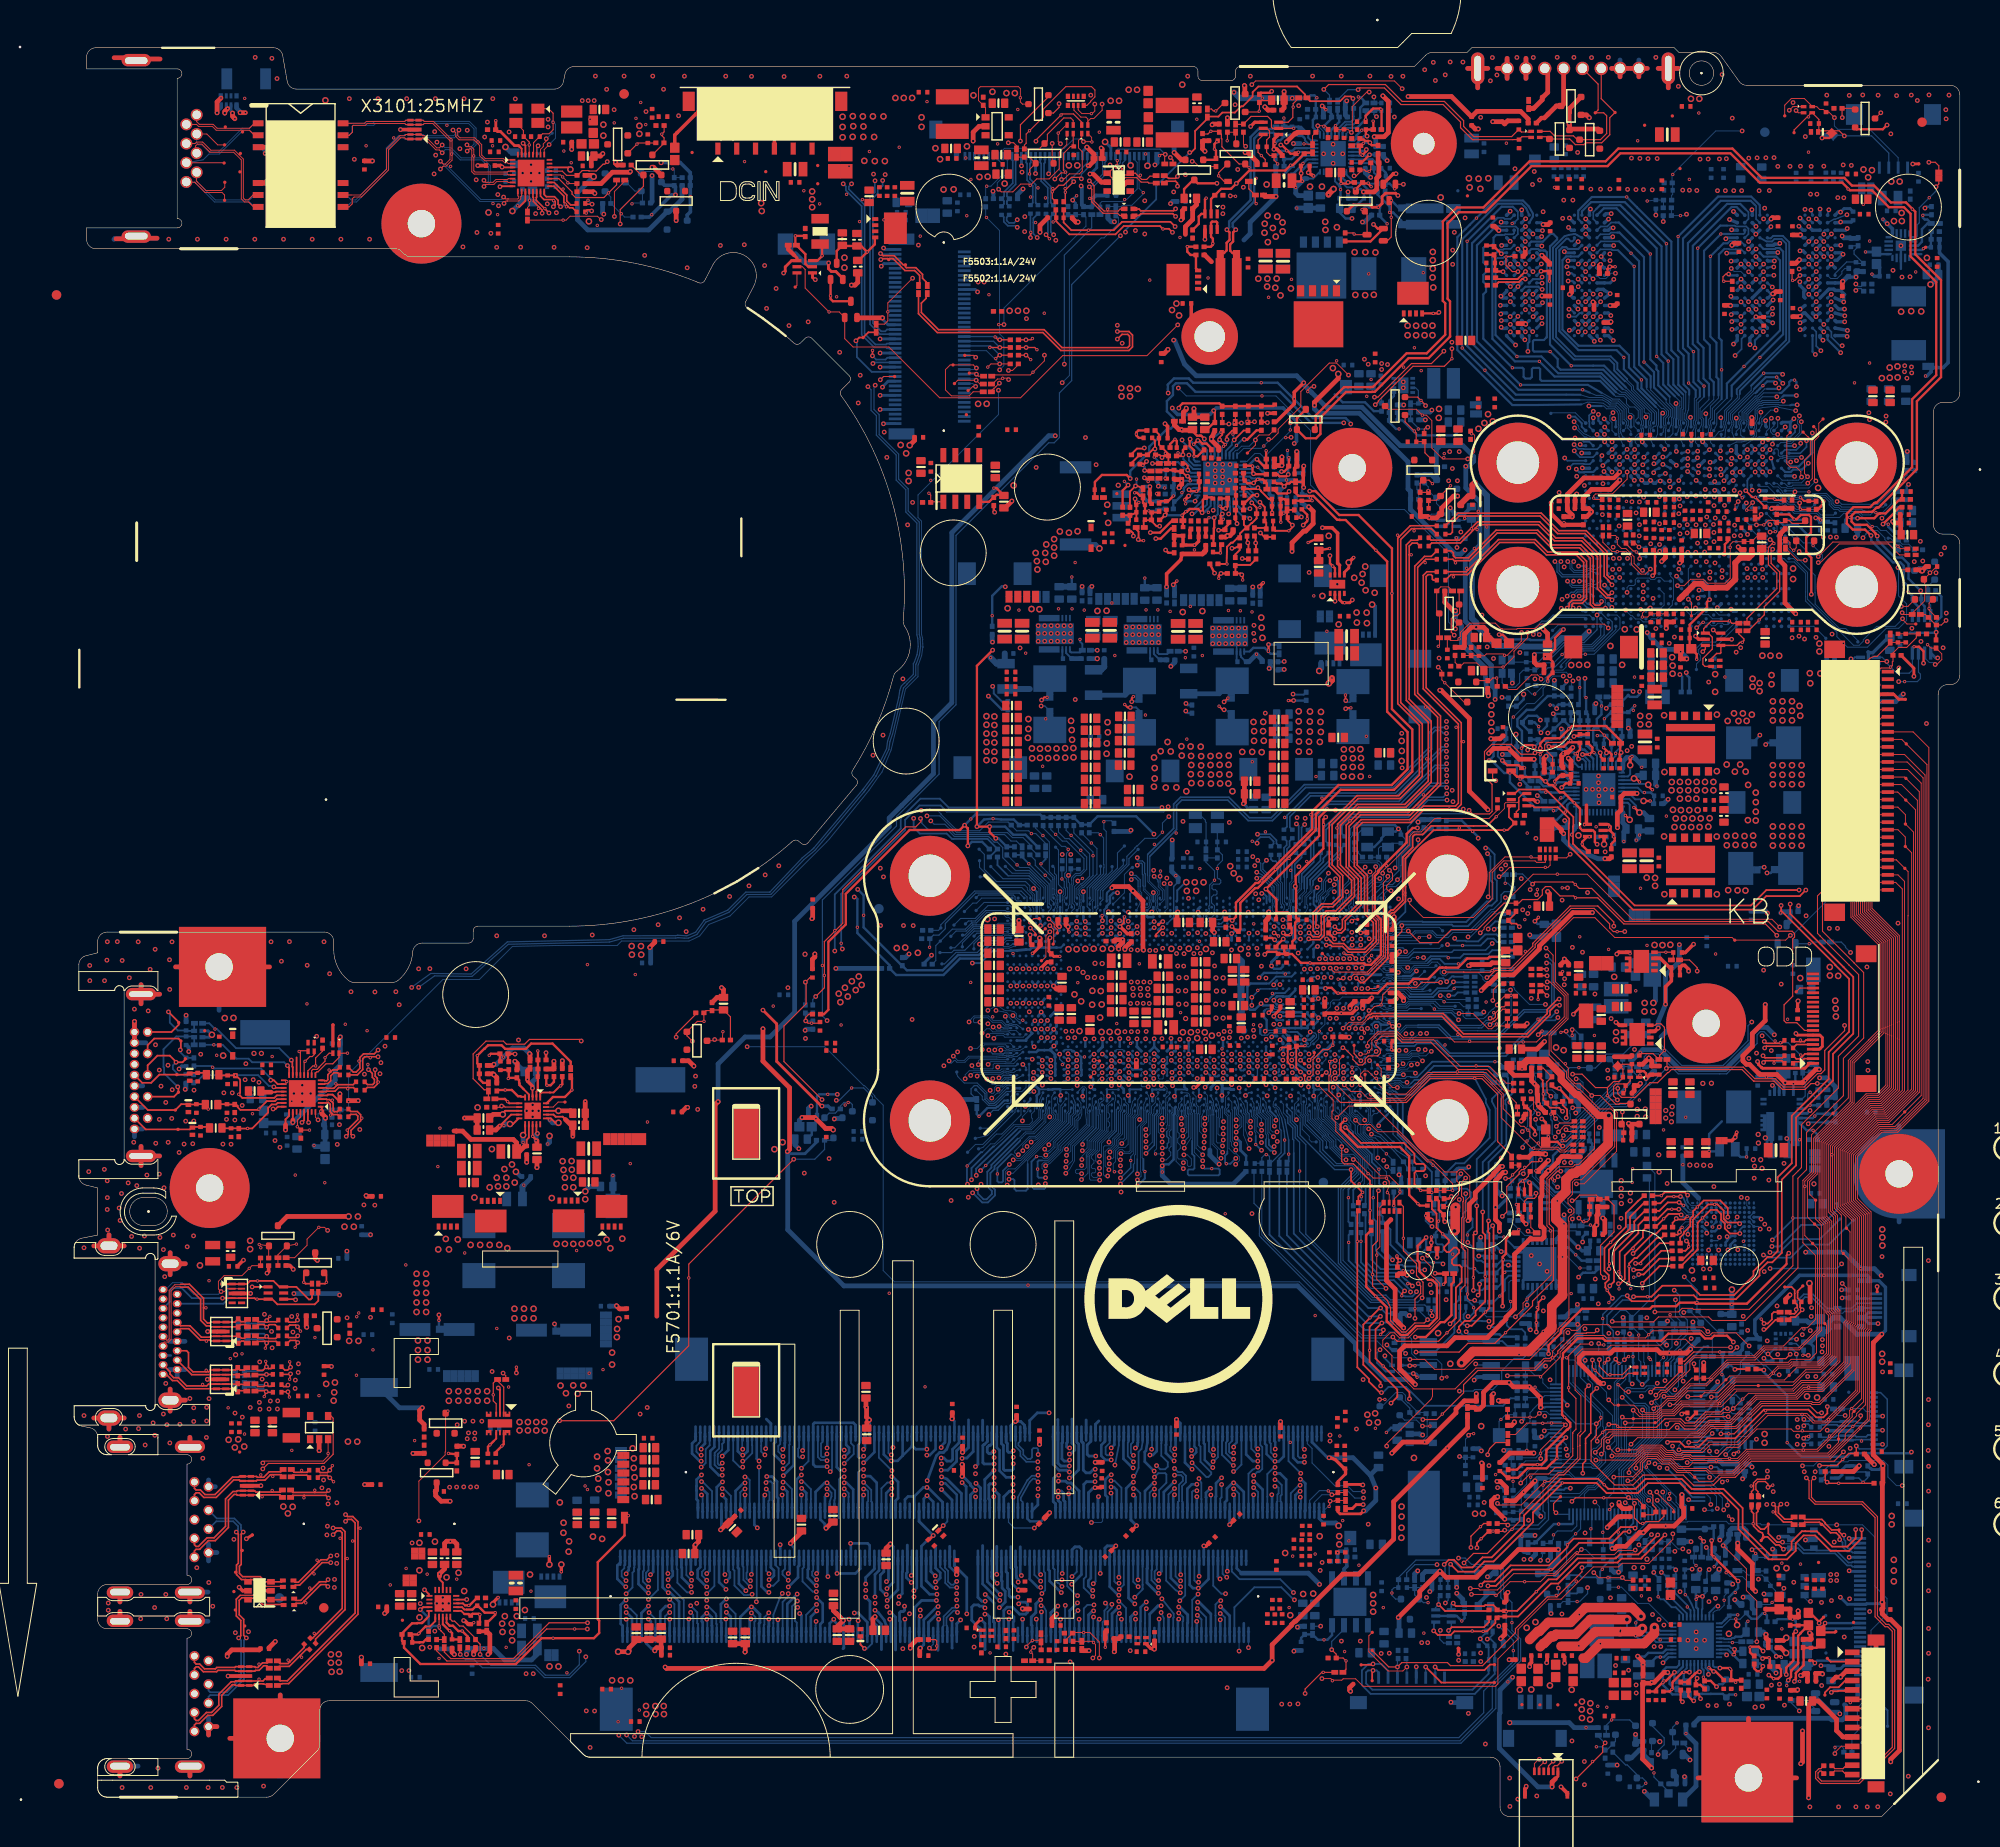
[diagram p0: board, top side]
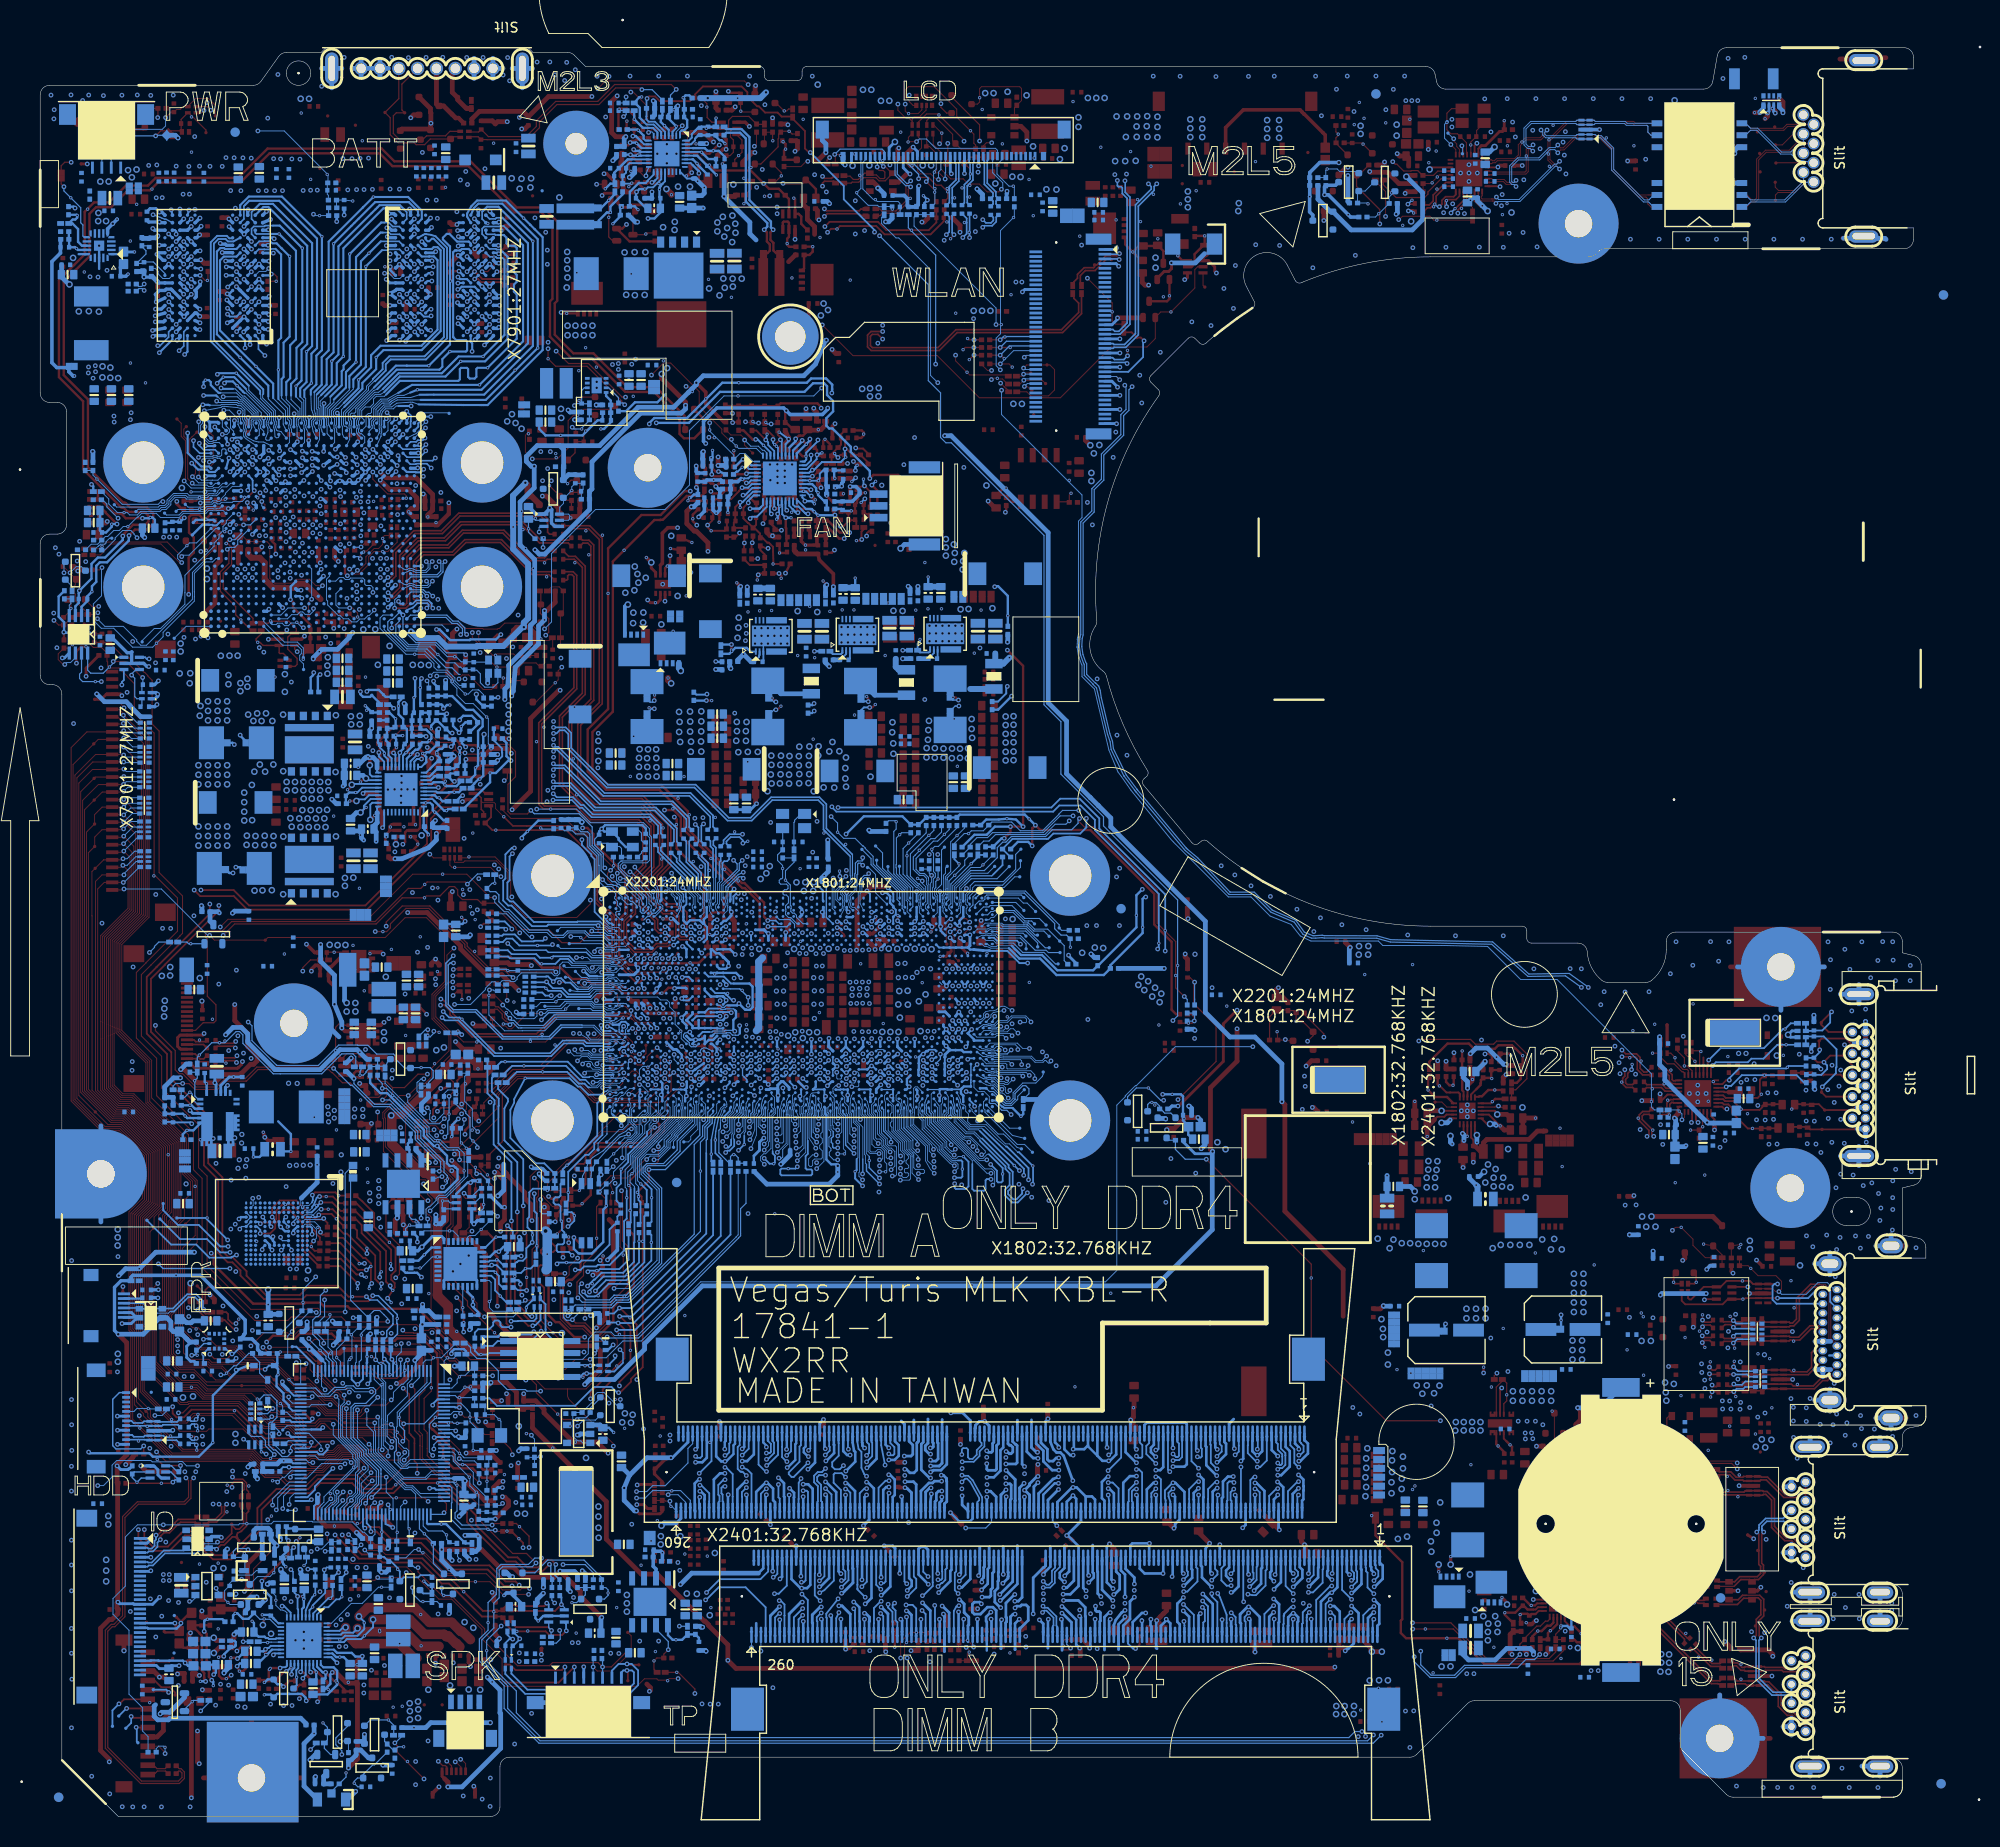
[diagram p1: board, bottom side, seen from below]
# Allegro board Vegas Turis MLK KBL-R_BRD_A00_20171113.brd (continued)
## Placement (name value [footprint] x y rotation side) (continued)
R6808  0R2J-2-GP  [R402H16]  186.33 5.39 90 top
R6809  0R2J-2-GP  [R402H16]  186.33 4.55 90 top
R7601  1KR2F-L1-GP  [R402H15]  194.28 139.95 90 bottom
R7618  1KR2F-L1-GP  [R402H15]  164.88 135.79 180 top
R7621  -  [0R0402-PAD]  145.51 125.29 90 top
R7622  1K69R2F-2-GP  [R402H16]  165.65 135.78 0 top
R7623  -  [0R0402-PAD]  146.88 130.26 270 top
R7625  10KR2J-L-GP  [R402H15]  145.2 130.26 270 top
R7704  -  [0R0603-PAD]  151.79 124.7 90 top
R7705  -  [0R0603-PAD]  171.16 124.11 90 top
R7802  2K2R2J-L1-GP  [R402H16]  169.28 170.16 270 bottom
R7803  10R2J-L-GP  [R402H16]  169.3 171.8 270 bottom
R7804  49D9R2F-L1-GP  [R402H16]  169.27 170.99 90 bottom
R7809  120R2F-GP  [R402H16]  162.35 139.55 180 top
R7810  40D2R2F-GP  [R402H16]  158.27 137.72 180 top
R7814  100R2F-L3-GP  [R402H16]  158.22 139.83 270 top
R7817  40D2R2F-GP  [R402H16]  160.36 137.72 180 top
R7818  100R2F-L3-GP  [R402H16]  159.9 139.83 270 top
R7819  5K1R2F-2-GP  [R402H16]  169.37 173.64 90 bottom
R7820  51D1R2F-GP  [R402H16]  185.08 139.37 0 top
R7821  51D1R2F-GP  [R402H16]  181.68 139.48 0 top
R7901  1MR2J-1-GP  [R402H16]  155.18 122.3 180 bottom
R7902  1KR2F-L1-GP  [R402H15]  195.57 143.49 180 bottom
R7903  5K1R2F-2-GP  [R402H16]  194.74 143.49 0 bottom
R7904  0R2J-2-GP  [R402H16]  151.63 120.12 270 top
R7911  0R2J-2-GP  [R402H16]  194.24 134.6 90 bottom
R7912  -  [0R0402-PAD]  177.3 126.83 90 top
R7913  0R2J-2-GP  [R402H16]  180.9 137.96 0 top
R7914  -  [0R0402-PAD]  177.3 126.03 90 top
R7919  -  [0R0402-PAD]  178.59 138.43 180 top
R7920  -  [0R0402-PAD]  194.28 140.82 90 bottom
R7921  10KR2J-L-GP  [R402H15]  181.8 137.3 180 top
R7922  10KR2J-L-GP  [R402H15]  182.52 139.48 180 top
R7923  10KR2J-L-GP  [R402H15]  152.4 118.45 180 bottom
R7924  10KR2J-L-GP  [R402H15]  158.13 119.54 180 bottom
R7925  10KR2J-L-GP  [R402H15]  152.84 112.03 90 bottom
R7926  8K45R2F-2-GP  [R402H16]  147.6 123.84 0 top
R7927  2KR2F-L1-GP  [R402H16]  148.43 123.83 180 top
R7928  8K45R2F-2-GP  [R402H16]  146.72 123.83 0 top
R7929  2KR2F-L1-GP  [R402H16]  146.69 122.26 270 top
R7930  8K45R2F-2-GP  [R402H16]  178.25 135.08 180 top
R7931  4K75R2F-1-GP  [R402H16]  177.43 135.08 0 top
R7932  3K24R2F-GP  [R402H16]  169.16 127.39 180 top
R7933  5K62R2F-GP  [R402H16]  168.33 127.4 0 top
R7934  10KR2J-L-GP  [R402H15]  157.27 119.53 0 bottom
R7935  10KR2J-L-GP  [R402H15]  195.96 134.63 90 bottom
R7936  10KR2J-L-GP  [R402H15]  194.24 135.66 270 bottom
R7937  -  [0R0402-PAD]  181.82 135.24 180 top
R7938  16K2R2F-GP  [R402H16]  195.26 132.5 270 top
R7939  10KR2J-L-GP  [R402H15]  151.68 114.57 270 bottom
R7940  10KR2J-L-GP  [R402H15]  152.84 112.87 270 bottom
R7941  4K7R2J-2-GP  [R402H16]  154.88 120.22 270 bottom
R7942  10KR2J-L-GP  [R402H15]  150.19 120.3 180 top
R7943  0R2J-2-GP  [R402H16]  145.75 121.42 270 top
R7944  0R2J-2-GP  [R402H16]  152.84 113.71 90 bottom
R7945  0R2J-2-GP  [R402H16]  159.05 119.5 0 bottom
R7946  0R2J-2-GP  [R402H16]  153.24 118.45 0 bottom
R8101  60D4R2F-GP  [R402H16]  150.58 162.75 90 top
R8102  60D4R2F-GP  [R402H16]  150.59 163.56 90 top
R8103  60D4R2F-GP  [R402H16]  190.57 162.12 90 bottom
R8104  60D4R2F-GP  [R402H16]  190.57 162.88 90 bottom
R8105  2K37R2F-GP  [R402H16]  150.86 166.42 0 top
R8106  2K37R2F-GP  [R402H16]  189.54 167.38 180 bottom
R8107  5K49R2F-GP  [R402H16]  150.6 164.34 270 top
R8108  5K49R2F-GP  [R402H16]  190.11 164.64 180 bottom
R8109  120R2F-GP  [R402H16]  188.55 164.11 0 bottom
R8110  120R2F-GP  [R402H16]  153.52 165.83 270 top
R8111  1KR2J-L2-GP  [R402H15]  156.75 164.58 0 top
R8112  1KR2J-L2-GP  [R402H15]  162.49 164 90 top
R8113  1KR2J-L2-GP  [R402H15]  182.52 164.65 0 top
R8114  1KR2J-L2-GP  [R402H15]  176.17 162.74 180 top
R9120  10KR2J-L-GP  [R402H15]  161.39 58.29 270 bottom
R9121  10KR2J-L-GP  [R402H15]  160.24 62 270 bottom
R9122  2K2R2J-L1-GP  [R402H16]  155.42 52.74 180 bottom
R9130  -  [0R0402-PAD]  150.55 57.77 270 bottom
R9132  33R2J-2-GP  [R402H16]  150.57 61.59 270 bottom
R9133  33R2J-2-GP  [R402H16]  150.51 58.59 270 bottom
R9136  0R0402-PAD-2-GP  [0R0402-PAD-1]  150.05 53.89 270 bottom
R9138  33R2J-2-GP  [R402H16]  150.55 56.22 270 bottom
R9140  10KR2J-L-GP  [R402H15]  150.55 56.99 270 bottom
R9141  10KR2J-L-GP  [R402H15]  152.97 63.35 270 bottom
R9143  0R0402-PAD-2-GP  [0R0402-PAD-1]  163.21 62.41 180 bottom
R9144  0R0402-PAD-2-GP  [0R0402-PAD-1]  161.39 59.08 90 bottom
R9145  0R0402-PAD-2-GP  [0R0402-PAD-1]  160.18 53.75 270 bottom
R9146  0R2J-L-GP  [R402H15]  160.17 52.97 270 bottom
R9147  0R0402-PAD-2-GP  [0R0402-PAD-1]  150.46 59.44 270 bottom
R9149  0R2J-2-GP  [R402H16]  157.58 52.3 90 bottom
R9150  0R0402-PAD-2-GP  [0R0402-PAD-1]  157.57 53.08 90 bottom
R9152  0R0402-PAD-2-GP  [0R0402-PAD-1]  150.05 54.66 270 bottom
R9202  0R0402-PAD-2-GP  [0R0402-PAD-1]  190.27 56.94 90 bottom
R9203  0R0402-PAD-2-GP  [0R0402-PAD-1]  181.69 53.6 90 top
R9204  0R0402-PAD-2-GP  [0R0402-PAD-1]  181.69 52.79 90 top
RJ45  RJ45-8P-186-GP  [23-00980-2A03-A]  6.6 177.3 90 bottom
RN801  SRN2K2J-1-GP  [ARES2H16]  152.32 94.8 270 bottom
RN802  SRN10KJ-6-GP  [ARES8-CN24-MUH20]  156.57 102.34 180 top
RN803  SRN2K2J-1-GP  [ARES2H16]  152.31 93.28 270 bottom
RN1201  SRN1KJ-7-GP  [SMD-ARES4H18]  113.42 18.69 90 top
RN1301  SRN1KJ-7-GP  [SMD-ARES4H18]  96.99 19.47 270 top
RN1701  SRN10KJ-5-GP  [ARES2H18]  144.23 54.42 0 bottom
RN1704  SRN10KJ-6-GP  [ARES8-CN24-MUH20]  139.97 64.8 0 top
RN1807  SRN2K2J-4-GP  [ARES8-CN24-UH20]  148.36 88.41 270 bottom
RN1812  SRN10KJ-6-GP  [ARES8-CN24-MUH20]  159.85 73.05 90 top
RN1813  SRN10KJ-5-GP  [ARES2H18]  159.72 71.07 90 top
RN1901  SRN20KJ-1-GP  [SMD-ARES4H20]  165.79 78.89 90 top
RN2007  SRN10KJ-5-GP  [ARES2H18]  155.35 88.03 90 top
RN2008  SRN2K2J-1-GP  [ARES2H16]  152.31 91.74 90 bottom
RN2009  SRN10KJ-5-GP  [ARES2H18]  152.3 89.71 270 bottom
RN2010  SRN2K2J-1-GP  [ARES2H16]  155.27 89.75 270 top
RN2011  SRN10KJ-5-GP  [ARES2H18]  151.29 88.09 90 bottom
RN2402  SRN4K7J-8-GP  [SMD-ARES4H18]  166.37 47.43 270 top
RN2403  SRN10KJ-12-GP  [ARES8-CN24-UH22]  189.29 101.75 90 bottom
RN2404  SRN10KJ-12-GP  [ARES8-CN24-UH22]  189.3 104.91 90 bottom
RN2405  SRN100KJ-5-GP  [ARES8-CN24H20]  177.5 43.07 90 bottom
RN2406  SRN100KJ-5-GP  [ARES8-CN24H20]  189.26 112.85 90 bottom
RN2407  SRN100KJ-5-GP  [ARES8-CN24H20]  189.24 115.42 90 bottom
RN2408  SRN100KJ-5-GP  [ARES8-CN24H20]  189.29 110.23 90 bottom
RN2409  SRN100KJ-5-GP  [ARES8-CN24H20]  189.29 107.44 90 bottom
RN2501  SRN4K7J-8-GP  [SMD-ARES4H18]  147.65 56.5 180 bottom
RN2502  SRN0J-6-GP  [SMD-ARES4H20]  147.54 54.61 0 bottom
RN2503  SRN0J-6-GP  [SMD-ARES4H20]  140.49 47.62 270 bottom
RN2901  SRN2K2J-1-GP  [ARES2H16]  180.61 18.34 90 bottom
RN3201  SRN75J-1-GP  [ARES8-CN24H22]  16.42 182.4 180 bottom
RN4302  SRN100J-3-GP  [SMD-ARES4H18]  155.26 178.79 270 top
RN5501  SRN100J-3-GP  [SMD-ARES4H18]  105.82 179.33 0 top
RN5502  SRN100KJ-5-GP  [ARES8-CN24H20]  106.43 182.35 180 top
RN5503  SRN100J-3-GP  [SMD-ARES4H18]  107.38 179.33 0 top
RN5601  SRN2K2J-1-GP  [ARES2H16]  13.19 83.16 90 bottom
RN5602  SRN4K7J-8-GP  [SMD-ARES4H18]  27.82 81.59 180 top
RN5603  SRN4K7J-8-GP  [SMD-ARES4H18]  25.18 81.79 180 top
RN5701  SRN470J-3-GP  [ARES8-CN24H20]  17.9 51.53 90 bottom
RN5702  SRN2K2J-1-GP  [ARES2H16]  25.61 56.19 180 top
RN5703  SRN470J-3-GP  [ARES8-CN24H20]  17.61 46.49 90 bottom
RN6401  SRN100J-3-GP  [SMD-ARES4H18]  184.21 181.41 270 top
RN6502  SRN2K2J-1-GP  [ARES2H16]  146.51 18.76 270 bottom
RN6503  SRN33J-5-GP-U  [SMD-ARES4H18]  150.61 16.18 0 bottom
RN6504  SRN10KJ-5-GP  [ARES2H18]  150.37 20.1 0 bottom
RN7902  SRN4K7J-8-GP  [SMD-ARES4H18]  174.38 122.56 270 top
RN7903  SRN4K7J-8-GP  [SMD-ARES4H18]  189.08 119.13 90 bottom
RN7904  SRN10KJ-5-GP  [ARES2H18]  162.76 136.59 0 top
RN7905  SRN10KJ-5-GP  [ARES2H18]  195.22 134.42 270 top
RTC1  BAT-AAA-BAT-054-P06-GP-U  [AAA-BAT-054-P06]  32.4 31.1 90 bottom
SKT251  SKT-G6179HT0321-001-GP  [G6179HT0321-001]  147.22 48.62 90 bottom
SPI25  GD25B128CSIGR-GP  [SOIC8-1H86]  147.22 48.62 270 bottom
SPK1  ACES-CON4-29-GP  [50224-0040N-001]  155.2 8.3 180 bottom
SPR1  SPRING-63-GP  [SPR5630H142]  71.4 74.7 90 top
SPR2  SPRING-63-GP  [SPR5630H142]  22.4 83.3 0 bottom
SPR3  SPRING-63-GP  [SPR5630H142]  71.4 47.3 90 top
SPR4  SPRING-43-GP-U  [SPR4527H308]  143.4 35.5 90 bottom
SPR5  SPRING-63-GP  [SPR5630H142]  64.4 78.3 0 bottom
TC3501  SC100U6D3V6MX-GP  [C1206H71]  23.07 41.59 180 top
THM262  NCT7718W-GP  [MSOP8-1H44]  196.28 125.65 0 bottom
TP1  STAR-CON8-2-GP  [106H08-011001-A2-R]  142.1 12.1 180 bottom
TP401  TPAD14-OP-GP  [TPAD14-OP]  103.98 100.99 180 bottom
TP402  TPAD14-OP-GP  [TPAD14-OP]  98.94 100.98 180 bottom
TP404  TPAD14-OP-GP  [TPAD14-OP]  137.15 78.88 0 top
TP405  TPAD14-OP-GP  [TPAD14-OP]  111.59 103.15 180 bottom
TP406  TPAD14-OP-GP  [TPAD14-OP]  111.48 101.64 0 bottom
TP407  TPAD14-OP-GP  [TPAD14-OP]  113.05 102.79 180 bottom
TP408  TPAD14-OP-GP  [TPAD14-OP]  109.06 100.99 180 bottom
TP601  TPAD14-OP-GP  [TPAD14-OP]  96.27 73.15 180 bottom
TP602  TPAD14-OP-GP  [TPAD14-OP]  96.1 70.96 180 bottom
TP610  TPAD14-OP-GP  [TPAD14-OP]  138.8 71.58 180 bottom
TP611  TPAD14-OP-GP  [TPAD14-OP]  140.17 71.67 180 bottom
TP612  TPAD14-OP-GP  [TPAD14-OP]  102.78 90.96 0 top
TP613  TPAD14-OP-GP  [TPAD14-OP]  103.19 94.36 0 top
TP614  TPAD14-OP-GP  [TPAD14-OP]  95.79 77.24 180 bottom
TP615  TPAD14-OP-GP  [TPAD14-OP]  94.93 70.6 180 bottom
TP616  TPAD14-OP-GP  [TPAD14-OP]  108.01 78.59 0 top
TP617  TPAD14-OP-GP  [TPAD14-OP]  108.94 80.3 0 top
TP618  TPAD14-OP-GP  [TPAD14-OP]  96.15 102.81 180 bottom
TP619  TPAD14-OP-GP  [TPAD14-OP]  96.2 101.59 180 bottom
TP620  TPAD14-OP-GP  [TPAD14-OP]  97.39 100.97 180 bottom
TP621  TPAD14-OP-GP  [TPAD14-OP]  92.08 94.44 180 bottom
TP622  TPAD14-OP-GP  [TPAD14-OP]  92.03 93.04 180 bottom
TP623  TPAD14-OP-GP  [TPAD14-OP]  93.48 94.74 180 bottom
TP624  TPAD14-OP-GP  [TPAD14-OP]  94.71 94.87 180 bottom
TP625  TPAD14-OP-GP  [TPAD14-OP]  95.84 97.67 180 bottom
TP626  TPAD14-OP-GP  [TPAD14-OP]  94.39 93.68 180 bottom
TP627  TPAD14-OP-GP  [TPAD14-OP]  91.99 91.82 180 bottom
TP628  TPAD14-OP-GP  [TPAD14-OP]  93.15 93.55 180 bottom
TP629  TPAD14-OP-GP  [TPAD14-OP]  93.15 92.33 180 bottom
TP630  TPAD14-OP-GP  [TPAD14-OP]  92.2 90.62 180 bottom
TP631  TPAD14-OP-GP  [TPAD14-OP]  95.61 93.57 180 bottom
TP632  TPAD14-OP-GP  [TPAD14-OP]  95.6 92.22 180 bottom
TP633  TPAD14-OP-GP  [TPAD14-OP]  94.37 92.43 180 bottom
TP634  TPAD14-OP-GP  [TPAD14-OP]  104.47 93.9 0 top
TP635  TPAD14-OP-GP  [TPAD14-OP]  104.02 92.73 0 top
TP636  TPAD14-OP-GP  [TPAD14-OP]  102.55 95.43 0 top
TP637  TPAD14-OP-GP  [TPAD14-OP]  102.14 93.72 0 top
TP638  TPAD14-OP-GP  [TPAD14-OP]  136.38 95.35 0 top
TP801  TPAD14-OP-GP  [TPAD14-OP]  112.45 100.86 180 bottom
TP802  TPAD14-OP-GP  [TPAD14-OP]  132.61 91.73 0 top
TP1601  TPAD14-OP-GP  [TPAD14-OP]  110.28 100.96 0 bottom
TP1602  TPAD14-OP-GP  [TPAD14-OP]  104.27 103.02 180 bottom
TP1603  TPAD14-OP-GP  [TPAD14-OP]  145.39 94.14 270 bottom
TP1701  TPAD14-OP-GP  [TPAD14-OP]  132.59 78.74 0 top
TP1702  TPAD14-OP-GP  [TPAD14-OP]  131.76 81.19 0 top
TP1703  TPAD14-OP-GP  [TPAD14-OP]  133.06 71.12 180 bottom
TP1704  TPAD14-OP-GP  [TPAD14-OP]  130.74 78.76 0 top
TP1705  TPAD14-OP-GP  [TPAD14-OP]  131.97 71.7 180 bottom
TP1706  TPAD14-OP-GP  [TPAD14-OP]  130.72 79.99 0 top
TP1707  TPAD14-OP-GP  [TPAD14-OP]  134.81 80.8 0 top
TP1803  TPAD14-OP-GP  [TPAD14-OP]  144.14 92.77 180 bottom
TP1804  TPAD14-OP-GP  [TPAD14-OP]  144.06 87.81 180 bottom
TP1805  TPAD14-OP-GP  [TPAD14-OP]  138.52 88.23 0 top
TP1806  TPAD14-OP-GP  [TPAD14-OP]  145.35 92.56 180 bottom
TP1807  TPAD14-OP-GP  [TPAD14-OP]  114.95 93.59 0 top
TP1808  TPAD14-OP-GP  [TPAD14-OP]  115.21 94.79 0 top
TP1902  TPAD14-OP-GP  [TPAD14-OP]  137.62 71.21 180 bottom
TP2006  TPAD14-OP-GP  [TPAD14-OP]  144.7 90.42 180 bottom
TP2007  TPAD14-OP-GP  [TPAD14-OP]  143.16 88.64 180 bottom
TP2008  TPAD14-OP-GP  [TPAD14-OP]  135.99 81.97 0 top
TP2010  TPAD14-OP-GP  [TPAD14-OP]  143.48 89.82 180 bottom
TP2011  TPAD14-OP-GP  [TPAD14-OP]  144.54 89.2 180 bottom
TP2012  TPAD14-OP-GP  [TPAD14-OP]  143.12 85.86 180 bottom
TP2015  TPAD14-OP-GP  [TPAD14-OP]  146.73 86.11 180 bottom
TP2301  TPAD14-OP-GP  [TPAD14-OP]  94.59 96.19 180 bottom
TP2304  TPAD14-OP-GP  [TPAD14-OP]  93.78 79.12 180 bottom
TP2305  TPAD14-OP-GP  [TPAD14-OP]  141.08 70.85 180 bottom
TP2307  TPAD14-OP-GP  [TPAD14-OP]  95.75 72.07 180 bottom
TP2310  TPAD14-OP-GP  [TPAD14-OP]  138.48 79.89 0 top
TP2311  TPAD14-OP-GP  [TPAD14-OP]  96.27 99.87 180 bottom
TP2312  TPAD14-OP-GP  [TPAD14-OP]  95.83 96.3 180 bottom
TP2401  TPAD14-OP-GP  [TPAD14-OP]  157.92 33.99 0 top
TP2402  TPAD14-OP-GP  [TPAD14-OP]  169.95 32.38 0 top
TP2403  TPAD14-OP-GP  [TPAD14-OP]  174.05 32.54 180 bottom
TP2404  TPAD14-OP-GP  [TPAD14-OP]  166.77 49.97 180 bottom
TP2405  TPAD14-OP-GP  [TPAD14-OP]  168.08 49.75 180 bottom
TP2406  TPAD14-OP-GP  [TPAD14-OP]  173.57 49.93 180 bottom
TP2407  TPAD14-OP-GP  [TPAD14-OP]  174.58 41.08 180 bottom
TP3101  TPAD14-OP-GP  [TPAD14-OP]  50.86 180.14 180 bottom
TP3102  TPAD14-OP-GP  [TPAD14-OP]  50.78 178.92 180 bottom
TP3103  TPAD14-OP-GP  [TPAD14-OP]  49.24 176.73 180 bottom
TP4301  TPAD14-OP-GP  [TPAD14-OP]  76.61 162.56 0 top
TP4501  TPAD14-OP-GP  [TPAD14-OP]  52.15 75.93 0 top
TP6001  TPAD14-OP-GP  [TPAD14-OP]  182.96 87.65 0 top
TP6101  TPAD14-OP-GP  [TPAD14-OP]  87.17 153.05 0 top
TP6102  TPAD14-OP-GP  [TPAD14-OP]  94.62 155.3 0 top
TP6103  TPAD14-OP-GP  [TPAD14-OP]  94.98 151.56 0 top
TP6301  TPAD14-OP-GP  [TPAD14-OP]  187.29 65.14 270 bottom
TP6302  TPAD14-OP-GP  [TPAD14-OP]  185.83 63.62 270 bottom
TP6303  TPAD14-OP-GP  [TPAD14-OP]  187.63 63.51 270 bottom
TP6304  TPAD14-OP-GP  [TPAD14-OP]  189.02 63.37 270 bottom
TP6801  TPAD14-OP-GP  [TPAD14-OP]  186.27 16.8 0 top
TP6802  TPAD14-OP-GP  [TPAD14-OP]  186.01 12.9 0 top
TP6803  TPAD14-OP-GP  [TPAD14-OP]  188.34 13.48 180 bottom
TP6804  TPAD14-OP-GP  [TPAD14-OP]  192.67 9.59 180 bottom
TP6805  TPAD14-OP-GP  [TPAD14-OP]  192.01 10.67 180 bottom
TP6806  TPAD14-OP-GP  [TPAD14-OP]  191.25 9.37 180 bottom
TP6807  TPAD14-OP-GP  [TPAD14-OP]  189.97 7.83 180 bottom
TP7701  TPAD14-OP-GP  [TPAD14-OP]  156.9 149.13 180 bottom
TP7702  TPAD14-OP-GP  [TPAD14-OP]  186.11 125.22 180 bottom
TP7703  TPAD14-OP-GP  [TPAD14-OP]  157.08 126.06 180 bottom
TP7901  TPAD14-OP-GP  [TPAD14-OP]  185.91 138.72 180 bottom
TP7902  TPAD14-OP-GP  [TPAD14-OP]  195.67 126.75 0 top
TP7903  TPAD14-OP-GP  [TPAD14-OP]  190.18 138.69 180 bottom
TP7904  TPAD14-OP-GP  [TPAD14-OP]  171.84 127.61 0 top
TP7905  TPAD14-OP-GP  [TPAD14-OP]  176.46 138.92 0 top
TP7906  TPAD14-OP-GP  [TPAD14-OP]  187.14 138.53 180 bottom
TP7907  TPAD14-OP-GP  [TPAD14-OP]  192.48 139.43 180 bottom
TP7908  TPAD14-OP-GP  [TPAD14-OP]  185.82 148.54 0 top
TP7909  TPAD14-OP-GP  [TPAD14-OP]  184.18 136.21 180 bottom
TP7910  TPAD14-OP-GP  [TPAD14-OP]  184.94 139.46 180 bottom
TP7911  TPAD14-OP-GP  [TPAD14-OP]  184.83 147.72 0 top
TP7912  TPAD14-OP-GP  [TPAD14-OP]  183.7 147.14 0 top
TP7913  TPAD14-OP-GP  [TPAD14-OP]  182.34 147.1 0 top
TP7914  TPAD14-OP-GP  [TPAD14-OP]  184.08 137.54 180 bottom
TP7918  TPAD14-OP-GP  [TPAD14-OP]  192.74 135.87 180 bottom
TP7919  TPAD14-OP-GP  [TPAD14-OP]  172.39 123.18 180 bottom
TP7920  TPAD14-OP-GP  [TPAD14-OP]  172.37 121.91 180 bottom
TP7922  TPAD14-OP-GP  [TPAD14-OP]  157.99 122.2 180 bottom
TP7923  TPAD14-OP-GP  [TPAD14-OP]  189.52 124.84 180 bottom
TP8501  TPAD14-OP-GP  [TPAD14-OP]  165.12 119.17 180 bottom
TP8502  TPAD14-OP-GP  [TPAD14-OP]  163.88 119.23 180 bottom
U2101  RT9724GB-GP  [SOT-23-5H51]  143.13 40.66 90 bottom
U3501  SY6288DAAC-GP  [SOT-23-5H56]  26.03 41.33 0 top
U3503  SY6288DAAC-GP  [SOT-23-5H56]  182.63 24.48 270 bottom
U4001  AP22966DC8-7-GP  [SON14J3020-G2610H32]  45.24 41.78 0 top
U4002  APE8939GN3-GP  [DFN8F3-G245165H34]  166.06 83.12 270 top
U4006  APE8939GN3-GP  [DFN8F3-G245165H34]  166.51 90.89 270 top
U5501  RT9724GB-GP  [SOT-23-5H51]  98.07 179.65 270 top
U5601  RTD2166-CGT-GP  [QFN32J4-G2D85H36]  24.24 76.84 270 top
U6301  KLMBG4GEND-B031-GP  [BGA153G115130-1H40]  175.22 61.95 270 bottom
U6701  LNG2DMTR-GP  [LGA12G2H40]  181.58 50.51 0 bottom
U9103  NPCT650VB2YX-GP  [QFN32G5-G3D6H32]  155.7 58.72 90 bottom
USB1  SKT-USB13-179-GP  [SKT-USB13-157164-1]  4.87 31.55 90 bottom
USB2  SKT-USB13-179-GP  [SKT-USB13-157164-1]  4.87 13.05 90 bottom
VGA1  D-SUB-15-297-GP  [28-00370-1003-A]  7.11 78.8 90 bottom
VRAM1  H5GQ2H24AFR-T2C-GP  [BGA170D1214H48]  157.4 163.8 180 bottom
VRAM2  H5GQ2H24AFR-T2C-GP  [BGA170D1214H48]  181.9 163.8 0 bottom
WLAN1  PAD-SKT-NGFF75P-GP-U  [PAD-SKT-NGFF75P-U]  92.4 157.3 270 bottom
X1801  XTAL-24MHZ-81-GP  [OSC-3225-4P-4H36]  120.3 105.8 0 bottom
X1802  X-32D768KHZ-65-GP  [SMD-OSC2H56]  142.37 64.12 270 bottom
X2201  XTAL-24MHZ-86-GP  [OSC-3225-4P-3H36]  138.49 103.86 180 bottom
X2401  XTAL-32D768KHZ-91-GP  [SMD49-3215-0713H36]  152.63 40.5 90 bottom
X3101  XTAL-25MHZ-260-GP  [OSC-3225-4P-4H36]  48.1 180.76 180 top
X7901  XTAL-27MHZ-159-GP  [SMD-OSC38H20]  152.22 122.21 270 bottom
XF3201  XFORM-12P-48-GP  [XFORM12A127097H91]  24.06 175.52 270 top
XF3202  XFORM-12P-48-GP  [XFORM12A127097H91]  24.06 175.52 90 bottom

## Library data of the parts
AFTP2501 AFTP2502 AFTP2601-AFTP2603 AFTP2901-AFTP2904 AFTP3201-AFTP3208 AFTP3601-AFTP3608 AFTP4301-AFTP4315 AFTP4601 AFTP5602-AFTP5609 AFTP6001 AFTP6101 AFTP6105-AFTP6110 AFTP6401-AFTP6404 AFTP6502 AFTP6503 AFTP6505-AFTP6508 AFTP6510-AFTP6513 AFTP6515-AFTP6540 AFTP6601-AFTP6612 AFTP8902-AFTP8904 = AFTE14P-75: tolerance: ZZ.AFT14.101
BATT1 = C144KA-108A7-L-1: tolerance: 20.81775.008
C715 C1176 C1183 C1202-C1206 C1208-C1210 C1303-C1310 C1324 C1325 C1704 C2401 C2501 C2615 C2707 C2710 C2711 C2713 C2715 C2717 C2720 C2722 C2902 C4004 C4005 C4007 C4009 C4012 C4013 C4016 C5538 C5615 C5621 C5628 C6002 C6008 C6009 C6105 C6106 C6703 C7713 C8001 C8002 C8010 C8016 C8038-C8041 C8043 C8044 C8053 C8063 C8064 C8121 C8122 C8131 C8132 PC1055 PC1057 PC1058 PC5109 PC5117 PC5118 PC5152 PC5403 PC8621 PC8622 = C603H38: tolerance: 78.10610.5BL
C716 C717 C719 C722 C1101-C1103 C1116 C1117 C1136 C1138 C1147-C1154 C1172-C1175 C1180 C1207 C1213-C1221 C1225 C1226 C1313-C1322 C1326 C1327 C1901 C1902 C2101 C2103-C2109 C2116 C2117 C2120 C2121 C2125 C2418 C3104 C3105 C3508 C3510 C3518 C4028 C4029 C5536 C6318 C6320 C7711 C7715 C7801 C7805 C7904 C8003-C8006 C8008 C8009 C8013 C8015 C8017-C8037 C8042 C8045 C8048-C8050 C8054 C8055 C8057-C8062 C8065 C8101-C8104 C8113-C8120 C8123-C8130 C9202 EC9725-EC9731 FC9702 FC9703 FC9706-FC9708 PC4439 PC4445 PC4446 PC4607 PC4708 PC4809 PC4812 PC5102 PC5107 PC5401 PC8508 PC8509 PC8623 PC8634 PC8655 = C402H22: tolerance: 78.10523.5FL
C718 C720 C721 C1228 C1229 C1301 C1328 C2110-C2112 C2118 C2119 C2406-C2408 C2410-C2414 C2416 C2420-C2423 C2428 C2429 C2502 C2605 C2610 C2612 C2616-C2618 C2704 C2706 C2714 C2718 C2721 C2735-C2737 C2741 C3103 C3112-C3115 C3117-C3124 C3504 C3507 C3517 C3618 C3706 C4017 C4018 C5501 C5531 C5533 C5602 C5606 C5609 C5610 C5620 C5624-C5627 C5702 C6001 C6007 C6018 C6101-C6104 C6316 C6319 C6401 C6503 C6504 C6701 C6702 C7710 C7714 C7821 C7822 C8007 C8011 C8012 C8046 C8047 C8056 C8105-C8112 C9107 C9108 C9111 C9112 C9116 C9201 EC1707 EC1709 EC1712 EC1805-EC1808 EC2601 EC6401 PC4517 PC4518 PC5106 PC8601 PC8603 PC8607 PC8636 = C402H22: tolerance: 78.10421.2FL
C1104 C1106 C1108 C1182 C1184 C2113 C2114 C2122 C5506 C8066 PC1001-PC1037 PC1040-PC1054 PC1062-PC1099 PC1105 PC1106 PC8534 PC8535 PC8625 PC8626 = C603H40: tolerance: 78.22610.5BL
C1201 C1329 C2415 C2417 C2426 C2708 C5543 C5608 PC5001 PC8654 = C603H36: tolerance: 78.22523.L1L
C1211 C1212 C1223 C1224 C1227 C1230-C1232 C1311 C1312 C1330 C1331 = C402H22: tolerance: 078.47510.05FD
C1222 C1323 C2123 = C402H22: tolerance: 78.22321.2FL
C1601 = C402H22: tolerance: 78.10421.2FL; signal model: wistron_C1601
C1602 = C402H22: tolerance: 78.10421.2FL; signal model: wistron_C1602
C1603 = C402H22: tolerance: 78.10421.2FL; signal model: wistron_C1603
C1604 = C402H22: tolerance: 78.10421.2FL; signal model: wistron_C1604
C1605 = C402H22: tolerance: 78.22423.L2L; signal model: wistron_C1605
C1606 = C402H22: tolerance: 78.22423.L2L; signal model: wistron_C1606
C1607 = C402H22: tolerance: 78.22423.L2L; signal model: wistron_C1607
C1608 = C402H22: tolerance: 78.22423.L2L; signal model: wistron_C1608
C1609 = C402H22: tolerance: 78.22423.L2L; signal model: wistron_C1609
C1610 = C402H22: tolerance: 78.22423.L2L; signal model: wistron_C1610
C1611 = C402H22: tolerance: 78.22423.L2L; signal model: wistron_C1611
C1612 = C402H22: tolerance: 78.22423.L2L; signal model: wistron_C1612
C1701 PC4662 PC5312 = C402H22: tolerance: 78.22124.2FL
C1801 C1802 C2201 C2202 C3116 C3125 C5611-C5614 C5618 C5619 = C402H22: tolerance: 78.15034.1FL
C1803 C1804 = C402H22: tolerance: 78.3R974.1FL
C2403 C7609 = C402H22: tolerance: 78.47034.1FL
C2405 C2613 C5607 C5622 C7802 EC2905-EC2908 PC8512 = C402H22: tolerance: 78.10134.1FL
C2409 C2419 C3201 C7921 C8014 EC1708 PC4303-PC4305 PC4419 PC4531 PC4609 PC4613 PC4615 PC4620 PC4622 PC4637 PC4644 PC5313 PC8501 = C402H22: tolerance: 78.10324.L0L
C2424 C2425 C5616 C5617 PC4522 PC4523 PC5115 = C402H22: tolerance: 78.18034.1FL
C2435 C2441 C2603 C2614 C9114 C9115 PC5120 PC5315 = C402H22: tolerance: 78.22224.2FL
C2503 = C402H22: tolerance: 78.47423.5FL
C2604 C2611 C2723 C3108-C3111 C5505 C5539 C6317 C8051 C8052 C9106 C9109 C9113 PC4526 = C603H36: tolerance: 78.47520.5BL
C2702 C2703 C2705 C2709 C2740 = C402H22: tolerance: 78.22523.5FL
C2725 C5540 C5541 EC1802 EC1901 EC2602 EC4306 EC4309 EC4310 PC4436 = C402H22: tolerance: 78.10034.L0L
C2738 PC4471 PC8517 PC8518 PC8612 = C402H22: tolerance: 78.22423.L2L
C2739 = C603H36: tolerance: 78.10134.1BL
C2907 C2908 = C603H38: tolerance: 78.10610.L0L
C3102 = C402H22: tolerance: 78.10421.2FL; signal model: wistron_C3102
C3107 = C402H22: tolerance: 78.10421.2FL; signal model: wistron_C3107
C3202 = C1808H40: tolerance: 078.5603N.014D
C3512 C3513 PC1038 PC1039 PC5110-PC5114 PC5154 PC5301 PC5303 PC5305-PC5307 PC5402 PC5404 PC8604 PC8605 PC8657-PC8661 = C603H40: tolerance: 78.22610.5BLDL
C3515 = C805H58: tolerance: 78.22610.L2L
C3601 = C402H22: tolerance: 78.10421.2FL; signal model: wistron_C3601
C3602 = C402H22: tolerance: 78.10421.2FL; signal model: wistron_C3602
C3604 = C402H22: tolerance: 78.10421.2FL; signal model: wistron_C3604
C3605 = C402H22: tolerance: 78.10421.2FL; signal model: wistron_C3605
C4001 C4002 PC4661 = C402H22: tolerance: 78.47124.2FL
C5508 = C402H22: tolerance: 78.10421.2FL; signal model: wistron_C5508
C5515 EC401 EC1702 EC1703 EC1705 EC1706 EC1903 EC2002 EC2901-EC2904 EC6403 EC9708-EC9711 EC9714 EC9740 EC9745 EC9748 PC4407-PC4409 PC4616-PC4619 PC4642 PC4643 PC4651 PC4706 PC4810 PC4813 PC5314 PC8503 PC8511 PC8513 = C402H22: tolerance: 78.10224.L1L
C5532 = C402H22: tolerance: 78.10421.2FL; signal model: wistron_C5532
C5534 = C402H22: tolerance: 78.10421.2FL; signal model: wistron_C5534
C5535 EC4308 PC4302 PC4516 PC4525 PC4530 PC4535 PC5108 = C603H36: tolerance: 78.10424.2BL
C5537 = C402H22: tolerance: 78.10421.2FL; signal model: wistron_C5537
C5601 = C402H22: tolerance: 78.10421.2FL; signal model: wistron_C5601
C5603 = C402H22: tolerance: 78.10421.2FL; signal model: wistron_C5603
C5604 = C402H22: tolerance: 78.10421.2FL; signal model: wistron_C5604
C5605 = C402H22: tolerance: 78.10421.2FL; signal model: wistron_C5605
C5623 = C402H22: tolerance: 78.10321.2FL
C5629 PC1056 PC1059-PC1061 = C402H22: tolerance: 78.4R7B4.1FL
C5701 = C402H22: tolerance: 78.10421.2FL; signal model: wistron_C5701
C5703 = C402H22: tolerance: 78.10421.2FL; signal model: wistron_C5703
C5704 = C402H22: tolerance: 78.10421.2FL; signal model: wistron_C5704
C5705 = C402H22: tolerance: 78.10421.2FL; signal model: wistron_C5705
C5706 = C402H22: tolerance: 78.10421.2FL; signal model: wistron_C5706
C5707 = C402H22: tolerance: 78.10421.2FL; signal model: wistron_C5707
C5708 = C402H22: tolerance: 78.10421.2FL; signal model: wistron_C5708
C5709 = C402H22: tolerance: 78.10421.2FL; signal model: wistron_C5709
C6003 = C402H22: tolerance: 78.22423.L2L; signal model: wistron_C6003
C6004 = C402H22: tolerance: 78.22423.L2L; signal model: wistron_C6004
C6005 = C402H22: tolerance: 78.22423.L2L; signal model: wistron_C6005
C6006 = C402H22: tolerance: 78.22423.L2L; signal model: wistron_C6006
C6010 = C402H22: tolerance: 78.10324.L0L; signal model: wistron_C6010
C6011 = C402H22: tolerance: 78.10324.L0L; signal model: wistron_C6011
C6013 = C402H22: tolerance: 78.10324.L0L; signal model: wistron_C6013
C6014 = C402H22: tolerance: 78.10324.L0L; signal model: wistron_C6014
C7601 = C402H22: tolerance: 78.22423.L2L; signal model: wistron_C7601
C7602 = C402H22: tolerance: 78.22423.L2L; signal model: wistron_C7602
C7603 = C402H22: tolerance: 78.22423.L2L; signal model: wistron_C7603
C7604 = C402H22: tolerance: 78.22423.L2L; signal model: wistron_C7604
C7605 = C402H22: tolerance: 78.22423.L2L; signal model: wistron_C7605
C7606 = C402H22: tolerance: 78.22423.L2L; signal model: wistron_C7606
C7607 = C402H22: tolerance: 78.22423.L2L; signal model: wistron_C7607
C7608 = C402H22: tolerance: 78.22423.L2L; signal model: wistron_C7608
C7803 PC5153 PC5405 = C402H22: tolerance: 78.68034.1FL
C7901 C7903 = C402H22: tolerance: 78.6R874.1FLDL
C7918 = C402H22: tolerance: 78.82321.2FL
C7919 C7920 = C603H36: tolerance: 78.68421.5BL
CPU1 = BGA1356M4224-U2H52: tolerance: 071.SKYLA.000U
D1702 D2402 D2403 D2405 = SOD323AKH38: tolerance: 83.R2004.G8F
D2101 D2901 = SOT-23-9H44: tolerance: 75.BAT54.07D
D2102 = SOD323-2513AKH36: tolerance: 83.R2004.J8F
D2501 D2703 D5502 D5503 D8601 D8602 PD4410 = SOT-23-9H44: tolerance: 75.00054.A7D
D2601 D5604 PD4404 = SOD323AKH38: tolerance: 83.R5003.H8H
D4001 D4002 = SOT23-2D4-312H44: tolerance: 83.00016.P11
D4304-D4306 PD4302 = SOT23-2D4-312H44: tolerance: 75.00099.O7D
D5701 = SOT23-2D4-312H44: tolerance: 83.00056.Y11
D7601 = SOT-23-9H44: tolerance: 83.00056.Q11
DB3 = 50696-00601-001: tolerance: 20.K0691.006
DBG1 = DM-87212-1400N-01: tolerance: ZZ.F0765.01401
DCIN1 = 50458-00601-W01: tolerance: 20.F2132.006
DM1 = ADDR0206-P013A: tolerance: 062.10011.01C1
DM2 = ADDR0205-P012A: tolerance: 062.10011.01B1
EC2101 EC2701-EC2705 EC4302 EC4307 EC6402 EC6404 EC8901-EC8928 EC9701-EC9707 EC9712 EC9713 EC9715-EC9724 EC9732-EC9739 EC9741-EC9744 EC9746 EC9747 EC9749-EC9753 FC9704 PC4456 PC4463 PC4464 PC4466 PC4602 PC4603 PC4630 PC4631 PC4633 PC4634 PC5004 PC5105 PC5304 PC5308 PC8521 PC8523 PC8525 PC8530 PC8651 PC8656 = C402H22: tolerance: 78.10422.5FL
EC2709-EC2711 EC5501 EC5502 EC5504 EC9201 EC9202 PC8624 = C402H22: tolerance: 78.22034.1FL
EC4301 PC4306 PC4401 PC4410 PC4418 PC4427 PC4438 PC4452 PC4453 PC4459 PC4519 PC4527 PC4528 PC4701-PC4704 PC4802-PC4805 PC4814-PC4817 PC5002 PC5003 PC5309 PC5310 PC8519 PC8528 PC8529 PC8531 PC8652 = C805H56: tolerance: 78.10622.LAL
EC5503 EC6501-EC6506 PC4610 PC4624 PC4639 = C402H22: tolerance: 78.33034.1FL
ED502 ED1217 ED1302 ED5601-ED5603 ED6401 = SOD882-10D6-1H20: tolerance: 83.05725.0A0
ED3201 ED3202 = DFN10G2510H26: tolerance: 75.01004.073
ED3602 ED3603 ED6001 = DFN10G2510H26: tolerance: 75.01045.073
ED3604 ED3704 ED5501 ED9201 = SOT-6H58: tolerance: 075.09904.0A7C
ED5701-ED5703 = SLP2510P8-3H26: tolerance: 75.00524.A73
EL3601 = L125100-4P-4H28: tolerance: 68.01012.20B; signal model: wistron_EL3601
EL3602 = L125100-4P-4H28: tolerance: 68.01012.20B; signal model: wistron_EL3602
EL3706 = L125100-4P-4H28: tolerance: 68.01012.20B; signal model: wistron_EL3706
EL4303 EL4304 R1724 R1735 R2701 R2707 R2713 R2714 R4025 R4048 R4101 R6001 R6003 R6117 = 0R0805-PAD-1-U: tolerance: ZZ.00PAD.M31
EL5507 = L125100-4P-4H24: tolerance: 68.00396.001; signal model: wistron_EL5507
EL5601-EL5603 = L1608-UH38: tolerance: 68.00084.B61
ER5704 = 0R0402-PAD-1: tolerance: ZZ.00PAD.M11; signal model: Graser_ER5704
ER5705 = 0R0402-PAD-1: tolerance: ZZ.00PAD.M11; signal model: Graser_ER5705
ER5706 = 0R0402-PAD-1: tolerance: ZZ.00PAD.M11; signal model: Graser_ER5706
ER5713 = 0R0402-PAD-1: tolerance: ZZ.00PAD.M11; signal model: Graser_ER5713
ER5714 = 0R0402-PAD-1: tolerance: ZZ.00PAD.M11; signal model: Graser_ER5714
ER5715 = 0R0402-PAD-1: tolerance: ZZ.00PAD.M11; signal model: Graser_ER5715
ER5716 = 0R0402-PAD-1: tolerance: ZZ.00PAD.M11; signal model: Graser_ER5716
ER5717 = 0R0402-PAD-1: tolerance: ZZ.00PAD.M11; signal model: Graser_ER5717
EU1701 = D402H24: tolerance: 83.05325.AA0
F5502 F5503 = POLYSW-4633-UH43: tolerance: 69.50007.A31
F5701 = POLYSW-2114H30: tolerance: 69.48001.081
FAN1 = 3806K-F03N-04L: tolerance: 020.F0283.0003
FAN261 = SOIC8H69: tolerance: 74.05606.A71
FC1901 FC1902 = C402H22: tolerance: 78.2R074.1FL
FPR1 = TF31HM-6S-0D5H-800: tolerance: 020.K0237.0006
G1901 G6401 G6402 = CON2O-U: tolerance: ZZ.CON2O.XXX
GPU1 = BGA631M23H82: tolerance: 071.00JET.M001
H1-H8 = HOLE335R178: tolerance: ZZ.00PAD.7F1
H9 H10 H12 H13 = HOLE335R115: tolerance: ZZ.00PAD.D01
H11 H14 = HT85B85X925R29-S: tolerance: ZZ.00PAD.D81
H15 = HOLE276R91: tolerance: ZZ.00PAD.CZ1
H16 = HT85BE95R29-U-5: tolerance: ZZ.00PAD.D31
H17 = HOLE384X421R115: tolerance: ZZ.SCREW.681
HDA27 = QFN40J5-G3D75H36: tolerance: 071.03204.0003
HDD1 = 132F12-010000-A2-R: tolerance: 020.K0125.0012
HDMI1 = SKT-HDMI23-188137-5: tolerance: 022.10025.0161
HS1 = STF237R128H128: tolerance: 34.4LO45.201
IOBD1 = 51519-03001-W02-U2: tolerance: 20.K0510.030
KB1 = 196370-30041-3: tolerance: 20.K0621.030
KBC24 = TQFP128-2H48: tolerance: 071.01416.000G
L3101 = L2520-D820H41: tolerance: 68.4R71E.10G
L8001 = L402H22: tolerance: 68.00109.081
L8002 L8003 = L402H22: tolerance: 68.00084.921
LCD1 = 20455-040E-12: tolerance: 20.F1407.040
LED1 = LED3020-3P-19H44: tolerance: 083.1212A.0070
LOM31 = QFN32J4-G2D85H36: tolerance: 71.08111.U03
ODD1 = 51519-02001-W03-U1: tolerance: 20.K0708.020
PC4301 PC4435 PC4524 PC5156 = C603H32: tolerance: 78.10524.5BL
PC4402-PC4404 PC4461 PC4462 PC4467 PC4468 PC4611 PC4612 PC4623 PC4632 = C402H22: tolerance: 78.22224.L0L
PC4405 PC4625 PC4626 PC4635 PC4652 PC8522 = C402H22: tolerance: 78.22322.2FLDL
PC4406 PC8662 = C402H22: tolerance: 78.47124.L0L
PC4431 PC4606 PC4707 PC4808 PC4811 PC5005 PC8507 PC8510 = C603H40: tolerance: 78.22422.2BL
PC4433 PC8602 = C603H36: tolerance: 78.47422.5BL
PC4509 PC4529 PC5103 PC5104 PC5302 PC8520 PC8526 PC8527 PC8532 = C805H58: tolerance: 78.47522.L4L
PC4520 PC4614 PC8506 PC8515 PC8516 PC8524 PC8533 = C402H22: tolerance: 78.33124.2FL
PC4536 = C603: tolerance: 78.56124.2BL
PC4601 = C402H22: tolerance: 78.22224.2FLDL
PC4604 PC4629 PC4638 PC4641 = C402H22: tolerance: 78.33124.2FLDL
PC4605 = C402H22: tolerance: 78.68322.2FL
PC4608 PC4628 = C402H22: tolerance: 78.33322.2FL
PC4621 = C402H22: tolerance: 78.68124.2FL
PC4640 = C402H22: tolerance: 78.47224.2FLDL
PC4653 PC5116 = C402H22: tolerance: 78.47322.2FL
PC5155 PC5406 = C402H22: tolerance: 78.47224.2FL
PC8502 PC8635 = C402H22: tolerance: 78.10422.5FLDL
PC8514 = C402H22: tolerance: 78.18134.1FL
PD4301 = DO214AAAKH97: tolerance: 83.P6SMB.HAG
PD4303 = SOT-23-10H44: tolerance: 83.0024V.0A1
PD4304 = SOD123AK-2H43: tolerance: 83.SMF18.AAH
PD8501 = SOD323-2513AKH36: tolerance: 83.R5003.N8F
PG4407 PG4426 PG4428 PG4429 PG4532 PG4535 PG4701-PG4708 PG4802-PG4806 PG4808-PG4816 PG5001-PG5003 PG5011 PG5101 PG5113-PG5130 PG5301-PG5314 PG8507-PG8510 PG8651-PG8653 PG8655 = GAP-CLOSE-PWR-3: tolerance: ZZ.CLOSE.001
PG4517-PG4529 PG4531 PG4533 PG4534 PG4536-PG4538 PG4540-PG4545 PG5151 PG5152 PG5405-PG5407 PG8501-PG8506 PG8511-PG8516 PG8601-PG8604 = GAP-CLOSE-PWR: tolerance: ZZ.CON2D.XXX
PL4401 = L7066-1830-UH119: tolerance: 68.4R71A.20H
PL4501 = L7066-1830-UH119: tolerance: 68.2R210.20B
PL4502 = L7066-1830-UH119: tolerance: 68.3R310.20A
PL4701 PL4801 PL4802 = L7366-1930H158: tolerance: 68.R1510.20A
PL5001 = L7066-1830-UH119: tolerance: 68.R4710.10M
PL5101 = L7066-1830-UH119: tolerance: 68.R6810.20B
PL5301 = L7066-1830-UH119: tolerance: 68.1R01A.20B
PL8501 PL8502 = L7066-1830-UH119: tolerance: 68.R3310.201
PL8601 = L3030-3009H63: tolerance: 068.1R050.1021
PL8651 = L686647-127318H119: tolerance: 68.R681A.10A
PQ4301 Q501 Q6401 = SOT23DGS2D4H48: tolerance: 84.05067.031
PQ4302 Q5703 Q7905 = SOT23CBE2D4H44: tolerance: 84.T3904.H11
PQ4304 PQ4415 = SOT323CBE2D2H40: tolerance: 84.05212.B11
PQ4305 PQ4416 = SC70-2D2-312H44: tolerance: 84.00024.01K
PQ4306 PQ4405 PQ4406 PQ8501 PQ8604 Q1702 Q2412 Q6701 = SOT-363H44: tolerance: 84.2N702.A3F
PQ4401 PQ4410 PU4301 = PPAK-8P-3232H36: tolerance: 84.07403.037
PQ4402 PQ4412 PQ8608 Q502 Q1901 Q2110 Q2408 Q2414 Q2505 Q2602 Q2605 Q2705 Q3102 Q5701 Q6505 Q7902 Q7903 = SOT23DGS2D4H44: tolerance: 84.2N702.J31
PQ4409 = SOT23CBE2D4H44: tolerance: 84.03906.P11
PQ8607 Q2107 Q2704 Q3101 Q6504 = SOT23DGS2D4H48: tolerance: 84.02130.031
PQ8609 = SOT23DGS2D4H44: tolerance: 084.03419.0031
PR4302 = R402H16: tolerance: 64.15025.6DL
PR4303 PR8501 PR8502 PR8522 PR8543 PR8624 PR8625 PR8650 PR8661 R507 R802 R1503 R1606-R1608 R1610 R1701 R1707 R1717 R1718 R1720 R1726 R1816 R1817 R1834 R1835 R2001-R2005 R2008 R2015-R2018 R2020 R2022-R2024 R2115 R2403 R2410 R2412 R2414 R2415 R2429 R2430 R2607 R2736 R2919 R2920 R3103 R3106 R4009 R5521 R5709 R6323 R6401 R6514 R7625 R7921-R7925 R7934-R7936 R7939 R7940 R7942 R9120 R9121 R9140 R9141 = R402H15: tolerance: 63.10334.L0L
PR4304 PR8651 R1805 R1821 R1832 R7802 R9122 = R402H16: tolerance: 63.22234.L0L
PR4305 PR4306 = R402H16: tolerance: 63.33034.1DL
PR4307 = R603H22: tolerance: 63.24434.15L
PR4308 = R603H22: tolerance: 63.47333.15L
PR4309 PR4312 PR4417 PR4431 PR4441 PR4478 PR4534 PR5308 PR8539 PR8606 PR8619 PR8673 R603 R806 R1715 R1722 R1727 R1737 R1904 R2118 R2120 R2417 R2434 R2436 R2449-R2452 R2455 R2478 R2489 R2702 R2710 R2716 R2717 R3107 R4031 R4032 R5506 R5528 R5529 R5719 R6509 R6702-R6705 = R402H16: tolerance: 63.10434.1DL
PR4313 PR4406 PR4415 PR4458 PR4459 PR4462 PR4470 PR4471 PR4474-PR4476 PR4502-PR4505 PR4701 PR4702 PR4706 PR4802 PR4806 PR4811 PR4812 PR5004 PR5127 PR5128 PR5153 PR5158 PR5305 PR5306 PR5406 PR5408 PR8505 PR8509 PR8511-PR8514 PR8520 PR8530 PR8534 PR8544 PR8621 R410 R504 R602 R703 R709 R732 R1205 R1210 R1212 R1303 R1311 R1601 R1602 R1704 R1706 R1708 R1710 R1713 R1728 R2101 R2113 R2402 R2416 R2419 R2420 R2427 R2431 R2435 R2438 R2439 R2445 R2456 R2458 R2469 R2470 R2472 R2474 R2479 R2481 R2491 R2495 R2497 R2606 R2611 R2612 R2615 R2712 R2718 R3105 R3110 R4002 R4010 R4011 R4024 R4029 R4030 R4034 R4301 R5530 R5531 R5602 R5603 R5605 R5712 R6002 R6112-R6114 R6116 R6404 R6405 R6508 R6512 R7621 R7623 R7919 R7920 R7937 = 0R0402-PAD: tolerance: ZZ.R0402.ZZZ
PR4314 = R1206H28: tolerance: 63.33232.11L
PR4317 R705 R2704-R2706 R3104 R7704 R7705 = 0R0603-PAD: tolerance: ZZ.R0603.ZZZ
PR4401 PR4402 R2711 R5711 = R402H16: tolerance: 64.20035.6DL
PR4403 PR5301 = R402H16: tolerance: 64.95325.6DL
PR4404 = R402H16: tolerance: 64.82525.6DL
PR4405 = R402H16: tolerance: 64.14735.6DL
PR4407 PR4604 PR4607 PR4627 PR4631 PR4639 PR4659 PR4663 R503 R710-R713 R716 R717 R726 R1501 R1604 R7814 R7818 = R402H16: tolerance: 64.10005.L1L
PR4408 PR4481 PR4501 PR4525 PR4530 PR4535 PR5126 PR8546 PR8601 PR8677 R2461 R2473 R2486 R2602 R2605 R2737 R4033 R5524 R5526 R5707 R6324 R6511 R6515 R6518-R6520 R6706 R6807 R7904 R7911 R7913 R7943-R7946 R9149 = R402H16: tolerance: 63.R0034.1DL
PR4409 PR4413 PR4439 PR4450 PR4451 PR4472 PR4821-PR4824 PR5303 PR5402 PR8506 PR8508 PR8524 R1716 R2441 R2444 = R402H16: tolerance: 64.10035.L3L
PR4410 = R402H16: tolerance: 64.71515.6DL
PR4411 PR4477 PR4603 PR4615 PR4635 PR4645 PR4651 R7601 R7618 R7902 = R402H15: tolerance: 64.10015.L3L
PR4412 = NTC-402H24-U: tolerance: 69.60028.001
PR4414 PR8672 R1802 R2102 R2203 R6707 R7901 = R402H16: tolerance: 63.10534.1DL
PR4416 R2613 = R402H16: tolerance: 64.18725.6DL
PR4418 = R402H16: tolerance: 64.19135.6DL
PR4420 PR4422 PR4435 PR4449 PR4453 PR4523 PR4609 PR5111 PR5155 PR5304 PR8503 PR8519 PR8538 R1204 R1208 R1211 R1302 R1306 R1310 R2401 R2443 R2448 R2493 = R402H15: tolerance: 64.10025.L0L
PR4426 PR4443 = R3720H40: tolerance: 64.R0105.7FL
PR4428 PR8674 = 0R0603-PAD-U: tolerance: ZZ.R0603.001
PR4434 = R402H16: tolerance: 64.30035.L0L
PR4437 PR4456 PR4468 R1206 R1305 = R402H16: tolerance: 64.2R005.6DL
PR4438 = R603H22: tolerance: 64.4R705.55L
PR4440 = R603H22: tolerance: 63.20333.15L
PR4444 PR8518 PR8603 R401 R417 R419 R604 R605 R1702 R1822-R1825 R1827 R1828 R1909 R2006 R2007 R2019 R2432 R2453 R2502 R2735 R2921 R2922 R3109 R4005 R6506 R6516 = R402H16: tolerance: 63.10234.1DL
PR4445 = R402H15: tolerance: 63.47434.L0L
PR4452 R5710 = R402H16: tolerance: 64.15035.6DL
PR4454 = R805H24: tolerance: 64.10005.16L
PR4455 = R402H16: tolerance: 64.68035.6DL
PR4457 PR4467 PR4601 PR4602 PR4612 PR4623 PR4647 PR4649 PR4665-PR4668 PR5109 PR8671 = 0R0402-PAD: tolerance: ZZ.R0402.001
PR4512 = R402H16: tolerance: 64.66515.6DL
PR4517 PR4531 = R402H16: tolerance: 64.12735.L1L
PR4524 PR4528 = R603H22: tolerance: 63.1R534.15L
PR4526 = R402H16: tolerance: 64.10025.6DL
PR4527 = R402H16: tolerance: 64.15425.6DL
PR4529 PR4533 PR5120 PR5309 = R805H24: tolerance: 64.2R205.16L
PR4605 PR8609 R5606-R5608 = R402H16: tolerance: 64.75R05.6DL
PR4606 = R402H16: tolerance: 64.45R35.6DL
PR4608 = R402H16: tolerance: 64.90925.6DL
PR4610 = R402H16: tolerance: 63.1R034.1DL
PR4611 PR4646 PR4650 PR8533 = NTC-402H22-U: tolerance: 69.60011.201
PR4613 PR4614 PR4669 R721 R1307 R1819 R2114 R2411 R2418 R2428 R2463-R2466 R2471 R2476 R2487 R3701 R3702 R4012 R5533 R5534 R6115 R6118 R9146 = R402H15: tolerance: 63.R0034.L0L
PR4616 = R402H16: tolerance: 64.57615.6DL
PR4617 PR4654 = NTC-402H24-U: tolerance: 69.60013.141
PR4618 PR4643 PR4652 PR8532 = R402H16: tolerance: 64.11025.6DL
PR4620 = R402H16: tolerance: 64.39205.6DL
PR4621 PR4655 = R402H16: tolerance: 64.27425.6DL
PR4622 PR4809 PR4815 R2908 R2910 = R402H16: tolerance: 64.10R05.L1L
PR4624 R412-R415 R601 R7804 = R402H16: tolerance: 64.49R95.L0L
PR4625 PR4641 PR4653 PR8529 = R402H16: tolerance: 64.26115.6DL
PR4626 = R402H16: tolerance: 64.33015.6DL
PR4628 = R402H16: tolerance: 64.93115.6DL
PR4629 PR4661 PR4672 = R402H16: tolerance: 64.88725.6DL
PR4630 PR4638 PR4657 PR8527 R2614 R7927 R7929 = R402H16: tolerance: 64.20015.L0L
PR4632 = R402H16: tolerance: 64.10015.6DL
PR4633 = R402H16: tolerance: 64.30115.6DL
PR4636 PR4658 R403 = R402H16: tolerance: 64.49905.6DL
PR4637 R7622 = R402H16: tolerance: 64.16915.6DL
PR4640 R3102 = R402H16: tolerance: 64.24915.L0L
PR4642 = R402H16: tolerance: 64.32405.6DL
PR4644 = R402H16: tolerance: 64.11335.6DL
PR4648 R6406 = R402H16: tolerance: 64.27405.6DL
PR4656 = R402H16: tolerance: 64.28715.6DL
PR4660 = R402H16: tolerance: 64.19115.6DL
PR4662 R7931 = R402H16: tolerance: 64.47515.6DL
PR4670 = R402H16: tolerance: 64.26705.6DL
PR4671 = R402H16: tolerance: 64.15415.6DL
PR4703 PR4805 PR4814 = R1206H28: tolerance: 63.2R232.11L
PR4704 PR4803 PR4813 = R402H16: tolerance: 64.2R205.6DL
PR4705 PR4804 PR4810 PR5001 PR5112 PR8507 PR8515 = R603H24: tolerance: 64.2R205.L0L
PR4708 PR4808 PR4816 PR5003 PR8517 PR8537 = R402H16: tolerance: 64.36515.6DL
PR4712 PR4817 PR4818 = R402H16: tolerance: 64.51115.6DL
PR5107 = R402H16: tolerance: 64.5R105.6DL
PR5113 = R402H16: tolerance: 64.75035.L0L
PR5114 = R402H16: tolerance: 64.25535.6DL
PR5116 = R402H16: tolerance: 64.15825.6DL
PR5117 PR5154 R2424 = R402H16: tolerance: 64.20025.L0L
PR5151 = R402H16: tolerance: 64.43225.6DL
PR5152 PR5401 = R402H16: tolerance: 63.47334.1DL
PR5302 = R402H16: tolerance: 64.25515.6DL
PR5403 PR8676 = R402H16: tolerance: 64.16525.6DL
PR5404 = R402H16: tolerance: 64.13025.6DL
PR8510 PR8521 PR8540 = R402H16: tolerance: 64.1R005.6DL
PR8516 = R402H16: tolerance: 64.13335.6DL
PR8523 = R402H16: tolerance: 64.30105.6DL
PR8525 = R402H16: tolerance: 64.11315.6DL
PR8526 = R402H16: tolerance: 64.33025.6DL
PR8528 = R402H16: tolerance: 64.32425.6DL
PR8531 PR8535 R7803 = R402H16: tolerance: 63.10034.L0L
PR8536 = R402H16: tolerance: 64.16515.6DL
PR8541 PR8542 = R603H22: tolerance: 63.2R233.15L
PR8545 R4302 R5502 R5503 R5518 R5525 = R402H15: tolerance: 63.10134.L0L
PR8622 = R402H16: tolerance: 64.30125.6DL
PR8623 = R402H16: tolerance: 64.51125.6DL
PR8675 R2609 = R402H16: tolerance: 64.24925.6DL
PT4501 PT4502 = SE361414H178: tolerance: 79.22710.3KL
PT4701 PT4801 PT4803 PT8506-PT8508 = CT7343H83: tolerance: 79.33719.20C
PT4805 PT8902 = CT7343H123: tolerance: 077.C1071.0071
PT4806 PT8901 = CT7343H83: tolerance: 79.33612.20L
PU4401 = QFN32J4-G2D7H42: tolerance: 074.95521.0A73
PU4411 PU4412 = PPAK-8PH48: tolerance: 084.04378.0037
PU4501 PU4504 PU4505 PU5002 PU5003 PU5102 = PPAK-8P-3232H36: tolerance: 84.07410.A37
PU4502 PU5105 = PPAK-8P-3232H36: tolerance: 84.07506.037
PU4503 = QFN20-G1D75H32: tolerance: 74.51225.073
PU4601 = QFN40J5-G3D6-DIFF-H34: tolerance: 074.95859.0B33
PU4701 PU4801 PU4802 = DFN8J4535-G4122-U1H40: tolerance: 074.97396.0043
PU5001 = DFN8G2-G1710-U1H40: tolerance: 074.95808.0B73
PU5101 = QFN20-G1D75H32: tolerance: 074.08231.0073
PU5151 PU5401 = SOIC8-G3530H63: tolerance: 74.05930.03D
PU5301 = QFN22G4-G2PH42: tolerance: 074.02262.0043
PU8501 = QFN40-G3D5H32: tolerance: 74.62771.033
PU8502-PU8505 = PPAK-8P-G5324H44-COLAY: tolerance: ZZ.00215.037
PU8601 = DFN8G2-G1711H26: tolerance: 74.00232.033
PU8651 = QFN20Z3-G1D1H36: tolerance: 074.08286.0B43
PWR1 = 50524-00401-001: tolerance: 020.K0005.0004
Q1701 = SOT-363H44: tolerance: 075.00138.0A7C
Q1801 = SOT-363H44: tolerance: 84.2N702.A3F; signal model: Graser_Q1801
Q5702 = SOT-363H44: tolerance: 84.2N702.A3F; signal model: wistron_Q5702
Q6301 = SOT23DGS2D4H44: tolerance: 084.00138.0A31
Q6403 Q6404 Q6502 = SOT23CBE2D6H62: tolerance: 084.02418.0011
Q6503 = SOT-363H44: tolerance: 84.2N702.A3F; signal model: Graser_Q6503
Q7901 = SOT-363H44: tolerance: 84.2N702.A3F; signal model: Graser_Q7901
Q7904 = SOT-363H44: tolerance: 84.2N702.A3F; signal model: Graser_Q7904
R402 R406-R409 R416 R421-R423 = R402H16: tolerance: 63.51034.1DL
R501 = R402H16: tolerance: 64.12105.6DL
R502 = R402H16: tolerance: 64.80R65.6DL
R505 = R402H16: tolerance: 64.47005.6DL
R506 = R402H16: tolerance: 64.22035.L1L
R718-R720 = R805H20: tolerance: 063.R0007.0161
R723 = R402H16: tolerance: 64.54R95.6DL
R727 = R402H16: tolerance: 63.56034.1DL
R728 = R402H16: tolerance: 63.22134.1DL
R801 R1209 R1309 = R402H16: tolerance: 64.24R95.6DL
R1101 = 0R1206-PAD: tolerance: ZZ.R1206.ZZZ
R1110 R1117 R1139 R1711 R2108 R2112 R2446 R2703 R2715 R2901-R2904 R2906 R2907 R2909 R2911 R2923 R3101 R5520 R5527 R5609 R5610 R6701 = 0R0603-PAD-1-U: tolerance: ZZ.00PAD.M21
R1215 R1312 = R402H16: tolerance: 64.24005.6DL
R1502 R1901 = R402H16: tolerance: 64.20005.6DL
R1603 = R402H16: tolerance: 64.11305.6DL
R1719 R2505 = R402H16: tolerance: 64.47025.6DL
R1730 = R402H16: tolerance: 63.33434.1DL
R1731 R3111 R4006 = R402H16: tolerance: 63.20334.1DL
R1734 R8101-R8104 = R402H16: tolerance: 64.60R45.6DL
R1801 = 0R0402-PAD: tolerance: ZZ.R0402.ZZZ; signal model: Graser_R1801
R1803 = R402H16: tolerance: 64.27015.6DL
R1804 = R402H16: tolerance: 64.15R05.6DL; signal model: Graser_R1804
R1806 = 0R0402-PAD: tolerance: ZZ.R0402.ZZZ; signal model: Graser_R1806
R1807 = 0R0402-PAD: tolerance: ZZ.R0402.ZZZ; signal model: Graser_R1807
R1808 = 0R0402-PAD: tolerance: ZZ.R0402.ZZZ; signal model: Graser_R1808
R1809 = 0R0402-PAD: tolerance: ZZ.R0402.ZZZ; signal model: Graser_R1809
R1810 = 0R0402-PAD: tolerance: ZZ.R0402.ZZZ; signal model: wistron_R1810
R1811 = 0R0402-PAD: tolerance: ZZ.R0402.ZZZ; signal model: Graser_R1811
R1812 = 0R0402-PAD: tolerance: ZZ.R0402.ZZZ; signal model: Graser_R1812
R1813 = R402H15: tolerance: 63.R0034.L0L; signal model: wistron_R1813
R1814 = 0R0402-PAD: tolerance: ZZ.R0402.ZZZ; signal model: Graser_R1814
R1815 R2504 = R402H16: tolerance: 63.10634.1DL
R1818 = R402H16: tolerance: 64.82015.6DL
R1820 = R402H16: tolerance: 63.15434.1DL
R1826 = 0R0402-PAD: tolerance: ZZ.R0402.ZZZ; signal model: Graser_R1826
R1829 = R402H16: tolerance: 64.15R05.6DL; signal model: Graser_R1829
R1830 = R402H16: tolerance: 64.15R05.6DL; signal model: Graser_R1830
R1831 = R402H16: tolerance: 64.15R05.6DL; signal model: Graser_R1831
R1833 = R402H16: tolerance: 64.15R05.6DL; signal model: Graser_R1833
R1907 = 0R0402-PAD: tolerance: ZZ.R0402.ZZZ; signal model: wistron_R1907
R1908 = 0R0402-PAD: tolerance: ZZ.R0402.ZZZ; signal model: wistron_R1908
R1912 = 0R0402-PAD: tolerance: ZZ.R0402.ZZZ; signal model: wistron_R1912
R2046 R2048 R2049 = R402H16: tolerance: 63.51334.1DL
R2104 R2501 R2738 R2912 R2913 R5613 R5616 R6513 R7941 = R402H16: tolerance: 63.47234.1DL
R2107 R2462 R2708 R2709 R2719 R2734 R2740 R2741 R4036 R5501 R5537 R5538 R6004 R6521 R9136 R9143-R9145 R9147 R9150 R9152 R9202 = 0R0402-PAD-1: tolerance: ZZ.00PAD.M11
R2116 R5522 R5718 R6311 R6325 R6517 R6601 = R603H22: tolerance: 63.R0033.L0L
R2201 = R402H16: tolerance: 63.R0034.1DL; signal model: wistron_R2201
R2202 = R402H16: tolerance: 63.R0034.1DL; signal model: wistron_R2202
R2421 R2423 = R402H16: tolerance: 63.33134.1DL
R2437 = R402H16: tolerance: 63.43034.1DL
R2442 = R402H16: tolerance: 64.64925.6DL
R2503 = R402H16: tolerance: 64.16015.6DL
R2507 = R402H16: tolerance: 64.10R05.L1L; signal model: Graser_R2507
R2608 = R402H16: tolerance: 64.25525.6DL
R2610 = NTC-603H38: tolerance: 69.60035.041
R2720 = R402H16: tolerance: 63.22034.1DL
R2722 = 0R0402-PAD-1: tolerance: ZZ.00PAD.M11; signal model: wistron_R2722
R2723 = R402H16: tolerance: 63.22034.1DL; signal model: wistron_R2723
R2724 = R402H16: tolerance: 63.22034.1DL; signal model: wistron_R2724
R3113 = R402H16: tolerance: 63.15334.1DL
R3301 = 0R0402-PAD-1: tolerance: ZZ.00PAD.M11; signal model: Graser_R3301
R3302 = 0R0402-PAD-1: tolerance: ZZ.00PAD.M11; signal model: Graser_R3302
R3605 = 0R0402-PAD-1: tolerance: ZZ.00PAD.M11; signal model: Graser_R3605
R3606 = 0R0402-PAD-1: tolerance: ZZ.00PAD.M11; signal model: Graser_R3606
R3607 = 0R0402-PAD-1: tolerance: ZZ.00PAD.M11; signal model: Graser_R3607
R3608 = 0R0402-PAD-1: tolerance: ZZ.00PAD.M11; signal model: Graser_R3608
R3609 = 0R0402-PAD-1: tolerance: ZZ.00PAD.M11; signal model: Graser_R3609
R3610 = 0R0402-PAD-1: tolerance: ZZ.00PAD.M11; signal model: Graser_R3610
R3611 = 0R0402-PAD-1: tolerance: ZZ.00PAD.M11; signal model: Graser_R3611
R3612 = 0R0402-PAD-1: tolerance: ZZ.00PAD.M11; signal model: Graser_R3612
R5523 R5532 = R805H24: tolerance: 63.R0031.16L
R5535 = 0R0402-PAD-1: tolerance: ZZ.00PAD.M11; signal model: Graser_R5535
R5536 = 0R0402-PAD-1: tolerance: ZZ.00PAD.M11; signal model: Graser_R5536
R5611 R5612 = R402H16: tolerance: 63.47034.1DL
R5701-R5703 R5708 = R402H16: tolerance: 63.15134.1DL
R6108 = R402H15: tolerance: 63.R0034.L0L; signal model: Graser_R6108
R6109 = R402H15: tolerance: 63.R0034.L0L; signal model: Graser_R6109
R6110 = 0R0402-PAD-1: tolerance: ZZ.00PAD.M11; signal model: Graser_R6110
R6111 = 0R0402-PAD-1: tolerance: ZZ.00PAD.M11; signal model: Graser_R6111
R6119 = R402H15: tolerance: 63.R0034.L0L; signal model: Graser_R6119
R6312 = R402H16: tolerance: 64.10R05.L1L; signal model: Graser_R6312
R6313 = R402H16: tolerance: 64.10R05.L1L; signal model: Graser_R6313
R6314 = R402H16: tolerance: 64.10R05.L1L; signal model: Graser_R6314
R6315 = R402H16: tolerance: 64.10R05.L1L; signal model: Graser_R6315
R6316 = R402H16: tolerance: 64.10R05.L1L; signal model: Graser_R6316
R6317 = R402H16: tolerance: 64.10R05.L1L; signal model: Graser_R6317
R6318 = R402H16: tolerance: 64.10R05.L1L; signal model: Graser_R6318
R6319 = R402H16: tolerance: 64.10R05.L1L; signal model: Graser_R6319
R6320 = R402H16: tolerance: 63.R0034.1DL; signal model: Graser_R6320
R6321 = R402H16: tolerance: 63.R0034.1DL; signal model: Graser_R6321
R6322 = R402H16: tolerance: 64.10R05.L1L; signal model: Graser_R6322
R6407 = R402H16: tolerance: 64.42205.6DL
R6522 = R603H22: tolerance: 63.10133.15L
R6808 = R402H16: tolerance: 63.R0034.1DL; signal model: Graser_R6808
R6809 = R402H16: tolerance: 63.R0034.1DL; signal model: Graser_R6809
R7809 R8109 R8110 = R402H16: tolerance: 64.12005.6DL
R7810 R7817 = R402H16: tolerance: 64.40R25.6DL
R7819 R7903 = R402H16: tolerance: 64.51015.6DL
R7820 R7821 = R402H16: tolerance: 64.51R15.6DL
R7912 = 0R0402-PAD: tolerance: ZZ.R0402.ZZZ; signal model: Graser_R7912
R7914 = 0R0402-PAD: tolerance: ZZ.R0402.ZZZ; signal model: Graser_R7914
R7926 R7928 R7930 = R402H16: tolerance: 64.84515.6DL
R7932 = R402H16: tolerance: 64.32415.6DL
R7933 = R402H16: tolerance: 64.56215.6DL
R7938 = R402H16: tolerance: 64.16225.6DL
R8105 R8106 = R402H16: tolerance: 64.23715.6DL
R8107 R8108 = R402H16: tolerance: 64.54915.6DL
R8111-R8114 = R402H15: tolerance: 63.10234.L0L
R9130 = 0R0402-PAD: tolerance: ZZ.R0402.ZZZ; signal model: Graser_R9130
R9132 = R402H16: tolerance: 63.33034.1DL; signal model: Graser_R9132
R9133 = R402H16: tolerance: 63.33034.1DL; signal model: Graser_R9133
R9138 = R402H16: tolerance: 63.33034.1DL; signal model: Graser_R9138
R9203 = 0R0402-PAD-1: tolerance: ZZ.00PAD.M11; signal model: Graser_R9203
R9204 = 0R0402-PAD-1: tolerance: ZZ.00PAD.M11; signal model: Graser_R9204
RJ45 = 23-00980-2A03-A: tolerance: 022.10001.0D41
RN801 RN803 RN2008 RN2010 RN2901 RN5601 RN5702 RN6502 = ARES2H16: tolerance: 66.22236.04L
RN802 RN1704 RN1812 = ARES8-CN24-MUH20: tolerance: 66.10336.08L
RN1201 RN1301 = SMD-ARES4H18: tolerance: 66.10236.04L
RN1701 RN1813 RN2007 RN2009 RN2011 RN6504 RN7904 RN7905 = ARES2H18: tolerance: 66.10336.04L
RN1807 = ARES8-CN24-UH20: tolerance: 66.22236.A8L
RN1901 = SMD-ARES4H20: tolerance: 66.20336.04L
RN2402 RN2501 RN5602 RN5603 RN7902 RN7903 = SMD-ARES4H18: tolerance: 66.47236.04L
RN2403 RN2404 = ARES8-CN24-UH22: tolerance: 66.10336.B8L
RN2405-RN2409 RN5502 = ARES8-CN24H20: tolerance: 66.10436.A8L
RN2502 = SMD-ARES4H20: tolerance: 66.R0036.04L; signal model: Graser_RN2502
RN2503 = SMD-ARES4H20: tolerance: 66.R0036.04L; signal model: Graser_RN2503
RN3201 = ARES8-CN24H22: tolerance: 66.75036.08L
RN4302 = SMD-ARES4H18: tolerance: 66.10136.04L; signal model: Graser_RN4302
RN5501 RN5503 RN6401 = SMD-ARES4H18: tolerance: 66.10136.04L
RN5701 RN5703 = ARES8-CN24H20: tolerance: 66.47136.08L
RN6503 = SMD-ARES4H18: tolerance: 66.33036.04L
RTC1 = AAA-BAT-054-P06: tolerance: 62.70001.061
SKT251 = G6179HT0321-001: tolerance: 62.10089.011
SPI25 = SOIC8-1H86: tolerance: 072.25128.0H01
SPK1 = 50224-0040N-001: tolerance: 20.F1639.004
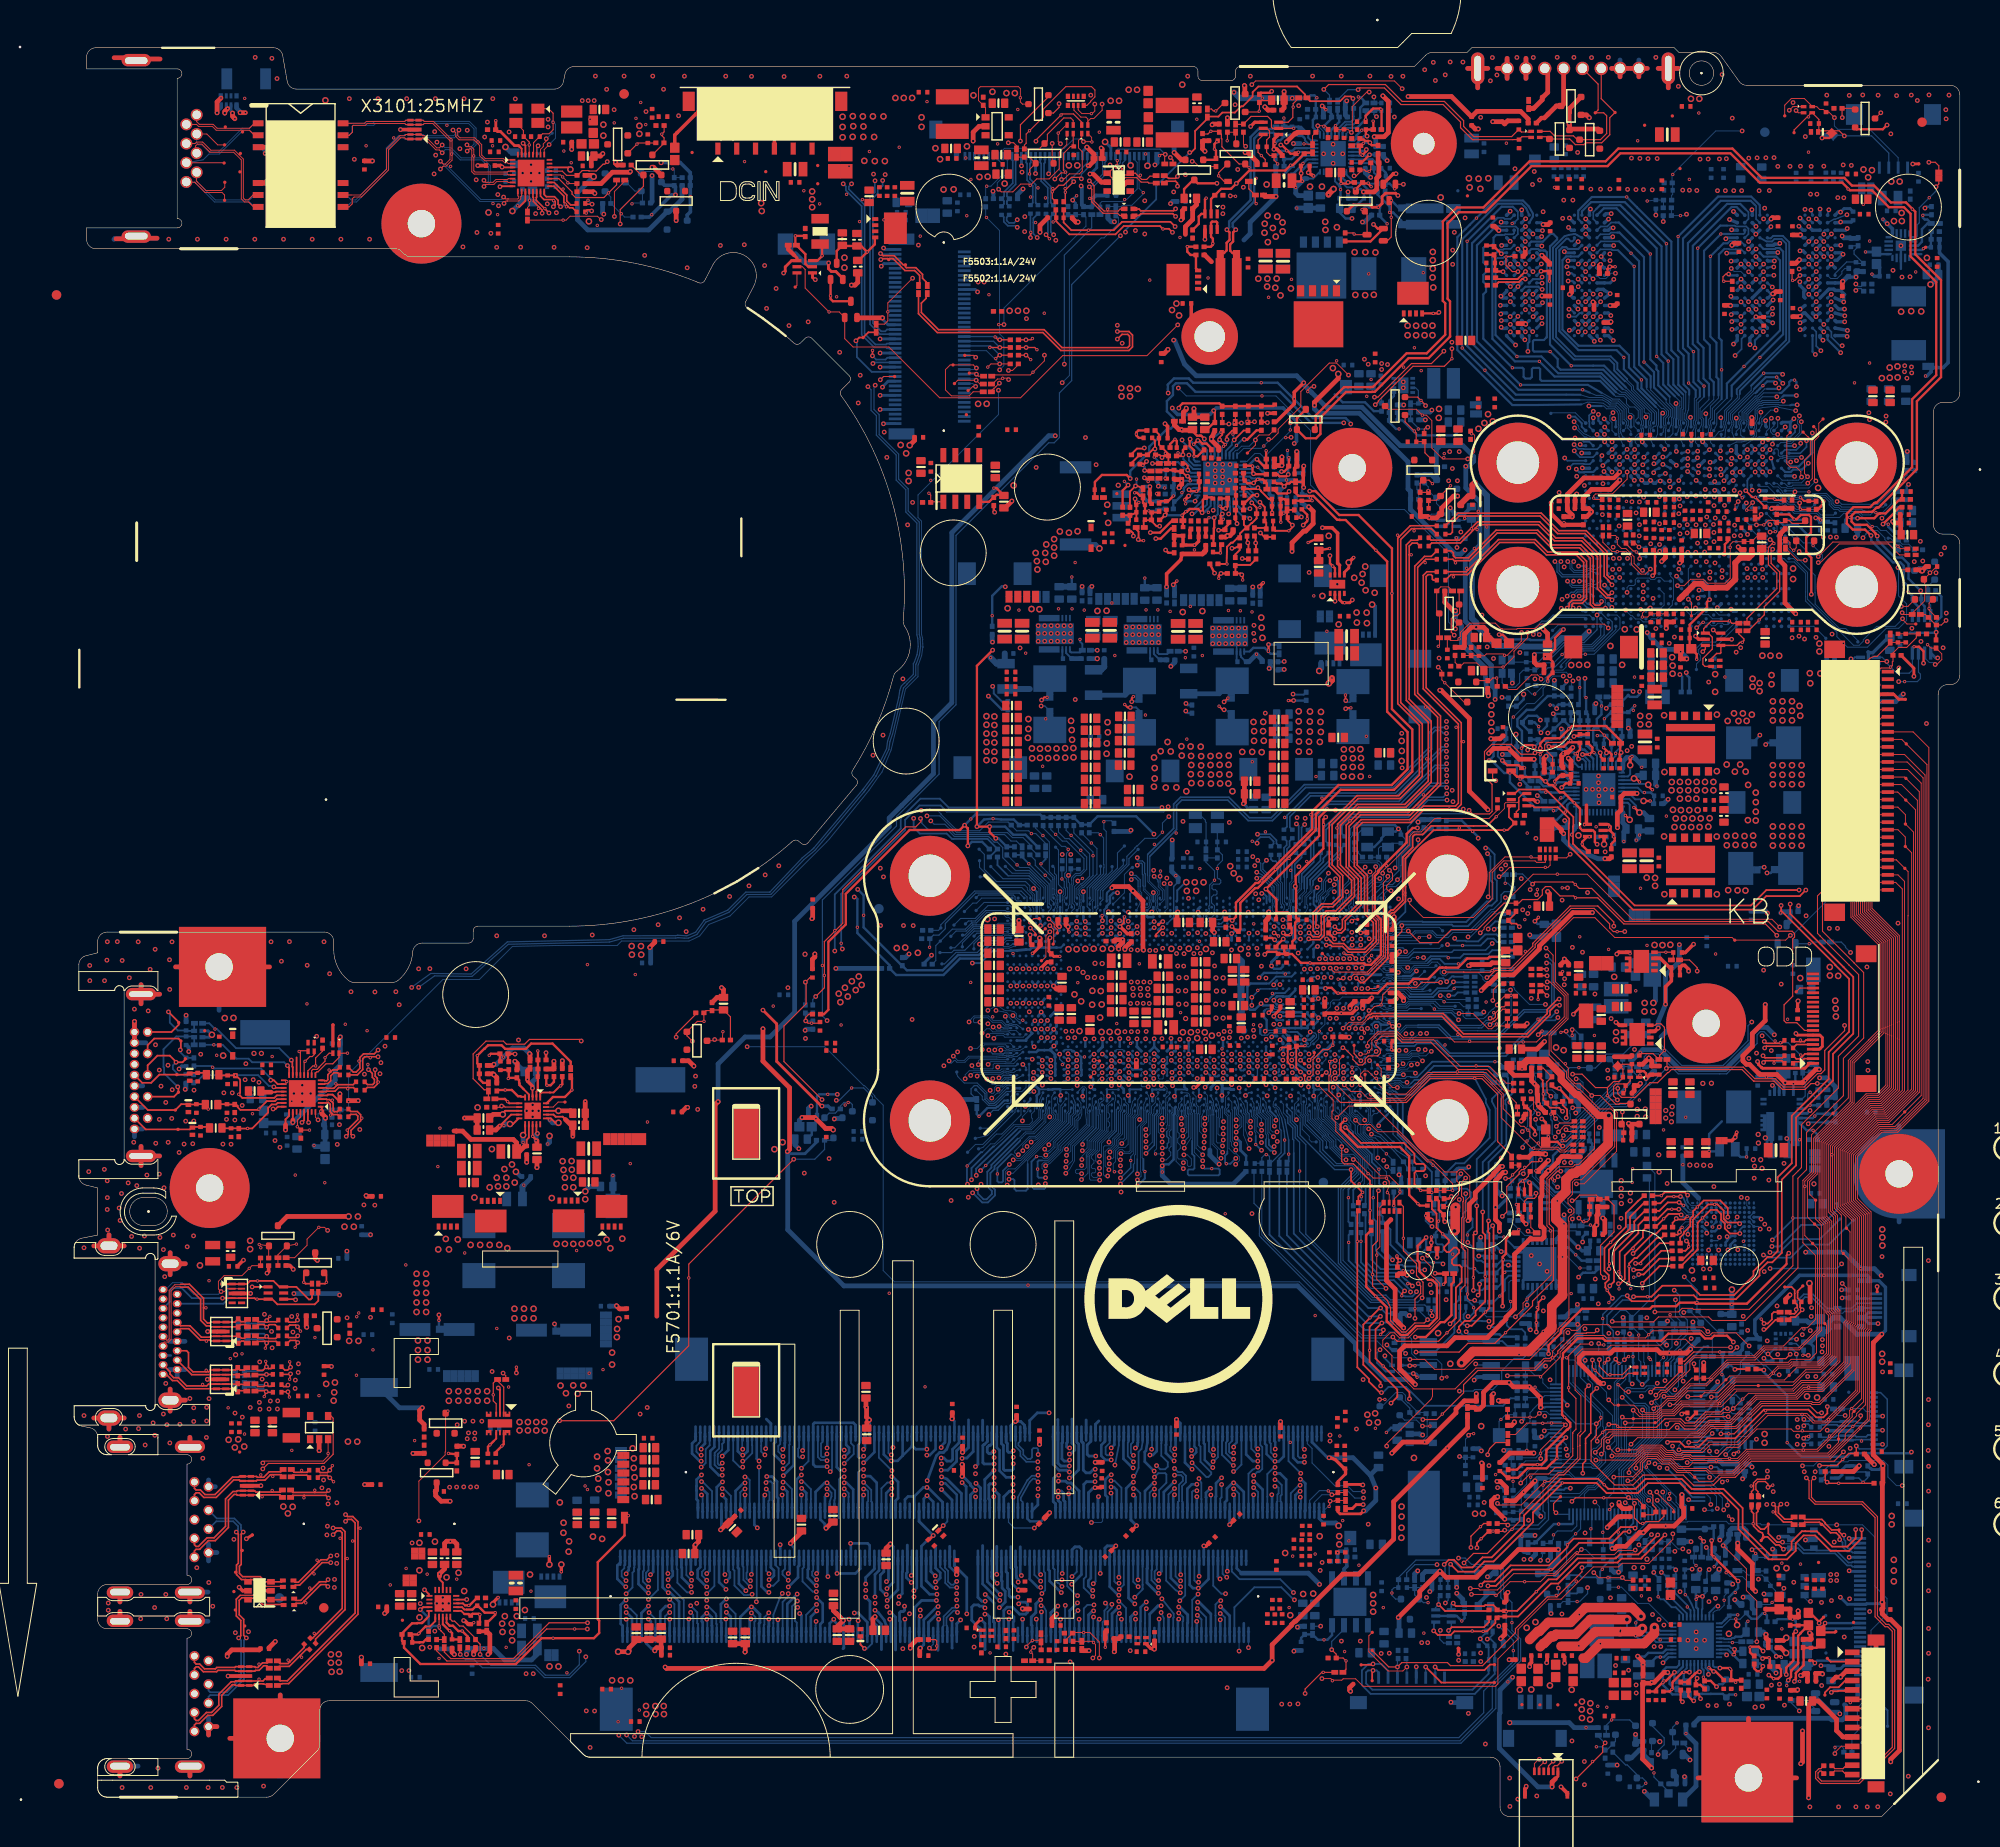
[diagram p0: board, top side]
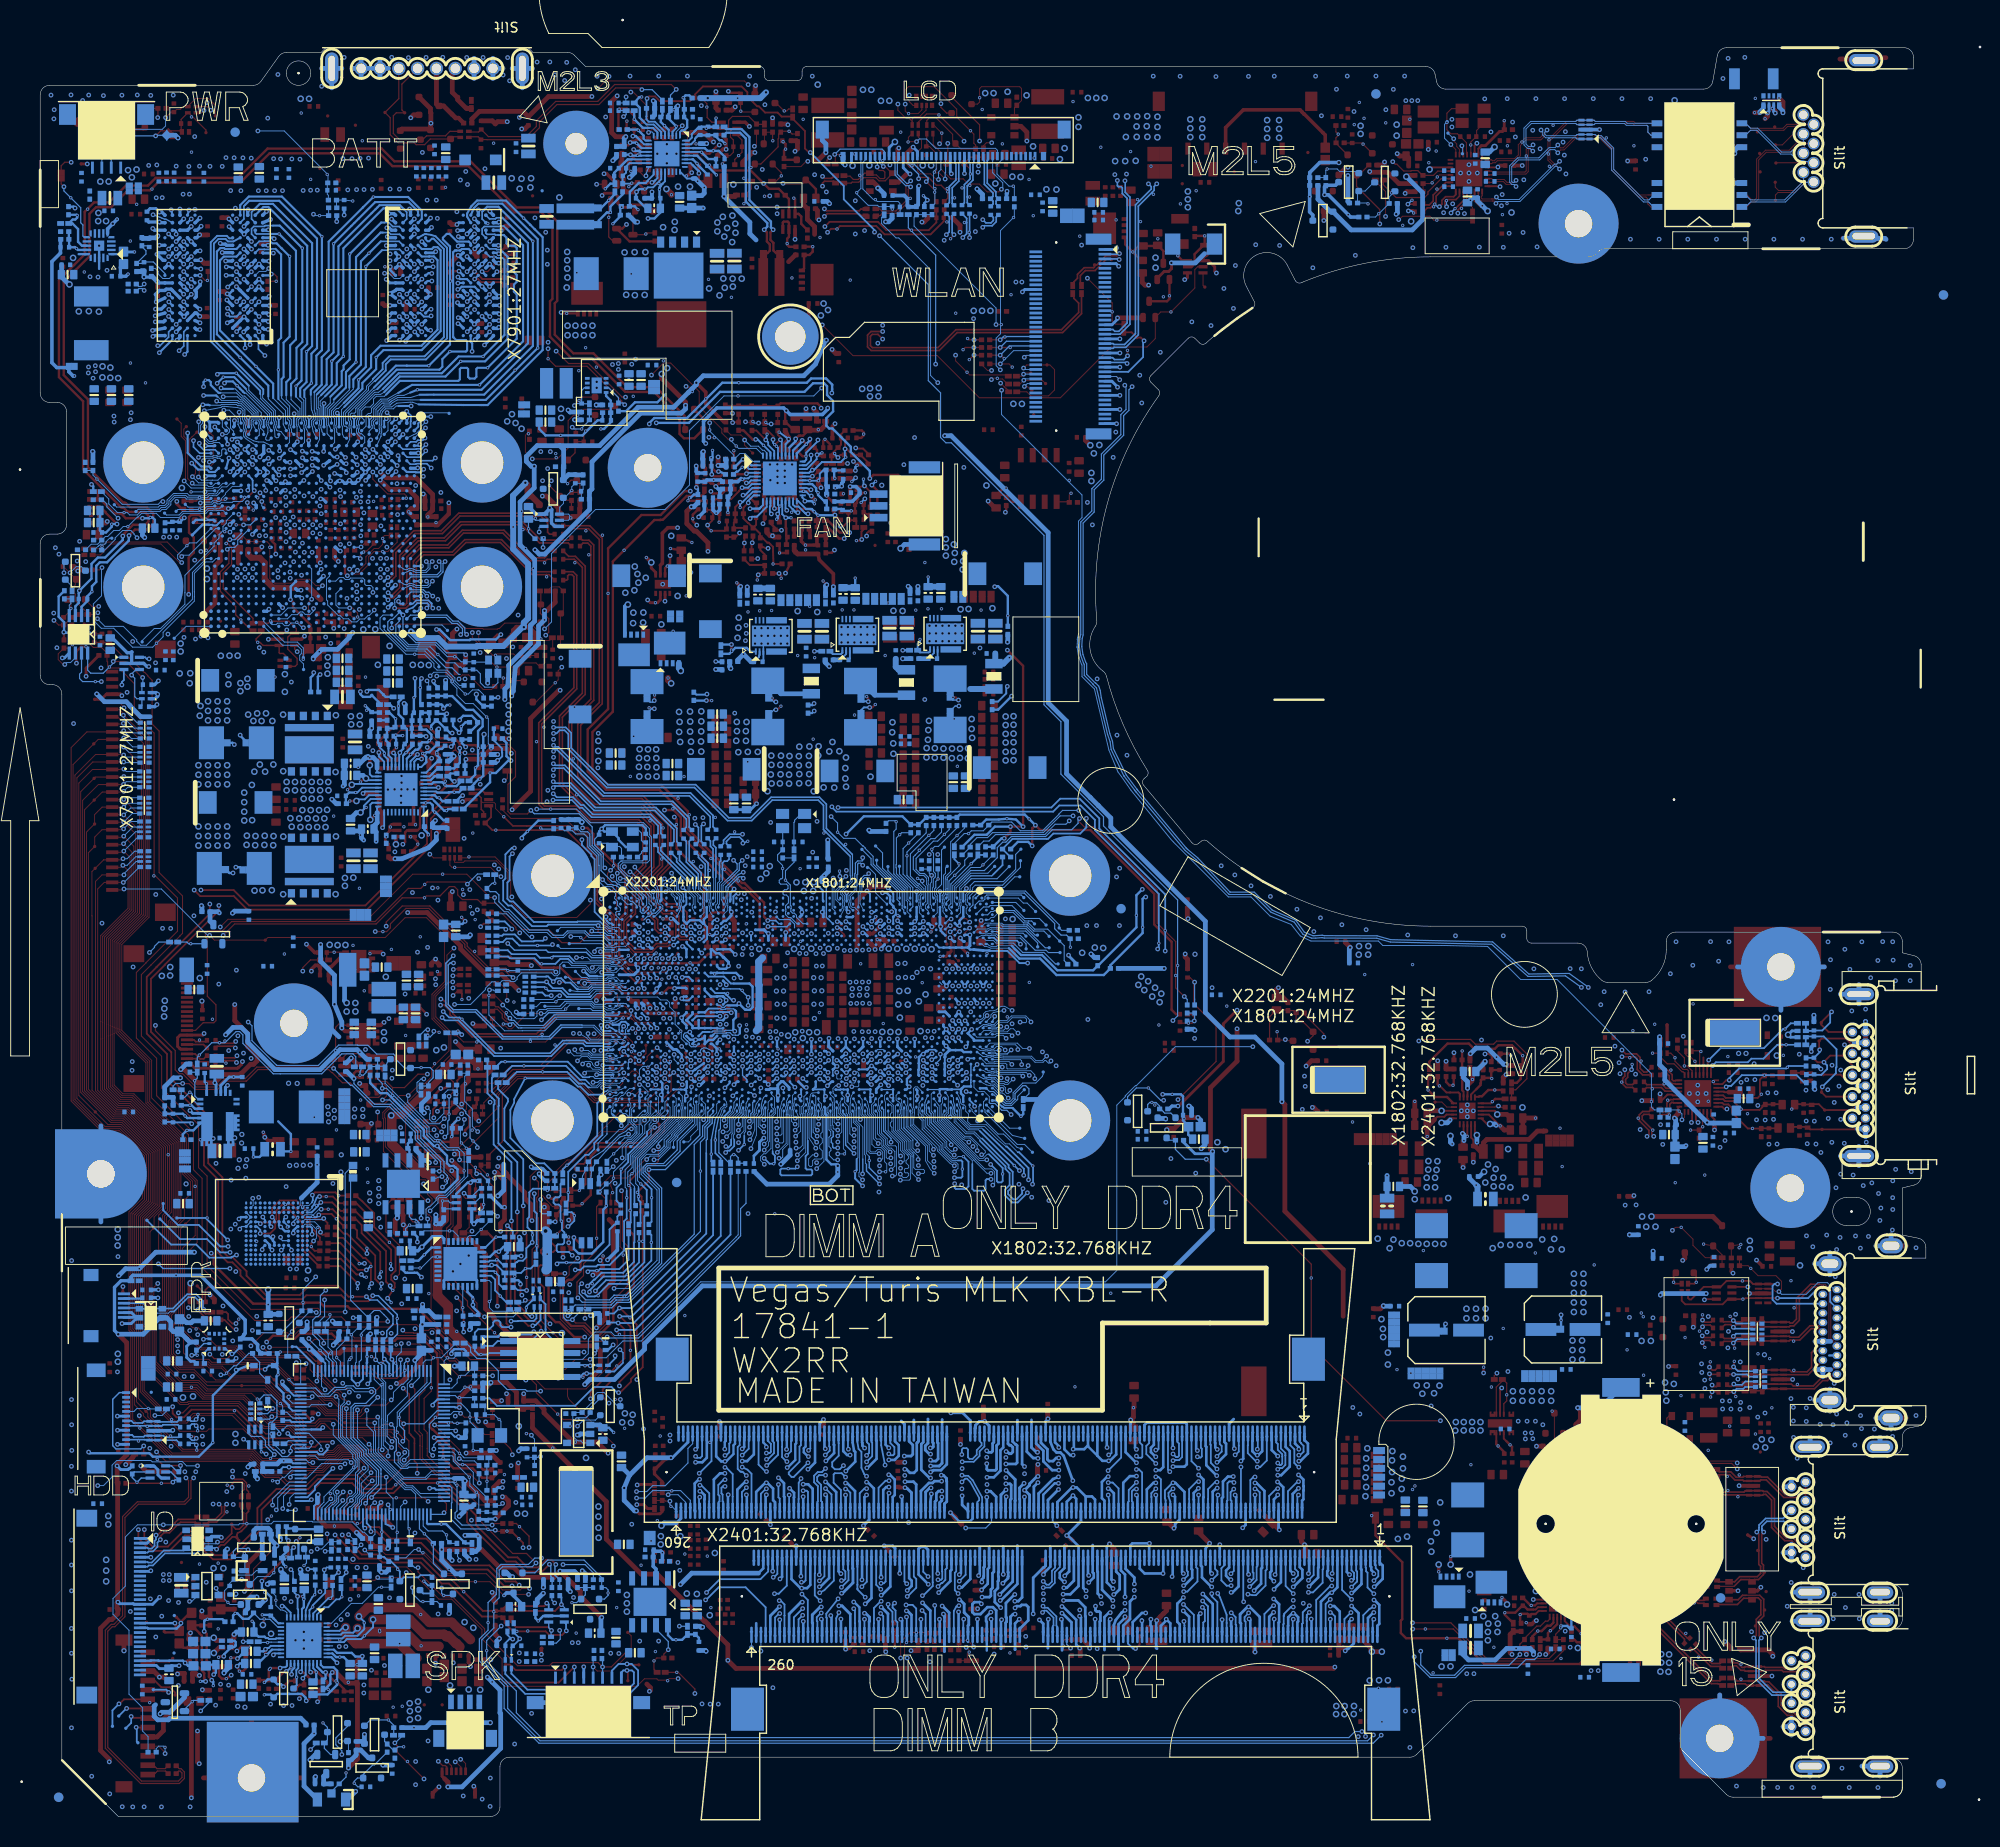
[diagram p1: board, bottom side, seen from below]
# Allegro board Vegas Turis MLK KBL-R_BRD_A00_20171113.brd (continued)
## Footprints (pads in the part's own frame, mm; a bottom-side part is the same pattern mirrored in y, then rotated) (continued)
C144KA-108A7-L-1
  round 1.422 hole 1.016: 1(7,0) 2(5,0) 3(3,0) 4(1,0) 5(-1,0) 6(-3,0) 7(-5,0) 8(-7,0)
  oval 1.422x3.404 hole 0.711x2.692: 9(10.125,0) 10(-10.125,0)
C402H22
  custom 0.114x0.114 smd: 1(0,0.457) 2(0,-0.457)
C603
  custom 0.197x0.197 smd: 1(0,0.66) 2(0,-0.66)
C603H32
  custom 0.197x0.197 smd: 1(0,0.66) 2(0,-0.66)
C603H36
  custom 0.197x0.197 smd: 1(0,0.66) 2(0,-0.66)
C603H38
  custom 0.197x0.197 smd: 1(0,0.66) 2(0,-0.66)
C603H40
  custom 0.197x0.197 smd: 1(0,0.66) 2(0,-0.66)
C805H56
  rect 1.549x0.94 smd: 1(0,0.838) 2(0,-0.838)
C805H58
  rect 1.549x0.94 smd: 1(0,0.838) 2(0,-0.838)
C1206H71
  rect 1.854x1.016 smd: 1(0,1.346) 2(0,-1.346)
C1808H40
  rect 2.235x1.143 smd: 1(0,2.057) 2(0,-2.057)
CON2O-U
  custom 0.159x0.159 smd: 1(0,0.254) 2(0,-0.254)
CT7343H83
  rect 2.413x1.905 smd: 1(0,2.959) 2(0,-2.959)
CT7343H123
  rect 2.413x1.905 smd: 1(0,2.959) 2(0,-2.959)
D402H24
  custom 0.127x0.127 smd: 1(0,0.432) 2(0,-0.432)
DFN8F3-G245165H34
  rect 0.406x0.711 smd: 1(0.975,1.399) 2(0.325,1.399) 3(-0.325,1.399) 4(-0.975,1.399) 5(-0.975,-1.399)
  rect 0.025x0.025 smd: 6(-0.325,-1.399) 8(0.975,-1.399)
  custom 0.178x0.178 smd: 7(0.325,-1.399)
  rect 2.438x1.651 smd: 9(0,0)
DFN8G2-G1710-U1H40
  rect 0.305x0.559 smd: 1(0.75,1.043) 2(0.25,1.043) 3(-0.25,1.043) 4(-0.75,1.043) 5(-0.75,-1.043) 6(-0.25,-1.043) 7(0.25,-1.043) 8(0.75,-1.043)
  rect 1.702x0.94 smd: 9(0,0)
DFN8G2-G1711H26
  rect 0.305x0.508 smd: 1(0.75,1) 2(0.25,1) 3(-0.25,1) 4(-0.75,1) 5(-0.75,-1) 6(-0.25,-1) 7(0.25,-1) 8(0.75,-1)
  rect 1.702x1.092 smd: 9(0,0)
DFN8J4535-G4122-U1H40
  rect 0.203x0.686 smd: 1(1.6,1.661) 2(1.2,1.661) 3(0.8,1.661) 6(0.8,-1.661) 7(1.2,-1.661) 8(1.6,-1.661)
  rect 2.21x0.686 smd: 4(-0.6,1.661) 5(-0.6,-1.661)
  rect 4.039x2.21 smd: 9(0,0)
DFN10G2510H26
  rect 0.305x0.66 smd: 1(1,0.43) 5(-1,0.43) 6(-1,-0.43) 10(1,-0.43)
  rect 0.254x0.66 smd: 2(0.521,0.43) 4(-0.521,0.43) 7(-0.521,-0.43) 9(0.521,-0.43)
  rect 0.025x0.025 smd: 3(0,0.43)
  rect 0.406x1.499 smd: 8(0,-0.43)
DM-87212-1400N-01
  rect 0.61x1.549 smd: 1(-6.5,-2.525) 2(-5.5,-2.525) 3(-4.5,-2.525) 4(-3.5,-2.525) 5(-2.5,-2.525) 6(-1.5,-2.525) 7(-0.5,-2.525) 8(0.5,-2.525) 9(1.5,-2.525) 10(2.5,-2.525) 11(3.5,-2.525) 12(4.5,-2.525) 13(5.5,-2.525) 14(6.5,-2.525)
  rect 1.194x1.803 smd: 15(-7.797,0) 16(7.797,0)
DO214AAAKH97
  rect 2.261x1.651 smd: A(0,2.223) K(0,-2.223)
G6179HT0321-001
  rect 0.635x1.854 smd: 1(1.905,3.339) 2(0.635,3.339) 3(-0.635,3.339) 4(-1.905,3.339) 5(-1.905,-3.339) 6(-0.635,-3.339) 7(0.635,-3.339) 8(1.905,-3.339)
GAP-CLOSE-PWR
  rect 0.66x0.762 smd: 1(-0.305,0) 2(0.305,0)
GAP-CLOSE-PWR-3
  rect 0.66x0.762 smd: 1(-0.305,0) 2(0.305,0)
HOLE276R91
  round 7.01 hole 2.311: 1(0,0)
HOLE335R115
  round 8.509 hole 2.921: 1(0,0)
HOLE335R178
  round 8.509 hole 4.521: 1(0,0)
HOLE384X421R115
  rect 9.754x10.693 hole 2.921: 1(0,0)
HT85B85X925R29-S
  rect 8.509x9.271 hole 2.921: 1(0,0)
HT85BE95R29-U-5
  round 8.509 hole 2.921: 1(0,0)
L402H22
  custom 0.127x0.127 smd: 1(0,0.432) 2(0,-0.432)
L1608-UH38
  custom 0.197x0.197 smd: 1(0,0.66) 2(0,-0.66)
L2520-D820H41
  rect 2.261x1.295 smd: 1(0,0.844) 2(0,-0.844)
L3030-3009H63
  rect 3.251x1.397 smd: 1(0,1.044) 2(0,-1.044)
L7066-1830-UH119
  rect 3.505x2.667 smd: 1(0,2.653) 2(0,-2.653)
L7366-1930H158
  rect 3.505x2.819 smd: 1(0,2.729) 2(0,-2.729)
L125100-4P-4H24
  rect 0.635x0.432 smd: 1(-0.562,0.341) 2(0.562,0.341) 3(0.562,-0.341) 4(-0.562,-0.341)
L125100-4P-4H28
  rect 0.635x0.432 smd: 1(-0.562,0.341) 2(0.562,0.341) 3(0.562,-0.341) 4(-0.562,-0.341)
L686647-127318H119
  rect 3.683x2.159 smd: 1(0,2.859) 2(0,-2.859)
LED3020-3P-19H44
  rect 1.499x0.991 smd: 1(0,1.5) 3(0,-1.5)
  rect 0.889x0.889 smd: 2(0.65,0)
LGA12G2H40
  rect 0.381x0.381 smd: 1(0.809,0.809) 4(-0.809,0.809) 7(-0.809,-0.809) 10(0.809,-0.809)
  rect 0.305x0.432 smd: 2(0.25,0.784) 3(-0.25,0.784) 8(-0.25,-0.784) 9(0.25,-0.784)
  rect 0.432x0.305 smd: 5(-0.784,0.25) 6(-0.784,-0.25) 11(0.784,-0.25) 12(0.784,0.25)
MSOP8-1H44
  rect 0.356x1.397 smd: 1(-0.975,-1.991) 2(-0.325,-1.991) 3(0.325,-1.991) 4(0.975,-1.991) 5(0.975,1.991) 6(0.325,1.991) 7(-0.325,1.991) 8(-0.975,1.991)
NTC-402H22-U
  custom 0.127x0.127 smd: 1(0,0.432) 2(0,-0.432)
NTC-402H24-U
  custom 0.127x0.127 smd: 1(0,0.432) 2(0,-0.432)
NTC-603H38
  rect 0.914x0.787 smd: 1(0,0.66) 2(0,-0.66)
OSC-3225-4P-3H36
  rect 1.27x0.914 smd: 1(-1.108,-0.825) 2(1.108,-0.825) 3(1.108,0.825) 4(-1.108,0.825)
OSC-3225-4P-4H36
  rect 1.397x1.067 smd: 1(-1.171,-0.756) 2(1.171,-0.756) 3(1.171,0.756) 4(-1.171,0.756)
PAD-SKT-NGFF75P-U
  round 0.254 hole 1.168 unplated: (-10,0)
  round 0.254 hole 1.651 unplated: (10,0)
  rect 0.305x1.346 smd: 1(-9.25,5.173) 2(-9,-2.173) 3(-8.75,5.173) 4(-8.5,-2.173) 5(-8.25,5.173) 6(-8,-2.173) 7(-7.75,5.173) 8(-7.5,-2.173) 9(-7.25,5.173) 10(-7,-2.173) 11(-6.75,5.173) 12(-6.5,-2.173) 13(-6.25,5.173) 14(-6,-2.173) 15(-5.75,5.173) 16(-5.5,-2.173) 17(-5.25,5.173) 18(-5,-2.173) 19(-4.75,5.173) 20(-4.5,-2.173) 21(-4.25,5.173) 22(-4,-2.173) 23(-3.75,5.173) 24(-3.5,-2.173) 25(-3.25,5.173) 26(-3,-2.173) 27(-2.75,5.173) 28(-2.5,-2.173) 29(-2.25,5.173) 30(-2,-2.173) 31(-1.75,5.173) 32(-1.5,-2.173) 33(-1.25,5.173) 34(-1,-2.173) 35(-0.75,5.173) 36(-0.5,-2.173) 37(-0.25,5.173) 38(0,-2.173) 39(0.25,5.173) 40(0.5,-2.173) 41(0.75,5.173) 42(1,-2.173) 43(1.25,5.173) 44(1.5,-2.173) 45(1.75,5.173) 46(2,-2.173) 47(2.25,5.173) 48(2.5,-2.173) 49(2.75,5.173) 50(3,-2.173) 51(3.25,5.173) 52(3.5,-2.173) 53(3.75,5.173) 54(4,-2.173) 55(4.25,5.173) 56(4.5,-2.173) 57(4.75,5.173) 58(5,-2.173) 59(5.25,5.173) 60(5.5,-2.173) 61(5.75,5.173) 62(6,-2.173) 63(6.25,5.173) 64(6.5,-2.173) 65(6.75,5.173) 66(7,-2.173) 67(7.25,5.173) 68(7.5,-2.173) 69(7.75,5.173) 70(8,-2.173) 71(8.25,5.173) 72(8.5,-2.173) 73(8.75,5.173) 74(9,-2.173) 75(9.25,5.173)
  rect 1.194x2.743 smd: 76(-10.35,4.5) 77(10.35,4.5)
POLYSW-2114H30
  rect 1.6x0.889 smd: 1(0,0.865) 2(0,-0.865)
POLYSW-4633-UH43
  rect 3.505x1.626 smd: 1(0,1.834) 2(0,-1.834)
PPAK-8P-3232H36
  rect 0.406x0.66 smd: 1(-0.975,-2.142) 2(-0.325,-2.142) 3(0.325,-2.142) 4(0.975,-2.142)
  rect 3.353x2.438 smd: 5(0,0)
  rect 0.025x0.025 smd: 6(0.65,0.838) 7(0,0.838) 8(-0.65,0.838)
PPAK-8P-G5324H44-COLAY
  rect 0.762x0.889 smd: 1(-1.905,-2.946) 2(-0.635,-2.946) 3(0.635,-2.946) 4(1.905,-2.946) 5(1.905,2.946) 6(0.635,2.946) 7(-0.635,2.946) 8(-1.905,2.946)
  rect 5.207x2.896 smd: 9(0,0.65)
  rect 5.207x0.787 smd: 10(0,-1.7)
PPAK-8PH48
  rect 0.762x1.194 smd: 1(-1.905,-3.556) 2(-0.635,-3.556) 3(0.635,-3.556) 4(1.905,-3.556)
  rect 5.283x4.902 smd: 5(0,0)
  rect 0.025x0.025 smd: 6(0.635,2.032) 7(-0.635,2.032) 8(-1.905,2.032)
QFN20-G1D75H32
  rect 0.203x0.66 smd: 1(0.8,1.487) 2(0.4,1.487) 3(0,1.487) 4(-0.4,1.487) 5(-0.8,1.487) 11(-0.8,-1.487) 12(-0.4,-1.487) 13(0,-1.487) 14(0.4,-1.487) 15(0.8,-1.487)
  rect 0.66x0.203 smd: 6(-1.487,0.8) 7(-1.487,0.4) 8(-1.487,0) 9(-1.487,-0.4) 10(-1.487,-0.8) 16(1.487,-0.8) 17(1.487,-0.4) 18(1.487,0) 19(1.487,0.4) 20(1.487,0.8)
  rect 1.753x1.753 smd: 21(0,0)
QFN20Z3-G1D1H36
  custom 0.064x0.064 smd: 1(0.9,1.297) 5(-0.9,1.297) 6(-1.297,0.9) 10(-1.297,-0.9) 11(-0.9,-1.297) 15(0.9,-1.297) 16(1.297,-0.9) 20(1.297,0.9)
  rect 0.254x0.914 smd: 2(0.45,1.297) 3(0,1.297) 4(-0.45,1.297) 12(-0.45,-1.297) 13(0,-1.297) 14(0.45,-1.297)
  rect 0.914x0.254 smd: 7(-1.297,0.45) 8(-1.297,0) 9(-1.297,-0.45) 17(1.297,-0.45) 18(1.297,0) 19(1.297,0.45)
  rect 1.092x1.092 smd: 21(0,0)
QFN22G4-G2PH42
  rect 0.305x0.66 smd: 1(1.25,1.924) 2(0.75,1.924) 3(0.25,1.924) 4(-0.25,1.924) 5(-0.75,1.924) 6(-1.25,1.924) 16(0.75,-1.924) 17(1.25,-1.924)
  custom 0.326x0.326 smd: 7(-1.924,1.25)
  rect 0.025x0.025 smd: 8(-1.924,0.75) 9(-1.924,0.25) 10(-1.924,-0.75) 13(-0.75,-1.924) 14(-0.25,-1.924) 15(0.25,-1.924)
  custom 0.232x0.232 smd: 11(-1.924,-1.25)
  custom 0.165x0.165 smd: 12(-1.25,-1.924)
  rect 0.66x0.305 smd: 18(1.924,-1.25) 19(1.924,-0.75) 20(1.924,-0.25) 21(1.924,0.25) 22(1.924,1.25)
QFN32G5-G3D6H32
  rect 0.305x0.66 smd: 1(1.75,2.487) 8(-1.75,2.487) 17(-1.75,-2.487) 24(1.75,-2.487)
  rect 0.305x0.737 smd: 2(1.25,2.449) 3(0.75,2.449) 4(0.25,2.449) 5(-0.25,2.449) 6(-0.75,2.449) 7(-1.25,2.449) 18(-1.25,-2.449) 19(-0.75,-2.449) 20(-0.25,-2.449) 21(0.25,-2.449) 22(0.75,-2.449) 23(1.25,-2.449)
  rect 0.66x0.305 smd: 9(-2.487,1.75) 16(-2.487,-1.75) 25(2.487,-1.75) 32(2.487,1.75)
  rect 0.737x0.305 smd: 10(-2.449,1.25) 11(-2.449,0.75) 12(-2.449,0.25) 13(-2.449,-0.25) 14(-2.449,-0.75) 15(-2.449,-1.25) 26(2.449,-1.25) 27(2.449,-0.75) 28(2.449,-0.25) 29(2.449,0.25) 30(2.449,0.75) 31(2.449,1.25)
  rect 3.607x3.607 smd: 33(0,0)
QFN32J4-G2D7H42
  custom 0.051x0.051 smd: 1(1.4,1.911) 8(-1.4,1.911) 9(-1.911,1.4) 16(-1.911,-1.4) 17(-1.4,-1.911) 24(1.4,-1.911) 25(1.911,-1.4) 32(1.911,1.4)
  rect 0.203x0.686 smd: 2(1,1.911) 3(0.6,1.911) 4(0.2,1.911) 5(-0.2,1.911) 6(-0.6,1.911) 7(-1,1.911) 18(-1,-1.911) 19(-0.6,-1.911) 20(-0.2,-1.911) 21(0.2,-1.911) 22(0.6,-1.911) 23(1,-1.911)
  rect 0.686x0.203 smd: 10(-1.911,1) 11(-1.911,0.6) 12(-1.911,0.2) 13(-1.911,-0.2) 14(-1.911,-0.6) 15(-1.911,-1) 26(1.911,-1) 27(1.911,-0.6) 28(1.911,-0.2) 29(1.911,0.2) 30(1.911,0.6) 31(1.911,1)
  rect 2.692x2.692 smd: 33(0,0)
QFN32J4-G2D85H36
  rect 0.203x0.61 smd: 1(1.4,1.958) 2(1,1.958) 3(0.6,1.958) 4(0.2,1.958) 5(-0.2,1.958) 6(-0.6,1.958) 7(-1,1.958) 8(-1.4,1.958) 17(-1.4,-1.958) 18(-1,-1.958) 19(-0.6,-1.958) 20(-0.2,-1.958) 21(0.2,-1.958) 22(0.6,-1.958) 23(1,-1.958) 24(1.4,-1.958)
  rect 0.61x0.203 smd: 9(-1.958,1.4) 10(-1.958,1) 11(-1.958,0.6) 12(-1.958,0.2) 13(-1.958,-0.2) 14(-1.958,-0.6) 15(-1.958,-1) 16(-1.958,-1.4) 25(1.958,-1.4) 26(1.958,-1) 27(1.958,-0.6) 28(1.958,-0.2) 29(1.958,0.2) 30(1.958,0.6) 31(1.958,1) 32(1.958,1.4)
  rect 2.845x2.845 smd: 33(0,0)
QFN40-G3D5H32
  rect 0.203x0.66 smd: 1(1.8,2.4) 10(-1.8,2.4) 21(-1.8,-2.4) 30(1.8,-2.4)
  rect 0.203x0.711 smd: 2(1.4,2.4) 3(1,2.4) 4(0.6,2.4) 5(0.2,2.4) 6(-0.2,2.4) 7(-0.6,2.4) 8(-1,2.4) 9(-1.4,2.4) 22(-1.4,-2.4) 23(-1,-2.4) 24(-0.6,-2.4) 25(-0.2,-2.4) 26(0.2,-2.4) 27(0.6,-2.4) 28(1,-2.4) 29(1.4,-2.4)
  rect 0.66x0.203 smd: 11(-2.4,1.8) 20(-2.4,-1.8) 31(2.4,-1.8) 40(2.4,1.8)
  rect 0.711x0.203 smd: 12(-2.4,1.4) 13(-2.4,1) 14(-2.4,0.6) 15(-2.4,0.2) 16(-2.4,-0.2) 17(-2.4,-0.6) 18(-2.4,-1) 19(-2.4,-1.4) 32(2.4,-1.4) 33(2.4,-1) 34(2.4,-0.6) 35(2.4,-0.2) 36(2.4,0.2) 37(2.4,0.6) 38(2.4,1) 39(2.4,1.4)
  rect 3.505x3.505 smd: 41(0,0)
QFN40J5-G3D6-DIFF-H34
  rect 0.203x0.66 smd: 1(1.8,2.388) 10(-1.8,2.388) 21(-1.8,-2.388) 30(1.8,-2.388)
  rect 0.203x0.737 smd: 2(1.4,2.388) 3(1,2.388) 4(0.6,2.388) 5(0.2,2.388) 6(-0.2,2.388) 7(-0.6,2.388) 8(-1,2.388) 9(-1.4,2.388) 22(-1.4,-2.388) 23(-1,-2.388) 24(-0.6,-2.388) 25(-0.2,-2.388) 26(0.2,-2.388) 27(0.6,-2.388) 28(1,-2.388) 29(1.4,-2.388)
  rect 0.66x0.203 smd: 11(-2.388,1.8) 20(-2.388,-1.8) 31(2.388,-1.8) 40(2.388,1.8)
  rect 0.737x0.203 smd: 12(-2.388,1.4) 13(-2.388,1) 14(-2.388,0.6) 15(-2.388,0.2) 16(-2.388,-0.2) 17(-2.388,-0.6) 18(-2.388,-1) 19(-2.388,-1.4) 32(2.388,-1.4) 33(2.388,-1) 34(2.388,-0.6) 35(2.388,-0.2) 36(2.388,0.2) 37(2.388,0.6) 38(2.388,1) 39(2.388,1.4)
  rect 3.607x3.607 smd: 41(0,0)
QFN40J5-G3D75H36
  rect 0.203x0.66 smd: 1(1.8,2.489) 2(1.4,2.489) 3(1,2.489) 4(0.6,2.489) 5(0.2,2.489) 6(-0.2,2.489) 7(-0.6,2.489) 8(-1,2.489) 9(-1.4,2.489) 10(-1.8,2.489) 21(-1.8,-2.489) 22(-1.4,-2.489) 23(-1,-2.489) 24(-0.6,-2.489) 25(-0.2,-2.489) 26(0.2,-2.489) 27(0.6,-2.489) 28(1,-2.489) 29(1.4,-2.489) 30(1.8,-2.489)
  rect 0.66x0.203 smd: 11(-2.489,1.8) 12(-2.489,1.4) 13(-2.489,1) 14(-2.489,0.6) 15(-2.489,0.2) 16(-2.489,-0.2) 17(-2.489,-0.6) 18(-2.489,-1) 19(-2.489,-1.4) 20(-2.489,-1.8) 31(2.489,-1.8) 32(2.489,-1.4) 33(2.489,-1) 34(2.489,-0.6) 35(2.489,-0.2) 36(2.489,0.2) 37(2.489,0.6) 38(2.489,1) 39(2.489,1.4) 40(2.489,1.8)
  rect 3.759x3.759 smd: 41(0,0)
R402H15
  custom 0.127x0.127 smd: 1(0,0.432) 2(0,-0.432)
R402H16
  custom 0.127x0.127 smd: 1(0,0.432) 2(0,-0.432)
R603H22
  custom 0.197x0.197 smd: 1(0,0.66) 2(0,-0.66)
R603H24
  custom 0.197x0.197 smd: 1(0,0.66) 2(0,-0.66)
R805H20
  rect 1.549x0.94 smd: 1(0,0.838) 2(0,-0.838)
R805H24
  rect 1.549x0.94 smd: 1(0,0.838) 2(0,-0.838)
R1206H28
  rect 1.854x1.016 smd: 1(0,1.346) 2(0,-1.346)
R3720H40
  rect 4.013x1.041 smd: 1(0,0.867) 2(0,-0.867)
SC70-2D2-312H44
  custom 0.152x0.152 smd: 1(-0.65,-0.864) 2(0.65,-0.864) 3(0,0.864)
SE361414H178
  rect 1.372x3.277 smd: 1(0,2.343) 2(0,-2.343)
SKT-HDMI23-188137-5
  oval 0.787x0.94 hole 0.533: 1(-4.5,5.75) 2(-4,7.25) 3(-3.5,5.75) 4(-3,7.25) 5(-2.5,5.75) 6(-2,7.25) 7(-1.5,5.75) 8(-1,7.25) 9(-0.5,5.75) 10(0,7.25) 11(0.5,5.75) 12(1,7.25) 13(1.5,5.75) 14(2,7.25) 15(2.5,5.75) 16(3,7.25) 17(3.5,5.75) 18(4,7.25) 19(4.5,5.75)
  oval 1.626x2.515 hole 0.914x1.803: 20(-7.25,6.5) 21(7.25,6.5) 22(-9.15,0) 23(9.15,0)
SKT-USB13-157164-1
  round 1.067 hole 0.711: 1(3.5,9.41) 2(1,9.41) 3(-1,9.41) 4(-3.5,9.41) 5(-4,7.91) 6(-2,7.91) 7(0,7.91) 8(2,7.91) 9(4,7.91)
  oval 1.321x3.2 hole 0.711x2.489: 10(7.7,7.43) 11(-7.7,7.43)
  oval 1.321x2.819 hole 0.711x2.108: 12(7.7,0) 13(-7.7,0)
SLP2510P8-3H26
  rect 0.305x0.762 smd: 1(-1,-0.5) 5(1,-0.5) 6(1,0.5) 10(-1,0.5)
  rect 0.203x0.762 smd: 2(-0.5,-0.5) 4(0.5,-0.5) 7(0.5,0.5) 9(-0.5,0.5)
  rect 0.406x1.753 smd: 3(0,-0.449)
  rect 0.025x0.025 smd: 8(0,0.449)
SMD49-3215-0713H36
  rect 1.549x1.295 smd: 1(0,1.244) 2(0,-1.244)
SMD-ARES4H18
  rect 0.356x0.61 smd: 1(-0.325,-0.457) 2(0.325,-0.457) 3(0.325,0.457) 4(-0.325,0.457)
SMD-ARES4H20
  rect 0.356x0.61 smd: 1(-0.325,-0.457) 2(0.325,-0.457) 3(0.325,0.457) 4(-0.325,0.457)
SMD-OSC2H56
  rect 1.194x0.61 smd: 1(-3.147,-0.457) 2(3.147,-0.457) 3(3.147,0.457) 4(-3.147,0.457)
SMD-OSC38H20
  rect 0.965x0.737 smd: 1(-0.706,-0.495) 2(0.706,-0.495) 3(0.706,0.495) 4(-0.706,0.495)
SOD123AK-2H43
  rect 1.143x1.245 smd: A(0,1.631) K(0,-1.631)
SOD323-2513AKH36
  rect 0.559x1.041 smd: A(0,0.987) K(0,-0.987)
SOD323AKH38
  rect 0.559x0.813 smd: A(0,1.1) K(0,-1.1)
SOD882-10D6-1H20
  rect 0.61x0.457 smd: 1(0,0.457) 2(0,-0.457)
SOIC8-1H86
  rect 0.635x1.524 smd: 1(-1.905,-3.442) 2(-0.635,-3.442) 3(0.635,-3.442) 4(1.905,-3.442) 5(1.905,3.442) 6(0.635,3.442) 7(-0.635,3.442) 8(-1.905,3.442)
SOIC8-G3530H63
  rect 0.635x1.524 smd: 1(-1.905,-2.492) 2(-0.635,-2.492) 3(0.635,-2.492) 4(1.905,-2.492) 5(1.905,2.492) 6(0.635,2.492) 7(-0.635,2.492) 8(-1.905,2.492)
  rect 3.505x2.997 smd: 9(0,0)
SOIC8H69
  rect 0.635x1.524 smd: 1(-1.905,-2.477) 2(-0.635,-2.477) 3(0.635,-2.477) 4(1.905,-2.477) 5(1.905,2.477) 6(0.635,2.477) 7(-0.635,2.477) 8(-1.905,2.477)
SON14J3020-G2610H32
  rect 0.025x0.025 smd: 1(1.2,0.978) 6(-0.8,0.978) 9(-0.8,-0.978) 14(1.2,-0.978)
  custom 0.14x0.14 smd: 2(0.8,0.978) 7(-1.2,0.978) 8(-1.2,-0.978) 13(0.8,-0.978)
  rect 0.203x0.559 smd: 3(0.4,0.978) 4(0,0.978) 5(-0.4,0.978) 10(-0.4,-0.978) 11(0,-0.978) 12(0.4,-0.978)
  rect 2.591x0.889 smd: 15(0,0)
SOT23-2D4-312H44
  custom 0.171x0.171 smd: 1(-0.95,-1.069) 2(0.95,-1.069) 3(0,1.069)
SOT23CBE2D4H44
  custom 0.165x0.165 smd: B(-0.95,-1.073) C(0,1.073) E(0.95,-1.073)
SOT23CBE2D6H62
  custom 0.165x0.165 smd: B(-0.95,-1.016) C(0,1.016) E(0.95,-1.016)
SOT23DGS2D4H44
  custom 0.171x0.171 smd: D(0,1.069) G(-0.95,-1.069) S(0.95,-1.069)
SOT23DGS2D4H48
  custom 0.171x0.171 smd: D(0,1.069) G(-0.95,-1.069) S(0.95,-1.069)
SOT323CBE2D2H40
  custom 0.152x0.152 smd: B(-0.65,-0.864) C(0,0.864) E(0.65,-0.864)
SOT-6H58
  rect 0.61x0.813 smd: 1(-0.95,-1.219) 2(0,-1.219) 3(0.95,-1.219) 4(0.95,1.219) 5(0,1.219) 6(-0.95,1.219)
SOT-23-5H51
  rect 0.686x0.864 smd: 1(-0.953,-1.232) 2(0,-1.232) 3(0.953,-1.232) 4(0.953,1.232) 5(-0.953,1.232)
SOT-23-5H56
  rect 0.686x0.864 smd: 1(-0.953,-1.232) 2(0,-1.232) 3(0.953,-1.232) 4(0.953,1.232) 5(-0.953,1.232)
SOT-23-9H44
  custom 0.165x0.165 smd: 1(-0.953,-1.056) 2(0.953,-1.056) 3(0,1.056)
SOT-23-10H44
  custom 0.165x0.165 smd: 1(-0.95,-1.054) 2(0.95,-1.054) 3(0,1.054)
SOT-363H44
  rect 0.356x0.965 smd: 1(-0.65,-0.826) 2(0,-0.826) 3(0.65,-0.826) 4(0.65,0.826) 5(0,0.826) 6(-0.65,0.826)
SPR4527H308
  rect 8.992x3.404 smd: 1(-2.248,0)
SPR5630H142
  rect 5.283x2.692 smd: 1(-2.413,0)
STF237R128H128
  round 6.02 hole 3.251: 1(0,0)
TF31HM-6S-0D5H-800
  rect 0.305x1.295 smd: 1(-1.25,3.5) 2(-0.75,3.5) 3(-0.25,3.5) 4(0.25,3.5) 5(0.75,3.5) 6(1.25,3.5)
  rect 1.295x1.6 smd: 7(-3.25,0) 8(3.25,0)
TPAD14-OP
  round 0.356 smd: 1(0,0)
TQFP128-2H48
  rect 0.203x1.27 smd: 1(6.2,7.62) 2(5.8,7.62) 3(5.4,7.62) 4(5,7.62) 5(4.6,7.62) 6(4.2,7.62) 7(3.8,7.62) 8(3.4,7.62) 9(3,7.62) 10(2.6,7.62) 11(2.2,7.62) 12(1.8,7.62) 13(1.4,7.62) 14(0.999,7.62) 15(0.599,7.62) 16(0.199,7.62) 17(-0.199,7.62) 18(-0.599,7.62) 19(-0.999,7.62) 20(-1.4,7.62) 21(-1.8,7.62) 22(-2.2,7.62) 23(-2.6,7.62) 24(-3,7.62) 25(-3.4,7.62) 26(-3.8,7.62) 27(-4.2,7.62) 28(-4.6,7.62) 29(-5,7.62) 30(-5.4,7.62) 31(-5.8,7.62) 32(-6.2,7.62) 65(-6.2,-7.62) 66(-5.8,-7.62) 67(-5.4,-7.62) 68(-5,-7.62) 69(-4.6,-7.62) 70(-4.2,-7.62) 71(-3.8,-7.62) 72(-3.4,-7.62) 73(-3,-7.62) 74(-2.6,-7.62) 75(-2.2,-7.62) 76(-1.8,-7.62) 77(-1.4,-7.62) 78(-0.999,-7.62) 79(-0.599,-7.62) 80(-0.199,-7.62) 81(0.199,-7.62) 82(0.599,-7.62) 83(0.999,-7.62) 84(1.4,-7.62) 85(1.8,-7.62) 86(2.2,-7.62) 87(2.6,-7.62) 88(3,-7.62) 89(3.4,-7.62) 90(3.8,-7.62) 91(4.2,-7.62) 92(4.6,-7.62) 93(5,-7.62) 94(5.4,-7.62) 95(5.8,-7.62) 96(6.2,-7.62)
  rect 1.27x0.203 smd: 33(-7.62,6.2) 34(-7.62,5.8) 35(-7.62,5.4) 36(-7.62,5) 37(-7.62,4.6) 38(-7.62,4.2) 39(-7.62,3.8) 40(-7.62,3.4) 41(-7.62,3) 42(-7.62,2.6) 43(-7.62,2.2) 44(-7.62,1.8) 45(-7.62,1.4) 46(-7.62,0.999) 47(-7.62,0.599) 48(-7.62,0.199) 49(-7.62,-0.199) 50(-7.62,-0.599) 51(-7.62,-0.999) 52(-7.62,-1.4) 53(-7.62,-1.8) 54(-7.62,-2.2) 55(-7.62,-2.6) 56(-7.62,-3) 57(-7.62,-3.4) 58(-7.62,-3.8) 59(-7.62,-4.2) 60(-7.62,-4.6) 61(-7.62,-5) 62(-7.62,-5.4) 63(-7.62,-5.8) 64(-7.62,-6.2) 97(7.62,-6.2) 98(7.62,-5.8) 99(7.62,-5.4) 100(7.62,-5) 101(7.62,-4.6) 102(7.62,-4.2) 103(7.62,-3.8) 104(7.62,-3.4) 105(7.62,-3) 106(7.62,-2.6) 107(7.62,-2.2) 108(7.62,-1.8) 109(7.62,-1.4) 110(7.62,-0.999) 111(7.62,-0.599) 112(7.62,-0.199) 113(7.62,0.199) 114(7.62,0.599) 115(7.62,0.999) 116(7.62,1.4) 117(7.62,1.8) 118(7.62,2.2) 119(7.62,2.6) 120(7.62,3) 121(7.62,3.4) 122(7.62,3.8) 123(7.62,4.2) 124(7.62,4.6) 125(7.62,5) 126(7.62,5.4) 127(7.62,5.8) 128(7.62,6.2)
unnamed#2
  round 1.016 smd: (0,0)
XFORM12A127097H91
  rect 0.635x1.143 smd: 1(-4.445,-4.508) 2(-3.175,-4.508) 3(-1.905,-4.508) 4(1.905,-4.508) 5(3.175,-4.508) 6(4.445,-4.508) 7(4.445,4.508) 8(3.175,4.508) 9(1.905,4.508) 10(-1.905,4.508) 11(-3.175,4.508) 12(-4.445,4.508)

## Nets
1.8V_RUN_FB: PC5405.2 PR5403.2 PR5404.1 PU5401.2
3.3V_ALW_1: PC8601.2 PC8603.2 PQ8604.5 PQ8604.6 PQ8609.G PR8606.2 PR8619.2
3.3V_RUN_VGA_1: D8601.3 D8602.3 PQ8604.3 PR8609.2
3V5V_CT1: C4001.1 U4001.12
3V5V_CT2: C4002.1 U4001.10
3V5V_S0_ON: R4010.2 U4001.3 U4001.5
3V_5V_DSW_OK: D2101.3 R2114.2 R2115.2 U2101.1
3V_5V_EN: C4009.1 D4001.1 PR4503.1 PR4504.2 R4006.1 R4009.1 R4012.1
3V_5V_POK: D2101.1 EC1705.1 PR4534.2 PR5306.1 PR5406.1 PU4503.7 R1728.2 R2114.1 R4033.1
3V_5V_POK#: Q1701.5 Q1701.6 R1726.2
3V_5V_POK_C: Q1701.2 R1727.2 R1728.1
3V_FEEDBACK: PG4535.2 PR4512.1 PR4535.1
5V_CRT_S0_R: AFTP5604.1 C5623.2 D5604.K RN5601.3(B) RN5601.4(B) VGA1.9
5V_HDD_S0: AFTP6001.1 C6007.1 C6008.1 HDD1.2 HDD1.3 HDD1.4 R6001.2
5V_HDMI_S0: C5702.1 D5604.A F5701.2 HDMI1.18 R5718.2
5V_PWR: PC4518.1 PG4519.2 PG4523.2 PG4527.2 PG4532.1 PG4533.2 PG4537.2 PG4538.2 PG4540.2 PG4541.2 PG4544.2 PG4545.2 PL4501.2 PT4501.1
5V_PWR_2: PC4524.1 PU4503.13
5V_S0: C2605.1 C2611.1 C4005.1 C5602.1 C5629.1 C6001.1 C6002.1 D5701.3 EC9718.1 EC9719.1 EC9720.1 EC9721.1 EC9722.1 EC9723.1 EC9724.1 F5701.1 FAN261.2 FC9704.1 Q5701.G Q6502.E R2701.1 R2703.2 R2707.1 R5527.1 R5718.1 R5719.1 R6001.1 R6003.1 R6512.1 R6705.1 U4001.13 U4001.14 U5601.17
5V_S5: C3504.1 C3510.1 C4028.1 C4029.1 EC9732.1 EC9733.1 EC9734.1 PC5001.1 PC5156.1 PC5302.1 PC5401.1 PC8508.1 PG4519.1 PG4523.1 PG4527.1 PG4533.1 PG4537.1 PG4538.1 PG4540.1 PG4541.1 PG4544.1 PG4545.1 PR4303.2 PR4610.1 PR4635.1 PR4704.1 PR4803.1 PR4813.1 PR5107.2 PR5109.2 PR5308.1 PR8510.1 PU5001.6 PU5151.6 PU5301.21 PU5401.6 PU8501.26 PU8501.31 Q6403.E Q6404.E U3501.5 U3503.5 U4001.1 U4001.2 U4001.4 U4002.3 U4006.3
+3V_1D8V_AVDD: C2710.1 HDA27.33 R2719.2
+3V_1D8V_DVDD: C2720.1 C2721.1 C2723.1 C2740.1 C2741.1 HDA27.1 HDA27.8 R2710.1 R2715.2 R2717.1
+5V_AVDD: C2706.1 C2707.1 HDA27.20 R2703.1
+5V_PVDD: R2701.2 R2707.2 R2713.1 R2714.1
+5V_PVDD1: C2713.1 C2714.1 C2717.1 C2718.1 HDA27.34 HDA27.39 R2713.2 R2714.2
+V1.00A_SIP: C1108.1 C2101.1 C2104.1 C2116.1 C2121.1 C2122.1 CPU1.A10 CPU1.A14 CPU1.AB17 CPU1.AB19 CPU1.AB20 CPU1.AK20 CPU1.K17 CPU1.K19 CPU1.L1 CPU1.L19 CPU1.L21 CPU1.N20 CPU1.P18 CPU1.T1 CPU1.Y18 R1117.2 R1803.2 R2108.1
+V1.00U_CPU: C720.1 C721.1 C4012.1 CPU1.K20 CPU1.K21 R4025.2 R4036.1
+V1.00U_CPU_LS: R4025.1 U4006.6 U4006.7 U4006.8
+V1.8A_SIP: C1106.1 C2108.1 CPU1.AA1 CPU1.AF16 CPU1.AK15 R1139.2 R1607.1 R1718.1 R1816.1 R1818.2 R2001.2 R2004.2 R2015.1 R2017.1 R2022.1
+V3.3A_SIP: C1104.1 C1183.1 C2105.1 C2106.1 C2107.1 C2109.1 C2110.1 C2111.1 CPU1.AD15 CPU1.AG15 CPU1.AJ16 CPU1.AJ21 CPU1.AK17 CPU1.T16 CPU1.V19 CPU1.Y15 CPU1.Y16 R1110.2 R1701.1 R2101.1
+VCCAMPHYPLL_1P0: C2113.1 CPU1.K15 CPU1.L15 R2112.2
+VCCAPLL_1P0: C2114.1 CPU1.V15 R2108.2
+VCCDSW_1P0: C2103.1 CPU1.AL1
+VCCFUSEPRG: CPU1.G20 R703.1
+VCCGT: C1136.1 C1138.1 C1147.1 C1148.1 C1149.1 C1150.1 CPU1.A58 CPU1.A62 CPU1.A66 CPU1.AA63 CPU1.AA64 CPU1.AA66 CPU1.AA67 CPU1.AA69 CPU1.AA70 CPU1.AA71 CPU1.AC64 CPU1.AC65 CPU1.AC66 CPU1.AC67 CPU1.AC68 CPU1.AC69 CPU1.AC70 CPU1.AC71 CPU1.J53 CPU1.J55 CPU1.J56 CPU1.J58 CPU1.J60 CPU1.K53 CPU1.K55 CPU1.K56 CPU1.K58 CPU1.K60 CPU1.L62 CPU1.L63 CPU1.L64 CPU1.L65 CPU1.L66 CPU1.L67 CPU1.L68 CPU1.L69 CPU1.L70 CPU1.L71 CPU1.M62 CPU1.N63 CPU1.N64 CPU1.N66 CPU1.N67 CPU1.N69 CPU1.N70 CPU1.N71 CPU1.R63 CPU1.R64 CPU1.R65 CPU1.R66 CPU1.R67 CPU1.R68 CPU1.R69 CPU1.R70 CPU1.R71 CPU1.T62 CPU1.U65 CPU1.U68 CPU1.U71 CPU1.W63 CPU1.W64 CPU1.W65 CPU1.W66 CPU1.W67 CPU1.W68 CPU1.W69 CPU1.W70 CPU1.W71 CPU1.Y62 FC9706.1 FC9707.1 FC9708.1 PC1031.1 PC1032.1 PC1033.1 PC1034.1 PC1041.1 PC1042.1 PC1043.1 PC1044.1 PC1053.1 PC1065.1 PC1069.1 PC1070.1 PC1071.1 PC1072.1 PC1073.1 PC1074.1 PC1075.1 PC1076.1 PC1077.1 PC1078.1 PC1079.1 PC1080.1 PC1081.1 PC1082.1 PC1083.1 PC1084.1 PC1085.1 PC1086.1 PC1087.1 PC1088.1 PC1089.1 PC1090.1 PC1091.1 PC1092.1 PC1093.1 PC1094.1 PC1095.1 PC1096.1 PG4708.2 PL4701.2 PR4663.2 PT4701.1 R712.1 R719.2 R721.1
+VCCIO: C1151.1 C1152.1 C1153.1 C1154.1 C4007.1 CPU1.AK28 CPU1.AK30 CPU1.AL30 CPU1.AL42 CPU1.AM28 CPU1.AM30 CPU1.AM42 PC1035.1 PC1036.1 PC1037.1 R801.1 R4048.1 U4002.6 U4002.7 U4002.8
+VCCMPHYGTAON_1P0_LS_SIP: C1172.1 C1173.1 C1174.1 C1175.1 C1176.1 C1180.1 C1182.1 C1184.1 C1704.1 CPU1.AF20 CPU1.AF21 CPU1.N15 CPU1.N16 CPU1.N17 CPU1.N18 CPU1.P15 CPU1.P16 CPU1.T19 CPU1.T20 R1724.2 R1735.2 R2112.1
+VCCPAZIO: CPU1.AJ19 R2101.2
+VCCPDSW_3P3: CPU1.AD17 CPU1.AD18 CPU1.AJ17 R1707.1 R1711.2
+VCCPRIM_CORE: C2120.1 CPU1.AF18 CPU1.AF19 CPU1.V20 CPU1.V21 EC2101.1 PC1105.1 PC1106.1 R1101.2
+VCCPRTC_3P3: CPU1.AK19 CPU1.BB14 R2107.2
+VCCSA: CPU1.AK23 CPU1.AK25 CPU1.G23 CPU1.G25 CPU1.G27 CPU1.G28 CPU1.J22 CPU1.J23 CPU1.J27 CPU1.K23 CPU1.K25 CPU1.K27 CPU1.K28 CPU1.K30 PC1045.1 PC1046.1 PC1047.1 PC1048.1 PC1049.1 PC1050.1 PC1051.1 PC1052.1 PC1054.1 PC1098.1 PG5001.2 PL5001.2 R716.2
+VCCST_CPU: C716.1 CPU1.A18 PC4602.1 PR4603.1 PR4604.1 PR4605.1 PR4606.1 R419.1 R603.2 R723.1 R726.1 R727.1 R4036.2
+VCCSTG: C717.1 CPU1.A22 R401.1 R408.2 R409.2 R416.2 R417.2 R421.2 R422.2 R423.2 R703.2 R1722.1 R4048.2
+VDDQ_CPU_CLK: C715.1 C722.1 CPU1.AM40 R705.2
AV1_TP: CPU1.AV1 TP2310.1
AV71_TP: CPU1.AV71 TP2304.1
AVCC33: C5606.1 C5621.2 R5610.2 U5601.1
DVSS: HDA27.10 R2716.2
GND: AFTP2501.1 AFTP2601.1 AFTP3604.1 AFTP3608.1 AFTP4309.1 AFTP4310.1 AFTP4311.1 AFTP6403.1 AFTP6531.1 AFTP6537.1 AFTP6612.1 BATT1.7 BATT1.8 BATT1.9 BATT1.10 C715.2 C716.2 C717.2 C718.2 C719.2 C720.2 C721.2 C722.2 C1101.2 C1102.2 C1103.2 C1104.2 C1106.2 C1108.2 C1116.2 C1117.2 C1136.2 C1138.2 C1147.2 C1148.2 C1149.2 C1150.2 C1151.2 C1152.2 C1153.2 C1154.2 C1172.2 C1173.2 C1174.2 C1175.2 C1176.2 C1180.2 C1182.2 C1183.2 C1184.2 C1201.2 C1202.2 C1203.2 C1204.2 C1205.2 C1206.2 C1207.2 C1208.2 C1209.2 C1210.2 C1211.2 C1212.2 C1213.2 C1214.2 C1215.2 C1216.2 C1217.2 C1218.2 C1219.2 C1220.2 C1221.2 C1223.2 C1224.2 C1225.2 C1226.2 C1227.2 C1228.2 C1229.2 C1230.2 C1231.2 C1232.2 C1301.2 C1303.2 C1304.2 C1305.2 C1306.2 C1307.2 C1308.2 C1309.2 C1310.2 C1311.2 C1312.2 C1313.2 C1314.2 C1315.2 C1316.2 C1317.2 C1318.2 C1319.2 C1320.2 C1321.2 C1322.2 C1324.2 C1325.2 C1326.2 C1327.2 C1328.2 C1329.2 C1330.2 C1331.2 C1701.2 C1704.2 C1801.2 C1802.2 C1803.2 C1804.2 C1901.2 C1902.2 C2101.2 C2103.2 C2104.2 C2105.2 C2106.2 C2107.2 C2108.2 C2109.2 C2110.2 C2111.2 C2112.2 C2113.2 C2114.2 C2116.2 C2117.2 C2118.2 C2119.2 C2120.2 C2121.2 C2122.2 C2123.2 C2125.2 C2201.2 C2202.2 C2401.2 C2403.2 C2405.2 C2406.2 C2409.2 C2410.2 C2411.2 C2412.2 C2413.2 C2414.2 C2415.2 C2416.2 C2417.2 C2418.2 C2419.2 C2420.2 C2421.2 C2423.2 C2424.2 C2425.2 C2426.2 C2428.2 C2429.2 C2501.2 C2502.2 C2503.2 C2603.2 C2604.2 C2605.2 C2610.2 C2611.2 C2615.2 C2616.2 C2617.2 C2618.2 C2704.2 C2705.2 C2709.1 C2713.2 C2714.2 C2717.2 C2718.2 C2720.2 C2721.2 C2722.2 C2723.2 C2725.2 C2736.2 C2737.2 C2739.2 C2740.2 C2741.2 C3103.2 C3104.2 C3108.2 C3109.2 C3110.2 C3111.2 C3112.2 C3113.2 C3114.2 C3115.2 C3116.2 C3117.2 C3118.2 C3119.2 C3120.2 C3121.2 C3122.2 C3123.2 C3124.2 C3125.2 C3201.2 C3202.2 C3504.2 C3507.2 C3508.2 C3510.2 C3512.2 C3513.2 C3515.2 C3517.2 C3518.2 C3618.2 C3706.2 C4001.2 C4002.2 C4004.2 C4005.2 C4007.2 C4009.2 C4012.2 C4013.2 C4016.2 C4017.2 C4018.2 C4028.2 C4029.2 C5501.2 C5505.2 C5506.2 C5515.2 C5535.2 C5536.2 C5538.2 C5539.2 C5540.2 C5541.2 C5543.2 C5602.2 C5606.2 C5607.2 C5608.2 C5609.2 C5610.2 C5611.2 C5612.2 C5613.2 C5614.2 C5615.2 C5616.2 C5617.2 C5618.2 C5619.2 C5620.2 C5621.1 C5622.2 C5623.1 C5626.2 C5627.2 C5628.2 C5629.2 C5702.2 C6001.2 C6002.2 C6007.2 C6008.2 C6009.2 C6018.2 C6101.2 C6102.2 C6103.2 C6104.2 C6105.2 C6106.2 C6316.2 C6317.2 C6318.2 C6319.2 C6320.2 C6401.2 C6504.2 C6701.2 C6702.2 C6703.2 C7609.2 C7710.2 C7711.2 C7713.2 C7714.2 C7715.2 C7801.2 C7802.2 C7803.2 C7805.2 C7901.2 C7903.2 C7904.2 C7918.2 C7919.2 C7920.2 C7921.2 C8001.2 C8002.2 C8003.2 C8004.2 C8005.2 C8006.2 C8007.2 C8008.2 C8009.2 C8010.2 C8011.2 C8012.2 C8013.2 C8014.2 C8015.2 C8016.2 C8017.2 C8018.2 C8019.2 C8020.2 C8021.2 C8022.2 C8023.2 C8024.2 C8025.2 C8026.2 C8027.2 C8028.2 C8029.2 C8030.2 C8031.2 C8032.2 C8033.2 C8034.2 C8035.2 C8036.2 C8037.2 C8038.2 C8039.2 C8040.2 C8041.2 C8042.2 C8043.2 C8044.2 C8045.2 C8046.2 C8047.2 C8048.2 C8049.2 C8050.2 C8051.2 C8052.2 C8053.2 C8054.2 C8055.2 C8056.2 C8057.2 C8058.2 C8059.2 C8060.2 C8061.2 C8062.2 C8063.2 C8064.2 C8065.2 C8066.2 C8103.2 C8104.2 C8105.2 C8106.2 C8107.2 C8108.2 C8109.2 C8110.2 C8111.2 C8112.2 C8113.2 C8114.2 C8115.2 C8116.2 C8117.2 C8118.2 C8119.2 C8120.2 C8121.2 C8122.2 C8123.2 C8124.2 C8125.2 C8126.2 C8127.2 C8128.2 C8129.2 C8130.2 C8131.2 C8132.2 C9106.2 C9107.2 C9108.2 C9109.2 C9111.2 C9112.2 C9113.2 C9114.2 C9115.2 C9116.2 C9201.2 C9202.2 CPU1.AA2 CPU1.AA4 CPU1.AA65 CPU1.AA68 CPU1.AB8 CPU1.AB15 CPU1.AB16 CPU1.AB18 CPU1.AB21 CPU1.AD8 CPU1.AD13 CPU1.AD16 CPU1.AD19 CPU1.AD20 CPU1.AD21 CPU1.AD62 CPU1.AE64 CPU1.AE65 CPU1.AE66 CPU1.AE67 CPU1.AE68 CPU1.AE69 CPU1.AF1 CPU1.AF2 CPU1.AF4 CPU1.AF10 CPU1.AF15 CPU1.AF17 CPU1.AF63 CPU1.AG16 CPU1.AG17 CPU1.AG18 CPU1.AG19 CPU1.AG20 CPU1.AG21 CPU1.AG71 CPU1.AH6 CPU1.AH13 CPU1.AH63 CPU1.AH64 CPU1.AH67 CPU1.AJ4 CPU1.AJ15 CPU1.AJ18 CPU1.AJ20 CPU1.AK8 CPU1.AK11 CPU1.AK16 CPU1.AK18 CPU1.AK21 CPU1.AK22 CPU1.AK27 CPU1.AK63 CPU1.AK68 CPU1.AK69 CPU1.AL2 CPU1.AL4 CPU1.AL28 CPU1.AL32 CPU1.AL35 CPU1.AL38 CPU1.AL45 CPU1.AL48 CPU1.AL52 CPU1.AL55 CPU1.AL58 CPU1.AL64 CPU1.AL65 CPU1.AL66 CPU1.AM8 CPU1.AM13 CPU1.AM21 CPU1.AM25 CPU1.AM27 CPU1.AM43 CPU1.AM45 CPU1.AM46 CPU1.AM55 CPU1.AM60 CPU1.AM61 CPU1.AM68 CPU1.AM71 CPU1.AN20 CPU1.AN23 CPU1.AN28 CPU1.AN30 CPU1.AN32 CPU1.AN33 CPU1.AN35 CPU1.AN37 CPU1.AN38 CPU1.AN40 CPU1.AN42 CPU1.AN58 CPU1.AN63 CPU1.AP10 CPU1.AP18 CPU1.AP20 CPU1.AP23 CPU1.AP28 CPU1.AP32 CPU1.AP35 CPU1.AP38 CPU1.AP42 CPU1.AP58 CPU1.AP63 CPU1.AP68 CPU1.AP70 CPU1.AR5 CPU1.AR8 CPU1.AR11 CPU1.AR15 CPU1.AR16 CPU1.AR20 CPU1.AR23 CPU1.AR28 CPU1.AR35 CPU1.AR42 CPU1.AR43 CPU1.AR45 CPU1.AR46 CPU1.AR48 CPU1.AR50 CPU1.AR52 CPU1.AR53 CPU1.AR55 CPU1.AR58 CPU1.AR63 CPU1.AT2 CPU1.AT4 CPU1.AT20 CPU1.AT23 CPU1.AT28 CPU1.AT35 CPU1.AT42 CPU1.AT56 CPU1.AT58 CPU1.AT63 CPU1.AT68 CPU1.AT71 CPU1.AU10 CPU1.AU15 CPU1.AU20 CPU1.AU32 CPU1.AU38 CPU1.AV68 CPU1.AV69 CPU1.AV70 CPU1.AW6 CPU1.AW8 CPU1.AW10 CPU1.AW12 CPU1.AW14 CPU1.AW16 CPU1.AW18 CPU1.AW21 CPU1.AW23 CPU1.AW26 CPU1.AW28 CPU1.AW30 CPU1.AW32 CPU1.AW34 CPU1.AW36 CPU1.AW38 CPU1.AW41 CPU1.AW43 CPU1.AW45 CPU1.AW47 CPU1.AW49 CPU1.AW51 CPU1.AW53 CPU1.AW55 CPU1.AW57 CPU1.AW60 CPU1.AW62 CPU1.AW64 CPU1.AW66 CPU1.AY66 CPU1.B10 CPU1.B14 CPU1.B18 CPU1.B22 CPU1.B30 CPU1.B34 CPU1.B39 CPU1.B44 CPU1.B48 CPU1.B53 CPU1.B58 CPU1.B62 CPU1.B66 CPU1.BA6 CPU1.BA10 CPU1.BA14 CPU1.BA18 CPU1.BA23 CPU1.BA28 CPU1.BA32 CPU1.BA36 CPU1.BA41 CPU1.BA45 CPU1.BA49 CPU1.BA53 CPU1.BA57 CPU1.BA62 CPU1.BA66 CPU1.BB6 CPU1.BB18 CPU1.BB26 CPU1.BB30 CPU1.BB34 CPU1.BB38 CPU1.BB43 CPU1.BB55 CPU1.BB60 CPU1.BB64 CPU1.C5 CPU1.C25 CPU1.D6 CPU1.D10 CPU1.D11 CPU1.D14 CPU1.D18 CPU1.D22 CPU1.D25 CPU1.D26 CPU1.D30 CPU1.D34 CPU1.D39 CPU1.D44 CPU1.D45 CPU1.D47 CPU1.D48 CPU1.D53 CPU1.D58 CPU1.D62 CPU1.D66 CPU1.D69 CPU1.E6 CPU1.E11 CPU1.E15 CPU1.E18 CPU1.E21 CPU1.E46 CPU1.E50 CPU1.E53 CPU1.E56 CPU1.E65 CPU1.F1 CPU1.F2 CPU1.F4 CPU1.F8 CPU1.F13 CPU1.F22 CPU1.F23 CPU1.F27 CPU1.F28 CPU1.F32 CPU1.F33 CPU1.F35 CPU1.F37 CPU1.F38 CPU1.F40 CPU1.F42 CPU1.F68 CPU1.G5 CPU1.G6 CPU1.G10 CPU1.G22 CPU1.G43 CPU1.G45 CPU1.G48 CPU1.G52 CPU1.G55 CPU1.G58 CPU1.G60 CPU1.G63 CPU1.G66 CPU1.H15 CPU1.H18 CPU1.H71 CPU1.J8 CPU1.J11 CPU1.J13 CPU1.J25 CPU1.J28 CPU1.J32 CPU1.J35 CPU1.J38 CPU1.J42 CPU1.K16 CPU1.K18 CPU1.K22 CPU1.K61 CPU1.K63 CPU1.K64 CPU1.K65 CPU1.K66 CPU1.K67 CPU1.K68 CPU1.K70 CPU1.K71 CPU1.L2 CPU1.L4 CPU1.L8 CPU1.L11 CPU1.L16 CPU1.L17 CPU1.L18 CPU1.L20 CPU1.N6 CPU1.N10 CPU1.N13 CPU1.N19 CPU1.N21 CPU1.N65 CPU1.N68 CPU1.P17 CPU1.P19 CPU1.P20 CPU1.P21 CPU1.R6 CPU1.R13 CPU1.T2 CPU1.T4 CPU1.T15 CPU1.T17 CPU1.T18 CPU1.T21 CPU1.U10 CPU1.U63 CPU1.U64 CPU1.U66 CPU1.U67 CPU1.U69 CPU1.U70 CPU1.V16 CPU1.V17 CPU1.V18 CPU1.W6 CPU1.W9 CPU1.W13 CPU1.Y17 CPU1.Y19 CPU1.Y20 CPU1.Y21 D2601.A D4304.1 D4305.1 D4306.1 DB3.4 DB3.7 DB3.8 DBG1.3 DBG1.15 DBG1.16 DCIN1.7 DCIN1.8 DM1.1 DM1.2 DM1.5 DM1.6 DM1.9 DM1.10 DM1.14 DM1.15 DM1.18 DM1.19 DM1.22 DM1.23 DM1.26 DM1.27 DM1.30 DM1.31 DM1.35 DM1.36 DM1.39 DM1.40 DM1.43 DM1.44 DM1.47 DM1.48 DM1.51 DM1.52 DM1.56 DM1.57 DM1.60 DM1.61 DM1.64 DM1.65 DM1.68 DM1.69 DM1.72 DM1.73 DM1.77 DM1.78 DM1.81 DM1.82 DM1.85 DM1.86 DM1.89 DM1.90 DM1.93 DM1.94 DM1.98 DM1.99 DM1.102 DM1.103 DM1.106 DM1.107 DM1.167 DM1.168 DM1.171 DM1.172 DM1.175 DM1.176 DM1.180 DM1.181 DM1.184 DM1.185 DM1.188 DM1.189 DM1.192 DM1.193 DM1.196 DM1.197 DM1.201 DM1.202 DM1.205 DM1.206 DM1.209 DM1.210 DM1.213 DM1.214 DM1.217 DM1.218 DM1.222 DM1.223 DM1.226 DM1.227 DM1.230 DM1.231 DM1.234 DM1.235 DM1.238 DM1.239 DM1.243 DM1.244 DM1.247 DM1.248 DM1.251 DM1.252 DM1.261 DM1.262 DM2.1 DM2.2 DM2.5 DM2.6 DM2.9 DM2.10 DM2.14 DM2.15 DM2.18 DM2.19 DM2.22 DM2.23 DM2.26 DM2.27 DM2.30 DM2.31 DM2.35 DM2.36 DM2.39 DM2.40 DM2.43 DM2.44 DM2.47 DM2.48 DM2.51 DM2.52 DM2.56 DM2.57 DM2.60 DM2.61 DM2.64 DM2.65 DM2.68 DM2.69 DM2.72 DM2.73 DM2.77 DM2.78 DM2.81 DM2.82 DM2.85 DM2.86 DM2.89 DM2.90 DM2.93 DM2.94 DM2.98 DM2.99 DM2.102 DM2.103 DM2.106 DM2.107 DM2.167 DM2.168 DM2.171 DM2.172 DM2.175 DM2.176 DM2.180 DM2.181 DM2.184 DM2.185 DM2.188 DM2.189 DM2.192 DM2.193 DM2.196 DM2.197 DM2.201 DM2.202 DM2.205 DM2.206 DM2.209 DM2.210 DM2.213 DM2.214 DM2.217 DM2.218 DM2.222 DM2.223 DM2.226 DM2.227 DM2.230 DM2.231 DM2.234 DM2.235 DM2.238 DM2.239 DM2.243 DM2.244 DM2.247 DM2.248 DM2.251 DM2.252 DM2.261 DM2.262 EC401.2 EC1702.2 EC1703.2 EC1705.2 EC1706.2 EC1707.2 EC1708.2 EC1709.2 EC1712.2 EC1802.2 EC1805.2 EC1806.2 EC1807.2 EC1808.2 EC1901.1 EC1903.1 EC2002.1 EC2101.2 EC2601.2 EC2602.2 EC2701.2 EC2702.2 EC2703.2 EC2704.2 EC2705.2 EC2709.2 EC2710.2 EC2711.2 EC2901.2 EC2902.2 EC2903.2 EC2904.2 EC4306.2 EC4307.2 EC4308.2 EC4309.2 EC4310.2 EC5501.2 EC5502.2 EC5503.2 EC5504.2 EC6401.2 EC6402.2 EC6403.2 EC6404.2 EC6501.2 EC6502.2 EC6503.2 EC6504.2 EC6505.2 EC6506.2 EC8901.2 EC8902.2 EC8903.2 EC8904.2 EC8905.2 EC8906.2 EC8907.2 EC8908.2 EC8909.2 EC8910.2 EC8911.2 EC8912.2 EC8913.2 EC8914.2 EC8915.2 EC8916.2 EC8917.2 EC8918.2 EC8919.2 EC8920.2 EC8921.2 EC8922.2 EC8923.2 EC8924.2 EC8925.2 EC8926.2 EC8927.2 EC8928.2 EC9201.2 EC9202.2 EC9701.2 EC9702.2 EC9703.2 EC9704.2 EC9705.2 EC9706.2 EC9707.2 EC9708.2 EC9709.2 EC9710.2 EC9711.2 EC9712.2 EC9713.2 EC9714.2 EC9715.2 EC9716.2 EC9717.2 EC9718.2 EC9719.2 EC9720.2 EC9721.2 EC9722.2 EC9723.2 EC9724.2 EC9725.2 EC9726.2 EC9727.2 EC9728.2 EC9729.2 EC9730.2 EC9731.2 EC9732.2 EC9733.2 EC9734.2 EC9735.2 EC9736.2 EC9737.2 EC9738.2 EC9739.2 EC9740.2 EC9741.1 EC9742.2 EC9743.2 EC9744.2 EC9745.2 EC9746.2 EC9747.1 EC9748.2 EC9749.1 EC9750.2 EC9751.2 EC9752.2 EC9753.2 ED502.2 ED1217.2 ED1302.2 ED3201.3 ED3201.8 ED3202.3 ED3202.8 ED3602.3 ED3602.8 ED3603.3 ED3603.8 ED3604.2 ED3704.2 ED5501.2 ED5601.2 ED5602.2 ED5603.2 ED5701.3 ED5701.8 ED5702.3 ED5702.8 ED5703.3 ED5703.8 ED6001.3 ED6001.8 ED6401.2 ED9201.2 EL4303.2 EL4304.2 EU1701.2 FAN1.3 FAN1.4 FAN1.5 FAN261.5 FAN261.6 FAN261.7 FAN261.8 FC1901.2 FC1902.2 FC9702.2 FC9703.2 FC9704.2 FC9706.2 FC9707.2 FC9708.2 FPR1.5 FPR1.6 FPR1.7 FPR1.8 G1901.1 G6401.2 G6402.2 GPU1.A3 GPU1.A30 GPU1.AA11 GPU1.AA13 GPU1.AA16 GPU1.AA27 GPU1.AB6 GPU1.AB10 GPU1.AB15 GPU1.AB24 GPU1.AB32 GPU1.AC9 GPU1.AC17 GPU1.AC24 GPU1.AC26 GPU1.AC27 GPU1.AD6 GPU1.AD8 GPU1.AD25 GPU1.AD32 GPU1.AE7 GPU1.AE14 GPU1.AE27 GPU1.AF32 GPU1.AG12 GPU1.AG27 GPU1.AH10 GPU1.AH28 GPU1.AH32 GPU1.B6 GPU1.B8 GPU1.B10 GPU1.B12 GPU1.B14 GPU1.B16 GPU1.B18 GPU1.B20 GPU1.B22 GPU1.B24 GPU1.B26 GPU1.C1 GPU1.C32 GPU1.E28 GPU1.F2 GPU1.F6 GPU1.F8 GPU1.F10 GPU1.F12 GPU1.F14 GPU1.F16 GPU1.F18 GPU1.F20 GPU1.F22 GPU1.F24 GPU1.F26 GPU1.G8 GPU1.G10 GPU1.G27 GPU1.G31 GPU1.H2 GPU1.H6 GPU1.H14 GPU1.H17 GPU1.H20 GPU1.J7 GPU1.J27 GPU1.J31 GPU1.K2 GPU1.K6 GPU1.K11 GPU1.K22 GPU1.K28 GPU1.K32 GPU1.L27 GPU1.M6 GPU1.M12 GPU1.M32 GPU1.N11 GPU1.N13 GPU1.N16 GPU1.N18 GPU1.N21 GPU1.N25 GPU1.N27 GPU1.P6 GPU1.P9 GPU1.P25 GPU1.P32 GPU1.R11 GPU1.R12 GPU1.R15 GPU1.R17 GPU1.R20 GPU1.R27 GPU1.T6 GPU1.T11 GPU1.T13 GPU1.T16 GPU1.T18 GPU1.T21 GPU1.T25 GPU1.T32 GPU1.U9 GPU1.U15 GPU1.U17 GPU1.U20 GPU1.U25 GPU1.U27 GPU1.V11 GPU1.V13 GPU1.V16 GPU1.V18 GPU1.V32 GPU1.W25 GPU1.W26 GPU1.W27 GPU1.Y10 GPU1.Y15 GPU1.Y17 GPU1.Y20 GPU1.Y25 GPU1.Y32 H1.1 H2.1 H3.1 H4.1 H5.1 H6.1 H7.1 H8.1 H9.1 H10.1 H11.1 H12.1 H13.1 H14.1 H15.1 H16.1 H17.1 HDA27.41 HDD1.6 HDD1.9 HDD1.12 HDD1.13 HDD1.14 HDMI1.2 HDMI1.5 HDMI1.8 HDMI1.11 HDMI1.17 HDMI1.20 HDMI1.21 HDMI1.22 HDMI1.23 HS1.1 IOBD1.1 IOBD1.2 IOBD1.5 IOBD1.8 IOBD1.29 IOBD1.30 IOBD1.31 IOBD1.32 KB1.1 KB1.31 KB1.32 KBC24.17 KBC24.51 KBC24.64 KBC24.84 KBC24.100 KBC24.124 LCD1.13 LCD1.16 LCD1.19 LCD1.23 LCD1.24 LCD1.25 LCD1.29 LCD1.36 LCD1.41 LCD1.42 LCD1.43 LCD1.44 LED1.3 LOM31.33 ODD1.1 ODD1.4 ODD1.7 ODD1.18 ODD1.19 ODD1.20 ODD1.21 ODD1.22 PC1001.2 PC1002.2 PC1003.2 PC1004.2 PC1005.2 PC1006.2 PC1007.2 PC1008.2 PC1009.2 PC1010.2 PC1011.2 PC1012.2 PC1013.2 PC1014.2 PC1015.2 PC1016.2 PC1017.2 PC1018.2 PC1019.2 PC1020.2 PC1021.2 PC1022.2 PC1023.2 PC1024.2 PC1025.2 PC1026.2 PC1027.2 PC1028.2 PC1029.2 PC1030.2 PC1031.2 PC1032.2 PC1033.2 PC1034.2 PC1035.2 PC1036.2 PC1037.2 PC1038.2 PC1039.2 PC1040.2 PC1041.2 PC1042.2 PC1043.2 PC1044.2 PC1045.2 PC1046.2 PC1047.2 PC1048.2 PC1049.2 PC1050.2 PC1051.2 PC1052.2 PC1053.2 PC1054.2 PC1055.2 PC1056.2 PC1057.2 PC1058.2 PC1059.2 PC1060.2 PC1061.2 PC1062.2 PC1063.2 PC1064.2 PC1065.2 PC1066.2 PC1067.2 PC1068.2 PC1069.2 PC1070.2 PC1071.2 PC1072.2 PC1073.2 PC1074.2 PC1075.2 PC1076.2 PC1077.2 PC1078.2 PC1079.2 PC1080.2 PC1081.2 PC1082.2 PC1083.2 PC1084.2 PC1085.2 PC1086.2 PC1087.2 PC1088.2 PC1089.2 PC1090.2 PC1091.2 PC1092.2 PC1093.2 PC1094.2 PC1095.2 PC1096.2 PC1097.2 PC1098.2 PC1099.2 PC1105.2 PC1106.2 PC4302.2 PC4303.2 PC4304.2 PC4305.2 PC4306.2 PC4401.2 PC4402.2 PC4403.2 PC4404.2 PC4405.2 PC4406.2 PC4410.2 PC4418.2 PC4419.2 PC4427.2 PC4435.2 PC4436.2 PC4438.2 PC4445.2 PC4446.2 PC4452.2 PC4453.2 PC4456.2 PC4459.2 PC4461.1 PC4462.1 PC4464.2 PC4467.2 PC4468.2 PC4471.2 PC4509.2 PC4517.2 PC4518.2 PC4519.2 PC4520.2 PC4524.2 PC4525.2 PC4526.2 PC4527.2 PC4528.2 PC4529.2 PC4530.2 PC4531.2 PC4536.2 PC4601.2 PC4602.2 PC4603.1 PC4604.1 PC4606.2 PC4607.2 PC4610.1 PC4612.2 PC4613.2 PC4614.2 PC4615.1 PC4620.2 PC4621.1 PC4622.2 PC4624.2 PC4629.1 PC4631.2 PC4633.2 PC4637.2 PC4638.2 PC4639.2 PC4640.2 PC4641.2 PC4644.2 PC4651.2 PC4661.2 PC4701.2 PC4702.2 PC4703.2 PC4704.2 PC4706.2 PC4708.2 PC4802.2 PC4803.2 PC4804.2 PC4805.2 PC4809.2 PC4810.2 PC4812.2 PC4813.2 PC4814.2 PC4815.2 PC4816.2 PC4817.2 PC5001.2 PC5002.2 PC5003.2 PC5004.2 PC5102.2 PC5103.2 PC5104.2 PC5105.2 PC5106.2 PC5107.2 PC5109.2 PC5110.2 PC5111.2 PC5112.2 PC5113.2 PC5114.2 PC5116.2 PC5117.2 PC5118.2 PC5120.2 PC5152.2 PC5154.2 PC5155.2 PC5156.2 PC5301.2 PC5302.2 PC5303.2 PC5305.2 PC5306.2 PC5307.2 PC5308.2 PC5309.2 PC5310.2 PC5313.2 PC5314.2 PC5315.2 PC5401.2 PC5402.2 PC5403.2 PC5404.2 PC5406.2 PC8501.2 PC8502.1 PC8503.1 PC8506.2 PC8508.2 PC8509.2 PC8511.2 PC8512.2 PC8516.2 PC8519.2 PC8520.2 PC8521.2 PC8524.2 PC8525.2 PC8526.2 PC8527.2 PC8528.2 PC8529.2 PC8530.2 PC8531.2 PC8532.2 PC8533.2 PC8534.2 PC8535.2 PC8602.2 PC8604.2 PC8605.2 PC8607.2 PC8612.2 PC8621.2 PC8622.2 PC8623.2 PC8625.2 PC8626.2 PC8635.2 PC8636.2 PC8651.2 PC8652.2 PC8654.2 PC8655.2 PC8657.2 PC8658.2 PC8659.2 PC8660.2 PC8661.2 PD4301.A PD4302.1 PD4303.3 PD4304.A PQ4302.E PQ4304.E PQ4306.1 PQ4306.4 PQ4402.S PQ4405.1 PQ4405.4 PQ4406.1 PQ4406.4 PQ4412.S PQ4415.E PQ8501.1 PQ8501.4 PQ8604.1 PQ8604.4 PQ8608.S PR4302.2 PR4308.2 PR4313.2 PR4403.2 PR4404.2 PR4405.2 PR4406.1 PR4411.2 PR4412.2 PR4413.2 PR4414.2 PR4416.2 PR4418.2 PR4434.1 PR4445.2 PR4455.2 PR4478.2 PR4517.2 PR4523.2 PR4526.2 PR4530.2 PR4531.2 PR4608.1 PR4614.1 PR4617.1 PR4621.1 PR4627.2 PR4628.2 PR4629.2 PR4639.1 PR4644.2 PR4654.2 PR4655.1 PR4659.2 PR4661.2 PR4672.1 PR4712.2 PR4817.2 PR4818.2 PR5114.2 PR5117.2 PR5152.2 PR5154.2 PR5303.2 PR5304.2 PR5401.2 PR5404.2 PR8501.1 PR8502.1 PR8506.1 PR8508.1 PR8516.2 PR8524.2 PR8528.2 PR8531.2 PR8623.2 PR8671.2 PR8672.2 PR8676.2 PT4501.2 PT4502.2 PT4701.2 PT4801.2 PT4803.2 PT4805.2 PT4806.2 PT8506.2 PT8507.2 PT8508.2 PT8901.2 PT8902.2 PU4401.33 PU4412.1 PU4412.2 PU4412.3 PU4502.1 PU4502.2 PU4502.3 PU4503.21 PU4505.1 PU4505.2 PU4505.3 PU4601.41 PU4701.3 PU4701.9 PU4801.3 PU4801.9 PU4802.3 PU4802.9 PU5001.4 PU5001.9 PU5003.1 PU5003.2 PU5003.3 PU5101.1 PU5101.3 PU5101.14 PU5101.21 PU5105.1 PU5105.2 PU5105.3 PU5151.1 PU5301.4 PU5301.12 PU5301.13 PU5301.14 PU5301.15 PU5301.19 PU5401.1 PU8501.41 PU8502.5 PU8502.6 PU8502.7 PU8503.5 PU8503.6 PU8503.7 PU8504.5 PU8504.6 PU8504.7 PU8505.5 PU8505.6 PU8505.7 PU8601.4 PU8601.8 PU8601.9 PU8651.7 PU8651.8 PU8651.18 PU8651.21 PWR1.4 PWR1.5 PWR1.6 Q501.S Q502.S Q1701.1 Q1701.4 Q1702.1 Q1702.4 Q1901.S Q2110.S Q2408.S Q2505.S Q2705.S Q3102.S Q5701.S Q6505.S Q6701.1 Q6701.4 Q7902.S Q7903.S R402.2 R406.2 R407.2 R412.1 R413.1 R414.1 R415.1 R501.2 R502.2 R503.2 R601.1 R602.2 R604.2 R605.2 R711.1 R713.1 R717.2 R806.2 R1205.1 R1209.2 R1210.1 R1212.1 R1303.1 R1307.1 R1309.2 R1311.1 R1501.2 R1502.2 R1601.2 R1602.2 R1603.2 R1715.2 R1717.1 R1719.2 R1720.1 R1817.2 R1823.2 R1825.2 R1901.2 R1904.1 R2008.2 R2016.2 R2018.2 R2019.2 R2020.2 R2024.2 R2118.2 R2401.2 R2417.2 R2436.2 R2445.1 R2448.2 R2449.2 R2455.2 R2504.2 R2505.2 R2605.1 R2611.2 R2704.2 R2705.2 R2706.2 R2735.2 R3102.1 R3107.2 R3113.2 R4006.2 R4301.2 R5506.2 R5526.2 R5528.2 R5531.2 R5606.2 R5607.2 R5608.2 R5616.2 R5707.2 R5709.2 R5711.2 R5719.2 R6513.2 R6601.2 R6707.2 R7601.1 R7809.1 R7814.2 R7818.2 R7819.2 R7820.2 R7821.2 R7902.1 R7922.1 R7925.2 R7927.2 R7929.2 R7931.2 R7933.2 R7934.2 R7936.2 R7938.1 R7939.2 R7941.1 R7943.1 R8107.2 R8108.2 R8109.1 R8110.1 R8111.1 R8112.1 R8113.1 R9141.2 RJ45.9 RJ45.10 RN1201.2(A) RN1301.2(A) RN1701.1(A) RN1701.2(A) RN2009.1(A) RN2009.2(A) RN5502.1(A) RN5502.2(A) RN5502.3(A) RN5602.2(A) RN7904.3(B) RN7904.4(B) RTC1.2 SKT251.4 SPI25.4 SPK1.5 SPK1.6 SPR1.1 SPR2.1 SPR3.1 SPR4.1 SPR5.1 TC3501.2 THM262.5 TP1.4 TP1.9 TP1.10 U2101.2 U3501.2 U3503.2 U4001.11 U4001.15 U4002.5 U4006.5 U5501.2 U5601.24 U5601.33 U6301.A6 U6301.C4 U6301.E7 U6301.G5 U6301.H10 U6301.J5 U6301.K8 U6301.N2 U6301.N5 U6301.P4 U6301.P6 U6701.5 U6701.6 U6701.7 U6701.8 U9103.9 U9103.16 U9103.23 U9103.32 U9103.33 USB1.4 USB1.7 USB1.10 USB1.11 USB1.12 USB1.13 USB2.4 USB2.7 USB2.10 USB2.11 USB2.12 USB2.13 VGA1.5 VGA1.6 VGA1.7 VGA1.8 VGA1.10 VGA1.16 VGA1.17 VRAM1.A1 VRAM1.A3 VRAM1.A12 VRAM1.A14 VRAM1.B5 VRAM1.B10 VRAM1.C1 VRAM1.C3 VRAM1.C4 VRAM1.C11 VRAM1.C12 VRAM1.C14 VRAM1.D10 VRAM1.E1 VRAM1.E3 VRAM1.E12 VRAM1.E14 VRAM1.F5 VRAM1.F10 VRAM1.G5 VRAM1.G10 VRAM1.H1 VRAM1.H2 VRAM1.H13 VRAM1.H14 VRAM1.K1 VRAM1.K2 VRAM1.K13 VRAM1.K14 VRAM1.L5 VRAM1.L10 VRAM1.M5 VRAM1.M10 VRAM1.N1 VRAM1.N3 VRAM1.N12 VRAM1.N14 VRAM1.P10 VRAM1.R1 VRAM1.R3 VRAM1.R4 VRAM1.R11 VRAM1.R12 VRAM1.R14 VRAM1.T5 VRAM1.T10 VRAM1.U1 VRAM1.U3 VRAM1.U12 VRAM1.U14 VRAM2.A1 VRAM2.A3 VRAM2.A12 VRAM2.A14 VRAM2.B5 VRAM2.B10 VRAM2.C1 VRAM2.C3 VRAM2.C4 VRAM2.C11 VRAM2.C12 VRAM2.C14 VRAM2.D10 VRAM2.E1 VRAM2.E3 VRAM2.E12 VRAM2.E14 VRAM2.F5 VRAM2.F10 VRAM2.G5 VRAM2.G10 VRAM2.H1 VRAM2.H2 VRAM2.H13 VRAM2.H14 VRAM2.K1 VRAM2.K2 VRAM2.K13 VRAM2.K14 VRAM2.L5 VRAM2.L10 VRAM2.M5 VRAM2.M10 VRAM2.N1 VRAM2.N3 VRAM2.N12 VRAM2.N14 VRAM2.P10 VRAM2.R1 VRAM2.R3 VRAM2.R4 VRAM2.R11 VRAM2.R12 VRAM2.R14 VRAM2.T5 VRAM2.T10 VRAM2.U1 VRAM2.U3 VRAM2.U12 VRAM2.U14 WLAN1.1 WLAN1.7 WLAN1.18 WLAN1.33 WLAN1.39 WLAN1.45 WLAN1.51 WLAN1.57 WLAN1.63 WLAN1.69 WLAN1.75 WLAN1.76 WLAN1.77 X2201.2 X2201.4 X3101.2 X3101.4 X7901.2 X7901.4
V3D3_STB: HDA27.16 R2708.2
VCC_CORE: C1101.1 C1102.1 C1103.1 C1116.1 C1117.1 CPU1.A30 CPU1.A34 CPU1.A39 CPU1.A44 CPU1.AK33 CPU1.AK35 CPU1.AK37 CPU1.AK38 CPU1.AK40 CPU1.AL33 CPU1.AL37 CPU1.AL40 CPU1.AM32 CPU1.AM33 CPU1.AM35 CPU1.AM37 CPU1.AM38 CPU1.G30 CPU1.G32 CPU1.G33 CPU1.G35 CPU1.G37 CPU1.G38 CPU1.G40 CPU1.G42 CPU1.J30 CPU1.J33 CPU1.J37 CPU1.J40 CPU1.K33 CPU1.K35 CPU1.K37 CPU1.K38 CPU1.K40 CPU1.K42 CPU1.K43 PC1001.1 PC1002.1 PC1003.1 PC1004.1 PC1005.1 PC1006.1 PC1007.1 PC1008.1 PC1009.1 PC1010.1 PC1011.1 PC1012.1 PC1013.1 PC1014.1 PC1015.1 PC1016.1 PC1017.1 PC1018.1 PC1019.1 PC1020.1 PC1021.1 PC1022.1 PC1023.1 PC1024.1 PC1025.1 PC1026.1 PC1027.1 PC1028.1 PC1029.1 PC1030.1 PC1040.1 PC1066.1 PC1067.1 PC1068.1 PC1097.1 PC1099.1 PG4809.1 PG4815.1 PL4801.2 PL4802.2 PR4631.1 PT4801.1 PT4803.1 R710.1 R718.1 R720.1
VCC_SENSE: CPU1.E32 PR4665.1 R710.2
VCCDSW_EN#: C2125.1 D2101.2 R2120.2 R2411.1
VCCDSW_ON: KBC24.88 R2411.2
VCCGT_SENSE: CPU1.J70 PR4667.1 R712.2
VCCK_12: C5608.1 C5609.1 C5620.1 U5601.4 U5601.25
VCCRTCEXT: C2112.1 CPU1.BB10
VCCSA_SENSE: CPU1.H20 PR4601.2 R716.1
VCCSTG_EN_R: C4017.1 R4034.2 U4002.4
VCCSTU_EN_R: C4018.1 R4024.2 U4006.4
VDD: PC4446.1 PR4401.1 PR4402.1 PR4438.1 PR4451.1 PU4401.19
VDD10: C3104.1 C3108.1 C3112.1 C3114.1 C3115.1 C3119.1 C3122.1 C3123.1 L3101.2 LOM31.3 LOM31.8 LOM31.22 LOM31.30 R3101.2
VDD_DAC_33: C5615.1 C5627.1 C5628.1 R5609.2 U5601.20
VDDREG: C3110.1 C3124.1 LOM31.23 R3104.2
VSS_AY71: CPU1.AY71 R602.1
VSS_MECH1: GPU1.A32 TP7701.1
VSS_MECH2: GPU1.AM1 TP7702.1
VSS_MECH3: GPU1.AM32 TP7703.1
VSS_SENSE: CPU1.E33 PR4666.1 R711.2
VSSGT_SENSE: CPU1.J69 PR4668.1 R713.2
VSSSA_SENSE: CPU1.H21 PR4602.2 R717.1
0D6V_S0: C1223.1 C1224.1 C1225.1 C1226.1 C1227.1 C1230.1 C1324.1 C1325.1 C1326.1 C1327.1 DM1.258 DM2.258 PG5113.1 PG5114.1
0D95V_VGA_EN: PR8603.1 PR8621.1 PR8625.2
0D95V_VGA_EN_R: D8601.2 PC8607.1 PR8621.2 PU8601.7
0D95V_VGA_S0: C8010.1 C8011.1 C8012.1 C8013.1 C8015.1 C8016.1 C8057.1 C8065.1 GPU1.L23 GPU1.L24 GPU1.L25 GPU1.L26 GPU1.M22 GPU1.N22 GPU1.N23 GPU1.N24 GPU1.R21 GPU1.R22 GPU1.T22 GPU1.U21 GPU1.U22 GPU1.V22 L8003.1 PG8603.2 PG8604.2 R7618.2 R7622.1 R7705.1
0D95V_VGA_S0_PG: PG8655.1 PR8624.2 PU8601.2
1D0V_S5: C4013.1 C4016.1 PC1038.1 PC1039.1 PG5304.2 PG5305.2 PG5306.2 PG5307.2 PG5308.2 PG5309.2 PG5311.2 PG5312.2 PG5313.2 PG5314.2 R1101.1 R1117.1 R1724.1 R1735.1 R2402.1 U4002.1 U4002.2 U4002.9 U4006.1 U4006.2 U4006.9
1D0V_S5_PWRGD: PR5305.1 R4029.1
1D2V_S3: C718.1 C719.1 C1202.1 C1203.1 C1204.1 C1205.1 C1206.1 C1208.1 C1209.1 C1210.1 C1214.1 C1215.1 C1216.1 C1217.1 C1218.1 C1219.1 C1220.1 C1221.1 C1303.1 C1304.1 C1305.1 C1306.1 C1307.1 C1308.1 C1309.1 C1310.1 C1315.1 C1316.1 C1317.1 C1318.1 C1319.1 C1320.1 C1321.1 C1322.1 CPU1.AL23 CPU1.AU23 CPU1.AU28 CPU1.AU35 CPU1.AU42 CPU1.BB23 CPU1.BB32 CPU1.BB41 CPU1.BB47 CPU1.BB51 DM1.12 DM1.33 DM1.54 DM1.75 DM1.96 DM1.111 DM1.112 DM1.117 DM1.118 DM1.123 DM1.124 DM1.129 DM1.130 DM1.135 DM1.136 DM1.141 DM1.142 DM1.147 DM1.148 DM1.153 DM1.154 DM1.159 DM1.160 DM1.163 DM1.178 DM1.199 DM1.220 DM1.241 DM2.12 DM2.33 DM2.54 DM2.75 DM2.96 DM2.111 DM2.112 DM2.117 DM2.118 DM2.123 DM2.124 DM2.129 DM2.130 DM2.135 DM2.136 DM2.141 DM2.142 DM2.147 DM2.148 DM2.153 DM2.154 DM2.159 DM2.160 DM2.163 DM2.178 DM2.199 DM2.220 DM2.241 EC8901.1 EC8902.1 EC8903.1 EC8904.1 EC8905.1 EC8906.1 EC8907.1 EC8908.1 EC8909.1 EC8910.1 EC8911.1 EC8912.1 EC8913.1 EC8914.1 EC8915.1 PC1055.1 PC1056.1 PC1057.1 PC1058.1 PC1059.1 PC1060.1 PC1061.1 PC1062.1 PC1063.1 PC1064.1 PG5115.1 PG5116.1 PG5119.2 PG5120.2 PG5121.2 PG5122.2 PG5123.2 PG5124.2 PG5125.2 PG5126.2 PG5127.2 PG5128.2 PG5129.2 PG5130.2 R505.1 R705.1 R1215.1 R1312.1 RN1201.1(A) RN1301.1(A)
1D8V_EN#: Q2705.D R2736.2 R2738.1
1D8V_EN_R#: C2738.2 Q2704.G R2738.2
1D8V_PWR: PC5402.1 PC5404.1 PC5405.1 PG5405.1 PG5406.1 PG5407.1 PR5403.1 PU5401.3 PU5401.4
1D8V_S0: C2736.1 Q2704.D R2709.1 R2719.1 R6401.1
1D8V_S5: C2737.1 C2738.1 PC8634.1 PC8635.1 PG5405.2 PG5406.2 PG5407.2 PQ8607.S PR8650.1 Q2704.S Q6301.G R1139.1 R2462.1 R2736.1 R5521.1 R6311.1
1D8V_S5_KBC: C2423.1 KBC24.54 R2410.1 R2462.2
1D8V_VGA_EN: D8601.1 PC8612.1 PQ8608.G PR8603.2
1D8V_VGA_EN#: PQ8608.D PR8650.2 PR8651.1
1D8V_VGA_EN_R#: PC8634.2 PQ8607.G PR8651.2
1D8V_VGA_S0: C7904.1 C8002.1 C8008.1 C8017.1 GPU1.AA20 GPU1.AA21 GPU1.AB20 GPU1.AB21 GPU1.AD17 GPU1.AM30 L8001.1 L8002.1 PC8636.1 PQ8607.D PR8546.1 R7704.1 R7926.1 R7928.1 R7930.1 R7932.1 RN7905.3(B) RN7905.4(B)
1D35V_VGA_S0: C8001.1 C8003.1 C8004.1 C8005.1 C8006.1 C8007.1 C8009.1 C8014.1 C8031.1 C8032.1 C8033.1 C8034.1 C8042.1 C8101.1 C8102.1 C8105.1 C8106.1 C8107.1 C8108.1 C8109.1 C8110.1 C8111.1 C8112.1 C8113.1 C8114.1 C8115.1 C8116.1 C8117.1 C8118.1 C8119.1 C8120.1 C8121.1 C8122.1 C8123.1 C8124.1 C8125.1 C8126.1 C8127.1 C8128.1 C8129.1 C8130.1 C8131.1 C8132.1 EC9725.1 EC9726.1 EC9727.1 EC9728.1 EC9729.1 EC9730.1 EC9731.1 GPU1.H13 GPU1.H16 GPU1.H19 GPU1.J9 GPU1.J10 GPU1.J23 GPU1.J24 GPU1.K9 GPU1.K10 GPU1.K23 GPU1.K24 GPU1.L11 GPU1.L12 GPU1.L13 GPU1.L20 GPU1.L21 GPU1.L22 PC8657.1 PC8658.1 PC8659.1 PC8660.1 PC8661.1 PG8653.2 PL8651.2 R7802.1 R7810.1 R7817.1 R8101.1 R8102.1 R8103.1 R8104.1 R8105.1 R8106.1 R8114.1 VRAM1.B1 VRAM1.B3 VRAM1.B12 VRAM1.B14 VRAM1.C5 VRAM1.C10 VRAM1.D1 VRAM1.D3 VRAM1.D11 VRAM1.D12 VRAM1.D14 VRAM1.E5 VRAM1.E10 VRAM1.F1 VRAM1.F3 VRAM1.F12 VRAM1.F14 VRAM1.G1 VRAM1.G2 VRAM1.G4 VRAM1.G11 VRAM1.G13 VRAM1.G14 VRAM1.H3 VRAM1.H12 VRAM1.K3 VRAM1.K12 VRAM1.L1 VRAM1.L2 VRAM1.L4 VRAM1.L11 VRAM1.L13 VRAM1.L14 VRAM1.M1 VRAM1.M3 VRAM1.M12 VRAM1.M14 VRAM1.N5 VRAM1.N10 VRAM1.P1 VRAM1.P3 VRAM1.P11 VRAM1.P12 VRAM1.P14 VRAM1.R5 VRAM1.R10 VRAM1.T1 VRAM1.T3 VRAM1.T12 VRAM1.T14 VRAM2.B1 VRAM2.B3 VRAM2.B12 VRAM2.B14 VRAM2.C5 VRAM2.C10 VRAM2.D1 VRAM2.D3 VRAM2.D11 VRAM2.D12 VRAM2.D14 VRAM2.E5 VRAM2.E10 VRAM2.F1 VRAM2.F3 VRAM2.F12 VRAM2.F14 VRAM2.G1 VRAM2.G2 VRAM2.G4 VRAM2.G11 VRAM2.G13 VRAM2.G14 VRAM2.H3 VRAM2.H12 VRAM2.K3 VRAM2.K12 VRAM2.L1 VRAM2.L2 VRAM2.L4 VRAM2.L11 VRAM2.L13 VRAM2.L14 VRAM2.M1 VRAM2.M3 VRAM2.M12 VRAM2.M14 VRAM2.N5 VRAM2.N10 VRAM2.P1 VRAM2.P3 VRAM2.P11 VRAM2.P12 VRAM2.P14 VRAM2.R5 VRAM2.R10 VRAM2.T1 VRAM2.T3 VRAM2.T12 VRAM2.T14
2D5V_PWR: PC5153.1 PC5154.1 PG5151.1 PG5152.1 PR5151.1 PU5151.3 PU5151.4
2D5V_PWROK: PR5128.1 PR5158.1
2D5V_S3: C1207.1 C1211.1 C1212.1 C1213.1 C1231.1 C1232.1 C1311.1 C1312.1 C1313.1 C1314.1 C1330.1 C1331.1 DM1.257 DM1.259 DM2.257 DM2.259 PG5151.2 PG5152.2
3D3V_AUX_KBC_R: DB3.1 R2476.2
3D3V_AUX_S5: PR4409.1 PR4435.1 PR4449.1 PR4450.1 PR4501.1 PR4505.2 R1726.1 R1727.1 R1737.1 R2453.1 R2473.1 R2503.1 R2609.1
3D3V_CAMERA_S0: C5539.1 EC5503.1 LCD1.32 R5532.2
3D3V_LAN_S5: C3103.1 C3109.1 C3111.1 C3113.1 C3117.1 C3120.1 LOM31.11 LOM31.32 Q3101.D R3104.1
3D3V_PWR: PC4517.1 PG4517.1 PG4522.1 PG4526.1 PG4528.1 PG4529.1 PG4535.1 PL4502.1 PT4502.1
3D3V_PWR_2: PC4526.1 PR4505.1 PU4503.3
3D3V_RTC_SYS: D2501.1 R2503.2 R2505.1
3D3V_RUN_FFS: C6701.1 C6702.1 C6703.1 R6701.2 U6701.2 U6701.3 U6701.9 U6701.10
3D3V_S0: C1201.1 C1228.1 C1328.1 C1329.1 C2615.1 C2616.1 C4004.1 C5505.1 C5610.1 C5626.1 C6101.1 C6102.1 C6105.1 DBG1.10 DM1.255 DM2.255 EC9735.1 EC9736.1 EC9737.1 EC9738.1 ED9201.5 FC9702.1 FC9703.1 IOBD1.15 PC8601.1 PQ8609.S PR4609.1 PR8601.1 PR8619.1 Q1801.2 Q1801.5 Q2414.G Q5702.2 Q5702.5 Q5703.C Q7904.2 Q7904.5 R506.1 R802.2 R1204.1 R1208.1 R1211.1 R1302.1 R1306.1 R1310.1 R1503.2 R1606.2 R1608.2 R1610.2 R1834.2 R1835.2 R2002.1 R2003.1 R2005.1 R2006.1 R2023.1 R2046.1 R2048.1 R2049.1 R2429.2 R2430.1 R2489.1 R2613.1 R2614.1 R2715.1 R2716.1 R2737.1 R3109.2 R4005.1 R5522.1 R5529.2 R5532.1 R5609.1 R5610.1 R5613.1 R6117.1 R6517.1 R6520.1 R6701.1 R6702.1 R6703.1 R6704.1 R9120.2 R9121.2 R9145.1 R9150.1 R9202.1 RN801.1(A) RN801.2(A) RN803.1(A) RN803.2(A) RN1812.1(A) RN1812.2(A) RN1812.3(A) RN1812.4(A) RN1813.1(A) RN1813.2(A) RN2007.3(B) RN2007.4(B) RN2008.3(B) RN2008.4(B) RN2010.1(A) RN2010.2(A) RN5602.1(A) RN5603.1(A) RN5603.2(A) RN7903.1(A) RN7903.2(A) THM262.1 U4001.8 U4001.9 U5501.4 U5501.5 U5601.14 U5601.26
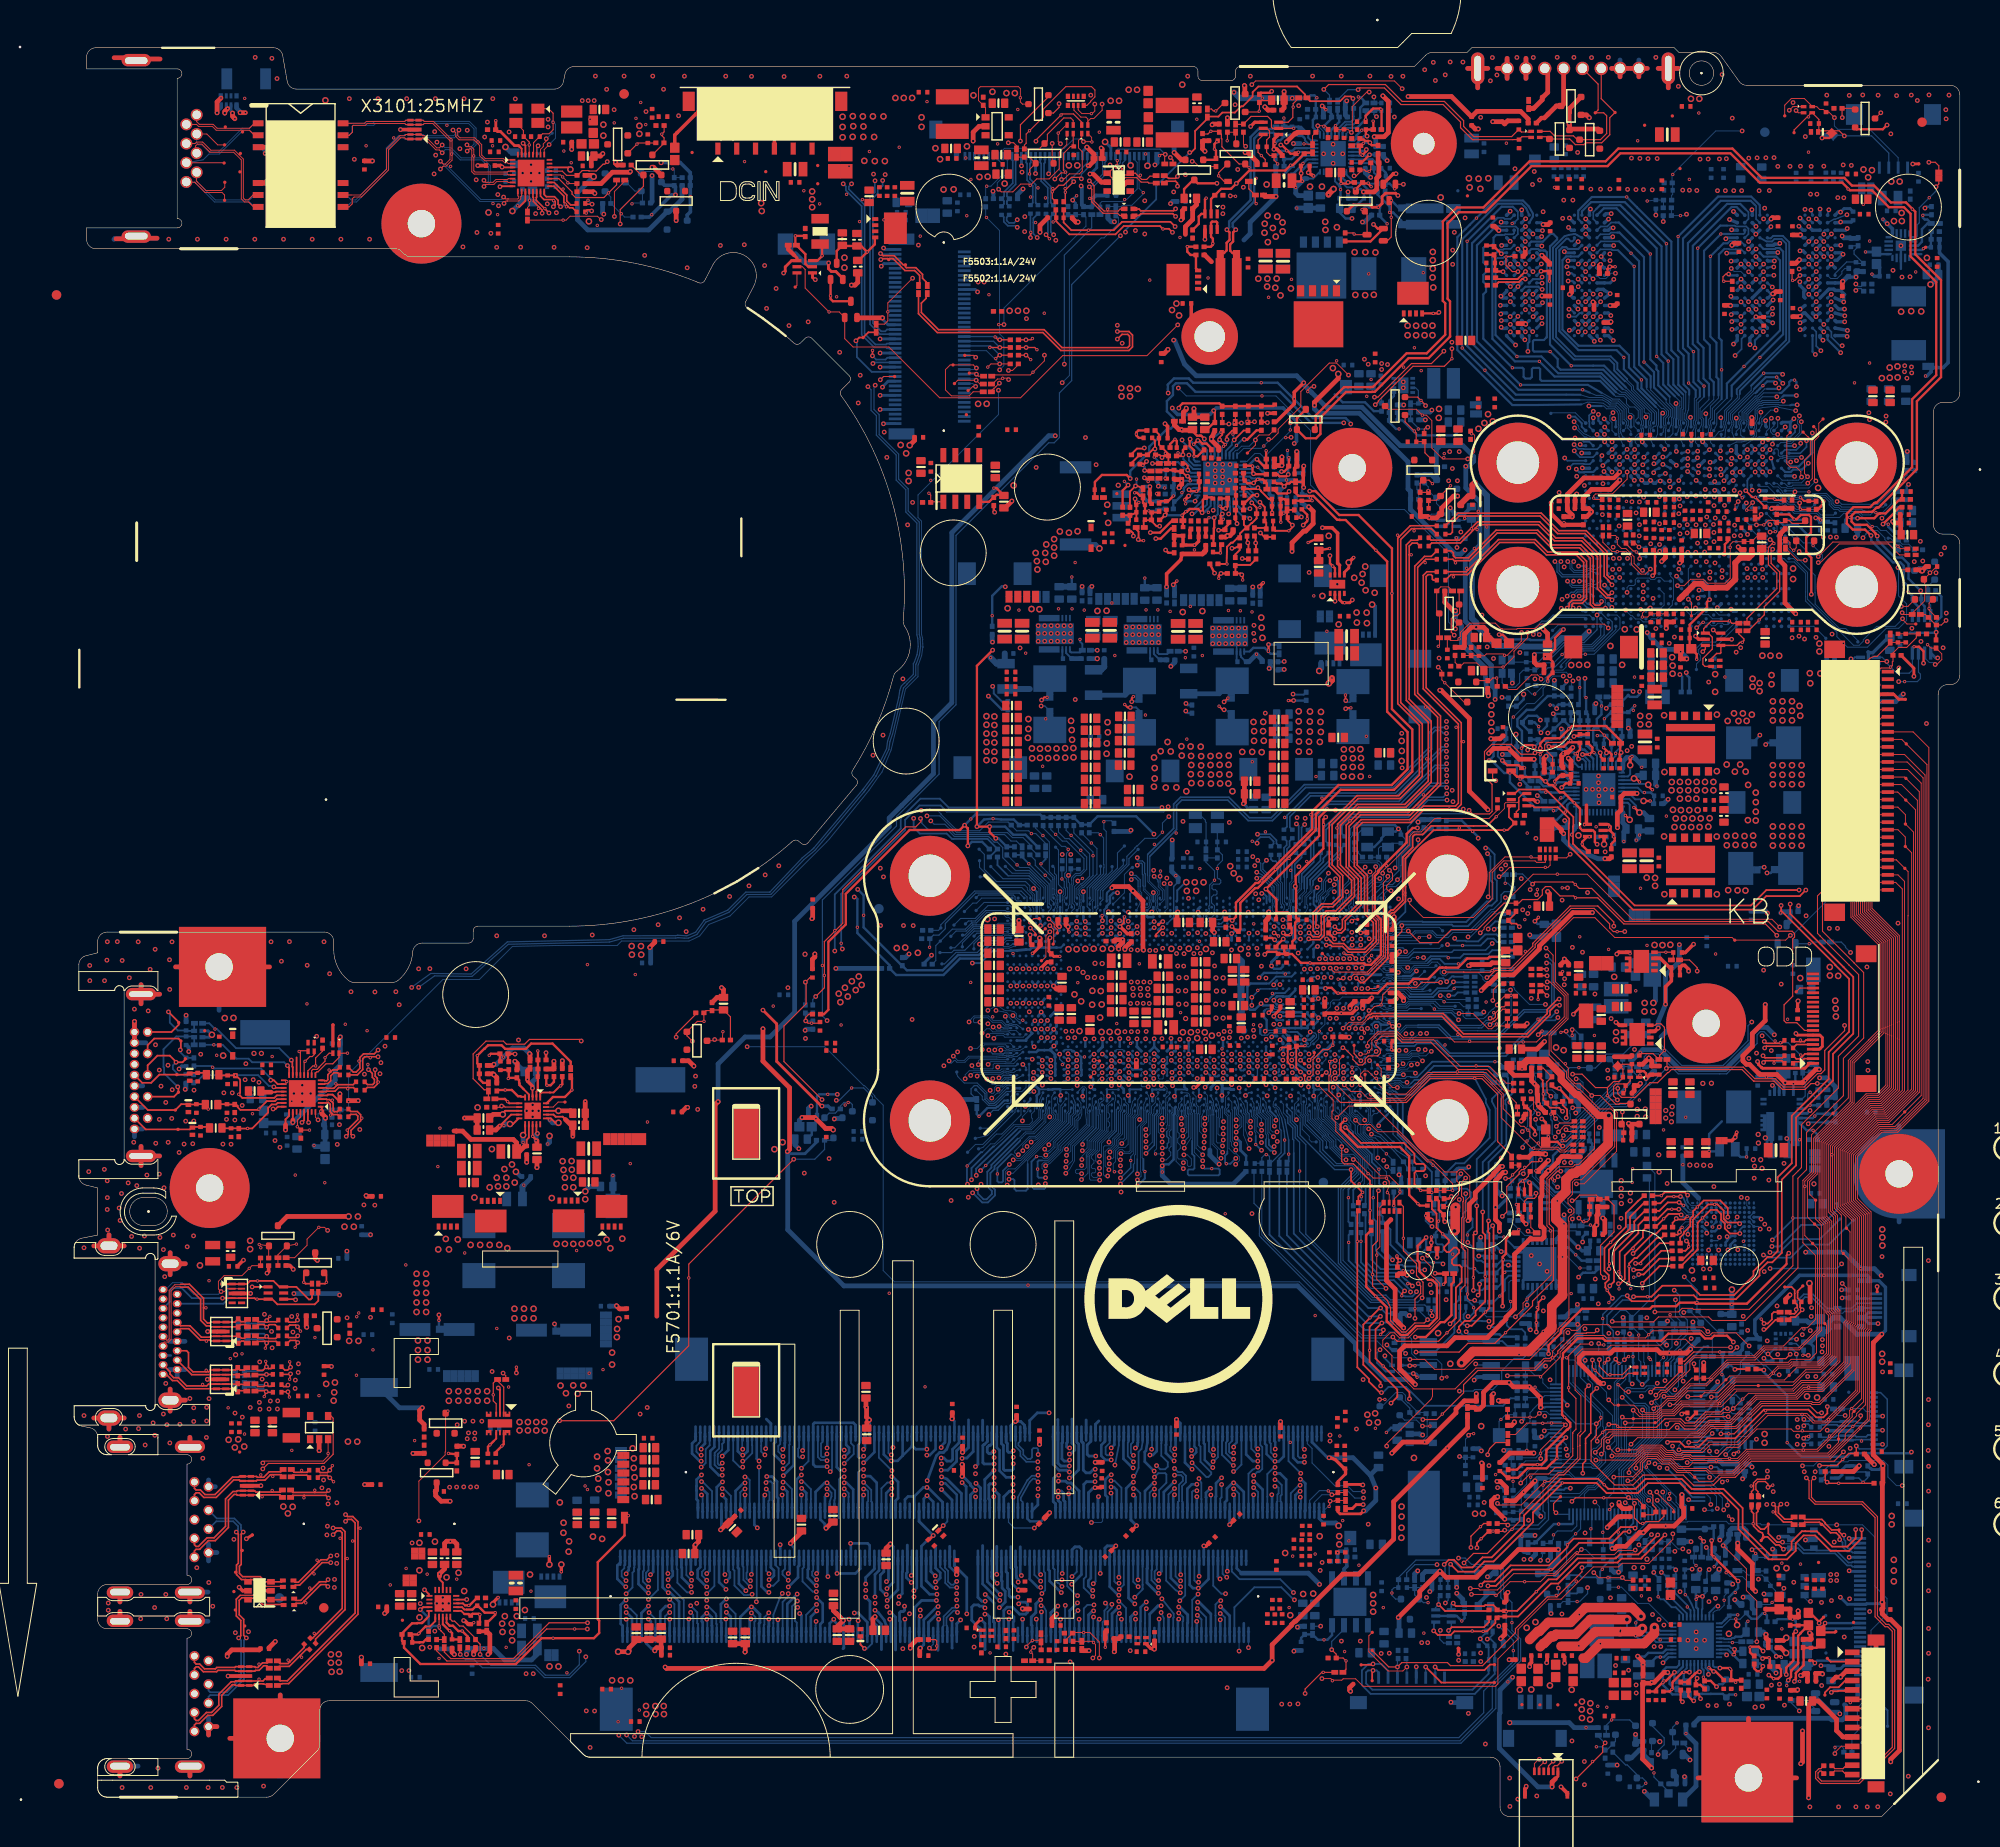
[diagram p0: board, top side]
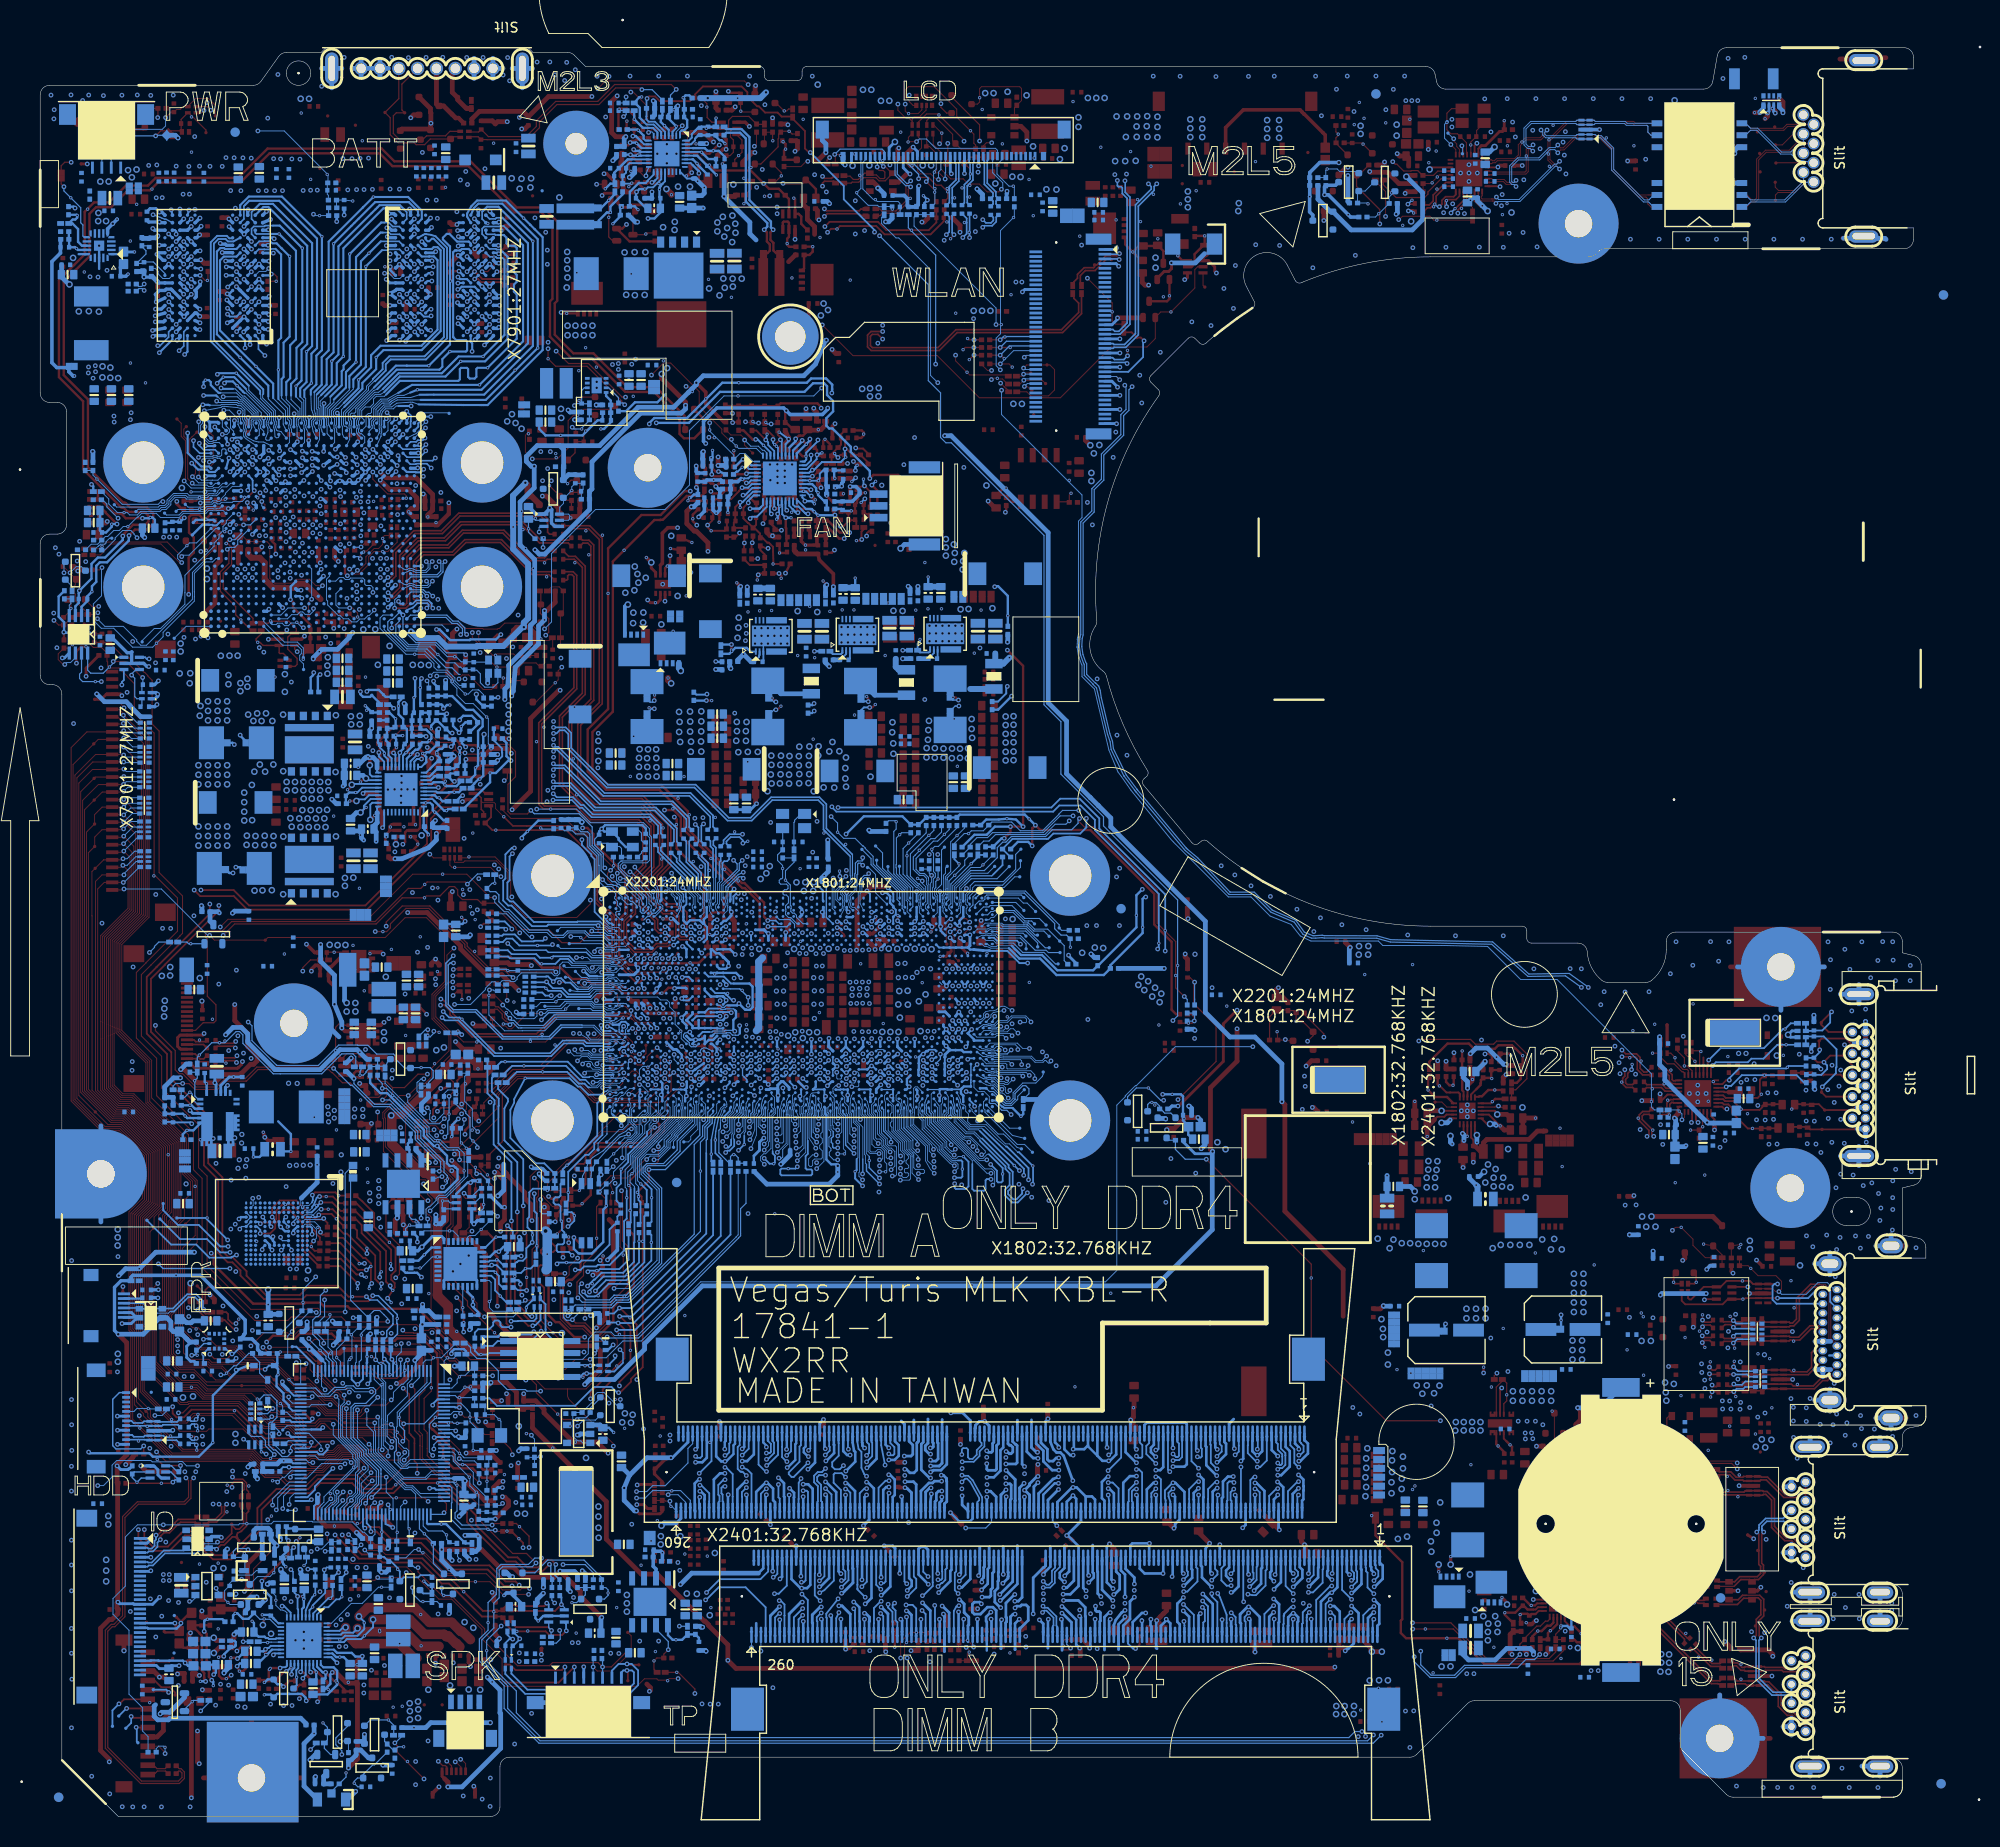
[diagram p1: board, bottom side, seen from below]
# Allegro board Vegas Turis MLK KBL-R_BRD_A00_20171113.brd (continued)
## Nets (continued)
3D3V_S5: AFTP6402.1 C2415.1 C2416.1 C2421.1 C3105.1 C3121.1 C6401.1 EC8916.1 EC8917.1 EC8918.1 EC8919.1 EC8920.1 EC8921.1 EC8922.1 EC8923.1 EC8924.1 EC8925.1 EC8926.1 EC8927.1 EC8928.1 PC5152.1 PC5403.1 PC8603.1 PC8655.1 PD4302.2 PG4517.2 PG4522.2 PG4526.2 PG4528.2 PG4529.2 PG8601.1 PG8602.1 PR4304.1 PR4453.2 PR4472.1 PR4534.1 PR5111.1 PR5155.1 PR5402.1 PR8539.1 PR8606.1 PR8624.1 PR8673.1 PU5151.5 PU5151.9 PU5401.5 PU5401.9 PU8651.15 PWR1.1 Q2412.2 Q2412.5 Q3101.S R507.1 R1711.1 R2115.1 R2120.1 R2434.1 R2442.1 R2443.1 R2446.1 R3103.1 R3106.1 R4031.1 R4101.1 R6118.1 R6325.1 R6521.1 R9143.1 R9146.1 R9149.1 RN1704.1(A) RN1704.2(A) RN1704.3(A) RN1704.4(A) RN2405.5(B) RN2405.6(B) RN2405.7(B) RN2405.8(B) U2101.4 U2101.5 U4001.6 U4001.7
3D3V_S5_KBC: C2410.1 C2411.1 C2412.1 C2413.1 C2414.1 C2417.1 C2420.1 C2422.1 C2429.1 D4304.2 D4305.2 D4306.2 KBC24.5 KBC24.19 KBC24.22 KBC24.43 KBC24.65 KBC24.82 KBC24.103 KBC24.115 R2412.1 R2414.1 R2415.1 R2424.1 R2446.2 R2450.1 R2476.1 R2478.1 R2493.2 R2607.1 R2608.1 R4032.1 RN2402.3(B) RN2402.4(B) RN2403.1(A) RN2403.2(A) RN2403.3(A) RN2403.4(A) RN2404.1(A) RN2404.2(A) RN2404.3(A) RN2404.4(A) RN2406.1(A) RN2406.2(A) RN2406.3(A) RN2406.4(A) RN2407.1(A) RN2407.2(A) RN2407.3(A) RN2407.4(A) RN2408.1(A) RN2408.2(A) RN2408.3(A) RN2408.4(A) RN2409.1(A) RN2409.2(A) RN2409.3(A) RN2409.4(A)
3D3V_S5_PCH: C2501.1 C2502.1 R1110.1 R1731.1 R1805.2 R1820.2 R1821.2 R1822.1 R1824.1 R1827.1 R1828.1 R1832.2 R2007.1 R2116.2 R2501.1 R4101.2 RN802.1(A) RN802.2(A) RN802.3(A) RN802.4(A) RN1807.1(A) RN1807.2(A) RN1807.3(A) RN1807.4(A) RN2011.1(A) RN2011.2(A) RN2501.3(B) RN2501.4(B) SKT251.8 SPI25.8
3D3V_S5_PCH_GEN9: R2116.1 U2101.3
3D3V_TP_S5_R: C6503.2 Q6504.S R6520.2 R6521.2
3D3V_TPM: C9114.1 C9115.1 C9116.1 R9140.1 R9147.1 R9149.2 R9150.2
3D3V_TPM_1: C9106.1 C9108.1 R9143.2 R9144.1
3D3V_VGA_S0: C8024.1 GPU1.AA17 GPU1.AA18 GPU1.AB17 GPU1.AB18 PC8604.1 PC8605.1 PQ8609.D PR8503.1 PR8505.1 PR8518.1 PR8601.2 PR8609.1 PR8625.1 Q7901.2 Q7901.5 R7625.1 R7903.2 R7921.1 R7935.1 R7942.1 RN7902.3(B) RN7902.4(B)
3D3V_WLAN_S0: AFTP6101.1 C6103.1 C6104.1 C6106.1 R6117.2 R6118.2 WLAN1.2 WLAN1.4 WLAN1.72 WLAN1.74
+DC_IN: AFTP4313.1 AFTP4314.1 DCIN1.1 DCIN1.2 EC4301.1 EC4302.1 PC4301.1 PC4302.1 PD4301.K PQ4305.2 PR4307.1 PR4312.1 PR4314.1 PU4301.1 PU4301.2 PU4301.3
+RTC_CELL_VBAT: C2428.1 KBC24.122 R2451.1 R2452.2 R2472.2 R2473.2
+RTC_VCC: AFTP2502.1 R2502.1 RTC1.1
+SDC_IN: PG4429.2 PQ4410.1 PQ4410.2 PQ4410.3 PR4426.1 PR4441.1
+UZ12_TPM: C9109.1 C9112.1 R9145.2 R9146.2 U9103.8
+V_VREF_PATH1: C1222.2 R1209.1
+V_VREF_PATH2: C1323.2 R1309.1
+VCHGR: PG4428.2 PL4401.2 PQ4401.5 PQ4401.6 PQ4401.7 PQ4401.8 PR4443.1
A67_TP: CPU1.A67 TP2311.1
A70_TP: CPU1.A70 TP2301.1
AC_DIS: KBC24.69 PQ4304.B PQ4306.5 PR4444.2
AC_DIS_R: PC4471.1 PQ4412.G PR4444.1
AC_IN#_G: PQ4306.2 PR4312.2 PR4313.1
AC_IN_KBC#: PQ4306.6 TP4301.1
AC_PRESENT: CPU1.AY15 D1702.A EC1707.1 Q1702.3 RN1704.8(B)
ACLIM: PR4401.2 PR4403.1 PU4401.16
ACOK_IN: D1702.K PQ4405.2 PR4417.2 PR4418.1 PR4474.1 R2469.2
AD+: PC4303.1 PC4304.1 PC4305.1 PC4306.1 PD4410.1 PQ4410.5 PQ4410.6 PQ4410.7 PQ4410.8 PR4420.1 PR4431.1 PR4440.1 PR4445.1 PR4452.1 PU4301.5 PU4301.6 PU4301.7 PU4301.8
AD+_G_1: PQ4405.5 PQ4405.6 PR4422.2
AD+_G_2: PQ4410.4 PR4422.1 PR4441.2
AD+_R: PQ4401.4 PQ4412.D PR4440.2
AD_IA: PC4402.1 PR4475.1 R2421.2
AD_OFF_L: PQ4304.C PQ4305.1
AD_OFF_R: PC4301.2 PQ4305.3 PR4307.2 PR4308.1 PU4301.4
ADBIA0: GPU1.L18 VRAM1.J4
ADBIA1: GPU1.K16 VRAM2.J4
ALL_SYS_PWRGD: D4002.1 EC1709.1 R1716.1 R2481.1 R4002.1 R4005.2 R4011.2
ALWON: KBC24.121 R4009.2
AMBER_LED_BAT: EC6402.1 Q6403.C R6407.1
ATI_RST#: D7601.3 R7621.1 R7623.2 R7625.2
AUD_AGND: AFTP6611.1 C2702.1 C2703.2 C2706.2 C2707.2 C2710.2 C2711.2 C2715.2 C2902.2 EC2701.1 EC2702.1 EC2703.1 EC2704.1 EC2705.1 EC2905.2 EC2906.2 EC2907.2 EC2908.2 EC9739.1 EC9743.1 EC9744.1 EC9745.1 HDA27.19 HDA27.31 IOBD1.18 IOBD1.28 R2702.2 R2704.1 R2705.1 R2706.1 R2919.2 R2920.2 R6601.1
AUD_HP1_JACK_L: HDA27.25 R2908.1 R2913.2 R2922.2
AUD_HP1_JACK_L1: EC2907.1 R2907.1 R2908.2 R2919.1
AUD_HP1_JACK_R: HDA27.26 R2910.1 R2912.2 R2921.2
AUD_HP1_JACK_R1: EC2908.1 R2909.1 R2910.2 R2920.1
AUD_PC_BEEP: C2735.2 HDA27.11
AUD_PC_BEEP_C: C2735.1 C2739.1 D2703.3 R2735.1
AUD_PORTA_L_R_B: AFTP6606.1 IOBD1.19 R2907.2
AUD_PORTA_R_R_B: AFTP6608.1 IOBD1.20 R2909.2
AUD_SENSE: C2902.1 R2711.1 R2923.2
AUD_SENSE_A: HDA27.12 R2710.2 R2711.2
AUD_SPK_L+: EC2902.1 HDA27.35 R2902.1
AUD_SPK_L+_C: AFTP2902.1 R2902.2 SPK1.3
AUD_SPK_L-: EC2901.1 HDA27.36 R2901.1
AUD_SPK_L-_C: AFTP2901.1 R2901.2 SPK1.4
AUD_SPK_R+: EC2904.1 HDA27.38 R2904.1
AUD_SPK_R+_C: AFTP2904.1 R2904.2 SPK1.1
AUD_SPK_R-: EC2903.1 HDA27.37 R2903.1
AUD_SPK_R-_C: AFTP2903.1 R2903.2 SPK1.2
AUD_VREF: C2702.2 HDA27.22
AUX_ON: KBC24.3 R2491.2
B71_TP: CPU1.B71 TP2312.1
BA1_TP: CPU1.BA1 TP2305.1
BAT1_LED#: KBC24.106 Q2412.4 RN2405.2(A)
BAT2_LED#: KBC24.1 Q2412.1 RN2405.1(A)
BAT_AMBER: LED1.1 R6407.2
BAT_WHITE: LED1.2 R6406.2
BATT_WHITE_LED#: Q2412.6 R6404.1
BATT_WHITE_LED_R#: Q6401.D Q6404.B R6404.2
BB70_TP: CPU1.BB70 TP2307.1
BEEP: KBC24.45 R2734.1
BKLT_CTRL: D5503.3 R5524.1 RN5501.3(B) RN5502.8(B)
BKLT_IN_EC: KBC24.67 R2435.2 R2436.1
BLON_OUT: R2497.2 RN5503.4(B)
BLON_OUT_C: LCD1.21 RN5502.7(B) RN5503.1(A)
BLUETOOTH_EN: CPU1.AB2 R2002.2 R6113.1
BLUETOOTH_EN_NGFF: AFTP6107.1 R6113.2 WLAN1.54
BOARD_ID: KBC24.111 R2474.1
BOARD_ID2: CPU1.AB3 R2005.2 R2008.1
BOARD_ID_R: C2408.1 R2443.2 R2444.1 R2474.2
BOOST_MON: PC4403.1 PR4476.1 R2423.2
BP_D: PQ4402.D PR4415.2
BP_G: PC4433.2 PQ4402.G PR4478.1
BREATH_LED#: KBC24.70 TP2402.1
BT+: AFTP4302.1 AFTP4306.1 AFTP4307.1 BATT1.1 BATT1.2 EC4307.1 EC4308.1 PC4401.1 PC4410.1 PC4452.1 PC4453.1 PC4464.1 PD4304.K PG4426.2 PQ4416.2 PR4443.2 PR4454.2 PR4481.1
CAMERA_DET#: CPU1.BA7 R2004.1 R5501.2
CAMERA_DET#_R: LCD1.33 R5501.1
CAP_LED: AFTP6532.1 KB1.4 R6506.2
CAP_LED#: KBC24.93 Q2414.S R2489.2
CAP_LED#_S: Q2414.D R6508.1
CAP_LED_Q: Q6502.C R6506.1
CAP_LED_R#: Q6502.B R6508.2
CASA0B: GPU1.G19 VRAM1.L3
CASA1B: GPU1.G16 VRAM2.G3
CBN: C2708.2 HDA27.28
CBP: C2708.1 HDA27.30
CCG4_I2C_INT#: KBC24.32 TP2406.1
CCLIM: PR4402.2 PR4404.1 PU4401.11
CFG0: CPU1.E68 TP618.1
CFG1: CPU1.B67 TP619.1
CFG2: CPU1.D65 TP620.1
CFG3: CPU1.D67 R604.1 TP621.1
CFG4: CPU1.E70 R605.1 TP622.1
CFG5: CPU1.C68 TP623.1
CFG6: CPU1.D68 TP624.1
CFG7: CPU1.C67 TP625.1
CFG8: CPU1.F71 TP626.1
CFG9: CPU1.G69 TP627.1
CFG10: CPU1.F70 TP628.1
CFG11: CPU1.G68 TP629.1
CFG12: CPU1.H70 TP630.1
CFG13: CPU1.G71 TP631.1
CFG14: CPU1.H69 TP632.1
CFG15: CPU1.G70 TP633.1
CFG16: CPU1.E63 TP634.1
CFG17: CPU1.F63 TP635.1
CFG18: CPU1.E66 TP636.1
CFG19: CPU1.F66 TP637.1
CFG_RCOMP: CPU1.E60 R601.2
CHG_AMBER_LED#: Q2412.3 R6405.1
CHG_AMBER_LED_R#: Q6403.B R6405.2
CKEA0: GPU1.K20 VRAM1.J3
CKEA1: GPU1.J17 VRAM2.J3
CL_CLK: CPU1.G3 R6109.1
CL_CLK_R: R6109.2 WLAN1.42
CL_DATA: CPU1.G2 R6119.1
CL_DATA_R: R6119.2 WLAN1.40
CL_RST#: CPU1.G1 EC1805.1 R6108.1
CL_RST#_R: R6108.2 WLAN1.38
CLK_TP_SIO: EC6503.1 KBC24.78 RN6503.1(A) RN6504.4(B)
CLKA0: GPU1.H26 R8101.2 VRAM1.J12
CLKA0B: GPU1.H25 R8102.2 VRAM1.J11
CLKA1: GPU1.G9 R8103.2 VRAM2.J12
CLKA1B: GPU1.H9 R8104.2 VRAM2.J11
CLKREQ_PCIE#1: CPU1.AT7 R6112.2 RN1812.6(B)
CLKREQ_PCIE#2: CPU1.AT8 R3105.1 RN1812.5(B)
CLKREQ_PCIE#3: CPU1.AT10 RN1813.4(B)
CLKREQ_PCIE#4: CPU1.AU8 RN1813.3(B)
CLKREQ_PCIE#5: CPU1.AU7 RN1812.8(B)
CLKREQ_PEG#0: CPU1.AR10 Q7903.D R7943.2 RN1812.7(B)
CLKRUN#_R: CPU1.AW11 R1818.1 R1819.1
CLKTESTA: C7822.1 GPU1.K8
CLKTESTA_C: C7822.2 R7821.1
CLKTESTB: C7821.1 GPU1.L7
CLKTESTB_C: C7821.2 R7820.1
CMP_VIN0: KBC24.20 R2470.1
CMP_VIN0_R: C2612.1 C2613.1 R2470.2 R2471.2 R2608.2 R2609.2 R2610.1
CMP_VIN1: KBC24.21 TP2404.1
CMP_VOUT0: KBC24.85 R2602.1 R2607.2 R2612.1
CMP_VOUT1_R: C2419.1 Q2408.G R2417.1 R2418.1 R2420.2
CPU_A16_TP: CPU1.BB9 TP1902.1
CPU_D3_TP: CPU1.J4 TP1803.1
CPU_D4_TP: CPU1.V1 TP1804.1
CPU_D5_TP: CPU1.V2 TP1805.1
CPU_D6_TP: CPU1.M1 TP1806.1
CPU_DP1_CTRL_CLK: CPU1.L13 Q5702.4 RN801.3(B)
CPU_DP1_CTRL_DATA: CPU1.L12 Q5702.1 RN801.4(B)
CPU_DP1_HPD: CPU1.L9 R5712.1
CPU_DP2_CTRL_CLK: CPU1.N7 RN803.4(B)
CPU_DP2_CTRL_DATA: CPU1.N8 RN803.3(B)
CPU_DP2_HPD: CPU1.L7 R806.1 R5605.2
CPU_POPIRCOMP: CPU1.AT16 R412.2
CPVDD: C2704.1 C2705.1 HDA27.29 R2709.2
CPVEE: C2709.2 HDA27.27
CRT_B: AFTP5606.1 C5618.1 ED5601.1 EL5602.2 VGA1.3
CRT_DDCCLK_CON: AFTP5608.1 C5607.1 R5602.2 RN5601.2(A) VGA1.15
CRT_DDCCLK_CON_R: R5602.1 U5601.15
CRT_DDCDATA_CON: AFTP5609.1 C5622.1 R5603.2 RN5601.1(A) VGA1.12
CRT_DDCDATA_CON_R: R5603.1 U5601.16
CRT_G: AFTP5607.1 C5614.1 ED5603.1 EL5603.2 VGA1.2
CRT_HSYNC_CON: AFTP5603.1 C5617.1 R5612.2 VGA1.13
CRT_PCH_HPD: R5605.1 U5601.32
CRT_R: AFTP5605.1 C5619.1 ED5602.1 EL5601.2 VGA1.1
CRT_VSYNC_CON: AFTP5602.1 C5616.1 R5611.2 VGA1.14
CSA0B_0: GPU1.H22 VRAM1.G12
CSA1B_0: GPU1.G13 VRAM2.L12
CSI2_COMP: CPU1.E13 R1501.1
DAT_TP_SIO: EC6501.1 KBC24.79 RN6503.2(A) RN6504.3(B)
DBC_EN_R: LCD1.8 R5518.1
DBC_PANEL_EN: CPU1.AM5 R2003.2 R5518.2
DC_IN_D: PQ4405.3 PR4420.2
DCBATOUT: EC9701.1 EC9702.1 EC9703.1 EC9704.1 EC9705.1 EC9706.1 EC9707.1 EC9708.1 EC9709.1 EC9710.1 EC9711.1 EC9712.1 EC9713.1 EC9714.1 EC9715.1 EC9716.1 EC9717.1 EC9740.1 EC9741.2 EC9742.1 EC9747.2 EC9748.1 EC9749.2 F5503.1 PC4418.1 PC4427.1 PC4438.1 PC4456.1 PC4459.1 PC4519.1 PC4531.1 PG4407.2 PG4518.2 PG4520.2 PG4521.2 PG4524.2 PG4525.2 PG4531.2 PG4534.2 PG4536.2 PG4542.2 PG4543.2 PG4701.1 PG4702.1 PG4703.1 PG4704.1 PG4705.1 PG4706.1 PG4802.2 PG4803.2 PG4804.2 PG4805.2 PG4806.2 PG4810.2 PG4811.2 PG4812.2 PG4814.2 PG4816.2 PG5002.2 PG5003.2 PG5117.1 PG5118.1 PG5301.1 PG5302.1 PG5303.1 PG8501.1 PG8502.1 PG8503.1 PG8504.1 PG8505.1 PG8506.1 PG8511.1 PG8512.1 PG8513.1 PG8514.1 PG8515.1 PG8516.1 PG8651.1 PG8652.1 PQ4401.1 PQ4401.2 PQ4401.3 PR4426.2 PR4459.1 PR4477.1 PR4612.1 PT4805.1 PT4806.1 PT8901.1 PT8902.1 PU4411.5 PU4411.6 PU4411.7 PU4411.8 PU4503.12
DCBATOUT_LCD: C5515.1 C5535.1 F5503.2 LCD1.1 LCD1.2
DDBIA0_0: GPU1.H27 VRAM1.P13
DDBIA0_1: GPU1.A27 VRAM1.P2
DDBIA0_2: GPU1.C23 VRAM1.D13
DDBIA0_3: GPU1.C19 VRAM1.D2
DDBIA1_0: GPU1.C15 VRAM2.P2
DDBIA1_1: GPU1.E9 VRAM2.P13
DDBIA1_2: GPU1.C5 VRAM2.D2
DDBIA1_3: GPU1.H4 VRAM2.D13
DDC_CLK_HDMI: ED5703.4 ED5703.7 HDMI1.15 Q5702.3 RN5702.4(B)
DDC_CLK_PH1: D5701.2 RN5702.1(A)
DDC_DATA_HDMI: ED5703.1 ED5703.10 HDMI1.16 Q5702.6 RN5702.3(B)
DDC_DATA_PH2: D5701.1 RN5702.2(A)
DDPD_CTRLDATA: CPU1.N12 TP802.1
DDR4_DRAMRST#: DM1.108 DM2.108 ED1217.1 ED1302.1 R504.2
DGPU_HOLD_RST#: CPU1.P3 D7601.2 EC2002.2 R7623.1 RN2009.4(B)
DGPU_PWR_EN: CPU1.U1 PD8501.K PR8661.1 RN2009.3(B)
DGPU_PWR_EN_R: PC8602.1 PQ8604.2 PR8661.2
DGPU_PWROK: CPU1.C8 EC1903.2 PR8520.2 R1904.2 R2427.2 R7904.1
DGPU_PWROK_EC: KBC24.23 R2427.1
DGPU_PWROK_R: Q7903.G R7904.2 R7942.2
DMIC_CLK: C2725.1 EC5501.1 R2720.1 R5503.2
DMIC_CLK_EDP: LCD1.27 R5503.1
DMIC_CLK_R: HDA27.3 R2720.2
DMIC_DATA: EC2711.1 EC5502.1 R2718.1 R5502.2
DMIC_DATA_EDP: LCD1.28 R5502.1
DMIC_DATA_R: HDA27.2 R2718.2
DP_CRT_B: C5613.1 EL5602.1 R5607.1 U5601.21
DP_CRT_G: C5611.1 EL5603.1 R5608.1 U5601.22
DP_CRT_HSYNC_CON: R5612.1 U5601.19
DP_CRT_R: C5612.1 EL5601.1 R5606.1 U5601.23
DP_CRT_VSYNC_CON: R5611.1 U5601.18
DPLL_PVDD: C7710.1 C7711.1 C7713.1 GPU1.AF14 R7704.2
DPLL_VDDC: C7714.1 C7715.1 GPU1.AD14 R7705.2
DQA0_0: GPU1.K27 VRAM1.M13
DQA0_1: GPU1.J29 VRAM1.N13
DQA0_2: GPU1.H30 VRAM1.T13
DQA0_3: GPU1.H32 VRAM1.U13
DQA0_4: GPU1.G29 VRAM1.U11
DQA0_5: GPU1.F28 VRAM1.T11
DQA0_6: GPU1.F32 VRAM1.M11
DQA0_7: GPU1.F30 VRAM1.N11
DQA0_8: GPU1.C30 VRAM1.U2
DQA0_9: GPU1.F27 VRAM1.N2
DQA0_10: GPU1.A28 VRAM1.T2
DQA0_11: GPU1.C28 VRAM1.T4
DQA0_12: GPU1.E27 VRAM1.M2
DQA0_13: GPU1.G26 VRAM1.M4
DQA0_14: GPU1.D26 VRAM1.N4
DQA0_15: GPU1.F25 VRAM1.U4
DQA0_16: GPU1.A25 VRAM1.A11
DQA0_17: GPU1.C25 VRAM1.B13
DQA0_18: GPU1.E25 VRAM1.B11
DQA0_19: GPU1.D24 VRAM1.A13
DQA0_20: GPU1.E23 VRAM1.F13
DQA0_21: GPU1.F23 VRAM1.E13
DQA0_22: GPU1.D22 VRAM1.F11
DQA0_23: GPU1.F21 VRAM1.E11
DQA0_24: GPU1.E21 VRAM1.E4
DQA0_25: GPU1.D20 VRAM1.F4
DQA0_26: GPU1.F19 VRAM1.F2
DQA0_27: GPU1.A19 VRAM1.E2
DQA0_28: GPU1.D18 VRAM1.A2
DQA0_29: GPU1.F17 VRAM1.B2
DQA0_30: GPU1.A17 VRAM1.A4
DQA0_31: GPU1.C17 VRAM1.B4
DQA1_0: GPU1.E17 VRAM2.U4
DQA1_1: GPU1.D16 VRAM2.T4
DQA1_2: GPU1.F15 VRAM2.T2
DQA1_3: GPU1.A15 VRAM2.U2
DQA1_4: GPU1.D14 VRAM2.N2
DQA1_5: GPU1.F13 VRAM2.M2
DQA1_6: GPU1.A13 VRAM2.M4
DQA1_7: GPU1.C13 VRAM2.N4
DQA1_8: GPU1.E11 VRAM2.M13
DQA1_9: GPU1.A11 VRAM2.M11
DQA1_10: GPU1.C11 VRAM2.N13
DQA1_11: GPU1.F11 VRAM2.T13
DQA1_12: GPU1.A9 VRAM2.N11
DQA1_13: GPU1.C9 VRAM2.T11
DQA1_14: GPU1.F9 VRAM2.U13
DQA1_15: GPU1.D8 VRAM2.U11
DQA1_16: GPU1.E7 VRAM2.E2
DQA1_17: GPU1.A7 VRAM2.A2
DQA1_18: GPU1.C7 VRAM2.A4
DQA1_19: GPU1.F7 VRAM2.F2
DQA1_20: GPU1.A5 VRAM2.B4
DQA1_21: GPU1.E5 VRAM2.B2
DQA1_22: GPU1.C3 VRAM2.E4
DQA1_23: GPU1.E1 VRAM2.F4
DQA1_24: GPU1.G7 VRAM2.E13
DQA1_25: GPU1.G6 VRAM2.F11
DQA1_26: GPU1.G1 VRAM2.A11
DQA1_27: GPU1.G3 VRAM2.E11
DQA1_28: GPU1.J6 VRAM2.F13
DQA1_29: GPU1.J1 VRAM2.B11
DQA1_30: GPU1.J3 VRAM2.B13
DQA1_31: GPU1.J5 VRAM2.A13
DRAM_RST: R7802.2 R7804.1 VRAM1.J2 VRAM2.J2
DRAM_RST_R: C7802.1 R7803.1 R7804.2
DRAM_RST_VGA1: C7803.1 GPU1.L10 R7803.2 R7819.1
E51_RX1: TP6102.1 WLAN1.46
E51_RX2: TP6103.1 WLAN1.58
E51_TX1: R6115.2 WLAN1.44
E51_TXD_R: DB3.5 R2466.2
EC_AGND: C2407.2 C2408.2 C2422.2 C2435.2 C2441.2 KBC24.112 R2441.2 R2444.2 R2445.2
EC_BRIGHTNESS: D5503.2 R2456.1
EDCA0_0: GPU1.H28 VRAM1.R13
EDCA0_1: GPU1.C27 VRAM1.R2
EDCA0_2: GPU1.A23 VRAM1.C13
EDCA0_3: GPU1.E19 VRAM1.C2
EDCA1_0: GPU1.E15 VRAM2.R2
EDCA1_1: GPU1.D10 VRAM2.R13
EDCA1_2: GPU1.D6 VRAM2.C2
EDCA1_3: GPU1.G5 VRAM2.C13
EDP_AUX_CON_N: C5533.2 LCD1.12 R5529.1
EDP_AUX_CON_P: C5531.2 LCD1.11 R5528.1
EDP_AUX_CPU_N: C5533.1 CPU1.E45
EDP_AUX_CPU_P: C5531.1 CPU1.F45
EDP_BKLT_CTRL: D5503.1 R5524.2 R5530.2
EDP_COMP: CPU1.E52 R801.2
EDP_DISP_UTIL: CPU1.B52 TP801.1
EDP_HPD: CPU1.L10 RN5502.6(B) RN5503.3(B)
EDP_HPD_CONN: LCD1.9 RN5503.2(A)
EDP_TX_CON_N0: C5508.2 LCD1.14
EDP_TX_CON_N1: C5534.2 LCD1.17
EDP_TX_CON_P0: C5532.2 LCD1.15
EDP_TX_CON_P1: C5537.2 LCD1.18
EDP_TX_CPU_N0: C5508.1 CPU1.C47
EDP_TX_CPU_N1: C5534.1 CPU1.D46
EDP_TX_CPU_P0: C5532.1 CPU1.C46
EDP_TX_CPU_P1: C5537.1 CPU1.C45
EDP_VDD_EN: CPU1.U13 D5502.1
EDRAM_OPIO_RCOMP: CPU1.H66 R414.2
EMMC_CLK: CPU1.AM3 R6320.1
EMMC_CLK_R: R6320.2 U6301.M6
EMMC_CMD: CPU1.AP4 R6321.1
EMMC_CMD_R: R6321.2 U6301.M5
EMMC_D0: CPU1.AP2 R6312.2
EMMC_D0_R: R6312.1 U6301.A3
EMMC_D1: CPU1.AP1 R6313.2
EMMC_D1_R: R6313.1 U6301.A4
EMMC_D2: CPU1.AP3 R6314.2
EMMC_D2_R: R6314.1 U6301.A5
EMMC_D3: CPU1.AN3 R6316.2
EMMC_D3_R: R6316.1 U6301.B2
EMMC_D4: CPU1.AN1 R6317.2
EMMC_D4_R: R6317.1 U6301.B3
EMMC_D5: CPU1.AN2 R6318.2
EMMC_D5_R: R6318.1 U6301.B4
EMMC_D6: CPU1.AM4 R6319.2
EMMC_D6_R: R6319.1 U6301.B5
EMMC_D7: CPU1.AM1 R6315.2
EMMC_D7_R: R6315.1 U6301.B6
EMMC_E9: TP6301.1 U6301.E9
EMMC_E10: TP6302.1 U6301.E10
EMMC_F10: TP6303.1 U6301.F10
EMMC_K10: TP6304.1 U6301.K10
EMMC_RCLK: CPU1.AM2 R6322.1
EMMC_RCLK_R: R6322.2 U6301.H5
EMMC_RCOMP: CPU1.AT1 R1502.1
EMMC_RESET#: Q6301.S R6323.2 R6324.1 U6301.K5
EMMC_VCC: C6318.1 C6319.1 R6325.2 U6301.E6 U6301.F5 U6301.J10 U6301.K9
EMMC_VCCQ: C6316.1 C6317.1 R6311.2 R6323.1 U6301.C6 U6301.M4 U6301.N4 U6301.P3 U6301.P5
EMMC_VDDI: C6320.1 U6301.C2
EN/DEM_VGA: D8602.2 PC8502.2 PD8501.A PQ8501.2 PR8503.2 PR8514.1
EOPIO_RCOMP: CPU1.H65 R415.2
ESPI_ALERT#: CPU1.AY11 KBC24.55 R2410.2
ESPI_CLK: EC1802.1 KBC24.57 R1804.2
ESPI_CLK_CON: DBG1.2 TP6801.1
ESPI_CLK_CPU: CPU1.AW9 R1804.1
ESPI_CS#: KBC24.58 R1801.2
ESPI_CS#_CON: DBG1.5 TP6803.1
ESPI_CS#_CPU: CPU1.BA12 R1801.1
ESPI_IO0: KBC24.59 R1829.2
ESPI_IO0_CON: DBG1.9 TP6807.1
ESPI_IO0_CPU: CPU1.AY13 R1829.1
ESPI_IO1: KBC24.60 R1830.2
ESPI_IO1_CON: DBG1.8 TP6806.1
ESPI_IO1_CPU: CPU1.BA13 R1830.1
ESPI_IO2: KBC24.61 R1831.2
ESPI_IO2_CON: DBG1.7 TP6805.1
ESPI_IO2_CPU: CPU1.BB13 R1831.1
ESPI_IO3: KBC24.62 R1833.2
ESPI_IO3_CON: DBG1.6 TP6804.1
ESPI_IO3_CPU: CPU1.AY12 R1833.1
ESPI_RESET#: KBC24.53 R1826.2
ESPI_RESET#_CON: DBG1.4 TP6802.1
ESPI_RESET#_CPU: CPU1.BA11 R1826.1
EXT_CLK_IN_CRT: R5616.1 U5601.28
EXT_PWR_GATE#: CPU1.AM10 R1731.2
FALL_INT2: Q6701.2 Q6701.3 R6703.2
FAN1_DAC_1: C2401.1 FAN261.4 R2403.2
FAN1_PWM: KBC24.47 R2403.1
FAN1_TACH: D2403.A KBC24.40 R2430.2 R2461.1
FAN2_PWMVOL_LP#: KBC24.34 R2486.1
FAN_TACH1: D2403.K EC2602.1 R2461.2 R2606.1
FAN_TACH1_C: AFTP2602.1 FAN1.2 R2606.2
FAN_VCC1: AFTP2603.1 C2603.1 C2604.1 D2601.K EC2601.1 FAN1.1 FAN261.3
FFS_INT2: CPU1.AC2 Q6701.5 R6704.2 R6706.2 R6707.1 U6701.11
FFS_INT2_Q: HDD1.1 Q6701.6 R6705.2 R6706.1
FON#: FAN261.1 R2605.2
FP_PWR: AFTP8902.1 C9201.1 C9202.1 FPR1.1 FPR1.2 R9202.2
FPR_SCAN#: KBC24.42 R2412.2
GPD2/LAN_WAKE#: CPU1.AM15 R1707.2 R1710.2
GPD9/SLP_WLAN#: CPU1.BB17 TP1705.1
GPD11/LANPHYPC: CPU1.AW17 RN1704.5(B)
GPIO16_VGA: GPU1.M4 TP7903.1
GPIO_5_AC_BATT: GPU1.T9 Q7902.D R7913.2 R7921.2
GPIO_8_ROMSO: GPU1.P10 TP7905.1
GPIO_9_ROMSI: GPU1.P4 TP7906.1
GPIO_10_ROMSCK: GPU1.P2 TP7901.1
GPIO_17_THERMAL_INT: GPU1.R6 TP7923.1
GPIO_19_CTF: GPU1.M2 R7922.2
GPIO_22_ROMCS#: GPU1.N8 TP7910.1
GPP_B4/CPU_GP3: CPU1.AY5 TP404.1
GPP_B18/GSPI0_MOSI: CPU1.AR7 R2007.2 R2019.1
GPP_B22: CPU1.AN5 TP2008.1
GPP_B23/SML1ALERT#: CPU1.AM7 R1820.1
GPP_C2/SMBALERT#: CPU1.R10 R1821.1
GPP_C5/SML0ALERT#: CPU1.W1 R1822.2 R1823.1
GPP_E0/SATAXPCIE0/SATAGP0: CPU1.H2 TP1603.1
GPU_ALERT#: R2613.2 THM262.6
GPU_DMINUS: GPU1.T2 TP7914.1
GPU_DPLUS: GPU1.T4 TP7909.1
GPU_DPRSLP: R7911.1 TP7918.1
GPU_DPRSLP_R: GPU1.U6 R7911.2
GPU_PWR_LEVEL: KBC24.10 R7937.1
GPU_PWR_LEVEL_R: Q7902.G R7937.2
GPU_T_CRIT#: R2614.2 R2615.1 THM262.4
GPU_T_CRIT_R#: Q2605.S R2615.2
GPU_THM_SMBCLK: KBC24.12 R2439.1
GPU_THM_SMBDAT: KBC24.11 R2438.1
GT_CORE: CPU1.A48 CPU1.A53 CPU1.J43 CPU1.J45 CPU1.J46 CPU1.J48 CPU1.J50 CPU1.J52 CPU1.K48 CPU1.K50 R718.2 R719.1
GTX_CORE: CPU1.AK42 CPU1.AK43 CPU1.AK45 CPU1.AK46 CPU1.AK48 CPU1.AK50 CPU1.AL43 CPU1.AL46 CPU1.AL50 CPU1.AM48 CPU1.AM50 CPU1.AM52 R720.2
H_CATERR#: CPU1.D63 TP401.1
H_CPU_SVIDALRT#: CPU1.B63 R728.1
H_CPU_SVIDCLK: CPU1.A63 R732.1
H_CPU_SVIDDAT: CPU1.D64 R709.1 R726.2
H_CPUPWRGD: CPU1.A68 R1720.2
H_PECI: CPU1.A54 R2437.2
H_PECI_R: C2405.1 KBC24.94 R2437.1
H_PROCHOT#: C2403.1 PR4415.1 PR4450.2 PR4458.2 PR4603.2 PR4607.1 PU4401.5 R401.2 R403.1 R2416.2
H_PROCHOT#_EC: Q2408.D R2416.1 R2418.2
H_PROCHOT#_R: CPU1.C65 R403.2
H_VCCST_PWRGD: CPU1.B65 R1734.2
H_VCCST_PWRGD_R: EC1708.1 R1716.2 R1719.1 R1722.2 R1734.1
H_VID3: GPU1.AK10 TP7919.1
H_VID4: GPU1.AM10 TP7920.1
HDA_BITCLK: CPU1.AY22 R1907.2
HDA_BITCLK_CODEC_R: HDA27.5 R2723.2
HDA_CODEC_BITCLK: EC1901.2 EC2710.1 R1907.1 R2723.1
HDA_CODEC_SDIN0: HDA27.7 R2724.2
HDA_CODEC_SDOUT: EC2709.1 R1912.1 R2722.1
HDA_CODEC_SYNC: HDA27.9 R1908.1
HDA_SDIN0: CPU1.BA21 FC1902.1 R2724.1
HDA_SDOUT: CPU1.BB22 FC1901.1 R1909.2 R1912.2
HDA_SDOUT_CODEC_R: HDA27.4 R2722.2
HDA_SPKR_R: D2703.1 R2741.2
HDA_SYNC: CPU1.BA22 R1908.2
HDD_DEVSLP: CPU1.J1 R6002.1
HDD_DEVSLP_R: HDD1.5 R6002.2
HDD_FALL_INT: CPU1.M3 R6702.2 U6701.12
HDMI_CLK: C5704.1 CPU1.G56
HDMI_CLK#: C5701.1 CPU1.F56
HDMI_CLK#_R: C5701.2 ER5714.1 RN5701.7(B)
HDMI_CLK#_R_C: ED5702.2 ED5702.9 ER5714.2 HDMI1.12 R5702.2
HDMI_CLK_R: C5704.2 ER5706.1 RN5701.8(B)
HDMI_CLK_R_C: ED5702.1 ED5702.10 ER5706.2 HDMI1.10 R5702.1
HDMI_DATA0: C5703.1 CPU1.G53
HDMI_DATA0#: C5705.1 CPU1.F53
HDMI_DATA0#_R: C5705.2 ER5715.1 RN5701.5(B)
HDMI_DATA0#_R_C: ED5702.5 ED5702.6 ER5715.2 HDMI1.9 R5701.2
HDMI_DATA0_R: C5703.2 ER5713.1 RN5701.6(B)
HDMI_DATA0_R_C: ED5702.4 ED5702.7 ER5713.2 HDMI1.7 R5701.1
HDMI_DATA1: C5706.1 CPU1.F58
HDMI_DATA1#: C5707.1 CPU1.E58
HDMI_DATA1#_R: C5707.2 ER5704.1 RN5703.5(B)
HDMI_DATA1#_R_C: ED5701.5 ED5701.6 ER5704.2 HDMI1.6 R5708.2
HDMI_DATA1_R: C5706.2 ER5705.1 RN5703.6(B)
HDMI_DATA1_R_C: ED5701.4 ED5701.7 ER5705.2 HDMI1.4 R5708.1
HDMI_DATA2: C5709.1 CPU1.F55
HDMI_DATA2#: C5708.1 CPU1.E55
HDMI_DATA2#_R: C5708.2 ER5716.1 RN5703.7(B)
HDMI_DATA2#_R_C: ED5701.2 ED5701.9 ER5716.2 HDMI1.3 R5703.2
HDMI_DATA2_R: C5709.2 ER5717.1 RN5703.8(B)
HDMI_DATA2_R_C: ED5701.1 ED5701.10 ER5717.2 HDMI1.1 R5703.1
HDMI_HPD_B: Q5703.B R5710.2
HDMI_HPD_E: Q5703.E R5709.1 R5712.2
HDMI_PLL_GND: Q5701.D R5707.1 RN5701.1(A) RN5701.2(A) RN5701.3(A) RN5701.4(A) RN5703.1(A) RN5703.2(A) RN5703.3(A) RN5703.4(A)
HOST_DEBUG_TX: KBC24.81 R2466.1 R2478.2 R6115.1 R6807.1
HOST_DEBUG_TX_CON: DBG1.11 R6807.2
HPD_HDMI_CON: ED5703.2 ED5703.9 HDMI1.19 R5710.1 R5711.1
HW_ACAV_IN: KBC24.128 R2469.1
HW_ACAVIN_NB: KBC24.24 TP2405.1
I2C0_SCL: CPU1.N3 RN2007.1(A)
I2C0_SCL_TCH_PAD: CPU1.U6 EC6504.1 Q6503.1 R6518.1 RN2010.3(B)
I2C0_SDA: CPU1.M4 RN2007.2(A)
I2C0_SDA_TCH_PAD: CPU1.U7 EC6502.1 Q6503.4 R6519.1 RN2010.4(B)
I2C1_SCL: CPU1.N2 RN2008.1(A)
I2C1_SCL_R: AFTP6528.1 Q6503.6 R6515.2 R6518.2 RN6502.4(B) TP1.3
I2C1_SDA: CPU1.N1 RN2008.2(A)
I2C1_SDA_R: AFTP6527.1 Q6503.3 R6511.2 R6519.2 RN6502.3(B) TP1.2
I_ADP: C2435.1 KBC24.110 R2421.1
I_BATT: C2441.1 KBC24.114 R2423.1
ICSP_CLK: KBC24.101 R2463.1
ICSP_CLK_R: DB3.2 R2463.2
ICSP_CLR: KBC24.87 R2414.2 R2465.1
ICSP_DAT: KBC24.102 R2464.1
ICSP_DATA_R: DB3.3 R2464.2
ICSP_MCLR_R: DB3.6 R2465.2
INT_TP#: AFTP6525.1 R410.1 R2431.1 R6514.2 TP1.5
ISOLATE#: LOM31.20 R3109.1 R3113.1
ITP_PMODE: CPU1.E8 TP638.1
JACK_PLUG: AFTP6607.1 IOBD1.27 R2923.1
JET_SVC: GPU1.P8 R7919.2
JET_SVD: GPU1.N1 R7920.2
JGND: AFTP4301.1 AFTP4315.1 DCIN1.5 DCIN1.6 EC4301.2 EC4302.2 EL4303.1 EL4304.1
JTAG_TCK_VGA: GPU1.L3 TP7911.1
JTAG_TDI_VGA: GPU1.L5 TP7908.1
JTAG_TDO_VGA: GPU1.K4 TP7913.1
JTAG_TMS_VGA: GPU1.L1 TP7912.1
JTAG_TRST#_VGA: GPU1.L6 TP7907.1
KB_DET#: AFTP6519.1 CPU1.BB7 KB1.30 R2001.1
KB_LED_PWM: KBC24.44 TP2407.1
KBC_BEEP_R: D2703.2 R2734.2
KBC_PWRBTN#: R2432.1 RN6401.2(A)
KBC_PWRBTN#_C: AFTP6404.1 EC6403.1 ED6401.1 G6401.1 G6402.1 PWR1.2 RN6401.3(B)
KSI0: AFTP6507.1 KB1.22 KBC24.98 RN2404.5(B)
KSI1: AFTP6540.1 KB1.24 KBC24.99 RN2404.7(B)
KSI2: AFTP6533.1 KB1.26 KBC24.6 RN2403.5(B)
KSI3: AFTP6502.1 KB1.23 KBC24.7 RN2404.6(B)
KSI4: AFTP6521.1 KB1.27 KBC24.104 RN2403.6(B)
KSI5: AFTP6513.1 KB1.25 KBC24.105 RN2404.8(B)
KSI6: AFTP6511.1 KB1.28 KBC24.107 RN2403.7(B)
KSI7: AFTP6523.1 KB1.29 KBC24.108 RN2403.8(B)
KSO0: AFTP6520.1 KB1.13 KBC24.2 RN2406.8(B)
KSO1: AFTP6517.1 KB1.15 KBC24.14 RN2408.6(B)
KSO2: AFTP6510.1 KB1.14 KBC24.15 RN2408.5(B)
KSO3: AFTP6518.1 KB1.16 KBC24.16 RN2408.7(B)
KSO4: AFTP6522.1 KB1.20 KBC24.37 RN2409.7(B)
KSO5: AFTP6536.1 KB1.21 KBC24.38 RN2409.8(B)
KSO6: AFTP6512.1 KB1.18 KBC24.39 RN2409.5(B)
KSO7: AFTP6534.1 KB1.19 KBC24.50 RN2409.6(B)
KSO8: AFTP6505.1 KB1.17 KBC24.46 RN2408.8(B)
KSO9: AFTP6516.1 KB1.7 KBC24.68 R2449.1 R2450.2
KSO10: AFTP6503.1 KB1.5 KBC24.72 RN2407.5(B)
KSO11: AFTP6506.1 KB1.6 KBC24.74 RN2407.6(B)
KSO12: AFTP6538.1 KB1.12 KBC24.75 RN2406.7(B)
KSO13: AFTP6535.1 KB1.9 KBC24.76 RN2407.8(B)
KSO14: AFTP6539.1 KB1.8 KBC24.77 RN2407.7(B)
KSO15: AFTP6515.1 KB1.10 KBC24.86 RN2406.5(B)
KSO16: AFTP6508.1 KB1.11 KBC24.92 RN2406.6(B)
L_BKLT_CTRL: CPU1.R11 R5530.1
L_BKLT_EN: CPU1.R12 R2435.1
LAN_CLKREQ_LAN#: LOM31.12 R3105.2
LAN_ENABLE_R_C: Q3102.D R3106.2 R3111.1
LAN_MDI0N: ED3202.2 ED3202.9 LOM31.2 XF3202.11
LAN_MDI0P: ED3202.1 ED3202.10 LOM31.1 XF3202.12
LAN_MDI1N: ED3202.5 ED3202.6 LOM31.5 XF3202.7
LAN_MDI1P: ED3202.4 ED3202.7 LOM31.4 XF3202.8
LAN_MDI2N: ED3201.2 ED3201.9 LOM31.7 XF3201.8
LAN_MDI2P: ED3201.1 ED3201.10 LOM31.6 XF3201.7
LAN_MDI3N: ED3201.5 ED3201.6 LOM31.10 XF3201.12
LAN_MDI3P: ED3201.4 ED3201.7 LOM31.9 XF3201.11
LANWAKE#: KBC24.35 R1710.1
LANXIN: C3125.1 LOM31.28 X3101.1
LANXOUT: C3116.1 LOM31.29 X3101.3
LCD_BRIGHTNESS: EC5504.1 LCD1.20 RN5501.2(A)
LCD_TST: KBC24.26 R2419.2 R2456.2
LCD_TST_C: LCD1.10 RN5501.1(A)
LCD_TST_R: R2419.1 RN5501.4(B)
LCD_VCC_TEST_EN: D5502.2 R2495.2
LCD_VCC_TEST_EN_R: KBC24.113 R2487.1 R2495.1
LCDVDD: C5506.1 R5523.2 U5501.3
LCDVDD_EN: D5502.3 R5506.1 U5501.1
LCDVDD_LCD: C5536.1 C5538.1 LCD1.4 LCD1.5 LCD1.6 LCD1.7 R5523.1
LDO1_CAP: C2703.1 HDA27.21 R2702.1
LDO2_CAP: C2711.1 HDA27.32
LDO3_CAP: C2722.1 HDA27.6
LED0: LOM31.27 TP3103.1
LED1: LOM31.26 TP3102.1
LED2: LOM31.25 TP3101.1
LID_CL_SIO#: D2402.K KBC24.66 RN2405.3(A) RN6401.1(A)
LID_CLOSE#_C: AFTP6401.1 EC6401.1 PWR1.3 RN6401.4(B)
LINE1-L_C: C2907.2 R2922.1
LINE1-L_R: C2908.2 R2921.1
LINE1_L: C2907.1 HDA27.18
LINE1_R: C2908.1 HDA27.17
LINE1_VREFO: D2901.3 HDA27.24
LINE1_VREFO_D1: D2901.1 R2912.1
LINE1_VREFO_D2: D2901.2 R2913.1
LOM_TCT: C3201.1 XF3201.9 XF3201.10 XF3202.9 XF3202.10
LPSS_UART2_CTS#: CPU1.AD4 R2046.2
M_A_A0: CPU1.AY50 DM1.144
M_A_A1: CPU1.BB50 DM1.133
M_A_A2: CPU1.AY51 DM1.132
M_A_A3: CPU1.BA50 DM1.131
M_A_A4: CPU1.BB52 DM1.128
M_A_A5: CPU1.BA51 DM1.126
M_A_A6: CPU1.BA52 DM1.127
M_A_A7: CPU1.AW52 DM1.122
M_A_A8: CPU1.AY52 DM1.125
M_A_A9: CPU1.BB54 DM1.121
M_A_A10: CPU1.AT50 DM1.146
M_A_A11: CPU1.BA54 DM1.120
M_A_A12: CPU1.AW54 DM1.119
M_A_A13: CPU1.AU46 DM1.158
M_A_A14: CPU1.AT46 DM1.151
M_A_A15: CPU1.AU48 DM1.156
M_A_A16: CPU1.AU50 DM1.152
M_A_ACT_N: CPU1.BA55 DM1.114
M_A_ALERT_N: CPU1.AW50 DM1.116
M_A_BA0: CPU1.AU52 DM1.150
M_A_BA1: CPU1.AT48 DM1.145
M_A_BG0: CPU1.AY55 DM1.115
M_A_BG1: CPU1.AY54 DM1.113
M_A_CKE0: CPU1.BA56 DM1.109
M_A_CKE1: CPU1.BB56 DM1.110
M_A_CLK0: CPU1.AT53 DM1.137
M_A_CLK1: CPU1.AT55 DM1.138
M_A_CLK#0: CPU1.AU53 DM1.139
M_A_CLK#1: CPU1.AU55 DM1.140
M_A_CS#0: CPU1.AU45 DM1.149
M_A_CS#1: CPU1.AU43 DM1.157
M_A_DIMA_ODT0: CPU1.AT45 DM1.155
M_A_DIMA_ODT1: CPU1.AT43 DM1.161
M_A_DQ0: CPU1.AL71 DM1.8
M_A_DQ1: CPU1.AL68 DM1.7
M_A_DQ2: CPU1.AN68 DM1.20
M_A_DQ3: CPU1.AN69 DM1.21
M_A_DQ4: CPU1.AL70 DM1.4
M_A_DQ5: CPU1.AL69 DM1.3
M_A_DQ6: CPU1.AN70 DM1.16
M_A_DQ7: CPU1.AN71 DM1.17
M_A_DQ8: CPU1.AR70 DM1.28
M_A_DQ9: CPU1.AR68 DM1.29
M_A_DQ10: CPU1.AU71 DM1.41
M_A_DQ11: CPU1.AU68 DM1.42
M_A_DQ12: CPU1.AR71 DM1.24
M_A_DQ13: CPU1.AR69 DM1.25
M_A_DQ14: CPU1.AU70 DM1.38
M_A_DQ15: CPU1.AU69 DM1.37
M_A_DQ16: CPU1.BB65 DM1.50
M_A_DQ17: CPU1.AW65 DM1.49
M_A_DQ18: CPU1.AW63 DM1.62
M_A_DQ19: CPU1.AY63 DM1.63
M_A_DQ20: CPU1.BA65 DM1.46
M_A_DQ21: CPU1.AY65 DM1.45
M_A_DQ22: CPU1.BA63 DM1.58
M_A_DQ23: CPU1.BB63 DM1.59
M_A_DQ24: CPU1.BA61 DM1.70
M_A_DQ25: CPU1.AW61 DM1.71
M_A_DQ26: CPU1.BB59 DM1.83
M_A_DQ27: CPU1.AW59 DM1.84
M_A_DQ28: CPU1.BB61 DM1.66
M_A_DQ29: CPU1.AY61 DM1.67
M_A_DQ30: CPU1.BA59 DM1.79
M_A_DQ31: CPU1.AY59 DM1.80
M_A_DQ32: CPU1.AY39 DM1.174
M_A_DQ33: CPU1.AW39 DM1.173
M_A_DQ34: CPU1.AY37 DM1.187
M_A_DQ35: CPU1.AW37 DM1.186
M_A_DQ36: CPU1.BB39 DM1.170
M_A_DQ37: CPU1.BA39 DM1.169
M_A_DQ38: CPU1.BA37 DM1.183
M_A_DQ39: CPU1.BB37 DM1.182
M_A_DQ40: CPU1.AY35 DM1.195
M_A_DQ41: CPU1.AW35 DM1.194
M_A_DQ42: CPU1.AY33 DM1.207
M_A_DQ43: CPU1.AW33 DM1.208
M_A_DQ44: CPU1.BB35 DM1.191
M_A_DQ45: CPU1.BA35 DM1.190
M_A_DQ46: CPU1.BA33 DM1.203
M_A_DQ47: CPU1.BB33 DM1.204
M_A_DQ48: CPU1.AY31 DM1.216
M_A_DQ49: CPU1.AW31 DM1.215
M_A_DQ50: CPU1.AY29 DM1.228
M_A_DQ51: CPU1.AW29 DM1.229
M_A_DQ52: CPU1.BB31 DM1.211
M_A_DQ53: CPU1.BA31 DM1.212
M_A_DQ54: CPU1.BA29 DM1.224
M_A_DQ55: CPU1.BB29 DM1.225
M_A_DQ56: CPU1.AY27 DM1.237
M_A_DQ57: CPU1.AW27 DM1.236
M_A_DQ58: CPU1.AY25 DM1.249
M_A_DQ59: CPU1.AW25 DM1.250
M_A_DQ60: CPU1.BB27 DM1.232
M_A_DQ61: CPU1.BA27 DM1.233
M_A_DQ62: CPU1.BA25 DM1.245
M_A_DQ63: CPU1.BB25 DM1.246
M_A_DQS_DN0: CPU1.AM70 DM1.11
M_A_DQS_DN1: CPU1.AT69 DM1.32
M_A_DQS_DN2: CPU1.BA64 DM1.53
M_A_DQS_DN3: CPU1.AY60 DM1.74
M_A_DQS_DN4: CPU1.BA38 DM1.177
M_A_DQS_DN5: CPU1.AY34 DM1.198
M_A_DQS_DN6: CPU1.BA30 DM1.219
M_A_DQS_DN7: CPU1.AY26 DM1.240
M_A_DQS_DP0: CPU1.AM69 DM1.13
M_A_DQS_DP1: CPU1.AT70 DM1.34
M_A_DQS_DP2: CPU1.AY64 DM1.55
M_A_DQS_DP3: CPU1.BA60 DM1.76
M_A_DQS_DP4: CPU1.AY38 DM1.179
M_A_DQS_DP5: CPU1.BA34 DM1.200
M_A_DQS_DP6: CPU1.AY30 DM1.221
M_A_DQS_DP7: CPU1.BA26 DM1.242
M_A_PARITY: CPU1.AT52 DM1.143
M_B_A0: CPU1.BA46 DM2.144
M_B_A1: CPU1.AY46 DM2.133
M_B_A2: CPU1.AY47 DM2.132
M_B_A3: CPU1.BB46 DM2.131
M_B_A4: CPU1.BA47 DM2.128
M_B_A5: CPU1.AY48 DM2.126
M_B_A6: CPU1.BA48 DM2.127
M_B_A7: CPU1.AP48 DM2.122
M_B_A8: CPU1.BB48 DM2.125
M_B_A9: CPU1.AP50 DM2.121
M_B_A10: CPU1.AW46 DM2.146
M_B_A11: CPU1.AN48 DM2.120
M_B_A12: CPU1.AN50 DM2.119
M_B_A13: CPU1.BA43 DM2.158
M_B_A14: CPU1.AY44 DM2.151
M_B_A15: CPU1.AY43 DM2.156
M_B_A16: CPU1.AW44 DM2.152
M_B_ACT_N: CPU1.AN53 DM2.114
M_B_ALERT_N: CPU1.AN43 DM2.116
M_B_BA0: CPU1.BB44 DM2.150
M_B_BA1: CPU1.BA44 DM2.145
M_B_BG0: CPU1.AP52 DM2.115
M_B_BG1: CPU1.AN52 DM2.113
M_B_CKE0: CPU1.AN56 DM2.109
M_B_CKE1: CPU1.AP55 DM2.110
M_B_CLK0: CPU1.AP45 DM2.137
M_B_CLK1: CPU1.AP46 DM2.138
M_B_CLK#0: CPU1.AN45 DM2.139
M_B_CLK#1: CPU1.AN46 DM2.140
M_B_CS#0: CPU1.BB42 DM2.149
M_B_CS#1: CPU1.AY42 DM2.157
M_B_DIMB_ODT0: CPU1.BA42 DM2.155
M_B_DIMB_ODT1: CPU1.AW42 DM2.161
M_B_DQ0: CPU1.AF65 DM2.28
M_B_DQ1: CPU1.AF64 DM2.29
M_B_DQ2: CPU1.AK65 DM2.41
M_B_DQ3: CPU1.AK64 DM2.42
M_B_DQ4: CPU1.AF66 DM2.24
M_B_DQ5: CPU1.AF67 DM2.25
M_B_DQ6: CPU1.AK67 DM2.38
M_B_DQ7: CPU1.AK66 DM2.37
M_B_DQ8: CPU1.AF70 DM2.8
M_B_DQ9: CPU1.AF68 DM2.7
M_B_DQ10: CPU1.AH71 DM2.20
M_B_DQ11: CPU1.AH68 DM2.21
M_B_DQ12: CPU1.AF71 DM2.4
M_B_DQ13: CPU1.AF69 DM2.3
M_B_DQ14: CPU1.AH70 DM2.16
M_B_DQ15: CPU1.AH69 DM2.17
M_B_DQ16: CPU1.AT66 DM2.50
M_B_DQ17: CPU1.AU66 DM2.49
M_B_DQ18: CPU1.AP65 DM2.62
M_B_DQ19: CPU1.AN65 DM2.63
M_B_DQ20: CPU1.AN66 DM2.46
M_B_DQ21: CPU1.AP66 DM2.45
M_B_DQ22: CPU1.AT65 DM2.58
M_B_DQ23: CPU1.AU65 DM2.59
M_B_DQ24: CPU1.AT61 DM2.70
M_B_DQ25: CPU1.AU61 DM2.71
M_B_DQ26: CPU1.AP60 DM2.83
M_B_DQ27: CPU1.AN60 DM2.84
M_B_DQ28: CPU1.AN61 DM2.66
M_B_DQ29: CPU1.AP61 DM2.67
M_B_DQ30: CPU1.AT60 DM2.79
M_B_DQ31: CPU1.AU60 DM2.80
M_B_DQ32: CPU1.AU40 DM2.174
M_B_DQ33: CPU1.AT40 DM2.173
M_B_DQ34: CPU1.AT37 DM2.187
M_B_DQ35: CPU1.AU37 DM2.186
M_B_DQ36: CPU1.AR40 DM2.170
M_B_DQ37: CPU1.AP40 DM2.169
M_B_DQ38: CPU1.AP37 DM2.183
M_B_DQ39: CPU1.AR37 DM2.182
M_B_DQ40: CPU1.AT33 DM2.195
M_B_DQ41: CPU1.AU33 DM2.194
M_B_DQ42: CPU1.AU30 DM2.207
M_B_DQ43: CPU1.AT30 DM2.208
M_B_DQ44: CPU1.AR33 DM2.191
M_B_DQ45: CPU1.AP33 DM2.190
M_B_DQ46: CPU1.AR30 DM2.203
M_B_DQ47: CPU1.AP30 DM2.204
M_B_DQ48: CPU1.AU27 DM2.216
M_B_DQ49: CPU1.AT27 DM2.215
M_B_DQ50: CPU1.AT25 DM2.228
M_B_DQ51: CPU1.AU25 DM2.229
M_B_DQ52: CPU1.AP27 DM2.211
M_B_DQ53: CPU1.AN27 DM2.212
M_B_DQ54: CPU1.AN25 DM2.224
M_B_DQ55: CPU1.AP25 DM2.225
M_B_DQ56: CPU1.AT22 DM2.237
M_B_DQ57: CPU1.AU22 DM2.236
M_B_DQ58: CPU1.AU21 DM2.249
M_B_DQ59: CPU1.AT21 DM2.250
M_B_DQ60: CPU1.AN22 DM2.232
M_B_DQ61: CPU1.AP22 DM2.233
M_B_DQ62: CPU1.AP21 DM2.245
M_B_DQ63: CPU1.AN21 DM2.246
M_B_DQS_DN0: CPU1.AH66 DM2.32
M_B_DQS_DN1: CPU1.AG69 DM2.11
M_B_DQS_DN2: CPU1.AR66 DM2.53
M_B_DQS_DN3: CPU1.AR61 DM2.74
M_B_DQS_DN4: CPU1.AT38 DM2.177
M_B_DQS_DN5: CPU1.AT32 DM2.198
M_B_DQS_DN6: CPU1.AR25 DM2.219
M_B_DQS_DN7: CPU1.AR22 DM2.240
M_B_DQS_DP0: CPU1.AH65 DM2.34
M_B_DQS_DP1: CPU1.AG70 DM2.13
M_B_DQS_DP2: CPU1.AR65 DM2.55
M_B_DQS_DP3: CPU1.AR60 DM2.76
M_B_DQS_DP4: CPU1.AR38 DM2.179
M_B_DQS_DP5: CPU1.AR32 DM2.200
M_B_DQS_DP6: CPU1.AR27 DM2.221
M_B_DQS_DP7: CPU1.AR21 DM2.242
M_B_PARITY: CPU1.AP43 DM2.143
M_VREF_CA_DIMMA: C1229.1 DM1.164 R1206.1 RN1201.3(B) RN1201.4(B)
M_VREF_CA_DIMMB: C1301.1 DM2.164 R1305.1 RN1301.3(B) RN1301.4(B)
MAA0_0: GPU1.K17 VRAM1.H4
MAA0_1: GPU1.J20 VRAM1.H5
MAA0_2: GPU1.H23 VRAM1.H11
MAA0_3: GPU1.G23 VRAM1.H10
MAA0_4: GPU1.G24 VRAM1.K11
MAA0_5: GPU1.H24 VRAM1.K10
MAA0_6: GPU1.J19 VRAM1.K5
MAA0_7: GPU1.K19 VRAM1.K4
MAA0_8: GPU1.G20 VRAM1.J5
MAA1_0: GPU1.J14 VRAM2.K4
MAA1_1: GPU1.K14 VRAM2.K5
MAA1_2: GPU1.J11 VRAM2.K11
MAA1_3: GPU1.J13 VRAM2.K10
MAA1_4: GPU1.H11 VRAM2.H11
MAA1_5: GPU1.G11 VRAM2.H10
MAA1_6: GPU1.J16 VRAM2.H5
MAA1_7: GPU1.L15 VRAM2.H4
MAA1_8: GPU1.G14 VRAM2.J5
MASK_SATA_LED#: KBC24.56 Q6401.G R6401.2
MCT: C3202.1 RN3201.5(B) RN3201.6(B) RN3201.7(B) RN3201.8(B)
MCT0: RN3201.4(A) XF3201.3
MCT1: RN3201.3(A) XF3201.4
MCT2: RN3201.2(A) XF3202.4
MCT3: RN3201.1(A) XF3202.3
MDO0+: AFTP3204.1 RJ45.1 XF3202.1
MDO0-: AFTP3201.1 RJ45.2 XF3202.2
MDO1+: AFTP3202.1 RJ45.3 XF3202.5
MDO1-: AFTP3208.1 RJ45.6 XF3202.6
MDO2+: AFTP3205.1 RJ45.4 XF3201.6
MDO2-: AFTP3203.1 RJ45.5 XF3201.5
MDO3+: AFTP3207.1 RJ45.7 XF3201.2
MDO3-: AFTP3206.1 RJ45.8 XF3201.1
ME_FWP: KBC24.80 R1909.1
ME_SUS_PWR_ACK_R: CPU1.AR13 R1708.1 R1718.2
MEC_XTAL1_R: C2425.1 KBC24.123 X2401.1
MEC_XTAL2: KBC24.125 R2428.2 R2458.1
MEM_CALRP0: GPU1.K25 R7809.2
MEM_SMBCLK: CPU1.R7 Q1801.3 R1805.1
MEM_SMBDATA: CPU1.R8 Q1801.6 R1832.1
MESO_SVC: GPU1.AJ11 R7946.2
MESO_SVD: GPU1.AK12 R7944.2
MESO_SVT: GPU1.AL11 R7945.2
MESO_U1: GPU1.U1 RN7905.2(A)
MESO_U3: GPU1.U3 RN7905.1(A)
MF_A0: R8112.2 VRAM1.J1
MF_A1: R8114.2 VRAM2.J1
MIC2_VREFO: HDA27.23 RN2901.1(A) RN2901.2(A)
MIC_CAP: C2715.1 HDA27.15
MIC_GND: LCD1.26 R5531.1
MLPS_EN#: GPU1.R5 R7935.2 R7936.1
MODEL_ID: C2407.1 KBC24.109 R2441.1 R2442.2
MPV18: C8043.1 C8044.1 C8045.1 GPU1.L8 L8001.2
MSM#: CPU1.AP56 TP617.1
MVREFDA: C7805.1 GPU1.K26 R7817.2 R7818.1
MVREFSA: C7801.1 GPU1.J26 R7810.2 R7814.1
NB_MODE#: KBC24.96 TP2401.1
NB_MUTE#: KBC24.119 R2712.1 R2717.2
NC#AA3: GPU1.AA3 R7938.2
NC_R: GPU1.AM26 TP7922.1
NC_VSYNC: GPU1.AJ27 R7941.2
NCT7718_DXN: C2614.2 Q7905.E THM262.3
NCT7718_DXP: C2614.1 Q7905.B Q7905.C THM262.2
ODD_PWR_5V: C6009.1 C6018.1 ODD1.10 ODD1.11 ODD1.12 ODD1.13 ODD1.14 ODD1.15 R6003.2
P_SYS: PC4404.1 PR4411.1 PR4614.2 PU4401.8 PU4601.1
PANEL_BKEN_EC: KBC24.117 R2471.1 R2497.1
PANEL_SIZE_ID: CPU1.AP13 R5521.2 R5525.2 R5526.1
PANEL_SIZE_ID_CONN: LCD1.22 R5525.1
PBAT_CHG_SMBCLK: EC4309.1 KBC24.9 PR4471.1 RN2402.1(A) RN4302.2(A)
PBAT_CHG_SMBDAT: EC4310.1 KBC24.8 PR4470.1 RN2402.2(A) RN4302.1(A)
PBAT_PRES1#: AFTP4303.1 BATT1.5 D4304.3 R4302.2
PBAT_PRES#: EC4306.1 KBC24.29 PC4433.1 PR4409.2 PR4439.2 PR4472.2 R2415.2 R4302.1
PBAT_SMBCLK1: AFTP4304.1 BATT1.3 D4306.3 RN4302.3(B)
PBAT_SMBDAT1: AFTP4308.1 BATT1.4 D4305.3 RN4302.4(B)
PCH_BATLOW#: CPU1.AU13 RN1704.6(B)
PCH_DPC_AUXN: C5625.1 CPU1.E48
PCH_DPC_AUXN_U: C5625.2 U5601.3
PCH_DPC_AUXP: C5624.1 CPU1.F48
PCH_DPC_AUXP_U: C5624.2 U5601.2
PCH_DPC_N0: C5605.1 CPU1.C50
PCH_DPC_N0_U: C5605.2 U5601.6
PCH_DPC_N1: C5604.1 CPU1.C52
PCH_DPC_N1_U: C5604.2 U5601.8
PCH_DPC_P0: C5601.1 CPU1.D50
PCH_DPC_P0_U: C5601.2 U5601.5
PCH_DPC_P1: C5603.1 CPU1.D52
PCH_DPC_P1_U: C5603.2 U5601.7
PCH_DPWROK: CPU1.BB20 R1704.2
PCH_JTAG_TCK: CPU1.B56 R407.1
PCH_JTAG_TDI: CPU1.D59 R408.1
PCH_JTAG_TDO: CPU1.A56 R409.1
PCH_JTAG_TMS: CPU1.C59 R416.1
PCH_PLTRST#: CPU1.AN10 R1713.2
PCH_POPIRCOMP: CPU1.AU16 R413.2
PCH_RSMRST#: EC1712.1 KBC24.27 R1702.2
PCH_SMBCLK: DM1.253 DM2.253 EC6505.1 Q1801.4 R1834.1 R6515.1 U5601.30 U6701.1
PCH_SMBDATA: DM1.254 DM2.254 EC6506.1 Q1801.1 R1835.1 R6511.1 U5601.29 U6701.4
PCH_THERMTRIP: CPU1.C63 R419.2
PCH_WAKE#: CPU1.BB15 RN1704.7(B)
PCIE_CALR_RX: GPU1.AA22 R7618.1
PCIE_CALR_TX: GPU1.Y22 R7622.2
PCIE_CLK_XDP_N: CPU1.F43 TP1807.1
PCIE_CLK_XDP_P: CPU1.E43 TP1808.1
PCIE_RCOMPN: CPU1.F5 R1604.1
PCIE_RCOMPP: CPU1.E5 R1604.2
PCIE_RX_CON_N5: C3107.1 LOM31.18
PCIE_RX_CON_P5: C3102.1 LOM31.17
PCIE_RX_CPU_N5: C3107.2 CPU1.F16
PCIE_RX_CPU_N6: CPU1.G18 WLAN1.43
PCIE_RX_CPU_P5: C3102.2 CPU1.E16
PCIE_RX_CPU_P6: CPU1.F18 WLAN1.41
PCIE_TX_CON_N5: C1601.1 LOM31.14
PCIE_TX_CON_N6: C1603.1 WLAN1.37
PCIE_TX_CON_P5: C1602.1 LOM31.13
PCIE_TX_CON_P6: C1604.1 WLAN1.35
PCIE_TX_CPU_N5: C1601.2 CPU1.C19
PCIE_TX_CPU_N6: C1603.2 CPU1.D20
PCIE_TX_CPU_P5: C1602.2 CPU1.D19
PCIE_TX_CPU_P6: C1604.2 CPU1.C20
PCIE_WAKE#: KBC24.4 LOM31.21 R3103.2
PD4404_A: PD4404.A PQ4409.B
PD4404_K: PD4404.K PR4459.2
PDB_R: HDA27.40 R2712.2
PEG_CLK1_CPU: CPU1.A42 WLAN1.47
PEG_CLK1_CPU#: CPU1.B42 WLAN1.49
PEG_CLK2_CPU: CPU1.C41 LOM31.15
PEG_CLK2_CPU#: CPU1.D41 LOM31.16
PEG_CLK_CPU: CPU1.C42 GPU1.AK30
PEG_CLK_CPU#: CPU1.D42 GPU1.AK32
PEG_RX_CPU_N0: C7602.2 CPU1.H13
PEG_RX_CPU_N1: C7604.2 CPU1.G11
PEG_RX_CPU_N2: C7606.2 CPU1.H16
PEG_RX_CPU_N3: C7608.2 CPU1.G15
PEG_RX_CPU_P0: C7601.2 CPU1.G13
PEG_RX_CPU_P1: C7603.2 CPU1.F11
PEG_RX_CPU_P2: C7605.2 CPU1.G16
PEG_RX_CPU_P3: C7607.2 CPU1.F15
PEG_RX_GPU_N0: C7602.1 GPU1.AG31
PEG_RX_GPU_N1: C7604.1 GPU1.AF28
PEG_RX_GPU_N2: C7606.1 GPU1.AF26
PEG_RX_GPU_N3: C7608.1 GPU1.AD26
PEG_RX_GPU_P0: C7601.1 GPU1.AH30
PEG_RX_GPU_P1: C7603.1 GPU1.AG29
PEG_RX_GPU_P2: C7605.1 GPU1.AF27
PEG_RX_GPU_P3: C7607.1 GPU1.AD27
PEG_TX_CPU_N0: C1606.2 CPU1.B17
PEG_TX_CPU_N1: C1608.2 CPU1.D16
PEG_TX_CPU_N2: C1610.2 CPU1.D17
PEG_TX_CPU_N3: C1612.2 CPU1.B19
PEG_TX_CPU_P0: C1605.2 CPU1.A17
PEG_TX_CPU_P1: C1607.2 CPU1.C16
PEG_TX_CPU_P2: C1609.2 CPU1.C17
PEG_TX_CPU_P3: C1611.2 CPU1.A19
PEG_TX_GPU_N0: C1606.1 GPU1.AE31
PEG_TX_GPU_N1: C1608.1 GPU1.AD28
PEG_TX_GPU_N2: C1610.1 GPU1.AC31
PEG_TX_GPU_N3: C1612.1 GPU1.AB28
PEG_TX_GPU_P0: C1605.1 GPU1.AF30
PEG_TX_GPU_P1: C1607.1 GPU1.AE29
PEG_TX_GPU_P2: C1609.1 GPU1.AD30
PEG_TX_GPU_P3: C1611.1 GPU1.AC29
PG_1: PG4429.1 PR4467.1
PG_2: PG4407.1 PR4468.1
PIRQA#: CPU1.BB11 R1607.2 R9152.1
PLL_ANALOG_IN: GPU1.AA1 TP7902.1
PLT_RST#: C1701.1 D7601.1 EC1703.1 Q6301.D R1713.1 R1715.1 R3110.1 R5538.2 R6116.1 R6324.2 R9136.1
PLT_RST#_LAN: LOM31.19 R3110.2
PLT_RST#_Q_TPM2: R9136.2 U9103.17
PLT_RST_NGFF#: AFTP6108.1 R6116.2 WLAN1.52
PM_LAN_ENABLE: Q3102.G R2491.1 R3107.1
PM_LAN_ENABLE_C: C3105.2 Q3101.G R3111.2
PM_PCH_PWROK: CPU1.BA20 R1706.2 RN1701.4(B)
PM_RSMRST#: CPU1.AY17 Q1701.3 Q1702.2 R1702.1 R1704.1 RN1701.3(B)
PM_RSMRST#_M: Q1702.5 Q1702.6 R1737.2
PME#: CPU1.AU11 TP1707.1
POL1/SPI_CEB: RN5602.3(B) U5601.10
POL2: RN5602.4(B) U5601.9
POWER_SW_IN#: C2426.1 KBC24.127 R2432.2 R2451.2
PQ3802_1: PQ4302.B PR4302.1 PR4309.2
PQ3809_D: PQ4306.3 PR4314.2
PQ4406_2: PQ4406.2 PR4408.1 PR4462.1
PQ4406_3: PQ4406.3 PR4458.1
PQ4406_5: PC4439.1 PQ4406.5 PR4413.1
PQ4406_6: PC4439.2 PQ4406.6 PR4453.1
PQ4409_C: PQ4409.C PR4455.1 PR4462.2
PQ4409_E: PQ4409.E PR4414.1 PR4431.2
PQ4416_1: PQ4415.C PQ4416.1
PQ8206_3: PQ8501.3 PR8545.2
PR_2: PC4405.1 PR4407.2
PRIM_PWRGD: KBC24.30 PR5408.1 R4030.1
PROC_SELECT#: CPU1.C64 R603.1
PROCHOT: KBC24.83 R2420.1
PROJECT_ID1: CPU1.AY8 R2015.2 R2016.1
PROJECT_ID2: CPU1.BA8 R2017.2 R2018.1
PS_0: C7918.1 GPU1.AC19 R7926.2 R7927.1
PS_1: C7919.1 GPU1.AD19 R7928.2 R7929.1
PS_2: C7920.1 GPU1.AE17 R7930.2 R7931.1
PS_3: C7921.1 GPU1.AE20 R7932.2 R7933.1
PS_ID: KBC24.36 PD4302.3 PR4304.2 PR4305.2
PS_ID_R: AFTP4312.1 DCIN1.4 PR4317.1
PS_ID_R1: PQ4301.S PR4305.1 PR4306.2
PS_ID_R2: PD4303.1 PD4303.2 PQ4301.D PR4306.1 PR4309.1 PR4317.2
PSID_DISABLE#_R_C: PQ4301.G PQ4302.C PR4303.1
PTP_DIS#: D2405.K KBC24.90
PU8201_36: PU8501.36 PU8501.37 PU8501.38
PU8201_39: PU8501.39 PU8501.40
PURE_HW_SHUTDOWN#: C2610.1 D4001.3 Q2602.D Q2605.D R2612.2 R4012.2
PWR_0D95V: PC8624.1 PC8625.1 PC8626.1 PG8603.1 PG8604.1 PL8601.2 PR8622.1
PWR_0D95V_FB: PC8624.2 PR8622.2 PR8623.1 PU8601.1
PWR_0D95V_PHASE: PL8601.1 PU8601.6
PWR_0D95V_PVDD: PC8621.1 PC8622.1 PC8623.1 PG8601.2 PG8602.2 PU8601.3
PWR_1D0V: PC5301.1 PC5303.1 PC5305.1 PC5306.1 PC5307.1 PG5304.1 PG5305.1 PG5306.1 PG5307.1 PG5308.1 PG5309.1 PG5310.2 PG5311.1 PG5312.1 PG5313.1 PG5314.1 PL5301.2
PWR_1D0V_BT: PC5304.2 PU5301.20
PWR_1D0V_EN: PC5314.1 PR5306.2 PU5301.2
PWR_1D0V_PFM: PR5303.1 PU5301.3
PWR_1D0V_PG: PR5305.2 PR5308.2 PU5301.1
PWR_1D0V_PH: PC5304.1 PL5301.1 PR5309.1 PU5301.10 PU5301.11 PU5301.16 PU5301.17 PU5301.18
PWR_1D0V_SNUB: PC5315.1 PR5309.2
PWR_1D0V_SS: PC5313.1 PU5301.22
PWR_1D0V_TON: PR5301.2 PU5301.6
PWR_1D0V_VFB: PC5312.2 PR5302.2 PR5304.1 PU5301.5
PWR_1D0V_VFB_A: PC5312.1 PG5310.1 PR5302.1
PWR_1D2V: PC5110.1 PC5111.1 PC5112.1 PC5113.1 PC5114.1 PG5101.2 PG5119.1 PG5120.1 PG5121.1 PG5122.1 PG5123.1 PG5124.1 PG5125.1 PG5126.1 PG5127.1 PG5128.1 PG5129.1 PG5130.1 PL5101.2
PWR_1D8V_EN: PC5406.1 PR5401.1 PR5406.2 PU5401.8
PWR_1D8V_POK: PR5402.2 PR5408.2 PU5401.7
PWR_1D35V_BOOT: PR8674.1 PU8651.1
PWR_1D35V_BOOT_A: PC8656.1 PR8674.2
PWR_1D35V_EN: D8602.1 PG8655.2 PR8672.1 PU8651.11
PWR_1D35V_FB: PC8662.2 PR8675.2 PR8676.1 PU8651.14
PWR_1D35V_FB_A: PC8662.1 PG8653.1 PR8675.1
PWR_1D35V_PG: PR8673.2 PU8651.9 PU8651.10
PWR_1D35V_PH: PC8656.2 PL8651.1 PU8651.6 PU8651.19 PU8651.20
PWR_1D35V_VCC: PC8654.1 PR8677.2 PU8651.16 PU8651.17
PWR_1V35V_ILMT: PR8671.1 PR8677.1 PU8651.13
PWR_2D5V_EN: PC5155.1 PR5152.1 PR5153.2 PU5151.8
PWR_2D5V_FB: PC5153.2 PR5151.2 PR5154.1 PU5151.2
PWR_2D5V_POK: PR5155.2 PR5158.2 PU5151.7
PWR_3D3V_CS2: PR4517.1 PU4503.5
PWR_3D3V_DRVH2: PU4503.10 PU4504.4
PWR_3D3V_DRVL2: PU4503.11 PU4505.4
PWR_3D3V_EN2: PR4503.2 PU4503.6
PWR_3D3V_FB2: PC4523.2 PR4512.2 PR4523.1 PU4503.4
PWR_3D3V_FB2_R: PC4523.1 PR4535.2
PWR_3D3V_LL2: PC4535.2 PL4502.2 PR4533.1 PU4503.8 PU4504.1 PU4504.2 PU4504.3 PU4505.5 PU4505.6 PU4505.7 PU4505.8
PWR_3D3V_SNUB: PC4520.1 PR4533.2
PWR_3D3V_VBST2: PR4528.2 PU4503.9
PWR_3D3V_VBST2_1: PC4535.1 PR4528.1
PWR_5V_CS1: PR4531.1 PU4503.1
PWR_5V_DRVH1: PU4501.4 PU4503.16
PWR_5V_DRVL1: PU4502.4 PU4503.15
PWR_5V_EN1: PR4502.2 PU4503.20
PWR_5V_EN1_R: PR4501.2 PR4502.1 PR4504.1 PR4530.1
PWR_5V_FB1: PC4522.2 PR4526.1 PR4527.2 PU4503.2
PWR_5V_FB1_R: PC4522.1 PR4525.2
PWR_5V_LL1: PC4516.2 PL4501.1 PR4529.1 PU4501.1 PU4501.2 PU4501.3 PU4502.5 PU4502.6 PU4502.7 PU4502.8 PU4503.18
PWR_5V_SNUB: PC4536.1 PR4529.2
PWR_5V_VBST1: PR4524.1 PU4503.17
PWR_5V_VBST1_1: PC4516.1 PR4524.2
PWR_5V_VCLK: PU4503.19 TP4501.1
PWR_5V_VO1: PG4532.2 PR4525.1 PR4527.1 PU4503.14
PWR_CHG_ACDET: PC4419.1 PR4416.1 PR4452.2 PU4401.1
PWR_CHG_ACN: PC4466.2 PC4468.1 PR4468.2 PU4401.31
PWR_CHG_ACOK: PR4408.2 PR4434.2 PR4451.2 PR4474.2 PU4401.2
PWR_CHG_ACP: PC4466.1 PC4467.1 PR4467.2 PU4401.32
PWR_CHG_AMON: PR4475.2 PU4401.6
PWR_CHG_ASGATE: PC4409.2 PU4401.30
PWR_CHG_BATDRV: PC4408.2 PU4401.25
PWR_CHG_BATGONE: PC4436.1 PR4439.1 PU4401.13
PWR_CHG_BMON: PR4476.2 PU4401.7
PWR_CHG_BTST: PR4428.1 PU4401.24
PWR_CHG_BTST1: PC4431.1 PR4428.2
PWR_CHG_CMSRC: PC4409.1 PR4477.2 PU4401.29
PWR_CHG_COMP: PC4406.1 PR4407.1 PU4401.10
PWR_CHG_DCIN: PC4435.1 PR4437.1 PU4401.18
PWR_CHG_DCIN_D: PD4410.2 PQ4416.3 PR4481.2
PWR_CHG_DCIN_R: PD4410.3 PR4437.2
PWR_CHG_FSET: PR4406.2 PU4401.12
PWR_CHG_HIDRV: PU4401.23 PU4411.4
PWR_CHG_LODRV: PU4401.21 PU4412.4
PWR_CHG_NTC: PR4410.1 PU4401.17
PWR_CHG_NTC_1: PR4410.2 PR4412.1
PWR_CHG_PHASE: PC4431.2 PL4401.1 PU4401.22 PU4411.1 PU4411.2 PU4411.3 PU4412.5 PU4412.6 PU4412.7 PU4412.8
PWR_CHG_PROG: PR4405.1 PU4401.9
PWR_CHG_REGN: PC4445.1 PR4417.1 PR4438.2 PU4401.20
PWR_CHG_SCL: PR4449.2 PR4471.2 PU4401.4
PWR_CHG_SDA: PR4435.2 PR4470.2 PU4401.3
PWR_CHG_SRN: PC4462.2 PC4463.2 PR4457.2 PU4401.14
PWR_CHG_SRN_R: PG4426.1 PR4457.1
PWR_CHG_SRP: PC4461.2 PC4463.1 PR4456.2 PU4401.15
PWR_CHG_SRP_R: PG4428.1 PR4456.1
PWR_DCBATOUT_1D0V: PC5308.1 PC5309.1 PC5310.1 PG5301.2 PG5302.2 PG5303.2 PR5301.1 PU5301.7 PU5301.8 PU5301.9
PWR_DCBATOUT_1D35V: PC8651.1 PC8652.1 PG8651.2 PG8652.2 PU8651.2 PU8651.3 PU8651.4 PU8651.5
PWR_DCBATOUT_3D3V: PC4509.1 PC4525.1 PC4528.1 PG4521.1 PG4524.1 PG4525.1 PG4531.1 PU4504.5 PU4504.6 PU4504.7 PU4504.8
PWR_DCBATOUT_5V: PC4527.1 PC4529.1 PC4530.1 PG4518.1 PG4520.1 PG4534.1 PG4536.1 PG4542.1 PG4543.1 PU4501.5 PU4501.6 PU4501.7 PU4501.8
PWR_DCBATOUT_VCCGTA: PC4802.1 PC4803.1 PC4804.1 PC4805.1 PG4802.1 PG4803.1 PG4804.1 PG4805.1 PG4806.1 PU4801.5
PWR_DCBATOUT_VCCGTB: PC4814.1 PC4815.1 PC4816.1 PC4817.1 PG4810.1 PG4811.1 PG4812.1 PG4814.1 PG4816.1 PU4802.5
PWR_DCBATOUT_VCCSA: PC5002.1 PC5003.1 PC5004.1 PG5002.1 PG5003.1 PU5002.5 PU5002.6 PU5002.7 PU5002.8
PWR_DCBATOUT_VCORE: PC4701.1 PC4702.1 PC4703.1 PC4704.1 PG4701.2 PG4702.2 PG4703.2 PG4704.2 PG4705.2 PG4706.2 PU4701.5
PWR_DCBATOUT_VDDQ: PC5103.1 PC5104.1 PC5105.1 PG5117.2 PG5118.2 PR5113.1 PU5102.5 PU5102.6 PU5102.7 PU5102.8
PWR_DCBATOUT_VGA_CORE1: PC8526.1 PC8527.1 PC8528.1 PC8529.1 PC8530.1 PG8511.2 PG8512.2 PG8513.2 PG8514.2 PG8515.2 PG8516.2 PU8502.2 PU8502.3 PU8502.4 PU8502.10 PU8503.2 PU8503.3 PU8503.4 PU8503.10
PWR_DCBATOUT_VGA_CORE2: PC8519.1 PC8520.1 PC8521.1 PC8531.1 PC8532.1 PG8501.2 PG8502.2 PG8503.2 PG8504.2 PG8505.2 PG8506.2 PU8504.2 PU8504.3 PU8504.4 PU8504.10 PU8505.2 PU8505.3 PU8505.4 PU8505.10
PWR_OPCN: PC4407.2 PU4401.28
PWR_OPCP: PC4407.1 PU4401.27
PWR_SECLET: KBC24.63 R1819.2 R2401.1
PWR_VBAT: PC4408.1 PR4454.1 PU4401.26
PWR_VCCGT_BOOTA: PR4804.2 PU4801.7
PWR_VCCGT_BOOTA_RC: PC4808.1 PR4804.1
PWR_VCCGT_BOOTB: PR4810.2 PU4802.7
PWR_VCCGT_BOOTB_RC: PC4811.1 PR4810.1
PWR_VCCGT_BOOTRA: PC4808.2 PU4801.6
PWR_VCCGT_BOOTRB: PC4811.2 PU4802.6
PWR_VCCGT_COMP: PC4610.2 PR4626.2 PU4601.4
PWR_VCCGT_COMP1: PC4612.1 PC4651.1 PR4626.1
PWR_VCCGT_FB: PR4630.2 PR4633.2 PR4636.2 PR4671.2 PU4601.5
PWR_VCCGT_FB1: PC4614.1 PC4661.1 PR4630.1
PWR_VCCGT_FB2: PC4615.2 PC4618.1 PC4619.1 PC4662.1 PR4631.2 PR4633.1 PR4665.2 PR4671.1
PWR_VCCGT_FB_RC: PC4618.2 PC4662.2 PR4636.1
PWR_VCCGT_FCCM#: PR4806.1 PR4812.1 PU4601.11
PWR_VCCGT_FCCM#_RA: PR4806.2 PU4801.1
PWR_VCCGT_FCCM#_RB: PR4812.2 PU4802.1
PWR_VCCGT_IMON: PC4604.2 PR4608.2 PR4672.2 PU4601.2
PWR_VCCGT_ISEN1: PC4625.1 PR4669.2 PR4821.1 PR4824.2 PU4601.9
PWR_VCCGT_ISEN2: PC4626.1 PR4635.2 PR4669.1 PR4822.2 PR4823.1 PU4601.10
PWR_VCCGT_ISUMN: PC4625.2 PC4626.2 PC4630.2 PC4633.1 PR4642.2 PR4643.2 PR4645.2 PR4646.2 PR4647.1 PR4670.2 PR4809.2 PR4815.2
PWR_VCCGT_ISUMN_GA: PG4809.2 PR4809.1 PR4822.1
PWR_VCCGT_ISUMN_GB: PG4815.2 PR4815.1 PR4824.1
PWR_VCCGT_ISUMN_P_1: PC4609.2 PC4628.2 PC4653.2 PR4647.2
PWR_VCCGT_ISUMN_P_2: PR4641.2 PR4646.1
PWR_VCCGT_ISUMN_RC: PC4623.1 PR4645.1
PWR_VCCGT_ISUMNB: PC4623.2 PR4642.1 PR4670.1 PU4601.8
PWR_VCCGT_ISUMP: PC4609.1 PC4628.1 PC4630.1 PC4653.1 PR4641.1 PR4643.1 PR4808.1 PR4816.1 PU4601.7
PWR_VCCGT_ISUMP_GA: PG4808.2 PR4808.2 PR4821.2
PWR_VCCGT_ISUMP_GB: PG4813.2 PR4816.2 PR4823.2
PWR_VCCGT_NTC: PR4616.1 PU4601.3
PWR_VCCGT_NTC1: PR4616.2 PR4617.2 PR4621.2
PWR_VCCGT_PWMA: PR4802.2 PU4601.12
PWR_VCCGT_PWMA_RA: PR4802.1 PR4817.1 PU4801.8
PWR_VCCGT_PWMB: PR4811.2 PU4601.13
PWR_VCCGT_PWMB_RA: PR4811.1 PR4818.1 PU4802.8
PWR_VCCGT_RTN: PC4619.2 PC4622.1 PR4639.2 PR4666.2 PU4601.6
PWR_VCCGT_SNB1: PC4810.1 PR4805.2
PWR_VCCGT_SNB2: PC4813.1 PR4814.2
PWR_VCCGT_SWA: PG4808.1 PL4801.1 PR4805.1 PU4801.4
PWR_VCCGT_SWB: PG4813.1 PL4802.1 PR4814.1 PU4802.4
PWR_VCCGT_VCCDA: PC4809.1 PR4803.2 PU4801.2
PWR_VCCGT_VCCDB: PC4812.1 PR4813.2 PU4802.2
PWR_VCCSA_BST: PR5001.2 PU5001.2
PWR_VCCSA_BST_RC: PC5005.1 PR5001.1
PWR_VCCSA_COMP: PC4624.1 PR4640.1 PU4601.24
PWR_VCCSA_COMP_RC: PC4601.1 PR4640.2
PWR_VCCSA_DRVH: PU5001.1 PU5002.4
PWR_VCCSA_DRVL: PU5001.5 PU5003.4
PWR_VCCSA_FB: PR4632.2 PR4637.1 PR4638.2 PU4601.25
PWR_VCCSA_FB1: PC4621.2 PR4638.1
PWR_VCCSA_FB2: PC4616.2 PC4617.2 PC4620.1 PR4601.1 PR4637.2
PWR_VCCSA_FB_RC: PC4617.1 PR4632.1
PWR_VCCSA_FCCM: PU4601.29 PU5001.7
PWR_VCCSA_IMON: PC4629.2 PR4644.1 PU4601.23
PWR_VCCSA_ISUMN: PC4603.2 PC4605.1 PR4611.1 PR4613.1 PR4615.1 PR4618.2 PR4620.1 PR5004.2
PWR_VCCSA_ISUMN_P_1: PC4608.2 PR4613.2
PWR_VCCSA_ISUMN_P_2: PR4611.2 PR4625.2
PWR_VCCSA_ISUMN_R: PG5001.1 PR5004.1
PWR_VCCSA_ISUMN_RC: PC4611.2 PR4615.2
PWR_VCCSA_ISUMNB: PC4611.1 PR4620.2 PU4601.28
PWR_VCCSA_ISUMP: PC4605.2 PC4608.1 PR4618.1 PR4625.1 PR5003.2 PU4601.27
PWR_VCCSA_ISUMP_R: PG5011.1 PR5003.1
PWR_VCCSA_PWM: PU4601.30 PU5001.3
PWR_VCCSA_RTN: PC4613.1 PC4616.1 PR4602.1 PR4627.1 PU4601.26
PWR_VCCSA_SW: PC5005.2 PG5011.2 PL5001.1 PU5001.8 PU5002.1 PU5002.2 PU5002.3 PU5003.5 PU5003.6 PU5003.7 PU5003.8
PWR_VCORE_ALERT#: PR4623.2 PU4601.36
PWR_VCORE_BOOT: PR4705.2 PU4701.7
PWR_VCORE_BOOT_RC: PC4707.1 PR4705.1
PWR_VCORE_BOOTR: PC4707.2 PU4701.6
PWR_VCORE_COMP: PC4639.1 PR4656.1 PU4601.16
PWR_VCORE_COMP1: PC4640.1 PR4656.2
PWR_VCORE_FB: PR4657.1 PR4658.1 PR4660.1 PU4601.17
PWR_VCORE_FB1: PC4641.1 PR4657.2
PWR_VCORE_FB2: PC4642.2 PC4643.2 PC4644.1 PR4660.2 PR4663.1 PR4667.2
PWR_VCORE_FB_RC: PC4643.1 PR4658.2
PWR_VCORE_FCCM#: PR4706.1 PU4601.21
PWR_VCORE_FCCM#_R: PR4706.2 PU4701.1
PWR_VCORE_IMON: PC4638.1 PR4661.1 PU4601.14
PWR_VCORE_ISUMN: PC4631.1 PC4634.1 PR4648.2 PR4649.2 PR4650.1 PR4651.2 PR4652.2 PR4701.2
PWR_VCORE_ISUMN_G: PG4708.1 PR4701.1
PWR_VCORE_ISUMN_P_1: PC4635.1 PC4652.1 PR4649.1
PWR_VCORE_ISUMN_P_2: PR4650.2 PR4653.2
PWR_VCORE_ISUMN_RC: PC4632.1 PR4651.1
PWR_VCORE_ISUMNA: PC4632.2 PR4648.1 PU4601.20
PWR_VCORE_ISUMP: PC4634.2 PC4635.2 PC4652.2 PR4652.1 PR4653.1 PR4708.2 PU4601.19
PWR_VCORE_ISUMP_G: PG4707.1 PR4708.1
PWR_VCORE_NTC: PR4662.1 PU4601.15
PWR_VCORE_NTC1: PR4654.1 PR4655.2 PR4662.2
PWR_VCORE_PROG1: PR4629.1 PU4601.32
PWR_VCORE_PROG2: PR4628.1 PU4601.31
PWR_VCORE_PWM: PR4702.2 PU4601.22
PWR_VCORE_PWM_R: PR4702.1 PR4712.1 PU4701.8
PWR_VCORE_RTN: PC4637.1 PC4642.1 PR4659.1 PR4668.2 PU4601.18
PWR_VCORE_SCLK: PR4624.2 PU4601.37
PWR_VCORE_SDIO: PR4622.2 PU4601.35
PWR_VCORE_SNB: PC4706.1 PR4703.2
PWR_VCORE_SW: PG4707.2 PL4701.1 PR4703.1 PU4701.4
PWR_VCORE_VCC: PC4607.1 PR4610.2 PU4601.34
PWR_VCORE_VCC_R: PC4708.1 PR4704.2 PU4701.2
PWR_VCORE_VIN: PC4606.1 PR4612.2 PU4601.33
PWR_VCORE_VRHOT#: PR4607.2 PU4601.38
PWR_VDDQ_BOOT: PR5112.1 PU5101.18
PWR_VDDQ_BOOT_A: PC5108.1 PR5112.2
PWR_VDDQ_CS: PR5114.1 PU5101.13
PWR_VDDQ_EN: PC5106.1 PR5128.2 PU5101.8
PWR_VDDQ_FB: PC5115.2 PR5116.2 PR5117.1 PU5101.6
PWR_VDDQ_HG: PU5101.17 PU5102.4
PWR_VDDQ_LG: PU5101.15 PU5105.4
PWR_VDDQ_PG: PR5111.2 PU5101.10 R4011.1
PWR_VDDQ_PH: PC5108.2 PL5101.1 PR5120.1 PU5101.16 PU5102.1 PU5102.2 PU5102.3 PU5105.5 PU5105.6 PU5105.7 PU5105.8
PWR_VDDQ_SNUB: PC5120.1 PR5120.2
PWR_VDDQ_TON: PR5113.2 PU5101.9
PWR_VDDQ_VDD: PC5107.1 PR5109.1 PU5101.12
PWR_VDDQ_VDDQ: PC5115.1 PG5101.1 PR5116.1 PU5101.5
PWR_VDDQ_VID: PC5102.1 PR5107.1 PU5101.11
PWR_VDDQ_VLDOIN: PC5109.1 PG5115.2 PG5116.2 PU5101.19
PWR_VDDQ_VTT: PC5117.1 PC5118.1 PG5113.2 PG5114.2 PU5101.2 PU5101.20
PWR_VDDQ_VTTREF: PC5116.1 PU5101.4
PWR_VGA_CORE__BOOT1_1: PC8510.1 PR8515.2
PWR_VGA_CORE__BOOT2_1: PC8507.1 PR8507.2
PWR_VGA_CORE_BOOT1: PR8515.1 PU8501.21
PWR_VGA_CORE_BOOT2: PR8507.1 PU8501.30
PWR_VGA_CORE_COMP: PC8514.2 PC8515.2 PR8528.1 PU8501.19
PWR_VGA_CORE_COMP_1: PC8516.1 PR8527.2
PWR_VGA_CORE_EN_R#: PQ8501.5 PQ8501.6 PR8539.2
PWR_VGA_CORE_ENABLE: PR8514.2 PU8501.8
PWR_VGA_CORE_FB: PC8514.1 PR8523.2 PR8525.1 PR8526.2 PR8527.1 PU8501.18
PWR_VGA_CORE_FB2_R: PC8515.1 PR8526.1
PWR_VGA_CORE_FB_R: PC8513.1 PR8523.1
PWR_VGA_CORE_IMON: PC8511.1 PR8516.1 PU8501.10
PWR_VGA_CORE_IMON_NB: PR8508.2 PU8501.2
PWR_VGA_CORE_ISEN1: PC8518.1 PR8519.1 PR8543.1 PU8501.13
PWR_VGA_CORE_ISEN2: PC8517.1 PR8522.1 PR8538.1 PU8501.12
PWR_VGA_CORE_ISUMN: PR8536.2 PU8501.15
PWR_VGA_CORE_ISUMP: PC8522.1 PC8523.1 PR8517.1 PR8529.1 PR8532.1 PR8537.1 PU8501.14
PWR_VGA_CORE_LGATE1: PU8501.24 PU8502.8 PU8503.8
PWR_VGA_CORE_LGATE2: PU8501.27 PU8504.8 PU8505.8
PWR_VGA_CORE_LGATE_NB: PR8501.2 PU8501.34
PWR_VGA_CORE_NTC: PR8524.1 PU8501.11
PWR_VGA_CORE_NTC_NB: PR8506.2 PU8501.1
PWR_VGA_CORE_PGOOD: PC8512.1 PR8518.2 PR8520.1 PR8544.2 PU8501.20
PWR_VGA_CORE_PH1: PG8507.1 PR8517.2 PR8519.2
PWR_VGA_CORE_PH2: PG8509.1 PR8537.2 PR8538.2
PWR_VGA_CORE_PHASE1: PC8510.2 PG8507.2 PL8501.1 PR8541.1 PU8501.23 PU8502.9 PU8503.9
PWR_VGA_CORE_PHASE2: PC8507.2 PG8509.2 PL8502.1 PR8542.1 PU8501.28 PU8504.9 PU8505.9
PWR_VGA_CORE_PWROK: PR8544.1 PU8501.9
PWR_VGA_CORE_RTN: PC8501.1 PR8530.1 PU8501.17
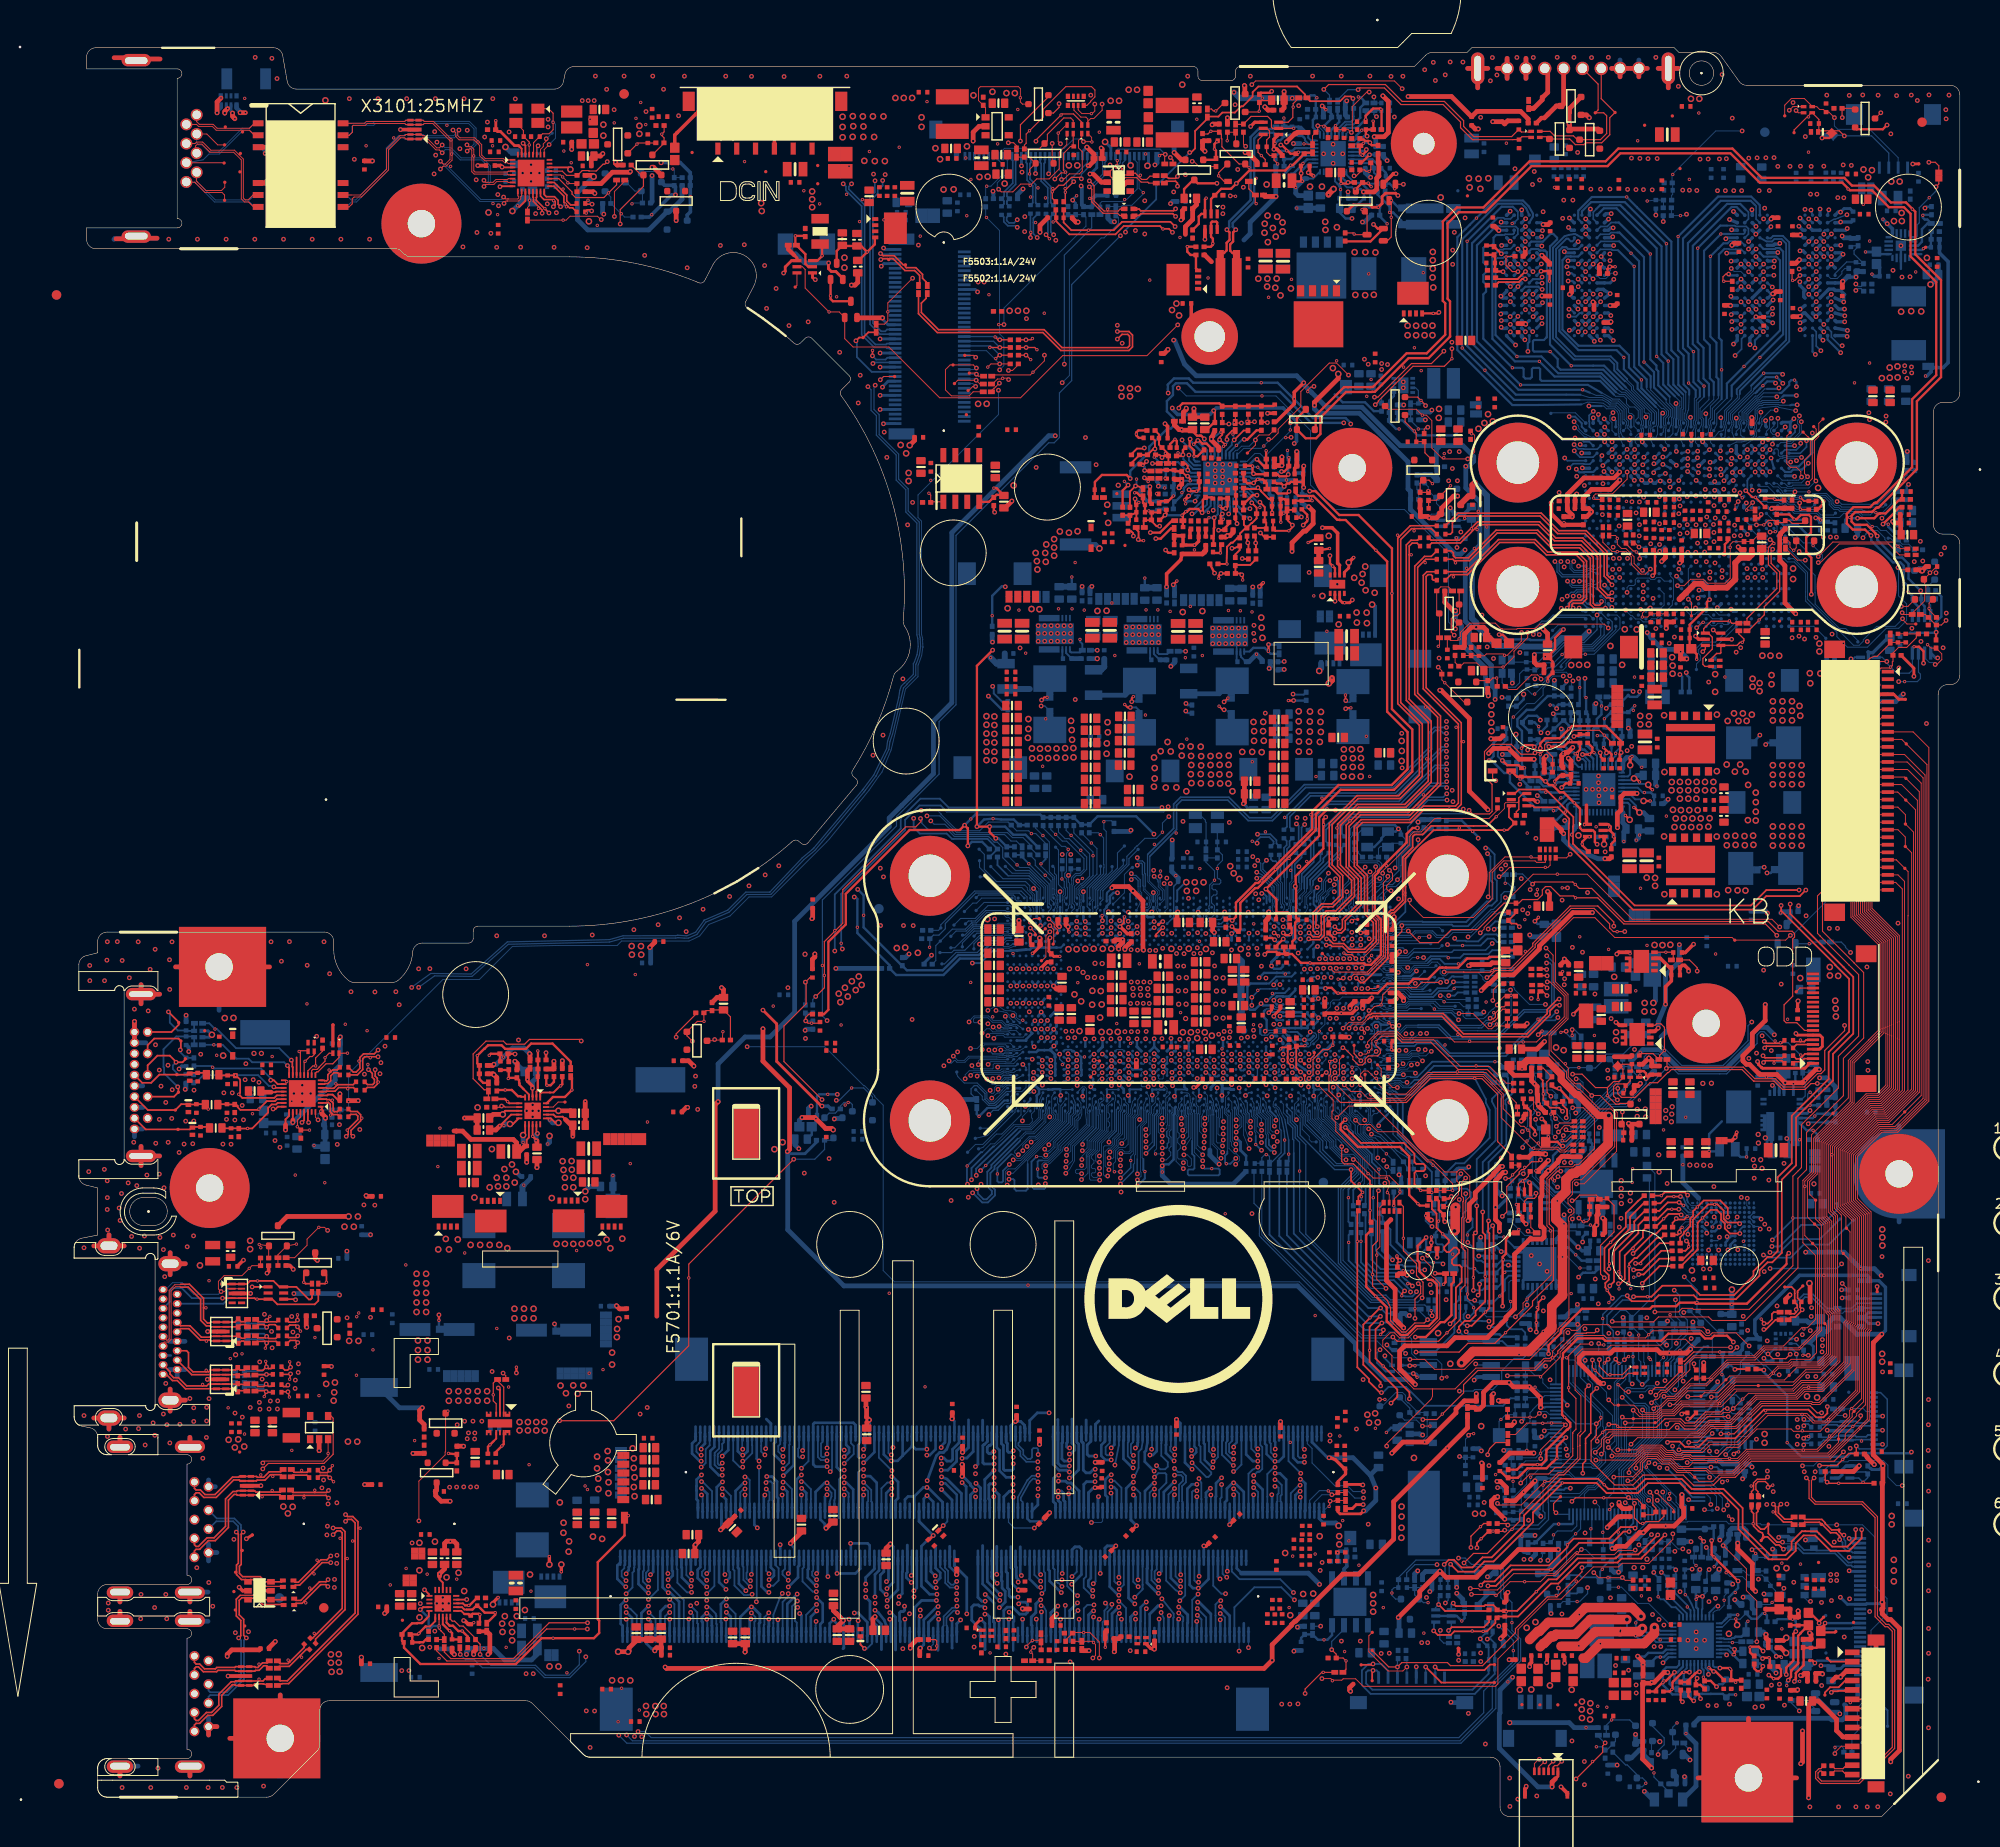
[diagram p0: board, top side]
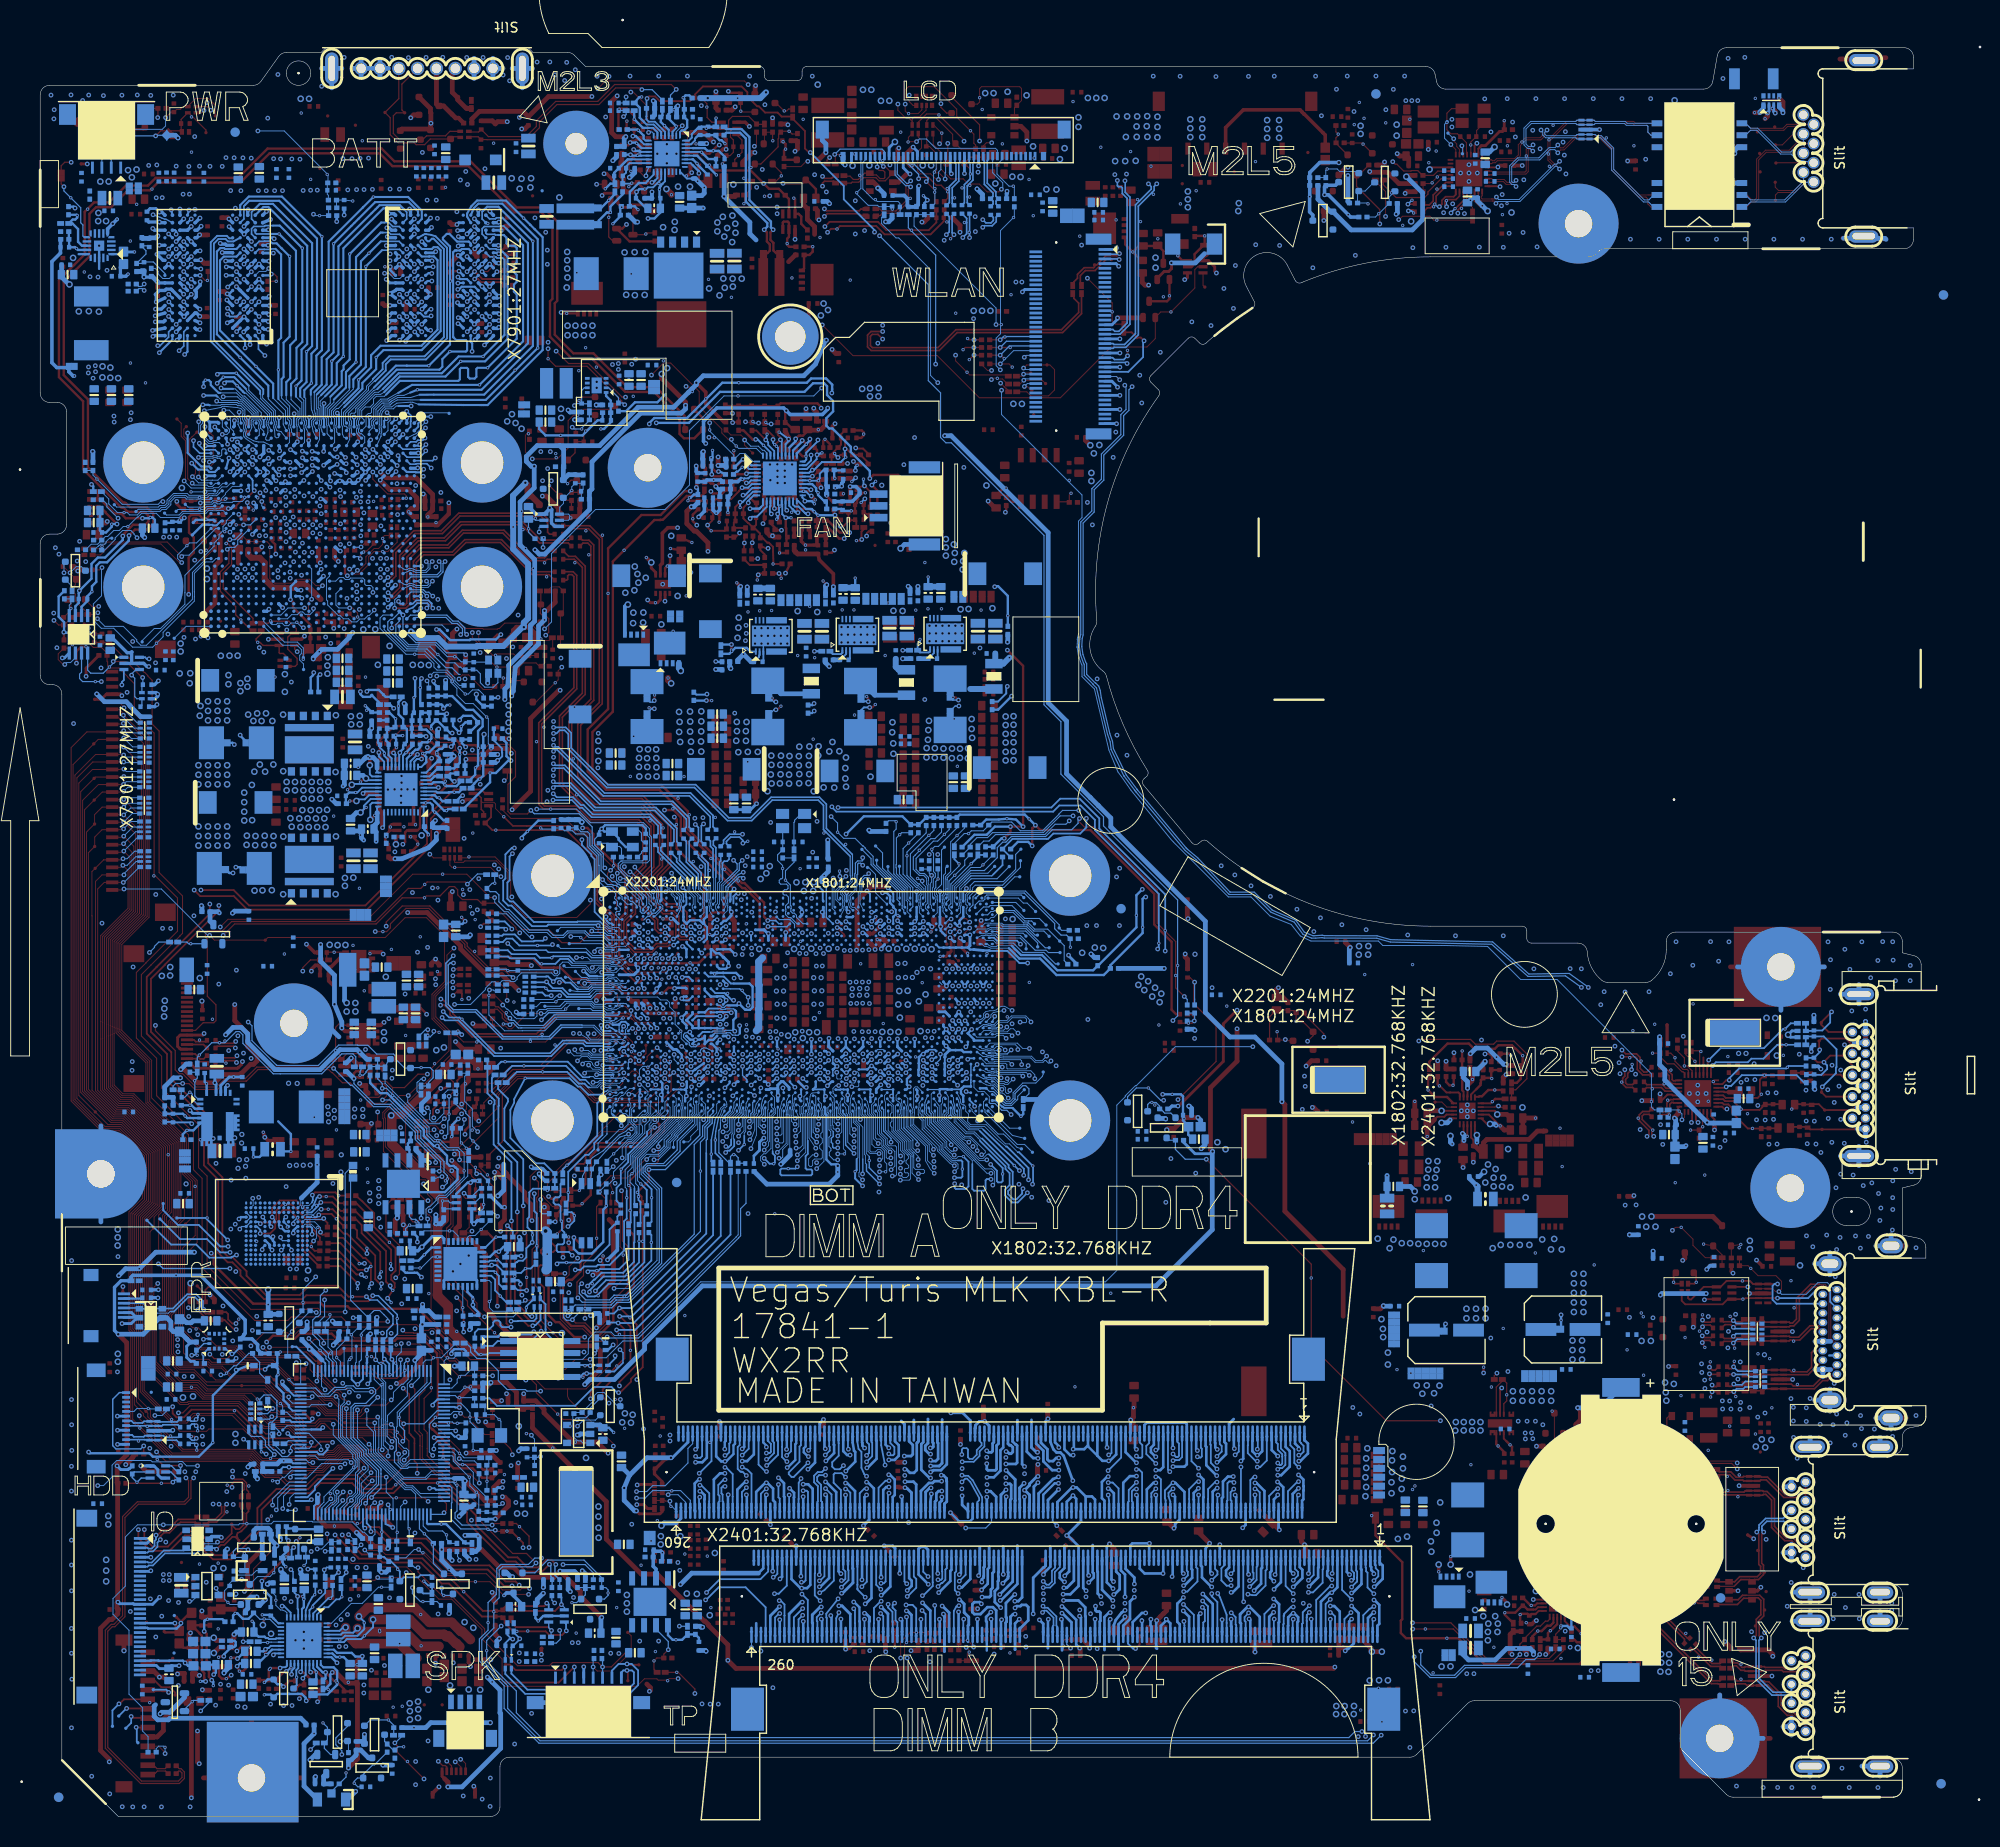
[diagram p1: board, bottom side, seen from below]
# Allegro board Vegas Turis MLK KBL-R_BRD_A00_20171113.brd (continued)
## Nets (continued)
PWR_VGA_CORE_SVC: PR8509.2 PU8501.3
PWR_VGA_CORE_SVD: PR8512.2 PU8501.5
PWR_VGA_CORE_SVT: PR8513.2 PU8501.7
PWR_VGA_CORE_UGATE1: PU8501.22 PU8502.1 PU8503.1
PWR_VGA_CORE_UGATE2: PU8501.29 PU8504.1 PU8505.1
PWR_VGA_CORE_UGATE_LX_NB: PR8502.2 PU8501.32 PU8501.33
PWR_VGA_CORE_VDD: PC8509.1 PR8510.2 PU8501.25
PWR_VGA_CORE_VDDIO: PC8503.2 PR8505.2 PR8546.2 PU8501.6 R7923.1 R7924.1 R7940.1
PWR_VGA_CORE_VO1: PG8508.1 PR8521.2 PR8522.2
PWR_VGA_CORE_VO2: PG8510.1 PR8540.2 PR8543.2
PWR_VGA_CORE_VR_HOT#: PR8511.2 PU8501.4
PWR_VGA_CORE_VSEN: PC8513.2 PC8524.1 PR8525.2 PR8534.1 PU8501.16
PWR_VGA_CORE_VSUM-: PC8517.2 PC8518.2 PC8522.2 PC8523.2 PC8525.1 PR8521.1 PR8532.2 PR8533.2 PR8536.1 PR8540.1
PWR_VGA_SNUB1: PC8506.1 PR8541.2
PWR_VGA_SNUB2: PC8533.1 PR8542.2
PWR_VTT_EN: PR5126.2 PR5127.2 PU5101.7
PWRGOOD_TEST: GPU1.N10 R7601.2
PX_EN: GPU1.AB16 TP7904.1
Q502_G: Q501.D Q502.G R507.2
Q4009_G: Q2705.G R2737.2 R2740.2
Q6204_G: Q6503.2 Q6503.5 R6512.2
Q6205_Q: Q6505.D R6522.2
RASA0B: GPU1.G22 VRAM1.G3
RASA1B: GPU1.G17 VRAM2.L3
REGOUT: C3118.1 L3101.1 LOM31.24 R3101.1
RESET_OUT#: EU1701.1 KBC24.73 Q2602.G Q2605.G R1706.1
RING2: EC2905.1 HDA27.13 R2906.1 RN2901.4(B)
RING2_R: AFTP6605.1 IOBD1.24 IOBD1.25 IOBD1.26 R2906.2
RSET: LOM31.31 R3102.2
RSMRST_PWRGD#: D4002.3 R4029.2 R4030.2 R4031.2 R4032.2 R4033.2
RSVD_F65: CPU1.F65 TP612.1
RSVD_G65: CPU1.G65 TP613.1
RSVD_TP_AW70: CPU1.AW70 TP615.1
RSVD_TP_AW71: CPU1.AW71 TP614.1
RSVD_TP_BA68: CPU1.BA68 TP602.1
RSVD_TP_BA70: CPU1.BA70 TP601.1
RTC_3D3V: C2503.1 D2501.3 Q2107.S R2113.1 R2472.1
RTC_3P3_EN_D: Q2110.D R2104.2
RTC_3P3_EN_G: C2123.1 D2102.A Q2110.G R2102.2
RTC_AUX_S5: C2117.1 C2118.1 C2119.1 Q2107.D R1730.1 R2104.1 R2107.1 R2113.2 R2708.1 RN1901.1(A) RN1901.2(A)
RTC_DET#: CPU1.P1 Q2505.D RN2011.3(B)
RTC_PWR: D2501.2 Q2505.G R2502.2 R2504.1
RTC_RST#: C1901.1 CPU1.AM16 EC1807.1 G1901.2 Q1901.D RN1901.3(B)
RTC_X1: C1804.1 CPU1.AM18 R1815.1 X1802.1
RTC_X2: C1803.1 CPU1.AM20 R1815.2 X1802.4
RTCRST_ON: D2102.K EC1808.1 KBC24.31 Q1901.G Q2107.G R1817.1 R2102.1 R2118.1
RUNPWROK: KBC24.48 R2481.2
SA0_CHA_DIM0: DM1.256 R1204.2 R1205.2
SA0_CHB_DIM0: DM2.256 R1302.2 R1303.2
SA1_CHA_DIM0: DM1.260 R1208.2 R1210.2
SA1_CHB_DIM0: DM2.260 R1306.2 R1307.2
SA2_CHA_DIM0: DM1.166 R1211.2 R1212.2
SA2_CHB_DIM0: DM2.166 R1310.2 R1311.2
SATA_LED#_R: CPU1.H1 Q6401.S R1606.1
SATA_ODD_DA#_C: ODD1.17 TP6001.1
SATA_ODD_PRSNT#: CPU1.H3 R1608.1 R6004.1
SATA_ODD_PRSNT#_R: ODD1.8 R6004.2
SATA_RX_CON_N0: C6004.2 ED6001.4 ED6001.7 HDD1.8
SATA_RX_CON_N1: C6010.2 ODD1.5
SATA_RX_CON_P0: C6003.2 ED6001.5 ED6001.6 HDD1.7
SATA_RX_CON_P1: C6011.2 ODD1.6
SATA_RX_CPU_N0: C6004.1 CPU1.F20
SATA_RX_CPU_N1: C6010.1 CPU1.G21
SATA_RX_CPU_P0: C6003.1 CPU1.E20
SATA_RX_CPU_P1: C6011.1 CPU1.F21
SATA_TX_CON_N0: C6006.2 ED6001.2 ED6001.9 HDD1.10
SATA_TX_CON_N1: C6013.2 ODD1.3
SATA_TX_CON_P0: C6005.2 ED6001.1 ED6001.10 HDD1.11
SATA_TX_CON_P1: C6014.2 ODD1.2
SATA_TX_CPU_N0: C6006.1 CPU1.B21
SATA_TX_CPU_N1: C6013.1 CPU1.D21
SATA_TX_CPU_P0: C6005.1 CPU1.A21
SATA_TX_CPU_P1: C6014.1 CPU1.C21
SD_RCOMP: CPU1.AB7 R1901.1
SEN_A0: R8111.2 VRAM1.J10
SEN_A1: R8113.2 VRAM2.J10
SERIRQ_TPM: R9141.1 U9103.27
SIO_EXT_SCI#: CPU1.J2 R1610.1
SIO_EXT_SMI#_R: CPU1.L6 R802.1
SIO_EXT_WAKE#: CPU1.AD3 KBC24.116 RN2011.4(B)
SIO_PWRBTN#: CPU1.BA15 KBC24.52
SIO_RCIN#: CPU1.AW13 R1816.2
SIO_SLP_A#: CPU1.AN16 TP1706.1
SIO_SLP_S0#: CPU1.AT11 TP1701.1
SIO_SLP_S3#: CPU1.AP15 PR5126.1 R2486.2 R2487.2 R2740.1 R4010.1 R4034.1
SIO_SLP_S4#: CPU1.BA16 PQ4415.B PR5153.1 R4024.1
SIO_SLP_S5#: CPU1.AY16 TP1703.1
SKTOCC#: CPU1.A65 TP402.1
SLEEVE: EC2906.1 HDA27.14 R2911.1 RN2901.3(B)
SLEEVE_R: AFTP6609.1 IOBD1.21 IOBD1.22 IOBD1.23 R2911.2
SLP_LAN#: CPU1.AW15 TP1704.1
SLP_SUS#: CPU1.AN15 TP1702.1
SM_DRAMRST#: CPU1.AT13 ED502.1 R504.1 R505.2
SM_INTRUDER#: CPU1.AP16 R1730.2
SM_PGCNTL: CPU1.AW67 Q501.G
SM_PGCNTL_R: PR5127.1 Q502.D R506.2
SM_RCOMP_0: CPU1.AR18 R501.1
SM_RCOMP_1: CPU1.AT18 R502.1
SM_RCOMP_2: CPU1.AU18 R503.1
SMB_CLK_THM_R: C2617.1 Q7904.1 RN7903.3(B) THM262.8
SMB_CLK_VGA: GPU1.U7 R7912.2
SMB_CLK_VGA_R: Q7901.1 R7912.1 RN7902.2(A)
SMB_DATA_THM_R: C2618.1 Q7904.4 RN7903.4(B) THM262.7
SMB_DATA_VGA: GPU1.U8 R7914.2
SMB_DATA_VGA_R: Q7901.4 R7914.1 RN7902.1(A)
SML0_SMBCLK: CPU1.R9 RN1807.5(B)
SML0_SMBDATA: CPU1.W2 RN1807.6(B)
SML1_SMBCLK: CPU1.W3 Q7901.6 Q7904.6 R2439.2 RN1807.7(B)
SML1_SMBDATA: CPU1.V3 Q7901.3 Q7904.3 R2438.2 RN1807.8(B)
SPI_CLK_CPU: CPU1.AV2 R1806.2
SPI_CLK_CRT: R5613.2 U5601.11
SPI_CLK_ROM: R1806.1 R9138.1 RN2503.4(B)
SPI_CLK_ROM_R: RN2503.1(A) SKT251.6 SPI25.6
SPI_CLK_ROM_TPM2: R9138.2 U9103.19
SPI_CS2#_R_TPM2: R9122.2 R9130.2 R9140.2 U9103.20
SPI_CS_CPU_N0: CPU1.AU3 R1812.2
SPI_CS_CPU_N2: CPU1.AU1 R1814.2
SPI_CS_ROM_N0: R1812.1 R2501.2 SKT251.1 SPI25.1
SPI_CS_ROM_N2: R1814.1 R9130.1
SPI_HOLD_CPU: CPU1.AU4 R1811.2
SPI_HOLD_ROM: R1811.1 R1827.2 RN2502.4(B)
SPI_HOLD_ROM_R: RN2501.2(A) RN2502.1(A) SKT251.7 SPI25.7
SPI_IRQ#_TPM2: R9152.2 U9103.18
SPI_SI_CPU: CPU1.AV3 R1808.2 R1824.2 R1825.1
SPI_SI_CRT: RN5603.4(B) U5601.12
SPI_SI_ROM: R1808.1 R9133.1 RN2503.3(B)
SPI_SI_ROM_R: RN2503.2(A) SKT251.5 SPI25.5
SPI_SI_ROM_TPM2: R9133.2 U9103.21
SPI_SO_CPU: CPU1.AW3 R1807.2
SPI_SO_CRT: RN5603.3(B) U5601.13
SPI_SO_ROM: R1807.1 R2507.1 R9132.1
SPI_SO_ROM_R: R2507.2 SKT251.2 SPI25.2
SPI_SO_ROM_TPM2: R9132.2 U9103.24
SPI_WP_CPU: CPU1.AW2 R1809.2
SPI_WP_ROM: R1809.1 R1828.2 RN2502.3(B)
SPI_WP_ROM_R: RN2501.1(A) RN2502.2(A) SKT251.3 SPI25.3
SPKR: CPU1.AW5 R2006.2 R2741.1
SPV10: C8055.1 C8056.1 GPU1.H8 L8003.2
SPV18: C8053.1 C8054.1 GPU1.H7 L8002.2
SRTC_RST#: C1902.1 CPU1.AN18 EC1806.1 RN1901.4(B)
SUS_CLK: R1813.2 R2428.1
SUSACK#_R: CPU1.AP11 R1708.2
SUSCLK_R: CPU1.BA17 R1813.1
SYS_PRES1#: AFTP4305.1 BATT1.6 R4301.1
SYS_PWROK: CPU1.B6 EC1702.1 KBC24.28 R1717.2
SYSPWR_PRES: KBC24.120 R2453.2 R2455.1
TESTEN: GPU1.K7 R7902.2 R7903.1
THERM_SYS_SHDN#: Q2602.S R2602.2
TOPAZ_OCP: PR8511.1 R7913.1
TOUCH_PANEL_INTR#: CPU1.A7 D2402.A R2429.1 R5537.2
TOUCHPAD_INTR#: CPU1.BA5 R410.2
TP1_AY4: CPU1.AY4 TP610.1
TP2_BB3: CPU1.BB3 TP611.1
TP_EN#: KBC24.49 R6516.1 RN2405.4(A)
TP_LOCK#: AFTP6526.1 D2405.A R6509.2 TP1.6
TP_ON#_GATE: C6503.1 Q6504.G Q6505.G R6516.2
TP_RESET: C5540.1 LCD1.38 R5538.1
TP_RS: C5541.1 LCD1.37 R5537.1
TP_VDD: AFTP6529.1 C6504.1 Q6504.D R6509.1 R6513.1 R6514.1 R6517.2 R6522.1 RN6502.1(A) RN6502.2(A) RN6504.1(A) RN6504.2(A) TP1.1
TP_WAKE_KBC#: KBC24.33 R2431.2
TPAN_VDD: C5501.1 C5543.1 ED5501.5 F5502.2 LCD1.40 R5520.2
TPAN_VDD_F: F5502.1 R5520.1 R5522.2 R5527.2
TPCLK_C: AFTP6530.1 RN6503.4(B) TP1.8
TPDATA_C: AFTP6524.1 RN6503.3(B) TP1.7
TPM_GPIO0: R9121.1 U9103.29
TPM_GPIO2: R9120.1 U9103.3
TPM_GPIO4: R9122.1 U9103.13
TPM_SELECT: CPU1.AY7 R2020.1 R2022.2
TPM_VDD14: C9107.1 C9111.1 C9113.1 R9147.2 U9103.14 U9103.22
TPM_VSB: R9144.2 U9103.1
TS#_DIMM0_1: DM1.134 R1215.2
TS#_DIMM1_1: DM2.134 R1312.2
U22_POWER_K52: CPU1.K52 R721.2
UART0_CTS#: CPU1.U4 TP2011.1
UART0_RTS#: CPU1.U3 TP2010.1
UART0_TXD: CPU1.U2 TP2007.1
UART1_CTS#: CPU1.AB4 TP2015.1
UART1_RXD: CPU1.AC1 TP2012.1
UART_2_CRXD_DTXD: CPU1.AD1 R2048.2 R6809.1
UART_2_CRXD_DTXD_CON: DBG1.14 R6809.2
UART_2_CTXD_DRXD: CPU1.AD2 R2049.2 R6808.1
UART_2_CTXD_DRXD_CON: DBG1.13 R6808.2
USB2_ID: CPU1.AG3 R1601.1
USB2_VBUSSENSE: CPU1.AG4 R1602.1
USB3_PRX_CTX_N1_C: ED3602.1 ED3602.10 R3607.2 USB1.5
USB3_PRX_CTX_N2_C: ED3603.1 ED3603.10 R3611.2 USB2.5
USB3_PRX_CTX_P1_C: ED3602.2 ED3602.9 R3608.2 USB1.6
USB3_PRX_CTX_P2_C: ED3603.2 ED3603.9 R3612.2 USB2.6
USB3_PTX_CRX_N1_C: ED3602.4 ED3602.7 R3605.2 USB1.8
USB3_PTX_CRX_N1_R: C3602.2 R3605.1
USB3_PTX_CRX_N2_C: ED3603.4 ED3603.7 R3609.2 USB2.8
USB3_PTX_CRX_N2_R: C3605.2 R3609.1
USB3_PTX_CRX_P1_C: ED3602.5 ED3602.6 R3606.2 USB1.9
USB3_PTX_CRX_P1_R: C3601.2 R3606.1
USB3_PTX_CRX_P2_C: ED3603.5 ED3603.6 R3610.2 USB2.9
USB3_PTX_CRX_P2_R: C3604.2 R3610.1
USB20_VCCA: AFTP6610.1 C3515.1 C3517.1 C3518.1 C3706.1 ED3704.5 IOBD1.10 IOBD1.11 IOBD1.12 IOBD1.13 U3503.1
USB30_RX_CPU_N1: CPU1.H8 R3607.1
USB30_RX_CPU_N2: CPU1.J6 R3611.1
USB30_RX_CPU_P1: CPU1.G8 R3608.1
USB30_RX_CPU_P2: CPU1.H6 R3612.1
USB30_TX_CPU_N1: C3602.1 CPU1.C13
USB30_TX_CPU_N2: C3605.1 CPU1.B13
USB30_TX_CPU_P1: C3601.1 CPU1.D13
USB30_TX_CPU_P2: C3604.1 CPU1.A13
USB30_VCCC: AFTP3601.1 AFTP3605.1 C3507.1 C3508.1 C3512.1 C3513.1 C3618.1 ED3604.5 TC3501.1 U3501.1 USB1.1 USB2.1
USB_CAMERA_PN4: EL5507.1 LCD1.30 R5533.1
USB_CAMERA_PP4: EL5507.4 LCD1.31 R5534.1
USB_CON_PN6: AFTP6109.1 R6110.1 WLAN1.5
USB_CON_PN7: ED5501.1 LCD1.34 R5535.1
USB_CON_PP6: AFTP6110.1 R6111.1 WLAN1.3
USB_CON_PP7: ED5501.6 LCD1.35 R5536.1
USB_CPU_PN0: CPU1.AB9 EL3601.4
USB_CPU_PN1: CPU1.AD6 EL3602.4
USB_CPU_PN2: CPU1.AH3 EL3706.1 R3701.1
USB_CPU_PN4: CPU1.AJ1 EL5507.2 R5533.2
USB_CPU_PN5: CPU1.AF6 R3301.1
USB_CPU_PN6: CPU1.AH1 R6110.2
USB_CPU_PN7: CPU1.AF8 R5535.2
USB_CPU_PN8: CPU1.AG1 R9203.1
USB_CPU_PP0: CPU1.AB10 EL3601.1
USB_CPU_PP1: CPU1.AD7 EL3602.1
USB_CPU_PP2: CPU1.AJ3 EL3706.4 R3702.1
USB_CPU_PP4: CPU1.AJ2 EL5507.3 R5534.2
USB_CPU_PP5: CPU1.AF7 R3302.1
USB_CPU_PP6: CPU1.AH2 R6111.2
USB_CPU_PP7: CPU1.AF9 R5536.2
USB_CPU_PP8: CPU1.AG2 R9204.1
USB_EN#: KBC24.13 R2479.2
USB_OC0#: CPU1.A9 RN802.6(B) U3501.3
USB_OC1#: CPU1.C9 RN802.5(B)
USB_OC2#: CPU1.D9 RN802.8(B) U3503.3
USB_OC3#: CPU1.B9 RN802.7(B)
USB_PN0_C: AFTP3602.1 ED3604.3 EL3601.3 USB1.2
USB_PN1_C: AFTP3606.1 ED3604.1 EL3602.3 USB2.2
USB_PN2_C: AFTP6603.1 ED3704.6 EL3706.2 IOBD1.6 R3701.2
USB_PN5_C: AFTP6601.1 IOBD1.3 R3301.2
USB_PN8_C: AFTP8903.1 EC9202.1 ED9201.6 FPR1.3 R9203.2
USB_POWERSHARE_VBUS_EN: KBC24.71 TP2403.1
USB_PP0_C: AFTP3603.1 ED3604.4 EL3601.2 USB1.3
USB_PP1_C: AFTP3607.1 ED3604.6 EL3602.2 USB2.3
USB_PP2_C: AFTP6604.1 ED3704.1 EL3706.3 IOBD1.7 R3702.2
USB_PP5_C: AFTP6602.1 IOBD1.4 R3302.2
USB_PP8_C: AFTP8904.1 EC9201.1 ED9201.1 FPR1.4 R9204.2
USB_PWR_EN#: R2434.2 R2479.1 U3501.4 U3503.4
USB_PWR_SHR_EN_L#: KBC24.118 R2493.1
USB_UART_SEL_D9: CPU1.P2 TP2006.1
USBCOMP: CPU1.AB6 R1603.1
V_SM_VREF_CNTA: C1222.1 CPU1.AY67 R1206.2
V_SM_VREF_CNTB: C1323.1 CPU1.BA67 R1305.2
VCI_IN1#: KBC24.126 R2452.1
VCREF0: C2409.1 KBC24.25 R2424.2 R2448.1
VD_IN1_C: C2612.2 C2613.2 R2610.2 R2611.1
VGA_CORE: C8018.1 C8019.1 C8020.1 C8021.1 C8022.1 C8023.1 C8025.1 C8026.1 C8027.1 C8028.1 C8029.1 C8030.1 C8035.1 C8036.1 C8037.1 C8038.1 C8039.1 C8040.1 C8041.1 C8046.1 C8047.1 C8048.1 C8049.1 C8050.1 C8051.1 C8052.1 C8058.1 C8059.1 C8060.1 C8061.1 C8062.1 C8063.1 C8064.1 C8066.1 EC9746.1 EC9750.1 EC9751.1 EC9752.1 EC9753.1 GPU1.AA12 GPU1.AA15 GPU1.M11 GPU1.M13 GPU1.M15 GPU1.M16 GPU1.M17 GPU1.M18 GPU1.M20 GPU1.M21 GPU1.N12 GPU1.N15 GPU1.N17 GPU1.N20 GPU1.R13 GPU1.R16 GPU1.R18 GPU1.T12 GPU1.T15 GPU1.T17 GPU1.T20 GPU1.U11 GPU1.U13 GPU1.U16 GPU1.U18 GPU1.V15 GPU1.V17 GPU1.V20 GPU1.V21 GPU1.Y13 GPU1.Y16 GPU1.Y18 GPU1.Y21 PC8534.1 PC8535.1 PG8508.2 PG8510.2 PL8501.2 PL8502.2 PR8535.2 PR8545.1 PT8506.1 PT8507.1 PT8508.1
VGA_RST#: C7609.1 GPU1.AL27 R7621.2
VGA_SVC: PR8509.1 R7919.1 R7923.2 R7939.1 R7946.1
VGA_SVD: PR8512.1 R7920.1 R7925.1 R7940.2 R7944.1
VGA_SVT: PR8513.1 R7924.2 R7934.1 R7945.1
VGA_VDD_RUN_FB_H: PR8534.2 PR8535.1 TP8502.1
VGA_VDD_RUN_FB_L: PR8530.2 PR8531.1 TP8501.1
VGA_VSUM-_1: PR8529.2 PR8533.1
VR_CAP: C2418.1 KBC24.18
VR_EN: PU4601.40 R4002.2
VR_RDY: AFTP4601.1 PR4609.2 PU4601.39
VR_SVID_ALERT#: PR4605.2 PR4623.1 R727.2 R728.2
VR_SVID_CLK: PR4606.2 PR4624.1 R723.2 R732.2
VR_SVID_DATA: PR4604.2 PR4622.1 R709.2
VRAM_ID1: CPU1.AP8 R2023.2 R2024.1
VREF_CPU: C2406.1 KBC24.95 R2402.2
VREFC_A0: C8101.2 C8103.1 R8105.2 R8107.1 VRAM1.J14
VREFC_A1: C8102.2 C8104.1 R8106.2 R8108.1 VRAM2.J14
WCKA0_0: GPU1.E32 VRAM1.P4
WCKA0_1: GPU1.A21 VRAM1.D4
WCKA0B_0: GPU1.E30 VRAM1.P5
WCKA0B_1: GPU1.C21 VRAM1.D5
WCKA1_0: GPU1.E13 VRAM2.P4
WCKA1_1: GPU1.E3 VRAM2.D4
WCKA1B_0: GPU1.D12 VRAM2.P5
WCKA1B_1: GPU1.F4 VRAM2.D5
WEA0B: GPU1.G25 VRAM1.L12
WEA1B: GPU1.H10 VRAM2.G12
WHITE_LED_BAT: EC6404.1 Q6404.C R6406.1
WIFI_RF_EN: CPU1.B7 R1503.1 R6114.1
WLAN_CLKREQ_WLAN#: AFTP6105.1 R6112.1 WLAN1.53
WLAN_DISABLE#1: AFTP6106.1 R6114.2 WLAN1.56
WLAN_WAKE: TP6101.1 WLAN1.55
XCLK_BIASREF: CPU1.E42 R1803.1
XDP_BPM0: CPU1.C55 TP405.1
XDP_BPM1: CPU1.D55 TP406.1
XDP_BPM2: CPU1.B54 TP407.1
XDP_BPM3: CPU1.C56 TP408.1
XDP_DBRESET#: CPU1.B5 EC1706.1 R1701.2
XDP_PRDY#: CPU1.D56 TP1601.1
XDP_PREQ#: CPU1.D61 TP1602.1
XDP_TCK_JTAGX: CPU1.A59 R417.1
XDP_TCLK: CPU1.B61 R406.1
XDP_TDI: CPU1.D60 R422.1
XDP_TDO_CPU: CPU1.A61 R423.1
XDP_TMS: CPU1.C60 R421.1
XDP_TRST#: CPU1.B59 CPU1.C61 EC401.1 R402.1
XO_IN: GPU1.AC22 RN7904.2(A)
XO_IN2: GPU1.AB22 RN7904.1(A)
XTAL24_IN: CPU1.E37 R1802.1 R1810.1
XTAL24_IN_R: C1801.1 R1810.2 X1801.1
XTAL24_IN_U42: CPU1.E3 R2201.1
XTAL24_IN_U42_R: C2201.1 R2201.2 R2203.1 X2201.1
XTAL24_OUT: C1802.1 CPU1.E35 R1802.2 X1801.3
XTAL24_OUT_R_U42: C2202.1 R2202.2 R2203.2 X2201.3
XTAL24_OUT_U42: CPU1.C7 R2202.1
XTAL_KBC_2: C2424.1 R2458.2 X2401.2
XTL_27M_X1_VGA: C7901.1 GPU1.AM28 R7901.1 X7901.1
XTL_27M_X2_VGA: C7903.1 GPU1.AK28 R7901.2 X7901.3
ZQ_A0: R8110.2 VRAM1.J13
ZQ_A1: R8109.2 VRAM2.J13
ZVM#: CPU1.AR56 TP616.1
N171297876: CPU1.A5
N171299768: CPU1.H63
N171301627: VRAM1.A10
N171301632: VRAM1.U10
N171301637: VRAM2.A10
N171301642: VRAM2.U10
N171378840: CPU1.AN11
N171586817: CPU1.BB67
N171586827: CPU1.BA71
N171586837: CPU1.BA2
N172436911: CPU1.E71

Pads without a net: CPU1 A3 A4 A6 A11 A15 A23 A25 A26 A27 A29 A31 A33 A36 A38 A40 A45 A47 A50 A52 A69 AB1 AB11 AB12 AB13 AB62 AC3 AC63 AD9 AD10 AD11 AD12 AE62 AE63 AF11 AF12 AF13 AG62 AH7 AH8 AH9 AH10 AH11 AH12 AJ62 AK6 AK7 AK9 AK10 AK12 AK13 AK32 AK52 AK53 AK55 AK56 AK58 AK60 AK62 AK70 AL25 AL27 AL53 AL56 AL60 AL61 AL63 AM11 AM22 AM23 AM53 AM56 AM58 AN7 AN8 AN13 AN55 AP5 AP7 AP53 AT5 AT15 AU2 AU5 AU56 AU58 AU63 AW1 AW7 AW20 AW22 AW48 AW56 AW68 AW69 AY1 AY2 AY3 AY9 AY20 AY21 AY56 AY68 B2 B3 B11 B15 B23 B25 B26 B27 B29 B31 B33 B36 B38 B40 B45 B47 B50 B69 B70 BA3 BA4 BA9 BB2 BB4 BB5 BB57 BB66 BB68 BB69 C1 C2 C4 C11 C12 C15 C23 C24 C27 C28 C29 C31 C32 C33 C36 C37 C38 C40 C51 C54 C70 C71 D1 D3 D4 D5 D7 D8 D12 D15 D23 D24 D27 D28 D29 D31 D32 D33 D36 D37 D38 D40 D51 D54 D71 E1 E2 E10 E22 E23 E25 E27 E28 E30 E38 E40 E61 F6 F10 F25 F30 F46 F50 F52 F60 F61 G4 G46 G50 G61 H5 H10 H11 J3 J5 J10 J68 J71 K32 K45 K46 M2 N9 N11 P4 P62 U8 U9 U11 U12 V62 W4 W7 W8 W10 W11 W12; D4001 2; D4002 2; DBG1 1 12; DCIN1 3; DM1 87 88 91 92 95 97 100 101 104 105 162 165; DM2 87 88 91 92 95 97 100 101 104 105 162 165; ED3704 3 4; ED5501 3 4; ED5703 5 6; ED9201 3 4; GPU1 AA5 AA6 AA29 AA31 AB2 AB4 AB7 AB8 AB9 AB11 AB12 AB13 AB23 AB25 AB26 AB27 AB30 AC1 AC3 AC5 AC6 AC7 AC8 AC10 AC11 AC13 AC14 AC16 AC20 AC23 AC25 AD2 AD4 AD7 AD9 AD10 AD11 AD13 AD16 AD20 AD22 AD23 AD24 AE1 AE3 AE5 AE6 AE8 AE9 AE10 AE11 AE13 AE16 AE19 AE22 AE23 AE24 AE25 AE26 AF2 AF4 AF6 AF7 AF8 AF9 AF10 AF11 AF13 AF16 AF17 AF19 AF20 AF22 AF23 AF24 AF25 AG1 AG3 AG5 AG6 AG7 AG8 AG9 AG10 AG11 AG13 AG14 AG15 AG16 AG17 AG18 AG19 AG20 AG21 AG22 AG23 AG24 AG25 AG26 AH1 AH3 AH5 AH6 AH8 AH12 AH14 AH16 AH18 AH20 AH22 AH24 AH26 AJ7 AJ9 AJ13 AJ15 AJ17 AJ19 AJ21 AJ23 AJ25 AK1 AK3 AK5 AK6 AK8 AK14 AK16 AK18 AK20 AK22 AK24 AK26 AL7 AL9 AL13 AL15 AL17 AL19 AL21 AL23 AL25 AM3 AM5 AM6 AM8 AM12 AM14 AM16 AM18 AM20 AM22 AM24 J8 J22 J25 K13 K30 L9 L16 L17 L29 L31 M27 M28 M30 N3 N5 N6 N7 N9 N26 N29 N31 P7 P23 P24 P26 P27 P28 P30 R1 R3 R29 R31 T7 T8 T10 T23 T24 T26 T27 T28 T30 U5 U10 U12 U23 U24 U26 U29 U31 V2 V4 V6 V12 V27 V28 V30 W1 W3 W5 W6 W7 W8 W9 W10 W23 W24 W29 W31 Y2 Y4 Y6 Y7 Y8 Y9 Y11 Y12 Y23 Y24 Y26 Y27 Y28 Y30; HDMI1 13 14; IOBD1 9 14 16 17; KB1 2 3; KBC24 41 89 91 97; LCD1 3 39; ODD1 9 16; PU8501 35; PU8601 5; PU8651 12; RN5502 4 5; U5601 27 31; U6301 A1 A2 A7 A8 A9 A10 A11 A12 A13 A14 B1 B7 B8 B9 B10 B11 B12 B13 B14 C1 C3 C5 C7 C8 C9 C10 C11 C12 C13 C14 D1 D2 D3 D4 D12 D13 D14 E1 E2 E3 E5 E8 E12 E13 E14 F1 F2 F3 F12 F13 F14 G1 G2 G3 G10 G12 G13 G14 H1 H2 H3 H12 H13 H14 J1 J2 J3 J12 J13 J14 K1 K2 K3 K6 K7 K12 K13 K14 L1 L2 L3 L12 L13 L14 M1 M2 M3 M7 M8 M9 M10 M11 M12 M13 M14 N1 N3 N6 N7 N8 N9 N10 N11 N12 N13 N14 P1 P2 P7 P8 P9 P10 P11 P12 P13 P14; U9103 2 4 5 6 7 10 11 12 15 25 26 28 30 31; VGA1 4 11; VRAM1 A5 U5; VRAM2 A5 U5; WLAN1 6 8 9 10 11 12 13 14 15 16 17 19 20 21 22 23 24 25 26 27 28 29 30 31 32 34 36 48 50 59 60 61 62 64 65 66 67 68 70 71 73; X1801 2 4; X1802 2 3

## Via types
v1: diameter 0.508, hole 0.254, TOP to BOTTOM, 4062 vias
v2: diameter 0.356, hole 0.178, TOP to BOTTOM, 1267 vias
v3: diameter 0.559, hole 0.305, TOP to BOTTOM, 82 vias
v4: diameter 0.711, hole 0.406, TOP to BOTTOM, 786 vias

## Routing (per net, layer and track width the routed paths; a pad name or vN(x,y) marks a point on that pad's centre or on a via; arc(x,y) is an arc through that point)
1.8V_RUN_FB: length 3
  BOTTOM w0.254: PC5405.2 160.98,71.82 PR5403.2 161.29,71.52 PR5404.1 161.12,70.85 PU5401.2
3.3V_ALW_1: length 9.4
  BOTTOM w0.102: PR8606.2 142.85,140.83 PC8603.2 142.66,141.07 PR8619.2 142.69,141.7 PC8601.2 143.87,141.33 v2(143.87,140.93) 144.64,140.16 PQ8609.G 144.75,140.14 144.75,139.56 145.15,139.16 145.15,138.45 PQ8604.6 144.22,138.42 144.1,138.3 144.1,137.9 144.23,137.77 PQ8604.5
3.3V_RUN_VGA_1: length 103.3
  TOP w0.102: v1(191.96,181.08) 191.36,180.48 D8602.3 ; D8601.3 139.63,149.57 142.62,149.57 v2(143.24,148.94) 143.68,148.94 144.25,148.36 144.25,145.44 145.4,144.29 v1(148.06,144.29) 148.8,145.03 148.8,146.81 PR8609.2
  L3 w0.102: v1(148.06,144.29) 148.06,148.33 149.02,149.29 149.02,154.03 147.5,155.55 146.23,155.55 145.96,155.83 145.96,155.98 145.93,156.01 145.93,166.69 150.84,171.59 155.51,171.59 158.12,174.2 168.1,174.2 171.11,177.22 174.05,177.22 176.91,180.08 190.96,180.08 v1(191.96,181.08)
  L4 w0.102: v1(147.34,136.52) 147.71,136.9 147.71,143.05 147.43,143.33 147.43,143.69 147.68,143.94 147.71,143.94 v1(148.06,144.29)
  BOTTOM w0.102: PQ8604.3 147.22,137.12 147.35,137 147.35,136.54 v1(147.34,136.52)
3V5V_CT1: length 2.6
  TOP w0.203: U4001.12 45.64,39.9
  TOP w0.254: C4001.1 44.79,38.72 v2(45.45,39.38) 45.64,39.57 45.64,39.9
3V5V_CT2: length 2.6
  TOP w0.203: U4001.10 44.84,40.16 44.58,39.9
  TOP w0.254: 44.58,39.9 v2(44.18,39.5) 43.97,39.29 43.97,38.57 C4002.1
3V5V_S0_ON: length 8
  TOP w0.127: U4001.3 45.64,45.64 44.99,46.29 R4010.2 44.91,46.45 44.53,46.07 v2(44.53,44.81) 44.53,44.17 44.84,43.86 U4001.5
3V_5V_DSW_OK: length 12.7
  TOP w0.102: v1(138.7,44.33) v2(139.26,44.33)
  BOTTOM w0.102: U2101.1 142.7,39.71 142.91,39.92 143.16,39.92 143.33,39.99 143.76,40.42 143.76,42.03 143.76,42.03 143.76,42.7 R2115.2 143.52,42.94 R2114.2 142.68,43.04 142.68,43.05 141.77,43.96 141.7,43.96 141.44,44.21 141.44,44.76 141.15,45.06 140.44,45.06 138.97,43.6 D2101.3 138.72,44.3 v1(138.7,44.33)
3V_5V_EN: length 40.4
  TOP w0.127: v1(53.88,82.43) 53.71,82.59 48.37,82.59 47.87,82.08 45.93,82.08 45.6,82.41 43.76,82.41 42.39,81.04 42.39,78.42 43.57,77.24 43.89,77.24 PR4504.2 44.02,76.45 PR4503.1 ; R4012.1 69.73,84.99 C4009.1 67.85,85.73 R4006.1 67.14,85.65 R4009.1 66.91,84.52 v2(66.92,84.51) 66.21,84.51 D4001.1 65.11,82.99 v1(65.69,82.4)
  L3 w0.127: v1(65.69,82.4) 65.34,82.04 54.26,82.04 v1(53.88,82.43)
3V_5V_POK: length 447.1
  TOP w0.127: v1(162.57,57.26) 162.18,57.65 162.18,60.69 163.61,62.13 163.61,64.95 EC1705.1 162.77,65.6 PR5406.1 162.04,65.72 161.72,66.04 159.96,66.04 159.36,65.45 v1(159.15,65.45) ; PR4534.2 45.29,75.38 v1(45.41,75.51) 45.67,75.51 45.78,75.4 PU4503.7 ; v1(151.75,63.79) 152.21,64.25 152.21,66.95 153.54,68.27 153.54,68.49 153.8,68.75 154.02,68.75 154.85,69.59 155.57,69.59 155.77,69.79 155.77,69.79 v1(155.8,69.79) ; v1(185.21,77.91) 185.2,77.91 185.2,77.9 184.53,77.9 183.92,77.28 181.51,77.28 180.63,78.16 178.44,78.16 177.21,79.39 169.71,79.39 169.39,79.07 169.32,79.07 168.24,77.99 167.43,77.99 165.88,76.43 164.4,76.43 164.01,76.83 v1(164.01,77.39) ; v1(161.82,51.69) 161.55,51.42 160.72,51.42 160.67,51.37 159.55,51.37 157.64,49.46 157.64,49.23 157.33,48.92 157.33,48.9 156.85,48.42 156.26,48.42 155.24,47.41 149.14,47.41 147.63,45.89 147.63,45.03 v2(145.37,42.77) 144.79,42.19 v1(143.3,42.19)
  L3 w0.127: v1(162.57,57.26) 162.57,54.39 161.82,53.64 v1(161.82,51.69) ; v1(30.79,65) 30.79,56.52 24.7,50.43 24.7,44.48 21.08,40.86 21.08,25.8 21.87,25 21.87,21.15 21.88,21.14 21.88,19.99 27.34,14.53 36.51,14.53 49.72,14.53 54.47,9.78 63.29,9.78 64.36,10.84 136.87,10.84 138.66,9.06 150.37,9.06 157.21,2.22 179.01,2.22 180.54,3.76 187.04,3.76 195.03,11.75 195.03,31.15 190.4,35.78 189.05,35.78 185.59,39.25 185.59,42.2 186.11,42.72 186.11,43.09 185.83,43.36 185.83,43.74 186.01,43.92 186.01,48.42 184.06,50.37 184.06,51.41 184.02,51.46 184.02,53.23 184.12,53.33 184.12,53.33 184.38,53.59 184.38,53.59 184.6,53.81 v1(184.6,54.07) ; v1(159.15,65.45) 159.16,65.45 158.95,65.23 153.19,65.23 v1(151.75,63.79)
  L4 w0.127: v1(45.41,75.51) 45.02,75.91 41.69,75.91 v1(30.79,65) ; v1(155.8,69.79) 156.43,69.16 158.06,69.16 158.21,69.01 165.2,69.01 168.01,66.2 169.81,66.2 170.1,66.49 173.4,66.49 174.91,64.98 178.38,64.98 182.67,60.69 182.67,55.89 184.5,54.07 v1(184.6,54.07)
  BOTTOM w0.127: R4033.1 164.5,78.41 164.01,77.91 v1(164.01,77.39) 163.54,77.39 159.27,73.12 159.27,72.47 158.51,71.7 157.98,71.7 157.11,70.83 156.46,70.83 156.44,70.84 156.08,70.84 156.06,70.83 156,70.83 155.8,70.63 155.8,69.84 155.77,69.82 155.77,69.79 v1(155.8,69.79) ; v1(151.75,63.79) 152.11,64.15 R1728.2 ; D2101.1 140.84,44.48 141.91,43.4 R2114.1 141.91,42.82 142.36,42.37 143.11,42.37 v1(143.3,42.19) ; v1(185.21,77.91) 185.95,77.91 186.23,77.63 PR5306.1
3V_5V_POK#: length 3.9
  BOTTOM w0.127: Q1701.6 157.38,64.58 R1726.2 157.63,64.64 157.63,65.38 v2(157.59,65.42) 156.99,65.42 156.8,65.23 Q1701.5
3V_5V_POK_C: length 3.3
  BOTTOM w0.127: R1728.1 153.46,64.42 153.24,64.65 v2(153.24,65.04) 153.24,65.73 R1727.2 154.16,65.23 Q1701.2
3V_FEEDBACK: length 37.2
  TOP w0.254: PR4512.1 46.1,80.31 PR4535.1 46.81,81.07 v1(46.84,81.04) ; v1(38.76,53.32) v2(38.76,52.73)
  L3 w0.254: v1(38.76,53.32) 38.76,57.52 35.93,60.35 35.93,69.33 45.72,79.12 45.72,79.91 v1(46.84,81.04)
  BOTTOM w0.254: PG4535.2 v1(38.76,53.32)
5V_CRT_S0_R: length 11.8
  L3 w1.016: v4(14.64,83.09) 14.23,83.09 14.18,83.03 11.42,83.03 8.33,79.94 VGA1.9
  BOTTOM w0.305: RN5601.4 14.38,82.83 v4(14.64,83.09) 14.23,83.5 RN5601.3
5V_HDMI_S0: length 8.2
  L2 w0.508: HDMI1.18 10.95,56.15 v4(13.37,58.57)
  L3 w0.508: v4(13.37,58.57) 10.95,56.15 HDMI1.18
  vias: v2(14.33,56.95) v2(15.15,80.9) v4(15.83,80.88)
5V_PWR:
  vias: v2(56.19,47.5)
5V_PWR_2: length 2.6
  TOP w0.203: v2(48.72,72.29) 48.72,72.29 PU4503.13
  TOP w0.254: v2(48.72,72.29) 49.17,71.84
  TOP w0.508: 49.17,71.84 PC4524.1
5V_S0: length 263.2
  TOP w0.508: R6705.1 190.51,38.23 190.51,38.16 v1(191.26,37.4) ; v1(25.84,59.11) 25.61,59.34 D5701.3
  L2 w1.524: 157.72,8.26 157.71,8.26 151.57,8.26 150.74,9.09 63.82,9.09 63.57,8.84
  L3 w0.508: v1(148.14,10.96) 148.14,22.06 147.54,22.66 147.54,23.08 v1(146.9,23.72)
  L3 w2.032: 19.61,84.36 41.18,84.36 44.24,87.42 66.12,87.42 86.2,107.5 86.2,107.51 87.38,108.69 87.73,109.04 87.73,109.11 91.79,113.17 91.79,141.19 90.62,142.36 ; 89.92,176.77 87.69,174.54 87.69,162.57 92.65,157.62 92.65,150.14 94.87,147.91 94.95,147.79 94.95,143.75 94.55,143.35
  BOTTOM w0.508: R6512.1 147.68,22.55 147.54,22.7 147.54,23.08 v1(146.9,23.72)
  vias: v1(34.81,15.5) v1(35.57,15.5) v1(48.02,15.17) v1(48.78,15.17) v2(19.83,60.45) v2(21.04,80.77) v2(30.02,53.12) v2(29.99,46.9) v2(48.34,37.39) v2(60.05,11.31) v2(91.02,142.01) v2(161.88,11.71) v2(162.85,11.61) v3(19.11,81.1) v3(19.9,81.1) v3(178.6,11.61) v3(179.37,11.71) v4(16,84.86) v4(16.93,84.88) v4(18.7,61.19) v4(18.7,60.3) v4(27.28,17.22) v4(27.28,16.33) v4(27.35,15.37) v4(28.12,17.25) v4(28.12,16.36) v4(28.21,15.39) v4(29.09,39.84) v4(29.22,50.55) v4(30.08,39.84) v4(30.21,50.54) v4(47.32,41.92) v4(47.32,41.03) v4(48.21,41.92) v4(48.21,41.03) v4(49.1,41.92) v4(49.1,41.03) v4(49.94,41.92) v4(50,41.02) v4(60.76,11.74) v4(60.79,10.88) v4(61.75,11.73) v4(61.78,10.88) v4(62.64,11.73) v4(62.67,10.88) v4(88.66,142.81) v4(88.66,141.94) v4(90.04,180.6) v4(90.04,179.59) v4(112.04,183.53) v4(112.93,183.53) v4(160.21,12.21) v4(160.18,11.37) v4(160.21,10.47) v4(161.09,12.03) v4(161.07,11.19) v4(161.07,10.31) v4(186.54,90.28) v4(186.54,89.38) v4(187.42,89.34) v4(192.11,62.4) v4(192.11,61.55) v4(192.12,60.68) v4(192.1,49.17) v4(192.1,48.33)
5V_S5: length 654
  TOP w0.127: 45.24,42.88 U4001.4
  TOP w0.203: v1(45.07,45.54) 45.24,45.37 45.24,42.88
  TOP w0.254: v1(121.08,149.42) 121.2,149.3 PR4610.1 121.11,148.16 120.35,147.41 PC5001.1 ; PR4635.1 v1(121.16,132.15)
  TOP w0.305: PU5001.6 134.46,133
  TOP w0.381: v1(169.08,86.33) 169.08,88.19 169.7,88.81 C4029.1 169.7,90.22 C4028.1 169.51,90.23 168.53,91.21 ; 134.46,133 134.25,133.21 134.25,136.4 133.67,136.98 v1(132.63,136.98)
  TOP w0.406: PR5107.2 PR5109.2 ; U4002.3 167.47,83.45 167.95,83.45 v1(168.31,83.81) ; U4006.3 168.53,91.21
  TOP w0.508: v1(179.68,86.3) 179.68,84.59 178.31,83.22 178.31,81.85 177.3,80.84 177.3,80.31 177.67,79.94 178.01,79.94 179,78.95 179.04,78.95 179.13,78.86 180.92,78.86 v1(181.8,77.98) 183.63,77.98 185.04,79.4 v1(185.41,79.4) ; PC5401.1 162.63,62.05 162.63,63.4 v1(162.43,63.6) ; 164.34,108.35 164.72,108.74 v1(166.05,108.74) ; 164.34,108.35 164.34,106.97 163.97,106.61 v1(163.97,105.1) ; 164.34,108.35 PC8508.1 ; v1(43.97,17.22) 44.17,17.42 44.17,19.34 PR5109.2 ; 61.91,53.18 61.91,58.14 68.1,64.33 68.1,75.66 v1(68.42,75.97)
  L2 w0.508: v1(181.8,77.98) 182.01,77.98 182.68,77.31 182.68,68.11 178.5,63.93 178.5,60.72 176.77,58.99 175.86,58.99 171.07,54.21 170.76,54.21 170.18,53.62 169.04,53.62 167.43,52.01 163.72,52.01 163.7,51.98 163.16,51.98 162.81,52.33 161.01,52.33 v1(160.53,51.84)
  L2 w1.524: 53.82,44.02 53.82,29.77 53.83,29.76 53.83,23.14 53.38,22.7 53.38,19.45 54.08,18.76 62.6,18.76 68.88,12.47 126.24,12.47 129.63,15.86 131.95,15.86 132.01,15.8 133.81,15.8 v1(136.66,18.64)
  L3 w0.381: v1(129.64,145.94) 130.21,145.94 131.91,144.24 131.91,139.57 132.63,138.85 v1(132.63,136.98) ; v1(104.24,146.75) 107.26,146.75 v1(107.45,146.56)
  L3 w0.508: v1(160.53,51.84) 160.53,58.08 162.43,59.99 162.43,63.59 v1(162.43,63.6) ; v1(43.97,17.22) 43.97,17.28 43.34,17.92 39.17,17.92 38.28,18.81 36.06,18.81 34.58,20.29 34.58,30.27 36.74,32.43 49.58,32.43 50.94,33.79 50.94,42.7 48.09,45.54 v1(45.07,45.54) ; 185.53,29.57 185.53,32 181.29,36.24 181.29,44.4 178.6,47.09 178.6,50.87 v1(177.81,51.67) ; v1(166.05,108.74) 168.73,108.74 v1(169.36,108.11) ; v1(163.97,105.1) 165.33,103.74 165.33,100.24 170.56,95.01 v1(170.56,92.67)
  L4 w0.254: 127.56,131.48 127.47,131.39 121.61,131.39 121.16,131.83 v1(121.16,132.15)
  L4 w0.381: v1(116.68,149.7) 109.91,149.7 107.57,147.36 107.57,146.7 v1(107.45,146.56) ; v1(179.68,86.3) 179.07,85.69 177.32,85.69 176.73,86.28 169.47,86.28 169.46,86.29 169.26,86.29 169.24,86.32 169.16,86.32 169.15,86.33 v1(169.08,86.33)
  L4 w0.508: v1(104.24,146.75) 108.99,151.5 109,154.02 109,164.14 110.22,165.36 110.22,168.1 111.16,169.04 111.16,171.66 110.73,172.09 110.73,173.78 107.82,176.68 95.27,176.68 93.95,175.36 91.52,175.36 89.39,177.5 65.31,177.5 62.22,174.41 v1(61.41,174.41) ; v3(108.7,123.07) 115.7,123.07 v1(116.52,122.24) 126.75,122.24 v1(126.97,122.02) 127.56,122.62 127.56,133.53 129.26,135.23 131,135.23 132.63,136.86 v1(132.63,136.98) ; v1(160.53,51.84) 161.31,51.06 162.46,51.06 162.86,50.66 167.35,50.66 168.44,51.75 172.88,51.75 173.32,52.18 177.29,52.18 v1(177.81,51.67)
  BOTTOM w0.203: PU8501.31 163.8,105.27 v1(163.97,105.1) ; PU8501.26 165.83,108.95 v1(166.05,108.74)
  BOTTOM w0.305: PC5302.1 181.8,78.69 v1(181.8,77.98) 181.66,77.84 PU5301.21
  BOTTOM w0.381: v1(129.64,145.94) 129.87,146.17 129.87,148.29 128.45,149.71 121.36,149.71 v1(121.08,149.42) 120.67,149.02 117.24,149.02 116.68,149.58 v1(116.68,149.7)
  BOTTOM w0.508: v1(185.41,79.4) 184.84,79.97 PR5308.1 ; v1(170.56,92.67) 170.56,90.89 169.08,89.42 v1(169.08,86.33) 168.31,84.45 v1(168.31,83.81) ; Q6403.E 185.02,12.65 186.6,11.07 187.43,11.07 v1(187.6,10.91) ; PR4803.1 127.09,122.23 127.04,122.17 127.04,122.05 127.02,122.02 v1(126.97,122.02) ; v1(169.36,108.11) 168.89,107.64 PR8510.1 ; PR4303.2 61.41,171.65 v1(61.41,174.41) ; PU5401.6 162.39,63.64 v1(162.43,63.6) ; PR4704.1 v3(108.7,123.07) ; Q6404.E 171.11,6.58 v1(171.68,6.01) ; PR4813.1 116.95,122.67 v1(116.52,122.24) ; v1(68.42,75.97) 68.42,79.99 71.28,82.85 73.93,82.85 76.55,85.47 76.55,95.15 86.6,105.19 86.6,106.13 87.93,107.45 91.3,110.83 91.3,116.43 93.25,118.38 93.25,136.45 103.55,146.75 v1(104.24,146.75)
  vias: v1(134.64,18.64) v2(26.02,44.73) v2(46.16,45.65) v2(54.72,47.12) v2(134.98,17.53) v2(138.26,41.26) v2(181.44,26.93) v4(26.78,45.98) v4(27.63,45.08) v4(27.57,44.19) v4(27.71,46.13) v4(51.68,45.8) v4(52.26,44.99) v4(53.03,45.82) v4(53.5,44.93) v4(54.09,45.82) v4(57.16,49.3) v4(57.16,48.03) v4(57.69,51.82) v4(57.67,50.95) v4(57.84,52.86) v4(137.4,42.7) v4(137.58,41.85) v4(138.23,42.85) v4(138.51,41.89) v4(180.88,26.39) v4(181.93,26.39) v4(193.34,27.27) v4(193.34,26.13) v4(193.34,24.99)
+3V_1D8V_AVDD: length 7
  TOP w0.508: v1(166.12,17.03) 166.69,16.47 v2(166.69,16.13) R2719.2
  BOTTOM w0.203: 169.14,17.73 HDA27.33
  BOTTOM w0.254: 166.12,17 166.86,17 167.25,17.39 168.8,17.39 169.14,17.73 ; 166.12,17 v1(166.12,17.03) ; 166.12,17 C2710.1
+3V_1D8V_DVDD: length 2.6
  BOTTOM w0.508: R2710.1 178.55,21.85 178.29,22.11 178.29,22.99 177.96,23.32 177.34,23.32 v1(177.33,23.31)
  vias: v1(167.41,23.08) v1(173.7,22.83) v1(174.39,23.19) v2(166.52,23.45) v2(176.49,23.8)
+5V_AVDD:
  vias: v2(175.91,15.73)
+5V_PVDD:
  vias: v2(159.93,21.47) v2(159.87,18.14)
+5V_PVDD1: length 0.6
  BOTTOM w0.127: 169.28,18.13 HDA27.34
  vias: v1(167.7,21.46) v1(167.88,18.06) v1(168.38,20.93) v1(168.57,18.06) v1(168.92,20.35) v2(164.29,19.79) v2(168.51,18.77)
+V1.00A_SIP: length 53.4
  L3 w0.508: v1(130.06,91.77) 128.76,90.48 127.37,90.48 127.29,90.4 v1(127.22,90.4) 127.24,90.38 127.24,89.73 126.63,89.12 v1(126.63,89.11)
  L4 w0.305: v1(130.13,100.95) 130.13,100.91 128.44,99.23 125.44,99.23 124.78,99.89 124.78,100.66 123.45,102 118.06,102 116.67,103.39 v1(116.67,103.79)
  BOTTOM w0.127: 127.29,86.21 127.46,86.21 127.66,86 127.91,86 128.12,86.21 128.34,86.21 CPU1.AB20 ; v1(132.38,99.56) 132.56,99.39 132.56,98.56 132.01,98.01 132.01,97.63 132.01,97.63 CPU1.A14 ; CPU1.L1 140.3,92.11 140.52,92.33 141.17,92.33 141.46,92.04 v1(141.46,91.92)
  BOTTOM w0.178: CPU1.T1 140.34,89.46 140.51,89.29 141.18,89.29 141.21,89.32
  BOTTOM w0.203: v1(130.06,91.77) 130.39,92.1 CPU1.K17 ; CPU1.P18 129.34,89.27 127.7,89.27 126.96,88.53 126.68,88.53
  BOTTOM w0.254: CPU1.L21 128.2,91.75 128.56,91.75 128.99,92.18 CPU1.K19 CPU1.L19 ; v1(142.62,89.86) 142.56,89.86 142.02,89.32 141.21,89.32 ; 127.29,86.21 126.3,86.21 v1(126.11,86.4) 125.46,85.75 125.34,85.75 125.32,85.74 124.93,85.74 124.66,86.01 124.66,88.2 124.99,88.53 126.68,88.53 ; v1(127.22,90.4) 127.22,90.37 127.49,90.1 128.18,90.1 128.44,90.36 CPU1.N20 ; v1(134.03,99.66) 134.36,99.34 134.36,97.46 134.37,97.38 CPU1.A10
  BOTTOM w0.305: v1(128.13,82.55) 128.13,82.53 128.15,82.53 128.44,82.24 CPU1.AK20 ; CPU1.L21 127.74,91.34 127.22,90.81 v1(127.22,90.4)
  BOTTOM w0.508: R1803.2 116.67,101.82 v1(116.67,103.79)
  vias: v1(128.11,86.71) v1(140.72,97.53) v1(153.91,96.37) v1(154.44,95.98) v2(127.31,87.48) v2(154.13,95.33) v2(154.64,96.7) v2(165.31,91.7)
+V1.00U_CPU: length 54.9
  TOP w0.254: v1(142.72,105.07) 142.22,105.07 141.58,104.43 141.58,103.53 138.6,100.55 138.6,100.49 138.56,100.45 138.56,100.33 138.2,99.97 138.2,95.99 138.84,95.35 138.84,91.57 137.79,90.53 137.17,90.53 137.03,90.67 131.36,90.67 v2(131.3,90.73) 130.33,90.73 129.39,91.67 C721.1 ; v1(126.5,91.62) 126.78,91.9 127.72,91.9 C720.1 127.95,91.67 C721.1 ; C721.1 128.58,91.9 R4036.1
  L4 w0.254: v1(159.19,92.38) 159.19,92.62 156.56,95.25 155.93,95.25 154.3,96.88 154.09,96.88 152,98.97 151.07,98.97 149.89,100.15 149.89,101.06 147.24,103.71 146.61,103.71 146.61,103.72 145.04,103.72 145,103.75 144.97,103.75 143.61,105.11 142.73,105.11 142.69,105.07 v1(142.72,105.07)
  BOTTOM w0.254: CPU1.K20 CPU1.K21 127.06,92.18 v1(126.5,91.62)
  vias: v2(159.97,93.5)
+V1.00U_CPU_LS:
  vias: v2(163.03,92.16)
+V1.8A_SIP: length 121.1
  TOP w0.254: R1816.1 137.29,61.79 137.29,56.3 v2(138.29,55.29) 139.46,54.13 139.46,52.65 139.55,52.56 140.94,51.17 141.2,51.17 141.62,51.17 142.58,52.13 143.92,52.13 144.79,53 144.79,56.54 144.34,57 144.3,57 144.25,57.04 143.84,57.04 142.94,57.94 142.94,58.89 142.75,59.08 142.75,60.64 v1(143.65,61.54) ; v1(145.63,63.21) 145.5,63.34 R1607.1 145.5,63.99 145.2,64.29 145.17,64.29 144.99,64.46 144.99,65.43 R2017.1
  TOP w0.508: R1818.2 154.85,79.55 R2022.1 ; R1818.2 154.85,78.19 v2(155.17,77.87) 155.45,77.58 155.45,76.74 155.5,76.7 155.5,75.8 v1(155.57,75.72) 155.57,75.55 155.81,75.31 155.84,75.31 156.21,74.94 156.21,74.92 156.29,74.84 R2001.2 ; R1818.2 153,78.77 152.5,79.27 ; v1(140.46,86.91) 140.17,86.62 C2108.1 ; R1718.1 153.54,70.08 154.54,70.08 154.93,70.46 155.3,70.46 155.33,70.49 155.58,70.49 155.64,70.43 156.23,70.43 156.25,70.41 156.34,70.41 v1(156.34,70.4) ; v1(151.74,69.08) 151.56,69.08 150.81,68.34 150.81,68.26 148.86,66.31 148.86,65.7 148.23,65.07 148.23,63.46 v1(148.1,63.33)
  L3 w0.381: v1(151.74,69.08) 152.51,69.86 154.46,69.86 154.96,70.36 156.31,70.36 v1(156.34,70.4)
  L3 w0.457: v1(128.12,85.06) 131.65,88.58 133.19,88.58 133.52,88.25 133.52,87.78 134.39,86.91 v1(140.46,86.91)
  L3 w0.508: v1(148.1,63.33) 145.75,63.33 v1(145.63,63.21) 144.91,62.49 144.91,62.45 144.08,61.61 143.72,61.61 v1(143.65,61.54) ; v1(140.46,86.91) 140.87,87.32 141.99,87.32 142.89,86.41 147.51,86.41 148.15,85.77 148.15,85.25 151.42,81.98 v1(151.42,81.66)
  L4 w0.508: v1(155.57,75.72) 156.56,74.73 156.56,70.7 156.34,70.48 v1(156.34,70.4)
  BOTTOM w0.089: CPU1.AA1 139.49,86.91 139.3,87.1 134.74,87.1 134.43,86.79 133.76,86.79 133.47,86.5 133.47,86.06 132.89,85.48 132.89,85.09 ; CPU1.AK15 132.24,82.67 132.24,83.54 132.44,83.75
  BOTTOM w0.102: 132.89,85.09 132.89,84.19 132.44,83.75
  BOTTOM w0.203: v1(128.12,85.06) 130.61,85.06 CPU1.AF16
  BOTTOM w0.254: v1(145.63,63.21) R2004.2 ; v1(143.65,61.54) 143.65,60.33 143.17,59.86 143.02,59.83 141.74,59.83 140.52,61.05 140.52,64.51 140.21,64.82 v2(140.21,64.93) R2015.1 ; v1(140.46,86.91) 140.36,86.81 CPU1.AA1
+V3.3A_SIP: length 51.2
  L3 w0.381: v4(157.45,81.74) 157.45,83.23 158.66,84.44 158.66,85.66 159.16,86.15 159.16,91.12 158.26,92.01 158.26,94.61 155.99,96.88 155.99,99.2 151.21,103.98 v1(149.18,103.98)
  L4 w0.508: v1(132.19,86.94) 130.45,86.94 130.04,87.35 127.22,87.35 126.67,86.8 v1(126.67,86.75)
  BOTTOM w0.127: CPU1.AK17 130.69,81.81 131.18,81.81 131.38,82.02 131.38,82.24 131.56,82.42 131.59,82.42 131.99,82.83 131.99,83.11 131.85,83.27 v1(131.33,83.38)
  BOTTOM w0.203: CPU1.AJ16 131.33,83.25 v1(131.33,83.38) ; CPU1.T16 131.46,89.25 131.99,89.25 132.05,89.18 v1(132.14,89.18) ; v1(132.19,86.94) 132,86.75 131.43,86.75 CPU1.Y16 ; v1(126.67,86.75) 126.84,86.75 127.41,87.32 127.44,87.32 127.63,87.52 128.62,87.52 129.09,87.99 CPU1.V19
  BOTTOM w0.254: R1701.1 147.43,105.85 v2(148.59,104.69) 149.18,104.11 v1(149.18,103.98) ; CPU1.AD15 131.69,85.42 v1(132.21,84.9) 132.2,84.9 132.11,84.81 132.11,84.51 131.69,84.08 CPU1.AG15 ; v1(132.19,86.94) 132.19,86.94 131.99,87.15 CPU1.Y15
  BOTTOM w0.305: CPU1.AJ21 127.34,82.96 v1(127.24,82.86)
  vias: v2(132.29,83.47) v2(158.45,80.01) v4(158.26,81.45)
+VCCAMPHYPLL_1P0: length 29.9
  TOP w0.254: v1(155.2,95.15) 155.57,95.52 v2(155.57,95.57)
  L3 w0.254: v1(155.2,95.15) 154.33,95.15 153.67,95.81 146.33,95.81 146.05,96.09 134.82,96.09 132.57,93.85 132.57,92.93 v1(132.11,92.47)
  BOTTOM w0.254: CPU1.L15 CPU1.K15 131.97,92.46 132.09,92.46 v1(132.11,92.47) ; v1(155.2,95.15) 155.49,94.86 156.15,94.86 C2113.1 156.24,94.86 157.42,94.86 R2112.2
+VCCAPLL_1P0: length 23.9
  TOP w0.254: R2108.2 152.11,92.06 C2114.1 151.4,91.37 150.38,91.37 150.2,91.19 148.01,91.19 147.05,90.22 145.76,90.22 145.75,90.23 145.36,90.23 145.36,90.22 145.07,90.22 143.86,89.02 142.31,89.02 141.81,88.52 139.53,88.52 138.52,87.51 v2(134.29,87.51) 134.16,87.51 133.59,88.08 133.02,88.08 v1(132.95,88.01)
  BOTTOM w0.254: CPU1.V15 131.78,88.08 132.88,88.08 v1(132.95,88.01)
+VCCDSW_1P0: length 3.1
  TOP w0.254: C2103.1 139.96,82.28 v2(139.96,81.51) 140.05,81.42 v1(140.77,81.42)
  BOTTOM w0.254: CPU1.AL1 139.54,81.46 140.74,81.46 v1(140.77,81.42)
+VCCFUSEPRG: length 2.5
  TOP w0.254: R703.1 129.35,94.44 129.35,93.88 v2(129.21,93.74) 129.15,93.68 128.7,93.68 v1(128.47,93.91)
  BOTTOM w0.254: v1(128.47,93.91) 128.55,93.91 128.87,93.59 CPU1.G20
+VCCGT: length 44.1
  TOP w0.254: v1(115.96,134.61) 116.25,134.32 PR4663.2
  L4 w0.254: v1(106.37,118.72) 106.37,122.75 106.37,122.75 106.37,126.77 105.44,127.7 99.04,127.7 98.53,128.2 98.53,130.39 98.43,130.5 98.43,130.92 98.53,131.03 98.94,131.43 103.78,131.43 105.82,133.47 114.83,133.47 v1(115.96,134.61)
  BOTTOM w0.102: 104.53,88.42 104.76,88.65 104.76,88.7
  BOTTOM w0.203: v1(101.94,98.63) 102.27,98.29 CPU1.A66 ; CPU1.A62 v1(104.75,98.3) ; CPU1.A58 v1(107.23,98.3)
  BOTTOM w0.508: v1(88.7,91.67) 88.32,91.29 R712.1
  vias: v1(97.8,95.4) v1(99.51,90.1) v1(99.51,88.27) v1(99.51,86.44) v1(100.16,90.1) v1(100.16,86.44) v1(100.81,90.1) v1(100.81,88.27) v1(101.46,88.27) v1(101.46,86.44) v1(102.11,90.1) v1(102.11,86.44) v1(102.76,88.27) v1(103.42,90.1) v1(103.4,88.27) v1(104.07,90.1) v1(106.31,82.78) v1(108.36,82.65) v1(110.16,82.65) v2(81.49,84.13) v2(95.26,88.65) v2(99.75,91.72) v2(102.9,111.62) v2(103.23,116.66) v2(106.64,88.62) v2(110.78,84.28) v3(105.75,90.1) v3(106.61,90.12) v3(107.2,89.71) v3(107.68,89.18) v3(108.41,89.18) v3(108.47,90.68) v3(109.23,90.65) v3(109.18,89.16) v4(81.24,87.45) v4(81.41,86.55) v4(81.9,88.09) v4(82.2,87.15) v4(82.63,88.78) v4(83.04,87.84) v4(83.37,89.28) v4(83.67,88.39) v4(87.41,92.31) v4(88.3,92.36) v4(89.64,91.8) v4(97.04,95.38) v4(101.33,114.65) v4(101.39,116.65) v4(101.39,115.59) v4(101.76,113.52) v4(101.78,112.47) v4(102.62,113.49) v4(102.62,112.52) v4(103.47,113.51) v4(103.48,112.49) v4(104.38,113.51) v4(104.37,112.53) v4(105.29,113.55) v4(105.3,112.53) v4(105.65,92.18) v4(105.92,116.45) v4(105.99,115.47) v4(106.03,114.44) v4(106.17,113.56) v4(106.18,112.57) v4(106.28,87.38) v4(106.51,92.18) v4(106.82,83.48) v4(106.99,86.64) v4(107.43,92.23) v4(108.19,87.76) v4(108.16,86.29) v4(108.32,92.23) v4(109.01,84.91) v4(109.07,87.73) v4(109.18,86.31) v4(109.16,83.39) v4(109.29,92.22) v4(110.01,83.39) v4(110.19,92.24) v4(110.88,83.39)
+VCCIO: length 22.4
  TOP w0.508: v1(111.64,92.15) 111.64,92.31 111.7,92.37 111.7,92.38 112.05,92.72 112.08,92.72 R801.1
  L3 w0.381: v1(111.64,92.15) 111.64,91.71 111.91,91.44 114.15,91.44 115.76,89.84 115.76,84.61 116.11,84.25 116.11,83.11 116.52,82.7 v1(116.54,82.7) 117.22,82.03 122.23,82.03 122.74,82.54 v1(122.74,82.78)
  BOTTOM w0.305: v1(116.54,82.7) 116.58,82.67 CPU1.AL42 116.12,81.37 CPU1.AM42
  vias: v1(122.07,81.03) v1(122.18,83.44) v1(122.82,83.42) v1(122.98,81.03) v2(121.95,81.59) v2(161.53,83.01) v4(163.83,83.36) v4(163.81,82.5)
+VCCMPHYGTAON_1P0_LS_SIP: length 7.6
  TOP w0.305: v1(127.46,85.05) 127.46,85.13 128.16,85.83 C1180.1
  L4 w0.254: v1(160.26,91.86) 160.5,91.86 161.56,90.8 161.56,90.74 161.58,90.73 v1(161.58,87.42)
  BOTTOM w0.178: CPU1.AF20 CPU1.AF21
  BOTTOM w0.254: CPU1.AF21 v1(127.46,85.05)
  vias: v1(128.12,88.42) v1(130.71,90.06) v1(131.37,90.09) v1(132.1,90.11) v1(158.32,88.4) v1(158.36,89.04) v2(128.68,89.54) v2(158.14,89.81)
+VCCPAZIO: length 39.9
  TOP w0.254: v1(155.56,83.1) 155.58,83.1 v2(155.96,83.48)
  L3 w0.254: v1(155.56,83.1) 155.54,83.1 153.6,81.16 151.21,81.16 147.65,84.72 147.65,85.55 147.35,85.85 141.46,85.85 140.94,86.37 131.92,86.37 129.28,83.73 127.13,83.73 126.81,84.05 v1(126.04,84.05)
  BOTTOM w0.127: 128.81,83.11 128.66,83.26 127.47,83.26 127.44,83.29 127.43,83.29 127.42,83.3 127.05,83.3 126.8,83.05 126.47,83.05 126.45,83.03 126.2,83.03 126.02,83.21
  BOTTOM w0.254: CPU1.AJ19 128.97,82.96 128.81,83.11 ; 126.02,83.21 126.02,84.03 v1(126.04,84.05) ; v1(155.56,83.1) 155.58,83.1 155.58,83.12 155.78,83.32 156.25,83.32 R2101.2
+VCCPDSW_3P3: length 51.7
  TOP w0.254: v1(155.93,74.15) 155.98,74.15 156.35,73.77 R1711.2
  L3 w0.254: v1(155.93,74.15) 156.08,74.3 156.08,75.93 155.78,76.23 154.85,76.23 153.86,77.23 150.39,77.23 148.33,79.29 147.59,79.29 144.4,82.47 141.81,82.47 141.8,82.47 141.2,82.47 141.18,82.49 137.22,82.49 136.97,82.25 135.33,82.25 134.61,82.96 133.46,82.96 133.1,83.32 132.4,83.32 132.37,83.3 131.98,83.3 131.69,83 131.69,82.35 131.15,81.82 126.72,81.82 126.14,82.39 126.14,82.81 126.55,83.22 v1(126.55,83.47)
  BOTTOM w0.127: 126.64,83.55 127.56,83.55 127.64,83.48 128.87,83.48 128.97,83.38 129.25,83.38 ; 128.36,85.87 128.08,85.87 128,85.79 127.57,85.79 127.52,85.84 126.67,85.84 126.54,85.71
  BOTTOM w0.203: 128.36,85.87 129.34,85.87 CPU1.AD18 ; CPU1.AJ17 129.96,83.38 129.25,83.38
  BOTTOM w0.254: CPU1.AD18 CPU1.AD17 ; v1(126.55,83.47) 126.7,83.62 126.7,84.66 126.42,84.94 126.42,85.59 126.54,85.71 ; v1(155.93,74.15) 156.56,73.51 R1707.1 156.56,72.33 v2(156.64,72.25)
+VCCPRIM_CORE: length 3.9
  BOTTOM w0.14: CPU1.V21 127.76,87.96 127.03,87.96
  BOTTOM w0.152: 127.03,87.96 126.02,87.96 v1(125.13,87.07) v1(125.13,86.21)
  vias: v1(127.46,84.2) v1(128.11,84.2) v2(125.76,87.81) v2(167.11,92.59) v4(167.92,92.63) v4(168.76,92.61) v4(169.59,92.65)
+VCCPRTC_3P3: length 49
  TOP w0.254: v1(144.6,57.73) 144.63,57.7 R2107.2 145.71,56.78 v2(145.49,56.56)
  L4 w0.203: 128.92,77.83 128.92,79.48 128.9,79.51 128.92,79.54 128.92,79.92 128.9,79.94 128.92,79.96 128.92,80.19 128.91,80.2 128.91,80.57 v1(128.46,81.02)
  L4 w0.254: 128.92,77.83 128.92,77.62 129.75,76.79 129.75,75.98 134.17,71.56 134.17,70.99 134.47,70.69 135.08,70.69 v1(135.16,70.78) 135.68,70.78 136.48,69.98 136.48,68.86 138.21,67.13 138.71,67.13 139.15,66.69 139.15,66.07 138.75,65.66 138.75,57.76 141.89,54.61 143.85,54.61 144.7,55.47 144.7,56.99 144.65,57.04 144.65,57.61 v1(144.6,57.73)
  BOTTOM w0.089: CPU1.BB14 131.83,74.15 132.45,73.53 132.47,73.53 133.63,72.37 133.63,72.36
  BOTTOM w0.102: 133.63,72.36 134.06,71.93 134.06,71.35
  BOTTOM w0.127: v1(135.16,70.78) 134.53,70.78 134.06,71.25 134.06,71.35
  BOTTOM w0.254: v1(128.46,81.02) 128.48,81.04 128.48,81.64 128.96,82.12 CPU1.AK19
+VCCSA: length 8.1
  BOTTOM w0.762: 124.27,83.52 124.01,83.77 124.01,85.82 123.97,85.86 123.97,88.36 124.01,88.39 124.01,90.86 123.6,91.26
  vias: v1(122.97,92.1) v1(124.75,91.62) v1(124.67,82.83) v1(124.77,92.31) v1(125.31,83.57) v1(125.36,82.88) v1(125.53,98.07) v1(125.72,93.92) v1(125.66,92.28) v1(125.76,91.62) v1(125.86,97.44) v2(125.33,94.87) v2(125.31,84.15) v2(137.29,114.81) v2(137.65,110.54) v4(123.95,92.2) v4(134.91,113.41) v4(134.89,112.49) v4(134.88,111.51) v4(134.86,110.54) v4(135.77,113.42) v4(135.85,111.55) v4(135.77,110.53) v4(135.87,112.48) v4(136.66,113.44) v4(136.73,112.5) v4(136.74,111.56) v4(136.7,110.54)
+VCCST_CPU: length 165.7
  TOP w0.254: v1(97.59,123.97) 95.92,122.3 v1(95.92,105.21) v1(97.26,105.21) 97.26,104.62 v1(97.92,103.96) ; 129.79,98.82 129.83,98.78 129.83,95.51 C716.1 129.73,95.01 129.73,93.3 129.44,93.01 R4036.2 ; 129.79,98.82 129.79,99.95 132.72,102.88 132.72,105.97 v1(132.98,106.22) ; 129.79,98.82 v1(129.74,98.87) ; PC4602.1 127.4,149.91 PR4603.1 124.76,149.91 PR4606.1 123.4,149.91 PR4605.1 PR4604.1 121.68,150.19 117.77,150.19 117.37,149.8 v1(117.37,149.69)
  L4 w0.254: v1(117.37,149.69) 117.37,149.68 ; 117.37,149.68 116.89,149.19 110.8,149.19 103.96,142.36 99.51,142.36 98.51,141.36 98.51,138.05 97.92,137.45 97.92,125.51 98.22,125.21 98.22,124.42 97.77,123.97 v1(97.59,123.97) ; 117.37,149.68 117.37,149.57 117.82,149.12 119.19,149.12 119.99,149.93 123,149.93 125.67,147.26 126.99,147.26 130.2,144.05 130.86,144.05 131.37,143.54 131.37,142.07 139,134.44 139,126.57 138.97,126.54 138.97,117.65 137.85,116.54 137.85,116.49 137.83,116.47 137.83,110.12 133.94,106.22 v1(132.98,106.22)
  BOTTOM w0.203: CPU1.A18 129.53,98.52 129.74,98.73 v1(129.74,98.87)
  BOTTOM w0.254: R727.1 101.08,104.35 99.78,104.35 98.91,105.21 v1(97.26,105.21) ; R419.1 100.43,105.37 R723.1 99.84,105.96 98.5,105.96 v2(97.64,106.05) 96.67,105.96 v1(95.92,105.21) ; v1(97.92,103.96) 98.2,103.96 99.09,103.08 R603.2 R726.1
+VCCSTG: length 138.6
  TOP w0.254: v1(134.02,106.97) 133.06,106.97 132.28,106.2 132.28,104.24 126.63,98.58 ; 127.74,96.09 128.94,96.09 129.14,95.89 R703.2 ; 127.74,96.09 127.74,97.46 126.63,98.58 ; 127.74,96.09 127.74,95.43 C717.1 ; R1722.1 79.66,85.27 80.14,85.75 80.14,92.97 81.99,94.82 81.99,98.07 88.77,104.85 94.1,104.85 v1(94.61,105.36) 94.94,105.03 94.95,105.03 v1(94.95,103.16) ; v1(159.29,85.26) 159.29,85.3 159.93,85.93 R4048.2 ; 126.63,98.58 v1(126.62,98.57)
  L3 w0.254: v1(134.02,106.97) 137.45,106.97 141.1,110.62 v1(141.1,111.45)
  L4 w0.254: v1(159.29,85.26) 160.11,86.08 160.11,91.3 159.7,91.71 159.7,92.65 156.72,95.63 156.09,95.63 154.43,97.29 154.21,97.29 152.15,99.35 151.84,99.35 151.23,99.35 150.27,100.31 150.27,101.22 147.39,104.09 145.11,104.09 142.26,106.95 142.06,106.95 141.1,107.91 141.1,108.11 v1(141.1,111.45) ; v1(126.62,98.57) 126.46,98.73 125.42,98.73 124.42,99.73 124.42,100.24 123.05,101.6 117.54,101.6 v1(114.73,104.41)
  BOTTOM w0.254: v1(126.62,98.57) 127.01,98.18 127.01,97.48 127.05,97.37 CPU1.A22 ; v1(94.95,103.16) 95.38,103.59 96.47,103.59 R401.1 ; v1(114.73,104.41) 112.84,106.3 108.74,106.3 R409.2 R408.2 106.98,105.42 R416.2 R417.2 R422.2 R421.2 R423.2 102.65,106.49 95.73,106.49 v2(95.27,106.02) v1(94.61,105.36)
+VDDQ_CPU_CLK: length 51.9
  L3 w0.203: 99.07,86.92 102.91,86.92 103.33,86.49 103.33,86.17
  L3 w0.254: v1(81.09,76.75) 81.09,77.48 90.53,86.92 99.07,86.92 ; 103.33,86.17 104.6,84.91 104.6,82.58 105.32,81.87 115.78,81.87 v1(116.58,81.06)
  BOTTOM w0.254: v1(81.09,76.75) v2(80.07,76.75) 79.14,76.75 78.93,76.54 C722.1 78.93,73.99 78.37,73.43 R705.2 78.37,72.46 C715.1 ; v1(116.58,81.06) 116.87,81.35 CPU1.AM40
AV1_TP: length 4.4
  TOP w0.102: v1(140.59,77.48) 140.09,77.48 138.87,78.7 138.87,79.5 TP2310.1
  BOTTOM w0.102: CPU1.AV1 139.82,77.48 v1(140.59,77.48)
AV71_TP: length 7.9
  BOTTOM w0.102: TP2304.1 93.78,78.9 93.89,78.64 94.57,77.95 95.95,77.95 96.98,76.93 96.98,76.31 97.33,75.96 97.66,75.96 99.09,77.4 CPU1.AV71
AVCC33: length 5.8
  TOP w0.203: 26.32,74.96 26.32,75.32 U5601.1
  TOP w0.508: v1(26.7,74.22) 26.7,74.33 26.32,74.71 26.32,74.96
  BOTTOM w0.508: v1(26.7,74.22) 26.58,74.1 26.58,73.62 C5606.1 26.63,73.37 C5621.2 26.66,72.45 R5610.2 25.6,71.2 v2(25.49,71.31)
DVSS: length 3.5
  BOTTOM w0.102: HDA27.10 174.14,21.66 174.29,21.81 174.63,21.95 174.82,21.95 175.31,22.44 v2(175.31,22.98) 175.31,23.43 175.59,23.7 R2716.2
GND: length 1971.6
  TOP w0.203: v1(21.14,75.2) 21.4,75.2 21.64,75.44 U5601.24 ; v1(37.23,24.09) 37.68,23.63 PU5101.1 ; v1(41.71,23.06) 41.7,23.05 PU5101.14
  TOP w0.254: PC8502.1 153.47,111.74 152.25,111.74 v1(151.75,112.24) ; v1(146.33,65.9) 146.27,65.9 146.03,65.66 R2018.2 ; v1(127.24,183.36) 127.08,183.21 126.1,183.21 PR4478.2 ; PC4633.2 129.86,138.05 130.32,138.05 v1(130.39,138.12) ; R2401.2 v1(157.79,77.39) 157.63,77.32 157.1,77.54 R2020.2 ; R1501.2 133.29,93.9 v1(133.92,93.27) ; C2429.2 170.93,42.9 170.8,42.77 v1(170.8,42.77) ; G6401.2 186.49,178.41 v1(185.71,178.41)
  TOP w0.305: v1(178.86,80.24) 178.96,80.14 178.96,79.92 179.27,79.61 179.31,79.61 179.4,79.52 183.89,79.52 184.42,80.05 ODD1.1 ; ODD1.4 185.43,81.55 185.5,81.62 185.51,81.62 185.75,81.85 185.75,82.78 185.48,83.05 ODD1.7 183.07,83.05 182.94,83.18 v1(182.94,83.22) ; PR4526.2 v1(50.14,81.18) ; C8003.2 166.52,146.2 v1(166.61,146.11) ; PQ4306.1 78.45,163.58 78.68,163.35 v1(78.75,163.35) ; R1205.1 136.67,35.29 136.73,35.24 v1(136.92,35.24) ; v1(75.38,164.05) 75.56,164.23 75.56,164.7 76.22,165.37 PQ4306.4 76.8,165.65 76.5,165.95 ; v1(171.82,146.26) 171.83,146.27 C8004.2 ; v1(126.93,85.43) 127.25,85.75 C1180.2 ; C8006.2 172.97,146.17 v1(173.03,146.12) ; v1(195.35,175.64) 195.36,175.65 AFTP6403.1 ; v1(185.83,139.78) 185.83,139.5 185.27,138.94 R7820.2 ; R1210.1 135.8,32.73 136.22,33.15 v1(136.96,33.15) ; v1(178.69,159.4) 178.72,159.37 C8033.2 ; v1(101.57,93.7) 101.56,93.7 101.59,93.67 101.59,92.83 R414.1 ; v1(18.3,29.51) AFTP3604.1
  TOP w0.356: v3(183.17,86.67) 183.12,86.62 C6018.2 ; 160.68,105.57 PQ8501.1 ; EC9733.2 58.67,53.95 ; v1(154.62,67.37) 154.62,67.29 154.74,67.17 Q1702.4 ; RN5602.2 27.5,84.12 27.5,84.13 ; 140.16,174.6 139.08,173.52 PQ4415.E ; v1(127.47,177.2) 127.47,178.26 PQ4406.1 ; PQ4406.4 125.45,180.08 v1(125,179.63) ; EC1707.2 153.44,64.13 Q1702.1
  TOP w0.381: v1(116.07,130.7) 116.07,132.07 117.57,133.57 PC4644.2 ; 156.5,17.06 156.5,17.07 EC2903.2 ; 158.35,16.97 EC2904.2 ; C4018.2 171.18,91.83 v1(172.06,92.71) ; v1(34.67,179.3) ED3201.8 ED3201.3 ; HS1.1 118.69,159.26 EC8917.2 ; PC4615.1 129.67,143.29 PR4621.1 ; R415.1 103.38,90.83 102.76,90.21 v1(102.76,90.1) ; PC4631.2 114.3,139.7 PC4620.2 v1(114.3,141.35) ; v1(20.49,57.75) 20.67,57.93 R5711.2 ; 162.56,104.04 162.56,103.43 162.55,103.42 v4(162.55,103.33) ; v1(163.81,84.41) 163.86,84.41 164.17,84.1 ; PC4603.1 116.18,147.76 v1(115.9,148.03) ; C4029.2 170.61,89.44 C4028.2 170.85,90.47 171.11,90.47 171.53,90.04 v1(171.53,89.85) ; v1(23.28,58.15) 23.28,58.19 22.91,58.56 R5709.2 ; v1(126.8,149.14) 126.87,149.14 126.88,149.14 126.88,149.15 PC4602.2 ; ED3604.2 v1(19.96,23.99) ; v1(17.99,59.13) 17.36,58.5 C5702.2 ; 160.68,107.48 160.68,105.57 ; v1(154.27,62.97) 153.88,63.35 153.88,63.68 EC1707.2 ; 154.83,17.08 EC2902.2 ; PC4606.2 118.83,148.73 PC5001.2
  TOP w0.406: U4006.5 164.11,91.86 v1(163.91,91.66) ; 154.83,17.08 154.83,16.37 154.64,16.18 v1(154.64,15.93) ; PR4413.2 128.35,176.65 127.78,177.22 127.49,177.22 v1(127.47,177.2) ; U4002.5 164.17,84.1 ; v1(41.38,20.82) 41.45,20.75 41.55,20.75 41.87,20.43 PC5102.2 ; v1(158.35,16.28) 158.35,16.97 ; C3112.2 42.89,175.47 v1(42.89,175.48) ; v1(156.45,16.33) 156.5,16.38 156.5,17.06 ; v1(154.28,3.21) 154.28,3.07 154.15,2.94 DB3.8 ; v1(14.15,46.46) 14.16,46.46 ED5701.8 ED5701.3 ; ED5703.3 ED5703.8 v1(18.74,55.59) ; DB3.7 158.65,2.47 v1(157.98,3.15) ; ED3602.8 ED3602.3 19.83,35.14 v1(19.84,35.16) ; ED3603.8 v1(16.36,14.92) ; v1(14.18,51.54) ED5702.8 ED5702.3 ; EC9732.2 27.23,47.86 27.26,47.83 v1(27.34,47.83) ; 108.36,174.49 108.28,174.58 v1(107.93,174.58) ; PQ8501.4 162.56,104.04 ; 140.16,174.6 v1(140.44,174.6) ; PQ4405.4 v1(120.15,167.64)
  TOP w0.457: 159.47,139.48 R7818.2 159.47,140.39 v1(159.65,140.57) ; 76.5,165.95 75.88,166.57 PR4313.2 ; 159.47,139.04 C7805.2
  TOP w0.508: EC1805.2 140.25,94.49 140.25,95.61 v1(140.24,95.62) ; 127.53,143.47 127.66,143.6 128.28,143.6 ; 127.53,143.47 PR4672.1 ; 127.53,143.47 PR4608.1 ; v1(162.89,30.72) 164.01,31.84 164.31,31.84 164.35,31.88 C2420.2 ; v1(154.18,166.62) 154.18,166.05 R8110.1 ; v1(95.52,178.08) 95.52,179.02 96.15,179.65 U5501.2 ; v1(135.56,85.9) 135.56,86.13 136.07,86.64 R1603.2 ; v1(116.21,155.93) 116.21,155.9 115.81,155.5 EC9703.2 ; 151.18,185.8 BATT1.8 ; BATT1.8 152.25,186.87 ; BATT1.8 152.25,184.73 ; DBG1.3 188.28,15.45 187.68,14.85 v1(187.68,14.81) 187.19,14.81 AFTP6612.1 ; EC1808.2 165.51,71.9 R1817.2 165.51,73.23 165.22,73.53 165.22,73.59 165.16,73.65 v1(165.16,73.66) 165.24,73.58 Q1901.S ; PC1088.2 100.39,95.22 v1(100.38,95.23) ; v1(141.63,57.54) 141.48,57.7 140.77,57.7 R503.2 ; v1(120.15,176.99) 119.89,177.25 PR4414.2 119.99,178.11 PC4471.2 ; v1(156.56,98.31) 156.56,98.26 156.75,98.07 C2122.2 ; 4.25,186.94 6.29,186.94 RJ45.10 6.77,186.8 9.13,186.8 ; v1(187.92,163.16) 187.86,163.1 EC9725.2 ; v1(104.06,88.27) 104.37,87.96 PC1044.2 ; C5620.2 v1(30.18,76.08) ; v1(154.22,158.61) 154.16,158.68 C8110.2 ; EC9714.2 65.28,80.32 v1(65.84,79.76) ; v1(124.24,107.65) 124.34,107.75 PC1001.2 PC1022.2 ; USB2.11 12.3,4.31 ; VGA1.17 7.11,88.42 ; VGA1.17 7.11,86.38 ; VGA1.17 9.08,87.4 ; EC9748.2 78.47,95.51 v1(78.39,95.43) ; 122.54,136.13 122.49,136.13 122.34,135.98 PC4639.2 ; 122.54,136.13 v1(122.54,136.11) ; 122.54,136.13 122.79,136.13 123.14,136.48 PR4655.1 ; R1901.2 132.87,86.66 132.89,86.68 v1(132.89,86.94) ; C3201.2 30.86,175.96 v1(31.69,175.96) ; PC4531.2 v1(48.08,69.54) ; v1(117.26,96.13) 117.18,96.04 PC1030.2 ; v1(122.54,180.55) PR4455.2 ; HDMI1.23 5.31,60.65 ; HDMI1.23 2.09,60.65 ; HDMI1.23 3.7,61.82 ; v1(65.18,75.36) 65.06,75.36 EC9717.2 ; PC4613.2 116.95,142.1 PR4627.2 117.68,141.61 117.44,141.37 117.44,141.27 v1(117.39,141.23) ; v1(149.55,37.57) 149.63,37.49 EC8921.2 ; 169.37,183.74 BATT1.9 ; BATT1.9 170.44,185.8 ; BATT1.9 168.31,185.8 ; v1(155.14,123.48) 155.14,122.67 155.43,122.39 C7710.2 156.17,122.38 C7711.2 ; EC6504.2 152.01,19.35 v1(151.56,18.91) ; EC9701.2 31.1,65.92 v1(31.02,65.99) ; v1(56.17,176.74) 55.91,176.48 C3110.2 55.15,176.48 54.95,176.28 C3124.2 ; USB2.10 12.3,21.79 ; 15.17,9.55 USB2.4 14.28,8.66 ; v1(149.19,179.37) 148.87,179.37 EC4306.2 ; PC4641.2 120.23,134.54 PC4640.2 119.88,134.19 PC4644.2 ; 148.06,185.8 BATT1.10 ; BATT1.10 149.12,183.74 ; BATT1.10 150.19,185.8 ; 159.47,139.48 159.47,139.04 ; v1(175.99,160.58) 175.95,160.62 C8034.2 ; 7.11,69.18 VGA1.16 ; VGA1.16 7.11,71.22 ; VGA1.16 9.08,70.2 ; EC4310.2 152.31,180.23 AFTP4311.1 151.76,180.14 v1(150.73,180.14) ; v1(182.3,55.44) 181.84,54.99 EC9202.2 ; v1(156.22,82.36) 155.42,81.56 C1106.2 ; C2118.2 C2117.2 167.62,80.3 v1(167.31,80.61) 166.65,79.95 166.31,79.95 C4017.2 ; v1(156.08,169.2) 156.62,169.2 EC9731.2 ; v1(6.41,84.49) 6.41,84.49 VGA1.5 VGA1.10 ; EC9730.2 150.91,169.03 v1(151.37,168.57) ; R3107.2 57.71,175.52 57.51,175.72 v1(57.51,175.85) ; v1(129.9,145.07) 129.9,143.55 PR4621.1 ; D4304.1 160.67,180.86 v1(160.98,180.55) ; C2428.2 150.64,44.77 v1(150.8,44.93) ; v1(26.03,38.89) 26.03,38.89 U3501.2 ; v1(68.79,88.09) 68.99,87.89 C4009.2 68.31,87.05 R4006.2 ; v1(166.41,77.91) 166.18,77.68 EC1806.2 165.75,77.11 C1902.2 ; v1(183.39,159.45) 183.35,159.41 EC9726.2 ; v1(180.3,169.8) 180.43,169.93 EC9728.2 ; PC5106.2 40.15,17.46 v1(40.39,17.22) ; 8.81,167.75 6.83,167.75 RJ45.9 6.31,167.69 4.44,167.69 ; v1(155.95,165.93) 156.75,165.12 R8111.1 ; HDMI1.20 10.2,45.42 ; HDMI1.20 10.2,43.08 ; HDMI1.20 11.81,44.25 ; USB1.12 4.87,40.29 ; v1(82.58,162.77) 82.97,162.77 83.26,163.05 PR4308.2 ; v4(184.37,56.68) 184.44,56.61 EC9201.2 ; v1(153.75,73.92) 154.04,74.2 154.04,74.47 R2024.2 ; v1(185.76,15.14) 185.7,15.2 EC2703.2 185.05,15.2 185.06,15.2 185.06,14.4 EC9744.2 ; EC6502.2 152.15,22.93 152.15,23.63 v1(152.33,23.82) ; EC5502.2 102.62,169.11 v1(102.62,168.39) ; C2112.2 143.78,63.67 144.07,63.38 v1(144.2,63.38) ; HDMI1.21 11.81,58.75 ; HDMI1.21 10.2,57.58 ; HDMI1.21 10.2,59.92 ; v1(156.39,112.69) 156.17,112.46 EC1903.1 156.19,111.81 R1904.1 ; PR4523.2 47.07,79.4 47.07,80.03 v1(46.84,80.27) ; DBG1.15 v3(191.45,17.62) ; v1(55.32,172.52) 55.15,172.7 R3113.2 ; EC9740.2 61.69,92.91 61.17,92.39 v1(61.17,92.36) ; v1(52.86,177.19) 52.86,177.94 C3118.2 ; R717.2 126.6,95.2 C717.2 126.92,95.52 v1(126.92,96.14) ; C1901.2 165.38,80.75 163.63,80.75 ; PC5401.2 161.55,61.88 161.55,62.67 v1(161.76,62.88) 161.79,62.91 161.79,63.9 PC5406.2 161.88,64.07 PR5401.2 161.92,64.78 EC1705.2 ; 2.09,42.35 HDMI1.22 ; HDMI1.22 3.7,41.18 ; HDMI1.22 5.31,42.35 ; v1(148.16,90.44) 148.29,90.44 148.4,90.55 150.46,90.55 150.64,90.73 152.09,90.73 C2114.2 ; EC9749.1 v3(30.52,16.91) ; C2108.2 140.68,87.53 141.25,86.96 v1(141.25,86.72) ; C8009.2 176.35,167.21 v1(176.14,167) ; PR4530.2 44.51,78.94 v1(44.6,78.84) 44.91,78.54 PR4517.2 ; R601.1 104.53,94.74 v1(104.68,94.59) ; H17.1 177.9,10.41 ; H17.1 183.01,4.1 ; H17.1 172.54,4.1 ; PD4303.3 v1(63.96,169.63) ; R2455.2 152.74,41.57 153.02,41.86 v1(153.02,41.94) ; C7920.2 179.3,133.21 ; v1(158.88,161.79) 159.09,161.99 C8111.2 ; v1(116.87,176.86) 117.65,176.08 PQ4412.S ; C2401.2 98.9,139.09 v1(99.63,139.81) ; C7713.2 156.55,125.73 v1(156.07,126.21) ; 58.67,53.95 57.95,53.95 v1(57.63,54.28) ; C8109.2 161.48,160.87 v1(161.38,160.98) ; v1(117.61,169.7) 117.76,169.85 117.76,170.68 PR4445.2 ; R413.1 v1(135.47,82.83) ; PC4524.2 49.17,68.98 v1(49.17,68.98) ; v1(128.32,143.6) 128.28,143.6 ; 128.28,143.6 128.32,143.63 128.32,144.49 v1(128.32,144.5) ; v1(158.34,91.13) 158.34,91.09 ; 158.34,91.09 158.34,90.94 157.96,90.56 C1175.2 ; 158.34,91.09 158.8,90.63 C1174.2 ; 154.25,184.73 BATT1.7 154.25,186.87 ; v1(61.41,175.29) 61.56,175.29 Q3102.S ; v1(180.47,161.84) 180.57,161.84 180.81,162.08 C8031.2 ; v1(36.01,38.59) 36.01,38.59 37.18,38.59 R2504.2 ; USB1.13 4.87,22.81 ; v1(106.66,169.47) 106.44,169.47 106.05,169.86 EC5501.2 ; v1(107.82,17.62) 107.18,17.62 R1303.1 ; C8112.2 163.21,158.79 v1(163.28,158.87) ; EC9709.2 v1(30.87,35.28) ; C2610.2 196.76,132.86 196.43,132.53 196.43,132.45 v1(196.36,132.38) 196.24,132.38 196.12,132.5 R7938.1 ; C8032.2 178.27,148.66 v1(178.25,148.68) ; 108.36,174.49 109.15,173.71 ED5501.2 ; USB2.13 4.87,4.31 ; 10.78,90.3 H14.1 20.76,90.3 ; v1(33,21.59) 33.22,21.81 EC9747.1 ; AFTP6531.1 135.52,13.69 135.52,13.41 v1(135.62,13.31) ; R6707.2 189.06,36.67 v1(189.66,37.27) ; USB2.12 4.87,21.79 ; EC2901.2 v1(152.47,16.66) ; R8113.1 182.92,165.08 v1(183.3,165.46) ; v1(180.36,139.01) 180.4,139.05 R7821.2 181.68,139.05 R7922.1 ; PC1097.2 120.96,94.13 v1(121.14,93.96) ; R2008.2 154.12,84.02 v1(154.38,84.27) ; PQ4304.E 83.21,159.28 85.88,159.28 v1(85.88,159.28) ; v1(118.98,149.63) 118.98,149 118.83,148.85 PC4606.2 ; USB1.10 12.3,40.29 ; v1(162.18,164.97) 162.05,164.84 R8112.1 ; v1(176.8,134.94) 177.12,134.62 177.4,134.62 R7931.2 ; R5707.2 24.66,52.06 v1(24.71,52) ; v1(155.95,161.63) 155.98,161.61 EC9729.2 ; EC9727.2 183.4,168.1 v1(183.41,168.11) ; C8105.2 163.75,160.6 v1(163.2,160.6) ; USB1.11 12.3,22.81 ; C2104.2 140.03,90.86 C2121.2 140.51,91.61 v1(140.82,91.92) ; R5531.2 109.22,177.24 v1(109.13,177.33) ; C3618.2 20.71,17.93 v1(21.37,18.59) ; PR4531.2 v1(51.87,80.32) ; 21.9,12.91 H11.1 16.54,8.3 ; PQ4402.S 124.38,183.1 124.38,183.93 v1(124.34,183.97) ; EC1709.2 78.44,91.11 78.7,91.37 v1(78.7,91.67) ; v1(150.53,114.55) 150.54,114.54 151.5,114.54 EC9712.2 ; R2449.2 v1(173.14,48.23)
  L2 w0.254: 10.4,55 HDMI1.17 ; 10.45,52 10.44,52 HDMI1.11 ; 10.37,49 HDMI1.5
  L2 w0.508: 2.09,60.65 HDMI1.23 ; HDMI1.23 3.7,61.82 ; HDMI1.23 5.31,60.65 ; 154.25,184.73 BATT1.7 154.25,186.87 ; HDMI1.21 10.2,59.92 ; HDMI1.21 10.2,57.58 ; HDMI1.21 11.81,58.75 ; USB2.10 12.3,21.79 ; USB1.10 12.3,40.29 ; 8.51,167.73 6.85,167.73 ; 6.85,167.73 6.87,167.7 8.67,167.7 ; 6.85,167.73 RJ45.9 6.37,167.74 ; 7.27,73.08 VGA1.6 6.41,72.25 ; VGA1.5 6.41,84.49 v1(6.41,84.49) ; 151.18,185.8 BATT1.8 ; BATT1.8 152.25,186.87 ; BATT1.8 152.25,184.73 ; HDMI1.2 11.78,47.5 ; HDMI1.2 10.12,47.5 ; HDMI1.2 10.95,46.75 ; BATT1.9 170.44,185.8 ; BATT1.9 168.31,185.8 ; BATT1.9 169.37,183.74 ; VGA1.17 7.11,88.42 ; VGA1.17 7.11,86.38 ; VGA1.17 9.08,87.4 ; USB2.13 4.87,4.31 ; 21.9,6.28 H11.1 ; H11.1 19.88,8.3 ; H11.1 23.92,8.3 ; H11.1 21.9,10.32 ; 6.37,167.74 4.14,167.74 ; 6.37,167.74 6.33,167.7 4.53,167.7 ; H16.1 193.9,70.32 ; H16.1 193.9,66.28 ; H16.1 195.92,68.3 ; 148.06,185.8 BATT1.10 ; BATT1.10 150.19,185.8 ; BATT1.10 149.12,183.74 ; USB2.4 15.17,9.55 ; USB2.4 14.28,10.44 ; USB2.4 14.28,8.66 ; H14.1 15.4,92.32 ; H14.1 17.42,90.3 ; H14.1 15.4,88.28 ; H14.1 13.38,90.3 ; USB1.13 4.87,22.81 ; VGA1.16 9.08,70.2 ; VGA1.16 7.11,71.22 ; VGA1.16 7.11,69.18 ; USB1.4 15.17,28.05 ; USB1.4 14.28,28.94 ; USB1.4 14.28,27.16 ; USB1.11 12.3,22.81 ; 14,13.05 USB2.7 ; 13.93,31.55 USB1.7 ; VGA1.10 7.26,82.24 ; VGA1.7 7.33,75.36 ; 11.78,50.5 HDMI1.8 10.12,50.5 ; HDMI1.20 11.81,44.25 ; HDMI1.20 10.2,45.42 ; HDMI1.20 10.2,43.08 ; USB1.12 4.87,40.29 ; VGA1.8 7.25,77.65 ; HDMI1.22 5.31,42.35 ; HDMI1.22 3.7,41.18 ; HDMI1.22 2.09,42.35 ; USB2.12 4.87,21.79 ; USB2.11 12.3,4.31
  L3 w0.254: 13.72,31.55 USB1.7 ; 10.4,52 HDMI1.11 ; 10.36,55 HDMI1.17 ; 10.35,49 9.45,49 HDMI1.5 ; 13.86,13.05 USB2.7
  L3 w0.508: 14.28,8.66 USB2.4 ; USB2.4 14.28,10.44 ; USB2.4 15.17,9.55 ; HDMI1.21 11.81,58.75 ; HDMI1.21 10.2,59.92 ; HDMI1.21 10.2,57.58 ; 8.67,167.7 6.87,167.7 RJ45.9 6.37,167.74 4.14,167.74 ; VGA1.8 7.25,77.65 ; BATT1.8 152.25,186.87 ; BATT1.8 151.18,185.8 ; BATT1.8 152.25,184.73 ; 19.88,8.3 H11.1 ; H11.1 23.92,8.3 ; H11.1 21.9,10.32 ; H11.1 21.9,6.28 ; USB2.10 12.3,21.79 ; VGA1.10 7.26,82.24 ; 15.4,88.28 H14.1 ; H14.1 15.4,92.32 ; H14.1 17.42,90.3 ; H14.1 13.38,90.3 ; HDMI1.20 11.81,44.25 ; HDMI1.20 10.2,45.42 ; HDMI1.20 10.2,43.08 ; HDMI1.23 5.31,60.65 ; HDMI1.23 2.09,60.65 ; HDMI1.23 3.7,61.82 ; BATT1.10 150.19,185.8 ; BATT1.10 149.12,183.74 ; BATT1.10 148.06,185.8 ; USB2.11 12.3,4.31 ; 170.44,185.8 BATT1.9 169.37,183.74 ; 10.95,46.75 HDMI1.2 ; HDMI1.2 11.78,47.5 ; HDMI1.2 10.12,47.5 ; 14.28,28.94 USB1.4 14.28,27.16 ; 7.11,86.38 VGA1.17 ; VGA1.17 9.08,87.4 ; VGA1.17 7.11,88.42 ; USB1.11 12.3,22.81 ; VGA1.16 7.11,71.22 ; VGA1.16 7.11,69.18 ; VGA1.16 9.08,70.2 ; USB2.12 4.87,21.79 ; USB1.12 4.87,40.29 ; 2.09,42.35 HDMI1.22 ; HDMI1.22 5.31,42.35 ; HDMI1.22 3.7,41.18 ; 154.25,184.73 BATT1.7 154.25,186.87 ; 7.27,73.08 VGA1.6 6.41,72.25 ; USB2.13 4.87,4.31 ; USB1.13 4.87,22.81 ; 10.12,50.5 HDMI1.8 11.78,50.5 ; VGA1.7 7.33,75.36 ; USB1.10 12.3,40.29 ; VGA1.5 6.41,84.49 v1(6.41,84.49)
  L4 w0.305: 10.37,49 HDMI1.5 ; 13.72,31.55 USB1.7 ; v1(127.25,34.19) 128.04,33.4 130.5,33.4 131.82,34.73 131.82,34.94 132.74,35.86 132.74,38.46 134.27,39.99 134.27,42.36 136.95,45.04 v1(136.95,46.44) ; 10.35,55 HDMI1.17 ; 13.83,13.05 USB2.7
  L4 w0.508: H14.1 17.42,90.3 ; H14.1 15.4,88.28 ; H14.1 15.4,92.32 ; H14.1 13.38,90.3 ; 10.2,57.58 HDMI1.21 ; HDMI1.21 11.81,58.75 ; HDMI1.21 10.2,59.92 ; HDMI1.20 10.2,45.42 ; HDMI1.20 10.2,43.08 ; HDMI1.20 11.81,44.25 ; 6.41,72.25 VGA1.6 7.27,73.08 ; H11.1 23.92,8.3 ; H11.1 21.9,6.28 ; H11.1 19.88,8.3 ; H11.1 21.9,10.32 ; 2.09,60.65 HDMI1.23 ; HDMI1.23 5.31,60.65 ; HDMI1.23 3.7,61.82 ; 3.7,41.18 HDMI1.22 ; HDMI1.22 5.31,42.35 ; HDMI1.22 2.09,42.35 ; VGA1.7 7.29,75.36 ; USB2.4 15.17,9.55 ; USB2.4 14.28,8.66 ; USB2.4 14.28,10.44 ; 151.18,185.8 BATT1.8 152.25,186.87 ; USB2.10 12.3,21.79 ; 14.28,27.16 USB1.4 ; USB1.4 14.28,28.94 ; USB1.4 15.17,28.05 ; 168.31,185.8 BATT1.9 170.44,185.8 ; 10.12,50.5 HDMI1.8 11.78,50.5 ; 7.11,69.18 VGA1.16 ; VGA1.16 7.11,71.22 ; VGA1.16 9.08,70.2 ; HDMI1.11 10.23,52 ; v1(6.41,84.49) 6.41,84.49 VGA1.5 ; 10.12,47.5 HDMI1.2 ; HDMI1.2 10.95,46.75 ; HDMI1.2 11.78,47.5 ; VGA1.17 7.11,88.42 ; VGA1.17 9.08,87.4 ; VGA1.17 7.11,86.38 ; USB1.12 4.87,40.29 ; USB1.11 12.3,22.81 ; USB1.10 12.3,40.29 ; 148.06,185.8 BATT1.10 150.19,185.8 ; USB1.13 4.87,22.81 ; VGA1.10 7.29,82.24 ; VGA1.8 7.29,77.65 ; USB2.12 4.87,21.79
  L5GND w0.508: v1(6.41,84.49) 6.41,84.49 VGA1.5 ; VGA1.10 7.4,82.24 ; VGA1.7 7.48,75.36 ; VGA1.8 7.41,77.65
  BOTTOM w0.089: CPU1.BB34 120.68,74.56 120.71,74.53 120.71,70.87 120.67,70.83 ; v1(177.76,65.7) 177.72,65.66 177.72,64.95 U6301.N2 ; v1(140.82,91.92) 140.79,91.89 139.67,91.89 139.59,91.85 139.15,91.85 139.06,91.89 CPU1.L2
  BOTTOM w0.102: 138.2,83.18 138.17,83.21 138.17,83.6 137.95,83.82 137.95,84.07 CPU1.AF4 ; 135.42,95.86 135.42,96.14 135.47,96.19 135.47,96.47 135.42,96.51 135.42,96.78 135.67,97.03 135.67,97.82 135.96,98.2 137.72,99.96 137.88,99.96 138.72,100.8 138.72,101.1 138.45,101.36 135.87,101.36 135.6,101.64 135.6,104.02 C2202.2
  BOTTOM w0.127: CPU1.BB43 115.73,74.37 v1(115.59,74.23) ; v1(179.15,62.44) 179.15,62.5 178.94,62.7 U6301.P6 U6301.N5 ; v1(117.85,71.67) 118.42,72.25 118.42,74.59 118.33,74.69 CPU1.BB38 ; CPU1.AG71 98.75,83.8 98.54,83.91 98.33,83.91 v1(98.28,83.97) ; v1(140.35,100.82) 140.53,100.99 140.53,102.33 141.44,103.25 141.44,103.87 C2201.2 ; 120.2,94.45 120.2,94.85 120.68,95.33 121.8,95.33 CPU1.D30 ; CPU1.AV70 99.49,77.05 99.06,77.05 97.9,75.89 97.87,75.89 97.74,75.76 97.25,75.76 97.24,75.77 96.78,76.23 96.78,76.84 95.94,77.68 95.64,77.68 95.3,77.33 95.3,76.81 R602.2 ; v1(98.25,78.5) 98.43,78.5 98.71,78.79 CPU1.AT71 ; v1(103.65,74.35) 103.61,74.4 CPU1.BB64 ; v1(103.56,71.4) 103.56,71.61 105.69,73.74 105.69,74.69 105.88,74.88 105.88,75.23 CPU1.BB60 ; VRAM2.C12 185.9,158.6 v1(185.9,158.59) ; CPU1.AW60 CPU1.AW62 ; 155.73,121.39 155.89,121.39 156.6,122.1 157.26,122.1 159.25,124.09 160.31,124.09 160.32,124.1 161.38,124.1 163.42,126.14 163.42,126.97 163.14,127.24 162.91,127.24 162.2,127.95 GPU1.AH28 ; CPU1.BB55 108.58,75.29 108.58,73.19 107.14,71.76 v1(107.14,71.43) ; v1(161.8,127.7) 161.8,126.13 160.44,124.76 160.05,124.76 160.04,124.75 158.26,124.75 157.19,123.68 155.34,123.68 v1(155.14,123.48) ; 140.14,95.2 140.24,95.29 v1(140.24,95.62) ; CPU1.AF2 138.84,83.61 138.84,83.38 138.67,83.22 138.67,83.22 138.63,83.17 138.53,83.17 138.2,83.18 138.1,83.18 137.77,83.19 137.67,83.16 ; v1(97.19,81.47) 97.61,81.05 98.67,81.05 98.74,81.05 98.84,81.15 CPU1.AM71 ; CPU1.AP70 100.05,79.78 98.25,79.78 v1(98.13,79.65) ; 136.21,95.29 135.82,95.68 135.6,95.68 135.28,96.01 134.97,96.01 134.49,96.49 CPU1.B10 ; v1(126.15,73.57) 126.15,74.15 125.66,74.63 CPU1.BB26 ; CPU1.BA28 124.64,75.89 124.64,74.88 124.85,74.68 124.85,74.05 v1(125,73.9) ; CPU1.AW51 CPU1.AW53 ; v1(123.46,74.03) 123.46,74.11 123.31,74.26 CPU1.BB30
  BOTTOM w0.152: CPU1.AV68 101.47,78.03 101.47,78.03 101.47,78.27 101.46,78.29 CPU1.AT68 CPU1.AP68 ; CPU1.AP42 116.13,80.06 116.13,80.7 CPU1.AN42 ; PU4801.9 123.51,124.68 PU4801.3 ; CPU1.AR42 116.13,79.39 116.13,78.76 CPU1.AT42 ; v1(173.46,62.99) 173.46,63.21 U6301.C4 ; CPU1.B34 119.69,96.64
  BOTTOM w0.178: 140.14,95.18 140.14,95.2 140.14,95.2 ; CPU1.AW64 103.48,77.28 102.52,77.28 ; CPU1.H71 99.51,93.4 99.02,93.4 98.71,93.09 96.57,93.09 v1(96.2,92.72) ; CPU1.AM60 105.92,81.5 105.29,81.5 CPU1.AM61
  BOTTOM w0.203: KBC24.64 171.8,33.53 171.66,33.67 v1(171.53,33.67) ; GPU1.B12 175,148.63 v1(174.96,148.67) ; v1(165.32,148.72) 165.4,148.63 GPU1.B24 ; CPU1.AW53 109.74,76.73 v1(109.9,76.57) ; CPU1.J25 124.82,93.14 v1(124.82,93.88) ; CPU1.AW62 104.78,76.67 v1(104.82,76.63) ; CPU1.AG21 127.83,83.75 128.39,83.75 CPU1.AG20 CPU1.AG19 ; v1(162.89,30.72) 162.97,30.8 163.66,31.08 KBC24.84 ; v1(158.98,34.89) 158.46,34.89 158.3,34.73 KBC24.100 ; v1(110.21,79.72) 110.53,79.4 CPU1.AR52 ; CPU1.AW36 119.51,76.68 v1(119.63,76.56) ; 118.21,77.28 117.05,77.28 CPU1.AW41 117.03,76.67 v1(116.91,76.54) ; CPU1.AL2 138.56,81.79 138.24,81.79 CPU1.AJ4 ; CPU1.AW43 115.81,77.25 115.35,77.25 115.32,77.28 115,77.28 114.98,77.26 CPU1.AW45 114.55,76.67 v1(114.55,76.67) ; KBC24.17 165.26,46.27 v1(165.55,45.98) ; v1(163.57,148.57) 163.8,148.34 GPU1.B26 ; CPU1.B14 131.69,96.96 131.69,97.67 131.76,97.74 131.76,98.42 v1(132.08,98.73) ; v1(176.6,148.63) GPU1.B10 ; KBC24.124 158.14,44.33 158.65,43.83 v1(158.65,43.72) ; PC4812.2 114.32,123.08 PU4802.3 ; 126.7,97.05 126.7,97.79 126.38,98.11 v1(126.18,98.11) ; GPU1.AH32 160.24,128.1 v1(159.91,128.43) ; GPU1.B18 170.2,148.49 170.26,148.55 170.26,150.12 v1(170.19,150.18) ; GPU1.B8 178.2,148.64 v1(178.25,148.68) ; CPU1.K71 99.47,92 97.6,92 96.3,90.71 v1(95.44,90.71) ; v1(126.93,85.43) 126.99,85.49 127.76,85.49 CPU1.AD21 127.82,85.51 128.4,85.51 CPU1.AD20 CPU1.AD19 ; v1(171.46,61.88) 171.46,62.53 171.63,62.7 U6301.A6 ; GPU1.AB32 v1(159.84,132.9) ; CPU1.AN63 CPU1.AP63 ; CPU1.AR45 114.56,79.14 114.62,79.14 v1(114.7,79.06) 114.87,79.06 CPU1.AR43 ; v1(169.83,39.36) 169.83,38.97 170.31,38.49 170.71,38.49 170.95,38.73 KBC24.51 ; CPU1.E18 129.5,94.55 129.5,93.28 CPU1.H18 ; v1(151.75,112.24) 151.7,112.24 151.26,112.68 151.26,113.08 151.29,113.11 151.29,113.51 152.11,114.34 R7939.2 ; CPU1.K63 104.84,92.35 CPU1.K61 ; PU4701.3 105,123.13 PC4708.2 ; CPU1.H15 131.67,92.81 CPU1.K16 ; CPU1.AR46 CPU1.AR48 112.1,79.77 v1(112.02,79.77) 111.91,79.77 CPU1.AR50 ; v1(158.85,148.79) 159.48,148.79 160.18,148.08 160.18,147.72 GPU1.C32 ; CPU1.AW10 134.68,77.26 134.7,77.28 135.47,77.28 CPU1.AW8 ; v1(123.16,37.31) 123.09,37.31 121.96,38.44 121.96,39.92 122.02,39.98 DM1.217 ; v1(159.94,131.3) 160.47,131.3 160.47,131.3 GPU1.AD32 ; CPU1.AW47 113.32,77.28 112.16,77.28 CPU1.AW49 112.14,76.79 v1(111.99,76.64) ; CPU1.BB6 CPU1.BA6 ; CPU1.AF2 138.84,84.21 138.58,84.47 138.17,84.47 CPU1.AF4 ; GPU1.B16 171.8,148.65 v1(171.74,148.71) ; CPU1.AB21 127.47,86.63 v1(127.47,86.75) ; v1(168.78,149.16) 168.6,148.98 GPU1.B20 ; v1(131.7,76.58) 131.7,77.13 CPU1.AW14 132.26,77.26 132.28,77.28 133.05,77.28 CPU1.AW12 ; DM1.60 80.77,33.61 80.85,33.83 80.85,34.65 80.04,35.46 v1(79.99,35.46) ; GPU1.AF32 159.91,129.7 v1(159.91,129.7) ; 140.14,95.18 139.88,94.92 139.64,94.92 CPU1.F1 ; PC4809.2 123.51,122.82 PU4801.3 ; GPU1.B22 v1(167,148.74) ; CPU1.B53 109.44,96.37 109.44,95.89 CPU1.D53 109.72,95.61 CPU1.E53 ; v1(170.49,132.56) 170.8,132.26 GPU1.AC17 ; v1(173.36,149.1) 173.4,149.06 GPU1.B14
  BOTTOM w0.229: GPU1.F2 181.84,145.66 182.75,145.66 v1(182.79,145.7) ; GPU1.H2 181.94,143.96 v1(182.38,143.96)
  BOTTOM w0.254: CPU1.AD16 131.04,85.28 CPU1.AF15 131.65,84.63 131.04,84.02 CPU1.AG16 CPU1.AG17 ; DM1.239 127.52,39.89 127.62,39.8 v1(127.62,39.05) ; v1(140.7,104.97) 140.42,104.68 X2201.4 138.89,103.98 138.89,103.81 138.12,103.03 X2201.2 ; v1(140.7,104.97) 140.96,104.7 C2201.2 ; v1(140.7,104.97) 140.7,105 140.33,105.37 136.36,105.37 136,105.01 136,104.46 C2202.2 ; CPU1.AL58 v1(107.44,82.64) ; CPU1.AW55 108.32,77.26 108.03,77.56 ; CPU1.P19 CPU1.P20 CPU1.P21 126.42,89.66 v1(125.9,89.14) ; 89.02,39.44 89.02,39.34 88.02,38.34 ; CPU1.AF2 CPU1.AF1 ; 108.03,77.56 v1(108.02,77.56) ; 108.03,77.56 108.26,77.79 108.26,78.38 CPU1.AT56 ; CPU1.U63 v1(104.06,88.27) CPU1.U64 ; v1(120.98,37.09) 120.93,37.09 120.12,37.89 120.12,39.56 120.02,39.66 DM1.209 ; CPU1.AH63 104.39,83.36 v1(104.08,83.67) ; 194.09,164.49 PU8651.18 v1(194.09,166.96) ; CPU1.AM68 102.23,81.24 CPU1.AL66 CPU1.AL65 CPU1.AL64 ; R7939.2 152.15,114.61 EC9713.2 ; CPU1.U69 100.42,88.63 v1(100.16,88.27) CPU1.U70 ; v1(111.99,76.64) 112.14,76.48 CPU1.BA49 ; CPU1.AM60 106.2,81.35 v1(106.52,81.03) 106.65,81.03 CPU1.AN58 106.99,80.69 106.99,80.07 CPU1.AP58 106.99,80.04 106.99,79.42 CPU1.AR58 107.04,79.34 107.04,78.81 CPU1.AT58 ; CPU1.AV68 102.22,77.59 CPU1.AW66 102.52,77.28 102.52,76.85 CPU1.AY66 CPU1.BA66 ; v1(104.08,83.67) 104.39,83.98 CPU1.AF63 ; v1(104.08,83.67) 104.08,83.58 CPU1.AH64 ; U6301.H10 175.47,61.02 175.62,61.18 175.62,61.26 ; CPU1.AR42 116.09,79.4 115.76,79.73 ; CPU1.B44 114.66,96.31 v1(114.49,96.14) ; CPU1.AP42 116.08,80.05 115.76,79.73 ; v1(130.72,82.55) 130.74,82.58 131.29,82.56 CPU1.AJ15 ; v1(130.72,82.55) 130.27,82.57 129.82,82.75 CPU1.AJ18 CPU1.AK18 129.32,82.54 128.86,82.54 CPU1.AJ20 ; v1(130.72,82.55) CPU1.AK16 ; CPU1.U66 v1(102.11,88.27) CPU1.U67 ; CPU1.AW64 103.95,77.26 103.99,77.3 104.74,77.3 CPU1.AW62 ; CPU1.AF17 CPU1.AG17 ; CPU1.AG17 CPU1.AG18 CPU1.AG19 ; CPU1.AW38 117.95,77.54 CPU1.AU38 ; DM1.235 126.52,39.62 126.69,39.45 126.69,38.52 127.47,37.74 v1(127.59,37.74) ; DM1.213 121.02,39.04 v1(121.05,39.02) ; 10.27,49 HDMI1.5 ; CPU1.AR53 110.04,79.72 v1(110.21,79.72) ; CPU1.BA53 109.74,76.41 v1(109.9,76.57) ; v1(154.62,67.37) 154.94,67.37 156.15,66.16 Q1701.4 ; CPU1.AW14 131.65,77.44 131.65,78.09 CPU1.AU15 ; CPU1.BA14 131.83,76.44 v1(131.7,76.58) ; CPU1.AL45 115.21,81.37 CPU1.AM43 ; CPU1.AL45 v1(114.75,82.66) ; CPU1.AL45 114.75,81.81 CPU1.AM45 ; v1(127.47,86.75) 127.47,86.75 127.47,86.83 CPU1.Y21 127.82,87.18 128.41,87.18 CPU1.Y20 CPU1.Y19 129.74,87.8 CPU1.V18 ; CPU1.K70 CPU1.K71 ; v1(123.2,39.26) 123.2,39.43 123.52,39.76 DM1.223 ; v1(111.09,93.84) 110.84,93.59 CPU1.G52 ; v1(118.73,38.25) 118.77,38.25 119.22,38.7 119.22,39.13 119.02,39.32 DM1.205 ; 115.76,79.73 v1(115.69,79.73) ; CPU1.G58 106.77,93.59 v1(106.51,93.86) 106.33,93.86 CPU1.G60 ; CPU1.G48 112.78,93.91 v1(112.96,93.91) ; v1(119.63,76.56) 119.63,76.16 CPU1.BA36 ; CPU1.AL55 v1(109.26,82.64) ; CPU1.AL52 v1(111.09,82.68) ; CPU1.AV69 CPU1.AV70 ; CPU1.AW6 136.63,76.71 v1(136.55,76.63) 136.67,76.5 CPU1.BA6 ; U6301.K8 176.06,61.7 175.62,61.26 ; CPU1.AR55 109.16,79.76 v1(109.23,79.76) ; CPU1.N65 102.9,90.29 v1(102.76,90.1) ; v1(113.91,22.79) 113.87,22.79 113.3,22.23 113.3,20.74 113.27,20.71 ; CPU1.B58 CPU1.D58 107.23,95.33 v1(107.43,95.13) 107.66,94.89 CPU1.E56 ; v1(177.1,163.4) 176.7,163 VRAM2.H1 ; CPU1.AR15 v1(131.21,79.08) CPU1.AR16 CPU1.AP18 ; FC1901.2 124.52,70.21 124.5,70.23 ; CPU1.B14 CPU1.D14 132.01,95.23 CPU1.E15 131.3,95.26 130.29,95.26 129.92,94.89 CPU1.E18 129.84,95.35 129.56,95.62 CPU1.D18 CPU1.B18 ; CPU1.AT63 104.25,78.77 104.25,79.39 CPU1.AR63 104.25,79.42 104.25,80.04 CPU1.AP63 ; v1(101.57,93.7) 101.59,93.71 102.09,93.71 CPU1.G66 ; CPU1.B53 109.71,96.76 110.05,97.1 110.05,97.42 110.04,97.43 110.04,97.8 110.41,98.17 v1(110.85,98.17) ; CPU1.BA57 107.16,76.14 v1(107.16,76.55) 107.16,77.16 CPU1.AW57 ; v1(175.62,61.63) 175.62,61.26 ; v1(118.41,82.62) CPU1.AL38 v1(118.41,81.03) ; v1(139.48,50.12) 140.1,49.5 ED502.2 ; CPU1.BA41 117.03,76.42 v1(116.91,76.54) ; v1(112.92,82.65) CPU1.AL48 ; VRAM2.G5 180.26,161.84 180.41,161.84 ; CPU1.T21 127.45,88.49 v1(127.45,88.39) ; CPU1.AM13 132.19,80.96 v1(132.19,80.38) ; CPU1.B22 127.05,96.28 v1(126.92,96.14) 126.92,95.76 CPU1.D22 127.49,95.18 127.72,95.18 CPU1.E21 ; U6301.G5 174.97,62.83 v1(174.79,62.65) 174.34,62.2 U6301.E7 ; v1(104.68,94.59) 104.68,94.15 CPU1.G63 ; CPU1.D45 114.07,95.58 114.62,95.58 CPU1.D44 ; v1(136.83,90.2) 137.09,90.45 CPU1.N6 ; CPU1.K68 101.56,92.15 CPU1.K67 CPU1.K66 CPU1.K65 CPU1.K64 CPU1.K63 ; v1(175.82,62.69) 175.97,62.84 U6301.J5 ; CPU1.AR8 v1(134.87,79.08) ; v1(114.55,76.67) 114.55,76.66 CPU1.BA45 ; CPU1.B66 CPU1.D66 102.68,95.22 v1(102.68,94.69) 102.9,94.69 CPU1.E65 ; U6301.P4 179.03,63.7 v1(179.23,63.5) ; v1(104.82,76.63) 104.78,76.59 CPU1.BA62 ; v1(101.46,90.1) 101.33,90.29 CPU1.N68 ; CPU1.AL32 v1(122.07,82.67) ; CPU1.B62 CPU1.D62 ; CPU1.L4 CPU1.L2 ; CPU1.AU10 134.25,77.94 CPU1.AW10 134.25,76.81 v1(134.37,76.7) 134.25,76.58 CPU1.BA10 ; CPU1.G5 137.37,93.59 137.59,93.37 v1(137.59,93.29) ; CPU1.AK69 CPU1.AK68 101.14,82.59 CPU1.AH67 101.79,83.25 v1(101.39,83.65)
  BOTTOM w0.279: DM1.85 87.02,40.7 87.02,39.24 v1(87,39.22) ; v1(78.89,23.26) 79.53,22.62 79.53,20.69 79.27,20.43 DM2.86 ; DM1.222 123.27,34.07 123.19,34.15 v1(123.19,34.19) ; DM2.172 v1(102.77,21.74) ; v1(116.87,37.79) 116.83,37.79 116,38.62 116,39.49 116.02,39.52 DM1.193 ; v1(104.98,25.83) 105.02,25.87 DM2.181 ; DM2.98 82.27,20.2 82.38,20.3 82.38,20.93 v1(82.34,20.96) ; DM2.197 109.02,26.03 v1(109.02,25.83) ; v1(65.54,24.46) 65.51,24.46 64.57,25.4 64.57,26.44 64.52,26.48 DM2.27 ; DM1.171 110.52,39.51 v1(110.19,39.17) ; v1(112.55,35.53) 112.43,35.53 111.77,34.87 DM1.176 ; DM1.227 124.52,38.48 125.24,37.77 v1(125.76,37.77) ; v1(68.86,34.18) 68.86,34.12 69.27,33.7 DM1.14 ; 89.27,34.02 90.22,34.97 v1(90.61,34.97) 90.68,34.9 90.79,34.9 92.27,33.41 DM1.106 ; 89.27,34.02 DM1.94 ; 89.27,34.02 89.26,34.01 88.6,34.01 88.27,33.68 DM1.90 ; 107.02,28.45 DM2.189 107.02,25.72 v1(105.99,24.68) ; v1(86.87,36.12) 86.97,36.12 87.54,35.55 87.54,33.83 87.27,33.56 DM1.86 ; v1(73.81,23.82) 73.65,23.82 73.02,24.44 DM2.61 ; DM1.69 83.02,41.61 82.79,41.84 78.65,41.84 78.52,41.71 DM1.51 78.52,37.43 78.77,37.18 v1(79.99,37.18) ; 107.77,21.42 107.77,19.3 ; v1(66.62,37.77) 66.46,37.77 65.65,38.58 65.65,39.64 66.02,40.01 DM1.1 ; DM1.196 116.77,34.06 v1(116.91,34.19) ; DM1.98 90.27,33.76 v1(90.62,34.11) 91.27,33.45 DM1.102 ; v1(120.73,34.88) 120.25,34.4 120.25,33.93 120.27,33.91 DM1.210 ; v1(113.04,25.15) 113.04,25.22 113.02,25.24 DM2.213 ; DM1.78 85.27,35.47 84.57,36.17 v1(83.88,36.17) ; DM2.193 108.02,25.33 107.76,25.06 107.76,24.49 v1(108.23,24.02) ; DM2.222 v1(115.27,20.98) ; DM1.206 119.27,33.95 119.29,33.96 v1(119.29,33.99) ; DM2.2 58.27,20.27 58.07,20.47 58.07,22.48 58.59,23 v1(58.64,23) ; DM1.2 66.27,33.57 66.13,33.71 66.13,34.63 66.11,34.65 66.11,35.1 66.13,35.12 66.13,35.8 66.63,36.3 v1(66.65,36.3) ; DM1.31 73.52,39.14 v1(73.47,39.09) ; DM1.23 71.52,39.95 71.56,39.92 71.56,38.82 71.14,38.4 v1(71.03,38.4) 70.93,38.4 70.51,38.82 70.51,40.29 70.52,40.3 DM1.19 ; DM2.243 120.52,25.22 119.57,24.26 v1(119.44,24.26) 118.87,24.26 118.52,24.61 DM2.235 ; v1(78.86,24.53) 78.79,24.53 77.95,25.37 77.95,26.23 78.02,26.3 DM2.81 ; v1(119.29,35.31) 118.75,35.31 118.27,34.83 DM1.202 ; v1(121.75,25.25) 121.52,25.47 DM2.247 ; DM1.61 81.02,37.13 81.35,36.81 v1(81.82,36.81) ; DM1.82 86.27,34.36 86.77,34.85 v1(86.87,34.85) ; v1(71.96,25.73) 72.02,25.8 DM2.57 ; DM2.214 113.27,20.71 ; v1(111.01,25.42) 111.01,25.62 111.02,25.64 DM2.205 ; DM2.251 v1(122.52,26.06) ; DM1.168 109.77,33.95 109.56,34.17 109.56,35.81 110.07,36.32 v1(110.2,36.32) ; v1(102.69,25.7) 102.53,25.87 DM2.171 ; DM2.23 63.52,26.14 63.6,26.06 63.6,25.61 63.16,25.17 v1(63.1,25.17) ; v1(68.86,38.3) 69.5,38.94 69.5,40.68 DM1.15 ; v1(69.26,24.14) 69.26,24.17 68.52,24.9 DM2.43 ; DM2.48 69.77,19.31 69.77,21.22 v1(69.3,21.7) ; v1(117.56,24.41) 117.46,24.41 116.52,25.34 DM2.227 ; DM1.72 83.77,34.06 v1(83.88,34.16) ; v1(58.65,21.68) 58.7,21.68 59.27,21.1 DM2.6 ; v1(71.91,21) 71.78,20.86 DM2.56 ; DM2.230 117.27,20.89 ; DM1.64 81.77,34.12 v1(81.82,34.16) ; v1(130.72,39.02) 130.52,39.21 DM1.251 ; DM1.238 127.27,34.17 v1(127.25,34.19) ; DM2.90 80.27,20.53 v1(80.71,20.96) 80.71,20.82 81.28,20.26 81.28,19.3 DM2.94 ; v1(77.4,38.89) 77.52,39.01 DM1.47 ; DM2.93 81.02,25.85 v1(81.05,25.83) 83.01,25.83 83.52,26.34 DM2.103 ; DM2.73 76.02,25.97 v1(75.88,25.82) ; DM1.36 74.8,32.52 74.8,33.83 74.68,33.95 74.68,35.6 74.15,36.13 v1(73.59,36.13) ; DM1.103 91.52,39.02 90.91,38.4 v1(90.6,38.4) ; DM2.102 83.27,20.88 83.31,20.92 83.31,20.81 v1(83.3,20.81) ; v1(125.32,35.58) 125.44,35.58 126.27,34.75 DM1.234 ; v1(65.6,25.82) 65.52,25.89 DM2.31 ; v1(69.27,25) 69.67,25.4 69.67,25.94 69.52,26.08 DM2.47 ; DM2.107 84.52,28.81 84.31,29.03 v1(82.5,29.03) 82.52,29 DM2.99 ; DM2.168 101.77,20.29 ; DM2.231 117.52,25.74 v1(117.57,25.69) ; v1(77.3,34.88) 77.79,34.38 77.79,33.7 77.77,33.68 DM1.48 ; v1(112.55,34.17) 112.77,33.95 DM1.180 ; DM2.51 70.52,26.43 70.63,26.32 70.63,24.74 v1(71.37,24) ; DM2.206 111.27,20.96 ; DM1.99 90.52,39.11 90.6,39.04 v1(90.6,39.04) 89.43,39.04 89.02,39.44 DM1.93 ; DM2.167 101.53,25.23 102.4,24.35 v1(102.69,24.35) ; DM2.252 122.77,21.33 ; DM2.26 64.27,22.83 63.32,23.79 v1(63.12,23.79) 63.1,23.79 62.52,24.36 DM2.19 ; DM1.22 71.27,34.18 v1(71.28,34.18) ; DM1.197 117.02,39.17 v1(116.94,39.08) ; DM2.60 72.78,20.52 ; v1(114.78,35.44) 114.63,35.44 113.77,34.59 DM1.184 ; v1(79.99,39.17) 80.02,39.2 DM1.57 ; v1(83.88,39.02) 84.02,39.17 84.02,40.7 DM1.73 ; DM1.39 75.52,39.71 75.5,39.68 75.5,39.22 v1(75.29,39.02) ; v1(75.88,24.39) 75.9,24.39 76.91,25.41 76.91,26.54 77.02,26.65 DM2.77 ; v1(114.78,34.17) 114.77,34.16 DM1.188 ; DM2.244 120.77,21.53 ; v1(58.61,24.41) 58.56,24.41 57.71,25.25 57.71,26.68 58.02,26.99 DM2.1 ; DM1.172 110.77,34.71 110.47,35.01 v1(110.17,35.01) ; DM2.14 61.27,20.72 v1(61.02,20.98) ; v1(130.72,37.64) 130,37.64 129.52,38.12 DM1.247 ; v1(79.99,34.19) 79.78,33.98 79.78,32.5 DM1.56 ; DM1.68 82.77,34.76 82.07,35.46 v1(81.82,35.46) ; DM2.234 118.27,20.55 ; DM1.65 82.02,39.5 82.34,39.18 82.34,38.73 81.84,38.23 v1(81.82,38.23) ; v1(112.7,22.59) 112.65,22.59 112.02,23.22 DM2.209 ; DM2.30 65.27,20.95 v1(65.31,20.98) ; v1(73.39,34.17) 73.39,34.07 73.27,33.96 DM1.30 ; v1(111,23.52) 110.94,23.52 110.02,24.43 DM2.201 ; DM2.184 105.77,21.88 ; DM2.218 114.27,21.51 ; DM1.89 88.02,38.34 87.48,37.8 v1(86.82,37.8) 86.7,37.8 86.02,38.47 86.02,40.7 DM1.81 ; DM2.68 v1(74.78,20.91) ; DM1.40 75.77,34.51 75.38,34.9 v1(75.29,34.9) ; v1(67.21,25.82) 67.52,26.13 DM2.39 ; v1(110.19,37.9) 109.57,37.9 109.13,38.33 109.13,39.47 109.52,39.86 DM1.167 ; DM2.40 67.78,20.25 67.75,20.28 67.75,21.16 67.32,21.6 v1(67.21,21.6) 67.11,21.6 66.69,21.18 66.69,20.73 66.78,20.65 DM2.36 ; DM1.185 114.02,39.73 113.88,38.87 113.75,38.74 113.75,37.71 v1(114.75,36.71) ; v1(78.9,21.85) 78.27,21.23 DM2.82 ; v1(72.77,37.78) 72.52,38.03 DM1.27 ; DM1.181 113.02,39.74 112.99,39.71 112.99,39.51 112.97,39.37 v1(112.76,39.16) ; DM2.72 75.78,22.59 v1(76.82,23.64) ; DM1.252 130.81,32.54 130.81,35.39 130.36,35.84 v1(130.29,35.84) ; DM2.64 73.78,20.17 ; DM1.107 92.52,39.76 92.12,39.36 v1(92.12,39.22) ; DM1.5 67.02,39.64 66.62,39.24 v1(66.62,39.04) ; v1(61.02,23.75) 60.92,23.75 59.97,24.7 59.97,26.24 60.02,26.3 DM2.9 ; DM2.85 79.02,25.96 v1(78.89,25.82) ; v1(68.89,35.56) 68.83,35.56 68.27,35 DM1.10 ; v1(127.6,36.47) 128.12,36.47 128.77,35.82 DM1.244 ; DM1.226 124.27,34.5 123.31,35.46 v1(123.19,35.46) 123.09,35.46 122.48,34.85 122.48,33.61 122.27,33.41 DM1.218 ; DM1.6 67.27,34.28 66.68,34.88 v1(66.66,34.88) ; v1(125.32,34.19) 125.27,34.14 DM1.230 ; v1(77.27,36.3) 77.25,36.3 76.75,35.8 76.75,33.93 76.77,33.91 DM1.44 ; v1(127.59,37.74) 127.99,37.74 128.52,38.27 DM1.243 ; DM2.175 103.53,26.22 103.65,26.1 103.65,25.02 104.87,23.8 v1(104.88,23.8) ; DM2.226 116.27,21.27 ; DM2.239 119.52,25.53 v1(119.53,25.53) ; v1(79.99,35.46) 79.74,35.46 78.77,34.49 DM1.52 ; DM2.202 110.27,21.55 ; v1(118.78,36.91) 118.73,36.91 118.02,37.61 DM1.201 ; v1(75.34,36.22) 76.45,37.33 76.45,39.28 76.52,39.36 DM1.43 ; DM1.214 121.27,33.96 121.32,34.01 121.32,35.43 121.89,35.99 v1(121.91,35.99) ; v1(63.28,22.36) 62.86,22.36 62.27,21.78 DM2.18 ; DM1.189 115.02,38.83 114.61,38.42 v1(114.3,38.42) ; DM2.65 74.02,26.47 74.35,26.14 74.35,25.58 73.93,25.16 v1(73.84,25.16) ; DM1.26 72.27,30.99 v1(72.59,30.68) ; DM1.248 129.77,33.7 129.75,33.72 129.75,34.15 130.17,34.57 v1(130.26,34.57) ; v1(71.28,35.45) 71.12,35.45 70.27,34.6 DM1.18 ; DM2.238 v1(119.27,20.74) ; v1(77.08,21.57) 77.27,21.38 DM2.78 ; DM2.5 59.02,26.61 58.93,26.51 58.93,26.19 58.65,25.91 v1(58.65,25.79) ; DM2.89 80.02,25.56 v1(80.08,25.5) ; v1(71.96,22.27) 71.84,22.27 70.78,21.21 DM2.52 ; DM2.10 60.27,21.62 v1(61.02,22.36) ; v1(82.89,21.63) 83.29,21.63 84.27,20.65 DM2.106 ; DM2.35 66.52,26.5 66.24,26.22 66.24,25.34 67.19,24.39 v1(67.21,24.39) ; DM2.188 v1(106.77,20.96) ; v1(116.91,35.56) 116.86,35.56 115.77,34.48 DM1.192 ; DM2.22 63.27,20.97 v1(63.28,20.97) ; v1(61.24,25.7) 61.52,25.99 DM2.15 ; v1(83.88,37.6) 83.9,37.6 85.02,38.72 85.02,40.7 DM1.77 ; v1(68.86,36.27) 68.5,36.27 67.59,37.18 67.59,38.84 68.02,39.28 DM1.9 ; DM2.223 115.52,26.05 v1(115.28,25.8) ; DM2.44 68.78,20.6 68.72,20.66 68.72,22.56 69.27,23.12 v1(69.3,23.12) ; DM1.175 111.52,39.98 111.49,39.94 111.49,38.01 112.45,37.05 v1(112.52,37.05) ; DM2.248 v1(121.77,20.91) ; 108.77,20.82 108.77,19.3 ; DM1.231 125.52,40.33 125.55,40.3 125.55,39.28 v1(125.76,39.07) ; DM2.210 112.27,20.71 ; DM1.35 74.52,39.8 74.35,39.63 74.35,38.51 75.22,37.64 v1(75.32,37.64) ; DM2.180 104.77,20.93 ; v1(75.02,28.88) 75.02,28.88 DM2.69 ; DM2.185 106.02,28.35 ; DM2.176 103.77,21.66
  BOTTOM w0.305: CPU1.AD62 104.19,85.52 CPU1.AE64 ; R605.2 90.31,90.71 91.09,91.49 v1(91.09,91.54) ; v1(123.46,72.1) 123.49,72.1 123.92,71.67 123.92,70.81 124.5,70.23 ; v1(124.24,107.65) 124.87,107.01 PC1008.2 PC1023.2 ; v1(191.65,52.39) 190.68,52.39 190.06,53.01 ; GPU1.P6 180.09,139.01 v1(180.36,139.01) ; v1(153.15,156.4) 152.2,157.35 VRAM1.U14 ; GPU1.C1 182.33,147.43 182.33,148.17 ; CPU1.AM46 112.92,81.81 CPU1.AL48 ; IOBD1.5 v1(188.59,27.55) ; WLAN1.75 86.01,148.05 v1(85.99,148.03) ; 107.77,21.42 108.21,21.85 v1(108.32,21.85) ; v1(100.65,175.44) LCD1.13 ; C8107.2 189.01,170.58 188.68,170.9 188.06,170.9 v1(187.68,170.53) ; v1(182.79,142.44) 182.73,142.5 GPU1.K2 ; v1(102.15,174.62) LCD1.16 ; v1(174.91,145.15) 174.91,145.61 GPU1.F12 ; CPU1.AE65 102.78,85.5 v1(102.75,85.5) CPU1.AE66 ; v1(170.55,140.04) 170.34,140.04 GPU1.N18 ; 110.27,21.55 110.98,22.25 v1(111,22.25) ; CPU1.AA68 v1(100.81,86.44) ; LCD1.19 103.65,174.71 v1(103.54,174.6) ; LCD1.36 112.15,175.59 v4(112.25,175.49) ; v1(104.68,94.59) 104.75,94.66 CPU1.D62 ; CPU1.AN63 104.21,80.73 104.21,80.98 CPU1.AL64 103.74,81.53 v1(104.1,81.89) 104.39,82.18 CPU1.AK63 ; v1(170.23,145.09) 170.2,145.13 GPU1.F18 ; CPU1.D39 117.14,96.01 v1(117.26,96.13) 117.14,96.24 CPU1.B39 ; v1(155.7,58.72) 154.45,59.97 U9103.23 ; v1(155.7,58.72) 153.95,56.97 U9103.16 ; v1(155.7,58.72) 157.45,56.97 U9103.9 ; DM2.217 114.02,26.37 113.99,26.34 113.99,24.83 115.1,23.72 v1(115.2,23.72) ; WLAN1.7 86.04,165.05 v1(85.76,164.77) ; CPU1.AL55 109.26,81.81 CPU1.AM55 ; GPU1.A3 181.5,148.2 182.31,148.2 182.33,148.17 ; v1(108.92,20.97) 108.77,20.82 ; VRAM1.K1 163.2,163 v1(163.59,163.38) ; WLAN1.51 v1(85.63,154.05) ; CPU1.W9 134.85,87.78 v1(134.85,87.98) 134.48,88.35 CPU1.U10 ; GPU1.G8 178.2,144.91 v1(178.6,145.31) 178.21,145.7 GPU1.F8 ; Q6701.4 187.5,35.97 187.84,36.31 187.84,36.84 188.22,37.22 188.62,37.22 Q6701.1 v1(189.66,37.27) ; v1(153.79,41.99) 154.02,42.22 C2424.2 ; 182.33,148.17 v1(182.73,148.57) ; CPU1.AW34 120.78,77.48 121.4,78.1 CPU1.AU32 121.98,77.73 CPU1.AW32 122.08,77.35 122.79,77.35 122.88,77.26 CPU1.AW30 ; v1(168.98,145.32) GPU1.F20 ; HDD1.6 v1(192.15,42.55) ; v1(119.38,22.78) 119.52,22.78 120.77,21.53 ; WLAN1.45 v1(85.63,155.55) ; CPU1.D34 119.42,95.82 v1(119.42,96.11) 119.42,96.44 CPU1.B34 ; 155.95,165.95 155.67,165.95 155.42,166.2 VRAM1.F10 ; 155.95,165.95 v1(155.95,165.93) ; 155.95,165.95 VRAM1.G10 ; WLAN1.63 v1(85.63,151.05) ; WLAN1.57 86.48,152.55 85.88,151.95 v1(85.88,151.92) ; CPU1.J28 v1(122.98,93.85) 123.05,93.85 CPU1.F28 CPU1.F27 ; CPU1.E50 111.23,95.21 v1(111.08,95.21) ; v1(156.08,169.2) 155.88,169.4 VRAM1.B10 ; v1(158.87,157.97) 159.17,157.97 VRAM1.T5 ; v1(198,123.14) 197.78,123.14 THM262.5 ; v1(73.81,20.97) 73.81,20.97 73.81,20.21 73.78,20.17 ; 108.77,19.3 DM2.196 ; 122.77,21.33 v1(121.8,22.3) ; v1(178.69,159.4) 178.3,159.01 VRAM2.C3 ; 105.77,21.88 v1(106.6,22.7) ; VRAM1.R12 153.84,159 v1(154.22,158.61) 154.6,158.99 VRAM1.R11 ; CPU1.AM13 132.75,81.52 133.07,81.52 CPU1.AK11 ; v1(179.72,148.37) 179.72,147.78 GPU1.B6 ; VRAM1.R14 v1(151.64,159) ; 101.77,20.29 101.69,20.37 101.69,21.19 102.18,21.68 102.18,22.59 102.62,23.03 v1(102.69,23.03) ; 103.77,21.66 104.48,22.36 v1(104.52,22.36) ; v1(184.44,75.03) 184.14,74.73 PU5301.4 ; CPU1.J32 121.15,93.94 v1(121.14,93.96) ; v1(151.37,168.57) 151.4,168.6 VRAM1.C14 ; C6701.2 180.42,48.4 179.83,48.4 v1(179.53,48.7) ; U9103.32 157.45,61.41 157.69,61.65 158.66,61.65 v3(159.79,60.52) ; CPU1.J8 135.48,92.29 v1(135.8,92.61) ; GPU1.AH28 v1(161.8,127.7) ; C7802.2 v1(168.05,170.21) ; v1(101.57,93.7) 101.56,93.69 101.56,92.56 CPU1.K67 ; 114.27,21.51 115.15,22.39 v1(115.49,22.39) ; v1(188.59,26.11) 188.68,26.11 188.74,26.05 IOBD1.8 ; v1(161.8,146.9) GPU1.E28 ; 118.27,20.55 118.31,20.59 118.31,21.43 117.48,22.26 v1(117.36,22.26) ; v1(107.93,174.58) 107.98,174.58 108.65,175.24 LCD1.29 ; v1(161.41,148.66) 161.4,148.65 GPU1.A30 ; CPU1.K68 CPU1.K70 ; IOBD1.2 188.99,29.05 188.59,29.45 v1(188.59,29.55) 188.6,29.55 IOBD1.1 ; v1(180.47,161.84) 180.41,161.84 179.97,161.4 ; 190.06,53.01 ED9201.2 189.85,53.05 FPR1.6 ; 190.06,53.01 190.1,53.01 190.64,53.55 FPR1.5 ; v1(158.72,165.35) 158.78,165.4 VRAM1.G5 ; VRAM1.H14 152.2,164.61 v1(152.6,165) ; v1(175.3,141.97) 175.6,142.28 GPU1.K11 ; v1(85.88,159.28) 85.88,159.14 86.48,158.55 WLAN1.33 ; 107.02,28.45 106.82,28.66 106.33,28.66 106.02,28.35 ; v1(85.63,149.55) WLAN1.69 ; 117.27,20.89 v1(117.36,20.98) ; HDD1.12 v1(192.13,39.55) ; CPU1.AA65 v1(102.76,86.44) ; WLAN1.18 95.73,162.3 v1(95.99,162.05) ; 112.27,20.71 112.24,20.74 112.24,21.18 112.65,21.6 v1(112.77,21.6) ; VRAM1.K14 152.21,163 v1(152.6,162.61) 152.61,162.61 VRAM1.K13 ; v1(86,166.71) 86.16,166.55 WLAN1.1 ; GPU1.H20 168.08,143.78 v1(167.85,143.78) ; HDD1.9 v1(192.13,41.05) ; 107.77,19.3 DM2.192 ; 72.78,20.52 72.86,20.6 72.86,21.49 72.08,22.27 v1(71.96,22.27) ; v1(177.8,136.27) 177.8,136.3 GPU1.U9 ; 116.27,21.27 v1(116.35,21.35) ; VRAM1.T10 155.87,158.67 v1(155.96,158.67) ; CPU1.T2 CPU1.T4 137.26,89.46 CPU1.R6 136.83,89.88 v1(136.83,90.2) ; v1(109.25,93.88) 109.09,93.88 CPU1.G55 ; v1(142.6,15.91) TP1.4 ; 111.27,20.96 v1(111.27,20.96) ; 104.77,20.93 v1(104.8,20.96) ; WLAN1.39 v1(85.63,157.05) ; VRAM2.N1 v1(176.14,167) ; v1(158.33,166.33) 158.45,166.2 VRAM1.F5
  BOTTOM w0.33: PU5301.19 180.66,77.48 v1(180.44,77.7) ; VRAM2.U12 v1(185.5,170.85)
  BOTTOM w0.356: GPU1.H17 171.03,144.33 v1(171.45,144.33) ; VRAM2.C14 187.23,158.87 v1(188.11,158.87) ; v1(168.46,134.5) 168.57,134.5 168.97,134.9 GPU1.Y20 ; VRAM2.R12 VRAM2.R11 v1(184.3,169) ; GPU1.G31 160.2,144.9 v1(160.18,144.92) ; v1(179.03,140.9) 179.03,140.9 GPU1.M6 ; v1(176.1,168.65) 176.15,168.6 VRAM2.R1 ; v1(187.85,55.12) 187.87,55.14 188.57,55.14 C9201.2 ; VRAM2.R4 v1(178.68,168.18) 178.68,168.22 VRAM2.R3 ; VRAM2.N12 185.5,167 v1(185.1,166.6) ; GPU1.M12 174.55,140.95 v1(174.31,140.95) ; VRAM1.M5 159.27,161.4 v1(158.88,161.79) 159.3,162.2 VRAM1.L5 ; v1(155.02,159.42) VRAM1.P10 ; v1(163.31,170.36) 162.76,170.36 VRAM1.A1 ; VRAM2.A3 178.05,157.15 v1(178.05,156.44) ; VRAM2.M5 179.93,166.21 180.99,166.21 v1(181.01,166.24) ; VRAM2.E12 v1(185.12,160.22) ; v1(183.41,168.11) 183.72,167.8 VRAM2.P10 ; v1(180.64,165.33) 179.97,165.33 VRAM2.L5 ; VRAM2.C1 176.23,159 v1(176.12,158.89) ; VRAM2.E14 187.48,160.22 v1(188.1,160.22) ; v1(171.82,146.26) 171.82,145.72 GPU1.F16 ; VRAM1.A3 161,170.74 v1(161.11,170.85) ; VRAM2.E3 v1(178.7,160.2) ; v1(155.95,161.63) 155.63,161.63 VRAM1.M10 ; VRAM1.E1 162.63,166.97 v1(163.57,166.97) ; VRAM1.A14 152.57,170.57 v1(152.57,170.62) ; v1(173.03,146.12) 173.4,145.74 GPU1.F14 ; v1(155,161.8) VRAM1.L10 ; v1(161.51,156.79) 161.51,156.89 VRAM1.U3 ; VRAM2.K1 176.7,164.6 v1(177.1,165) 177.5,164.6 VRAM2.K2 ; v1(172.64,130.34) 173.04,130.34 GPU1.AE14 ; v1(176.3,156.49) 176.7,156.89 VRAM2.A1 ; VRAM2.F10 183.77,161.53 183.77,162.07 VRAM2.G10 183.35,162.75 v1(183.35,163.12) ; PQ8604.4 145.68,137.12 146.02,137.46 146.02,138.11 ; v1(163.52,168.86) 163.27,168.86 163.02,168.6 VRAM1.C1 ; VRAM1.C12 v1(154.2,169) ; v1(177.01,144.5) 176.61,144.9 GPU1.G10 GPU1.F10 ; v3(159.79,60.52) 159.95,60.46 160,60.34 160.22,60.12 C9106.2 161.07,60.42 C9108.2 ; v1(154.18,166.62) VRAM1.E12 ; v1(178.26,170.78) 178.3,170.74 VRAM2.U3 ; VRAM2.L10 183.36,165.4 v1(183.3,165.46) ; VRAM1.H13 152.6,165 v1(152.6,165) ; VRAM2.H2 177.5,163.01 v1(177.1,163.4) ; v1(189.32,163.62) 188.61,163.62 R8109.1 ; VRAM1.E3 161,167 v1(160.6,166.6) ; VRAM1.R3 160.99,159 v1(160.59,158.6) 160.2,158.99 VRAM1.R4 ; VRAM1.H1 162.55,164.6 v1(162.18,164.97) 161.81,164.6 VRAM1.H2 ; v1(179.42,143.72) GPU1.H6 ; v1(178.69,159.4) 178.7,159.4 VRAM2.C4 VRAM2.B5 ; GPU1.K22 167.03,142.5 v1(166.66,142.88) ; EC1712.2 154.43,67.56 v1(154.62,67.37) ; v1(188.39,168.78) 188.2,168.6 VRAM2.R14 ; v1(188.37,157.31) 188.34,157.31 188.25,157.4 VRAM2.A14 ; VRAM2.U14 187.43,170.53 v1(187.68,170.53) ; Q1701.1 154.5,63.2 v1(154.27,62.97) 153.89,63.35 R9141.2 ; VRAM2.E1 176.01,160.6 v1(175.99,160.58) ; v1(163.2,160.6) VRAM1.N1 ; VRAM2.K13 186.3,164.61 v1(186.69,165) 187.09,164.6 VRAM2.K14 ; GPU1.P9 177.4,139.35 v1(177.67,139.62) ; v1(183.37,166.41) 183.69,166.41 VRAM2.M10 ; v1(160.24,143.34) 160.28,143.3 GPU1.J31 ; v1(185.81,156.91) 185.5,157.22 VRAM2.A12 ; v1(162.6,130.88) 162.62,130.88 GPU1.AE27 ; GPU1.G27 163.01,144.9 v1(163.41,145.3) 163.8,145.69 GPU1.F26 ; VRAM1.C4 v1(160.6,169) 161,168.6 VRAM1.C3 ; v1(174.59,128.48) 175,128.89 GPU1.AG12 ; v1(163.38,128.52) GPU1.AG27 ; C9202.2 188.57,55.98 v1(187.79,55.98) ; v1(158.87,169.9) 159.37,169.4 VRAM1.B5 ; v1(179.41,145.31) GPU1.F6 ; v1(155,168.2) VRAM1.C11 ; VRAM1.N12 v1(154.2,161) ; v1(155.92,167.93) 155.79,167.8 VRAM1.D10 ; v1(180.19,137.31) GPU1.T6 ; v1(176.3,170.6) VRAM2.U1 ; GPU1.J7 179.01,143.3 v1(179.4,142.91) 179.4,142.9 GPU1.K6 ; v1(121.95,76.63) 121.98,76.6 CPU1.BA32 ; v1(166.61,146.11) 166.61,146.09 GPU1.F22 ; VRAM1.R1 163.15,159 v1(163.28,158.87) ; VRAM2.N3 v1(177.9,166.6) ; GPU1.F24 165.4,146.15 v1(165.23,146.32) ; C2618.2 188.17,117.96 v1(187.94,118.19) ; v1(176.05,128.32) 176.26,128.1 GPU1.AH10 ; v1(161.38,160.98) VRAM1.N3 ; v1(151.67,166.98) 151.68,167 VRAM1.E14 ; VRAM1.N14 152.18,160.62 v1(151.54,160.62) ; VRAM2.T10 183.87,169.4 v1(183.37,169.9) ; VRAM2.B10 183.74,158.04 v1(183.39,158.04) ; VRAM2.C11 VRAM2.D10 183.74,159.8 v1(183.39,159.45) ; VRAM2.H13 VRAM2.H14 187.77,163 v1(187.92,163.16) ; GPU1.J27 v1(163.4,142.9) ; v1(187.7,167) VRAM2.N14 ; VRAM1.A12 v1(153.8,170.76) ; v1(163.54,156.87) 163.01,157.4 VRAM1.U1 ; VRAM1.K1 VRAM1.K2 ; v1(172.6,143.56) 172.66,143.56 GPU1.H14 ; VRAM2.T5 v1(180.3,169.8) ; C2617.2 188.2,120.3 v1(187.79,120.7) ; VRAM2.F5 179.97,161.4
  BOTTOM w0.381: PC4614.2 129.78,139.4 PC4661.2 129.78,138.73 v1(130.39,138.12) ; v1(186.26,41.06) 186.23,41.06 186.29,41 ED6001.3 ED6001.8 ; EC9723.2 22.92,58.55 23.28,58.19 v1(23.28,58.15) ; v1(114.3,141.35) 113.67,141.35 113.29,140.97 PC4621.1 113.29,140.54 114.05,139.78 PC4601.2 115.12,139.77 PC4624.2 ; C5622.2 11.94,81.99 12.16,81.77 12.16,81.63 12.17,81.62 v1(12.17,81.3) ; ED3201.3 ED3201.8 v1(34.67,179.3) ; v1(149.77,85.5) 149.7,85.43 149.68,85.43 149.54,85.29 R1823.2 ; EC1802.2 139.03,60.2 v1(140.07,59.16) ; CPU1.AW32 121.98,76.67 v1(121.95,76.63) ; v1(147.34,68.31) 147.34,68.2 146.7,67.56 R1825.2 ; C5616.2 11.44,79.73 v1(11.15,79.45) ; ED3704.2 182.13,29.75 181.19,29.75 v1(181.11,29.66)
  BOTTOM w0.406: R5528.2 97.67,172.5 97.62,172.55 v1(97.62,172.74) ; 146.02,138.11 146.02,138.9 v1(146.22,139.09) 146.22,138.98 146.78,138.42 PQ8604.1 147.67,138.42 PC8602.2 ; v1(154.14,156.96) 153.8,157.3 VRAM1.U12 ; v1(148.75,46.38) 149.08,46.71 SKT251.4 SPI25.4 ; v1(135.35,172.68) 135.35,172.01 ; v1(106.99,173.31) 107.07,173.23 107.07,171.3 R5526.2 107.29,171.08 C5541.2 108.11,171.08 108.21,171.18 108.21,171.96 108.54,172.29 C5501.2 ; C1803.2 140.83,68.35 140.72,68.25 140.72,68.21 v1(140.77,68.21) 141,67.97 141,67.97 R2016.2
  BOTTOM w0.457: C2123.2 179.61,23.59 v1(179.54,23.66) ; v4(46.94,68.52) 47.44,68.02 PC4520.2
  BOTTOM w0.508: 152.25,184.73 BATT1.8 ; BATT1.8 151.18,185.8 ; BATT1.8 152.25,186.87 ; PC8607.2 142.83,149.28 144.05,149.28 v1(144.25,149.48) ; v1(61.17,92.36) 61.26,92.27 EC9737.2 ; R713.1 v1(80.93,90.14) ; v1(152.81,120.47) 152.81,121.41 X7901.2 ; v1(189.24,135.94) 189.49,136.18 C8053.2 ; C2722.2 172.65,25.78 172.65,26.17 v1(172.72,26.25) ; PC4526.2 46.84,80.16 v1(46.84,80.27) ; VGA1.16 9.08,70.2 ; VGA1.16 7.11,71.22 ; VGA1.16 7.11,69.18 ; 8.75,167.75 6.83,167.75 RJ45.9 6.35,167.72 4.33,167.72 4.23,167.63 ; v1(176.43,23.04) 176.45,23.04 176.97,22.53 Q2110.S ; v1(146.28,12.15) 146.33,12.1 TP1.9 ; v1(165.9,8.72) Q2705.S 166.14,7.98 C2736.2 ; C2419.2 164.29,26.17 v1(164.09,25.97) 163.6,25.97 R2417.2 ; v1(180.46,28.42) 180.48,28.42 180.69,28.22 R2118.2 ; 169.37,183.74 BATT1.9 ; BATT1.9 170.44,185.8 ; BATT1.9 168.31,185.8 ; VGA1.5 6.41,84.49 v1(6.41,84.49) ; v1(185.45,78.51) 186.18,78.51 187.12,77.56 PR5304.2 187.08,76.43 PC5314.2 186.22,76.42 PR5303.2 ; 193.9,73.41 H16.1 193.9,63.19 ; v1(57.63,54.28) 57.59,54.24 PC4518.2 ; v1(116.87,176.86) 116.87,177.77 117.25,178.15 LCD1.44 ; PR8508.1 157.22,105.1 158.55,105.1 PR8506.1 158.66,105.56 v1(158.37,105.86) ; v1(128.57,121.92) 127.96,121.92 PR4617.1 ; v1(78.31,75.5) 78.26,75.5 78.01,75.25 C722.2 ; 149.12,183.74 BATT1.10 ; BATT1.10 150.19,185.8 ; BATT1.10 148.06,185.8 ; v1(80.77,74.13) 80.82,74.19 81.54,74.19 Q502.S ; v1(179.92,96.01) 179.71,96.22 EC9706.2 ; 154.25,184.73 BATT1.7 154.25,186.87 ; 4.87,4.31 USB2.13 6.79,5.35 ; v1(171.1,4.22) 171.15,4.18 EC6404.2 ; 10.12,47.5 HDMI1.2 ; HDMI1.2 11.78,47.5 ; HDMI1.2 10.95,46.75 ; R2735.2 175.06,29.83 174.85,29.61 v1(174.85,29.38) ; 168.61,82.87 170.04,84.3 H13.1 ; v3(174.78,26.28) 174.78,26.08 174.41,25.71 C2723.2 ; 10.2,57.58 HDMI1.21 ; HDMI1.21 10.2,59.92 ; HDMI1.21 11.81,58.75 ; 15.4,85.69 H14.1 ; H14.1 20.01,90.3 ; H14.1 10.79,90.3 ; v1(189.32,163.62) C8104.2 189.59,164.28 189.67,164.21 R8108.2 ; PR8528.2 165.32,115.49 v1(165.13,115.67) PC8516.2 ; 21.9,12.91 H11.1 17.29,8.3 ; 10.2,43.08 HDMI1.20 ; HDMI1.20 10.2,45.42 ; HDMI1.20 11.81,44.25 ; C5607.2 v1(11.89,85.16) ; v1(169.2,50.1) 169.2,50.12 168.63,50.69 R2448.2 168.63,51.46 C2409.2 ; v4(197.24,162.84) 197.29,162.84 198.1,163.65 PC8654.2 198.08,163.91 PC8655.2 ; C2423.2 177.65,37.44 177.98,37.44 v1(178.27,37.14) ; v1(137.75,174.22) 137.68,174.22 137.18,174.71 PC4461.1 ; C2413.2 154.5,32.92 C2417.2 155.32,32.4 v1(155.83,31.9) ; v1(128.32,143.6) 127.63,143.6 PC4604.1 127.47,144.21 PR4614.1 ; v1(149.51,38.86) 149.28,39.09 C2125.2 ; v1(154.73,51.73) 154.62,51.84 C9111.2 C9107.2 ; PR5152.2 130.23,20.21 130.14,20.12 v1(129.97,20.12) ; 14.28,27.16 USB1.4 ; USB1.4 14.28,28.94 ; USB1.4 15.17,28.05 ; v1(146.9,24.36) 146.87,24.38 EC6505.2 ; PR8524.2 158.13,115.47 v1(158.01,115.59) ; EC9735.2 31.48,61.82 v1(31.49,61.83) ; 11.78,50.5 HDMI1.8 10.12,50.5 ; PR8516.2 156.9,112.18 v1(156.39,112.69) 156.6,112.9 PC8511.2 ; v1(142.79,105.7) 142.79,105.69 142.79,105.67 142.81,105.69 142.83,105.69 143.09,105.95 R1717.1 144.17,105.95 EC1702.2 144.26,105.94 144.96,105.94 EC1706.2 ; 5.31,60.65 HDMI1.23 3.7,61.82 ; LED1.3 167.7,1.8 v1(166.83,2.67) ; v1(149.44,61.57) 149.44,61.52 149.37,61.45 C9113.2 ; v1(97.58,124.82) 97.54,124.86 PR4654.2 ; PR5404.2 160.42,70.8 159.85,70.23 PU5401.1 159.31,69.74 159.06,69.49 v1(159.02,69.49) ; v4(108.94,134.78) 108.51,135.2 FAN1.4 ; 14.22,23.85 USB1.11 12.3,22.81 ; EC6501.2 151.84,18.15 151.84,18.63 v1(151.56,18.91) ; 12.3,21.79 USB2.10 14.22,20.75 ; v1(136.89,169.47) 137.1,169.47 137.84,170.21 PR4412.2 ; USB2.11 12.3,4.31 ; v1(165.27,51.3) 165.5,51.06 C2418.2 ; C2403.2 156.85,21.63 v1(156.92,21.56) ; v1(151.75,112.24) 151.96,112.03 R7925.2 ; v1(112.28,104.83) 112.3,104.83 112.17,104.7 R407.2 ; EC9742.2 116.73,171.67 v1(116.49,171.43) ; v1(156.58,27.22) 156.87,27.5 C2405.2 ; v1(77,70.98) 76.58,71.39 C715.2 ; 5.31,42.35 HDMI1.22 3.7,41.18 ; PR4818.2 v1(116.07,130.7) ; EC6506.2 144.26,24.13 v1(144.03,23.9) ; v1(110.52,169.5) 110.2,169.5 109.84,169.86 C5540.2 ; C5617.2 11.87,77.36 v1(11.8,77.29) ; 120.67,70.83 120.67,70.3 121.63,69.34 v1(121.66,69.34) ; 135.35,172.01 PC4445.2 PC4446.2 ; C2737.2 v1(163.94,5.46) ; 6.41,72.25 VGA1.6 7.27,73.08 ; VGA1.17 9.08,87.4 ; VGA1.17 7.11,86.38 ; VGA1.17 7.11,88.42 ; EC9719.2 v1(28.98,60.08) ; R602.2 93.15,76.21 H2.1 ; VGA1.7 7.3,75.36 ; USB1.10 12.3,40.29 ; PR4302.2 56.15,171.43 56.15,170.44 v1(56.28,170.31) ; C2119.2 167.82,80.1 v1(167.31,80.61) ; v1(129.55,177.81) 129.56,177.81 PC4468.2 ; v1(150.16,25.47) 150.35,25.47 150.77,25.9 Q6505.S ; v1(156.33,47.87) C2426.2 ; v1(143.28,40.55) 143.07,40.55 142.96,40.66 U2101.2 ; v1(77.67,83.56) 77.78,83.67 R1719.2 ; PC4612.2 129.94,144.28 PC4651.2 129.96,145.01 v1(129.9,145.07) ; PR4817.2 v1(125.23,130.68) ; v1(154.74,27.33) 155.28,27.87 C2406.2 ; USB1.13 4.87,22.81 ; v1(187.92,163.16) 188.45,163.68 R8109.1 ; PR8623.2 v1(141.27,150.03) ; v1(157.27,120.76) R7934.2 ; PR4712.2 v1(107.09,130.74) ; C2425.2 v1(151.89,38.91) ; v1(114.83,175.55) 115.05,175.77 LCD1.42 ; v1(171.79,29.21) 171.66,29.21 171.65,29.21 C2739.2 ; v1(185.71,178.41) 185.99,178.69 G6402.2 ; v1(154.66,93.7) 154.66,93.66 154.82,93.5 C2113.2 ; USB2.12 4.87,21.79 ; EC1901.1 140.9,53.34 FC1902.2 141.43,53.46 141.66,53.24 v1(141.86,53.24) ; USB1.12 4.87,40.29 ; PC8525.2 161.56,118.17 v1(161.68,118.29) ; PC5155.2 129.67,17.64 v1(129.6,17.57) ; v4(54.31,66.44) 54.31,66.5 54.77,66.96 PC4536.2 ; 14.28,8.66 USB2.4 ; USB2.4 15.17,9.55 ; USB2.4 14.28,10.44 ; 7.62,82.24 VGA1.10 ; VGA1.8 7.28,77.65
  vias: v1(1.05,60.45) v1(1.05,42.61) v1(1.55,68.54) v1(1.65,90.45) v1(1.67,88.84) v1(3.23,88.83) v1(3.21,68.78) v1(3.53,92.97) v1(3.48,91.01) v1(3.52,67.56) v1(3.53,65.77) v1(3.52,64.51) v1(3.54,40.39) v1(3.56,62.33) v1(3.63,22.69) v1(3.63,21.92) v1(4.59,92.98) v1(4.78,64.67) v1(4.88,63.35) v1(5.03,66.22) v1(5.1,90.98) v1(5.09,3.07) v1(5.47,41.18) v1(5.74,67.34) v1(5.86,89.14) v1(6.1,61.65) v1(6.33,71.66) v1(6.4,85.81) v1(6.66,67.05) v1(6.8,92.97) v1(6.84,41.23) v1(6.94,42.61) v1(6.96,60.4) v1(7.1,23.6) v1(7.07,21.01) v1(7.47,61.7) v1(7.54,39.48) v1(7.73,68.18) v1(7.87,85.62) v1(8.07,90.04) v1(8.14,3.07) v1(8.39,41.84) v1(8.55,22.2) v1(8.61,92.17) v1(8.64,82.02) v1(8.57,40.52) v1(8.67,71.55) v1(8.91,5.13) v1(9.05,79.33) v1(9.05,74.09) v1(9.05,68.28) v1(9.12,61.54) v1(9.23,77.62) v1(9.48,60.25) v1(9.48,42.78) v1(9.55,66.83) v1(9.62,57.38) v1(9.74,75.9) v1(9.74,46.03) v1(9.74,23.6) v1(9.84,21.01) v1(9.86,41.63) v1(9.97,79.85) v1(9.99,71.66) v1(10.05,167.65) v1(10.13,91.06) v1(10.16,87.91) v1(10.17,39.7) v1(10.4,92.97) v1(10.42,77.24) v1(10.37,74.2) v1(10.54,61.8) v1(11.15,70.57) v1(11.23,41.68) v1(11.68,71.47) v1(11.85,73.91) v1(11.92,3.08) v1(12.01,60.55) v1(12.3,44.43) v1(12.61,71.5) v1(12.74,77.2) v1(12.71,73.92) v1(12.69,61.71) v1(12.71,43.44) v1(12.71,41.99) v1(13.03,26.44) v1(13.1,167.65) v1(13.45,81.02) v1(13.67,38.08) v1(14.08,43.49) v1(14.08,42.04) v1(14.05,40.29) v1(14.24,3.07) v1(14.33,44.41) v1(14.31,24.87) v1(14.73,22.34) v1(15.75,3.08) v1(15.81,71.47) v1(15.91,76.91) v1(16.15,167.65) v1(16.19,74.09) v1(16.67,71.45) v1(16.8,76.91) v1(16.97,29.45) v1(17.08,74.03) v1(17.09,42.88) v1(17.13,19.53) v1(17.29,3.07) v1(17.86,75.58) v1(17.86,42.45) v1(17.99,74.04) v1(18.24,80.01) v1(18.17,78.31) v1(18.52,19.64) v1(18.71,43.47) v1(19.03,78.31) v1(19.24,186.97) v1(19.2,167.65) v1(19.72,48.31) v1(19.68,44.01) v1(19.74,43.28) v1(19.97,46.48) v1(20.12,3.23) v1(20.22,53.37) v1(20.71,43.31) v1(20.85,44.16) v1(20.92,92.97) v1(21.01,186.87) v1(20.98,51.56) v1(21.04,49.81) v1(21.34,71.84) v1(21.56,184.72) v1(21.63,44.17) v1(21.6,43.31) v1(21.87,71.12) v1(22.02,90.9) v1(22.25,167.65) v1(22.87,92.98) v1(23.12,53.14) v1(23.25,51.49) v1(23.35,76.84) v1(23.5,46.38) v1(23.48,45.49) v1(23.83,48.11) v1(23.81,47.2) v1(24.24,77.73) v1(24.24,76.84) v1(24.24,75.95) v1(24.76,90.47) v1(25.13,76.84) v1(25.29,167.65) v1(26.32,34.93) v1(26.45,37.04) v1(26.55,92.97) v1(26.5,35.77) v1(26.91,30.85) v1(26.86,29.92) v1(26.97,33.21) v1(27.15,89.57) v1(27.65,24.34) v1(27.67,25.2) v1(27.91,33.34) v1(27.92,27.76) v1(27.9,26.9) v1(27.95,71.43) v1(28.19,73.53) v1(28.34,167.65) v1(29,53) v1(29.24,182.58) v1(29.41,87.66) v1(30.35,73.01) v1(30.84,78.89) v1(31.39,167.65) v1(31.49,53.05) v1(31.96,87.63) v1(32.29,182.58) v1(32.49,78.95) v1(32.6,80.12) v1(33.03,81.87) v1(34.18,87.66) v1(34.54,86.28) v1(35.34,182.58) v1(36.6,90.1) v1(36.78,22.63) v1(37.79,90.11) v1(38.25,174.58) v1(38.3,179.08) v1(38.32,19.7) v1(38.38,182.58) v1(38.41,176.58) v1(38.55,177.96) v1(38.53,22.65) v1(39.17,23.28) v1(39.17,22.65) v1(39.17,22.01) v1(39.8,22.65) v1(39.9,34.99) v1(40.64,35.01) v1(40.7,41.63) v1(40.99,177.26) v1(41.31,166.83) v1(41.43,182.58) v1(41.39,35.03) v1(41.49,42.01) v1(41.65,90.1) v1(41.77,179.22) v1(42.12,35.02) v1(42.37,42.01) v1(42.72,173.96) v1(42.8,168.36) v1(42.76,35.03) v1(43.31,42.01) v1(43.62,178.51) v1(43.91,180.09) v1(44.28,168.28) v1(44.41,47.3) v1(44.48,182.58) v1(44.9,166.79) v1(44.9,93.6) v1(45.02,172.39) v1(45.09,171.2) v1(46.21,179.05) v1(46.23,50.85) v1(46.87,182.56) v1(47.44,166.8) v1(47.66,174.68) v1(48.08,75) v1(48.55,175.57) v1(48.55,174.68) v1(48.55,173.79) v1(48.72,75.64) v1(48.72,75) v1(48.72,74.37) v1(49.03,170.36) v1(49.44,174.68) v1(49.35,75) v1(49.98,93.6) v1(50.27,171.41) v1(50.36,180.39) v1(50.36,179.57) v1(50.99,166.79) v1(51.24,170.46) v1(52.56,43.63) v1(54.41,11.22) v1(54.51,166.74) v1(54.82,7.33) v1(55.05,93.69) v1(55.29,11.21) v1(55.38,184.98) v1(56.58,183.58) v1(57.37,181.41) v1(58.43,184.98) v1(59.47,94.25) v1(60.14,42.77) v1(60.62,165.93) v1(60.76,181.22) v1(60.89,43.47) v1(61.48,184.98) v1(62.05,94.78) v1(62.62,183.58) v1(64.22,180.77) v1(64.32,95.51) v1(64.84,184.98) v1(65.03,94.05) v1(65.13,164.61) v1(65.95,77.6) v1(66.02,78.69) v1(66.15,22.66) v1(66.25,75.15) v1(66.82,96.42) v1(67.21,22.97) v1(68.66,166.98) v1(69.23,184.98) v1(69.64,97.78) v1(71.2,167.06) v1(71.7,98.92) v1(71.97,184.95) v1(73.36,164.85) v1(73.42,100.08) v1(73.57,160.29) v1(74.58,162.41) v1(74.87,101.04) v1(75.43,184.93) v1(75.84,88.09) v1(75.95,158.46) v1(77.58,68.38) v1(77.7,82.69) v1(77.99,158.86) v1(79.23,184.97) v1(80.21,69.93) v1(80.75,65.28) v1(81.34,155.63) v1(82.09,184.98) v1(83.31,150.24) v1(83.52,153.19) v1(84.93,174.57) v1(84.88,112.8) v1(85.66,100.79) v1(85.68,94.69) v1(85.94,114.93) v1(85.99,99.87) v1(86.07,147.14) v1(86.17,174.51) v1(86.35,144.46) v1(88.05,120.91) v1(88.12,94.69) v1(88.56,137.28) v1(89.04,84.71) v1(89.09,139.67) v1(89.15,94.69) v1(89.7,167.02) v1(92.4,79.79) v1(93.18,65.47) v1(93.86,81.27) v1(95,65.81) v1(95.64,19.14) v1(95.61,18.01) v1(96.36,67.2) v1(97.09,84.25) v1(100.5,124.2) v1(100.71,174.77) v1(101.01,170.04) v1(100.99,168.45) v1(101.25,71.21) v1(101.48,85.52) v1(102.43,126.56) v1(102.43,125.75) v1(102.43,124.92) v1(102.45,67.13) v1(103.12,126.56) v1(103.11,125.75) v1(103.11,124.92) v1(103.8,126.56) v1(103.8,125.75) v1(103.8,124.92) v1(104.3,167.53) v1(104.49,126.56) v1(104.48,125.75) v1(104.49,124.92) v1(104.99,102.25) v1(105.17,126.56) v1(105.17,125.75) v1(105.17,124.92) v1(105.37,83.46) v1(105.61,82.75) v1(105.86,126.56) v1(105.86,125.75) v1(105.86,124.92) v1(105.89,102.25) v1(106.04,83.47) v1(106.57,77.7) v1(108.01,182.96) v1(108.58,143.68) v1(110.07,175.54) v1(110.84,158.5) v1(111.35,156.59) v1(111.79,126.43) v1(111.78,125.61) v1(111.79,124.78) v1(112.25,86.41) v1(112.32,88.7) v1(112.47,126.43) v1(112.47,125.61) v1(112.47,124.78) v1(112.99,88.69) v1(112.96,86.44) v1(113.16,126.43) v1(113.15,125.61) v1(113.16,124.78) v1(113.6,86.42) v1(113.65,88.7) v1(113.84,126.43) v1(113.84,125.61) v1(113.84,124.78) v1(114.23,86.41) v1(114.31,88.67) v1(114.53,126.43) v1(114.53,125.61) v1(114.53,124.78) v1(115.22,126.43) v1(115.21,125.61) v1(115.21,124.78) v1(115.67,93.82) v1(116.82,172.67) v1(117.47,81.03) v1(117.49,80.38) v1(117.64,73.57) v1(117.81,105.77) v1(117.86,69.49) v1(118.07,174.5) v1(118.31,184.97) v1(118.27,102.49) v1(119.32,80.38) v1(119.32,79.73) v1(119.36,93.93) v1(120.06,71.67) v1(120.24,82.62) v1(120.46,143.7) v1(120.97,126.31) v1(120.97,125.49) v1(120.97,124.66) v1(121.11,80.39) v1(121.24,143.05) v1(121.25,142.39) v1(121.23,141.73) v1(121.17,90.4) v1(121.25,143.73) v1(121.66,126.31) v1(121.66,125.49) v1(121.66,124.66) v1(122.03,143.72) v1(122.01,143.04) v1(122.02,142.39) v1(122,141.74) v1(122.01,71.27) v1(122.06,171.06) v1(122.05,170.35) v1(122.23,96.14) v1(122.34,126.31) v1(122.34,125.49) v1(122.34,124.66) v1(122.74,105.66) v1(122.82,143.7) v1(122.77,142.04) v1(123.03,126.31) v1(123.03,125.49) v1(123.03,124.66) v1(122.98,80.38) v1(123.72,126.31) v1(123.71,125.49) v1(123.71,124.66) v1(124.01,82.73) v1(124.4,126.31) v1(124.4,125.49) v1(124.4,124.66) v1(124.75,96.12) v1(124.97,184.97) v1(125.01,72.61) v1(125.14,64.08) v1(125.23,102.02) v1(125.33,125.75) v1(125.36,126.61) v1(125.41,124.98) v1(125.44,101.06) v1(125.71,81.01) v1(125.72,80.38) v1(126.14,90.38) v1(126.16,71.62) v1(126.65,82.6) v1(127.83,71.75) v1(128.3,11.94) v1(129.24,76.58) v1(129.17,11.94) v1(129.43,79.06) v1(129.93,106.16) v1(130.03,11.97) v1(130.11,181.84) v1(130.79,106.1) v1(131.58,184.98) v1(132.39,26.16) v1(132.6,27) v1(132.75,176.73) v1(132.75,90.15) v1(132.89,82.81) v1(133.44,84.83) v1(133.5,83.68) v1(133.77,177.74) v1(133.77,176.73) v1(133.77,175.71) v1(133.92,79.71) v1(134.11,84.83) v1(134.21,130.98) v1(134.25,91.19) v1(134.63,184.98) v1(134.78,176.73) v1(135.39,90.17) v1(135.76,93.97) v1(136.24,41.18) v1(136.81,87.99) v1(136.76,82.76) v1(137.09,154.89) v1(137.5,154.36) v1(137.5,31.06) v1(137.68,184.98) v1(138.34,79.04) v1(138.92,154.43) v1(138.92,153.8) v1(138.87,17.33) v1(139.55,154.33) v1(139.73,17.35) v1(139.91,184.95) v1(140.27,180.64) v1(141.18,184.96) v1(141.22,152.48) v1(141.22,151.85) v1(141.5,83.19) v1(141.5,81.42) v1(143.49,185.66) v1(143.59,68.09) v1(143.7,83.24) v1(144.08,56.53) v1(144.19,55.68) v1(144.41,186.44) v1(144.63,184.52) v1(145.02,123.12) v1(145.68,185.11) v1(145.81,116.39) v1(145.81,114.49) v1(145.81,112.58) v1(145.83,110.63) v1(146.2,186.48) v1(146.39,156.69) v1(146.41,109.07) v1(146.47,166.48) v1(146.47,164.98) v1(146.5,107.86) v1(146.64,168.38) v1(147.55,186.47) v1(147.79,169.91) v1(149.44,17.38) v1(149.45,16.47) v1(149.57,127.7) v1(149.81,33.38) v1(149.94,7.7) v1(150.14,124.31) v1(150.48,184.48) v1(150.68,186.95) v1(150.81,123.08) v1(151.17,185.1) v1(152.52,4.08) v1(152.55,1.07) v1(153.09,175.14) v1(153.29,186.96) v1(154.82,59.62) v1(154.95,173.46) v1(155.03,186.96) v1(155.13,174.85) v1(155.21,120.9) v1(155.7,173.94) v1(156.5,57.94) v1(157.57,186.98) v1(157.78,140.73) v1(158,128.42) v1(158.1,129.36) v1(158.31,132.82) v1(158.71,51.42) v1(159.14,8.03) v1(159.35,186.97) v1(159.65,142.45) v1(159.74,176.87) v1(160.46,141.46) v1(160.47,3.37) v1(160.64,109.17) v1(161.22,186.95) v1(161.32,109.17) v1(161.62,57.12) v1(161.94,54.49) v1(161.96,110.59) v1(161.96,109.88) v1(161.97,109.17) v1(162.01,108.49) v1(162.01,107.75) v1(162.44,141.66) v1(162.38,138.37) v1(162.69,109.17) v1(162.93,79.32) v1(163,186.98) v1(162.98,78.46) v1(163.1,45.62) v1(163.23,23.24) v1(163.41,109.15) v1(163.52,134.91) v1(163.54,133.72) v1(163.47,132.55) v1(163.77,16.04) v1(164.15,137.17) v1(164.18,133.72) v1(164.18,132.58) v1(164.21,131.68) v1(165.04,133.72) v1(165.01,113.29) v1(165.46,176.26) v1(165.49,113.74) v1(166.36,176.23) v1(167.22,176.2) v1(168.05,186.97) v1(168.05,126.26) v1(168.19,176.22) v1(168.21,46.05) v1(168.43,140.29) v1(168.44,137.39) v1(169.02,46.33) v1(169.48,124.69) v1(170.02,125.36) v1(170.44,183.9) v1(170.57,137.22) v1(171.38,136.43) v1(171.45,18.73) v1(171.55,28.16) v1(172.04,57.08) v1(172.33,137.29) v1(172.33,133.38) v1(172.34,19.62) v1(172.34,18.73) v1(172.34,17.84) v1(172.48,135.34) v1(172.75,176.15) v1(173.23,18.73) v1(173.42,133.36) v1(173.47,138.12) v1(173.61,176.17) v1(174.24,139.33) v1(174.18,137.32) v1(174.23,135.49) v1(174.81,176.18) v1(175.09,185.15) v1(175.35,139.36) v1(175.33,138.06) v1(175.55,176.2) v1(177.74,132.63) v1(177.81,131.67) v1(177.93,176.26) v1(178.59,132.59) v1(178.59,131.7) v1(178.81,176.29) v1(178.75,81.13) v1(179.34,82.98) v1(179.38,132.56) v1(179.42,131.69) v1(179.75,176.3) v1(179.84,33.16) v1(179.89,50.55) v1(179.9,36.71) v1(180.32,81.41) v1(180.52,34.53) v1(180.61,176.32) v1(180.93,54.26) v1(181.01,175.38) v1(181.71,11.83) v1(181.98,33.2) v1(182.31,175.39) v1(182.53,125.28) v1(182.71,24.89) v1(183.07,42.19) v1(183.14,41.37) v1(183.12,40.43) v1(183.07,39.56) v1(183.42,175.41) v1(183.82,36.64) v1(183.93,178.55) v1(184.19,46.76) v1(184.42,1.02) v1(184.56,175.38) v1(184.98,36.64) v1(185.07,125.33) v1(185.05,46.76) v1(185.66,22.75) v1(185.67,13.92) v1(185.85,135.98) v1(185.9,175.41) v1(186.21,182.96) v1(186.49,94.39) v1(186.61,135.99) v1(186.71,22.95) v1(186.78,125.67) v1(187.01,29.16) v1(187.35,94.4) v1(187.47,1.02) v1(187.96,175.54) v1(188.09,122.62) v1(188.6,182.93) v1(188.82,175.49) v1(189.31,1.02) v1(190.03,182.98) v1(190.52,124.89) v1(190.48,90.29) v1(190.52,1.02) v1(190.57,80.23) v1(190.59,79.31) v1(190.69,149.2) v1(190.76,148.47) v1(191.63,1.03) v1(191.67,182.95) v1(192.14,47.25) v1(192.51,148.85) v1(192.49,148.21) v1(193.02,178.84) v1(192.96,2.4) v1(193.63,182.91) v1(193.89,122.07) v1(194.21,163.62) v1(194.87,4.27) v1(195.19,182.97) v1(195.84,182.39) v1(196.16,135.54) v1(196.22,124.89) v1(196.81,116.16) v1(197.01,59.08) v1(197.03,44.31) v1(197.01,41.63) v1(196.99,38.91) v1(197.03,37.22) v1(197.03,34.58) v1(197.03,29.37) v1(197.03,26.73) v1(197.02,23.98) v1(197.03,19.98) v1(197.03,17.34) v1(196.98,14.59) v1(197.03,9.42) v1(197.08,182.98) v1(198.86,181.41) v1(198.89,180.44) v1(198.91,127.91) v1(199.2,182.96) v2(14.25,75.18) v2(16.36,43.44) v2(20.85,41.49) v2(22.59,78.11) v2(23.12,76.02) v2(23.5,68.17) v2(24.73,86.37) v2(25.51,19.46) v2(28.81,84.2) v2(30.23,53.51) v2(31.13,83.52) v2(31.75,49.6) v2(42.46,20.6) v2(45.9,17.98) v2(54.54,90.55) v2(57.79,10.06) v2(59.69,180.49) v2(60.2,182.18) v2(81.01,161.52) v2(81.6,167.69) v2(81.92,75.62) v2(82.33,175.4) v2(84.5,176.97) v2(86.04,169.7) v2(86.6,55.61) v2(90.41,45.67) v2(97.59,84.99) v2(100.79,84.63) v2(101.35,56.47) v2(105,79.91) v2(107.34,80.73) v2(122.3,64.06) v2(129.21,39.76) v2(131.95,110.53) v2(131.86,53.24) v2(137.8,152.73) v2(141.25,154.05) v2(158.29,137.53) v2(166.33,104.31) v2(166.56,111.51) v2(169.17,106.33) v2(174.4,91.67) v2(184.27,180.64) v2(184.27,176.9) v2(184.28,45.62) v3(77.66,91.65) v3(110.93,141.49) v3(112.49,88) v3(112.52,87.3) v3(113.28,88) v3(113.31,87.3) v3(114.07,87.98) v3(114.09,87.27) v3(121.32,89.13) v3(121.29,86.34) v3(121.32,84.86) v3(121.37,87.73) v3(122.08,89.13) v3(122.13,87.73) v3(122.05,86.34) v3(122.08,84.86) v3(165.74,26.45) v3(166.66,26.46) v3(167.11,27.34) v3(168.36,70.33) v3(168.4,68.5) v3(171.66,69.24) v3(172.4,69.22) v3(173.05,77.91) v3(173.13,69.22) v3(173.85,69.18) v3(173.96,77.93) v3(178.41,69.81) v3(178.54,69.11) v3(178.92,72.49) v3(178.95,71.58) v3(179.19,69.8) v3(179.33,68.89) v3(179.69,72.13) v3(184.85,67.24) v4(26.7,182.4) v4(36.53,50.59) v4(36.53,49.57) v4(36.53,48.55) v4(36.69,21.16) v4(37.55,50.59) v4(37.55,49.57) v4(37.55,48.55) v4(38.34,29.21) v4(44.14,66.87) v4(44.39,70.94) v4(44.91,67.89) v4(45.03,66.97) v4(45.48,20.49) v4(45.52,19.61) v4(45.72,68.81) v4(45.76,21.29) v4(45.92,67.89) v4(45.92,66.97) v4(46.52,69.3) v4(46.49,20.49) v4(46.53,19.61) v4(46.54,18.72) v4(46.81,67.38) v4(46.78,53.97) v4(46.78,52.95) v4(47.03,21.29) v4(47.8,53.97) v4(47.8,52.95) v4(47.89,21.94) v4(48.81,53.97) v4(48.81,52.95) v4(51.9,69.65) v4(51.99,68.72) v4(52,31.22) v4(51.98,30.15) v4(52.15,67.89) v4(52.15,66.87) v4(52.54,28.14) v4(52.59,29.24) v4(52.85,69.66) v4(52.88,68.75) v4(53.03,67.89) v4(53.03,66.87) v4(54.3,65.6) v4(55.13,29.75) v4(56.1,29.5) v4(74.4,70.92) v4(75.28,71.66) v4(81.64,180.66) v4(81.64,179.58) v4(81.65,178.48) v4(81.85,165.68) v4(81.84,164.62) v4(82.73,180.72) v4(82.72,178.53) v4(82.78,179.66) v4(83.8,180.7) v4(83.85,178.52) v4(83.86,179.63) v4(83.96,175.97) v4(84.87,180.7) v4(85,178.51) v4(85.07,175.95) v4(85.99,180.7) v4(86.14,175.95) v4(91.51,177.32) v4(92.01,176.15) v4(92.37,172.92) v4(93.44,172.95) v4(96.93,116.95) v4(96.93,116.04) v4(96.93,115.1) v4(96.93,114.18) v4(96.93,113.19) v4(96.93,112.28) v4(97.57,183.31) v4(97.77,116.92) v4(97.77,116) v4(97.77,115.06) v4(97.77,114.15) v4(97.77,113.16) v4(97.77,112.24) v4(98.87,173.56) v4(105.69,175.49) v4(106.58,175.49) v4(109.72,114.06) v4(109.7,112.95) v4(109.8,116.3) v4(109.83,115.24) v4(112.13,110.52) v4(126.13,127.42) v4(126.17,126.35) v4(126.26,125.28) v4(126.5,169.29) v4(126.47,168.33) v4(126.8,170.16) v4(126.83,167.34) v4(127.36,168.84) v4(127.67,167.92) v4(127.82,170.03) v4(128.4,169.42) v4(128.4,168.48) v4(130.11,117.46) v4(130.11,116.4) v4(130.12,115.33) v4(130.14,114.26) v4(130.11,113.19) v4(130.58,23.65) v4(131.2,114.24) v4(131.22,113.17) v4(131.31,117.44) v4(131.29,116.38) v4(131.3,115.31) v4(131.65,23.69) v4(132.34,29.79) v4(132.42,116.34) v4(132.36,114.21) v4(132.47,117.4) v4(132.46,115.27) v4(132.93,169.5) v4(132.95,168.63) v4(136.01,131.66) v4(136.26,127.96) v4(136.29,126.9) v4(136.79,131.14) v4(136.9,132.06) v4(137.17,132.86) v4(137.22,130.33) v4(137.33,127.95) v4(137.35,126.84) v4(138.18,130.07) v4(141.05,114.32) v4(141.05,112.19) v4(141.04,32.94) v4(141.04,31.87) v4(141.03,30.69) v4(141.02,29.62) v4(141.06,113.25) v4(145.02,149.61) v4(144.99,148.65) v4(159.06,122.38) v4(159.9,122.4) v4(160.76,122.4) v4(163.63,89.24) v4(169.75,109.95) v4(169.72,109.07) v4(169.79,123.21) v4(169.84,122.32) v4(169.83,121.46) v4(169.87,107) v4(170.03,105.16) v4(170.16,106.08) v4(170.61,109.96) v4(170.61,109.07) v4(170.61,108.18) v4(170.72,106.96) v4(170.92,105.16) v4(171.05,106.08) v4(171.5,109.96) v4(171.5,109.07) v4(171.5,108.18) v4(171.61,106.96) v4(171.81,105.16) v4(171.94,106.08) v4(172.39,109.96) v4(172.39,109.07) v4(172.36,108.18) v4(172.5,106.96) v4(172.7,105.16) v4(172.83,106.08) v4(173.28,109.96) v4(173.28,109.07) v4(173.63,105.2) v4(173.77,106.1) v4(174.17,109.96) v4(174.17,109.07) v4(174.35,121.41) v4(174.35,119.53) v4(177.83,105.89) v4(177.86,109.64) v4(178.33,120.92) v4(178.33,120.08) v4(178.67,108.83) v4(178.67,107.81) v4(178.67,106.79) v4(178.67,105.86) v4(179.08,120.46) v4(179.08,119.61) v4(183.39,89.11) v4(184.12,44.65) v4(185.18,44.53) v4(185.43,124.67) v4(185.43,123.83) v4(193.35,169.57) v4(194.16,170.44) v4(194.19,169.57)
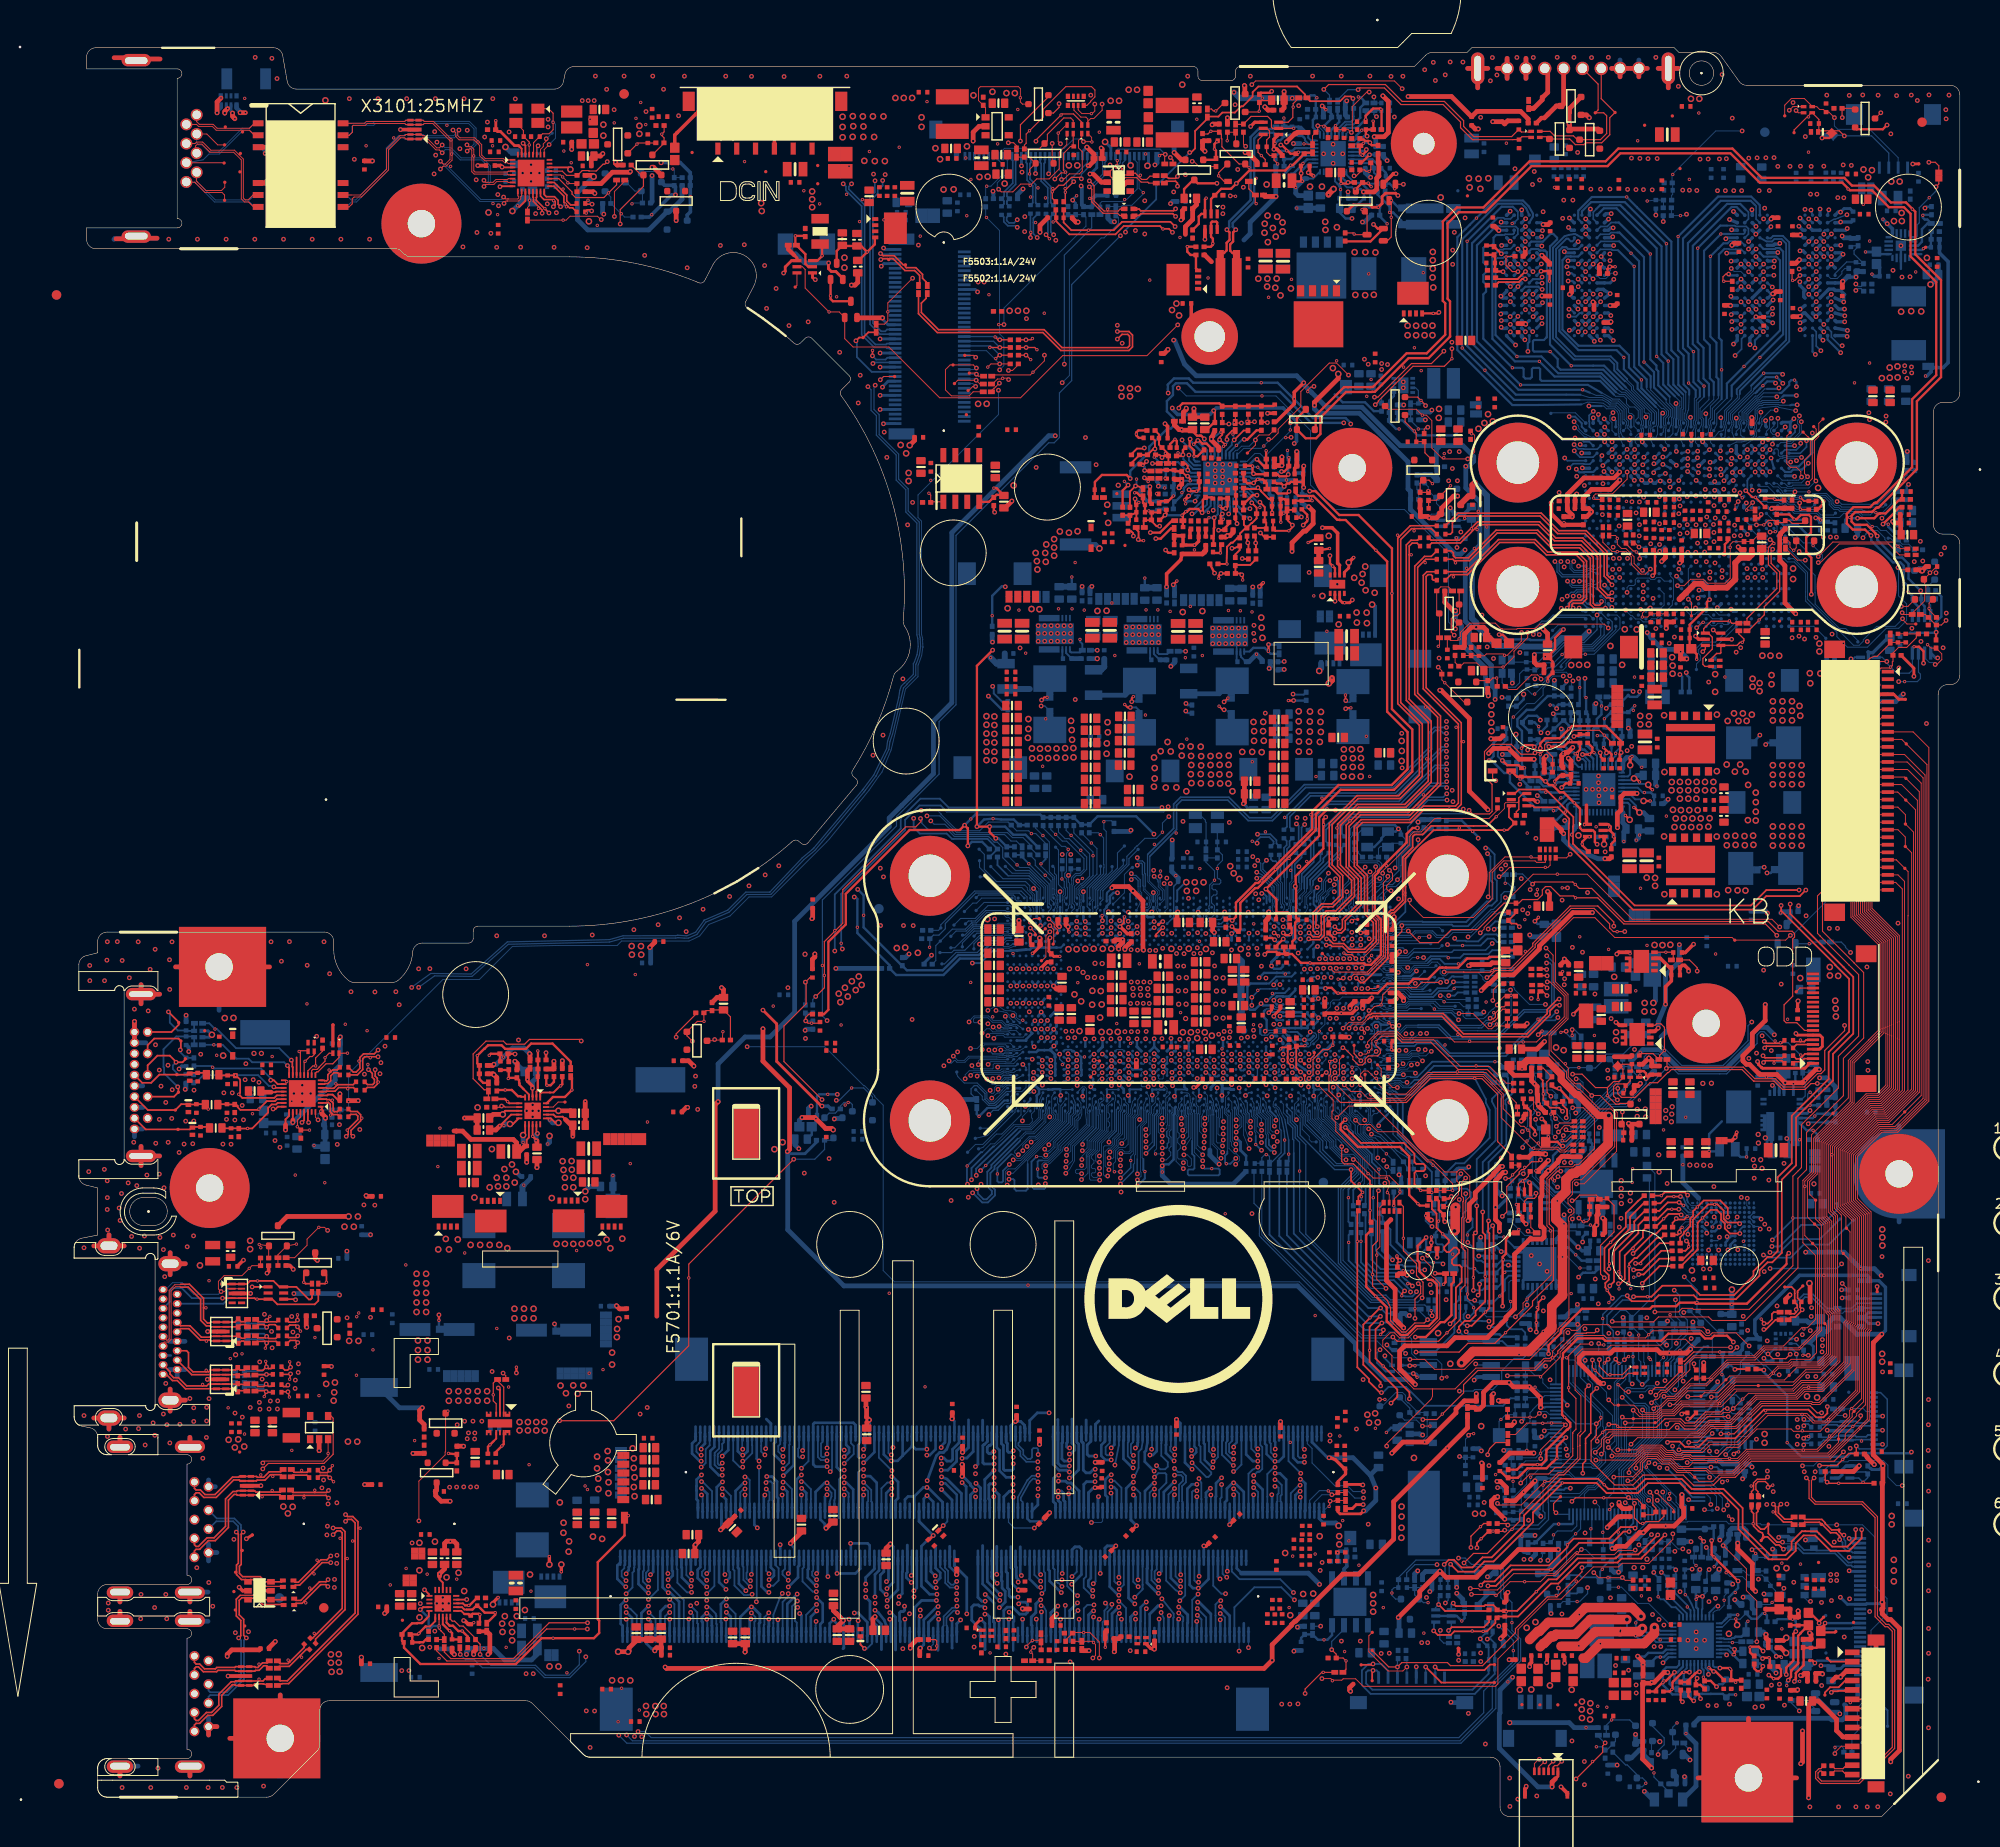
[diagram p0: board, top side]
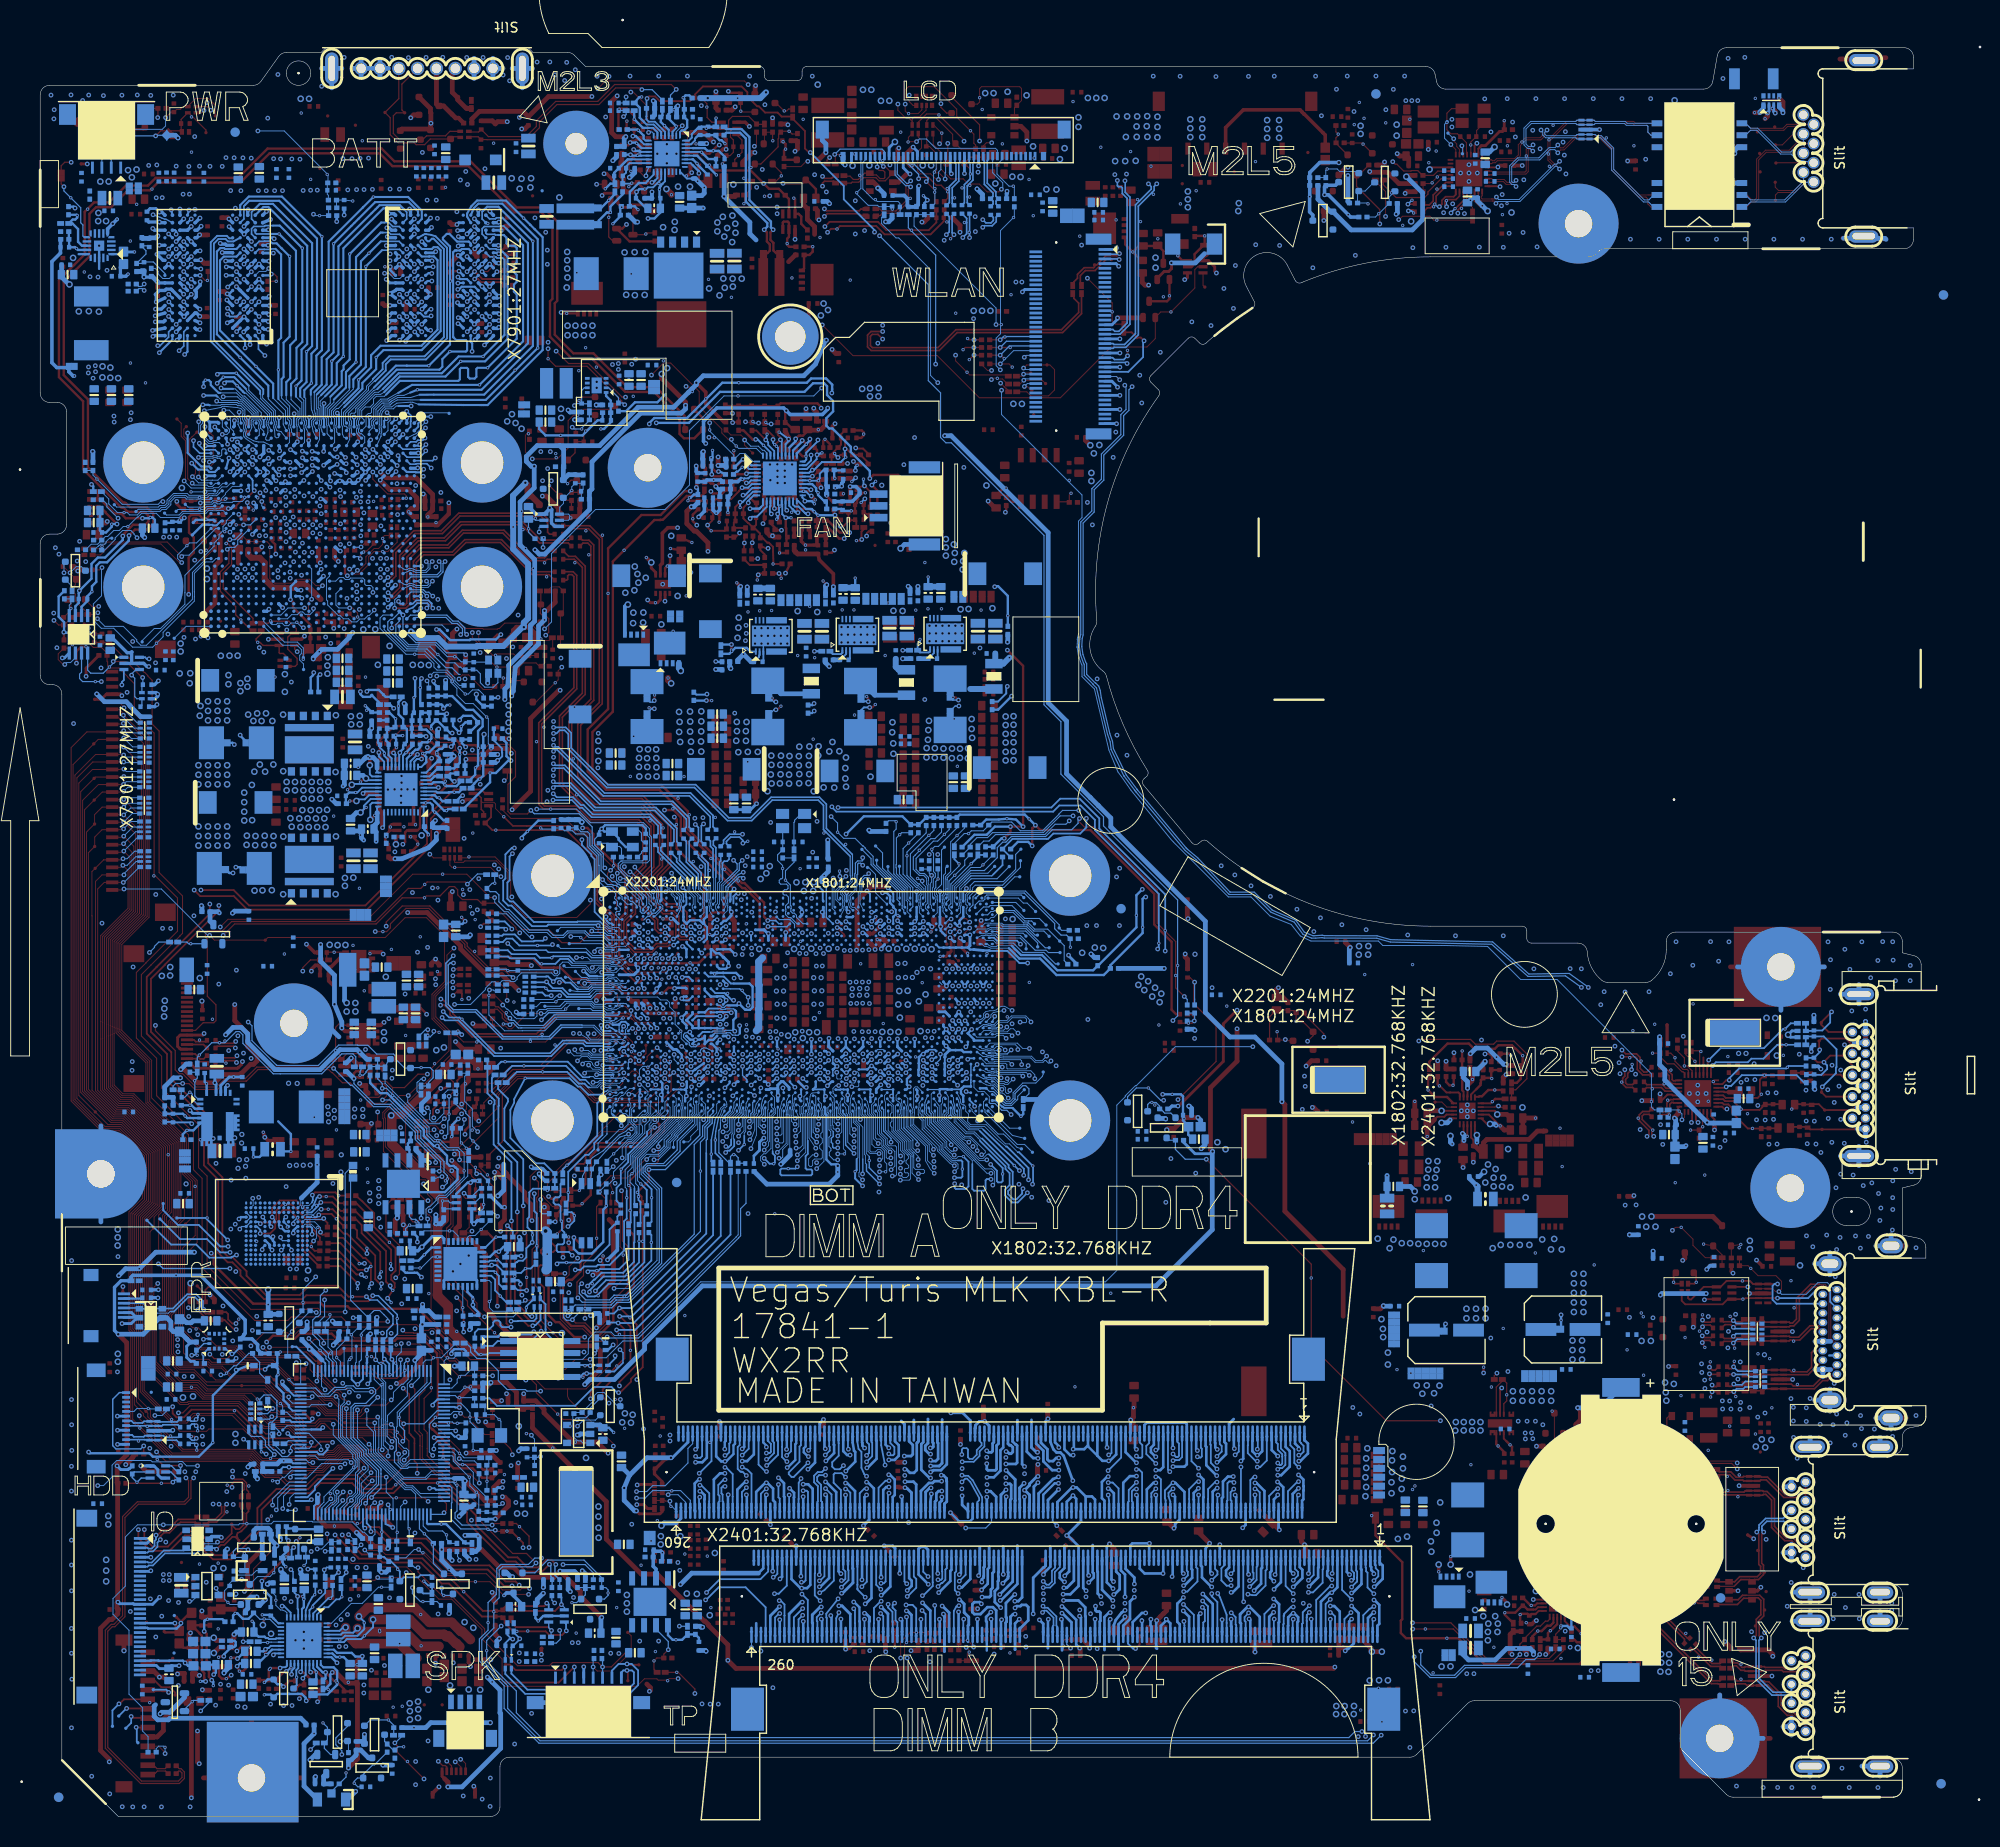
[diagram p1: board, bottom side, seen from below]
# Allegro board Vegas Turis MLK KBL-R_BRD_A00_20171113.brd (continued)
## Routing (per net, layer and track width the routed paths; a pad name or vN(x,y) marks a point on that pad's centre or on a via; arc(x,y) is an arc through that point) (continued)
V3D3_STB: length 2.4
  BOTTOM w0.102: 175.78,18.53 HDA27.16
  BOTTOM w0.127: 175.78,18.53 176.14,18.53 v2(176.19,18.48) 176.18,18.48 176.18,18.5 177.11,18.5 R2708.2
VCC_CORE: length 28.6
  TOP w0.508: v1(129.4,134.47) 129.4,135.38 130.64,136.62 130.85,136.62 131.65,137.42 131.65,138.73 v1(131.17,139.2)
  L4 w0.508: v1(129.4,134.47) 129.4,134.26 129.2,134.06 129.2,121.2 126.56,118.55 v1(126.56,117.27)
  BOTTOM w0.203: CPU1.A44 v1(114.66,98.2) ; CPU1.A39 117.2,97.35 117.2,98.43 117.99,99.21 118.07,99.21 v4(118.16,99.3)
  BOTTOM w0.508: PR4631.1 130.91,139.2 v1(131.17,139.2)
  vias: v1(114.7,100.56) v1(115.66,92.28) v1(116.09,99.74) v1(116.61,93.88) v1(117.13,91.72) v1(117.25,90.4) v1(117.48,92.3) v1(117.48,82.6) v1(117.92,91.7) v1(117.89,90.39) v1(118.4,97.59) v1(118.41,93.84) v1(118.97,91.71) v1(119.34,92.33) v1(119.39,83.47) v1(119.66,91.74) v1(120.24,93.84) v1(120.94,91.8) v1(121.61,83.14) v2(113.82,117.07) v2(117.56,85.45) v2(118.22,114.51) v2(119.61,100.74) v2(119.57,93.02) v2(125.18,112.1) v3(117.3,87.76) v3(117.38,89.16) v3(117.36,86.34) v3(118.09,87.76) v3(118.14,86.34) v3(118.09,84.81) v3(118.17,89.16) v4(114.74,112.55) v4(114.73,109.45) v4(114.81,111.44) v4(114.81,110.33) v4(115.44,113.22) v4(115.98,109.35) v4(116.17,114.2) v4(116.51,113.2) v4(116.58,92.22) v4(117.11,109.38) v4(117.64,113.75) v4(117.68,112.76) v4(117.8,83.35) v4(118.17,108.97) v4(118.22,98.38) v4(118.43,92.24) v4(118.63,113.73) v4(118.65,110.79) v4(118.67,112.72) v4(118.69,111.76) v4(118.72,109.84) v4(118.65,83.35) v4(119.06,99.3) v4(119.21,98.38) v4(119.32,82.73) v4(119.7,113.7) v4(119.74,112.69) v4(119.74,111.71) v4(119.7,110.79) v4(119.71,109.81) v4(120,99.29) v4(120.13,83.35) v4(120.25,92.2) v4(120.74,112.71) v4(120.74,111.76) v4(120.78,110.73) v4(120.78,109.78) v4(120.88,82.99) v4(121.64,112.75) v4(121.71,111.77) v4(121.69,110.77) v4(121.76,109.8) v4(122.64,109.79) v4(122.68,112.76) v4(122.66,111.77) v4(122.72,110.75) v4(122.83,101.01) v4(123.07,108.97) v4(123.2,100.26) v4(123.81,99.65) v4(124.11,113.15) v4(125.16,113.15) v4(125.3,116.33) v4(125.37,115.36) v4(125.36,114.33) v4(126.18,113.12) v4(126.34,116.34) v4(126.32,115.36) v4(126.4,114.33)
VCC_SENSE: length 65.6
  TOP w0.254: R710.2 122.89,95.38 v1(123.04,95.23) 123.44,95.62 123.44,97.13 123.72,97.41 125.53,99.21 125.81,99.21 131.54,104.95 131.54,106.83 134.34,109.63 139.99,109.63 141.67,111.31 141.67,115.26 139.51,117.43 139.51,133.39 v2(138.31,134.58) 135.1,137.8 134.47,137.8 134.45,137.82 134.2,137.82 131.66,140.36 130.08,140.36 129.78,140.67 PR4665.1
  BOTTOM w0.152: CPU1.E32 121.87,94.89 122.21,95.23 v1(123.04,95.23)
VCCDSW_EN#: length 11.3
  TOP w0.102: v2(144.05,41.49) v1(143.26,41.49)
  L4 w0.102: v1(147.2,38.26) 143.96,41.49 v1(143.26,41.49)
  BOTTOM w0.102: v1(143.26,41.49) 142.62,42.13 141.4,42.13 141.37,42.11 D2101.2 ; R2120.2 147.83,37.32 R2411.1 ; R2411.1 147.5,38.17 147.41,38.26 v1(147.2,38.26) ; R2411.1 C2125.1
VCCDSW_ON: length 25.4
  TOP w0.102: v1(148.16,40.52) 148.33,40.69 v2(148.69,40.69)
  L4 w0.102: v1(148.16,40.52) 147.68,40.05 147.68,39.63 147.67,39.62 147.67,38.09 147.68,38.08 147.68,34.88 149.81,32.75 150.58,32.75 150.98,32.34 156.71,32.34 157.25,31.81 159,31.81 160.36,33.17 160.98,33.43 v1(161.58,33.43)
  BOTTOM w0.102: v1(148.16,40.52) 148.16,40.43 147.83,40.11 R2411.2 ; KBC24.88 162.06,32.95 v1(161.58,33.43)
VCCGT_SENSE: length 89.8
  TOP w0.254: PR4667.1 116.54,136.91 115.46,135.82 v1(114.92,135.82)
  L3 w0.254: v1(83.25,98.54) 83.25,100.22 88.23,105.2 91.26,105.2 92.46,106.4 92.46,108.66 95.81,112.01 95.81,117.41 96.93,118.53 97.5,118.53 98.21,119.23 98.21,127.81 97.85,128.17 97.85,132.87 103.73,138.74 112.96,138.74 114.92,136.78 v1(114.92,135.82)
  BOTTOM w0.089: 97.12,92.55 98.65,92.55 98.73,92.47 99.3,92.47 99.54,92.58 99.69,92.73 CPU1.J70
  BOTTOM w0.254: 97.12,92.55 96.14,91.57 93.91,91.57 92.29,89.94 88.48,89.94 R712.2 87.84,90.58 87.81,90.58 83.88,94.51 v2(83.88,95.79) 83.88,97.92 v1(83.25,98.54)
VCCK_12: length 13.2
  TOP w0.203: U5601.25 22.84,74.47 22.46,74.09 22.46,73.51 ; 28.24,76.08 C5620.1 28.1,76.08 27.46,76.72 26.96,76.72 26.88,76.64 U5601.4
  TOP w0.508: 22.46,73.51 v1(22.46,72.97) ; 28.24,76.08 v1(28.24,76.81)
  L4 w0.508: v1(22.46,72.97) 22.46,74.18 23.35,75.07 25.81,75.07 27.55,76.81 v1(28.24,76.81)
  vias: v2(23.71,73.31)
VCCRTCEXT: length 17.8
  TOP w0.254: v1(135.05,74.06) 134.56,73.57 134.56,73.03 136.42,71.17 140.85,71.17 141.85,70.17 141.85,66.05 v2(142.77,65.13) 142.97,64.93 C2112.1
  BOTTOM w0.089: v1(135.05,74.06) 135.05,74.18 134.48,74.76 134.48,75.05 134.25,75.28 CPU1.BB10
VCCSA_SENSE: length 90.6
  TOP w0.254: v1(113.72,142.28) 113.85,142.15 114.33,142.15 PR4601.2 ; v1(128.47,93.26) 127.69,92.49 R716.1
  L3 w0.254: v1(128.47,93.26) 128.48,93.26 129.04,93.83 129.04,100.99 132.04,103.99 132.04,106.45 133.84,108.25 136.49,108.25 139.87,111.63 139.87,133.46 133.21,140.11 133.21,145.41 131.02,147.61 126.95,147.61 126.79,147.45 114.11,147.45 112.61,145.94 112.61,143.39 v1(113.72,142.28)
  BOTTOM w0.254: CPU1.H20 128.79,92.94 v1(128.47,93.26) ; v2(114.11,141.89) v1(113.72,142.28)
VCCSTG_EN_R: length 7.8
  TOP w0.127: U4002.4 167.97,84.1 168.12,84.25 168.59,84.25 168.97,83.87 v2(168.97,81.41) 168.45,80.89 168.45,80.54 R4034.2 167.74,81.09 166.5,81.09 C4017.1
VCCSTU_EN_R: length 2.9
  TOP w0.127: R4024.2 169.9,91.23 C4018.1 169.87,91.86 v2(169.12,91.86) U4006.4
VDD: length 29.3
  TOP w0.508: PR4402.1 138.54,175.85 PR4401.1 138.63,174.36 138.62,174.36 138.4,174.14 138.4,172.96 138.11,172.67 v1(136.99,172.67) ; PR4451.1 129.95,179 129.81,178.86 129.69,178.86 v1(128.81,177.98)
  L3 w0.254: v1(128.81,177.98) 128.81,177.47 128.98,177.31 130.64,177.31 132.51,179.17 134.56,179.17 136.27,177.47 136.27,176.15 137.19,175.23 137.19,173.1 136.99,172.9 v1(136.99,172.67)
  BOTTOM w0.203: PU4401.19 134.37,174.02 135.23,173.16 135.79,173.16 135.97,172.98 v2(136.1,172.98)
  BOTTOM w0.254: PR4438.1 135.97,170.93 PC4446.1 137.05,172.61 v1(136.99,172.67) 136.68,172.98 v2(136.1,172.98)
VDD10: length 7
  TOP w0.203: v1(47.7,177.85) 47.95,177.6 LOM31.30 ; v4(52.73,175.06) 52.51,175.28 LOM31.22 ; LOM31.8 45.29,173.28 v1(45.24,173.23) ; v1(45.47,175.31) 45.5,175.28 LOM31.3
  TOP w0.406: C3112.1 45.31,175.47 v1(45.47,175.31)
  vias: v1(53.98,182.38) v1(54.62,182.38) v1(55.25,182.38) v2(44.46,177.57) v2(52.46,173.64) v2(54.82,180.39)
VDD_DAC_33: length 2.5
  TOP w0.203: U5601.20 21.45,77.04 21.39,76.98 20.93,76.98
  TOP w0.508: C5628.1 19.96,76.98 20.93,76.98
  vias: v1(19.64,78.03) v2(18.95,74.69)
VDDREG:
  vias: v2(52.81,175.77)
VSS_AY71: length 4.8
  BOTTOM w0.203: 97.02,75.29 97.05,75.31 97.93,75.31 98.06,75.45 98.16,75.45 98.81,76.1 CPU1.AY71
  BOTTOM w0.254: R602.1 95.9,74.66 v2(96.15,74.41) 97.02,75.29
VSS_MECH1: length 4.2
  BOTTOM w0.102: GPU1.A32 159.51,149.19 156.96,149.19 TP7701.1
VSS_MECH2: length 4.4
  BOTTOM w0.102: GPU1.AM1 184.84,126.5 TP7702.1
VSS_MECH3: length 3.8
  BOTTOM w0.102: TP7703.1 157.66,126.64 160.46,126.64 GPU1.AM32
VSS_SENSE: length 72.5
  TOP w0.254: v1(129.09,140.84) 129.09,140.83 128.88,140.62 127.88,140.62 127.58,140.92 PR4666.1 ; v1(123.02,94.59) 123.53,94.08 R711.2 123.91,94.29 123.91,97.11 125.48,98.68 125.76,98.68 131.93,104.85 131.93,106.5 134.55,109.12 140.23,109.12 142.18,111.07 142.18,115.54 140.01,117.71 v2(140.01,130) 140.01,134.78 136.46,138.33 134.42,138.33 131.88,140.87 v1(131.27,140.87)
  L4 w0.254: v1(129.09,140.84) 130.02,141.77 130.85,141.77 131.27,141.34 v1(131.27,140.87)
  BOTTOM w0.152: CPU1.E33 121.01,94.57 123,94.57 v1(123.02,94.59)
VSSGT_SENSE: length 90.9
  TOP w0.254: v1(114.35,136.46) 115.38,136.46 116.65,137.73 PR4668.1
  L3 w0.254: v1(82.89,97.73) 83.16,97.73 83.76,98.33 83.76,100.01 88.4,104.65 91.6,104.65 93,106.05 93,108.48 96.32,111.8 96.32,117.2 97.14,118.02 97.75,118.02 98.72,118.98 98.72,128.02 98.36,128.38 98.36,132.66 103.94,138.23 112.58,138.23 v1(114.35,136.46)
  BOTTOM w0.089: CPU1.J69 100.28,92.73 100.02,92.47 99.78,92.47 99.34,92.29 97.42,92.29
  BOTTOM w0.254: v1(82.89,97.73) 83.01,97.73 83.22,97.53 v2(83.22,94.52) 83.22,93.9 86.64,90.47 R713.2 87.35,89.44 92.36,89.44 94.11,91.19 96.32,91.19 97.42,92.29
VSSSA_SENSE: length 87.5
  TOP w0.254: R717.1 127.29,93.37 127.48,93.19 v1(127.55,93.19) ; v1(113.74,143.06) 113.79,143.01 PR4602.2
  L3 w0.254: v1(127.55,93.19) 127.97,93.6 127.97,95 127.96,95.01 127.96,100.4 131.69,104.13 131.69,106.82 133.66,108.79 136.31,108.79 139.26,111.74 139.26,133.35 132.71,139.9 132.71,144.57 130.18,147.1 127.37,147.1 127.21,146.94 114.32,146.94 113.2,145.81 113.2,143.6 v1(113.74,143.06)
  BOTTOM w0.254: v1(113.74,143.06) 113.74,143.42 v2(113.55,143.61) ; CPU1.H21 127.8,92.94 v1(127.55,93.19)
0D6V_S0: length 124.2
  L3 w1.016: v4(36.68,26.16) 35.7,25.18 35.7,20.75 36.28,20.17 37.54,20.17 37.95,20.58 39.08,20.58 40.62,19.05 43.79,19.05 45.11,17.73 47.68,17.73 48.93,18.98 54.57,18.98 57.06,16.49 61.87,16.49 62.15,16.77 70.73,16.77 72.86,14.63 102.7,14.63 105.39,17.32 106.19,17.32 107.56,15.95 124.05,15.95 129.21,21.11 v4(129.21,21.39) 128.66,21.94 128.66,24.31 131.53,27.18 131.53,27.19 133.42,29.08 133.42,30.2 133.42,30.2 134,30.78 134.22,30.78 v4(134.34,30.9)
  BOTTOM w0.279: DM2.258 124.27,20.54
  BOTTOM w0.305: 132.78,31.19 132.75,31.19 132.27,31.67 DM1.258
  BOTTOM w0.508: v4(134.34,30.9) 134.05,31.19 132.78,31.19
  vias: v2(35.27,26.36) v2(129.09,22.2) v2(134.78,31.45)
0D95V_VGA_EN: length 4.2
  TOP w0.127: PR8603.1 143.44,147.46 143.64,147.66 v1(143.82,147.66)
  BOTTOM w0.127: PR8621.1 141.99,148.45 PR8625.2 142,148.38 142.82,147.57 v2(142.82,147.47) 143.64,147.47 v1(143.82,147.66)
0D95V_VGA_EN_R: length 6.4
  TOP w0.127: v1(143.59,149.96) 143.59,150.02 v2(143.1,150.5) 142.74,150.86 141.4,150.86 D8601.2
  BOTTOM w0.127: PC8607.1 142.82,151.56 142.53,151.85 PU8601.7 ; PC8607.1 142.8,150.15 PR8621.2 ; PC8607.1 143.38,150.18 143.59,149.98 v1(143.59,149.96)
0D95V_VGA_S0: length 44.2
  TOP w0.508: v1(171.34,123.04) 170.68,123.04 C8012.1 170.68,123.94 R7705.1
  L4 w0.508: v1(167.14,125.83) 167.14,126.11 165.7,127.56 165.7,134.62 165.68,134.64 165.68,134.65 165.65,134.67 165.65,135.18 165.7,135.22 165.7,135.52 v1(166.29,136.11) ; v1(166.31,139.72) 166.36,139.72 166.49,139.59 167.23,139.59 168.98,137.84 170.82,137.84 171.72,138.73 173.93,138.73 173.94,138.72 176.2,138.72 178.41,136.52 178.41,135.19 179.54,134.06 180.74,134.06 182.02,135.34 186.86,135.34 187.24,135.72 v1(187.24,135.97)
  BOTTOM w0.508: v1(171.34,123.04) 171.34,123.16 v2(170.7,123.8) 170.44,124.06 168.76,124.06 167.52,125.3 167.52,125.45 v1(167.14,125.83)
  vias: v1(165.51,139.74) v1(165.96,138.56) v1(166.33,140.84) v1(166.31,137.31) v1(166.76,140.22) v2(148.47,146.97) v2(164.93,139.78) v4(149.21,147.5) v4(149.84,148.11) v4(150.22,149.05) v4(150.73,148.29)
0D95V_VGA_S0_PG: length 86.1
  TOP w0.127: PG8655.1 198.12,175.45 197.75,175.82 v1(197.06,175.82) ; v1(138.25,150.06) 138.56,150.37 138.56,150.46 142.25,154.14 145.59,154.14 v2(146.39,154.94) v1(146.39,156.01)
  L3 w0.127: v1(146.39,156.01) 146.64,156.26 146.65,156.27 146.88,156.51 146.88,156.88 146.81,156.95 146.81,157.48 146.32,157.96 146.32,163.58 147.41,164.67 147.41,167.83 150.96,171.38 155.6,171.38 155.61,171.38 155.64,171.38 158.22,173.96 168.2,173.96 171.21,176.98 174.15,176.98 176.93,179.76 191.96,179.76 192.17,179.97 192.43,180.23 193.1,180.23 197.24,176.09 197.02,175.87 v1(197.06,175.82)
  BOTTOM w0.127: PU8601.2 139.95,151.85 138.91,150.82 PR8624.2 138.42,150.23 v1(138.25,150.06)
1D0V_S5: length 74.4
  L2 w0.508: v1(155.21,29.88) 156.46,31.13 156.46,32.2 157.78,33.52 157.78,51.39 159.7,53.31 162.07,53.31 162.56,53.8 166.42,53.8 173.06,60.44 173.06,60.5 173.46,60.9 176.82,60.9 177.61,61.7 177.61,64.29 180.78,67.46 180.78,69.79 181.16,70.17 181.16,75.99 177.94,79.22 v1(177.94,80.58)
  BOTTOM w0.508: 168.01,88.73 168.01,86.7 v4(167.79,86.48) ; R2402.1 154.06,28.16 153.7,28.51 153.7,29.67 v2(153.83,29.8) 153.91,29.88 v1(155.21,29.88)
  vias: v2(165.92,87.76) v2(166.31,76.15) v3(166.08,75.15) v3(166.07,74.41) v3(166.93,75.19) v3(166.97,74.35) v4(166.86,86.46) v4(166.86,85.56) v4(167.79,85.56)
1D0V_S5_PWRGD: length 23.2
  BOTTOM w0.127: R4029.1 166.82,79.83 166.82,80.75 167.13,81.05 168.31,81.05 170.43,78.94 174.84,78.94 175.58,78.94 175.61,78.97 178.81,82.17 178.81,83.07 179.16,83.42 179.54,83.42 180.72,82.24 v2(181.29,82.24) 182.12,82.24 183.66,80.7 PR5305.1
1D2V_S3: length 428.3
  TOP w0.305: C1218.1 112.43,30.46 v1(112.88,30.91) ; C1215.1 110.19,28.27 v1(110.68,28.76) ; v1(91.28,29.86) 90.84,29.42 PC1061.1 ; v1(126.64,81.03) 126.67,81 EC8908.1 ; v1(96.33,20.96) 95.74,20.38 C1214.1 95.99,19.79 RN1301.1 ; PC1056.1 126.42,77.99 v1(126.64,77.78) ; v1(118.96,77.49) 119.17,77.49 119.92,78.23 C718.1
  TOP w0.356: RN1201.1 114.35,17.89 114.69,17.75 v1(114.77,17.79)
  TOP w0.381: C1316.1 123.2,31.44 v1(122.77,31.01) ; v1(120.02,28.76) 120.28,28.76 C1319.1 ; C1322.1 109.1,34.95 v1(108.47,34.95)
  TOP w0.508: C1318.1 117.13,42.18 v1(117.12,42.19) ; v1(104.38,21.51) 103.89,21.03 C1221.1 ; C1321.1 100.35,24.06 v1(100.33,24.07) ; v1(88.84,17.89) 88.84,18.1 89.54,18.8 R1312.1 ; v1(94.34,36.15) 94.39,36.2 C1219.1 94.39,37.37 v1(94.34,37.42) ; v1(112.86,80.38) 112.86,80.38 EC8904.1 ; v1(94.39,38.71) 94.39,38.72 C1216.1 ; 82.38,19.94 81.08,19.94 81.08,20.2 v1(81.72,20.83) 81.35,21.2 81.35,21.23 80.97,21.6 80.95,21.6 80.68,21.87 C1305.1 ; EC8912.1 93.3,42.29 v1(93.28,42.27) ; EC8901.1 v1(108.49,37.64) ; C1307.1 65.95,28.81 v1(66.02,28.88) 66.35,29.22 C1309.1 ; v1(114.77,17.79) 114.77,17.96 114.79,17.97 C1217.1 ; v1(68.69,30.46) 69.4,31.17 PC1062.1 70.19,31.89 C1317.1 ; C1220.1 v1(128.18,41.96) ; PC1059.1 EC8915.1 ; EC8915.1 62.36,17.96 C1205.1 61.09,18.85 C1203.1 PC1058.1 59.72,18.67 58.96,17.91 58.96,17.62 v4(58.85,17.51) v4(57.8,17.51) ; EC8915.1 61.9,17.93 61.69,17.73 v1(61.69,17.61) ; EC8913.1 89.85,17.83 v1(89.91,17.89) ; v1(77.34,74.29) 78.69,74.29 v2(78.82,74.17) 79.85,73.13 EC8911.1 80.5,73.13 v3(80.65,72.98) ; EC8902.1 122.98,77.83 v1(122.99,77.81) ; v1(85.09,21.23) 84.87,21.01 C1206.1 ; v1(93.76,25.71) 93.78,25.73 C1320.1 ; C1208.1 C1204.1 71.31,17.51 v1(71.27,17.48) ; EC8903.1 100.13,42.12 v1(100.01,41.99) ; v1(103.64,32.29) 103.13,31.78 R1215.1 ; v1(86.73,28.97) 86.27,28.5 C1209.1 ; EC8914.1 v1(102.57,39.55) ; v1(100.76,22.08) 100.79,22.05 PC1060.1 ; 77.27,30.36 77.27,30.2 v1(76.11,29.03) ; C1202.1 80.55,31.29 v1(79.89,30.63) ; C1304.1 84.13,43.51 v2(84.19,43.45) 84.19,42.44 v1(84.49,42.14) 84.23,41.89 PC1063.1
  L2 w0.762: v1(88.84,17.89) 88.84,18.11 88.34,18.61 72.41,18.61 v1(71.27,17.48) 67.73,17.48 65.04,20.17 57.03,20.17 55.28,21.93 55.28,25.59 57.3,27.61 57.3,33.11 58.23,34.04 v4(59.54,34.04)
  L3 w0.102: 115.96,78.04 115.96,78.04 115.96,77.38
  L4 w0.127: v1(126.64,81.03) 126.21,81.46 125.24,81.46 ; 125.24,81.46 125.24,81.15 125.25,81.14 ; 125.24,81.46 124.35,81.46 ; 123.16,81.5 123.2,81.46 124.35,81.46 ; 124.35,81.46 124.35,81.2
  L4 w0.305: 120.78,78.01 120.78,75.87 v1(122.12,73.86) ; v1(127.69,74) 127.69,74.73 125.92,76.51 125.92,77.68 125.97,77.73
  L4 w0.508: v1(77.34,74.29) 77.67,73.96 77.67,70.1 76.94,69.37 73.25,65.42 73.25,63.46 69.21,59.42 63.79,53.62 63.79,49.15 62.92,48.29 62.92,42.71 v4(59.34,39.13)
  L4 w1.016: 128.41,76.04 128.98,75.47 128.98,73.69 129.96,72.71 130.79,72.71 133.87,69.64 133.87,69.27 135.27,67.87 135.64,67.87 137.86,65.65 137.86,49.18 137.86,49.18 137.86,44.62 135.32,42.07 135.32,36.18 134.23,35.09 133.26,35.09 132.74,34.57 132.74,34.35 129.4,31.01 v1(122.77,31.01)
  BOTTOM w0.089: v1(122.12,73.86) 122.02,74.33 CPU1.BB32
  BOTTOM w0.127: CPU1.BB47 113.36,75.29 113.36,74.22 v1(113.2,74.07) ; v1(109.95,71.67) 109.95,72.07 110.73,72.85 110.73,75.13 CPU1.BB51
  BOTTOM w0.203: v1(127.69,74) 127.69,74.38 127.07,75 127.07,75.29 CPU1.BB23
  BOTTOM w0.254: CPU1.AU42 116.27,78.1 v1(116.71,77.67) ; CPU1.AU23 126.31,78.1 v1(126.64,77.78) ; v1(93.28,42.27) 93.52,42.02 DM1.111 ; CPU1.AU35 119.17,77.49 v1(118.96,77.49) ; DM1.142 101.27,31.65 101.56,31.37 102.75,31.37 102.75,31.4 v1(103.64,32.29) ; 99.77,17.63 DM2.160 ; CPU1.BB41 116.93,75.3 116.93,74.68 116.82,74.56 116.82,69.83 116.31,69.32 115.77,69.32 v1(115.61,69.15) ; CPU1.AU28 123.28,78.1 v1(122.99,77.81) ; DM1.112 93.77,34.2 92.57,35.41 v1(92.16,35.41) ; v1(76.11,29.03) 76.52,28.48 ; v1(126.64,81.03) CPU1.AL23
  BOTTOM w0.279: v1(66.02,28.88) 66.02,28.88 DM2.33 ; v1(100.33,24.07) 99.67,24.73 99.67,26.29 99.53,26.44 DM2.159 ; DM2.153 v1(98.02,25.73) ; 93.29,17.89 93.27,17.91 DM2.142 93.27,20.93 v1(93.24,20.96) ; DM2.241 v1(120.02,28.76) ; 106.02,42.24 106.02,42.23 DM1.153 ; v1(91.67,23.62) 90.89,23.62 90.02,24.49 DM2.129 90.02,28.73 91.16,29.86 v1(91.28,29.86) ; DM2.147 96.53,24.71 98.28,22.96 v1(98.35,22.96) ; v1(86.66,21.66) 86.8,21.66 87.27,21.19 DM2.118 ; v1(89.91,17.89) 90.27,18.26 DM2.130 90.27,20.9 91.69,22.31 v1(91.79,22.31) ; DM2.112 85.77,20.43 85.09,21.12 v1(85.09,21.23) ; DM2.123 88.52,25.95 88.41,25.84 88.41,25.39 88.93,24.88 v1(88.95,24.88) ; DM2.148 96.77,20.52 v1(96.33,20.96) ; v1(85.09,23.34) 85.09,25.72 85.52,26.15 DM2.111 ; DM2.220 v1(114.77,17.79) ; DM2.178 104.27,20.74 104.27,20.74 104.27,21.18 104.27,21.19 104.27,21.41 v1(104.38,21.51) ; DM2.160 99.77,20.68 99.85,20.76 99.85,21.21 v1(99.34,21.72) ; DM1.54 79.27,31.58 79.76,31.09 ; v1(86.36,24.22) 87.02,24.88 DM2.117 87.02,28.67 v1(86.73,28.97) ; v1(61.69,17.61) 61.49,17.81 61.37,17.81 60.78,18.41 DM2.12 ; DM2.96 81.78,20.77 v1(81.72,20.83) ; DM2.54 v1(71.27,17.48) ; DM1.147 104.52,42.17 104.51,42.18 ; v1(88.84,17.89) 88.77,17.96 DM2.124 ; v1(91.85,20.96) 91.77,20.88 DM2.136 ; v1(93.76,25.71) 93.76,25.81 93.02,26.54 DM2.141 ; DM2.163 100.53,25.72 v1(100.64,25.61) ; v1(91.51,24.94) 91.61,24.94 92.02,25.35 92.02,25.91 91.52,26.4 DM2.135 ; v1(99.75,36.04) 99.03,36.04 98.32,36.75 98.32,38.92 98.02,39.22 DM1.129 ; v1(98.2,20.91) 98.27,20.84 DM2.154 ; 95.02,42.16 DM1.117
  BOTTOM w0.305: v1(117.12,42.19) 117.52,41.79 DM1.199 ; 96.52,42.12 DM1.123 ; DM1.159 107.52,42.14 ; v1(79.89,30.63) 79.76,30.76 79.76,31.09 ; v1(97.74,34.72) 98.27,34.18 DM1.130 ; 108.87,42.03 108.52,41.69 DM1.163 ; DM1.135 99.52,41.53 99.98,41.99 v1(100.01,41.99) 100.57,41.99 100.97,41.58 100.97,41.3 101.02,41.25 DM1.141 ; DM1.153 106.02,39.68 106.31,39.4 106.31,38.95 105.87,38.52 v1(105.75,38.52) ; v1(99.78,33.94) 99.78,33.89 99.77,33.88 DM1.136 ; DM1.124 96.77,33.56 96.76,33.58 96.76,35.81 v1(97.73,36.78) ; 98.02,28.71 DM2.153 ; DM1.12 68.77,30.55 v1(68.69,30.46) ; DM1.148 104.77,33.36 104.55,33.58 v1(104.55,33.95) ; 76.52,28.48 DM2.75 ; v1(112.88,30.91) 112.27,31.51 DM1.178 ; DM2.96 81.78,17.91 81.69,17.83 ; 73.55,42.23 74.02,41.75 DM1.33 ; v1(128.18,41.96) 128.02,41.81 DM1.241 ; v1(105.75,37.25) 104.83,37.25 104.52,37.55 DM1.147 ; v1(94.39,38.71) 94.51,38.71 95.02,39.22 DM1.117 ; 88.52,28.84 DM2.123 ; v1(110.68,28.76) 109.76,28.76 109.53,28.52 DM2.199 ; DM1.160 107.77,34.41 108.19,34.82 108.37,34.95 v1(108.47,34.95) ; 91.52,28.76 DM2.135 ; DM1.154 106.27,34.48 105.84,34.92 v1(105.7,34.92) ; DM1.118 95.23,32.54 95.23,34.17 95.73,34.67 v1(95.77,34.67) 95.23,35.21 95.23,35.35 94.44,36.15 v1(94.34,36.15) ; 91.77,17.66 DM2.136 ; DM2.178 104.27,17.54 104.28,17.54 ; 99.53,28.67 DM2.159 ; DM2.148 96.77,17.74 96.77,17.74 ; 85.77,17.74 DM2.112 ; DM2.154 98.27,17.84 98.28,17.84 ; DM1.96 89.77,31.37 v1(91.28,29.86) ; 87.27,17.7 DM2.118 ; DM1.220 122.77,31.02 v1(122.77,31.01) ; v1(84.49,42.14) 84.49,41.79 84.52,41.75 DM1.75 ; 100.53,28.66 DM2.163 ; 96.53,28.79 DM2.147 ; 93.02,28.71 DM2.141
  BOTTOM w0.508: R705.1 77.05,74 v1(77.34,74.29) ; v1(115.61,69.15) v2(115.61,68.5) 115.61,68.12 116.52,67.21 123.15,67.21 R505.1
  vias: v1(35.91,29.07) v1(37.79,17.99) v1(84.11,24.03) v1(85.1,22.66) v1(86.37,22.3) v1(87.59,22.63) v1(88.75,21.54) v1(89.24,23.34) v1(89.9,21.95) v1(92.16,37.47) v1(93.76,23.67) v1(93.76,23.01) v1(95.77,36.43) v1(97.75,38.15) v1(97.75,36.02) v1(99.78,38.18) v1(99.75,35.28) v1(102.39,36.98) v1(102.42,34.83) v1(105.39,69.63) v1(107.04,69.19) v1(108.49,36.25) v1(108.94,68.9) v1(109.99,69.37) v1(111.17,69.16) v1(111.23,66.37) v1(112.94,81.05) v1(113.88,71.74) v1(115.6,71.69) v2(38.77,16.79) v2(58.88,31.98) v4(36.68,29.09) v4(36.98,17.91) v4(59.47,38.06) v4(59.46,37.05) v4(59.54,36.04) v4(59.47,35.01)
1D8V_EN#: length 3.3
  BOTTOM w0.127: v2(161.74,7.41) 162.32,7.41 R2736.2 162.84,7.06 R2738.1 163.76,7.98 Q2705.D
1D8V_EN_R#: length 6.2
  BOTTOM w0.127: C2738.2 166.6,3.15 v2(166.99,3.53) 166.99,3.74 166.64,4.09 Q2704.G 166.03,4.46 165.02,5.48 164.84,5.48 R2738.2
1D8V_PWR:
  vias: v2(165.59,68.84)
1D8V_S0: length 19.2
  TOP w0.508: v1(167.6,5.16) 166.64,6.11 166.64,14.12 R2719.1 167.52,14.16 v2(167.62,14.26) 167.88,14.26 168.93,15.31 v1(169.31,15.31)
  BOTTOM w0.254: R2709.1 170.06,13.55 169.52,14.09 169.52,15.11 v1(169.31,15.31)
  BOTTOM w0.508: Q2704.D 165.46,6.23 166.3,7.06 C2736.1 166.78,6.52 167.28,6.03 167.58,5.91 R6401.1 v1(167.6,5.16)
1D8V_S5: length 374.2
  TOP w0.508: v1(146.99,140.34) 146.57,140.34 145.3,139.07 145.3,138.57 PQ8607.S 144.76,138.03 v2(143.97,138.03) 143.82,138.18 PC8635.1 143.03,139 PC8634.1 143,139.87 PR8650.1
  TOP w0.762: 162.99,74.31 163.05,74.37 163.05,74.51 ; 163.05,74.51 v4(163.05,74.51) ; 163.05,74.51 163.05,74.51 161.96,74.51 159.73,76.73 159.56,76.73 158,78.3 158,78.85 156.49,80.36 154.39,80.36 R1139.1
  TOP w1.016: 162.99,74.31 162.99,71.48 160.21,68.7 159.89,68.64 159.88,68.63 159.76,68.61 159.51,68.36 159.16,68.36 158.5,67.7 158.5,66.41 157.42,65.33 157.42,63.49 158.14,62.78 v2(158.14,59.47) 158.14,55.48 158.13,55.35 157.02,54.24 156.99,54.2 156.99,52.15 156.99,52.14 156.99,51.86 154.55,49.42 148.61,49.42 v4(147.4,48.21)
  L2 w0.203: v1(146.99,140.34) 146.47,140.34 145.09,141.72 145.09,145.84 147.74,148.49 147.74,168.22 143.18,172.77 137.77,172.77 137.19,172.19 135.07,172.19 134.67,172.59 134.67,173.31 133.82,174.15 129.43,174.15 127.95,172.67 123.1,172.67 123.04,172.73 121.51,172.73 118.51,169.74 118.51,169.23 116.72,167.44 110.5,167.44 106.13,171.8 v1(106.09,171.8)
  L2 w1.016: v4(159.83,104.28) 160.35,103.75 160.35,101.42 165.43,96.34 171.43,96.34 172.61,95.16 176.72,91.06 180.04,91.06 183.52,87.58 183.55,87.58 185.1,86.03 185.1,82.51 186.14,80.97 187.12,79.99 187.12,61.86 181.25,56 176.14,56 ; 176.14,56 v4(176.14,56) ; 176.14,56 174.56,54.42 174.56,52.09 174.5,52.04 174.5,51.21 174.23,50.94 174.23,49.63 175.46,48.41 175.46,46.71 177.27,44.9 v1(177.27,35.88)
  L3 w0.508: v1(154.44,113.35) 154.44,113.87 154.9,114.33 154.9,118.34 155.3,118.74 155.3,119.82 154.58,120.54 154.58,122.74 154.49,122.82 154.49,124.14 153.15,125.48 153.15,126.1 153.89,126.84 155,126.84 157.21,129.05 157.21,132.35 155,134.56 152.77,134.56 v1(146.99,140.34)
  L3 w1.016: 147.05,41.49 147,41.54 147,43.77 148.07,44.84 148.07,45.58 147.4,46.25 v4(147.4,48.21) ; 147.05,41.49 v4(149.5,41.49) ; 147.05,41.49 147.05,39.66 148.09,38.62 148.09,37.89 147.85,37.65 147.85,31.48 151.7,27.64 151.7,26.6 153.22,25.07 153.22,21.66 152.45,20.89 152.45,17.91 151.58,17.03 151.58,14.08 158.52,7.14 159.16,7.14 v1(160.46,5.84)
  L4 w0.508: v4(159.83,104.28) 159.83,105.51 158.81,106.52 158.81,109.5 156.92,111.39 155.19,111.39 154.44,112.15 v1(154.44,113.35)
  L4 w1.016: v4(149.5,41.49) 149.5,40.12 148.62,39.24 148.62,38.49 148.64,38.47 148.64,37.23 149.46,36.4 150.71,36.4 150.87,36.56 158.56,36.56 160.08,35.05 164.45,35.05 164.7,34.79 166.24,34.79 166.83,35.38 173.06,35.38 173.79,34.66 176.05,34.66 v1(177.27,35.88)
  BOTTOM w0.254: R5521.1 106.41,171.48 v1(106.09,171.8) 106.09,171.85 v2(106.51,172.26)
  BOTTOM w0.508: R2462.1 177.49,36.16 177.27,35.94 v1(177.27,35.88) ; Q6301.G 174.99,53.37 R6311.1 v2(176.12,54.41) 176.12,55.99 v4(176.14,56)
  vias: v2(161.32,5.84)
1D8V_S5_KBC: length 6
  BOTTOM w0.203: 173.77,37.8 173.51,37.53 KBC24.54
  BOTTOM w0.508: R2410.1 R2462.2 176.7,36.75 C2423.1 175.16,37.47 174.84,37.8 v2(174.47,37.8) 173.77,37.8
1D8V_VGA_EN: length 6.5
  TOP w0.127: PQ8608.G 143.52,144.94 143.52,146.05 PR8603.2 142.62,146.13 PC8612.1 142.59,146.12 142.59,147.06 v2(142.39,147.26) 141.41,148.24 141.41,148.95 D8601.1
1D8V_VGA_EN#: length 3.5
  TOP w0.127: v2(144.32,141.66) 143.95,142.04 PQ8608.D 143.01,141.71 PR8650.2 PR8651.1
1D8V_VGA_EN_R#: length 3.9
  TOP w0.127: v2(146.24,141.45) 145.18,140.39 PQ8607.G 144.73,139.9 143.92,139.9 PR8651.2 143.91,139.87 PC8634.2
1D8V_VGA_S0: length 114
  TOP w0.381: 169.17,126.95 R7932.1 169.16,126.95 ; 169.92,126.95 C8008.1
  TOP w0.508: v1(169.16,126.29) 169.16,126.29 169.16,126.95 ; R7930.1 178.25,134.64 178.25,134.63 ; R7928.1 147.6,124.27 R7926.1 147.72,124.38 147.72,125.24 147.72,125.24 147.72,125.67 147.81,125.77 148.45,126.41 v1(148.96,126.41) 149.74,126.41 150.08,126.07 C8002.1 150.43,125.31 151.04,124.7 R7704.1 ; v1(159.22,113.63) 158.71,113.11 158.5,113.11 158.29,112.91 v2(158.19,112.91) 158.04,112.76 158.04,111.66 PR8546.1 ; v1(168.67,133.4) 169.07,133.8 C7904.1 ; 169.17,126.95 169.92,126.95
  TOP w0.635: 178.25,134.63 178.25,134.12 177.92,133.79 177.02,133.79 176.49,133.26 176.49,131.5 175.61,130.61 174.38,130.61 174.35,130.58 173.36,130.58 172.91,131.02 172.21,131.02 171.23,130.05 171.23,130.05 170.83,129.65 170.83,129.65 170.57,129.39 ; PQ8607.D 147.32,139.5 148.14,140.33 148.55,140.33 PC8636.1 148.57,141.52 v1(148.8,141.76)
  L3 w0.635: v1(159.22,113.63) 160.05,114.45 160.05,115.08 158.7,116.44 156.94,116.44 156.46,116.92 156.46,117.5 156.56,117.6 156.56,121.57 v1(160.96,125.97) 161.1,125.97 161.85,125.22 166.8,125.22 166.86,125.16 168.03,125.16 v1(169.16,126.29) ; v1(170.26,131.83) 168.69,133.4 v1(168.67,133.4)
  L4 w0.635: v1(195.51,133.38) 195.28,133.61 187.35,133.61 184.49,130.75 173.41,130.75 173.05,131.1 171.7,131.1 170.98,131.83 v1(170.26,131.83)
  BOTTOM w0.356: GPU1.AD17 170.79,131.3 v1(170.26,131.83)
  BOTTOM w0.635: 148.96,126.46 149.07,126.46 151.12,124.41 153.93,124.41 154,124.34 157.17,124.34 158.07,125.25 160.24,125.25 v1(160.96,125.97) ; 148.96,126.46 v1(148.96,126.41) ; 148.96,126.46 148.96,126.9 148.51,127.35 148.51,133.13 150.1,134.71 v2(150.1,137.06) 150.12,137.08 150.12,140.39 148.8,141.71 v1(148.8,141.76)
1D35V_VGA_S0: length 129.8
  TOP w0.254: v1(151.63,166.1) 150.88,166.85 R8105.1 150.73,166.98 C8101.1
  TOP w0.457: v1(156.93,139.63) 156.93,138.46 158.1,137.29 R7810.1 R7817.1
  TOP w0.508: 194.03,137.5 C8042.1 193.39,137.48 v1(193.23,137.64) ; 194.03,137.5 194.03,137.48 194.07,137.45 194.07,136.29 C8001.1 ; 194.03,137.5 194.03,138.36 C8014.1
  L4 w0.114: v1(183.9,170.82) 182.48,172.24 157.75,172.24 v1(156.08,170.57)
  L4 w0.508: v1(156.93,139.63) 161.68,139.63 163.35,141.3 164.45,141.3 165.16,142.01 v1(165.77,142.01)
  BOTTOM w0.114: 183.9,170.81 v1(183.9,170.82)
  BOTTOM w0.254: v1(151.63,166.1) 151.74,166.2 VRAM1.F14
  BOTTOM w0.305: v1(176.14,158.06) 176.56,158.06 VRAM2.B1 ; v1(175.58,166.17) 176.67,166.17 VRAM2.M1 ; VRAM2.P1 175.64,167.8 175.53,167.7 v1(175.49,167.7) ; VRAM1.B12 v1(154.22,169.82) ; v1(172.48,144.41) 172.17,144.1 GPU1.H16 ; GPU1.K24 165.4,142.38 v1(165.77,142.01) ; GPU1.L20 168.75,141.95 v1(168.52,141.95) 168.25,141.95 GPU1.L21 ; VRAM1.T12 v1(154.2,157.8) ; v1(177.91,167.4) 178.3,167.79 VRAM2.P3 ; GPU1.J24 165.4,143.27 v1(165.79,142.87) ; GPU1.H13 174.24,143.94 173.82,143.94 v1(173.81,143.93) ; v1(165.79,142.87) 166.2,143.28 GPU1.J23 ; v1(165.79,142.87) 166.17,142.5 GPU1.K23 166.2,142.39 v1(166.56,142.04) ; GPU1.J9 177.4,143.3 v1(177,142.9) GPU1.K9 ; R7802.1 v1(168.84,169.52)
  BOTTOM w0.356: VRAM2.T3 178.67,169.03 178.67,169 v1(178.7,169) ; v1(181.22,167.21) 181.14,167.12 180.68,167.12 180.55,167 VRAM2.N5 ; VRAM1.L2 161.92,162.32 162.48,162.32 VRAM1.L1 v1(163.2,161.86) VRAM1.M1 ; VRAM1.B1 v1(163.02,169.78) 162.98,169.78 ; VRAM1.F12 153.4,166.6 v1(153.4,166.6) ; VRAM1.K12 v1(153.4,162.61) VRAM1.L13 ; VRAM1.F1 v1(162.24,165.8) VRAM1.G1 ; VRAM2.D1 176.25,159.8 176.06,159.61 v1(176.06,159.63) ; v1(159.8,167.39) 159.79,167.39 VRAM1.E5 ; GPU1.J10 176.56,143.3 176.19,142.93 v1(176.19,142.85) 176.54,142.5 GPU1.K10 ; VRAM1.D11 v1(154.21,168.21) ; VRAM2.C10 v1(183.37,158.76) ; VRAM1.H3 v1(161.4,165) VRAM1.G2 ; GPU1.L21 167.84,141.7 167.53,142.01 v1(167.49,142.01) 167.47,142.01 167.15,141.7 GPU1.L22 166.89,141.7 v1(166.56,142.04) ; VRAM2.P11 184.7,167.8 v1(184.3,167.4) 183.9,167 VRAM2.N10 ; VRAM2.H12 v1(185.08,162.59) VRAM2.G11 ; VRAM1.T3 v1(161.4,158.6) ; VRAM2.D14 v1(188.13,159.5) ; v1(155.94,166.92) 155.86,167 VRAM1.E10 ; v1(183.25,169.02) 183.68,168.6 VRAM2.R10 ; VRAM2.L11 184.69,165.4 v1(184.3,165.79) ; VRAM2.M14 187.79,166.2 v1(187.94,166.04) 187.3,165.4 VRAM2.L14 ; v1(155,165.8) 154.6,165.4 VRAM1.G11 ; VRAM1.G13 153,165.4 v1(153.4,165) 153.8,164.6 VRAM1.H12 ; VRAM1.L11 v1(154.2,161.8) VRAM1.M12 ; VRAM1.M14 151.77,161.4 v1(151.59,161.59) 151.68,161.59 152.2,162.11 VRAM1.L14 ; VRAM1.N10 155.75,160.6 156.05,160.9 v1(156.01,160.9) ; v1(151.63,165.1) 151.9,165.1 VRAM1.G14 ; GPU1.L12 174.49,141.7 v1(174.3,141.89) 174.11,141.7 GPU1.L13 ; VRAM2.G1 176.71,162.2 v1(177.1,162.6) 177.5,162.2 VRAM2.G2 ; VRAM1.D1 163.37,167.8 v1(163.47,167.91) ; VRAM1.D3 v1(160.6,168.2) ; VRAM2.M12 185.9,165.8 v1(185.9,165.79) ; GPU1.L11 176.1,142 v1(176.28,142) ; VRAM1.T1 163.02,158.2 v1(163.34,157.87) ; VRAM2.D12 185.45,159.8 v1(185.07,159.42) 184.7,159.79 VRAM2.D11 ; VRAM1.R5 v1(159.8,158.6) ; v1(152.58,167.42) 152.57,167.42 152.57,167.43 VRAM1.D14 ; v1(178.69,165.8) 179.09,165.4 VRAM2.L4 ; VRAM2.F1 176.2,161.4 v1(176.03,161.57) ; VRAM2.L1 176.63,165.33 176.06,165.33 v1(176.05,165.31) ; VRAM1.R10 155.71,159.31 v1(155.94,159.31) ; VRAM1.T14 152.16,158.16 151.75,158.16 v1(151.62,158.29) ; VRAM1.B3 v1(160.6,169.8) ; VRAM2.M3 178.3,166.2 v1(178.7,166.6) ; VRAM2.R5 v1(180.28,168.98) ; VRAM1.P3 160.96,159.8 v1(160.57,159.41) ; VRAM1.C5 159.07,168.6 v1(158.78,168.9) ; VRAM2.B3 178.31,158.2 v1(178.73,157.78) 178.73,157.78 178.73,157.78 ; v1(151.62,169.47) 151.68,169.4 VRAM1.B14 ; VRAM1.N5 v1(159.78,160.22) ; VRAM1.F3 v1(161.39,165.8) ; v1(163.27,159.53) 163,159.8 VRAM1.P1 ; VRAM2.F14 v1(188.02,160.98) 188.02,161.68 188.11,161.77 187.68,162.2 VRAM2.G14 186.96,162.34 186.44,162.34 VRAM2.G13 VRAM2.F12 ; v1(180.51,161.19) 180.48,161.19 180.48,161.16 179.92,160.6 VRAM2.E5 ; VRAM2.L2 177.5,165.4 v1(177.9,165) 178.3,164.6 VRAM2.K3 ; GPU1.H19 169.61,144.1 v1(170.23,143.62) ; VRAM2.F3 VRAM2.G4 v1(179.5,162.6) ; VRAM2.B14 v1(188.41,157.95) ; v1(185.1,169.8) 185.5,169.4 VRAM2.T12 ; VRAM2.H3 v1(178.69,163.38) ; VRAM2.D3 v1(177.92,160.18) ; VRAM2.T14 187.61,169.4 v1(187.69,169.48) 188.82,169.48 C8107.1 ; VRAM2.E10 v1(183.38,160.21) ; VRAM2.P12 v1(185.9,167.4) ; VRAM1.D12 v1(154.18,167.41) ; VRAM1.M3 v1(160.6,161) ; VRAM2.T1 175.89,169.74 v1(175.89,169.74) ; VRAM1.G4 v1(159.81,165.01) ; VRAM1.C10 v1(156,168.56) ; VRAM2.C5 v1(180.47,158.76) ; VRAM1.P14 151.68,159.8 v1(151.58,159.69) ; VRAM2.B12 v1(185.9,157.79)
  BOTTOM w0.508: v1(187.85,167.99) 188.05,167.79 188.71,167.79 C8102.1 189.47,167.73 R8106.1
  vias: v1(154.2,160.16) v1(158.15,169.86) v1(158.27,171.8) v1(159.24,171.8) v1(159.81,162.6) v1(161.15,172.97) v1(161.4,166.6) v1(162.18,172.97) v1(163.17,172.98) v1(163.17,166.08) v1(163.19,165.37) v1(165.05,172.94) v1(165.94,172.92) v1(166.74,172.91) v1(167.67,172.89) v1(170.91,172.86) v1(171.62,172.85) v1(172.41,172.83) v1(174.6,172.8) v1(175.44,172.8) v1(176.33,172.8) v1(177.17,172.8) v1(179.03,172.8) v1(179.5,169.8) v1(179.62,170.94) v1(180.11,172.82) v1(184.49,172.43) v1(185.17,172.43) v1(185.9,166.6) v1(187.39,172.06) v1(188.02,172.05) v1(194.49,154.2) v1(194.47,153.56) v1(194.73,152.87) v1(195.21,154.07) v1(195.24,153.43) v2(149.89,153.72) v2(152.79,169.32) v2(157.28,173.15) v2(171.61,174) v2(188.48,172.98) v2(189.16,152.38) v2(190.76,154.48) v4(185.29,141.21) v4(192.07,152.88) v4(192.9,154) v4(192.9,152.92) v4(193.73,154.13) v4(193.74,152.96)
2D5V_PWR:
  vias: v2(136.51,26.7)
2D5V_PWROK: length 99.5
  TOP w0.127: PR5158.1 v2(132.71,15.32) 132.56,15.32 130.79,13.55 v1(130.79,13.07) ; v1(41.03,17.22) 40.97,17.28 PR5128.1
  L3 w0.127: v1(54.36,16.97) 56.21,15.12 61.27,15.12 64.24,12.15 127.86,12.15 128.78,13.07 v1(130.79,13.07)
  BOTTOM w0.127: v1(54.36,16.97) 54.36,16.46 52.67,14.76 49.97,14.76 48.92,15.81 43.37,15.81 42.5,16.68 41.57,16.68 v1(41.03,17.22)
2D5V_S3:
  vias: v1(133.43,40.54) v1(133.43,39.91) v2(129.47,27.67) v2(131.86,27.89) v2(134.47,40.44) v2(135.44,29.29) v4(128.67,28) v4(134.41,29.79) v4(134.42,28.92)
3D3V_AUX_KBC_R: length 42.6
  TOP w0.305: DB3.1 157.65,4.27 157.39,4.02
  TOP w0.508: v1(151.18,35.61) 151.53,35.61 152.17,34.97 R2476.2 ; v1(157.03,3.14) 157.03,3.65 157.39,4.02
  L3 w0.508: v1(151.18,35.61) 151.48,35.61 151.87,35.22 151.87,33.03 151.33,32.48 151.33,30.13 152.84,28.62 152.84,27.07 154.36,25.54 154.36,21.19 153.6,20.42 153.6,15.57 152.83,14.8 v1(152.83,14.8)
  BOTTOM w0.508: v1(152.83,14.8) v2(152.33,14.3) 152.33,14.28 151.5,13.44 151.5,11.01 151.43,10.93 151.43,7.24 155.52,3.14 v1(157.03,3.14)
3D3V_AUX_S5: length 514.6
  TOP w0.254: v1(132.61,181.81) v2(133,181.41) ; v1(46.99,47.14) v2(46.99,47.75)
  TOP w0.305: R2609.1 195.47,122.05 v1(195.47,121.18)
  TOP w0.508: v1(48.39,81.08) 48.44,81.03 PR4505.2 ; R2453.1 151.46,44.13 151.46,44.2 v1(151.33,44.2) ; v1(44.6,79.95) 44.48,79.83 PR4501.1 ; v1(148.98,44.93) R2473.1 148.97,44.18 147.71,44.18 146.82,43.29 146.82,42.9 143.71,39.79 v2(143.49,39.79) 141.18,39.79 v1(140.01,38.62) ; v1(151.43,62.2) 151.43,63.01 151.01,63.43 v1(151.01,64.75) 151.01,67.56 151.45,68 151.45,68.08 151.82,68.45 151.9,68.45 152,68.45 152.03,68.48 v1(152.08,68.48) ; R1737.1 155.56,68.66 156.63,69.73 v1(156.62,69.73) ; R2503.1 v1(41.37,39.35)
  L2 w0.508: v1(151.43,62.2) 151.43,60.75 150.99,60.3 150.99,54.14 151.14,53.99 151.14,53.98 151.43,53.68 151.43,44.2 v1(151.33,44.2)
  L3 w0.508: v1(198.74,134.85) 199.09,134.5 199.09,131.66 198.35,130.92 196.63,130.92 196.6,130.94 195.8,130.94 195.4,130.55 195.4,129.81 195.94,129.28 195.94,125.51 195.23,124.8 195.23,124.8 195.23,121.43 v1(195.47,121.18) 195.61,121.05 195.61,70.44 196.48,69.57 196.48,61.24 192.73,57.49 v1(192.01,57.49) ; v1(46.99,47.14) 47.76,47.14 53.77,41.13 53.77,33.36 54.3,32.82 54.3,26.43 54.81,25.92 54.81,22.41 58.33,18.89 80.99,18.89 84.19,15.7 102,15.7 104.56,18.26 112.69,18.26 113.8,17.15 122.42,17.15 127.45,22.17 127.45,24.35 129.08,25.99 130.64,27.55 130.64,27.56 131.55,28.47 131.55,30.04 132.12,30.61 132.13,30.61 133.19,31.67 133.81,31.67 135.37,33.23 135.37,34.61 139.37,38.62 v1(140.01,38.62) ; v1(152.08,68.48) 152.77,69.17 155.52,69.17 155.53,69.16 156.06,69.16 156.62,69.72 v1(156.62,69.73) ; v1(158.31,63.95) 158.31,63.89 156,61.58 152.06,61.58 v1(151.43,62.2) ; v1(148.98,44.93) 149.78,44.13 151.46,44.13 151.46,44.2 v1(151.33,44.2) ; v1(176.17,180.51) 176.24,180.45 176.24,180.04 174,177.81 171.09,177.81 167.92,174.63 157.94,174.63 155.57,172.26 147.45,172.26 145.47,174.25 141.69,174.25 139.95,176 v1(139.5,176) 139.18,176.33 139.18,181 138.85,181.33 136.23,181.33 v1(135.21,182.35) 134.67,181.81 v1(132.61,181.81) ; v1(31.95,64.98) 31.95,67.29 v1(44.6,79.95)
  L4 w0.508: v1(198.74,134.85) 198.56,135.03 197.97,135.03 196.53,136.46 196.53,151.72 198.97,154.15 198.97,171.19 196.02,174.14 196.02,177.28 192.88,180.42 192.31,180.42 191.83,179.93 186.76,179.93 186.19,180.51 v1(176.17,180.51) ; v1(31.95,64.98) 34.4,62.52 34.4,49.64 36.22,47.82 44.03,47.82 44.14,47.93 46.34,47.93 46.99,47.28 v1(46.99,47.14) 46.99,45.97 45.1,44.08 45.1,41.65 42.8,39.35 v1(41.37,39.35) ; v1(156.62,69.73) 156.7,69.73 156.82,69.84 157.64,69.84 157.95,70.15 160.62,70.15 160.85,69.92 161.09,69.82 165.02,69.82 167.84,67 168.19,66.64 169.51,66.64 170.45,67.58 176.47,67.58 177.62,66.43 178.02,66.43 183.97,60.48 v1(183.97,59.97)
  BOTTOM w0.356: R1727.1 152.51,65.95 151.31,64.75 v1(151.01,64.75)
  BOTTOM w0.508: v1(158.31,63.95) 158.31,63 v2(158.3,62.99) 157.79,62.99 157.48,63.31 R1726.1 ; PR4435.1 132.73,181.68 v1(132.61,181.81) ; PR4449.1 135.07,180.85 PR4450.1 135.07,182.2 v1(135.21,182.35) ; v1(183.97,59.97) 188.07,59.97 v2(189.82,58.22) 191.27,58.22 v1(192.01,57.49) ; v1(48.39,81.08) 47.79,81.67 46.58,81.67 v2(45.62,80.71) 44.86,79.95 v1(44.6,79.95) ; PR4409.1 139.12,176.39 v1(139.5,176)
3D3V_CAMERA_S0: length 1.8
  BOTTOM w0.305: LCD1.32 110.15,177.38 v4(109.54,177.99)
  vias: v2(108.92,179.03)
3D3V_LAN_S5: length 6.3
  TOP w0.203: LOM31.11 47.95,171.72 47.29,171.07
  BOTTOM w0.508: v4(45.83,177.45) 46.36,176.91 C3111.1 ; C3109.1 48.18,172.05 47.63,172.05 C3103.1 47.63,171.71 v2(47.12,171.2) v4(46.56,170.64)
  vias: v2(44.99,170.26) v2(55.58,169.12) v2(57.39,180.01) v4(44.03,170.49) v4(54.69,169.55) v4(56.23,179.82) v4(56.23,178.66)
3D3V_PWR:
  vias: v2(44.91,51.87)
3D3V_PWR_2: length 5.3
  TOP w0.203: PU4503.3 48.7,76.51 v1(48.7,77.4)
  TOP w0.356: v1(48.7,77.4) 48.7,77.63 48.17,78.16 v2(48.17,78.33)
  TOP w0.508: v2(48.17,78.33) 48.17,79.26 PR4505.1
  BOTTOM w0.508: v1(48.7,77.4) 48.7,78.1 49.13,78.54 PC4526.1
3D3V_RTC_SYS: length 3
  TOP w0.254: D2501.1 39.47,37.59 R2505.1 40.66,37.6 R2503.2 v2(39.77,38.58)
3D3V_RUN_FFS: length 8.3
  L4 w0.508: v1(183.62,51.21) 183.62,51.01 183.64,50.98 183.64,50.46 183.62,50.43 183.62,49.47 183.62,48.88 183.23,48.5 182.6,48.5 182.59,48.49 182.07,48.49 182.06,48.5 181.62,48.5 v1(181.01,49.11)
  BOTTOM w0.508: C6703.1 184.11,52.68 184.3,52.48 184.8,52.48 185.18,52.86 R6701.2
  vias: v2(183.78,51.81)
3D3V_S0: length 983.5
  TOP w0.127: 145.15,26.04 v1(145.11,26.07)
  TOP w0.178: 152.4,95.25 152.4,95.2 152.71,94.9 153.23,94.9 v1(153.56,94.57) ; 152.4,95.25 153.19,96.04 R1606.2 ; 152.4,95.25 R1610.2
  TOP w0.203: U5601.14 23.64,80.67 ; U5601.26 23.24,74.02
  TOP w0.254: v1(155.21,72.5) 155.21,72.93 154.75,73.39 154.75,74.23 154.75,74.23 154.75,74.97 154.44,75.28 154.35,75.28 R2023.1 153.97,75.66 R2003.1 ; v1(197.84,125.87) 197.82,125.85 R2613.1
  TOP w0.305: v1(137.01,32.48) 136.69,32.17 134.5,32.17 134.26,32.41 R1208.1 ; 135.08,36.41 134.26,35.59 R1204.1
  TOP w0.356: v1(133.33,38.13) 133.51,38.13 134,37.92 134.94,36.98 C1328.1 135.08,36.91 135.08,36.41 ; RN5602.1 28.15,82.72 v1(28.28,82.86) ; v1(155.49,107.87) 155.3,107.87 155.09,108.08 Q1801.5
  TOP w0.381: v1(130.64,152.39) 129.63,151.38 v2(129.63,150.67) 129.63,150.15 127.72,148.24 PR4609.1 ; R2006.1 v1(144.8,59.43)
  TOP w0.508: v1(142.49,45.92) 140.83,47.58 140.83,49.48 141.38,50.02 145.85,50.02 146.72,50.89 150.15,50.89 152.12,52.87 152.12,53.05 153.04,53.97 153.04,59.74 154.75,61.45 154.83,61.37 155.96,61.37 156.18,61.59 156.18,62.47 155.96,62.69 155.83,62.69 155.83,62.82 155.81,62.84 155.81,65.81 155.95,65.96 155.95,67.28 155.95,67.89 156.41,68.35 156.41,68.43 156.62,68.63 v1(156.62,68.63) 156.7,68.63 157.55,69.49 157.58,69.49 157.7,69.61 157.7,69.78 158.07,70.15 158.78,70.15 158.81,70.12 160.05,70.12 ; v1(184.29,1.98) 184.29,11.86 C1201.1 185.32,12.27 187.26,10.33 187.26,9.12 187.93,8.45 DBG1.10 ; 23.24,74.02 v1(23.24,73.76) ; R3109.2 55.99,173.56 57.19,174.76 59.02,174.76 v1(59.09,174.84) ; v1(145.11,26.07) 142.97,23.93 142.97,23.43 v1(140.69,21.15) ; v4(29.16,63.77) 22.63,63.77 Q5703.C ; v1(157.69,28.37) 153.44,28.37 151.57,26.49 150.08,26.49 149,25.42 145.77,25.42 145.15,26.04 ; 192.11,22.78 192.18,22.71 192.18,22.13 FC9703.1 192.11,21.95 192.11,21.55 192.72,20.93 193.01,20.93 193.94,20 193.94,7.01 193.01,6.09 v1(193.01,5.81) ; 192.11,22.78 192.11,22.81 192.12,22.82 192.12,35.4 R6704.1 192.18,35.49 v1(192.18,37.26) 192.18,37.41 191.14,38.45 FC9702.1 191.14,41.95 191.16,41.97 191.16,50.36 v1(192.06,51.26) ; 192.11,22.78 v1(192.1,22.78) ; EC9738.1 89.29,146.26 v4(88.78,145.75) ; v1(73.18,83.72) 73.18,80.28 76.01,77.46 76.01,70.91 v1(75.78,70.68)
  L2 w0.381: v1(144.8,59.43) 144.8,58.56 145.17,58.18 145.17,52.58 144.24,51.65 144.24,47.68 v1(142.49,45.92)
  L2 w0.508: v1(178.5,67.84) 176.73,67.84 172.1,63.21 172.1,61.61 171.94,61.46 171.94,60.9 167.03,55.99 164.76,55.99 164.48,55.71 161.01,55.71 v1(159.72,54.43)
  L2 w1.524: 42.52,38.88 43.91,37.49 43.91,25.98 46.53,23.36 49.1,23.36 50.11,22.35 50.11,19.06 53.34,15.83 61.23,15.83 66.23,10.82 127.8,10.82 127.83,10.8 129.64,10.8 129.67,10.82 130.5,10.82 130.5,10.82 140.44,10.82 142.9,13.29 149.22,13.29 v3(152.53,9.97)
  L3 w0.254: v1(147.86,143.51) 153.13,138.24 156.47,138.24 156.54,138.18 156.54,138.18 158.12,136.59 166.49,136.59 167.02,136.06 167.02,135.07 168.15,133.95 168.16,133.95 168.18,133.95 168.19,133.95 170.81,133.95 170.87,133.89 171.83,133.89 171.83,133.89 171.88,133.89 171.89,133.89 172.96,133.89 172.98,133.89 172.99,133.89 174.37,133.89 175.14,133.12 175.16,133.11 175.16,133.1 175.58,132.68 175.58,130.47 176.61,129.44 176.61,124.69 v1(177.07,124.23) ; v1(159.72,54.43) 159.72,57.2 v1(159.84,57.32) 159.84,59.82 160.32,60.3 160.32,61.01 v1(160.28,61.06)
  L3 w0.356: v1(188.81,122.23) 188.35,121.77 188.35,119.77 v1(187.87,119.29)
  L3 w0.508: v1(193.01,5.81) 191.62,5.81 187.8,1.98 v1(184.29,1.98) ; v1(157.69,28.37) 158.33,27.72 158.33,23.71 158.07,23.45 v1(158.07,21.52) ; v1(163.3,84.81) 163.17,84.68 163.07,84.48 163.07,82.2 163.62,81.65 163.62,77.9 163.34,77.62 163.34,76.64 162.25,75.55 162.25,73.43 v1(162.05,73.23) ; v1(155.49,107.87) 155.2,107.87 153.6,109.48 153.6,109.71 ; v1(116.82,156.91) 116.82,157.06 101.01,172.87 100.81,172.87 v1(100.81,172.99) 100.81,173.03 100.49,173.35 100.49,173.96 97.54,176.9 97.54,179.65 99.75,181.86 ; v1(105.82,16.44) 107.2,15.06 124.86,15.06 129.07,19.28 130.03,19.28 132.38,21.63 132.38,24.6 v1(132.32,24.67) 133.94,24.67 136.63,27.36 ; v1(150.98,118.73) 151.33,118.38 151.33,115.81 151.32,115.81 151.32,115.06 151.2,114.93 151.2,113.23 151.11,113.14 151.11,111.98 152.71,110.38 152.79,110.38 153.46,109.72 153.6,109.72 153.6,109.71 ; v1(145.11,26.07) 144.51,25.47 138.52,25.47 136.63,27.36 ; 153.6,109.71 v1(153.6,109.71) ; v1(142.49,45.92) 142.49,44.68 142.51,44.65 142.51,39.74 138.3,35.52 v1(138.3,34.91) ; v1(137.01,32.48) 136.83,32.3 136.83,29.34 136.83,29.34 136.83,28.51 136.83,27.55 136.63,27.36 ; v1(25.77,82.92) 25.83,82.86 v1(28.28,82.86) 41.88,82.86 44.17,85.14 71.76,85.14 v1(73.18,83.72)
  L4 w0.254: v1(177.07,124.23) 177.43,124.59 177.43,124.97 179.56,127.1 185.78,127.1 186.29,126.6 187.16,126.6 187.7,126.05 187.7,124.88 189.29,123.29 189.29,122.71 v1(188.81,122.23) ; v1(156.62,68.63) 156.24,68.63 155.29,69.58 155.29,72.42 v1(155.21,72.5)
  L4 w0.381: v1(154.82,86.96) 154.82,85.06 156.78,83.1 158.52,82.37 160.87,82.37 v1(163.3,84.81)
  L4 w0.508: v1(158.07,21.52) 164.08,21.52 164.79,22.23 168.96,22.23 v1(170.62,23.89) 172.47,23.89 173.17,24.59 173.42,24.69 v1(176.22,24.69) 176.87,24.04 177.49,24.04 178.55,22.98 183.31,22.98 183.91,23.58 187.37,23.58 v1(187.66,23.3) ; 162.09,73.23 v1(162.05,73.23) ; 162.09,73.23 163.41,71.92 164.15,71.61 166.45,71.61 166.84,71.22 174.82,71.22 178.2,67.84 v1(178.5,67.84) ; 162.09,73.23 162.09,73.25 160.57,74.78 v1(159.55,74.78)
  BOTTOM w0.254: R9121.2 160.28,61.59 v1(160.28,61.06) ; 195.03,125.81 195.11,125.81 195.13,125.79 195.55,125.79 195.57,125.81 197.62,125.81 197.68,125.87 v1(197.84,125.87) 197.81,125.9 197.81,126.94 198.39,127.52 198.39,129.67 R2614.1 ; R9120.2 161.82,58.09 161.52,57.79 161.34,57.79 161.34,57.79 160.57,57.79 160.57,57.79 160.31,57.79 v1(159.84,57.32)
  BOTTOM w0.279: 124.04,25.86 123.52,26.37 DM2.255
  BOTTOM w0.305: 184.33,50.42 184.78,49.97 184.78,48.8 184.37,48.38 183.98,48.38 183.76,48.16 R1834.2 ; R6703.1 190.87,36.96 190.94,36.96 191.03,36.87 191.78,36.87 v1(192.18,37.26) ; v1(187.66,23.3) 188.41,22.55 IOBD1.15 190.4,22.55 190.46,22.61 191.91,22.61 192.11,22.81 192.11,22.78 v1(192.1,22.78) ; R506.1 78.87,71.67 77.65,70.45 76.01,70.45 75.82,70.64 ; v1(133.33,38.13) 133.18,38.13 131.52,39.78 DM1.255
  BOTTOM w0.356: 190.63,122.61 190.63,123.75 190.61,123.78 190.82,123.69 191.1,123.69 192.69,125.27 C2615.1 ; 190.63,122.61 190.69,122.56 Q7904.2 ; 190.63,122.61 190.58,122.56 Q7904.5 189.34,122.56 189.01,122.23 v1(188.81,122.23) ; R9202.1 191.76,56.94 192.45,56.25 192.45,51.65 v1(192.06,51.26) ; RN7903.1 188.14,118.8 187.87,119.07 v1(187.87,119.29) 188.03,119.45 RN7903.2
  BOTTOM w0.381: R2430.1 176.04,49.23 R2429.2 176.92,49.3 177.25,49.62 177.25,50.15 177.85,50.76 R1835.2 178.72,51.12 178.72,51.22 178.58,51.36 178.58,52.77 183.32,57.51 v2(185.91,57.51) 190.5,57.51 190.7,57.31 R9202.1
  BOTTOM w0.508: 137.75,36.25 137.75,36.33 138.5,37.08 C1329.1 ; 137.75,36.25 135.87,38.13 v1(133.33,38.13) ; 137.75,36.25 138.3,34.93 v1(138.3,34.91) 138.3,33.59 137.19,32.48 v1(137.01,32.48) ; v1(176.22,24.69) 176.13,24.69 176,24.82 R2716.1 ; v1(132.32,24.67) 131.13,25.86 124.04,25.86 ; R2489.1 157.71,28.39 v1(157.69,28.37) 157.69,27.25 156.23,25.79 Q2414.G ; R6702.1 184.45,50.42 184.75,50.72 184.75,50.74 R6701.1 186.2,51.53 186.47,51.81 186.47,52.58 186.9,53.01 ED9201.5 187.41,52.97 187.69,52.97 189.4,51.26 v1(192.06,51.26) ; v1(28.2,55.42) 28.05,55.58 v1(23.35,55.58) ; PR8619.1 143.47,142.59 PC8601.1 144.21,142.62 PQ8609.S 144.77,143.43 PR8601.1 144.74,145.29 145.15,145.7 ; R5529.2 100.23,172.41 v1(100.81,172.99) ; R4005.1 159.1,76.47 159.85,75.72 159.85,75.07 159.56,74.78 v1(159.55,74.78) ; v1(145.11,26.07) 145.07,26.03 143.58,26.03 143.27,25.72 R6520.1 ; R6517.1 140.77,21.07 v1(140.69,21.15) ; 145.15,145.7 147.55,145.7 148.7,144.56 148.7,144.03 148.18,143.51 v1(147.86,143.51) 147.86,141.21 149.36,139.71 149.36,135.15 147.81,133.6 147.81,127.04 148.26,126.59 148.26,124.66 150.57,122.35 150.57,122.31 150.57,121.41 150.68,120.14 150.98,119.84 v1(150.98,118.73) ; 145.15,145.7 140.91,145.7 136.83,149.79 133.05,149.79 131.46,151.37 130.64,152.19 v1(130.64,152.39) 129.89,153.13 119.22,153.13 117.97,154.38 116.94,156.87 v1(116.82,156.91) ; v3(152.53,9.97) 158.85,9.97 159.38,9.44 v2(160.64,9.44) R2737.1 ; v1(159.72,54.43) 159.72,54.02 159.75,54 R9145.1 159.08,53.75 158.41,53.08 R9150.1 ; v1(75.78,70.68) 75.82,70.64 75.82,62.37 81.79,56.39 130,56.39 136.13,50.26 136.13,49.66 139.35,46.45 141.96,46.45 v1(142.49,45.92) ; v1(28.28,82.86) 28.3,82.84 C5626.1 28.29,82.14 28.29,79.89 27.74,79.35 27.74,78.27 v1(23.24,73.76) 23.17,73.7 C5610.1 20.33,73.7
  vias: v1(41.76,40.15) v1(41.89,40.77) v1(42.57,40.76) v1(42.55,40.13) v2(26.63,67.36) v2(59.62,89.49) v2(87.66,177.42) v2(100.26,181.43) v2(154.19,91.95) v4(28.72,62.69) v4(29.72,62.68) v4(30.15,63.77) v4(59.24,92.51) v4(59.26,91.6) v4(60.23,92.51) v4(60.25,91.6) v4(87.26,182.66) v4(87.82,145.77) v4(88.15,182.66) v4(88.4,144.88) v4(89.03,182.66) v4(99.06,183.17) v4(99.95,183.17) v4(110.13,182.36) v4(111.02,182.36) v4(117.74,184.08)
3D3V_S5: length 298.9
  TOP w0.254: R1711.1 157.57,71.7 157.6,71.7 158.04,71.26 v1(158.17,71.26)
  TOP w0.305: v1(79.47,75.51) 79.39,75.51 74.65,80.25 74.65,84.24 v1(73.18,85.7)
  TOP w0.508: v1(183.45,5.61) 183.64,5.79 v1(183.64,9.08) ; R4101.1 157.15,105.74 158.02,104.87 158.02,104.71 v1(158.26,104.47) ; PR5111.1 42.65,17.69 42.45,17.49 v1(42.45,17.22) ; v4(134.31,153.32) 134.31,152.85 131.78,150.32 v1(131.78,149.99) ; v1(124.42,176.86) 124.69,176.86 125.69,175.86 PR4453.2 ; 139.9,63.43 139.89,63.43 139.44,62.98 139.44,56.97 140.35,56.05 140.35,52.84 140.72,52.47 140.73,52.47 141.26,51.94 v1(141.26,51.93) ; v1(162.65,101.79) 163.13,101.79 PR8539.1 ; PR4472.1 126.86,181.37 v1(126.51,181.71) ; v4(55.2,174.3) 55.2,174.3 55.07,174.43 R3103.1
  L2 w0.381: v1(141.26,51.93) 141.26,49.81 140.89,49.45 140.89,46.71 142.96,44.64 147.82,44.64 149.74,46.57 149.74,56.19 150.01,56.46 150.01,62.22 148.45,63.79 148.45,65.13 150.35,67.03 152.11,67.03 153.4,68.32 153.4,68.54 156.12,71.26 v1(158.17,71.26)
  L3 w0.508: v4(116.65,160.12) 115.5,161.27 115.5,174.03 116.81,175.34 118.41,175.34 118.46,175.29 119.35,175.29 120.8,176.74 120.8,177.54 123.35,180.09 v1(123.35,181.94) ; v4(193.11,31.05) 194.33,29.83 194.33,12.04 187.9,5.61 v1(183.45,5.61) ; v1(147.78,134.63) 147.78,128.51 147.73,128.46 147.73,126.04 148.29,125.48 148.29,121.68 149.05,120.92 149.05,112.6 150.59,111.07 151.11,111.07 155.01,107.16 155.56,107.16 v1(158.26,104.47)
  L4 w0.254: v1(169.25,67.28) 168.33,67.28 168.06,67.55 168.01,67.55 167.45,68.1 167.45,68.16 165.28,70.33 161.6,70.33 160.85,70.63 160.23,71.26 v1(158.17,71.26)
  L4 w0.381: v1(159.74,52.3) 159.74,52.37 160.1,52.73 162.1,52.73 162.56,53.19 164.42,53.19 v1(164.57,53.05)
  L4 w0.406: v1(126.51,181.71) 126.28,181.94 v1(123.35,181.94) 123.35,181.74 123.83,181.26 123.83,177.33 124.3,176.86 v1(124.42,176.86)
  BOTTOM w0.254: 196.26,166.06 PU8651.15 ; R4031.1 165.29,77.96 164.22,76.88 163.48,76.88 159.59,72.99 159.59,72.34 158.51,71.26 v1(158.17,71.26) 157.33,70.43 157.13,70.22 157.13,69.43 156.84,69.14 156.41,69.14 156.26,68.99 156.21,68.99 156.01,68.79 156.01,67.7 157.35,66.36 160,66.36 160.04,66.4 ; PR8624.1 138.09,149.37 137.15,150.31 134.78,150.31 133.93,151.15
  BOTTOM w0.305: R2443.1 151.73,34.95 v1(151.24,34.95)
  BOTTOM w0.356: R507.1 80.4,75.2 80.1,75.51 v1(79.47,75.51)
  BOTTOM w0.508: R9149.1 159.73,52.3 v1(159.74,52.3) ; v4(55.2,174.3) 53.48,172.57 53.48,169.72 54.57,168.63 61.06,168.63 PD4302.2 63.26,170.57 64.59,171.9 64.59,173.34 PR4304.1 ; v1(147.78,134.63) 147.32,134.17 146.73,134.17 141.98,138.92 141.98,139.99 PR8606.1 141.99,140.83 PC8603.1 141.72,141.1 141.72,143.98 136.55,149.15 132.24,149.15 131.78,149.61 v1(131.78,149.99) ; R2434.1 164.62,52.99 v1(164.57,53.05) ; v1(159.74,52.3) 159.85,52.19 R2446.1 ; v1(159.74,52.3) R9146.1 ; R6521.1 142.43,25.78 v1(142.75,26.11) ; v1(158.26,104.47) 158.26,103.8 159.09,102.96 161.91,101.79 v1(162.65,101.79)
  vias: v2(35.24,58.63) v2(39.71,43.08) v2(58.16,13.63) v2(60.73,179.83) v2(74.28,86.13) v2(103.08,159.78) v2(134.13,154.72) v2(139.1,22.2) v2(150.76,30.33) v2(165.54,67.39) v2(172.61,181.06) v2(179.71,43.13) v3(164.37,67.58) v3(164.37,66.74) v3(164.37,65.93) v3(164.39,65.15) v3(165.35,66.27) v3(165.32,65.43) v4(22.23,32.94) v4(22.71,32.21) v4(23.22,32.92) v4(36.38,57.68) v4(36.38,56.67) v4(36.38,55.65) v4(36.38,54.63) v4(36.38,53.62) v4(37.4,57.68) v4(37.4,56.67) v4(37.4,55.65) v4(37.4,54.63) v4(37.4,53.62) v4(39.81,45.2) v4(39.81,44.18) v4(40.83,45.2) v4(40.83,44.18) v4(41.85,45.2) v4(41.85,44.18) v4(42.87,75.36) v4(42.86,45.2) v4(42.86,44.18) v4(43.88,45.2) v4(43.88,44.18) v4(57.16,14.47) v4(58.1,14.48) v4(59.09,14.45) v4(60.06,179.7) v4(60.06,178.84) v4(73,171.48) v4(73.06,170.64) v4(99.39,160.04) v4(100.28,160.04) v4(101.17,160.04) v4(117.12,160.81) v4(117.4,159.54) v4(133.74,153.94) v4(138.02,23.54) v4(138.02,22.66) v4(138.02,21.77) v4(148.84,32.18) v4(149.68,32.2) v4(154.33,20.05) v4(155.26,20.66) v4(171.78,182.57) v4(171.89,58.04) v4(172.67,182.57) v4(179.61,40.65) v4(179.61,39.71) v4(193.07,173.77) v4(193.11,31.94) v4(193.96,173.77) v4(196.86,165.66)
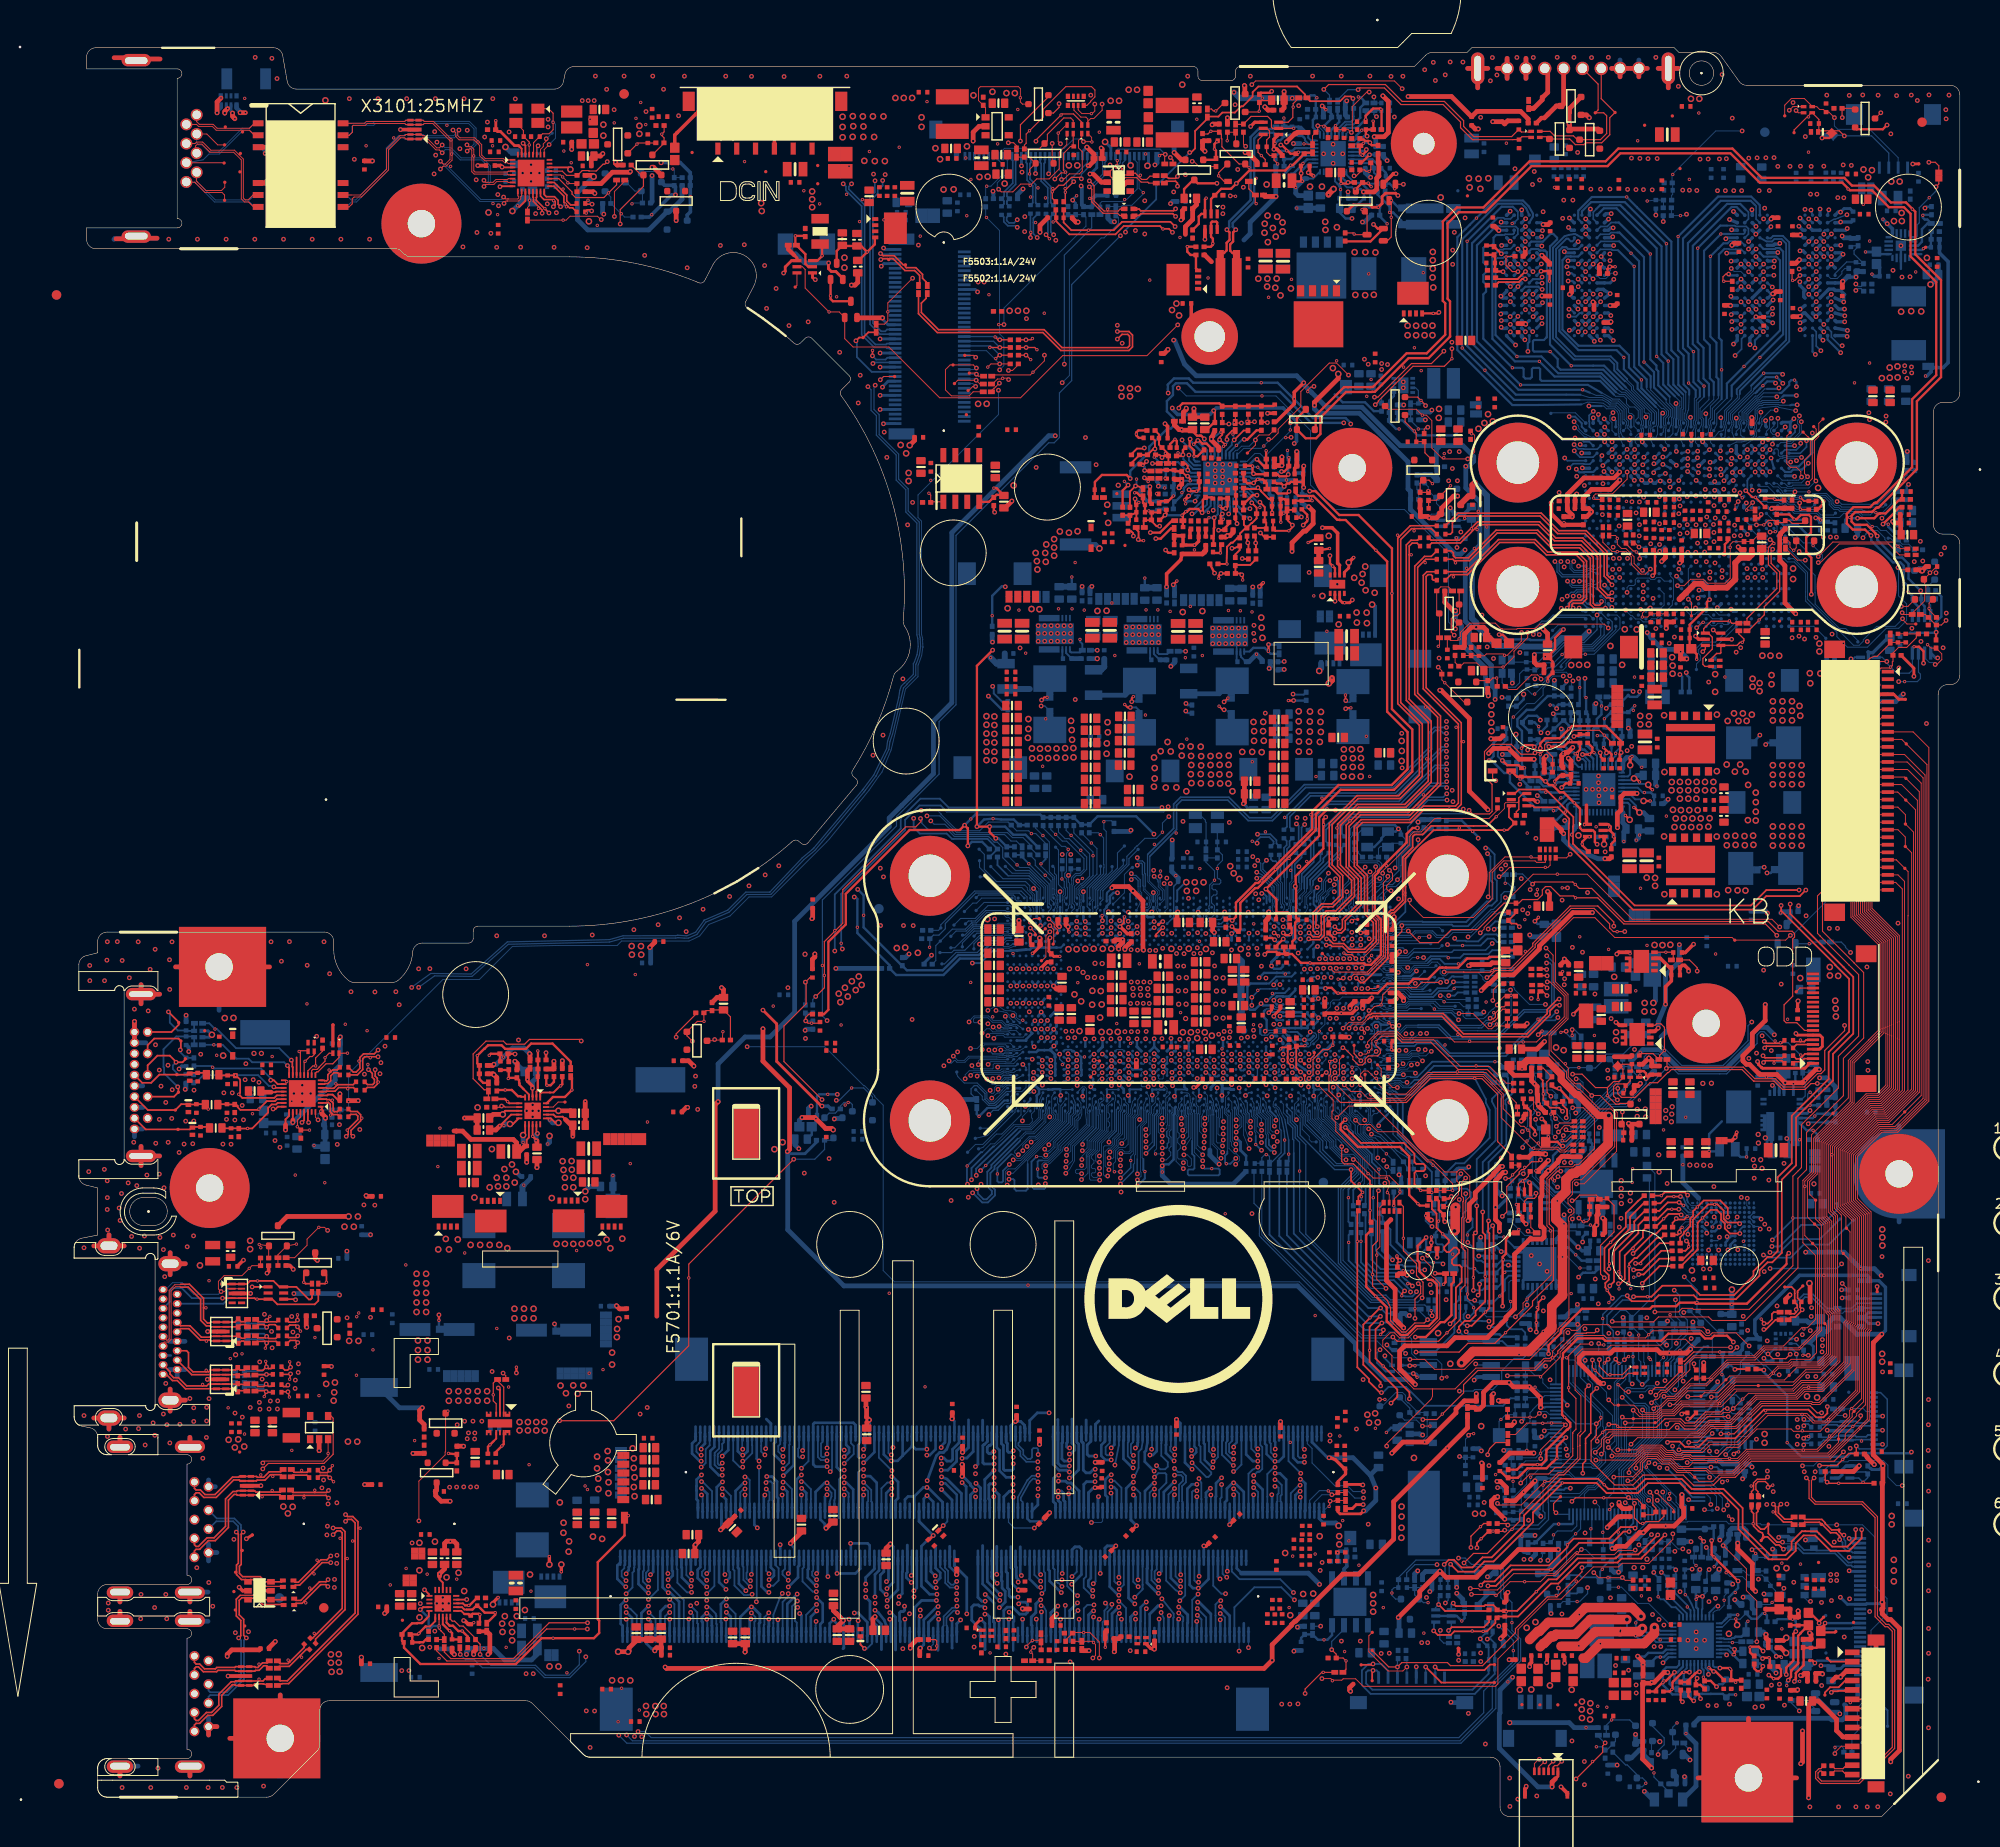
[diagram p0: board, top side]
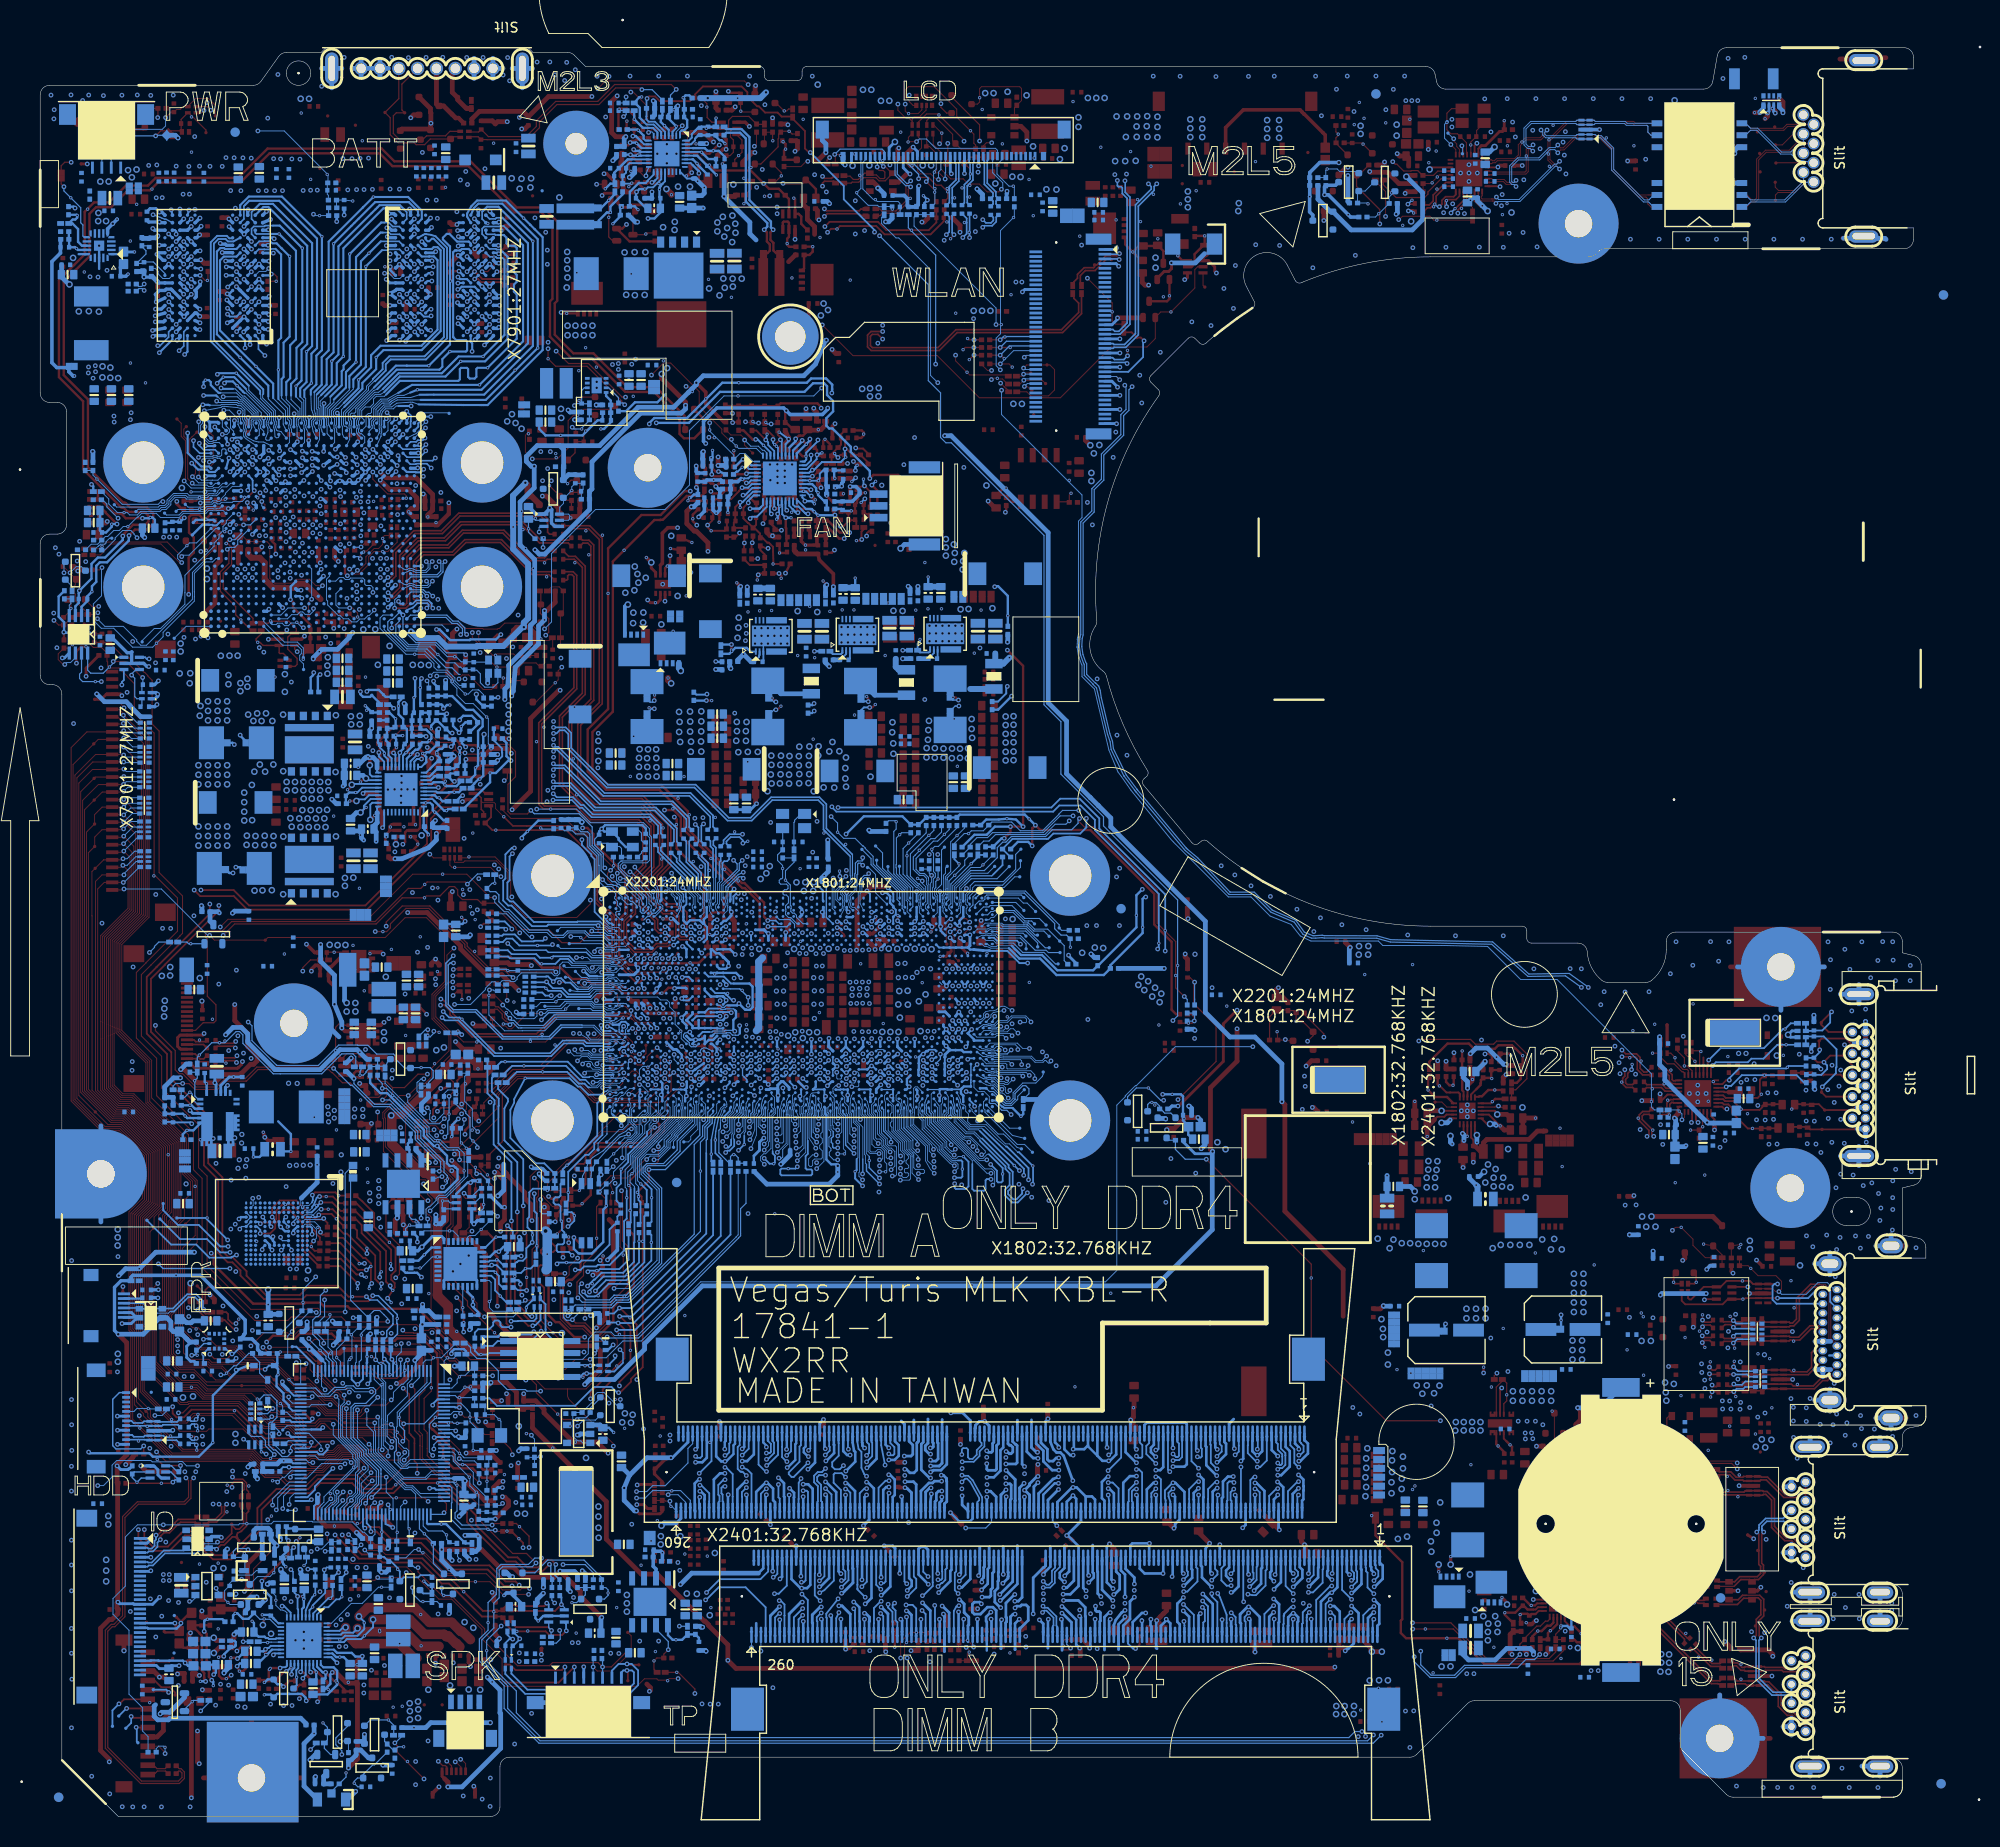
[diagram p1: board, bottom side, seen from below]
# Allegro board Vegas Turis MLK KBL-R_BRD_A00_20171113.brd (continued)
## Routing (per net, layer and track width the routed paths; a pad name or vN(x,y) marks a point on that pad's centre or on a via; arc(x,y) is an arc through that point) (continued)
3D3V_S5_KBC: length 423.8
  TOP w0.127: 152.18,33.55 R2476.1 ; v1(172.1,48.12) 172.1,47.71 R2450.1
  TOP w0.254: v1(171.44,42.26) 171.44,42.27 171.69,42.27 C2429.1
  TOP w0.508: v1(170.83,34.2) 170.8,34.18 170.8,32.94 C2414.1 171.01,31.88 170,30.86 v2(169.1,30.86) 167.42,30.86 v1(166.73,30.18) 166.32,30.18 164.85,28.71 163.91,28.71 163.68,28.48 v1(163.41,28.48) ; D4304.2 158.88,181.54 158.88,181.11 158.84,181.06 v1(158.84,179.97) 158.84,179.79 158.88,179.74 D4306.2 158.99,179.35 161.92,179.35 D4305.2 ; v1(164.14,33.38) 164.14,33.11 164.54,32.72 165.25,32.72 C2420.1 ; 152.18,33.55 153.1,33.55 v2(154.01,34.47) v1(155.21,35.67)
  L2 w0.508: v1(172.1,48.12) 172.1,42.82 171.55,42.27 171.44,42.27 v1(171.44,42.26) ; v1(172.1,48.12) 168.8,48.12 v1(166.61,45.93) 165.34,47.19 161.83,47.19 161.14,47.88 161.06,47.88 161.05,47.89 160.68,48.26 160.68,48.35 v1(160.54,48.48) 159.9,47.84 159.9,36.98 159.65,36.74 159.65,36.21 159.95,35.92 159.95,32.69 160.48,31.42 v1(163.41,28.48) ; v1(172.1,48.12) 171.11,49.12 171.11,51.67 v1(171.99,52.55) ; v1(171.99,52.55) 169.39,52.55 v1(169.29,52.66) ; v1(171.99,52.55) 171.99,52.71 172.56,53.27 172.56,54.4 175.56,57.4 178.12,57.4 179.69,58.97 180.09,58.97 184.52,63.4 185.09,63.4 185.51,63.82 185.51,76.22 184.44,77.29 184.44,79.29 v1(180.64,83.08)
  L3 w0.508: v1(154.53,31.49) 154.53,34.98 v1(155.21,35.67) 156.46,36.92 156.46,39.9 156,40.36 v1(155.9,40.36) ; v1(184.02,95.73) 181.44,95.73 178.87,93.16 178.87,89.51 179.35,89.03 179.56,89.03 181.62,86.96 181.62,86.5 187.4,80.73 187.4,72.05 186.16,70.81 186.16,61.08 177.07,51.99 177.07,50.91 177.31,50.67 177.31,47.48 180.34,44.45 180.34,38.22 v1(178.57,36.44) ; v1(163.41,28.48) 164.14,29.21 v1(164.14,33.38) ; v1(198.36,134.16) 198.46,134.06 198.46,131.93 198.09,131.55 196.89,131.55 196.87,131.58 195.53,131.58 194.77,130.82 194.77,129.55 195.3,129.01 195.3,126.34 v1(195.26,126.29) 195.26,125.72 194.59,125.06 194.59,119.55 v1(194.34,119.31) 193.78,118.75 v1(193.78,94.95)
  L4 w0.508: v1(193.78,94.95) 190.32,94.95 189.54,95.73 v1(184.02,95.73) ; v1(166.52,44.66) 165.89,44.66 165.01,43.79 165.01,42.91 165.38,42.54 170.02,42.54 170.45,42.12 171.29,42.12 v1(171.44,42.26) 174.2,39.51 176.24,39.51 177.06,38.69 177.06,37.46 178.08,36.44 v1(178.57,36.44) ; v1(198.36,134.16) 198.13,134.39 197.29,134.39 196.78,134.9 195.76,134.9 195.38,135.27 195.38,136.16 195.82,136.6 195.82,151.9 198.33,154.42 198.33,170.45 189.52,179.26 186.54,179.26 186.01,179.79 158.84,179.79 v1(158.84,179.97) ; v1(164.14,33.38) 164.14,33.38 163.76,33.76 162.86,33.76 160.14,31.04 154.98,31.04 v1(154.53,31.49)
  BOTTOM w0.203: KBC24.19 166.06,46.48 v1(166.61,45.93) 166.73,45.93 167.26,46.45 KBC24.22 ; R2412.1 173.81,42.1 173.64,41.93 KBC24.43 171.64,41.93 171.44,42.13 v1(171.44,42.26) ; KBC24.103 156.36,35.93 ; KBC24.65 171.26,32.99 170.89,33.36 ; v1(160.54,48.48) 160.46,48.4 KBC24.5 ; v1(164.14,33.38) 164.14,33.33 164.46,33.02 KBC24.82 ; v1(155.9,40.36) 156.31,40.36 156.68,40.73 KBC24.115
  BOTTOM w0.508: v1(163.41,28.48) 163.33,28.57 R2414.1 ; v1(171.99,52.55) 171.99,51.84 172.3,51.54 R2415.1 ; C2413.1 155.14,34.06 C2417.1 155.32,35.56 v1(155.21,35.67) 155.47,35.93 156.36,35.93 ; v1(180.64,83.08) 179.86,83.86 178.98,83.86 178.3,83.19 178.3,82.46 178.29,82.44 178.29,82.27 175.43,79.41 175.39,79.38 175.03,79.38 170.62,79.38 168.5,81.5 166.66,81.5 v2(166.39,81.22) 165.64,80.48 R4032.1 ; C2410.1 159.81,49.54 R2446.2 159.85,49.18 v1(160.54,48.48) ; 188.68,116.89 189.67,116.89 190.81,118.04 190.81,118.1 191.21,118.49 193.53,118.49 v1(194.34,119.31) ; R2478.1 v1(166.73,30.18) ; 170.89,33.36 170.89,34.14 v1(170.83,34.2) ; v1(169.29,52.66) 169.03,52.39 R2424.1 ; v1(155.9,40.36) 155.8,40.26 C2422.1 155.18,40.29 155.18,40.91 R2493.2
  vias: v2(167.47,48.57) v2(188.27,99.98)
3D3V_S5_PCH: length 88.1
  TOP w0.508: v1(161.3,96.07) 159.23,96.07 155.68,92.52 155.68,92.21 152.93,89.46 151.3,89.46 150.37,88.54 150.24,88.54 v1(149.5,87.79)
  TOP w1.016: v1(146.79,64.77) 146.73,64.71 146.73,62.3 v4(146.66,62.23)
  L3 w0.508: v1(148.18,69.05) 150.69,69.05 v1(151.62,69.99) ; v1(146.79,64.77) 147.32,64.77 147.68,65.13 148.35,65.13 148.97,65.76 151.53,65.76 v1(151.73,65.96)
  L3 w0.635: v1(161.3,96.07) 161.3,96.71 160.1,97.91 160.1,99.13 159.08,100.15 159.08,100.2 v1(155.31,103.96)
  L3 w0.762: v4(142.36,38.11) 144.14,39.89 144.14,43.99 146.21,46.07 v4(146.21,48.12)
  L4 w0.254: v1(145.77,54.92) 145.77,53.68 147.9,51.55 v1(147.9,51.53)
  L4 w0.508: v1(154.74,77.06) 154.47,77.06 153.5,78.03 153.23,78.03 148.95,82.3 148.95,87.24 v1(149.5,87.79)
  L4 w0.762: v4(144.92,51.37) 144.92,48.77 145.56,48.12 v4(146.21,48.12)
  BOTTOM w0.254: v1(147.9,51.53) 148.18,51.25 151.45,51.25 151.7,51 153.2,51 R2501.1
  BOTTOM w0.381: R1824.1 146.53,68.4 146.95,68.82 147.04,68.82 147.1,68.89 148.02,68.89 v1(148.18,69.05)
  BOTTOM w0.508: 151.1,69.34 151.1,66.55 151.69,65.96 v1(151.73,65.96) ; R1828.1 146.12,61.7 146.48,62.05
  BOTTOM w1.016: 146.6,58.09 146.48,58.21 v2(146.48,59.77) 146.48,62.05 v4(146.66,62.23)
  vias: v2(150.02,86.57) v2(153.84,79.46) v2(154.39,104.52)
3D3V_S5_PCH_GEN9: length 2.8
  BOTTOM w0.254: v2(139.42,40.82) 139.92,41.31 R2116.1
  BOTTOM w0.508: U2101.3 140.87,41.61 R2116.1
3D3V_TP_S5_R: length 4.2
  BOTTOM w0.127: R6521.2 R6520.2 ; R6521.2 141.61,24.33 C6503.2 ; R6521.2 142.43,23.55 Q6504.S 142.98,23.1 143.36,22.73 v2(143.85,22.73)
3D3V_TPM: length 13.8
  TOP w0.203: v1(149.17,55.41) 149.32,55.56 v1(149.32,56.57)
  L3 w0.254: v1(156.1,53.74) 153.16,53.74 151.49,55.41 v1(149.17,55.41) ; v1(149.32,56.57) 149.32,59.49 v1(149.24,59.57)
  BOTTOM w0.254: v1(149.32,56.57) 149.32,56.77 149.54,56.99 R9140.1 ; R9147.1 149.88,59.59 149.27,59.59 v1(149.24,59.57)
  vias: v2(156.09,51.56)
3D3V_TPM_1:
  vias: v2(163.24,61.03)
3D3V_VGA_S0: length 88.2
  TOP w0.356: Q7901.2 172.6,125.12 v1(172.27,125.45) ; Q7901.5 v1(176.11,125.12)
  TOP w0.508: C8024.1 170.79,133.44 v1(170.59,133.24) ; v1(158.76,112.48) 159.04,112.2 PR8505.1 ; R7625.1 145.63,129.05 146.53,128.16 v1(146.77,128.16) ; v1(150.25,119.11) 150.25,119.31 150.19,119.37 R7942.1 ; v1(150.29,113) 150.81,113.51 152.41,113.51 v2(152.45,113.48) 153.55,112.37 155.11,112.37 v1(155.11,112.37) ; v1(182.91,127.84) 181.77,128.98 181.77,132.95 181.21,133.5 181.21,136.18 181.31,136.27 181.31,136.37 R7921.1
  L3 w0.508: v1(150.25,119.11) 150.14,119.11 149.69,118.66 149.69,113.65 150.29,113.04 v1(150.29,113) ; v1(155.11,112.37) 155.43,112.05 158.33,112.05 v1(158.76,112.48) 159.48,111.76 160.1,111.76 161.45,113.11 161.45,116.11 161.05,116.51 161.05,118.55 161.42,118.93 164.9,118.93 165.41,118.42 170.08,118.42 172.83,121.16 ; v1(194.77,145.09) 196.15,143.72 196.15,136.45 196.79,135.8 196.79,133.82 v1(196.42,133.44)
  L4 w0.508: v1(143.56,148.45) 143.87,148.45 144.03,148.29 144.12,148.29 144.49,147.92 144.49,147.83 146.15,146.18 v1(146.15,145.07)
  BOTTOM w0.102: 194.74,143.94 R7903.2
  BOTTOM w0.254: v1(155.11,112.37) 155.21,112.27 PR8518.1 155.21,111.68 PR8503.1
  BOTTOM w0.508: v1(150.25,119.11) 150.27,119.13 150.27,119.42 150.09,119.61 149.87,122.15 147.4,124.62 147.4,126.55 v2(146.77,127.18) v1(146.77,128.16) ; v1(194.77,145.09) 194.74,145.05 194.74,143.94 ; PR8625.1 143.56,148.45 v1(143.56,148.45)
  vias: v1(146.04,141.97) v1(146.43,143.27) v1(146.97,141.97) v1(147.16,145.07) v1(176.59,123.75) v1(198.58,124.22) v2(145.52,144.43) v2(145.57,144.86) v2(175.39,121.11)
3D3V_WLAN_S0:
  vias: v1(96.05,163.09) v1(96.68,163.09) v2(94.84,170.14) v2(97.2,161.75) v4(96.04,150.14) v4(96.95,150.15)
+DC_IN: length 6.6
  TOP w0.305: v1(80.16,165.13) 80.14,165.11 80.14,164.52 80.45,164.21 80.93,164.21 81.67,163.48 PQ4305.2
  BOTTOM w0.508: v1(80.16,165.13) 77.62,165.13 76.64,166.11
  vias: v2(71.23,175.9) v2(77.53,172.8) v2(79.2,171.4) v2(83.45,169.52) v4(68.72,180.3) v4(68.72,179.36) v4(68.72,178.42) v4(69.99,180.3) v4(69.99,179.36) v4(69.99,178.42) v4(78.41,172.72) v4(78.41,171.88) v4(78.41,171.05)
+RTC_CELL_VBAT: length 14.9
  TOP w0.508: R2472.2 148.81,43.47 R2473.2 149.35,43.3 149.73,43.68 C2428.1 149.75,44.01 149.75,45.08 150.78,46.12 v1(152.46,46.12) 152.92,45.67 v2(154.62,45.67) 155.8,44.48 155.8,43.54 155.84,43.5 155.84,43.47 v1(155.81,43.47)
  BOTTOM w0.203: v1(155.81,43.47) 156.26,43.47 156.32,43.53 KBC24.122
  BOTTOM w0.508: v1(152.46,46.12) 152.52,46.06 R2451.1 R2452.2
+RTC_VCC: length 8
  TOP w0.508: R2502.1 37.19,41.67 36.71,42.14 AFTP2502.1 36.71,43.16 v1(36.99,43.44)
  BOTTOM w0.508: RTC1.1 34.56,43.44 v1(36.99,43.44)
+SDC_IN: length 1.1
  TOP w0.508: PR4441.1 120.11,165.98 120.84,165.25
  vias: v2(120.48,163.53)
+UZ12_TPM:
  vias: v2(159.06,55.58)
+V_VREF_PATH1: length 1.8
  TOP w0.254: C1222.2 v2(109.56,17.99)
  TOP w0.508: R1209.1 109.56,19.6 C1222.2
+V_VREF_PATH2:
  vias: v2(97.32,17.38)
+VCHGR:
  vias: v2(143.34,164.09) v4(144.33,163.58) v4(144.36,166.3) v4(144.36,165.41) v4(144.36,164.52) v4(144.41,162.51)
A67_TP: length 6.4
  BOTTOM w0.102: CPU1.A67 101.6,97.83 100.69,98.73 97.95,98.73 96.81,99.87 TP2311.1
A70_TP: length 5.6
  BOTTOM w0.102: TP2301.1 95.49,97.08 95.89,97.08 96.43,97.61 CPU1.A70
AC_DIS: length 341.2
  TOP w0.102: PQ4306.5 77.37,164.72 77.67,164.42 77.67,162.45 v2(80.21,159.92) 81.28,159.92 PQ4304.B 81.87,157.08 82.76,156.19 86.56,156.19 91.96,150.79 100.56,150.79 105.04,155.27 113.99,155.27 v1(117.26,158.54) ; v1(118.79,175.92) 118.96,175.92 119.51,175.37 PR4444.2
  L3 w0.102: v1(182.63,182.17) 192.06,182.17 193.35,180.88 193.37,180.88 198.15,176.1 198.14,176.09 199.17,175.05 199.17,174.72 199.17,152.99 195.03,148.84 195.03,146.45 193.91,145.33 193.91,141.69 193.91,141.69 193.91,141.34 193.91,141.34 193.91,141.17 194.95,140.12 194.95,139.59 194.95,138.9 194.95,136 192.74,133.79 192.74,129.72 191.5,128.48 191.5,120.73 190.69,119.92 190.69,119.3 191.32,118.67 191.79,118.67 192.4,118.06 192.4,94.27 194.24,92.43 194.24,71.44 192.4,69.6 192.4,69.6 192.06,69.26 192.06,67.54 193.06,66.53 193.06,59.3 192.36,58.6 191.64,58.6 188.48,55.43 188.48,54.86 187.29,53.67 187.29,42.49 186.69,41.89 186.69,40.85 186.44,40.6 v1(186.44,39.34) ; v1(117.26,158.54) 117.26,158.74 114.84,161.16 114.84,174.95 115.26,175.37 115.26,176.6 115.95,177.29 117.42,177.29 v1(118.79,175.92) 118.79,176.51 122.05,179.78 122.05,181.26 123.2,182.4 124.4,182.4 126.08,184.08 142.07,184.08 144.04,182.11 147.52,182.11 149.03,180.6 v1(149.44,180.6)
  L4 w0.102: v1(182.63,182.17) 182.24,181.78 182.05,181.78 181.8,181.53 181.8,181.34 181.62,181.16 173.37,181.16 173.18,180.98 168.97,180.98 168.79,181.16 150,181.16 v1(149.44,180.6) ; v1(186.44,39.34) 186.44,39.34 186.44,36.94 182.15,32.65 178.51,32.65 177.32,33.84 173.49,33.84 172.89,33.24 169.39,33.24 169.04,33.59 169.04,34.23 v1(168.79,34.49)
  BOTTOM w0.102: v1(168.79,34.49) 168.84,34.43 168.84,33.5 169.21,33.13 169.31,33.13 169.66,32.78 KBC24.69
AC_DIS_R: length 3.5
  TOP w0.254: PQ4412.G 121.17,176.08 PR4444.1 121.32,177.06 v2(121.16,177.22) 121.16,177.76 PC4471.1
AC_IN#_G: length 5.4
  TOP w0.254: PR4312.2 77.6,168 v2(76.63,168) 76.63,167.12 PR4313.1 77.7,166.05 77.7,165.03 78,164.72 PQ4306.2
AC_IN_KBC#: length 1.6
  TOP w0.102: PQ4306.6 76.8,162.75 TP4301.1
AC_PRESENT: length 60.8
  TOP w0.102: 155.36,62.03 154.66,62.03 v1(154.47,62.21) ; 155.36,62.03 154.77,62.62 EC1707.1 154.77,64.7 Q1702.3 ; 155.36,62.03 D1702.A ; v1(139.38,56.13) 138.4,57.11 v2(138.4,59.67) 138.4,60.22 138.73,60.55 138.73,64.73 139.14,65.14 RN1704.8
  L3 w0.102: v1(154.47,62.21) 152.03,62.21 151.61,62.63 151.25,62.63 150.98,62.36 149.38,62.36 148.97,62.76 146.44,62.76 144.63,60.95 144.63,60.81 143.89,60.07 140.04,60.07 139.29,59.32 139.29,56.21 v1(139.38,56.13)
  BOTTOM w0.089: 133.24,72.49 133.24,72.5 132.4,73.35 132.38,73.35 131.55,74.18 131.55,75.86 131.21,76.2 CPU1.AY15
  BOTTOM w0.102: 133.24,72.49 133.24,72.37 133.83,71.78 133.83,71.19 134.63,70.38 135.91,70.38 136.5,69.79 136.5,68.27 134.82,66.59 134.82,59.1 137.79,56.13 v1(139.38,56.13)
ACLIM: length 4.3
  TOP w0.127: PR4401.2 137.78,175.75 137.78,175.04 v2(137.59,174.86) 137.59,174.86 137.25,174.86 137.1,175.01 PR4403.1 136.61,174.77 136.22,174.38 v1(135.99,174.38)
  BOTTOM w0.127: v1(135.99,174.38) 135.99,174.31 135.92,174.34 135.89,174.38 135.86,174.45 135.95,174.66 PU4401.16
ACOK_IN: length 227.4
  TOP w0.203: 181.94,58.72 181.94,59.63 v1(182.18,59.87)
  TOP w0.254: PR4474.1 130.79,176.84 PR4417.2 129.47,175.52 v2(129.24,175.52) 128.67,174.95 124.86,174.95 v1(123.48,173.57) 122.91,173 121.88,173 PR4418.1 120.8,171.92 PQ4405.2 ; v1(151.77,54.24) 151.77,59.47 152.13,59.83 152.13,61.37 152.79,62.03 D1702.K ; v1(156.66,49.18) 156.66,50.09 157.98,51.41 157.98,51.73 160.21,53.96 167.43,53.96 167.7,54.23 170.21,54.23 170.59,54.61 172.18,54.61 172.29,54.5 177.73,54.5 181.94,58.72
  L3 w0.254: v1(156.66,49.18) 156.66,51.99 156.05,52.6 152.93,52.6 151.77,53.75 v1(151.77,54.24) ; v1(182.18,59.87) 182.18,66.21 185.01,69.04 185.01,71.16 186.38,72.53 186.38,79.69 183.8,82.27 183.17,82.27 182.25,83.19 182.25,84.11 180.49,85.88 180.49,86.21 175.5,91.19 167.77,91.19 166.8,92.17 166.8,93.14 167.38,93.72 167.38,96.45 164.24,99.58 164.24,103.04 162.96,104.32 162.38,104.32 157.54,109.16 157.54,109.53 156.16,110.91 155.14,110.91 153.68,112.37 153.68,114.19 154.13,114.65 154.13,118.65 154.54,119.06 154.54,119.5 153.82,120.23 153.82,122.42 150.24,126 150.24,134.88 147.62,137.5 146.73,137.5 144.52,139.71 144.52,146.81 147.7,149.99 147.7,153.84 147.21,154.32 141.47,154.32 136.48,159.31 126.66,159.31 123.02,162.95 123.02,167 124.31,168.29 124.31,172.37 123.48,173.2 v1(123.48,173.57)
  BOTTOM w0.254: v1(156.66,49.18) 156.66,49.37 156.36,49.67 155.32,49.67 155.12,49.47 R2469.2
AD+: length 69.2
  TOP w0.305: v1(140.65,172.29) 140.41,172.53 139.34,172.53 138.97,172.16 138.97,171.45 v2(138.56,171.05) 137.93,171.05 137.68,171.3 135.91,171.3 135.24,170.62 PD4410.1
  TOP w0.508: PR4431.1 120.99,179.88 v1(120.91,179.81) ; PR4440.1 119.25,171.3 PR4445.1 118.84,169.75 118.07,168.98 118.07,168.16
  L3 w0.635: v1(123.23,183.26) 123.21,183.24 121.67,183.24 121.06,182.63 121.06,180.01 120.91,179.86 v1(120.91,179.81) 112.78,179.81 109.37,176.39 109.37,175.25 109.69,174.93 109.69,174.93 110.66,173.95 110.66,173.37 110.66,173.37 110.66,172.79 110.66,172.79 110.66,172.12 113.75,169.04 v1(113.75,168.2)
  L4 w0.508: v1(129.42,182.64) 129.87,183.09 132.25,183.09 133.83,181.51 140.32,181.51 141.28,180.55 141.28,174.5 140.65,173.87 140.65,173.8 140.6,173.75 140.6,173.22 140.65,173.17 v1(140.65,172.29)
  BOTTOM w0.635: PR4452.1 v1(129.42,182.64) v2(126.25,182.64) 123.85,182.64 v1(123.23,183.26)
  vias: v2(89.9,167.97) v2(114.28,163.3) v2(117.5,167.83)
AD+_G_1: length 4.9
  TOP w0.254: PR4422.2 120.77,166.84 120.99,167.06 v2(120.99,167.18) 120.99,167.7 120.8,167.89 PQ4405.5 120.8,169.4 120.91,169.52 121.35,169.52 121.45,169.42 PQ4405.6
AD+_G_2: length 4.3
  TOP w0.254: PQ4410.4 119.19,164.56 PR4441.2 118.62,165.98 118.27,166.32 v2(118.27,166.85) 119.17,166.85 PR4422.1
AD+_R: length 54.6
  TOP w0.254: v1(145,159.87) 144.9,159.76 v2(144.41,159.76) PQ4401.4 ; v1(121.42,173.59) 119.37,173.59 PQ4412.D 118.9,173.94 117.93,172.98 PR4440.2
  L3 w0.254: v1(145,159.87) 145.09,159.96 145.09,167.36 144.05,168.4 137.14,168.4 136.38,169.17 136.38,169.26 136.38,170.77 138.41,172.81 138.41,174.73 136.78,176.36 136.78,178.68 135.22,180.24 131.78,180.24 131.18,179.64 127.03,179.64 125.6,178.21 124.44,178.21 122.78,176.56 122.78,174.95 v1(121.42,173.59)
AD_IA: length 232
  TOP w0.102: v1(151.22,33.28) 151.39,33.11 153.76,33.11 v2(156.26,35.6) 156.73,35.6 157.67,36.54 158.17,36.54 159.75,38.12 159.75,39.32 159.75,39.33 159.75,40.5 159.75,40.5 159.75,40.6 160.09,40.94 160.09,44.69 159.48,45.31 159.48,48.93 160.23,49.68 162.85,49.68 163.26,50.09 168.59,50.09 169.22,50.72 171.21,50.72 171.82,50.11 171.92,50.11 172.16,49.87 v1(175.99,49.87)
  L3 w0.102: v1(138.1,182.77) 136.96,182.77 136.68,183.06 135.28,183.06 134.72,182.5 132.61,182.5 130.61,180.49 126.74,180.49 125.27,179.02 124.1,179.02 121.97,176.89 121.97,175.89 120.61,174.53 120.61,173.25 121.17,172.68 123.02,172.68 123.27,172.43 123.27,170.6 122.04,169.37 122.04,162.96 126.73,158.27 136.55,158.27 140.66,154.15 140.66,151.68 141.82,150.52 141.82,149 143.74,147.08 143.74,139.51 147.23,136.02 147.59,136.02 148.81,134.8 148.81,128.08 148.76,128.03 148.76,127.36 149.39,126.72 149.39,126.07 149.32,126 149.32,122.21 151.68,119.85 152.08,119.85 152.74,119.19 152.74,115.22 152.73,115.22 152.73,112.34 154.85,110.22 154.95,110.22 158.47,106.71 158.74,106.71 161.16,104.29 161.16,103.38 161.64,102.9 161.64,101.22 166.16,96.7 166.16,93.47 166.11,93.43 166.11,91.88 167.69,90.31 174.51,90.31 179.34,85.48 179.45,85.48 181.57,83.36 181.57,82.85 184.47,79.95 184.47,78.04 185.69,76.82 185.69,72.81 184.32,71.44 184.32,69.32 181.28,66.28 181.28,58.61 175.86,53.19 175.86,50 v1(175.99,49.87)
  BOTTOM w0.102: v1(151.22,33.28) 151.44,33.06 R2421.2 ; PC4402.1 138.1,182.13 PR4475.1 138.13,182.16 138.13,182.74 v1(138.1,182.77)
AD_OFF_L: length 4.3
  TOP w0.254: PQ4305.1 v2(80.37,161.63) 80.37,161.3 80.62,161.05 PQ4304.C
AD_OFF_R: length 8.4
  TOP w0.254: v2(84.26,166.29) 85.07,167.1 85.07,167.79 PU4301.4 ; v2(84.26,166.29) 83.62,166.93 PR4307.2 81.68,166.93 PC4301.2 81.02,166.39 PQ4305.3 ; v2(84.26,166.29) 83.37,165.39 PR4308.1
ADBIA0: length 31.7
  L3 w0.102: v1(169.56,141.29) 169.91,141.63 169.91,142.3 169.62,142.59 169.62,144.41 169.79,144.58 169.79,145.3 170.03,145.53
  L3 w0.203: v1(160.57,163.42) 161.04,163.88 162.1,163.88 163.06,162.93 163.82,162.93 164.74,163.85 165.24,163.85 168.12,160.96 168.12,151.53 170.03,149.62 170.03,145.53
  BOTTOM w0.229: VRAM1.J4 160.55,163.45 160.55,163.44 v1(160.57,163.42) ; GPU1.L18 v1(169.56,141.29)
ADBIA1: length 30.9
  L3 w0.102: 171.28,146.49 171.28,146.23 172.07,145.44 172.07,143.92 171.88,143.73 171.88,143.41 v1(171.43,142.96)
  L3 w0.203: 171.28,146.49 171.28,149.03 171.57,149.31 171.57,151.84 170.81,152.59 170.81,161.72 171.97,162.87 175.93,162.87 176.91,163.86 177.53,163.86 177.66,163.73 178.23,163.73 178.7,164.19 v1(179.49,164.19)
  BOTTOM w0.229: GPU1.K16 v1(171.43,142.96) ; v1(179.49,164.19) VRAM2.J4
ALL_SYS_PWRGD: length 318.6
  TOP w0.127: v1(79.46,76.19) 75.42,80.24 75.42,84.02 77.77,86.38 77.77,88.6 v1(77.69,88.68) 78.18,89.17 EC1709.1
  L2 w0.102: 179.07,67.65 180.12,68.7 180.12,70.06 180.5,70.44 180.5,75.54 178.84,77.2
  L2 w0.127: 178.84,77.2 177.26,78.77 177.26,83.46 v1(178.25,84.44) ; v1(156.25,42.55) 156.25,42.55 156.25,42.56 156.28,42.54 156.56,42.54 156.99,42.96 156.99,46.25 v1(156.82,46.41) 156.82,48.39 155.84,49.37 155.84,50.4 159.42,53.98 160.8,53.98 161.75,54.93 162.96,54.93 163.26,54.63 166.3,54.63 172.38,60.72 172.38,60.78 172.78,61.18 172.78,63.27 176.8,67.28 178.7,67.28 179.07,67.65
  L3 w0.127: v1(156.25,42.55) 156.25,42.55 156.07,42.37 155.29,42.37 148.76,48.91 144.85,48.91 140.71,44.77 140.71,41.44 138.44,39.17 138.44,38.74 134.92,35.22 134.92,33.41 133.63,32.11 133.01,32.11 132.04,31.15 132.03,31.15 131.07,30.19 131.07,28.68 131.06,28.67 131.06,28.63 127,24.58 127,22.36 123.41,18.76 104.44,18.76 101.82,16.14 84.76,16.14 81.36,19.54 58.37,19.54 55.57,22.34 55.57,27.44 56.66,28.52 56.66,32.69 58.23,34.26 58.23,44.97 79.68,66.43 79.68,74.88 79.91,75.11 79.91,75.74 v1(79.46,76.19)
  L4 w0.102: 158.74,45.97 157.26,45.97 v1(156.82,46.41)
  L4 w0.127: v1(174.53,38.78) 174.53,38.78 174.53,38.78 174.15,38.39 173.57,38.39 173.31,38.65 173.31,38.7 171.68,40.33 167.76,40.33 167.29,40.8 165.69,40.8 165.22,41.27 164.52,41.27 159.82,45.97 158.74,45.97
  BOTTOM w0.102: R2481.1 175.31,39.36 174.72,38.78 v1(174.53,38.78)
  BOTTOM w0.127: v1(178.25,84.44) 177.84,84.04 177.84,82.46 175.24,79.86 175.21,79.82 170.8,79.82 168.64,81.99 166.62,81.99 166.6,81.97 165.53,81.97 164.59,81.03 162.81,81.03 162.58,80.8 162.58,80.5 161.63,79.55 D4002.1 160.95,79.6 v2(159.88,79.6) 158.91,79.6 158.6,79.29 158.6,78.52 159.1,78.02 R4005.2 159.11,77.64 R4002.1 ; R4011.2 175.62,39.88 175.36,39.62 R2481.1 ; R1716.1 77.69,86.89 77.69,86.89 v1(77.69,88.68)
ALWON: length 363
  TOP w0.127: v1(187.99,38.75) 186.99,37.76 178.2,37.76 176.49,36.04 174.99,36.04 174.16,35.22 172.04,35.22 170.97,36.29 166.68,36.29 165.63,35.24 163.69,35.24 161.18,37.75 161.18,39.91 161.57,40.31 161.57,40.35 161.73,40.51 v1(161.73,41.73) 162.21,42.22 v2(162.21,42.41) ; v1(63.96,82.83) 63.96,83.19 66.05,85.27 R4009.2
  L3 w0.127: v1(63.96,82.83) 62.54,84.25 45.75,84.25 17.69,56.19 17.69,43.34 19.29,41.73 19.29,37.53 19.29,36.63 19.4,36.52 19.4,34.75 19.9,34.25 19.9,24.93 20.73,24.1 20.73,20.72 20.73,18.6 20.92,18.41 20.92,18.41 21.18,18.15 21.18,18.15 21.49,17.84 22.16,17.84 26.59,13.41 48.98,13.41 54.5,7.89 59.71,7.89 v1(60.31,8.49) ; v1(153.39,1.84) 153.87,1.36 180.66,1.36 182.1,2.8 187.3,2.8 195.89,11.39 195.89,31.66 189.83,37.72 189.02,37.72 v1(187.99,38.75)
  L4 w0.127: v1(153.39,1.84) 153.42,1.87 153.42,6.12 150.19,9.35 133.34,9.35 132.42,10.28 63.27,10.28 63.02,10.03 61.85,10.03 v1(60.31,8.49)
  BOTTOM w0.127: v1(161.73,41.73) 159.56,41.73 158.16,43.13 KBC24.121
AMBER_LED_BAT: length 18
  BOTTOM w0.508: 188.1,11.87 188.24,11.74 188.24,10.64 187.86,10.27 186.73,10.27 186.56,10.44 172.67,10.44 172.11,9.88 R6407.1
  vias: v2(188.71,12.1)
ATI_RST#: length 8.1
  TOP w0.102: R7623.2 146.02,130.7 145.2,130.7 R7625.2 144.77,128.14 D7601.3 145.07,127.83 R7621.1 145.07,124.51 v2(144.94,124.37)
AUD_AGND: length 19
  TOP w0.508: v1(183.17,21.85) 183.19,21.82 EC2908.2 183.17,21.19 R2920.2 182.3,21.21 EC9739.1 181.19,22.05 R2705.1 179.76,22.02 EC9745.1 ; EC9744.1 184.17,14.4 184.17,15.2 184.16,15.2 EC2703.1 183.83,15.2 183.62,14.99 v1(183.44,14.99) ; v1(179.75,19.35) 179.76,19.34 179.76,18.96 EC2906.2 179.99,18.7 EC2905.2 ; v1(183.12,13.46) 183.07,13.41 EC2704.1 ; v1(184.39,19.51) 184.54,19.36 184.54,18.85 EC2907.2 184.51,18.82 R2919.2
  BOTTOM w0.203: v1(175.57,17.17) 175.41,17.33 HDA27.19 ; 169.41,16.93 HDA27.31
  BOTTOM w0.254: v1(168.82,16.33) 169.41,16.93
  BOTTOM w0.305: v1(185.6,16.02) 186.41,16.02 R6601.1 186.72,15.71 187.68,15.71 188.02,16.05 IOBD1.28
  BOTTOM w0.508: v1(180.82,15.25) 180.82,15.33 180.36,15.78 C2902.2 ; v1(179.75,19.35) 179.5,19.6 C2715.2
  vias: v1(165.16,15.55) v1(165.96,13.98) v1(165.97,13.12) v1(173.59,11.79) v1(174.49,11.78) v1(175.87,11.94) v1(180.33,13.96) v1(181.19,14.06) v1(187.43,21.29)
AUD_HP1_JACK_L: length 13.9
  TOP w0.254: v1(179.45,17.58) 178.98,18.05 178.12,18.05 v2(178.06,17.99) 178.06,17.44 178.45,17.06 R2922.2 ; v1(172.68,15.36) 172.49,15.36 172.2,15.17 171.93,14.9 171.93,14.89 171.52,14.48 R2913.2 170.71,14.28 R2908.1
  L3 w0.254: v1(179.45,17.58) 177.78,17.58 176.53,16.33 173.65,16.33 v1(172.68,15.36)
  BOTTOM w0.203: HDA27.25 172.54,15.51 v1(172.68,15.36)
AUD_HP1_JACK_L1: length 21.4
  TOP w0.254: 183.73,17.93 EC2907.1 185.12,17.93 R2907.1 ; 183.73,17.93 183.75,17.91 183.75,16.08 182.94,15.27 182.94,15.21 182.93,15.2 182.93,14.78 182.94,14.77 182.94,14.63 182.77,14.47 v1(182.77,14.35) ; 183.73,17.93 R2919.1 ; R2908.2 170.68,13.41 170.68,12.38 v1(170.88,12.19)
  L3 w0.254: v1(182.77,14.35) 181.87,13.45 180.12,13.45 179.78,13.79 176.14,13.79 174.73,12.38 173.41,12.38 172.81,11.78 171.29,11.78 v1(170.88,12.19)
  BOTTOM w0.254: v1(182.77,14.35) 182.79,14.37 v2(183.33,14.37)
AUD_HP1_JACK_R: length 14.3
  TOP w0.254: v1(180.06,15.02) v2(180.57,14.64) 181.05,14.64 181.35,14.95 181.35,15.62 R2921.2 ; v1(172.44,14.69) 172.44,14.58 172.31,14.45 R2910.1 172.79,13.99 R2912.2
  L3 w0.254: v1(180.06,15.02) 179.91,15.02 179.84,14.95 175.68,14.95 175.06,14.33 172.8,14.33 v1(172.44,14.69)
  BOTTOM w0.203: v1(172.44,14.69) 172.44,14.75 172.14,15.04 HDA27.26
AUD_HP1_JACK_R1: length 20.4
  TOP w0.203: EC2908.1 183.22,20.32 ; 182.33,20.31 R2920.1
  TOP w0.254: v1(172.8,12.52) 172.6,13 R2910.2 ; v1(182.13,14.48) 182.13,14.54 182.42,14.84 182.42,15.41 182.43,15.42 182.43,15.51 183.17,16.25 183.17,16.35 183.17,16.36 183.17,19.2 183.43,19.46 183.43,19.5 R2909.1 182.34,20.32 182.33,20.31
  L3 w0.254: v1(172.8,12.52) 173.24,12.96 174.42,12.96 175.9,14.45 180.1,14.45 180.12,14.46 180.87,14.46 180.97,14.57 181.4,14.57 181.48,14.48 v1(182.13,14.48)
  BOTTOM w0.254: v2(181.96,13.91) 181.96,14.32 v1(182.13,14.48)
AUD_PC_BEEP: length 2.3
  BOTTOM w0.203: HDA27.11 175.04,20.53 175.35,20.84
  BOTTOM w0.254: v2(176.75,21.43) 175.94,21.43 C2735.2 175.58,21.07 175.58,21.07 175.35,20.84
AUD_PC_BEEP_C: length 13.8
  TOP w0.254: v1(173.98,29.32) 173.98,27.83 v2(174.24,27.58) v1(176.8,25.02)
  BOTTOM w0.254: C2739.1 173.25,30.53 D2703.3 173.32,30.61 174,30.61 R2735.1 174.2,29.54 v1(173.98,29.32) ; C2735.1 175.82,22.29 175.82,23.3 176.8,24.28 v1(176.8,25.02)
AUD_PORTA_L_R_B: length 6.4
  TOP w0.254: AFTP6606.1 187.08,19.56 185.73,19.56 R2907.2 185.58,20.01 186.04,20.47 v1(186.04,20.55)
  BOTTOM w0.254: v1(186.04,20.55) IOBD1.19
AUD_PORTA_R_R_B: length 7.1
  TOP w0.254: 185.4,20.68 184.44,21.64 R2909.2 ; 185.4,20.68 185.4,20.7 AFTP6608.1 ; 185.4,20.68 v1(185.4,20.55)
  BOTTOM w0.254: IOBD1.20 188.97,20.05 188.9,19.98 185.85,19.98 185.4,20.43 v1(185.4,20.55)
AUD_SENSE: length 10.8
  TOP w0.254: v1(182.92,19.67) 182.66,19.41 182.66,16.57 181.91,15.82 v1(181.91,15.08)
  BOTTOM w0.254: v1(182.92,19.67) 182.92,20.73 182.87,20.85 v2(182.58,20.97) 180.99,20.97 R2711.1 ; R2923.2 182.62,16.13 C2902.1 181.68,15.29 181.9,15.08 v1(181.91,15.08)
AUD_SENSE_A: length 7
  BOTTOM w0.127: HDA27.12 175.11,20.13 175.94,20.96 177,20.96 R2710.2
  BOTTOM w0.254: R2710.2 177.68,21.54 178.22,21.01 178.81,21.01 179.39,21.59 v2(179.63,21.59) 179.86,21.36 R2711.2
AUD_SPK_L+: length 16.8
  TOP w1.016: 155.76,18.04 156.12,18.4 156.2,18.4 156.98,19.18 157.05,19.11 157.19,19.11 157.45,19.36 159.52,19.36 161.09,20.93 v4(164.98,20.93)
  BOTTOM w0.203: HDA27.35 168.08,18.53 167.76,18.85 166.25,18.85 v2(165.9,19.2) 164.98,20.12 v4(164.98,20.93)
AUD_SPK_L+_C:
  vias: v4(154.82,13.49)
AUD_SPK_L-: length 19.6
  TOP w1.016: 154.64,18.8 155.51,19.67 155.67,19.67 156.63,20.63 158.99,20.63 160.57,22.2 165.54,22.2 v4(166.48,21.26)
  BOTTOM w0.203: HDA27.36 168.24,18.93 167.97,19.2 166.63,19.2 165.92,19.91 v2(165.92,20.58) 165.92,20.7 v4(166.48,21.26)
AUD_SPK_L-_C:
  vias: v4(153.6,13.46)
AUD_SPK_R+: length 11.4
  TOP w1.016: v4(167.9,20.09) 167.9,19.47 166.81,18.37 v2(162.16,18.37) 160.61,16.82 160.33,16.82
  BOTTOM w0.203: HDA27.38 168.54,19.73 168.18,20.09 v4(167.9,20.09)
AUD_SPK_R+_C:
  vias: v4(159.11,13.46)
AUD_SPK_R-: length 12.9
  TOP w1.016: 157.97,18.09 160.05,18.09 161.47,19.51 161.5,19.51 161.64,19.64 v2(164.27,19.64) 166.28,19.64 v4(166.63,19.99)
  BOTTOM w0.203: HDA27.37 168.41,19.33 168.2,19.53 167.09,19.53 v4(166.63,19.99)
AUD_SPK_R-_C:
  vias: v4(156.8,13.92)
AUD_VREF: length 3.2
  TOP w0.254: v2(173.69,15.81) v1(174.2,15.42) 174.4,15.42 175.27,14.55 C2702.2
  BOTTOM w0.203: v1(174.2,15.42) 174.15,15.42 173.74,15.83 HDA27.22
AUX_ON: length 5.2
  BOTTOM w0.102: KBC24.3 159.66,48.23 159.37,48.52 158.77,48.52 158.57,48.72 v2(158.57,48.76) 157.72,48.76 156.18,50.3 R2491.2
B71_TP: length 3.7
  BOTTOM w0.102: CPU1.B71 96.69,97.15 TP2312.1
BA1_TP: length 5.1
  BOTTOM w0.102: CPU1.BA1 140.13,75.13 140.13,73.36 140.13,73.35 140.13,72.58 140.13,72.58 140.13,72.5 141.08,71.56 TP2305.1
BAT1_LED#: length 30.8
  TOP w0.127: v1(163.06,41.68) 163.79,41.68 v2(163.99,41.48) 164.1,41.36 168.11,41.36 169.01,42.26 170.71,42.26 171.16,41.81 172.15,41.81 173.34,43 174.94,43 175.3,43.36 v1(175.64,43.36)
  L4 w0.127: v1(178.74,40.1) 178.74,40.26 175.64,43.36 v1(175.64,43.36)
  BOTTOM w0.127: v1(178.74,40.1) 178.66,40.1 178.19,39.63 Q2412.4 ; v1(175.64,43.36) 176.19,42.82 RN2405.2 ; v1(163.06,41.68) 162.73,41.35 162.73,40.26 162.52,40.05 162.52,38.9 162.71,38.71 162.71,37.67 162.04,37 161.31,37 161.18,37.13 KBC24.106
BAT2_LED#: length 27.4
  TOP w0.127: v1(161.83,39.88) 161.83,40.25 v2(162.42,40.83) 162.69,41.11 169.47,41.11 170.14,41.78 170.51,41.78 171.11,41.18 172.2,41.18 173.52,42.5 v1(175.74,42.5)
  BOTTOM w0.127: v1(161.83,39.88) 161.84,39.88 161.63,40.09 161.63,41.01 162.17,41.55 162.17,42.85 158.86,46.17 KBC24.1 ; Q2412.1 176.89,42.1 RN2405.1 175.99,42.23 175.74,42.47 v1(175.74,42.5)
BAT_AMBER: length 9
  BOTTOM w0.508: R6407.2 v2(171.25,8.82) 172.32,7.75 172.32,3.22 LED1.1
BAT_WHITE: length 2.8
  BOTTOM w0.127: LED1.2 169.4,2.64 R6406.2 167.85,4.19 v2(167.85,4.63)
BATT_WHITE_LED#: length 68.1
  TOP w0.127: v2(176.85,38.75) 176.57,38.75 v1(176.34,38.52)
  L3 w0.127: v1(176.34,38.52) 176.34,35.13 177.58,33.89 177.58,32.3 177.57,32.29 177.57,28.06 177.78,27.85 177.78,25.4 178.81,24.37 179.56,24.37 180.12,23.81 188.69,23.81 188.91,24.02 192.3,24.02 192.5,23.82 192.62,23.82 193.29,23.16 193.29,21.21 193.3,21.2 193.3,16.18 193.29,16.17 193.29,11.98 188.43,7.13 186.89,7.13 186.88,7.11 v1(171.62,7.11)
  BOTTOM w0.127: v1(176.34,38.52) 176.49,38.52 176.89,38.92 Q2412.6 ; v1(171.62,7.11) 171.02,7.71 R6404.1
BATT_WHITE_LED_R#: length 4.5
  BOTTOM w0.127: v2(170.3,9.94) 169.83,9.47 Q6401.D 169.83,8.13 R6404.2 170.16,7.24 169.5,6.58 Q6404.B
BB70_TP: length 5
  BOTTOM w0.102: CPU1.BB70 97.05,72.39 TP2307.1
BEEP: length 21.3
  TOP w0.254: v2(172.75,29.63) v1(173.14,29.23)
  L3 w0.254: v1(170.32,41.33) 171.55,41.33 172.67,40.21 172.67,39.2 174.52,37.35 174.52,34.95 176.17,33.3 176.17,32.88 176.08,32.8 176.08,32.67 173.14,29.73 v1(173.14,29.23)
  BOTTOM w0.203: 171.53,41.13 KBC24.45
  BOTTOM w0.254: 171.53,41.13 170.52,41.13 v1(170.32,41.33) ; v1(173.14,29.23) 172.91,29 172.91,27.58 R2734.1
BKLT_CTRL: length 21.6
  TOP w0.114: RN5502.8 107.61,181.87 108,182.27 108,182.32 108.46,182.77 108.46,183.5 108.1,183.86 105.36,183.86 102.97,181.47 102.97,180.64 v2(101.51,179.17) 101.15,178.82 101.15,177.84 100.96,177.65 R5524.1 102.52,177.24 D5503.3 103.4,178.12 103.4,178.79 105.15,180.53 105.89,180.53 106.15,180.27 RN5501.3
BKLT_IN_EC: length 11.2
  TOP w0.102: v2(169.51,34.33) 169.51,33.81 v1(169.47,33.77)
  L3 w0.102: v1(169.47,33.77) 170.92,32.32 v1(170.92,28.44)
  BOTTOM w0.102: v1(169.47,33.77) 170.42,32.83 170.42,32.15 KBC24.67 ; v1(170.92,28.44) 170.43,28.44 169.7,29.17 R2435.2 169.36,29.21 168.66,29.21 R2436.1
BLON_OUT: length 320.2
  TOP w0.127: R2497.2 151.03,39.74 150.4,39.12 150.16,38.52 v1(150.19,38.45) ; v1(102.19,178.06) 102.19,178.19 v2(104.86,180.85) 104.96,180.96 106.18,180.96 107.05,180.08 RN5503.4
  L3 w0.127: v1(150.19,38.45) 149.79,38.45 149.1,37.76 149.1,36.22 150.64,34.68 150.64,30.19 152.39,28.43 152.39,26.89 153.92,25.36 153.92,21.37 153.15,20.6 153.15,16.49 152.35,15.68 152.35,14.63 152.68,14.3 153.54,14.3 154.15,13.69 154.15,13.39 156.36,11.17 156.85,11.17 160.65,7.38 165.43,7.38 166.48,8.43 179.15,8.43 183.26,12.53 187.71,12.53 191.93,16.75 191.93,20.63 v1(190.77,21.79)
  L4 w0.127: v1(190.77,21.79) 190.46,22.1 190.46,29.65 190.75,29.94 190.75,31.05 195.88,36.18 195.88,88.47 189.28,95.07 184.14,95.07 183.56,94.49 183.17,94.1 181.03,94.1 180.44,94.1 179.76,93.42 176.84,93.42 176.72,93.31 167.02,93.31 161.47,98.86 161.47,99.17 159.59,101.05 159.54,101.05 156.62,103.98 156.62,105.53 156.56,105.58 154.4,107.74 147.24,107.74 146.95,107.46 145.81,107.46 144.47,108.79 144.47,123.45 145.08,124.07 145.08,141.25 137.39,148.94 137.03,148.94 128.23,157.74 128.23,159.22 124,163.44 124,172.28 122.11,174.17 122.11,176.25 118.58,179.78 103.92,179.78 v1(102.19,178.06)
BLON_OUT_C: length 22.2
  TOP w0.102: RN5502.7 106.68,181.39 107.07,181 v2(108.08,181) 108.17,181 108.44,181.27 v1(108.44,182.01) ; RN5503.1 107.05,178.5 106.72,178.16 106.72,177.34 107.11,176.95 107.11,174.89 106.81,174.59 105.73,174.59 105.25,174.11 105.19,174.07 104.99,174.07 v1(104.91,173.99)
  L3 w0.102: v1(108.44,182.01) 108.44,181.61 108.07,181.24 108.07,180.2 105.11,177.24 105.11,174.53 104.91,174.33 v1(104.91,173.99)
  BOTTOM w0.102: LCD1.21 104.65,175.04 104.91,174.78 v1(104.91,173.99)
BLUETOOTH_EN: length 147.7
  TOP w0.102: v1(103.09,155.32) 103.09,154.72 v2(101.88,153.51) 101.58,153.21 97.62,153.21 R6113.1 ; v1(151.2,86.25) 151.2,86.44 151.96,87.19 R2002.2
  L3 w0.102: v1(103.09,155.32) 108.8,155.32 109.62,154.5 114.75,154.5 115.36,153.89 117.19,153.89 118.41,152.66 125.26,152.66 125.87,153.28 131.71,153.28 132.79,152.2 132.79,149.45 135.26,146.98 137.01,146.98 138.93,145.06 138.93,137.72 138.93,137.4 142.21,134.12 142.21,126.75 142.21,126.26 142.21,123.73 142.21,123.72 142.21,122.32 142.21,119.69 142.44,119.46 142.65,119.25 142.65,107.51 142.77,107.39 142.77,106.62 143.25,106.13 143.25,104.83 143.08,104.65 142.73,104.65 142.37,104.3 142.37,103.56 142.6,103.32 143.54,103.32 143.66,103.44 147.66,103.44 149.3,101.8 152.86,101.8 155.39,99.28 155.39,98.59 154.96,98.16 154.96,97.07 157.59,94.43 157.59,88.52 158.25,87.87 158.25,86.05 158.08,85.88 158.08,84.74 157.18,83.84 153.61,83.84 v1(151.2,86.25)
  BOTTOM w0.089: 140.42,86.12 139.95,85.89 139.71,85.89 139.62,85.92 139.39,85.92 CPU1.AB2
  BOTTOM w0.102: 140.42,86.12 141.5,86.12 141.82,86.44 144.41,86.44 145,85.86 146.49,85.86 146.59,85.76 146.88,85.76 146.9,85.78 147.32,85.78 147.57,85.52 147.57,85.08 147.84,84.81 147.93,84.81 147.94,84.8 149.75,84.8 149.88,84.93 149.9,84.93 150.27,85.3 150.27,85.38 150.68,85.8 150.75,85.8 v1(151.2,86.25)
BLUETOOTH_EN_NGFF: length 3
  TOP w0.102: R6113.2 96.08,153.09 v1(95.87,153.3) 95.75,153.42 AFTP6107.1
  BOTTOM w0.102: v1(95.87,153.3) WLAN1.54
BOARD_ID: length 4.3
  BOTTOM w0.102: KBC24.111 156.39,39.13 155.86,38.6 v2(155.8,38.6) 155.66,38.46 155.65,38.46 155.39,38.21 155.39,38.2 155.32,38.12 R2474.1
BOARD_ID2: length 16.1
  TOP w0.102: v1(147.14,85.34) 148.63,85.34 150.25,83.72 150.61,83.72 150.91,84.02 R2008.1 152.29,84.8 R2005.2
  BOTTOM w0.089: CPU1.AB3 139.18,85.75 139.59,85.75 139.68,85.71 140.13,85.71 140.49,85.93
  BOTTOM w0.102: v1(147.14,85.34) 146.72,85.34 146.41,85.65 144.69,85.65 v2(144.52,85.82) 144.08,86.25 141.9,86.25 141.58,85.93 140.49,85.93
BOARD_ID_R: length 3.6
  BOTTOM w0.102: R2443.2 v2(152.88,35.62) 152.88,36.47 C2408.1 152.9,36.54 R2444.1 152.68,37.54 R2474.2
BOOST_MON: length 228.8
  TOP w0.254: R2423.2 153.3,36.87 153.84,37.4 155.91,37.4 156.42,37.91 156.42,38.92 158.61,41.11 158.66,41.11 158.96,41.41 158.96,41.83 v2(158.37,42.42) 158.09,42.7 158.09,48.59 158.1,48.59 158.19,48.81 158.19,49.23 159.77,50.81 162.43,50.81 162.68,50.56 168.62,50.56 169.38,51.31 172.77,51.31 173.27,50.81 173.95,50.81 174.24,51.1 175.62,51.1 v1(176.29,50.43)
  L3 w0.254: v1(176.29,50.43) 176.29,53.19 181.59,58.49 181.59,66.15 184.63,69.19 184.63,71.31 186,72.69 186,79.53 183.64,81.89 183.02,81.89 181.87,83.03 181.87,83.49 179.57,85.79 179.47,85.79 174.44,90.81 167.61,90.81 166.42,92.01 166.42,93.3 166.47,93.35 166.47,96.82 163.86,99.42 163.86,102.88 162.81,103.94 161.94,103.94 156.81,109.07 156.53,109.07 155.08,110.53 154.98,110.53 153.3,112.21 153.3,114.35 153.72,114.77 153.72,118.64 152.2,120.16 151.81,120.16 149.63,122.34 149.63,125.87 149.7,125.94 149.7,126.85 149.06,127.48 149.06,127.91 149.12,127.96 149.12,135.46 147.46,137.12 146.58,137.12 144.14,139.56 144.14,147.08 144.33,147.27 144.33,148.47 141.74,151.06 141.74,153.51 136.47,158.78 126.65,158.78 122.64,162.79 122.64,167.15 123.93,168.44 123.93,172.2 123.05,173.08 121.21,173.08 120.91,173.38 120.91,174.3 122.27,175.66 122.27,176.77 124.23,178.72 125.39,178.72 126.82,180.15 130.97,180.15 131.57,180.75 138.3,180.75 v1(138.37,180.68)
  BOTTOM w0.127: v1(138.37,180.68) 138.31,180.68 138.1,180.89 PR4476.1 138.89,181.31 PC4403.1
BP_D: length 2.3
  TOP w0.127: PR4415.2 120.84,181.49 121.04,181.28 v2(121.29,181.28) 121.32,181.28 122.16,182.12 PQ4402.D
BP_G: length 3.9
  TOP w0.127: PC4433.2 127.19,182.38 126.13,182.38 PR4478.1 125.94,181.28 v2(125.92,181.26) 125.83,181.17 PQ4402.G
BREATH_LED#: length 5.7
  TOP w0.102: v1(168.15,34.49) 168.15,34.39 169.95,32.59 TP2402.1
  BOTTOM w0.102: KBC24.70 169.26,32.8 168.64,33.42 168.64,34.01 v1(168.15,34.49)
BT+: length 62.1
  TOP w0.254: PR4481.1 135.08,167.41 137.74,167.41 PQ4416.2 138.5,168.77 v1(138.06,169.22)
  TOP w0.508: BATT1.2 165.14,185.8 ; BATT1.2 163.36,185.8 ; BATT1.2 164.25,184.91 ; BATT1.1 167.14,185.8 ; BATT1.1 165.36,185.8 ; BATT1.1 166.25,184.91
  L3 w0.508: BATT1.2 164.25,186.69 ; BATT1.2 165.14,185.8 ; BATT1.2 163.36,185.8 ; BATT1.2 164.25,184.91 ; 165.36,185.8 BATT1.1 ; BATT1.1 167.14,185.8 ; BATT1.1 166.25,184.91 ; BATT1.1 166.25,186.69
  L3 w0.635: v4(145.19,172.09) 142.2,172.09 139.33,169.22 v1(138.06,169.22)
  L4 w0.762: v4(126.7,173.47) 126.7,177.9 129.27,180.47 136.28,180.47 137.37,179.38 138.37,179.38 138.89,178.85 138.89,176.47 138.74,176.31 138.74,169.9 v1(138.06,169.22)
  BOTTOM w0.508: 165.36,185.8 BATT1.1 ; BATT1.1 167.14,185.8 ; BATT1.1 166.25,184.91 ; BATT1.1 166.25,186.69 ; 164.25,184.91 BATT1.2 ; BATT1.2 165.14,185.8 ; BATT1.2 163.36,185.8 ; BATT1.2 164.25,186.69
  vias: v2(152.18,177.85) v2(166.12,178.11) v4(148.19,174.12) v4(148.27,173.15) v4(149.21,174.07) v4(149.41,173) v4(150.25,174.12)
CAMERA_DET#: length 174.6
  TOP w0.127: v2(158.11,98.7) 158.66,98.7 v1(158.66,98.69) ; R5501.2 116.75,176.05 v1(116.47,176.32)
  L3 w0.127: v1(158.66,98.69) 158.66,96.69 160.72,94.63 160.72,93 161.39,92.33 161.39,91.4 161.07,91.07 161.06,91.05 161.06,80.33 160.93,80.2 160.93,77.77 160.84,77.7 160.78,77.64 160.77,77.64 160.19,77.06 160.19,76.19 160.24,76.13 160.24,74.49 160.05,74.29 160.05,67.95 160.32,67.68 160.32,66.95 159.82,66.45 156.7,66.45 156.35,66.68 155.02,66.68 154.74,66.41 149,66.41 148.16,65.57 v1(147.17,65.57) 146.86,65.26 146.35,65.26 145.25,66.35 145.25,67.09 143.7,68.65 143.62,68.65 143.4,68.87 142.81,69.12 142.79,69.09 141,69.09 140.08,68.17 140.08,67.25 139.68,66.85 139.08,66.85 138.51,67.42 v1(138.51,70)
  L4 w0.127: v1(158.66,98.69) 158.64,98.69 152.49,104.84 148.82,104.84 148.06,105.6 145.54,105.6 142.97,108.17 142.97,124.43 143.58,125.04 143.58,140.63 137,147.21 135.17,147.21 134.45,147.94 134.45,149.51 132.48,151.47 131.63,151.47 131.54,151.56 131.54,151.56 131.28,151.82 131.1,152.01 131.1,152.56 127.04,156.62 127.04,158.29 119.36,165.96 119.36,173.83 117.96,175.24 117.56,175.24 v1(116.47,176.32)
  BOTTOM w0.089: CPU1.BA7 135.99,75.64 135.85,75.49 135.85,74.83 136.11,74.57 136.38,74.57 136.71,74.24 136.71,72.56 137.52,71.75 137.84,71.75 138.51,71.08 v1(138.51,70)
  BOTTOM w0.127: v1(147.17,65.57) 147.23,65.51 147.23,64.31 146.99,64.07 R2004.1
CAMERA_DET#_R: length 7.8
  TOP w0.127: v2(115.32,176.53) 115.45,176.66 v1(115.93,176.66) 115.87,176.6 115.87,175.66 R5501.1
  BOTTOM w0.127: LCD1.33 110.65,176.96 110.9,177.22 115.37,177.22 v1(115.93,176.66)
CAP_LED: length 34.4
  TOP w0.305: AFTP6532.1 193.87,118.74 193.33,119.28 KB1.4
  TOP w0.381: v1(191.67,119.13) 191.68,119.13 191.83,119.28 KB1.4
  L4 w0.508: v1(183.22,96.8) 190.57,96.8 192.2,98.43 192.2,118.4 191.68,118.92 191.68,119.13 v1(191.67,119.13)
  BOTTOM w0.508: R6506.2 183.17,96.69 183.22,96.74 v1(183.22,96.8)
CAP_LED#: length 7.4
  BOTTOM w0.127: Q2414.S 158.58,26.91 R2489.2 158.58,29.09 v2(159.53,30.04) 160.06,30.57 KBC24.93
CAP_LED#_S: length 104.2
  L4 w0.127: v1(188.74,91.83) 188.74,91.08 191.29,88.52 191.29,71.44 189.84,69.98 189.84,66.57 193.39,63.01 193.39,37.09 192.43,36.13 192.43,35.53 186.93,30.03 186.65,30.03 184.09,27.47 181.22,27.47 181.04,27.64 168.84,27.64 168.07,26.87 166.92,26.87 166.87,26.93 160.06,26.93 157.7,24.57 v1(157.7,24.28)
  BOTTOM w0.127: Q2414.D 156.65,23.49 v2(157.47,23.49) 157.7,23.72 v1(157.7,24.28) ; v1(188.74,91.83) 188.21,92.37 188.21,92.48 187.75,92.94 R6508.1
CAP_LED_Q: length 2.6
  BOTTOM w0.508: Q6502.C 182.3,95.15 R6506.1 181.44,96.17 v2(181.31,96.04)
CAP_LED_R#: length 2.9
  BOTTOM w0.127: Q6502.B v2(184.35,92.76) 184.59,92.76 184.77,92.94 R6508.2
CASA0B: length 30
  L3 w0.102: 168.65,145.77 168.57,145.7 168.57,145.15 168.8,144.93 v1(168.8,144.49)
  L3 w0.203: v1(161.4,161.81) 161.83,162.24 162.37,162.24 162.74,161.87 162.74,161.68 163.07,161.35 163.47,161.35 163.81,161.01 163.81,159.93 164.32,159.42 166.33,159.42 166.55,159.2 166.55,158.73 166.35,158.53 164.84,158.53 164.68,158.36 164.68,158.05 164.88,157.85 166.32,157.85 166.55,157.63 166.55,157.31 166.35,157.1 165.48,157.1 165.27,156.9 165.27,156.6 165.48,156.39 166.35,156.39 166.55,156.19 166.55,151.42 168.23,149.74 168.23,148.12 168.65,147.7 168.65,145.77
  BOTTOM w0.229: v1(161.4,161.81) 161.01,162.2 VRAM1.L3 ; v1(168.8,144.49) 168.78,144.49 168.78,144.47 169.17,144.47 GPU1.G19
CASA1B: length 27.1
  L3 w0.203: v1(172.5,145.11) 172.5,145.43 172.3,145.63 172.3,151.88 171.33,152.84 171.33,161.5 172.17,162.34 173.06,162.34 173.27,162.13 173.27,161.32 173.47,161.11 173.78,161.11 173.98,161.32 173.98,162.13 174.18,162.34 176.34,162.34 176.54,162.14 177.44,162.14 v1(177.9,162.6)
  BOTTOM w0.229: GPU1.G16 v1(172.5,145.11) ; VRAM2.G3 v1(177.9,162.6)
CBN: length 2.2
  BOTTOM w0.203: v2(171.02,15.34) 171.02,15.44 171.34,15.76 HDA27.28
  BOTTOM w0.254: v2(171.02,15.34) 171.02,14.64 C2708.2
CBP: length 6.6
  BOTTOM w0.203: 170.26,15.85 170.54,16.13 HDA27.30
  BOTTOM w0.254: C2708.1 169.81,12.97 168.8,13.98 v2(168.8,14.22) 168.8,15.49 169.17,15.85 170.26,15.85
CCG4_I2C_INT#: length 3.8
  BOTTOM w0.203: KBC24.32 171.26,48.05 173.14,49.93 TP2406.1
CCLIM: length 4.5
  TOP w0.254: PR4402.2 138.53,177.63 137.87,177.63 137.67,177.84 v1(137.67,177.91) 137.49,178.09 137.17,178.09 137.02,178.24 136.73,178.24 PR4404.1
  BOTTOM w0.203: 136.46,177.33 PU4401.11
  BOTTOM w0.254: v1(137.67,177.91) 137.05,177.91 v2(136.97,177.84) 136.46,177.33
CFG0: length 11.7
  BOTTOM w0.089: CPU1.E68 101.96,96.03 101.96,96.49 101.86,96.59 101.86,96.81 102.01,96.96 102.01,97.39 102.04,97.47 102.04,97.47 102.04,97.99 101.78,98.24 101.78,98.24 101.55,98.47 101.55,98.47 101.54,98.48 101.54,98.91
  BOTTOM w0.114: TP618.1 96.71,102.26 96.71,100.66 98,99.37 101.09,99.37 101.54,98.91
CFG1: length 8.8
  BOTTOM w0.089: 101,98.99 101.28,98.71 101.28,98.49 101.86,97.91 101.86,97.5 101.86,97.5 101.83,97.42 101.83,97.21 101.6,96.98 CPU1.B67
  BOTTOM w0.114: 101,98.99 98.09,98.99 96.2,100.88 TP619.1
CFG2: length 9.2
  BOTTOM w0.089: CPU1.D65 102.56,96.05 102.56,96.69 102.51,96.83 102.51,97.1 102.53,97.16 102.53,97.42 102.51,97.48 102.51,98.6 102.1,99.02 102.08,99.02
  BOTTOM w0.114: 102.08,99.02 101.43,99.67 98.69,99.67 TP620.1
CFG3: length 14
  BOTTOM w0.114: CPU1.D67 101.6,96.53 101.25,96.88 101.25,97.74 100.63,98.36 95.66,98.36 92.08,94.78 TP621.1 91.83,94.19 R604.1
CFG4: length 12.2
  BOTTOM w0.089: CPU1.E70 99.56,95.31 99.31,95.56 99.04,95.56 98.52,96.08 96.97,96.08
  BOTTOM w0.114: R605.1 91.55,90.96 91.55,92.56 TP622.1 93.3,94.31 94.69,94.31 95.35,94.97 95.4,94.97 95.86,94.97 96.97,96.08
CFG5: length 8.6
  BOTTOM w0.114: TP623.1 94.18,95.45 95.73,95.45 97.1,96.81 99.42,96.81 99.56,96.67 100.13,96.67 CPU1.C68
CFG6: length 6.3
  BOTTOM w0.114: CPU1.D68 99.68,95.84 99.33,96.19 99.06,96.19 98.96,96.29 97.05,96.29 96.86,96.29 95.75,95.18 95.32,95.18 95.01,95.18 TP624.1
CFG7: length 6.1
  BOTTOM w0.114: TP625.1 96.11,97.94 99.78,97.94 99.97,97.75 99.97,97.5 100.17,97.3 100.59,97.3 101.01,96.88 CPU1.C67
CFG8: length 5.7
  BOTTOM w0.089: 98.13,94.62 98.26,94.75 99.57,94.75 CPU1.F71
  BOTTOM w0.114: TP626.1 94.63,93.68 95.52,94.57 98.08,94.57 98.13,94.62
CFG9: length 9.4
  BOTTOM w0.089: CPU1.G69 100.39,93.86 100.11,93.86 99.92,93.8 99.75,93.8 99.62,93.83 99.36,93.83 99.29,93.8 98.76,93.8 98.58,93.63 96.2,93.63
  BOTTOM w0.114: TP627.1 93.23,91.82 93.48,92.07 94.64,92.07 96.19,93.63 96.2,93.63
CFG10: length 7.9
  BOTTOM w0.089: CPU1.F70 99.96,94.95 99.36,94.95 99.35,94.94 98.17,94.94 98.05,94.82 98.04,94.82 97.99,94.77
  BOTTOM w0.114: 97.99,94.77 95.83,94.77 95.43,94.77 94.77,94.11 93.71,94.11 TP628.1
CFG11: length 9.1
  BOTTOM w0.089: CPU1.G68 100.77,94.33 99.73,94.33 99.34,94.5 98.41,94.5 98.33,94.41
  BOTTOM w0.114: TP629.1 93.57,92.33 95.6,94.36 98.28,94.36 98.33,94.41
CFG12: length 9.1
  BOTTOM w0.089: CPU1.H70 99.93,93.16 99.8,93.11 99.08,93.11 98.79,92.82 96.94,92.82 96.9,92.79
  BOTTOM w0.114: 96.9,92.79 95.95,91.84 93.7,91.84 92.48,90.62 TP630.1
CFG13: length 3.8
  BOTTOM w0.114: TP631.1 95.92,93.88 98.48,93.88 98.66,94.06 CPU1.G71
CFG14: length 6.2
  BOTTOM w0.089: CPU1.H69 100.27,93.66 100.07,93.66 99.97,93.62 99.72,93.62 99.59,93.66 99.41,93.66 99.34,93.63 99.33,93.62 98.86,93.62 98.61,93.37 96.23,93.37
  BOTTOM w0.114: TP632.1 95.6,92.75 96.23,93.37
CFG15: length 6.6
  BOTTOM w0.089: 98.36,94.11 98.57,94.32 99.3,94.32 99.54,94.22 99.7,94.06 CPU1.G70
  BOTTOM w0.114: TP633.1 94.37,92.84 95.64,94.11 98.36,94.11
CFG16: length 2.7
  TOP w0.114: v1(103.57,95.39) 104.13,94.83 104.13,94.57 104.47,94.23 TP634.1
  BOTTOM w0.114: CPU1.E63 103.81,95.33 103.62,95.33 v1(103.57,95.39)
CFG17: length 2.8
  TOP w0.114: v1(103.66,94.68) 104.08,94.26 104.08,92.79 TP635.1
  BOTTOM w0.114: CPU1.F63 103.81,94.68 v1(103.66,94.68)
CFG18: length 1.7
  TOP w0.114: v1(101.59,95.06) 101.96,95.43 TP636.1
  BOTTOM w0.114: v1(101.59,95.06) 101.69,94.95 CPU1.E66
CFG19: length 1.5
  TOP w0.114: v1(101.6,94.43) 102.14,93.89 TP637.1
  BOTTOM w0.114: CPU1.F66 101.72,94.3 v1(101.6,94.43)
CFG_RCOMP: length 2
  TOP w0.254: v2(105.71,94.01) 105.61,94.11 v1(105.61,94.56)
  TOP w0.508: R601.2 105.39,94.78 v1(105.61,94.56)
  BOTTOM w0.305: CPU1.E60 105.94,94.89 v1(105.61,94.56)
CHG_AMBER_LED#: length 56.2
  L3 w0.127: v1(183.3,11.22) 183.61,11.53 189.4,11.53 192.4,14.54 192.4,16.54 192.41,16.55 192.41,20.83 192.4,20.84 192.4,21.72 191.45,22.67 187.28,22.67 186.91,22.3 184.17,22.3 183.49,22.98 178.65,22.98 177.26,24.37 177.26,26.9 176.31,27.85 176.31,30.43 177.01,31.13 177.01,32.42 177.09,32.5 177.09,33.69 175.82,34.96 175.82,35.84 175.56,36.09 175.47,36.18 v1(175.47,38.47)
  BOTTOM w0.127: Q2412.3 178.19,40.67 177.91,40.39 176.84,40.39 176.42,39.97 176.42,39.41 v1(175.47,38.47) v2(175.89,38.06) ; R6405.1 182.42,12.09 v1(183.3,11.22)
CHG_AMBER_LED_R#: length 2.3
  BOTTOM w0.127: R6405.2 184.06,12.34 v2(184.2,12.2) 185.02,11.38 Q6403.B
CKEA0: length 30.9
  L3 w0.102: v1(169.07,142.75) 169.41,143.09 169.41,144.89 169.59,145.07 169.59,145.76
  L3 w0.203: v1(161.38,163.43) 162.12,163.43 162.93,162.62 165.46,162.62 165.82,162.26 165.82,162.08 164.79,161.04 164.79,160.75 165,160.54 165.29,160.54 166.38,161.63 166.7,161.63 167.6,160.73 167.6,151.62 169.59,149.63 169.59,145.76
  BOTTOM w0.229: VRAM1.J3 161.37,163.43 v1(161.38,163.43) ; v1(169.07,142.75) GPU1.K20
CKEA1: length 29.3
  L3 w0.102: v1(171.44,143.61) 171.86,144.03 171.86,145.27 171.5,145.63 171.45,145.63
  L3 w0.203: 171.45,145.63 170.97,146.1 170.97,149.15 171.26,149.44 171.26,151.32 170.29,152.29 170.29,162.07 171.7,163.48 176.1,163.48 176.8,164.18 v1(177.92,164.18)
  BOTTOM w0.229: VRAM2.J3 v1(177.92,164.18) ; GPU1.J17 v1(171.44,143.61)
CL_CLK: length 100.7
  TOP w0.14: R6109.1 v1(101.13,155.32) 101.16,155.32 v2(101.63,154.85)
  L3 w0.165: v1(101.13,155.32) 101.59,155.78 108.88,155.78 109.78,154.89 114.91,154.89 115.53,154.28 117.35,154.28 118.57,153.05 125.1,153.05 125.71,153.66 131.87,153.66 133.17,152.36 133.17,151.39 139.32,145.24 139.32,137.56 142.6,134.28 142.6,126.59 142.6,126.59 142.6,126.1 142.6,126.1 142.6,123.89 142.6,123.88 142.6,122.16 142.6,119.85 143.04,119.41 143.04,118.85 143.1,118.79 143.1,106.59 143.47,106.23 143.47,104.5 v1(142.79,103.82)
  BOTTOM w0.089: CPU1.G3 138.89,94.48 139.52,94.48 139.68,94.54 139.83,94.54 140.47,95.18
  BOTTOM w0.178: 142.79,103.26 141.79,102.26 141.79,102.08 141.44,101.74 141.44,96.15 140.47,95.18
  BOTTOM w0.191: v1(142.79,103.82) 142.79,103.26
CL_CLK_R: length 5.9
  TOP w0.14: v2(97.92,154.96) 98.28,155.32 v1(98.35,155.32) R6109.2
  BOTTOM w0.14: v1(98.35,155.32) 97.37,156.3 WLAN1.42
CL_DATA: length 112.5
  TOP w0.14: v2(102.3,155.9) 102.06,156.14 v1(101.15,156.14) R6119.1
  L3 w0.165: v1(150.17,102.34) 149.32,102.34 147.74,103.91 147.15,103.91 143.54,107.53 143.54,118.94 143.46,119.02 143.46,119.59 143.02,120.03 143.02,124.06 143.02,124.06 143.02,125.93 143.02,126.41 143.02,126.42 143.02,134.45 139.74,137.73 139.74,145.42 133.59,151.56 133.59,152.54 132.05,154.08 125.53,154.08 124.92,153.47 118.74,153.47 117.52,154.69 115.7,154.69 115.09,155.31 109.96,155.31 109.06,156.2 101.21,156.2 v1(101.15,156.14)
  BOTTOM w0.089: 140.52,94.76 140.15,94.61 139.91,94.36 139.72,94.36 139.56,94.3 139.36,94.3 CPU1.G2
  BOTTOM w0.178: 140.52,94.76 140.89,95.12 143.25,95.12 143.3,95.07
  BOTTOM w0.191: 143.3,95.07 147.9,95.07 150.09,97.26 150.43,97.26 150.71,97.54 150.71,99.26 150.48,99.5 150.48,102.03 v1(150.17,102.34)
CL_DATA_R: length 6.2
  TOP w0.14: R6119.2 v1(98.35,156.14) v2(97.29,156.14)
  BOTTOM w0.14: v1(98.35,156.14) 97.69,156.8 WLAN1.40
CL_RST#: length 114.8
  TOP w0.127: EC1805.1 140.34,93.34 141.07,94.07 v1(141.07,94.69)
  TOP w0.14: R6108.1 v1(101.13,156.95) 101.68,156.95 v2(101.82,157.09)
  L3 w0.165: v1(149.97,102.94) 149.31,102.94 147.91,104.33 147.33,104.33 144.44,107.22 144.42,107.22 143.96,107.68 143.96,119.11 143.88,119.2 143.88,119.76 143.44,120.2 143.44,124.23 143.44,124.23 143.44,125.75 143.44,125.75 143.44,126.24 143.44,134.62 140.15,137.91 140.15,145.59 134.01,151.73 134.01,152.71 132.22,154.5 125.36,154.5 124.75,153.89 118.92,153.89 117.69,155.11 115.87,155.11 115.26,155.72 110.13,155.72 108.9,156.95 v1(101.13,156.95)
  BOTTOM w0.089: v1(141.07,94.69) 140.83,94.46 140.27,94.46 139.91,94.1 CPU1.G1
  BOTTOM w0.178: 141.17,94.79 v1(141.07,94.69)
  BOTTOM w0.191: 141.17,94.79 146.37,94.79 146.53,94.63 148.09,94.63 150.27,96.82 150.62,96.82 151.16,97.36 151.16,99.46 150.92,99.7 150.92,102.26 150.24,102.94 v1(149.97,102.94)
CL_RST#_R: length 5.7
  TOP w0.14: v2(97.85,157.25) 98.15,156.95 v1(98.35,156.95) R6108.2
  BOTTOM w0.14: WLAN1.38 98,157.3 v1(98.35,156.95)
CLK_TP_SIO: length 30.1
  TOP w0.191: v1(149.45,24.59) 149.85,24.98 150.91,24.98 152.62,26.68 156.72,26.68 158.66,28.62 v2(158.66,28.87) 159.32,29.53 163.11,29.53 164.34,30.76 165.74,30.76 v1(165.85,30.65)
  L3 w0.165: v1(149.4,18.88) 149.4,24.53 v1(149.45,24.59)
  BOTTOM w0.191: RN6504.4 150.04,19.56 149.4,18.92 v1(149.4,18.88) 149.4,18.83 150.09,18.14 EC6503.1 150.14,18.12 150.29,17.97 RN6503.1 ; v1(165.85,30.65) 165.89,30.65 166.06,30.81 KBC24.78
CLKA0: length 33.8
  TOP w0.203: R8101.2 151.26,163.01 151.27,163.01 151.34,163.08 153.51,163.08 153.84,163.41 v1(154.19,163.41)
  L3 w0.102: 161.83,145.93 161.84,145.93 161.84,145.86 162.34,145.36 162.6,145.23 162.96,144.88 162.96,144.36 163.41,143.91 163.78,143.91 163.91,144.03 163.91,144.22 v1(164.18,144.49)
  L3 w0.165: v1(154.19,163.41) 153.43,163.41 152.44,163.05 152.41,163.04 151.59,162.22 151.29,162.22 151.16,162.35 151.16,162.5 151.03,162.63 150.87,162.63 150.72,162.48 150.72,161.98 150.9,159.72 150.9,157.5 158.21,150.19 158.71,150.19 160.19,148.72 160.79,146.97 161.83,145.93
  BOTTOM w0.203: VRAM1.J12 v1(154.19,163.41) ; GPU1.H26 164.17,144.47 164.17,144.49 v1(164.18,144.49)
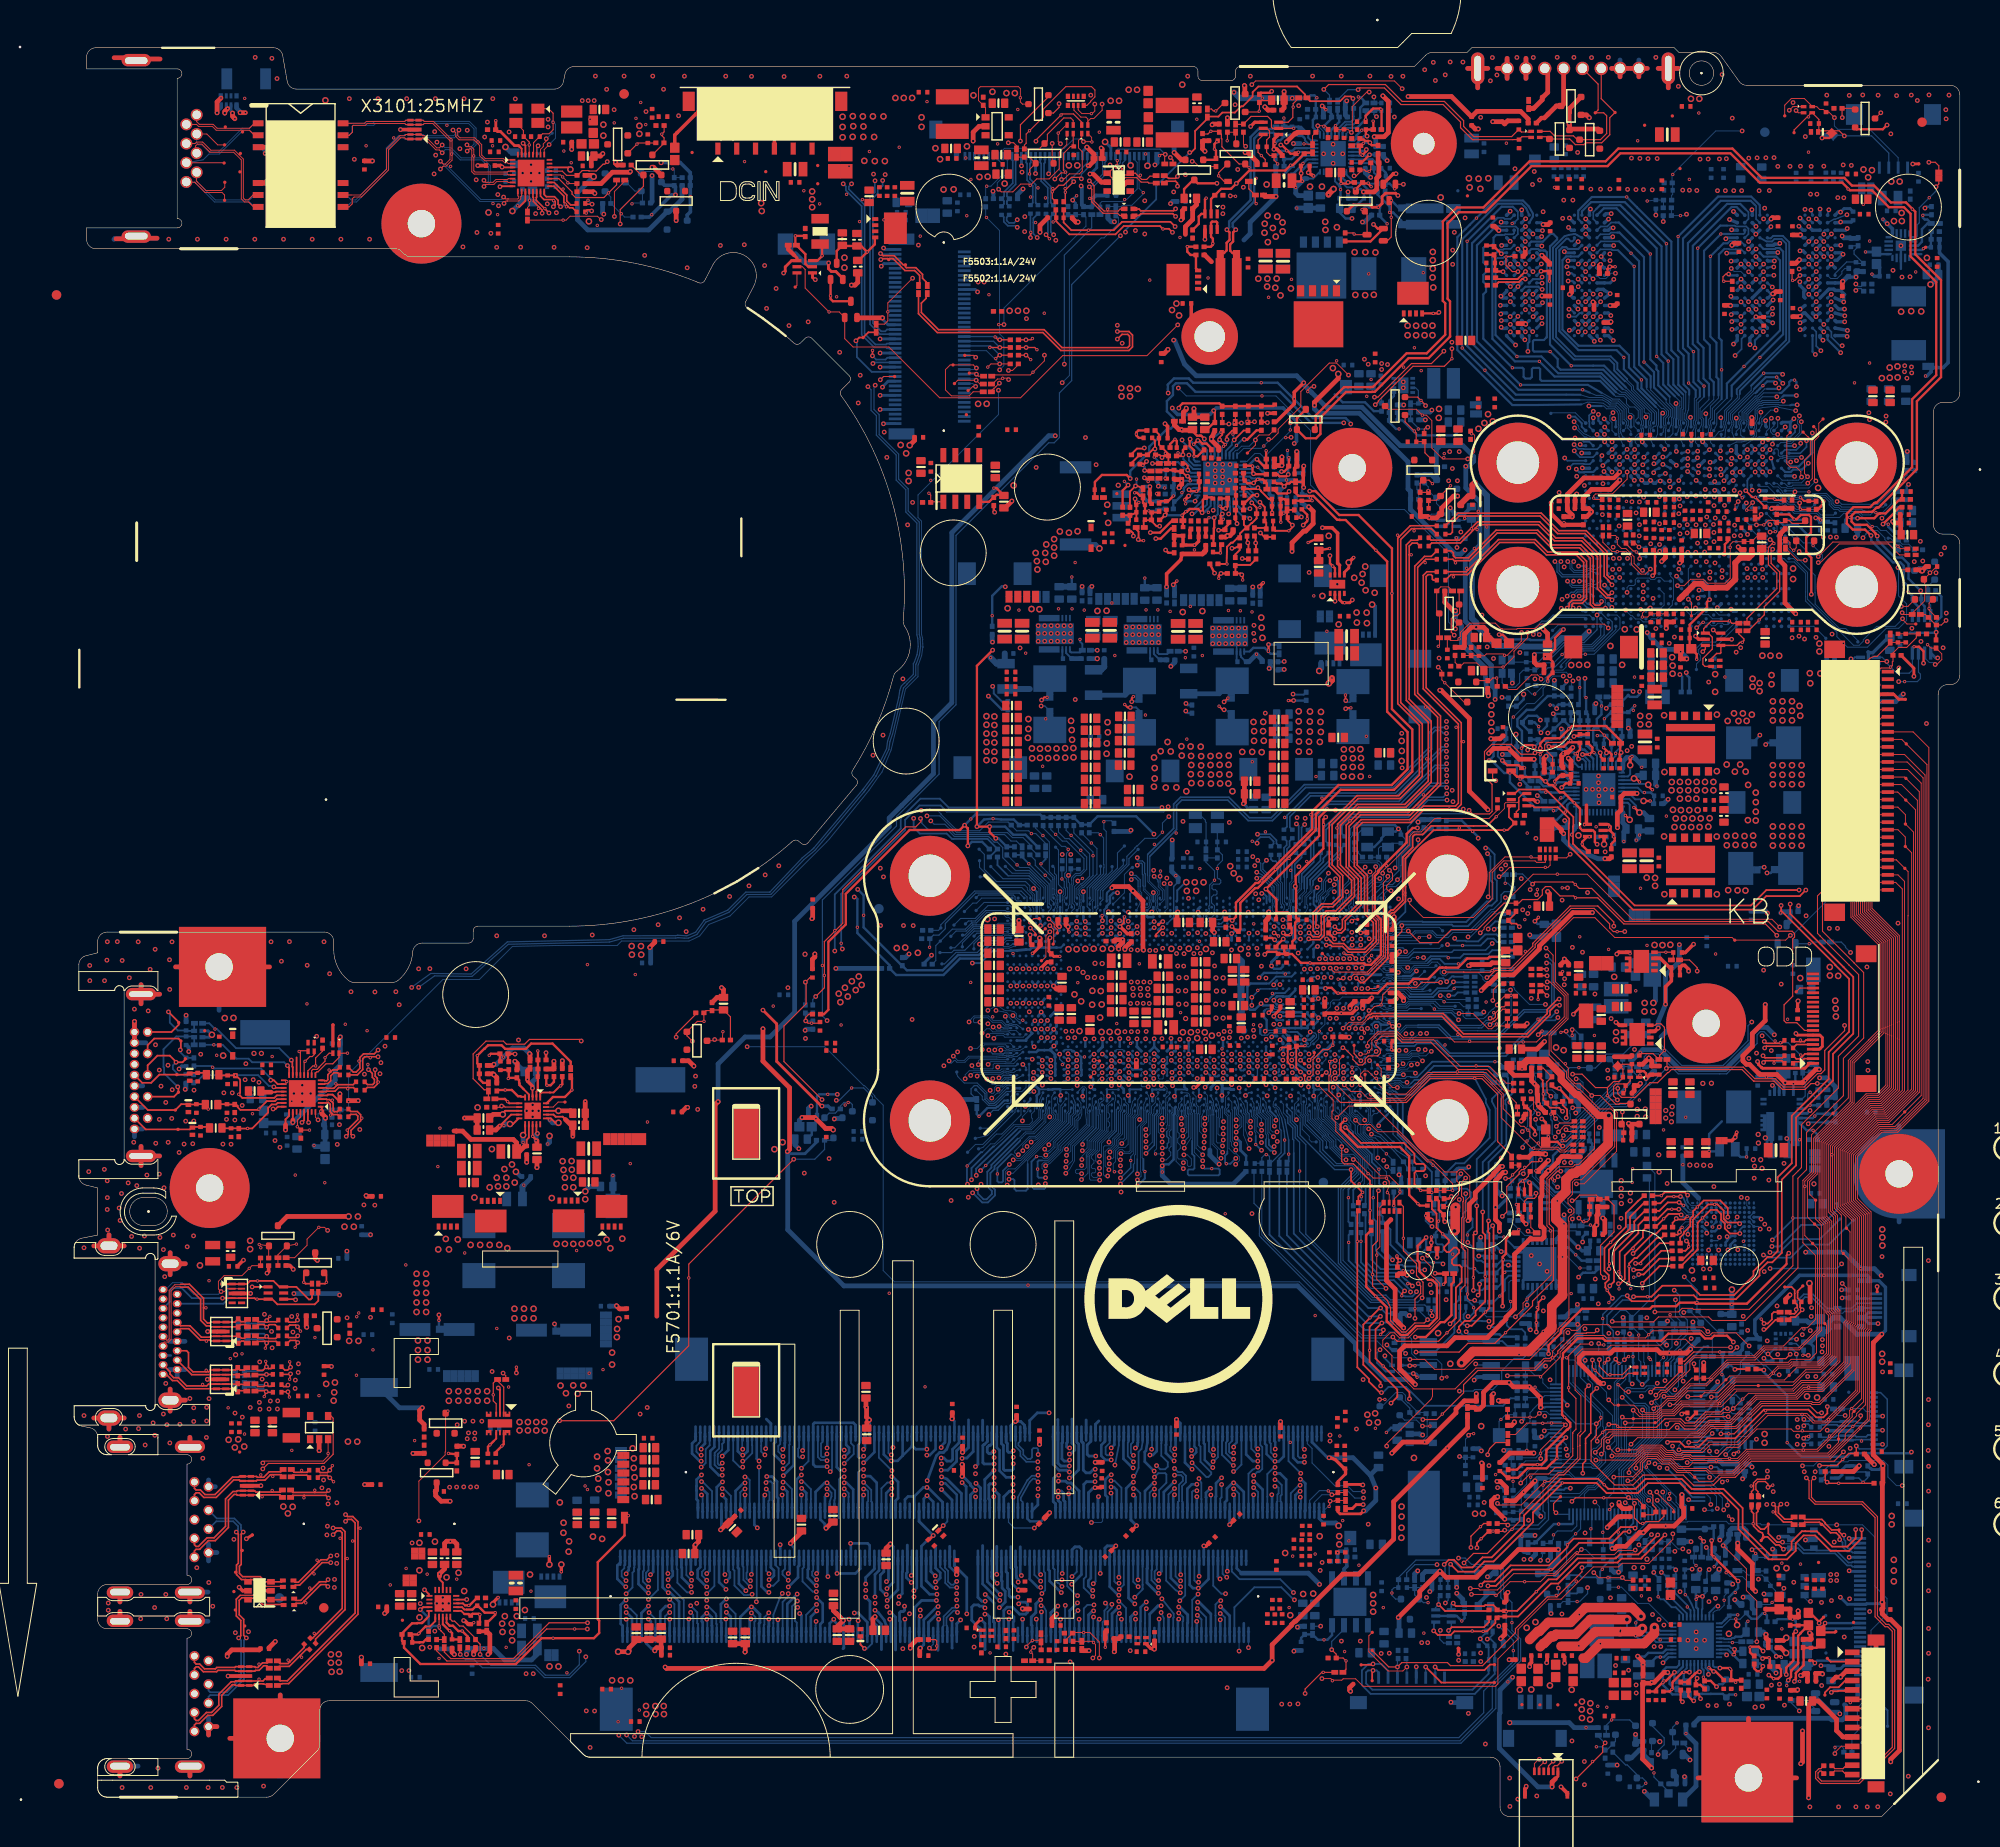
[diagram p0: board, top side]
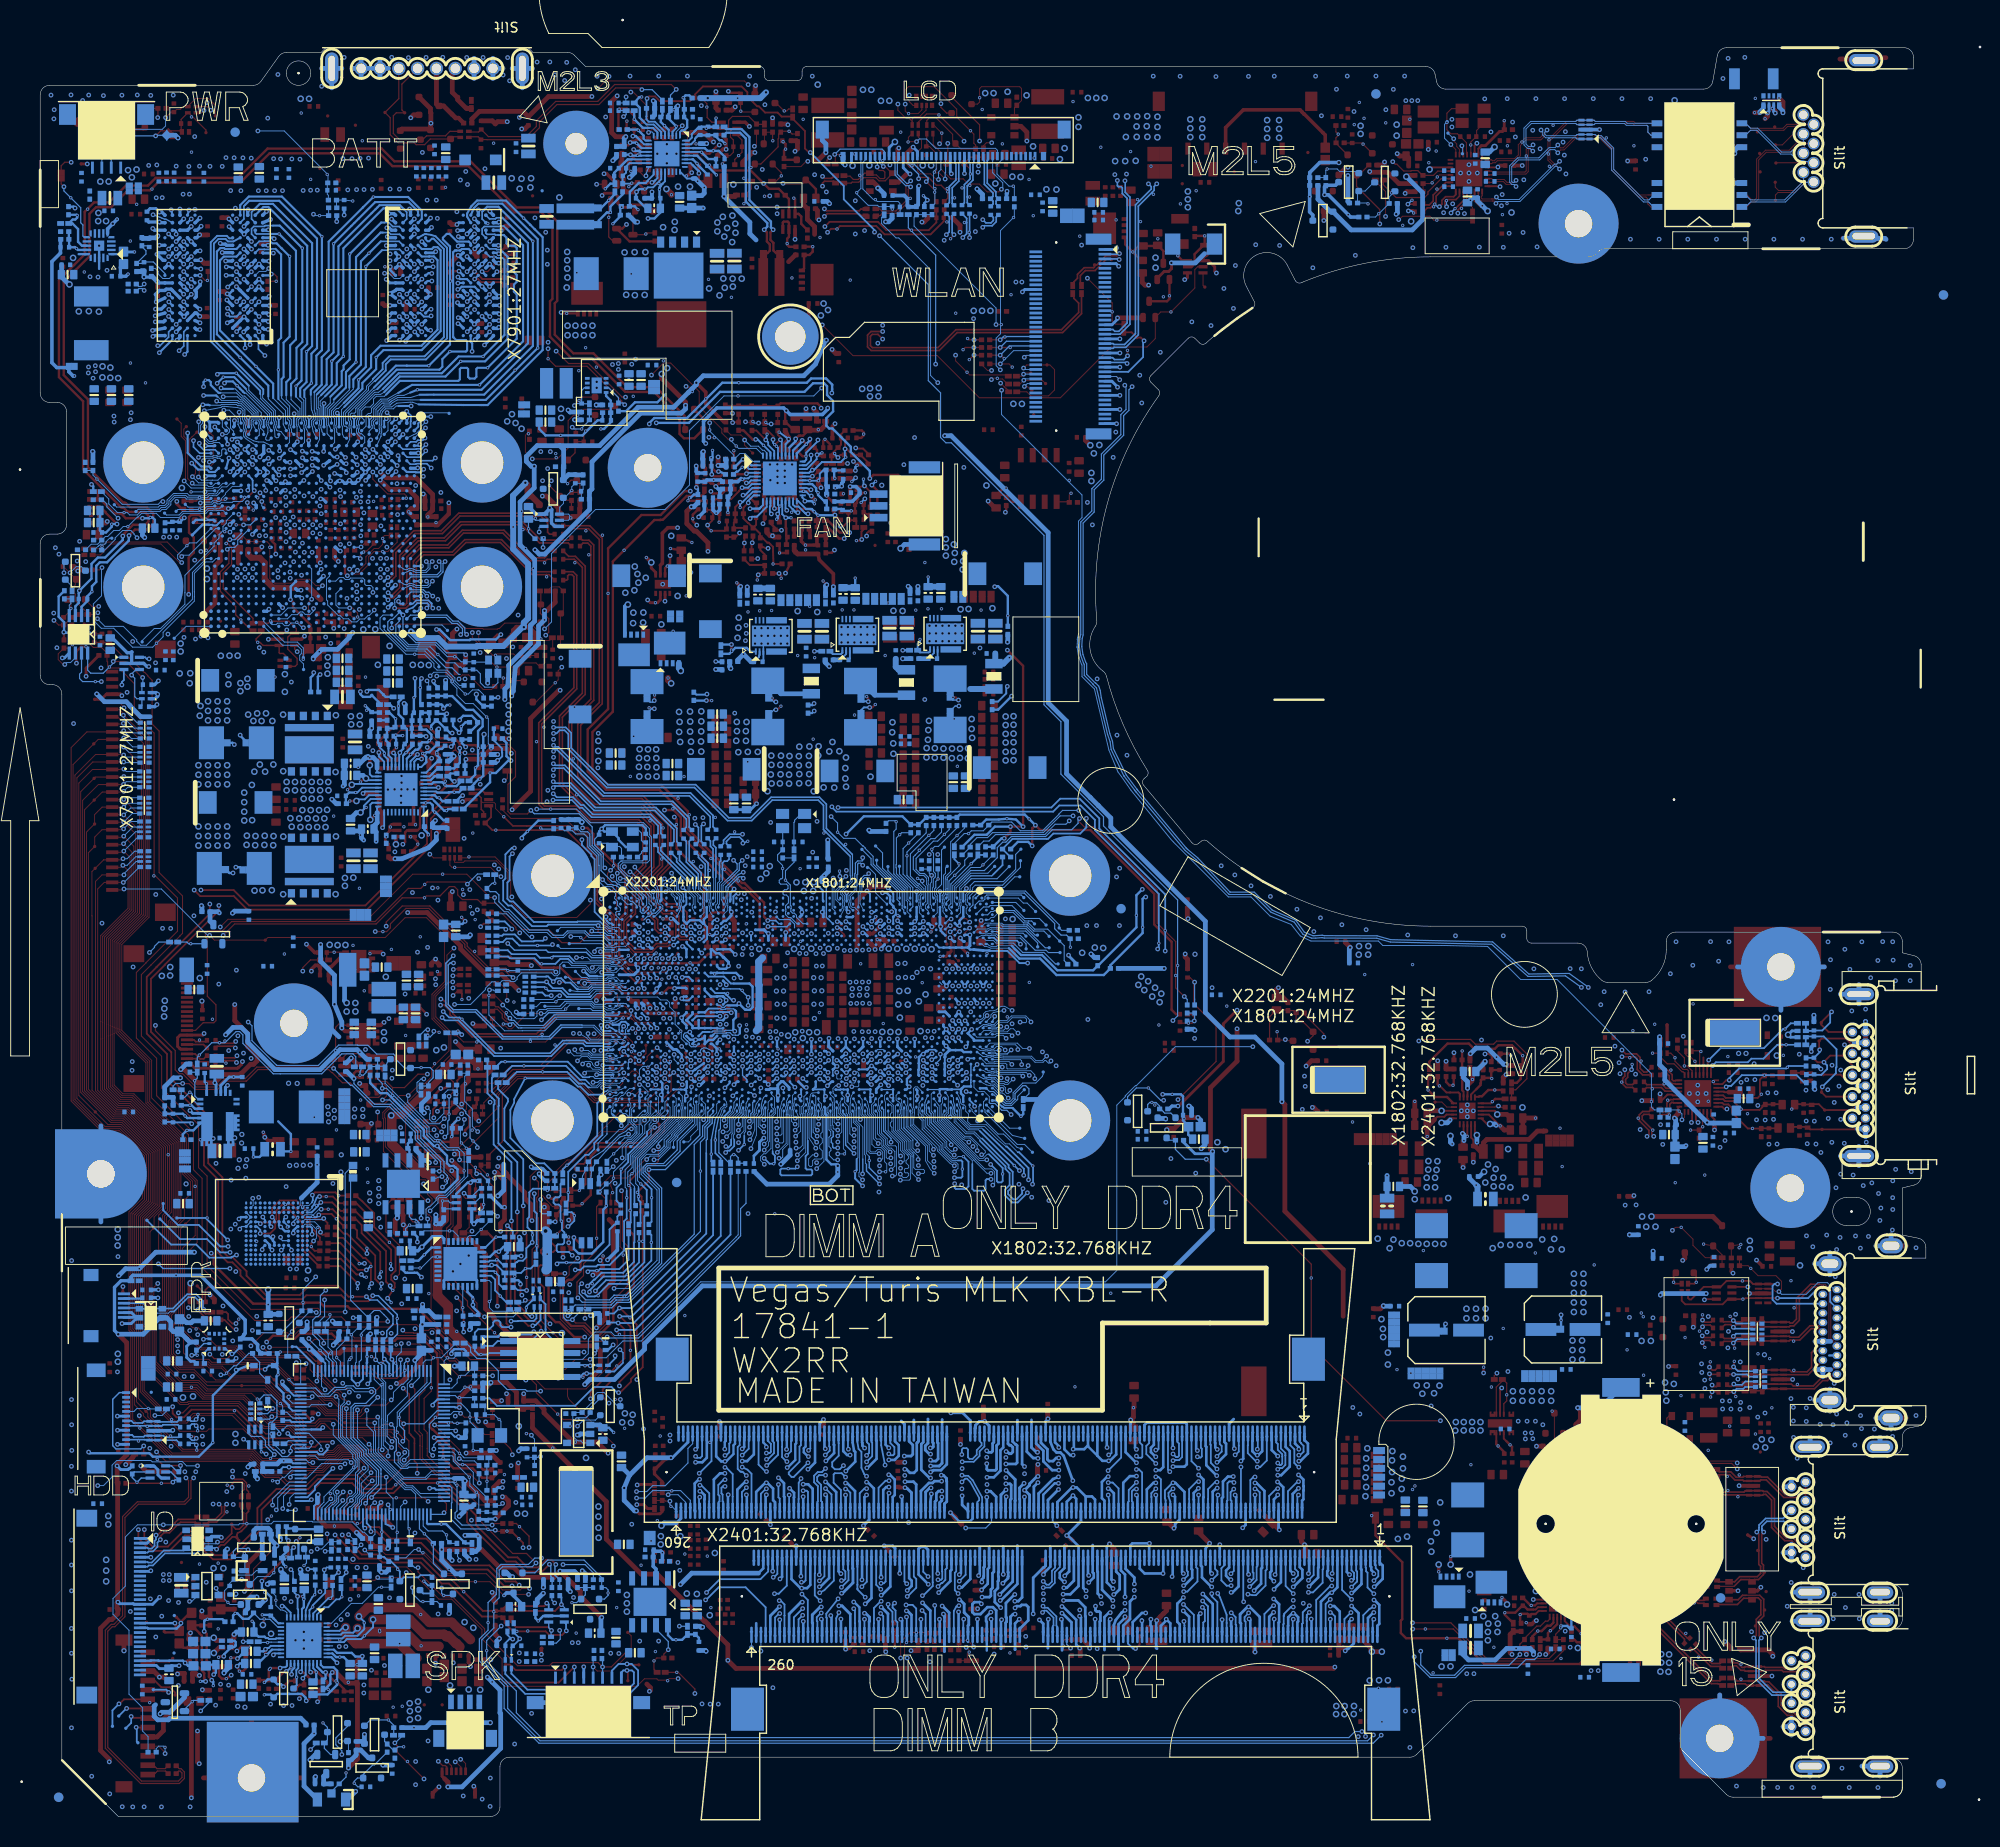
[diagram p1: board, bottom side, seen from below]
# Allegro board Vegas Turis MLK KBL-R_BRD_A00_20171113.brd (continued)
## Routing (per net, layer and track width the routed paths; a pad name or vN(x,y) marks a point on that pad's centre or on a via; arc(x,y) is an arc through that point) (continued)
CLKA0B: length 34.4
  TOP w0.203: R8102.2 151.17,163.41 153.37,163.41 154.16,164.21 v1(154.2,164.21)
  L3 w0.102: v1(164.2,143.7) 163.33,143.7 162.75,144.28 162.75,144.79 162.48,145.06 162.22,145.19 161.69,145.72 161.63,145.72 161.62,145.73
  L3 w0.165: 161.62,145.73 160.54,146.81 160.23,147.68 159.93,148.56 158.59,149.9 158.09,149.9 150.61,157.38 150.61,159.71 150.42,161.97 150.42,162.6 150.75,162.92 151.47,162.92 151.6,162.8 151.76,162.8 152.25,163.29 152.33,163.32 152.34,163.32 153.37,163.71 153.7,163.71 v1(154.2,164.21)
  BOTTOM w0.203: VRAM1.J11 v1(154.2,164.21) ; v1(164.2,143.7) GPU1.H25
CLKA1: length 33.4
  L3 w0.165: v1(177.78,145.28) 177.9,145.41 177.9,146.08 178.95,147.13 180.16,147.13 181.46,148.42 181.46,149.47 181.01,149.92 180.85,149.92 179.96,150.81 179.96,152.85 181.92,154.81 183.34,154.81 185.05,156.52 185.05,158.78 185.88,159.6 185.88,163.79 185.75,163.91 185.43,163.91 185.1,163.58 v1(185.1,163.39)
  L4 w0.165: v1(189.3,162.2) 189.14,162.37 186.98,162.37 185.7,163.65 185.35,163.65 v1(185.1,163.39)
  BOTTOM w0.127: R8103.2 189.86,162.39 189.49,162.39 v1(189.3,162.2)
  BOTTOM w0.203: v1(177.78,145.28) 177.74,145.32 177.56,145.32 177.36,145.12 177.36,144.94 GPU1.G9 ; VRAM2.J12 185.55,163.75 185.55,163.57 185.33,163.35 185.15,163.34 v1(185.1,163.39)
CLKA1B: length 34
  L3 w0.102: 178.2,145.52 178.2,145.16 v1(177.79,144.48)
  L3 w0.165: 178.2,145.52 178.2,145.96 179.07,146.83 180.28,146.83 181.75,148.3 181.75,149.59 181.13,150.21 180.97,150.21 180.25,150.93 180.25,152.73 182.04,154.51 183.47,154.51 185.35,156.39 185.35,158.66 186.17,159.48 186.17,163.91 185.87,164.21 v1(185.1,164.21)
  L4 w0.165: v1(185.1,164.21) 185.37,163.94 185.82,163.94 187.1,162.66 189.08,162.66 v1(189.31,162.88)
  BOTTOM w0.127: v1(189.31,162.88) 189.57,162.62 189.88,162.62 R8104.2
  BOTTOM w0.203: GPU1.H9 v1(177.79,144.48) ; v1(185.1,164.21) VRAM2.J11
CLKREQ_PCIE#1: length 181.7
  TOP w0.102: v1(89.09,163.5) 86.45,160.87 v2(86.45,159.92) 86.45,158.97 86.09,158.61 R6112.2 ; RN1812.6 159.01,73.3 158.89,73.43 158.33,73.43 158.07,73.17 158.07,73.13 v1(157.7,72.76)
  L3 w0.102: v1(89.09,163.5) 89.39,163.81 109.32,163.81 117.22,155.91 118.02,155.91 119.25,154.68 124.13,154.68 124.74,155.3 134.21,155.3 136.32,153.18 136.32,150.84 141.15,146 141.15,138.32 144.44,135.03 144.44,125.83 144.43,125.83 144.43,124.65 144.44,124.64 144.44,120.99 145.54,119.89 145.54,117.12 145.17,116.76 145.17,107.82 146.95,106.04 150.53,106.04 157.2,99.38 157.2,99.37 157.6,98.96 157.6,97.87 157.46,97.73 157.46,96.9 160.03,94.34 160.03,92.71 160.69,92.04 160.69,91.68 160.36,91.35 160.36,83.63 160.35,83.62 160.35,80.61 160.23,80.49 160.23,78.09 159.49,77.35 157.51,75.37 157.51,74.69 157.9,74.3 157.9,73.55 157.92,73.53 157.92,72.97 v1(157.7,72.76) 157.47,72.76 157.28,72.95 156.31,72.95 156.3,72.94 154.66,72.94 154.03,72.32 152.28,72.32 149.54,75.05 149.49,75.05 147.44,77.1 142.13,77.1 142.07,77.05 139.45,77.05 138.48,78.02 137.71,78.02 136.86,78.87 136.51,78.87 136.06,78.43 v1(135.78,78.43)
  BOTTOM w0.102: v1(135.78,78.43) 135.91,78.43 CPU1.AT7
CLKREQ_PCIE#2: length 218.5
  TOP w0.102: v1(157.49,73.35) 157.85,73.71 159.22,73.71 RN1812.5 ; R3105.1 v2(51.96,169.67) 52.28,169.67 52.69,170.09 55.6,170.09 55.96,169.73 v1(56.01,169.73)
  L3 w0.102: 157.49,73.35 157.29,73.15 156.23,73.15 156.2,73.18 154.8,73.18 154.75,73.23 151.94,73.23 149.71,75.46 149.66,75.46 147.6,77.52 141.5,77.52 140.45,78.57 138.17,78.57 137.33,79.41 136.06,79.41 135.96,79.51 135.6,79.51 135.35,79.26 135.35,78.91 v1(134.87,78.43) ; 157.49,73.35 157.49,73.48 156.97,74 156.97,75.12 159.29,77.44 160.03,78.17 160.03,80.58 160.14,80.7 160.14,91.23 159.82,91.55 159.82,94.25 157.26,96.82 157.26,97.81 157.4,97.96 157.4,98.88 156.99,99.29 156.99,99.29 150.45,105.84 146.87,105.84 145.02,107.69 144.85,107.85 144.85,119.35 144.67,119.53 144.67,120.21 144.23,120.65 144.23,124.56 144.23,124.56 144.23,125.91 144.23,125.91 144.23,134.95 140.95,138.24 140.95,145.92 136.07,150.79 136.07,153.14 134.12,155.09 124.83,155.09 124.22,154.48 119.16,154.48 117.94,155.7 117.05,155.7 113.55,159.2 v1(101.18,159.2) ; 157.49,73.35 v1(157.49,73.35)
  L4 w0.102: v1(56.01,169.73) 56.4,169.73 57.17,170.5 70.92,170.5 79.98,161.45 93.04,161.45 95.28,159.2 v1(101.18,159.2)
  BOTTOM w0.102: CPU1.AT8 135,78.43 v1(134.87,78.43)
CLKREQ_PCIE#3: length 34
  TOP w0.102: v1(133.95,79.08) 133.95,79.01 133.56,78.62 133.56,78.26 133.81,78.01 133.89,78.01 135.77,76.13 141.44,76.13 143.98,78.67 149.68,78.67 151.63,76.71 151.63,74.27 154.88,71.02 v2(155.07,71.02) 155.17,70.93 157.56,70.93 157.87,70.62 158.43,70.62 158.53,70.73 RN1813.4
  BOTTOM w0.102: CPU1.AT10 134.28,78.75 v1(133.95,79.08)
CLKREQ_PCIE#4: length 31.2
  TOP w0.102: RN1813.3 158.92,71.4 158.34,70.83 157.99,70.83 157.68,71.13 155.83,71.13 154.67,72.29 154.67,72.74 v2(154.45,72.95) 154.05,73.36 153.7,73.36 151.84,75.22 151.84,76.8 149.76,78.87 143.89,78.87 141.36,76.33 137.46,76.33 136.73,77.06 135.65,77.06 v1(134.95,77.76)
  BOTTOM w0.102: v1(134.95,77.76) 134.98,77.76 CPU1.AU8
CLKREQ_PCIE#5: length 28.1
  TOP w0.102: v1(158.23,72.38) 158.1,72.25 v2(158.1,71.82) 158.15,71.77 158.56,71.77 159,72.22 RN1812.8
  L3 w0.102: v1(135.77,77.75) 136.33,77.2 137.99,77.2 138.62,76.56 142.27,76.56 142.33,76.62 147.24,76.62 152.11,71.75 154.5,71.75 154.52,71.74 155.54,71.74 155.76,71.96 157,71.96 157.18,71.78 157.63,71.78 v1(158.23,72.38)
  BOTTOM w0.102: CPU1.AU7 136.11,78.1 v1(135.77,77.75)
CLKREQ_PEG#0: length 97
  TOP w0.102: RN1812.7 158.73,72.8 158.54,72.99 v1(158.5,72.99) ; v1(144.93,122.16) 145.32,121.77 R7943.2 145.32,120.81 v2(145.63,120.5) 147.68,118.45 Q7903.D
  L3 w0.102: v1(134.87,79.73) 134.44,79.3 134.44,77.82 134.52,77.74 134.52,77.58 134.77,77.33 135.06,77.33 136.19,76.2 139.97,76.2 144.51,71.66 145.28,71.34 147.01,71.34 147.21,71.53 155.62,71.53 155.72,71.63 157.04,71.63 157.1,71.57 157.78,71.57 158.08,71.88 158.34,71.88 158.66,72.2 158.66,72.84 v1(158.5,72.99) 158.4,73.09 158.4,73.33 158.1,73.64 158.1,74.38 157.71,74.77 157.71,75.28 159.69,77.27 160.43,78.01 160.43,80.41 160.56,80.54 160.56,91.27 160.9,91.6 160.9,92.13 160.23,92.8 160.23,94.42 157.66,96.99 157.66,97.64 157.81,97.79 157.81,99.05 157.4,99.46 157.4,99.46 150.61,106.24 147.04,106.24 145.38,107.9 145.38,116.67 145.74,117.03 145.74,119.97 144.93,120.78 v1(144.93,122.16)
  BOTTOM w0.102: v1(134.87,79.73) 134.54,79.4 CPU1.AR10
CLKRUN#_R: length 39.4
  TOP w0.191: R1818.1 155.71,78.56 156.04,78.23 156.04,77.85 156.05,77.83 156.1,76.81 v2(156.1,76.81) 156.1,76.16 156.42,75.84 R1819.1 156.46,75.68 156.81,75.33 157.76,75.33 v1(158.14,74.95)
  L3 w0.165: v1(133.78,77.51) 133.78,76.63 134.17,76.23 135.17,76.23 135.78,75.62 139.24,75.62 143.8,71.06 144.68,70.7 150.51,70.7 150.64,70.83 153.52,70.83 153.71,70.64 154.13,70.64 154.64,71.15 155.78,71.15 155.88,71.24 156.88,71.24 156.94,71.19 157.58,71.19 157.97,70.8 158.36,70.8 159.05,71.49 159.05,74.4 158.5,74.95 v1(158.14,74.95)
  BOTTOM w0.114: v1(133.78,77.51) 133.64,77.37 CPU1.AW11
CLKTESTA: length 4.6
  TOP w0.191: v1(177.6,140.92) 178.31,140.21 v2(178.63,140.21) 179.66,139.19 C7822.1
  BOTTOM w0.191: v1(177.6,140.92) 177.77,141.09 177.77,142 177.83,142.13 GPU1.K8
CLKTESTA_C: length 2.1
  TOP w0.191: R7821.1 180.78,139.92 v2(180.7,140) 180.6,140.09 C7822.2
CLKTESTB: length 7
  TOP w0.191: v2(183.41,138.95) 183.41,138.96 ; 183.41,138.96 183.33,139.04 v1(183.33,139.62) ; 183.41,138.96 183.46,138.9 C7821.1
  BOTTOM w0.089: GPU1.L7 179.12,141.38 179.94,141.38 180.68,140.64 180.68,140.5 181.08,140.1 181.08,139.97 181.27,139.78 181.53,139.78 181.58,139.83 181.59,139.83 181.6,139.84 182,139.84 182.01,139.83 182.02,139.83 182.15,139.7 183.25,139.7 v1(183.33,139.62)
CLKTESTB_C: length 1.8
  TOP w0.191: v2(183.42,140.19) 183.79,139.82 C7821.2 184.33,139.8 R7820.1
CMP_VIN0: length 5.2
  BOTTOM w0.114: R2470.1 165.51,52.08 166.23,51.37 v2(166.23,51.17) 166.23,48.55 166.46,48.32 KBC24.20
CMP_VIN0_R: length 146
  TOP w0.102: C2613.1 193.78,125.71 C2612.1 194.62,125.69 R2608.2 195.73,125.47
  TOP w0.114: 195.73,125.47 195.73,125.28 194.71,124.26 193.84,124.26 193.25,123.66 R2609.2 193.25,122.79 193.18,122.72 193.18,122.33 192.92,122.07 191.98,122.07 191.07,121.16 191.07,121.13 190.35,120.41 190.35,117.26 188.25,115.15 188.25,100.11 185.77,97.63 185.77,97.42 185.76,97.41 185.76,94.09 189.1,90.74 189.1,90.73 190.13,89.7 190.13,82.73 187.98,80.58 187.98,76.61 184.06,72.69 184.06,68.74 183.15,67.83 183.15,58.32 177.55,52.72 174.04,52.72 173.67,53.09 168.34,53.09 167.81,52.57 163.47,52.57 v1(163.42,52.62) ; v1(153.69,35.44) 154.66,36.4 156.68,36.4 157.35,37.07 157.96,37.07 159.23,38.34 159.23,39.11 159.23,40.82 159.56,41.16 159.56,44.43 158.79,45.21 v2(158.79,45.57) 158.79,48.98 160.02,50.21 161.14,50.21 v1(161.2,50.27)
  L3 w0.102: v1(161.2,50.27) 162.03,51.11 162.03,51.23 v1(163.42,52.62)
  BOTTOM w0.114: R2610.1 167.37,67.62 167.37,54.88 R2470.2 165.43,53.22 164.98,53.67 164.97,53.67 164.87,53.78 164.27,53.78 163.84,53.35 163.84,53.35 163.42,52.93 v1(163.42,52.62) ; R2471.2 153.72,35.47 v1(153.69,35.44)
CMP_VIN1: length 2.7
  BOTTOM w0.102: KBC24.21 166.86,48.2 166.77,48.28 TP2404.1
CMP_VOUT0: length 130.6
  TOP w0.114: v1(163.38,33.13) 163.38,32.89 163.15,32.66 163.15,32.62 v2(163.14,32.62) ; R2612.1 196.69,127.76 R2602.1 197.81,126.64 R2607.2 198.4,126.64 v1(198.89,127.13)
  L3 w0.102: v1(198.89,127.13) 198.23,126.47 198.23,126.1 198.27,126.05 198.27,125.69 198.14,125.56 198.14,123.63 198.43,123.34 198.43,122.53 196.37,120.47 196.37,70.82 197.2,69.99 197.2,60.73 195.63,59.16 195.63,42.44 192.02,38.82 189.01,38.82 v1(188.7,39.13)
  L4 w0.114: v1(188.7,39.13) 188.7,38.35 188.22,37.86 188.22,36.88 183.21,31.87 176.6,31.87 176.39,32.08 173.46,32.08 173.44,32.07 168.98,32.07 168.96,32.08 164.33,32.08 163.38,33.03 v1(163.38,33.13)
  BOTTOM w0.114: KBC24.85 163.26,33 163.38,33.12 v1(163.38,33.13)
CMP_VOUT1_R: length 8.6
  BOTTOM w0.191: R2418.1 158.95,25.65 159.95,25.65 160.18,25.42 161.73,25.42 Q2408.G 162.14,26.04 v2(162.36,26.27) 162.36,26.4 163.07,27.1 R2417.1 163.81,27.59 C2419.1 164.29,28.37 R2420.2
CPU_A16_TP: length 5
  BOTTOM w0.089: CPU1.BB9 134.94,74.99 135.63,74.3 135.63,74.28
  BOTTOM w0.102: TP1902.1 137.53,71.21 136.11,72.63 136.11,73.49 135.63,73.97 135.63,74.28
CPU_D3_TP: length 6.6
  BOTTOM w0.089: CPU1.J4 138.19,92.45 139.18,92.45 139.25,92.37 139.59,92.37 139.68,92.34 139.69,92.33 140.24,92.33 140.5,92.59
  BOTTOM w0.102: TP1803.1 140.67,92.77 140.5,92.59
CPU_D4_TP: length 4.8
  BOTTOM w0.102: CPU1.V1 139.53,88.1 141.63,88.1 141.69,88.04 142.05,87.68 143.29,87.68 TP1804.1
CPU_D5_TP: length 2.8
  TOP w0.102: TP1805.1 138.3,88.01 v1(137.45,88.01)
  BOTTOM w0.102: CPU1.V2 138.5,87.79 138.01,87.79 137.8,88.01 v1(137.45,88.01)
CPU_D6_TP: length 6
  BOTTOM w0.089: CPU1.M1 139.88,91.52 141.64,91.52 141.81,91.69
  BOTTOM w0.102: 141.81,91.69 142.39,92.27 145.05,92.27 TP1806.1
CPU_DP1_CTRL_CLK: length 190.5
  TOP w0.191: v1(23.53,54.92) 23.46,54.98 Q5702.4
  L3 w0.165: v1(23.53,54.92) 24.36,55.74 24.36,60.44 31.36,67.44 31.36,67.54 46.82,83 47.13,83 51.18,83 51.18,83 51.96,83 53.97,80.99 67.97,80.99 69.62,82.64 73.35,82.64 79.94,89.23 79.94,90.18 81.62,91.86 v1(81.62,92.2) ; v1(150.88,94.3) 150.88,94.34 150.04,95.18 136.37,95.18 135.93,94.74 135.73,94.74 134.34,93.34 134.34,93.09 134.09,92.85 134,92.85 v1(132.32,91.16)
  L4 w0.165: v1(116.24,107.32) 117.06,108.14 122.89,108.14 124.37,106.66 128.46,106.66 129.2,107.4 130.93,107.4 136.71,101.63 140.5,101.63 141.39,100.74 141.39,99.05 145.05,95.39 149.83,95.39 150.87,94.35 150.88,94.33 v1(150.88,94.3)
  BOTTOM w0.191: v1(81.62,92.2) 81.5,92.32 v2(81.5,92.81) 81.5,98.05 88.29,104.85 88.29,105.93 89.81,107.45 92.07,107.45 92.72,106.8 115.76,106.8 116.24,107.28 v1(116.24,107.32) ; RN801.3 151.04,94.46 v1(150.88,94.3) ; v1(132.32,91.16) 132.53,91.38 CPU1.L13
CPU_DP1_CTRL_DATA: length 190.2
  TOP w0.191: Q5702.1 v1(18.91,56.29)
  L3 w0.165: v1(80.82,91.99) 80.82,91.69 79.52,90.4 79.52,89.4 73.18,83.06 69.45,83.06 68.03,81.64 53.91,81.64 52.12,83.44 46.19,83.44 21.9,59.14 21.9,58.42 19.77,56.29 v1(18.91,56.29) ; v1(150.24,94.32) 149.83,94.74 143.19,94.74 142.11,93.66 139.85,93.66 138.33,92.14 134.57,92.14 v1(133.61,91.18)
  L4 w0.165: v1(115.58,107.24) 115.93,106.89 116.41,106.89 117.24,107.72 122.72,107.72 124.08,106.35 128.68,106.35 129.32,106.99 130.99,106.99 136.6,101.38 140.39,101.38 141.14,100.63 141.14,98.94 145.11,94.97 149.59,94.97 v1(150.24,94.32)
  BOTTOM w0.191: RN801.4 150.99,95.13 150.24,94.38 v1(150.24,94.32) ; CPU1.L12 133.61,91.21 v1(133.61,91.18) ; v1(80.82,91.99) v2(80.82,94.16) 80.82,98 87.82,105.01 87.82,106.09 89.91,108.18 91.97,108.18 92.91,107.24 v1(115.58,107.24)
CPU_DP1_HPD: length 247.9
  TOP w0.102: v1(141.92,48.58) 143.49,48.58 144.54,47.53 147.71,47.53 148.76,48.57 154.67,48.57 157.67,51.58 157.67,51.86 158.82,53.01 158.82,63.26 158.75,63.33 158.75,63.69 159.01,63.94 159.1,63.94 159.35,64.19 159.35,64.55 158.72,65.18 158.72,65.66 159.19,66.13 159.19,67.42 159.44,67.67 160.15,67.67 163.68,71.19 163.68,74.21 163.74,74.28 163.74,74.74 163.29,75.2 162.06,75.2 159.97,77.29 159.8,77.29 158.56,78.53 158.56,78.65 158.55,79.13 156.72,80.96 156.72,83.05 158.52,84.86 158.52,87.29 157.13,88.67 157.13,91.55 v1(156.38,92.3) ; v1(26.93,62.3) 26.61,62.61 v2(26,62.61) 24.75,61.36 24.75,60.71 23.43,59.39 R5712.1
  L3 w0.102: v1(47.21,82.53) 47.3,82.61 51.02,82.61 53.03,80.6 70.29,80.6 v1(71.51,81.82) ; v1(135.53,91.17) 136.17,91.81 138.7,91.81 140.28,93.4 142.37,93.4 143.32,94.35 149.6,94.35 150.09,93.86 154.13,93.86 154.4,94.13 154.84,94.13 156.38,92.59 v1(156.38,92.3)
  L4 w0.102: v1(26.93,62.3) 26.93,62.59 42.08,77.74 44.11,77.74 45.85,79.49 45.85,80.75 47.21,82.11 v1(47.21,82.53)
  BOTTOM w0.102: CPU1.L9 135.45,91.17 v1(135.53,91.17) ; v1(141.92,48.58) 141.75,48.75 140.22,48.75 138.43,50.54 136.46,50.54 130.18,56.83 87.16,56.83 85.96,58.02 85.96,75.6 85.06,76.5 85.06,76.59 83.98,77.67 83.89,77.67 79.74,81.82 v1(71.51,81.82)
CPU_DP2_CTRL_CLK: length 19.2
  TOP w0.14: v2(134.91,91.77) 135.08,91.6 135.76,91.6 v1(136.18,91.18)
  L3 w0.165: v1(146.68,93.34) 146.63,93.29 145.35,93.29 144.92,92.86 144.22,92.86 144.19,92.89 140.13,92.89 138.83,91.59 136.59,91.59 v1(136.18,91.18)
  BOTTOM w0.191: RN803.4 151.26,93.61 151.13,93.75 149.92,93.75 149.18,93.01 147.91,93.01 147.84,93.08 146.94,93.08 v1(146.68,93.34) ; v1(136.18,91.18) 136.28,91.08 CPU1.N7
CPU_DP2_CTRL_DATA: length 18
  L3 w0.165: v1(136.19,90.19) 136.63,90.63 137.01,90.63 137.07,90.57 138.53,90.57 140.4,92.44 144.01,92.44 144.03,92.41 145.1,92.41 145.36,92.67 v1(145.92,92.67)
  BOTTOM w0.178: 149.72,92.85 149.45,92.57 v2(147.52,92.57) 146.02,92.57 v1(145.92,92.67)
  BOTTOM w0.191: RN803.3 151.19,92.94 150.82,93.31 150.18,93.31 149.72,92.85 ; CPU1.N8 135.78,90.59 v1(136.19,90.19)
CPU_DP2_HPD: length 225.3
  TOP w0.102: v1(136.86,91.16) 138.57,92.87 138.57,95.23 137.93,95.87 137.93,100.08 138.28,100.43 v1(138.28,100.95)
  L3 w0.102: v1(98.21,151.59) 104.79,151.59 105.56,152.36 116.12,152.36 117.09,151.39 117.5,151.39 117.51,151.4 127.83,151.4 133.65,145.59 133.65,140.29 140.3,133.63 140.3,111.45 136.66,107.81 134.02,107.81 133.43,107.23 133.43,104.93 137.06,101.3 137.89,101.3 138.24,100.95 v1(138.28,100.95)
  BOTTOM w0.102: v1(98.21,151.59) 98.21,149.01 89.66,140.46 89.66,138.05 90.03,137.68 90.03,125.65 90.12,125.32 90.17,125.12 90.14,125.07 90.16,124.64 90.18,124.32 90.18,124.25 90.17,124.23 90.04,123.38 89.72,122.49 89.66,122.38 89.66,121.16 88.34,119.83 86.8,113.35 85.84,111.02 85.46,110.51 84.46,109.08 80.26,103.92 79.94,103.57 74.11,97.74 71.71,97.74 69.68,95.71 67.43,94.81 66.46,93.59 65.33,93.05 58.17,93.05 57.7,92.58 51.44,92.58 46.57,92.47 43.05,88.96 39.18,88.96 29.16,78.94 v2(29.16,75.98) 29.16,75.41 28.84,75.1 R5605.2 28.25,74.32 R806.1 ; v1(136.86,91.16) 136.83,91.2 136.55,91.62 CPU1.L7
CPU_POPIRCOMP: length 4.5
  TOP w0.203: v2(130.78,81.95) 130.7,81.87 R412.2 129.85,81.84 129.85,79.59 v1(130.31,79.12)
  BOTTOM w0.254: CPU1.AT16 130.38,79.12 v1(130.31,79.12)
CPVDD: length 6.2
  TOP w0.254: v1(170.03,15.32) 170.03,15.31 169.12,14.4 v2(168.92,14.4) 168.07,13.54 C2705.1 168.06,13.28 C2704.1
  BOTTOM w0.203: 170.94,15.92 HDA27.29
  BOTTOM w0.254: 170.94,15.92 170.33,15.32 v1(170.03,15.32) 170.03,14.69 R2709.2
CPVEE: length 5
  TOP w0.254: v1(171.62,15.33) 170.88,15.33 169.92,14.38 169.82,14.24 169.82,13.58 v2(169.75,13.5) 169.53,13.28 C2709.2
  BOTTOM w0.203: HDA27.27 171.74,15.52 171.62,15.4 v1(171.62,15.33)
CRT_B: length 8.5
  TOP w0.191: EL5602.2 13.85,79.04 C5618.1 ED5601.1 12.16,79.04 11.97,78.85 AFTP5606.1 9.06,78.85 8.19,77.98 7.23,77.98 VGA1.3
CRT_DDCCLK_CON: length 10.4
  TOP w0.191: VGA1.15 10.33,83.38 11.11,84.16 AFTP5608.1 11.11,84.43 v1(10.02,85.52)
  BOTTOM w0.191: v1(10.02,85.52) 10.17,85.37 10.17,84.38 11.01,83.54 C5607.1 11.94,83.5 RN5601.2 12.75,84.27 R5602.2
CRT_DDCCLK_CON_R: length 12.7
  TOP w0.191: U5601.15 23.24,79.64 23.19,79.69 23.19,80.28 v1(23.07,80.39)
  BOTTOM w0.191: v1(23.07,80.39) 21.8,81.66 17.2,81.66 15.17,83.7 v2(14.97,83.7) 14.36,84.3 R5602.1
CRT_DDCDATA_CON: length 13.4
  TOP w0.191: VGA1.12 10.62,76.51 AFTP5609.1 11.08,77.47 v1(11.01,77.55)
  BOTTOM w0.191: v1(11.01,77.55) 9.56,79 9.56,79.59 9.49,79.65 9.49,81.55 10.85,82.91 C5622.1 12.67,82.91 RN5601.1 12.76,82.82 R5603.2
CRT_DDCDATA_CON_R: length 11
  TOP w0.191: U5601.16 22.84,79.6 22.66,79.77 v1(22.66,79.81)
  BOTTOM w0.191: v1(22.66,79.81) 22.31,80.16 18.91,80.16 18.53,80.55 17.25,80.55 15.78,82.02 v2(14.84,82.02) R5603.1
CRT_G: length 8.4
  TOP w0.191: VGA1.2 7.84,75.08 AFTP5607.1 11.37,75.71 ED5603.1 12.16,75.68 12.97,75.68 C5614.1 13.89,75.71 EL5603.2
CRT_HSYNC_CON: length 9.4
  TOP w0.191: AFTP5603.1 11.83,80.48 11.51,80.16 v1(10.83,80.16) 10.83,80.21 10.17,80.87 8.84,80.87 7.81,79.83 VGA1.13
  BOTTOM w0.191: v1(10.83,80.16) 10.49,79.83 10.49,79.44 11.11,78.82 11.82,78.82 C5617.1 11.92,78.82 12.67,78.82 R5612.2
CRT_PCH_HPD: length 3.2
  TOP w0.102: U5601.32 25.64,74.32 v1(25.92,74.04)
  BOTTOM w0.102: R5605.1 26.34,75.1 v2(26.21,74.97) 25.92,74.67 v1(25.92,74.04)
CRT_R: length 8.6
  TOP w0.191: EL5601.2 14.27,73.29 C5619.1 ED5602.1 12.3,73.03 AFTP5605.1 7.6,73.03 VGA1.1
CRT_VSYNC_CON: length 7.7
  TOP w0.191: v1(11.28,81.49) 11.34,81.54 AFTP5602.1 11.09,82.68 8.51,82.68 7.81,81.98 VGA1.14
  BOTTOM w0.191: v1(11.28,81.49) 11.28,81.23 11.86,80.65 C5616.1 11.92,80.63 R5611.2
CSA0B_0: length 32
  L3 w0.203: v1(166.67,143.67) 166.32,144.01 166.32,144.66 167.07,145.41 167.07,146.33 165.82,147.58 165.82,149.26 163.92,151.16 163.92,153.12 163.12,153.92 161.02,153.92 161.02,153.92 160,153.92 157.41,156.51 157.41,164.14 156.08,165.47 155.32,165.47 154.85,165 v1(154.2,165)
  BOTTOM w0.229: GPU1.H22 v1(166.67,143.67) ; VRAM1.G12 v1(154.2,165)
CSA1B_0: length 29.2
  L3 w0.102: 175.19,145.61 175.31,145.49 175.31,144.97 174.94,144.6 v1(174.94,144.36)
  L3 w0.203: 175.19,145.61 175.19,146.4 175.91,147.12 175.91,150.64 175.41,151.14 175.41,153.51 177.07,155.16 178.35,155.16 179.8,156.61 180.27,156.61 182.21,158.55 182.21,164.06 183.09,164.94 183.47,164.94 183.87,164.54 184.63,164.54 v1(185.1,165)
  BOTTOM w0.229: VRAM2.L12 v1(185.1,165) ; v1(174.94,144.36) GPU1.G13
CSI2_COMP: length 2.5
  TOP w0.381: R1501.1 133.29,95.39 v1(133.33,95.43) 133.36,95.4 v2(134.18,95.4)
  BOTTOM w0.305: CPU1.E13 133.12,95.43 v1(133.33,95.43)
DAT_TP_SIO: length 28.9
  TOP w0.191: v1(165.21,30.28) 164.62,30.28 163.43,29.08 159.89,29.08 157.05,26.24 v2(156.9,26.24) 152.8,26.24 151.07,24.51 v1(150.22,24.51)
  L3 w0.165: v1(150.15,18.85) 150.15,19.62 150.07,19.7 150.07,20.78 150.22,20.93 v1(150.22,24.51)
  BOTTOM w0.191: v1(150.15,18.85) 150.26,18.85 ; 150.26,18.85 150.5,18.85 150.92,18.43 EC6501.1 150.94,18.13 RN6503.2 ; 150.26,18.85 150.71,19.3 RN6504.3 ; KBC24.79 165.66,31.17 165.26,30.77 165.26,30.33 v1(165.21,30.28)
DBC_EN_R: length 5.8
  BOTTOM w0.102: R5518.1 96.85,173.17 v2(96.96,173.28) 97.41,173.28 98.69,174.57 98.69,175.57 98.15,176.11 LCD1.8
DBC_PANEL_EN: length 186.8
  TOP w0.102: R2003.2 155.06,76.06 155.06,75.19 v1(155.57,74.68) ; v1(137.42,81.88) 137.42,82.31 138.5,83.39 140.63,83.39 141.26,82.76 146.21,82.76 146.65,82.32 155.38,82.32 155.7,82.64 155.71,82.64 155.99,82.92 156.01,82.92 156.01,82.95 156.04,82.99 156.32,82.99 158.32,84.98 158.32,87.2 156.81,88.71 v1(156.52,88.71)
  L3 w0.102: v1(137.42,81.88) 137.73,82.19 141.05,82.19 141.07,82.16 141.93,82.16 142.02,82.17 144.28,82.17 147.46,78.98 148.21,78.98 150.27,76.92 153.33,76.92 v1(155.57,74.68) ; v1(98.34,153.76) 99.38,154.8 108.53,154.8 109.03,154.3 114.67,154.3 115.28,153.68 117.1,153.68 118.33,152.46 125.34,152.46 125.95,153.07 131.63,153.07 132.58,152.12 132.58,149.37 135.29,146.67 136.7,146.67 138.73,144.64 138.73,137.8 138.73,137.32 142.01,134.03 142.01,126.83 142.01,126.34 142.01,123.64 142.01,123.64 142.01,122.41 142.01,119.61 142.33,119.29 142.33,105.27 142.07,105.01 142.07,103.42 142.54,102.96 143.72,102.96 143.97,103.21 147.61,103.21 149.21,101.6 152.72,101.6 154.47,99.85 154.47,98.89 154.27,98.69 154.27,96.92 156.96,94.23 156.96,89.15 v1(156.52,88.71)
  BOTTOM w0.102: CPU1.AM5 137.42,81.62 v1(137.42,81.88) ; v1(98.34,153.76) 98.78,154.2 98.78,157.13 98.32,157.6 98.32,168.57 v2(96.93,169.95) 96.85,170.04 R5518.2
DC_IN_D: length 4.2
  TOP w0.254: v2(120.28,172.01) 120.15,171.88 PQ4405.3 119.77,170.34 119.49,170.05 119.49,169.28 PR4420.2
DCBATOUT: length 30
  TOP w0.203: PU4503.12 48.32,72.16 48.08,71.93 PC4531.1 48.08,71.25
  TOP w0.508: 40.36,72.86 40.61,72.86 40.63,72.85 41.27,72.85 42.16,71.96 46.65,71.96 47.02,71.6 PC4519.1 47.31,70.68 47.89,71.25 48.08,71.25 ; PR4612.1 117.86,148.4 117.86,149.25 118.16,149.55 v1(118.16,149.68) ; v1(127.69,172.19) 126.52,172.19 PR4459.1
  L4 w0.508: v4(113.02,151.74) 114.29,150.47 117.49,150.47 118.16,149.8 v1(118.16,149.68)
  BOTTOM w0.508: 124.29,167.57 124.95,168.23 124.95,169.45 v1(127.69,172.19) 127.67,172.21 127.67,175.38 PR4477.1
  vias: v2(38.87,73.15) v2(52.36,15.27) v2(60.92,73.81) v2(90.61,182.28) v2(106.36,133.28) v2(119.03,134.62) v2(121.42,178.01) v2(126.91,161.47) v2(142.4,156.11) v2(186.75,70.33) v4(50.51,15.95) v4(51.46,15.94) v4(95.55,182.94) v4(102.16,134.3) v4(102.29,133.43) v4(102.34,132.54) v4(103.17,134.3) v4(103.23,133.35) v4(103.28,135.21) v4(104.12,135.77) v4(104.12,134.88) v4(104.12,134.01) v4(104.73,136.58) v4(105.7,136.45) v4(106.61,136.6) v4(111.25,151.83) v4(111.29,150.95) v4(112.18,151.79) v4(112.19,150.95) v4(125.81,163.45) v4(126.78,163.45) v4(126.75,162.61) v4(127.62,162.49) v4(127.77,163.46) v4(128.18,161.67) v4(141.68,158.46) v4(141.68,157.44) v4(142.58,158.45) v4(142.58,157.43) v4(143.48,158.46) v4(143.48,157.44) v4(144.32,158.46) v4(144.32,157.44) v4(150.58,118.09) v4(150.58,117.15) v4(150.58,116.26) v4(150.59,115.36) v4(190.11,175.06) v4(190.61,174.22) v4(191.02,174.98)
DCBATOUT_LCD:
  vias: v2(94.74,176.28) v4(94.86,177.52)
DDBIA0_0: length 23.1
  L4 w0.203: v1(162.42,143.58) 162.14,143.87 159.59,143.87 157.5,145.96 157.5,146.58 155.94,148.14 155.94,148.59 152.65,151.88 152.65,156.72 153.05,157.13 153.05,158.94 v1(152.58,159.41)
  BOTTOM w0.229: VRAM1.P13 v1(152.58,159.41) ; v1(162.42,143.58) 162.94,144.1 GPU1.H27
DDBIA0_1: length 13.1
  L4 w0.203: v1(161.39,159.41) 162.83,157.97 162.83,157.61 163.04,157.4 163.04,156.71 163.2,156.55 163.2,152.63 162.57,151.99 v1(162.57,148.56)
  BOTTOM w0.229: v1(161.39,159.41) 161.78,159.8 VRAM1.P2 ; GPU1.A27 v1(162.57,148.56)
DDBIA0_2: length 38.4
  BOTTOM w0.102: GPU1.C23 165.72,147.78 165.72,148.88 165.49,149.12 165.27,149.12 165.15,149.24 165.15,149.66 164.16,150.65 163.43,150.65 163.34,150.74 162.33,151.31 162.28,151.31
  BOTTOM w0.178: VRAM1.D13 153.39,168.19 153.39,168.76 153.16,168.99 151.51,168.99 151.46,169.04 151.09,169.04 150.82,168.77
  BOTTOM w0.229: 162.28,151.31 160.83,152.16 v2(153.67,152.16) 149.05,156.79 149.05,167 150.82,168.77
DDBIA0_3: length 26.1
  BOTTOM w0.102: GPU1.C19 169.58,147.71 169.69,147.92 169.74,148.01 169.74,148.68 169.8,148.74 169.8,149.65 169.14,150.31 169.14,150.6
  BOTTOM w0.178: 163.96,168.35 163.29,168.35 163.11,168.17 162.17,168.17 VRAM1.D2
  BOTTOM w0.229: 163.96,168.35 164.18,168.35 166.79,165.74 v2(166.79,154.59) 167.86,153.52 167.86,151.89 169.14,150.6
DDBIA1_0: length 28.1
  BOTTOM w0.102: 173.7,151.03 173.7,150.6 172.75,149.66 172.75,148.62 172.93,148.45 172.93,147.96 GPU1.C15
  BOTTOM w0.178: VRAM2.P2 177.89,168.19 177.89,168.76 177.65,169.01 176.54,169.01 176.45,169.09 175.62,169.09
  BOTTOM w0.229: 175.62,169.09 174.9,169.09 v2(172.5,166.69) 172.5,156.72 173.12,156.1 173.12,152.84 173.7,152.26 173.7,151.03
DDBIA1_1: length 34.1
  L3 w0.203: v1(186.71,168.2) 187.33,167.58 187.51,167.49 188.26,167.49 189.28,166.46 189.28,165.33 188.83,163.98 188.83,162.02 189.46,161.39 189.46,155.42 186.22,152.18 185.51,152.18 185.3,151.97 v1(182.99,151.97)
  BOTTOM w0.102: 181.22,151.31 179.5,151.31 178.96,150.77 178.71,150.77 177.21,149.27 177.21,148.4 177.07,148.22 177.07,148.03 177.13,147.89 177.13,147.53 177.07,147.39 177.07,146.83 177.1,146.8 GPU1.E9
  BOTTOM w0.229: v1(182.99,151.97) 182.99,152.47 v2(182.79,152.67) 182.43,152.67 182.23,152.47 182.23,152.15 181.39,151.31 181.22,151.31 ; VRAM2.P13 186.3,167.8 v1(186.71,168.2)
DDBIA1_2: length 14.7
  L4 w0.203: v1(177.09,159.43) 177.86,158.66 177.86,157.07 177.6,156.81 177.6,156.13 178.01,155.72 178.01,153.77 178.01,153.76 178.01,151.62 v1(181.02,148.61)
  BOTTOM w0.102: GPU1.C5 181,147.7 181,148.61 v1(181.02,148.61)
  BOTTOM w0.229: v1(177.09,159.43) VRAM2.D2
DDBIA1_3: length 20.5
  L4 w0.203: v1(186.68,160.18) 186.25,159.75 186.25,159.25 186.36,159.14 186.36,156.26 186.27,156.17 186.27,148.91 185.65,148.29 185.65,148.01 185.14,147.5 185.14,146.67 184.25,145.78 184.18,145.78 182.99,144.59 v1(182.99,144.11)
  BOTTOM w0.102: GPU1.H4 181.27,144.37 181.51,144.37 181.54,144.38 181.67,144.43 181.88,144.43 182.01,144.37 182.74,144.37 v1(182.99,144.11)
  BOTTOM w0.229: v1(186.68,160.18) 186.3,159.8 VRAM2.D13
DDC_CLK_HDMI: length 19.9
  TOP w0.191: RN5702.4 25.94,54.81 25.56,54.43 21.6,54.43 21.05,54.98 Q5702.3 v2(19.44,54.98) 19.29,54.98 19.18,55.09 ED5703.7 ED5703.4 15.76,55.09 v1(15.76,55.09)
  BOTTOM w0.191: HDMI1.15 10.17,54.72 10.17,55.86 10.48,56.17 11.43,56.17 12.51,55.09 v1(15.76,55.09)
DDC_CLK_PH1: length 2
  TOP w0.191: D5701.2 26.8,57.54 26.8,56.79 v2(26.81,56.78) 26.66,56.63 RN5702.1
DDC_DATA_HDMI: length 18.8
  TOP w0.191: v1(15.76,56.59) 16.79,56.59 ED5703.1 ED5703.10 18.36,56.59 18.69,56.92 v2(19.48,56.92) 21.17,56.92 21.81,56.29 Q5702.6 23.61,56.29 24.94,54.96 25.12,54.96 25.27,55.11 RN5702.3
  BOTTOM w0.191: v1(15.76,56.59) 16.09,56.59 16.29,56.39 16.29,54.92 15.86,54.5 HDMI1.16
DDC_DATA_PH2: length 2.1
  TOP w0.191: RN5702.2 24.59,56.63 24.39,56.82 ; 24.39,56.82 v2(24.39,56.78) ; 24.39,56.82 24.41,56.83 24.41,57.53 D5701.1
DDPD_CTRLDATA: length 1.3
  TOP w0.102: TP802.1 132.96,91.39 v1(132.96,91.17)
  BOTTOM w0.102: v1(132.96,91.17) 133.18,90.94 CPU1.N12
DDR4_DRAMRST#: length 100.4
  TOP w0.191: v1(92.34,30.91) 91.85,30.42 ED1302.1 ; ED1217.1 83.54,18.28 v1(83.97,17.85)
  L3 w0.165: v1(83.97,17.85) 83.99,17.83 v1(88.05,17.83) 89.08,16.8 101.44,16.8 104.05,19.42 123.14,19.42 124.78,21.06 124.78,23.71 127.8,26.74 128.2,26.74 130.41,28.95 130.41,30.53 131.59,31.71 131.67,31.71 131.76,31.8 131.77,31.8 132.74,32.77 133.35,32.77 134.27,33.68 134.27,35.49 137.78,39.01 137.78,39.44 139.42,41.07 139.42,47.16 v1(141.46,49.21)
  L4 w0.165: v1(88.05,17.83) 88.05,18.1 91.02,21.07 91.02,27.82 92.34,29.14 v1(92.34,30.91)
  BOTTOM w0.152: v1(141.46,49.21) 141.22,49.46 R504.2
  BOTTOM w0.191: v1(92.34,30.91) 92.77,31.35 DM1.108 ; v1(83.97,17.85) 84.25,17.85 84.77,18.37 DM2.108
DGPU_HOLD_RST#: length 80.7
  TOP w0.127: v1(146.63,125.56) 146.32,125.87 146.32,127.3 146.64,127.62 146.95,127.62 147.21,127.88 147.21,128.76 D7601.2 147.15,130.1 R7623.1 ; v1(145.56,89.76) 147.64,89.76 147.66,89.74 150.45,89.74 150.88,90.16 152.64,90.16 154.98,92.5 154.98,92.81 158.94,96.77 161.89,96.77 163.59,95.07 v1(163.59,94.63)
  L3 w0.127: v1(163.59,94.63) 163.59,97.4 160.32,100.67 160.32,100.74 159.79,101.27 159.79,101.67 159.79,102.07 159.14,102.72 158.7,102.72 155.46,105.95 154.91,105.95 151.44,109.43 150.77,109.43 148.13,112.07 148.13,120.53 147.35,121.31 147.35,122.66 147.35,124.68 146.63,125.39 v1(146.63,125.56) ; v1(140.69,89.72) 142.18,89.72 142.45,89.45 145.26,89.45 v1(145.56,89.76)
  BOTTOM w0.089: v1(140.69,89.72) 140.66,89.69 139.68,89.69 139.59,89.72 139.15,89.72 138.75,90.13 CPU1.P3
  BOTTOM w0.127: RN2009.4 150.8,90.04 v2(150.66,89.91) 149.61,89.91 EC2002.2 149.52,90 148.35,90 145.8,90 v1(145.56,89.76)
DGPU_PWR_EN: length 82.9
  TOP w0.127: v1(150.11,89.17) 150.25,89.17 150.99,89.91 152.75,89.91 155.23,92.39 155.23,92.7 159.05,96.52 161.49,96.52 163.14,94.86 163.14,94.44 163.54,94.05 v2(163.94,94.05) 164.74,94.05 v1(164.75,94.06) ; v1(151.05,110.1) 150.97,110.1 150.71,110.36 PD8501.K
  L3 w0.127: v1(146.92,134.88) 146.92,129.01 147.29,128.64 147.29,125.86 147.83,125.31 147.83,122.46 147.83,121.51 148.61,120.73 148.61,112.42 150.93,110.1 v1(151.05,110.1) 151.45,110.1 154.83,106.72 155.38,106.72 158.51,103.58 158.96,103.58 160.27,102.27 160.27,101.47 160.8,100.94 160.8,100.87 164.28,97.39 164.28,94.63 164.75,94.16 v1(164.75,94.06) ; v1(142.5,88.55) 143.09,89.13 150.12,89.13 150.12,89.17 v1(150.11,89.17)
  BOTTOM w0.089: CPU1.U1 139.98,88.64 141.27,88.64 141.28,88.64 142.41,88.64 v1(142.5,88.55)
  BOTTOM w0.127: PR8661.1 146.91,134.89 v1(146.92,134.88) ; RN2009.3 150.31,89.37 v1(150.11,89.17)
DGPU_PWR_EN_R: length 4.1
  BOTTOM w0.127: PQ8604.2 147.74,137.77 147.87,137.9 PC8602.1 148.47,136.87 v2(148.47,136.86) 148.47,136.5 PR8661.2
DGPU_PWROK: length 158.6
  TOP w0.102: v1(155.85,120.9) 155.85,120.97 155.49,121.34 154.83,121.34 153.28,119.79 152.39,119.79 R7904.1
  TOP w0.127: PR8520.2 v2(162.57,114.93) 162.05,115.45 159.32,115.45 158.03,114.16 156.5,114.16 156.24,113.89 156.24,113.39 156.17,113.32 ; v1(148.21,106.94) 148.59,106.56 150.39,106.56 150.65,106.82 150.65,109.71 149.85,110.52 149.85,113.19 150.62,113.96 152.68,113.96 153.73,112.91 155.08,112.91 v1(155.22,113.05) 155.27,113.1 155.96,113.1 156.17,113.32 ; R1904.2 157.08,111.03 EC1903.2 157.08,112.62 156.39,113.32 156.17,113.32
  L3 w0.127: v1(177.34,53.16) 183.53,59.35 183.53,66.75 185.58,68.8 185.58,70.92 186.62,71.96 186.62,71.96 186.95,72.29 186.95,80.22 181.14,86.03 181.14,86.82 179.37,88.58 178.92,88.58 175.74,91.77 168.01,91.77 167.37,92.4 167.37,92.9 167.95,93.49 167.95,96.68 164.82,99.82 164.82,103.59 156.93,111.48 155.37,111.48 154.67,112.19 154.67,112.55 155.16,113.05 v1(155.22,113.05) 155.9,113.05 156.22,113.36 156.22,113.96 155.38,114.8 155.38,116.07 155.34,116.11 155.34,117.97 155.79,118.43 155.79,120.84 v1(155.85,120.9)
  L4 w0.127: v1(167.09,53) 167.58,53 167.63,52.95 168.26,52.95 168.39,53.08 168.61,53.08 168.85,52.84 168.85,52.47 169.11,52.21 169.48,52.21 169.74,52.47 169.74,52.84 169.97,53.08 171.48,53.08 171.56,53.16 v1(177.34,53.16)
  BOTTOM w0.089: 138.6,98.83 138.21,98.83 136.97,97.59 136.86,97.59 136.73,97.47 136.71,97.42 136.71,97.14 136.71,97.13 136.71,96.77 136.6,96.66
  BOTTOM w0.127: 136.6,96.66 136.6,96.19 136.42,96.01 136.16,96.01 135.73,96.45 CPU1.C8 ; v1(148.21,106.94) 147.9,106.63 147.9,106.62 147.85,106.6 147.82,106.58 143.1,106.58 141.7,105.18 141.7,103.2 140.76,102.26 140.76,100.53 139.58,99.36 139.26,99.36 138.99,99.09 138.85,99.09 138.6,98.83 ; R2427.2 166.5,53 v1(167.09,53)
DGPU_PWROK_EC: length 5.2
  BOTTOM w0.102: R2427.1 167.23,51.3 167.23,48.85 v2(167.32,48.76) 167.66,48.42 KBC24.23
DGPU_PWROK_R: length 3.3
  TOP w0.127: Q7903.G 149.11,120.73 R7942.2 150.46,120.73 150.73,121.01 v2(151.14,121.01) 151.2,120.96 R7904.2
DMIC_CLK: length 235.8
  TOP w0.191: v1(116.97,168.99) 116.47,169.49 111.34,169.49 110.45,168.61 v2(107.77,168.61) 105.95,168.61 105.13,169.43 EC5501.1 105.13,170.76 R5503.2
  L4 w0.165: v1(116.97,168.99) 118.38,167.58 118.38,165.68 126.29,157.77 126.29,156.08 131.33,151.04 132.15,151.04 133.56,149.63 133.56,148.26 135.01,146.81 136.83,146.81 143.18,140.46 143.18,125.2 142.57,124.59 142.57,108 145.37,105.2 147.87,105.2 148.63,104.44 152.26,104.44 158.47,98.23 158.51,98.23 158.98,97.76 158.98,97.74 164.14,92.58 164.24,92.58 166.14,90.68 171.12,90.68 171.16,90.72 171.17,90.72 171.18,90.73 172.08,90.73 172.08,90.73 176.72,90.73 177.76,91.78 184.14,91.78 185.22,92.85 189.17,92.85 192.11,89.91 192.11,71.1 190.66,69.64 190.66,66.91 194.21,63.35 194.21,36.75 193.25,35.79 193.25,35.13 188.82,30.7 188.82,30.07 189.06,29.83 189.06,29.36 188.17,28.47 186.27,28.47 183.67,25.86 182.31,25.86 182.26,25.82 178.16,25.82 177.15,26.82 169.18,26.82 168.65,26.29 v1(168.65,25.94)
  BOTTOM w0.178: 168.69,26.29 168.69,26.47 C2725.1
  BOTTOM w0.191: 168.69,26.29 168.69,25.99 168.65,25.96 v1(168.65,25.94) 168.71,25.94 169.23,25.42 R2720.1
DMIC_CLK_EDP: length 6.1
  TOP w0.14: v1(106.2,173.76) 105.32,172.87 v2(105.32,172.65) 105.32,171.81 R5503.1
  BOTTOM w0.14: v1(106.2,173.76) 106.01,173.96 106.01,174.14 106.74,174.86 106.74,174.86 107.14,175.26 107.14,175.26 107.65,175.78 LCD1.27
DMIC_CLK_R: length 4.3
  BOTTOM w0.191: HDA27.3 171.34,21.58 169.74,23.18 v2(169.53,23.18) 169.28,23.43 R2720.2
DMIC_DATA: length 234.5
  TOP w0.191: v1(116.69,168.38) 116.32,168.75 115.71,168.75 v2(115.69,168.73) 115.37,169.05 111.52,169.05 110.64,168.16 105.74,168.16 104.35,169.55 EC5502.1 104.3,169.98 R5502.2
  L4 w0.165: v1(116.69,168.38) 116.69,166.78 125.87,157.6 125.87,155.91 131.15,150.62 131.86,150.62 133.14,149.34 133.14,148.09 134.83,146.39 136.66,146.39 142.76,140.29 142.76,125.38 142.15,124.77 142.15,107.83 145.2,104.79 147.7,104.79 148.96,103.52 149.39,103.52 149.63,103.76 152.35,103.76 158.3,97.81 158.33,97.81 158.56,97.59 158.56,97.57 163.96,92.16 164.07,92.16 165.97,90.26 171.29,90.26 171.34,90.31 172.25,90.31 172.26,90.32 176.89,90.32 177.94,91.36 184.32,91.36 185.39,92.43 188.99,92.43 191.69,89.73 191.69,71.28 190.24,69.82 190.24,66.73 193.79,63.18 193.79,36.93 192.83,35.96 192.83,35.36 187.09,29.63 186.81,29.63 184.25,27.07 177.5,27.07 177.33,27.24 169.01,27.24 168.23,26.46 168.23,26.33 v1(167.83,25.94)
  BOTTOM w0.191: R2718.1 168.39,25.29 167.83,25.85 v1(167.83,25.94) 167.83,26.4 EC2711.1
DMIC_DATA_EDP: length 7.9
  TOP w0.14: v1(107.02,174.07) 106.87,174.21 105.97,174.21 105.14,173.38 104.62,173.38 v2(103.93,172.69) 103.93,172 R5502.1
  BOTTOM w0.14: LCD1.28 108.15,175.68 107.56,175.09 107.56,175.08 107.02,174.54 v1(107.02,174.07)
DMIC_DATA_R: length 4.7
  BOTTOM w0.191: R2718.2 168.3,24.23 v2(168.3,23.35) 168.57,23.08 168.9,23.08 169.73,22.24 170.17,22.24 170.94,21.47 HDA27.2
DP_CRT_B: length 9.2
  TOP w0.191: U5601.21 21.53,76.64 21.27,76.38 17.87,76.38 17.61,76.63 v2(17.48,76.76) 17.63,76.91 17.63,78.33 17.23,78.73 R5607.1 17.11,78.76 C5613.1 15.46,78.76 EL5602.1
DP_CRT_G: length 7.8
  TOP w0.191: EL5603.1 15.32,75.71 C5611.1 16.26,75.68 R5608.1 17.22,75.68 17.38,75.52 17.38,75.38 17.66,75.1 19.54,75.1 v2(19.63,75.19) 20.48,76.04 21.34,76.04 21.55,76.24 U5601.22
DP_CRT_HSYNC_CON: length 10.5
  TOP w0.191: v1(21.22,77.55) 21.32,77.44 U5601.19
  BOTTOM w0.191: R5612.1 12.92,77.99 13.72,78.79 v2(17.16,78.79) 19.55,78.79 20.69,77.65 21.11,77.65 v1(21.22,77.55)
DP_CRT_R: length 8
  TOP w0.191: U5601.23 21.62,75.84 21.46,75.68 20.99,75.68 20.61,75.3 20.61,74.82 18.92,73.13 v2(18.42,73.13) 18.41,73.12 R5606.1 17.47,73.14 C5612.1 15.74,73.14 EL5601.1
DP_CRT_VSYNC_CON: length 10.5
  TOP w0.191: U5601.18 21.62,77.84 21.2,78.26 v1(20.89,78.26)
  BOTTOM w0.191: R5611.1 14.58,79.77 v2(14.71,79.63) 14.84,79.5 19.85,79.5 20.89,78.46 v1(20.89,78.26)
DPLL_PVDD: length 33
  TOP w0.254: v1(158.24,126.16) 157.34,125.27 157.34,124.09 C7713.1 157.09,122.76 C7710.1 157.09,121.56 C7711.1 156.57,121.04 v2(156.57,120.68) ; v1(151.41,125.62) 151.42,125.61 151.8,125.61 152.45,124.95 R7704.2
  L3 w0.254: v1(158.24,126.16) 159.25,127.18 163.09,127.18 164.75,128.84 165.21,128.84 166.24,127.82 169.94,127.82 171,128.88 171.94,128.88 v1(172.55,129.49)
  BOTTOM w0.254: v1(158.24,126.16) 157.92,126.16 156.79,125.04 154.71,125.04 154.64,125.11 151.92,125.11 v1(151.41,125.62) ; GPU1.AF14 172.76,129.7 v1(172.55,129.49)
DPLL_VDDC: length 9.7
  TOP w0.254: v1(173.76,129.33) 173.74,129.33 173.49,129.09 173.49,128.51 171.65,126.67 C7715.1 C7714.1 171.65,124.29 R7705.2 172.4,123.54 v2(172.4,122.99)
  BOTTOM w0.254: GPU1.AD14 173.2,131.25 173.73,130.73 173.73,129.36 v1(173.76,129.33)
DQA0_0: length 29.8
  L4 w0.203: v1(152.62,161.77) 151.92,161.07 151.35,161.07 150.24,159.97 150.24,150.87 157.25,143.86 157.25,143.8 159.07,141.99 161.58,141.99 v1(162.54,142.96)
  BOTTOM w0.229: VRAM1.M13 152.63,161.77 v1(152.62,161.77) ; GPU1.K27 v1(162.54,142.96)
DQA0_1: length 26.6
  L4 w0.203: v1(159.6,143.2) 159.27,142.87 158.62,142.87 157.56,143.93 157.56,144.03 155.41,146.18 155.41,146.53 150.76,151.18 150.76,159.52 151.39,160.15 151.74,160.15 v1(152.6,161)
  BOTTOM w0.229: GPU1.J29 161.41,142.91 160.48,142.91 160.44,142.87 159.94,142.87 v1(159.6,143.2) ; v1(152.6,161) VRAM1.N13
DQA0_2: length 22.5
  L4 w0.203: v1(152.6,158.6) 151.28,157.28 151.28,151.43 155.82,146.89 155.82,146.29 158.79,143.32 v1(158.81,143.32)
  BOTTOM w0.178: GPU1.H30 161.03,143.73 160.45,143.73 160.4,143.78 159.27,143.78 v1(158.81,143.32)
  BOTTOM w0.229: v1(152.6,158.6) 152.99,158.2 VRAM1.T13
DQA0_3: length 19.1
  L4 w0.203: v1(158.37,144.39) 156.26,146.5 156.26,147.15 155.93,147.48 155.93,147.52 152.13,151.32 152.13,157.33 v1(152.6,157.79)
  BOTTOM w0.178: v1(158.37,144.39) 158.66,144.1 GPU1.H32
  BOTTOM w0.229: v1(152.6,157.79) 152.99,157.4 VRAM1.U13
DQA0_4: length 17.3
  L4 w0.203: v1(159.39,145.15) 158.19,146.35 158.19,146.77 156.73,148.23 156.73,150 154.71,152.02 154.71,155.47 v1(154.46,155.72)
  BOTTOM w0.178: v1(159.39,145.15) 159.39,145.08 159.99,144.48 161.38,144.48 GPU1.G29
  BOTTOM w0.229: VRAM1.U11 154.61,157.39 154.61,156.74 154.45,156.58 154.45,155.72 v1(154.46,155.72)
DQA0_5: length 17.5
  L4 w0.203: v1(154.97,157.82) 154.98,157.81 154.98,156.48 155.33,156.13 155.33,152.3 157.12,150.5 157.12,148.28 158.55,146.86 158.55,146.64 v1(159.37,145.82)
  BOTTOM w0.178: v1(159.37,145.82) 159.82,145.37 160.36,145.37 160.4,145.33 161.83,145.33 GPU1.F28
  BOTTOM w0.229: v1(154.97,157.82) 154.97,157.82 154.97,157.82 154.6,158.19 VRAM1.T11
DQA0_6: length 18.6
  L4 w0.203: v1(160.01,145.83) 160.01,146.61 159.66,146.97 159.38,146.97 158.14,148.22 158.14,151.01 156.46,154.08 156.46,159.95 155.98,160.44 155.82,160.44 155.24,161.02 v1(154.98,161.02)
  BOTTOM w0.229: v1(160.01,145.83) 160.15,145.7 GPU1.F32 ; v1(154.98,161.02) 154.97,161.02 154.97,161.03 VRAM1.M11
DQA0_7: length 18.4
  L4 w0.203: v1(159.47,146.51) 159.41,146.51 157.58,148.34 157.58,150.85 155.85,153.57 155.85,156.36 155.48,157.27 155.48,157.82 155.3,158.31 154.74,158.88 154.55,159.22 154.55,159.56 154.95,160.17 155.01,160.18 155.01,160.19 v1(155,160.19)
  BOTTOM w0.178: v1(159.47,146.51) 159.7,146.28 160.23,146.28 160.41,146.11 160.99,146.11 GPU1.F30
  BOTTOM w0.229: v1(155,160.19) 155,160.2 VRAM1.N11
DQA0_8: length 10.9
  L4 w0.203: v1(161.41,149.35) 161.41,152.8 162.16,153.56 v1(162.16,156.92)
  BOTTOM w0.178: GPU1.C30 160.99,147.71 160.99,148.26 160.96,148.29 160.96,148.91 v1(161.41,149.35)
  BOTTOM w0.229: VRAM1.U2 161.8,157.28 v1(162.16,156.92)
DQA0_9: length 19.1
  L4 w0.203: v1(162.19,161) 162.25,161.06 163.39,161.06 165.23,159.22 165.23,150.95 164.04,149.76 164.04,148.01 163.1,147.07 163.1,146.6 v1(162.61,146.11)
  BOTTOM w0.178: VRAM1.N2 161.8,160.61 v1(162.19,161)
  BOTTOM w0.229: GPU1.F27 v1(162.61,146.11)
DQA0_10: length 11.5
  L4 w0.203: v1(161.95,149.02) 161.95,152.34 162.68,153.07 162.68,157.04 161.92,157.81 v1(161.4,157.81)
  BOTTOM w0.229: GPU1.A28 161.95,148.35 v1(161.95,149.02) ; v1(161.4,157.81) 161.79,158.2 VRAM1.T2
DQA0_11: length 13.2
  L4 w0.203: v1(162.6,146.9) 161.3,148.2 161.22,148.2 160.47,148.95 160.47,156.26 159.81,156.92 v1(159.81,157.8)
  BOTTOM w0.229: v1(159.81,157.8) 160.2,158.19 VRAM1.T4 ; GPU1.C28 v1(162.6,146.9)
DQA0_12: length 19.9
  L4 w0.203: v1(163.4,146.11) 163.4,146.87 164.59,148.06 164.59,148.92 165.75,150.08 165.75,159.44 163.78,161.4 162.56,161.4 v1(162.18,161.78)
  BOTTOM w0.229: VRAM1.M2 162.18,161.78 v1(162.18,161.78) ; v1(163.4,146.11) GPU1.E27
DQA0_13: length 24.4
  L4 w0.203: v1(163.4,144.51) 164.23,145.34 164.23,146.98 166.27,149.02 166.27,159.65 163.6,162.32 161.11,162.32 v1(160.59,161.8)
  BOTTOM w0.178: v1(160.59,161.8) 160.2,161.41 VRAM1.M4
  BOTTOM w0.229: GPU1.G26 v1(163.4,144.51)
DQA0_14: length 19.1
  L4 w0.203: v1(163.5,149.21) 163.5,150.43 164.71,151.64 164.71,158.74 163.38,160.07 160.72,160.07 v1(159.82,160.98)
  BOTTOM w0.102: GPU1.D26 163.4,147.3 163.4,148.17 163.17,148.4 163.17,148.88 v1(163.5,149.21)
  BOTTOM w0.229: VRAM1.N4 159.82,160.98 v1(159.82,160.98)
DQA0_15: length 15.9
  L4 w0.203: v1(160.56,157.8) 160.56,156.81 161.23,156.14 161.23,153.58 160.94,153.29 v1(160.94,149.92)
  BOTTOM w0.102: 162.29,149.92 162.52,149.92 162.82,149.62 163.66,149.62 163.96,149.32 164.07,149.06 164.07,147.94 164.13,147.81 164.13,147.59 164.07,147.46 164.07,147.14 164.13,147.01 164.13,146.72 164.14,146.69 GPU1.F25
  BOTTOM w0.229: VRAM1.U4 160.2,157.44 v1(160.56,157.8) ; 162.29,149.92 v1(160.94,149.92)
DQA0_16: length 42
  BOTTOM w0.102: GPU1.A25 164.47,148.23 164.47,149.39 163.83,150.02 163.18,150.02 163.02,150.18 162.95,150.25 162.4,150.57 159.93,150.57
  BOTTOM w0.229: 159.93,150.57 153,150.57 v2(147.48,156.08) 147.48,167.65 151.26,171.42 153.8,171.42 154.27,170.95 VRAM1.A11
DQA0_17: length 41.4
  BOTTOM w0.102: 160.03,151.11 161,150.82 162.37,150.82 163.01,150.45 163.08,150.41 163.18,150.31 163.26,150.23 163.84,150.23 164.01,150.23 164.68,149.56 164.68,148.49 164.93,148.24 164.93,147.99 164.87,147.86 164.87,147.57 GPU1.C25
  BOTTOM w0.178: VRAM1.B13 153.39,169.79 153.39,170.57 153.33,170.63
  BOTTOM w0.229: 153.33,170.63 152.87,171.09 151.67,171.09 v2(148,167.43) 148,156.3 153.18,151.12 158.53,151.12 160.03,151.11
DQA0_18: length 46.4
  BOTTOM w0.102: 160.14,150.08 160.2,150.11 160.79,150.32 161.02,150.32 162.45,150.22 163,149.82 163.75,149.82 164.14,149.43 164.27,149.12 164.27,147.99 164.29,147.94 164.33,147.9 164.33,147.5 164.29,147.46 164.27,147.41 164.27,147.19 164.33,147.06 164.33,147.05 GPU1.E25
  BOTTOM w0.229: VRAM1.B11 154.99,170.05 154.99,170.37 154.55,171.15 153.94,171.75 150.86,171.75 v2(148.99,169.89) 148.29,169.18 146.96,167.86 146.96,155.87 152.81,150.02 153.2,150.02 153.45,150.02 155.39,150.02 160.14,150.08
DQA0_19: length 38.5
  BOTTOM w0.102: GPU1.D24 165.4,147.23 165.09,147.54 165.07,147.59 165.07,147.81 165.09,147.86 165.13,147.9 165.13,148.32 164.91,148.54 164.91,149.61 164.07,150.45 163.33,150.45 163.2,150.57 162.37,151.05 161.71,151.05 161.03,151.34
  BOTTOM w0.178: 151.24,169.93 151.87,169.93 151.99,169.81 152.61,169.81 VRAM1.A13
  BOTTOM w0.229: 151.24,169.93 148.53,167.21 148.53,156.58 153.46,151.64 v2(160.27,151.64) 161.03,151.34
DQA0_20: length 32.5
  BOTTOM w0.102: 163.95,151.71 164.4,151.38 164.81,151.38 166.59,149.59 166.59,148.63 166.73,148.34 166.73,147.9 166.69,147.86 166.67,147.81 166.67,147.59 166.69,147.54 166.73,147.46 166.73,147.14 166.67,147.02 166.67,146.97 GPU1.E23
  BOTTOM w0.178: VRAM1.F13 152.57,165.77 151.94,165.77 151.81,165.65 151.2,165.65 151.02,165.46
  BOTTOM w0.229: 151.02,165.46 151.02,157.46 v2(153.3,155.18) 155.89,155.18 157.68,153.4 162.26,153.4 163.95,151.71
DQA0_21: length 34.7
  BOTTOM w0.102: 163.8,151.39 164.18,151.15 164.75,151.15 166.39,149.51 166.39,148.58 166.53,148.3 166.53,147.98 166.5,147.96 166.47,147.88 166.47,147.5 166.51,147.46 166.53,147.41 166.53,147.19 166.51,147.14 166.34,146.97 166.2,146.97 165.87,146.64 165.87,146.03 GPU1.F23
  BOTTOM w0.178: 151.18,166.27 151.45,166.54 151.85,166.54 151.93,166.62 152.62,166.62 VRAM1.E13
  BOTTOM w0.229: 163.8,151.39 162.14,153.05 157.29,153.05 v2(155.68,154.66) 153.08,154.66 150.69,157.05 150.69,165.78 151.18,166.27
DQA0_22: length 32.2
  BOTTOM w0.102: 164.53,151.72 164.92,151.56 166.82,149.65 166.82,149.28 166.95,149.15 167.28,149.15 167.41,149.03 167.41,148.53 167.27,148.3 167.27,147.98 167.33,147.84 167.33,147.58 167.27,147.43 167.27,147.03 167.14,146.9 GPU1.D22
  BOTTOM w0.229: 164.53,151.72 162.47,153.78 157.93,153.78 157.62,154.08 157.62,154.9 v2(156.82,155.7) 155.12,155.7 154.99,155.83 154.99,156.8 155.12,156.93 156.16,156.93 156.44,157.21 156.48,157.25 156.48,166.26 156.28,166.45 156.14,166.45 156.14,166.45 155.75,166.45 155.75,166.45 155.71,166.45 155.55,166.61 154.83,166.61 154.6,166.37 VRAM1.F11
DQA0_23: length 32.8
  BOTTOM w0.102: GPU1.F21 167.47,146.36 167.47,146.36 167.47,147.39 167.53,147.54 167.53,147.89 167.47,148.03 167.47,148.22 167.61,148.42 167.61,149.15 164.89,151.88
  BOTTOM w0.229: VRAM1.E11 154.6,167.18 154.82,167.39 156.05,167.39 156.87,168.21 157.16,168.21 157.56,167.8 157.56,167.62 156.81,166.87 156.81,166.86 156.81,156.45 v2(159.06,154.2) 161.39,154.2 161.4,154.21 162.56,154.21 164.89,151.88
DQA0_24: length 29.7
  BOTTOM w0.102: 168.04,149.82 168.34,149.52 168.34,147.92 168.24,147.72 168.24,146.94 168.06,146.59 GPU1.E21
  BOTTOM w0.229: VRAM1.E4 159.81,166.61 158.73,166.61 158.54,166.8 158.13,166.8 157.8,166.47 157.8,157.88 159.83,155.86 163.87,155.86 v2(164.65,155.08) 164.65,153.83 166.12,152.37 166.12,151.74 168.04,149.82
DQA0_25: length 28.4
  BOTTOM w0.102: 168.1,150.23 168.67,149.66 168.86,149.66 169.19,149.33 169.19,148.99 168.87,148.67 168.87,147.98 168.93,147.84 168.93,147.61 168.85,147.45 168.85,147.15 GPU1.D20
  BOTTOM w0.229: 168.1,150.23 166.52,151.8 v2(166.52,152.69) 165.19,154.02 165.19,155.32 164.19,156.32 159.83,156.32 158.13,158.02 158.13,165.42 158.53,165.82 159.01,165.82 159.02,165.81 159.81,165.81 VRAM1.F4
DQA0_26: length 25.7
  BOTTOM w0.102: GPU1.F19 169.07,146.03 169.07,147.38 169.13,147.53 169.13,147.89 169.07,148.03 169.07,148.58 169.39,148.91 169.39,149.41 167.08,151.73 167.08,151.92
  BOTTOM w0.178: VRAM1.F2 162.17,166.57 163.34,166.57 163.43,166.48 164.03,166.48
  BOTTOM w0.229: 167.08,151.92 167.08,152.74 165.75,154.07 v2(165.75,164.75) 164.03,166.48
DQA0_27: length 24.2
  BOTTOM w0.102: 167.5,151.87 167.5,151.62 169.6,149.53 169.6,148.82 169.4,148.63 GPU1.A19
  BOTTOM w0.178: 164.16,167.41 162.21,167.41 VRAM1.E2
  BOTTOM w0.229: 164.16,167.41 165.42,166.16 ; 165.42,166.16 v2(165.42,166.16) ; 165.42,166.16 166.27,165.3 166.27,154.31 167.5,153.08 167.5,151.87
DQA0_28: length 29.4
  BOTTOM w0.102: 170.08,150.94 170.6,150.42 170.6,149.98 170.51,149.89 170.51,148.44 170.47,148.4 170.47,147.98 170.53,147.84 170.53,147.61 170.43,147.35 170.41,147.18 GPU1.D18
  BOTTOM w0.229: 170.08,150.94 168.84,152.19 168.84,154.48 v2(168.14,155.18) 168.14,166.67 163.88,170.93 162.53,170.93 VRAM1.A2
DQA0_29: length 32.9
  BOTTOM w0.102: GPU1.F17 170.67,146.36 170.67,147.4 170.73,147.51 170.73,147.89 170.67,148.03 170.67,148.32 170.71,148.36 170.71,149.67 170.8,149.76 170.8,150.77 170.5,151.07
  BOTTOM w0.178: 161.72,170.85 161.72,170.84 161.41,170.52 161.41,169.79 VRAM1.B2
  BOTTOM w0.229: 161.72,170.85 162.13,171.26 164.29,171.26 164.53,171.02 164.72,170.82 165.13,170.41 168.66,166.89 168.66,155.4 v2(169.37,154.69) 169.37,152.2 170.5,151.07
DQA0_30: length 31.5
  BOTTOM w0.102: 170.95,151.15 171.01,151.09 171.01,149.63 170.92,149.54 170.92,148.18 GPU1.A17
  BOTTOM w0.229: VRAM1.A4 160.2,170.61 161.18,171.59 164.75,171.59 166.52,169.82 166.97,169.38 167.28,169.06 v2(169.18,167.16) 169.18,155.62 169.91,154.88 169.91,152.19 170.95,151.15
DQA0_31: length 34.8
  BOTTOM w0.102: 171.23,151.39 171.23,149.48 171.13,149.13 171.13,148.45 171.33,148.25 171.33,147.96 GPU1.C17
  BOTTOM w0.229: VRAM1.B4 159.81,169.79 159.81,170.68 161.26,172.13 v2(164.95,172.13) 166.05,171.03 169.7,167.38 169.7,155.83 170.44,155.09 170.44,152.17 171.23,151.39
DQA1_0: length 34
  BOTTOM w0.102: 171.6,151.12 171.54,149.58 171.48,149.43 171.42,149.26 171.33,149 171.33,148.54 171.53,148.34 171.53,147.92 171.46,147.76 171.34,147.19 GPU1.E17
  BOTTOM w0.229: VRAM2.U4 179.1,171.26 178.18,172.18 174.67,172.18 v2(170.42,167.93) 170.42,155.85 171.01,155.26 171.01,152.21 171.6,151.62 171.6,151.12
DQA1_1: length 33.1
  BOTTOM w0.102: GPU1.D16 172.03,147.42 172.13,147.61 172.13,147.84 172.07,147.98 172.07,148.37 172.14,148.45 172.14,150.73 172.28,150.87
  BOTTOM w0.178: VRAM2.T4 178.71,169.79 178.71,171.16 178.56,171.31
  BOTTOM w0.229: 172.28,150.87 172.28,151.6 v2(171.53,152.35) 171.53,155.47 170.94,156.07 170.94,167.71 174.96,171.73 178.14,171.73 178.56,171.31
DQA1_2: length 32.2
  BOTTOM w0.102: 172.73,150.91 172.35,150.53 172.35,148.35 172.27,148.27 172.27,148.03 172.33,147.89 172.33,147.53 172.27,147.39 172.27,146.03 GPU1.F15
  BOTTOM w0.178: 177.6,170.82 177.89,170.52 177.89,169.79 VRAM2.T2
  BOTTOM w0.229: 177.6,170.82 177.02,171.4 175.63,171.4 171.46,167.23 171.46,156.28 v2(172.05,155.69) 172.05,152.46 172.73,151.78 172.73,150.91
DQA1_3: length 27.2
  BOTTOM w0.102: 173.17,150.91 172.55,150.29 172.55,148.15 GPU1.A15
  BOTTOM w0.229: 173.17,150.91 v2(173.17,152.03) 172.58,152.62 172.58,155.9 171.98,156.5 171.98,166.94 176.11,171.07 176.63,171.07 VRAM2.U2
DQA1_4: length 24.4
  BOTTOM w0.102: GPU1.D14 173.65,147.15 173.65,147.45 173.73,147.61 173.73,147.84 173.67,147.98 173.67,148.48 173.85,148.66 173.85,149.9 174.7,150.76 174.7,151.03
  BOTTOM w0.178: 175.68,167.21 175.91,167.44 176.52,167.44 176.54,167.42 177.08,167.42 VRAM2.N2
  BOTTOM w0.229: 175.68,167.21 175.23,167.21 174.71,166.69 v2(173.85,165.82) 173.85,157.29 174.49,156.65 174.49,152.99 174.7,152.78 174.7,151.03
DQA1_5: length 24.3
  BOTTOM w0.102: 175.04,150.65 174.05,149.66 174.05,148.51 173.87,148.33 173.87,148.03 173.93,147.89 173.93,147.53 173.87,147.39 173.87,146.03 GPU1.F13
  BOTTOM w0.178: 175.34,166.62 175.79,166.62 175.85,166.56 176.53,166.56 176.55,166.57 177.13,166.57 VRAM2.M2
  BOTTOM w0.229: 175.04,153.77 v2(175.04,153.76) ; 175.04,153.77 175.04,156.88 174.75,157.17 174.75,166.03 175.34,166.62 ; 175.04,153.77 175.04,150.65
DQA1_6: length 22.7
  BOTTOM w0.102: GPU1.A13 174.28,148.18 174.28,149.44 175.6,150.75
  BOTTOM w0.229: 175.6,150.75 175.6,152.3 v2(177.42,154.12) 181.25,157.95 181.25,165.39 180.84,165.8 179.5,165.8 VRAM2.M4
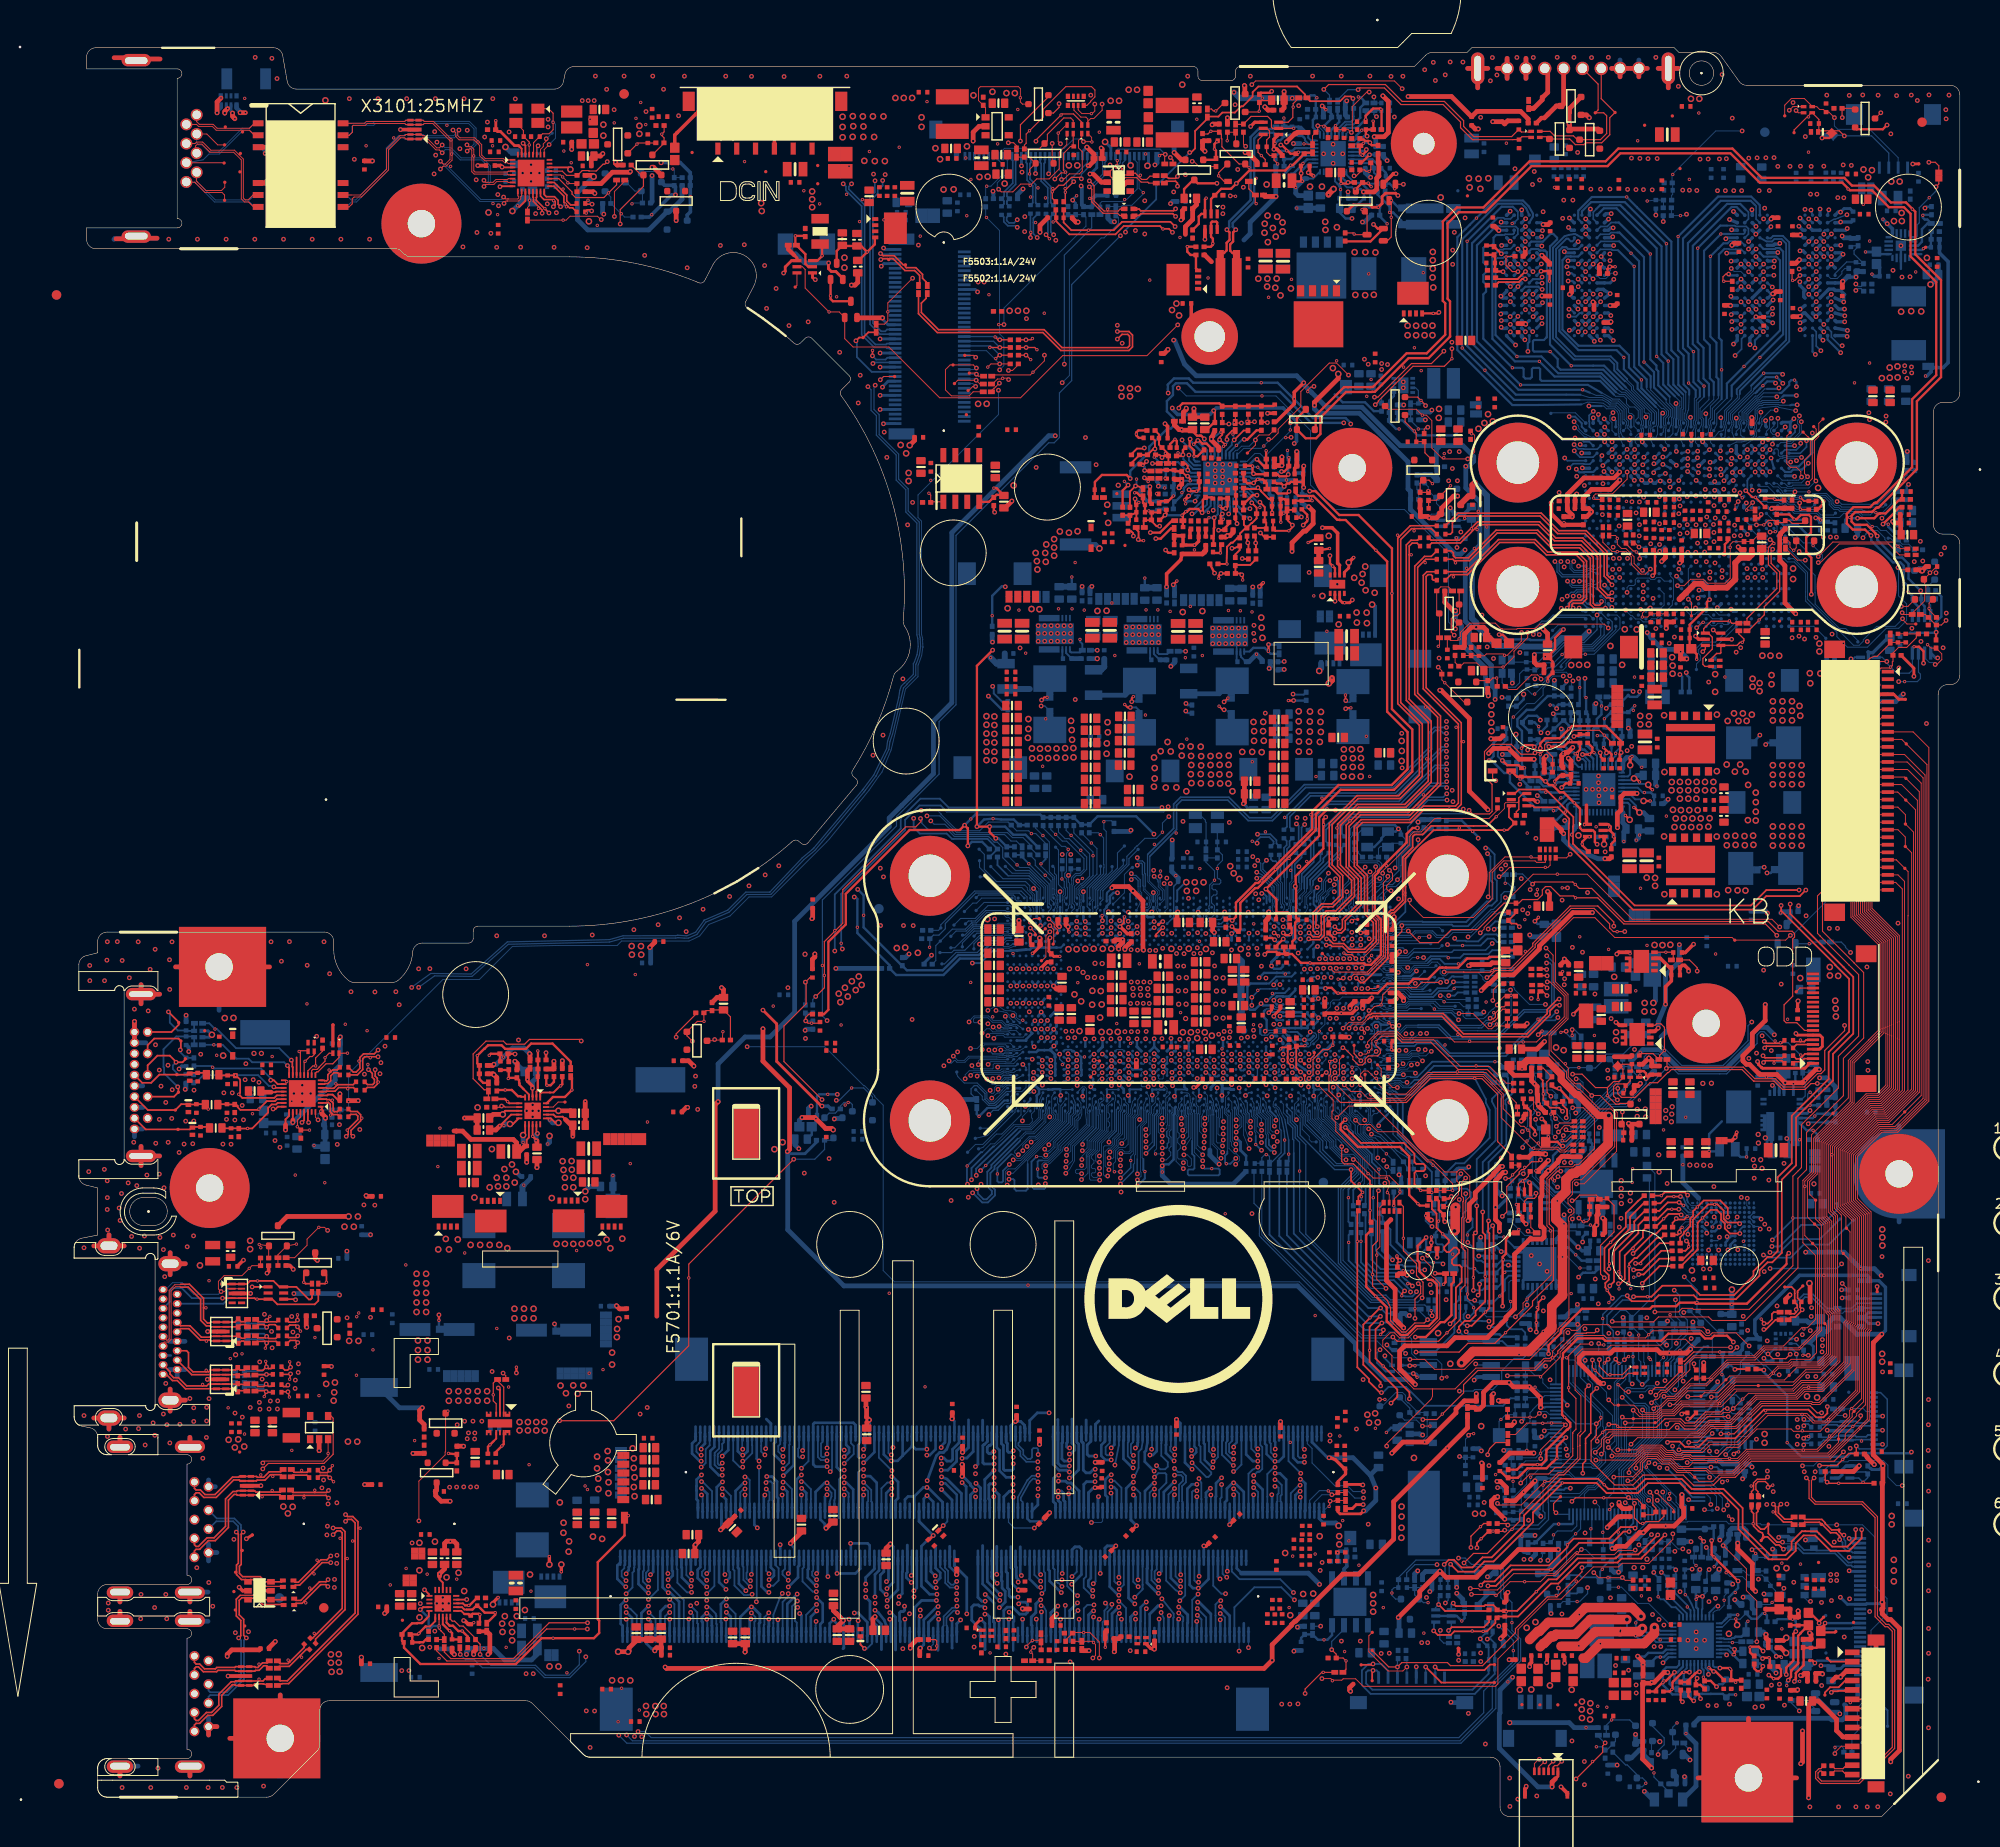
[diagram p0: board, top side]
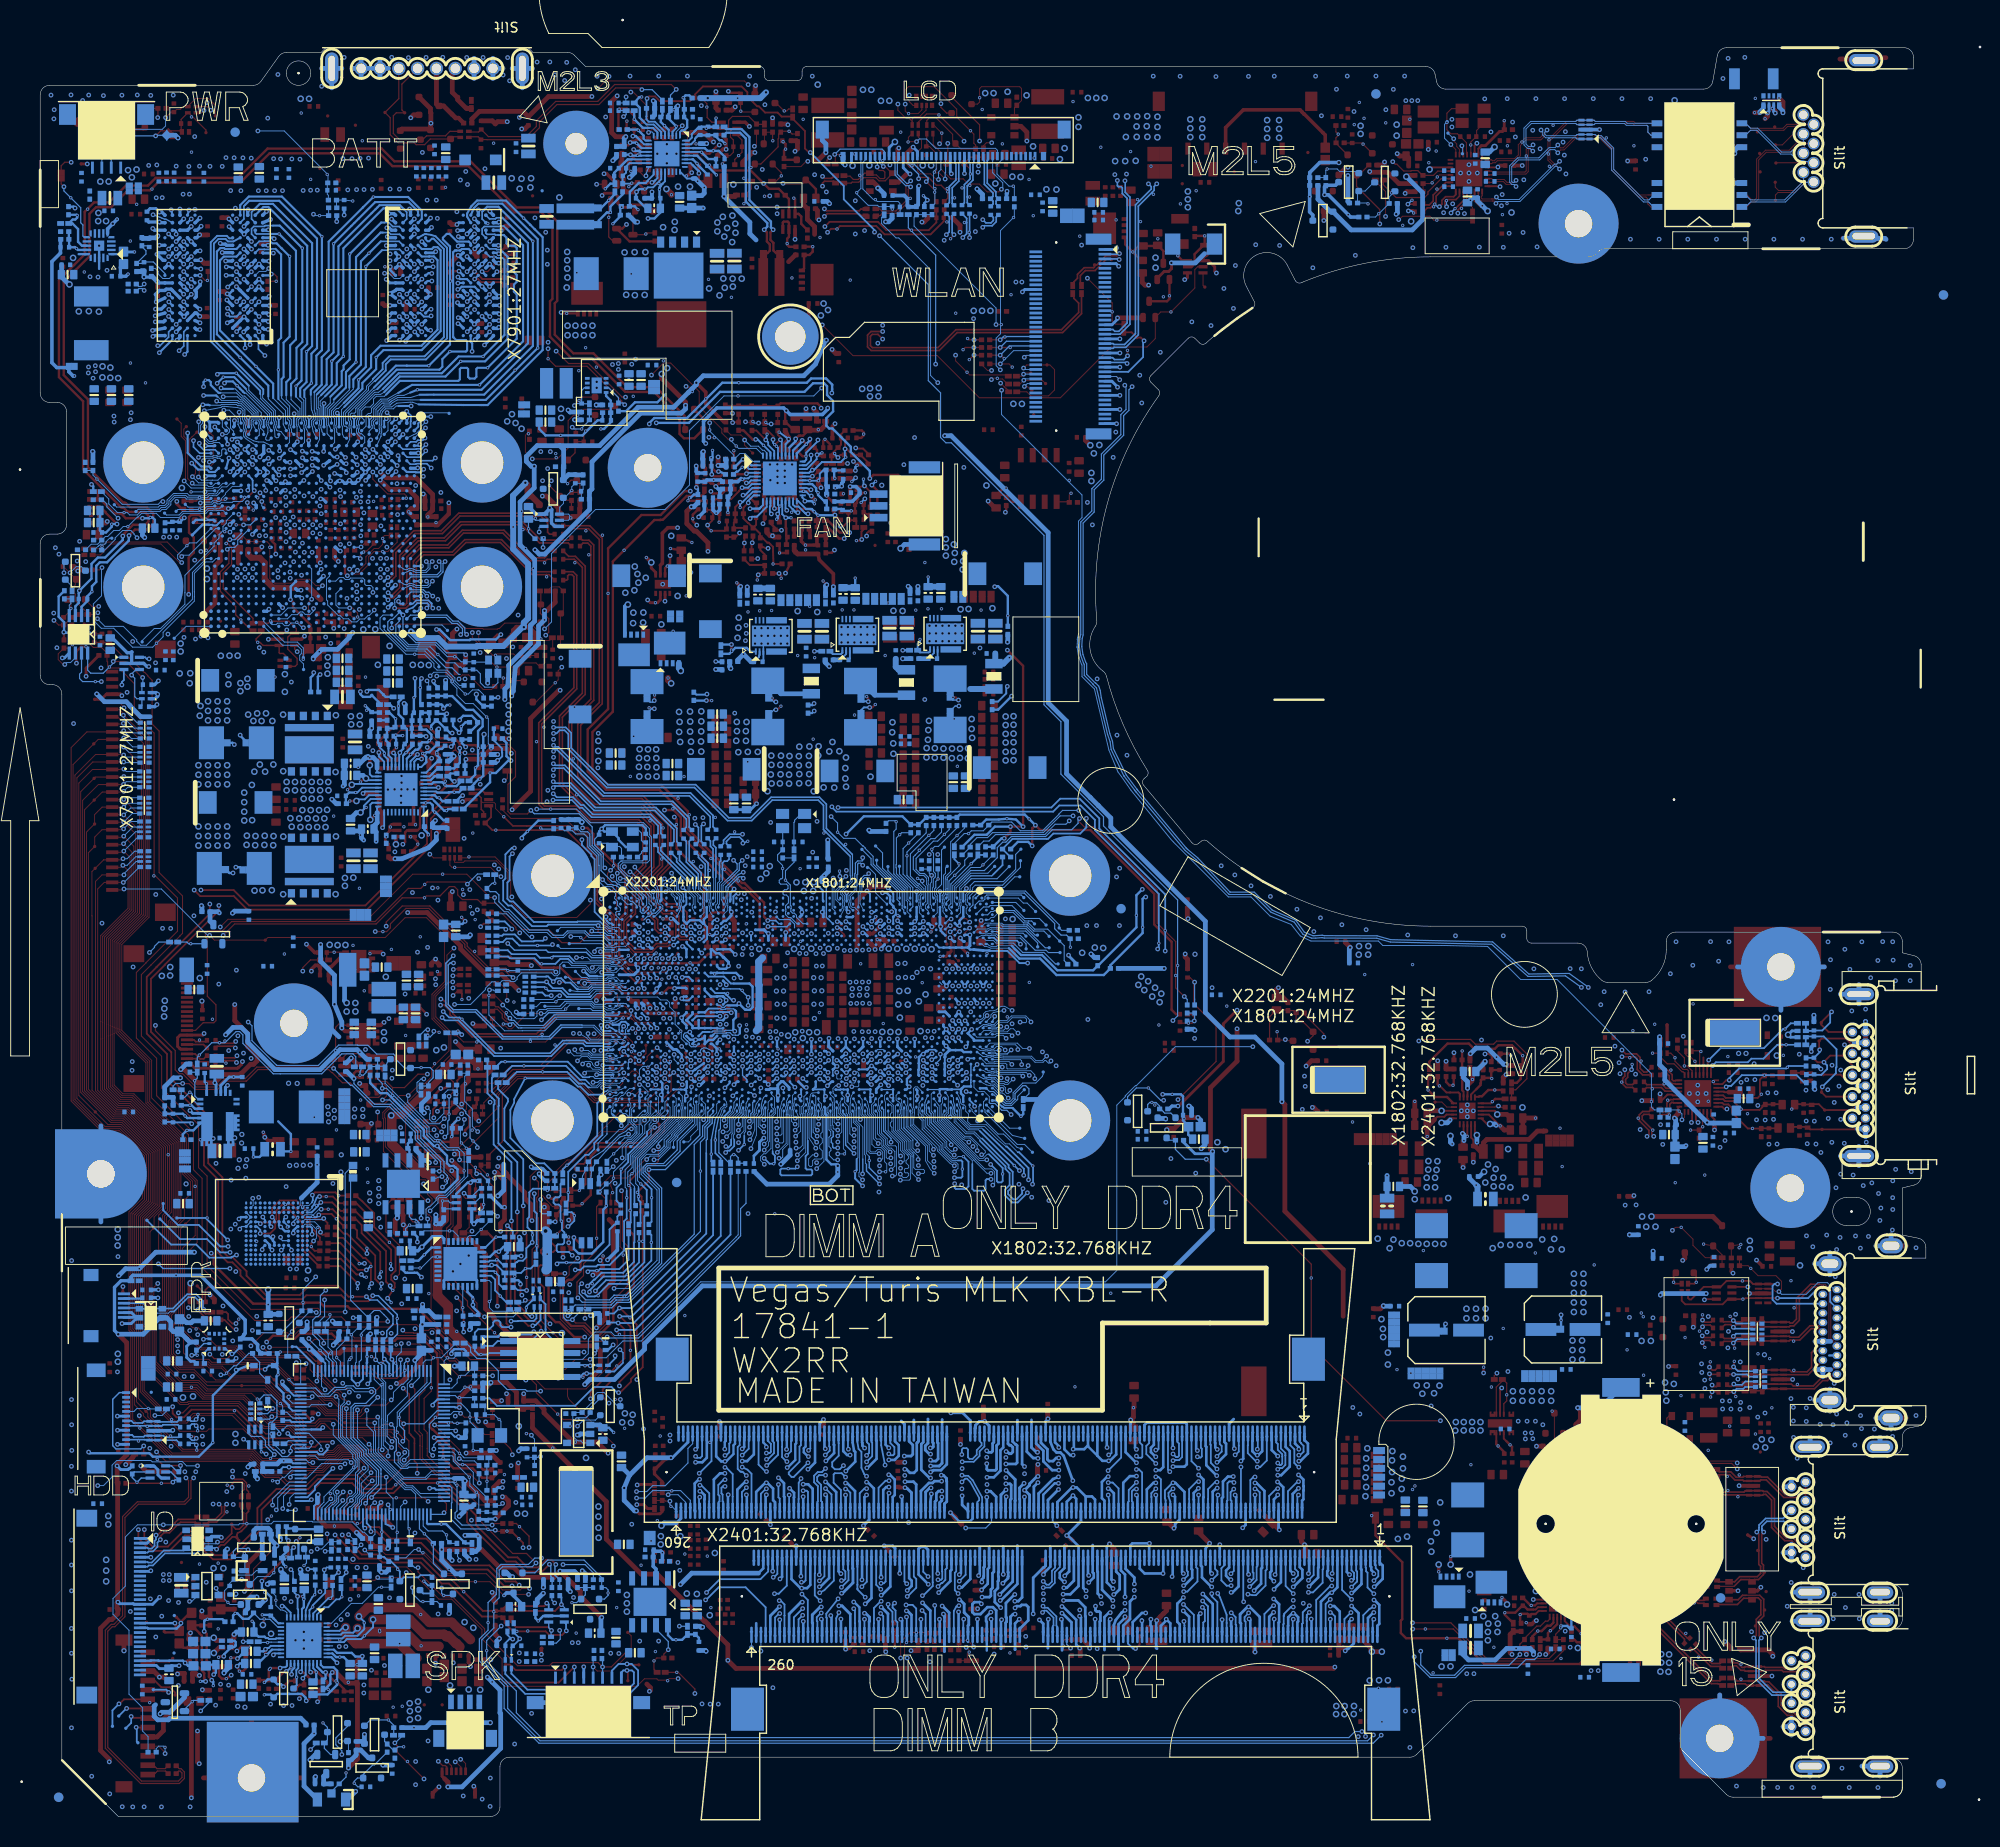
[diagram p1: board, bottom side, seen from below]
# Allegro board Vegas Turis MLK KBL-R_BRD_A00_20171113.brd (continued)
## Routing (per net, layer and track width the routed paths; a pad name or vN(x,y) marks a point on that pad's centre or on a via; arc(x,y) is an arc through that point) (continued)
DQA1_7: length 24.9
  BOTTOM w0.102: 176.11,150.93 176.11,150.67 174.53,149.09 174.53,148 174.51,147.93 174.35,147.6 GPU1.C13
  BOTTOM w0.229: 176.11,150.93 176.11,152.08 v2(179.11,155.07) 181.58,157.54 181.58,166.33 181.21,166.71 180.82,166.71 180.72,166.61 179.49,166.61 VRAM2.N4
DQA1_8: length 28.4
  L3 w0.203: v1(186.7,165.8) 187.16,165.34 187.16,162.55 187.47,162.25 187.47,157.3 186.63,156.47 186.63,155.35 184.74,153.45 182.43,153.45 181.79,152.81 181.23,152.81 v1(180.77,152.35)
  BOTTOM w0.102: 178.65,151.29 178.5,151.29 176.19,148.99 176.19,148.54 176.33,148.23 176.33,147.92 176.16,147.56 176.16,147.09 176.39,146.53 176.39,146.39 176.28,146.28 176.02,146.28 GPU1.E11
  BOTTOM w0.229: v1(180.77,152.35) 180.59,152.53 179.88,152.53 v2(179.43,152.07) 179.11,151.76 178.8,151.44 178.79,151.44 178.65,151.29 ; v1(186.7,165.8) 186.56,165.8 186.3,166.06 VRAM2.M13
DQA1_9: length 27.6
  L3 w0.203: v1(185.1,165.8) 186.8,164.1 186.8,162.34 187.16,161.98 187.16,159.13 186.97,158.94 186.54,158.94 186.4,158.8 186.4,158.42 186.6,158.22 186.83,158.22 187.04,158.01 187.04,157.71 186.83,157.5 186.6,157.5 186.4,157.3 186.4,156.68 186.1,156.39 186.1,155.55 184.42,153.87 182.11,153.87 v1(181.53,153.28)
  BOTTOM w0.102: GPU1.A11 175.79,148.11 175.79,149.19 178.18,151.59 178.18,152.08
  BOTTOM w0.229: v1(181.53,153.28) 181.41,153.41 v2(179.51,153.41) 178.18,152.08 ; v1(185.1,165.8) VRAM2.M11
DQA1_10: length 29.6
  L3 w0.203: v1(181.54,152.33) 181.78,152.33 182.43,152.99 185.01,152.99 187.17,155.15 187.17,156.43 187.91,157.17 187.91,158.09 188.22,158.4 188.3,158.4 188.58,158.69 188.58,161.06 187.9,161.74 187.9,162.36 187.46,162.8 187.46,165.84 v1(186.7,166.6)
  BOTTOM w0.102: 178.49,151.75 178.4,151.52 175.99,149.11 175.99,148.5 176.13,148.17 176.13,147.96 GPU1.C11
  BOTTOM w0.229: v1(181.54,152.33) 181.54,152.34 v2(180.89,152.99) 179.73,152.99 178.49,151.75 ; VRAM2.N13 v1(186.7,166.6)
DQA1_11: length 40.5
  L3 w0.203: v1(188.36,170.25) 189.04,170.25 190.55,168.74 191.54,166.96 191.54,162.5 191.55,162.49 191.55,154.57 186.92,149.94 183.17,149.94 v1(183.07,150.04)
  BOTTOM w0.102: 182.33,149.99 182.31,150 181.18,150 181.09,150.09 179.51,150.09 179.38,149.96 179.05,149.96 178.6,149.51 178.6,148.96 178.65,148.91 178.65,148.58 178.58,148.44 178.47,148.33 178.47,147.98 178.53,147.84 178.53,147.61 178.47,147.49 178.47,147.18 178.53,147.04 178.53,146.81 178.48,146.71 178.36,146.6 177.67,146.21 177.14,146.09 176.61,146.09 GPU1.F11
  BOTTOM w0.14: v1(188.36,170.25) 187.63,169.98 187.42,169.89 187.13,169.77 186.99,169.77 VRAM2.T13
  BOTTOM w0.229: 182.33,149.99 182.5,150.04 v1(183.07,150.04)
DQA1_12: length 34.5
  L3 w0.203: v1(180.9,150.9) 181.06,151.06 182.07,151.06 182.52,151.5 186.27,151.5 189.99,155.22 189.99,161.84 189.8,162.02 189.8,166.68 188.08,168.4 187.38,168.57 186.78,168.66 185.74,168.66 185.34,168.26 v1(185.1,167.39)
  BOTTOM w0.102: GPU1.A9 177.42,148.43 177.42,149.19 178.79,150.57 179.07,150.57 179.4,150.9 v1(180.9,150.9)
  BOTTOM w0.229: v1(185.1,167.39) VRAM2.N11
DQA1_13: length 37.5
  L3 w0.203: v1(182.99,151.03) 183.66,151.03 183.71,150.98 186.49,150.98 190.51,155 190.51,162.05 190.32,162.24 190.32,166.85 189.57,168.24 188.58,169.24 188.1,169.24 187.87,169.02 185.08,169.02 v1(184.3,169.8)
  BOTTOM w0.102: 181.52,150.9 181.49,150.9 181.07,150.49 179.34,150.49 179.21,150.36 178.88,150.36 177.64,149.12 177.64,148.38 177.73,148.28 177.73,147.96 GPU1.C9
  BOTTOM w0.229: VRAM2.T11 v1(184.3,169.8) ; 181.52,150.9 181.65,151.03 v1(182.99,151.03)
DQA1_14: length 40.8
  L3 w0.203: v1(186.43,170.77) 187.62,170.98 188.02,170.98 189.08,170.72 189.47,170.56 191.02,169 192.08,167.06 192.08,154.36 187.14,149.42 v1(182.91,149.42)
  BOTTOM w0.102: v1(182.91,149.42) 181.12,149.77 181.01,149.88 180.78,149.88 179.41,149.75 179.03,149.65 178.8,149.43 178.8,149.09 178.85,148.94 178.85,148.5 178.74,148.31 178.67,148.18 178.67,148.03 178.73,147.89 178.73,147.53 178.67,147.39 178.67,147.23 178.73,147.09 178.73,146.73 178.69,146.64 178.49,146.43 GPU1.F9
  BOTTOM w0.229: v1(186.43,170.77) 186.43,170.77 VRAM2.U13
DQA1_15: length 38.7
  L3 w0.203: v1(181.6,150.44) 182.31,150.44 182.6,150.5 183.46,150.5 183.5,150.46 186.71,150.46 191.03,154.78 191.03,162.27 190.85,163.28 190.85,167.04 190.02,168.53 188.77,169.78 188.03,169.78 187.87,169.93 186.12,169.93 185.89,170.03 185.55,170.3 185.25,170.43 v1(184.54,170.75)
  BOTTOM w0.102: GPU1.D8 177.87,147.62 177.87,147.79 177.93,147.92 177.93,148.37 177.84,148.47 177.84,149.04 178.96,150.16 179.29,150.16 179.42,150.29 181.45,150.29 v1(181.6,150.44)
  BOTTOM w0.229: VRAM2.U11 v1(184.54,170.75)
DQA1_16: length 20.3
  L4 w0.203: v1(177.11,160.99) 176.21,160.09 175.87,160.09 175.12,159.34 175.12,149.93 176.14,148.9 176.14,148.44 177.88,146.71 179.63,146.71 v1(179.98,146.36)
  BOTTOM w0.229: VRAM2.E2 177.11,160.99 v1(177.11,160.99) ; GPU1.E7 179.06,146.56 179.58,146.56 179.64,146.51 179.83,146.51 v1(179.98,146.36)
DQA1_17: length 11.5
  L4 w0.203: v1(179.21,149.26) 178.23,149.26 176.48,151.02 v1(176.48,155.28)
  BOTTOM w0.102: GPU1.A7 179.06,148.17 179.06,148.61 179.21,148.75 v1(179.21,149.26)
  BOTTOM w0.178: v1(176.48,155.28) 177.16,155.97 177.16,157.06 VRAM2.A2
DQA1_18: length 12.4
  L4 w0.203: v1(178.58,156.09) 178.53,156.09 178.53,156.09 178.53,151.78 v1(180.84,149.48)
  BOTTOM w0.102: GPU1.C7 179.33,147.96 179.33,147.96 179.33,148.24 179.31,148.26 179.31,148.53 180.25,149.48 v1(180.84,149.48)
  BOTTOM w0.229: VRAM2.A4 178.58,156.88 v1(178.58,156.09)
DQA1_19: length 21.9
  L4 w0.203: v1(179.4,146.09) 178.06,146.09 175.67,148.48 175.67,148.75 174.48,149.94 174.48,159.72 175.88,161.12 176.22,161.12 176.54,161.44 177.46,161.44 v1(177.9,161)
  BOTTOM w0.229: VRAM2.F2 v1(177.9,161) ; GPU1.F7 179.02,145.7 179.4,146.09 179.41,146.09 179.41,146.09 v1(179.4,146.09)
DQA1_20: length 14.5
  L4 w0.203: v1(179.48,157.82) 179.48,156.73 179.41,156.66 179.41,151.55 181.48,149.48 181.48,148.11 181,147.63 v1(181,146.9)
  BOTTOM w0.102: v1(181,146.9) 180.5,146.9 180.3,147.1 180.24,147.21 180.24,147.39 180.3,147.5 180.6,147.8 GPU1.A5
  BOTTOM w0.229: VRAM2.B4 v1(179.48,157.82)
DQA1_21: length 16.5
  L4 w0.203: v1(177.1,157.81) 176.62,157.81 175.66,156.86 175.66,150.51 177.98,148.19 178.79,148.19 180.44,146.54 v1(180.44,145.86)
  BOTTOM w0.229: v1(180.44,145.86) GPU1.E5 ; v1(177.1,157.81) 177.11,157.81 VRAM2.B2
DQA1_22: length 16.3
  L4 w0.203: v1(178.72,160.99) 179.17,160.54 179.17,158.78 179.93,158.01 179.93,152.05 180.63,151.36 181.33,151.36 182.06,150.62 182.06,150.25 181.8,149.99 v1(181.8,147.69)
  BOTTOM w0.229: GPU1.C3 181.41,147.3 v1(181.8,147.69) ; v1(178.72,160.99) 179.1,160.61 VRAM2.E4
DQA1_23: length 16.9
  L4 w0.203: v1(179.47,161.02) 179.47,158.91 180.48,157.9 180.48,154.97 181.71,153.74 181.71,153.74 182.36,153.09 182.36,150.12 182.13,149.89 182.13,148.43 v1(182.84,147.72)
  BOTTOM w0.178: GPU1.E1 182.84,147.14 v1(182.84,147.72)
  BOTTOM w0.229: v1(179.47,161.02) 179.1,161.39 VRAM2.F4
DQA1_24: length 27.1
  L4 w0.203: v1(179.39,144.51) 180.7,143.2 184.26,143.2 184.71,143.64 184.71,143.84 188.81,147.94 188.81,156.05 187.66,157.2 187.66,160.01 v1(186.68,160.99)
  BOTTOM w0.229: VRAM2.E13 186.68,160.98 v1(186.68,160.99) ; GPU1.G7 v1(179.39,144.51)
DQA1_25: length 20.3
  L4 w0.203: v1(180.18,145.28) 181.19,145.28 184.09,148.18 184.09,153.76 184.08,153.77 184.08,153.99 183.65,154.42 183.65,156.42 183.85,156.62 183.85,161.33 v1(184.3,161.79)
  BOTTOM w0.229: v1(184.3,161.79) 184.31,161.79 VRAM2.F11 ; GPU1.G6 179.8,144.9 v1(180.18,145.28)
DQA1_26: length 14.6
  L4 w0.203: v1(185,155.39) 185.13,155.27 185.13,149.04 184.91,148.81 184.91,148.13 184.37,147.6 184.06,147.25 v1(184.06,146.23)
  BOTTOM w0.178: GPU1.G1 183.4,144.9 184.06,145.56 v1(184.06,146.23)
  BOTTOM w0.229: VRAM2.A11 184.7,155.69 v1(185,155.39)
DQA1_27: length 19.3
  L4 w0.203: v1(185.1,161) 184.46,160.37 184.46,158.83 184.18,158.55 184.18,155.48 184.6,155.06 184.6,148.26 183.44,147.1 v1(183.44,145.96)
  BOTTOM w0.178: GPU1.G3 181.77,145.27 182.35,145.27 182.37,145.25 182.97,145.25 183.44,145.72 v1(183.44,145.96)
  BOTTOM w0.229: v1(185.1,161) 184.7,160.61 VRAM2.E11
DQA1_28: length 28.1
  L4 w0.203: v1(186.69,161.78) 187.86,161.78 189.33,160.31 189.33,147.7 184.52,142.89 180.21,142.89 v1(180.18,142.92)
  BOTTOM w0.229: VRAM2.F13 186.68,161.78 v1(186.69,161.78) ; GPU1.J6 v1(180.18,142.92)
DQA1_29: length 17.2
  L4 w0.203: v1(184.68,147.05) 184.68,147.48 185.31,148.1 185.31,148.68 185.65,149.02 185.65,155.74 v1(185.59,155.8)
  BOTTOM w0.178: v1(185.59,155.8) 185.09,156.29 185.09,157.81 VRAM2.B11
  BOTTOM w0.229: v1(184.68,147.05) 184.68,144.94 183.23,143.49 182.39,143.49 GPU1.J1
DQA1_30: length 20.4
  L4 w0.203: v1(187.86,156.33) 188.23,155.95 188.23,148.1 184.25,144.12 v1(184.25,143.83)
  BOTTOM w0.178: VRAM2.B13 186.71,157.79 186.71,157.24 187.62,156.33 v1(187.86,156.33)
  BOTTOM w0.229: GPU1.J3 181.79,142.91 182.38,142.91 182.63,143.16 183.58,143.16 v1(184.25,143.83)
DQA1_31: length 20.7
  L4 w0.203: v1(180.3,144.38) 181.17,143.5 183.23,143.5 183.95,144.22 183.95,144.25 183.99,144.29 183.99,144.62 187.69,148.32 v1(187.69,155.58)
  BOTTOM w0.229: VRAM2.A13 186.3,156.97 v1(187.69,155.58) ; GPU1.J5 v1(180.3,144.38)
DRAM_RST: length 24.5
  L4 w0.102: v1(163.76,164.02) 165.04,164.02 v1(171.32,170.3) 174.45,167.16 174.45,166.15 v1(176.07,164.53)
  BOTTOM w0.102: v1(163.76,164.02) 163.3,164.02 162.74,163.47 162.13,163.47 VRAM1.J2 ; v1(176.07,164.53) 176.38,164.22 177.08,164.22 VRAM2.J2 ; v1(171.32,170.3) 171.17,170.16 v2(170.67,170.16) R7802.2 169.7,170.16 R7804.1
DRAM_RST_R: length 2.6
  BOTTOM w0.102: R7804.2 168.87,171.01 R7803.1 C7802.1 v2(167.14,171.71)
DRAM_RST_VGA1: length 92.4
  L3 w0.102: v1(177.22,179.15) 189.34,179.15 197.77,170.72 197.77,153.38 193.67,149.28 193.67,147 192.62,145.95 192.62,140.49 193.68,139.42 193.68,137.11 193.28,136.71 183.44,136.71 180,140.16 176.95,140.16 176.38,140.73 v1(176.38,140.94)
  BOTTOM w0.102: v1(177.22,179.15) 174.42,179.15 169.85,174.58 v2(169.85,174.52) 169.77,174.45 169.77,173.66 R7819.1 169.84,173.59 C7803.1 169.84,172.42 169.73,172.31 R7803.2 ; GPU1.L10 176.38,141.28 v1(176.38,140.94)
E51_RX1: length 2.6
  TOP w0.102: TP6102.1 95.59,155.3 v1(95.79,155.09)
  BOTTOM w0.102: v1(95.79,155.09) 95.59,155.3 WLAN1.46
E51_RX2: length 2.3
  TOP w0.102: TP6103.1 95.05,151.56 95.49,152 v1(95.78,152)
  BOTTOM w0.102: WLAN1.58 95.47,152.3 v1(95.78,152)
E51_TX1: length 6.9
  TOP w0.102: R6115.2 v1(98.34,154.39) 97.41,154.39 v2(97.07,154.05)
  BOTTOM w0.102: WLAN1.44 96.93,155.8 v1(98.34,154.39)
E51_TXD_R: length 42.9
  TOP w0.102: v1(148.46,23.6) 151.22,23.6 152.57,24.95 v2(154.11,24.95) 155.79,24.95 156.44,25.6 157.34,25.6 159.57,27.83 163.64,27.83 164.09,28.28 165.82,28.28 v1(165.87,28.32) ; v1(156.25,5.81) 156.2,5.81 155.65,5.26 DB3.5
  L3 w0.102: v1(156.25,5.81) 156.25,6.24 153.09,9.4 152.46,9.4 151.8,10.06 151.8,10.63 149.6,12.83 148.97,13.46 148.97,23.09 v1(148.46,23.6)
  BOTTOM w0.102: v1(165.87,28.32) 165.5,27.96 165.43,27.79 R2466.2
EC_AGND: length 14.8
  TOP w0.508: v1(151.99,31.61) 150.59,33.01 150.59,33.54 150.98,33.93 151.2,33.93 151.25,33.98 v1(151.24,33.98) ; C2441.2 151.52,37.63 152.53,38.63 v1(155.09,38.63)
  L3 w0.508: v1(150.32,37.29) 150.54,37.08 153.54,37.08 v1(155.09,38.63)
  BOTTOM w0.305: v1(151.99,31.61) 152.74,31.61 C2407.2 153.02,31.57 R2441.2
  vias: v2(151.03,36.34)
EC_BRIGHTNESS: length 194.5
  TOP w0.114: v2(123.4,172.21) 123.37,172.21 123.37,172.25 v1(122.84,172.25) ; v1(103.92,177.83) 103.92,175.85 D5503.2
  L3 w0.114: v1(122.84,172.25) 122.09,171.5 121.88,171.5 121.61,171.23 121.61,162.8 126.6,157.81 136.16,157.81 138.39,155.59 138.39,153.37 140.64,151.11 140.64,149.59 143.33,146.91 143.33,139.33 147.13,135.53 147.5,135.53 148.4,134.63 148.4,128.26 148.35,128.2 148.35,126.3 148.91,125.73 148.91,122.04 151.51,119.44 151.9,119.44 152.32,119.02 152.32,115.4 152.32,115.39 152.32,112.17 155.46,109.03 155.56,109.03 158.3,106.29 158.57,106.29 160.37,104.5 160.37,103.58 161.23,102.72 161.23,101.05 165.75,96.52 165.75,93.64 165.7,93.6 165.7,91.71 168,89.41 174.83,89.41 179.17,85.07 179.28,85.07 181.16,83.19 181.16,82.56 184.06,79.66 184.06,77.87 185.28,76.64 185.28,72.98 184.73,72.43 183.91,71.61 183.91,69.49 180.87,66.45 180.87,59.59 179.57,58.29 v1(179.57,57.92)
  L4 w0.114: v1(122.84,172.25) 122.84,172.84 121.69,174 121.69,176.07 118.4,179.36 105.45,179.36 v1(103.92,177.83) ; v1(170.14,54.92) 170.65,55.43 177.08,55.43 v1(179.57,57.92)
  BOTTOM w0.114: v1(170.14,54.92) 170.14,53.17 170.85,52.46 R2456.1
EDCA0_0: length 23.2
  L4 w0.203: v1(153.4,159.45) 153.4,156.81 153.98,156.24 153.98,154.93 153.77,154.72 153.56,154.72 153.36,154.52 153.36,154.22 153.56,154.01 153.77,154.01 153.98,153.81 153.98,153.51 153.77,153.3 153.56,153.3 153.36,153.1 153.36,152.79 153.56,152.59 153.77,152.59 153.98,152.39 153.98,151.68 156.42,149.23 156.42,148.09 157.81,146.71 157.81,146.09 159.43,144.47 162.15,144.47 v1(162.33,144.64)
  BOTTOM w0.229: GPU1.H28 162.2,144.52 v1(162.33,144.64) ; VRAM1.R13 v1(153.4,159.45)
EDCA0_1: length 16.7
  L4 w0.203: v1(162.19,159.41) 162.63,159.41 162.75,159.29 162.75,158.69 163.06,158.38 163.48,158.38 163.81,158.72 164.15,158.72 164.33,158.54 164.33,156.71 163.92,156.3 163.92,153.77 164.22,153.46 164.22,152.16 164,151.94 163.24,151.94 163.02,151.72 163.02,147.81 162.9,147.68 v1(162.62,147.68)
  BOTTOM w0.229: GPU1.C27 v1(162.62,147.68) ; VRAM1.R2 161.8,159.02 v1(162.19,159.41)
EDCA0_2: length 38.8
  BOTTOM w0.102: GPU1.A23 166.05,148.1 165.93,148.23 165.93,148.43 166.19,148.69 166.19,149.43 165.8,149.81 165.29,149.81 164.93,150.17 164.93,150.66 164.64,150.95 163.78,150.95 163.6,151.13
  BOTTOM w0.178: VRAM1.C13 153,168.3 152.87,168.17 152.05,168.17 151.97,168.09 151.7,168.09
  BOTTOM w0.229: 151.7,168.09 151.1,168.09 150.81,167.81 150.81,167.2 150.55,166.95 149.95,166.95 149.72,166.72 149.72,165.19 150.02,164.89 150.02,164.15 149.72,163.85 149.72,163.12 150.02,162.82 150.02,162.08 149.72,161.78 149.72,157.07 v2(152.81,153.98) 153.88,153.98 154,153.85 154,153.02 154.19,152.84 154.71,152.84 154.88,153.01 154.88,153.84 155.01,153.97 155.63,153.97 155.76,153.84 155.76,152.75 155.92,152.59 162.14,152.59 163.6,151.13
EDCA0_3: length 28.2
  BOTTOM w0.102: GPU1.E19 169.76,146.86 169.87,147.01 169.87,147.81 169.94,147.94 169.94,148.59 170,148.65 170,149.76 169.53,150.23 169.53,150.89
  BOTTOM w0.178: 163.78,169.42 163.32,169.42 162.89,169 162.2,169 VRAM1.C2
  BOTTOM w0.229: 169.53,150.89 168.31,152.11 168.31,153.62 168.12,153.81 168.12,154.22 167.47,154.87 v2(167.47,166.07) 164.12,169.42 163.78,169.42
EDCA1_0: length 26.7
  BOTTOM w0.102: GPU1.E15 172.86,146.5 173.06,146.7 173.06,147.76 173.13,147.92 173.13,148.54 172.96,148.72 172.96,149.35 174.21,150.6 174.21,151.07
  BOTTOM w0.178: VRAM2.R2 177.5,168.33 177.37,168.2 175.92,168.2
  BOTTOM w0.229: 175.92,168.2 v2(174.96,168.2) 173.17,166.41 173.17,156.99 173.79,156.38 173.79,152.86 174.21,152.45 174.21,151.07
EDCA1_1: length 34
  L3 w0.203: v1(181.13,151.83) 181.13,151.75 181.33,151.54 181.9,151.54 182.89,152.53 185.26,152.53 185.63,152.9 185.92,152.9 188.74,155.71 188.74,156.64 189.04,156.93 189.04,161.21 188.39,161.86 188.39,163.66 188.26,163.79 188.15,163.79 187.92,164.02 187.92,165.15 188.13,165.36 188.57,165.36 188.77,165.56 188.77,166.34 188.57,166.54 187.45,166.54 187.18,166.81 187.18,167.03 187,167.21 186.64,167.21 186.44,167.41 186.44,167.8 186.06,168.18 v1(185.9,168.18)
  BOTTOM w0.102: 179.87,151.74 179.62,151.74 178.86,150.97 178.62,150.97 176.86,149.2 176.86,148.95 177.01,148.8 177.01,148.47 176.98,148.44 176.96,148.41 176.87,148.3 176.87,147.98 176.93,147.84 176.93,147.57 176.92,147.55 176.6,147.23 GPU1.D10
  BOTTOM w0.229: 179.87,151.74 181.04,151.74 v1(181.13,151.83) ; v1(185.9,168.18) 185.9,168.47 186.03,168.6 VRAM2.R13
EDCA1_2: length 15.3
  L4 w0.203: v1(177.1,158.6) 177.43,158.6 177.56,158.47 177.56,157.46 176.79,156.69 176.79,155.93 177.3,155.42 177.3,150.83 177.8,150.33 178.81,150.33 180.33,148.82 v1(180.33,148.62)
  BOTTOM w0.102: v1(180.33,148.62) 180.34,148.62 180.34,148.59 180.13,148.39 180.13,147.62 180.08,147.51 179.8,147.23 GPU1.D6
  BOTTOM w0.229: VRAM2.C2 v1(177.1,158.6)
EDCA1_3: length 21.2
  L4 w0.203: v1(183.53,144.45) 183.53,144.59 185.44,146.5 185.44,147.08 186.98,148.62 186.98,159.17 v1(186.71,159.44)
  BOTTOM w0.102: v1(183.53,144.45) 183.41,144.57 182.06,144.57 181.93,144.63 181.61,144.63 181.58,144.61 181.47,144.57 181.19,144.57 181.07,144.7 181.07,145.23 180.94,145.36 180.73,145.36 180.6,145.23 GPU1.G5
  BOTTOM w0.229: VRAM2.C13 186.3,159.03 v1(186.71,159.44)
EDP_AUX_CON_N: length 6.1
  BOTTOM w0.178: C5533.2 99.1,171.39 99.1,171.68 R5529.1 99.11,172.21 99.11,172.56 100.03,173.48 100.03,175.95 100.15,176.07 LCD1.12
EDP_AUX_CON_P: length 6.1
  BOTTOM w0.178: LCD1.11 99.65,176.09 99.73,176.01 99.73,173.6 98.81,172.68 98.81,172.22 R5528.1 98.79,171.7 98.79,171.39 C5531.2
EDP_AUX_CPU_N: length 108.7
  L4 w0.152: v1(100.2,169.72) 100.72,169.2 104.48,169.2 105.18,168.51 105.18,167.16 104.72,166.71 104.72,155.54 104.72,155.35 104.72,155.16 104.72,155.16 104.72,154.01 93.68,142.97 93.68,121.33 92.87,120.51 92.87,110.24 95.31,107.8 107.43,107.8 112.24,102.99 113.18,102.99 114.8,101.37 115.53,101.37 117.39,99.51 117.39,98.33 115.72,96.66 114.07,96.66 113.63,96.22 113.63,95.61 113.63,95.6 113.63,95.14 114.01,94.76 114.39,94.76 v1(114.75,95.12)
  BOTTOM w0.178: v1(100.2,169.72) 99.86,169.38 99.33,169.38 99.08,169.63 99.08,169.95 C5533.1 ; CPU1.E45 v1(114.75,95.12)
EDP_AUX_CPU_P: length 108.8
  L4 w0.152: v1(100.2,168.91) 104.36,168.91 104.89,168.39 104.89,167.28 104.43,166.83 104.43,155.54 104.43,155.16 104.43,154.13 93.39,143.09 93.39,121.45 92.57,120.64 92.57,110.12 95.18,107.51 107.31,107.51 112.12,102.69 113.06,102.69 114.67,101.08 115.41,101.08 117.1,99.39 117.1,98.45 115.6,96.95 113.95,96.95 113.34,96.34 113.34,95.73 113.34,95.72 113.34,95.02 113.89,94.47 v1(114.75,94.47)
  BOTTOM w0.178: C5531.1 98.77,169.99 98.77,169.51 99.21,169.07 100.04,169.07 v1(100.2,168.91) ; CPU1.F45 v1(114.75,94.47)
EDP_BKLT_CTRL: length 3.7
  TOP w0.114: R5530.2 100.13,176.37 R5524.2 101.49,176.37 D5503.1 101.52,175.07 101.52,174.72 101.51,174.72 v2(101.51,174.58)
EDP_COMP: length 3.4
  TOP w0.203: v1(111.11,94.57) 111.53,94.99 111.53,95.54 v2(111.61,95.62)
  TOP w0.381: v1(111.11,94.57) 111.15,94.57 111.89,93.83 R801.2
  BOTTOM w0.305: CPU1.E52 110.95,94.57 v1(111.11,94.57)
EDP_DISP_UTIL: length 4.8
  BOTTOM w0.102: CPU1.B52 111.59,98.17 111.59,100.13 112.33,100.86 TP801.1
EDP_HPD: length 132.4
  TOP w0.102: v1(109.22,182.01) 109.22,181.35 108.34,180.47 108.01,180.47 107.7,180.17 ; v1(129.3,146.59) 129.26,146.55 v2(128.73,146.55) ; RN5502.6 106.23,181.81 106.23,181.36 106.97,180.62 107.5,180.62 107.7,180.42 107.7,180.17 ; 107.7,180.17 RN5503.3
  L3 w0.102: v1(129.3,146.59) 130.07,146.59 132.27,144.39 132.27,139.72 133,139 133,138.82 138.83,132.99 138.83,111.92 136.13,109.22 133.48,109.22 131.3,107.04 131.3,104.17 127.59,100.46 127.59,95.68 127.1,95.19 127.1,93.08 127.7,92.48 130.44,92.48 132.15,90.77 134.48,90.77 v1(134.88,91.17) ; v1(109.22,182.01) 109.22,181.35 108.54,180.67 108.54,172.52 112.5,168.56 v1(112.76,168.56)
  L4 w0.102: v1(129.3,146.59) 128.77,146.59 127.63,147.72 126.6,147.72 123.87,150.45 120.48,150.45 116.69,154.24 111.67,154.24 110.41,155.5 110.41,162.96 112.83,165.39 112.83,168.49 v1(112.76,168.56)
  BOTTOM w0.102: v1(134.88,91.17) 134.48,91.57 CPU1.L10
EDP_HPD_CONN: length 11.8
  TOP w0.102: 108.11,178.01 108.1,178.01 v1(107.23,178.01) ; 108.11,178.01 v2(108.14,177.98) ; 108.11,178.01 108.11,178.47 RN5503.2
  BOTTOM w0.102: LCD1.9 98.65,177.1 98.85,177.3 105.2,177.3 106.19,178.3 106.95,178.3 v1(107.23,178.01)
EDP_TX_CON_N0: length 5.8
  BOTTOM w0.178: v2(101.62,172.13) 101.85,172.14 ; 101.85,172.14 101.85,173.32 101.25,173.92 101.25,175.69 101.15,175.79 LCD1.14 ; 101.85,172.14 101.85,171.52 C5508.2
EDP_TX_CON_N1: length 5.9
  BOTTOM w0.178: 103.45,172.04 103.45,173.12 102.75,173.82 102.75,175.69 102.65,175.79 LCD1.17 ; 103.45,172.04 103.45,171.44 C5534.2 ; 103.45,172.04 v2(103.21,172.04)
EDP_TX_CON_P0: length 5.9
  BOTTOM w0.178: v2(102.41,173.1) 102.16,173.1 ; 102.16,173.1 102.16,171.52 C5532.2 ; 102.16,173.1 102.16,173.44 101.55,174.05 101.55,175.69 101.65,175.79 LCD1.15
EDP_TX_CON_P1: length 5.9
  BOTTOM w0.178: 103.75,173.03 103.75,171.54 C5537.2 ; 103.75,173.03 103.75,173.24 103.05,173.94 103.05,175.69 103.15,175.79 LCD1.18 ; 103.75,173.03 v2(103.98,173.03)
EDP_TX_CPU_N0: length 96.4
  TOP w0.178: v1(101.61,167.82) v2(101.64,168.37)
  L4 w0.152: v1(112.32,99.58) 112.19,99.71 111.7,99.71 105.63,105.78 94.38,105.78 90.87,109.29 90.87,121.41 91.69,122.22 91.69,142.96 91.69,142.97 91.69,143.8 102.28,154.39 102.28,166.37 101.61,167.04 v1(101.61,167.82)
  BOTTOM w0.089: CPU1.C47 113.24,97.05 113.24,98.1 113.04,98.3 113.04,98.83
  BOTTOM w0.127: v1(112.32,99.58) 112.54,99.79 112.72,99.79 112.84,99.67 112.84,99.67 113.04,99.47 113.04,98.83
  BOTTOM w0.178: v1(101.61,167.82) C5508.1
EDP_TX_CPU_N1: length 97.9
  TOP w0.178: v1(103.26,168.12) v2(103.63,167.7)
  L4 w0.152: v1(103.26,168.12) 103.26,165.39 103.58,165.07 103.58,154.48 92.54,143.45 92.54,142.41 92.54,121.82 91.72,121 91.72,109.67 94.79,106.61 106.95,106.61 112.27,101.28 112.78,101.28 v1(112.96,101.1)
  BOTTOM w0.089: CPU1.D46 113.43,96.22 113.83,96.63 114.07,96.63 114.2,96.75 114.26,96.9 114.25,97.06 114.21,97.15 114.21,97.42 114.25,97.51 114.25,97.79 113.6,98.45 113.6,98.85 113.56,98.88 113.56,98.95
  BOTTOM w0.127: v1(112.96,101.1) 113.18,101.32 113.4,101.32 113.49,101.22 113.49,100.15 113.56,100.08 113.56,98.95
  BOTTOM w0.178: C5534.1 103.46,170.13 103.46,168.32 v1(103.26,168.12)
EDP_TX_CPU_P0: length 96.1
  L4 w0.152: v1(102.32,167.82) 101.9,167.4 101.9,167.16 102.57,166.49 102.57,154.27 91.98,143.68 91.98,142.84 91.98,142.84 91.98,122.1 91.16,121.28 91.16,109.41 94.5,106.07 105.75,106.07 111.82,100 112.11,100 v1(112.32,100.21)
  BOTTOM w0.089: 113.27,98.83 113.25,98.81 113.25,98.36 113.43,98.18 113.43,96.78 113.43,96.77 CPU1.C46
  BOTTOM w0.127: 113.27,98.83 113.27,99.56 112.81,100.02 112.52,100.02 v1(112.32,100.21)
  BOTTOM w0.178: C5532.1 101.91,169.86 101.91,169.42 ; v1(102.32,167.82) 101.91,168.23 101.91,169.42 ; v2(102.15,169.42) 101.91,169.42
EDP_TX_CPU_P1: length 97.6
  L4 w0.152: v1(112.96,101.91) 112.96,101.69 112.85,101.58 112.4,101.58 107.07,106.9 94.91,106.9 92.02,109.79 92.02,120.88 92.83,121.7 92.83,142.29 92.83,143.32 103.87,154.36 103.87,165.2 103.56,165.51 103.56,167.61 v1(104.07,168.12)
  BOTTOM w0.089: CPU1.C45 114.15,96.44 114.35,96.62 114.45,96.89 114.44,97.06 114.39,97.19 114.39,97.39 114.43,97.48 114.43,97.87 113.77,98.52 113.77,98.85 113.81,98.88 113.81,98.91
  BOTTOM w0.127: 113.81,98.91 113.81,100.18 113.74,100.25 113.74,101.32 113.5,101.56 113.02,101.56 112.96,101.63 v1(112.96,101.91)
  BOTTOM w0.178: 103.77,169.47 103.77,168.43 v1(104.07,168.12) ; 103.77,169.47 v2(104.02,169.48) ; 103.77,169.47 103.77,170.06 C5537.1
EDP_VDD_EN: length 184.2
  TOP w0.127: D5502.1 103.52,181.05 104.04,181.05 104.65,181.65 v1(104.65,182.05)
  L3 w0.127: v1(104.65,182.05) 104.65,181.58 103.09,180.02 103.09,174.42 103.98,173.53 105.16,173.53 110.69,168.01 v1(111.17,168.01) ; v1(80,84.6) 86.39,84.6 89,87.2 102.99,87.2 103.65,86.54 103.65,86.29 104.92,85.02 104.92,82.73 105.45,82.19 116.2,82.19 116.74,81.65 124.85,81.65 125.83,82.63 125.83,82.94 125.88,83 125.88,83.57 125.63,83.82 125.63,84.47 124.74,85.37 124.74,85.39 124.67,85.46 124.67,87.29 125.17,87.79 130.17,87.79 131.97,89.59 132.42,89.59 v1(132.82,89.18)
  BOTTOM w0.127: v1(132.82,89.18) 132.53,88.89 CPU1.U13 ; v1(80,84.6) 79.5,85.09 v2(79.5,90.45) 79.5,97.41 87.38,105.28 87.38,106.27 91.9,110.79 91.9,116.37 93.7,118.16 93.7,136.16 103.54,146 104.12,146 104.69,146.57 104.69,151.31 105.99,152.61 105.99,162.83 v1(111.17,168.01)
EDRAM_OPIO_RCOMP: length 2.7
  TOP w0.305: v2(101.81,91.75) 101.89,91.75 102.64,92.5 102.64,92.66
  TOP w0.508: 102.64,92.66 102.64,92.67 ; 102.64,92.67 102.64,93.31 v1(102.58,93.37) ; 102.64,92.67 R414.2
  BOTTOM w0.254: CPU1.H66 102.28,93 102.58,93.3 v1(102.58,93.37)
EMMC_CLK: length 48.1
  TOP w0.191: v1(166.61,56.66) 168.44,58.49 R6320.1
  L4 w0.165: v1(166.61,56.66) 166.29,56.66 164.01,58.94 158.69,58.94 154.73,62.9 154.73,63.16 152.19,65.7 152.19,66.15 150.61,67.73 150.61,70.18 149.98,70.82 149.98,75.66 144.31,81.32 v1(144.2,81.32)
  BOTTOM w0.089: v1(144.2,81.32) 144.1,81.32 143.62,80.85 142.98,80.85 142.88,80.94 142.12,80.94 141.84,80.66 140.3,80.66 140.3,80.66 140.15,80.66 140.14,80.65 140.1,80.65 140.03,80.58 139.71,80.58 139.63,80.62 139.63,80.62 139.35,80.62 139.35,80.62 139.26,80.58 139.06,80.58 138.98,80.62 138.94,80.65 138.71,80.65 CPU1.AM3
  BOTTOM w0.191: v1(166.61,56.66) 166.63,56.64 v2(166.63,56.1)
EMMC_CLK_R: length 13.1
  TOP w0.191: v1(176.98,61.96) 175.93,61.96 175.38,62.51 175.38,63.01 174.98,63.41 174.98,64.02 174.54,64.47 173.87,64.47 v2(173.02,63.62) 172.5,63.1 172.5,60.26 R6320.2
  BOTTOM w0.191: U6301.M6 177.32,62.7 176.96,62.35 176.96,61.97 v1(176.98,61.96)
EMMC_CMD: length 50.7
  TOP w0.191: v1(166.23,57.61) 166.75,57.61 168.43,59.28 R6321.1
  L3 w0.165: v1(152.55,75.92) 150.02,76.33 147.96,78.39 147.22,78.39 147.09,78.51 143.97,80.59 143.55,80.81 142.7,80.96 141.47,80.73 140.28,80.73 v1(137.63,80.34)
  L4 w0.165: v1(166.23,57.61) 166.63,58.01 166.63,59.65 165.12,61.15 161.75,61.15 160.34,62.56 160.34,63.83 159.22,64.96 155.94,64.96 154.29,66.61 154.29,67.05 153.51,67.83 153.51,69.46 153.51,69.46 153.51,70.26 152.55,71.22 v1(152.55,75.92)
  BOTTOM w0.127: CPU1.AP4 137.86,80.11 v1(137.63,80.34)
  BOTTOM w0.191: v1(166.23,57.61) 165.94,57.32 v2(165.7,57.32)
EMMC_CMD_R: length 12.4
  TOP w0.191: R6321.2 171,59.28 171.99,60.28 171.99,63.43 173.62,65.05 v2(174.3,65.05) 174.61,65.05 175.26,64.4 175.26,63.53 175.66,63.13 176.84,63.13 v1(176.96,63)
  BOTTOM w0.191: U6301.M5 177.16,63.2 v1(176.96,63)
EMMC_D0: length 52.1
  TOP w0.191: R6312.2 166.89,64.37 165.75,63.24 165.75,62.24 163.61,60.1 163.61,56.85 v1(163.16,56.4)
  L4 w0.165: v1(163.16,56.4) 163,56.24 157.43,56.24 156.19,57.48 156.11,57.48 152.48,61.11 152.48,61.77 151.9,62.36 151.9,62.39 151.63,62.66 151.62,62.66 150.13,64.15 150.13,65.02 148.79,66.36 148.79,69.09 148.17,69.71 148.17,71.19 148.06,71.31 145.5,71.31 144.49,71.63 143.25,72.87 143.25,75.37 144.21,76.33 144.21,77.94 143.25,78.9 143.25,78.92 142.7,79.47 142.49,79.47 v1(142.08,79.87)
  BOTTOM w0.089: v1(142.08,79.87) 141.64,79.42 140.98,79.42 140.81,79.26 139.71,79.26 139.62,79.29 139.39,79.29 CPU1.AP2
  BOTTOM w0.191: v2(162.88,55.92) 163.16,56.2 v1(163.16,56.4)
EMMC_D0_R: length 5.5
  TOP w0.191: v2(171,64.95) v1(170.53,65.27) 169.32,65.27 168.42,64.37 R6312.1
  BOTTOM w0.191: v1(170.53,65.27) 170.85,64.95 170.85,64.87 171.52,64.2 U6301.A3
EMMC_D1: length 50.9
  TOP w0.191: v1(164.08,56.63) 164.26,56.63 164.75,57.12 164.75,59.62 166.68,61.55 166.68,62.28 R6313.2
  L4 w0.165: v1(142.72,79.98) 142.87,79.98 143.09,79.76 143.92,79.76 144.22,79.46 144.22,79.23 143.98,78.99 143.98,78.76 144.22,78.53 144.45,78.53 144.69,78.76 144.92,78.76 145.15,78.53 145.15,78.29 144.73,77.88 144.73,77.02 145.09,76.66 147.02,76.66 148.59,75.09 148.59,72.91 148.2,72.52 148.2,71.98 148.59,71.58 148.59,70.24 149.21,69.62 149.21,66.6 150.55,65.26 150.55,64.33 151.8,63.08 151.8,63.08 152.88,62 152.88,61.97 153.44,61.4 153.58,61.27 153.58,60.75 154.25,60.08 155.21,60.08 157.09,58.2 157.09,58.2 158.63,56.66 162.76,56.66 162.97,56.86 163.85,56.86 v1(164.08,56.63)
  BOTTOM w0.089: CPU1.AP1 140.23,79.52 140.3,79.45 140.75,79.45 140.91,79.6 141.34,79.6 141.66,79.92 141.66,80.05 141.86,80.26 142.44,80.26 v1(142.72,79.98)
  BOTTOM w0.191: v1(164.08,56.63) 164.15,56.57 v2(164.15,56.07)
EMMC_D1_R: length 4.7
  TOP w0.191: 168.89,63.52 168.08,62.71 R6313.1 ; 168.89,63.52 v2(168.89,63.53) ; 168.89,63.52 169.4,64.04 170.64,64.04 v1(170.75,63.93)
  BOTTOM w0.191: v1(170.75,63.93) 170.98,63.7 U6301.A4
EMMC_D2: length 53.1
  TOP w0.191: v1(165.13,56.65) 165.22,56.74 165.22,58.78 165.79,59.36 166.03,59.36 168.18,61.5 168.67,61.5 R6314.2
  L4 w0.165: v1(165.13,56.65) 164.08,55.6 157.29,55.6 152.51,60.38 152.51,60.4 151.25,61.66 151.19,61.66 148.37,64.47 148.37,68.14 147.64,68.87 147.64,70.47 147.36,70.75 145.85,70.75 145.71,70.8 144.99,71.03 144.27,71.26 142.51,73.02 142.51,75.38 142.65,75.53 142.65,76.95 142.82,77.11 143.45,77.11 143.62,77.28 143.62,77.61 143.45,77.77 142.82,77.77 142.65,77.94 142.65,78.83 142.51,78.97 v1(142.51,79)
  BOTTOM w0.089: v1(142.51,79) 142.29,79.23 141.07,79.23 140.92,79.08 139.68,79.08 139.59,79.12 138.98,79.12 138.96,79.14 138.89,79.14 CPU1.AP3
  BOTTOM w0.191: v2(165.39,56.11) 165.39,56.39 v1(165.13,56.65)
EMMC_D2_R: length 3.6
  TOP w0.191: R6314.1 170.37,61.83 170.57,62.03 v1(170.57,62.11) 170.57,62.33 v2(170.85,62.61)
  BOTTOM w0.089: U6301.A5 171.18,63.2 170.57,62.59 v1(170.57,62.11)
EMMC_D3: length 54.5
  TOP w0.191: R6316.2 166.14,65.4 164.87,64.12 164.87,62.66 162.59,60.39 162.59,58 163.05,57.54 163.05,57.06 162.68,56.69 162.68,56.24 v1(163.44,55.08)
  L4 w0.165: v1(140.57,79.84) 140.77,78.71 141.32,77.41 141.59,75.37 141.64,75.33 141.64,75.07 141.64,75.07 141.64,72.7 143.97,70.37 144.31,70.37 145.27,70.06 146.45,68.88 146.45,66.95 147.69,65.7 147.69,64.56 151.75,60.5 151.82,60.5 152.09,60.23 152.09,60.21 157.22,55.08 v1(163.44,55.08)
  BOTTOM w0.127: v1(140.57,79.84) 138.53,79.84 CPU1.AN3
  BOTTOM w0.191: v2(163.06,54.62) 163.06,54.7 v1(163.44,55.08)
EMMC_D3_R: length 6.1
  TOP w0.191: R6316.1 v2(168.64,65.98) 168.99,66.33 171.14,66.33 v1(171.43,66.04)
  BOTTOM w0.089: U6301.B2 172.22,64.95 171.79,64.95 171.49,65.25
  BOTTOM w0.191: 171.49,65.25 171.38,65.5 171.38,65.99 v1(171.43,66.04)
EMMC_D4: length 50
  TOP w0.191: v1(163.07,58.2) 163.07,60.24 165.31,62.48 165.31,63.73 166.76,65.18 R6317.2
  L4 w0.165: v1(141.2,80) 140.95,80.1 140.67,80.39 140.67,80.75 140.87,80.96 143.79,80.96 143.97,80.78 144.09,80.78 149.43,75.43 149.43,70.59 149.82,70.2 150.07,69.95 150.07,67.06 150.3,66.82 150.74,66.82 151.25,66.31 151.25,65.77 151.24,65.77 152.69,64.32 152.69,63.51 152.98,63.22 153.62,63.22 153.79,63.04 153.79,62.29 154.01,62.07 154.01,62.02 154.28,61.75 155.08,61.75 158.47,58.35 162.91,58.35 v1(163.07,58.2)
  BOTTOM w0.089: v1(141.2,80) 141.2,80.1 140.99,80.3 140.25,80.3 140.17,80.22 139.53,80.22 CPU1.AN1
  BOTTOM w0.191: v2(163.12,58.75) 163.12,58.75 163.12,58.72 163.07,58.68 v1(163.07,58.2)
EMMC_D4_R: length 5.8
  TOP w0.191: R6317.1 168.54,65.18 169.25,65.89 v2(169.97,65.89) v1(170.67,65.89)
  BOTTOM w0.089: U6301.B3 172.22,64.45 171.69,64.45 171.45,64.69
  BOTTOM w0.191: 171.45,64.69 171.45,64.81 171.29,64.98 171.29,65 170.97,65.76 v1(170.67,65.89)
EMMC_D5: length 52
  TOP w0.191: R6318.2 166.86,63.53 166.2,62.87 166.2,62 164.21,60.02 164.21,57.38 v1(164.28,57.32)
  L4 w0.165: v1(143.26,80.31) 143.97,80.31 145.81,78.47 145.81,78.23 145.21,77.63 145.21,77.4 145.44,77.17 145.68,77.17 146.16,77.65 146.62,77.65 149.01,75.26 149.01,70.42 149.63,69.8 149.63,66.79 152.22,64.2 152.22,63.27 153.59,61.9 153.59,61.85 154.11,61.33 154.55,61.33 157.51,58.38 158.05,57.84 159.99,57.84 160.64,57.19 160.97,57.19 161.62,57.84 162.77,57.84 163.04,57.57 163.28,57.57 163.77,58.07 164.06,58.07 164.4,57.73 164.4,57.44 v1(164.28,57.32)
  BOTTOM w0.089: CPU1.AN2 139.06,80.41 139.3,80.41 139.39,80.44 139.59,80.44 139.71,80.4 140.1,80.4 140.18,80.48 140.21,80.48 140.22,80.48 141.91,80.48 142.19,80.76 142.8,80.76 v1(143.26,80.31)
  BOTTOM w0.191: v1(164.28,57.32) 164.28,57.72 v2(164.11,57.89)
EMMC_D5_R: length 5.3
  TOP w0.191: R6318.1 168.26,63.53 169.28,64.54 v2(169.75,64.54) v1(170.49,64.54)
  BOTTOM w0.089: v1(170.49,64.54) 170.72,64.54 171.31,63.95 172.22,63.95 U6301.B4
EMMC_D6: length 52.5
  TOP w0.191: v1(165.64,59.83) 167.75,61.95 168.1,61.95 168.79,62.64 R6319.2
  L4 w0.165: v1(138.34,81.32) 137.94,81.72 137.94,84.16 138.81,85.04 142.91,85.04 152.08,75.87 152.08,71.1 153.09,70.09 153.09,67.61 153.83,66.87 153.83,66.47 155.82,64.49 156.93,64.49 158.02,63.4 158.63,63.4 158.95,63.08 158.95,62.84 158.76,62.65 158.76,62.42 159,62.18 159.23,62.18 159.42,62.38 159.66,62.38 161.3,60.74 164.73,60.74 v1(165.64,59.83)
  BOTTOM w0.127: v1(138.34,81.32) 137.87,80.84 CPU1.AM4
  BOTTOM w0.191: v2(165.64,60.39) v1(165.64,59.83)
EMMC_D6_R: length 4.8
  TOP w0.191: R6319.1 169.83,63.1 170.22,63.49 v1(170.22,63.56) 170.33,63.45 171.07,63.45 v2(171.38,63.77)
  BOTTOM w0.089: v1(170.22,63.56) 170.33,63.45 172.22,63.45 U6301.B5
EMMC_D7: length 51.4
  TOP w0.191: R6315.2 168.64,60.12 166.61,58.09 v1(165.69,58.09)
  L4 w0.165: v1(143.55,81.5) 143.92,81.87 144.54,81.87 150.52,75.89 150.52,74.86 150.69,74.7 150.83,74.7 150.99,74.53 150.99,74.2 150.83,74.04 150.69,74.04 150.52,73.87 150.52,73.54 150.69,73.38 150.83,73.38 150.99,73.21 150.99,72.88 150.83,72.72 150.69,72.72 150.52,72.55 150.52,71.11 151.16,70.47 151.16,67.96 152.74,66.38 152.74,65.92 155.35,63.32 155.35,63.06 155.81,62.59 156.05,62.59 156.42,62.97 156.66,62.97 156.89,62.74 156.89,62.51 156.51,62.13 156.51,61.89 156.75,61.66 156.98,61.66 157.36,62.04 157.59,62.04 157.83,61.81 157.83,61.57 157.45,61.19 157.45,60.96 157.74,60.66 157.98,60.66 158.27,60.96 158.51,60.96 158.74,60.72 158.74,60.49 158.44,60.19 158.44,59.96 158.92,59.49 164.3,59.49 v1(165.69,58.09)
  BOTTOM w0.089: CPU1.AM1 139.82,80.84 141.76,80.84 142.04,81.12 142.06,81.12 142.08,81.14 143.33,81.14 143.55,81.36 v1(143.55,81.5)
  BOTTOM w0.191: v1(165.69,58.09) 165.65,58.09 165.28,58.46 165.22,58.46 165.22,58.46 v2(165.21,58.46)
EMMC_D7_R: length 5
  TOP w0.191: v1(171.3,61.17) 171.54,60.93 v2(171.54,60.57) 171.54,60.47 171.19,60.12 R6315.1
  BOTTOM w0.089: v1(171.3,61.17) 171,61.47 171,62.41 171.54,62.95 172.22,62.95 U6301.B6
EMMC_E9: length 16.5
  L4 w0.165: v1(174.81,61.56) 174.81,61.17 175.28,60.7 176.95,60.7 177.07,60.59 v1(180.39,60.59)
  BOTTOM w0.127: U6301.E9 174.61,61.2 174.81,61.41 v1(174.81,61.56)
  BOTTOM w0.191: TP6301.1 187.29,64.44 185.71,62.87 183.5,62.87 181.22,60.59 v1(180.39,60.59)
EMMC_E10: length 16.9
  L4 w0.165: v1(173.66,60.2) 173.65,60.2 173.65,60.18 175.04,58.79 179.86,58.79 180.85,59.78 180.85,60.86 v1(180.43,61.27)
  BOTTOM w0.127: v1(173.66,60.2) 173.65,60.2 173.65,60.36 173.97,60.68 U6301.E10
  BOTTOM w0.191: TP6302.1 182.77,63.62 v1(180.43,61.27)
EMMC_F10: length 15.9
  L4 w0.165: v1(174.73,60.2) 174.73,60.14 175.66,59.21 179.68,59.21 180.18,59.7 v1(180.18,59.95)
  BOTTOM w0.127: v1(174.73,60.2) 174.67,60.2 174.47,60.41 U6301.F10
  BOTTOM w0.191: v1(180.18,59.95) 181.21,59.95 182.63,61.37 185.49,61.37 TP6303.1
EMMC_K10: length 14.8
  L4 w0.165: v1(176.76,60.24) 177.33,59.67 v1(179.49,59.67)
  BOTTOM w0.191: v1(176.76,60.24) 176.76,60.41 U6301.K10 ; v1(179.49,59.67) 179.98,59.47 180.06,59.39 182.37,59.39 183.76,60.78 186.43,60.78 TP6304.1
EMMC_RCLK: length 47.5
  TOP w0.191: v1(165.9,58.78) 166.31,58.78 168.45,60.93 R6322.1
  L4 w0.165: v1(165.9,58.78) 164.65,60.03 159.59,60.03 159.29,60.33 159.29,61.11 156.46,63.95 155.59,63.95 153.29,66.25 153.29,66.65 152.55,67.39 152.55,69.86 151.54,70.87 151.54,75.65 144.77,82.42 143.69,82.42 142.83,81.55 v1(142.83,81.53)
  BOTTOM w0.089: CPU1.AM2 139.23,80.84 139.49,81.1 139.65,81.1
  BOTTOM w0.102: v1(142.83,81.53) 142.7,81.41 142.09,81.41 141.99,81.3 141.96,81.3 141.69,81.03 140.21,81.03 140.13,81.11 139.66,81.11 139.65,81.1
  BOTTOM w0.191: v2(166.45,58.76) 165.92,58.76 v1(165.9,58.78)
EMMC_RCLK_R: length 10
  TOP w0.191: R6322.2 170.63,61.55 171.02,61.94 171.02,62.07 171.71,62.76 171.71,63.54 172.02,63.85 172.02,64.34 v2(172.47,64.79) 173.15,65.47 174.9,65.47 175.7,64.67 v1(175.7,63.71)
  BOTTOM w0.127: v1(175.7,63.71) 175.47,63.47 U6301.H5
EMMC_RCOMP: length 1.8
  BOTTOM w0.203: CPU1.AT1 139.51,78.83 141.22,78.83 v1(141.23,78.84)
  vias: v2(139.58,78.65)
EMMC_RESET#: length 21.4
  L4 w0.165: v1(171.08,57.36) 171.32,57.6 171.32,60.53 171.93,61.13 171.93,62.12 173.99,64.18 176.23,64.18 v1(176.7,63.71)
  BOTTOM w0.127: v1(171.08,57.36) 172.42,56.01 v2(172.42,54.64) 172.42,53.87 R6324.1 172.54,53.6 174.64,51.51 Q6301.S 175.05,51.41 177.1,51.41 R6323.2
  BOTTOM w0.191: U6301.K5 176.44,63.35 v1(176.7,63.71)
EMMC_VCC: length 2.6
  BOTTOM w0.178: v1(174.25,63.71) 174.47,63.5 U6301.F5 174.47,63.2 173.97,62.7 U6301.E6
  BOTTOM w0.254: v1(175.72,60.21) 175.97,60.46 U6301.J10 175.97,60.76 176.41,61.2 U6301.K9
  vias: v2(174.09,62.65) v2(177.35,61.14)
EMMC_VCCQ: length 7.7
  L2 w0.254: v1(173.46,62) 174.28,62.83 174.28,63.01 175.49,64.22 175.54,64.22 v1(177.13,65.8)
  BOTTOM w0.127: U6301.P5 U6301.N4 U6301.P3
  BOTTOM w0.254: v1(173.46,62) 173.46,62.26 173.02,62.7 U6301.C6
  vias: v1(173.11,58.19) v1(173.79,58.19) v1(179.63,62.95) v1(180.1,62.44) v2(183.89,66.97)
EMMC_VDDI: length 6.4
  BOTTOM w0.089: 172.59,65.72 172.72,65.59 172.72,64.95 U6301.C2
  BOTTOM w0.508: 172.59,65.72 172.59,65.73 171.64,66.68 171.63,66.68 170.92,67.38 v2(170.92,69.28) C6320.1
EN/DEM_VGA: length 149.2
  TOP w0.254: v1(192.62,179.78) 192.16,179.33 189.43,179.33 D8602.2 ; v1(161.82,103.33) 161.58,103.57 161.58,104.6 161.37,104.81 PQ8501.2 160.26,104.81 159.99,105.07 159.99,107.12 v2(159.39,107.73) 158.25,108.86 157.84,108.86 157.07,109.62 156.73,109.62 v1(156.34,110.02) 156.21,110.02 155.74,110.48 153.81,110.48 PC8502.2 153.3,110.52 PD8501.A
  L3 w0.254: v1(192.62,179.78) 192.92,179.78 196.61,176.09 196.55,176.03 196.55,175.61 196.85,175.31 197.39,175.31 198.34,174.37 198.34,153.34 194.19,149.19 194.19,146.8 193.05,145.66 193.05,140.67 194.11,139.6 194.11,139.24 194.11,136.6 192.34,134.83 187.16,134.83 186.68,134.35 186.68,128.01 189.97,124.72 189.97,120.73 189.85,120.6 189.85,118.96 190.61,118.19 190.61,100.54 v1(188.07,98)
  L4 w0.254: v1(161.82,103.33) 161.82,102.94 161.78,102.9 161.78,102.16 161.82,102.12 161.82,101.71 163.14,100.39 163.14,100.21 163.14,99.01 167.54,94.6 167.57,94.6 168.05,94.6 168.48,94.6 174.5,94.59 174.76,94.59 174.87,94.59 175.95,94.59 176.23,94.87 177.98,94.87 181.03,97.92 187.99,97.92 v1(188.07,98)
  BOTTOM w0.254: v1(156.34,110.02) 156.5,110.02 PR8514.1 156.76,110.86 PR8503.2
EOPIO_RCOMP: length 3.6
  TOP w0.305: v1(103.68,93.4) 103.56,93.28 103.56,91.94 R415.2 104.09,91.42 v2(104.73,91.42)
  BOTTOM w0.254: CPU1.H65 103.29,93 v1(103.68,93.4)
ESPI_ALERT#: length 69
  L4 w0.165: v1(143.5,58.1) 144.02,58.1 144.11,58.2 144.79,58.2 145.07,57.92 145.07,57.21 148.57,53.71 148.57,52.85 148.98,52.44 148.98,50.96 157.99,41.95 157.99,41.43 158.68,40.74 158.68,40.74 160.67,38.75 160.67,38.23 161.49,37.41 161.87,37.41 161.94,37.49 166.13,37.49 167.09,36.53 173.31,36.53 v1(173.91,37.13)
  BOTTOM w0.089: 135.17,73.65 134.92,73.65 134.67,73.9 134.67,74.32 133.97,75.02 133.97,75.95 CPU1.AY11
  BOTTOM w0.102: 135.17,73.65 135.21,73.65 135.46,73.4 135.46,73.12 135.44,73.1 135.44,72.47 137.65,70.27 137.65,69.3 138.2,68.75 138.2,66.87 138.03,66.7 138.03,66.49
  BOTTOM w0.191: 138.03,66.49 v2(138.03,65.76) 138.03,63.55 138.31,63.27 138.31,60.15 139.84,58.63 141.1,58.63 141.27,58.46 142.57,58.46 142.93,58.1 v1(143.5,58.1) ; KBC24.55 173.91,37.13 v1(173.91,37.13) 174.55,37.13 174.89,36.79 R2410.2
ESPI_CLK: length 60.9
  L3 w0.165: v1(173.76,36.05) 172.02,37.8 172.02,39.94 171.73,40.23 170.77,40.23 169.67,41.33 169.67,41.88 168.84,42.71 166.47,42.71 166.17,43.02 166.17,43.31 165.59,43.89 163.89,43.89 163.81,43.81 161.12,43.81 156,48.93 156,49.65 153.71,51.94 152.54,51.94 150.27,54.22 148.72,54.22 147.5,55.44 147.5,55.67 148.64,56.8 148.64,57.12 148.44,57.31 148.21,57.31 146.59,55.69 146.36,55.69 146.13,55.91 146.13,56.16 147.82,57.86 147.82,58.1 147.6,58.33 147.36,58.33 146.1,57.07 145.87,57.07 145.44,57.5 v1(145.44,58.73)
  BOTTOM w0.127: KBC24.57 173.57,36.33 173.76,36.14 v1(173.76,36.05)
  BOTTOM w0.191: v1(145.44,58.73) 145.3,58.87 v2(144.43,58.87) 143.06,58.87 142.83,59.1 141.54,59.1 139.86,60.78 139.86,62.4 139.33,62.92 139.21,62.92 EC1802.1 139.03,63.77 R1804.2
ESPI_CLK_CON: length 2.8
  TOP w0.191: TP6801.1 186.62,16.45 DBG1.2
ESPI_CLK_CPU: length 14.2
  BOTTOM w0.089: CPU1.AW9 134.92,76.7 134.66,76.44 134.66,74.83 135.03,74.46 135.2,74.46 135.45,74.23 135.45,73.77 135.65,73.57 135.65,73.01
  BOTTOM w0.127: 135.88,72.78 135.65,73.01
  BOTTOM w0.191: R1804.1 139.12,65.44 139.12,66.81 138.66,67.27 138.66,68.77 v2(138.63,68.8) 137.88,69.54 137.88,70.37 135.88,72.37 135.88,72.78
ESPI_CS#: length 61
  L4 w0.165: v1(142.17,57.9) 142.28,58.36 142.48,58.56 144.95,58.56 145.43,58.08 145.43,57.37 145.7,57.11 145.93,57.11 146.47,57.65 146.7,57.65 146.94,57.41 146.94,57.18 146.4,56.64 146.4,56.4 146.63,56.17 146.86,56.17 147.4,56.71 147.64,56.71 147.87,56.48 147.87,56.24 147.33,55.7 147.33,55.47 148.93,53.87 148.93,53.01 149.34,52.6 149.34,51.93 158.41,42.87 158.69,42.87 159.47,43.65 159.7,43.65 159.94,43.42 159.94,43.18 159.01,42.26 159.01,42.02 159.24,41.79 159.48,41.79 160.4,42.71 160.64,42.71 160.87,42.48 160.87,42.25 159.95,41.32 159.95,41.09 161.63,39.4 162.17,39.4 162.82,38.76 163.2,38.76 163.55,39.1 163.55,39.16 163.82,39.43 164.71,39.43 165.32,38.82 165.56,38.82 165.99,39.26 166.23,39.26 166.46,39.02 166.46,38.79 166.02,38.35 166.02,38.12 166.99,37.15 167.63,37.15 v1(167.97,37.48)
  BOTTOM w0.102: v1(167.97,37.48) 167.99,37.51 170.44,37.51 172.02,35.93 KBC24.58
  BOTTOM w0.191: v1(142.17,57.9) 142.05,58.02 v2(141.21,58.02) 141.04,58.02 140.88,58.18 138.83,58.18 137.84,59.17 R1801.2
ESPI_CS#_CON: length 4.1
  TOP w0.191: v1(186.7,13.19) 186.83,13.31 187.4,13.31 187.43,13.34 188.08,13.34 188.18,13.45 DBG1.5
  BOTTOM w0.191: TP6803.1 186.95,13.48 186.7,13.23 v1(186.7,13.19)
ESPI_CS#_CPU: length 15.3
  BOTTOM w0.089: 136.08,71.56 136.08,71.56 133.94,73.71 133.93,73.71 133.12,74.52 133.12,75.91 CPU1.BA12
  BOTTOM w0.102: 136.08,71.56 137.46,70.19 137.46,68.96 137.92,68.5 137.92,67.16 v2(137.82,67.06) 137.61,66.85 137.61,66.66
  BOTTOM w0.191: 137.61,66.66 137.61,63.13 R1801.1
ESPI_IO0: length 61.1
  L3 w0.165: v1(175.66,33.09) 173.39,35.36 172.98,35.36 170.92,37.42 170.92,37.54 169.28,39.18 168.74,39.18 166.19,41.74 165.85,41.74 164.68,42.91 164.3,42.91 164.22,42.83 160.19,42.83 158.71,44.31 158.41,44.31 158.2,44.52 156.86,45.86 156.71,45.86 151.34,51.23 150.36,51.23 148.97,52.62 147.51,52.62 146.79,51.9 145.19,51.9 145.15,51.94 144.01,51.94 143.34,52.61 143.34,54.29 142.62,55 v1(142.62,55.78)
  BOTTOM w0.102: KBC24.59 173.89,35.53 175.66,33.76 v1(175.66,33.09)
  BOTTOM w0.191: v1(142.62,55.78) 142.62,55.71 142.18,55.27 141.43,55.27 141.16,55.38 139.94,56.61 137.9,56.61 135.41,59.09 v2(135.41,61.01) 135.41,61.8 R1829.2
ESPI_IO0_CON: length 3
  TOP w0.191: v1(190.15,9.48) 190.12,9.45 DBG1.9
  BOTTOM w0.191: TP6807.1 190.09,7.96 190.09,9.41 v1(190.15,9.48)
ESPI_IO0_CPU: length 16
  BOTTOM w0.089: CPU1.AY13 132.3,76.06 132.23,75.8 132.23,75.56 132.27,75.42 132.27,75.21 132.26,75.15 132.23,75.07 132.23,74.26 132.61,73.88 132.7,73.88 134.84,71.74
  BOTTOM w0.102: 134.84,71.74 134.84,71.73 136.69,69.87 136.69,67.97 136.08,67.35
  BOTTOM w0.191: R1829.1 135.39,63.22 v2(135.39,65.77) 135.39,66.67 136.08,67.35
ESPI_IO1: length 61.1
  L3 w0.165: v1(175.26,32.59) 175.26,32.7 174.97,32.99 174.97,33.26 173.24,34.99 172.83,34.99 170.49,37.33 170.49,37.45 169.13,38.82 168.59,38.82 166.04,41.37 164.58,41.37 163.48,42.46 159.63,42.46 158.84,43.25 158.46,43.25 158.18,43.53 158.18,43.95 156.64,45.49 156.56,45.49 151.26,50.8 149.35,50.8 149.19,50.97 149.19,51.47 149.02,51.64 148.69,51.64 148.53,51.47 148.53,50.97 148.36,50.8 146.47,50.8 146.31,50.97 146.31,51.32 146.14,51.49 145.81,51.49 145.65,51.32 145.65,50.97 145.48,50.8 144.62,50.8 142.97,52.45 142.97,54.12 141.99,55.1 v1(141.99,55.75)
  BOTTOM w0.102: v1(175.26,32.59) 175.12,32.73 175.12,33.85 173.83,35.13 KBC24.60
  BOTTOM w0.191: R1830.2 v2(136.72,61.14) 136.72,58.89 138.22,57.39 140.5,57.39 141.99,55.91 v1(141.99,55.75)
ESPI_IO1_CON: length 3.3
  TOP w0.191: v1(190.69,10.62) 190.55,10.48 188.95,10.48 DBG1.8
  BOTTOM w0.191: TP6806.1 190.69,9.94 v1(190.69,10.62)
ESPI_IO1_CPU: length 14.9
  BOTTOM w0.089: 134.76,72.35 132.76,74.36 132.76,75.38 CPU1.BA13
  BOTTOM w0.102: 136.78,66.81 136.78,66.96 137.08,67.26 137.08,70.03 134.76,72.35 134.76,72.35
  BOTTOM w0.191: 136.78,66.81 v2(136.78,65.87) 136.78,65.51 136.56,65.3 136.56,63.08 R1830.1
ESPI_IO2: length 63
  TOP w0.191: v2(141.06,55.34) 141.06,55.56 v1(141.36,55.86)
  L3 w0.165: v1(174.58,32.73) 174.58,33.13 173.08,34.62 172.67,34.62 170.12,37.18 170.12,37.3 168.97,38.45 168.44,38.45 166.89,39.99 166.66,39.99 166.39,39.72 166.15,39.72 165.92,39.95 165.92,40.19 166.19,40.46 166.19,40.69 165.88,41 163.62,41 163.41,41.21 160.04,41.21 158.8,42.45 158.74,42.45 157.82,43.37 157.82,43.79 156.48,45.13 156.41,45.13 151.1,50.43 144.41,50.43 143.06,51.78 142.66,51.78 141.36,53.08 141.36,53.76 141.53,53.92 141.95,53.92 142.11,54.09 142.11,54.41 141.93,54.58 141.53,54.58 141.36,54.75 v1(141.36,55.86)
  BOTTOM w0.102: v1(174.58,32.73) 174.56,32.73 174.56,32.72 174.49,32.78 174.49,34.04 173.8,34.73 KBC24.61
  BOTTOM w0.191: v1(141.36,55.86) 140.22,57 138.06,57 136.16,58.9 136.16,63.79 R1831.2
ESPI_IO2_CON: length 3.4
  TOP w0.191: DBG1.7 188.96,11.48 v1(191.17,11.48)
  BOTTOM w0.191: TP6805.1 191.2,11.48 v1(191.17,11.48)
ESPI_IO2_CPU: length 12.3
  BOTTOM w0.089: CPU1.BB13 132.5,74.26 132.69,74.06 132.78,74.06 132.78,74.06 135.03,71.81 135.03,71.81
  BOTTOM w0.102: 135.03,71.81 136.88,69.95 136.88,67.57 v2(136.54,67.23)
  BOTTOM w0.191: R1831.1 135.91,66.6 v2(136.54,67.23)
ESPI_IO3: length 61.1
  TOP w0.191: v2(141.69,56.63) 141.94,56.63 v1(142.19,56.38)
  L3 w0.165: v1(173.9,33.16) 173.62,33.16 169.75,37.02 169.75,37.15 168.82,38.08 167.38,38.08 167.22,38.24 167.22,38.72 167.05,38.89 166.72,38.89 166.56,38.72 166.56,38.24 166.39,38.08 166.02,38.08 163.26,40.84 159.89,40.84 158.64,42.08 158.59,42.08 157.45,43.22 157.45,43.64 156.33,44.76 156.26,44.76 150.95,50.06 144.26,50.06 142.91,51.42 142.51,51.42 140.9,53.03 140.9,56.05 141.17,56.33 142.14,56.33 v1(142.19,56.38)
  BOTTOM w0.102: KBC24.62 173.35,34.33 173.84,33.85 173.84,33.22 v1(173.9,33.16)
  BOTTOM w0.191: R1833.2 137.21,63.94 137.21,61.03 137.26,60.98 137.26,58.94 138.41,57.79 140.71,57.79 141.44,57.06 141.51,57.06 v1(142.19,56.38)
ESPI_IO3_CON: length 5.9
  TOP w0.191: v1(191.98,11.97) 191.92,11.97 191.44,12.45 DBG1.6
  BOTTOM w0.191: v1(191.98,11.97) 192.67,11.27 TP6804.1
ESPI_IO3_CPU: length 14.1
  BOTTOM w0.089: 134.78,72.6 132.93,74.45 132.93,75.45 132.78,75.6 132.78,76.33 CPU1.AY12
  BOTTOM w0.102: 134.78,72.6 134.79,72.6 135.89,71.49 135.89,71.48 137.27,70.11 137.27,68.53 v2(137.47,68.32) 137.68,68.12 137.68,67.43 137.21,66.97 137.21,66.78
  BOTTOM w0.191: R1833.1 137.21,65.06 137.21,66.78
ESPI_RESET#: length 56.1
  TOP w0.191: v1(146.18,52.36) 146.81,52.99 146.81,56.21 147.42,56.82 147.42,58.37 147.21,58.59 146.6,58.59 146.39,58.79 146.39,59.17 147.14,59.92 147.14,60.19 146.86,60.47 146.59,60.47 146.11,59.99 145.84,59.99 145.57,60.26 145.57,60.53 146.05,61.01 146.05,61.28 v2(145.41,61.92) 144.75,62.57 144.75,64.07 144.26,64.56 144.26,65.37 R1826.2
  L3 w0.165: v1(146.18,52.36) 145.38,52.36 145.18,52.56 145.18,53.95 145.49,54.26 147.65,54.26 148.8,53.11 150.51,53.11 152.29,51.33 152.74,51.33 155.87,48.2 155.87,47.68 156.14,47.41 156.66,47.41 160.87,43.2 164.06,43.2 164.14,43.28 164.83,43.28 166.01,42.11 166.34,42.11 166.34,42.1 168.03,42.1 171.38,38.75 v1(171.38,37.61)
  BOTTOM w0.102: KBC24.53 172.12,37.93 171.81,37.61 v1(171.38,37.61)
ESPI_RESET#_CON: length 3.7
  TOP w0.191: DBG1.4 188.19,14.45 187.48,13.74 186.58,13.74 186.01,13.17 TP6802.1
ESPI_RESET#_CPU: length 18.8
  TOP w0.191: v1(135.07,73.24) 136.71,71.59 141.26,71.59 142.41,70.44 142.41,69.55 142.6,69.36 143.37,69.36 143.56,69.17 143.56,68.79 143.37,68.6 142.6,68.6 142.41,68.41 142.41,67.2 v2(143.07,66.54) R1826.1
  BOTTOM w0.089: v1(135.07,73.24) 135.05,73.26 134.64,73.26 134.01,73.89 134,73.89 133.43,74.46 133.43,75.38 CPU1.BA11
EXT_CLK_IN_CRT: length 3.1
  TOP w0.127: v2(25,72.96) R5616.1 23.73,73.31 23.73,74.02 24.04,74.32 U5601.28
EXT_PWR_GATE#: length 25
  TOP w0.127: R1731.2 152.92,77.11 152.42,77.11 150.15,79.39 147.06,79.39 144.15,82.29 141.08,82.29 140.44,82.94 138.9,82.94 v2(138.31,82.35) 138.31,81.99 138.78,81.52 138.78,81.13 138.5,80.84 137.51,80.84 137.17,80.51 137.17,80.15 136.9,79.88 136.44,79.88 135.87,80.46 135.87,80.76 134.96,81.66 134.75,81.66 134.75,81.69 134.79,81.69 134.79,81.71 v1(134.8,81.71)
  BOTTOM w0.127: CPU1.AM10 134.76,81.71 v1(134.8,81.71)
FALL_INT2: length 4.7
  BOTTOM w0.152: Q6701.2 190.35,36.62 R6703.2 190.57,36.02 v2(190.07,35.52) 189.62,35.97 Q6701.3
FAN1_DAC_1: length 4.2
  TOP w0.254: FAN261.4 97.21,139.74 97.68,140.2 R2403.2 97.99,140.47 98.72,140.47 ; 98.72,140.47 98,141.19 v2(97.72,141.19) ; 98.72,140.47 C2401.1
FAN1_PWM: length 251.8
  TOP w0.254: v1(97.8,138.63) 97.71,138.72 R2403.1
  L3 w0.254: v1(174.05,40.71) 174.59,40.16 176.13,40.16 177.49,38.8 177.49,36.75 178.95,35.28 v1(178.95,25.22)
  L4 w0.254: v1(97.8,138.63) 97.8,141.19 99.35,142.74 102.49,142.74 106.95,147.21 106.95,147.34 107.13,147.55 110.43,150.85 110.44,152.12 110.44,152.62 110.84,153.02 114.52,153.02 115.1,152.44 115.1,152.44 v1(116.24,151.3) ; v1(135.63,148.01) 135.89,147.75 136.9,147.75 143.9,140.76 143.9,124.72 143.29,124.11 143.29,108.3 145.67,105.92 148.19,105.92 148.85,105.26 152.52,105.26 158.54,99.24 158.84,99.24 159.66,98.42 159.66,97.91 160.98,96.58 161.52,96.58 161.81,96.29 161.81,95.56 164.33,93.04 164.43,93.04 166.33,91.14 170.93,91.14 170.98,91.19 171.89,91.2 176.53,91.2 177.57,92.24 183.95,92.24 185.03,93.32 189.36,93.32 192.58,90.1 192.58,70.91 191.12,69.45 191.12,67.1 194.68,63.54 194.68,36.56 193.71,35.6 193.71,34.5 190.43,31.22 190.43,30.07 188.36,28.01 186.54,28.01 183.93,25.4 182.5,25.4 182.31,25.22 v1(178.95,25.22)
  BOTTOM w0.203: 173.36,40.33 KBC24.47
  BOTTOM w0.254: v1(174.05,40.71) 173.67,40.33 173.36,40.33 ; v1(116.24,151.3) 116.21,151.33 116.21,151.72 116.21,152.14 116.21,152.14 116.21,152.2 116.85,152.84 118.44,152.84 118.89,152.39 v2(126.13,152.39) 127.87,152.39 131.63,148.63 135.1,148.63 135.63,148.1 v1(135.63,148.01)
FAN1_TACH: length 10.6
  TOP w0.203: R2461.1 176.7,47.55 176.67,47.52 v1(176.45,47.52)
  BOTTOM w0.203: KBC24.40 173.54,43.13 173.92,43.51 ; D2403.A 176.05,47.91 v1(176.45,47.52)
  BOTTOM w0.254: 173.92,43.51 173.92,43.69 174.5,44.26 174.5,44.99 175.24,45.72 175.24,46.8 v2(175.08,46.96) 175.08,47.56 D2403.A 175.15,48.19 R2430.2
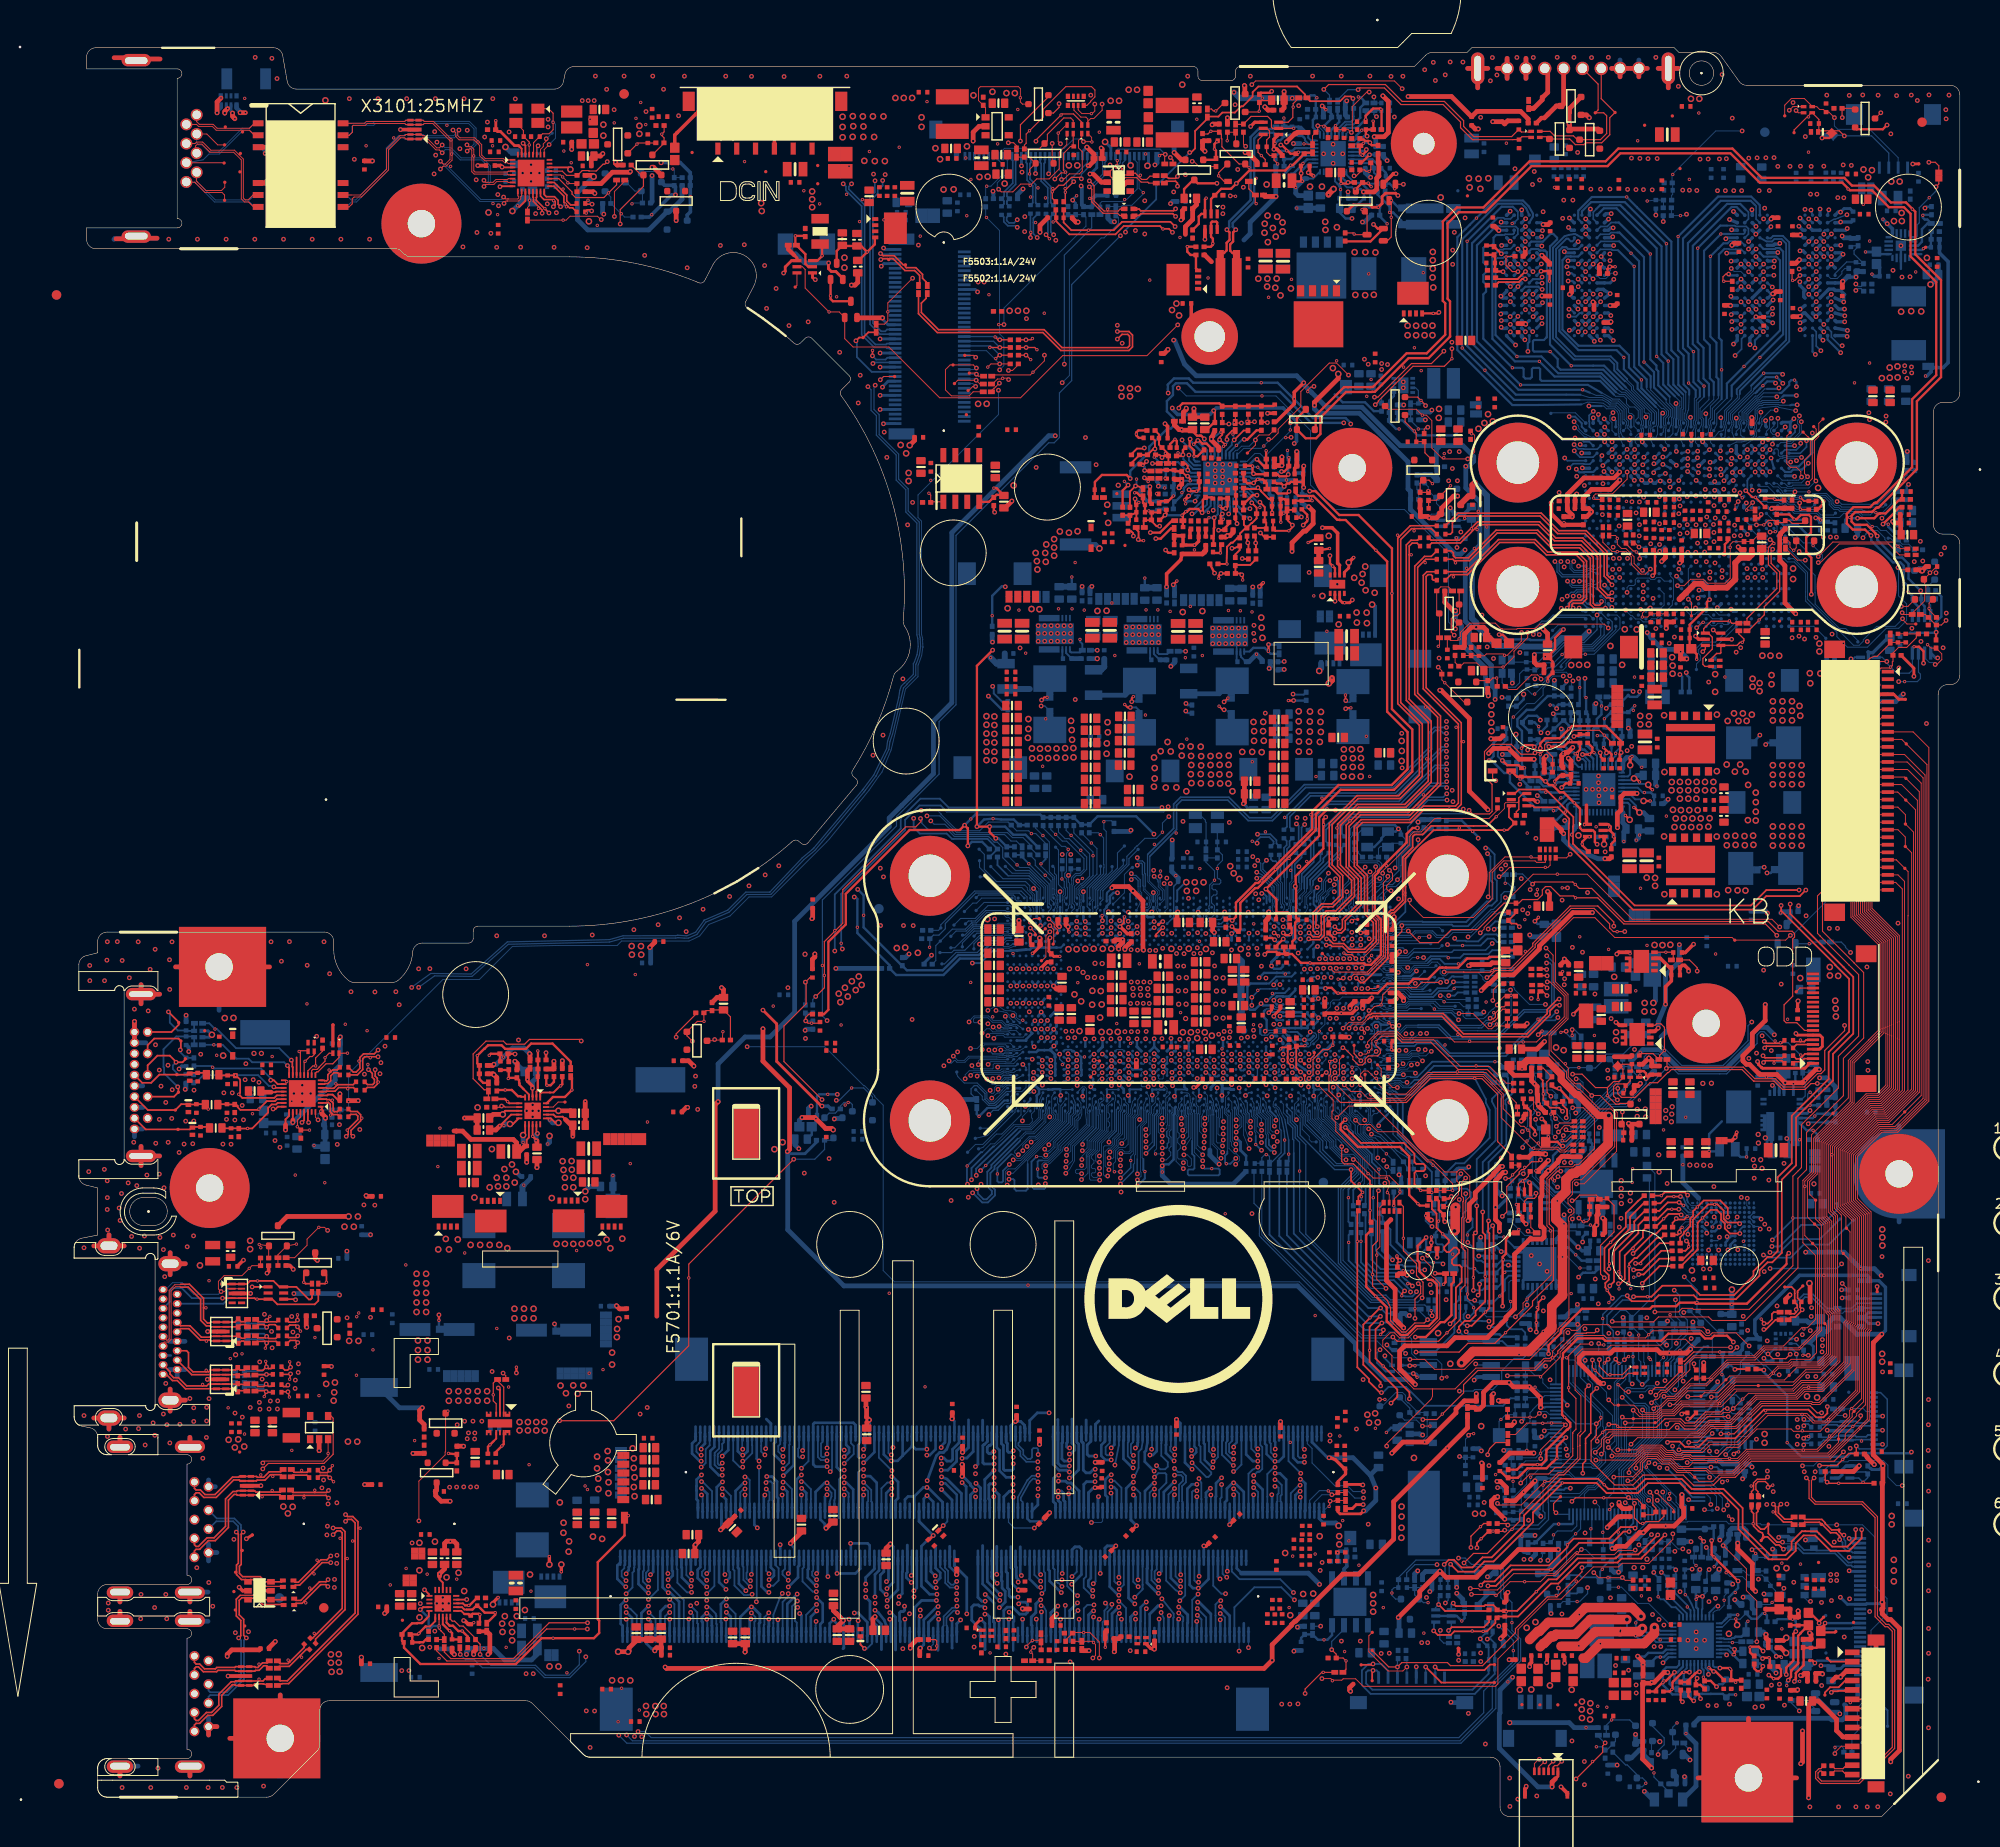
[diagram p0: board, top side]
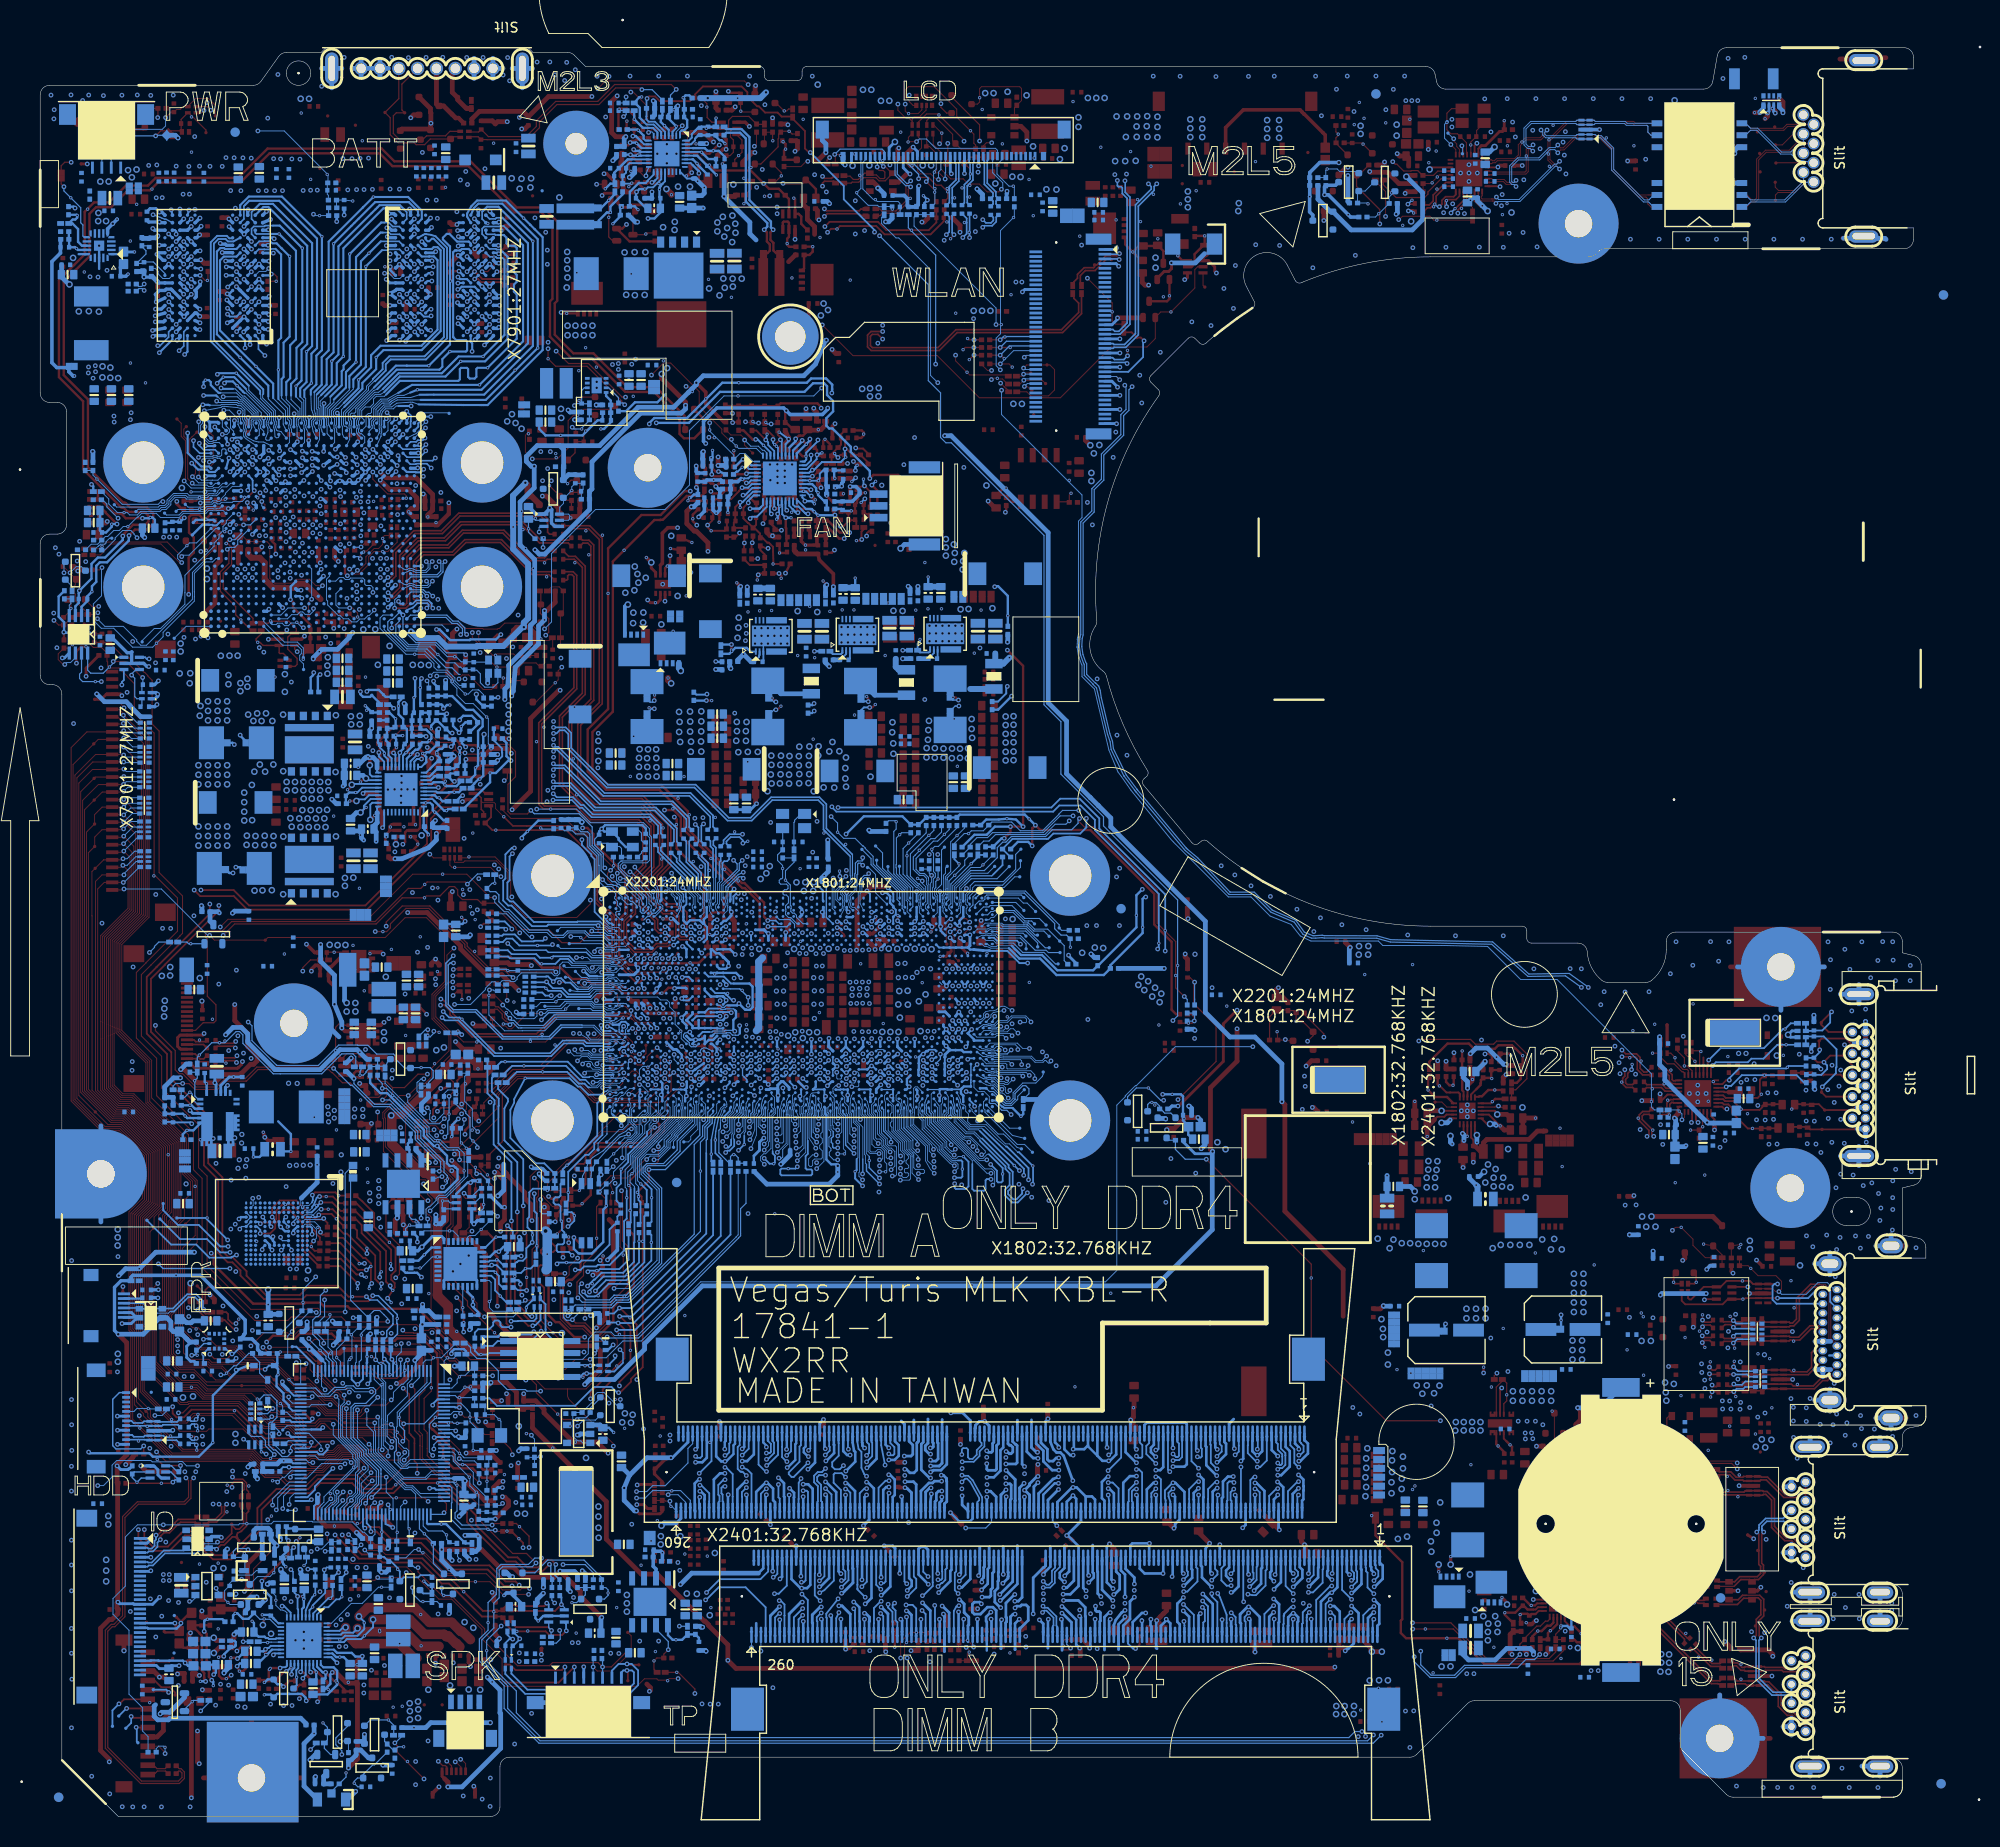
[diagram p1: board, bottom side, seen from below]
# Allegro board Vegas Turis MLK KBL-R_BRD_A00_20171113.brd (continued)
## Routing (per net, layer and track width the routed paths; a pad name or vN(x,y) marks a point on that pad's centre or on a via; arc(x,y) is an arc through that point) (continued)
FAN2_PWMVOL_LP#: length 30.2
  TOP w0.127: R2486.1 168.92,31.91 168.35,31.35 167,31.35 166.79,31.14 v2(166.65,31.14) 166.36,31.14 165.78,31.72 v1(165.78,33.28)
  BOTTOM w0.127: KBC24.34 171.08,45.53 170.46,44.91 169.77,44.91 169.07,45.6 168.02,45.6 167.85,45.77 167.08,45.77 166.79,45.48 165.44,45.48 165.34,45.58 164.97,45.58 164.71,45.32 164.71,44.95 165.76,43.91 166.93,43.91 167.33,43.5 167.33,40.18 165.97,38.81 165.97,38.38 164.4,36.8 164.4,36.52 164.4,35.27 165.59,34.08 165.59,33.48 v1(165.78,33.28)
FAN_TACH1: length 222.7
  TOP w0.254: R2461.2 178.76,47.49 179.5,47.49 v1(179.53,47.46) ; R2606.1 108.43,140.26 EC2602.1 108.45,141.04 108.45,141.84 109.2,142.59 111.83,142.59 v1(112.2,142.21)
  L4 w0.254: v1(134.89,148.12) 135.28,148.51 135.84,148.51 136.1,148.26 137.12,148.26 144.41,140.97 144.41,124.37 143.8,123.76 143.8,108.51 145.88,106.43 149.75,106.43 149.83,106.35 152.15,106.35 158.75,99.75 159.05,99.75 160.16,98.63 160.16,98.12 160.71,97.57 161.37,97.57 164.24,94.69 164.24,93.85 164.54,93.55 164.64,93.55 166.54,91.65 169.96,91.65 170.05,91.74 176.35,91.74 177.36,92.75 183.74,92.75 184.82,93.83 189.57,93.83 193.08,90.31 193.08,70.7 191.63,69.24 191.63,67.36 195.21,63.78 v1(195.21,38.73)
  BOTTOM w0.254: 179.42,47.46 v1(179.53,47.46) ; 179.42,47.46 179.42,47.33 182,44.74 v2(182,39.73) 183.49,38.24 188.39,38.24 188.75,38.6 195.08,38.6 v1(195.21,38.73) ; 179.42,47.46 179.42,47.46 179.32,47.46 179.25,47.53 178.31,47.91 D2403.K ; v1(134.89,148.12) 131.42,148.12 128.12,151.42 119.15,151.42 118.23,152.33 117.06,152.33 116.75,152.02 116.75,151.09 116.1,150.44 116.1,149.34 116.82,148.63 116.82,147.82 116.52,147.53 116.17,147.53 114.22,145.58 114.22,145.03 112.2,143.01 v1(112.2,142.21)
FAN_TACH1_C:
  vias: v4(109.76,139.42)
FAN_VCC1: length 11.7
  L4 w1.016: v4(99.81,141.47) 100.51,140.78 105,140.78 108.28,137.5 v4(109.86,137.5)
FFS_INT2: length 105.2
  TOP w0.152: R6704.2 v2(187.48,35.41) 186.37,35.41 v1(186.25,35.53) 186.05,35.74 R6707.1
  L3 w0.152: v1(186.25,35.53) 186.25,37.55 185.07,38.74 185.07,43.62 185.74,44.3 185.74,48.18 183.79,50.12 183.6,50.12 v1(183.01,50.72) 183.16,50.87 183.16,51.56 183.75,52.15 183.75,53.34 184.14,53.73 184.14,54.8 187.79,58.45 v1(187.79,58.73)
  L4 w0.152: v1(180.19,58.24) 180.06,58.37 179.38,58.37 177.19,56.19 176.74,56.19 176.37,56.56 175.9,56.56 175.53,56.19 171.03,56.19 165.08,62.14 164.03,62.14 163.71,62.45 163.71,62.96 160.52,66.16 158.25,66.16 158.11,66.02 157.36,66.02 156.98,66.02 154.01,68.99 154.01,69.03 153.98,69.06 153.98,70.37 153.01,71.35 153.01,76.11 152.74,76.38 152.54,76.38 147.09,81.83 v1(147.09,84.67)
  BOTTOM w0.152: v1(147.09,84.67) 146.33,85.43 140.53,85.43 140.28,85.18 138.97,85.18 138.84,85.31 CPU1.AC2 ; v1(187.79,58.73) 187.3,58.24 v1(180.19,58.24) ; Q6701.5 186.46,36.62 R6706.2 186.01,35.77 186.25,35.54 v1(186.25,35.53) ; U6701.11 182.39,50.79 182.94,50.79 v1(183.01,50.72)
FFS_INT2_Q: length 17.9
  TOP w0.152: v1(189.35,39.38) R6705.2 189.3,38.57 188.54,38.57 v2(187.91,37.94) 187.26,37.3 v1(185.44,37.3)
  BOTTOM w0.152: Q6701.6 186.4,37.27 185.77,36.64 R6706.1 185.44,36.81 v1(185.44,37.3) ; HDD1.1 191.94,45.05 192.64,44.34 192.64,39.41 192.3,39.07 189.67,39.07 v1(189.35,39.38)
FON#: length 2.4
  TOP w0.114: FAN261.1 91.08,139.74 R2605.2 91.01,140.45 v2(90.82,140.64)
FP_PWR: length 2.5
  TOP w0.254: AFTP8902.1 191.56,56.2 191.56,56.32 v1(191.56,56.32)
  BOTTOM w0.254: FPR1.2 189.57,55.05 C9201.1
FPR_SCAN#: length 3.2
  BOTTOM w0.102: v2(174.84,43.89) 174.59,43.64 R2412.2 174.14,42.96 173.51,42.33 KBC24.42
GPD2/LAN_WAKE#: length 31.7
  L3 w0.089: 133.74,82.14 133.48,82.14 133.12,81.77 132.27,81.77 v1(132.2,81.85)
  L3 w0.102: 133.74,82.14 134.98,82.14 135.11,82.01 135.22,81.9 136.74,81.9 137.2,81.44 137.67,81.44 138.18,81.96 141.93,81.96 142.03,81.97 144.19,81.97 147.38,78.78 148.12,78.78 150.18,76.72 152.55,76.72 155.18,74.09 v1(155.28,74.09)
  BOTTOM w0.089: CPU1.AM15 132.16,81.85 v1(132.2,81.85)
  BOTTOM w0.102: R1710.2 154.82,70.81 v2(155.59,71.58) 155.7,71.69 R1707.2 155.33,73.52 155.33,73.94 155.28,73.99 v1(155.28,74.09)
GPD9/SLP_WLAN#: length 4.4
  BOTTOM w0.089: CPU1.BB17 130.26,74.8 130.26,74.52 130.48,74.3 130.48,73.03 131.23,72.28 131.23,71.94 131.47,71.7 TP1705.1
GPD11/LANPHYPC: length 44.5
  TOP w0.127: v1(143.22,55.12) 143.32,55.22 143.32,56.79 142.62,57.49 142.62,58.74 141.23,60.13 v2(141.23,61.46) 141.23,64.82 RN1704.5
  BOTTOM w0.089: 132.37,71.68 132.37,71.8 130.66,73.51 130.66,74.37 130.44,74.59 130.44,75.68 130.35,75.78 130.35,76.66 CPU1.AW17
  BOTTOM w0.127: v1(143.22,55.12) 142.76,54.66 139.76,54.66 139.27,55.15 138.35,55.15 137.96,55.15 134.32,58.79 134.32,66.79 136.08,68.55 136.08,68.92 135.83,69.17 133.9,69.17 132.37,70.71 132.37,71.68
GPIO16_VGA: length 10.5
  BOTTOM w0.089: 181.28,140.69 181.07,140.9 GPU1.M4
  BOTTOM w0.102: 181.28,140.69 181.28,140.68 181.58,140.38 182.01,140.38 182.06,140.43 182.36,140.43 182.59,140.2 183.05,140.2 183.08,140.23 184.7,140.23 184.89,140.41 186.1,140.41 186.67,139.84 186.67,139.5 187.05,139.13 187.49,139.13 187.68,138.94 189.93,138.94 TP7903.1
GPIO_5_AC_BATT: length 7.4
  TOP w0.127: Q7902.D 183.63,137.44 182.54,137.44 182.24,137.74 181.81,137.74 R7921.2 181.6,137.53 R7913.2 180.66,137.76 180.01,137.76 v2(179.52,137.28) v1(178.74,137.28)
  BOTTOM w0.127: GPU1.T9 178.02,137.28 v1(178.74,137.28)
GPIO_8_ROMSO: length 1.7
  TOP w0.102: TP7905.1 176.46,139.43 v1(176.8,139.77)
  BOTTOM w0.102: v1(176.8,139.77) 176.8,139.3 GPU1.P10
GPIO_9_ROMSI: length 6.7
  BOTTOM w0.089: GPU1.P4 181.25,139.05 181.59,139.05 181.67,138.98 181.95,138.98 181.99,139.01 182.53,139.01 182.72,138.82
  BOTTOM w0.102: TP7906.1 186.94,138.33 185.6,138.33 185.22,138.71 182.83,138.71 182.72,138.82
GPIO_10_ROMSCK: length 4.4
  BOTTOM w0.102: GPU1.P2 181.86,139.24 182.65,139.24 182.97,138.92 185.71,138.92 TP7901.1
GPIO_17_THERMAL_INT: length 18.1
  BOTTOM w0.102: TP7923.1 189.52,124.98 188.23,126.27 187.56,126.27 184.98,128.85 184.98,130.07 184.97,130.08 184.97,131.92 181.87,135.02 181.87,135.36 181.35,135.88 181.35,136.25 180.93,136.67 180.93,137.11 180.57,137.46 180.57,137.73 GPU1.R6
GPIO_19_CTF: length 3.6
  TOP w0.102: R7922.2 182.52,140.48 v1(182.84,140.79)
  BOTTOM w0.102: v2(184.32,140.79) 182.84,140.79 v1(182.84,140.79) 182.73,140.9 GPU1.M2
GPIO_22_ROMCS#: length 7.4
  BOTTOM w0.089: 180.52,139.68 181.09,139.68 181.19,139.59
  BOTTOM w0.102: 180.52,139.68 179.94,139.68 179.85,139.77 178.88,139.77 178.35,140.3 GPU1.N8 ; TP7910.1 184.64,139.17 183.08,139.17 182.77,139.48 182.09,139.48 181.94,139.63 181.66,139.63 181.54,139.51 181.26,139.51 181.19,139.59
GPP_B4/CPU_GP3: length 3.1
  TOP w0.089: TP404.1 137.15,77.42 v1(137.81,76.76)
  BOTTOM w0.102: CPU1.AY5 137.38,76.83 137.74,76.83 v1(137.81,76.76)
GPP_B18/GSPI0_MOSI: length 29.6
  TOP w0.102: v2(135.78,79.64) v1(135.78,79.08)
  L3 w0.102: v1(153.87,72.8) 152.08,72.8 149.62,75.26 149.58,75.26 147.52,77.32 141.36,77.32 140.43,78.25 137.81,78.25 136.96,79.1 136.41,79.1 136.39,79.08 v1(135.78,79.08)
  BOTTOM w0.102: v1(135.78,79.08) 135.91,79.08 CPU1.AR7 ; v1(153.87,72.8) 154.44,73.37 154.44,75.2 155.24,76 155.24,78.67 R2007.2 R2019.1
GPP_B22: length 2.5
  TOP w0.127: v1(136.72,80.33) 136.27,80.77 136.27,80.82 135.99,81.09 TP2008.1
  BOTTOM w0.127: CPU1.AN5 137.09,80.7 v1(136.72,80.33)
GPP_B23/SML1ALERT#: length 20.4
  TOP w0.102: v1(136.68,81.03) 137.28,81.03 v2(137.53,81.28) 137.88,81.63 137.88,82.49 138.57,83.18 140.54,83.18 141.16,82.56 144.45,82.56 147.29,79.71 150.4,79.71 152.18,77.93 R1820.1
  BOTTOM w0.102: v1(136.68,81.03) 136.68,81.08 136.41,81.35 CPU1.AM7
GPP_C2/SMBALERT#: length 18.2
  TOP w0.102: v1(134.09,90.15) 134.14,90.2 v2(134.68,90.2)
  L3 w0.102: v1(145.16,87.24) 145.06,87.24 144.4,87.9 142.23,87.9 142.23,87.9 137.98,87.9 137.67,87.59 134.69,87.59 134.26,88.02 134.26,88.75 133.99,89.02 133.99,90.04 v1(134.09,90.15)
  BOTTOM w0.102: v1(134.09,90.15) 134.48,89.76 CPU1.R10 ; R1821.1 145.87,86.84 145.47,87.24 v1(145.16,87.24)
GPP_C5/SML0ALERT#: length 9.7
  BOTTOM w0.102: R1823.1 148.13,85.31 148.13,86.04 R1822.2 147.61,86.07 147.17,86.51 145.64,86.51 v2(145.55,86.59) 145.31,86.84 141.83,86.84 141.2,87.47 CPU1.W1
GPP_E0/SATAXPCIE0/SATAGP0: length 7.2
  BOTTOM w0.089: 141.54,94.45 141.36,94.26 140.39,94.26 139.97,93.84 139.66,93.84 139.65,93.85 139.62,93.85 139.61,93.84 139.24,93.84 CPU1.H2
  BOTTOM w0.102: 141.54,94.45 141.6,94.5 145.03,94.5 TP1603.1
GPU_ALERT#: length 5.4
  TOP w0.102: v2(196.93,124.55) 197.29,124.18 R2613.2 198.43,123.57 198.43,122.96 197.92,122.45 v1(197.73,122.45)
  BOTTOM w0.102: v1(197.73,122.45) 197.53,122.65 197.12,122.65 196.61,123.16 THM262.6
GPU_DMINUS: length 2.4
  BOTTOM w0.254: GPU1.T2 181.91,137.81 183.81,137.81 TP7914.1
GPU_DPLUS: length 3.9
  BOTTOM w0.203: 182.43,137.31 182.4,137.27 182.37,137.3 182.06,137.3 181.99,137.23 181.6,137.23 181.13,137.7 GPU1.T4
  BOTTOM w0.254: TP7909.1 183.09,137.31 182.43,137.31
GPU_DPRSLP: length 2.5
  BOTTOM w0.102: TP7918.1 192.98,135.87 193.35,135.49 193.35,135.36 193.49,135.23 193.94,135.23 194.07,135.09 194.15,135.03 194.17,135.03 194.62,134.66 R7911.1
GPU_DPRSLP_R: length 17.9
  TOP w0.102: v1(180.19,136.52) 180.69,136.52 180.74,136.56 v2(180.75,136.56)
  L3 w0.102: v1(180.19,136.52) 180.58,136.52 183.1,134 184.37,134 185.84,135.47 189.57,135.47 190.02,135.91 v1(190.06,135.91)
  BOTTOM w0.102: v1(190.06,135.91) 190.06,135.96 190.38,136.28 190.38,136.35 190.71,136.68 191.6,136.68 192.39,135.89 192.39,135.72 193.5,134.6 R7911.2 ; v1(180.19,136.52) 180.18,136.52 GPU1.U6
GPU_PWR_LEVEL: length 118.9
  TOP w0.102: R7937.1 183.09,133.53 v1(183.94,133.53) ; v1(161.98,50.27) 162.13,50.12 v2(162.52,50.12)
  L3 w0.102: v1(183.94,133.53) 185.69,131.78 185.69,128.31 189.24,124.76 189.24,121.44 189.03,121.24 189.03,119.16 190.18,118.02 190.18,101.48 186,97.31 186,84.82 189.3,81.52 189.3,71.19 188.09,69.99 188.09,59.04 188.22,58.91 188.22,58.56 188.12,58.45 188.12,58.32 185.82,56.02 185.82,54.38 184.6,53.16 184.55,53.16 184.55,53.15 v1(184.56,53.15)
  L4 w0.102: v1(161.98,50.27) 162.1,50.15 167.64,50.15 168.72,51.23 171.63,51.23 171.63,51.24 171.99,51.24 171.99,51.23 173.28,51.23 173.4,51.11 173.4,51.11 173.43,51.08 173.79,51.08 173.95,51.23 176.56,51.23 176.63,51.17 177.42,51.17 177.49,51.09 177.91,51.09 177.99,51.17 179.67,51.17 181.62,53.12 184.51,53.12 184.55,53.16 184.55,53.15 v1(184.56,53.15)
  BOTTOM w0.102: v1(161.98,50.27) 161.98,49.38 162.5,48.86 162.5,48.11 162.46,48.07 KBC24.10
GPU_PWR_LEVEL_R: length 2.7
  TOP w0.102: Q7902.G 182.97,134.84 v2(182.71,134.59) 182.63,134.59 182.31,134.91 182.31,135.41 182.05,135.67 R7937.2
GPU_T_CRIT#: length 2.7
  BOTTOM w0.102: THM262.4 197.26,128.75 197.09,128.93 197.09,129.29 R2615.1 R2614.2
GPU_T_CRIT_R#: length 1.5
  BOTTOM w0.102: Q2605.S 196.96,130.75 R2615.2
GPU_THM_SMBCLK: length 3.3
  TOP w0.191: v2(164.14,48.16) 163.79,48.51 v1(163.79,48.62)
  BOTTOM w0.191: R2439.1 163.94,48.76 v1(163.79,48.62) 163.71,48.56 163.26,48.11 KBC24.12
GPU_THM_SMBDAT: length 3
  TOP w0.191: v2(162.59,48.19) v1(162.98,48.59)
  BOTTOM w0.191: KBC24.11 162.86,48.46 v1(162.98,48.59) 163.1,48.7 R2438.1
GT_CORE: length 12.1
  TOP w0.508: v1(113.62,92.09) 113.56,92.14 113.56,97.32 v1(112.5,98.38) 112.04,98.84 110.4,98.84 v1(110.27,98.71)
  BOTTOM w0.203: v1(112.5,98.38) 112.19,98.06 CPU1.A48 ; v1(110.27,98.71) 109.75,98.19 109.75,98.1 109.71,98.06 CPU1.A53
  vias: v1(112.3,92.13) v1(112.98,92.09) v1(114.28,92.05) v1(114.92,92.05) v2(113.18,90.63)
GTX_CORE: length 1
  BOTTOM w0.102: CPU1.AM52 110.79,81.51 111.39,81.51 CPU1.AM50
  vias: v1(111.64,83.42) v1(112.01,82.68) v1(112.33,83.42) v1(113.01,83.42) v1(113.84,82.65) v1(113.9,83.44) v1(115.58,82.68) v2(112.25,82.17)
H_CATERR#: length 5.7
  BOTTOM w0.089: 104.36,99.74 104.36,99.73 104.37,99.73 104.37,98.46 104.36,98.46 104.36,98.14 104.37,98.14 104.37,98.07 104.51,97.92 104.51,97.91 104.52,97.91 104.52,97.46 104.51,97.45 104.48,97.37 104.48,97.21 104.51,97.12 104.51,97.08 104.52,97.07 104.52,96.85 104.49,96.78 104.46,96.65 104.42,96.51 104.43,96.31 104.43,96.17 104.3,95.99 104.14,95.76 CPU1.D63
  BOTTOM w0.102: 104.36,99.74 104.36,100.04 104.16,100.25 104.16,100.81 TP401.1
H_CPU_SVIDALRT#: length 6.3
  BOTTOM w0.114: R728.1 102.12,101.64 102.12,101.1 v2(103.18,100.03) 103.79,99.42 103.79,97.45 104.08,97.16 CPU1.B63
H_CPU_SVIDCLK: length 5.4
  BOTTOM w0.114: CPU1.A63 104,97.69 104,97.98 104,97.99 104,98.62 104,98.62 104,99.57 103.98,99.58 103.98,99.76 102.72,101.03 v2(102.72,101.25)
  BOTTOM w0.191: R732.1 103.22,101.75 v2(102.72,101.25)
H_CPU_SVIDDAT: length 8.4
  BOTTOM w0.114: v2(101.43,101.27) 103.59,99.11 103.59,97.01 103.81,96.79 103.81,96.56 103.73,96.41 103.51,96.19 CPU1.D64
  BOTTOM w0.191: v2(101.43,101.27) 100.72,101.98 R709.1 R726.2
H_CPUPWRGD: length 13.5
  BOTTOM w0.127: CPU1.A68 100.41,98.15 95.79,98.15 92.56,94.92 92.56,94.36 91.88,93.68 91.29,93.68 R1720.2 90.91,92.39 v2(90.89,92.39)
H_PECI: length 197.7
  L3 w0.102: v1(153.75,99.68) 152.5,98.43 152.5,97.49 151.66,96.65 143.62,96.65 141.74,98.54 v1(140.73,98.54)
  L4 w0.114: v1(116.31,106.28) 117.43,107.39 122.61,107.39 123.91,106.1 128.75,106.1 129.41,106.76 130.76,106.76 136.73,100.79 136.73,100.78 137.04,100.47 137.05,100.47 138.53,98.99 140.28,98.99 v1(140.73,98.54) ; v1(153.75,99.68) 153.79,99.72 154.95,99.72 156.12,98.56 156.12,97.79 165.05,88.86 170.1,88.86 170.34,88.62 170.37,88.62 170.38,88.61 177.46,88.61 179.33,90.48 184.68,90.48 185.76,91.56 187.06,91.56 190.12,88.5 190.12,71.3 189.11,70.29 189.11,66.26 192.66,62.71 192.66,38.7 191.7,37.74 191.7,36.52 183.15,27.97 181.43,27.97 180.92,28.47 180.92,28.71 180.67,28.96 178.26,28.96 177.45,28.16 172.18,28.16 171.55,28.79 171.46,28.88 170.74,28.88 170.48,28.62 166.78,28.62 166.05,27.89 156.46,27.89 v1(155.8,27.22)
  BOTTOM w0.114: CPU1.A54 109.03,98.42 111.85,101.23 111.85,102.05 112.69,102.88 112.69,102.94 112.9,103.15 112.95,103.15 113.76,103.96 114.98,103.96 v2(115.63,104.62) 115.63,105.59 v1(116.31,106.28) ; v1(155.8,27.22) 155.89,27.31 155.89,27.51 156.01,27.62 156.01,28.1 R2437.2
H_PECI_R: length 5.9
  BOTTOM w0.114: R2437.1 156.75,29.03 C2405.1 157.02,29.3 157.02,29.32 157.16,29.46 157.16,29.91 v2(157.18,29.93) 157.6,30.35 159.13,30.35 159.66,30.87 KBC24.94
H_PROCHOT#: length 337.8
  TOP w0.165: v1(161.78,45.51) 161.14,44.87 161.14,40.75 160.98,40.6 160.98,40.56 160.58,40.16 160.58,39.67 160.58,37.78 160.29,37.48 v1(160.29,36.47)
  TOP w0.191: PR4603.2 PR4607.1 126.71,148.2 126.76,148.15 v1(126.78,148.15) ; v1(135.87,182.6) 135.65,182.82 135.01,182.82 134.51,182.32 131.33,182.32 PR4458.2 130.79,182.86 130.79,183.03 129.93,183.88 125.82,183.88 125.21,183.27 125.21,182.81 124.18,181.77 123.99,181.77 123.32,181.1 122,181.1 121.57,180.68 120.46,180.68 PR4415.1 120.4,180.46 119.1,179.15 119.1,177.29 118.66,176.86 v1(118.52,176.86)
  L3 w0.165: v1(160.29,36.47) 162.04,34.73 162.04,25.56 v1(160.8,24.32) ; v1(111.7,168.4) 111.7,163.41 117.76,157.35 117.76,157.05 119.55,155.26 123.89,155.26 124.5,155.87 134.45,155.87 136.9,153.42 136.9,152.95 139.3,150.56 139.3,149.04 141.98,146.35 141.98,138.66 145.27,135.38 145.27,124.99 146.06,124.2 146.06,120.83 146.88,120.01 146.88,111.16 158.23,99.8 158.23,99.8 159.26,98.78 159.26,96.93 161.31,94.87 161.31,93.25 161.98,92.58 161.98,87.67 162.04,87.61 162.04,87.22 161.66,86.84 161.66,80.05 161.52,79.91 161.52,77.52 161.09,77.09 161.05,77.09 160.78,76.82 160.78,76.43 160.83,76.38 160.83,74.24 160.64,74.04 160.64,68.19 160.91,67.92 160.91,66.7 160.64,66.43 160.64,66.41 160.34,66.12 160.34,63.4 158.25,61.31 158.25,48.77 160.48,46.55 160.81,46.55 161.38,45.98 161.38,45.91 v1(161.78,45.51) ; v1(126.78,148.15) 124.11,150.82 117.75,150.82 117.74,150.82 116.9,150.82 116.9,150.82 113.82,150.82 108.74,145.74 106.03,145.74 103.68,143.39 v1(102.21,143.39) 102.21,142.22 100.49,140.49 99.65,140.49 98.71,139.55 98.71,138.48 94.09,133.86 94.09,119.61 93.71,119.23 93.71,112.9 93.15,112.34 93.15,112.32 89.2,108.37 v1(89.2,106.09)
  L4 w0.165: v1(102.21,143.39) 105.6,146.77 105.6,146.94 109.78,151.13 109.79,151.66 109.79,163.82 111.7,165.74 v1(111.7,168.4)
  BOTTOM w0.114: C2403.1 158.19,22.84 R2416.2 ; R401.2 98.08,102.82 98.08,102.87
  BOTTOM w0.127: v1(160.8,24.32) 160.8,23.69 159.95,22.84 v2(159.69,22.84) R2416.2
  BOTTOM w0.191: v1(89.2,106.09) 89.2,105.12 89.85,104.47 92.71,104.47 93.26,103.91 93.42,103.91 93.42,103.91 97.04,103.91 98.08,102.87 ; R403.1 97.26,101.98 R401.2 ; v1(118.52,176.86) 114.97,173.3 114.97,171.88 111.7,168.62 v1(111.7,168.4) ; PU4401.5 133.97,179.06 135.04,180.13 135.69,180.13 135.95,180.39 135.95,180.7 135.93,180.72 PR4450.2 135.93,182.55 v1(135.87,182.6)
H_PROCHOT#_EC: length 3.3
  BOTTOM w0.191: v2(159.59,25.01) 159.13,24.55 R2418.2 158.71,23.72 R2416.1 159.65,23.71 Q2408.D
H_PROCHOT#_R: length 9
  BOTTOM w0.089: 102.17,99.27 102.69,98.74 102.69,97.51 102.73,97.42 102.73,97.15 102.69,97.06 102.69,96.86 102.74,96.73 102.74,96.52 CPU1.C65
  BOTTOM w0.14: 99.09,100.13 99.24,99.98 101.45,99.98 102.17,99.27
  BOTTOM w0.191: 99.09,100.13 98.1,101.12 R403.2
H_VCCST_PWRGD: length 44.3
  TOP w0.127: v1(78.79,87.15) 79.71,88.07 v2(79.71,89.39) 79.71,92.99 81.67,94.95 81.67,98.5 88.35,105.18 89.42,105.18 89.97,105.74 89.97,106.03 v1(89.93,106.07)
  BOTTOM w0.089: 102.7,99.33 103.22,98.81 103.22,97.24 CPU1.B65
  BOTTOM w0.127: v1(89.93,106.07) 90.08,105.92 90.08,105.55 90.75,104.88 92.8,104.88 93.53,104.15 97.16,104.15 97.76,103.56 98.08,103.56 98.66,102.98 98.66,101.91 100.03,100.54 101.49,100.54 102.7,99.33 ; R1734.2 78.48,86.84 v1(78.79,87.15)
H_VCCST_PWRGD_R: length 5.3
  TOP w0.127: R1722.2 78.06,85.27 77.73,84.93 v1(77.73,84.56) 77.97,84.32 v2(78.35,84.32) 79.12,84.32 EC1708.1
  BOTTOM w0.127: R1734.1 R1716.2 77.69,84.59 v1(77.73,84.56) 77.75,84.54 R1719.1
H_VID3: length 6.7
  BOTTOM w0.102: TP7919.1 172.39,124.2 173.02,124.82 174.4,124.82 176.6,127.02 GPU1.AK10
H_VID4: length 7.4
  BOTTOM w0.102: TP7920.1 172.37,122.5 172.78,122.91 172.78,123.42 172.6,123.6 172.6,124.03 173.06,124.49 174.59,124.49 GPU1.AM10
HDA_BITCLK: length 7.6
  BOTTOM w0.089: CPU1.AY22 127.44,75.95 127.39,75.71 127.39,75.48 127.56,75.31 127.74,75.31 127.91,75.15 128.05,74.61 128.28,74.26
  BOTTOM w0.14: 128.61,72.16 128.61,72.32 128.57,72.82 128.28,74.26
  BOTTOM w0.178: R1907.2 128.04,69.93 128.61,70.5 v2(128.61,71.9) 128.61,72.16
HDA_BITCLK_CODEC_R: length 3.7
  BOTTOM w0.191: R2723.2 171.12,23.63 v2(171.18,23.57) 171.45,23.3 171.83,22.62 172.14,21.89 HDA27.5
HDA_CODEC_BITCLK: length 85.6
  TOP w0.191: v1(138.94,52.45) 138.27,51.78 138.27,48.69 v2(139.08,47.88) 141.88,45.08 v1(141.88,44.39)
  L4 w0.165: v1(141.88,44.39) 141.88,43.09 141.62,42.83 141.62,40.56 142.92,39.25 142.92,26.93 142.29,26.3 142.29,25.92 143.84,24.37 144.23,24.37 145.42,23.17 148.23,23.17 148.27,23.14 157.32,23.14 157.38,23.2 160.34,23.2 161.45,24.31 165.15,24.31 165.55,24.72 169.12,24.72 170.01,25.61 171.23,25.61 v1(171.91,26.29)
  BOTTOM w0.191: R1907.1 128.04,61.7 137.3,52.45 v1(138.94,52.45) 138.98,52.5 EC1901.2 ; v1(171.91,26.29) 171.16,26.29 EC2710.1 171.12,26.25 R2723.1
HDA_CODEC_SDIN0: length 3.6
  TOP w0.191: v1(173.01,23.39) v2(172.45,23.39)
  BOTTOM w0.191: R2724.2 173.34,23.79 173.01,23.46 v1(173.01,23.39) 173.01,22.06 172.94,22 HDA27.7
HDA_CODEC_SDOUT: length 87.1
  TOP w0.191: v1(139.1,51.71) 139.1,51.53 v2(138.8,51.23)
  L4 w0.165: v1(170.17,26.21) 169.74,26.21 168.85,25.33 165.3,25.33 164.89,24.92 159.48,24.92 158.37,23.81 155.95,23.81 154.75,25.01 149.97,25.01 149.93,25.05 149.26,25.05 149.25,25.04 144.69,25.04 143.64,26.09 143.64,39.4 142.23,40.81 142.23,42.58 142.49,42.84 142.49,45.06 143.61,46.19 143.61,52.15 143.05,52.7 143.05,53 142.36,53.7 141.09,53.7 v1(139.1,51.71)
  BOTTOM w0.178: v1(170.17,26.21) 169.92,26.47 EC2709.1
  BOTTOM w0.191: v1(170.17,26.21) 170.17,25.52 R2722.1 ; R1912.1 127,61.84 137.13,51.71 v1(139.1,51.71)
HDA_CODEC_SYNC: length 91.5
  TOP w0.191: v1(139.92,43.93) 140.58,44.6 140.58,45.38 137.64,48.32 v2(137.64,49.55) 137.64,52.05 138.74,53.16 v1(138.79,53.16)
  L4 w0.165: v1(174.65,22.35) 171.58,22.35 168.65,19.43 157.29,19.43 155.49,21.23 153.26,21.23 151.69,19.65 151.13,19.65 150.15,20.63 144.64,20.63 140.45,24.82 140.45,30.78 140.47,30.8 140.47,39.17 139.82,39.81 139.82,43.84 v1(139.92,43.93)
  BOTTOM w0.191: HDA27.9 173.74,21.66 174.43,22.35 v1(174.65,22.35) ; v1(138.79,53.16) 137.49,53.16 128.86,61.78 R1908.1
HDA_SDIN0: length 97.6
  TOP w0.191: v1(138.81,45.76) 138.81,46.17 136.97,48.01 136.97,52.28 v2(137.69,53) 138.67,53.98 v1(138.81,54.04)
  L4 w0.165: v1(138.81,45.76) 138.9,45.76 140.43,44.23 140.43,40.07 141.09,39.41 141.09,33.96 141.62,33.42 141.62,29.41 141.11,28.9 141.11,25.02 144.07,22.06 147.13,22.06 147.47,22.41 157.45,22.41 157.64,22.6 160.99,22.6 162.1,23.7 165.52,23.7 165.93,24.11 169.38,24.11 170.2,24.93 172.04,24.93 172.85,25.74 172.88,25.75 173.25,25.75 173.71,26.21 v1(173.71,26.25)
  BOTTOM w0.089: 128.81,74.46 128.47,74.8 128.47,75.71 CPU1.BA21
  BOTTOM w0.14: 129.58,70.5 129.58,71.88 129.48,71.99 129.48,73.18 128.95,73.7 128.95,74.32 128.81,74.46
  BOTTOM w0.152: v1(173.71,26.25) 173.48,26.02 173.48,25.3 173.34,25.16 R2724.1
  BOTTOM w0.191: 129.58,70.5 129.58,61.96 137.5,54.04 v1(138.81,54.04) 139.38,53.46 FC1902.1
HDA_SDOUT: length 9.4
  BOTTOM w0.089: 128.08,73.75 128.08,74.17 127.93,74.47 127.9,74.53 CPU1.BB22
  BOTTOM w0.127: FC1901.1 125.47,69.43 R1909.2 126.19,70.02 126.52,70.35 v2(126.66,70.35) 126.8,70.35 127,70.15 R1912.2 127.13,69.43 128.24,70.54 128.24,72.93 128.08,73.1 128.08,73.75
HDA_SDOUT_CODEC_R: length 4
  BOTTOM w0.191: HDA27.4 171.74,21.92 v2(171.4,22.27) 171.4,22.44 170.07,23.77 R2722.2
HDA_SPKR_R: length 2.2
  BOTTOM w0.254: v2(174.25,26.55) 174.5,26.8 174.61,27.06 R2741.2 174.61,27.7 174.21,28.09 D2703.1
HDA_SYNC: length 6.6
  BOTTOM w0.089: CPU1.BA22 128.04,75.29 128.31,74.69 128.64,74.08
  BOTTOM w0.14: 128.64,74.08 128.7,73.72 129.04,71.9
  BOTTOM w0.178: 129.04,71.9 v2(129.04,70.4) 129.04,69.63 R1908.2
HDD_DEVSLP: length 108.1
  TOP w0.102: v1(152.07,97.67) 152.54,97.67 155.02,100.15 v2(157.59,100.15) 160.76,100.15 165.56,95.36 180.4,95.36 v1(181.22,94.54)
  L3 w0.102: v1(181.22,94.54) 180.86,94.54 180.25,93.93 180.25,89.6 v1(181.37,88.47)
  L4 w0.102: v1(188.17,42.62) 189.21,43.67 189.21,47.16 189.57,47.51 189.57,61.06 186.92,63.72 186.92,72.27 187.83,73.18 187.83,82.63 187.83,83.31 185.23,85.91 183.13,85.91 181.37,87.67 v1(181.37,88.47)
  BOTTOM w0.102: v1(188.17,42.62) 187.39,42.62 186.93,43.08 R6002.1 ; v1(152.07,97.67) 152.06,97.67 152.06,97.17 151.05,96.16 150.65,96.16 148.44,93.95 146.5,93.95 145.97,93.42 144.75,93.42 144.25,93.92 142.53,93.92 142.05,93.44 140.48,93.44 CPU1.J1
HDD_DEVSLP_R: length 3.6
  BOTTOM w0.102: HDD1.5 190.39,43.05 190.08,43.36 v2(188.87,43.36) 188.7,43.36 188.66,43.32 R6002.2
HDD_FALL_INT: length 84.6
  TOP w0.152: v1(184.25,49.02) v2(183.67,49.02)
  L3 w0.152: v1(165.79,81.52) 165.13,80.86 165.13,74.43 167.12,72.44 167.12,69.1 168.2,68.02 168.6,68.02 168.76,68.18 172.99,68.18 v1(174.22,66.95)
  L4 w0.152: v1(174.22,66.95) 175.8,65.36 175.98,65.36 176.1,65.25 178.55,65.25 178.71,65.09 182.97,60.84 182.97,59.54 185.06,57.45 185.06,51.37 184.25,50.56 v1(184.25,49.02) ; v1(150.67,92.79) 150.83,92.63 151.45,92.63 154.68,89.39 154.68,88.27 154.36,87.95 154.36,84.96 154.42,84.89 156.56,82.76 158.44,81.98 161.26,81.98 161.71,81.52 v1(165.79,81.52)
  BOTTOM w0.089: CPU1.M3 139,91.22 139.06,91.19 139.26,91.19 139.35,91.22 139.35,91.23 139.63,91.23 139.63,91.22 139.71,91.19 139.89,91.19 140.04,91.19 140.27,91.29
  BOTTOM w0.152: U6701.12 182.96,50.26 183.66,49.56 R6702.2 183.77,49.5 183.77,49.24 183.99,49.02 v1(184.25,49.02) ; v1(150.67,92.79) 149.96,92.08 146.59,92.08 146.36,91.85 142.32,91.85 141.76,91.29 140.27,91.29
HDMI_CLK: length 121.5
  TOP w0.178: C5704.1 22.96,50.6 23.53,50.6 v1(23.76,50.37) v2(23.49,49.85)
  L4 w0.152: v1(23.76,50.37) 23.55,50.58 23.16,50.58 22.98,50.4 22.98,50.09 23.26,49.8 24.56,49.8 25.18,50.42 25.18,56.56 23.74,58 23.74,63.01 25.3,64.57 46.51,85.78 68.78,85.78 76.63,93.63 79.22,93.63 81.17,95.57 92.75,95.57 95.24,98.06 103.45,98.06 104.91,96.6 106.97,96.6 108.19,95.39 108.19,94.58 v1(107.43,93.82)
  BOTTOM w0.178: CPU1.G56 107.66,93.59 v1(107.43,93.82)
HDMI_CLK#: length 120.7
  TOP w0.178: v1(23.76,51.08) 23.58,50.9 22.79,50.9 C5701.1
  L4 w0.152: v1(107.43,94.47) 107.44,94.46 107.65,94.46 107.89,94.7 107.89,95.27 106.85,96.31 104.79,96.31 103.33,97.77 95.36,97.77 92.87,95.28 81.29,95.28 79.34,93.33 76.75,93.33 68.9,85.49 46.63,85.49 25.43,64.28 25.42,64.28 24.04,62.89 24.04,58.12 25.47,56.68 25.47,50.3 24.68,49.51 23.14,49.51 22.69,49.96 22.69,50.52 23.04,50.87 23.55,50.87 v1(23.76,51.08)
  BOTTOM w0.178: CPU1.F56 107.66,94.24 v1(107.43,94.47)
HDMI_CLK#_R: length 5
  TOP w0.178: ER5714.1 19.49,50.88 20.3,50.88 v1(20.45,51.03) 20.68,50.8 21.41,50.8 C5701.2
  BOTTOM w0.178: v1(20.45,51.03) 20.17,51.31 18.41,51.31 RN5701.7
HDMI_CLK#_R_C: length 8.4
  TOP w0.178: ER5714.2 18.12,50.83 17.76,50.83 R5702.2 17.32,51.04 ED5702.2 ED5702.9 14.51,51.04 14.42,50.95 13.52,50.95 12.31,52.15 11.3,52.15 HDMI1.12
HDMI_CLK_R: length 5.6
  TOP w0.178: ER5706.1 19.44,50.5 20.28,50.5 v1(20.45,50.32) ; C5704.2 21.45,50.5 20.63,50.5 v1(20.45,50.32) ; v1(20.45,50.32) v2(20.32,49.78)
  BOTTOM w0.178: RN5701.8 18.41,50.73 20.05,50.73 v1(20.45,50.32)
HDMI_CLK_R_C: length 8.5
  TOP w0.178: v2(14.05,50.52) 14.05,50.64 ; 14.05,50.64 13.39,50.64 12.18,51.85 11.3,51.85 HDMI1.10 ; 14.05,50.64 14.42,50.64 14.51,50.54 ED5702.10 ED5702.1 17.18,50.54 R5702.1 17.79,50.52 17.98,50.52 ER5706.2
HDMI_DATA0: length 121.2
  TOP w0.178: C5703.1 22.92,52.23 23.54,52.23 v1(23.73,52.05) v2(24.05,51.59)
  L4 w0.152: v1(23.73,52.05) 23.94,52.26 24.32,52.26 24.62,52.55 24.62,55.91 22.47,58.06 22.47,62.56 46.26,86.35 68.5,86.35 78.28,96.13 92.63,96.13 95.71,99.21 102.77,99.21 105.04,96.94 106.97,96.94 108.48,95.44 108.48,93.64 108.96,93.16 109.55,93.16 109.96,93.58 109.96,93.63 v1(110.18,93.84)
  BOTTOM w0.178: v1(110.18,93.84) 109.93,93.59 CPU1.G53
HDMI_DATA0#: length 121.5
  TOP w0.178: C5705.1 22.83,52.54 23.51,52.54 v1(23.73,52.76) 23.73,52.76 v2(23.73,53.32)
  L4 w0.152: v1(23.73,52.76) 23.94,52.55 24.2,52.55 24.33,52.68 24.33,55.79 22.18,57.94 22.18,62.68 46.13,86.64 68.38,86.64 78.16,96.42 92.51,96.42 95.59,99.51 102.89,99.51 105.16,97.23 107.09,97.23 108.77,95.56 108.77,93.77 109.08,93.46 109.43,93.46 109.67,93.7 109.67,93.97 v1(110.18,94.48)
  BOTTOM w0.178: CPU1.F53 109.94,94.24 v1(110.18,94.48)
HDMI_DATA0#_R: length 5.5
  TOP w0.178: C5705.2 21.51,52.58 20.58,52.58 v1(20.45,52.71) ; v1(20.45,52.71) 20.33,52.58 19.54,52.58 ER5715.1 ; v1(20.45,52.71) v2(20.8,53.15)
  BOTTOM w0.178: RN5701.5 18.41,52.4 20.15,52.4 v1(20.45,52.71)
HDMI_DATA0#_R_C: length 18.3
  TOP w0.102: 11.31,56.57 11.26,56.52 10.69,56.52 10.1,55.92 10.1,50.78 9.95,50.63 9.82,50.63 HDMI1.9
  TOP w0.178: 13.75,54.06 13.75,55.07 12.25,56.57 11.31,56.57 ; 13.75,54.06 v2(14,54.06) ; 13.75,54.06 13.75,52.86 14.17,52.45 14.42,52.45 14.51,52.54 ED5702.6 ED5702.5 17.09,52.54 R5701.2 17.73,52.58 18.17,52.58 ER5715.2
HDMI_DATA0_R: length 5
  TOP w0.178: ER5713.1 19.51,52.28 20.17,52.28 v1(20.45,52) 20.73,52.27 21.35,52.27 C5703.2
  BOTTOM w0.178: RN5701.6 18.45,51.85 20.31,51.85 v1(20.45,52)
HDMI_DATA0_R_C: length 18.1
  TOP w0.102: 11.31,56.26 11.26,56.31 10.78,56.31 10.3,55.84 10.3,50.7 10.03,50.43 9.57,50.43 9.45,50.3 HDMI1.7
  TOP w0.178: ER5713.2 18.19,52.28 17.69,52.28 R5701.1 17.41,52.04 ED5702.4 ED5702.7 14.51,52.04 14.42,52.14 14.04,52.14 13.44,52.74 13.44,54.94 12.12,56.26 11.31,56.26
HDMI_DATA1: length 121.2
  TOP w0.178: v2(22.9,46.48) v1(22.99,47.04) 22.94,46.99 C5706.1
  L4 w0.152: v1(106.5,94.51) 106.94,94.94 106.94,95.45 106.4,95.99 104.66,95.99 103.37,97.27 95.77,97.27 92.51,94.01 81,94.01 79.68,92.69 77.17,92.69 69.37,84.89 46.84,84.89 24.66,62.71 24.66,58.35 26.04,56.97 26.04,49.72 25.28,48.95 22.36,48.95 21.87,48.46 21.87,47.42 22.25,47.04 v1(22.99,47.04)
  BOTTOM w0.178: CPU1.F58 v1(106.5,94.51)
HDMI_DATA1#: length 119.3
  TOP w0.178: v2(22.9,48.32) v1(22.99,47.75) 22.68,47.44 22.39,47.44 C5707.1
  L4 w0.152: v1(106.52,95.15) 106.52,95.46 106.28,95.7 104.53,95.7 103.25,96.98 95.89,96.98 92.63,93.72 81.12,93.72 79.8,92.39 77.29,92.39 69.49,84.6 46.96,84.6 24.95,62.59 24.95,58.47 26.33,57.09 26.33,49.6 25.4,48.66 22.48,48.66 22.16,48.34 22.16,47.54 22.37,47.33 22.58,47.33 v1(22.99,47.75)
  BOTTOM w0.178: v1(106.52,95.15) 106.78,94.89 CPU1.E58
HDMI_DATA1#_R: length 5.5
  TOP w0.178: v1(20.43,47.79) 20.62,47.6 20.91,47.6 C5707.2 ; v1(20.43,47.79) v2(20.35,48.37) ; v1(20.43,47.79) 20.06,47.42 19.49,47.42 ER5704.1
  BOTTOM w0.178: v1(20.43,47.79) 19.97,47.33 RN5703.5
HDMI_DATA1#_R_C: length 9.8
  TOP w0.178: v2(14.03,47.42) 14.03,47.26 ; 14.03,47.26 12.62,47.26 12.15,47.73 12.15,49.3 11.94,49.5 HDMI1.6 ; 14.03,47.26 14.29,47.26 14.49,47.46 ED5701.6 ED5701.5 17.13,47.46 R5708.2 17.63,47.45 18.1,47.45 ER5704.2
HDMI_DATA1_R: length 4.4
  TOP w0.178: ER5705.1 19.25,46.96 20.4,46.96 v1(20.43,46.98) 20.44,46.99 C5706.2
  BOTTOM w0.178: v1(20.43,46.98) 19.01,46.98 18.76,46.74 RN5703.6
HDMI_DATA1_R_C: length 8.1
  TOP w0.178: HDMI1.4 12.49,46.96 ED5701.7 ED5701.4 17.26,46.96 R5708.1 17.5,46.96 18.31,46.96 ER5705.2
HDMI_DATA2: length 129.7
  TOP w0.178: C5709.1 22.08,45.14 v1(22.71,45.14) v2(22.87,44.58)
  L4 w0.152: v1(109.25,94.54) 109.68,94.97 109.68,95.42 107.23,97.87 106.36,97.87 103.88,100.34 95.25,100.34 92.17,97.27 77.53,97.27 70.08,89.82 68.54,89.82 66.66,87.94 46.18,87.94 21.33,63.09 21.33,57.47 19.3,55.44 19.3,49.59 21.01,47.87 21.01,45.51 21.39,45.13 21.92,45.13 21.92,45.13 22.71,45.13 v1(22.71,45.14)
  BOTTOM w0.178: CPU1.F55 v1(109.25,94.54)
HDMI_DATA2#: length 128.9
  TOP w0.178: C5708.1 22.23,45.7 22.56,45.7 v1(22.71,45.85) ; v1(109.26,95.21) 109.23,95.23 109.23,95.76 v2(109.22,95.76)
  L4 w0.152: v1(22.71,45.85) 22.71,46.37 22.61,46.48 22.12,46.48 22,46.36 22,45.63 21.8,45.43 21.51,45.43 21.31,45.63 21.31,48 19.59,49.71 19.59,55.32 21.62,57.35 21.62,62.96 46.3,87.64 66.78,87.64 68.66,89.52 70.2,89.52 77.66,96.98 92.29,96.98 95.37,100.05 103.76,100.05 106.24,97.58 107.11,97.58 109.26,95.43 v1(109.26,95.21)
  BOTTOM w0.178: CPU1.E55 108.94,94.89 v1(109.26,95.21)
HDMI_DATA2#_R: length 4.8
  TOP w0.178: ER5716.1 19.51,45.7 20.15,45.7 v1(20.41,45.96) 20.64,45.72 20.94,45.72 C5708.2
  BOTTOM w0.178: v1(20.41,45.96) 20.32,45.87 19.54,45.87 19.17,46.24 RN5703.7
HDMI_DATA2#_R_C: length 10.3
  TOP w0.178: 13.65,45.76 14.09,45.76 14.28,45.96 ED5701.9 ED5701.2 17.34,45.96 R5703.2 17.45,45.94 18.28,45.94 ER5716.2 ; 13.65,45.76 11.96,45.76 11.08,46.64 10.57,46.64 10.19,47.02 10.19,47.26 HDMI1.3 ; 13.65,45.76 v2(13.65,45.92)
HDMI_DATA2_R: length 5.1
  TOP w0.178: v1(20.41,45.16) 20.31,45.25 19.25,45.25 ER5717.1 ; v1(20.41,45.16) 20.47,45.09 C5709.2 ; v1(20.41,45.16) v2(20.2,44.63)
  BOTTOM w0.178: RN5703.8 19.2,45.65 19.41,45.44 20.12,45.44 v1(20.41,45.16)
HDMI_DATA2_R_C: length 9.7
  TOP w0.178: HDMI1.1 9.78,47 10.45,46.33 10.96,46.33 11.83,45.46 ED5701.10 ED5701.1 17.06,45.46 R5703.1 17.5,45.25 18.31,45.25 ER5717.2
HDMI_HPD_B: length 2.3
  TOP w0.102: R5710.2 20.67,60.61 Q5703.B v2(19.67,60.8)
HDMI_HPD_E: length 3.5
  TOP w0.102: v2(23.61,60.83) Q5703.E 21.65,59.7 R5712.2 R5709.1
HDMI_PLL_GND:
  vias: v2(16.59,48.67) v2(17.84,49.18) v2(25.59,50.9) v3(17.15,49.07)
HOST_DEBUG_TX: length 260.3
  TOP w0.102: v1(99.27,153.7) 99.7,153.7 100.32,154.31 R6115.1
  L3 w0.102: v1(99.27,153.7) 114.58,153.7 115.08,153.2 116.9,153.2 118.13,151.98 128.42,151.98 134.86,145.54 136.21,145.54 137.65,144.11 137.65,136.87 140.82,133.69 140.82,115.36 v1(141.05,115.13)
  L4 w0.102: v1(187.27,31) 192.19,35.92 192.19,36.23 193.15,37.19 193.15,62.91 189.59,66.47 189.59,70.08 191.02,71.51 191.02,88.29 187.27,92.05 185.56,92.05 184.48,90.97 179.12,90.97 177.25,89.1 170.58,89.1 170.31,89.35 165.25,89.35 157.23,97.37 157.23,98.25 152.11,103.37 149.79,103.37 149.55,103.13 148.8,103.13 147.53,104.4 145.18,104.4 142.37,107.22 142.23,107.22 141.63,107.81 141.61,108.47 141.61,114.57 v1(141.05,115.13)
  BOTTOM w0.102: R6807.1 188.89,8.49 189.47,9.07 189.47,11.55 190.91,13 190.91,19.79 192.61,21.49 192.61,23.17 191.31,24.48 191.31,29.71 190.01,31 v1(187.27,31) 179.28,31 179.16,31.12 v2(178.39,31.12) 178.38,31.1 175.8,31.1 175.53,31.37 171.47,31.37 171.4,31.3 167.17,31.3 166.08,30.21 165.91,30.21 R2478.2 ; R2466.1 R2478.2 ; R2478.2 164.78,30 164.78,30.46 164.86,30.54 KBC24.81
HOST_DEBUG_TX_CON: length 4.4
  TOP w0.102: v1(187.08,6.68) 187.08,6.79 187.76,7.47 188.9,7.47 DBG1.11
  BOTTOM w0.102: v1(187.08,6.68) 187.08,7.33 v2(187.09,7.34) 187.22,7.47 187.76,7.47 188.03,7.2 R6807.2
HPD_HDMI_CON: length 16.6
  TOP w0.102: ED5703.9 ED5703.2 16.28,56.09 15.97,55.79 v1(15.61,55.79) 15.33,56.07 15.33,56.88 15.93,57.48 17.83,57.48 v2(18.6,58.25) 18.89,58.54 R5711.1 R5710.1
  BOTTOM w0.102: v1(15.61,55.79) 15.33,55.5 12.71,55.5 11.48,56.73 10.46,56.73 9.72,56 HDMI1.19
HW_ACAV_IN: length 4.3
  BOTTOM w0.102: R2469.1 156.41,48.71 157.05,48.71 v2(157.09,48.75) 157.44,48.41 KBC24.128
HW_ACAVIN_NB: length 2.4
  BOTTOM w0.102: KBC24.24 168.06,49.73 TP2405.1
I2C0_SCL: length 21.7
  TOP w0.152: v1(156.48,87.26) 156.04,87.7 RN2007.1
  TOP w0.191: RN2007.1 155.54,87.46 v2(155.54,86.84)
  L3 w0.165: v1(156.48,87.26) 153.82,89.92 147.12,89.92 146.75,90.29 141.75,90.29 v1(141.69,90.23)
  BOTTOM w0.089: CPU1.N3 138.59,90.39 139.26,90.39 139.35,90.35 139.62,90.35 139.71,90.39 139.96,90.39 140.04,90.46 141.45,90.46 v1(141.69,90.23)
I2C0_SCL_TCH_PAD: length 170.2
  TOP w0.191: RN2010.3 155.76,89.38 156.48,89.38 v1(156.5,89.35) ; v1(169.02,29.92) 166.94,27.84 166.91,27.84 166.61,27.55 166.61,27.52 166.5,27.4 164.4,27.4 163.99,26.98 159.92,26.98 157.69,24.75 156.91,24.75 153.41,21.25 EC6504.1 151.32,21.25 R6518.1 151,20.93 151,20.57 150.11,19.67 v2(149.7,19.67) 146.64,19.67 146.26,19.29 144.89,19.29 v1(144.45,19.73)
  L3 w0.165: v1(156.5,89.35) 156.36,89.21 156.06,89.21 153.79,91.48 147.49,91.48 147.36,91.36 144.06,91.36 143.7,91.72 142.96,91.72 141.93,90.69 140.58,90.69 138.98,89.09 v1(136.87,89.09)
  L4 w0.165: v1(156.5,89.35) 155.86,88.71 155.86,85.4 157.26,84 158.03,84 158.18,84.16 161.31,84.16 164.62,87.46 169.44,87.46 169.67,87.24 169.83,87.24 169.84,87.23 178.03,87.23 178.04,87.24 178.9,87.24 181.01,89.35 182.3,89.35 183.11,88.54 186.66,88.54 188.99,86.22 188.99,71.77 187.98,70.76 187.98,65.24 190.7,62.51 190.7,38.97 189.2,37.46 189.2,36.47 183.75,31.03 183.64,30.9 183.63,30.9 183.62,30.89 183.26,30.87 183.1,30.87 180.86,30.73 180.77,30.65 175.81,30.65 175.75,30.71 169.8,30.71 v1(169.02,29.92)
  BOTTOM w0.191: v1(136.87,89.09) 136.87,88.78 CPU1.U6 ; v1(144.45,19.73) 144.48,19.76 144.48,20.47 Q6503.1
I2C0_SDA: length 21.2
  TOP w0.152: RN2007.2 156.18,88.37 v1(156.49,88.06)
  L3 w0.165: v1(143.37,91.29) 143.72,90.94 147.54,90.94 147.66,91.06 153.33,91.06 156.33,88.06 v1(156.49,88.06)
  BOTTOM w0.089: CPU1.M4 138.19,91.12 138.33,91.12 138.4,91.05 138.94,91.05 139.03,91.01 139.3,91.01 139.39,91.05 139.59,91.05 139.71,91 141.92,91 142.21,91.29 v2(142.75,91.29) v1(143.37,91.29)
I2C0_SDA_TCH_PAD: length 172.2
  TOP w0.191: v1(146.53,22.67) 146.53,22.62 146.79,22.36 149.82,22.36 149.93,22.47 150.79,22.47 151.19,22.07 R6519.1 151.27,21.87 151.61,21.87 151.63,21.85 EC6502.1 153.32,21.85 v2(155.35,23.89) 156.66,25.2 157.51,25.2 159.74,27.43 163.8,27.43 164.22,27.85 166.18,27.85 v1(168.26,29.92) ; RN2010.4 156.39,90.09 v1(156.45,90.03)
  L3 w0.165: v1(156.45,90.03) 154.51,91.97 142.67,91.97 141.78,91.07 140.42,91.07 138.88,89.53 134.68,89.53 134.43,89.29 134.43,88.93 134.95,88.41 135.76,88.41 v1(136.17,88)
  L4 w0.165: v1(168.26,29.92) 169.46,31.13 175.93,31.13 175.98,31.07 180.6,31.07 180.67,31.14 183.44,31.31 188.78,36.65 188.78,37.63 190.28,39.14 190.28,62.34 187.56,65.06 187.56,70.93 188.57,71.94 188.57,86.05 186.59,88.02 183.04,88.02 182.13,88.93 181.18,88.93 179.07,86.82 178.22,86.82 178.21,86.81 169.67,86.81 169.66,86.82 169.48,86.82 169.26,87.04 164.79,87.04 160.74,83 158.39,83 157.16,83.51 155.44,85.23 155.44,89.02 v1(156.45,90.03)
  BOTTOM w0.191: Q6503.4 146.32,22.54 146.45,22.67 v1(146.53,22.67) ; CPU1.U7 136.44,88.26 v1(136.17,88)
I2C1_SCL: length 13.9
  BOTTOM w0.089: CPU1.N2 139.06,90.56 139.3,90.56 139.39,90.53 139.59,90.53 139.68,90.56 139.76,90.64 143.75,90.64 143.86,90.76
  BOTTOM w0.191: RN2008.1 150.63,91.4 150.44,91.21 147.83,91.21 147.24,90.62 v2(147.08,90.62) 145.61,90.62 145.09,91.14 144.25,91.14 143.86,90.76
I2C1_SCL_R: length 26.2
  TOP w0.191: R6518.2 150.34,21.1 150.34,20.66 149.79,20.12 146.38,20.12 v1(146.03,19.77) ; AFTP6528.1 145.26,14.23 v1(143.6,15.89)
  L3 w0.165: v1(145.69,22.69) 145.69,20.11 v1(146.03,19.77) 145.8,19.53 145.8,16.43 144.79,15.43 144.06,15.43 v1(143.6,15.89)
  BOTTOM w0.127: R6515.2 145.99,22.99 v1(145.69,22.69) ; RN6502.4 146.07,19.73 v1(146.03,19.77) 146.32,20.06 146.32,20.14 ; v1(143.6,15.89) TP1.3
  BOTTOM w0.14: 146.32,20.14 Q6503.6
I2C1_SDA: length 13
  BOTTOM w0.089: 143.66,90.96 143.52,90.83 139.69,90.83 139.65,90.79 CPU1.N1
  BOTTOM w0.191: 143.66,90.96 144.12,91.42 145.84,91.42 v2(145.99,91.27) 147.26,91.27 147.65,91.66 150.26,91.66 150.68,92.07 RN2008.2
I2C1_SDA_R: length 24.3
  TOP w0.191: AFTP6527.1 150.43,16.14 149.84,15.55 144.94,15.55 v1(144.6,15.89) ; v1(144.97,22.52) 145.65,21.84 150.21,21.84 R6519.2
  L3 w0.165: v1(144.6,15.89) 145.16,16.45 v1(145.16,19.78) 145.16,22.33 v1(144.97,22.52)
  BOTTOM w0.127: RN6502.3 145.51,18.43 145.1,18.84 145.1,19.71 v1(145.16,19.78) ; v1(144.6,15.89) TP1.2 ; Q6503.3 144.63,22 144.63,22.19 v1(144.97,22.52)
  BOTTOM w0.191: R6511.2 144.97,23.3 v1(144.97,22.52)
I_ADP: length 8.5
  BOTTOM w0.102: R2421.1 152.85,33.8 C2435.1 152.91,33.91 154.33,35.33 154.33,36.57 155.16,37.4 v2(155.47,37.4) 155.8,37.4 156.26,37.85 156.26,38.49 156.5,38.73 KBC24.110
I_BATT: length 10.9
  TOP w0.254: v1(158.49,40.27) 157.54,39.33 v2(157.54,38.08) 157.14,37.67 157.1,37.67 156.43,37.01 154.41,37.01 153.4,36 R2423.1 152.24,36 151.53,36.71 C2441.1
  BOTTOM w0.203: KBC24.114 158.43,40.33 v1(158.49,40.27)
ICSP_CLK: length 10.3
  TOP w0.127: v1(152,30.43) 151.87,30.43 151.74,30.3 R2463.1
  BOTTOM w0.127: KBC24.101 156.82,35.13 156.61,34.92 156.61,33.35 156.65,33.31 156.65,31.56 155.65,30.56 152.81,30.56 v2(152.78,30.52) 152.68,30.43 v1(152,30.43)
ICSP_CLK_R: length 30.8
  TOP w0.14: v1(158.05,5.86) 157.59,5.4 157.29,5.4 157.15,5.26 DB3.2
  TOP w0.191: v1(149.04,28.57) 149.04,29.08 v2(149.49,29.52) 150.27,30.3 R2463.2
  L3 w0.165: v1(149.04,28.57) 149.04,28.05 151.1,26 151.1,20.62 150.91,20.43 150.91,20.05 151.03,19.92 151.03,17.68 150.73,17.38 150.73,13.52 158.05,6.21 v1(158.05,5.86)
ICSP_CLR: length 3.8
  BOTTOM w0.102: KBC24.87 162.46,30.24 v2(162.41,30.2) 162.47,30.15 R2414.2 R2465.1
ICSP_DAT: length 10.5
  TOP w0.127: R2464.1 152.17,31.14 v1(152.33,30.97)
  BOTTOM w0.127: KBC24.102 156.49,35.53 156.17,35.21 v2(156.06,35.21) 156.06,32.47 156.27,32.26 156.27,31.71 155.53,30.97 v1(152.33,30.97)
ICSP_DATA_R: length 31.7
  TOP w0.127: R2464.2 150.32,31.14
  TOP w0.14: v1(157.15,5.88) 156.65,5.37 DB3.3 ; v1(148.41,28.59) 148.41,29.79 v2(149.42,30.8) 149.76,31.14 150.32,31.14
  L3 w0.165: v1(157.15,5.88) 157.15,6.52 150.32,13.35 150.32,17.63 150.61,17.92 150.61,19.75 150.49,19.87 150.49,20.6 150.68,20.8 150.68,25.67 148.41,27.94 v1(148.41,28.59)
ICSP_MCLR_R: length 40
  TOP w0.102: v1(160.14,28.38) 159.8,28.03 159.49,28.03 157.26,25.8 152.95,25.8 151.22,24.07 149.35,24.07 149.2,24.23 v1(148.34,24.23) ; DB3.6 155.15,5.62 155.61,6.08 v1(155.68,6.08)
  L3 w0.102: v1(148.34,24.23) 148.03,23.91 148.03,22.78 148.65,22.16 148.65,12.92 152.68,8.89 152.87,8.89 v1(155.68,6.08)
  BOTTOM w0.102: v2(159.68,28.04) 159.8,28.04 v1(160.14,28.38) 160.6,28.38 161.5,27.48 R2465.2
INT_TP#: length 114.2
  TOP w0.102: v1(141.6,15.89) 141.17,15.46 139.61,15.46 137.56,17.51 137.56,19.21 AFTP6525.1 ; 144.33,45.44 144.33,44.69 144.19,44.36 139.46,39.63 v1(139.46,39.37) ; 144.33,45.44 142.36,45.44 140.01,47.78 140.01,48.98 139.04,49.94 139.04,50.64 139.53,51.13 139.55,51.13 139.84,51.41 140.27,51.41 140.81,50.87 141.33,50.87 141.33,50.87 141.75,50.87 142.71,51.83 144.05,51.83 145.1,52.88 145.1,56.67 144.46,57.3 144.42,57.3 144.15,57.57 144.15,58.45 v1(143.25,59.35) ; 144.33,45.44 146.72,45.44 148.94,47.66 155.15,47.66 156.16,48.66 156.75,48.66 157.09,49 157.09,49.46 158.28,50.65 158.28,51.6 158.53,51.86 158.89,51.86 159.08,51.67 159.74,51.67 160.35,52.27 163.02,52.27 163.28,52.02 173.11,52.02 v1(173.58,51.54)
  L4 w0.102: v1(139.46,39.37) 139.46,20.05 141.6,17.91 v1(141.6,15.89) ; v1(143.25,59.35) 141.84,59.35 140.54,60.65 140.54,67.83 140.34,68.03 140.34,68.2 v1(139.47,69.07)
  BOTTOM w0.102: v1(173.58,51.54) 174.05,51.07 R2431.1 ; v1(139.47,69.07) 139.5,69.07 139.9,68.67 R410.1 ; TP1.5 v1(141.6,15.89) 141.6,16.69 R6514.2
ISOLATE#: length 4.2
  TOP w0.102: R3113.1 R3109.1 52.61,173.56 v2(51.91,174.26) 51.69,174.48 LOM31.20
ITP_PMODE: length 1.2
  TOP w0.102: v1(135.75,95.16) 135.94,95.35 TP638.1
  BOTTOM w0.102: CPU1.E8 135.56,95.13 135.66,95.13 135.69,95.16 v1(135.75,95.16)
JACK_PLUG: length 6.6
  TOP w0.254: AFTP6607.1 184.69,16.57 v1(184.95,16.31)
  BOTTOM w0.254: R2923.1 184.64,16 v1(184.95,16.31) 185.19,16.56 186.63,16.56 186.64,16.55 187.77,16.55 187.8,16.58 188.58,16.58 188.62,16.55 IOBD1.27
JET_SVC: length 2.6
  TOP w0.102: v1(178.34,139.65) 177.71,139.02 v2(177.71,138.85) 178.58,138.85 R7919.2
  BOTTOM w0.102: GPU1.P8 178.34,139.24 v1(178.34,139.65)
JET_SVD: length 14.1
  BOTTOM w0.102: R7920.2 193.06,140.03 193.06,139.51 192.14,138.58 v2(191.44,138.58) 191.08,138.58 190.84,138.34 190.03,138.34 189.66,138.71 189.65,138.71 188.49,138.72 187.62,138.72 187.41,138.92 186.96,138.92 186.47,139.42 186.47,139.75 186.01,140.21 184.99,140.21 184.8,140.02 183.16,140.02 183.13,139.99 182.31,139.99 GPU1.N1
JGND:
  vias: v4(76.88,180.38) v4(76.88,179.44) v4(76.88,178.5) v4(78.15,180.38) v4(78.15,179.44) v4(78.15,178.5)
JTAG_TCK_VGA: length 9.6
  TOP w0.102: v1(184.2,141.72) 184.67,142.19 184.67,146.29 185.09,146.7 185.09,147.46 TP7911.1
  BOTTOM w0.102: GPU1.L3 181.73,141.7 182.06,141.37 182.48,141.37 182.63,141.51 183.99,141.51 v1(184.2,141.72)
JTAG_TDI_VGA: length 12
  TOP w0.102: v1(185.06,141.95) 184.91,142.09 184.91,146.23 185.36,146.69 185.36,148.08 TP7908.1
  BOTTOM w0.089: GPU1.L5 180.94,141.7 181.41,141.24 181.92,141.24 181.98,141.17 182.64,141.17
  BOTTOM w0.102: 182.64,141.17 182.67,141.2 184.31,141.2 v1(185.06,141.95)
JTAG_TDO_VGA: length 8.8
  TOP w0.102: v1(183.54,142.37) 183.46,142.45 183.46,142.94 183,143.4 182.36,143.4 181.97,143.79 181.97,146.73 TP7913.1
  BOTTOM w0.102: v1(183.54,142.37) 183.2,142.03 182.96,142.03 182.06,142.03 182.06,142.03 181.47,142.03 GPU1.K4
JTAG_TMS_VGA: length 7.7
  TOP w0.102: v1(184.17,142.4) 183.84,142.73 183.84,144.15 184.47,144.78 184.47,146.4 184.23,146.64 184.2,146.64 TP7912.1
  BOTTOM w0.102: GPU1.L1 182.25,141.75 182.54,141.75 183.52,141.75 v1(184.17,142.4)
JTAG_TRST#_VGA: length 14.3
  BOTTOM w0.089: GPU1.L6 180.14,141.7 180.52,141.32 181.04,141.32 181.48,140.88 181.48,140.77 181.67,140.58 181.93,140.58 181.98,140.63 182.44,140.63 182.67,140.39 182.97,140.39 183,140.42 184.53,140.42 184.72,140.62 185.84,140.62
  BOTTOM w0.102: TP7907.1 192.23,139.17 187.8,139.17 187.65,139.33 187.13,139.33 186.88,139.59 186.88,139.92 186.18,140.62 185.84,140.62
KB_DET#: length 108.6
  TOP w0.102: v1(191.45,98.58) 191.55,98.48 KB1.30 ; v1(159.62,67.24) 160.42,67.24 163.88,70.69 163.88,74.12 163.95,74.19 163.95,74.83 162.15,76.63 v1(161.24,76.63) 159.99,77.88 159.5,77.88 159.41,77.96 159.41,77.96 159.16,78.21 159.16,78.22 158.76,78.62 158.76,79.13 158.76,79.54 156.92,81.38 156.92,82.97 158.72,84.77 158.72,87.39 157.4,88.72 157.4,93.63 159.3,95.53 161.58,95.53 163.68,93.42 176.15,93.42 AFTP6519.1 176.44,93.14 181.84,93.14 v1(182.35,93.65) ; R2001.1 157.19,74.45 157.41,74.23 v1(157.41,74.18)
  L3 w0.102: v1(137.11,74.02) 136.81,73.71 136.81,72.18 137.06,71.93 141,71.93 141.8,71.13 141.82,71.13 142.97,69.98 142.97,69.98 143.16,69.78 144.29,69.32 146.43,67.18 146.59,67.18 146.59,67.18 153.46,67.18 154.34,68.06 154.91,68.06 155.39,67.58 159.41,67.58 159.62,67.38 v1(159.62,67.24)
  BOTTOM w0.102: v1(137.11,74.02) 137.11,74.18 136.3,74.99 CPU1.BB7 ; v1(161.24,76.63) 161.3,76.57 161.3,75.9 159.02,73.63 157.96,73.63 v1(157.41,74.18) ; v1(191.45,98.58) 187.48,98.58 182.55,93.65 v1(182.35,93.65)
KB_LED_PWM: length 2.1
  BOTTOM w0.102: KBC24.44 174.13,41.53 TP2407.1
KBC_BEEP_R: length 2
  BOTTOM w0.127: v2(172.32,26.67) 172.06,26.94 R2734.2 172.12,27.63 172.12,28.25 D2703.2
KBC_PWRBTN#: length 196.7
  TOP w0.102: v1(177.97,50.01) 176.57,51.4 174.05,51.4 173.76,51.11 173.4,51.11 172.89,51.62 167.7,51.62 v2(167.29,51.2) 166.95,50.86 162.81,50.86 162.55,51.12 159.64,51.12 157.88,49.36 157.88,48.87 157.84,48.76 155.92,46.84 v1(152.28,46.84) ; v1(182.95,181.32) 183.19,181.08 RN6401.2
  L3 w0.102: v1(182.95,181.32) 183.48,181.32 183.67,181.52 192.14,181.52 193.18,180.47 193.2,180.47 197.58,176.09 197.57,176.08 198.77,174.88 198.77,153.16 194.62,149.01 194.62,146.62 193.5,145.5 193.5,141.86 193.5,141.17 193.5,141 194.55,139.96 194.55,139.42 194.55,139.06 194.55,136.17 192.34,133.96 192.34,133.62 192.34,129.89 191.08,128.63 191.08,120.88 190.28,120.08 190.28,119.14 191.15,118.26 191.63,118.26 191.99,117.9 191.99,94.11 193.84,92.26 193.84,71.61 191.65,69.43 191.65,67.37 192.66,66.36 192.66,59.47 192.27,59.08 192.27,59.07 189.67,59.07 186.39,55.79 186.39,52.07 185.29,50.98 185.29,49.8 v1(185.71,49.38)
  L4 w0.102: v1(185.71,49.38) 185.73,49.38 185.73,49.37 185.7,49.37 184.4,48.07 182.77,48.07 182.77,48.06 181.89,48.06 181.88,48.07 179.56,48.07 178.76,48.87 178.76,49.22 v1(177.97,50.01)
  BOTTOM w0.102: R2432.1 v1(152.28,46.84)
KBC_PWRBTN#_C: length 16.3
  TOP w0.127: v1(188.08,178.63) 187.54,179.17 G6401.1 185.49,179.17 ED6401.1 EC6403.1 185.37,180.38 RN6401.3 184.57,181.08 182.74,179.26 AFTP6404.1
  BOTTOM w0.127: G6402.1 188.02,178.69 v1(188.08,178.63) 190.98,178.63 192.8,176.81 PWR1.2
KSI0: length 104.5
  TOP w0.102: v1(165.41,39.57) 166.1,40.26 172.7,40.26 173.89,41.45 176.47,41.45 176.58,41.5 179.18,44.09 184.62,44.09 184.69,44.03 184.72,44 185.4,44 188.9,47.49 188.9,52.23 189.09,52.42 189.09,63.45 187.64,64.9 187.64,70.9 191.31,74.56 192.48,74.56 195.23,77.31 195.23,102.43 AFTP6507.1 194.56,104.1 193.78,104.88 KB1.22 191.58,104.88 v1(191.49,104.97)
  BOTTOM w0.102: RN2404.5 190.71,105.75 v1(191.49,104.97) ; KBC24.98 159.85,33.93 160.85,34.94 161.51,34.94 165.19,38.62 165.19,38.79 165.19,38.79 165.19,39.34 v1(165.41,39.57)
KSI1: length 102.2
  TOP w0.102: v1(165.65,43.18) 166.33,42.5 168.15,42.5 168.66,43.01 169.85,43.01 170.8,43.95 174.62,43.95 176.46,45.79 AFTP6540.1 182.58,45.79 184.01,47.22 185.6,47.22 187.2,48.82 187.2,53.61 186.94,53.87 186.94,63.69 186.42,64.21 186.42,71.4 190.8,75.78 191.98,75.78 193.51,77.32 193.51,82.79 193.51,93.46 190.61,96.36 190.61,102.51 v1(191.49,103.39) 191.6,103.28 KB1.24
  BOTTOM w0.102: KBC24.99 159.96,34.33 160.77,35.14 161.4,35.14 164.93,38.67 164.93,40.87 165.65,41.58 v1(165.65,43.18) ; RN2404.7 190.22,104.66 v1(191.49,103.39)
KSI2: length 100.7
  TOP w0.102: v1(162.96,39.86) 163.56,40.46 172.61,40.46 173.81,41.66 176.09,41.66 178.8,44.37 183.08,44.37 183.9,45.19 185.77,45.19 188.7,48.11 188.7,52.31 188.89,52.51 188.89,63.36 188.83,63.42 187.44,64.82 187.44,70.98 191.22,74.76 192.4,74.76 194.84,77.21 194.84,95.72 194.86,95.73 194.86,100.43 AFTP6533.1 193.61,101.68 193.61,101.68 KB1.26 191.67,101.68 v1(191.55,101.8)
  BOTTOM w0.102: v1(162.96,39.86) 163.49,40.39 163.49,41.97 163.45,42.02 163.45,42.6 161.35,44.71 161.35,45.96 160.86,46.45 KBC24.6 ; RN2403.5 190.32,102.59 191.11,101.8 v1(191.55,101.8)
KSI3: length 95.5
  TOP w0.102: v1(163.05,44.27) 163.6,43.72 AFTP6502.1 165.72,43.72 166.2,43.23 166.2,43.03 166.53,42.7 168.07,42.7 168.58,43.21 169.77,43.21 170.72,44.16 174.53,44.16 174.55,44.17 176.57,46.19 182.69,46.19 183.98,47.48 185.57,47.48 187,48.91 187,53.53 186.74,53.79 186.74,63.27 186.22,63.79 186.22,71.49 190.72,75.98 191.89,75.98 193.31,77.4 193.31,82.87 193.31,93.35 190.41,96.25 190.41,103.13 v1(191.47,104.19) 191.59,104.08 KB1.23
  BOTTOM w0.102: v1(191.47,104.19) 190.5,105.17 RN2404.6 ; v1(163.05,44.27) 162.82,44.5 162.82,45.08 161.96,45.95 161.78,45.95 161.26,46.47 KBC24.7
KSI4: length 98.9
  TOP w0.102: v1(164.8,41.83) 167.95,41.83 AFTP6521.1 168.09,41.85 168.83,42.6 170.02,42.6 170.97,43.55 174.97,43.55 176.65,45.22 182.66,45.22 183.56,46.13 185.39,46.13 187.61,48.34 187.61,53.78 187.36,54.03 187.36,63.89 186.83,64.43 186.83,71.23 190.97,75.37 192.15,75.37 193.92,77.15 193.92,82.62 193.92,93.63 191.02,96.53 191.02,100.55 v1(191.56,101.1) 191.78,100.88 KB1.27
  BOTTOM w0.102: v1(191.56,101.1) 191.11,101.1 190.2,102 RN2403.6 ; KBC24.104 158.86,36.33 159.36,35.84 161.81,35.84 164.72,38.76 164.72,40.95 164.8,41.03 v1(164.8,41.83)
KSI5: length 100.9
  TOP w0.102: v1(164.49,42.45) 164.65,42.28 AFTP6513.1 168.23,42.28 168.75,42.8 169.94,42.8 170.89,43.75 174.7,43.75 176.38,45.43 182.57,45.43 183.48,46.33 185.31,46.33 187.4,48.43 187.4,53.7 187.16,53.95 187.16,63.81 186.62,64.34 186.62,71.32 190.88,75.58 192.06,75.58 193.71,77.23 193.71,82.71 193.71,93.54 190.81,96.44 190.81,101.95 v1(191.47,102.6) 191.59,102.48 KB1.25
  BOTTOM w0.102: RN2404.8 189.99,104.08 v1(191.47,102.6) ; KBC24.105 158.75,36.73 159.44,36.04 161.73,36.04 164.44,38.76 164.44,39.15 164.37,39.22 164.37,42.33 v1(164.49,42.45)
KSI6: length 98.3
  TOP w0.102: v1(191.45,100.08) KB1.28 193.78,100.08 194.48,99.39 194.48,77.13 192.31,74.97 191.14,74.97 187.23,71.06 187.23,64.73 188.25,63.72 188.25,62.58 AFTP6511.1 188.68,62.14 188.68,52.59 188.45,52.35 188.45,48.15 185.7,45.4 183.83,45.4 182.99,44.57 178.71,44.57 176.01,41.86 173.73,41.86 172.53,40.66 163.42,40.66 163.05,40.3 162.78,40.3 162.53,40.04 162.53,38.79 v1(162.26,38.52)
  BOTTOM w0.102: KBC24.107 161.13,37.53 161.41,37.24 161.94,37.24 162.31,37.61 162.31,38.47 v1(162.26,38.52) ; v1(191.45,100.08) 191.45,100.2 190.15,101.5 RN2403.7
KSI7: length 97.4
  TOP w0.102: v1(191.52,99.28) KB1.29 193.54,99.28 194.24,98.58 194.24,77.18 192.23,75.17 191.05,75.17 187.03,71.15 187.03,64.65 187.76,63.91 187.76,60.05 AFTP6523.1 188.48,59.33 188.48,52.67 188.24,52.44 188.24,48.23 185.62,45.61 183.74,45.61 182.91,44.77 178.63,44.77 175.92,42.06 173.64,42.06 172.44,40.87 163.06,40.87 162.26,40.06 162.26,39.34 v1(161.62,38.7)
  BOTTOM w0.102: RN2403.8 189.8,100.92 191.44,99.28 v1(191.52,99.28) ; v1(161.62,38.7) 161.62,38.55 162.11,38.06 162.11,37.7 161.86,37.45 161.5,37.45 161.01,37.93 KBC24.108
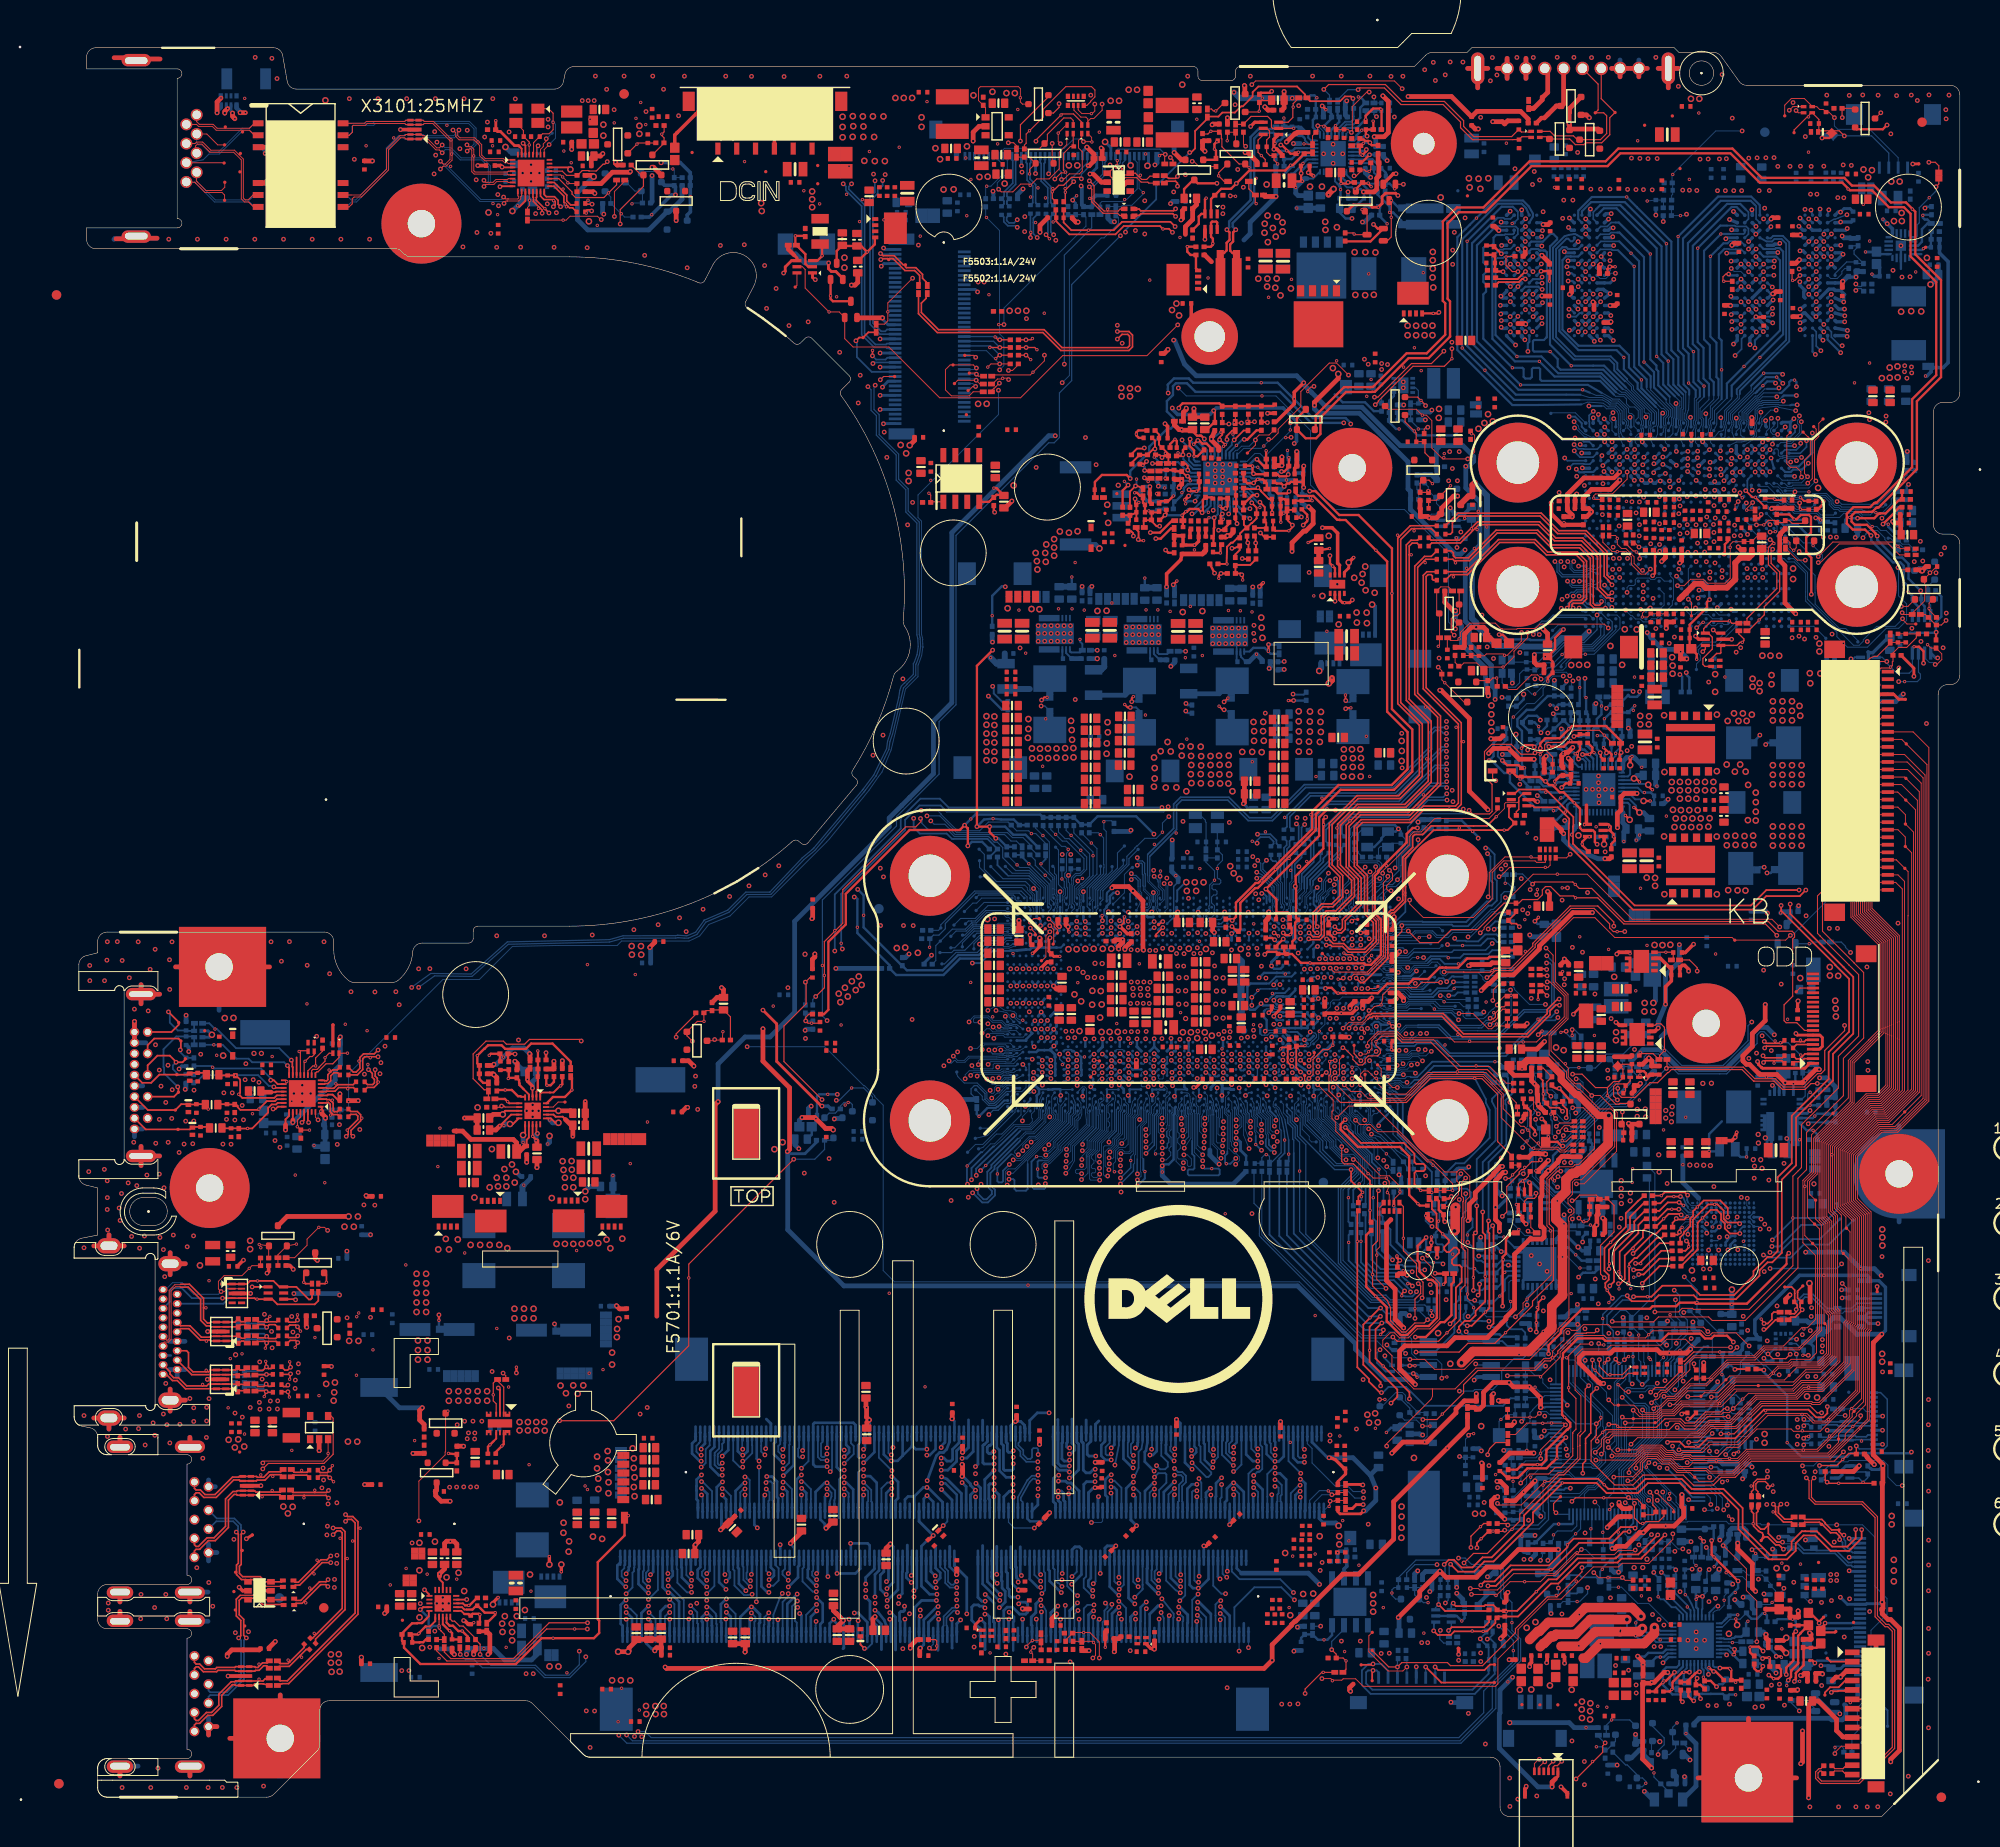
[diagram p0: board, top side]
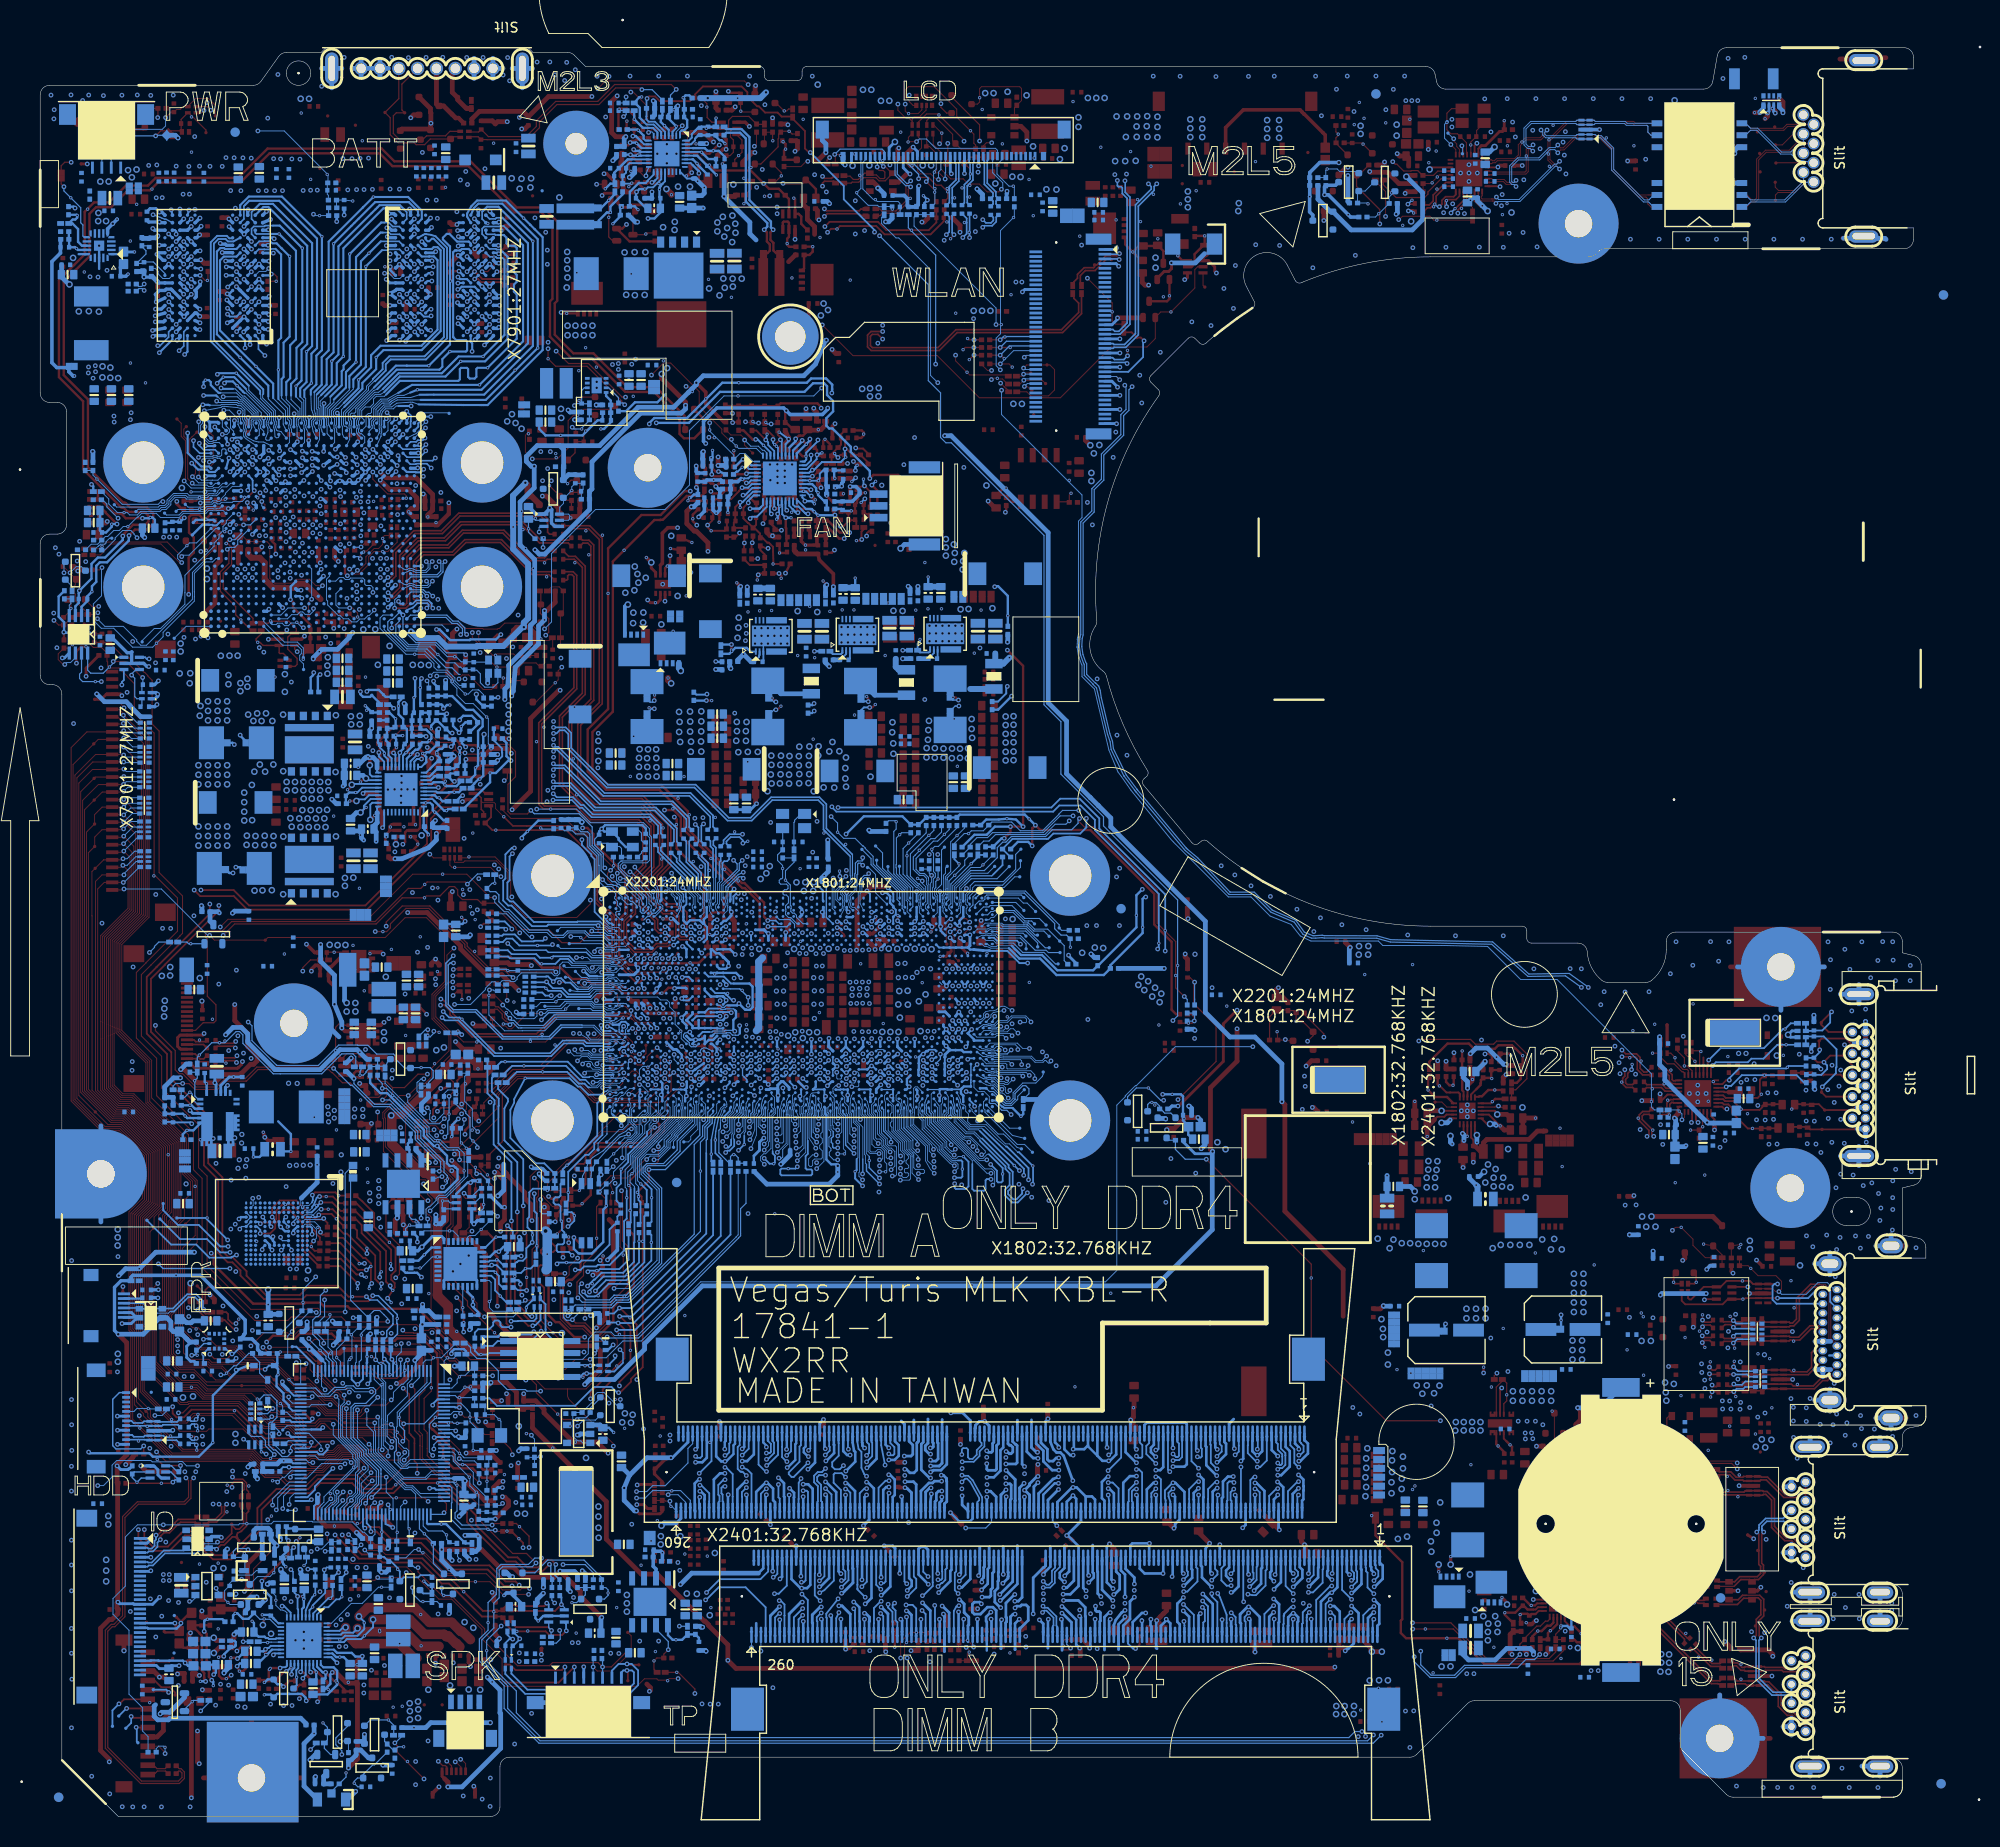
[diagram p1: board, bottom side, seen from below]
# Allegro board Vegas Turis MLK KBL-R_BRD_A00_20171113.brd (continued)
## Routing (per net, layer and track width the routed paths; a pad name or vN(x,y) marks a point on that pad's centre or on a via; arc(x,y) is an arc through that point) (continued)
KSO0: length 122.4
  TOP w0.102: v1(191.48,112.08) KB1.13 194.76,112.08 196.45,110.39 196.45,76.33 193.46,73.34 191.81,73.34 188.86,70.39 188.86,65.41 190.25,64.01 190.31,63.96 190.31,51.91 190.12,51.72 190.12,44.07 AFTP6520.1 188.91,42.87 188.91,42.47 185.26,38.82 177.78,38.82 176.79,37.83 171.77,37.83 171.56,38.05 171.06,38.05 170.94,37.93 170.08,37.93 169.73,38.27 169.02,38.27 168.44,38.86 166.8,38.86 165.81,37.88 v1(161.68,37.88)
  BOTTOM w0.102: RN2406.8 191.41,112.01 v1(191.48,112.08) ; KBC24.2 159.26,46.11 162.41,42.95 162.41,41.45 162.49,41.38 162.49,40.36 162.27,40.15 162.27,39.72 161.69,39.13 161.44,39.13 161.19,38.88 161.19,38.52 161.2,38.51 161.2,38.36 v1(161.68,37.88)
KSO1: length 114.7
  TOP w0.102: v1(163.01,39.22) 163.08,39.22 163.77,38.54 165.9,38.54 166.63,39.27 168.61,39.27 169.19,38.68 169.9,38.68 170.25,38.33 170.77,38.33 170.89,38.45 171.73,38.45 171.94,38.24 174.64,38.24 175.63,39.23 176.85,39.23 178.8,41.18 182.43,41.18 182.67,40.94 185.51,40.94 189.71,45.14 189.71,51.89 189.9,52.08 189.9,63.79 188.45,65.24 188.45,70.56 191.64,73.75 192.82,73.75 196.04,76.97 196.04,108.92 AFTP6517.1 194.48,110.48 KB1.15 191.8,110.48 191.75,110.53 v1(191.47,110.53)
  BOTTOM w0.102: RN2408.6 191.42,110.48 v1(191.47,110.53) ; v1(163.01,39.22) 163.69,39.9 163.69,42.06 163.65,42.1 163.65,44.2 163.64,44.2 163.64,46.13 164.06,46.54 KBC24.14
KSO2: length 117.2
  TOP w0.102: v1(191.47,111.33) 191.82,111.33 191.86,111.28 KB1.14 194.8,111.28 196.25,109.83 196.25,76.63 AFTP6510.1 193.16,73.55 191.73,73.55 188.65,70.47 188.65,65.32 190.11,63.87 190.11,52 189.92,51.81 189.92,44.42 188.64,43.15 188.64,42.49 185.18,39.02 177.69,39.02 176.7,38.04 171.86,38.04 171.64,38.25 170.98,38.25 170.86,38.13 170.16,38.13 169.81,38.48 169.11,38.48 168.52,39.06 166.71,39.06 165.96,38.31 v1(163.38,38.31)
  BOTTOM w0.102: v1(191.47,111.33) 191.21,111.07 RN2408.5 ; KBC24.15 164.46,46.65 163.85,46.04 163.85,44.29 163.85,44.28 163.85,42.18 163.9,42.14 163.9,39.46 163.38,38.95 v1(163.38,38.31)
KSO3: length 112.5
  TOP w0.102: v1(191.49,109.7) 191.68,109.63 191.81,109.68 KB1.16 194.16,109.68 195.84,108 195.84,77.06 192.74,73.95 191.56,73.95 188.25,70.64 188.25,65.15 189.7,63.7 189.7,52.17 189.51,51.98 189.51,45.22 186.11,41.82 184.78,41.82 183.97,42.63 179.97,42.63 176.85,39.52 173.82,39.52 172.99,38.69 170.84,38.69 170.69,38.54 170.33,38.54 169.98,38.88 169.28,38.88 168.69,39.47 166.54,39.47 166.04,38.97 AFTP6518.1 165.22,38.97 v1(164.01,38.97)
  BOTTOM w0.102: v1(191.49,109.7) 191.21,109.98 RN2408.7 ; v1(164.01,38.97) 164.1,39.06 164.1,42.23 164.06,42.27 164.06,44.37 164.05,44.37 164.05,45.64 164.86,46.45 KBC24.16
KSO4: length 84.8
  TOP w0.102: v1(171.45,44.63) 172.81,44.63 AFTP6522.1 173.22,45.04 174.68,45.04 176.27,46.62 180.05,46.62 181.09,47.66 182.39,47.66 182.62,47.89 185.41,47.89 186.59,49.08 186.59,53.36 186.33,53.62 186.33,63.1 185.81,63.62 185.81,71.65 190.56,76.41 191.74,76.41 192.9,77.57 192.9,83.04 192.9,83.04 192.9,84.05 192.9,93.18 190,96.08 190,104.98 v1(191.47,106.45) 191.59,106.45 191.62,106.48 KB1.20
  BOTTOM w0.102: v1(171.45,44.63) 171.45,44.46 171.58,44.33 KBC24.37 ; v1(191.47,106.45) 190.74,107.19 RN2409.7
KSO5: length 82.1
  TOP w0.102: KB1.21 191.49,105.68 191.47,105.7 v1(191.47,105.7) 190.2,104.43 190.2,96.17 193.11,93.27 193.11,84.14 193.11,84.14 193.11,82.96 193.11,77.48 191.81,76.19 190.63,76.19 186.01,71.57 186.01,63.71 186.54,63.18 186.54,53.7 186.79,53.44 186.79,48.99 185.49,47.69 183.01,47.69 AFTP6536.1 181.71,46.39 176.45,46.39 174.64,44.59 v1(173.95,44.59)
  BOTTOM w0.102: RN2409.8 190.57,106.6 v1(191.47,105.7) ; KBC24.38 173.55,43.93 173.95,44.33 v1(173.95,44.59)
KSO6: length 90.1
  TOP w0.102: KB1.18 191.5,108.08 v1(191.48,108.1) 189.8,106.43 189.8,96 192.7,93.1 192.7,83.97 192.7,77.65 191.65,76.61 190.48,76.61 185.61,71.74 185.61,63.54 186.13,63.01 186.13,53.53 186.39,53.28 186.39,49.16 185.32,48.09 182.52,48.09 182.3,47.86 181.01,47.86 179.97,46.82 175.9,46.82 AFTP6512.1 174.32,45.24 171.45,45.24 169.98,43.77 v1(169.55,43.77)
  BOTTOM w0.102: v1(169.55,43.77) 171.53,43.77 171.77,43.53 KBC24.39 ; v1(191.48,108.1) 191.3,108.28 RN2409.5
KSO7: length 91.7
  TOP w0.102: v1(171.54,39.76) 172.49,39.76 173.98,41.25 176.61,41.25 176.63,41.26 179.26,43.89 184.54,43.89 184.64,43.79 185.49,43.79 189.1,47.41 189.1,52.15 189.29,52.34 189.29,63.53 187.84,64.98 187.84,70.81 191.39,74.36 192.57,74.36 195.43,77.23 195.43,104.62 AFTP6534.1 194.57,106.48 193.77,107.28 KB1.19 v1(191.47,107.28)
  BOTTOM w0.102: RN2409.6 191.06,107.69 v1(191.47,107.28) ; KBC24.50 171.75,39.13 171.54,39.34 v1(171.54,39.76)
KSO8: length 98.4
  TOP w0.102: v1(170.51,38.97) 170.59,38.89 172.79,38.89 173.69,39.79 176.65,39.79 179.7,42.84 184.1,42.84 184.92,42.03 186.02,42.03 189.31,45.31 189.31,52.06 189.5,52.25 189.5,63.62 188.05,65.07 188.05,70.73 191.47,74.16 192.65,74.16 195.64,77.14 195.64,107 AFTP6505.1 193.76,108.88 KB1.17 191.55,108.88 v1(191.47,108.96)
  BOTTOM w0.102: v1(170.51,38.97) 170.51,39.44 171.79,40.72 171.93,40.72 171.93,40.73 KBC24.46 ; RN2408.8 191.03,109.4 v1(191.47,108.96)
KSO9: length 106.9
  TOP w0.102: KB1.7 192.12,116.88 191.86,116.62 191.33,116.62 189.19,114.47 189.19,95.74 192.09,92.84 192.09,83.72 192.09,83.38 191.07,82.36 191.07,82.35 188.91,80.2 188.91,75.91 185,71.99 185,68.35 184.16,67.51 184.16,63.73 AFTP6516.1 185.44,62.45 185.44,51.72 183.32,49.6 179.67,49.6 178.59,48.52 175.62,48.52 173.68,46.58 R2449.1 173.12,46.6 R2450.2 171.9,46.6 170.67,45.37 170.67,45.33 169.99,44.65 v1(168.92,44.65)
  BOTTOM w0.102: KBC24.68 170.06,32.73 169.45,33.34 169.29,33.34 169.04,33.59 169.04,34.13 169.22,34.31 169.22,34.66 166.68,37.21 166.68,37.88 166.82,38.02 166.82,38.46 168.65,40.29 168.65,43.69 168.62,43.73 168.62,44.35 v1(168.92,44.65)
KSO10: length 110.7
  TOP w0.102: KB1.5 192.66,118.52 192.06,118.52 191.45,117.91 v1(191.45,117.83) 191.45,117.6 188.78,114.94 188.78,95.58 191.68,92.68 191.68,83.55 190.66,82.53 190.66,82.52 188.51,80.36 188.51,76.37 AFTP6503.1 184.59,72.46 184.59,68.52 183.68,67.61 183.68,60.98 185.03,59.63 185.03,52.82 184.16,51.95 183.57,51.95 181.62,50 179.51,50 178.46,48.96 172.05,48.96 171.14,48.05 171.14,47.24 171.1,47.2 170.8,46.9 170.69,46.9 169.09,45.3 168.57,45.3 v1(168.05,44.78)
  BOTTOM w0.102: v1(191.45,117.83) 191.45,117.65 190.05,116.26 RN2407.5 ; KBC24.72 168.46,32.74 167.77,33.42 167.77,33.73 167.46,34.04 167.24,34.04 166.84,34.44 166.84,36.5 166.47,36.87 166.47,37.96 166.62,38.11 166.62,38.55 168.45,40.38 168.45,43.61 168.05,44.01 v1(168.05,44.78)
KSO11: length 111.3
  TOP w0.102: 191.47,117.05 191.47,117.2 191.95,117.68 KB1.6 ; 191.47,117.05 188.99,114.56 188.99,95.66 191.89,92.76 191.89,83.63 191.89,83.46 190.87,82.45 190.87,82.44 188.71,80.28 188.71,75.99 184.79,72.08 184.79,68.44 183.88,67.52 183.88,61.74 AFTP6506.1 185.23,60.39 185.23,51.8 183.23,49.8 179.59,49.8 178.55,48.76 172.13,48.76 171.67,48.3 171.67,47.48 170.89,46.7 170.78,46.7 169.16,45.08 168.74,45.08 168.48,44.82 168.48,44.6 168.23,44.35 167.98,44.35 v1(167.59,43.96) ; 191.47,117.05 v1(191.51,117.05)
  BOTTOM w0.102: KBC24.74 167.66,32.74 167.47,32.92 167.35,32.92 166.82,33.45 166.82,33.88 166.44,34.27 166.44,35.92 165.51,36.84 165.51,37.29 166.42,38.19 166.42,38.63 168.25,40.46 168.25,43.52 167.81,43.96 v1(167.59,43.96) ; v1(191.51,117.05) 191.51,116.83 190.35,115.67 RN2407.6
KSO12: length 115.2
  TOP w0.102: v1(191.48,112.82) 191.54,112.88 KB1.12 194.46,112.88 196.65,110.69 196.65,76.21 193.58,73.14 191.9,73.14 189.06,70.31 189.06,65.49 190.46,64.09 190.51,64.04 190.51,51.83 190.32,51.64 190.32,43.75 189.39,42.82 189.39,42.6 187.47,40.67 AFTP6538.1 187.47,39.76 186.33,38.62 177.86,38.62 176.84,37.59 171.97,37.59 171.56,37.18 170.53,37.18 169.65,38.07 168.94,38.07 168.35,38.66 166.88,38.66 165.2,36.98 v1(165.2,36.54)
  BOTTOM w0.102: KBC24.75 167.26,32.73 166.62,33.37 166.62,33.8 166.23,34.18 166.23,35.42 165.22,36.43 165.22,36.52 v1(165.2,36.54) ; RN2406.7 191.26,112.6 v1(191.48,112.82)
KSO13: length 119.8
  TOP w0.102: v1(165.07,35.68) 165.5,35.68 166.64,36.82 166.64,37.55 167.13,38.05 168.1,38.05 168.7,37.45 169.41,37.45 170.28,36.57 171.68,36.57 AFTP6535.1 172.63,35.62 174.12,35.62 174.78,36.29 176.39,36.29 178.1,38 186.58,38 190.73,42.15 190.73,51.47 190.92,51.66 190.92,64.26 189.47,65.71 189.47,70.14 192.06,72.73 193.75,72.73 197.06,76.04 197.06,113.61 195.39,115.28 KB1.9 191.69,115.28 191.58,115.4 v1(191.48,115.4)
  BOTTOM w0.102: RN2407.8 190.66,114.58 v1(191.48,115.4) ; v1(165.07,35.68) 166.03,34.72 166.03,34.1 166.42,33.71 166.42,33.28 166.86,32.85 KBC24.76
KSO14: length 109.5
  TOP w0.102: v1(167.82,43.35) 168.09,43.62 168.5,43.62 169.32,44.44 170.08,44.44 171.62,45.98 173.37,45.98 175.66,48.27 182.11,48.27 182.42,48.59 184.43,48.59 185.12,49.27 185.12,51.11 185.64,51.63 185.64,62.9 185.03,63.51 AFTP6539.1 184.39,66.14 184.39,67.46 185.2,68.27 185.2,71.91 189.12,75.82 189.12,80.11 192.29,83.29 192.29,83.8 192.29,92.93 189.39,95.83 189.39,114.07 v1(191.51,116.18) 191.58,116.11 192.67,116.11 KB1.8
  BOTTOM w0.102: v1(191.51,116.18) 190.5,115.17 RN2407.7 ; v1(167.82,43.35) 167.82,40.32 166.21,38.71 166.21,38.28 164.64,36.7 164.64,35.37 165.83,34.18 165.83,34.02 166.21,33.63 166.21,33.17 166.46,32.93 KBC24.77
KSO15: length 118.7
  TOP w0.102: v1(163.58,36.07) 163.63,36.11 165.64,36.11 166.39,36.87 166.39,37.59 167.05,38.25 168.18,38.25 168.77,37.67 169.48,37.67 170.37,36.78 173.36,36.78 173.65,36.49 176.31,36.49 178.03,38.21 186.5,38.21 190.52,42.23 190.52,51.56 190.72,51.75 190.72,64.12 190.66,64.18 189.26,65.58 189.26,70.22 191.98,72.94 193.66,72.94 196.86,76.13 196.86,111.81 AFTP6515.1 194.18,114.48 KB1.10 192.66,114.52 191.58,114.52 v1(191.47,114.63)
  BOTTOM w0.102: v1(191.47,114.63) 190.53,113.69 RN2406.5 ; v1(163.58,36.07) 163.58,34.49 162.86,33.77 KBC24.86
KSO16: length 109.9
  TOP w0.102: KB1.11 191.49,113.68 v1(191.48,113.67) 189.59,111.78 189.59,95.91 192.5,93.01 192.5,83.89 192.5,77.74 191.57,76.81 190.39,76.81 185.4,71.82 185.4,63.42 185.93,62.9 185.93,52.47 AFTP6508.1 186.18,52.21 186.18,49.24 185.25,48.31 182.45,48.31 182.21,48.07 175.74,48.07 173.45,45.77 171.7,45.77 170.16,44.24 169.41,44.24 168.58,43.41 168.49,43.41 167.98,42.9 166.94,42.9 v1(166.64,43.21)
  BOTTOM w0.102: v1(191.48,113.67) 190.91,113.1 RN2406.6 ; v1(166.64,43.21) 166.64,40.18 165.48,39.02 165.48,38.62 161.59,34.74 160.94,34.74 160.46,34.25 KBC24.92
L_BKLT_CTRL: length 128.2
  TOP w0.102: v1(139.58,99.93) 139.58,99.72 139.11,99.25
  TOP w0.114: R5530.1 100.12,177.59 99.82,177.9 v1(99.25,177.9) ; v1(131.73,152) 131.64,151.92 131.38,151.92 131.07,151.61 v2(131.07,151.45) ; 139.11,99.25 139.11,95.4 139.11,91.46 137.4,89.75 133.88,89.75 v1(133.46,90.16)
  L3 w0.114: v1(131.73,152) 131.87,151.87 131.87,150.69 131.34,150.17 131.34,149.81 131.87,149.29 131.87,149.12 135.03,145.96 136.47,145.96 138.06,144.36 138.06,138.08 138.06,137.04 141.34,133.76 141.34,127.11 141.34,126.62 141.34,123.37 141.34,123.36 141.34,122.69 141.34,122.68 141.34,122.33 141.34,119.33 141.6,119.07 141.6,101.49 140.04,99.93 v1(139.58,99.93)
  L4 w0.114: v1(99.25,177.9) 99.25,177.78 99.68,177.35 104.98,177.35 106.16,178.53 117.47,178.53 119.3,176.7 119.3,175.8 120.53,174.58 120.53,171.93 120.83,171.64 120.83,165.37 127.46,158.74 127.46,156.8 131.65,152.6 131.65,152.08 v1(131.73,152)
  BOTTOM w0.114: CPU1.R11 v1(133.46,90.16)
L_BKLT_EN: length 167.4
  TOP w0.102: v2(155.47,98.53) 155.46,98.53 155.46,98.05 v1(155.39,97.98)
  L2 w0.102: v1(154.04,27.33) 154.04,30.4 154.96,31.31 154.96,31.64 156.26,32.94 156.26,39.38 155.46,40.18 155.46,40.82 155.68,41.05 155.68,42.01 155.25,42.45 155.25,50.57 161.06,56.38 162.31,56.38 163.68,57.75 165.37,57.75 165.94,57.18 166.41,57.18 171.03,61.8 171.03,62.76 176.71,68.43 179.52,68.43 179.89,68.8 179.89,70.16 180.14,70.41 180.14,75.35 177.02,78.48 177.02,88.39 170.67,94.74 164.76,94.74 162.17,97.34 160.63,97.34 158.84,99.13 156.53,99.13 v1(155.39,97.98)
  L3 w0.102: v1(155.39,97.98) 155.39,96.94 157.89,94.43 157.89,90.72 158.79,89.82 158.79,86.81 158.45,86.47 158.45,85.96 158.29,85.81 158.29,84.67 157.26,83.64 152.26,83.64 149.05,86.84 144.44,86.84 144.03,87.25 142.61,87.25 142.15,87.71 138.06,87.71 137.74,87.4 134.61,87.4 134.07,87.94 134.07,88.67 v1(133.56,89.18)
  L4 w0.102: v1(170.08,28.18) 169.78,27.88 166.74,27.88 166.25,27.4 160.19,27.4 159.58,26.79 154.58,26.79 v1(154.04,27.33)
  BOTTOM w0.102: v1(170.08,28.18) 170.03,28.22 169.48,28.22 R2435.1 ; CPU1.R12 133.48,89.18 v1(133.56,89.18)
LAN_CLKREQ_LAN#: length 2.3
  TOP w0.102: R3105.2 48.17,171.02 48.39,171.25 v2(48.39,171.78) 48.35,171.83 LOM31.12
LAN_ENABLE_R_C: length 3.8
  TOP w0.127: R3106.2 62.68,179.06 v2(62.44,178.81) 62.44,178.66 62.68,178.42 62.68,177.89 R3111.1 62.67,177.84 Q3102.D
LAN_MDI0N: length 25.9
  TOP w0.102: LOM31.2 46.13,175.68 46.03,175.77 45.75,175.77 45.54,175.99 43.61,175.99 43.09,176.51 43.09,177.6 42.48,178.21 40.9,178.21 40.55,178.56 40.55,178.95 v1(40.25,179.25)
  BOTTOM w0.102: v1(40.25,179.25) 40.49,179.02 40.49,178.81 40.32,178.64 37.2,178.64 37.07,178.78 ED3202.9 ED3202.2 35.13,178.78 35,178.64 34.47,178.64 34.09,178.26 ; XF3202.11 28.91,172.35 29.43,171.82 29.91,171.82 33.17,175.07 33.17,177.34 34.09,178.26 ; v2(33.95,178.41) 34.09,178.26
LAN_MDI0P: length 25.8
  TOP w0.102: LOM31.1 46.13,176.08 46.03,175.99 45.84,175.99 45.63,176.2 43.7,176.2 43.3,176.6 43.3,177.69 42.57,178.42 40.99,178.42 40.76,178.65 40.76,179.13 v1(40.89,179.25)
  BOTTOM w0.102: v1(40.89,179.25) 40.7,179.06 40.7,178.72 40.41,178.43 40.04,178.43 ; XF3202.12 28.93,171.08 29.46,171.6 30,171.6 33.38,174.98 33.38,177.25 34.56,178.43 35,178.43 35.13,178.3 ED3202.1 ED3202.10 37.07,178.3 37.2,178.43 40.04,178.43 ; v2(40.04,178.21) 40.04,178.43
LAN_MDI1N: length 25.2
  TOP w0.102: LOM31.5 46.13,174.48 46.03,174.57 42.5,174.57 42.25,174.82 42.25,177.12 42.12,177.25 41.98,177.24 v1(41.76,177.01)
  BOTTOM w0.102: v2(42.91,177.98) 42.7,177.98 ; 42.7,177.98 42.7,179.45 41.99,180.16 37.2,180.16 37.07,180.3 ED3202.6 ED3202.5 35.25,180.3 35.12,180.16 31.93,180.16 31.74,179.97 XF3202.7 ; 42.7,177.98 42.7,177.68 42.32,177.29 42.04,177.29 v1(41.76,177.01)
LAN_MDI1P: length 25.3
  TOP w0.102: v1(41.74,177.67) 41.97,177.46 42.21,177.47 42.46,177.21 42.46,174.91 42.59,174.79 46.03,174.79 46.13,174.88 LOM31.4
  BOTTOM w0.102: XF3202.8 29.2,178.7 29.53,179.02 29.53,179.65 29.63,179.75 31.83,179.75 32.02,179.95 35.12,179.95 35.25,179.82 ED3202.4 ED3202.7 37.07,179.82 37.2,179.95 39.61,179.95 ; 39.61,179.95 41.9,179.95 42.49,179.36 42.49,177.76 42.23,177.51 41.9,177.51 v1(41.74,177.67) ; 39.61,179.95 v2(39.61,179.76)
LAN_MDI2N: length 27.3
  TOP w0.102: XF3201.8 30.44,172.35 33.19,175.1 33.19,177.23 34.61,178.64 35.12,178.64 35.25,178.78 ED3201.9 ED3201.2 36.91,178.78 37.04,178.64 37.24,178.64 38.53,177.35 38.8,177.35 v1(39.1,177.66) ; v1(43.55,173.25) 43.76,173.47 43.91,173.47 44.6,173.47 44.9,173.77 46.03,173.77 46.13,173.68 LOM31.7
  BOTTOM w0.102: 42.45,176.29 41.12,176.29 40.03,177.38 39.38,177.38 v1(39.1,177.66) ; 42.45,176.29 43.38,176.29 44.22,175.45 44.22,173.7 43.99,173.47 43.76,173.47 v1(43.55,173.25) ; 42.45,176.29 v2(42.45,176.49)
LAN_MDI2P: length 27.4
  TOP w0.102: LOM31.6 46.13,174.08 46.03,173.99 44.81,173.99 44.51,173.69 43.9,173.69 43.76,173.69 v1(43.54,173.9) ; v1(39.1,176.83) 38.8,177.14 38.44,177.14 37.16,178.42 37.03,178.42 36.9,178.3 ED3201.1 ED3201.10 35.25,178.3 35.12,178.43 34.7,178.43 33.41,177.14 33.41,175.01 30.53,172.13 29.75,172.13 29.54,171.93 29.54,171.41 29.21,171.08 XF3201.7
  BOTTOM w0.102: 40.26,176.84 41.03,176.07 43.29,176.07 44,175.36 44,173.79 43.9,173.69 43.76,173.69 v1(43.54,173.9) ; 40.26,176.84 39.94,177.17 39.43,177.17 39.1,176.84 v1(39.1,176.83) ; 40.26,176.84 v2(40.1,176.7)
LAN_MDI3N: length 27.9
  TOP w0.102: v1(38.92,175.11) 39.22,175.41 39.53,175.41 40.15,176.04 40.15,178.2 38.18,180.16 37.2,180.16 37.07,180.3 ED3201.5 ED3201.6 35.25,180.3 35.12,180.16 31.05,180.16 30.85,179.97 XF3201.12 ; LOM31.10 47.55,172.26 47.45,172.17 47.45,171.93 47.23,171.7 46.03,171.7 46.03,171.71 45.89,171.7 v1(45.68,171.45)
  BOTTOM w0.102: v1(38.92,175.11) 39.22,175.41 39.37,175.41 43.12,171.66 44.5,171.66 ; 44.5,171.66 45.44,171.66 v1(45.68,171.45) ; 44.5,171.66 v2(44.5,171.44)
LAN_MDI3P: length 27.6
  TOP w0.102: v1(38.92,175.93) 39.22,175.63 39.44,175.63 39.94,176.13 39.94,178.11 38.09,179.95 37.2,179.95 37.07,179.82 ED3201.4 ED3201.7 35.25,179.82 35.12,179.95 31.14,179.95 30.94,179.75 29.67,179.75 29.57,179.65 29.57,179.03 29.24,178.7 XF3201.11 ; v1(45.63,172.12) 45.87,171.91 46.02,171.92 46.12,171.93 46.12,171.92 47.14,171.92 47.24,172.02 47.24,172.17 47.15,172.26 LOM31.9
  BOTTOM w0.102: 39.84,175.24 39.46,175.63 39.22,175.63 v1(38.92,175.93) ; 39.84,175.24 v2(40,175.39) ; 39.84,175.24 43.21,171.87 45.41,171.87 v1(45.63,172.12)
LANWAKE#: length 43.1
  TOP w0.102: v2(164.04,45.9) 164.8,45.14 v1(165.15,45.14)
  L3 w0.102: v1(165.15,45.14) 163.79,45.14 163.53,44.88 160.92,44.88 157.47,48.33 157.47,62.44 158.92,63.89 v1(158.92,64.37)
  BOTTOM w0.102: KBC24.35 171.31,45.13 170.84,44.66 169.57,44.66 168.88,45.36 167.92,45.36 167.75,45.53 167.32,45.53 166.93,45.14 v1(165.15,45.14) ; v1(158.92,64.37) 158.08,65.21 158.08,65.64 157.95,65.78 157.21,65.78 154.92,68.07 154.92,69.72 R1710.1
LANXIN: length 7.5
  TOP w0.114: X3101.1 50.4,181.52 50.89,181.04 v2(50.89,180.06) 50.89,179.28 50.46,178.85 49.77,178.85 C3125.1 49.46,178.55 48.81,177.91 48.81,176.7 LOM31.28
LANXOUT: length 4
  TOP w0.114: LOM31.29 48.35,177.65 v2(48.36,177.66) 48.36,177.96 C3116.1 47.73,178.58 47.73,179.21 X3101.3
LCD_BRIGHTNESS: length 8.8
  TOP w0.114: v1(104.2,174.04) 104.85,174.69 105.23,174.69 105.3,174.74 v2(105.34,174.78) 105.29,174.78 105.11,174.97 105.11,176.75 105.87,177.51 EC5504.1 106.15,177.56 RN5501.2
  BOTTOM w0.114: v1(104.2,174.04) 104.2,174.04 104.2,174.7 104.15,174.75 LCD1.20
LCD_TST: length 6.7
  BOTTOM w0.102: KBC24.26 168.86,48.25 169.27,48.67 169.27,49.39 169.77,49.9 169.77,51.28 R2419.2 170.06,52.27 R2456.2 169.98,52.63 169.57,53.05 v2(169.57,53.33)
LCD_TST_C: length 15.8
  TOP w0.102: v1(98.22,172.96) 98.51,172.68 99.73,172.68 100.57,173.51 101.43,173.51 v2(101.58,173.36) 102.27,174.05 103.6,174.05 104.67,175.12 104.67,176.9 105.47,177.7 105.47,178.84 RN5501.1
  BOTTOM w0.102: v1(98.22,172.96) 98.08,173.1 98.08,173.64 99.15,174.71 LCD1.10
LCD_TST_R: length 251.6
  TOP w0.102: v1(104.8,177.79) 104.56,178.03 v2(104.56,178.92) 105.42,179.78 RN5501.4
  L4 w0.102: v1(194.24,35.17) 195.64,36.57 195.64,63.96 192.06,67.54 192.06,69.06 193.52,70.52 193.52,90.49 189.18,94.83 184.24,94.83 182.59,93.18 177.18,93.18 176.23,92.23 169.93,92.23 169.78,92.08 167.71,92.08 161.23,98.56 161.23,99.07 159.49,100.81 159.44,100.81 156.38,103.88 156.38,105.43 156.32,105.48 154.3,107.5 147.34,107.5 147.05,107.22 145.71,107.22 144.23,108.69 144.23,123.55 144.84,124.17 144.84,141.15 137.29,148.69 136.93,148.69 127.87,157.75 127.87,159.23 121.24,165.86 121.24,171.81 120.99,172.06 120.99,174.7 119.72,175.97 119.72,176.87 117.64,178.94 105.95,178.94 v1(104.8,177.79) ; v1(183.63,37.27) 181.44,39.46 181.44,43.14 174.29,50.29 v1(170.22,50.29)
  BOTTOM w0.102: v1(194.24,35.17) 193.62,35.17 192.71,36.08 192.71,37.34 192.22,37.83 188.59,37.83 188.45,37.69 185.66,37.69 185.62,37.73 185.26,37.73 184.8,37.27 v1(183.63,37.27) ; R2419.1 170.92,51.31 170.22,50.61 v1(170.22,50.29)
LCD_VCC_TEST_EN: length 220.7
  TOP w0.127: D5502.2 103.51,182.78 100.54,179.81 v1(100.54,178.08) ; R2495.2 171.1,48.39 172.07,49.37 v2(174.85,49.37) 176.18,49.37 v1(176.67,49.86)
  L3 w0.127: v1(124.23,173.17) 124.63,172.77 124.63,167.97 123.34,166.68 123.34,163.08 126.79,159.63 136.61,159.63 141.6,154.64 147.35,154.64 148.27,153.72 148.27,150.03 144.83,146.59 144.83,139.85 146.57,138.11 147.51,138.11 152.27,133.35 154.5,133.35 156.05,131.8 156.05,129.6 154.5,128.05 153.39,128.05 151.92,126.58 151.92,124.77 154.13,122.55 154.13,120.36 154.86,119.63 154.86,118.93 154.45,118.52 154.45,114.51 153.99,114.06 153.99,112.5 155.27,111.23 156.82,111.23 164.56,103.48 164.56,99.71 167.7,96.58 167.7,93.59 167.12,93.01 167.12,92.3 167.9,91.51 175.63,91.51 180.82,86.33 180.82,85.99 186.7,80.11 186.7,72.4 186.51,72.21 185.33,71.02 185.33,68.91 183.27,66.85 183.27,59.72 176.62,53.07 176.62,50.73 176.74,50.61 176.74,49.92 v1(176.67,49.86)
  L4 w0.127: v1(100.54,178.08) 103.06,180.6 111.56,180.6 112.02,181.06 117.66,181.06 122.37,176.35 122.37,175.6 124.23,173.74 v1(124.23,173.17)
LCD_VCC_TEST_EN_R: length 38.4
  TOP w0.127: R2487.1 166.73,33.07 166.07,33.73 165.32,33.73 165.14,33.91 ; 165.14,33.91 v1(165.14,33.9) ; 165.14,33.91 165.11,33.87 v2(162.52,33.87) 159.51,33.87 v1(159.13,33.49) ; v1(167.5,45.1) 167.99,45.58 168.92,45.58 170.67,47.33 R2495.1
  L3 w0.127: v1(158.52,39.05) 158.2,38.73 158.2,38.19 159.45,36.94 159.45,33.81 v1(159.13,33.49) ; v1(164.48,44.55) 164.69,44.76 164.87,44.76 164.95,44.68 165.32,44.68 165.41,44.76 165.99,44.76 166.5,45.27 167.37,45.27 167.54,45.1 v1(167.5,45.1)
  BOTTOM w0.127: KBC24.113 158.11,39.93 158.52,39.52 v1(158.52,39.05) ; v1(164.48,44.55) 165.38,43.65 166.82,43.65 167.08,43.39 167.08,40.28 165.72,38.92 165.72,38.52 164.14,36.95 164.14,36.83 164.14,34.9 v1(165.14,33.9)
LCDVDD:
  vias: v2(98.12,177.78)
LCDVDD_EN: length 10.4
  TOP w0.102: D5502.3 100.76,182 100.54,182.23 v2(100.54,182.68) 100.54,183.66 100.33,183.86 96.28,183.86 96.09,183.67 96.09,182.38 R5506.1 96.84,181.63 U5501.1
LCDVDD_LCD:
  vias: v2(95.29,173.99) v4(96.19,174.26) v4(97.06,174.3)
LDO1_CAP: length 4.5
  TOP w0.254: v1(174.86,15.77) 175.84,15.77 v2(175.99,15.62) 176.07,15.54 C2703.1 176.07,14.49 R2702.1
  BOTTOM w0.203: HDA27.21 174.14,16.01 174.28,15.86 174.77,15.86 v1(174.86,15.77)
LDO2_CAP: length 2.9
  BOTTOM w0.203: 169.3,17.33 HDA27.32
  BOTTOM w0.254: C2711.1 168.1,16.94 v2(168.52,16.94) 168.91,16.94 169.3,17.33
LDO3_CAP: length 3
  BOTTOM w0.203: 172.54,22.05 HDA27.6
  BOTTOM w0.254: C2722.1 172.3,23.15 172.34,23.11 v2(172.34,23.08) 172.34,22.25 172.54,22.05
LED0: length 1.9
  TOP w0.102: v1(49.3,177.57) 49.15,177.42 LOM31.27
  BOTTOM w0.102: v1(49.3,177.57) 49.24,177.52 TP3103.1
LED1: length 2.8
  TOP w0.102: v1(50.16,178.32) 50.16,178.09 49.85,177.78 49.85,177.49 49.55,177.19 LOM31.26
  BOTTOM w0.102: v1(50.16,178.32) 50.19,178.32 TP3102.1
LED2: length 4.1
  TOP w0.102: v1(50.47,177.7) 49.95,177.18 LOM31.25
  BOTTOM w0.102: TP3101.1 51.14,179.86 51.14,178.37 v1(50.47,177.7)
LID_CL_SIO#: length 195
  TOP w0.102: v1(182.23,181.35) 182.62,181.73 182.75,181.73 182.77,181.76 183.13,181.76 183.15,181.73 RN6401.1 ; v1(169.21,41.68) 169.55,42.02 170.61,42.02 171.12,41.51 172.19,41.51 173.44,42.75 175.04,42.75 175.21,42.93 175.85,42.93 v1(176.28,43.35) v2(177.29,44.36) 177.9,44.98 182.8,44.98 183.69,45.87 185.59,45.87 188.04,48.32 188.04,52.52 188.28,52.76 188.28,56.23 v1(187.86,56.65)
  L3 w0.102: v1(187.86,56.65) 190.01,58.8 192.28,58.8 192.86,59.38 192.86,66.45 191.86,67.45 191.86,69.34 192.2,69.68 192.2,69.68 194.04,71.52 194.04,92.35 192.2,94.19 192.2,117.98 191.71,118.47 191.23,118.47 190.48,119.22 190.48,120 191.3,120.82 191.3,128.56 192.54,129.81 192.54,133.71 192.54,133.88 194.75,136.09 194.75,138.98 194.75,139.51 194.75,139.51 194.75,140.04 193.71,141.08 193.71,141.25 193.71,145.42 194.83,146.54 194.83,148.93 198.97,153.07 198.97,174.8 198.97,174.97 197.86,176.08 197.87,176.09 193.29,180.67 193.27,180.67 192.18,181.76 182.77,181.76 182.73,181.72 182.6,181.72 v1(182.23,181.35)
  BOTTOM w0.102: v1(169.21,41.68) 169.21,40.56 167.14,38.49 167.14,38.05 166.88,37.79 166.88,37.29 170.21,33.96 170.21,33.4 170.47,33.14 170.83,32.78 170.86,32.71 KBC24.66 ; RN2405.3 176.32,43.32 v1(176.28,43.35) 176.17,43.46 D2402.K
LID_CLOSE#_C: length 17.7
  TOP w0.102: AFTP6401.1 181.75,181.89 182.45,182.6 183.83,182.6 184.67,181.76 RN6401.4 185.16,181.73 185.46,181.44 185.86,181.44 EC6401.1 186.44,181.15 v1(187.03,180.57)
  BOTTOM w0.102: PWR1.3 193.8,176.31 190.79,179.33 187.38,179.33 187.03,179.68 v1(187.03,180.57)
LINE1-L_C: length 2.8
  TOP w0.254: v1(179.42,15.97) v2(179.18,15.44) 178.79,15.44 178.51,15.73 R2922.1
  BOTTOM w0.254: v1(179.42,15.97) 179.13,16.26 C2907.2
LINE1-L_R: length 2.8
  TOP w0.254: R2921.1 180.17,16.79 v2(180.09,16.87) 179.48,16.87 v1(179.39,16.78)
  BOTTOM w0.254: C2908.2 178.63,17.55 178.92,17.26 178.92,17.23 179.37,16.78 v1(179.39,16.78)
LINE1_L: length 3.1
  BOTTOM w0.203: HDA27.18 175.72,17.73
  BOTTOM w0.254: 175.72,17.73 176.27,17.18 v2(176.27,17.18) 177.2,16.26 C2907.1
LINE1_R: length 3.3
  TOP w0.254: v1(176.41,17.77) v2(176.41,17.21)
  BOTTOM w0.203: v1(176.41,17.77) 176.37,17.77 176.23,17.91 176.07,17.91 175.85,18.13 HDA27.17
  BOTTOM w0.254: v1(176.41,17.77) 176.63,17.55 C2908.1
LINE1_VREFO: length 2.9
  BOTTOM w0.203: 173.09,14.8 173.09,13.94 D2901.3 ; 173.09,14.8 v2(173.11,14.8) ; 173.09,14.8 173.09,14.81 173.14,14.86 173.14,15.55 172.93,15.76 172.93,16.23 HDA27.24
LINE1_VREFO_D1: length 4.1
  TOP w0.254: v1(174.5,13.79) 173.88,14.41 R2912.1
  BOTTOM w0.254: v1(174.5,13.79) 174.77,14.06 175.15,14.06 175.54,14.45 D2901.1 176.18,14.56 176.48,14.25 v2(176.54,14.25)
LINE1_VREFO_D2: length 6.6
  TOP w0.254: v1(172.08,12.29) 172.08,12.29 172,12.29 171.51,12.78 171.51,13.4 R2913.1
  BOTTOM w0.254: v1(172.08,12.29) 172.14,12.35 172.14,12.62 172.55,13.03 172.96,13.03 172.97,13.02 173.89,13.02 173.9,13.03 175.17,13.03 D2901.2 175.85,12.96 176.45,12.96 176.47,12.93 v2(176.54,12.93)
LOM_TCT:
  vias: v1(29.77,176.14) v2(31.02,177.58)
LPSS_UART2_CTS#: length 19.1
  TOP w0.114: v1(145.18,88.65) 143.17,88.65 142.61,88.09 139.8,88.09 139.03,87.32 139.03,86.92 v2(138.86,86.26) 138.15,86.08 137.73,85.66 v1(137.57,85.66) ; R2046.2 151.45,88.53 150.78,87.86 150.78,86.78 v1(150.73,86.73)
  L3 w0.102: v1(150.73,86.73) 150.7,86.73 150.16,87.27 146.59,87.27 146.22,87.64 146.19,87.64 v1(145.18,88.65)
  BOTTOM w0.114: v1(137.57,85.66) 137.57,85.11 CPU1.AD4
M_A_A0: length 50.8
  L4 w0.089: 111.15,65.72 110.78,66.09 110.78,71 v1(111.31,71.53)
  L4 w0.254: 111.15,65.72 111.15,58.05 99.83,46.74 99.83,42.53 99.5,42.2 99.5,41.56 100.31,40.75 100.31,38.13 101.18,36.25 101.18,35.24 102.33,34.08 v1(102.39,34.08)
  BOTTOM w0.089: CPU1.AY50 111.71,76.16 111.71,75.95 112.02,75.64 112.02,74.74 111.8,74.52 111.8,72.02 v1(111.31,71.53)
  BOTTOM w0.292: v1(102.39,34.08) 102.39,33.12 DM1.144
M_A_A1: length 50.1
  L4 w0.089: 110.64,65.83 110.6,65.87 110.6,71.37 111.18,71.96 111.2,72.14 110.91,72.62 110.17,72.62 110.04,72.49 110.04,72.31 109.56,71.83 109.56,71.51 110.05,71.02 v1(110.05,70.63)
  L4 w0.254: 110.64,65.83 110.64,58.41 98.94,46.71 98.94,41.4 99.78,40.57 v1(99.78,38.86)
  BOTTOM w0.089: CPU1.BB50 111.58,74.98 111.39,74.8 111.39,72.54 110.73,71.88 110.73,71.33 110.05,70.66 v1(110.05,70.63)
  BOTTOM w0.292: v1(99.78,38.86) 99.62,38.71 99.28,38.71 99.16,38.83 99.16,39.65 99.02,39.78 DM1.133
M_A_A2: length 53
  L4 w0.089: 110.04,66.45 110.24,66.65 110.24,68.43 v1(109.94,68.73)
  L4 w0.254: v1(99.75,34.57) 100.01,34.57 100.34,34.9 100.34,36.63 100.03,36.93 99.22,36.93 98.76,37.39 98.76,40.09 97.92,40.92 97.92,47.28 109.62,58.98 109.62,66.03 110.04,66.45
  BOTTOM w0.089: CPU1.AY51 111.21,76.35 111.3,76.24 111.3,75.61 111.35,75.42 111.35,75.19 111.29,75 111.16,74.87 111.16,72.6 110.53,71.98 110.53,71.41 110.16,71.04 109.91,71.04 109.54,70.67 109.54,69.13 v1(109.94,68.73)
  BOTTOM w0.292: DM1.132 98.77,33.97 99.37,34.57 v1(99.75,34.57)
M_A_A3: length 51.2
  L4 w0.089: v1(109.96,70) 110.42,69.55 110.42,66.24 110.13,65.95
  L4 w0.254: 110.13,65.95 110.13,58.77 98.43,47.07 98.43,41.14 99.27,40.3 99.27,37.62 99.4,37.49 v1(99.78,37.49)
  BOTTOM w0.089: CPU1.BA50 111.71,75.64 111.84,75.51 111.84,74.81 111.58,74.56 111.58,72.13 111.46,72 111.13,72 110.92,71.8 110.92,71.27 110.46,70.8 110.46,70.04 110.33,69.91 110.06,69.91 v1(109.96,70)
  BOTTOM w0.292: DM1.131 98.52,39.63 98.74,39.42 98.74,36.92 98.86,36.79 99.65,36.79 99.78,36.92 v1(99.78,37.49)
M_A_A4: length 51.1
  L4 w0.254: v1(97.71,33.99) 96.86,34.84 96.86,37.58 96.71,37.73 96.71,39.27 95.71,40.26 95.71,43.77 94.27,45.21 94.27,46.5 107.59,59.82 107.59,68.22 108.9,69.54 v1(108.93,69.54)
  BOTTOM w0.089: CPU1.BB52 110.25,72.9 108.93,71.58 108.93,70.77 108.55,70.39 108.55,69.67 108.67,69.54 v1(108.93,69.54)
  BOTTOM w0.292: v1(97.71,33.99) 97.71,33.97 97.77,33.91 DM1.128
M_A_A5: length 52.7
  L4 w0.254: v1(109.81,68.07) 109.81,66.78 109.11,66.08 109.11,59.19 97.42,47.49 97.42,40.71 98.25,39.88 98.25,37.14 99.14,36.25 99.14,35.49 99.02,35.36 v1(97.75,35.36)
  BOTTOM w0.089: CPU1.BA51 111.12,75.58 111.18,75.4 111.18,75.22 111.13,75.09 110.95,74.91 110.95,72.65 110.36,72.05 110.36,71.48 110.16,71.29 109.49,71.29 109.37,71.16 109.37,68.2 109.49,68.07 v1(109.81,68.07)
  BOTTOM w0.292: DM1.126 97.27,33.66 97.18,33.76 97.18,35.23 97.31,35.36 v1(97.75,35.36)
M_A_A6: length 51.8
  L4 w0.089: 109.42,67.13 109.42,68.29 109.29,68.42 109.11,68.42 v1(108.96,68.27)
  L4 w0.254: 109.42,67.13 109.29,67.01 108.8,67.01 108.61,66.82 108.61,59.4 95.28,46.08 95.28,45.73 95.65,45.37 96.53,45.37 96.83,45.06 96.83,40.58 97.72,39.69 v1(97.72,38.79)
  BOTTOM w0.089: CPU1.BA52 109.99,75.64 109.85,75.49 109.85,74.82 110.02,74.65 110.02,74.35 109.85,74.18 109.85,73.88 110.02,73.71 110.02,73.41 109.85,73.24 109.85,72.8 108.71,71.66 108.71,70.81 108.22,70.32 108.22,70.31 108.07,70.17 108.07,69.99 108.36,69.7 108.36,69.47 108.07,69.18 108.07,68.98 108.17,68.88 108.43,68.88 108.52,68.79 108.52,68.5 108.43,68.41 108.17,68.41 108.07,68.31 108.07,68.13 108.3,67.91 108.65,67.91 108.96,68.21 v1(108.96,68.27)
  BOTTOM w0.292: DM1.127 97.52,39.61 97.37,39.46 97.23,39.46 97.02,39.24 97.02,38.74 97.2,38.56 97.38,38.56 97.5,38.68 97.61,38.68 v1(97.72,38.79)
M_A_A7: length 53.8
  L4 w0.089: v1(108.93,70.2) 107.49,68.76 106.93,68.76 106.47,68.3 106.47,66.48 106.06,66.07
  L4 w0.254: v1(95.82,35.41) 95.18,36.04 95.18,38.64 94.08,39.74 94.08,42.97 92.74,44.3 92.74,47.13 106.06,60.45 106.06,66.07
  BOTTOM w0.089: CPU1.AW52 110.64,76.65 110.64,76.18 110.53,75.86 110.53,72.94 109.16,71.56 109.16,70.33 109.03,70.2 v1(108.93,70.2)
  BOTTOM w0.292: v1(95.82,35.41) 96.3,34.92 96.3,33.74 96.28,33.72 DM1.122
M_A_A8: length 53
  L4 w0.254: v1(108.96,67.63) 108.22,67.63 108.1,67.51 108.1,59.61 94.77,46.29 94.77,45.52 96.25,44.05 96.25,40.45 97.21,39.48 97.21,37.94 97.69,37.47 v1(97.75,37.47)
  BOTTOM w0.089: CPU1.AY52 110.35,76.25 109.67,75.57 109.67,72.87 108.5,71.7 108.5,70.85 108.04,70.39 108.04,70.39 107.89,70.24 107.89,67.76 108.02,67.63 v1(108.96,67.63)
  BOTTOM w0.292: v1(97.75,37.47) 96.69,37.47 96.55,37.6 96.55,39.42 96.68,39.55 96.73,39.55 97.02,39.85 DM1.125
M_A_A9: length 50.4
  L4 w0.089: v1(107.04,68.33) 106.64,67.93 106.64,67.28 106.64,65.91 106.57,65.84
  L4 w0.254: v1(95.77,37.19) 95.69,37.26 95.69,38.85 94.62,39.92 94.62,43.28 93.25,44.65 93.25,46.92 106.57,60.24 106.57,65.84
  BOTTOM w0.089: v1(107.04,68.33) 106.51,68.33 106.38,68.46 106.38,68.65 106.51,68.78 107.36,68.78 107.54,68.96 107.54,70.09 107.54,70.24 107.54,70.24 107.54,70.38 107.68,70.53 107.68,70.54 108.04,70.9 108.04,71.76 109.22,72.94 CPU1.BB54
  BOTTOM w0.292: DM1.121 96.02,37.45 v1(95.77,37.19)
M_A_A10: length 53.1
  L4 w0.089: v1(112.06,78.44) 112.61,77.9 112.61,76.11 114.64,74.07 114.64,67.39 115.54,66.49
  L4 w0.254: v1(104.6,36.27) 104.6,44.97 115.69,56.06 115.69,66.34 115.54,66.49
  BOTTOM w0.292: DM1.146 104.27,33.22 104.03,33.47 104.03,35.64 104.05,35.66 104.05,35.86 104.05,35.86 104.05,35.93 104.36,36.24 104.57,36.24 v1(104.6,36.27) ; v1(112.06,78.44) 111.86,78.44 CPU1.AT50
M_A_A11: length 51.2
  L4 w0.254: v1(107.03,67.69) 107.08,67.64 107.08,60.03 93.76,46.71 93.76,44.88 95.18,43.46 95.18,40.07 96.2,39.06 96.2,37.52 96.32,37.39 96.32,34.44 95.85,33.96 v1(95.77,33.96)
  BOTTOM w0.089: v1(107.03,67.69) 107.71,68.38 107.71,70.16 107.71,70.31 107.86,70.46 107.86,70.46 108.28,70.88 108.28,71.75 109.48,72.95 109.48,75.51 109.36,75.64 CPU1.BA54
  BOTTOM w0.292: v1(95.77,33.96) DM1.120
M_A_A12: length 52.4
  L4 w0.089: v1(107.07,69.83) 106.84,69.83 106.29,69.27 106.29,66.79 105.55,66.05 105.55,65.64
  L4 w0.254: 105.55,65.64 105.55,60.66 92.23,47.34 92.23,44.07 92.98,43.32 92.98,42.89 92.23,42.14 92.23,41.89 92.49,41.63 93.28,41.63 93.4,41.51 93.4,38.05 93.53,37.92 94.2,37.92 v1(94.34,38.06)
  BOTTOM w0.089: CPU1.AW54 109.41,76.65 109.41,76.17 109.21,75.97 109.14,75.97 108.99,75.81 108.96,75.72 108.96,75.54 109,75.42 109,75.17 108.96,75.09 108.96,74.68 109.02,74.62 109.02,73 107.83,71.81 107.83,70.94 107.51,70.61 107.51,70.61 107.07,70.17 v1(107.07,69.83)
  BOTTOM w0.292: DM1.119 95.52,38.78 94.84,38.09 94.38,38.09 94.36,38.06 v1(94.34,38.06)
M_A_A13: length 55.1
  L4 w0.089: v1(114.12,77.57) 114.54,77.14 114.81,77.14 114.94,77.01 114.94,75.95 116.19,74.7 116.19,68.05 118.23,66.01 118.23,65.71
  L4 w0.254: 118.23,65.71 118.23,53.78 116.04,51.59 114.81,51.59 114.15,50.93 114.15,50.4 113.9,50.15 113.37,50.15 107.45,44.22 107.45,36.5 108.37,35.58 v1(108.47,35.58)
  BOTTOM w0.089: v1(114.12,77.57) 113.47,77.57 113.38,77.65 CPU1.AU46
  BOTTOM w0.292: v1(108.47,35.58) 107.57,35.58 107.27,35.29 DM1.158
M_A_A14: length 51.8
  L4 w0.089: v1(113.84,79.04) 113.9,78.97 114.1,78.97 114.23,79.1 114.23,79.82 114.1,79.95 113.68,79.95 113.04,79.3 113.04,77.04 113.62,76.46 113.62,75.9 113.93,75.59 114.19,75.59 114.32,75.46 114.32,75.2 114.63,74.89 114.9,74.89 115,74.8 115,67.97 116.71,66.25 116.71,66.17
  L4 w0.254: 116.71,66.17 116.71,55.64 105.77,44.7 v1(105.77,39.17)
  BOTTOM w0.089: v1(113.84,79.04) 113.72,79.15 113.53,79.15 113.38,79 CPU1.AT46
  BOTTOM w0.292: DM1.151 105.52,39.76 105.45,39.69 105.45,39.3 105.58,39.17 v1(105.77,39.17)
M_A_A15: length 53.6
  L4 w0.089: 115.05,66.38 114.45,66.97 114.45,73.95 112.4,76 112.4,77.42 v1(112.03,77.79)
  L4 w0.254: v1(104.58,35.64) 104.52,35.64 104.1,36.06 104.1,45.18 115.18,56.27 115.18,66.24 115.05,66.38
  BOTTOM w0.292: DM1.156 106.77,34.59 105.92,35.45 105.53,35.45 105.34,35.64 v1(104.58,35.64) ; CPU1.AU48 112.16,77.79 v1(112.03,77.79)
M_A_A16: length 53.2
  L4 w0.089: v1(111.08,78.5) 111.42,77.9 111.42,76.43 111.94,75.38 113.15,73.17 113.45,70.31 114,66.88 114,66.3
  L4 w0.254: 114,66.3 114.17,66.13 114.17,56.69 103.08,45.6 103.08,42.67 103.59,41.91 103.59,35.85 104.31,35.13 104.76,35.13 105.6,34.29 v1(105.67,34.29)
  BOTTOM w0.292: DM1.152 105.77,33.44 v1(105.67,34.29) ; CPU1.AU50 v1(111.08,78.5)
M_A_ACT_N: length 52.9
  L4 w0.089: v1(105.36,68.36) 105.36,67.41 103.46,65.51 103.46,65.23
  L4 w0.254: 103.46,65.23 103.46,61.57 90.09,48.2 90.09,38.07 92.07,36.1 v1(92.16,36.1)
  BOTTOM w0.089: CPU1.BA55 108.32,75.49 108.3,75.39 108.3,75.22 108.34,75.09 108.34,73.28 106.29,71.23 106.29,69.7 105.76,68.76 v1(105.36,68.36)
  BOTTOM w0.292: DM1.114 94.27,34.32 92.74,35.86 v1(92.16,36.1)
M_A_ALERT_N: length 63.3
  L4 w0.089: 105.04,65.41 105.04,65.85 106.11,66.91 106.11,69.42 107,70.31 107.21,70.31 108.83,71.93 108.83,80.02 109.67,80.86 109.67,81.1 110.04,81.47 110.39,81.47 110.64,81.22 110.64,78.16 v1(111.04,77.76)
  L4 w0.254: 105.04,65.41 105.04,60.99 91.73,47.67 91.73,41.61 92.79,40.54 92.79,36.98 94.28,35.49 v1(94.34,35.49)
  BOTTOM w0.292: CPU1.AW50 111.52,77.28 v1(111.04,77.76) ; v1(94.34,35.49) 94.77,35.05 DM1.116
M_A_BA0: length 53
  L4 w0.089: v1(110.21,77.68) 110.95,76.94 110.95,75.76 111.84,74.88 112.95,73.03 113.02,71.46
  L4 w0.254: v1(104.56,34.59) 104.05,34.59 103.08,35.56 103.08,41.73 102.57,42.24 102.57,45.81 113.66,56.9 113.66,66.76 113.48,68.23 113.02,71.46
  BOTTOM w0.292: DM1.150 105.27,33.46 105.13,33.6 105.13,34.35 104.9,34.58 104.56,34.58 v1(104.56,34.59) ; CPU1.AU52 v1(110.21,77.68)
M_A_BA1: length 55.2
  L4 w0.089: v1(112.07,79.08) 112.66,79.08 112.78,78.95 112.78,76.24 114.82,74.21 114.82,67.7 116.06,66.45
  L4 w0.254: v1(105.75,36.61) 105.66,36.61 105.24,37.04 105.24,44.89 116.2,55.85 116.2,66.31 116.06,66.45
  BOTTOM w0.292: DM1.145 104.02,37.43 104.65,36.8 105.44,36.8 105.53,36.72 105.64,36.72 v1(105.75,36.61) ; CPU1.AT48 112.14,79.08 v1(112.07,79.08)
M_A_BG0: length 53.4
  L4 w0.089: v1(105.36,69) 105.75,68.61 105.75,67.32 104.03,65.59 104.03,65.23
  L4 w0.254: v1(92.12,36.81) 92.08,36.81 91.11,37.78 91.11,39.25 90.71,39.64 90.71,48.09 104.03,61.41 104.03,65.23
  BOTTOM w0.089: CPU1.AY55 108.17,76.32 108.17,75.61 108.12,75.41 108.12,75.2 108.16,75.07 108.16,73.35 106.08,71.28 106.08,69.72 v1(105.36,69)
  BOTTOM w0.292: DM1.115 94.52,39.63 93.76,38.87 93.76,37.74 92.82,36.81 v1(92.12,36.81)
M_A_BG1: length 52.9
  L4 w0.089: 104.53,65.41 104.53,65.82 105.93,67.22 105.93,71.28 106.06,71.41 106.46,71.41 106.59,71.28 106.59,70.89 106.71,70.77 v1(107.12,70.77)
  L4 w0.254: v1(92.12,38.1) 91.61,38.61 91.61,39.46 92.11,39.96 92.11,40.46 91.22,41.35 91.22,47.88 104.53,61.2 104.53,65.41
  BOTTOM w0.089: v1(107.12,70.77) 107.35,70.77 107.63,71.04 107.63,71.84 107.63,71.84 107.63,71.94 108.85,73.16 108.85,74.47 108.79,74.53 108.79,75.13 108.82,75.21 108.82,75.39 108.79,75.52 108.79,75.74 108.82,75.88 108.82,76.16 108.95,76.29 CPU1.AY54
  BOTTOM w0.292: DM1.113 94.02,39.72 93.33,39.03 93.33,37.95 93.16,37.77 92.74,37.77 92.41,38.1 v1(92.12,38.1)
M_A_CKE0: length 54.3
  L4 w0.089: 102.45,63.07 102.69,63.31 102.69,65.72 104.66,67.69 104.66,70.13 v1(105.44,70.91)
  L4 w0.254: 102.45,63.07 102.45,62.03 89.07,48.66 89.07,37.25 v1(90.63,35.69)
  BOTTOM w0.089: v1(105.44,70.91) 105.65,71.41 107.72,73.48 107.72,73.48 107.72,74.73 107.64,74.81 107.64,75.11 CPU1.BA56
  BOTTOM w0.292: DM1.109 93.02,39.83 92.7,39.02 92.36,38.69 91.96,38.69 91.6,38.34 v1(90.63,35.69)
M_A_CKE1: length 51.6
  L4 w0.089: v1(105.44,70.28) 104.93,69.77 104.93,67.47 103.03,65.57 103.03,62.97 102.95,62.89
  L4 w0.254: v1(92.16,34.75) 92.1,34.75 91.14,35.71 91.14,36.07 89.58,37.63 89.58,48.43 102.95,61.8 102.95,62.89
  BOTTOM w0.089: v1(105.44,70.28) 105.89,70.73 105.89,71.4 107.9,73.41 CPU1.BB56
  BOTTOM w0.292: v1(92.16,34.75) 93.27,33.63 DM1.110
M_A_CLK0: length 54.5
  L4 w0.089: v1(110.2,79.04) 109.79,78.46 109.79,78.1 109.57,77.88 109.57,77.36 109.94,76.99 110.21,76.99 110.29,76.91 110.32,76.86 110.32,76.34 110.29,76.32 110.29,76.31
  L4 w0.127: v1(102.39,37.7) 102.23,37.85 101.89,38.5 101.89,41.4 101.41,41.88 101.41,45.98 112.72,57.29 112.72,66.18 112.32,66.58 112.32,68.56 112.49,68.73 112.49,71.59 112.05,72.36 112.16,72.72 112.33,72.82 112.38,72.99 112.25,73.22 112.08,73.26 111.9,73.16 111.54,73.26 111.31,73.66 111.41,74.02 111.52,74.08 111.56,74.26 111.44,74.48 111.26,74.53 111.16,74.47 110.79,74.57 110.29,75.44 110.29,76.31
  BOTTOM w0.089: CPU1.AT53 v1(110.2,79.04)
  BOTTOM w0.178: DM1.137 100.02,39.32 100.54,38.81 100.54,38.32 101.16,37.7 v1(102.39,37.7)
M_A_CLK1: length 54.3
  L4 w0.089: 109.41,76.18 109.41,76.21 109.39,76.23 109.39,78.02 109.61,78.24 109.61,78.67 109.22,79.05 v1(109.22,79.06)
  L4 w0.127: v1(102.41,36.27) 102.02,36.66 101.25,38.33 101.25,41.14 100.77,41.62 100.77,46.33 112.09,57.65 112.09,65.2 112.08,65.25 111.99,66.47 111.99,66.48 111.98,66.55 111.98,71.7 109.41,75.89 109.41,76.18
  BOTTOM w0.089: v1(109.22,79.06) CPU1.AT55
  BOTTOM w0.178: v1(102.41,36.27) 102.09,36.21 101.75,36.21 101.31,35.77 101.28,35.74 100.27,33.93 DM1.138
M_A_CLK#0: length 54.6
  L4 w0.089: 110.54,76.31 110.54,76.32 110.51,76.34 110.51,76.92 110.44,77.03 110.29,77.18 110.02,77.18 109.76,77.44 109.76,77.8 109.98,78.02 109.98,78.3 110.05,78.38 v1(110.2,78.38)
  L4 w0.127: 110.54,76.31 110.54,75.5 110.95,74.77 111.13,74.73 111.23,74.79 111.6,74.69 111.82,74.29 111.72,73.92 111.62,73.86 111.57,73.69 111.7,73.47 111.87,73.42 112.05,73.52 112.41,73.42 112.64,73.03 112.54,72.66 112.36,72.56 112.31,72.39 112.73,71.66 112.73,68.63 112.57,68.46 112.57,66.68 112.96,66.28 112.96,57.19 101.65,45.88 101.65,41.98 102.13,41.5 102.13,38.59 102.26,38.47 v1(102.43,38.47)
  BOTTOM w0.089: v1(110.2,78.38) 110.07,78.51 109.89,78.51 109.72,78.35 CPU1.AU53
  BOTTOM w0.178: DM1.139 100.52,39.89 100.33,39.69 100.33,39.45 100.84,38.93 100.84,38.45 101.29,38 101.61,38 101.77,38.17 101.77,39 101.91,39.14 102.29,39.14 102.43,39.01 v1(102.43,38.47)
M_A_CLK#1: length 54.3
  L4 w0.089: 109.17,76.18 109.17,76.21 109.2,76.23 109.2,78.1 109.29,78.19 109.29,78.34 v1(109.22,78.4)
  L4 w0.127: 109.17,76.18 109.17,75.83 111.74,71.63 111.74,66.54 111.75,66.45 111.84,65.23 111.84,57.75 100.53,46.43 100.53,41.52 101.01,41.04 101.01,38.28 101.82,36.52 101.96,36.38 101.96,35.77 102.17,35.56 v1(102.41,35.56)
  BOTTOM w0.089: CPU1.AU55 108.81,78.29 108.93,78.4 v1(109.22,78.4)
  BOTTOM w0.178: v1(102.41,35.56) 102.07,35.9 101.88,35.9 101.52,35.55 100.58,33.85 100.58,33.62 100.77,33.42 DM1.140
M_A_CS#0: length 56.5
  L4 w0.089: 117.22,65.86 117.22,66.18 115.33,68.06 115.33,68.26 115.42,68.35 115.73,68.35 115.81,68.43 115.81,68.67 115.72,68.76 115.31,68.76 115.19,68.87 115.19,74.67 115.36,74.84 115.36,74.97 115.1,75.23 114.99,75.23 114.83,75.07 114.7,75.07 114.5,75.27 114.5,75.4 114.65,75.56 114.65,75.68 114.41,75.92 114.28,75.92 114.13,75.77 114,75.77 113.8,75.98 113.8,76.1 113.95,76.26 113.95,76.38 113.24,77.09 113.24,77.29 113.55,77.6 113.55,77.93 113.24,78.23 113.24,78.52 113.37,78.65 113.72,78.65 113.84,78.54 v1(113.84,78.38)
  L4 w0.254: 117.22,65.86 117.22,54.56 116.96,54.31 116.09,54.31 115.83,54.04 115.83,52.86 115.58,52.6 114.39,52.6 106.43,44.65 106.43,38.01 106.31,37.88 v1(105.76,37.88)
  BOTTOM w0.089: CPU1.AU45 114.14,77.95 113.86,77.95 113.73,78.08 113.73,78.27 v1(113.84,78.38)
  BOTTOM w0.292: DM1.149 105.02,39.76 104.95,39.69 104.95,38.01 105.19,37.77 105.65,37.77 v1(105.76,37.88)
M_A_CS#1: length 58.6
  L4 w0.089: 118.74,65.64 118.74,65.93 116.42,68.26 116.42,74.78 115.15,76.05 115.15,77.09 114.73,77.51 v1(114.73,77.79)
  L4 w0.254: 118.74,65.64 118.74,53.13 117.94,52.33 117.5,52.33 117.04,51.86 117.04,51.42 116.24,50.62 115.84,50.62 115.38,51.08 115.02,51.08 114.66,50.72 114.66,50.36 115.08,49.95 115.08,49.67 114.64,49.23 114.35,49.23 113.94,49.64 113.59,49.64 113.14,49.2 113.14,48.87 113.48,48.53 113.48,48.25 113.09,47.86 112.8,47.86 112.53,48.14 112.08,48.14 107.96,44.01 107.96,43.54 108.34,43.16 108.34,42.85 107.96,42.47 107.96,42.09 108.34,41.71 108.34,41.23 107.96,40.85 107.96,37.16 108.21,36.91 v1(108.49,36.91)
  BOTTOM w0.089: CPU1.AU43 115.03,78.1 v1(114.73,77.79)
  BOTTOM w0.292: v1(108.49,36.91) 108.33,36.91 107.94,36.52 107.51,36.52 107.22,36.81 107.22,39.68 107.15,39.75 107.15,39.75 107.02,39.87 DM1.157
M_A_DIMA_ODT0: length 57.1
  L4 w0.089: v1(114.7,78.43) 114.25,77.98 113.98,77.98 113.73,77.73 113.73,77.39 114.14,76.98 114.14,76.44 116,74.58 116,67.81 117.72,66.08 117.72,65.81
  L4 w0.254: v1(105.75,35.98) 106.02,35.7 106.66,35.7 106.94,35.98 106.94,44.44 114.6,52.1 115.83,52.1 117.72,53.99 117.72,65.81
  BOTTOM w0.089: CPU1.AT45 114.38,78.75 v1(114.7,78.43)
  BOTTOM w0.292: v1(105.75,35.98) 105.86,35.98 106.73,36.85 106.73,39.57 106.52,39.78 DM1.155
M_A_DIMA_ODT1: length 58.5
  L4 w0.089: v1(115.72,79.09) 115.72,79.26 115.64,79.34 115.23,79.34 115.14,79.25 115.14,78.75 115.23,78.66 115.55,78.66 115.7,78.51 115.7,78.31 115.55,78.16 115.37,78.16 115.13,77.91 115.13,77.53 115.68,76.98 115.68,76.25 116.59,75.34 116.59,73.1 116.77,72.93 116.77,71.83 116.87,71.73 116.87,68.23 119.25,65.85 119.25,65.62
  L4 w0.254: v1(108.54,38.31) 108.47,38.38 108.47,40.47 108.85,40.86 108.85,44.05 109.13,44.33 109.42,44.33 109.89,43.85 110.23,43.85 110.59,44.21 110.59,44.6 110.13,45.05 110.13,45.41 110.49,45.77 110.85,45.77 111.33,45.29 111.79,45.29 112.1,45.6 112.1,45.96 111.57,46.49 111.57,46.85 111.93,47.21 112.29,47.21 112.74,46.75 113.15,46.75 119.25,52.85 119.25,65.62
  BOTTOM w0.089: v1(115.72,79.09) 115.72,78.47 115.63,78.39 115.3,78.39 115.21,78.47 CPU1.AT43
  BOTTOM w0.292: DM1.161 108.02,39.87 107.64,39.49 107.64,38.49 107.82,38.31 v1(108.54,38.31)
M_A_DQ0: length 69.3
  L4 w0.165: v1(66.65,35.59) 67.12,36.05 67.12,44.43 68.49,45.81 68.49,52.78 80.29,64.58 80.29,65.47 84.39,69.57 84.39,75.58 91.1,82.3 95.33,82.3 95.87,82.12 v1(96.48,81.51)
  BOTTOM w0.089: CPU1.AL71 98.98,82.02 96.73,82.02 96.48,81.76 v1(96.48,81.51)
  BOTTOM w0.191: DM1.8 67.77,34.57 66.76,35.59 v1(66.65,35.59)
M_A_DQ1: length 70.3
  L4 w0.165: v1(66.62,37.13) 66.6,37.13 66.13,37.6 65.79,38.67 65.79,39.38 66.51,46.2 66.52,46.21 66.58,46.79 66.58,46.88 66.64,47.52 66.65,47.53 66.71,48.08 66.71,48.2 66.77,48.83 66.79,48.84 66.84,49.37 66.84,49.51 67.13,52.46 67.16,52.49 67.17,52.61 79.31,65.6 82.04,68.34 83.63,72.48 83.63,75.87 90.8,83.03 91.41,83.03 95.68,83.03 97.86,82.08 98.39,81.56 v1(98.46,81.45)
  BOTTOM w0.089: v1(98.46,81.45) 98.96,81.37 99.33,81.37 99.4,81.41 99.61,81.41 99.72,81.37 99.95,81.37 100.14,81.43 100.48,81.43 CPU1.AL68
  BOTTOM w0.191: v1(66.62,37.13) 66.9,37.37 67.1,37.57 67.1,39.03 67.52,39.45 DM1.7
M_A_DQ2: length 70
  L4 w0.165: v1(71.28,34.81) 71.26,34.81 70.2,35.87 70.2,44.48 70.7,44.97 70.7,51.74 86.68,67.73 86.68,74.56 89.88,77.76 91.72,77.76 94.6,80.64 96.35,80.64 96.55,80.44 96.55,79.6 96.68,79.47 97.5,79.47 97.65,79.63 97.65,80.06 97.79,80.19 98.51,80.19 98.99,79.71 99.57,79.71 100.34,80.48 v1(101.8,80.48)
  BOTTOM w0.191: DM1.20 70.77,34.45 71.14,34.81 v1(71.28,34.81) ; CPU1.AN68 101.7,80.58 v1(101.8,80.48)
M_A_DQ3: length 69.7
  L4 w0.165: v1(95.38,79.81) 94.89,79.81 93.54,78.46 93.54,76 93.41,75.87 92.81,75.87 92.63,76.05 92.63,76.59 92.5,76.72 89.88,76.72 88.01,74.85 88.01,72.95 90.23,70.72 90.23,70.24 89.97,69.98 89.74,69.98 88.88,70.84 88.7,70.84 88.41,70.55 88.41,70.37 89.27,69.51 89.27,69.28 89.04,69.04 88.8,69.04 87.95,69.89 87.77,69.89 87.49,69.6 87.49,69.42 88.33,68.58 88.33,68.34 71.74,51.74 71.74,44.7 71.03,44 v1(71.03,39.04)
  BOTTOM w0.089: CPU1.AN69 100.4,80.58 99.82,80.01 98.92,80.01 98.88,80.05 97.77,80.05 97.64,79.92 97.64,79.52 97.58,79.46 95.58,79.46 95.38,79.66 v1(95.38,79.81)
  BOTTOM w0.191: v1(71.03,39.04) 71.02,39.05 71.02,39.13 70.98,39.17 70.98,40.08 71.02,40.12 DM1.21
M_A_DQ4: length 69.9
  L4 w0.165: v1(95.24,81.63) 94.94,81.93 91.26,81.93 84.76,75.43 84.76,69.42 82.03,66.69 82.03,65.79 68.86,52.62 68.86,45.65 67.49,44.28 67.49,37.1 68.35,36.24 68.35,35.16 67.36,34.17 v1(66.65,34.17)
  BOTTOM w0.089: v1(95.24,81.63) 95.95,81.63 96.52,82.2 99.45,82.2 CPU1.AL70
  BOTTOM w0.191: DM1.4 66.77,34.05 v1(66.65,34.17)
M_A_DQ5: length 70.6
  L4 w0.165: v1(66.62,38.4) 66.6,38.4 66.16,38.84 66.16,39.36 66.86,46.01 67.04,46.16 67.46,46.12 67.6,46.23 67.64,46.64 67.53,46.78 67.11,46.82 66.96,47 66.99,47.33 67.17,47.48 67.56,47.44 67.7,47.55 67.74,47.96 67.63,48.1 67.24,48.13 67.09,48.31 67.12,48.64 67.3,48.79 67.79,48.74 67.97,48.89 68,49.22 67.86,49.4 67.37,49.45 67.22,49.63 67.49,52.29 79.92,64.73 79.92,65.62 84.02,69.72 84.02,75.74 90.95,82.67 91.26,82.67 95.39,82.67 96.31,82.36 97.58,81.8 v1(97.82,81.47)
  BOTTOM w0.089: CPU1.AL69 100.28,81.6 100.11,81.6 99.92,81.55 99.74,81.55 99.64,81.58 99.36,81.58 99.29,81.55 99.03,81.55 98.74,81.84 98.2,81.84 97.83,81.47 v1(97.82,81.47)
  BOTTOM w0.191: DM1.3 66.52,39.84 66.4,39.71 66.4,39.67 66.12,39.39 66.12,38.77 66.48,38.4 v1(66.62,38.4)
M_A_DQ6: length 68.5
  L4 w0.165: v1(97.11,79.94) 97.29,80.11 97.29,80.88 97.16,81.01 96.99,81.01 96.99,81.01 94.45,81.01 91.67,78.23 89.82,78.23 86.29,74.69 86.29,67.86 70.29,51.86 70.29,45.09 69.83,44.63 69.83,34.64 69.7,34.51 69.19,34.51 v1(68.86,34.85)
  BOTTOM w0.089: v1(97.11,79.94) 97.4,80.23 98.96,80.23 99,80.18 99.54,80.18 CPU1.AN70
  BOTTOM w0.191: v1(68.86,34.85) 69,34.85 69.77,34.07 DM1.16
M_A_DQ7: length 67.7
  L4 w0.165: v1(71.03,37.13) 71.27,37.13 71.39,37 71.39,36.72 71.23,36.56 70.74,36.56 70.57,36.73 70.57,44.33 71.15,44.91 71.15,51.68 87.85,68.38 87.85,68.54 87.12,69.27 87.12,69.84 88.59,71.32 88.59,71.84 87.64,72.79 87.64,75 89.88,77.24 93.05,77.24 93.17,77.36 93.17,78.61 94.84,80.27 95.84,80.27 96.07,80.05 v1(96.07,79.91)
  BOTTOM w0.089: v1(96.07,79.91) 96.07,80.31 96.2,80.44 99.14,80.44 CPU1.AN71
  BOTTOM w0.191: v1(71.03,37.13) 70.73,37.13 70.02,37.83 DM1.17
M_A_DQ8: length 61.4
  L4 w0.165: v1(95.26,78.77) 95.26,73.49 73.3,51.54 73.3,43.52 73.17,43.4 72.46,43.4 72.31,43.24 72.31,37.27 72.44,37.14 v1(72.77,37.14)
  BOTTOM w0.089: CPU1.AR70 99.63,79.25 99.46,79.25 99.27,79.19 99.09,79.19 98.99,79.23 98.71,79.23 98.59,79.17 98.57,79.16 98.43,79.08 95.6,79.08 95.28,78.77 v1(95.26,78.77)
  BOTTOM w0.191: v1(72.77,37.14) 72.77,32.5 DM1.28
M_A_DQ9: length 61.8
  L4 w0.165: v1(100.8,79.93) 100.8,79.17 100.15,78.53 98.91,78.53 98.44,79 96.93,79 95.63,77.69 95.63,73.34 73.67,51.38 73.67,51.02 73.85,50.83 74.28,50.83 74.42,50.69 74.42,50.31 74.28,50.17 73.81,50.17 73.67,50.02 73.67,49.69 73.82,49.54 74.28,49.54 74.42,49.4 74.42,49.35 74.37,48.97 74.28,48.88 73.84,48.88 73.67,48.7 73.67,48.37 73.83,48.21 73.94,48.21 74.11,48.04 74.11,47.71 73.94,47.55 73.83,47.55 73.67,47.38 73.67,43.35 73.01,42.69 73.01,38.56 73.14,38.43 v1(73.39,38.43)
  BOTTOM w0.14: v1(100.8,79.93) 101.14,79.6 CPU1.AR68
  BOTTOM w0.191: v1(73.39,38.43) 73.35,38.43 73,38.78 73,39.4 73,39.4 73,39.82 73.02,39.85 DM1.29
M_A_DQ10: length 59.5
  L4 w0.165: v1(75.32,36.93) 75.52,36.73 75.91,36.73 76.04,36.86 76.12,38.28 76.12,39.49 76.56,39.93 76.56,51.11 99.31,73.86 99.31,76.7 99.19,76.82 97.69,76.82 v1(97.33,77.18)
  BOTTOM w0.089: v1(97.33,77.18) 97.33,76.98 97.45,76.86 97.65,76.86 97.78,76.98 97.78,77.45 98.05,77.72 98.59,77.72 99,78.13 CPU1.AU71
  BOTTOM w0.191: DM1.41 76.02,39.53 75.97,39.48 75.97,37.59 v1(75.32,36.93)
M_A_DQ11: length 61.9
  L4 w0.165: v1(75.32,35.54) 74.96,35.54 74.75,35.33 74.75,34.89 74.64,34.78 74.15,34.78 74.02,34.9 74.02,35.7 74.83,36.51 74.83,41.27 75.83,49.26 75.83,51.41 97.21,72.8 97.21,72.98 97.49,73.26 97.67,73.26 98.1,73.68 98.1,73.97 97.98,74.09 97.29,74.09 97.19,74.2 v1(97.19,74.6)
  BOTTOM w0.089: 99.51,76.15 99.51,76.52 100.04,77.05 100.35,77.05 100.36,77.04 100.69,77.04 101.14,77.48 CPU1.AU68
  BOTTOM w0.127: 99.51,76.15 99.51,75.88 99.41,75.78 98.9,75.78 98.18,75.06 97.64,75.06 v1(97.19,74.6)
  BOTTOM w0.191: v1(75.32,35.54) 75.52,35.54 76.26,34.8 76.26,33.75 76.27,33.73 DM1.42
M_A_DQ12: length 61
  L4 w0.165: v1(71.28,36.08) 71.89,36.7 71.89,43.41 72.93,44.45 72.93,51.69 94.28,73.04 v1(94.67,78.41)
  BOTTOM w0.089: CPU1.AR71 98.56,79.45 98.37,79.26 95.1,79.26 94.67,78.84 v1(94.67,78.41)
  BOTTOM w0.191: v1(71.28,36.08) 71.44,36.08 71.77,35.75 DM1.24
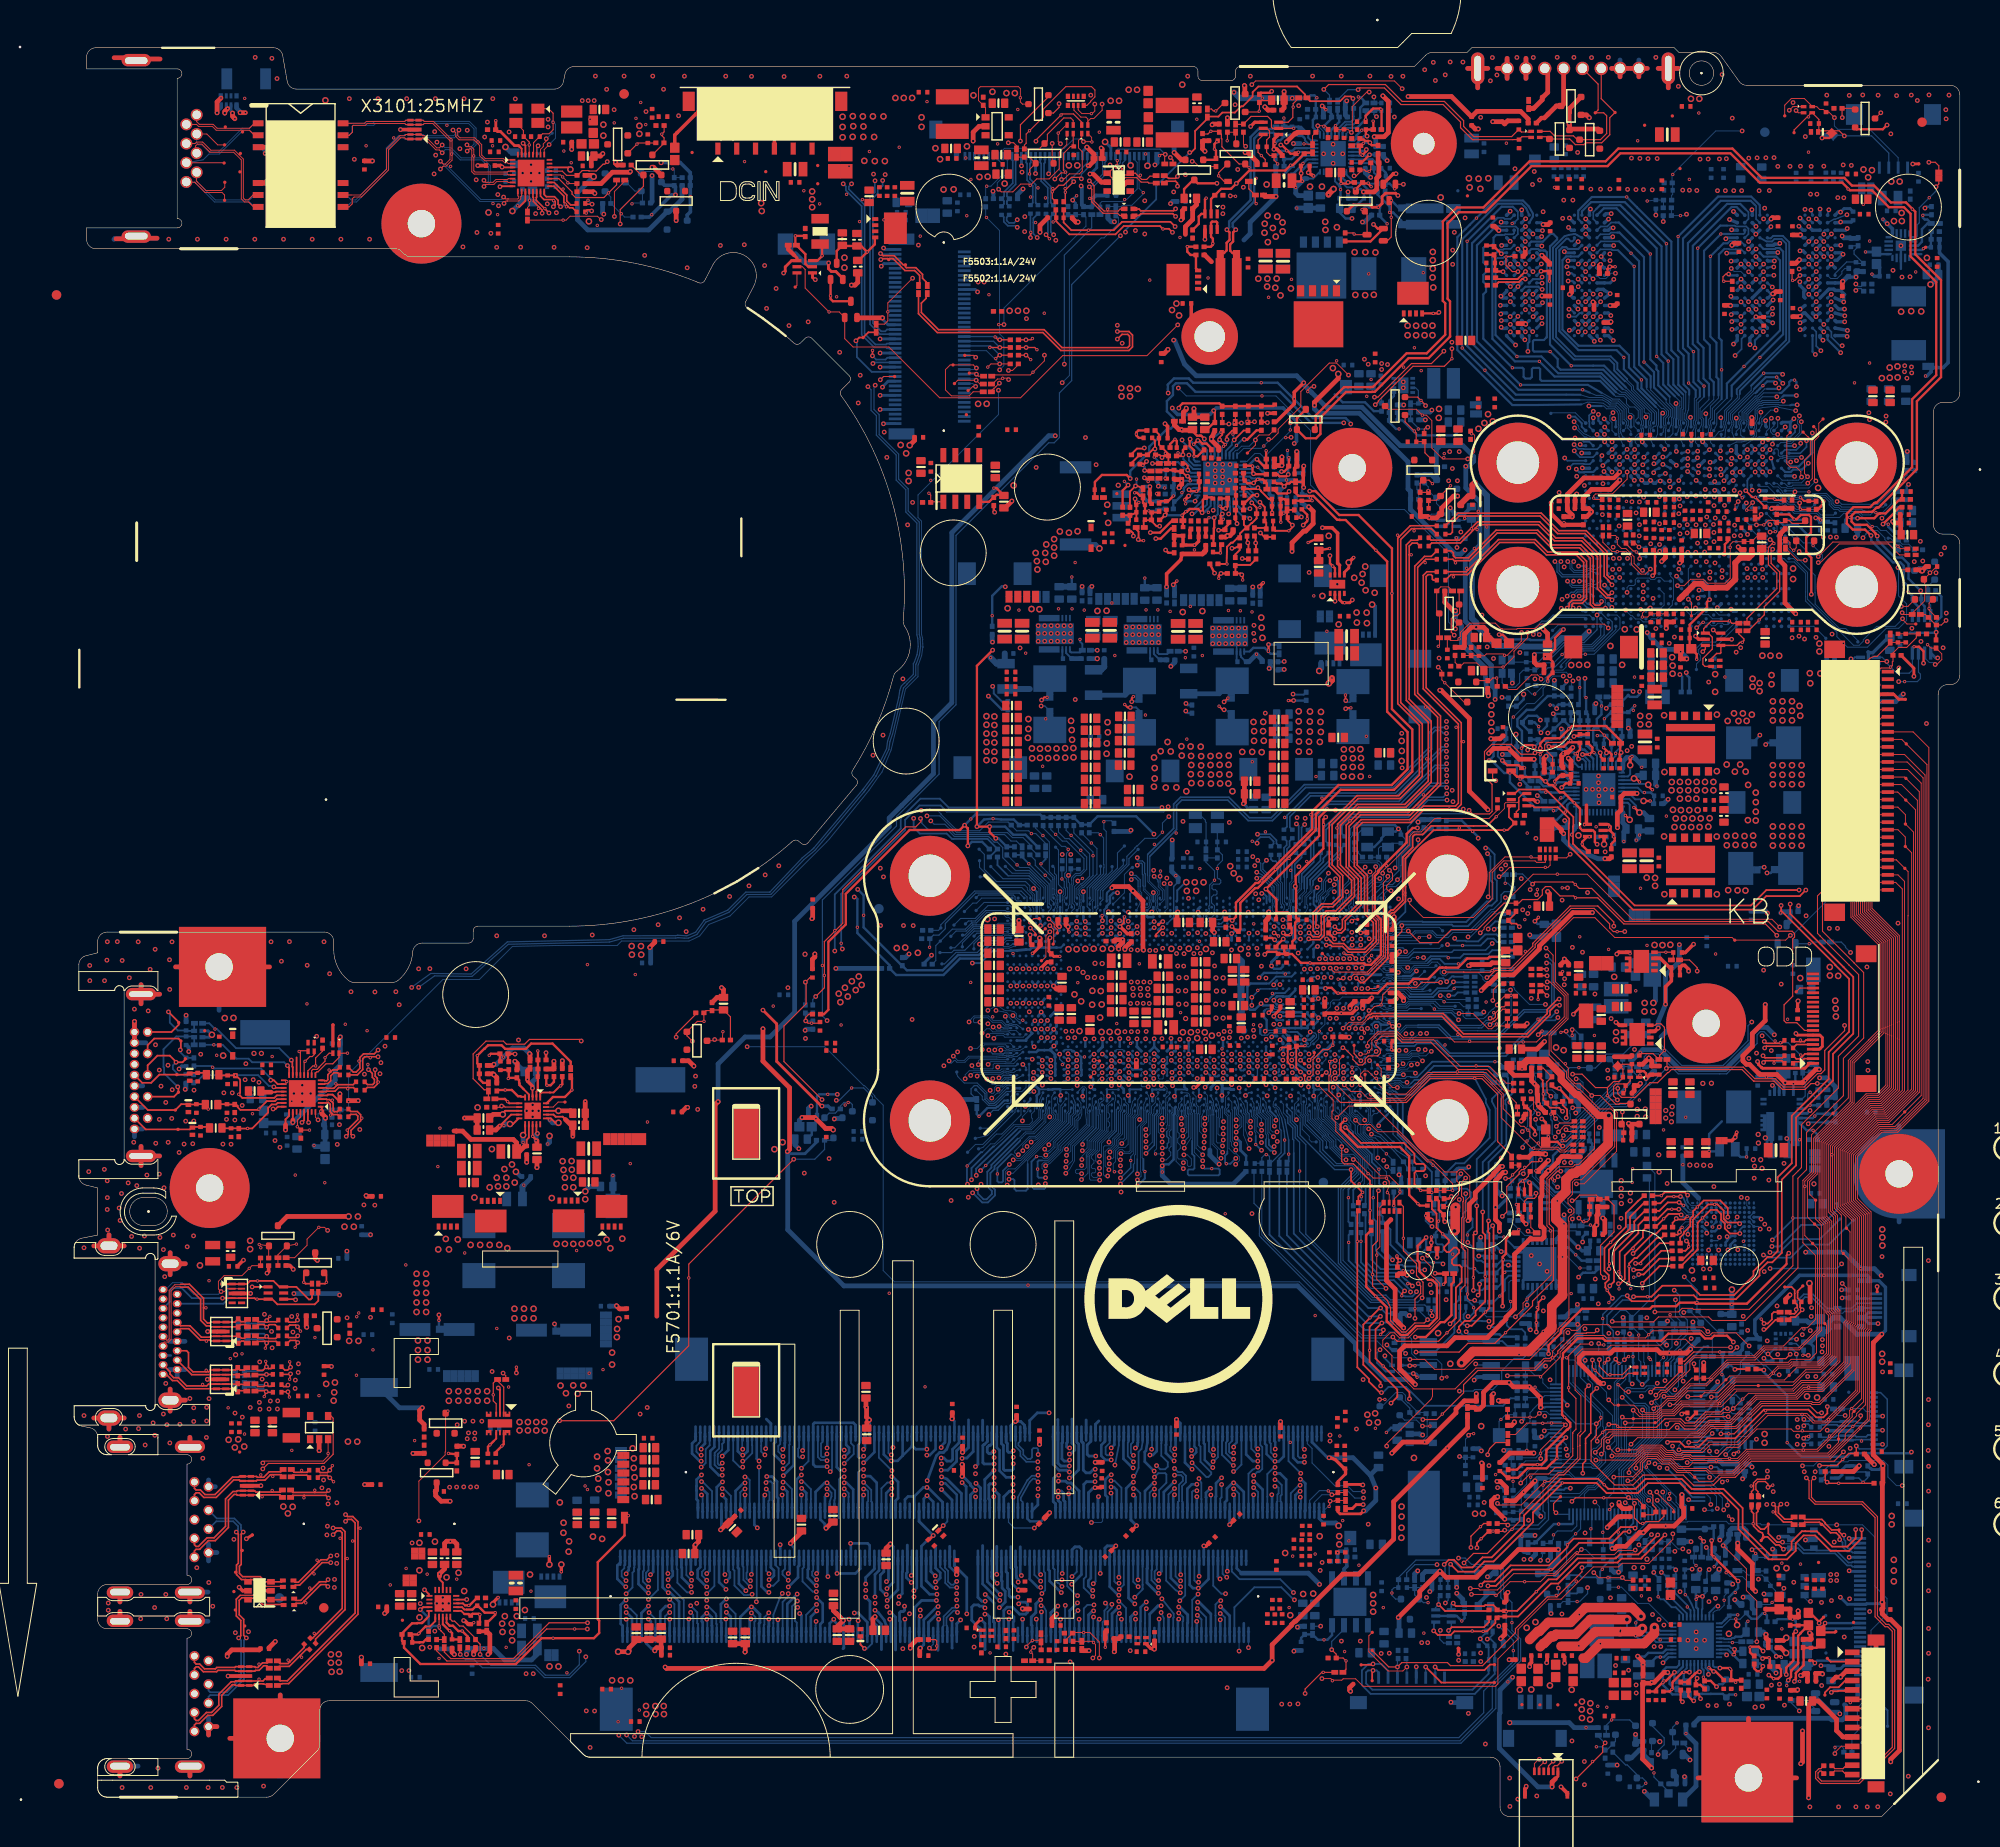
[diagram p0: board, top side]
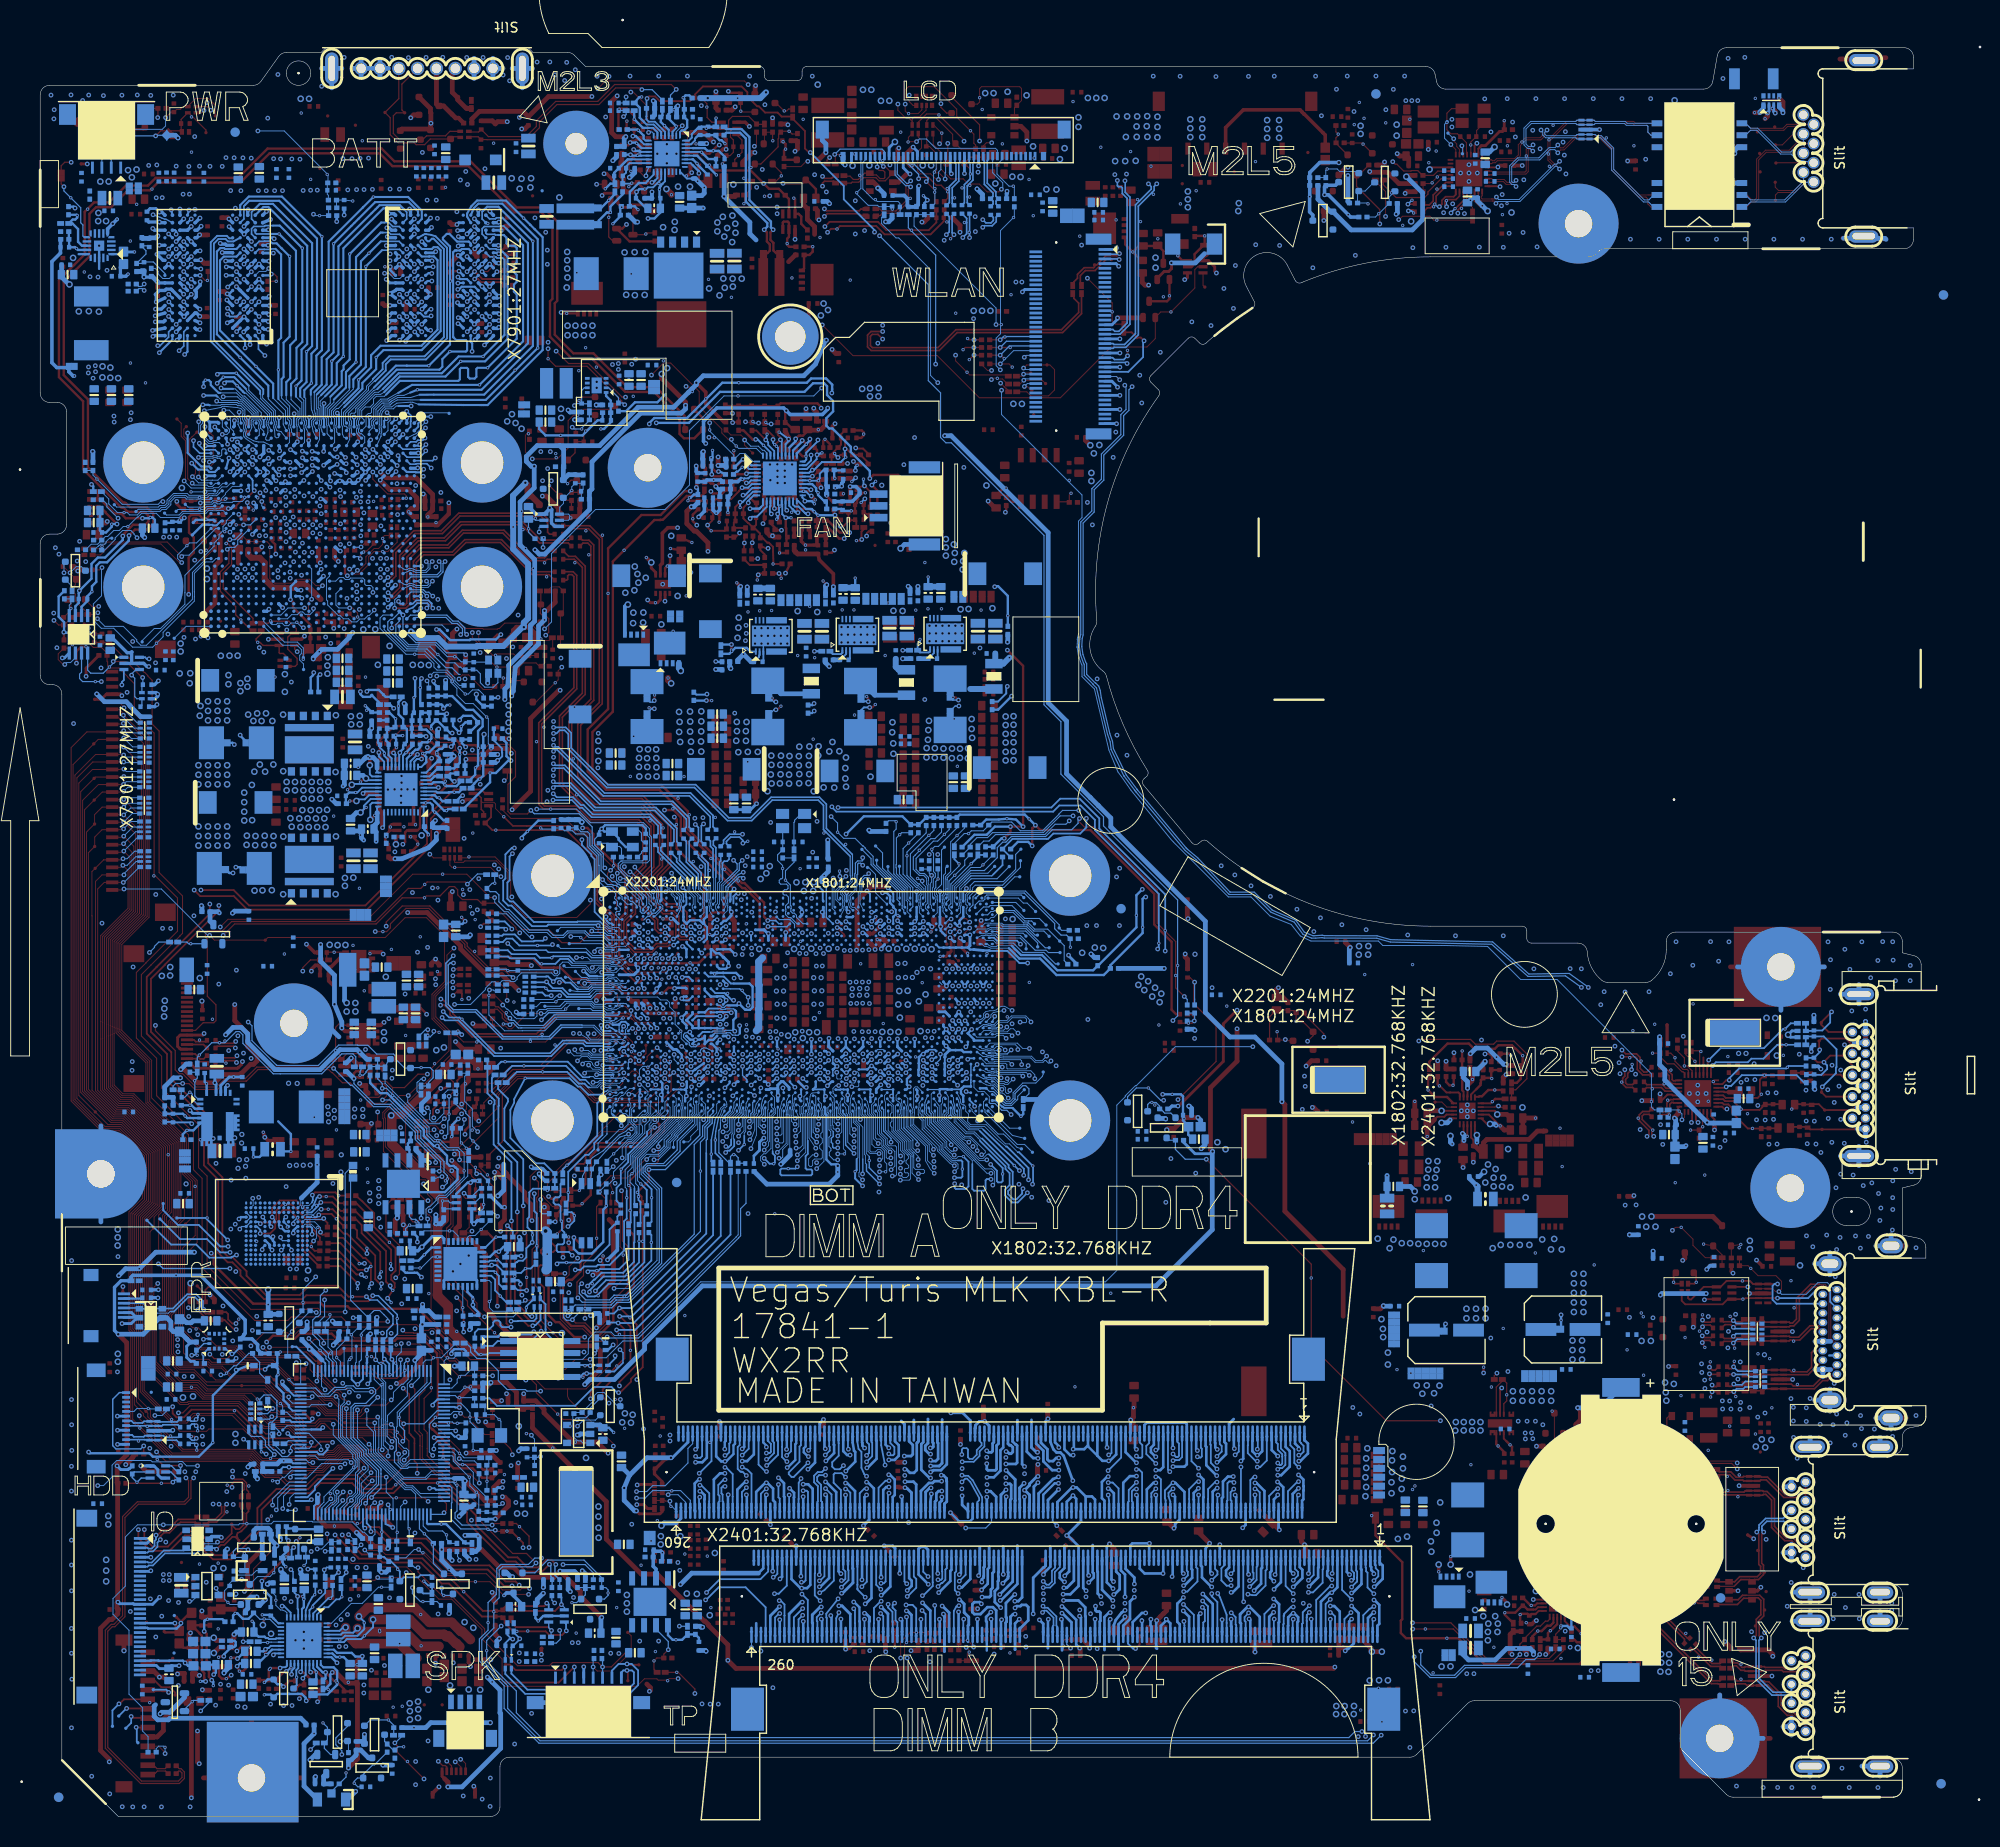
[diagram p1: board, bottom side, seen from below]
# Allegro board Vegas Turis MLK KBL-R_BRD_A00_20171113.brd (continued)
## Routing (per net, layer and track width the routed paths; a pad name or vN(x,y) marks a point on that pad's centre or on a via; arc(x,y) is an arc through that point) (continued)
M_A_DQ13: length 61.1
  L4 w0.165: v1(95.94,78.69) 95.94,79.1 95.82,79.23 94.84,79.23 93.91,78.31 93.91,73.19 72.56,51.84 72.56,44.62 71.51,43.56 71.51,38.22 71.06,37.77 v1(71.03,37.77)
  BOTTOM w0.089: v1(95.94,78.69) 95.97,78.69 96.17,78.89 98.49,78.89 98.68,79.02 98.75,79.05 98.96,79.05 99.06,79.02 99.3,79.02 99.49,79.07 99.83,79.07 100.12,79.29 CPU1.AR69
  BOTTOM w0.191: v1(71.03,37.77) 71.19,37.77 72.04,38.62 72.04,39.45 72.02,39.47 DM1.25
M_A_DQ14: length 60.1
  L4 w0.165: v1(75.21,34.17) 76.31,34.17 76.44,34.29 76.44,37.34 76.49,38.27 76.49,39.34 76.93,39.77 76.93,50.95 99.68,73.7 99.68,77.76 99.55,77.89 98.29,77.89 98.16,77.76 v1(98.16,77.29)
  BOTTOM w0.089: v1(98.16,77.29) 98.42,77.54 98.66,77.54 98.97,77.84 99.38,77.84 99.45,77.91 99.53,77.93 CPU1.AU70
  BOTTOM w0.191: DM1.38 75.27,34.11 v1(75.21,34.17)
M_A_DQ15: length 60.9
  L4 w0.165: v1(97.49,76.36) 97.3,76.18 97.27,75.8 97.27,75.54 97.4,75.41 98.08,75.41 98.23,75.57 98.71,75.57 98.94,75.33 98.94,74.01 76.19,51.26 76.19,49.23 75.69,45.22 75.84,45.03 75.99,45.01 76.13,44.83 76.09,44.5 75.9,44.36 75.76,44.38 75.57,44.23 75.53,43.91 75.67,43.72 76.02,43.68 76.17,43.49 76.13,43.16 75.94,43.02 75.59,43.06 75.41,42.92 75.37,42.6 75.57,42.33 76.02,42.28 76.16,42.09 76.12,41.77 75.94,41.62 75.38,41.69 75.24,41.58 75.2,41.25 75.2,40.91 75.32,40.78 76.04,40.78 76.17,40.66 76.17,40.29 76.03,40.15 75.37,40.15 75.2,39.98 75.2,39.58 75.3,39.48 75.63,39.48 75.76,39.35 75.76,38.41 75.63,38.28 v1(75.32,38.28)
  BOTTOM w0.089: CPU1.AU69 99.82,77.76 99.42,77.67 99.17,77.67 99.09,77.66 99.03,77.66 98.57,77.2 98.57,77.14 98.32,76.9 98.13,76.9 97.9,76.76 v1(97.49,76.36)
  BOTTOM w0.191: DM1.37 75.02,40.7 75.02,39.58 74.82,39.38 74.82,38.78 v1(75.32,38.28)
M_A_DQ16: length 54.3
  L4 w0.165: v1(77.27,35.59) 78.63,36.95 78.63,49.51 94.37,65.24 94.37,65.95 96.31,67.9 96.31,68.64 v1(96.31,68.65)
  BOTTOM w0.089: 100.51,72.86 100.64,72.98 101.69,72.98 102.86,74.16 102.86,74.91 CPU1.BB65
  BOTTOM w0.191: v1(77.27,35.59) 77.48,35.59 78.28,34.78 78.28,33.75 78.27,33.74 DM1.50 ; 96.85,69.19 100.51,72.86 ; 96.85,69.19 v1(96.31,68.65) ; 96.85,69.19 v2(96.85,69.19)
M_A_DQ17: length 56
  L4 w0.165: v1(94.91,67.2) 93.86,66.14 93.86,65.28 78.27,49.69 78.27,38 v1(77.27,37.01)
  BOTTOM w0.089: CPU1.AW65 102.59,76.21 102.59,76.04 102.55,75.9 102.51,75.78 102.4,75.67 102.3,75.64 102.23,75.64 102.2,75.62 102.17,75.62 102.02,75.46 102.02,74.97 101.73,74.68 101.73,74.26 101.8,74.18 101.8,73.85 101.48,73.52 99.83,73.52 97.79,71.49 97.37,71.49 96.48,70.6
  BOTTOM w0.191: v1(77.27,37.01) 78.02,37.76 DM1.49 ; v1(94.91,67.2) 94.86,67.25 94.86,69.12 v2(94.89,69.14) 96.34,70.6 96.48,70.6
M_A_DQ18: length 56.4
  L4 w0.165: v1(81.82,36.1) 81.68,35.96 81.36,35.96 81.23,36.08 81.23,49.07 81.34,49.18 97.57,65.41 97.57,68.35 99.55,70.34 v1(100.32,70.34)
  BOTTOM w0.089: CPU1.AW63 103.98,76.68 103.87,76.48 103.87,75.23 103.83,75.09 103.83,74.75 104.08,74.5 104.08,74.23 102.15,72.3 102.13,72.29 101.5,72.29 99.94,70.73 99.94,70.55 100.15,70.34 v1(100.32,70.34)
  BOTTOM w0.191: DM1.62 81.27,35.83 81.54,36.1 v1(81.82,36.1)
M_A_DQ19: length 55.9
  L4 w0.165: v1(81.82,38.94) 81.71,39.05 81.71,49.03 97.94,65.26 97.94,68.2 99.04,69.3 v1(99.37,69.3)
  BOTTOM w0.089: 99.55,70.39 99.73,70.39 100.17,69.94 100.55,69.94 104.63,74.03 104.63,75.66 104.48,75.86 104.48,76.34 104.36,76.46 104.23,76.46 104.17,76.4 CPU1.AY63
  BOTTOM w0.191: v1(99.37,69.3) 99.36,69.3 98.7,68.64 98.7,67.52 98.57,67.4 98.23,67.4 98.09,67.54 98.09,68.29 v2(98.1,68.29) 98.09,68.3 98.09,68.93 99.55,70.39 ; DM1.63 81.52,39.07 81.65,38.94 v1(81.82,38.94)
M_A_DQ20: length 55.4
  L4 w0.165: v1(95.85,68.15) 94.68,68.15 89.25,62.72 87.74,60.25 77.74,50.26 77.53,50.04 77.53,39.78 76.86,39.11 76.86,38.26 76.81,37.33 76.81,34.63 v1(77.27,34.17)
  BOTTOM w0.089: CPU1.BA65 102.7,75.14 102.68,75.07 102.68,74.22 101.62,73.16 100.3,73.16 100.15,73.01
  BOTTOM w0.191: v1(95.85,68.15) 95.83,68.17 95.83,68.85 96.24,69.26 100.15,73.01 ; v1(77.27,34.17) 77.27,34.16 DM1.46
M_A_DQ21: length 55.7
  L4 w0.165: v1(77.4,38.23) 77.77,38.23 77.9,38.36 77.9,49.89 89.72,61.71 89.72,61.95 89.51,62.15 89.51,62.38 89.75,62.62 89.98,62.62 90.19,62.41 90.42,62.41 90.65,62.65 90.65,62.88 90.45,63.09 90.45,63.32 90.68,63.55 90.91,63.55 91.12,63.35 91.35,63.35 91.59,63.58 91.59,63.81 91.38,64.02 91.38,64.25 91.62,64.49 91.85,64.49 92.05,64.28 92.29,64.28 92.62,64.61 92.62,65.56 94.72,67.67 v1(95.34,67.67)
  BOTTOM w0.089: 97.74,71.21 98.64,71.98 100.01,73.35 101.55,73.35 102.5,74.3 102.5,75.09 102.58,75.4 102.63,75.52 102.74,75.91 102.77,76.01 102.77,76.02 102.81,76.18 CPU1.AY65
  BOTTOM w0.191: DM1.45 77.02,39.19 76.92,39.09 76.92,38.27 77.05,38.14 77.32,38.14 v1(77.4,38.23) ; 97.74,71.21 97.65,71.21 97.32,70.9 95.34,68.91 v1(95.34,67.67)
M_A_DQ22: length 54.6
  L4 w0.165: v1(100.8,70.76) 100.45,70.8 99.81,70.8 99.36,70.67 97.19,68.5 97.19,66.42 96.72,65.09 80.98,49.34 80.98,49.34 80.82,49.18 80.82,35.64 80.22,35.04 v1(79.99,34.83)
  BOTTOM w0.089: v1(100.8,70.76) 100.8,71.34 101.57,72.11 102.17,72.11 102.25,72.16 104.25,74.15 104.25,74.57 104.01,74.82 104.01,75.07 104.07,75.33 CPU1.BA63
  BOTTOM w0.191: v1(79.99,34.83) 80.25,34.61 80.47,34.39 80.47,34.02 80.27,33.46 DM1.58
M_A_DQ23: length 53.6
  L4 w0.165: v1(101.68,71.67) 101.68,71.68 99.85,71.68 96.82,68.65 96.82,66.48 96.4,65.29 80.45,49.34 80.45,36.95 v1(80.33,36.65)
  BOTTOM w0.089: v1(101.68,71.67) 102.36,72.01 104.44,74.09 104.44,74.65 104.33,74.96 CPU1.BB63
  BOTTOM w0.191: DM1.59 80.52,36.86 80.33,36.67 v1(80.33,36.65)
M_A_DQ24: length 54.3
  L4 w0.165: v1(83.88,36.88) 83.15,36.88 83.02,37.01 83.02,39.45 82.82,39.65 82.82,48.57 99.14,64.89 v1(99.14,67.11)
  BOTTOM w0.089: v1(99.14,67.11) 98.93,67.31 98.93,68.51 99.25,68.83 99.98,68.83 100.96,69.81 100.96,69.85 105.01,73.9 105.01,75.35 CPU1.BA61
  BOTTOM w0.191: DM1.70 83.27,36.56 83.6,36.88 v1(83.88,36.88)
M_A_DQ25: length 55.8
  L4 w0.165: v1(99.33,67.73) 99.36,67.73 99.6,67.49 99.6,64.84 83.19,48.42 83.19,40.59 83.7,40.07 83.7,39.65 83.41,39.36 83.41,38.43 83.54,38.31 v1(83.88,38.31)
  BOTTOM w0.089: CPU1.AW61 105.57,76.91 105.68,76.77 105.68,74.98 105.56,74.85 105.56,74.83 105.46,74.74 105.46,73.85 101.31,69.71 101.31,69.35
  BOTTOM w0.191: DM1.71 83.52,39.75 83.25,39.48 83.25,38.23 83.35,38.12 83.69,38.12 v1(83.88,38.31) ; 101.31,69.35 101.31,66.7 101.13,66.51 100.09,66.51 99.91,66.7 99.91,67.62 99.78,67.74 99.35,67.74 v1(99.33,67.73)
M_A_DQ26: length 54
  L4 w0.165: v1(86.82,38.43) 86.62,38.43 86.5,38.56 86.5,41.25 86.11,41.64 86.11,41.98 86.5,42.37 86.5,42.73 86.33,42.9 86.22,42.9 86.06,43.06 86.06,43.39 86.22,43.56 86.33,43.56 86.5,43.72 86.5,44.05 86.33,44.22 86.22,44.22 86.06,44.38 86.06,44.71 86.22,44.88 86.33,44.88 86.5,45.04 86.5,45.37 86.33,45.54 86.22,45.54 86.06,45.7 86.06,46.03 86.22,46.2 86.33,46.2 86.5,46.36 86.5,46.69 86.33,46.86 86.22,46.86 86.06,47.02 86.06,47.35 86.22,47.52 86.33,47.52 86.5,47.68 86.5,48.17 102.14,63.82 102.14,66.44 102.34,66.63 102.63,66.63 103.19,67.19 v1(103.19,67.26)
  BOTTOM w0.089: CPU1.BB59 106.56,74.92 106.56,74.49 106.26,74.19 106.26,73.31 104.44,71.49 104.44,70.95 103.39,69.91 103.05,69.91 102.82,70.14 v2(102.26,70.14)
  BOTTOM w0.191: v2(102.26,70.14) 101.72,69.6 101.72,66.98 102,66.7 103.06,66.7 103.19,66.82 v1(103.19,67.26) ; v1(86.82,38.43) 86.72,38.43 86.52,38.63 DM1.83
M_A_DQ27: length 56.7
  L4 w0.165: v1(86.87,34.17) 85.36,35.68 85.36,40.75 84.95,41.16 84.95,48.19 101.01,64.25 101.01,67.48 102.59,69.05 v1(103.22,69.16)
  BOTTOM w0.089: CPU1.AW59 106.77,77.18 107.14,77.55 107.38,77.55 107.55,77.38 107.55,75.37 107.54,75.36 107.46,75.14 107.46,74.75 107.54,74.05 107.54,73.57 105.09,71.11 105,70.73 103.67,69.41 v1(103.22,69.16)
  BOTTOM w0.191: DM1.84 86.77,33.53 v1(86.87,34.17)
M_A_DQ28: length 53.2
  L4 w0.165: v1(99.33,68.36) 99.14,68.36 98.67,67.9 98.67,64.95 82.45,48.73 82.45,39.49 82.65,39.29 82.65,35.19 82.28,34.83 v1(81.82,34.83)
  BOTTOM w0.089: v1(99.33,68.36) 99.76,68.36 101.14,69.74 101.14,69.78 105.27,73.91 105.27,74.96 CPU1.BB61
  BOTTOM w0.191: DM1.66 82.27,33.95 82.29,33.97 82.29,34.36 81.83,34.83 v1(81.82,34.83)
M_A_DQ29: length 54.8
  L4 w0.165: v1(99.78,69.79) 99.85,69.87 100.41,69.87 100.53,69.74 100.53,69.38 99.98,68.83 99.09,68.83 98.31,68.05 98.31,65.1 82.08,48.88 82.08,39.33 82.28,39.13 82.28,37.65 82.15,37.52 v1(81.82,37.52)
  BOTTOM w0.089: CPU1.AY61 104.91,75.62 104.83,75.54 104.83,73.98 100.56,69.71 99.86,69.71 99.78,69.79 v1(99.78,69.79)
  BOTTOM w0.191: v1(81.82,37.52) 82.23,37.93 82.24,37.93 82.83,38.52 82.83,39.38 82.52,39.68 DM1.67
M_A_DQ30: length 55.6
  L4 w0.165: v1(103.21,67.89) 103.21,67.89 102.52,67.89 101.75,67.12 101.75,63.95 101.72,63.92 85.69,47.89 85.69,41.46 86.13,41.02 86.13,36.6 86.26,36.47 86.5,36.47 86.78,36.76 v1(86.89,36.76)
  BOTTOM w0.089: CPU1.BA59 106.63,75.64 106.69,75.59 106.88,75.08 106.88,74.77 106.74,74.63 106.74,74.3 106.45,74.01 106.45,73.18 104.63,71.35 104.63,70.89 103.46,69.73 102.86,69.73
  BOTTOM w0.191: DM1.79 85.5,40.68 85.5,38.14 v1(86.89,36.76) ; v1(103.21,67.89) 102.49,67.89 102.37,68.02 v2(102.37,68.81) 102.37,69.6 102.49,69.73 102.86,69.73
M_A_DQ31: length 55.6
  L4 w0.165: v1(86.87,35.49) 86.11,35.49 85.73,35.87 85.73,40.91 85.32,41.31 85.32,48.04 101.38,64.1 101.38,67.28 102.62,68.52 103.16,68.52 103.16,68.53 v1(103.2,68.53)
  BOTTOM w0.089: CPU1.AY59 106.93,75.88 106.97,75.79 106.97,75.39 107.06,75.11 107.06,74.62 107.04,74.58 106.91,74.21 106.65,73.95 106.65,73.05 104.84,71.24 104.84,70.85 103.54,69.55 103.06,69.55 102.83,69.32 102.83,68.89 v1(103.2,68.53)
  BOTTOM w0.191: v1(86.87,35.49) 86.39,35.49 85.77,34.87 DM1.80
M_A_DQ32: length 50.7
  L4 w0.089: 120.6,65.06 120.6,65.51 117.85,68.26 v1(117.85,68.85)
  L4 w0.165: 120.6,65.06 120.6,52.33 110.27,42 110.27,40.44 109.72,39.48 109.72,36.13 v1(110.17,35.68)
  BOTTOM w0.089: CPU1.AY39 117.67,76.06 117.35,75.75 117.35,75.39 117.2,75.08 117.2,74.58 117.08,74.46 117.08,69.63 v1(117.85,68.85)
  BOTTOM w0.191: DM1.174 111.27,34.94 110.53,35.68 v1(110.17,35.68)
M_A_DQ33: length 49.6
  L4 w0.089: 121.34,64.9 121.34,65.35 118.54,68.14 118.54,69.75 118.28,70.46 v1(117.95,71.03)
  L4 w0.165: 121.34,64.9 121.34,52.03 111.05,41.74 111.05,38.92 v1(110.58,37.35)
  BOTTOM w0.089: CPU1.AW39 118.25,76.9 118.38,76.87 118.49,76.75 118.55,76.51 118.59,76.13 118.59,75.88 118.55,75.74 118.55,75.49 118.59,75.41 118.59,75.21 118.55,75.13 118.55,74.74 118.66,74.63 118.66,72.11 v1(117.95,71.03)
  BOTTOM w0.191: DM1.173 111,40.13 111,39.46 v1(110.58,37.35)
M_A_DQ34: length 51.9
  L4 w0.165: v1(114.48,39.04) 114.32,39.19 114.32,41.97 123.5,51.15 123.5,64.98 119.76,68.73 119.76,68.91 v1(119.91,69.06)
  BOTTOM w0.089: 118.79,71.81 118.84,72.01 118.84,74.71 118.73,74.81 118.73,75.09 118.77,75.17 118.77,75.45 118.73,75.54 118.73,75.71 118.76,75.81 118.76,75.82 118.83,75.96 CPU1.AY37
  BOTTOM w0.191: v1(119.91,69.06) 120.1,68.86 v2(120.87,68.86) 121.59,68.86 121.71,68.73 121.71,68.27 121.59,68.14 118.45,68.14 118.32,68.27 118.32,68.65 118.43,68.77 118.9,68.77 119.03,68.89 119.03,70.19 118.79,70.43 118.79,71.81 ; v1(114.48,39.04) 114.52,39.08 DM1.187
M_A_DQ35: length 51.5
  L4 w0.089: v1(120.03,71.04) 120.34,70.73 120.34,68.52 123.87,64.99 123.87,64.85
  L4 w0.165: v1(114.78,34.8) 114.76,34.8 113.92,35.65 113.92,37.38 114.94,38.41 114.94,42.07 123.87,51 123.87,64.85
  BOTTOM w0.089: v1(120.03,71.04) 119.65,71.04 119.37,71.32 119.37,74.64 119.43,74.69 119.43,74.7 119.43,74.71 119.43,75.45 119.43,75.45 119.43,75.47 119.25,75.65 119.25,75.79 119.21,75.84 119.21,76.51 118.89,76.82 CPU1.AW37
  BOTTOM w0.191: v1(114.78,34.8) 114.66,34.8 114.27,34.41 DM1.186
M_A_DQ36: length 48.8
  L4 w0.089: v1(117.64,74.21) 117.25,73.81 117.25,73.42 117.25,73.41 117.39,73.28 117.39,72.19 117.46,72.12 117.46,68.39 120.23,65.61 120.23,64.89
  L4 w0.165: v1(110.17,34.37) 110.16,34.37 109.98,34.55 109.35,35.17 109.35,39.88 109.75,40.28 109.84,40.43 109.84,42.09 120.23,52.49 120.23,64.89
  BOTTOM w0.14: CPU1.BB39 117.67,74.23 v1(117.64,74.21)
  BOTTOM w0.191: DM1.170 110.27,34.26 v1(110.17,34.37)
M_A_DQ37: length 50.6
  L4 w0.089: 120.97,65.18 120.97,65.42 118.26,68.13 118.26,69.97 v1(117.91,70.32)
  L4 w0.165: 120.97,65.18 120.97,52.18 110.65,41.86 110.65,38.87 110.32,38.54 v1(110.19,38.54)
  BOTTOM w0.089: CPU1.BA39 117.56,75.42 117.48,75.25 117.37,75.02 117.37,74.5 117.25,74.38 117.25,72.74 117.41,72.59 117.41,72.2 117.25,72.04 117.25,71.61 117.53,71.34 117.53,71.02 117.25,70.75 117.25,70 117.38,69.88 118.09,69.88 118.28,69.69 118.28,69.21 118.4,69.1 118.58,69.1 118.7,69.22 118.7,69.91 118.29,70.32 v1(117.91,70.32)
  BOTTOM w0.191: v1(110.19,38.54) 110.04,38.4 109.72,38.4 109.6,38.52 109.6,39.26 110.02,39.69 DM1.169
M_A_DQ38: length 50.6
  L4 w0.089: 119.34,68.42 119.34,69.76 v1(119.91,70.33)
  L4 w0.165: 119.34,68.42 122.43,65.33 122.43,65.33 122.75,65 122.75,51.45 113.58,42.28 113.58,38.98 113.08,38.47 113.08,37.23 112.77,36.27 112.56,36.17 v1(112.55,36.17)
  BOTTOM w0.089: v1(119.91,70.33) 119.2,71.04 119.2,74.72 119.26,74.78 119.26,75.37 CPU1.BA37
  BOTTOM w0.191: DM1.183 113.52,39.81 113.4,39.06 113.09,38.76 113.09,37.05 112.79,36.39 112.57,36.17 v1(112.55,36.17)
M_A_DQ39: length 49.3
  L4 w0.089: v1(119.91,69.69) 119.52,69.3 119.52,68.6 119.67,68.46
  L4 w0.165: v1(112.55,34.85) 113.55,35.84 113.55,38.42 113.95,38.82 113.95,42.12 123.12,51.29 123.12,65 119.67,68.46
  BOTTOM w0.089: CPU1.BB37 119.02,74.96 119.02,70.58 v1(119.91,69.69)
  BOTTOM w0.191: DM1.182 113.27,34.36 112.79,34.85 v1(112.55,34.85)
M_A_DQ40: length 52.2
  L4 w0.089: v1(120.14,74.21) 119.62,74.21 119.37,73.97 118.85,73.97 118.7,74.12 118.7,74.75 118.83,74.88 120.66,74.88 121.59,73.95 121.59,70.66 121.25,70.33 121.25,68.85 125.9,64.2
  L4 w0.165: 125.9,64.2 125.9,63.88 125.73,63.71 125.73,50.72 117.98,42.97 117.98,41.85 116.47,40.34 116.47,38.55 116.6,38.42 v1(116.94,38.42)
  BOTTOM w0.089: v1(120.14,74.21) 120.3,74.37 120.3,75.05 120.25,75.17 120.25,75.44 120.28,75.54 120.28,75.74 120.24,75.84 120.24,76.17 CPU1.AY35
  BOTTOM w0.191: v1(116.94,38.42) 116.92,38.42 116.46,38.88 116.46,39.28 116.52,39.34 DM1.195
M_A_DQ41: length 53.3
  L4 w0.089: 125.57,63.9 125.57,64.23 121.02,68.77 121.02,70.62 121.39,70.98 121.39,73.73 121.26,73.85 120.41,73.85 v1(120.14,73.58)
  L4 w0.165: v1(116.91,34.85) 116.23,34.85 116.1,34.98 116.1,40.5 117.61,42 117.61,43.13 125.28,50.79 125.28,63.62 125.57,63.9
  BOTTOM w0.089: v1(120.14,73.58) 120.21,73.58 120.53,73.9 120.53,74.46 120.48,74.51 120.48,75.08 120.46,75.12 120.46,75.12 120.42,75.21 120.42,75.41 120.46,75.5 120.46,75.78 120.42,75.87 120.42,76.64 CPU1.AW35
  BOTTOM w0.191: v1(116.91,34.85) 116.9,34.85 116.27,34.23 DM1.194
M_A_DQ42: length 53
  L4 w0.089: 127.95,63.78 127.95,63.98 122.84,69.09 122.84,72.42 v1(122.09,73.17)
  L4 w0.165: v1(118.78,37.59) 119.2,38.02 119.2,39.97 127.95,48.72 127.95,63.78
  BOTTOM w0.089: v1(122.09,73.17) 121.84,73.17 121.71,73.3 121.71,74.21 121.79,74.29 121.79,75.09 121.76,75.21 121.72,75.27 121.54,76 CPU1.AY33
  BOTTOM w0.191: DM1.207 119.52,39.46 119.67,39.31 119.67,37.71 120.81,36.56 120.81,36.38 120.51,36.08 120.29,36.08 v1(118.78,37.59)
M_A_DQ43: length 51.6
  L4 w0.089: v1(121.44,77.44) 121.53,76.52 121.59,76.1 122.74,73.42 123.02,72.77 123.02,69.16 128.33,63.85 128.33,63.6
  L4 w0.165: 128.33,63.6 128.33,48.57 119.57,39.81 119.57,37.85 v1(119.51,35.92)
  BOTTOM w0.089: CPU1.AW33 v1(121.44,77.44)
  BOTTOM w0.191: v1(119.51,35.92) 119.76,35.45 119.76,33.75 119.77,33.73 DM1.208
M_A_DQ44: length 51.6
  L4 w0.089: v1(120.14,72.94) 120.46,72.94 120.59,73.07 120.59,73.45 120.72,73.58 121.08,73.58 121.21,73.45 121.21,71.34 120.8,70.93 120.8,68.73 124.62,64.9 124.62,64.62
  L4 w0.165: 124.62,64.62 124.62,63.89 124.91,63.6 124.91,50.95 115.72,41.76 115.72,37.46 115.55,37.29 v1(115.01,37.29)
  BOTTOM w0.089: CPU1.BB35 120.02,74.94 119.83,74.45 119.75,74.37 119.75,73.33 v1(120.14,72.94)
  BOTTOM w0.191: v1(115.01,37.29) 115.39,36.9 115.92,36.9 116.2,37.18 116.2,37.65 115.51,38.35 115.51,39.67 115.52,39.69 DM1.191
M_A_DQ45: length 52
  L4 w0.089: 124.24,64.7 124.24,64.95 120.57,68.62 120.57,71.83 v1(120.08,72.31)
  L4 w0.165: v1(114.78,36.07) 114.41,36.07 114.29,36.2 114.29,37.23 115.31,38.25 115.31,41.92 124.24,50.85 124.24,64.7
  BOTTOM w0.089: v1(120.08,72.31) 119.56,72.83 119.56,74.58 119.63,74.65 119.63,75.44 119.83,75.64 CPU1.BA35
  BOTTOM w0.191: DM1.190 115.27,34.7 116.05,35.47 116.05,36.35 115.92,36.48 115.2,36.48 114.95,36.23 v1(114.78,36.07)
M_A_DQ46: length 51.6
  L4 w0.089: v1(122.09,72.54) 122.64,71.98 122.64,69.04 127.57,64.11 127.57,63.93
  L4 w0.165: v1(118.71,38.91) 118.71,40.01 122.06,43.35 122.06,43.58 121.73,43.9 121.73,44.17 121.97,44.4 122.17,44.4 122.52,44.05 122.76,44.05 122.99,44.28 122.99,44.52 122.64,44.86 122.64,45.1 122.89,45.34 123.1,45.34 123.46,44.98 123.69,44.98 123.92,45.22 123.92,45.45 123.56,45.81 123.56,46.02 123.82,46.28 124.03,46.28 124.39,45.92 124.62,45.92 124.86,46.15 124.86,46.38 124.48,46.76 124.48,46.93 124.76,47.22 124.96,47.22 125.32,46.85 125.56,46.85 125.82,47.11 125.82,47.35 125.47,47.69 125.47,47.93 125.71,48.16 125.94,48.16 126.29,47.81 126.52,47.81 127.57,48.86 127.57,63.93
  BOTTOM w0.089: v1(122.09,72.54) 121.97,72.41 121.66,72.41 121.53,72.54 121.53,74.29 121.61,74.36 121.61,75.06 121.59,75.13 121.35,75.52 CPU1.BA33
  BOTTOM w0.191: DM1.203 118.52,39.11 118.71,38.92 v1(118.71,38.91)
M_A_DQ47: length 50.8
  L4 w0.089: 122.67,68.68 122.47,68.88 122.47,71.53 v1(122.09,71.9)
  L4 w0.165: v1(119.29,34.62) 118.38,34.62 118.25,34.75 118.25,40.06 121.29,43.1 121.29,44.27 127.16,50.14 127.16,64.19 122.67,68.68
  BOTTOM w0.089: CPU1.BB33 121.38,74.95 121.38,74.42 121.35,74.39 121.35,71.71 121.48,71.59 121.78,71.59 v1(122.09,71.9)
  BOTTOM w0.191: DM1.204 118.77,34.5 118.9,34.62 v1(119.29,34.62)
M_A_DQ48: length 50.5
  L4 w0.165: v1(121.91,35.28) 122.55,35.28 122.67,35.41 122.67,40.7 129.82,47.85 129.82,63.9 124.69,69.03 124.69,69.71 123.86,70.54 123.86,71.04 v1(123.43,71.46)
  BOTTOM w0.089: v1(123.43,71.46) 123.06,71.84 123.06,75.08 123.01,75.13 123.01,75.93 CPU1.AY31
  BOTTOM w0.191: DM1.216 121.77,33.78 121.91,33.92 v1(121.91,35.28)
M_A_DQ49: length 51.7
  L4 w0.165: v1(121.01,37.72) 120.7,37.72 120.57,37.85 120.57,39.38 120.7,39.5 121.75,39.5 121.94,39.69 121.94,41.12 129.08,48.26 129.08,63.86 123.88,69.06 123.88,69.77 123.7,69.95 v1(123.43,69.95)
  BOTTOM w0.089: 122.52,70.69 122.52,74.42 122.21,74.73 122.21,75.16 122.26,75.27 122.33,75.34 122.33,76.44 122.65,76.75 CPU1.AW31
  BOTTOM w0.191: v1(121.01,37.72) 121.05,37.72 121.53,38.2 121.53,39.3 121.52,39.31 DM1.215 ; 122.52,70.69 122.52,70.47 122.29,70.24 122.29,69.51 v2(122.41,69.38) 122.85,69.38 v1(123.43,69.95)
M_A_DQ50: length 50.6
  L4 w0.089: 127.5,68.67 127.34,68.67 125.52,70.49 125.52,70.93 125.41,72.75 125.4,72.76 125.4,72.77 v1(124.98,73.27)
  L4 w0.165: 127.5,68.67 132.01,64.16 132.01,47 125.3,40.29 125.3,37.57 125.57,37.3 v1(125.76,37.13)
  BOTTOM w0.089: CPU1.AY29 124.15,75.89 124.27,75.73 124.45,75.1 124.45,74.8 124.61,74.64 124.61,73.76 v1(124.98,73.27)
  BOTTOM w0.191: v1(125.76,37.13) 125.21,36.86 124.77,36.43 DM1.228
M_A_DQ51: length 50.4
  L4 w0.089: v1(123.78,77.44) 123.78,75.17 123.66,75.04 123.33,75.04 123.2,74.92 123.2,74.69 123.33,74.56 125.23,74.56 125.42,74.37 125.42,73.04 125.74,72.73 125.74,70.52 127.33,68.93 127.61,68.93 127.74,68.79
  L4 w0.165: 127.74,68.79 132.38,64.15 132.38,46.86 126.23,40.7 126.23,38.87 125.76,38.41 v1(125.76,38.4)
  BOTTOM w0.14: v1(123.78,77.44) 123.87,77.35 CPU1.AW29
  BOTTOM w0.191: DM1.229 125.02,40.15 125.07,40.11 125.07,39.08 125.75,38.4 v1(125.76,38.4)
M_A_DQ52: length 49.1
  L4 w0.165: v1(121.04,38.38) 121.35,38.38 121.48,38.25 121.48,36.95 121.6,36.83 122.18,36.83 122.31,36.95 122.31,40.86 129.45,48 129.45,63.89 124.16,69.18 124.16,69.85 123.42,70.59 v1(123.42,70.83)
  BOTTOM w0.089: v1(123.42,70.83) 122.95,71.3 122.95,71.67 122.88,71.75 122.88,74.75 CPU1.BB31
  BOTTOM w0.191: DM1.211 120.52,39.92 120.57,39.87 120.57,38.82 121.01,38.38 v1(121.04,38.38)
M_A_DQ53: length 50.1
  L4 w0.165: v1(123.41,69.32) 123.41,69.15 128.71,63.85 128.71,48.41 120.2,39.91 120.2,34.73 v1(120.77,34.17)
  BOTTOM w0.089: v1(123.41,69.32) 123.81,69.72 123.81,70.11 123.49,70.44 123.27,70.44 122.7,71 122.7,74.49 122.39,74.81 122.39,75.08 122.42,75.17 122.46,75.22 122.65,75.4 CPU1.BA31
  BOTTOM w0.191: v1(120.77,34.17) 120.77,34.16 DM1.212
M_A_DQ54: length 49.6
  L4 w0.089: 127.43,68.37 127.39,68.37 125.34,70.41 125.34,70.72 v1(124.94,71.93)
  L4 w0.165: v1(123.19,34.83) 123.49,35.1 123.64,35.25 124.93,37.96 124.93,40.44 131.64,47.15 131.64,64.16 127.43,68.37
  BOTTOM w0.089: CPU1.BA29 124.27,75.05 124.27,74.73 124.43,74.57 124.43,73 124.7,72.3 v1(124.94,71.93)
  BOTTOM w0.191: DM1.224 123.77,34.3 123.25,34.83 v1(123.19,34.83)
M_A_DQ55: length 48.9
  L4 w0.089: 127.18,68.27 127.18,68.31 125.04,70.45 v1(124.83,70.99)
  L4 w0.165: v1(123.18,36.67) 124.38,37.87 124.56,38.35 124.56,40.6 131.27,47.31 131.27,64.17 127.18,68.27
  BOTTOM w0.089: CPU1.BB29 124.09,74.66 124.16,74.5 124.25,74.4 124.25,72.42 v1(124.83,70.99)
  BOTTOM w0.191: v1(123.18,36.67) 123.29,36.67 124.02,37.4 DM1.225
M_A_DQ56: length 51.9
  L4 w0.089: 127.36,69.86 126.84,70.38 126.84,72.12 126.7,72.25 126.7,74.27 125.86,75.11 125.64,75.11 125.44,74.92 125.44,74.74 125.71,74.47 125.71,73.12 125.89,72.94 v1(126.17,72.94)
  L4 w0.165: 127.36,69.86 127.76,69.86 133.49,64.13 133.49,46.4 129.54,42.45 129.54,41.61 128.08,40.15 128.08,38.86 127.6,38.37 v1(127.59,38.37)
  BOTTOM w0.089: CPU1.AY27 125.22,76 125.28,75.93 125.35,75.77 125.35,75.44 125.36,75.4 125.43,75.15 125.44,75.07 125.46,75.03 125.46,74.56 125.75,74.27 125.75,73.35 v1(126.17,72.94)
  BOTTOM w0.191: v1(127.59,38.37) 127.47,38.37 127.14,38.71 127.14,39.64 127.02,39.75 DM1.237
M_A_DQ57: length 53.1
  L4 w0.089: 127.35,70.18 127.03,70.5 127.03,74.65 126.02,75.67 124.52,75.67 124.29,75.9 124.29,76.47 v1(124.45,76.63)
  L4 w0.165: v1(127.6,37.1) 127.61,37.1 128.45,37.94 128.45,40 129.92,41.48 129.92,42.31 133.86,46.25 133.86,64.12 127.83,70.14 127.39,70.14 127.35,70.18
  BOTTOM w0.14: CPU1.AW27 124.81,76.94 124.5,76.63 v1(124.45,76.63)
  BOTTOM w0.191: v1(127.6,37.1) 127.48,37.1 126.77,36.4 126.77,33.99 126.77,33.99 DM1.236
M_A_DQ58: length 51.5
  L4 w0.165: v1(127.53,73.37) 127.88,73.37 129.31,71.94 129.31,71.71 129.17,71.57 129.17,71.34 129.41,71.1 129.64,71.1 129.78,71.24 130.01,71.24 130.24,71.01 130.24,70.77 130.11,70.64 130.11,70.4 130.34,70.17 130.57,70.17 130.71,70.31 130.95,70.31 131.18,70.07 131.18,69.84 131.04,69.7 131.04,69.47 131.27,69.23 131.51,69.23 131.65,69.37 131.88,69.37 132.28,68.97 132.28,68.07 133.56,66.79 133.98,66.79 133.99,66.79 134.15,66.79 136.08,64.87 136.08,45.42 132.19,41.53 132.19,40.59 131.8,40.2 131.8,37.82 131.62,37.65 131.37,37.65 131.15,37.87 131.15,38.15 131.02,38.28 v1(130.72,38.28)
  BOTTOM w0.089: v1(127.53,73.37) 127.53,73.48 127.3,73.7 127.3,74.43 126.83,74.9 126.64,75.51 126.64,75.85 126.64,75.85 126.6,75.93 CPU1.AY25
  BOTTOM w0.191: DM1.249 130.02,38.3 130.2,38.12 130.56,38.12 v1(130.72,38.28)
M_A_DQ59: length 51.6
  L4 w0.165: v1(130.27,33.94) 130.28,33.94 131.27,34.93 131.27,36.78 132.18,37.68 132.18,40.06 132.55,40.44 132.55,41.34 136.46,45.24 136.46,65.07 134.06,67.46 133.51,67.46 132.7,68.27 132.7,68.94 128.26,73.38 128.26,75.09 v1(126.76,76.6)
  BOTTOM w0.14: CPU1.AW25 126.39,76.94 126.72,76.61 126.74,76.61 v1(126.76,76.6)
  BOTTOM w0.191: v1(130.27,33.94) 130.27,33.85 130.35,33.78 130.35,32.75 130.28,32.68 130.28,32.6 130.27,32.6 DM1.250
M_A_DQ60: length 50.4
  L4 w0.089: v1(126.16,70.81) 126.16,70.42 127.39,69.19
  L4 w0.165: 127.39,69.19 127.71,69.19 132.75,64.15 132.75,46.7 128.8,42.75 128.8,41.93 126.73,39.85 126.73,37.44 125.95,36.67 125.55,36.67 125.52,36.7 125.13,36.7 124.76,36.33 124.76,35.17 124.98,34.95 v1(125.32,34.95)
  BOTTOM w0.089: CPU1.BB27 125.08,74.9 125.08,74.43 125.09,74.42 125.09,74.42 125.39,74.11 125.39,72.79 125.55,72.64 125.55,72.34
  BOTTOM w0.191: v1(125.32,34.95) 125.79,34.47 125.79,33.99 125.77,33.97 DM1.232 ; 125.55,72.34 v2(125.55,71.42) v1(126.16,70.81)
M_A_DQ61: length 51.6
  L4 w0.089: 127.38,69.52 126.62,70.28 126.62,71.82 v1(126.14,72.3)
  L4 w0.165: 127.38,69.52 127.74,69.52 133.12,64.14 133.12,46.55 129.17,42.6 129.17,41.76 127.1,39.69 127.1,37.29 126.05,36.24 v1(125.32,36.24)
  BOTTOM w0.089: v1(126.14,72.3) 125.57,72.87 125.57,74.19 125.28,74.48 125.28,75.01 125.2,75.33 CPU1.BA27
  BOTTOM w0.191: DM1.233 126.02,40.5 126.03,40.5 126.03,39.48 126.24,39.26 126.24,36.93 125.96,36.66 125.88,36.66 125.86,36.64 125.72,36.64 v1(125.32,36.24)
M_A_DQ62: length 50.9
  L4 w0.165: v1(127.81,72.76) 128.68,71.89 128.68,71.21 133.36,66.54 133.88,66.54 134.6,65.81 134.6,65.36 134.97,64.99 135.43,64.99 135.69,64.72 135.69,45.57 131.82,41.69 131.82,40.77 130.25,39.21 130.25,36.55 v1(130.33,36.47)
  BOTTOM w0.089: CPU1.BA25 126.52,75.28 126.66,74.83 126.67,74.81 127.12,74.36 127.12,72.97 127.33,72.76 127.8,72.76 v1(127.81,72.76)
  BOTTOM w0.191: v1(130.33,36.47) 129.02,37.77 DM1.245
M_A_DQ63: length 49.8
  L4 w0.165: v1(130.26,35.21) 129.83,35.64 129.83,37.11 129.86,37.15 129.86,39.42 131.45,41.01 131.45,41.84 135.31,45.71 135.31,64.07 134.02,65.36 134.02,66.04 133.77,66.28 133.25,66.28 128.39,71.14 128.39,71.79 127.93,72.25 v1(127.42,72.25)
  BOTTOM w0.089: CPU1.BB25 126.33,74.85 126.94,74.24 126.94,72.73 v1(127.42,72.25)
  BOTTOM w0.191: v1(130.26,35.21) 130.12,35.21 129.27,34.35 129.27,33.52 129.27,33.46 DM1.246
M_A_DQS_DN0: length 70.3
  L4 w0.152: v1(93.41,80.82) 92.87,81.36 91.49,81.36 90.79,80.66 90.79,80.07 91.24,79.62 91.24,79.44 90.99,79.19 90.81,79.19 90.27,79.73 89.86,79.73 85.4,75.28 85.4,68.3 69.43,52.33 69.43,45.42 68.05,44.05 68.05,37.38 68.37,37.06 68.57,37.06 v1(68.86,36.9)
  BOTTOM w0.089: CPU1.AM70 99.78,80.94 99.6,80.89 99.42,80.89 99.31,80.92 99.04,80.92 98.82,80.85 98.67,80.85 98.35,80.85 98,80.81 95.02,80.81 94.57,80.35 93.88,80.35 93.74,80.5 v1(93.41,80.82)
  BOTTOM w0.191: v1(68.86,36.9) 68.62,37.03 68.39,37.03 68.05,37.37 68.05,38.39 68.05,38.39 68.05,38.63 68.52,39.11 DM1.11
M_A_DQS_DN1: length 61.1
  L4 w0.152: v1(96.97,78.38) 97.13,78.21 97.13,78.03 96.56,77.46 96.2,73.12 96.08,72.99 74.98,51.9 74.98,49.31 73.97,41.22 73.97,41.18 73.97,37.55 72.51,36.09 72.51,35.09 72.8,34.8 v1(73.53,34.8)
  BOTTOM w0.089: CPU1.AT69 100.11,78.4 99.81,78.4 99.61,78.35 99.4,78.35 99.27,78.39 98.96,78.39 98.63,78.06 98.63,78.06 98.49,77.92 97.96,77.92 97.86,77.81 97.54,77.81 v1(96.97,78.38)
  BOTTOM w0.191: v1(73.53,34.8) 73.87,34.46 73.87,33.64 73.77,33.54 DM1.32
M_A_DQS_DN2: length 55.7
  L4 w0.152: v1(79.99,37.82) 79.8,38.01 79.5,38.01 79.21,38.3 79.21,49.29 95.53,65.6 95.53,66.22 v1(95.46,66.29)
  BOTTOM w0.089: 100.51,71.83 100.51,71.93 100.7,72.11 100.7,72.11 101.15,72.56 102,72.56 103.25,73.81 103.25,74.52 103.38,74.66 103.38,75.09 103.34,75.22 103.34,75.39 103.39,75.58 CPU1.BA64
  BOTTOM w0.191: 100.51,71.83 97.79,69.11 97.79,68.82 97.35,68.38 97.35,67.11 97.84,66.62 97.84,66.01 97.09,65.27 96.48,65.27 v1(95.46,66.29) ; v1(79.99,37.82) 79.99,37.82 79.7,37.87 79.35,37.87 79.02,38.19 DM1.53
M_A_DQS_DN3: length 55
  L4 w0.152: v1(103.23,70.3) 102.67,70.3 100.45,68.08 100.45,64.49 84.03,48.07 84.03,41.91 84.79,39.45 84.79,35.24 84.5,34.95 84.18,34.95 v1(83.88,34.8)
  BOTTOM w0.089: CPU1.AY60 106.35,75.92 106.35,75.61 106.4,75.41 106.4,75.2 106.36,75.07 106.36,74.67 106.08,74.38 106.08,73.51 104.22,71.65 104.22,71.11 103.71,70.6 103.63,70.55 103.38,70.3 v1(103.23,70.3)
  BOTTOM w0.191: DM1.74 84.27,33.42 84.36,33.5 84.36,34.56 84.18,34.74 v1(83.88,34.8)
M_A_DQS_DN4: length 50.2
  L4 w0.152: v1(117.8,72.31) 117.81,72.31 118.79,71.33 118.79,68.23 121.9,65.11 121.9,51.79 111.64,41.53 111.64,40.92 111.93,40.63 112.54,40.63 112.66,40.5 112.66,40.08 112.53,39.95 111.91,39.95 111.61,39.66 111.61,37.95 111.87,37.69 v1(112.55,37.69)
  BOTTOM w0.089: CPU1.BA38 118.12,75.68 118.12,75.58 118.07,75.39 118.07,75.22 118.1,75.09 118.1,74.56 118.17,74.46 118.19,74.46 118.23,74.42 118.23,72.73 v1(117.8,72.31)
  BOTTOM w0.127: 112.54,37.7 v1(112.55,37.69)
  BOTTOM w0.191: 112.54,37.7 111.95,38.29 111.95,39.73 112.02,39.81 DM1.177
M_A_DQS_DN5: length 52.7
  L4 w0.089: v1(122.03,70.59) 122.26,69.99 122.26,68.81
  L4 w0.152: 122.26,68.81 122.26,68.81 122.26,68.67 126.59,64.34 126.59,50.39 120.72,44.52 120.72,43.34 120.29,42.9 119.84,42.9 119.58,43.16 119.38,43.16 119.15,42.93 119.15,42.74 119.41,42.47 119.41,42.02 117.68,40.3 117.68,36.71 117.39,36.42 v1(116.91,36.27)
  BOTTOM w0.089: v1(122.03,70.59) 121.09,71.53 121.09,74.63 121.09,74.63 121.09,75 121.08,75 121.08,75.06 121.13,75.21 121.13,75.41 121.07,75.61 121.07,75.99 CPU1.AY34
  BOTTOM w0.191: v1(116.91,36.27) 117.6,36.27 117.8,36.08 117.8,35.66 117.39,35.25 117.39,33.53 117.27,33.42 DM1.198
M_A_DQS_DN6: length 49.9
  L4 w0.152: v1(123.18,37.96) 123.77,38.29 123.77,38.29 124,38.52 124,39.54 123.53,40.01 123.53,40.36 130.7,47.53 130.7,64.37 128.41,66.66 127.87,66.66 127.71,66.82 127.71,67.37 127.28,67.81 126.72,67.81 126.56,67.97 126.56,68.18 126.56,68.19 126.56,68.63 126.24,68.96 125.79,68.96 125.79,68.96 125.57,68.96 125.41,69.12 125.41,69.33 125.41,69.34 125.41,69.78 124.4,70.79 124.4,71.21 124.52,71.32 124.52,73.06 124.21,73.37 v1(123.46,73.37)
  BOTTOM w0.089: CPU1.BA30 123.48,75.64 123.51,75.58 123.58,75.38 123.58,75.24 123.53,75.09 123.53,74.58 123.87,74.23 123.87,73.49 123.76,73.37 v1(123.46,73.37)
  BOTTOM w0.191: DM1.219 122.52,39.88 122.38,39.74 122.38,38.62 123.04,37.96 v1(123.18,37.96)
M_A_DQS_DN7: length 51.9
  L4 w0.152: v1(127.5,71.21) 127.67,71.05 128.01,71.05 128.47,70.59 129.67,69.13 134.74,64.07 134.74,45.93 130.86,42.05 130.86,41.22 129.29,39.65 129.29,37.8 128.82,35.58 128.32,35.08 v1(127.59,35.08)
  BOTTOM w0.089: CPU1.AY26 126.05,76.33 126.05,75.61 126.11,75.41 126.11,75.21 126.06,75.06 126.06,74.82 126.75,74.13 126.75,72.63 126.87,72.51 126.87,72.02 126.94,71.95
  BOTTOM w0.191: v1(127.5,71.21) 127.39,71.1 127.23,71.1 126.94,71.39 126.94,71.95 ; DM1.240 127.77,33.42 127.84,33.49 127.84,34.21 127.97,34.34 127.97,34.93 127.82,35.08 v1(127.59,35.08)
M_A_DQS_DP0: length 70.4
  L4 w0.152: v1(92.96,80.31) 92.96,80.88 92.75,81.09 91.61,81.09 91.07,80.55 91.07,80.19 91.52,79.73 91.52,79.32 91.11,78.91 90.7,78.91 90.15,79.45 89.97,79.45 85.68,75.16 85.68,68.19 69.7,52.21 69.7,45.3 68.33,43.93 68.33,37.49 68.49,37.34 68.71,37.34 68.86,37.49 v1(68.86,37.56)
  BOTTOM w0.089: v1(92.96,80.31) 92.96,80.17 93.05,80.08 93.24,80.08 93.49,80.34 93.62,80.34 93.8,80.16 94.65,80.16 95.1,80.62 98.01,80.62 98.36,80.66 98.84,80.66 99.08,80.74 99.28,80.74 99.39,80.71 99.62,80.71 99.81,80.76 100.16,80.76 100.66,81.15 CPU1.AM69
  BOTTOM w0.191: DM1.13 69.02,39.76 68.86,39.59 68.86,38.97 68.38,38.5 68.38,38.25 68.38,38.25 68.38,37.51 68.53,37.36 68.66,37.36 v1(68.86,37.56)
M_A_DQS_DP1: length 61.2
  L4 w0.152: v1(97.61,78.43) 97.42,78.24 97.42,78.22 97.41,78.21 97.41,77.92 96.83,77.33 96.47,73 96.36,72.88 75.26,51.78 75.26,49.29 74.25,41.18 74.25,37.43 72.79,35.97 72.79,35.21 72.91,35.08 73.1,35.08 v1(73.51,35.49)
  BOTTOM w0.089: CPU1.AT70 100.02,78.59 99.88,78.58 99.78,78.58 99.59,78.53 99.42,78.53 99.29,78.57 98.87,78.57 98.82,78.52 98.82,78.52 98.59,78.29 98.59,78.29 98.41,78.11 97.88,78.11 97.78,78 97.61,78 97.48,78.13 97.48,78.31 v1(97.61,78.43)
  BOTTOM w0.191: DM1.34 74.27,33.53 74.2,33.6 74.2,35.42 74.01,35.61 73.63,35.61 v1(73.51,35.49)
M_A_DQS_DP2: length 55.7
  L4 w0.152: v1(79.99,38.53) 79.75,38.29 79.61,38.29 79.49,38.41 79.49,49.17 95.81,65.49 95.81,65.98 96.17,66.35 96.17,66.49 v1(95.93,66.73)
  BOTTOM w0.089: CPU1.AY64 103.31,76.42 103.31,76.01 103.17,75.41 103.17,75.2 103.2,75.07 103.2,74.75 103.06,74.6 103.06,73.89 101.92,72.75 101.07,72.75 100.89,72.57 100.89,72.57 100.38,72.07 100.29,72.07 100.28,72.06
  BOTTOM w0.191: v1(79.99,38.53) 79.99,38.53 79.67,38.2 79.48,38.2 79.35,38.33 79.35,39.64 79.52,39.81 DM1.55 ; 100.28,72.06 97.46,69.24 97.46,68.96 97.02,68.52 97.02,66.97 97.51,66.48 97.51,66.15 96.95,65.6 96.62,65.6 96.02,66.2 96.02,66.65 v1(95.93,66.73)
M_A_DQS_DP3: length 55
  L4 w0.152: v1(103.12,70.92) 102.77,70.58 102.55,70.58 100.17,68.19 100.17,64.6 83.75,48.19 83.75,41.87 84.51,39.41 84.51,35.35 84.39,35.23 84.16,35.23 v1(83.88,35.51)
  BOTTOM w0.089: v1(103.12,70.92) 103.33,70.71 103.53,70.71 103.59,70.75 104.03,71.19 104.03,71.73 105.89,73.59 105.89,74.46 106.18,74.76 106.18,75.09 106.22,75.22 106.22,75.39 106.17,75.58 106.17,75.68 CPU1.BA60
  BOTTOM w0.191: v1(83.88,35.51) 84.69,34.7 84.69,33.47 84.77,33.39 DM1.76
M_A_DQS_DP4: length 50.1
  L4 w0.152: v1(112.55,38.38) 112.14,37.97 111.99,37.97 111.89,38.07 111.89,39.54 112.02,39.67 112.65,39.67 112.94,39.97 112.94,40.62 112.65,40.91 112.04,40.91 111.92,41.03 111.92,41.41 122.18,51.68 122.18,65.23 119.07,68.34 119.07,71.44 118.3,72.22 118.3,72.7 118.05,72.94 v1(117.77,72.94)
  BOTTOM w0.089: CPU1.AY38 118.04,76.61 117.94,76.51 117.94,75.61 117.89,75.41 117.89,75.2 117.93,75.07 117.93,74.51 118.04,74.34 118.04,73.2 v1(117.77,72.94)
  BOTTOM w0.191: v1(112.55,38.38) 112.28,38.64 112.28,39.56 112.52,39.79 112.52,39.85 112.52,39.86 DM1.179
M_A_DQS_DP5: length 52.8
  L4 w0.089: 121.98,68.81 121.98,68.85 122.07,68.94 122.07,69.83 121.94,69.96 v1(121.85,69.96)
  L4 w0.152: v1(116.91,36.99) 116.91,36.88 117.09,36.7 117.28,36.7 117.41,36.83 117.41,40.41 119.13,42.14 119.13,42.36 118.87,42.62 118.87,42.83 118.87,43.04 119.27,43.44 119.7,43.44 119.96,43.18 120.17,43.18 120.45,43.45 120.45,44.64 126.32,50.51 126.32,64.22 121.98,68.56 121.98,68.69 121.98,68.7 121.98,68.81
  BOTTOM w0.089: CPU1.BA34 120.82,75.96 120.89,75.89 120.89,75.58 120.95,75.38 120.95,75.24 120.9,75.09 120.9,74.63 120.9,74.63 120.9,71.45 121.46,70.9 121.46,70.09 121.58,69.96 v1(121.85,69.96)
  BOTTOM w0.191: DM1.200 117.77,33.43 117.72,33.48 117.72,35.11 118.13,35.52 118.13,36.21 117.74,36.6 117.29,36.6 v1(116.91,36.99)
M_A_DQS_DP6: length 50
  L4 w0.152: v1(123.46,72.74) 123.65,72.74 123.75,72.84 123.75,73 123.84,73.1 124.09,73.1 124.24,72.95 124.24,71.43 124.12,71.32 124.12,70.67 125.13,69.67 125.13,69.45 125.13,69.45 125.13,69 125.46,68.68 125.9,68.68 125.91,68.68 126.12,68.68 126.28,68.52 126.28,68.3 126.28,68.3 126.28,67.85 126.61,67.53 127.16,67.53 127.43,67.26 127.43,66.7 127.76,66.38 128.29,66.38 130.42,64.25 130.42,47.65 123.25,40.48 123.25,39.89 123.72,39.42 123.72,38.64 123.6,38.52 123.49,38.46 123.36,38.46 v1(123.19,38.63)
  BOTTOM w0.089: CPU1.AY30 123.49,76.44 123.64,76.05 123.69,75.76 123.69,75.61 123.75,75.41 123.75,75.21 123.71,75.06 123.71,74.67 124.06,74.31 124.06,73.34 v1(123.46,72.74)
  BOTTOM w0.191: v1(123.19,38.63) 122.84,38.63 122.71,38.75 122.71,39.6 123.02,39.91 DM1.221
M_A_DQS_DP7: length 52
  L4 w0.152: v1(127.52,70.57) 127.52,70.58 127.7,70.77 127.9,70.77 128.26,70.41 129.46,68.94 134.46,63.95 134.46,46.04 130.58,42.17 130.58,41.33 129.01,39.77 129.01,37.83 128.56,35.72 128.2,35.36 128.01,35.36 127.88,35.49 127.88,35.67 127.76,35.79 v1(127.59,35.79)
  BOTTOM w0.089: 126.61,71.95 126.61,71.97 126.68,72.04 126.68,72.43 126.56,72.55 126.56,74.05 125.88,74.73 125.88,75.09 125.93,75.24 125.93,75.38 125.87,75.58 125.87,75.76 CPU1.BA26
  BOTTOM w0.191: 126.61,71.95 126.61,71.25 127.1,70.77 127.33,70.77 v1(127.52,70.57) ; v1(127.59,35.79) 127.74,35.79 128.3,35.23 128.3,34.2 128.18,34.07 128.18,33.5 128.27,33.4 DM1.242
M_A_PARITY: length 50.8
  L4 w0.089: v1(111.09,79.18) 110.95,79.18 110.82,79.31 110.82,79.76 110.95,79.89 111.5,79.89 111.63,79.76 111.63,79.61 111.65,79.59 111.65,77.63 111.95,77.33 111.95,77.15 111.6,76.8 111.6,76.48 112.28,75.8 112.28,75.68 112.18,75.58 112.18,75.46 112.39,75.25 112.51,75.25 112.61,75.35 112.73,75.35 112.93,75.15 112.93,75.03 112.62,74.72 112.62,74.59 112.82,74.38 112.95,74.38 113.25,74.68 113.4,74.68 113.6,74.48 113.6,73.54 113.72,73.41 114.15,73.41 114.27,73.28 114.27,66.69 114.56,66.4
  L4 w0.254: v1(103.59,42.9) 103.59,45.39 114.68,56.48 114.68,66.29 114.56,66.4
  BOTTOM w0.292: CPU1.AT52 111.06,79.18 v1(111.09,79.18) ; DM1.143 101.52,42.09 102.34,42.9 v1(103.59,42.9)
M_B_A0: length 73.8
  L2 w0.152: v1(112.97,67.66) 113.26,67.66 113.39,67.53 113.39,66.17 112.5,65.28 112.5,58.79 98.46,44.75 98.46,33.98 92.4,27.93 92.4,20.55 92.2,20.35 90.76,20.35 90.56,20.14 90.56,19.7 90.76,19.51 94.04,19.51 94.18,19.64 v1(94.18,20.89)
  BOTTOM w0.089: v1(112.97,67.66) 113.36,68.05 113.36,68.46 113.29,68.52 113.29,73.36 113.78,73.85 113.78,75.07 113.86,75.4 113.86,75.4 CPU1.BA46
  BOTTOM w0.292: v1(94.18,20.89) 93.77,20.48 DM2.144
M_B_A1: length 74.9
  L2 w0.152: v1(112.97,68.29) 112.35,67.67 112.35,66.17 111.61,65.43 111.61,59.99 111.33,59.71 111.11,59.71 110.91,59.91 110.69,59.91 110.47,59.7 110.47,59.48 110.68,59.27 110.68,59.06 110.46,58.84 110.25,58.84 110.04,59.05 109.83,59.05 109.61,58.83 109.61,58.62 109.82,58.41 109.82,58.2 109.6,57.98 109.39,57.98 109.18,58.19 108.97,58.19 108.75,57.97 108.75,57.76 108.95,57.55 108.95,57.33 104.67,53.05 104.67,52.83 104.9,52.6 104.9,52.38 104.69,52.17 104.47,52.17 104.24,52.4 104.02,52.4 103.81,52.18 103.81,51.97 104.04,51.74 104.04,51.52 103.82,51.3 103.61,51.3 103.37,51.54 103.16,51.54 102.94,51.32 102.94,51.11 103.18,50.87 103.18,50.66 102.96,50.44 102.75,50.44 102.51,50.68 102.3,50.68 102.08,50.46 102.08,50.24 102.31,50.01 102.31,49.79 102.1,49.58 101.88,49.58 101.65,49.81 101.43,49.81 101.22,49.6 101.22,49.38 101.45,49.15 101.45,48.93 101.24,48.72 101.02,48.72 100.79,48.95 100.57,48.95 100.35,48.73 100.35,48.52 100.59,48.28 100.59,48.07 100.37,47.85 100.16,47.85 99.92,48.09 99.71,48.09 99.49,47.87 99.49,47.66 99.73,47.42 99.73,47.21 99.51,46.99 99.29,46.99 99.06,47.23 98.85,47.23 98.63,47.01 98.63,46.79 98.86,46.56 98.86,46.34 98.65,46.13 98.43,46.13 98.2,46.36 97.98,46.36 97.77,46.15 97.77,45.93 98,45.7 98,45.48 97.79,45.27 97.57,45.27 97.34,45.5 97.12,45.5 96.83,45.21 96.83,44.5 96.68,44.35 96.27,44.35 96.12,44.2 96.12,43.89 96.27,43.74 96.68,43.74 96.83,43.59 96.83,43.28 96.68,43.13 96.27,43.13 96.12,42.98 96.12,42.67 96.27,42.52 96.68,42.52 96.83,42.37 96.83,38.93 96.83,33.53 91.49,28.19 v1(91.49,25.57)
  BOTTOM w0.089: CPU1.AY46 113.65,75.69 113.65,75.28 113.6,75.09 113.6,73.92 112.95,73.27 112.95,69.87
  BOTTOM w0.152: v1(112.97,68.29) 112.95,68.32 112.95,69.87
  BOTTOM w0.292: DM2.133 91.02,26.04 v1(91.49,25.57)
M_B_A2: length 75.1
  L2 w0.102: v1(111.17,67.86) 111.56,67.47 111.56,67.06 111.31,66.81 111.08,66.81 110.76,66.49 110.76,65.95
  L2 w0.152: 110.76,65.95 110.8,65.92 110.8,61.17 107.44,57.81 107.18,57.55 107.18,57.33 107.38,57.13 107.38,56.91 107.17,56.7 106.95,56.7 106.75,56.9 106.53,56.9 106.31,56.69 106.31,56.47 106.52,56.26 106.52,56.05 106.3,55.83 106.09,55.83 105.88,56.04 105.67,56.04 105.45,55.82 105.45,55.61 105.66,55.4 105.66,55.19 105.44,54.97 105.23,54.97 105.02,55.18 104.81,55.18 104.59,54.96 104.59,54.74 104.79,54.54 104.79,54.32 104.58,54.11 104.36,54.11 104.16,54.31 103.94,54.31 103.73,54.1 103.73,53.88 103.93,53.68 103.93,53.46 103.72,53.25 103.5,53.25 103.3,53.45 103.08,53.45 102.86,53.23 102.86,53.02 103.07,52.81 103.07,52.6 102.85,52.38 102.64,52.38 102.43,52.59 102.22,52.59 102,52.37 102,52.16 102.21,51.95 102.21,51.74 95.31,44.84 95.31,33.68 95.05,33.43 94.77,33.43 94.59,33.25 94.59,33.04 94.69,32.94 94.69,32.72 94.47,32.51 94.26,32.51 94.16,32.61 93.94,32.61 93.73,32.39 93.73,32.18 93.83,32.08 93.83,31.86 93.61,31.65 93.4,31.65 93.3,31.74 93.08,31.74 92.79,31.46 92.79,30.71 90.89,28.81 90.47,28.81 90.27,28.6 90.27,23.12 v1(91.79,21.6)
  BOTTOM w0.089: CPU1.AY47 113.01,76.16 113.01,75.73 112.94,75.41 112.94,75.2 112.97,75.07 112.97,74.64 112.58,74.25 112.58,70.47 112.26,70.15
  BOTTOM w0.152: v1(111.17,67.86) 112.26,68.96 v2(112.26,69.72) 112.26,70.15
  BOTTOM w0.292: v1(91.79,21.6) 91.75,21.6 90.77,20.63 DM2.132
M_B_A3: length 74.2
  L2 w0.152: v1(91.59,24.3) 91.97,24.68 91.97,28.1 97.24,33.36 97.24,39.46 97.39,39.61 97.9,39.61 98.05,39.76 98.05,40.07 97.9,40.22 97.39,40.22 97.24,40.37 97.24,40.67 97.39,40.83 97.9,40.83 98.05,40.98 98.05,41.28 97.9,41.44 97.39,41.44 97.24,41.59 97.24,41.89 97.39,42.05 97.9,42.05 98.05,42.2 98.05,42.5 97.9,42.66 97.39,42.66 97.24,42.81 97.24,44.14 105.61,52.52 105.61,52.73 105.38,52.97 105.38,53.18 105.59,53.4 105.81,53.4 106.04,53.16 106.26,53.16 106.47,53.38 106.47,53.59 106.24,53.83 106.24,54.04 106.46,54.26 106.67,54.26 106.9,54.03 107.12,54.03 107.34,54.24 107.34,54.46 107.1,54.69 107.1,54.91 107.32,55.12 107.53,55.12 107.77,54.89 107.98,54.89 108.2,55.1 108.2,55.32 107.96,55.55 107.96,55.77 108.18,55.98 108.4,55.98 108.63,55.75 108.85,55.75 109.06,55.97 109.06,56.18 108.83,56.42 108.83,56.63 109.04,56.85 109.26,56.85 109.49,56.61 109.71,56.61 109.92,56.83 109.92,57.04 109.69,57.28 109.69,57.49 109.91,57.71 110.12,57.71 110.35,57.48 110.57,57.48 110.79,57.69 110.79,57.91 110.55,58.14 110.55,58.36 110.77,58.57 110.98,58.57 111.22,58.34 111.43,58.34 112.1,59 112.1,65.33 112.97,66.21 v1(112.97,67.02)
  BOTTOM w0.089: CPU1.BB46 113.95,74.9 113.95,73.77 113.47,73.29 113.47,70.01 113.6,69.88
  BOTTOM w0.216: v1(112.97,67.02) 112.98,67.02 113.77,67.81 v2(113.77,68.55) 113.6,68.71 113.6,69.88
  BOTTOM w0.292: DM2.131 90.52,25.05 91.28,24.3 v1(91.59,24.3)
M_B_A4: length 74.4
  L2 w0.152: v1(89.92,21.3) 89.92,20.49 89.79,20.36 89.39,20.36 89.26,20.49 89.26,22.46 89.81,23.01 89.81,29.05 94.9,34.14 94.9,34.25 94.9,34.25 94.9,34.97 94.9,34.98 94.9,45.01 97.13,47.23 97.13,47.45 96.92,47.65 96.92,47.87 97.14,48.09 97.35,48.09 97.56,47.88 97.78,47.88 97.99,48.1 97.99,48.31 97.79,48.52 97.79,48.73 98,48.95 98.22,48.95 98.42,48.74 98.64,48.74 98.85,48.96 98.85,49.17 98.65,49.38 98.65,49.59 98.86,49.81 99.08,49.81 99.29,49.6 99.5,49.6 99.72,49.82 99.72,50.04 99.51,50.24 99.51,50.46 99.73,50.67 99.94,50.67 100.15,50.47 100.36,50.47 100.58,50.68 100.58,50.9 100.37,51.1 100.37,51.32 100.59,51.54 100.81,51.54 101.01,51.33 101.23,51.33 101.44,51.55 101.44,51.76 101.24,51.97 101.24,52.18 109.79,60.74 109.79,60.98 109.38,61.39 109.38,61.64 109.55,61.81 110.27,61.81 110.4,61.94 110.4,66.9 110.73,67.23 v1(111.17,67.23)
  BOTTOM w0.089: 112.56,69.32 112.67,69.44 112.67,70.28 112.76,70.36 112.76,74.17 113.15,74.57 113.15,75.1 113.11,75.23 113.11,75.39 113.19,75.69 CPU1.BA47
  BOTTOM w0.152: 112.56,69.32 112.56,68.61 v1(111.17,67.23)
  BOTTOM w0.292: DM2.128 89.77,21.16 v1(89.92,21.3)
M_B_A5: length 75
  L2 w0.152: v1(111.17,68.52) 111.78,67.91 111.78,66.03 111.21,65.46 111.21,61 107.85,57.64 107.85,57.64 107.79,57.58 107.79,56.74 95.71,44.67 95.71,41.62 95.87,41.47 96.22,41.47 96.37,41.32 96.37,41.01 96.22,40.86 95.87,40.86 95.71,40.71 95.71,40.4 95.87,40.25 96.22,40.25 96.37,40.1 96.37,39.79 96.22,39.64 95.87,39.64 95.71,39.49 95.71,39.18 95.87,39.03 96.22,39.03 96.37,38.88 96.37,38.57 96.22,38.42 95.87,38.42 95.71,38.27 95.71,37.96 95.87,37.81 96.22,37.81 96.37,37.66 96.37,33.71 90.88,28.21 90.83,28.21 90.68,28.06 90.68,27.76 90.83,27.6 90.88,27.6 91.03,27.45 91.03,27.15 90.88,26.99 90.83,26.99 90.68,26.84 90.68,26.54 90.83,26.38 90.88,26.38 91.03,26.23 91.03,25.93 90.88,25.77 90.83,25.77 90.68,25.62 90.68,25.32 90.83,25.16 90.88,25.16 91.03,25.01 91.03,24.71 90.88,24.56 90.83,24.56 90.68,24.4 90.68,24.1 90.83,23.95 90.88,23.95 91.03,23.79 91.03,23.54 v1(91.62,22.96)
  BOTTOM w0.089: CPU1.AY48 112.47,76.01 112.26,75.16 112.26,74.72 111.98,74.44 111.98,71.44 111.66,71.11 111.02,71.11 110.64,70.73 110.64,69.6 110.4,69.36 110.4,68.65 v2(110.53,68.52) v1(111.17,68.52)
  BOTTOM w0.292: DM2.126 89.27,21.25 89.31,21.29 89.31,22.23 90.04,22.96 v1(91.62,22.96)
M_B_A6: length 74.4
  L2 w0.152: v1(111.17,69.79) 110.66,69.79 110.51,69.64 110.51,68.01 109.79,67.29 109.79,62.7 108.83,61.74 108.83,61.33 109.22,60.94 109.22,60.74 108.96,60.49 108.75,60.49 108.27,60.97 108.05,60.97 107.84,60.75 107.84,60.54 108.32,60.05 108.32,59.84 108.1,59.62 107.89,59.62 107.4,60.11 107.19,60.11 106.97,59.89 106.97,59.67 107.46,59.19 107.46,58.98 107.24,58.76 107.02,58.76 106.54,59.24 106.33,59.24 106.11,59.03 106.11,58.81 106.52,58.4 106.52,58.04 96.1,47.62 96.1,47.41 96.31,47.2 96.31,46.99 96.09,46.77 95.88,46.77 95.67,46.98 95.46,46.98 95.24,46.76 95.24,46.55 95.45,46.34 95.45,46.13 95.23,45.91 95.02,45.91 94.81,46.12 94.59,46.12 94.31,45.83 94.31,41.54 94.5,41.35 94.5,40.54 93.86,39.91 93.86,35.09 94.01,34.94 94.34,34.94 94.46,34.82 94.46,34.39 94.3,34.22 93.99,34.22 93.86,34.09 93.86,33.69 93.84,33.67 93.84,33.66 89.4,29.23 89.4,24.17 v1(89.23,23.99)
  BOTTOM w0.089: v1(111.17,69.79) 110.96,69.79 110.83,69.92 110.83,70.61 111.11,70.89 111.36,70.89 111.62,70.63 112.07,70.63 112.19,70.76 112.19,74.4 112.44,74.64 112.44,75.09 112.48,75.28 CPU1.BA48
  BOTTOM w0.292: DM2.127 89.52,24.29 v1(89.23,23.99)
M_B_A7: length 76.1
  L2 w0.102: 112.02,75.92 112.47,76.37 112.47,79.98 v1(112.02,80.43)
  L2 w0.152: v1(88.27,20.97) 88.27,21.75 88.68,22.16 88.68,24.26 88.49,24.46 88.49,29.57 93.02,34.1 93.02,39.6 92.72,39.9 92.72,45.4 100.57,53.24 100.57,53.46 100.09,53.94 100.09,54.16 100.3,54.37 100.52,54.37 101,53.89 101.22,53.89 101.43,54.1 101.43,54.32 100.95,54.8 100.95,55.02 101.17,55.23 101.38,55.23 101.86,54.75 102.08,54.75 102.3,54.97 102.3,55.18 101.81,55.67 101.81,55.88 108.68,62.75 108.68,66.92 108.51,67.08 108.51,71.02 111.39,73.89 111.39,75.29 112.02,75.92
  BOTTOM w0.216: v1(112.02,80.43) 112.09,80.43 CPU1.AP48
  BOTTOM w0.292: v1(88.27,20.97) 88.27,20.96 DM2.122
M_B_A8: length 71.5
  L2 w0.152: v1(111.22,70.45) 111.22,70.83 110.9,71.15 109.38,71.15 109.2,70.97 109.2,70.72 109.38,70.54 109.38,65.81 109.18,65.61 109.18,64.62 109.38,64.42 109.38,62.87 105.36,58.85 105.36,58.64 105.84,58.15 105.84,57.94 105.63,57.72 105.41,57.72 104.93,58.2 104.71,58.2 104.5,57.99 104.5,57.77 104.98,57.29 104.98,57.07 104.76,56.86 104.55,56.86 104.06,57.34 103.85,57.34 103.63,57.13 103.63,56.91 104.12,56.43 104.12,56.21 103.9,56 103.69,56 103.2,56.48 102.99,56.48 102.77,56.26 102.77,56.05 103.25,55.57 103.25,55.35 93.8,45.89 93.8,45.23 93.64,45.08 93.28,45.08 93.13,44.92 93.13,44.62 93.28,44.47 93.64,44.47 93.8,44.31 93.8,41.86 93.64,41.71 93.28,41.71 93.13,41.56 93.13,41.25 93.28,41.1 93.64,41.1 93.8,40.95 93.8,40.63 93.45,40.29 93.45,33.86 88.95,29.35 v1(88.95,25.61)
  BOTTOM w0.089: v1(111.22,70.45) 112.16,70.45 112.4,70.69 112.4,74.32 112.71,74.63 CPU1.BB48
  BOTTOM w0.292: v1(88.95,25.61) 89.02,25.69 DM2.125
M_B_A9: length 71.8
  L2 w0.102: 110.86,76.74 110.86,76.92 111.44,77.5 111.44,78.3 111.47,78.34 111.47,78.89 111.49,78.9 111.49,79.34 111.09,79.74 v1(111.09,80.29)
  L2 w0.152: 110.86,76.74 110.86,74.51 107.83,71.48 107.83,63.05 97.01,52.23 97.01,50.87 91.91,45.77 91.91,45.45 91.67,45.2 91.67,33.9 87.65,29.89 v1(87.65,23.36)
  BOTTOM w0.216: CPU1.AP50 111.37,80.05 111.13,80.29 v1(111.09,80.29)
  BOTTOM w0.292: v1(87.65,23.36) 87.99,23.7 87.99,26.01 88.02,26.05 DM2.121
M_B_A10: length 75.1
  L2 w0.102: 115.76,65.79 115.62,65.93 115.62,68.32 115.03,68.91 115.03,71.6 114.43,72.19 114.43,73.51 114.31,73.64 113.98,73.64 113.86,73.51 v1(113.86,73.01)
  L2 w0.152: 115.76,65.79 116.47,65.08 116.47,57.19 110.64,51.36 110.64,51.11 111.4,50.35 111.4,50.17 111.15,49.92 110.97,49.92 110.18,50.71 110,50.71 109.71,50.43 109.71,49.98 110.32,49.37 110.32,49.15 104.86,43.69 104.86,41.4 103.49,40.03 103.49,33.44 101.15,31.11 101.15,30.27 97.85,26.96 97.4,26.96 97.16,26.72 97.16,24.25 97.41,24 97.41,22.51 97.65,22.26 97.65,22.08 97.4,21.83 97.22,21.83 96.89,22.17 v1(96.77,22.17)
  BOTTOM w0.089: v1(113.86,73.01) 114.14,73.29 114.14,74.66 114.15,74.68 114.3,74.83 114.3,75.79 114.25,75.88 114.25,76.3 114.14,76.64 CPU1.AW46
  BOTTOM w0.292: DM2.146 96.27,19.94 95.37,20.85 95.37,22.25 95.6,22.48 96.07,22.48 96.2,22.35 96.59,22.35 v1(96.77,22.17)
M_B_A11: length 76.7
  L2 w0.102: v1(112.01,81.09) 111.62,80.7 111.62,79.6 111.68,79.55 111.68,78.83 111.66,78.81 111.66,78.26 111.66,78.26 111.66,78.21 111.63,78.17 111.63,77.36 111.1,76.83
  L2 w0.152: 111.1,76.83 111.1,74.14 108.27,71.31 108.27,62.92 99.36,54 99.36,53.59 99.73,53.22 99.73,53.01 99.51,52.79 99.29,52.79 98.93,53.16 98.71,53.16 98.49,52.94 98.49,52.73 98.86,52.36 98.86,52.14 98.65,51.93 98.43,51.93 98.06,52.3 97.85,52.3 97.63,52.08 97.63,51.87 98,51.5 98,51.28 92.32,45.6 92.32,44.59 92.07,44.35 92.07,43.98 92.32,43.74 92.32,43.37 92.07,43.13 92.07,42.76 92.32,42.52 92.32,42.15 92.07,41.91 92.07,41.55 92.32,41.3 92.32,39.73 92.62,39.43 92.62,34.27 88.08,29.74 88.08,23.69 88.23,23.55 v1(88.23,22.35)
  BOTTOM w0.216: v1(112.01,81.09) 112.24,81.09 112.47,80.86 CPU1.AN48
  BOTTOM w0.292: v1(88.23,22.35) 88.23,21.91 88.1,21.78 87.83,21.78 87.7,21.65 87.7,20.79 87.77,20.72 DM2.120
M_B_A12: length 76.4
  L2 w0.102: v1(111.12,81.08) 110.76,81.44 110.05,81.44 109.68,81.07 109.68,80.92 108.83,80.06 108.83,78.24 109.03,78.04 109.03,75.69
  L2 w0.152: v1(86.38,22.96) 86.27,22.96 85.06,24.17 85.06,25.07 84.56,25.56 84.56,29.21 88.8,33.44 89.33,34.83 89.33,46.85 105.32,62.83 105.32,65.99 105.87,68.08 105.87,71.81 108.01,73.94 109.03,75.69
  BOTTOM w0.216: CPU1.AN50 111.18,81.08 v1(111.12,81.08)
  BOTTOM w0.292: v1(86.38,22.96) 86.39,22.96 87.52,24.09 DM2.119
M_B_A13: length 72.5
  L2 w0.102: 118.09,65.54 116.4,67.22 116.4,71.53 v1(115.61,72.33)
  L2 w0.152: 118.09,65.54 118.09,54.56 113,49.47 113,48.27 111.38,46.65 111.2,46.65 110.78,47.06 110.59,47.06 110.26,46.73 110.26,46.53 110.57,46.21 110.57,46 110.36,45.78 110.14,45.78 109.84,46.09 109.61,46.09 109.4,45.87 109.4,45.65 109.79,45.27 109.79,45.05 109.57,44.84 109.35,44.84 108.97,45.22 108.75,45.22 108.54,45.01 108.54,44.79 108.92,44.41 108.92,44.19 108.71,43.97 108.49,43.97 108.1,44.36 107.89,44.36 107.67,44.15 107.67,43.93 108.06,43.54 108.06,43.33 107.84,43.11 107.63,43.11 107.24,43.5 107.03,43.5 106.74,43.21 106.74,33.55 99.29,26.11 99.29,23.91 99.26,23.88 99.26,23.87 98.84,23.45 98.84,21.45 v1(99.32,20.98)
  BOTTOM w0.089: CPU1.BA43 115.54,75.69 115.47,75.39 115.47,75.23 115.5,75.1 115.5,74.71 115.21,74.39 115.19,74.37 115.19,72.75 v1(115.61,72.33)
  BOTTOM w0.292: DM2.158 99.27,20.94 v1(99.32,20.98)
M_B_A14: length 75.8
  L2 w0.102: 117.28,65.24 116.01,66.51 116.01,70.02 v1(115.61,70.42)
  L2 w0.152: 117.28,65.24 117.28,56.74 116.25,55.7 116.25,55.49 116.95,54.79 116.95,54.57 116.73,54.36 116.52,54.36 115.81,55.06 115.6,55.06 115.38,54.84 115.38,54.63 116.09,53.92 116.09,53.71 115.87,53.49 115.66,53.49 114.95,54.2 114.74,54.2 114.52,53.98 114.52,53.76 115.22,53.06 115.22,52.85 115.01,52.63 114.79,52.63 114.09,53.33 113.87,53.33 113.66,53.12 113.66,52.9 114.36,52.2 114.36,51.98 114.15,51.77 113.93,51.77 113.23,52.47 113.01,52.47 112.8,52.25 112.8,52.04 113.5,51.34 113.5,51.12 113.28,50.91 113.07,50.91 112.36,51.61 112.15,51.61 111.86,51.32 111.86,51.08 112.34,50.6 112.34,49.96 105.67,43.29 105.67,41.06 105.14,40.53 105.14,33.86 104.3,33.03 104.3,32.26 98.48,26.44 98.48,25.2 v1(98.07,24.78)
  BOTTOM w0.089: v1(115.61,70.42) v2(114.9,70.42) 114.77,70.55 114.77,70.73 115.01,70.97 115.01,74.44 115.08,74.51 115.33,74.78 115.33,75.07 115.29,75.2 115.29,75.41 115.37,75.73 115.37,75.89 CPU1.AY44
  BOTTOM w0.292: DM2.151 97.53,25.98 97.5,25.95 97.5,25.51 97.53,25.49 97.53,25.32 v1(98.07,24.78)
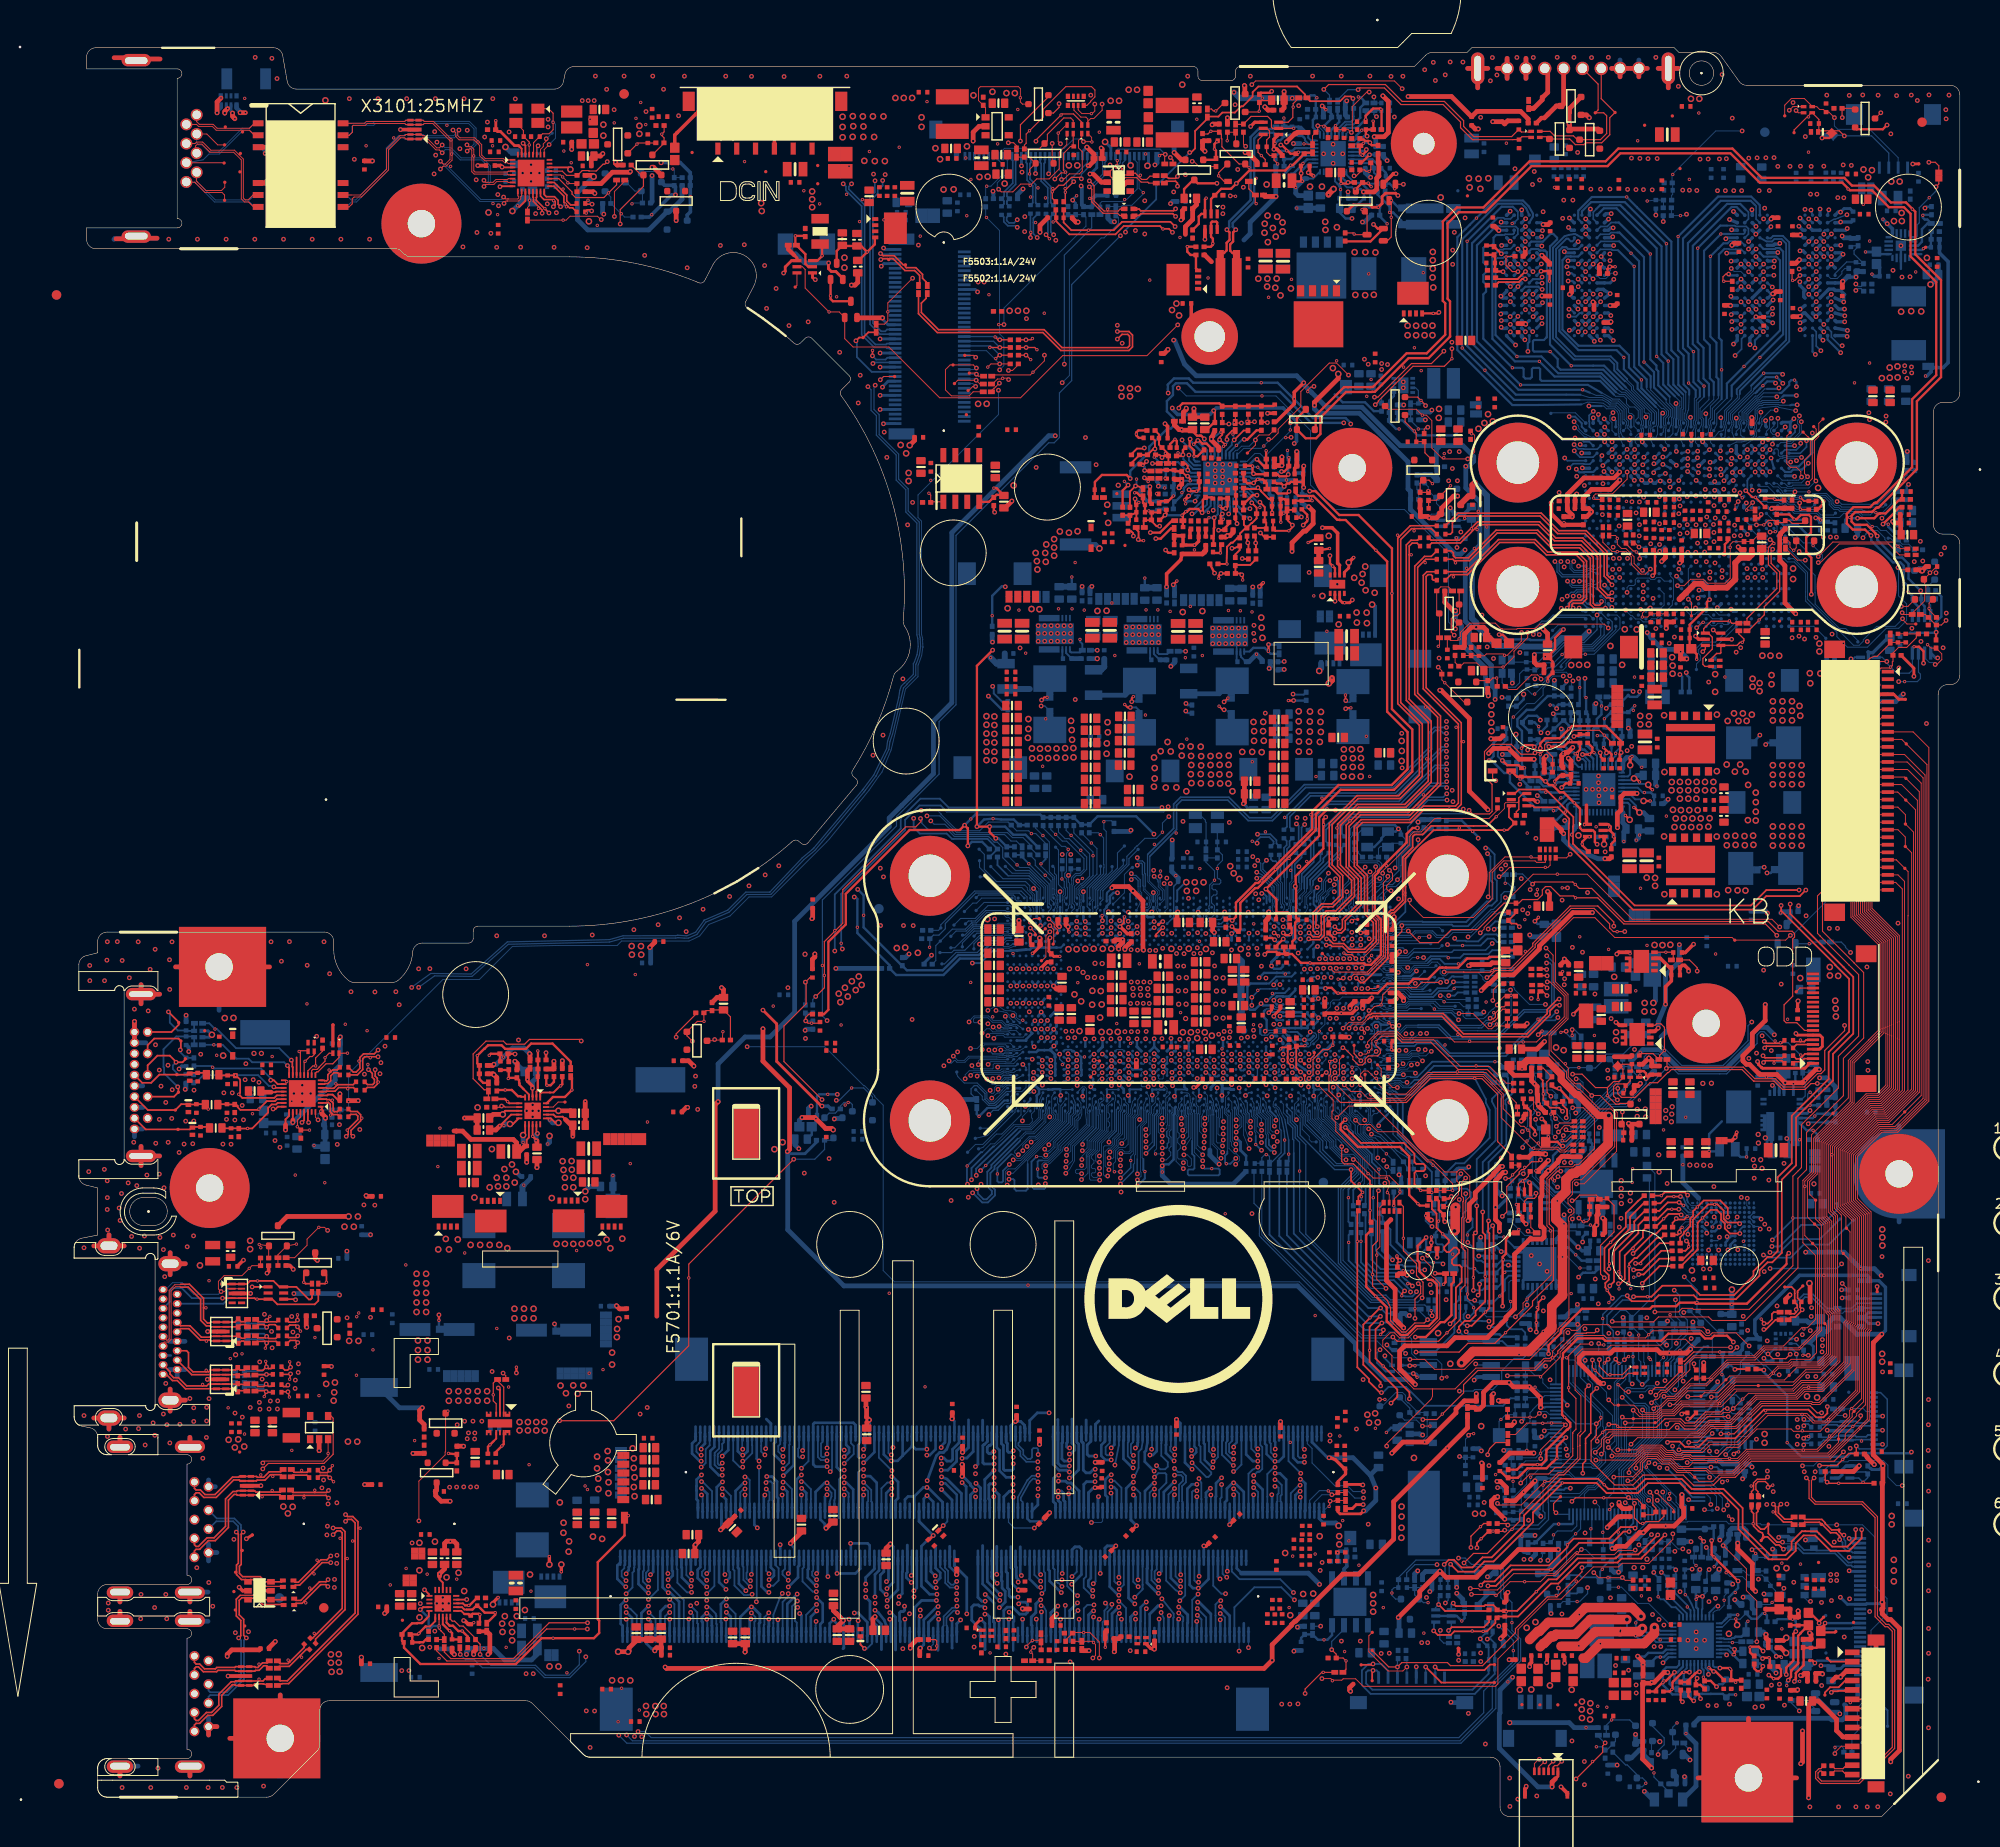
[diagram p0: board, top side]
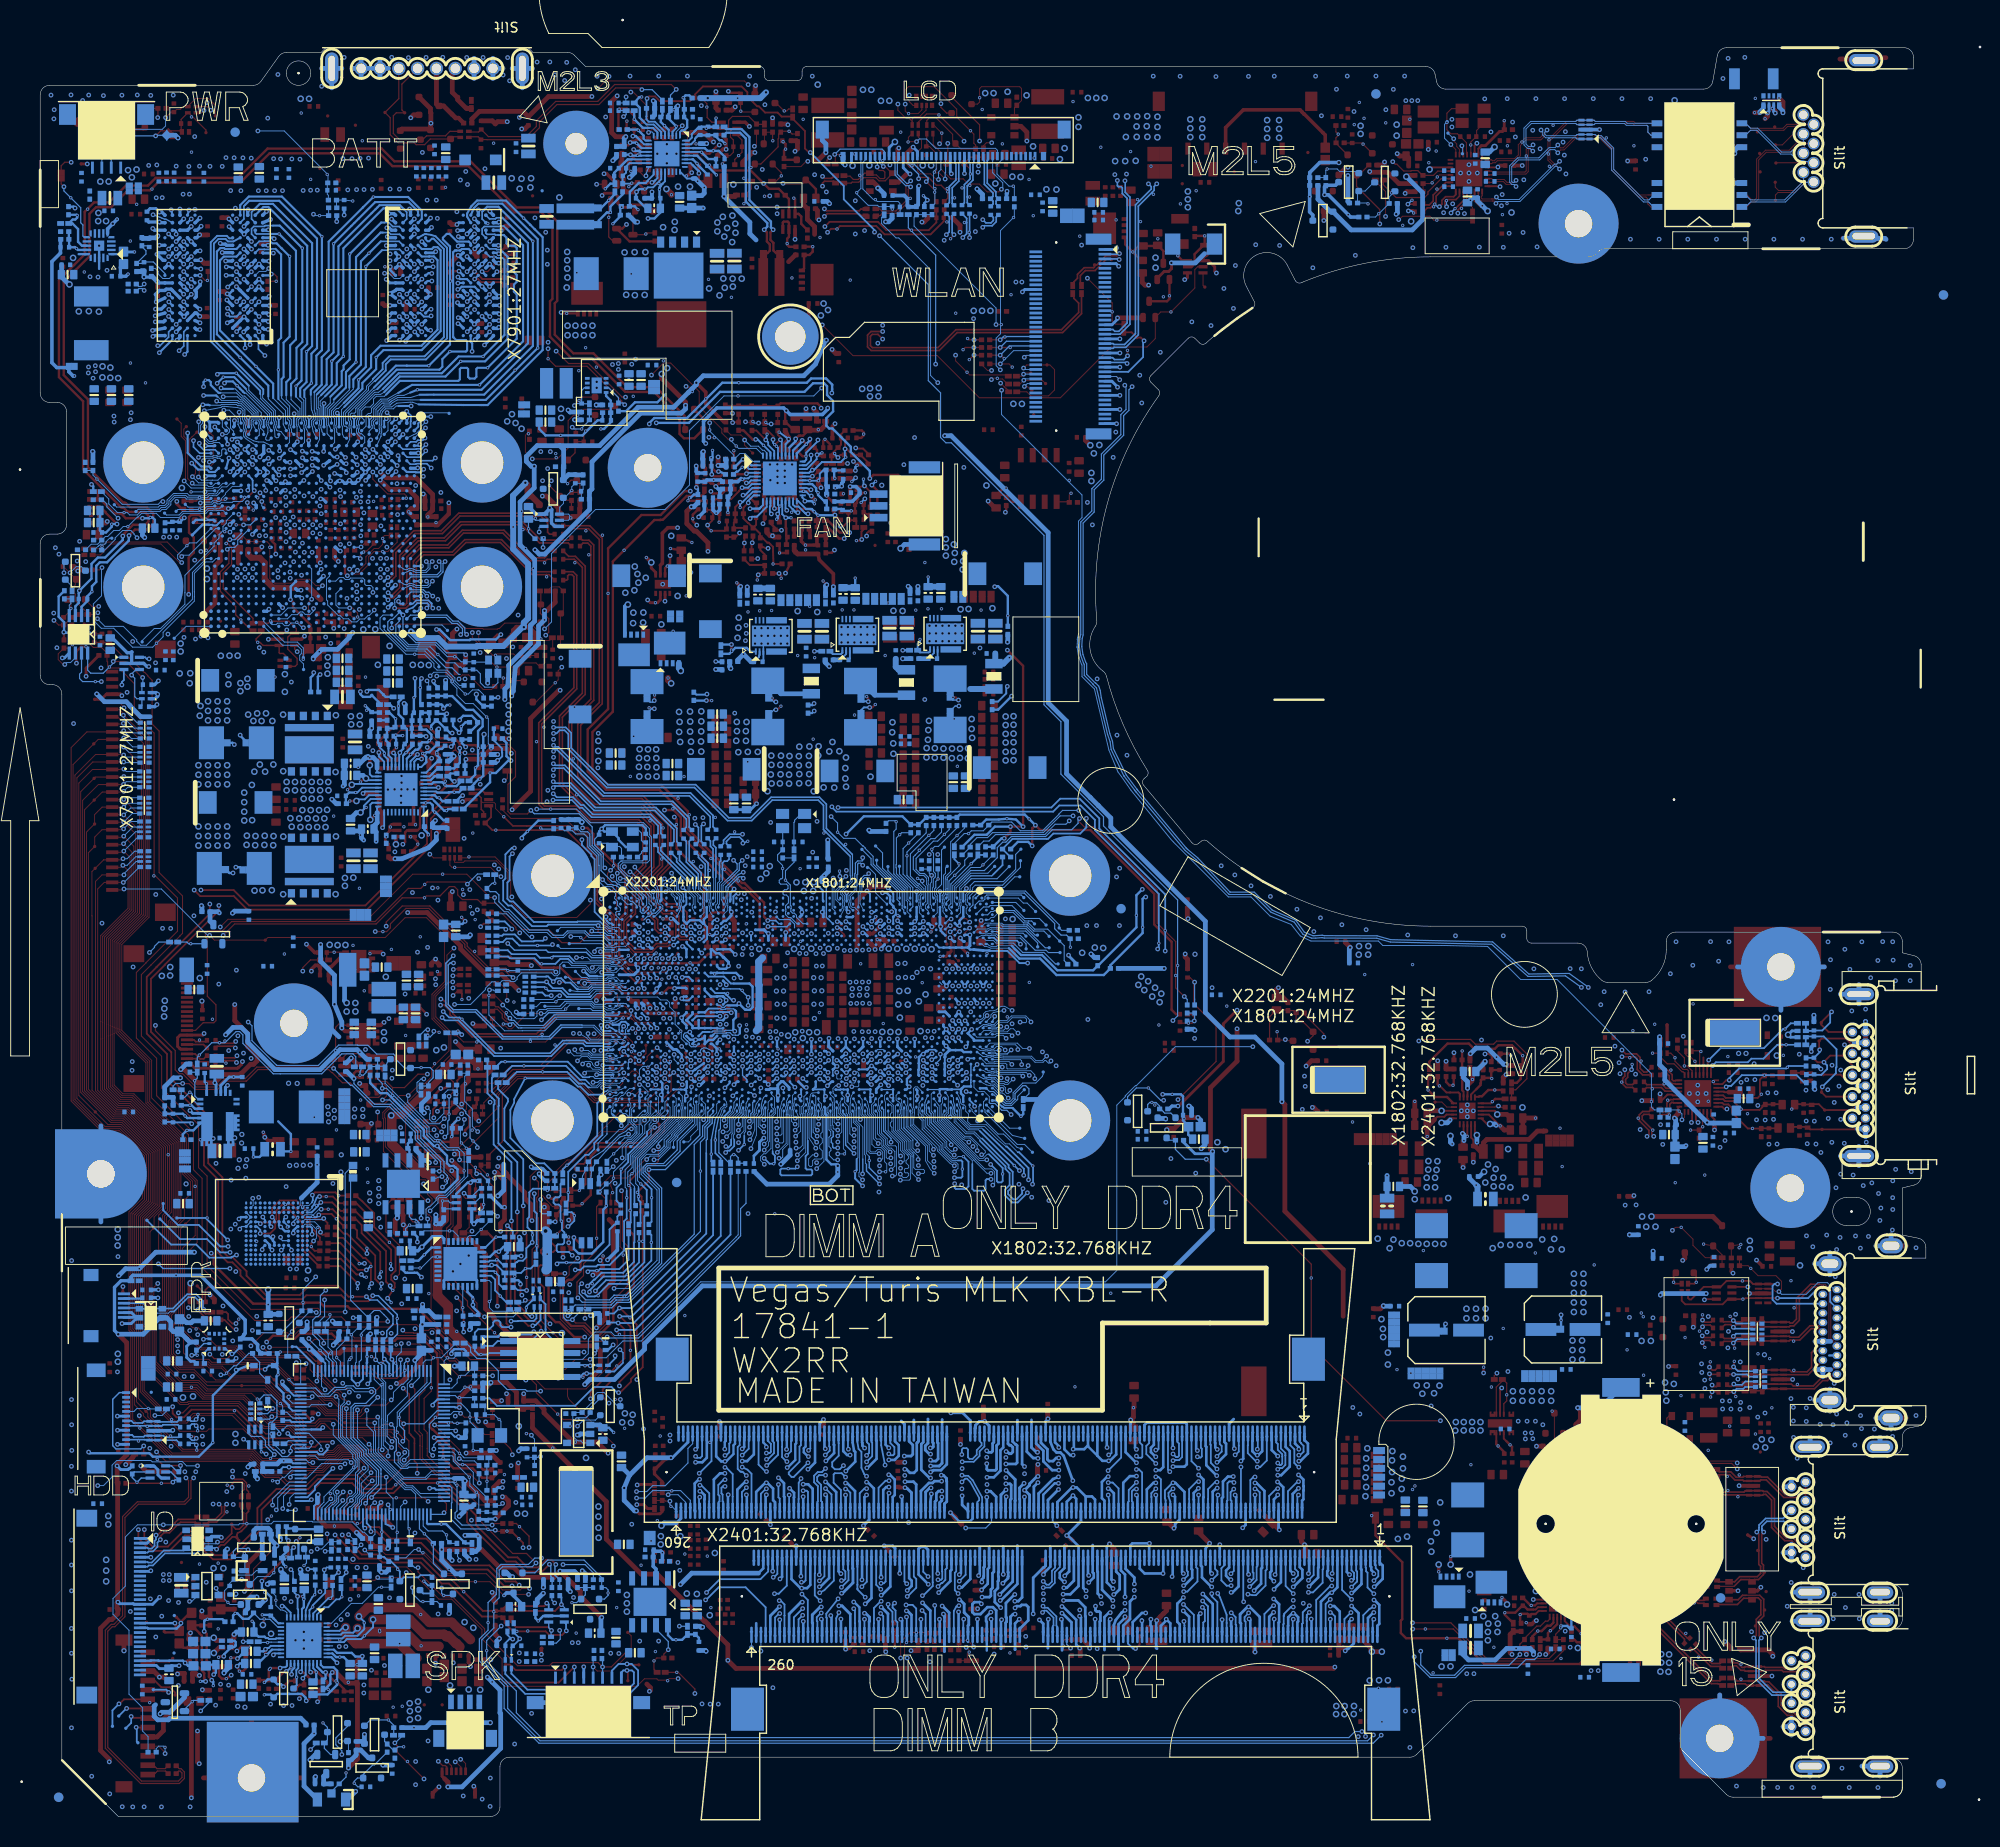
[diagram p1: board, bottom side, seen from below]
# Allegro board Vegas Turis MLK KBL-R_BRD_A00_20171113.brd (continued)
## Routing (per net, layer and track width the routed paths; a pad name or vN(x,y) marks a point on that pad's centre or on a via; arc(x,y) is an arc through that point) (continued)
M_B_A15: length 75.7
  L2 w0.102: 119.31,65.72 116.97,68.06 116.97,71.81 116.84,71.95 116.84,73.08 116.32,73.59 116.32,75.3 115.93,75.69 115.93,76.05 115.4,76.58 115.4,77.32 115.51,77.43 v1(115.51,77.69)
  L2 w0.152: 119.31,65.72 119.31,64.3 119.31,64.3 119.31,53.7 118.61,52.99 118.61,52.78 118.82,52.57 118.82,52.35 118.6,52.14 118.39,52.14 118.18,52.35 117.96,52.35 117.74,52.13 117.74,51.91 117.95,51.7 117.95,51.49 117.74,51.27 117.52,51.27 117.31,51.48 117.1,51.48 116.88,51.27 116.88,51.05 117.09,50.84 117.09,50.63 109.12,42.65 109.11,42.65 108.84,42.39 108.84,42.38 108.52,42.05 108.52,39.35 107.96,38.79 107.96,32.99 107.72,32.75 101.53,26.57 101.53,23.78 v1(100.35,22.6)
  BOTTOM w0.089: v1(115.51,77.69) 115.82,77.69 116.12,77.39 116.12,77.07 116.11,77.06 116.11,76.89 CPU1.AY43
  BOTTOM w0.292: v1(100.35,22.6) 100.53,22.78 101.1,22.78 101.31,22.57 101.31,21.71 101.1,21.5 100.45,21.5 99.71,22.24 99.13,22.24 98.77,21.89 DM2.156
M_B_A16: length 73.8
  L2 w0.102: v1(113.88,72.38) 114.83,71.42 114.83,68.83 115.4,68.26 115.4,65.71 115.55,65.56
  L2 w0.152: 115.55,65.56 116.06,65.05 116.06,57.35 109.05,50.34 109.05,50.07 109.75,49.37 109.75,49.15 109.53,48.94 109.31,48.94 108.62,49.63 108.4,49.63 108.18,49.42 108.18,49.2 108.88,48.5 108.88,48.29 104.45,43.86 104.45,41.57 103.08,40.2 103.08,33.61 100.28,30.81 100.28,30.59 100.48,30.39 100.48,30.17 100.27,29.96 100.05,29.96 99.85,30.16 99.63,30.16 99.41,29.95 99.41,29.73 99.62,29.53 99.62,29.31 99.4,29.09 99.19,29.09 98.98,29.3 98.77,29.3 98.55,29.08 98.55,28.87 98.76,28.66 98.76,28.45 98.54,28.23 98.33,28.23 98.12,28.44 97.91,28.44 97.69,28.22 97.69,28 97.89,27.8 97.89,27.59 97.68,27.37 97.46,27.37 97.26,27.57 97.04,27.57 96.75,27.29 96.75,23.64 v1(96.8,23.59)
  BOTTOM w0.089: v1(113.88,72.38) 114.15,72.38 114.33,72.56 114.33,74.61 114.48,74.76 114.48,75.48 114.87,75.87 114.87,76.42 115.16,76.71 CPU1.AW44
  BOTTOM w0.292: v1(96.8,23.59) 96.83,23.59 97.74,22.68 97.74,21.19 97.68,21.12 97.68,20.69 97.77,20.59 DM2.152
M_B_ACT_N: length 75.8
  L2 w0.102: 107.4,75.54 107.68,75.82 107.68,75.84 108.41,76.57 108.41,77.83 107.8,78.51 107.59,78.72 107.59,80.63 107.8,80.84 108.02,81.23 108.23,81.44 108.64,81.44 v1(109.24,81.03)
  L2 w0.152: 107.4,75.54 104.57,72.71 104.09,70.77 104.09,63.78 87.88,47.58 87.88,35 87.5,33.87 83.26,29.63 83.26,25.07 83.52,23.24 83.57,23.09 v1(85.09,21.92)
  BOTTOM w0.292: v1(85.09,21.92) 85.46,21.66 86.07,20.88 86.27,20.34 DM2.114 ; CPU1.AN53 v1(109.24,81.03)
M_B_ALERT_N: length 78.7
  L2 w0.102: v1(114.75,81.07) 114.28,81.54 111.91,81.54 111.51,81.15 111.51,80.91 111.28,80.68 110.93,80.68 110.68,80.43 110.68,77.96 110.64,77.93 110.64,77.59 110.57,77.36
  L2 w0.152: 110.57,77.36 110.57,74.78 107.56,71.77 107.56,67.33 107.3,67.07 107.3,63.09 96.6,52.4 96.6,51.03 91.09,45.52 91.09,45.12 90.94,44.96 90.79,44.96 90.64,44.81 90.64,44.51 90.79,44.35 90.94,44.35 91.09,44.2 91.09,43.9 90.94,43.74 90.79,43.74 90.64,43.59 90.64,43.29 90.79,43.13 90.94,43.13 91.09,42.98 91.09,42.68 90.94,42.52 90.79,42.52 90.64,42.37 90.64,42.07 90.79,41.91 90.94,41.91 91.09,41.76 91.09,41.46 90.94,41.31 90.79,41.31 90.64,41.15 90.64,40.85 90.79,40.7 90.94,40.7 91.09,40.54 91.09,33.93 87.25,30.09 87.25,30.06 87.25,30.05 87.25,23.81 87.12,23.67 87.12,21.47 86.99,21.35 v1(86.66,20.96)
  BOTTOM w0.292: CPU1.AN43 v1(114.75,81.07) ; DM2.116 86.77,20.85 v1(86.66,20.96)
M_B_BA0: length 74
  L2 w0.102: 115.12,65.1 114.99,65.23 114.99,68.13 114.45,68.67 114.45,70.35 114.33,70.47 v1(113.88,70.47)
  L2 w0.152: v1(96.77,21.5) 95.93,22.33 95.93,27.61 101.51,33.19 101.51,40.72 102.44,41.66 103.35,41.66 103.5,41.81 103.5,42.11 103.35,42.27 102.48,42.27 102.35,42.4 102.35,43.1 102.47,43.23 103.22,43.23 103.37,43.38 103.37,43.69 103.22,43.84 102.47,43.84 102.35,43.97 102.35,44.79 102.64,45.08 102.85,45.08 103.58,44.35 103.8,44.35 104.01,44.57 104.01,44.78 103.28,45.51 103.28,45.73 103.5,45.94 103.71,45.94 104.44,45.21 104.66,45.21 104.87,45.43 104.87,45.64 104.17,46.35 104.17,46.62 115.25,57.69 115.25,64.98 115.12,65.1
  BOTTOM w0.152: CPU1.BB44 115.07,74.81 114.93,74.65 114.77,74.5 114.77,71.36 v1(113.88,70.47)
  BOTTOM w0.292: DM2.150 97.27,20.5 97.26,20.51 97.26,21.23 96.99,21.5 v1(96.77,21.5)
M_B_BA1: length 75
  L2 w0.102: v1(113.88,71.11) 114.12,71.11 114.64,70.59 114.64,68.75 115.2,68.2 115.2,65.51 115.37,65.33
  L2 w0.152: v1(96.8,22.88) 96.34,23.34 96.34,27.45 101.91,33.02 101.91,40.52 102.45,41.05 103.36,41.05 104.05,41.74 104.05,44.03 105.61,45.59 105.61,45.81 105.06,46.36 105.06,46.54 105.32,46.79 105.5,46.79 106.04,46.24 106.26,46.24 106.48,46.46 106.48,46.67 105.75,47.4 105.75,47.61 105.96,47.83 106.18,47.83 106.91,47.1 107.12,47.1 107.34,47.32 107.34,47.53 106.61,48.26 106.61,48.48 106.83,48.69 107.04,48.69 107.77,47.97 107.98,47.97 108.2,48.18 108.2,48.4 107.47,49.12 107.47,49.34 115.65,57.52 115.65,65.05 115.37,65.33
  BOTTOM w0.089: CPU1.BA44 114.81,75.38 114.72,75.11 114.72,74.74 114.56,74.58 114.55,74.53 114.55,71.67 113.99,71.11 v1(113.88,71.11)
  BOTTOM w0.292: v1(96.8,22.88) 96.43,22.88 96.02,23.29 DM2.145
M_B_BG0: length 75.3
  L2 w0.102: 110.29,75.44 110.29,77.04 109.82,77.52 109.82,78.21 109.81,78.21 109.81,79.2 109.82,79.21 109.82,80.15 110.03,80.35 v1(110.22,80.35)
  L2 w0.152: v1(86.31,24.96) 85.5,25.77 85.5,28.96 90.14,33.6 90.14,45.28 93.53,48.67 93.53,48.88 93.13,49.28 93.13,49.5 93.35,49.71 93.56,49.71 93.96,49.32 94.17,49.32 94.39,49.53 94.39,49.75 93.99,50.14 93.99,50.36 94.21,50.57 94.42,50.57 94.82,50.18 95.03,50.18 95.25,50.39 95.25,50.61 94.85,51.01 94.85,51.22 95.07,51.44 95.29,51.44 95.68,51.04 95.9,51.04 96.11,51.26 96.11,51.47 95.72,51.87 95.72,52.08 106.56,62.93 106.56,63.67 106.76,63.88 106.76,64.39 106.56,64.59 106.56,64.89 106.87,65.2 106.87,65.5 106.56,65.81 106.56,66.11 106.87,66.42 106.87,66.72 106.56,67.03 106.56,71.66 107.39,72.49 107.72,72.49 107.99,72.75 107.99,73.08 108.26,73.35 108.59,73.35 108.85,73.62 108.85,73.95 109.12,74.21 109.45,74.21 109.72,74.48 109.72,74.81 110.16,75.25 110.29,75.44
  BOTTOM w0.292: v1(110.22,80.35) 110.34,80.35 CPU1.AP52 ; DM2.115 86.52,25.18 v1(86.31,24.96)
M_B_BG1: length 77
  L2 w0.102: v1(110.22,81.04) 109.62,80.45 109.62,77.1 109.45,76.93
  L2 w0.152: 109.45,76.93 109.45,75.74 108.45,74.03 106.15,71.73 106.15,67.97 105.8,62.74 92.4,49.34 92.4,49.12 92.78,48.74 92.78,48.53 92.56,48.31 92.34,48.31 91.96,48.69 91.75,48.69 91.53,48.47 91.53,48.26 91.91,47.88 91.91,47.66 91.7,47.45 91.48,47.45 91.1,47.83 90.89,47.83 90.67,47.61 90.67,47.4 91.01,47.06 91.01,46.86 90.77,46.62 90.59,46.62 90.24,46.97 90.02,46.97 89.73,46.68 89.73,33.8 89.67,33.74 89.67,33.7 84.97,29 84.97,25.73 85.46,25.24 85.46,24.41 v1(86.28,23.59)
  BOTTOM w0.292: DM2.113 86.02,26.02 85.66,25.66 85.66,24.15 86.21,23.59 v1(86.28,23.59) ; v1(110.22,81.04) 110.3,81.04 CPU1.AN52
M_B_CKE0: length 70.9
  L2 w0.102: v1(108.37,81.02) 108.03,80.68 107.79,80.11 107.79,78.8 107.96,78.62 108.45,78.08 108.65,77.88 108.65,76.46 108.41,76.1 107.7,75.39
  L2 w0.152: 107.7,75.39 104.99,72.67 104.49,70.94 104.49,63.61 88.32,47.44 88.32,34.9 88,33.8 83.72,29.51 83.72,25.09 v1(84.1,24.71)
  BOTTOM w0.216: v1(108.37,81.02) 108.21,81.02 CPU1.AN56
  BOTTOM w0.292: v1(84.1,24.71) 84.1,25.39 85.02,26.32 DM2.109
M_B_CKE1: length 72.3
  L2 w0.102: v1(108.37,79.72) 107.98,79.2 107.98,78.88 108.15,78.71 108.64,78.16 108.84,77.96 108.84,76.28 108.61,75.89 107.97,75.14
  L2 w0.152: v1(84.1,23.31) 84.58,23.8 84.58,24.97 84.13,25.42 84.13,29.35 88.42,33.64 88.72,34.62 88.72,47.27 104.91,63.45 104.91,71.01 105.21,71.95 105.27,72.04 106.63,73.8 107.97,75.14
  BOTTOM w0.216: v1(108.37,79.72) 108.7,80.05 CPU1.AP55
  BOTTOM w0.292: DM2.110 85.27,20.27 84.56,20.98 84.56,22.85 v1(84.1,23.31)
M_B_CLK0: length 75
  L2 w0.102: v1(93.78,24.33) 94.1,24.46 94.31,24.46 94.54,24.69 94.54,27.69 100.44,33.59 100.44,41.36 100.57,41.49 100.73,41.49 101.19,41.95 101.19,43.29 100.97,43.51 100.39,43.51 100.23,43.67 100.23,44.14 100.41,44.32 100.91,44.32 101.16,44.57 101.16,45.08 114.18,58.1 114.18,65.01 114.47,65.3 114.47,68.12 114.07,68.51 114.07,69.17 112.73,70.51 112.73,74.5 113.39,75.16 114.39,75.16 114.62,75.39 114.62,75.98 114.39,76.21 113.59,76.21 113.44,76.36 113.44,79.37 113.57,79.5 113.88,79.5 114.38,80.01 114.58,80.01 114.71,79.85 v1(114.7,79.72)
  BOTTOM w0.089: v1(114.7,79.72) CPU1.AP45
  BOTTOM w0.178: v1(93.78,24.33) 93.04,24.33 92.55,24.82 92.55,25.98 92.02,26.5 DM2.137
M_B_CLK1: length 73.9
  L2 w0.102: v1(113.85,80.33) 113.75,80.43 113.57,80.43 113.47,80.33 113.47,80.01 112.93,79.48 112.93,75.48 112.19,74.73 112.19,70.14 113.61,68.72 113.61,68.27 113.93,67.95 113.93,65.76 113.35,65.19 113.35,58.44 99.31,44.39 99.31,33.63 93.26,27.58 93.26,22.12 93.38,22 93.55,22 93.66,22.1 93.8,22.27 v1(93.8,22.35)
  BOTTOM w0.089: v1(113.85,80.33) 113.85,80.17 113.64,79.97 113.46,79.97 CPU1.AP46
  BOTTOM w0.178: v1(93.8,22.35) 93.64,22.18 93.31,22.18 92.38,21.25 92.38,20.27 92.27,20.17 DM2.138
M_B_CLK#0: length 74.9
  L2 w0.102: v1(114.76,80.4) 114.58,80.22 114.29,80.22 113.79,79.72 113.48,79.72 113.23,79.46 113.23,76.27 113.5,75.99 114.3,75.99 114.41,75.89 114.41,75.48 114.3,75.38 113.31,75.38 112.52,74.59 112.52,70.42 113.86,69.08 113.86,68.42 114.25,68.03 114.25,65.39 113.96,65.1 113.96,58.19 100.95,45.17 100.95,44.66 100.82,44.53 100.32,44.53 100.02,44.23 100.02,43.58 100.3,43.3 100.88,43.3 100.98,43.2 100.98,42.04 100.64,41.7 100.48,41.7 100.22,41.45 100.22,33.68 94.32,27.78 94.32,24.78 94.22,24.68 94.09,24.68 v1(93.78,24.99)
  BOTTOM w0.089: v1(114.76,80.4) 114.7,80.3 114.52,80.26 114.27,80.42 114.23,80.6 CPU1.AN45
  BOTTOM w0.178: DM2.139 92.52,26.43 92.85,26.1 92.85,24.95 93.17,24.63 93.42,24.63 93.77,24.99 v1(93.78,24.99)
M_B_CLK#1: length 73.9
  L2 w0.089: 93.56,21.78 v1(93.85,21.69)
  L2 w0.102: 93.56,21.78 93.29,21.78 93.04,22.03 93.04,27.67 99.09,33.72 99.09,44.48 113.14,58.53 113.14,65.28 113.71,65.85 113.71,67.86 113.39,68.18 113.39,68.63 111.97,70.06 111.97,74.82 112.72,75.57 112.72,79.57 113.25,80.1 113.25,80.42 113.48,80.65 113.52,80.65 v1(113.86,80.98)
  BOTTOM w0.089: v1(113.86,80.98) CPU1.AN46
  BOTTOM w0.178: v1(93.85,21.69) 93.66,21.88 93.44,21.88 92.68,21.13 92.68,20.3 92.77,20.21 DM2.140
M_B_CS#0: length 71.5
  L2 w0.102: 117.69,65.28 116.2,66.77 116.2,71.21 116.08,71.34 115.9,71.34 v1(115.61,71.06)
  L2 w0.152: 117.69,65.28 117.69,56.57 116.91,55.79 116.91,55.44 117.53,54.82 117.53,54.58 112.19,49.24 112.19,49.02 112.59,48.62 112.59,48.43 112.33,48.18 112.18,48.18 111.76,48.59 111.54,48.59 111.33,48.38 111.33,48.14 111.73,47.74 111.73,47.57 111.47,47.31 111.32,47.31 110.9,47.73 110.68,47.73 106.33,43.38 106.33,42.81 106.33,42.81 106.33,40.63 106.11,40.41 105.67,40.41 105.54,40.28 105.54,39.93 105.67,39.8 106.2,39.8 106.33,39.67 106.33,33.71 105.74,33.12 105.52,33.12 105.36,33.29 105.14,33.29 104.93,33.08 104.93,32.86 105.09,32.69 105.09,32.48 98.89,26.27 98.89,25.03 98.64,24.78 98.64,24.45 98.8,24.28 98.8,24 v1(98.4,23.59)
  BOTTOM w0.089: 116.09,72.8 116.33,73.04 116.33,73.43 116.35,73.45 116.35,74.79 116.39,74.83 CPU1.BB42
  BOTTOM w0.152: v1(115.61,71.06) 116.04,71.06 116.15,71.17 116.15,71.51 116.3,71.65 116.3,72.08 116.09,72.28 116.09,72.8
  BOTTOM w0.292: DM2.149 97.02,24.97 v1(98.4,23.59)
M_B_CS#1: length 74.4
  L2 w0.102: v1(115.61,72.96) 115.61,73.11 115.74,73.23 116.07,73.23 116.39,72.91 116.39,72.73 116.05,72.39 116.05,72.2 116.59,71.66 116.59,67.62 118.5,65.72
  L2 w0.152: v1(100.28,23.31) 99.9,22.93 99.9,22.31 99.76,22.17 99.45,22.17 99.31,22.32 99.31,23.3 99.87,23.87 99.87,24.72 99.7,24.89 99.7,25.92 107.14,33.36 107.14,41.84 113.41,48.1 113.41,49.29 113.76,49.64 113.98,49.64 114.36,49.27 114.57,49.27 114.79,49.48 114.79,49.7 114.41,50.08 114.41,50.29 114.63,50.51 114.84,50.51 115.22,50.13 115.44,50.13 115.65,50.34 115.65,50.56 115.27,50.94 115.27,51.15 118.5,54.38 118.5,65.72
  BOTTOM w0.089: CPU1.AY42 116.18,75.89 116.13,75.72 116.13,75.54 116.17,75.42 116.17,75.17 116.13,75.09 116.13,74.66 116.17,74.62 116.17,73.52 116.1,73.45 116.1,73.17 116,73.06 115.72,73.06 v1(115.61,72.96)
  BOTTOM w0.292: v1(100.28,23.31) 99.49,23.31 99.34,23.46 99.34,24.12 99.17,24.29 99.17,25.86 99.02,26 DM2.157
M_B_DIMB_ODT0: length 72.9
  L2 w0.102: 116.01,66.02 115.81,66.22 115.81,68.4 115.22,68.99 115.22,69.66 115.34,69.79 v1(115.61,69.79)
  L2 w0.152: v1(98.3,22.2) 97.81,22.68 97.81,24.32 97.57,24.56 97.57,26.11 101.56,30.1 101.56,30.94 103.89,33.27 103.89,34.82 104.13,35.05 104.13,35.44 104.12,35.45 104.12,35.57 103.89,35.8 103.89,37.32 104.05,37.47 104.58,37.47 104.73,37.63 104.73,37.93 104.58,38.08 104.05,38.08 103.89,38.24 103.89,38.54 104.05,38.69 104.58,38.69 104.73,38.84 104.73,39.15 104.58,39.3 104.05,39.3 103.89,39.45 103.89,39.86 105.26,41.23 105.26,43.46 111.93,50.13 111.93,50.43 111.45,50.91 111.45,51.49 116.87,56.91 116.87,65.15 116.01,66.02
  BOTTOM w0.102: CPU1.BA42 116.66,75.37 116.66,74.83 116.65,74.82 116.65,74.78 116.55,74.68 116.55,72.98 116.36,72.78 116.36,72.38 116.55,72.19 116.55,71.22 116.33,71.01 116.33,70.78 116.51,70.6 116.51,70.25 116.04,69.79 v1(115.61,69.79)
  BOTTOM w0.292: v1(98.3,22.2) 98.33,22.2 98.93,22.79 98.93,23.94 98.59,24.28 98.59,25 98.53,25.07 98.53,25.49 98.55,25.51 98.55,25.95 98.53,25.98 DM2.155
M_B_DIMB_ODT1: length 73.5
  L2 w0.102: 118.9,65.66 116.78,67.78 116.78,71.73 116.42,72.1 116.42,72.39 116.65,72.62 116.65,72.93 116.08,73.5 116.08,75.17 115.63,75.62 115.63,75.97 115.5,76.1 115.29,76.1 115.16,75.97 115.16,75.31 115.28,75.19 115.4,75.19 115.54,75.04 115.54,74.8 115.41,74.67 114.86,74.67 114.43,74.25 114.43,74.02 114.71,73.74 114.71,72.98 114.82,72.87 115.04,72.87 115.17,73 115.17,73.19 v1(115.58,73.6)
  L2 w0.152: v1(100.3,24.91) 100.11,25.11 100.11,25.72 107.55,33.16 107.55,39.09 108.11,39.65 108.11,40.29 107.55,40.85 107.55,41.67 116.24,50.35 116.24,51.36 118.9,54.03 118.9,65.66
  BOTTOM w0.089: v1(115.58,73.6) 115.79,73.6 116,73.8 116,74.47 115.95,74.51 115.95,75.13 115.99,75.21 115.99,75.39 115.95,75.52 115.95,75.74 115.99,75.88 115.99,76.35 116.09,76.45 116.14,76.5 116.39,76.75 CPU1.AW42
  BOTTOM w0.292: DM2.161 100.02,26.54 100.1,26.47 100.1,25.55 100.12,25.53 100.12,25.39 100.3,25.2 v1(100.3,24.91)
M_B_DQ0: length 89.4
  L2 w0.089: v1(63.12,24.5) 63.4,24.5 63.53,24.62 63.53,29.59 67.49,33.56 67.49,44.46 85.99,62.95 85.99,76.03 92.3,82.35 95.88,82.35 95.97,82.25 98.74,82.25 99.2,82.71 99.2,82.95 100.84,84.73 101.17,85.06 101.61,85.06 101.8,85.26 102.3,85.26 102.97,84.94 v1(103.41,84.61)
  BOTTOM w0.191: DM2.28 64.78,23 63.28,24.5 v1(63.12,24.5) ; CPU1.AF65 v1(103.41,84.61)
M_B_DQ1: length 87.9
  L2 w0.089: v1(65.6,25.11) 65.18,25.53 65.18,29.89 68.39,33.1 68.39,44.11 87.7,63.43 87.7,63.95 87.61,64.04 87.5,64.04 87.41,64.13 87.41,64.31 87.5,64.4 87.61,64.4 87.7,64.49 87.7,64.66 87.61,64.75 87.5,64.75 87.41,64.84 87.41,65.02 87.5,65.11 87.61,65.11 87.7,65.2 87.7,65.38 87.61,65.46 87.5,65.46 87.41,65.55 87.41,65.73 87.5,65.82 87.61,65.82 87.7,65.91 87.7,66.09 87.61,66.18 87.5,66.18 87.41,66.26 87.41,66.44 87.5,66.53 87.61,66.53 87.7,66.62 87.7,66.8 87.61,66.89 87.5,66.89 87.41,66.98 87.41,67.15 87.5,67.24 87.61,67.24 87.7,67.33 87.7,67.51 87.61,67.6 87.5,67.6 87.41,67.69 87.41,67.86 87.5,67.95 87.61,67.95 87.7,68.04 87.7,68.22 87.61,68.31 87.5,68.31 87.41,68.4 87.41,68.58 87.5,68.67 87.61,68.67 87.7,68.75 87.7,68.93 87.61,69.02 87.5,69.02 87.41,69.11 87.41,69.29 87.5,69.38 87.61,69.38 87.7,69.47 87.7,69.64 87.61,69.73 87.5,69.73 87.41,69.82 87.41,70 87.5,70.09 87.61,70.09 87.7,70.18 87.7,70.35 87.61,70.44 87.5,70.44 87.41,70.53 87.41,70.71 87.5,70.8 87.61,70.8 87.7,70.89 87.7,71.18 86.9,71.98 86.9,75.7 90.26,79.07 92.73,79.07 94.39,80.72 98.53,80.72 100.96,83.16 100.96,83.78 101.27,84.08 103.02,84.08 v1(103.41,83.7)
  BOTTOM w0.191: DM2.29 65.04,27.48 65.04,25.66 v1(65.6,25.11) ; CPU1.AF64 103.74,84.02 v1(103.41,83.7)
M_B_DQ2: length 88.3
  L2 w0.089: v1(103.41,82.78) 103.02,82.39 101.73,82.39 98.26,78.92 96.96,78.92 93.56,75.51 93.56,72.89 90.16,69.49 90.16,63.03 89.46,62.34 89.34,62.34 89.14,62.53 89.02,62.53 88.89,62.41 88.89,62.28 89.08,62.09 89.08,61.95 88.95,61.83 88.83,61.83 88.59,62.07 88.46,62.07 88.34,61.94 88.34,61.82 88.58,61.58 88.58,61.45 88.45,61.33 88.32,61.33 88.09,61.57 87.96,61.57 87.83,61.44 87.83,61.31 88.07,61.07 88.07,60.95 87.95,60.82 87.82,60.82 87.58,61.06 87.46,61.06 87.33,60.94 87.33,60.81 87.57,60.57 87.57,60.45 87.44,60.32 87.32,60.32 87.08,60.56 86.95,60.56 86.83,60.43 86.83,60.31 87.07,60.07 87.07,59.94 86.94,59.82 86.82,59.82 86.58,60.06 86.45,60.06 86.33,59.93 86.33,59.8 86.56,59.57 86.56,59.44 86.44,59.31 86.31,59.31 86.07,59.55 85.95,59.55 85.82,59.43 85.82,59.3 86.06,59.06 86.06,58.94 85.94,58.81 85.81,58.81 85.57,59.05 85.45,59.05 85.32,58.92 85.32,58.8 85.56,58.56 85.56,58.43 85.43,58.31 85.31,58.31 85.07,58.55 84.94,58.55 84.82,58.42 84.82,58.3 85.06,58.06 85.06,57.93 84.93,57.81 84.8,57.81 84.56,58.04 84.44,58.04 70.6,44.21 70.6,33.16 68.14,30.7 68.14,26.57 67.84,26.27 67.84,24.31 v1(67.21,23.68)
  BOTTOM w0.191: CPU1.AK65 103.41,82.65 v1(103.41,82.78) ; DM2.41 68.02,24.49 v1(67.21,23.68)
M_B_DQ3: length 89.4
  L2 w0.089: v1(67.21,22.26) 67.96,22.26 68.14,22.44 68.14,26.15 69.12,27.13 69.12,29.98 71.73,32.59 71.73,44.9 80.3,53.47 80.42,53.47 80.66,53.24 80.78,53.24 80.91,53.37 80.91,53.49 80.68,53.72 80.68,53.85 80.8,53.98 80.93,53.98 81.16,53.75 81.28,53.75 81.41,53.87 81.41,54 81.18,54.23 81.18,54.35 81.31,54.48 81.43,54.48 81.66,54.25 81.79,54.25 81.91,54.37 81.91,54.5 81.68,54.73 81.68,54.86 81.81,54.98 81.93,54.98 82.16,54.75 82.29,54.75 82.42,54.88 82.42,55 82.19,55.23 82.19,55.36 82.31,55.49 82.44,55.49 82.67,55.25 82.79,55.25 82.92,55.38 82.92,55.51 82.69,55.74 82.69,55.86 82.81,55.99 82.94,55.99 83.17,55.76 83.3,55.76 83.42,55.88 83.42,56.01 83.19,56.24 83.19,56.36 83.32,56.49 83.44,56.49 83.67,56.26 83.8,56.26 83.92,56.39 83.92,56.51 83.69,56.74 83.69,56.87 83.82,56.99 83.95,56.99 84.18,56.76 84.3,56.76 84.43,56.89 84.43,57.01 84.2,57.25 84.2,57.37 84.32,57.5 84.45,57.5 84.68,57.27 84.8,57.27 90.45,62.91 90.45,69.37 93.85,72.77 93.85,75.04 96.66,77.85 98.15,77.85 100.08,79.78 100.08,80.44 101.84,82.2 103.84,82.2 104.06,82.42 v1(104.06,82.78)
  BOTTOM w0.191: v1(67.21,22.26) 67.46,22.26 68.17,21.55 68.17,21.44 68.22,21.38 68.22,21.3 68.23,21.3 68.23,20.47 68.27,20.43 DM2.42 ; CPU1.AK64 104.06,82.65 v1(104.06,82.78)
M_B_DQ4: length 88.7
  L2 w0.089: v1(102.74,84.56) 102.35,84.86 102.24,84.96 102.14,84.96 101.92,84.96 101.73,84.77 101.29,84.77 99.46,82.94 99.46,82.71 98.7,81.96 95.85,81.96 95.75,82.05 92.43,82.05 86.28,75.91 86.28,70.97 86.44,70.81 86.44,70.62 86.28,70.46 86.28,70.26 86.44,70.1 86.44,69.91 86.28,69.75 86.28,69.55 86.44,69.39 86.44,69.2 86.28,69.03 86.28,68.84 86.44,68.68 86.44,68.48 86.28,68.32 86.28,68.13 86.44,67.97 86.44,67.77 86.28,67.61 86.28,67.42 86.44,67.26 86.44,67.06 86.28,66.9 86.28,66.71 86.44,66.54 86.44,66.35 86.28,66.19 86.28,66 86.44,65.83 86.44,65.64 86.28,65.48 86.28,65.28 86.44,65.12 86.44,64.93 86.28,64.77 86.28,62.83 67.8,44.35 67.8,33.34 63.82,29.36 63.82,23.62 v1(63.28,23.07)
  BOTTOM w0.191: v1(63.28,23.07) 63.78,22.58 DM2.24 ; CPU1.AF66 102.44,84.28 102.7,84.55 102.72,84.55 102.73,84.56 v1(102.74,84.56)
M_B_DQ5: length 88.5
  L2 w0.089: v1(65.6,23.82) 64.53,23.82 64.4,23.95 64.4,29.53 68.09,33.22 68.09,44.23 87.11,63.25 87.11,67.9 87.02,67.99 86.91,67.99 86.82,68.08 86.82,68.5 86.91,68.59 87.02,68.59 87.11,68.67 87.11,69.09 87.02,69.18 86.91,69.18 86.82,69.27 86.82,69.69 86.91,69.78 87.02,69.78 87.11,69.87 87.11,70.29 87.02,70.38 86.91,70.38 86.82,70.47 86.82,70.88 86.91,70.97 87.02,70.97 87.11,71.06 87.11,71.35 86.61,71.86 86.61,75.82 90.14,79.36 90.38,79.36 92.61,79.36 94.27,81.02 98.57,81.02 100.67,83.12 100.67,83.74 101.49,84.56 102.06,84.56 v1(102.08,84.58)
  BOTTOM w0.191: CPU1.AF67 101.79,84.28 v1(102.08,84.58) ; v1(65.6,23.82) 65.11,23.82 64.09,24.84 64.09,26.24 64.02,26.31 DM2.25
M_B_DQ6: length 86.7
  L2 w0.089: v1(102,81.81) 100.37,80.18 100.37,79.82 98.22,77.67 97.27,77.67 94.14,74.55 94.14,72.65 90.74,69.25 90.74,62.79 80.69,52.74 80.56,52.74 80.33,52.97 80.21,52.97 80.08,52.84 80.08,52.72 80.31,52.49 80.31,52.36 80.19,52.24 80.06,52.24 79.83,52.47 79.71,52.47 79.58,52.34 79.58,52.21 79.81,51.98 79.81,51.86 79.68,51.73 79.56,51.73 79.33,51.96 79.2,51.96 79.08,51.84 79.08,51.71 79.31,51.48 79.31,51.36 79.18,51.23 79.06,51.23 78.83,51.46 78.7,51.46 78.57,51.33 78.57,51.21 78.8,50.98 78.8,50.85 78.68,50.73 78.55,50.73 78.32,50.96 78.2,50.96 78.07,50.83 78.07,50.71 78.3,50.48 78.3,50.35 78.18,50.22 78.05,50.22 77.82,50.45 77.69,50.45 77.57,50.33 77.57,50.2 77.8,49.97 77.8,49.85 77.67,49.72 77.55,49.72 77.32,49.95 77.19,49.95 77.06,49.83 77.06,49.7 77.3,49.47 77.3,49.34 77.17,49.22 77.04,49.22 76.81,49.45 76.69,49.45 76.56,49.32 76.56,49.2 76.79,48.97 76.79,48.84 76.67,48.71 76.54,48.71 76.31,48.95 76.19,48.95 76.06,48.82 76.06,48.69 76.29,48.46 76.29,48.34 76.16,48.21 76.04,48.21 75.81,48.44 75.68,48.44 75.56,48.32 75.56,48.19 75.79,47.96 75.79,47.84 75.66,47.71 75.54,47.71 75.3,47.94 75.18,47.94 73.56,46.32 72.05,44.82 72.05,32.47 69.44,29.86 69.44,27.04 68.43,26.03 68.43,22.18 v1(67.21,20.96)
  BOTTOM w0.191: v1(102,81.81) 101.79,82.02 CPU1.AK67 ; DM2.38 67.27,20.9 v1(67.21,20.96)
M_B_DQ7: length 87.5
  L2 w0.089: v1(67.21,25.11) 66.79,25.53 66.79,25.99 67.85,27.06 67.85,30.84 70.29,33.28 70.29,44.31 89.86,63.88 89.86,64.92 89.78,65.01 89.49,65.01 89.4,65.1 89.4,65.27 89.49,65.36 89.78,65.36 89.86,65.45 89.86,65.63 89.78,65.72 89.49,65.72 89.4,65.81 89.4,65.98 89.49,66.07 89.78,66.07 89.86,66.16 89.86,66.34 89.78,66.43 89.49,66.43 89.4,66.52 89.4,66.7 89.49,66.78 89.78,66.78 89.86,66.87 89.86,67.05 89.78,67.14 89.49,67.14 89.4,67.23 89.4,67.41 89.49,67.5 89.78,67.5 89.86,67.59 89.86,67.76 89.78,67.85 89.49,67.85 89.4,67.94 89.4,68.12 89.49,68.21 89.78,68.21 89.86,68.3 89.86,68.47 89.78,68.56 89.49,68.56 89.4,68.65 89.4,68.83 89.49,68.92 89.78,68.92 89.86,69.01 89.86,69.19 89.78,69.27 89.49,69.27 89.4,69.36 89.4,69.54 89.49,69.63 89.78,69.63 89.86,69.72 89.86,69.9 89.78,69.99 89.49,69.99 89.4,70.07 89.4,70.25 89.49,70.34 89.78,70.34 89.86,70.43 89.86,70.72 88.11,72.48 88.11,75.2 90.76,77.86 93.23,77.86 94.59,79.22 98.25,79.22 101.8,82.78 v1(102.76,82.78)
  BOTTOM w0.191: v1(67.21,25.11) 66.71,25.61 66.71,26 67.02,26.31 DM2.37 ; v1(102.76,82.78) 102.76,82.65 CPU1.AK66
M_B_DQ8: length 89.3
  L2 w0.089: v1(58.65,22.32) 58.94,22.61 59.04,22.8 59.37,23.88 59.37,26.12 59.86,26.62 59.86,30.55 61.97,32.65 61.97,43.64 83.32,64.99 83.32,77.39 91.43,85.5 94.6,85.5 96.9,85.25 97.2,85.25 v1(97.95,85.67)
  BOTTOM w0.089: v1(97.95,85.67) 98.7,85.53 99.09,85.44 99.33,85.2 99.33,84.96 CPU1.AF70
  BOTTOM w0.191: v1(58.65,22.32) 59.13,22.04 59.78,21.39 DM2.8
M_B_DQ9: length 90.7
  L2 w0.089: v1(97.09,85.68) 97.03,85.63 96.35,85.63 96.19,85.79 91.31,85.79 83.03,77.51 83.03,65.11 61.68,43.76 61.68,33 59.47,30.79 59.47,26.77 59.08,26.38 59.08,23.99 58.75,23.67 v1(58.65,23.67)
  BOTTOM w0.089: CPU1.AF68 100.47,84.7 100.29,84.77 100.13,84.92 100.13,85.3 99.9,85.53 99.44,85.64 99.01,85.64 98.78,85.73 98.25,86.11 97.88,86.11 v1(97.09,85.68)
  BOTTOM w0.191: DM2.7 59.52,26.48 59.48,26.43 59.48,26.06 59.32,25.91 59.32,24.34 v1(58.65,23.67)
M_B_DQ10: length 88.2
  L2 w0.089: v1(97.09,82.98) 96.88,82.78 96.27,82.78 96.12,82.93 91.96,82.93 85.4,76.38 85.4,63.19 69.77,47.56 69.64,47.56 69.3,47.9 69.17,47.9 69.05,47.77 69.05,47.65 69.39,47.31 69.39,47.18 69.26,47.06 69.14,47.06 68.8,47.4 68.67,47.4 68.55,47.27 68.55,47.15 68.89,46.8 68.89,46.68 68.76,46.55 68.64,46.55 68.29,46.89 68.17,46.89 68.04,46.77 68.04,46.64 68.38,46.3 68.38,46.18 68.26,46.05 68.13,46.05 67.79,46.39 67.67,46.39 66.17,44.9 66.17,36.13 64.25,34.21 64.25,33.66 64.37,33.53 64.37,33.02 64.25,32.9 64.25,31.38 62.49,29.62 62.49,22.47 v1(63.28,21.68)
  BOTTOM w0.089: CPU1.AH71 98.84,83.13 98.76,83.21 97.31,83.21 v1(97.09,82.98)
  BOTTOM w0.191: v1(63.28,21.68) 63.19,21.68 62.78,21.27 DM2.20
M_B_DQ11: length 90.3
  L2 w0.089: v1(63.08,25.82) 63.08,29.63 65.34,31.89 65.34,32.01 64.8,32.55 64.8,32.68 65.64,33.51 65.64,33.69 65,34.33 65,34.51 65.7,35.21 65.88,35.21 66.07,35.02 66.07,34.84 65.84,34.62 65.84,34.38 66.44,33.78 66.44,33.65 65.47,32.68 65.47,32.55 65.67,32.35 65.8,32.35 67.14,33.68 67.14,39.21 66.53,39.82 66.53,44.82 67.06,45.35 67.18,45.35 67.51,45.02 67.64,45.02 67.77,45.14 67.77,45.27 67.43,45.6 67.43,45.73 67.56,45.85 67.69,45.85 68.02,45.52 68.14,45.52 85.69,63.07 85.69,76.25 92.08,82.64 96,82.64 96.09,82.55 97.56,82.55 v1(97.72,82.7)
  BOTTOM w0.089: CPU1.AH68 100.83,82.83 98.89,82.83 98.69,83.03 98.05,83.03 v1(97.72,82.7)
  BOTTOM w0.191: DM2.21 63.02,25.88 v1(63.08,25.82)
M_B_DQ12: length 88.1
  L2 w0.089: v1(58.65,20.97) 59.02,21.33 59.66,23.82 59.66,25.96 60.29,26.59 60.29,30.49 62.26,32.46 62.26,43.52 74.67,55.93 75.6,55.93 83.61,63.94 83.61,77.27 91.55,85.2 94.55,85.2 95.16,84.96 98.84,84.96 v1(98.93,85.05)
  BOTTOM w0.14: CPU1.AF71 v1(98.93,85.05)
  BOTTOM w0.191: v1(58.65,20.97) 58.78,20.85 DM2.4
M_B_DQ13: length 89.7
  L2 w0.089: v1(58.64,25.06) 58.63,25.06 58.23,25.46 58.23,26.12 59.13,27.02 59.13,27.37 59.02,27.47 58.72,27.47 58.58,27.61 58.58,27.84 58.68,27.94 58.91,27.94 59.13,28.16 59.13,30.86 61.39,33.12 61.39,43.88 82.74,65.23 82.74,77.63 91.19,86.08 98,86.08 98.23,86.03 98.56,85.9 98.8,85.65 100.21,85.65 100.34,85.52 100.34,85.26 100.21,85.13 v1(99.75,85.13)
  BOTTOM w0.089: CPU1.AF69 100.33,84.52 100.28,84.52 99.96,84.85 99.96,84.92 v1(99.75,85.13)
  BOTTOM w0.191: DM2.3 58.52,26.78 58.45,26.71 58.45,26.39 58.18,26.11 58.18,25.53 v1(58.64,25.06)
M_B_DQ14: length 89.4
  L2 w0.089: v1(61.09,21.67) 61.34,21.93 61.95,23.6 61.95,29.62 63.83,31.5 63.83,42.97 69.86,48.99 69.98,48.99 70.32,48.65 70.45,48.65 70.57,48.78 70.57,48.9 70.23,49.25 70.23,49.37 70.36,49.5 70.48,49.5 70.82,49.16 70.95,49.16 71.08,49.28 71.08,49.41 70.73,49.75 70.73,49.87 70.86,50 70.99,50 71.33,49.66 71.45,49.66 71.58,49.79 71.58,49.91 71.24,50.25 71.24,50.38 71.36,50.5 71.49,50.5 71.83,50.16 71.96,50.16 73.42,51.62 85.11,63.32 85.11,76.5 91.88,83.26 v1(96.46,83.26)
  BOTTOM w0.089: v1(96.46,83.26) 96.46,83.27 96.59,83.39 96.62,83.39 96.95,83.73 97.27,83.73 97.6,83.39 99.27,83.39 99.36,83.37 99.6,83.13 CPU1.AH70
  BOTTOM w0.191: DM2.16 61.78,20.98 v1(61.09,21.67)
M_B_DQ15: length 90.3
  L2 w0.089: v1(61.02,23.07) 61.66,23.72 61.66,29.89 63.52,31.75 63.52,43.08 71.24,50.8 71.25,50.8 71.46,51 71.58,51 71.92,50.66 72.04,50.66 72.17,50.79 72.17,50.92 71.83,51.25 71.83,51.38 71.96,51.51 72.08,51.51 72.42,51.17 72.55,51.17 72.67,51.29 72.67,51.42 72.34,51.76 72.34,51.88 72.46,52.01 72.59,52.01 72.92,51.67 73.05,51.67 84.82,63.44 84.82,76.62 91.97,83.76 97.5,83.76 v1(97.65,83.91)
  BOTTOM w0.089: CPU1.AH69 100.09,83.53 99.45,83.53 99.19,83.6 98.46,83.6 98.44,83.58 97.98,83.58 v1(97.65,83.91)
  BOTTOM w0.191: v1(61.02,23.07) 62.02,24.08 DM2.17
M_B_DQ16: length 74.9
  L2 w0.089: v1(69.3,22.41) 69.75,22.86 69.75,25.9 70.32,26.46 70.32,28.65 71.71,30.84 74.48,33.62 74.48,39.42 75.4,45.88 91.62,62.09 91.62,68.88 96.78,74.05 96.78,75.18 97.12,75.52 98.35,75.52 99.05,76.22 99.05,76.68 101.47,79.1 v1(101.94,79.1)
  BOTTOM w0.14: v1(101.94,79.1) 101.94,79.09 102.28,78.75 CPU1.AT66
  BOTTOM w0.191: DM2.50 70.27,21.52 69.39,22.41 v1(69.3,22.41)
M_B_DQ17: length 74.9
  L2 w0.089: v1(101.91,78.44) 100.79,78.02 99.33,76.55 99.33,76.24 98.45,75.36 98.16,75.24 97.79,74.98 97.72,74.8 97.72,74.69 97.52,74.2 91.94,68.62 91.94,68.61 91.91,68.57 91.91,61.97 75.68,45.74 74.78,39.4 74.78,33.49 71.94,30.66 70.61,28.56 70.61,25.95 70.39,25.73 70.39,24.39 70.95,23.83 70.95,23.82 71.2,23.57 71.2,23.57 71.24,23.53 71.52,23.53 v1(72.03,23.62)
  BOTTOM w0.191: DM2.49 70.02,26.26 70.16,26.13 70.16,24.54 71.18,23.52 71.57,23.52 v1(72.03,23.62) ; CPU1.AU66 v1(101.91,78.44)
M_B_DQ18: length 77.3
  L2 w0.089: v1(73.8,21.65) 73.52,21.65 73.39,21.77 73.39,28.43 78.49,33.53 78.49,45.44 87.01,53.96 87.01,54.54 93.7,61.23 94.47,62 94.47,68.51 94.68,68.72 94.8,68.72 95.21,68.32 95.35,68.32 95.64,68.61 95.64,68.73 95.23,69.14 95.23,69.27 95.52,69.56 95.65,69.56 95.92,69.3 96.04,69.3 96.34,69.59 96.34,69.72 96.07,69.99 96.07,70.11 98.62,72.66 98.62,73.12 100.58,75.08 101.65,75.08 104.18,77.6 104.18,79.33 v1(103.78,79.73)
  BOTTOM w0.191: CPU1.AP65 103.65,79.73 v1(103.78,79.73) ; v1(73.8,21.65) 73.34,21.18 73.34,20.41 73.27,20.34 DM2.62
M_B_DQ19: length 78.4
  L2 w0.089: v1(103.78,80.38) 104.07,80.38 104.35,80.09 104.35,77.53 101.71,74.88 100.75,74.88 100.01,74.14 100.01,73.63 96.78,70.41 96.78,65.91 96.69,65.82 95.74,65.82 95.65,65.73 95.65,65.31 95.74,65.22 96.69,65.22 96.78,65.13 96.78,63.9 96.56,63.68 96.44,63.68 95.19,64.93 95.03,64.93 94.76,64.66 94.76,64.51 96.02,63.26 96.02,63.13 95.76,62.87 95.58,62.87 95.26,63.2 95.08,63.2 94.83,62.96 94.83,62.78 95.16,62.45 95.16,62.27 87.84,54.95 87.84,54.37 78.79,45.32 78.79,33.41 73.83,28.46 73.83,28.13 73.92,28.04 74.32,28.04 74.41,27.95 74.41,27.53 74.32,27.44 73.92,27.44 73.83,27.35 v1(73.83,25.8)
  BOTTOM w0.191: CPU1.AN65 103.45,80.7 v1(103.78,80.38) ; v1(73.83,25.8) 73.52,26.11 DM2.63
M_B_DQ20: length 77.3
  L2 w0.089: v1(102.86,80.38) 102.47,79.99 101.47,79.99 98.24,76.76 97.34,76.76 94.83,74.25 94.83,72.92 91.03,69.13 91.03,62.33 72.93,44.23 72.93,38.22 73.2,37.96 73.2,36.97 72.93,36.7 72.93,32.93 69.73,29.74 69.73,26.92 68.72,25.91 68.72,21.75 v1(69.24,20.98)
  BOTTOM w0.191: v1(102.86,80.38) 102.54,80.7 CPU1.AN66 ; DM2.46 69.27,20.85 69.24,20.89 v1(69.24,20.98)
M_B_DQ21: length 76
  L2 w0.089: v1(69.15,25.71) 70.03,26.59 70.03,29.57 74.18,33.72 74.18,42.64 74.27,42.73 74.47,42.73 74.56,42.82 74.56,43.24 74.47,43.33 73.62,43.33 73.53,43.42 73.53,43.8 73.66,43.93 74.47,43.93 74.56,44.02 74.56,44.43 74.47,44.52 74.27,44.52 74.18,44.61 74.18,45.06 91.33,62.21 91.33,69.01 95.53,73.21 95.53,73.39 95.14,73.78 95.14,73.96 95.4,74.22 95.53,74.22 95.97,73.78 96.09,73.78 96.39,74.07 96.39,74.2 95.95,74.64 95.95,74.76 97.01,75.82 98.41,75.82 98.76,76.18 98.76,76.82 101.67,79.73 v1(102.86,79.73)
  BOTTOM w0.191: CPU1.AP66 102.54,80.05 v1(102.86,79.73) ; DM2.45 69.02,25.83 v1(69.15,25.71)
M_B_DQ22: length 75.9
  L2 w0.089: v1(71.96,21.64) 72.88,21.64 73.01,21.77 73.01,28.54 78.13,33.66 78.13,43.8 78.04,43.89 77.21,43.89 77.12,43.98 77.12,44.37 77.24,44.48 78.04,44.48 78.13,44.57 78.13,45.49 84.35,51.72 84.35,52.29 93.41,61.35 94.18,62.12 94.18,68.63 98.28,72.73 98.28,73.24 100.91,75.87 101.59,75.87 103.4,77.69 103.4,78.05 v1(103.78,78.43)
  BOTTOM w0.14: CPU1.AT65 103.45,78.75 v1(103.78,78.43)
  BOTTOM w0.191: v1(71.96,21.64) 71.96,21.62 72.38,21.19 72.38,20.8 72.27,20.69 DM2.58
M_B_DQ23: length 75.8
  L2 w0.089: v1(72.48,22.82) 72.48,28.43 76.8,32.74 76.8,41.29 76.88,41.38 77.46,41.38 77.56,41.48 77.56,41.89 77.47,41.98 76.88,41.98 76.8,42.07 76.8,42.48 76.88,42.57 77.46,42.57 77.56,42.67 77.56,43.08 77.47,43.17 76.88,43.17 76.8,43.26 76.8,44.57 81.86,49.63 81.86,50.21 93.89,62.24 93.89,68.76 98.1,72.97 98.1,73.32 101.37,76.58 102.05,76.58 102.88,77.41 v1(102.88,77.73)
  BOTTOM w0.14: v1(102.88,77.73) 103.25,78.1 CPU1.AU65
  BOTTOM w0.191: v1(72.48,22.82) 72.52,22.86 DM2.59
M_B_DQ24: length 74
  L2 w0.089: v1(75.88,23.68) 75.45,24.11 75.45,26.27 78.72,29.53 78.72,31.01 80.07,32.36 81.91,33.54 82.56,34.19 82.56,47.36 84.2,48.99 98.17,62.96 98.17,69.23 103.01,74.08 103.01,74.81 104.21,76.01 105.03,76.01 105.21,76.19 105.21,78.27 105.21,78.27 105.21,78.7 v1(105.59,79.08)
  BOTTOM w0.191: v1(105.59,79.08) 105.26,78.75 CPU1.AT61 ; DM2.70 75.27,22.79 75.88,23.39 v1(75.88,23.68)
M_B_DQ25: length 72.9
  L2 w0.089: v1(75.88,25.11) 76.8,25.11 76.92,25.23 76.92,26.8 76.92,27.22 79.39,29.68 79.39,31.23 80.37,32.21 81.92,32.21 83.22,33.51 83.22,46.4 83.31,46.49 84.27,46.49 84.36,46.58 84.36,46.87 84.27,46.96 83.31,46.96 83.22,47.05 83.22,47.6 84.49,48.87 98.46,62.84 98.46,63.5 98.46,69.08 103.24,73.86 103.24,74.61 103.6,74.97 104.28,74.97 105.48,76.17 105.48,78.32 v1(105.6,78.43)
  BOTTOM w0.191: CPU1.AU61 105.26,78.1 v1(105.6,78.43) ; DM2.71 75.52,26.32 75.27,26.06 75.27,25.71 v1(75.88,25.11)
M_B_DQ26: length 75.7
  L2 w0.089: v1(106.52,80.38) 107.02,79.88 107.02,78.76 107.14,78.64 107.14,77.16 107.03,77.05 106.42,76.44 106.42,75.43 103.16,72.17 103.16,71.51 102.72,71.07 102.72,69.23 101.95,68.46 101.95,63.75 86.4,48.2 86.4,33.77 81.86,29.23 81.86,28.56 81.95,28.47 82.37,28.47 82.46,28.38 82.46,28.09 82.37,28 81.95,28 81.86,27.91 81.86,27.62 81.95,27.53 82.42,27.53 82.5,27.44 82.5,27.15 82.42,27.06 81.95,27.06 81.86,26.97 81.86,26.68 81.95,26.59 82.43,26.59 82.51,26.5 82.51,26.21 82.43,26.12 81.95,26.12 81.86,26.03 81.86,24.95 81.74,24.83 79.44,24.83 79.31,24.95 79.31,25.04 79.19,25.17 v1(78.89,25.17)
  BOTTOM w0.191: DM2.83 78.52,26.13 78.41,26.02 78.41,25.62 78.87,25.17 v1(78.89,25.17) ; v1(106.52,80.38) 106.2,80.05 CPU1.AP60
M_B_DQ27: length 76.6
  L2 w0.089: v1(105.6,81.06) 105.19,80.53 104.84,78.95 104.84,77.51 104.39,77.05 102.61,74.95 102.61,74.44 102,73.83 99.44,71.5 97.52,69.59 97.52,63.21 80.96,46.65 79.54,39.27 79.54,33.33 78.11,31.3 78.06,31.07 78.02,30.04 77.95,29.81 75.55,27.3 75.55,27.3 74.82,26.56 74.82,23.57 75.02,23.25 76.89,21.15 v1(78.83,20.74)
  BOTTOM w0.191: CPU1.AN60 v1(105.6,81.06) ; v1(78.83,20.74) 78.78,20.3 DM2.84
M_B_DQ28: length 75.9
  L2 w0.089: v1(75.24,23.71) 75.16,23.98 75.16,26.46 78.39,29.69 78.39,31.15 81.23,33.98 81.23,40.82 81.32,40.91 82.03,40.91 82.12,41 82.12,41.29 82.03,41.38 81.32,41.38 81.23,41.47 81.23,46.44 83.91,49.11 83.91,49.11 97.88,63.08 97.88,69.39 102.79,74.3 102.79,74.89 104.52,76.93 105.03,77.44 105.03,78.92 105.24,79.89 v1(105.62,80.43)
  BOTTOM w0.191: v1(75.24,23.71) 74.98,23.27 74.29,21.42 74.29,20.57 74.29,20.56 74.29,20.01 74.27,20 DM2.66 ; CPU1.AN61 v1(105.62,80.43)
M_B_DQ29: length 74.9
  L2 w0.089: v1(73.81,24.53) 74.29,24.53 74.47,24.71 74.47,26.81 74.83,27.16 74.83,27.91 74.99,28.07 75.48,28.07 75.65,28.25 75.65,29.85 79.24,33.44 79.24,39.51 80.64,46.75 81.21,47.32 81.21,47.33 97.23,63.35 97.23,69.81 100.37,72.95 100.37,74.09 100.97,74.69 101.77,74.69 104.6,77.53 104.6,80.92 v1(104.71,81.03)
  BOTTOM w0.14: CPU1.AP61 104.71,80.5 v1(104.71,81.03)
  BOTTOM w0.191: v1(73.81,24.53) 74.29,24.53 74.85,25.09 74.85,26.38 74.52,26.7 DM2.67
M_B_DQ30: length 75.9
  L2 w0.089: v1(106.57,79.08) 106.57,78.96 106.96,78.57 106.96,77.23 106.24,76.52 106.24,75.51 102.9,72.17 102.9,71.51 102.22,70.83 102.22,69.53 101.41,68.72 101.41,63.63 86.11,48.32 86.11,33.89 81.53,29.31 81.53,27.98 81.44,27.89 81.03,27.89 80.94,27.8 80.94,27.51 81.03,27.42 81.44,27.42 81.53,27.33 81.53,26.42 81.4,26.29 80.57,26.29 80.49,26.38 80.49,26.68 80.4,26.77 80.1,26.77 80.02,26.68 80.02,26.38 79.93,26.29 78.73,26.29 78.44,26 78.44,24.02 78.56,23.9 v1(78.85,23.9)
  BOTTOM w0.191: v1(78.85,23.9) 78.47,23.9 77.39,24.98 77.39,26.34 77.52,26.48 DM2.79 ; CPU1.AT60 106.24,78.75 v1(106.57,79.08)
M_B_DQ31: length 74.8
  L2 w0.089: v1(78.88,22.54) 78.27,22.54 78.14,22.66 78.14,26.61 79.48,27.95 79.61,27.95 79.96,27.6 80.08,27.6 80.29,27.81 80.29,27.94 79.94,28.28 79.94,28.41 80.15,28.62 80.27,28.62 80.62,28.27 80.75,28.27 80.95,28.48 80.95,28.6 80.61,28.95 80.61,29.07 85.81,34.28 85.81,48.48 100.8,63.47 100.8,68.17 101.03,69.43 101.18,69.59 101.33,69.74 101.8,70.2 101.8,70.65 102.63,71.48 102.63,72.14 106.07,75.58 106.07,77.77 106.57,78.27 v1(106.57,78.4)
  BOTTOM w0.191: DM2.80 77.78,21.43 v1(78.88,22.54) ; v1(106.57,78.4) 106.27,78.1 CPU1.AU60
M_B_DQ32: length 70
  L2 w0.089: v1(102.74,22.4) 102.91,22.59 103.28,22.96 103.38,24.19 103.49,25.34 103.49,25.69 103.52,25.86 103.52,26.36 104.75,27.6 105.46,27.6 111.92,34.06 111.92,37.69 112.12,37.88 112.12,38.3 111.92,38.5 111.92,40.33 112.62,41.03 112.62,43.56 121.73,52.67 121.73,66.13 119.03,68.83 119.03,74.84 117.65,76.22 117.65,77.93 v1(117.52,78.38)
  BOTTOM w0.191: v1(102.74,22.4) 103.01,22.32 103.27,21.84 DM2.174 ; CPU1.AU40 v1(117.52,78.38)
M_B_DQ33: length 70
  L2 w0.089: v1(116.64,78.43) 116.64,78.33 117.12,77.85 117.29,77.08 117.29,75.84 118.56,74.58 118.56,68.74 121.15,66.15 121.15,52.91 111.31,43.08 111.31,34.41 110.25,33.34 109.53,33.34 106.11,29.92 106.11,29.53 105.86,29.28 105.47,29.28 102.27,26.08 102.27,23.82 102.4,23.69 v1(102.82,23.69)
  BOTTOM w0.191: v1(102.82,23.69) 103.17,24.04 103.17,25.9 103.02,26.04 DM2.173 ; CPU1.AT40 116.72,78.43 v1(116.64,78.43)
M_B_DQ34: length 71.6
  L2 w0.089: v1(118.41,79.08) 118.41,78.1 118.21,77.9 118.21,76.67 119.66,75.23 119.67,75.23 120.52,74.37 120.52,68.77 122.94,66.36 122.94,52.17 113.9,43.14 113.9,41.86 113.99,41.77 114.56,41.77 114.64,41.68 114.64,41.5 114.56,41.41 113.99,41.41 113.9,41.32 113.9,41.15 113.99,41.06 114.82,41.06 114.91,40.97 114.91,40.79 114.82,40.7 113.99,40.7 113.9,40.61 113.9,40.44 113.99,40.35 114.82,40.35 114.91,40.26 114.91,40.08 114.82,39.99 113.99,39.99 113.9,39.9 113.9,39.72 113.99,39.64 114.82,39.64 114.91,39.55 114.91,38.38 113.9,37.38 113.9,33.88 106.43,26.41 106.43,25.91 v1(106.02,25.5)
  BOTTOM w0.14: v1(118.41,79.08) 118.54,79.08 CPU1.AT37
  BOTTOM w0.191: DM2.187 106.53,26 v1(106.02,25.5)
M_B_DQ35: length 70.4
  L2 w0.089: v1(106.65,21.89) 106.14,21.89 105.82,22.21 105.82,23.3 107.04,24.52 107.04,26.13 114.47,33.57 114.81,33.57 115.51,34.26 115.51,38.16 115.51,38.16 115.51,43.91 123.52,51.93 123.52,66.42 120.92,69.03 120.92,74.48 119.46,75.94 119.45,75.94 118.57,76.82 118.57,77.69 v1(119.32,78.44)
  BOTTOM w0.14: CPU1.AU37 118.98,78.1 v1(119.32,78.44)
  BOTTOM w0.191: DM2.186 106.27,21.51 v1(106.65,21.89)
M_B_DQ36: length 70.6
  L2 w0.089: v1(102.23,20.97) 101.95,21.32 101.95,26.18 109.49,33.71 110.11,33.71 110.56,34.16 110.67,34.52 111.02,36.99 111.02,43.2 120.85,53.03 120.85,66.08 118.34,68.59 118.34,74.51 116.31,76.54 116.31,78.14 116.24,78.21 116.24,78.68 v1(116.64,79.09)
  BOTTOM w0.191: v1(116.64,79.09) 116.96,79.4 CPU1.AR40 ; v1(102.23,20.97) 102.27,20.92 DM2.170
M_B_DQ37: length 72.3
  L2 w0.089: v1(116.58,80.37) 117.08,79.87 117.08,78.26 117.47,77.87 117.47,76.02 118.82,74.68 118.82,68.73 121.44,66.11 121.44,52.79 111.6,42.95 111.6,42.66 111.69,42.57 112.22,42.57 112.32,42.47 112.32,41.19 112.24,41.11 112.06,41.11 111.97,41.19 111.97,42.12 111.87,42.22 111.69,42.22 111.6,42.13 111.6,34.16 105.36,27.92 104.62,27.92 103.12,26.41 103.12,25.52 103.1,25.51 103.1,25.43 v1(102.69,25.02)
  BOTTOM w0.14: CPU1.AP40 116.9,80.05 v1(116.58,80.37)
  BOTTOM w0.191: v1(102.69,25.02) 102.02,25.68 DM2.169
M_B_DQ38: length 73.2
  L2 w0.089: v1(118.41,80.38) 118.92,79.87 118.92,79.45 119.03,79.34 119.71,78.66 119.71,78.23 119.36,77.88 119.36,77.32 119.24,77.2 119.24,76.4 119.5,76.14 119.51,76.14 121.09,74.56 121.09,69.1 123.81,66.38 123.81,51.81 115.8,43.79 115.8,38.04 115.8,38.03 115.8,34.14 114.93,33.28 114.77,33.12 114.45,33.12 114.28,32.95 114.28,32.6 114.08,32.4 113.71,32.4 113.47,32.15 113.47,31.8 113.25,31.58 112.9,31.58 111.54,30.23 111.54,30.1 111.63,30.02 111.63,29.89 111.51,29.76 111.38,29.76 111.29,29.85 111.17,29.85 111.04,29.72 111.04,29.6 111.13,29.51 111.13,29.39 111,29.26 110.88,29.26 110.79,29.35 110.66,29.35 107.33,26.01 107.33,24.18 v1(106.61,23.47)
  BOTTOM w0.14: v1(118.41,80.38) 118.73,80.05 CPU1.AP37
  BOTTOM w0.191: v1(106.61,23.47) 106.54,23.47 105.52,24.49 105.52,24.88 105.53,24.89 DM2.183
M_B_DQ39: length 72.4
  L2 w0.089: v1(118.41,79.73) 118.74,79.4 118.74,79.38 118.8,79.32 118.8,78.22 118.39,77.81 118.39,76.75 119.71,75.43 119.72,75.43 120.74,74.41 120.74,68.81 123.23,66.32 123.23,52.05 115.22,44.04 115.22,42.86 115.11,42.75 114.39,42.75 114.3,42.67 114.3,42.31 114.39,42.22 115.13,42.22 115.22,42.13 115.22,38.28 114.24,37.3 114.24,33.75 106.74,26.25 106.74,24.81 105.31,23.37 v1(105.31,22.43)
  BOTTOM w0.14: CPU1.AR37 118.54,79.73 v1(118.41,79.73)
  BOTTOM w0.191: v1(105.31,22.43) 105.28,22.41 105.28,20.77 105.27,20.76 DM2.182
M_B_DQ40: length 70.5
  L2 w0.089: v1(120.24,79.08) 120.24,78.15 119.77,77.69 119.77,77.26 120.24,76.8 120.24,76.37 122.52,74.09 122.52,68.75 124.4,66.87 124.4,51.54 116.39,43.53 116.39,37.79 116.39,37.79 116.39,33.87 115.78,33.27 115.78,33.15 116.04,32.89 116.04,32.77 115.91,32.64 115.79,32.64 115.53,32.89 115.41,32.89 115.28,32.77 115.28,32.64 115.53,32.39 115.53,32.26 115.41,32.14 115.28,32.14 115.03,32.39 114.9,32.39 114.78,32.26 114.78,32.14 115.03,31.89 115.03,31.76 114.91,31.64 114.78,31.64 114.53,31.89 114.4,31.89 114.28,31.76 114.28,31.64 114.53,31.38 114.53,31.26 114.4,31.13 114.28,31.13 114.02,31.39 113.9,31.39 113.69,31.18 113.69,30.71 109.76,26.77 108.95,26.77 108.28,26.1 v1(108.28,24.74)
  BOTTOM w0.191: CPU1.AT33 120.37,79.08 v1(120.24,79.08) ; v1(108.28,24.74) 108.53,24.98 DM2.195
M_B_DQ41: length 70
  L2 w0.089: v1(120.16,77.51) 120.42,77.26 120.42,76.5 122.85,74.07 122.85,68.84 124.69,67 124.69,51.37 116.68,43.36 116.68,40.02 117.43,39.27 117.43,33.69 113.8,30.06 113.48,30.06 109.86,26.44 109.03,26.44 108.6,26.01 108.6,25.04 108.7,24.94 108.7,23.26 108.4,22.96 107.88,22.96 107.62,22.7 107.62,21.89 v1(108.31,21.2)
  BOTTOM w0.191: v1(120.16,77.51) 120.69,78.04 CPU1.AU33 ; v1(108.31,21.2) 108.27,21.17 DM2.194
M_B_DQ42: length 69
  L2 w0.089: v1(111.04,24.15) 111.74,24.85 111.74,25.69 114.32,28.27 114.55,28.27 119.29,33.01 119.65,33.01 120.25,33.6 120.25,35.8 120.33,35.88 120.46,35.88 120.55,35.97 120.55,36.15 120.46,36.24 120.33,36.24 120.25,36.33 120.25,44.39 126.48,50.63 126.48,56.21 126.57,56.3 126.78,56.3 126.87,56.39 126.87,56.57 126.78,56.66 126.57,56.66 126.48,56.74 126.48,56.92 126.57,57.01 126.78,57.01 126.87,57.1 126.87,57.28 126.78,57.37 126.57,57.37 126.48,57.46 126.48,57.63 126.57,57.72 126.78,57.72 126.87,57.81 126.87,62.91 127.07,63.53 127.07,64.91 126.5,68.05 125.24,69.31 125.24,71.13 124.85,71.52 124.79,71.52 124.53,71.79 124.53,74.57 122.62,76.47 122.62,76.83 122.07,77.39 v1(122.07,78.43)
  BOTTOM w0.191: CPU1.AU30 122.2,78.43 v1(122.07,78.43) ; v1(111.04,24.15) 111.05,24.15 111.53,24.63 DM2.207
M_B_DQ43: length 69.7
  L2 w0.089: v1(122.1,79.07) 122.45,78.62 122.45,78.1 122.41,78.06 122.41,77.33 122.83,76.91 122.83,76.64 125.47,74 125.47,69.6 126.74,68.33 127.36,64.93 127.36,63.48 127.16,62.86 127.16,50.9 121.49,45.22 121.49,36.6 121.2,36.31 121.2,33.99 119.87,32.67 119.36,32.67 114.67,27.98 114.44,27.98 112.03,25.57 112.03,24.77 111.56,23.88 111.38,23.27 v1(111,22.88)
  BOTTOM w0.191: v1(111,22.88) 111.04,22.88 111.76,22.15 111.76,20.55 111.77,20.53 DM2.208 ; CPU1.AT30 v1(122.1,79.07)
M_B_DQ44: length 71.1
  L2 w0.089: v1(108.23,23.39) 107.8,23.81 107.8,26.04 108.87,27.1 109.68,27.1 113.4,30.83 113.4,31.3 116.09,33.99 116.09,37.91 116.09,43.65 124.11,51.66 124.11,66.34 121.27,69.18 121.27,75.01 120.06,76.22 120.06,76.73 119.6,77.19 119.6,77.76 119.89,78.05 119.89,78.83 119.85,78.87 119.85,79.33 v1(120.24,79.72)
  BOTTOM w0.191: DM2.191 107.53,25.5 107.27,25.25 107.27,24.31 108.19,23.39 v1(108.23,23.39) ; CPU1.AR33 120.38,79.72 v1(120.24,79.72)
M_B_DQ45: length 71.9
  L2 w0.089: v1(120.28,80.35) 120.63,80.01 120.63,76.72 123.02,74.32 123.02,69.07 124.87,67.23 124.87,64.96 125.57,64.26 125.57,63.9 124.98,63.32 124.98,51.25 117.72,43.98 117.72,33.57 113.92,29.77 113.63,29.77 109.12,25.26 109.12,23.25 v1(108.35,22.48)
  BOTTOM w0.191: CPU1.AP33 120.39,80.35 v1(120.28,80.35) ; v1(108.35,22.48) 107.66,22.48 107.27,22.1 DM2.190
M_B_DQ46: length 70.2
  L2 w0.089: v1(111.01,24.79) 111.43,25.21 111.43,25.79 114.2,28.56 114.43,28.56 119.17,33.3 119.53,33.3 119.95,33.72 119.95,44.51 126.19,50.75 126.19,58.03 126.28,58.12 126.48,58.12 126.56,58.21 126.56,58.38 126.48,58.47 126.28,58.47 126.19,58.56 126.19,58.74 126.28,58.83 126.48,58.83 126.56,58.92 126.56,59.1 126.48,59.18 126.28,59.18 126.19,59.27 126.19,59.45 126.28,59.54 126.48,59.54 126.56,59.63 126.56,59.81 126.48,59.9 126.28,59.9 126.19,59.98 126.19,60.16 126.28,60.25 126.48,60.25 126.56,60.34 126.56,60.52 126.48,60.61 126.28,60.61 126.19,60.7 126.19,60.87 126.28,60.96 126.48,60.96 126.56,61.05 126.56,61.23 126.48,61.32 126.28,61.32 126.19,61.41 126.19,61.7 126.77,63.57 126.77,64.76 126.22,67.79 124.31,69.71 124.31,74.43 122.42,76.33 122.42,76.75 121.83,77.34 121.83,78.03 121.68,78.19 121.68,78.8 121.71,78.83 121.71,79.37 v1(122.07,79.73)
  BOTTOM w0.191: v1(111.01,24.79) 110.72,24.79 110.53,24.98 DM2.203 ; v1(122.07,79.73) 122.2,79.73 CPU1.AR30
M_B_DQ47: length 71.3
  L2 w0.089: v1(111.06,21.58) 111.35,21.95 111.87,23.36 111.87,23.68 112.32,24.14 112.32,25.45 114.43,27.55 115.05,27.55 118.97,31.47 119.09,31.47 121.49,33.87 121.49,36.17 121.69,36.38 121.69,36.4 121.78,36.48 121.78,44.87 127.72,50.81 127.72,67.89 125.73,69.88 125.73,74.05 123.08,76.7 123.08,77.01 122.58,77.5 122.58,77.96 122.63,78 122.63,79.25 122.44,80 v1(122.07,80.38)
  BOTTOM w0.191: v1(111.06,21.58) 110.77,21.29 DM2.204 ; CPU1.AP30 v1(122.07,80.38)
M_B_DQ48: length 72.3
  L2 w0.089: v1(113.91,22.08) 113.92,22.08 114.53,22.7 114.82,22.7 114.91,22.79 114.91,22.97 114.82,23.05 114.57,23.05 114.46,23.16 114.46,25.59 115.24,26.37 115.53,26.37 119.46,30.3 119.58,30.3 119.81,30.53 119.93,30.53 120.11,30.35 120.24,30.35 120.36,30.48 120.36,30.61 120.18,30.79 120.18,30.91 120.31,31.04 120.44,31.04 120.62,30.86 120.74,30.86 120.87,30.98 120.87,31.11 120.69,31.29 120.69,31.41 120.81,31.54 120.94,31.54 121.12,31.36 121.24,31.36 121.37,31.49 121.37,31.61 121.19,31.79 121.19,31.92 121.32,32.04 121.44,32.04 121.62,31.86 121.75,31.86 121.87,31.99 121.87,32.11 121.69,32.29 121.69,32.42 121.82,32.55 121.94,32.55 122.12,32.37 122.25,32.37 122.38,32.49 122.38,32.62 122.2,32.8 122.2,32.92 122.42,33.15 123.22,33.15 123.92,33.84 123.92,45.35 128.89,50.33 128.89,68.4 128.22,69.08 128.22,71.59 128.22,71.59 128.22,71.91 128.22,71.91 128.22,74.02 127.49,74.75 126.44,74.75 125.05,76.14 125.05,77.51 v1(124.81,77.74)
  BOTTOM w0.14: v1(124.81,77.74) 124.45,78.1 CPU1.AU27
  BOTTOM w0.191: DM2.216 113.77,20.54 113.78,20.55 113.78,21.95 v1(113.91,22.08)
M_B_DQ49: length 72.9
  L2 w0.089: v1(123.9,78.43) 124.4,77.92 124.4,77.56 124.86,77.1 124.86,76.02 127.01,73.87 127.01,69.88 128.6,68.28 128.6,50.45 123.62,45.47 123.62,44.7 123.53,44.61 123.02,44.61 122.94,44.52 122.94,44.34 123.02,44.25 123.53,44.25 123.62,44.16 123.62,43.99 123.53,43.9 123.02,43.9 122.94,43.81 122.94,43.63 123.02,43.54 123.53,43.54 123.62,43.45 123.62,33.96 123.1,33.44 122.3,33.44 119.46,30.6 119.34,30.6 115.42,26.67 115.13,26.67 114.08,25.62 114.08,24.69 113.42,24.03 113.42,23.9 113.75,23.56 113.75,23.44 113.63,23.31 113.5,23.31 113.17,23.65 113.04,23.65 v1(112.7,23.3)
  BOTTOM w0.14: v1(123.9,78.43) 124.22,78.75 CPU1.AT27
  BOTTOM w0.191: v1(112.7,23.3) 113.52,24.12 113.52,24.22 113.52,24.23 113.52,24.62 113.52,24.63 113.52,26.53 113.53,26.54 DM2.215
M_B_DQ50: length 71.2
  L2 w0.089: v1(115.57,23.13) 116.08,23.71 116.84,24.71 116.84,25.97 119.14,28.28 120.42,28.28 122.73,30.59 122.94,30.59 126.21,33.85 126.21,44.83 126.12,44.92 125.72,44.92 125.63,45.01 125.63,45.18 125.72,45.27 126.12,45.27 126.21,45.36 126.21,45.91 130.1,49.8 130.1,69.04 128.87,70.27 128.87,74.19 127.56,75.51 126.77,75.51 125.66,76.62 125.66,78.06 124.81,78.91 v1(124.81,79.08)
  BOTTOM w0.191: CPU1.AT25 v1(124.81,79.08) ; DM2.228 116.77,21.1 116.83,21.15 116.83,21.55 v1(115.57,23.13)
M_B_DQ51: length 70.7
  L2 w0.089: v1(117.56,25.05) 119.05,26.54 119.51,26.54 121.4,28.43 121.62,28.43 126.79,33.61 126.79,41.08 126.88,41.17 127.07,41.17 127.16,41.26 127.16,41.44 127.07,41.53 126.88,41.53 126.79,41.62 126.79,41.79 126.88,41.88 127.07,41.88 127.16,41.97 127.16,42.15 127.07,42.24 126.88,42.24 126.79,42.33 126.79,42.51 126.88,42.6 127.07,42.6 127.16,42.68 127.16,42.86 127.07,42.95 126.88,42.95 126.79,43.04 126.79,43.22 126.88,43.31 127.07,43.31 127.16,43.4 127.16,43.57 127.07,43.66 126.88,43.66 126.79,43.75 126.79,43.93 126.88,44.02 127.07,44.02 127.16,44.11 127.16,44.28 127.07,44.37 126.88,44.37 126.79,44.46 126.79,44.64 126.88,44.73 127.07,44.73 127.16,44.82 127.16,45 127.07,45.08 126.88,45.08 126.79,45.17 126.79,45.67 130.68,49.56 130.68,69.29 129.23,70.74 129.23,74.34 127.59,75.98 126.8,75.98 126.07,76.71 126.07,78.26 125.74,78.59 125.72,79.14 v1(125.72,79.73)
  BOTTOM w0.14: v1(125.72,79.73) 125.72,78.77 125.58,78.62 125.27,78.31 CPU1.AU25
  BOTTOM w0.191: v1(117.56,25.05) 117.5,25.05 117.02,25.53 DM2.229
M_B_DQ52: length 73.2
  L2 w0.089: v1(113.05,24.42) 113.77,25.15 113.77,25.73 115.01,26.96 115.3,26.96 119.22,30.89 119.34,30.89 122.64,34.2 122.64,39.78 122.73,39.87 123.24,39.87 123.33,39.96 123.33,40.13 123.24,40.22 122.73,40.22 122.64,40.31 122.64,40.49 122.73,40.58 123.24,40.58 123.33,40.67 123.33,40.85 123.24,40.93 122.73,40.93 122.64,41.02 122.64,41.2 122.73,41.29 123.24,41.29 123.33,41.38 123.33,41.56 123.24,41.65 122.73,41.65 122.64,41.73 122.64,41.91 122.73,42 123.17,42 123.26,42.09 123.26,42.27 123.17,42.36 122.73,42.36 122.64,42.45 122.64,44.91 128.31,50.57 128.31,68.14 126.79,69.66 126.79,73.74 124.07,76.47 124.07,76.79 124.18,76.91 124.18,77.68 123.86,78 123.78,78 123.51,78.27 123.51,80 v1(123.9,80.38)
  BOTTOM w0.14: CPU1.AP27 124.22,80.05 v1(123.9,80.38)
  BOTTOM w0.191: DM2.211 112.53,24.95 v1(113.05,24.42)
M_B_DQ53: length 73.7
  L2 w0.089: v1(112.77,20.96) 112.27,21.47 112.27,23.56 112.62,23.9 112.62,25.32 114.55,27.26 115.18,27.26 119.1,31.18 119.21,31.18 122.35,34.32 122.35,40.54 122.26,40.63 122.16,40.63 122.07,40.72 122.07,40.9 122.16,40.98 122.26,40.98 122.35,41.07 122.35,41.25 122.26,41.34 122.16,41.34 122.07,41.43 122.07,41.61 122.16,41.7 122.26,41.7 122.35,41.79 122.35,41.96 122.26,42.05 122.16,42.05 122.07,42.14 122.07,42.32 122.16,42.41 122.26,42.41 122.35,42.5 122.35,42.67 122.26,42.76 122.16,42.76 122.07,42.85 122.07,43.03 122.16,43.12 122.26,43.12 122.35,43.21 122.35,43.39 122.26,43.47 122.16,43.47 122.07,43.56 122.07,43.74 122.16,43.83 122.26,43.83 122.35,43.92 122.35,44.1 122.26,44.19 122.16,44.19 122.07,44.27 122.07,44.45 122.16,44.54 122.26,44.54 122.35,44.63 122.35,45.03 128.02,50.69 128.02,68.01 126.58,69.45 126.58,73.69 123.38,76.89 123.38,77.98 123.33,78.03 123.33,80.15 123.39,80.21 123.39,80.52 v1(123.9,81.03)
  BOTTOM w0.14: CPU1.AN27 124.22,80.7 v1(123.9,81.03)
  BOTTOM w0.191: DM2.212 112.77,20.96 v1(112.77,20.96)
M_B_DQ54: length 73.5
  L2 w0.089: v1(124.81,81.03) 125.45,81.42 125.88,81.42 126.11,81.19 126.11,79.53 126.07,79.49 126.07,78.76 126.25,78.58 126.25,77.62 126.87,76.99 126.91,76.99 129.41,74.49 129.41,70.97 130.98,69.41 130.98,49.44 127.65,46.11 127.65,39.62 128.11,39.16 128.11,34.29 121.96,28.14 121.52,28.14 119.63,26.25 119.23,26.25 118.61,25.63 118.06,23.71 117.7,23.35 117.3,23.35 116.14,22.24 v1(115.49,21.68)
  BOTTOM w0.191: CPU1.AN25 v1(124.81,81.03) ; v1(115.49,21.68) 115.77,21.07 DM2.224
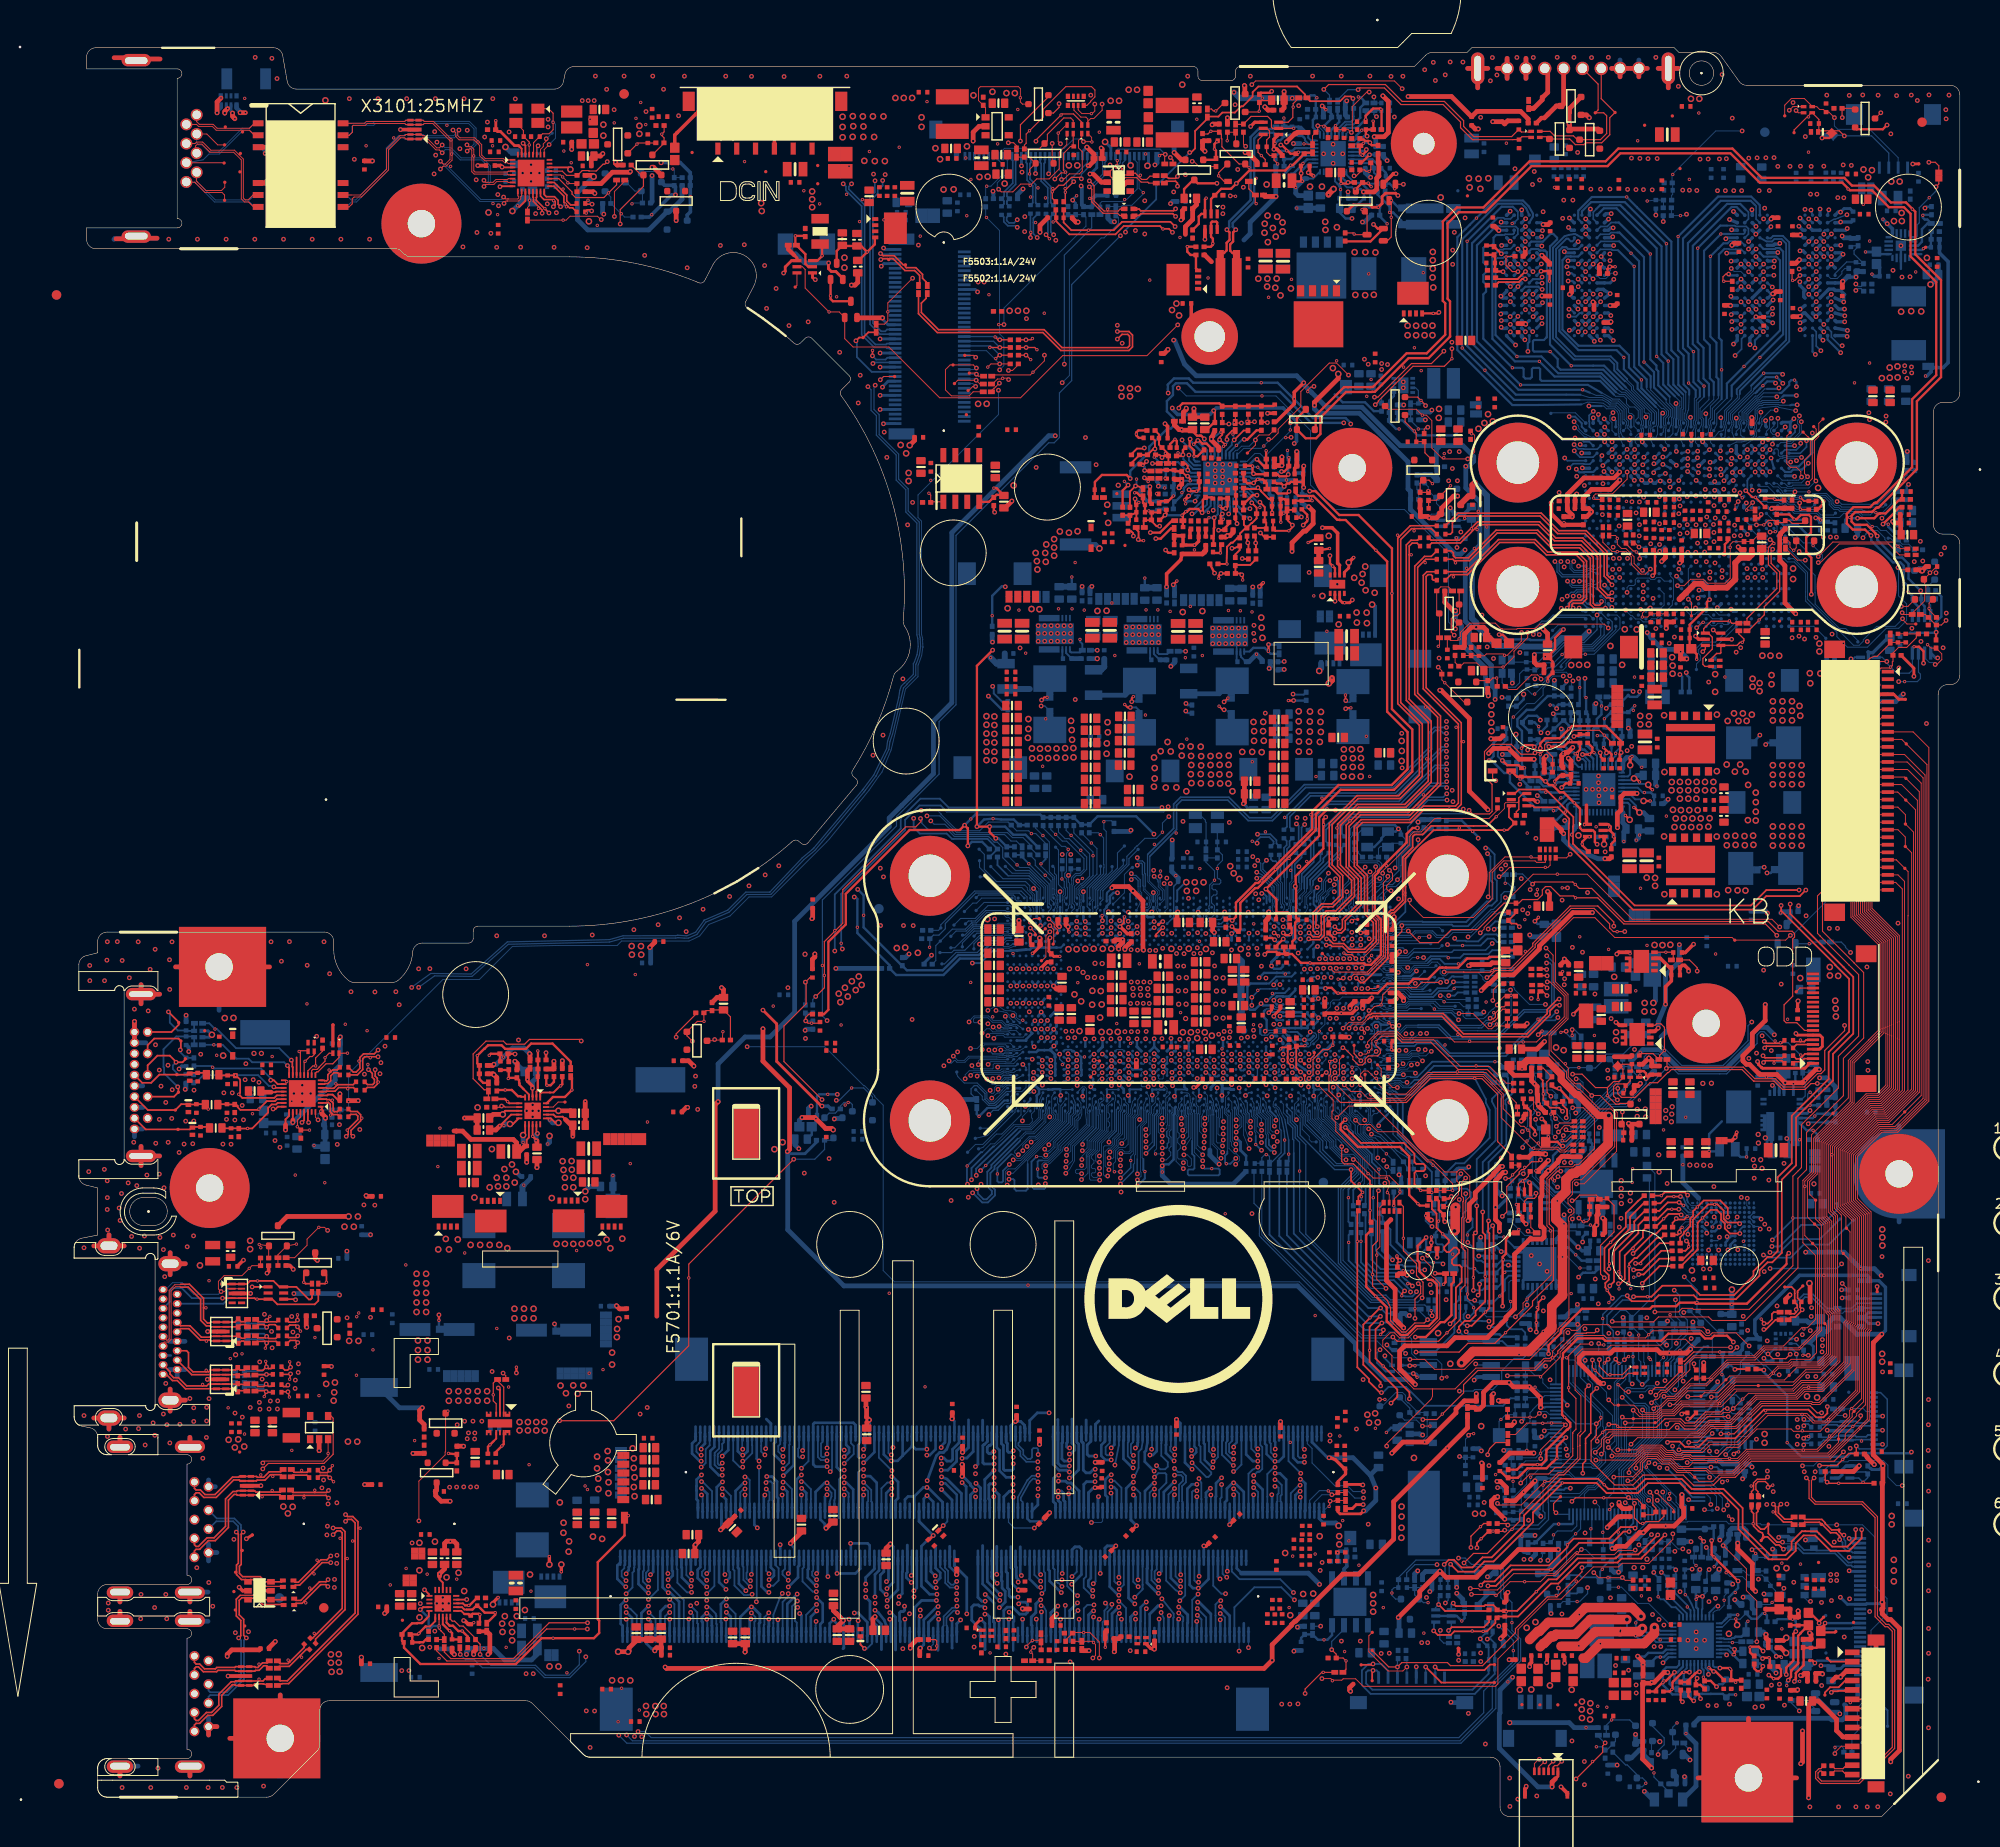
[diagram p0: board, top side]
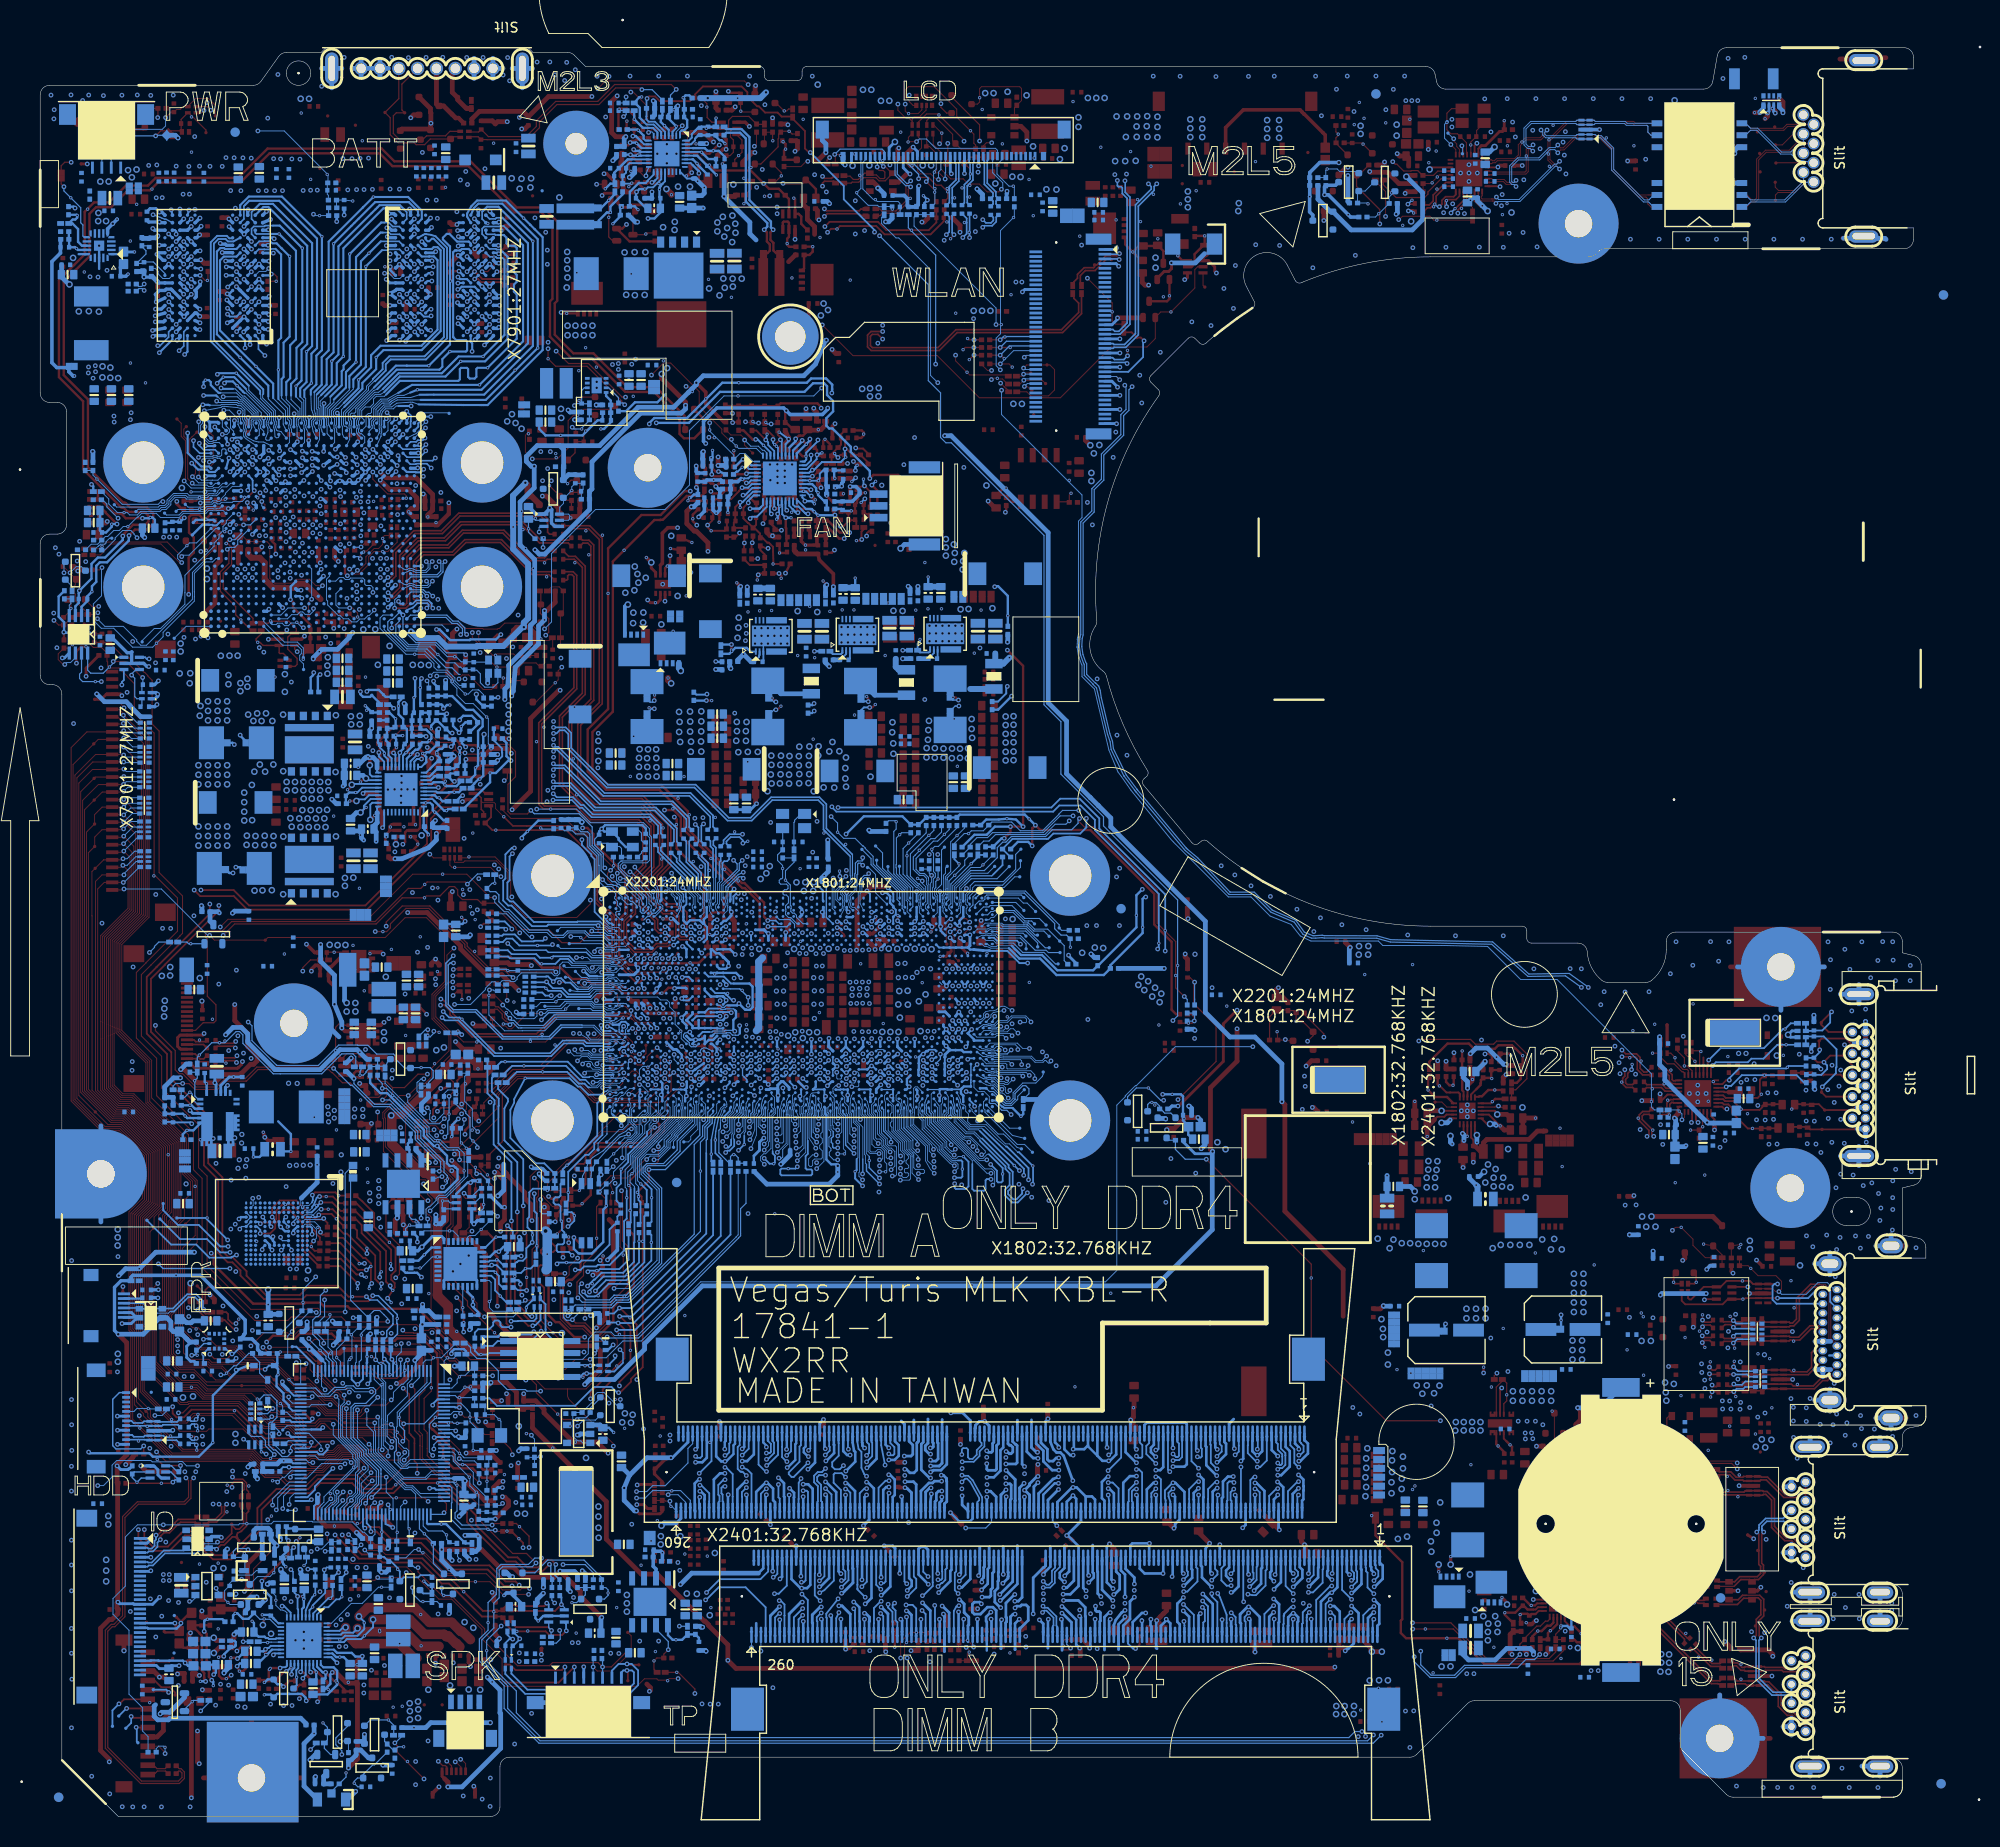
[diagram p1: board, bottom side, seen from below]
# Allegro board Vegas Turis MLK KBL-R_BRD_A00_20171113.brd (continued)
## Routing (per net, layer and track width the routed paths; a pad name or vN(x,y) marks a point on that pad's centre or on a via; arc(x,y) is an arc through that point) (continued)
M_B_DQ55: length 72.7
  L2 w0.089: v1(124.81,80.38) 125.24,79.8 125.24,78.78 125.88,78.15 125.88,76.65 126.77,75.76 127.55,75.76 129.05,74.27 129.05,70.51 130.39,69.17 130.39,49.68 126.5,45.79 126.5,33.73 121.5,28.73 121.28,28.73 120.54,27.98 119.26,27.98 118.58,27.3 118.58,27.18 118.85,26.91 118.85,26.78 118.73,26.65 118.6,26.65 118.33,26.93 118.21,26.93 118.08,26.8 118.08,26.67 118.35,26.4 118.35,26.28 118.23,26.15 118.1,26.15 117.83,26.42 117.7,26.42 117.13,25.85 117.13,24.17 v1(117.53,23.78)
  BOTTOM w0.191: CPU1.AP25 v1(124.81,80.38) ; DM2.225 116.02,25.07 117.04,24.05 v1(117.53,23.78)
M_B_DQ56: length 70.6
  L2 w0.089: v1(119.46,24.9) 119.89,24.9 120.49,25.5 120.49,26.28 121.76,27.56 122.1,27.56 122.29,27.56 128.9,34.16 128.9,39.37 128.99,39.46 129.31,39.46 129.4,39.55 129.4,39.73 129.31,39.82 128.99,39.82 128.9,39.91 128.9,40.09 128.99,40.17 129.31,40.17 129.4,40.26 129.4,40.44 129.31,40.53 128.99,40.53 128.9,40.62 128.9,40.8 128.99,40.89 129.31,40.89 129.4,40.97 129.4,41.15 129.31,41.24 128.99,41.24 128.9,41.33 128.9,41.51 128.99,41.6 129.31,41.6 129.4,41.69 129.4,41.86 129.31,41.95 128.99,41.95 128.9,42.04 128.9,42.22 128.99,42.31 129.31,42.31 129.4,42.4 129.4,42.57 129.31,42.66 128.61,42.66 128.38,42.89 128.38,44.33 128.9,44.85 128.9,46.26 131.56,48.92 131.56,69.79 130.13,71.22 130.13,73.36 130.56,73.79 130.56,74.41 129.87,75.1 129.37,75.1 127.21,77.26 127.21,78.03 126.73,78.51 126.73,78.99 v1(126.64,79.08)
  BOTTOM w0.191: CPU1.AT22 126.96,78.75 v1(126.64,79.08) ; v1(119.46,24.9) 119.22,24.9 119.02,25.09 DM2.237
M_B_DQ57: length 70.5
  L2 w0.089: v1(119.41,23.63) 119.57,23.63 120.82,24.88 120.82,26.2 121.88,27.27 122.3,27.27 122.41,27.27 129.19,34.04 129.19,38.92 129.69,39.43 129.69,42.7 129.68,42.71 129.68,43.26 129.59,43.35 129.15,43.35 129.06,43.44 129.06,43.62 129.15,43.7 129.52,43.7 129.68,43.86 129.68,44.14 129.59,44.23 129.28,44.23 129.19,44.32 129.19,44.49 129.28,44.58 129.59,44.58 129.68,44.67 129.68,44.85 129.59,44.94 129.28,44.94 129.19,45.03 129.19,45.2 129.28,45.29 129.59,45.29 129.68,45.38 129.68,45.56 129.59,45.65 129.28,45.65 129.19,45.74 129.19,45.92 129.28,46 129.59,46 129.68,46.09 129.68,46.63 131.85,48.8 131.85,69.91 130.49,71.28 130.49,73.36 130.82,73.69 130.82,74.41 129.64,75.58 129.15,75.58 127.6,77.14 v1(127.6,77.45)
  BOTTOM w0.191: CPU1.AU22 127.1,77.95 v1(127.6,77.45) ; v1(119.41,23.63) 118.79,23.01 118.79,19.32 DM2.236
M_B_DQ58: length 68.9
  L2 w0.089: v1(127.62,78.42) 127.62,78.39 128.23,77.78 128.23,77.04 129.17,76.1 129.73,76.1 131.3,74.53 131.3,73.46 131.07,73.23 131.07,71.52 132.44,70.15 132.44,48.47 130.33,46.36 130.33,43.62 130.42,43.53 130.76,43.53 130.85,43.44 130.85,43.26 130.76,43.18 130.42,43.18 130.33,43.09 130.33,42.91 130.42,42.82 130.76,42.82 130.85,42.73 130.85,42.55 130.76,42.46 130.42,42.46 130.33,42.38 130.33,42.2 130.42,42.11 130.76,42.11 130.85,42.02 130.85,41.84 130.76,41.75 130.42,41.75 130.33,41.66 130.33,41.49 130.42,41.4 130.76,41.4 130.85,41.31 130.85,41.13 130.76,41.04 130.42,41.04 130.33,40.95 130.33,40.78 130.42,40.69 130.76,40.69 130.85,40.6 130.85,40.42 130.76,40.33 130.42,40.33 130.33,40.24 130.33,40.06 130.42,39.98 130.76,39.98 130.85,39.89 130.85,39.71 130.76,39.62 130.42,39.62 130.33,39.53 130.33,39.24 129.78,38.68 129.78,38.15 129.86,38.07 130.04,38.07 130.13,37.98 130.13,37.8 130.04,37.71 129.86,37.71 129.78,37.62 129.78,33.8 122.62,26.65 122.13,26.65 121.75,26.27 121.75,25.96 122.28,25.43 v1(122.46,25.43)
  BOTTOM w0.191: v1(127.62,78.42) 127.69,78.42 CPU1.AU21 ; v1(122.46,25.43) 122.38,25.43 122.02,25.79 DM2.249
M_B_DQ59: length 69.9
  L2 w0.089: v1(128.47,79.08) 128.61,78.94 128.61,78.41 132.87,74.15 132.87,71.53 133.64,70.76 133.64,70.61 133.64,70.61 133.64,48.38 133.64,48.38 133.64,47.97 132.06,46.38 132.06,33.75 131,32.69 130.56,32.69 124.42,26.55 124.42,25.53 122.99,24.11 122.16,24.11 121.04,22.98 121.04,21.76 120.93,21.65 120.93,21.5 121.13,21.3 121.28,21.3 121.55,21.57 v1(121.77,21.57)
  BOTTOM w0.191: DM2.250 122.27,21.14 121.85,21.57 v1(121.77,21.57) ; v1(128.47,79.08) 128.14,78.75 CPU1.AT21
M_B_DQ60: length 72.2
  L2 w0.089: v1(117.36,21.63) 118.35,21.63 118.52,21.8 118.52,22.79 118.94,23.2 119.59,23.2 119.84,23.45 119.84,23.49 121.23,24.88 121.23,26.2 122.01,26.97 122.42,26.97 122.42,26.97 122.54,26.97 129.48,33.92 129.48,38.8 130,39.32 130,46.54 132.14,48.68 132.14,70.03 130.79,71.38 130.79,73.28 131.05,73.54 131.05,74.43 129.66,75.82 129.17,75.82 128.05,76.94 128.05,77.62 127.79,77.88 127.62,77.88 127.46,78.04 127.46,78.04 127.23,78.26 127.23,78.27 127.15,78.35 127.15,79.87 v1(126.64,80.38)
  BOTTOM w0.191: DM2.232 117.77,20.72 117.84,20.78 117.84,21.18 117.39,21.63 v1(117.36,21.63) ; v1(126.64,80.38) 126.96,80.7 CPU1.AN22
M_B_DQ61: length 71.9
  L2 w0.089: v1(117.48,22.93) 117.69,22.93 118.47,23.7 118.9,25.51 119.35,25.96 119.75,25.96 121.64,27.85 122.17,27.85 128.6,34.28 128.6,42.16 127.94,42.82 127.94,45.99 131.27,49.32 131.27,69.67 129.83,71.11 129.83,73.46 130.28,73.92 130.28,74.44 129.84,74.89 129.34,74.89 127.03,77.19 127.03,77.95 126.5,78.49 126.5,78.64 126.25,78.89 126.25,79.34 v1(126.64,79.73)
  BOTTOM w0.191: CPU1.AP22 126.77,79.73 v1(126.64,79.73) ; v1(117.48,22.93) 118.05,23.5 118.05,25.83 118.02,25.85 DM2.233
M_B_DQ62: length 71
  L2 w0.089: v1(122.33,23.67) 122.71,23.29 122.71,22.68 122.84,22.56 123.1,22.56 123.23,22.68 123.23,23.86 124.75,25.38 124.75,26.34 130.74,32.34 131.25,32.34 132.35,33.43 132.35,46.26 133.94,47.84 133.94,48.5 133.94,70.73 133.93,70.73 133.93,71.38 133.1,72.21 133.1,74.17 128.89,78.39 128.89,78.41 128.87,78.43 128.87,79.33 v1(128.47,79.73)
  BOTTOM w0.191: v1(122.33,23.67) 121.88,23.67 121.02,24.53 DM2.245 ; CPU1.AP21 128.34,79.73 v1(128.47,79.73)
M_B_DQ63: length 72.1
  L2 w0.089: v1(121.83,22.94) 122.74,22.02 123.22,22.02 123.64,22.44 123.64,23.86 125.1,25.32 125.1,26.28 130.77,31.96 131.38,31.96 132.64,33.22 132.64,46.14 134.23,47.72 134.23,48.62 134.23,71.7 133.48,72.44 133.48,74.24 130.89,76.84 130.72,76.84 129.04,78.51 129.04,79.48 128.85,79.67 128.85,79.96 v1(128.43,80.39)
  BOTTOM w0.191: v1(121.83,22.94) 121.67,22.94 121.27,22.53 121.27,21.35 121.27,21.34 DM2.246 ; v1(128.43,80.39) 128.43,80.39 128.32,80.39 CPU1.AN21
M_B_DQS_DN0: length 88.1
  L2 w0.102: v1(102.11,83.7) 102.11,83.33 102.02,83.24 101.59,83.24 98.88,80.53 95.26,80.53 94.87,80.14 94.51,80.14 92.94,78.56 90.47,78.56 87.4,75.49 87.4,72.19 88.69,70.9 88.69,70.4 88.58,70.29 88.42,70.29 88.2,70.07 88.2,69.6 88.42,69.38 88.58,69.38 88.69,69.28 88.69,68.97 88.58,68.87 88.42,68.87 88.2,68.65 88.2,68.18 88.42,67.96 88.58,67.96 88.69,67.86 88.69,67.55 88.58,67.45 88.42,67.45 88.2,67.23 88.2,66.76 88.42,66.54 88.58,66.54 88.69,66.43 88.69,66.13 88.58,66.03 88.42,66.03 88.2,65.81 88.2,65.33 88.42,65.11 88.58,65.11 88.69,65.01 88.69,63.7 69.56,44.58 69.56,33.56 67.15,31.15 67.15,27.75 66.08,26.68 66.08,23.59 65.07,22.58 65.07,22.12 v1(65.5,21.69)
  BOTTOM w0.191: v1(102.11,83.7) 102.44,83.37 CPU1.AH66 ; DM2.32 65.78,20.77 65.79,20.79 65.79,21.18 65.78,21.19 65.78,21.41 v1(65.5,21.69)
M_B_DQS_DN1: length 89.4
  L2 w0.102: v1(61.02,24.39) 60.41,24.39 60.16,24.63 60.16,25.74 60.93,26.51 60.93,30.42 62.76,32.25 62.76,43.31 72.62,53.17 72.94,53.17 73.17,52.93 73.31,52.93 73.53,53.15 73.53,53.29 73.3,53.53 73.3,53.84 73.77,54.32 74.09,54.32 74.32,54.08 74.47,54.08 74.89,54.51 74.89,54.97 75.3,55.38 75.76,55.38 84.11,63.73 84.11,77.06 91.76,84.7 94.45,84.7 v1(95.08,84.45)
  BOTTOM w0.089: v1(95.08,84.45) 95.34,84.8 95.62,85.08 97.16,85.08 97.64,84.61 98.57,84.61 98.98,84.19 99.26,84.19 99.41,84.24 99.6,84.24 99.81,84.18 100.13,84.18 CPU1.AG69
  BOTTOM w0.191: v1(61.02,24.39) 60.43,24.97 60.43,25.37 60.43,26.03 60.52,26.13 DM2.11
M_B_DQS_DN2: length 76.2
  L2 w0.102: v1(71.85,24.42) 71.84,24.43 71.13,24.43 70.89,24.68 70.89,25.52 71.11,25.74 71.11,28.37 76.09,33.35 76.09,44.86 76.74,45.51 76.74,46.09 76.95,46.3 77.53,46.3 77.75,46.52 77.75,47.1 77.96,47.31 78.54,47.31 78.76,47.53 78.76,48.11 92.41,61.76 92.41,63.75 92.63,63.97 93,63.97 93.1,64.07 93.1,64.48 93,64.58 92.63,64.58 92.41,64.8 92.41,66.65 92.63,66.87 93.08,66.87 93.18,66.97 93.18,67.38 93.08,67.48 92.63,67.48 92.41,67.7 92.41,68.38 99.55,75.51 99.55,76.52 100.76,77.73 101.91,77.73 102.86,78.68 v1(102.86,79.08)
  BOTTOM w0.191: CPU1.AR66 v1(102.86,79.08) ; DM2.53 71.02,26.6 71.11,26.52 71.11,25.14 71.66,24.59 71.68,24.59 v1(71.85,24.42)
M_B_DQS_DN3: length 74.6
  L2 w0.089: 105.68,77.27 105.68,77.28 105.68,77.97 105.99,78.27 105.99,79.35 v1(105.61,79.73)
  L2 w0.102: v1(76.84,22.9) 77.3,22.9 77.43,23.03 77.43,27.01 84.99,34.58 84.99,48.66 99.94,63.61 99.94,65.23 99.84,65.33 99.54,65.33 99.32,65.55 99.32,66.13 99.54,66.35 99.84,66.35 99.94,66.45 99.94,69.35 102.16,71.56 102.16,72.28 105.68,75.8 105.68,77.27
  BOTTOM w0.191: CPU1.AR61 105.28,79.4 v1(105.61,79.73) ; DM2.74 76.27,22.33 v1(76.84,22.9)
M_B_DQS_DN4: length 71.2
  L2 w0.089: 118.33,75.96 118.33,75.97 118.23,76.06 118.15,76.06 117.83,76.38 117.83,78.1 117.91,78.18 117.91,78.54 117.8,78.65 v1(117.47,79.02)
  L2 w0.102: v1(104.95,24.45) 104.24,24.45 103.99,24.69 103.99,25.22 103.99,25.23 104.1,25.87 104.64,26.41 105.19,26.96 105.53,26.96 105.88,27.32 106.34,27.32 106.56,27.54 106.56,27.99 106.89,28.33 107.35,28.33 107.56,28.54 107.56,29 107.9,29.33 108.35,29.33 108.57,29.55 108.57,30 108.91,30.34 109.36,30.34 109.58,30.56 109.58,31.01 109.91,31.35 110.37,31.35 110.59,31.56 110.59,32.02 111.81,33.25 112.27,33.25 113.2,34.18 113.2,43.43 122.23,52.46 122.23,66.52 121.11,67.64 120.48,67.64 119.27,68.85 119.27,75.02 118.33,75.96
  BOTTOM w0.191: v1(104.95,24.45) 104.57,24.83 104.5,24.83 104.18,25.15 104.18,26.24 104.02,26.39 DM2.177 ; CPU1.AT38 v1(117.47,79.02)
M_B_DQS_DN5: length 70.3
  L2 w0.102: v1(109.57,22.68) 109.78,22.68 110.12,23.02 110.12,25.55 113.84,29.27 114.14,29.27 118.48,33.61 118.48,35.94 119.25,36.7 119.25,44.8 125.48,51.04 125.48,61.81 126.07,63.68 126.07,64.53 125.46,67.89 123.91,69.45 123.91,74.19 122.25,75.85 121.84,75.85 120.83,76.86 120.83,77.88 121.29,78.34 121.29,78.86 121.19,78.96 121.19,78.97 v1(121.11,79.05)
  BOTTOM w0.191: DM2.198 109.27,20.65 109.47,20.84 109.47,21.88 109.78,22.2 109.78,22.47 v1(109.57,22.68) ; CPU1.AT32 121.52,78.66 121.24,78.66 121.11,78.79 v1(121.11,79.05)
M_B_DQS_DN6: length 72.2
  L2 w0.102: v1(115.22,24.37) 115.86,24.37 116.1,24.61 116.1,25.95 119.68,29.52 120.4,29.52 123.32,32.44 123.52,32.44 123.63,32.44 124.62,33.43 124.62,39.46 124.72,39.56 125.24,39.56 125.46,39.79 125.46,40.26 125.24,40.48 124.72,40.48 124.62,40.58 124.62,40.89 124.72,40.99 125.24,40.99 125.46,41.21 125.46,41.68 125.24,41.9 124.72,41.9 124.62,42 124.62,42.31 125,42.69 125,43.17 124.62,43.55 124.62,45.06 129.6,50.04 129.6,68.84 128.68,69.76 128.68,74.13 127.67,75.14 126.6,75.14 125.43,76.3 125.43,77.96 125.06,78.34 124.99,78.34 124.42,78.92 124.42,79.27 124.56,79.42 v1(124.81,79.73)
  BOTTOM w0.191: v1(115.22,24.37) 114.47,25.11 114.47,26.17 114.52,26.23 DM2.219 ; CPU1.AR25 v1(124.81,79.73)
M_B_DQS_DN7: length 70.3
  L2 w0.102: v1(119.34,21.38) 119.53,21.58 120.14,21.58 120.54,21.97 120.54,23.19 121.96,24.61 122.37,24.61 122.77,24.61 123.83,25.67 123.83,26.79 130.24,33.2 130.67,33.2 131.55,34.08 131.55,46.59 133.14,48.17 133.14,70.45 132.37,71.22 132.37,74.14 130,76.51 130,76.69 128.35,78.34 128.35,78.56 128.03,78.89 128.03,79.25 v1(127.55,79.73)
  BOTTOM w0.191: DM2.240 119.77,20.95 v1(119.34,21.38) ; v1(127.55,79.73) 127.23,79.4 CPU1.AR22
M_B_DQS_DP0: length 88.2
  L2 w0.102: v1(65.5,22.4) 65.5,22.73 66.28,23.5 66.28,26.6 67.35,27.66 67.35,31.06 69.76,33.48 69.76,44.49 88.89,63.62 88.89,65.1 88.67,65.32 88.51,65.32 88.4,65.42 88.4,65.72 88.51,65.82 88.67,65.82 88.89,66.04 88.89,66.52 88.67,66.74 88.51,66.74 88.4,66.84 88.4,67.14 88.51,67.25 88.67,67.25 88.89,67.47 88.89,67.94 88.67,68.16 88.51,68.16 88.4,68.26 88.4,68.57 88.51,68.67 88.67,68.67 88.89,68.89 88.89,69.36 88.67,69.58 88.51,69.58 88.4,69.68 88.4,69.99 88.51,70.09 88.67,70.09 88.89,70.31 88.89,70.99 87.6,72.27 87.6,75.41 90.55,78.36 93.02,78.36 94.6,79.94 94.95,79.94 95.35,80.33 98.96,80.33 101.67,83.04 102.11,83.04 v1(102.76,83.7)
  BOTTOM w0.191: v1(102.76,83.7) 103.09,83.37 CPU1.AH65 ; DM2.34 66.27,20.47 66.2,20.55 66.2,21.7 v1(65.5,22.4)
M_B_DQS_DP1: length 89.4
  L2 w0.102: v1(61.03,25.1) 61.03,25.01 60.61,24.59 60.49,24.59 60.37,24.72 60.37,25.65 61.13,26.42 61.13,30.34 62.97,32.17 62.97,43.23 72.7,52.96 72.85,52.96 73.09,52.73 73.4,52.73 73.73,53.06 73.73,53.38 73.5,53.61 73.5,53.76 73.86,54.12 74,54.12 74.24,53.88 74.55,53.88 75.1,54.43 75.1,54.89 75.39,55.18 75.85,55.18 84.32,63.65 84.32,76.97 91.84,84.5 94.41,84.5 94.85,84.06 94.92,84.06 95.24,84.06 95.25,84.06 95.86,84.06 v1(96.24,84.43)
  BOTTOM w0.089: v1(96.24,84.43) 96.18,84.37 95.66,84.37 95.56,84.46 95.56,84.76 95.7,84.89 97.08,84.89 97.56,84.42 98.49,84.42 98.89,84.02 99.29,84.02 99.44,84.06 99.58,84.06 99.78,84 100.06,84 100.16,83.9 CPU1.AG70
  BOTTOM w0.191: DM2.13 61.02,26.16 60.76,25.9 60.76,25.5 60.76,25.22 60.89,25.1 v1(61.03,25.1)
M_B_DQS_DP2: length 76.2
  L2 w0.102: v1(103.78,79.08) 103.64,79.22 103.39,79.22 103.26,79.09 103.26,78.79 102,77.52 100.84,77.52 99.75,76.43 99.75,75.43 92.61,68.29 92.61,67.78 92.72,67.68 93.17,67.68 93.39,67.46 93.39,66.89 93.17,66.67 92.72,66.67 92.61,66.57 92.61,64.89 92.72,64.78 93.08,64.78 93.3,64.56 93.3,63.99 93.08,63.77 92.72,63.77 92.61,63.67 92.61,61.68 78.96,48.02 78.96,47.44 78.62,47.11 78.04,47.11 77.95,47.02 77.95,46.44 77.62,46.1 77.04,46.1 76.94,46.01 76.94,45.43 76.29,44.78 76.29,33.26 71.31,28.28 71.31,25.66 71.09,25.44 71.09,24.76 71.22,24.63 71.42,24.63 v1(71.86,25.07)
  BOTTOM w0.191: v1(71.86,25.07) 71.65,25.07 71.44,25.28 71.44,25.88 71.52,25.97 DM2.55 ; v1(103.78,79.08) 103.45,79.4 CPU1.AR65
M_B_DQS_DP3: length 74.5
  L2 w0.089: 105.88,77.27 105.88,77.29 105.87,77.3 105.87,77.89 106.18,78.19 106.18,79.39 v1(106.52,79.73)
  L2 w0.102: 105.88,77.27 105.88,75.72 102.36,72.2 102.36,71.48 100.15,69.26 100.15,66.36 99.93,66.14 99.62,66.14 99.52,66.04 99.52,65.64 99.62,65.53 99.93,65.53 100.15,65.31 100.15,63.53 85.2,48.58 85.2,34.49 77.63,26.93 77.63,22.71 77.15,22.23 v1(76.87,22.23)
  BOTTOM w0.191: CPU1.AR60 106.2,79.4 v1(106.52,79.73) ; DM2.76 76.78,20.6 76.6,20.77 76.6,21.96 v1(76.87,22.23)
M_B_DQS_DP4: length 71.2
  L2 w0.089: 118.47,76.1 118.32,76.25 118.23,76.25 118.03,76.46 118.03,78.02 118.1,78.1 118.1,78.84 118.03,78.9 118.03,78.9 117.94,79 117.94,79.21 v1(117.49,79.67)
  L2 w0.102: 118.47,76.1 119.47,75.1 119.47,68.93 120.56,67.85 121.19,67.85 122.44,66.6 122.44,52.38 113.4,43.34 113.4,34.09 112.35,33.04 111.9,33.04 110.79,31.93 110.79,31.48 110.45,31.14 110,31.14 109.78,30.93 109.78,30.47 109.45,30.14 108.99,30.14 108.77,29.92 108.77,29.47 108.44,29.13 107.98,29.13 107.77,28.91 107.77,28.46 107.43,28.12 106.98,28.12 106.76,27.91 106.76,27.45 106.42,27.12 105.97,27.12 105.61,26.76 105.27,26.76 104.29,25.77 104.19,25.19 104.19,24.78 104.32,24.65 104.55,24.65 104.95,25.06 v1(104.95,25.16)
  BOTTOM w0.127: CPU1.AR38 117.95,79.49 117.77,79.67 v1(117.49,79.67)
  BOTTOM w0.191: DM2.179 104.53,26.04 104.51,26.02 104.51,25.28 104.63,25.16 v1(104.95,25.16)
M_B_DQS_DP5: length 70.3
  L2 w0.102: v1(121.13,79.69) 121.34,79.47 121.51,79.2 121.51,78.89 121.49,78.87 121.49,78.25 121.04,77.8 121.04,76.94 121.93,76.05 122.33,76.05 124.11,74.27 124.11,69.53 125.65,67.99 126.27,64.55 126.27,63.65 125.69,61.78 125.69,50.95 119.45,44.72 119.45,36.62 118.69,35.85 118.69,33.53 114.22,29.06 113.92,29.06 110.32,25.46 110.32,22.61 v1(110.26,22.55)
  BOTTOM w0.191: CPU1.AR32 v1(121.13,79.69) ; DM2.200 109.77,20.68 109.8,20.71 109.8,21.74 110.26,22.2 v1(110.26,22.55)
M_B_DQS_DP6: length 72.1
  L2 w0.102: v1(115.22,25.08) 115.22,24.98 115.63,24.57 115.77,24.57 115.9,24.7 115.9,26.03 119.6,29.73 120.32,29.73 123.24,32.65 123.43,32.65 123.43,32.65 123.55,32.65 124.42,33.51 124.42,39.55 124.64,39.77 125.15,39.77 125.25,39.87 125.25,40.17 125.15,40.28 124.64,40.28 124.42,40.5 124.42,40.97 124.64,41.19 125.15,41.19 125.25,41.29 125.25,41.6 125.15,41.7 124.64,41.7 124.42,41.92 124.42,42.39 124.8,42.78 124.8,43.08 124.42,43.47 124.42,45.14 129.39,50.12 129.39,68.75 128.47,69.68 128.47,74.04 127.58,74.93 126.52,74.93 125.23,76.22 125.23,77.88 124.97,78.14 124.91,78.14 124.21,78.83 124.21,79.35 124.32,79.46 124.32,79.63 124.23,79.73 v1(123.9,79.73)
  BOTTOM w0.191: v1(123.9,79.73) 123.9,79.37 123.98,79.29 124.24,79.29 CPU1.AR27 ; DM2.221 115.02,26.26 114.8,26.04 114.8,25.25 114.97,25.08 v1(115.22,25.08)
M_B_DQS_DP7: length 70.4
  L2 w0.102: v1(119.34,22.1) 119.65,21.78 120.06,21.78 120.33,22.06 120.33,23.27 121.87,24.81 122.46,24.81 122.68,24.81 123.63,25.76 123.63,26.88 130.15,33.4 130.59,33.4 131.35,34.16 131.35,46.67 132.94,48.26 132.94,70.36 132.16,71.14 132.16,74.06 129.8,76.42 129.8,76.61 128.15,78.26 128.15,78.48 v1(127.55,79.08)
  BOTTOM w0.191: CPU1.AR21 128.01,79.17 127.91,79.08 v1(127.55,79.08) ; DM2.242 120.27,21.16 v1(119.34,22.1)
M_B_PARITY: length 77.6
  L2 w0.102: 114.78,64.87 114.78,68.08 114.26,68.59 114.26,69.47 113.46,70.27 113.46,73.67 114.82,75.03 114.82,75.82 114.95,75.95 114.95,77.46 115.12,77.63 115.12,79.78 v1(115.71,80.37)
  L2 w0.152: v1(94.84,21.53) 95.46,21.53 95.59,21.66 95.59,22.11 94.99,22.7 94.55,22.7 94.4,22.86 94.4,23.16 94.55,23.31 95.02,23.31 95.17,23.47 95.17,27.43 101.1,33.35 101.1,40.95 101.84,41.69 101.84,44.86 114.82,57.83 114.82,64.81 114.78,64.85 114.78,64.87
  BOTTOM w0.216: CPU1.AP43 115.53,80.37 v1(115.71,80.37)
  BOTTOM w0.292: DM2.143 93.52,26.64 93.71,26.46 93.75,26.46 94.84,25.37 v1(94.84,21.53)
M_VREF_CA_DIMMA: length 21.9
  L4 w0.508: v1(112.21,17.62) 113.34,17.62 113.58,17.87 113.58,20.51 114.55,21.48 114.55,27.73 108.83,33.44 v1(108.83,34)
  BOTTOM w0.305: DM1.164 108.77,33.94 v1(108.83,34)
M_VREF_CA_DIMMB: length 1.7
  BOTTOM w0.305: v1(100.77,20.97) 100.77,20.96 DM2.164
MAA0_0: length 31.6
  L3 w0.102: v1(170.49,141.99) 170.49,142.4 169.83,143.06 169.83,144.01 170.69,144.88
  L3 w0.203: v1(160.59,164.2) 163.29,164.2 163.57,164.48 165.38,164.48 168.65,161.21 168.65,152.44 170.65,150.44 170.65,149.84 170.36,149.56 170.36,145.66 170.69,145.33 170.69,144.88
  BOTTOM w0.229: v1(160.59,164.2) 160.2,164.59 VRAM1.H4 ; GPU1.K17 v1(170.49,141.99)
MAA0_1: length 30.2
  L3 w0.102: v1(167.82,142.83) 167.24,143.41 167.24,144.7 167.68,145.15
  L3 w0.203: 167.68,145.15 167.68,146.75 166.53,147.89 166.53,149.61 164.98,151.16 164.98,153.81 163.75,155.04 160.35,155.04 158.04,157.35 158.04,164.15 v1(158.6,164.71)
  BOTTOM w0.229: v1(158.6,164.71) 159.29,164.71 VRAM1.H5 ; GPU1.J20 167.94,143.11 v1(167.82,142.83)
MAA0_2: length 29.1
  L3 w0.102: v1(165.8,143.69) 165.23,143.69 164.59,144.33 164.59,144.7 164.29,145
  L3 w0.203: 164.29,145 163.97,145.32 163.97,147.51 163.02,148.46 163.02,148.74 161.35,150.41 159,150.41 153.78,155.64 153.78,156.66 153.64,156.79 153.64,158.81 153.86,159.03 153.86,159.82 153.74,159.94 153.74,161.99 155,163.25 v1(155,164.2)
  BOTTOM w0.229: GPU1.H23 166.2,144.09 v1(165.8,143.69) ; v1(155,164.2) 154.8,164.4 154.6,164.6 VRAM1.H11
MAA0_3: length 28
  L3 w0.203: v1(155.89,165.02) 157.07,163.83 157.07,156.11 159.69,153.49 162.7,153.49 163.28,152.91 163.28,151.37 164.91,149.74 164.91,148.96 164.86,148.91 164.86,148.53 165.5,147.89 165.5,147.44 166.11,146.84 166.11,145.96 166.26,145.81 166.26,145.1 165.8,144.64 v1(165.8,144.51)
  BOTTOM w0.229: v1(165.8,144.51) 166.19,144.9 GPU1.G23 ; v1(155.89,165.02) 155.47,164.6 VRAM1.H10
MAA0_4: length 27.2
  L3 w0.102: 164.61,149.11 164.61,148.36 165.18,147.78 165.18,147.04 165.8,146.42 165.8,146.14 165.52,145.86 165.52,145.42 165.65,145.29 v1(165.8,145.29)
  L3 w0.203: 164.61,149.11 164.61,149.61 162.83,151.39 162.83,152.55 162.41,152.97 159.4,152.97 156.57,155.79 156.57,156.51 156.77,156.7 156.77,163.41 156.55,163.62 v1(155.97,163.62)
  BOTTOM w0.229: GPU1.G24 165.41,144.9 v1(165.8,145.29) ; v1(155.97,163.62) 155.75,163.4 155,163.4 VRAM1.K11
MAA0_5: length 27.6
  L3 w0.102: 164.42,145.31 165,144.73 v1(165,144.5)
  L3 w0.203: v1(155.97,162.97) 155.32,162.97 155.14,162.8 155.14,162.33 155.48,161.99 155.48,159.23 155.12,158.87 155.12,158.33 155.47,157.99 155.47,157.63 154.71,156.87 154.71,156.43 155.53,155.61 155.53,154.64 155.55,154.63 155.55,154.63 159.15,151.02 162.33,151.02 162.74,150.62 162.74,149.94 162.97,149.71 163.64,149.71 164,149.36 164,148.86 164.03,148.82 164.03,148.13 164.42,147.74 164.42,145.31
  BOTTOM w0.229: VRAM1.K10 155.95,163 v1(155.97,162.97) ; GPU1.H24 165,144.5 v1(165,144.5)
MAA0_6: length 29.7
  L3 w0.102: 167.99,145.12 167.99,145.09 167.73,144.84 167.73,144.84 167.44,144.55 167.44,143.61 167.82,143.23 168.57,143.23 168.8,143.47 v1(168.8,143.71)
  L3 w0.203: v1(158.74,163.2) 158.97,162.97 158.97,162.55 158.35,161.93 158.35,157.78 160.54,155.59 163.96,155.59 165.51,154.04 165.51,151.28 167.46,149.33 167.46,147.74 167.99,147.21 167.99,145.12
  BOTTOM w0.229: v1(158.74,163.2) 159.2,163.2 VRAM1.K5 ; GPU1.J19 v1(168.8,143.71)
MAA0_7: length 29.9
  L3 w0.102: v1(169.5,141.95) 169.29,141.95 168.66,142.58 168.66,143 169.21,143.54 169.21,144.98 169.39,145.15 169.39,145.56 169.24,145.71
  L3 w0.203: v1(159.8,163.4) 160.61,162.59 162.53,162.59 162.8,162.32 163.41,162.32 164.33,161.39 164.33,160.47 164.84,159.95 166.59,159.95 167.08,159.46 167.08,151.51 169.24,149.35 169.24,145.71
  BOTTOM w0.229: v1(159.8,163.4) VRAM1.K4 ; GPU1.K19 169.6,142.05 v1(169.5,141.95)
MAA0_8: length 27.6
  L3 w0.203: v1(167.92,144.45) 168.29,144.83 168.29,147.44 167.91,147.82 167.91,149.62 166.03,151.51 166.03,154.94 164.69,156.28 160.35,156.28 159.32,157.31 159.32,160.41 159.34,160.42 159.34,161.98 159.34,161.98 159.34,163.41 v1(158.75,164.01)
  BOTTOM w0.229: v1(167.92,144.45) 167.91,144.45 167.91,144.47 167.97,144.47 GPU1.G20 ; v1(158.75,164.01) 159.07,164.05 VRAM1.J5
MAA1_0: length 32.6
  L3 w0.102: 173.61,145.7 173.35,145.44 173.35,143.62 v1(173.75,143.22)
  L3 w0.203: v1(179.5,165) 180.03,164.47 180.03,163.67 180.97,162.72 180.97,159.54 180.64,159.21 179.15,159.21 178.88,158.94 178.46,158.94 177.31,160.09 175.87,160.09 174.9,159.12 173.45,159.12 172.98,158.64 172.98,153.43 173.35,153.06 173.35,149.81 173.82,149.34 173.82,145.91 173.61,145.7
  BOTTOM w0.229: VRAM2.K4 v1(179.5,165) ; v1(173.75,143.22) GPU1.J14
MAA1_1: length 30.8
  L3 w0.203: v1(180.58,164.7) 181.58,163.7 181.58,158.79 180.78,157.99 179.95,157.99 179.67,158.28 178.58,158.28 177.87,157.57 177.87,157.5 177.39,157.02 174.63,157.02 174.06,156.45 174.06,150.05 174.49,149.62 174.49,145.67 174.25,145.42 174.25,144.15 174.27,144.12 174.27,143.01 v1(173.76,142.5)
  BOTTOM w0.229: VRAM2.K5 180.46,164.76 v1(180.58,164.7) ; v1(173.76,142.5) GPU1.K14
MAA1_2: length 32.3
  L3 w0.102: v1(174.98,142.58) 174.53,143.03 174.53,144.23 174.5,144.25 174.5,145.32 174.89,145.71
  L3 w0.203: 174.89,145.71 174.89,147.86 175.45,148.43 175.45,150.03 174.87,150.61 174.87,154.35 176.5,155.99 176.96,155.99 177.96,157 180.22,157 181.9,158.68 181.9,164.71 183.11,165.91 183.49,165.91 184.3,165.1 v1(184.3,164.99)
  BOTTOM w0.229: VRAM2.K11 v1(184.3,164.99) ; v1(174.98,142.58) 175.34,142.94 GPU1.J11
MAA1_3: length 27.4
  L3 w0.203: v1(183.28,164.48) 182.51,163.71 182.51,158.43 180.4,156.31 180.23,156.31 178.49,154.56 177.25,154.56 176.24,153.55 176.24,150.31 177.06,149.49 177.06,147.44 175.59,145.97 175.59,144.87 175.43,144.71 175.43,143.71 v1(174.94,143.22)
  BOTTOM w0.229: v1(174.94,143.22) GPU1.J13 ; VRAM2.K10 v1(183.28,164.48)
MAA1_4: length 24.7
  L3 w0.102: v1(176.04,143.73) 175.71,144.06 175.71,144.53 175.96,144.78 176.21,144.78 176.54,145.11 176.54,145.51
  L3 w0.203: 176.54,145.51 176.54,145.69 177.77,146.93 177.77,152.38 181.94,156.55 183.45,156.55 183.85,156.94 183.85,159.64 183.84,159.64 183.84,162.15 v1(184.3,162.6)
  BOTTOM w0.229: v1(176.04,143.73) GPU1.H11 ; v1(184.3,162.6) VRAM2.H11
MAA1_5: length 25
  L3 w0.203: v1(184.3,163.4) 182.83,161.94 182.83,158.17 178.64,153.98 177.37,153.98 176.74,153.35 176.74,151.95 176.94,151.75 177.26,151.75 177.47,151.55 177.47,151.24 177.26,151.04 176.94,151.04 176.74,150.84 176.74,150.41 177.36,149.79 177.36,147.14 176.06,145.84 v1(176.06,145.21)
  BOTTOM w0.229: v1(184.3,163.4) VRAM2.H10 ; GPU1.G11 v1(176.06,145.21)
MAA1_6: length 28
  L3 w0.102: v1(172.57,142.84) 173.13,143.39 173.13,145.64 173.43,145.95 173.43,146.42 173.25,146.6
  L3 w0.203: 173.25,146.6 172.9,146.95 172.9,152.74 172.46,153.19 172.46,159.29 172.93,159.77 174.52,159.77 175.81,161.06 176.22,161.06 176.67,161.51 179.38,161.51 v1(180.43,162.56)
  BOTTOM w0.229: v1(172.57,142.84) GPU1.J16 ; v1(180.43,162.56) VRAM2.H5
MAA1_7: length 28.9
  L3 w0.102: v1(172.33,142.01) 172.17,142.17 172.17,143.7 172.44,143.98 172.62,143.98 172.9,144.26 172.9,145.47 172.6,145.78 172.6,146.7
  L3 w0.203: 172.6,146.7 172.6,152.36 171.89,153.07 171.89,159.57 172.76,160.45 174.25,160.45 175.84,162.03 176.22,162.03 176.41,161.84 177.94,161.84 v1(179.5,163.4)
  BOTTOM w0.229: VRAM2.H4 v1(179.5,163.4) ; GPU1.L15 v1(172.33,142.01)
MAA1_8: length 29.1
  L3 w0.203: v1(180.59,163.81) 181.28,163.13 181.28,158.92 180.66,158.3 180.18,158.3 179.89,158.58 178.45,158.58 177.56,157.69 177.56,157.62 177.29,157.35 176.15,157.35 175.04,158.46 173.77,158.46 173.54,158.23 173.54,153.54 173.68,153.4 173.68,149.96 174.12,149.52 174.12,145.78 173.76,145.41 v1(173.76,145.27)
  BOTTOM w0.229: GPU1.G14 v1(173.76,145.27) ; v1(180.59,163.81) 180.58,163.8 VRAM2.J5
MASK_SATA_LED#: length 67.4
  L3 w0.102: v1(175.12,35.55) 175.12,34.96 176.6,33.48 176.6,32.7 176.52,32.62 176.52,32.49 175.74,31.71 175.74,24.56 176.04,24.26 176.99,24.26 178.51,22.74 183.39,22.74 184.08,22.05 187,22.05 187.17,22.22 190.95,22.22 192.16,21.01 192.16,20.74 192.17,20.73 192.17,16.65 192.16,16.64 192.16,16.46 190.58,14.88 190.57,14.88 187.94,12.25 183.43,12.25 179.35,8.18 171.18,8.18 170.96,7.96 v3(168.47,7.96)
  BOTTOM w0.102: v2(175.66,35.69) 175.26,35.69 v1(175.12,35.55) 174.61,36.05 174.37,36.05 173.7,36.73 KBC24.56 ; R6401.2 167.6,7.92 Q6401.G 168.24,8.02 168.3,7.96 v3(168.47,7.96)
MCT:
  vias: v2(18.12,182.62)
MCT0: length 17
  TOP w0.508: v1(15.18,181.08) 15.18,182.24 v2(15.6,182.65) ; XF3201.3 22.23,177.43 v1(22.3,177.36)
  L4 w0.508: v1(15.18,181.08) 15.18,181.71 15.92,182.45 18.31,182.45 19.17,181.6 20.28,181.6 21.67,180.21 21.67,180.21 22.3,179.57 v1(22.3,177.36)
  BOTTOM w0.457: RN3201.4 15.58,181.66 15.18,181.27 v1(15.18,181.08)
MCT1: length 15.2
  TOP w0.508: v1(20.81,174.17) 20.26,173.62 XF3201.4 ; v2(16.32,181.53) 16.01,181.22 v1(16.01,181.05)
  L4 w0.508: v1(16.01,181.05) 16.01,181.46 16.36,181.81 18.05,181.81 18.9,180.96 20.02,180.96 21.03,179.95 21.03,174.39 v1(20.81,174.17)
  BOTTOM w0.305: v1(16.01,181.05) 16.17,181.21 RN3201.3
MCT2: length 9.5
  TOP w0.508: v1(16.83,181.05) 16.83,180.72 17.01,180.54 17.01,180.52 v2(17.08,180.45)
  L3 w0.508: v1(16.83,181.05) 16.83,180.91 18.21,179.53 19.66,179.53 20.3,178.89 v1(20.3,176.76)
  BOTTOM w0.305: v1(16.83,181.05) 16.67,181.21 RN3201.2
  BOTTOM w0.508: XF3202.4 19.99,177.43 20.3,177.12 v1(20.3,176.76)
MCT3: length 13.5
  TOP w0.508: v1(17.64,181.1) v2(18.2,181.1)
  L3 w0.508: v1(21.01,173.43) 21.61,174.03 21.61,178.55 19.88,180.28 18.46,180.28 v1(17.64,181.1)
  BOTTOM w0.457: RN3201.1 17.25,181.59 17.64,181.2 v1(17.64,181.1)
  BOTTOM w0.508: XF3202.3 20.47,173.62 20.55,173.53 20.91,173.53 v1(21.01,173.43)
MDO0+: length 13.9
  TOP w0.102: AFTP3204.1 15.98,172.34 15.72,172.61 13.91,172.61 12.93,173.59 12.83,173.7 RJ45.1
  BOTTOM w0.102: RJ45.1 12.83,173.7 12.93,173.59 14.91,171.6 18.63,171.6 19.16,171.08 XF3202.1
MDO0-: length 13.6
  TOP w0.102: RJ45.2 12.99,173.84 13.08,173.74 14,172.82 15.65,172.82 16.01,173.18 AFTP3201.1
  BOTTOM w0.102: RJ45.2 12.99,173.84 13.08,173.74 15,171.82 18.63,171.82 19.16,172.35 XF3202.2
MDO1+: length 13.2
  TOP w0.102: AFTP3202.1 15.91,175.77 RJ45.3
  BOTTOM w0.102: XF3202.5 19.16,178.7 18.63,179.23 17.96,179.23 15.43,176.7 14.32,176.7 13.71,176.09 RJ45.3
MDO1-: length 12.6
  TOP w0.102: AFTP3208.1 15.25,177.68 14.09,178.83 RJ45.6
  BOTTOM w0.102: RJ45.6 13.02,177.89 13.22,177.68 13.56,177.68 14.33,176.91 15.34,176.91 17.87,179.44 18.63,179.44 19.16,179.97 XF3202.6
MDO2+: length 12.9
  TOP w0.102: RJ45.4 12.89,176.92 12.89,177.55 13.09,177.75 13.57,177.75 14.43,176.89 16.95,176.89 17.76,176.08 17.76,174.8 ; AFTP3205.1 17.76,174.8 ; 17.76,174.8 17.76,171.94 18.09,171.61 18.53,171.61 19.07,171.08 XF3201.6
MDO2-: length 13.1
  TOP w0.102: XF3201.5 19.01,172.35 18.49,171.82 18.18,171.82 17.98,172.03 17.98,176.16 17.52,176.62 ; AFTP3203.1 17.52,176.62 ; 17.52,176.62 17.04,177.1 14.52,177.1 13.66,177.97 13,177.97 12.84,177.81 RJ45.5
MDO3+: length 8.3
  TOP w0.102: 17.89,179.22 18.63,179.22 19.16,178.7 XF3201.2 ; 17.89,179.22 15.1,179.22 14.68,179.64 13.22,179.64 13,179.85 RJ45.7 ; 17.89,179.22 AFTP3207.1
MDO3-: length 7.9
  TOP w0.102: 16.06,179.44 15.19,179.44 14.77,179.85 13.31,179.85 13.02,180.14 RJ45.8 ; 16.06,179.44 18.63,179.44 19.16,179.97 XF3201.1 ; 16.06,179.44 AFTP3206.1
ME_FWP: length 69.1
  TOP w0.102: v1(145.31,46.58) 145.44,46.71 v2(145.85,46.71)
  L4 w0.102: v1(164.8,33.35) 164.8,33.61 164.2,34.21 160.98,34.21 159.42,32.64 157.69,32.64 157.62,32.71 157.26,32.71 157.19,32.64 151.19,32.64 147.94,35.9 147.94,38.19 147.92,38.2 147.92,39.51 147.94,39.53 147.94,39.62 148.63,40.31 148.63,42.22 147.68,43.17 146.17,43.17 145.31,44.03 v1(145.31,46.58)
  BOTTOM w0.102: v1(145.31,46.58) 145.31,48.07 144.79,48.59 142.71,48.59 142.11,49.19 142.11,50.71 142.06,50.77 142.06,50.81 141.37,51.49 139.7,51.49 139.32,51.11 136.88,51.11 126.4,61.59 126.4,61.61 126.19,61.82 R1909.1 ; v1(164.8,33.35) 164.9,33.35 165.26,33 KBC24.80
ME_SUS_PWR_ACK_R: length 29
  TOP w0.127: R1708.1 152.74,69.24 R1718.2 153.52,68.89 v2(152.83,68.19) 152.83,68.14 152.5,67.81 v1(152.08,67.81)
  L3 w0.102: 132.74,78.43 132.12,79.04 v1(132.12,79.08)
  L3 w0.127: v1(152.08,67.81) 148.59,67.81 146.49,69.91 144.67,69.91 143.56,70.38 142.11,71.83 142.09,71.83 138.91,75.01 135.43,75.01 134.74,75.71 133.96,75.71 132.95,76.71 132.95,78.21 132.74,78.43
  BOTTOM w0.127: CPU1.AR13 v1(132.12,79.08)
MEC_XTAL1_R: length 8.6
  BOTTOM w0.114: KBC24.123 155.65,43.93 154.97,43.25 154.97,43.19 154.68,42.91 154.68,41.96 153.87,41.15 X2401.1 154.35,40.02 154.35,38.92 v2(154.34,38.91) C2425.1
MEC_XTAL2: length 4.2
  BOTTOM w0.114: KBC24.125 156.25,44.73 156.04,44.51 v2(155.81,44.51) 154.26,44.51 R2428.2 154.19,44.45 R2458.1
MEM_CALRP0: length 6.8
  TOP w0.102: R7809.2 161.59,139.98 v2(161.45,140.12) 161.45,140.37 161.65,140.58 163.44,140.58 165.01,142.14 v1(165.01,142.9)
  BOTTOM w0.102: GPU1.K25 165,142.9 v1(165.01,142.9)
MEM_SMBCLK: length 32.1
  TOP w0.191: v1(136.21,89.11) 136.69,88.63 136.98,88.63 137.01,88.65 137.05,88.65 139.56,91.16 139.56,91.27 139.57,91.27 139.57,91.77 139.58,91.79 139.58,94.59 139.62,94.63 139.62,95.38 139.63,95.38 139.63,95.66 140.03,96.06 140.27,96.06 141.45,97.24 141.45,97.89 141.45,98.12 141.44,98.13 141.44,98.23 141.45,98.24 141.45,98.83 141.44,98.84 141.44,101.83 144.45,104.84 v2(151.94,104.84) 152.31,104.84 R1805.1 152.45,106.21 152.45,107.18 Q1801.3
  BOTTOM w0.191: CPU1.R7 v1(136.21,89.11)
MEM_SMBDATA: length 35.6
  TOP w0.089: 153.49,107.93 153.32,107.76 152.1,107.76 151.96,107.62 151.96,107.13 v2(151.09,106.26)
  TOP w0.127: v1(135.54,89.09) 135.98,89.53 137.47,89.53 139.32,91.37 139.32,94.71 139.35,94.74
  TOP w0.152: Q1801.6 153.95,108.73 153.49,108.28 153.49,107.05 153.23,106.79 R1832.1
  TOP w0.178: 139.35,95.5 139.35,94.74 ; v2(151.09,106.26) 150.12,105.28 148.68,105.28
  TOP w0.191: 139.35,95.5 139.35,95.77 139.92,96.34 140.15,96.34 141.17,97.36 141.17,98.01 141.16,98.01 141.16,98.35 141.17,98.35 141.17,98.72 141.16,98.72 141.16,101.95 142.22,103.01 142.22,104.16 142.43,104.37 143.27,104.37 144.19,105.28 148.68,105.28
  BOTTOM w0.191: CPU1.R8 v1(135.54,89.09)
MESO_SVC: length 28.5
  L4 w0.102: v1(172.27,128.45) 172.21,128.45 168.84,125.08 168.84,124.03 166.65,121.84 166.12,121.84 166.1,121.82 164.93,121.82 164.87,121.76 164.52,121.41 159.11,121.41 158.94,121.24 v1(158.91,121.24)
  BOTTOM w0.102: R7946.2 153.24,119.22 153.75,119.74 153.82,119.74 153.82,119.74 154.43,119.74 154.86,119.3 v2(155.19,119.3) 155.19,119.3 156.51,120.62 156.51,120.9 157.23,121.62 158.53,121.62 v1(158.91,121.24) ; GPU1.AJ11 174.77,127.7 174.02,128.45 v1(172.27,128.45)
MESO_SVD: length 32.1
  L4 w0.102: v1(171.31,128.38) 171.31,127.87 165.46,122.02 164.84,122.02 164.52,121.69 158.45,121.69 158.23,121.47 158.23,121.21 v1(158.22,121.21)
  BOTTOM w0.102: GPU1.AK12 174.07,127.3 173.63,127.74 173.03,127.74 172.74,128.03 172.46,128.03 172.2,127.77 171.66,127.77 171.31,128.12 v1(171.31,128.38) ; v1(158.22,121.21) 157.11,121.21 156.72,120.81 156.72,120.54 156.08,119.9 156.08,119.2 155.17,118.29 154.34,118.29 v2(152.91,116.86) 152.73,116.68 152.73,114.83 152.74,114.83 152.74,114.04 R7944.2
MESO_SVT: length 22.1
  TOP w0.102: v2(173.08,126.93) 172.96,126.93 v1(172.39,126.35)
  L4 w0.102: v1(159.25,120.7) 159.4,120.55 160.75,120.55 161.12,120.92 164.32,120.92 165.01,121.61 166.18,121.61 166.2,121.63 166.73,121.63 169.04,123.94 169.04,125 170.4,126.35 v1(172.39,126.35)
  BOTTOM w0.102: R7945.2 159.08,119.96 159.08,120.53 v1(159.25,120.7) ; GPU1.AL11 175.8,126.77 175.71,126.68 175.28,126.68 175.14,126.83 174.64,126.83 174.38,126.57 173.97,126.57 173.69,126.85 173.02,126.85 172.53,126.36 172.4,126.36 v1(172.39,126.35)
MESO_U1: length 16.5
  TOP w0.102: v1(185.31,133.28) 185.55,133.28 187.53,135.25 192.77,135.25 193.94,134.08 RN7905.2
  BOTTOM w0.102: v1(185.31,133.28) 185.75,133.71 185.75,134.09 v2(184.76,135.08) 184.47,135.37 183.73,135.37 GPU1.U1
MESO_U3: length 15.5
  TOP w0.102: v1(185.31,133.91) 186.86,135.46 193.32,135.46 v2(193.78,135) 194.03,134.75 RN7905.1
  BOTTOM w0.102: v1(185.31,133.91) 185.17,134.06 184.53,134.06 181.69,136.9 GPU1.U3
MF_A0: length 2.5
  TOP w0.254: R8112.2 162.92,164.48 v1(163.16,164.71) v2(163.73,164.71)
  BOTTOM w0.254: v1(163.16,164.71) 163.16,164.36 VRAM1.J1
MF_A1: length 3.1
  TOP w0.127: R8114.2 v2(175.27,163.17) 175.19,163.26 175.19,163.65 175.48,163.94 v1(175.79,163.94)
  BOTTOM w0.254: VRAM2.J1 175.93,163.8 v1(175.79,163.94)
MIC2_VREFO: length 13.2
  TOP w0.254: v2(181.4,16.91) 181.29,17.02 v1(180.85,17.02)
  L3 w0.254: v1(173.64,15.1) 173.84,14.91 174.92,14.91 175.47,15.46 179.63,15.46 180.85,16.68 v1(180.85,17.02)
  BOTTOM w0.203: HDA27.23 173.34,15.79 173.64,15.48 v1(173.64,15.1)
  BOTTOM w0.254: v1(180.85,17.02) 180.8,17.02 180.8,17.24 180.17,17.88 RN2901.1 179.73,18.01 179.6,18.14 179.6,18.19 179.58,18.21 179.58,18.55 179.7,18.67 180.03,18.67 180.03,18.68 RN2901.2
MIC_CAP: length 4.4
  BOTTOM w0.203: 176.37,18.97 176.16,18.97 176.05,18.86 175.34,18.86 175.27,18.93 HDA27.15
  BOTTOM w0.254: v2(177.83,20.75) 177.64,20.56 C2715.1 177.15,19.11 176.52,19.11 176.37,18.97
MIC_GND: length 3.8
  TOP w0.508: v2(107.73,175.46) 107.84,175.46 108.36,175.97 R5531.1 108.36,176.67 v1(107.6,177.43)
  BOTTOM w0.305: v1(107.6,177.43) 107.15,176.98 LCD1.26
MLPS_EN#: length 17.2
  BOTTOM w0.089: 182.66,138.59 182.43,138.82 182.07,138.82 182.03,138.79 181.57,138.79 181.53,138.82 180.92,138.82 GPU1.R5
  BOTTOM w0.102: R7935.2 194.93,135.23 194.24,135.23 R7936.1 193.43,136.04 193.18,136.04 192.54,136.68 191.95,136.68 191.53,137.11 v2(191.04,137.11) 190.04,138.1 189.98,138.1 189.57,138.51 188.01,138.51 187.57,138.07 185.57,138.07 185.13,138.51 182.75,138.51 182.66,138.59
MODEL_ID: length 9.7
  BOTTOM w0.102: KBC24.109 156.58,38.33 156.46,38.22 156.46,37.77 v2(154.75,36.06) 154.7,36.01 154.7,35.15 153.75,34.2 R2441.1 152.97,32.44 C2407.1 152.8,32.27 R2442.2
MPV18: length 23.6
  TOP w0.254: L8001.2 193.93,139.16 193.38,138.61 193.38,138.56 v1(192.19,137.37)
  L3 w0.254: v1(178.29,140.97) 178.7,141.38 179.86,141.38 183.88,137.37 v1(192.19,137.37)
  BOTTOM w0.254: v1(192.19,137.37) 192.74,137.37 192.76,137.35 ; v1(178.29,140.97) 178.29,140.97 178.2,141.06 GPU1.L8 ; C8043.1 C8044.1 194,136.69 C8045.1 193.35,136.47 192.76,137.07 192.76,137.35 ; 192.76,137.35 v2(192.75,137.35)
MSM#: length 1.2
  TOP w0.102: TP617.1 v1(108.37,80.37)
  BOTTOM w0.102: CPU1.AP56 108.21,80.37 v1(108.37,80.37)
MVREFDA: length 8.5
  TOP w0.508: R7817.2 160.71,138.15 161.2,138.63 v2(161.2,138.66) 161.2,138.74 160.92,139.01 C7805.1 160.33,139.04 R7818.1 160.33,140.16 161.22,141.04 163.22,141.04 v1(164.22,142.04)
  BOTTOM w0.305: GPU1.K26 164.22,142.08 v1(164.22,142.04)
MVREFSA: length 10.6
  TOP w0.457: v1(164.2,142.9) 164.2,142.87 163.6,142.27 162.37,142.27
  TOP w0.508: 162.37,142.27 160.4,142.27 158.65,140.52 R7814.1 158.65,139.01 C7801.1 158.65,138.85 159.16,138.33 v2(159.16,138.13) 159.14,138.15 R7810.2
  BOTTOM w0.356: GPU1.J26 v1(164.2,142.9)
NB_MODE#: length 3.6
  TOP w0.127: v1(157.44,32.28) 157.19,32.54 157.19,33.26 TP2401.1
  BOTTOM w0.127: v1(157.44,32.28) 157.61,32.11 KBC24.96
NB_MUTE#: length 25
  TOP w0.102: v1(161.46,25.92) 162,25.38 v2(162.97,25.38) 164.47,25.38 v1(164.49,25.4) 164.79,25.1 165.62,25.1 R2717.2
  L3 w0.102: v1(161.46,25.92) 161.46,30.23 159.86,31.83 159.86,37.16 v1(158.64,38.38)
  BOTTOM w0.102: KBC24.119 158.35,42.33 159.01,41.67 159.01,38.75 v1(158.64,38.38) ; R2712.1 163.07,25.23 164.33,25.23 v1(164.49,25.4)
NC#AA3: length 27.5
  TOP w0.102: v1(193.78,132.74) 194.02,132.5 R7938.2
  BOTTOM w0.102: GPU1.AA3 181.68,133.7 182.03,133.34 182.76,133.34 183.97,132.13 183.97,130.16 183.96,130.15 183.96,129.64 183.97,129.64 183.97,129.18 187.29,125.86 187.29,125.39 v2(187.99,124.69) 188.4,124.28 190.53,124.28 192.54,126.29 193.86,126.29 194.7,127.13 194.7,128.88 193.83,129.75 193.83,132.69 v1(193.78,132.74)
NC_R: length 7.9
  BOTTOM w0.102: TP7922.1 157.99,122.4 159.47,123.88 160.4,123.88 160.41,123.89 161.54,123.89 163.8,126.14 GPU1.AM26
NC_VSYNC: length 14.3
  BOTTOM w0.102: GPU1.AJ27 163.92,127.7 164.24,127.38 164.24,126.29 161.48,123.53 v2(160.56,123.53) 159.5,123.53 158.52,122.55 158.52,122.18 158.18,121.84 157.11,121.84 156.29,121.01 156.29,120.7 155.8,120.22 R7941.2
NCT7718_DXN: length 151.7
  TOP w0.254: v2(195.48,124.33) 196.01,124.33 196.5,123.85 v1(196.5,122.58) ; v1(191.57,136.1) 191.42,136.25 191.42,136.36 190.49,137.29 189.2,137.29 188.85,137.64 188.85,138.25 189.25,138.66 190.63,138.66 191.05,138.68 191.47,139.1 191.56,139.1 191.6,139.13 191.73,139.13 195.79,143.2 195.79,150.42 198.36,152.99 198.36,163.3 196.76,164.9 196.76,164.9 195.62,166.03 195.62,170.56 194.63,171.55 193.03,171.55 191.24,173.35 188.89,173.35 188.07,174.17 179.31,174.17 176.19,177.28 164.07,177.28 162.71,175.92 154.64,175.92 149.73,171.02 146.91,171.02 145.42,169.53 145.42,161.09 145.68,160.83 145.68,157.49 143.7,155.51 141.57,155.51 137.99,151.94 137.71,151.94 137.69,151.92 135.35,151.92 134.93,151.92 131.91,148.9 131.91,147.51 Q7905.E
  L3 w0.254: v1(196.19,130.28) 197.26,129.21 197.26,123.46 196.5,122.69 v1(196.5,122.58)
  BOTTOM w0.254: THM262.3 196.61,128.63 196.26,128.98 C2614.2 196.26,130.02 196.19,130.09 v1(196.19,130.28) 194.9,131.57 194.9,133.14 194.23,133.81 193.45,133.81 191.57,135.69 v1(191.57,136.1)
NCT7718_DXP: length 145.1
  TOP w0.254: Q7905.C 129.92,148.61 Q7905.B 130.85,146.48 131.96,146.48 132.42,146.95 132.42,148.69 135.14,151.41 137.9,151.41 137.92,151.43 138.2,151.43 141.78,155.01 143.91,155.01 146.18,157.28 146.18,157.35 146.18,161.05 145.93,161.3 145.93,169.31 147.12,170.51 149.94,170.51 154.85,175.41 162.92,175.41 164.28,176.77 175.98,176.77 179.1,173.66 187.86,173.66 188.68,172.84 191.03,172.84 192.82,171.05 194.42,171.05 195.11,170.35 195.11,165.82 196.55,164.39 196.55,164.39 197.85,163.09 197.85,153.2 195.28,150.63 195.28,143.41 191.52,139.64 191.39,139.64 191.35,139.6 191.26,139.6 190.83,139.17 190.62,139.16 189.04,139.16 188.34,138.46 188.34,137.43 188.99,136.78 190.28,136.78 v1(190.91,136.15)
  BOTTOM w0.254: v1(190.91,136.15) 190.94,136.12 190.94,135.61 193.24,133.3 194.02,133.3 194.39,132.93 194.39,131.22 194.85,130.76 v2(194.85,130.18) 195.34,129.69 C2614.1 195.34,129.18 195.96,128.56 THM262.2
ODD_PWR_5V:
  vias: v2(182.05,84.74) v4(187.11,86.7) v4(187.16,85.87) v4(187.18,85.03)
P_SYS: length 88.8
  TOP w0.102: PR4411.1 134.9,179.3 PC4404.1 135.34,179.33 135.67,178.99 135.71,178.99 ; v1(137.6,183.28) 137.34,183.28 135.81,181.75 135.81,179.09 135.71,178.99 ; 135.71,178.99 v1(135.71,178.99) ; v1(141.1,183.64) 140.28,184.47 125.52,184.47 v1(125.13,184.08)
  L3 w0.102: v1(141.1,183.64) 137.96,183.64 v1(137.6,183.28) ; v1(125.13,184.08) 123.65,182.6 123.11,182.6 121.77,181.27 121.77,179.79 120.83,178.84 116.68,178.84 113.5,175.67 113.5,171.98 v1(113.75,171.73)
  L4 w0.102: v1(129.22,148.14) 129.22,148.58 125.94,151.85 121.28,151.85 114.4,158.72 114.4,171.08 v1(113.75,171.73)
  BOTTOM w0.102: PU4401.8 135.17,178.87 135.34,179.05 135.66,179.05 v1(135.71,178.99) ; v1(129.22,148.14) v2(129.22,147.37) 129.22,147.25 126.66,144.7 PR4614.2 126.6,144.26 125.99,144.87 125.46,144.87 124.6,144.02 PU4601.1
PANEL_BKEN_EC: length 14.8
  TOP w0.102: R2497.1 153.13,40.6 154.34,41.81 v2(156.97,41.81) 158.26,41.81 v1(158.45,41.62) 155.82,38.99 v1(155.82,38.03)
  BOTTOM w0.102: R2471.1 154.22,37.79 155.47,37.79 155.7,38.03 v1(155.82,38.03) ; v1(158.45,41.62) 158.39,41.62 158.3,41.53 KBC24.117
PANEL_SIZE_ID: length 178.6
  TOP w0.102: v1(98.79,158.57) v2(98.23,158.57)
  L3 w0.102: v1(133,80.99) 133,81.02 133.65,81.67 134.22,81.67 135.9,79.99 136.44,79.99 136.54,79.89 139.89,79.89 140.38,79.4 140.82,79.4 140.95,79.53 141.51,79.53 142.08,78.96 142.08,78.82 142.9,78 147.8,78 149.86,75.94 149.91,75.94 151.1,74.75 153.91,74.75 155,73.66 156.05,73.66 156.39,74 156.39,77.52 159.74,80.87 159.74,91.06 158.76,92.04 158.76,94.74 156.85,96.65 156.85,97.98 156.99,98.13 156.99,98.71 156.59,99.12 156.59,99.12 150.28,105.43 146.7,105.43 144.42,107.71 144.42,107.76 144.35,107.83 144.35,119.27 144.27,119.36 144.27,120.04 143.83,120.48 143.83,124.39 143.82,124.4 143.82,125.59 143.82,125.59 143.82,126.08 143.83,126.08 143.83,134.78 140.54,138.07 140.54,145.75 134.87,151.42 134.87,153.57 133.55,154.89 125.2,154.89 124.59,154.28 119.08,154.28 117.85,155.5 116.03,155.5 112.6,158.93 101.52,158.93 101.36,158.77 101,158.77 100.84,158.93 99.15,158.93 v1(98.79,158.57)
  BOTTOM w0.102: CPU1.AP13 133,80.47 v1(133,80.99) ; R5525.2 R5521.2 R5526.1 107.5,170 107.5,169.03 98.79,160.32 v1(98.79,158.57)
PANEL_SIZE_ID_CONN: length 5.7
  BOTTOM w0.102: LCD1.22 105.15,175.1 105.43,174.82 105.43,173.17 v2(105.29,173.03) 105.29,171.43 R5525.1
PBAT_CHG_SMBCLK: length 203.7
  TOP w0.127: RN2402.1 165.29,47.76 164.49,46.96 v2(163.17,46.96) 162.93,46.96 162.06,47.83 v1(162.06,48.55) ; RN4302.2 154.73,178.54 153.82,178.54 EC4309.1 152.88,178.24 152.87,178.22 148.74,178.22 148.58,178.22 147.3,179.5 147.3,179.77 147.3,180.1 145.45,181.96 140.97,181.96 139.21,183.73 136.61,183.73 v1(136.42,183.54)
  L3 w0.127: v1(162.06,48.55) 162.06,48.61 160.75,49.92 160.75,50.58 161.38,51.21 161.38,56.26 162.06,56.94 162.06,58.27 163.29,59.49 163.29,73.37 164.05,74.14 164.05,75.09 164.78,75.82 164.78,90.63 164.43,90.98 164.43,91.81 163.61,92.63 163.61,93.25 162.97,93.89 162.97,97.55 159.99,100.53 159.99,100.58 155.69,104.88 154.93,104.88 154.91,104.86 154.52,104.86 147.8,111.58 147.8,120.4 147.02,121.17 147.02,122.8 147.02,124.54 146.19,125.37 146.19,135.76 142.9,139.05 142.9,146.73 140.22,149.42 140.22,150.94 137.96,153.19 137.96,155.06 135.64,157.39 126.43,157.39 120.59,163.22 120.59,172.82 120.29,173.12 120.29,174.66 121.65,176.02 121.65,177.02 125.44,180.81 130.24,180.81 132.25,182.81 134.57,182.81 135.3,183.54 v1(136.42,183.54)
  BOTTOM w0.127: PR4471.1 134.24,182.45 135.34,183.54 v1(136.42,183.54) ; v1(162.06,48.55) KBC24.9
PBAT_CHG_SMBDAT: length 203.7
  TOP w0.127: RN4302.1 154.73,179.04 153.76,179.04 EC4310.1 152.73,178.55 148.71,178.55 147.63,179.63 147.63,180.24 145.58,182.29 141.11,182.29 139.31,184.09 133.29,184.09 v1(132.77,183.57) ; v1(161.31,48.52) 161.31,47.71 v2(161.6,47.43) 162.45,46.57 164.59,46.57 165.12,47.11 RN2402.2
  L3 w0.127: v1(161.31,48.52) 160.33,49.5 160.33,50.88 161.05,51.6 161.05,57.72 162.95,59.63 162.95,73.52 163.4,73.96 163.41,73.96 163.71,74.26 163.71,75.21 164.45,75.95 164.45,89.44 163.28,90.61 163.28,93.12 162.64,93.76 162.64,97.41 159.66,100.39 159.66,100.44 155.55,104.55 155.07,104.55 155.05,104.53 154.38,104.53 147.47,111.44 147.47,120.26 146.69,121.03 146.69,122.93 146.69,124.4 145.86,125.23 145.86,135.62 142.57,138.91 142.57,146.59 139.89,149.28 139.89,150.8 137.49,153.2 137.49,153.67 134.1,157.06 126.29,157.06 120.26,163.09 120.26,163.09 119.7,163.64 119.7,174.57 121.32,176.19 121.32,177.2 125.27,181.14 130.11,181.14 132.11,183.15 132.35,183.15 v1(132.77,183.57)
  BOTTOM w0.127: v1(161.31,48.52) 161.66,48.18 KBC24.8 ; PR4470.1 133.38,182.96 v1(132.77,183.57)
PBAT_PRES1#: length 7.5
  TOP w0.457: 156.2,180.53 155.9,180.53 R4302.2
  TOP w0.508: BATT1.5 158.25,182.01 158.05,181.81 D4304.3 157.48,181.81 AFTP4303.1 156.2,180.53
PBAT_PRES#: length 222.3
  TOP w0.457: 154.49,180.11 R4302.1
  TOP w0.508: PR4472.2 128.56,181.6 PC4433.1 v1(128.56,183.34) ; v1(150.21,107) 148.24,108.97 148.24,116.7 145.24,119.7 v1(145.1,119.7) ; v1(171.74,49.68) 171.32,49.25 v2(169.49,49.25) 168.55,49.25 168.19,49.61 163.6,49.61 163.24,49.25 160.41,49.25 159.91,48.75 159.91,48.22 161.98,46.15 162.04,46.15 162.16,46.03 v1(162.5,46.03) ; v1(138.13,178.54) 139.19,178.54 139.63,178.98 139.63,182.3 v1(139.05,182.88) ; v1(141.73,182.81) 146.34,182.81 EC4306.1 149.05,181.23 153.68,181.23 154.49,180.42 154.49,180.11
  L3 w0.508: v1(160.8,98.2) 162.12,96.88 162.12,93.54 162.76,92.9 162.76,87.99 162.82,87.93 162.82,86.9 162.44,86.51 162.44,79.73 162.3,79.59 162.3,76.62 161.62,75.94 161.62,73.92 161.42,73.72 161.42,72.45 161.98,71.88 161.98,66.65 161.13,65.79 161.13,63.08 159.08,61.04 159.08,51.95 159.35,51.69 159.35,48.78 160.28,47.85 160.67,47.85 v1(162.5,46.03)
  L4 w0.508: v1(145.1,119.7) 145.1,121.41 145.13,121.43 145.13,121.46 145.19,121.52 145.19,121.52 145.56,121.9 145.56,121.9 145.95,122.29 145.95,137.48 146.85,138.38 146.85,139.36 146.19,140.02 146.19,140.77 134.37,152.59 134.01,152.59 133,153.59 133,155.07 124.45,163.63 124.45,167.92 125.36,168.83 125.36,169.44 125.69,169.77 125.69,179.73 128.3,182.35 128.3,183.09 v1(128.56,183.34) 129.39,184.18 132.48,184.18 132.51,184.2 133.04,184.2 133.06,184.18 137.75,184.18 v1(139.05,182.88) 141.66,182.88 v1(141.73,182.81) ; v1(150.21,107) 153.89,107 154.75,106.14 155.05,106.14 155.57,105.62 155.57,104.6 155.94,104.22 155.94,103.7 159.26,100.38 159.31,100.38 160.8,98.9 v1(160.8,98.2)
  BOTTOM w0.191: KBC24.29 170.06,48.17 170.4,48.52
  BOTTOM w0.508: 170.4,48.52 171.61,49.72 171.74,49.72 ; 171.74,49.72 171.74,49.84 172.54,50.64 R2415.2 ; 171.74,49.72 v1(171.74,49.68) ; v1(138.13,178.54) 138.3,178.37 PR4439.2 PR4409.2
PBAT_SMBCLK1: length 16.2
  TOP w0.127: RN4302.3 155.79,178.54 156.51,178.54 D4306.3 158.9,178.3 159.51,177.69 160.4,177.69 160.61,177.9 162.31,177.9 163.16,178.75 163.16,180.56 AFTP4304.1 162.25,182.59 BATT1.3
PBAT_SMBDAT1: length 16.5
  TOP w0.127: BATT1.4 161.92,184.13 161.92,181.38 AFTP4308.1 162.51,181.08 162.83,180.77 162.83,178.89 162.17,178.23 D4305.3 159.71,178.23 159.3,178.63 157.3,178.63 156.81,179.11 RN4302.4
PCH_BATLOW#: length 17.6
  TOP w0.089: 134.22,72.67 138.79,68.09
  TOP w0.102: 134.22,72.67 134.04,72.84 134.04,73.78 133.64,74.19 133.64,74.91 133.77,75.04 133.77,76.14 v1(132.12,77.78) ; RN1704.6 140.26,65.28 140.26,65.63 140.87,66.24 v2(140.87,66.39) 140.87,66.97 139.74,68.09 138.79,68.09
  BOTTOM w0.102: CPU1.AU13 v1(132.12,77.78)
PCH_DPC_AUXN: length 112.7
  TOP w0.178: v1(29.62,72.29) 29.42,72.49 29.42,72.93 30.45,73.95 30.45,74.22 ; 30.45,74.22 30.45,74.58 30.09,74.93 29.4,74.93 C5625.1 ; 30.45,74.22 v2(30.56,74.22)
  L4 w0.152: v1(112.01,94.51) 112.07,94.51 112.45,94.9 112.45,96.34 112.2,96.6 111.36,96.6 109.48,98.47 109.48,98.9 107.11,101.27 104.91,101.27 104.07,102.11 94.62,102.11 92.03,104.7 83.24,104.7 79.46,100.92 77.88,100.92 69.41,92.45 66.78,92.45 64.72,90.39 44.81,90.39 38.1,83.68 31.82,83.68 29.41,81.28 29.41,72.5 v1(29.62,72.29)
  BOTTOM w0.127: CPU1.E48 112.39,94.89 v1(112.01,94.51)
PCH_DPC_AUXN_U: length 3.3
  TOP w0.178: C5625.2 27.95,74.91 27.64,74.91 27.52,75.03 27.52,75.82 27.32,76.02 ; 27.32,76.02 27.14,76.19 26.84,76.19 26.79,76.24 U5601.3 ; 27.32,76.02 v2(27.43,76.14)
PCH_DPC_AUXP: length 112.9
  TOP w0.178: C5624.1 29.4,74.63 29.96,74.63 30.14,74.45 30.14,74.08 29.12,73.05 29.12,72.95 ; 29.12,72.95 29.12,72.49 v1(28.91,72.29) ; 29.12,72.95 v2(29.01,72.95)
  L4 w0.152: v1(28.91,72.29) 29.12,72.5 29.12,81.4 31.7,83.97 37.98,83.97 44.69,90.68 64.6,90.68 66.66,92.74 69.29,92.74 77.76,101.21 79.34,101.21 83.12,104.99 92.15,104.99 94.74,102.4 104.19,102.4 105.03,101.56 107.23,101.56 109.77,99.03 109.77,98.59 111.48,96.89 112.32,96.89 112.75,96.47 112.75,94.96 112.93,94.77 v1(112.93,94.59)
  BOTTOM w0.127: v1(112.93,94.59) 112.58,94.24 CPU1.F48
PCH_DPC_AUXP_U: length 3.4
  TOP w0.178: 27.41,74.71 27.52,74.6 28,74.6 C5624.2 ; 27.41,74.71 27.21,74.91 27.21,75.69 27.02,75.89 26.84,75.89 26.79,75.84 U5601.2 ; 27.41,74.71 v2(27.25,74.56)
PCH_DPC_N0: length 100.6
  TOP w0.178: v1(31.27,79.38) 31.68,78.97 31.68,78.56 31.9,78.34 31.9,77.97 31.73,77.79 31.16,77.79 C5605.1
  L4 w0.152: v1(31.27,79.38) 31.69,79.8 31.69,80.11 31.24,80.56 31.24,81.66 32.3,82.72 38.35,82.72 45.45,89.82 65.74,89.82 67.67,91.75 69.57,91.75 78.05,100.23 79.86,100.23 83.75,104.12 92.06,104.12 94.56,101.61 104.22,101.61 104.93,100.9 106.96,100.9 109.11,98.75 109.11,98.32 111.57,95.86 111.75,95.86 v1(112.01,96.12)
  BOTTOM w0.178: v1(31.27,79.38) 31.21,79.44 v2(31.21,79.93) ; v1(112.01,96.12) 111.71,96.12 CPU1.C50
PCH_DPC_N0_U: length 4.3
  TOP w0.178: 27.91,77.72 27.59,77.39 26.84,77.39 26.79,77.44 U5601.6 ; 27.91,77.72 v2(27.81,77.87) ; 27.91,77.72 27.97,77.78 29.64,77.78 C5605.2
PCH_DPC_N1: length 101.1
  TOP w0.178: 30.36,80.29 30.36,80.67 30.74,81.05 31.88,81.05 v1(32.29,81.46) ; 30.36,80.29 v2(30.26,80.29) ; 30.36,80.29 30.36,79.52 29.96,79.12 29.65,79.12 C5604.1
  L4 w0.152: v1(109.89,96.16) 109.71,96.16 108.05,97.82 108.05,98.48 107.53,99.01 106.07,99.01 104.1,100.98 94.15,100.98 91.87,103.27 84.63,103.27 80.65,99.29 78.33,99.29 69.8,90.76 68.07,90.76 66.19,88.88 45.8,88.88 37.97,81.04 34.97,81.04 34.65,80.72 34.65,78.35 34.5,78.2 34.19,78.2 34.04,78.35 34.04,80.72 33.72,81.04 32.71,81.04 v1(32.29,81.46)
  BOTTOM w0.178: CPU1.C52 110.23,96.16 v1(109.89,96.16)
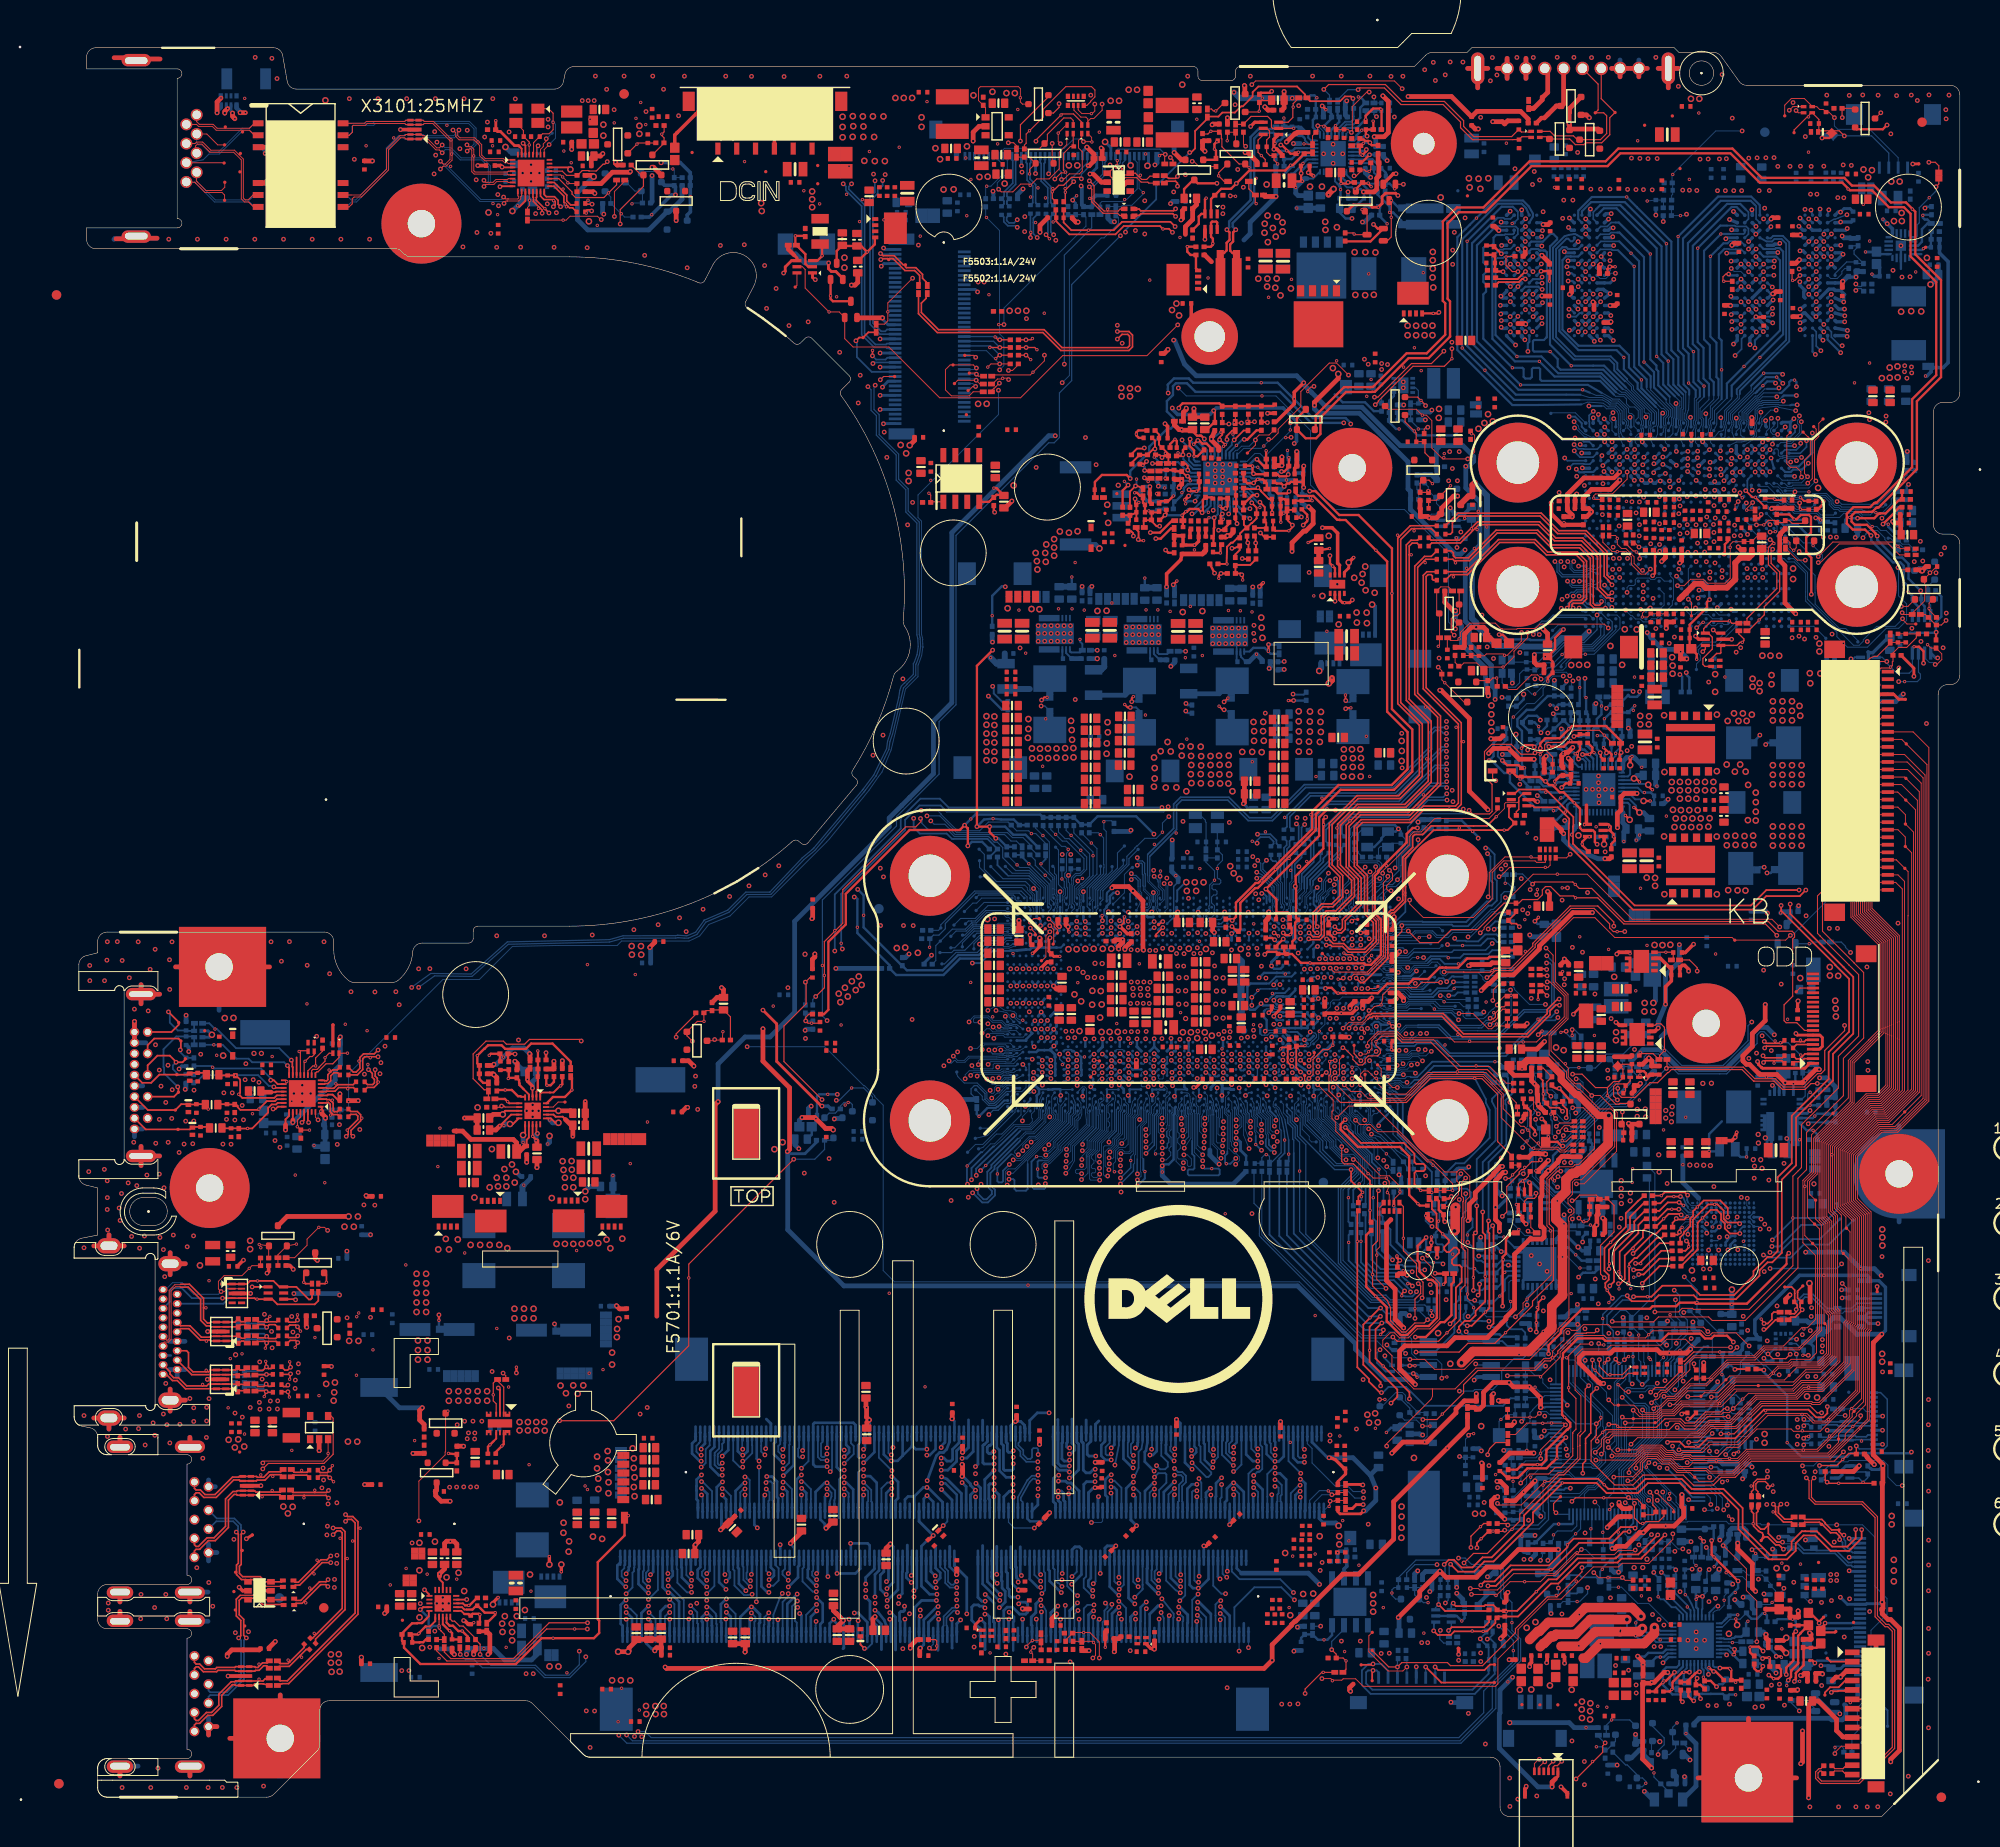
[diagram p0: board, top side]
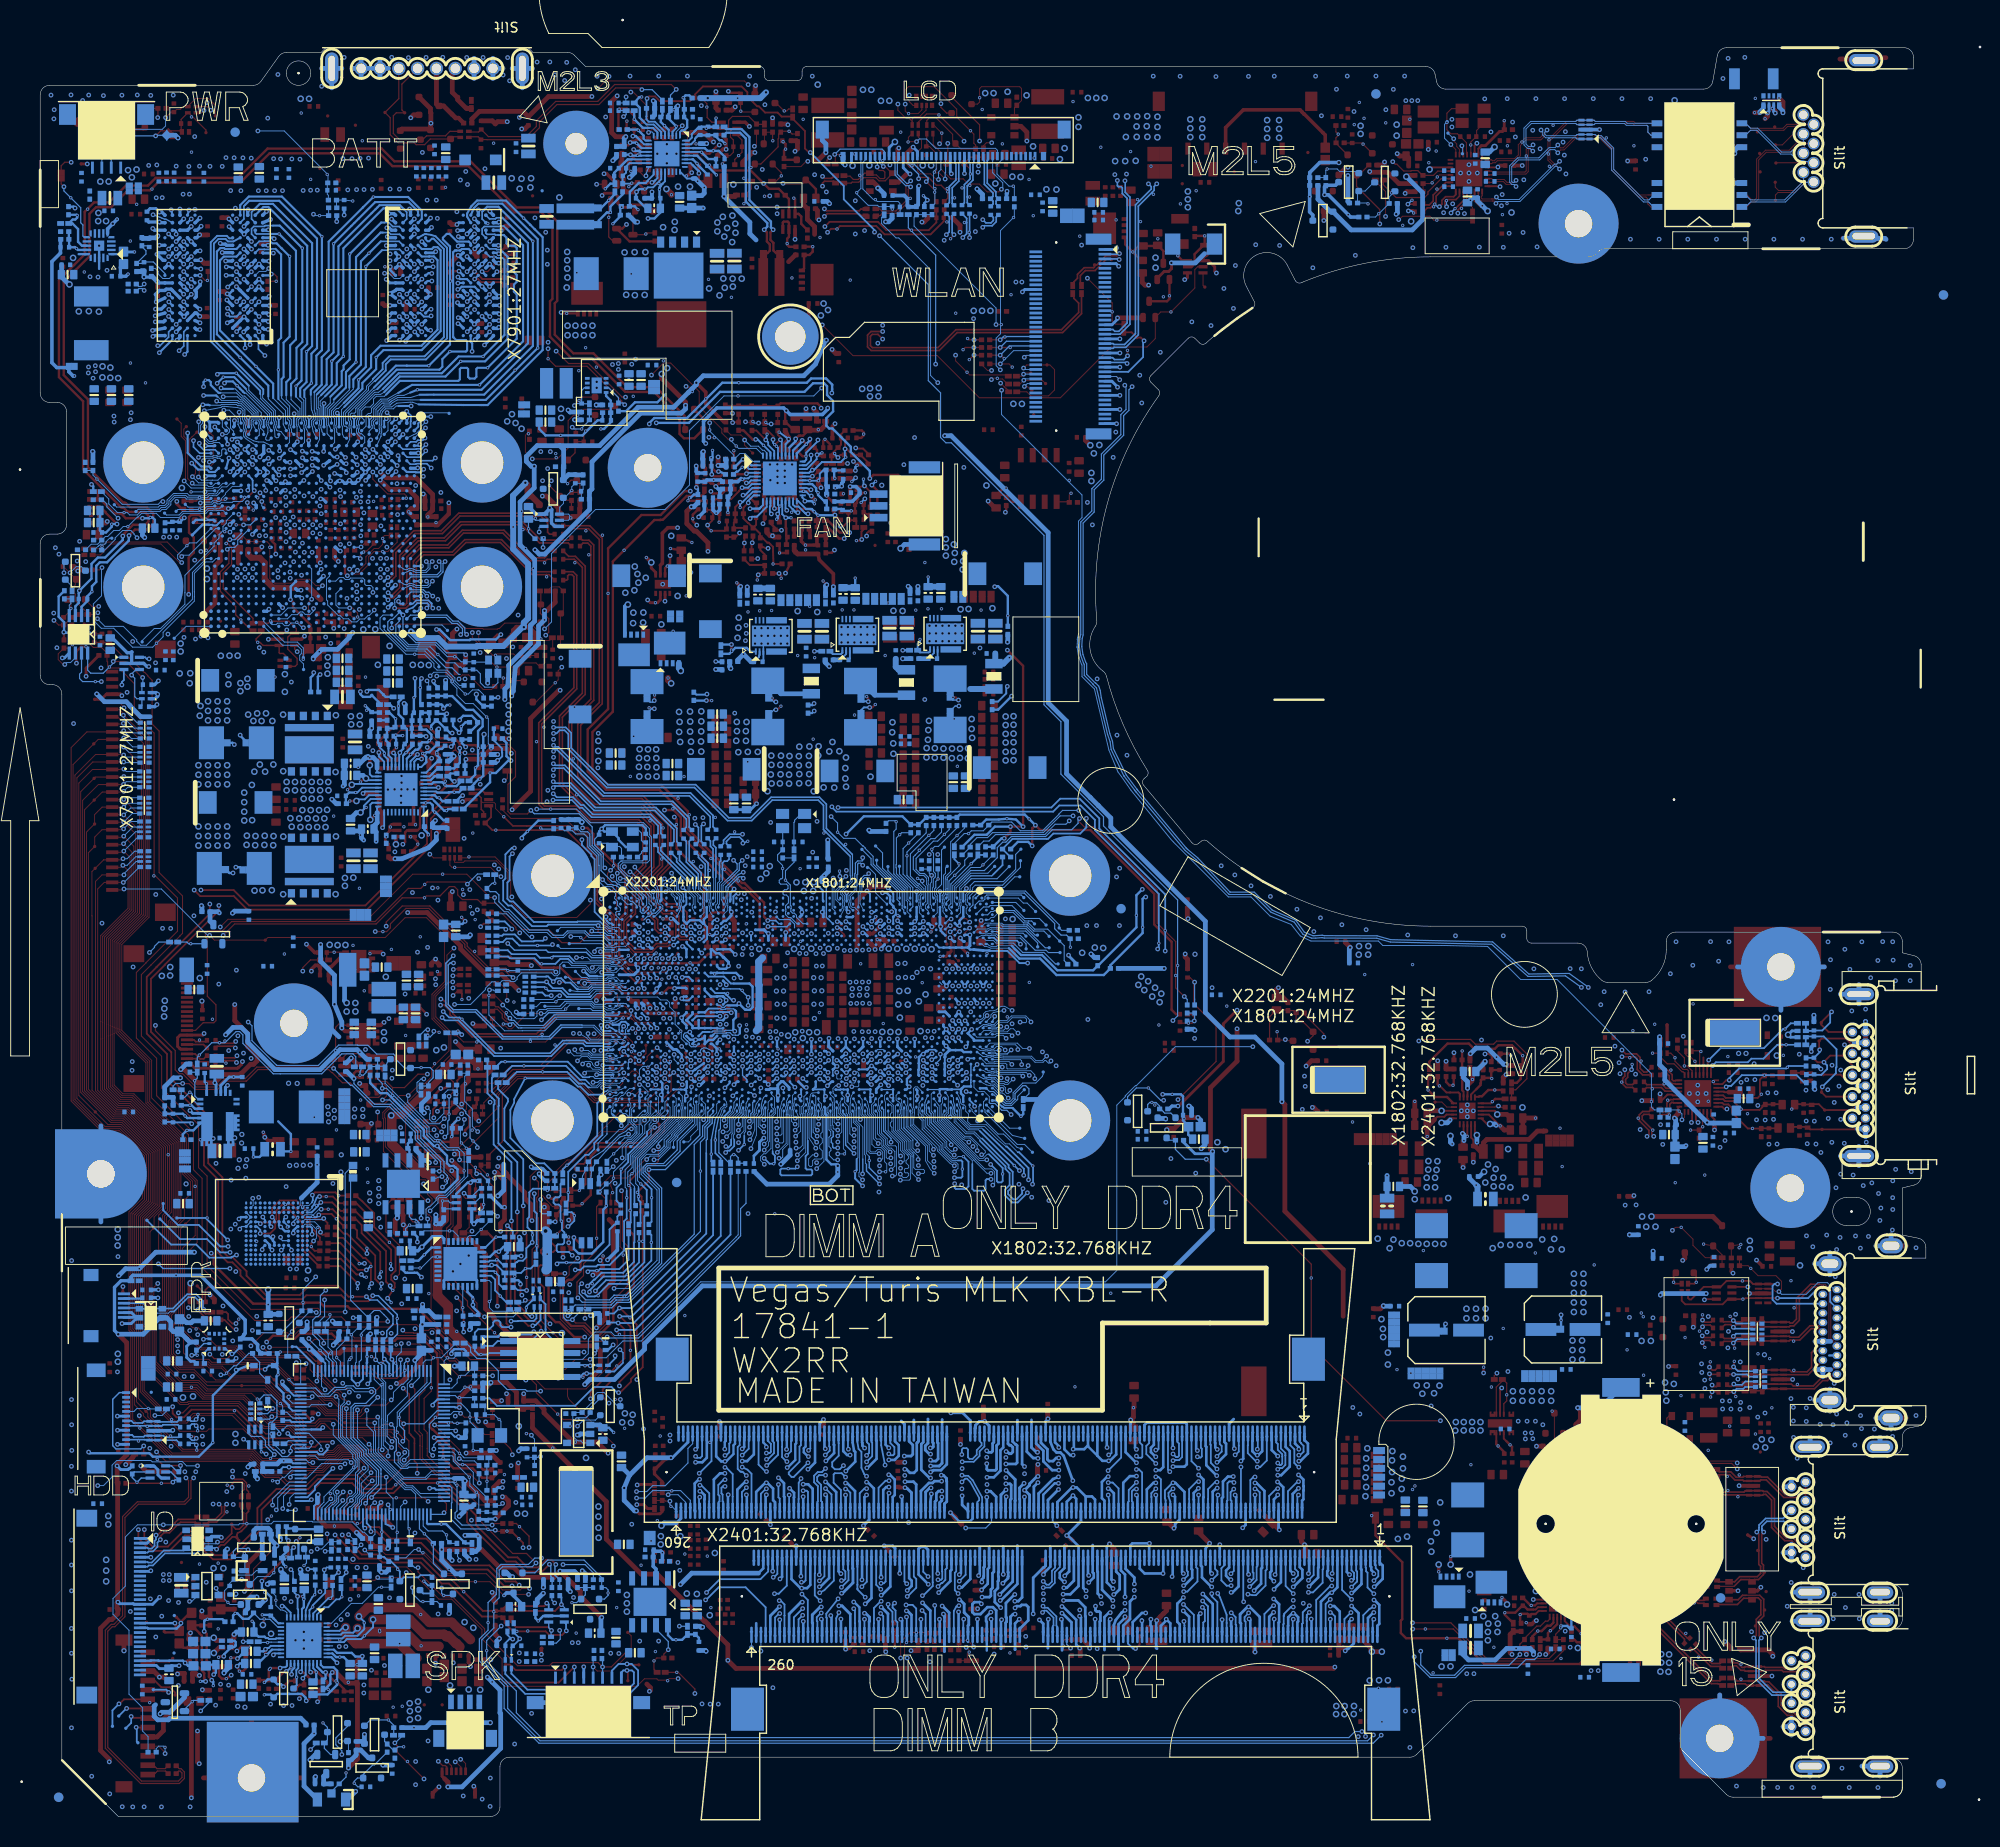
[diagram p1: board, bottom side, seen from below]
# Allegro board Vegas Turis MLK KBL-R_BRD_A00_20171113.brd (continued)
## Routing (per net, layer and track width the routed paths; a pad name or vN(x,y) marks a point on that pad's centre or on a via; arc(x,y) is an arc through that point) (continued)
PCH_DPC_N1_U: length 3.2
  TOP w0.178: U5601.8 26.57,78.24 26.62,78.19 26.83,78.19 26.96,78.32 26.96,78.84 27.28,79.16 ; C5604.2 27.95,79.35 27.47,79.35 27.28,79.16 ; v2(27.09,79.34) 27.28,79.16
PCH_DPC_P0: length 100.1
  TOP w0.178: C5601.1 31.16,77.49 31.85,77.49 32.21,77.85 32.21,78.06 ; 32.21,78.06 32.21,78.47 31.99,78.69 v1(31.99,79.38) ; 32.21,78.06 v2(32.32,78.06)
  L4 w0.152: v1(111.99,95.15) 111.99,95.35 111.82,95.53 111.49,95.53 108.82,98.2 108.82,98.63 106.84,100.61 104.81,100.61 104.1,101.32 94.44,101.32 91.94,103.82 83.87,103.82 79.99,99.94 78.18,99.94 69.69,91.45 67.79,91.45 65.86,89.52 45.57,89.52 38.47,82.43 32.42,82.43 31.53,81.54 31.53,80.68 31.99,80.23 v1(31.99,79.38)
  BOTTOM w0.178: v1(111.99,95.15) 111.99,95.18 CPU1.D50
PCH_DPC_P0_U: length 4.2
  TOP w0.178: C5601.2 29.68,77.47 29.06,77.47 ; 29.06,77.47 28.1,77.47 27.72,77.09 26.84,77.09 26.79,77.04 U5601.5 ; 29.06,77.47 v2(29.06,77.35)
PCH_DPC_P1: length 101.2
  TOP w0.178: v1(32.29,80.75) 31.46,80.75 ; 31.46,80.75 30.87,80.75 30.67,80.55 30.67,79.39 30.09,78.82 C5603.1 ; 31.46,80.75 v2(31.46,80.65)
  L4 w0.152: v1(110.18,95.18) 110.18,95.28 107.76,97.69 107.76,98.36 107.4,98.72 105.95,98.72 103.98,100.69 94.03,100.69 91.75,102.97 84.75,102.97 80.77,99 78.46,99 69.92,90.46 68.19,90.46 66.31,88.58 45.92,88.58 38.09,80.75 35.09,80.75 34.94,80.6 34.94,78.23 34.62,77.91 34.07,77.91 33.75,78.23 33.75,80.6 33.59,80.75 v1(32.29,80.75)
  BOTTOM w0.178: CPU1.D52 v1(110.18,95.18)
PCH_DPC_P1_U: length 2.9
  TOP w0.178: U5601.7 26.59,77.84 26.64,77.89 26.96,77.89 27.26,78.19 27.26,78.72 27.59,79.05 28,79.05 C5603.2
PCH_DPWROK: length 28.7
  BOTTOM w0.127: R1704.2 142,54.07 139.63,54.07 139.41,54.29 139.06,54.64 137.75,54.64 130.2,62.19 v2(130.2,68.6) 130.2,71.66 129.73,72.13 129.73,73.27 129.2,73.81 129.2,74.45 128.85,74.8 CPU1.BB20
PCH_JTAG_TCK: length 10.8
  BOTTOM w0.089: 108.25,98.79 108.17,98.7 108.17,97.46 107.91,97.2 CPU1.B56
  BOTTOM w0.114: R407.1 110.21,105.84 109.51,105.84 v2(109.41,105.73) 109.41,104.95 109.66,104.7 109.66,100.19 108.25,98.79
PCH_JTAG_TDI: length 10.6
  BOTTOM w0.089: CPU1.D59 106.94,96.05 106.94,96.69 106.99,96.83 106.99,97.1 106.97,97.16 106.97,97.42 106.99,97.48 106.99,97.93 106.84,98.08 106.84,98.46 107.1,98.72 107.24,98.72
  BOTTOM w0.114: R408.1 107.04,104.5 v2(108.08,103.47) 108.67,102.88 108.67,100.15 107.24,98.72
PCH_JTAG_TDO: length 8.8
  BOTTOM w0.114: CPU1.A56 107.91,98.73 109.38,100.2 109.38,100.81 109.42,100.84 109.42,101.14 109.38,101.18 109.38,104 v2(109.03,104.35) 108.83,104.56 R409.1
PCH_JTAG_TMS: length 10.7
  BOTTOM w0.089: CPU1.C59 106.76,96.52 106.76,96.73 106.82,96.86 106.82,97.06 106.79,97.12 106.79,97.45 106.82,97.51 106.82,97.84 106.67,97.99 106.67,98.54 107.04,98.92
  BOTTOM w0.114: 107.04,98.92 107.15,98.92 108.26,100.02 v2(108.26,102.12) 108.26,102.5 106.21,104.54 R416.1
PCH_PLTRST#: length 33
  L3 w0.127: v1(153.91,71.1) 153.78,71.23 150.47,71.23 150.34,71.1 144.92,71.1 143.91,71.52 139.47,75.96 136.09,75.96 134.96,77.08 134.67,77.08 134.28,77.48 134.28,77.64 133.96,77.95 133.85,77.95 133.5,78.3 133.5,79.25 133.48,79.27 133.48,80.49 133.94,80.95 v1(133.94,80.99)
  BOTTOM w0.127: R1713.2 156.2,75.73 155.76,75.28 155.5,75.28 155.13,74.92 155.13,74.75 154.68,74.29 154.68,72.11 v2(154.36,71.79) 153.91,71.34 v1(153.91,71.1) ; v1(133.94,80.99) 134.13,80.99 CPU1.AN10
PCH_POPIRCOMP: length 6.4
  TOP w0.127: R413.2 v2(133.74,81.97) 133.29,81.52 132.69,81.52 131.63,80.46 131.63,78.87 v1(131.2,78.44)
  BOTTOM w0.305: v1(131.2,78.44) 130.86,78.1 CPU1.AU16
PCH_RSMRST#: length 35.8
  L4 w0.127: v1(153.98,68.31) 154.28,68.31 154.77,67.82 154.81,67.82 156.87,65.75 156.91,65.75 158.22,65.75 158.36,65.89 159.34,65.89 161.28,63.94 161.28,62.73 162.46,61.55 165.29,61.55 170.01,56.83 v1(170.01,55.93)
  BOTTOM w0.127: v2(154.11,68.99) 154.11,68.44 v1(153.98,68.31) 153.51,68.31 EC1712.1 152.69,67.49 152.69,66.86 R1702.2 ; v1(170.01,55.93) 170.58,55.36 170.58,53.76 170.58,53.75 170.58,53.39 170.84,53.13 171.03,53.13 171.39,52.76 171.39,51.26 170.67,50.53 170.67,50.11 170.48,49.92 170.46,49.92 169.73,49.18 169.73,48.79 169.26,48.32 KBC24.27
PCH_SMBCLK: length 402.2
  TOP w0.191: v1(146.25,26.8) 147.03,26.02 148.75,26.02 149.83,27.1 150.8,27.1 155,31.29 155,32.32 v2(158.12,35.45) 161.75,35.45 162.81,34.38 166.16,34.38 167.21,35.43 170.62,35.43 171.69,34.36 175.06,34.36 176.83,32.59 176.83,30.53 180.03,27.33 180.4,27.33 182,27.33 182.92,28.24 182.92,29.04 183.75,29.87 184.97,29.87 186.62,28.22 188.57,28.22 189.92,29.57 v1(189.92,30.48) ; v1(24.91,73.77) 24.84,73.84 U5601.30 ; v1(183.99,98.47) 183.35,97.82 179.78,97.82 178.35,96.39 165.61,96.39 158.81,103.2 158.81,105.53 158.85,105.57 158.85,106.05 157.63,107.27 155.15,107.27 154.98,107.43 Q1801.4
  L3 w0.165: v1(146.25,26.8) 144.61,28.44 141.37,28.44 138.02,31.79 138.02,33.51 v1(136.99,34.54) 135.96,33.5 135.96,32.92 135.82,32.78 135.82,28.92 132.86,25.96 132.58,25.69 132.2,25.69 132.2,25.69 131.24,25.69 129.55,24.01 v1(129.55,23.8) ; v1(183.99,98.47) 185.3,97.16 185.3,84.98 188.91,81.36 188.91,71.35 187.67,70.11 187.67,59.27 187.33,58.93 187.33,58.84 184.6,56.11 184.54,56.11 182.5,54.07 182.5,50.57 182.53,50.54 182.98,50.09 182.98,49.15 v1(182.98,49.15) 183.47,48.66 183.47,44.9 182.61,44.04 182.61,36.76 186.06,33.31 187.12,33.31 189.92,30.51 v1(189.92,30.48)
  L4 w0.165: v1(129.55,23.8) 127.86,22.11 127.86,18.38 122.7,13.22 50.81,13.22 49.46,14.57 24.73,14.57 20.29,19.02 20.29,20.1 19.18,21.2 19.18,39.72 16.62,42.29 16.62,53.46 17.71,54.55 17.71,56.63 20.76,59.68 20.76,64.61 24.91,68.76 v1(24.91,73.77)
  BOTTOM w0.114: v1(136.99,34.54) 135.9,34.54 135.28,35.16 133.94,35.16 131.53,37.57 131.53,39.12 131.02,39.62 DM1.253
  BOTTOM w0.14: 145.97,25.4 146.1,25.53 146.1,26.66 v1(146.25,26.8)
  BOTTOM w0.152: 145.97,25.4 145.97,25.19 EC6505.1 145.96,24.36 R6515.1
  BOTTOM w0.191: R1834.1 183.02,48.27 183.02,49.11 v1(182.98,49.15) 182.98,49.24 182.52,49.7 U6701.1 ; DM2.253 122.99,27.47 122.99,26.27 123,26.26 123,26.04 123.82,25.22 128.13,25.22 v1(129.55,23.8)
PCH_SMBDATA: length 406.5
  TOP w0.14: v1(179.97,49.16) 180.47,48.66 181.86,48.66 v1(182.33,49.13)
  TOP w0.191: Q1801.1 153.08,108.73 153.5,109.15 156.37,109.15 159.29,106.24 159.29,105.27 159.25,105.23 159.25,103.38 165.8,96.83 178.16,96.83 179.8,98.47 v1(183.27,98.47) ; v1(145.57,26.78) 145.57,26.8 146.05,27.28 146.6,27.28 147.41,26.47 148.57,26.47 149.64,27.54 150.62,27.54 154.05,30.97 154.05,32 157.94,35.89 161.93,35.89 v2(162.57,35.25) 163,34.82 165.89,34.82 166.94,35.87 170.8,35.87 171.87,34.81 175.25,34.81 177.27,32.78 177.27,30.71 180.21,27.77 181.82,27.77 182.47,28.43 182.47,29.22 183.57,30.32 183.94,30.32 183.94,30.32 185.15,30.32 185.41,30.06 186.79,28.68 188.4,28.68 189.29,29.57 v1(189.29,30.49) ; v1(24.21,73.77) 24.44,74 U5601.29
  L3 w0.165: v1(129.65,23.02) 130.02,23.39 130.02,23.88 131.41,25.27 131.94,25.27 132.76,25.27 136.24,28.75 136.24,32.57 136.37,32.7 136.37,32.8 136.38,32.81 136.38,33.23 v1(136.99,33.84) 137.57,33.27 137.57,31.66 141.2,28.02 144.33,28.02 v1(145.57,26.78) ; v1(183.27,98.47) 184.88,96.86 184.88,84.8 188.49,81.19 188.49,71.53 187.26,70.29 187.26,60.45 182.76,55.95 182.76,55.25 182.08,54.57 182.08,49.63 182.33,49.38 v1(182.33,49.13) 183.05,48.4 183.05,45.08 182.19,44.21 182.19,36.59 185.88,32.9 186.88,32.9 v1(189.29,30.49)
  L4 w0.165: v1(24.21,73.77) 24.21,69.13 20.34,65.27 20.34,59.85 17.29,56.8 17.29,54.72 16.2,53.64 16.2,42.11 18.76,39.56 18.76,29.71 18.76,29.71 18.76,29.32 18.76,29.32 18.76,21.03 19.87,19.92 19.87,18.84 24.56,14.15 49.28,14.15 50.64,12.8 124.14,12.8 128.28,16.94 128.28,21.79 129.51,23.02 v1(129.65,23.02)
  BOTTOM w0.114: DM1.254 131.27,33.6 132.31,34.64 135.28,34.64 136.07,33.84 v1(136.99,33.84)
  BOTTOM w0.127: EC6506.1 145.15,25.15 R6511.1
  BOTTOM w0.152: EC6506.1 145.66,25.66 145.66,26.69 v1(145.57,26.78)
  BOTTOM w0.191: R1835.1 179.82,49.16 v1(179.97,49.16) 180.09,49.16 180.63,49.7 U6701.4 ; DM2.254 123.27,22.23 125.4,24.36 128.26,24.36 129.59,23.02 v1(129.65,23.02)
PCH_THERMTRIP: length 10
  BOTTOM w0.089: CPU1.C63 104.21,96.56 104.25,96.62 104.34,96.88 104.34,97.05 104.3,97.16 104.3,97.44 104.34,97.51 104.34,97.84 104.19,97.98 104.19,98.06 104.19,98.07 104.19,98.53 104.19,98.54 104.19,99.65 104.17,99.66 104.17,99.87 103.96,100.09
  BOTTOM w0.102: 102.93,104.26 102.93,104.26 102.13,105.07 R419.2 ; 102.93,104.26 103.61,103.59 103.61,100.44 103.96,100.09 ; 102.93,104.26 v2(102.94,104.26)
PCH_WAKE#: length 14.9
  TOP w0.102: RN1704.7 139.72,66.12 v2(139.54,66.31) 139.48,66.44 139.72,67.03 139.72,67.52 139.39,67.86 138.04,67.86 136.07,69.83 v1(135.91,69.83)
  BOTTOM w0.089: CPU1.BB15 131.37,74.89 131.37,74.11 132.31,73.17
  BOTTOM w0.102: v1(135.91,69.83) 135.55,70.19 134.56,70.19 133.64,71.11 133.64,71.7 132.99,72.35 132.99,72.5 132.32,73.17 132.31,73.17
PCIE_CALR_RX: length 3.1
  TOP w0.127: v1(166.34,133.7) 166.34,134.04 v2(165.98,134.4) 165.87,134.51 165.64,134.51 164.88,135.27 R7618.1
  BOTTOM w0.127: GPU1.AA22 166.54,133.9 v1(166.34,133.7)
PCIE_CALR_TX: length 1.5
  TOP w0.127: v1(166.26,134.93) 165.84,135.35 R7622.2
  BOTTOM w0.127: GPU1.Y22 166.29,134.9 v1(166.26,134.93)
PCIE_CLK_XDP_N: length 1.8
  TOP w0.178: v1(115.67,94.48) 114.95,93.75 TP1807.1
  BOTTOM w0.178: CPU1.F43 115.26,94.36 115.6,94.5 v1(115.67,94.48)
PCIE_CLK_XDP_P: length 1.1
  TOP w0.178: TP1808.1 115.27,94.79 115.59,95.11 v1(115.67,95.11)
  BOTTOM w0.178: v1(115.67,95.11) 115.43,95.11 CPU1.E43
PCIE_RCOMPN: length 1.3
  TOP w0.254: R1604.1 136.75,93.96 v1(136.7,93.91)
  BOTTOM w0.305: v1(136.7,93.91) 136.91,93.91 137.15,94.16 CPU1.F5
PCIE_RCOMPP: length 1.3
  TOP w0.254: v1(136.7,94.56) 136.96,94.83 R1604.2
  BOTTOM w0.305: CPU1.E5 v1(136.7,94.56)
PCIE_RX_CON_N5: length 4.5
  TOP w0.178: C3107.1 53.23,171.29 52.76,171.29 52.34,171.7 52.34,172.35 51.83,172.86 ; LOM31.18 51.01,173.68 51.83,172.86 ; 51.83,172.86 v2(51.95,172.98)
PCIE_RX_CON_P5: length 4.5
  TOP w0.178: v2(52.3,171.09) 52.42,171.2 ; 52.42,171.2 52.04,171.58 52.04,172.22 50.98,173.28 LOM31.17 ; 52.42,171.2 52.63,170.98 52.96,170.98 C3102.1
PCIE_RX_CPU_N5: length 171.5
  TOP w0.178: v1(55.03,171.37) 54.38,171.37 C3107.2
  L4 w0.152: v1(55.03,171.37) 55.03,171.37 56.07,172.41 62.42,172.41 65.97,175.96 83.18,175.96 84.44,174.7 84.44,173.85 85.1,173.18 90.85,173.18 91.87,172.15 105.07,172.15 107.5,169.72 107.5,166.68 106.81,165.98 106.81,153.69 106.79,153.67 106.79,152.93 105.2,151.34 104.46,151.34 95.38,142.27 95.38,120.59 94.67,119.88 94.67,111.34 96.35,109.67 109.48,109.67 113.9,105.25 113.9,104.65 117.4,101.14 121.43,101.14 126.06,96.52 126.06,96.13 127.07,95.12 127.07,93.07 127.38,92.77 128.68,92.77 129.1,93.19 129.1,94.64 129.6,95.14 130.12,95.14 v1(131.21,94.57)
  BOTTOM w0.178: v1(55.03,171.37) 54.61,171.79 v2(54.6,171.79) ; CPU1.F16 v1(131.21,94.57)
PCIE_RX_CPU_N6: length 160.4
  L4 w0.152: v1(81.72,173.53) 82.21,174.02 82.29,174.02 82.66,174.39 83.19,174.39 83.57,174.02 83.57,173.35 85,171.92 90.74,171.92 91.73,170.93 104.48,170.93 106.48,168.93 106.48,167.13 105.96,166.61 105.96,154.04 94.53,142.62 94.53,120.96 93.75,120.18 93.75,110.56 95.65,108.66 95.77,108.66 107.82,108.66 112.76,103.73 112.88,103.73 113.41,103.73 114.93,102.21 115.55,102.21 117.35,100.42 121.4,100.42 124.33,97.49 124.33,95.94 124.71,95.56 125.88,95.56 126.46,94.98 126.46,92.87 127.27,92.06 128.94,92.06 129.63,92.76 130.09,92.76 130.3,92.96 v1(130.3,93.27)
  BOTTOM w0.178: 82.24,172.59 82,172.84 82,173.25 v1(81.72,173.53) ; 82.24,172.59 83.67,171.16 83.67,157.48 85.01,156.15 86.26,156.15 86.36,156.05 WLAN1.43 ; 82.24,172.59 v2(82.07,172.42) ; v1(130.3,93.27) 130.04,93.27 129.84,93.47 CPU1.G18
PCIE_RX_CPU_P5: length 171.4
  TOP w0.178: v1(54.98,170.65) 54.87,170.77 54.51,170.77 C3102.2
  L4 w0.152: v1(130.3,94.57) 130.01,94.85 129.73,94.85 129.39,94.52 129.39,93.07 128.8,92.47 127.26,92.47 126.78,92.95 126.78,95 125.77,96.01 125.77,96.4 121.31,100.85 117.28,100.85 113.61,104.53 113.61,105.13 109.36,109.37 96.22,109.37 94.38,111.22 94.38,120 95.09,120.72 95.09,142.39 104.33,151.63 105.08,151.63 106.5,153.05 106.5,153.79 106.52,153.81 106.52,166.11 107.21,166.8 107.21,169.6 104.95,171.86 91.75,171.86 90.72,172.89 84.98,172.89 84.14,173.72 84.14,174.58 83.06,175.67 66.1,175.67 62.55,172.12 56.19,172.12 55.81,171.74 55.81,170.85 55.61,170.65 v1(54.98,170.65)
  BOTTOM w0.178: v1(130.3,94.57) 130.43,94.57 CPU1.E16 ; v2(54.42,170.43) 54.64,170.65 v1(54.98,170.65)
PCIE_RX_CPU_P6: length 160.4
  L4 w0.152: v1(82.6,173.53) 82.58,173.55 82.58,173.9 82.78,174.1 83.07,174.1 83.27,173.9 83.27,173.23 84.88,171.63 90.62,171.63 91.61,170.64 104.36,170.64 106.19,168.81 106.19,167.26 105.67,166.73 105.67,154.16 94.24,142.74 94.24,121.08 93.46,120.3 93.46,110.44 95.53,108.37 95.77,108.37 107.7,108.37 112.64,103.44 113,103.44 113.29,103.44 114.81,101.92 115.43,101.92 117.23,100.12 121.28,100.12 124.04,97.37 124.04,95.82 124.59,95.27 125.75,95.27 126.17,94.85 126.17,92.75 127.15,91.77 129.06,91.77 129.76,92.47 130.21,92.47 130.72,92.97 130.72,93.49 v1(130.3,93.92)
  BOTTOM w0.178: 83.57,171.69 83.98,171.29 83.98,157.61 85.14,156.45 86.26,156.45 86.36,156.55 WLAN1.41 ; 83.57,171.69 82.3,172.96 82.3,173.23 v1(82.6,173.53) ; 83.57,171.69 v2(83.76,171.86) ; CPU1.F18 v1(130.3,93.92)
PCIE_TX_CON_N5: length 182.9
  TOP w0.178: LOM31.14 49.15,172.12 49.1,172.07 49.1,171.79 v1(50.45,170.44)
  L4 w0.152: v1(50.45,170.44) 50.25,170.23 50.25,169.82 49.8,169.37 48.89,169.37 48.23,170.03 48.23,171.1 50.43,173.31 62.11,173.31 65.72,176.91 88.8,176.91 90.82,174.89 94.12,174.89 95.46,176.23 104.04,176.23 105.33,174.93 106.81,174.93 107.28,175.4 108.21,175.4 109.29,174.33 109.29,165.67 108.53,164.91 108.53,152.26 105.89,149.62 105.15,149.62 97.1,141.57 97.1,119.85 96.38,119.13 96.38,112.04 97,111.42 110.37,111.42 116.39,105.4 116.96,105.4 118.23,104.13 122.88,104.13 124.33,105.58 127.1,105.58 128.15,104.53 129.59,104.53 129.86,104.8 v1(129.86,105.5)
  BOTTOM w0.178: v2(50.02,170.9) 50.45,170.47 v1(50.45,170.44) ; v1(129.86,105.5) 129.9,105.5 130.11,105.29 130.11,103.64 C1601.1
PCIE_TX_CON_N6: length 148.4
  L4 w0.152: v1(125.73,104.4) 125.68,104.35 124.01,104.35 122.97,103.31 118.26,103.31 116.88,104.69 115.9,104.69 110.04,110.54 96.67,110.54 95.52,111.69 95.52,119.52 96.24,120.23 96.24,141.92 104.81,150.49 105.55,150.49 107.66,152.6 107.66,165.49 108.41,166.25 108.41,171.06 106.29,173.18 103.03,173.18 102.08,174.13 100.02,174.13 98.78,175.38 95.81,175.38 94.47,174.04 90.47,174.04 89.21,175.3 85.78,175.3 85.4,174.92 85.4,174.16 v1(85.1,173.86)
  BOTTOM w0.178: v1(85.1,173.86) 85.07,173.83 85.07,172.63 84.56,172.12 84.56,158.61 85.62,157.55 WLAN1.37 ; v1(125.73,104.4) 126.56,104.4 ; 126.56,104.4 v2(126.57,104.65) ; 126.56,104.4 127.1,104.4 127.74,103.76 127.74,103.42 C1603.1
PCIE_TX_CON_P5: length 181.6
  TOP w0.178: v1(49.73,170.41) 49.73,170.73 49.44,171.02 ; 49.44,171.02 48.79,171.66 48.79,172.07 48.75,172.12 LOM31.13 ; 49.44,171.02 v2(49.34,170.92)
  L4 w0.152: v1(130.74,105.44) 130.4,105.44 130.16,105.19 130.16,104.68 129.71,104.23 129.54,104.23 128.03,104.23 126.98,105.29 124.45,105.29 123,103.84 118.11,103.84 116.84,105.11 116.26,105.11 110.24,111.13 96.88,111.13 96.08,111.92 96.08,119.25 96.8,119.97 96.8,141.69 105.03,149.92 105.77,149.92 108.23,152.38 108.23,165.03 108.99,165.79 108.99,174.21 108.09,175.11 107.4,175.11 106.93,174.64 105.21,174.64 103.92,175.94 95.58,175.94 94.24,174.59 90.7,174.59 88.67,176.62 65.84,176.62 62.24,173.01 50.55,173.01 48.52,170.98 48.52,170.15 49.01,169.66 49.68,169.66 49.96,169.94 49.96,170.18 v1(49.73,170.41)
  BOTTOM w0.178: C1602.1 130.41,103.62 130.41,105.11 v1(130.74,105.44)
PCIE_TX_CON_P6: length 149.1
  L4 w0.152: v1(85.9,173.89) 85.74,174.04 85.73,174.04 85.69,174.08 85.69,174.8 85.9,175 89.09,175 90.35,173.74 94.59,173.74 95.93,175.08 98.65,175.08 99.9,173.83 101.96,173.83 102.91,172.89 106.17,172.89 108.12,170.93 108.12,166.37 107.37,165.61 107.37,152.72 105.43,150.78 104.69,150.78 95.95,142.04 95.95,120.35 95.23,119.64 95.23,111.57 96.55,110.25 109.92,110.25 115.77,104.39 116.75,104.39 118.13,103.01 123.09,103.01 124.13,104.06 124.67,104.06 124.87,103.86 124.87,103.25 125.05,103.08 125.56,103.08 125.69,103.21 v1(125.69,103.45)
  BOTTOM w0.178: v2(125.17,103.66) v1(125.69,103.45) 125.69,103.74 126.05,104.1 126.98,104.1 127.44,103.63 127.44,103.4 C1604.1 ; v1(85.9,173.89) 85.9,173.33 85.8,173.23 85.5,173.23 85.38,173.1 85.38,172.5 84.87,172 84.87,158.73 85.75,157.85 86.18,157.85 86.37,158.05 WLAN1.35
PCIE_TX_CPU_N5: length 6.9
  BOTTOM w0.089: 129.38,99.68 129.38,99.46 129.12,99.2 129.12,97.51 129.08,97.42 129.08,97.15 129.12,97.06 129.12,96.86 129.07,96.73 129.07,96.52 CPU1.C19
  BOTTOM w0.178: C1601.2 130.07,102.15 130.07,102.02 129.38,101.34 129.38,100.58 ; v2(129.25,100.57) 129.38,100.58 ; 129.38,100.58 129.38,99.68
PCIE_TX_CPU_N6: length 6.5
  BOTTOM w0.089: CPU1.D20 128.56,96.46 128.59,96.67 128.56,96.88 128.38,97.06 128.38,99.21 128.17,99.42 128.17,99.56
  BOTTOM w0.178: C1603.2 128.05,101.59 128.17,101.46 128.17,99.56
PCIE_TX_CPU_P5: length 7.5
  BOTTOM w0.089: CPU1.D19 129.24,96.26 129.24,96.69 129.3,96.83 129.3,97.1 129.26,97.19 129.26,97.39 129.3,97.48 129.3,99.1 129.69,99.5 129.69,99.55
  BOTTOM w0.178: 129.69,99.55 129.69,101.21 130.41,101.93 130.41,102.14 C1602.2
PCIE_TX_CPU_P6: length 6.5
  BOTTOM w0.089: 127.87,99.56 127.87,99.45 128.19,99.13 128.19,96.99 128.29,96.88 CPU1.C20
  BOTTOM w0.178: C1604.2 127.16,101.74 127.36,101.54 127.66,101.54 127.87,101.34 127.87,100.67 ; v2(127.63,100.68) 127.87,100.67 ; 127.87,100.67 127.87,99.56
PCIE_WAKE#: length 423.5
  TOP w0.127: LOM31.21 51.87,174.88 52.31,174.43 R3103.2 53.48,174.43 53.98,174.94 54.67,174.94 54.71,174.89 55.48,174.89 56.2,175.62 56.37,175.62 v1(56.64,175.89) ; v1(147.67,26.94) 148.68,27.95 150.15,27.95 153.6,31.4 153.6,32.13 157.77,36.3 158.27,36.3 159.99,38.02 159.99,39.42 159.99,39.43 159.99,40.4 159.99,40.45 160.55,41.01 160.55,45.42 v1(160.91,45.79)
  L3 w0.127: v1(84.34,151.97) 84.23,152.08 84.23,153.64 83.97,153.9 83.97,156.94 83.44,157.46 81.99,157.46 75.98,163.47 75.98,164.46 71.87,168.57 65.58,168.57 65.04,168.02 58.57,168.02 56.75,169.85 56.75,175.78 v1(56.64,175.89)
  L4 w0.127: v1(58.7,8.66) 58.19,8.16 57.55,8.16 56.98,8.72 53.71,8.72 48.99,13.44 23.75,13.44 19.16,18.04 19.16,19.63 18.76,20.03 18.76,20.03 16.34,22.45 16.34,29.01 16.23,29.13 16.23,29.7 16.34,29.82 16.34,38.15 15.41,39.09 15.41,53.76 16.27,54.63 16.27,56.7 19.69,60.12 19.69,73.08 22.23,75.63 22.23,78.27 29.74,85.78 34.67,85.78 35.86,86.97 v1(35.86,88.12)
  BOTTOM w0.114: KBC24.4 160.06,46.64 v1(160.91,45.79)
  BOTTOM w0.127: v1(35.86,88.12) 35.87,88.15 35.87,88.15 37.89,89.6 42.18,89.54 46.03,92.96 56.85,93.19 58.31,93.6 63.89,93.62 64.12,93.66 64.15,93.66 65.01,93.61 65.12,93.61 66.03,93.99 66.89,95.18 66.92,95.25 66.95,95.26 69.45,96.33 71.36,98.25 73.91,98.25 73.92,98.25 77.37,101.89 78.43,102.78 78.47,102.82 78.57,102.91 78.6,102.96 83.75,109.08 83.83,109.18 83.85,109.22 84.96,110.7 86.32,113.49 86.42,114.28 86.71,115.11 87.61,118.91 87.72,119.69 87.88,120.14 88.2,120.47 88.24,120.47 89.17,121.4 89.17,122.52 89.27,122.7 89.56,123.5 89.68,124.35 89.64,125.2 89.54,125.59 89.54,137.47 88.36,138.65 88.36,141.02 87.34,142.04 87.34,144.7 85.24,146.81 85.24,148.89 84.67,149.46 84.67,151.64 v1(84.34,151.97) ; v1(147.67,26.94) 148.08,26.54 151.23,26.54 151.58,26.19 151.58,23.24 152.15,22.67 v2(152.15,21.76) 152.15,20.04 153.43,18.76 153.43,16.64 152.76,15.96 152.75,15.96 150.68,13.89 150.68,11.47 147.25,8.04 59.32,8.04 v1(58.7,8.66)
PD4404_A: length 2.9
  TOP w0.127: PD4404.A 122.19,173.79 v2(121.6,174.38) 121.6,174.71 PQ4409.B
PD4404_K: length 2.7
  TOP w0.127: v2(125.58,171.43) 125.5,171.52 125.5,172.33 PR4459.2 125.46,172.34 124.81,173 PD4404.K
PDB_R: length 8.4
  BOTTOM w0.102: R2712.2 163.07,24.37 v2(164.08,24.37) 164.41,24.37 166.14,22.64 167.3,22.64 169.41,20.53 HDA27.40
PEG_CLK1_CPU: length 86.8
  TOP w0.178: v1(84.82,155.25) v2(84.83,155.83)
  L4 w0.152: v1(84.82,155.25) 85.25,154.81 87.66,154.81 91.1,151.38 91.1,122.51 90.31,121.73 90.31,108.95 94.51,104.75 106.26,104.75 111.92,99.1 114.8,99.1 115.09,99.39 115.09,99.58 v1(114.75,99.93)
  BOTTOM w0.089: 115.15,99.35 115.15,99.34 115.18,99.31 115.18,98.82 115.63,98.38 115.63,97.52 115.51,97.41 115.4,97.41 115.34,97.47 CPU1.A42
  BOTTOM w0.127: v1(114.75,99.93) 115.15,99.52 115.15,99.35
  BOTTOM w0.178: v1(84.82,155.25) 85.21,154.85 86.21,154.85 86.41,155.05 WLAN1.47
PEG_CLK1_CPU#: length 86.7
  L4 w0.152: v1(115.38,99.93) 115.38,99.27 114.92,98.8 111.8,98.8 106.14,104.46 94.39,104.46 90.02,108.83 90.02,121.85 90.8,122.63 90.8,151.26 87.54,154.52 84.96,154.52 v1(84.87,154.43)
  BOTTOM w0.089: 115.38,99.42 115.38,99.33 115.37,99.32 115.37,98.9 115.82,98.46 115.82,97.44 CPU1.B42
  BOTTOM w0.127: v1(115.38,99.93) 115.38,99.42
  BOTTOM w0.178: WLAN1.49 84.98,154.55 v1(84.87,154.43) ; v2(115.42,100.48) v1(115.38,99.93)
PEG_CLK2_CPU: length 130.5
  TOP w0.178: v1(50.92,171.1) 51.11,171.29 51.11,171.65 50.91,171.86 49.92,171.86 49.55,172.23 LOM31.15
  L4 w0.152: v1(115.81,99.16) 116.17,98.8 116.17,98.51 115.39,97.73 112.37,97.73 106.8,103.3 96.25,103.3 95.68,103.88 94.18,103.88 89.46,108.6 89.46,122.3 90.2,123.04 90.2,150.71 87.35,153.56 84.8,153.56 74.54,163.81 74.54,165.38 71.57,168.36 54.43,168.36 52.61,170.17 52.61,170.93 51.98,171.57 51.39,171.57 v1(50.92,171.1)
  BOTTOM w0.089: CPU1.C41 116.01,96.75 116.01,98.95 v1(115.81,99.16)
  BOTTOM w0.127: v2(50.93,171.75) 50.93,171.11 v1(50.92,171.1)
PEG_CLK2_CPU#: length 130.4
  TOP w0.178: v1(51.68,171.1) 51.42,171.37 51.42,171.78 51.03,172.16 50.17,172.16 49.95,172.39 LOM31.16
  L4 w0.152: v1(116.47,99.16) 116.47,98.4 115.51,97.44 112.25,97.44 106.67,103.01 96.13,103.01 95.56,103.58 94.06,103.58 89.17,108.47 89.17,122.42 89.91,123.16 89.91,150.59 87.23,153.27 84.68,153.27 74.25,163.69 74.25,163.93 74.25,165.26 71.45,168.06 54.3,168.06 52.32,170.05 52.32,170.81 52.03,171.1 v1(51.68,171.1)
  BOTTOM w0.089: v1(116.47,99.16) 116.2,98.89 116.2,96.53 115.9,96.23 CPU1.D41
  BOTTOM w0.127: v1(51.68,171.1) 51.9,171.1 v2(52.18,171.38)
PEG_CLK_CPU: length 75.4
  L4 w0.152: v1(155.04,125.64) 155.28,125.88 155.28,126.5 154.79,126.99 150.77,126.99 147.83,124.05 147.83,121.5 147.01,120.67 147.01,116.23 145.9,115.12 v1(145.81,115.12)
  BOTTOM w0.089: 114.29,100.02 114.29,100 114.26,99.97 114.26,99.42 115.29,98.38 115.29,98.02 115.08,97.81 115.08,97.51 115.12,97.42 115.12,97.15 115.08,97.06 115.08,96.86 115.13,96.73 115.13,96.52 CPU1.C42
  BOTTOM w0.127: GPU1.AK30 161.01,127.69 157.14,127.69 156.5,127.05 155.95,127.05 155.24,126.34 155.24,125.84 155.04,125.64 155.04,125.64 v1(155.04,125.64) ; 114.29,102.05 114.29,100.02
  BOTTOM w0.178: 116.92,104.69 114.29,102.05 ; 116.92,104.69 117.13,104.89 117.13,107.47 117.69,108.03 122.56,108.03 124.74,105.85 127.32,105.85 130.84,109.36 140.15,109.36 144.24,113.45 144.24,115.06 144.64,115.45 145.16,115.45 145.49,115.12 v1(145.81,115.12) ; 116.92,104.69 v2(117.09,104.53)
PEG_CLK_CPU#: length 75.4
  L4 w0.152: v1(145.81,115.76) 146.12,115.76 146.71,116.35 146.71,120.79 147.54,121.62 147.54,124.18 150.65,127.29 154.91,127.29 155.57,126.62 155.57,125.72 v1(155.67,125.62)
  BOTTOM w0.089: 114.05,100.02 114.05,100 114.08,99.97 114.08,99.34 115.11,98.31 115.11,98.09 114.9,97.89 114.9,97.48 114.94,97.39 114.94,97.19 114.9,97.1 114.9,96.83 114.95,96.69 114.95,96.42 CPU1.D42
  BOTTOM w0.127: GPU1.AK32 160.45,127.45 157.24,127.45 156.6,126.81 156.05,126.81 155.48,126.24 155.48,125.82 v1(155.67,125.62) ; 114.07,102.27 114.05,102.24 114.05,100.02
  BOTTOM w0.178: v1(145.81,115.76) 144.51,115.76 143.94,115.18 143.94,113.58 140.03,109.67 130.71,109.67 127.19,106.15 124.87,106.15 122.69,108.33 117.56,108.33 116.82,107.6 116.82,105.02 114.97,103.16 ; 114.97,103.16 114.07,102.27 ; 114.97,103.16 v2(114.77,103.32)
PEG_RX_CPU_N0: length 59.3
  TOP w0.178: 147.38,114.24 147.38,116.24 143.65,119.98 143.65,131.79 143.85,131.99 144.18,131.99 144.31,131.86 144.31,131.51 144.41,131.41 C7602.2 ; 147.38,114.24 v2(147.61,114.24) ; 147.38,114.24 147.38,107.58 146.89,107.09 143.48,107.09 142.03,105.64 136.87,105.64 136.32,105.09 136.32,101.11 137.41,100.03 137.41,96.07 138.34,95.14 138.34,94.88 138.34,92.99 137.21,91.86 135.37,91.86 134.76,92.48 133.64,92.48 133.5,92.62 v1(133.04,92.62)
  BOTTOM w0.178: CPU1.H13 v1(133.04,92.62)
PEG_RX_CPU_N1: length 52.2
  TOP w0.178: v2(143.54,133.27) 143.39,133.41 ; 143.39,133.41 142.75,132.77 142.75,119.4 145.18,116.96 145.18,109.67 141.96,106.45 136.67,106.45 135.46,105.24 135.46,101.04 136.74,99.77 136.74,96.88 135.05,95.19 135.05,94.31 134.65,93.92 v1(133.95,93.92) ; 143.39,133.41 143.61,133.63 C7604.2
  BOTTOM w0.178: CPU1.G11 v1(133.95,93.92)
PEG_RX_CPU_N2: length 55.9
  TOP w0.178: 141.84,134.1 141.84,118.76 144.18,116.42 144.18,109.94 141.5,107.26 136.46,107.26 134.54,105.34 134.54,101.12 136.03,99.63 136.03,97.8 134.18,95.95 133.92,95.95 133.17,95.95 132.8,95.58 132.8,95.1 132.82,95.08 132.82,93.64 132.37,93.19 131.26,93.19 v1(131.17,93.28) ; 141.84,134.1 v2(142.06,134.1) ; 141.84,134.1 141.84,135.02 142.17,135.35 142.68,135.35 C7606.2
  BOTTOM w0.178: CPU1.H16 130.83,92.94 v1(131.17,93.28)
PEG_RX_CPU_N3: length 57.5
  TOP w0.178: v2(140.61,136.19) 140.79,136.01 ; 140.79,136.01 140.64,135.86 140.64,118.28 142.93,115.98 142.93,110.68 140.75,108.5 136.3,108.5 133.35,105.55 133.35,101.01 134.48,99.88 134.48,97.85 133.63,97 132.55,97 131.64,96.09 131.64,95.97 131.64,94.14 131.86,93.93 v1(132.07,93.93) ; 140.79,136.01 141.96,137.18 C7608.2
  BOTTOM w0.178: CPU1.G15 v1(132.07,93.93)
PEG_RX_CPU_P0: length 59
  TOP w0.178: C7601.2 143.72,132.3 143.34,131.92 143.34,119.85 147.07,116.12 147.07,115.78 ; v2(146.83,115.77) 147.07,115.78 ; 147.07,115.78 147.07,107.71 146.76,107.4 143.35,107.4 141.9,105.95 136.74,105.95 136.01,105.22 136.01,100.99 137.1,99.9 137.1,95.94 138.04,95.01 138.04,93.12 137.09,92.17 135.5,92.17 134.89,92.78 133.77,92.78 133.28,93.27 v1(133.08,93.27)
  BOTTOM w0.178: CPU1.G13 v1(133.08,93.27)
PEG_RX_CPU_P1: length 52.7
  TOP w0.178: C7603.2 144.19,133.93 143.48,133.93 142.44,132.89 142.44,119.27 143.69,118.02 ; v2(143.58,117.91) 143.69,118.02 ; 143.69,118.02 144.87,116.84 144.87,109.8 141.83,106.76 136.54,106.76 135.15,105.37 135.15,100.92 136.43,99.64 136.43,97.01 134.75,95.32 134.75,94.44 134.53,94.22 134.3,94.22 v1(133.95,94.57)
  BOTTOM w0.178: CPU1.F11 133.5,94.36 133.7,94.57 v1(133.95,94.57)
PEG_RX_CPU_P2: length 55.9
  TOP w0.178: v1(131.21,93.92) 131.63,93.5 132.25,93.5 132.51,93.76 132.51,94.95 132.5,94.97 132.5,95.71 133.04,96.26 134.05,96.26 135.73,97.93 135.73,99.51 134.24,101 134.24,105.47 136.33,107.57 141.38,107.57 143.87,110.07 143.87,112.4 ; 143.87,112.4 143.87,116.3 141.54,118.63 141.54,135.15 142.04,135.65 142.74,135.65 C7605.2 ; 143.87,112.4 v2(143.71,112.41)
  BOTTOM w0.178: CPU1.G16 v1(131.21,93.92)
PEG_RX_CPU_P3: length 56.3
  TOP w0.178: 142.37,136.88 144.19,136.88 C7607.2 ; 142.37,136.88 142.09,136.88 140.94,135.73 140.94,118.4 143.23,116.11 143.23,110.55 140.88,108.19 136.43,108.19 133.66,105.42 133.66,101.14 134.79,100.01 134.79,97.73 133.75,96.69 132.67,96.69 131.95,95.97 131.95,94.71 v1(132.08,94.58) ; 142.37,136.88 v2(142.37,136.65)
  BOTTOM w0.178: CPU1.F15 v1(132.08,94.58)
PEG_RX_GPU_N0: length 26.6
  TOP w0.178: v1(158.64,128.44) 158.85,128.65 158.85,128.93 159.17,129.25 160.1,129.25 160.39,129.54 160.39,133.3 159.6,134.09 156.43,134.09 155.11,135.41 151.45,135.41 148.04,131.99 146.54,131.99 ; C7602.1 146.28,131.99 146.54,131.99 ; 146.54,131.99 v2(146.55,131.76)
  BOTTOM w0.178: GPU1.AG31 160.76,128.9 160.41,129.26 159.09,129.26 158.75,128.92 158.75,128.56 v1(158.64,128.44)
PEG_RX_GPU_N1: length 26.2
  TOP w0.178: C7604.1 146.48,133.63 146.63,133.47 146.76,133.47 ; v2(146.77,133.25) 146.76,133.47 ; 146.76,133.47 148.26,133.47 151.2,136.41 155.37,136.41 156.94,134.84 159.97,134.84 161.1,133.71 161.1,128.83 161.49,128.43 v1(162.69,128.43)
  BOTTOM w0.102: v1(162.69,128.43) 162.67,128.46 162.67,129.04 162.68,129.05 162.68,129.31 162.52,129.47 GPU1.AF28
PEG_RX_GPU_N2: length 26.6
  TOP w0.178: v2(149.06,136.78) 148.89,136.95 ; 148.89,136.95 149.23,137.3 155.58,137.3 157.29,135.59 160.17,135.59 161.85,133.91 161.85,130.49 162.81,129.53 163.17,129.53 v1(163.4,129.3) ; 148.89,136.95 147.29,135.36 144.25,135.36 C7606.1
  BOTTOM w0.178: GPU1.AF26 163.4,129.3 v1(163.4,129.3)
PEG_RX_GPU_N3: length 23.3
  TOP w0.178: v1(163.4,131.69) 163.14,131.69 162.87,131.96 162.87,134.45 160.66,136.66 157.74,136.66 155.88,138.53 149.21,138.53 ; 149.21,138.53 147.03,138.53 C7608.1 ; 149.21,138.53 v2(149.19,138.73)
  BOTTOM w0.178: v1(163.4,131.69) GPU1.AD26
PEG_RX_GPU_P0: length 27
  TOP w0.178: C7601.1 147.91,132.3 148.11,132.5 ; 148.11,132.5 151.33,135.71 155.24,135.71 156.56,134.39 159.72,134.39 160.69,133.42 160.69,129.41 160.23,128.95 159.3,128.95 159.15,128.8 159.15,128.56 v1(159.27,128.44) ; 148.11,132.5 v2(147.96,132.66)
  BOTTOM w0.178: GPU1.AH30 161.33,128.26 160.76,128.49 160.74,128.49 160.28,128.95 159.22,128.95 159.08,128.81 159.08,128.63 v1(159.27,128.44)
PEG_RX_GPU_P1: length 25.6
  TOP w0.178: v2(148.78,134.77) 148.97,134.61 ; 148.97,134.61 151.07,136.71 155.5,136.71 157.07,135.14 160.09,135.14 161.4,133.84 161.4,128.96 161.62,128.74 162.07,128.74 162.28,128.94 v1(162.28,129.15) ; 148.97,134.61 148.14,133.78 146.76,133.78 146.61,133.93 146.6,133.93 146.54,133.99 146.54,134.31 146.34,134.52 C7603.1
  BOTTOM w0.178: GPU1.AG29 162.1,128.9 162.28,129.08 v1(162.28,129.15)
PEG_RX_GPU_P2: length 26.5
  TOP w0.178: 146.85,135.66 147.16,135.66 149.1,137.6 155.71,137.6 157.42,135.89 160.3,135.89 162.15,134.03 162.15,130.61 162.93,129.83 163.16,129.83 v1(163.38,130.07) ; 146.85,135.66 v2(146.85,135.9) ; 146.85,135.66 144.17,135.66 C7605.1
  BOTTOM w0.178: GPU1.AF27 v1(163.38,130.07)
PEG_RX_GPU_P3: length 24.4
  TOP w0.178: C7607.1 146.23,136.3 146.44,136.5 146.44,137.5 147.16,138.22 147.73,138.22 ; 147.73,138.22 155.75,138.22 157.62,136.36 160.53,136.36 162.57,134.32 162.57,131.83 163,131.4 v1(163.4,130.9) ; 147.73,138.22 v2(147.74,137.97)
  BOTTOM w0.178: v1(163.4,130.9) GPU1.AD27
PEG_TX_CPU_N0: length 6.7
  BOTTOM w0.089: CPU1.B17 130.47,97.22 130.47,97.82 130.92,98.27 130.92,98.56 131,98.64
  BOTTOM w0.178: 131,98.64 131,99.75 132.73,101.47 132.73,101.83 C1606.2
PEG_TX_CPU_N1: length 9.3
  BOTTOM w0.089: 131.63,99.03 131.63,99.01 131.56,98.94 131.56,98.93 131.52,98.88 131.52,98.25 130.96,97.7 130.96,96.95 131.07,96.84 131.07,96.58 CPU1.D16
  BOTTOM w0.178: 134.13,101.94 131.63,99.44 131.63,99.03 ; 134.13,101.94 134.71,102.51 134.71,102.98 C1608.2 ; 134.13,101.94 v2(134.31,101.76)
PEG_TX_CPU_N2: length 9.6
  BOTTOM w0.089: CPU1.D17 129.82,96.05 129.82,96.69 129.77,96.83 129.77,97.1 129.81,97.19 129.81,97.39 129.77,97.48 129.77,98.17 130.24,98.64 130.24,99.19 130.12,99.3
  BOTTOM w0.178: 131.13,101.32 130.12,100.31 130.12,99.3 ; 131.13,101.32 v2(130.96,101.5) ; 131.13,101.32 131.39,101.58 131.39,103.65 C1610.2
PEG_TX_CPU_N3: length 7.4
  BOTTOM w0.089: 128.56,99.85 128.6,99.81 128.6,97.22 CPU1.B19
  BOTTOM w0.178: 128.56,99.85 128.56,102.97 128.83,103.25 128.83,103.67 C1612.2
PEG_TX_CPU_P0: length 5.7
  BOTTOM w0.089: 130.69,98.64 130.73,98.6 130.73,98.35 130.21,97.83 CPU1.A17
  BOTTOM w0.178: C1605.2 132.42,101.6 130.69,99.87 130.69,98.64
PEG_TX_CPU_P1: length 8.3
  BOTTOM w0.089: 131.33,99.03 131.33,98.33 130.77,97.78 CPU1.C16
  BOTTOM w0.178: 131.33,99.03 131.33,99.57 134.4,102.64 134.4,102.98 134.12,103.26 C1607.2
PEG_TX_CPU_P2: length 8.6
  BOTTOM w0.089: CPU1.C17 130,96.52 130,96.73 129.95,96.86 129.95,97.06 129.98,97.15 129.98,97.42 129.97,97.45 129.95,97.5 129.95,97.51 129.95,98.1 130.41,98.56 130.41,99.29 130.43,99.31
  BOTTOM w0.178: C1609.2 131.7,103.65 131.7,101.45 130.43,100.18 130.43,99.31
PEG_TX_CPU_P3: length 6.9
  BOTTOM w0.089: CPU1.A19 128.79,97.68 128.79,99.75 128.86,99.82
  BOTTOM w0.178: v2(129.09,101.82) 128.86,101.82 ; 128.86,101.82 128.86,102.84 129.14,103.12 129.14,103.67 C1611.2 ; 128.86,101.82 128.86,99.82
PEG_TX_GPU_N0: length 57.7
  L4 w0.152: v1(158.64,129.71) 158.55,129.79 157.92,129.79 157.57,129.45 157.57,127.73 157.77,127.52 158.94,127.52 159.32,127.15 159.32,125.78 158.4,124.87 157.18,124.87 156.25,123.93 154.25,123.93 153.99,124.2 151.12,124.2 149.65,122.72 149.65,120.89 148.71,119.96 148.71,114.28 148.33,113.9 148.33,112.56 147.92,112.15 147.2,112.15 147,111.95 147,110.93 147.31,110.62 149.14,110.62 149.51,110.24 149.51,109.55 149.14,109.17 147.09,109.17 146.66,109.6 146.08,109.6 v1(145.83,109.36)
  BOTTOM w0.127: v1(158.64,129.71) 159.06,130.13 159.37,130.13 159.62,130.38 160.88,130.38 GPU1.AE31
  BOTTOM w0.178: C1606.1 133.01,103.63 133.01,104.9 135.05,106.93 141.5,106.93 143.26,108.69 ; 143.26,108.69 144.08,109.52 145.67,109.52 v1(145.83,109.36) ; 143.26,108.69 v2(143.36,108.59)
PEG_TX_GPU_N1: length 56.4
  L4 w0.152: v1(159.3,131.3) 159.3,130.92 159.51,130.71 160.94,130.71 161.35,130.3 161.35,127.87 160.97,127.5 160.41,127.5 160.21,127.29 160.21,125.47 157.27,122.53 155.19,122.53 155.07,122.53 154.57,122.53 153.91,121.86 153.91,120.22 153.36,119.68 149.77,119.68 149.56,119.47 149.56,113.85 149.18,113.47 149.18,111.8 150.55,110.42 150.55,108.69 150.18,108.32 146.15,108.32 v1(145.86,108.03)
  BOTTOM w0.102: v1(159.3,131.3) 159.12,131.12 159.12,130.94 159.23,130.84 160.4,130.84 160.6,130.94 160.89,131.05 161.16,131.05 161.33,130.95 161.37,130.92 161.53,130.92 161.73,130.99 GPU1.AD28
  BOTTOM w0.178: 135.4,105.99 135.62,106.22 141.77,106.22 142.75,107.2 143.02,107.2 143.85,108.03 v1(145.86,108.03) ; 135.4,105.99 134.71,105.3 134.71,104.46 C1608.1 ; 135.4,105.99 v2(135.56,105.83)
PEG_TX_GPU_N2: length 57.3
  L4 w0.152: v1(145.83,111.9) 145.82,111.9 145.82,111.89 145.68,111.74 145.41,111.74 145.31,111.83 145.31,116.71 146.16,117.56 146.16,121.03 146.59,121.47 146.59,121.47 146.98,121.86 146.98,124.78 147.94,125.73 147.94,132.45 150,134.51 155.11,134.51 156.89,132.73 157.42,132.73 157.79,133.11 157.79,133.22 v1(157.97,133.39)
  BOTTOM w0.127: v1(157.97,133.39) 157.78,133.2 157.78,132.38 158.18,131.98 160.88,131.98 GPU1.AC31
  BOTTOM w0.178: v2(131.39,106.47) 131.56,106.31 ; 131.56,106.31 133.15,107.89 140.77,107.89 144.6,111.73 145.67,111.73 145.82,111.89 145.82,111.9 v1(145.83,111.9) ; 131.56,106.31 131.39,106.14 131.39,105.15 C1610.1
PEG_TX_GPU_N3: length 62.7
  L4 w0.152: v1(159.33,133.39) 159.11,133.61 159.11,134.93 159.25,135.07 160.07,135.07 160.27,134.86 160.27,132.72 159.75,132.2 157.16,132.2 156.5,131.54 156.5,125.74 155.84,125.08 154.73,125.08 154.46,125.35 153.38,125.35 152.32,126.41 150.99,126.41 148.45,123.86 148.45,121.32 147.57,120.44 147.57,114.98 146.27,113.69 145.97,113.69 v1(145.81,113.85)
  BOTTOM w0.102: GPU1.AB28 161.73,132.59 161.53,132.52 161.37,132.52 161.33,132.55 161.16,132.65 160.89,132.65 160.6,132.54 160.4,132.44 159.42,132.44 159.13,132.72 159.13,133.2 v1(159.33,133.39)
  BOTTOM w0.178: v1(145.81,113.85) 145.64,113.69 145.3,113.69 140.4,108.78 131.24,108.78 128.86,106.4 128.86,106.19 ; v2(128.62,106.19) 128.86,106.19 ; 128.86,106.19 128.86,105.2 C1612.1
PEG_TX_GPU_P0: length 58.9
  L4 w0.152: v1(145.83,109.99) 145.93,109.9 146.78,109.9 147.21,109.46 149.02,109.46 149.22,109.67 149.22,110.12 149.02,110.32 147.19,110.32 146.71,110.81 146.71,112.07 147.08,112.44 147.8,112.44 148.03,112.68 148.03,114.02 148.42,114.4 148.42,120.08 149.35,121.02 149.35,122.84 151,124.49 154.12,124.49 154.38,124.23 156.13,124.23 157.06,125.16 158.28,125.16 159.02,125.9 159.02,127.03 158.82,127.23 157.65,127.23 157.28,127.6 157.28,129.57 157.85,130.14 158.84,130.14 v1(159.27,129.71)
  BOTTOM w0.127: v1(159.27,129.71) 159.72,130.15 160.95,130.15 GPU1.AF30
  BOTTOM w0.178: C1605.1 132.71,103.62 132.71,105.03 132.94,105.26 ; 132.94,105.26 134.92,107.24 141.37,107.24 143.96,109.83 145.67,109.83 v1(145.83,109.99) ; 132.94,105.26 v2(132.75,105.44)
PEG_TX_GPU_P1: length 57.2
  L4 w0.152: v1(158.67,131.3) 158.39,131.02 158.39,130.65 158.62,130.42 160.82,130.42 161.06,130.18 161.06,127.99 160.85,127.79 160.29,127.79 159.91,127.42 159.91,125.59 157.14,122.82 155.07,122.82 154.45,122.82 153.61,121.99 153.61,120.34 153.24,119.97 149.65,119.97 149.27,119.59 149.27,113.97 148.88,113.59 148.88,111.67 150.26,110.3 150.26,108.82 150.06,108.61 145.93,108.61 v1(145.84,108.7)
  BOTTOM w0.102: v1(158.67,131.3) 158.92,131.05 158.92,130.86 159.14,130.64 160.45,130.64 160.68,130.75 160.93,130.85 161.09,130.85 161.23,130.77 161.32,130.72 GPU1.AE29
  BOTTOM w0.178: 134.4,105.08 134.4,105.42 135.5,106.52 141.64,106.52 142.62,107.5 142.89,107.5 143.72,108.33 145.47,108.33 v1(145.84,108.7) ; 134.4,105.08 v2(134.16,105.07) ; 134.4,105.08 134.4,104.48 C1607.1
PEG_TX_GPU_P2: length 58.1
  L4 w0.152: v1(145.82,111.26) 145.82,111.27 145.78,111.31 145.78,111.32 145.66,111.44 145.29,111.44 145.02,111.71 145.02,116.83 145.86,117.68 145.86,121.15 146.3,121.59 146.3,121.59 146.69,121.98 146.69,124.9 147.64,125.85 147.64,132.57 149.87,134.8 155.24,134.8 157.01,133.02 157.3,133.02 157.4,133.13 157.4,133.32 v1(157.33,133.39)
  BOTTOM w0.127: v1(157.33,133.39) 157.55,133.17 157.55,132.29 158.09,131.75 160.95,131.75 GPU1.AD30
  BOTTOM w0.178: 132.96,107.27 133.27,107.59 140.89,107.59 144.73,111.43 145.67,111.43 145.82,111.27 v1(145.82,111.26) ; 132.96,107.27 131.7,106.01 131.7,105.15 C1609.1 ; 132.96,107.27 v2(133.13,107.1)
PEG_TX_GPU_P3: length 63.5
  L4 w0.152: v1(145.81,113.22) 145.99,113.39 146.39,113.39 147.86,114.86 147.86,120.32 148.74,121.2 148.74,123.74 151.12,126.12 152.2,126.12 153.26,125.06 154.34,125.06 154.61,124.79 155.96,124.79 156.79,125.62 156.79,131.42 157.28,131.9 159.87,131.9 160.57,132.6 160.57,134.98 160.19,135.36 159.13,135.36 158.82,135.05 158.82,133.52 v1(158.69,133.39)
  BOTTOM w0.102: v1(158.69,133.39) 158.93,133.15 158.93,132.64 159.33,132.24 160.45,132.24 160.68,132.35 160.93,132.45 161.09,132.45 161.23,132.37 161.32,132.32 GPU1.AC29
  BOTTOM w0.178: v2(132.58,108.23) 132.57,108.48 ; 132.57,108.48 140.52,108.48 145.43,113.38 145.64,113.38 v1(145.81,113.22) ; 132.57,108.48 131.37,108.48 129.17,106.27 129.17,105.14 C1611.1
PG_1: length 17.4
  TOP w0.254: v1(122.47,168.66) 122.76,168.37 122.76,167.56 122.45,167.25 122.45,166.45 122.17,166.17 PG4429.1
  BOTTOM w0.254: PR4467.1 127.45,179.34 125.83,179.34 124.99,178.5 124.99,175.26 ; 124.99,175.26 124.99,171.8 122.71,169.53 122.71,168.89 v1(122.47,168.66) ; 124.99,175.26 v2(124.83,175.27)
PG_2: length 16.9
  TOP w0.254: PG4407.1 123.08,166.17 122.83,166.42 122.83,167.1 123.14,167.41 123.14,168.37 v1(123.42,168.66)
  BOTTOM w0.254: v2(125.58,174.12) 125.37,174.12 ; 125.37,174.12 125.37,178.35 125.99,178.96 127.44,178.96 PR4468.1 ; 125.37,174.12 125.37,171.65 123.09,169.37 123.09,168.98 v1(123.42,168.66)
PIRQA#: length 38.6
  TOP w0.102: 146.92,68.5 146.91,68.49 146.91,67.55 147.08,67.37 147.08,66.09 146.74,65.75 146.74,65.69 146.1,65.06 146.1,65 145.92,64.82 R1607.2 ; 146.92,68.5 147.16,68.75 147.57,68.75 148.29,68.03 148.29,65.89 147.86,65.46 147.86,65.29 147.8,65.23 147.8,63.64 147.67,63.51 147.67,61.22 147.64,61.2 147.64,60.72 148.08,60.28 148.08,55.56 v2(148.05,55.53) 148.05,55.1 148.28,54.87 v1(148.81,54.87) ; 146.92,68.5 145.63,68.5 144.36,69.77 143.86,69.77 138.12,75.51 135.4,75.51 v1(134.16,74.27)
  BOTTOM w0.089: v1(134.16,74.27) 134.16,74.28 133.69,74.75
  BOTTOM w0.102: 133.69,74.75 CPU1.BB11 ; R9152.1 149.01,54.66 v1(148.81,54.87)
PLL_ANALOG_IN: length 20.5
  TOP w0.102: v1(194.27,127.31) 194.27,127.22 194.74,126.75 TP7902.1
  BOTTOM w0.102: GPU1.AA1 182.69,133.7 184.17,132.22 184.17,130.07 184.17,130.07 184.17,129.73 184.17,129.72 184.17,129.37 189.06,124.49 189.66,124.49 190.09,124.91 190.09,125.07 191.52,126.49 193.48,126.49 194.27,127.28 v1(194.27,127.31)
PLT_RST#: length 312.1
  TOP w0.102: v1(146.76,126.22) 146.76,126.46 147.15,126.85 D7601.1 ; R3110.1 58.5,173.81 57.4,172.72 v1(57.4,170.06) ; v1(153.14,53.11) 153.94,53.91 153.94,54.55 156.93,57.54 156.93,62.33 156.48,62.78 156.48,67.8 157.73,69.05 159.24,69.05 159.43,69.25 159.43,69.25 159.88,69.33 161.53,70.98 161.53,74.15 160.35,75.33 v1(159.22,75.33) ; R6116.1 97.46,151.54 97.73,151.82 97.79,151.82 97.92,151.95 97.92,151.96 v1(98.31,152.35)
  L3 w0.102: v1(146.76,126.22) 146.76,126.04 147.53,125.27 147.53,124.84 147.59,124.78 147.59,122.56 147.59,121.41 148.37,120.63 148.37,112.17 150.87,109.67 151.54,109.67 155.01,106.19 155.56,106.19 158.8,102.96 159.24,102.96 160.03,102.17 160.03,101.57 160.03,101.37 160.56,100.84 160.56,100.77 164.02,97.31 164.02,92.8 164.78,92.05 164.78,91.39 167.55,88.61 175.02,88.61 180.13,83.5 180.13,82.98 183.64,79.47 183.64,77.7 184.87,76.47 184.87,73.15 184.55,72.84 183.48,71.77 183.48,70.37 180.75,67.64 v1(180.06,67.64) ; v1(98.31,152.35) 98.36,152.29 104.88,152.29 v1(104.98,152.4) 105.29,152.7 116.44,152.7 v1(117.32,151.83)
  L4 w0.102: v1(57.4,170.06) 57.4,170.07 70.61,170.07 83.12,157.56 86.13,157.56 92.13,151.56 97.53,151.56 v1(98.31,152.35) ; v1(180.06,67.64) 179.36,68.35 178.37,68.35 175.06,71.65 167.77,71.65 166.61,72.82 166.61,72.93 166.35,73.18 166,73.18 165.9,73.09 162.96,73.09 160.71,75.33 v1(159.22,75.33) ; v1(171.02,53.57) 168.52,53.57 168.16,53.21 168.12,53.19 167.75,53.19 167.51,53.44 166.85,53.44 165.6,52.19 163.24,52.19 163.15,52.27 160.35,52.27 159.94,51.87 156.42,51.87 155.18,53.12 153.15,53.12 v1(153.14,53.11)
  BOTTOM w0.102: v1(153.14,53.11) 150.08,53.11 149.62,53.57 R9136.1 ; Q6301.D 172.82,52.57 171.68,53.7 R6324.2 171.4,53.75 171.23,53.57 v1(171.02,53.57) ; R1715.1 156.06,77.7 156.06,77.07 R1713.1 156.5,77.22 157.03,77.22 157.45,76.81 EC1703.1 157.45,75.75 C1701.1 157.45,74.74 157.84,74.36 157.84,74.35 158.35,73.83 158.71,73.83 158.97,74.08 158.97,74.66 158.91,74.71 158.91,75.02 v1(159.22,75.33) ; R5538.2 110.95,169.95 110.95,169.32 109.42,167.78 109.13,167.78 105.75,164.4 105.75,153.16 v1(104.98,152.4) ; v1(146.76,126.22) 146.02,126.97 146.02,134.23 141.33,138.92 133.96,138.92 131.37,141.51 131.37,147.32 127.7,150.99 v2(126.21,150.99) 118.16,150.99 v1(117.32,151.83)
PLT_RST#_LAN: length 9.2
  TOP w0.127: R3110.2 57.63,173.43 v2(56.78,172.57) 56.28,172.08 53.27,172.08 52.9,172.44 52.9,172.67 51.5,174.08 LOM31.19
PLT_RST#_Q_TPM2: length 6
  BOTTOM w0.102: U9103.17 152.65,56.97 152.44,56.77 152.44,54.92 v2(152.63,54.74) 152.63,54.09 152.24,53.7 150.78,53.7 150.59,53.89 R9136.2
PLT_RST_NGFF#: length 11.6
  TOP w0.102: R6116.2 95.53,151.43 95.09,150.99 93.21,150.99 92.58,151.63 92.58,153.78 93.07,154.28 AFTP6108.1 95.54,154.28 v1(95.87,153.95)
  BOTTOM w0.102: v1(95.87,153.95) 95.72,153.8 WLAN1.52
PM_LAN_ENABLE: length 419.8
  TOP w0.127: R3107.1 60.24,174.47 Q3102.G 60.49,173.26 58.02,170.79 v1(58.02,169.27)
  L3 w0.127: v1(147.09,27.46) 147.09,27.55 146.24,28.4 146.24,44.26 v1(147.18,45.21) ; v1(58.02,169.27) 58.88,168.4 64.98,168.4 65.43,168.86 72.18,168.86 76.42,164.62 76.42,163.39 82.09,157.72 83.59,157.72 84.28,157.02 84.28,154.03 84.59,153.72 84.59,152.65 v1(85.11,152.12)
  L4 w0.127: v1(36.6,88.12) 36.6,87.35 34.77,85.53 30.32,85.53 22.48,77.69 22.48,75.52 19.94,72.98 19.94,60.02 16.52,56.6 16.52,54.52 15.8,53.8 15.8,39.05 16.6,38.26 16.6,29.72 16.53,29.65 16.53,29.18 16.6,29.12 16.6,22.55 19.47,19.68 19.47,18.26 23.98,13.75 49.12,13.75 53.82,9.04 57.46,9.04 v1(57.87,8.64)
  BOTTOM w0.127: R2491.1 155.08,50.31 154.62,49.85 154.62,49.36 153.94,48.68 152.99,48.68 151.68,47.36 151.68,46.32 150.73,45.37 148.8,45.37 148.64,45.21 v1(147.18,45.21) ; v1(36.6,88.12) 38.3,89.34 42.27,89.29 46.13,92.71 56.88,92.94 58.35,93.35 63.91,93.36 64.16,93.41 64.83,93.36 65.27,93.36 66.18,93.76 67.11,95.06 69.59,96.12 71.47,97.99 73.97,97.99 74.07,98.04 77.54,101.71 78.7,102.68 78.87,102.87 83.87,108.83 83.96,108.95 84.04,109.04 84.06,109.08 85.18,110.57 85.23,110.63 86.57,113.41 86.67,114.22 86.95,115.04 88.12,119.96 88.47,120.31 88.49,120.37 89.42,121.29 89.42,122.45 89.5,122.59 89.81,123.44 89.94,124.33 89.9,125.13 89.91,125.16 89.79,125.62 89.79,137.58 88.62,138.76 88.62,141.12 87.6,142.14 87.6,144.81 85.53,146.87 85.53,149 84.98,149.55 84.98,152 v1(85.11,152.12) ; v1(147.09,27.46) 147.8,27.46 148.47,26.79 151.4,26.79 151.84,26.35 151.84,24.54 151.89,24.49 151.89,23.61 152.76,22.73 v2(152.76,20.6) 152.76,19.79 153.69,18.87 153.69,16.53 152.86,15.71 152.85,15.71 151.06,13.91 151.06,11.49 147.35,7.79 58.72,7.79 v1(57.87,8.64)
PM_LAN_ENABLE_C: length 3.4
  TOP w0.127: R3111.2 61.78,177.87 C3105.2 59.91,177.87 v2(59.8,177.75) Q3101.G
PM_PCH_PWROK: length 86.1
  TOP w0.127: v2(144.19,53.76) v1(144.28,53.21)
  L4 w0.127: v1(166.26,28.87) 163.65,28.87 163.53,28.99 159.86,28.99 159.82,29.03 148.03,29.03 146.64,27.65 146.64,27.28 146.69,27.23 146.69,26.62 145.7,25.63 144.93,25.63 144.23,26.33 144.23,40.23 143.46,40.99 143.13,40.99 142.82,41.31 142.82,42.33 143.11,42.63 143.11,44.85 144.28,46.03 v1(144.28,53.21)
  BOTTOM w0.127: v1(144.28,53.21) 144.08,53.21 143.89,53.4 RN1701.4 143.5,54.37 139.69,54.37 139.66,54.39 139.16,54.89 137.86,54.89 130.86,61.89 130.86,71.42 129.97,72.31 129.97,73.38 129.42,73.93 129.42,74.86 128.85,75.43 CPU1.BA20 ; R1706.2 166.77,28.36 v1(166.26,28.87)
PM_RSMRST#: length 62.6
  TOP w0.127: v1(143.8,52.8) 143.45,52.45 142.45,52.45 141.49,51.49 141.07,51.49 139.87,52.69 139.87,54.06 139.54,54.81 137.96,56.4 v2(137.96,57.61) 137.96,60.64 138.49,61.17 138.49,66.41 v1(138.59,66.51) ; v1(155.32,66.24) 155.32,66.22 155.35,66.19 155.35,65.9 155.15,65.7 154.4,65.7 154.09,65.38 Q1702.2
  L3 w0.127: v1(138.59,66.51) 139.73,66.51 140.89,67.66 140.94,67.66 141.17,67.9 143.12,67.9 146.34,64.68 146.34,64.58 146.6,64.32 147.5,64.32 147.51,64.33 149.09,64.33 150.07,65.31 152.08,65.31 152.28,65.51 154.73,65.51 155.32,66.1 v1(155.32,66.24)
  L4 w0.127: v1(129.87,74.05) 130.61,74.05 134.69,69.98 134.69,69.61 134.95,69.35 135.71,69.35 136.12,68.94 136.12,68.77 138.38,66.51 v1(138.59,66.51)
  BOTTOM w0.089: v1(129.87,74.05) 129.64,74.29 129.64,75.12 129.64,75.13 129.67,75.21 129.67,75.72 130.07,76.12 CPU1.AY17
  BOTTOM w0.127: 143.74,52.8 143.74,52.91 143.01,53.63 R1704.1 ; 143.74,52.8 143.8,52.74 144.44,52.74 144.73,53.03 144.73,53.4 144.56,53.56 RN1701.3 ; 143.74,52.8 v1(143.8,52.8) ; R1702.1 153.62,66.76 Q1701.3 154.86,65.88 155.22,66.24 v1(155.32,66.24)
PM_RSMRST#_M: length 4.1
  TOP w0.127: Q1702.5 154.09,67.35 v2(153.89,67.54) ; Q1702.6 153.44,67.24 153.75,67.54 v2(153.89,67.54) ; v2(153.89,67.54) 154.09,67.74 154.17,67.74 154.52,68.08 154.52,68.2 154.7,68.39 R1737.2
PME#: length 3.3
  TOP w0.102: TP1707.1 134.43,80.43 134.43,78.88 v1(133.99,78.44)
  BOTTOM w0.102: v1(133.99,78.44) 133.99,78.44 133.66,78.1 CPU1.AU11
POL1/SPI_CEB: length 3.8
  TOP w0.127: RN5602.3 27.1,81.13 26.66,80.69 v2(26.66,80.65) 26.66,80.28 26.02,79.65 26.02,79.62 25.81,79.4 25.37,79.4 25.24,79.28 U5601.10
POL2: length 4.8
  TOP w0.127: v2(29.04,81.13) RN5602.4 28.15,80.67 27.48,80 26.76,80 25.91,79.15 25.79,79.15 25.64,79 U5601.9
POWER_SW_IN#: length 6.2
  BOTTOM w0.102: KBC24.127 156.6,45.53 156.05,46.09 156.05,46.48 v2(155.8,46.73) 155.63,46.9 155.18,46.9 C2426.1 154.21,46.87 R2432.2 R2451.2
PQ3802_1: length 4.5
  BOTTOM w0.102: PR4309.2 58.48,170 v2(58.14,170.35) 58.12,170.35 PR4302.1 57.02,172.13 PQ4302.B
PQ3809_D: length 2.6
  TOP w0.254: PQ4306.3 78.98,165.37 79.47,165.86 v2(79.47,165.88) 79.47,166.91 PR4314.2
PQ4406_2: length 7.5
  TOP w0.127: PR4462.1 123.43,179.86 124.21,179.86 PR4408.1 125.05,180.7 126.8,180.7 127.21,180.29 127.21,179.55 127.34,179.43 PQ4406.2 v2(129.57,179.43)
PQ4406_3: length 4.1
  TOP w0.127: PQ4406.3 128.98,180.08 129.49,180.59 129.49,181.65 v2(129.52,181.69) 129.52,182.06 130.11,182.64 PR4458.1
PQ4406_5: length 5.2
  TOP w0.127: v2(127.87,175.64) 127.87,175.67 127.49,176.05 PR4413.1 127.05,176.53 126.7,176.88 PC4439.1 126.7,178.2 127.01,178.5 127.01,179.15 126.73,179.43 PQ4406.5
PQ4406_6: length 3.8
  TOP w0.127: PR4453.1 126.55,176.13 v2(126.14,176.53) 125.79,176.89 PC4439.2 125.79,178.18 126.33,178.73 PQ4406.6
PQ4409_C: length 3.1
  TOP w0.102: PR4455.1 PR4462.2 123.4,177.86 PQ4409.C
  TOP w0.127: PR4455.1 122.54,178.11 v2(122.51,178.11)
PQ4409_E: length 6.9
  TOP w0.127: 121.67,179.01 121.89,178.79 121.89,178.35 121.95,178.3 121.95,177.47 123.78,175.64 PQ4409.E ; 121.67,179.01 121.56,179.12 v2(120.78,179.12) 120.75,179.12 120.46,178.83 119.94,178.83 PR4414.1 ; 121.67,179.01 PR4431.2
PQ4416_1: length 5
  TOP w0.127: PQ4415.C 139.94,171.55 v2(139.94,169.97) 139.94,167.89 139.53,167.47 PQ4416.1
PQ8206_3: length 2.1
  TOP w0.254: PR8545.2 160.23,103.22 v2(160.23,103.35) 160.23,103.6 PQ8501.3
PR_2: length 4.8
  TOP w0.254: PC4405.1 137.23,180.75 138.01,181.54 138.77,181.54 v2(138.85,181.46) 138.91,181.4 PR4407.2
PRIM_PWRGD: length 55.3
  L3 w0.102: v1(170.08,45.35) 168.29,45.35 167.23,46.41 164.78,46.41 163.45,45.08 161.01,45.08 157.67,48.42 157.67,61.99 v1(159.19,63.51)
  BOTTOM w0.102: 159.19,63.5 159.35,63.67 159.35,64.55 159.1,64.8 158.96,64.8 158.29,65.48 158.29,65.73 157.99,66.03 157.25,66.03 155.31,67.97 v2(155.31,68.62) 155.31,70.48 155.91,71.08 157,71.08 157.86,71.94 158.41,71.94 159.03,72.57 159.03,73.25 163.71,77.93 163.71,77.93 R4030.1 ; 159.19,63.5 159.19,62.83 PR5408.1 ; 159.19,63.5 v1(159.19,63.51) ; KBC24.30 170.46,45.73 v1(170.08,45.35)
PROC_SELECT#: length 8
  BOTTOM w0.089: CPU1.C64 103.4,96.75 103.4,98.93 103.11,99.22
  BOTTOM w0.102: R603.1 99.13,102.2 v2(100.18,101.14) 100.46,100.87 101.46,100.87 103.11,99.22
PROCHOT: length 2.9
  BOTTOM w0.191: KBC24.83 v2(164.06,30.23) 164.06,29.67 164.19,29.54 164.19,29.32 R2420.1
PROJECT_ID1: length 13.3
  BOTTOM w0.089: 136.35,73.37 136.53,73.56 136.53,74.17 136.31,74.4 136.03,74.4 135.67,74.76 135.67,75.65 135.77,75.75 135.77,76.33 CPU1.AY8
  BOTTOM w0.102: R2016.1 140.21,67.16 R2015.2 139.9,67.23 139.44,67.7 v2(139.44,67.85) 139.44,68.51 138.12,69.83 138.12,71.21 137.77,71.57 137.44,71.57 136.35,72.66 136.35,73.37
PROJECT_ID2: length 17.8
  TOP w0.102: R2017.2 144.75,66.52 R2018.1 146.45,66.52 v2(146.46,66.53) 146.46,67.26 144.15,69.57 143.77,69.57 140.56,72.78 138.5,72.78 137.73,73.55 136.6,73.55 v1(136.15,74.01)
  BOTTOM w0.089: v1(136.15,74.01) 136.15,74.03 135.49,74.69 CPU1.BA8
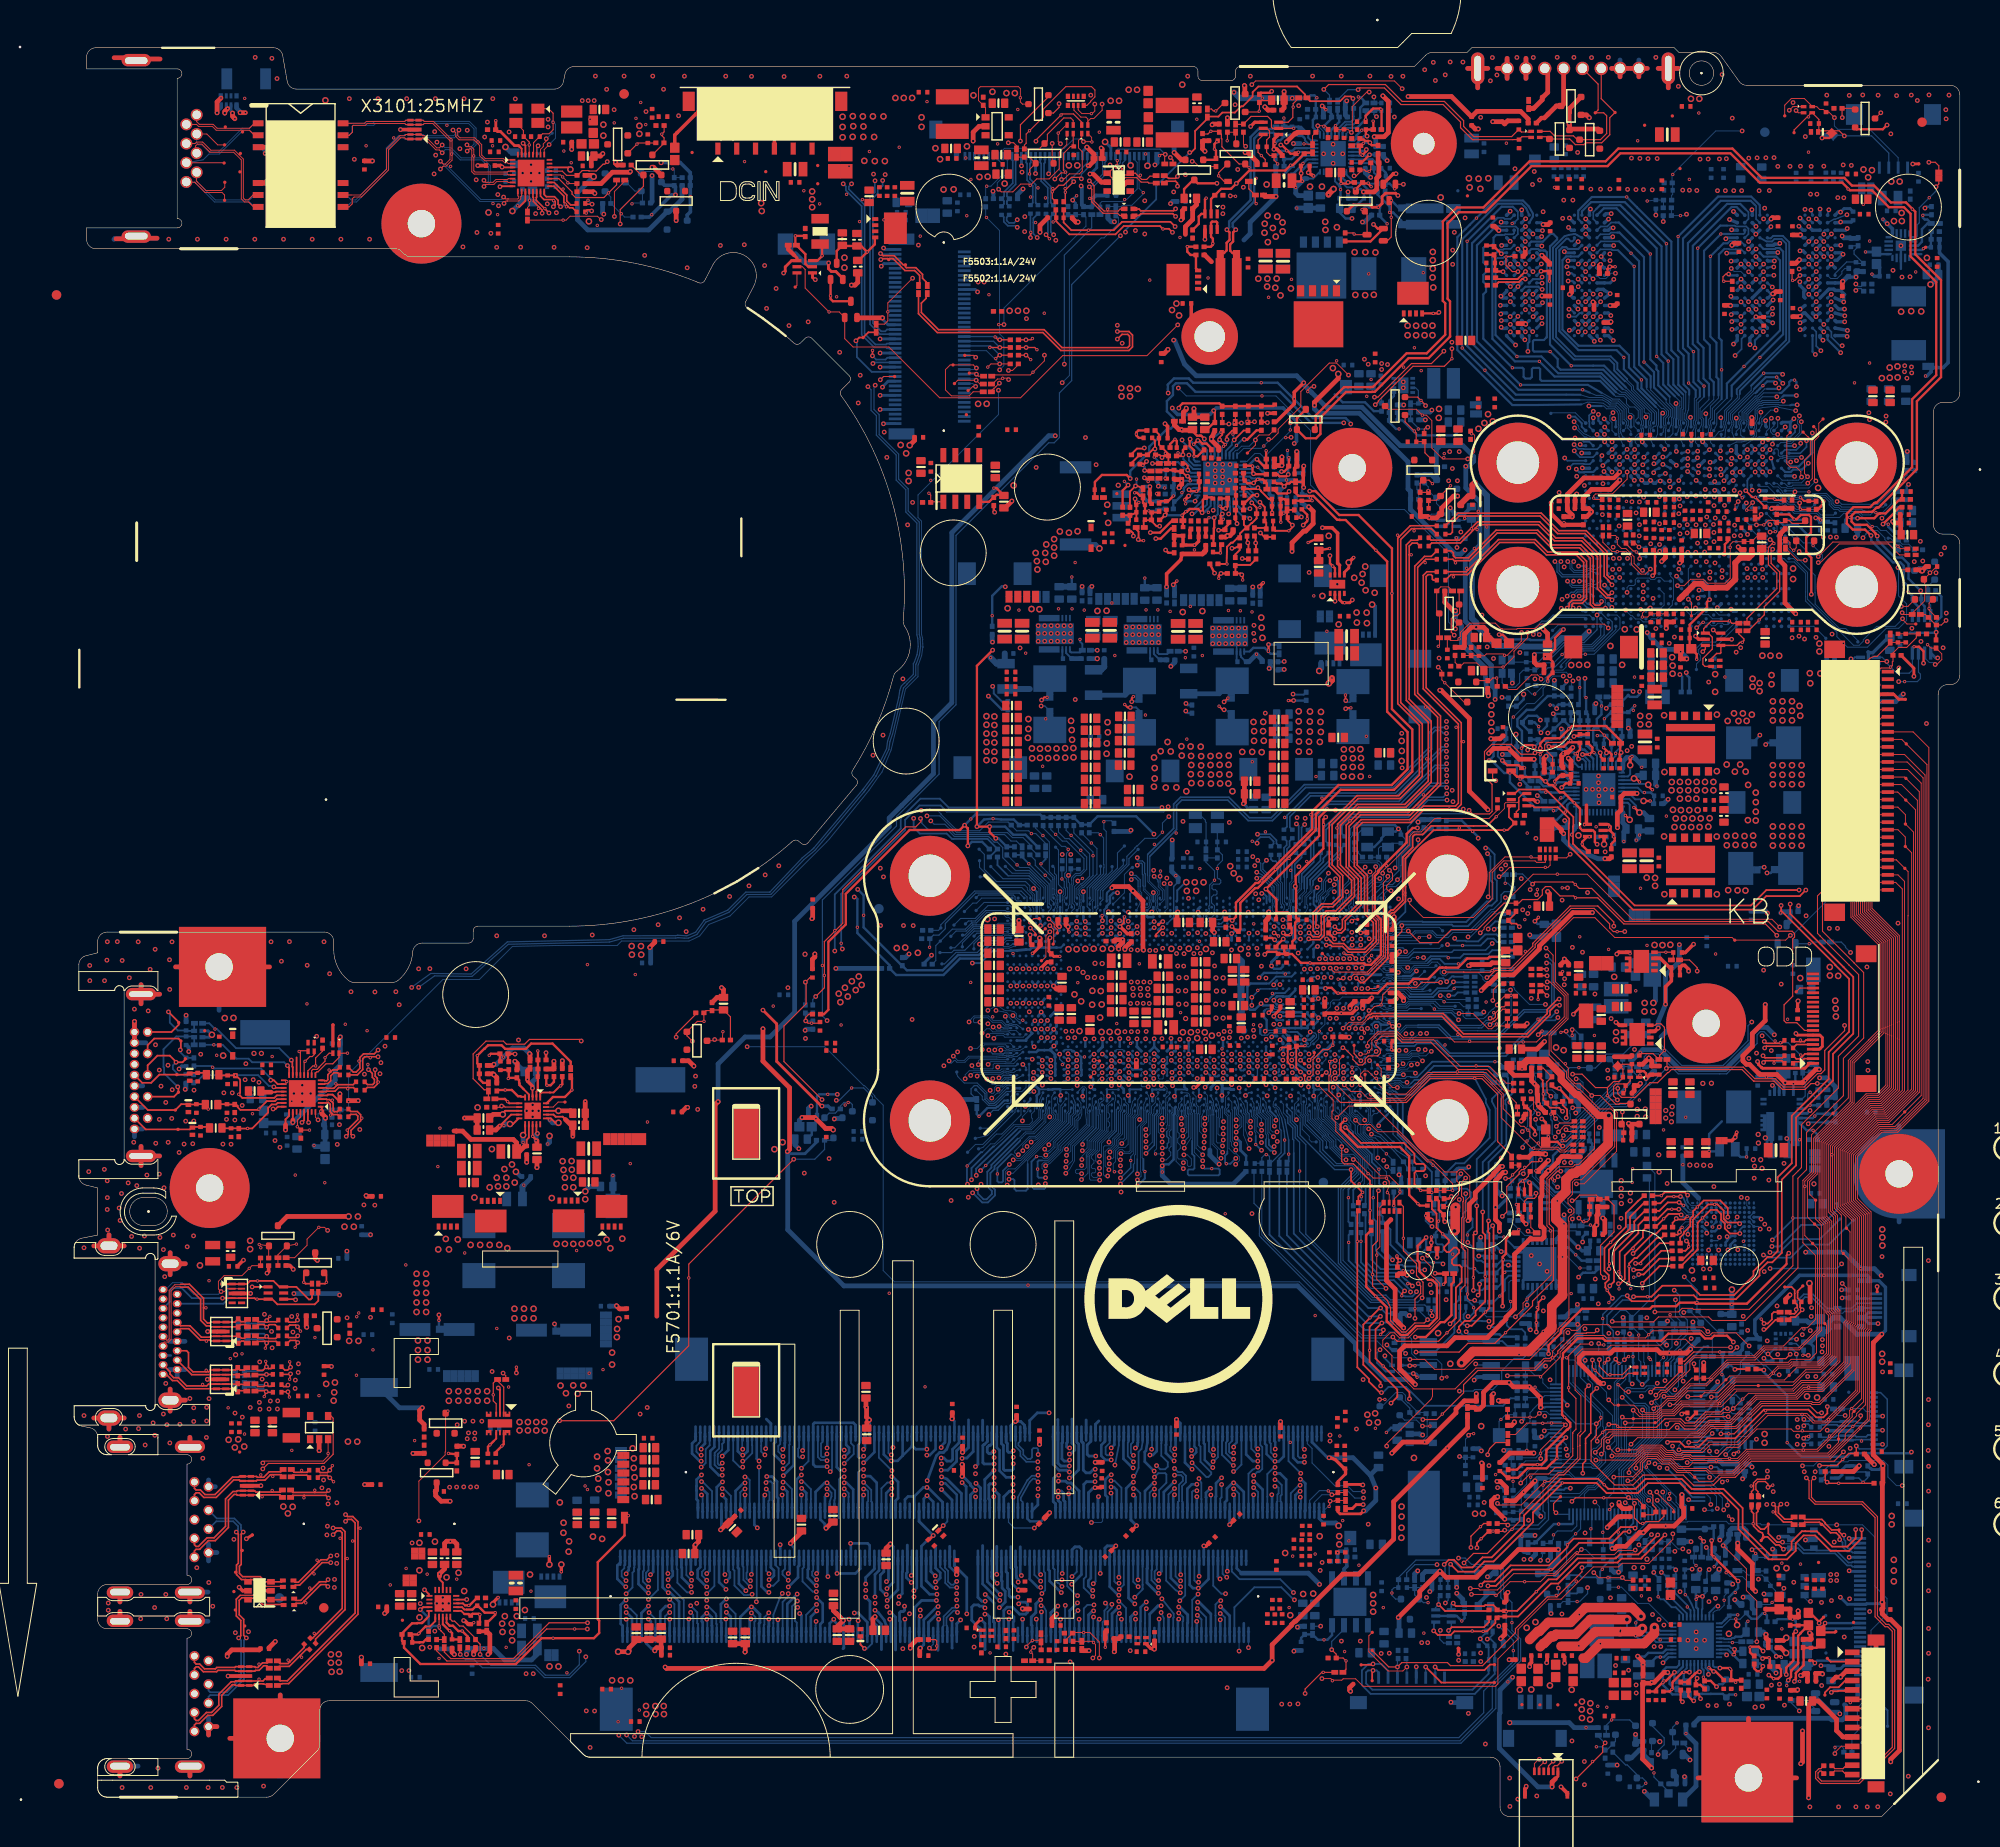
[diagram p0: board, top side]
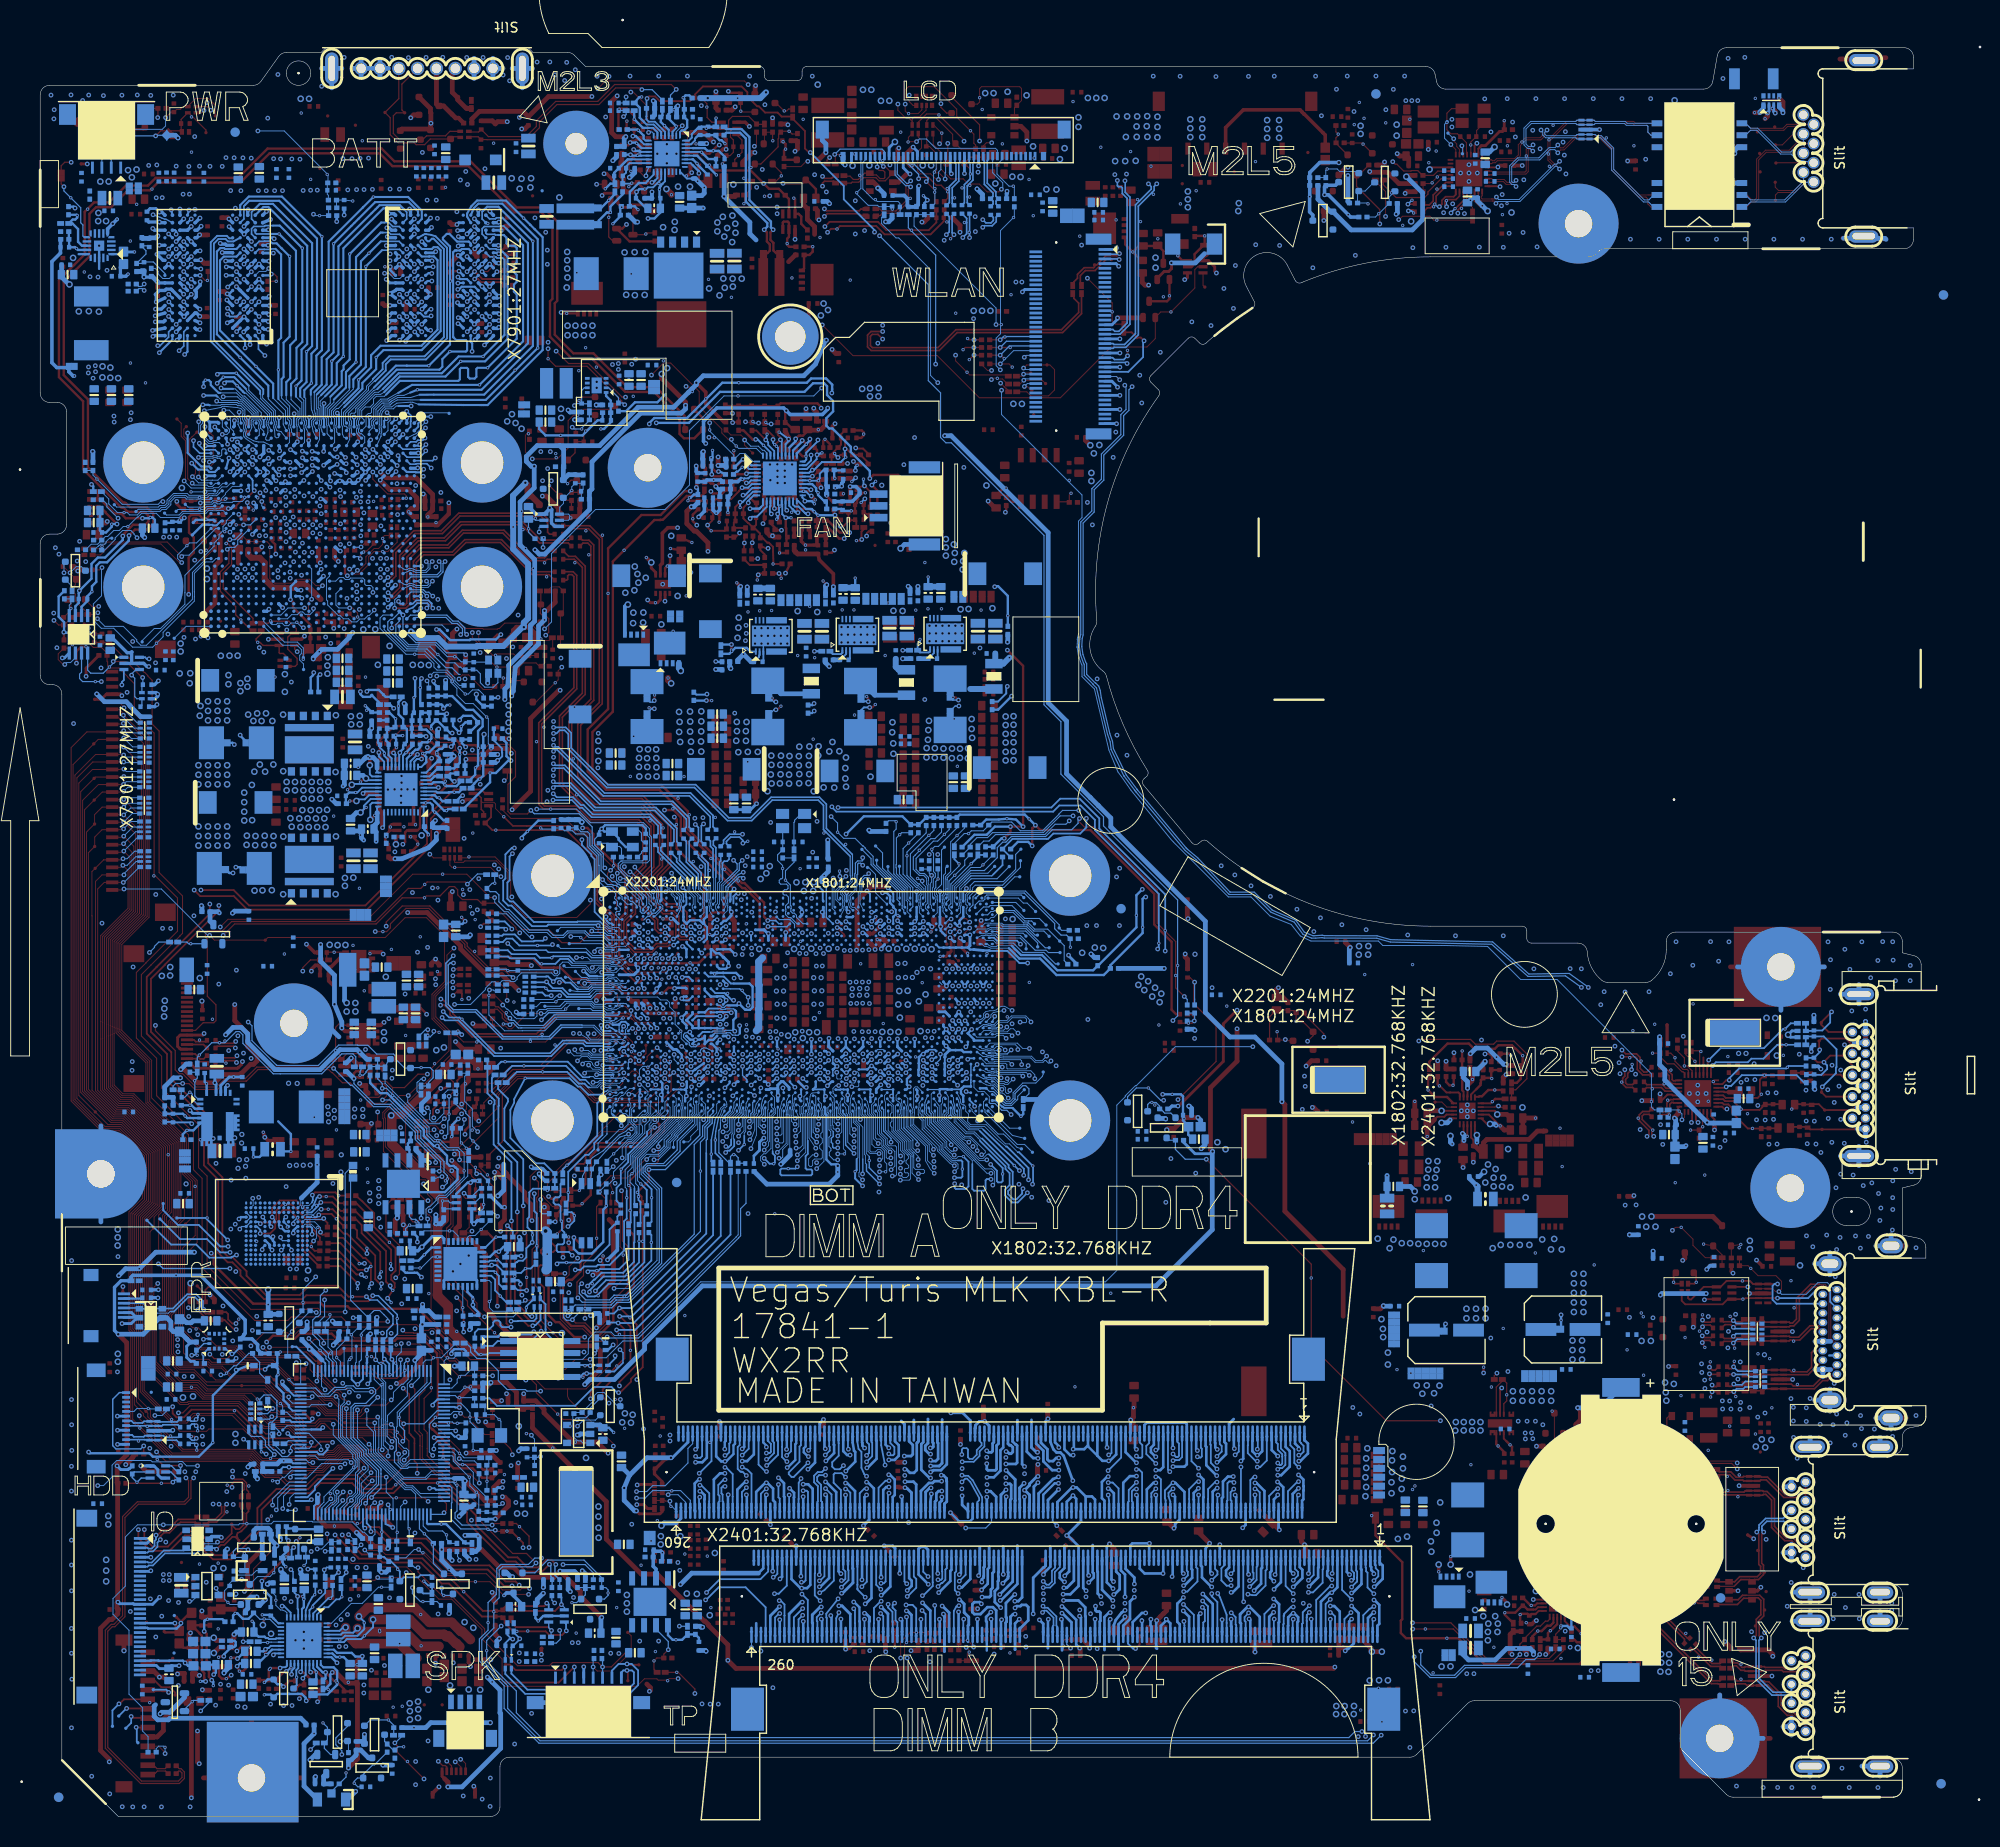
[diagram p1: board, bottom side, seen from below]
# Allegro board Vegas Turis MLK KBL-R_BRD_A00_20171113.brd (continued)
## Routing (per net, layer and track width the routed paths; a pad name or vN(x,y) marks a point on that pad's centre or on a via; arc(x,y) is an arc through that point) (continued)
PS_0: length 30.3
  TOP w0.102: R7926.2 148.43,123.4 R7927.1 149.23,123.4 C7918.1 149.85,123.37 150.04,123.57 151.83,123.57 v2(151.97,123.42) 152.26,123.42 153.76,124.92 153.76,125.82 153.79,125.85 153.79,125.84 v1(153.79,125.84)
  L3 w0.102: v1(164.86,128.23) 163.4,126.77 159.75,126.77 158.18,125.2 154.26,125.2 153.79,125.68 153.79,125.84 v1(153.79,125.84)
  BOTTOM w0.102: GPU1.AC19 169.6,131.84 169.93,131.51 169.93,129.31 169.81,129.19 169.81,128.78 168.66,127.63 168.46,127.63 168.13,127.3 167.59,127.3 167.26,126.97 166.71,126.97 166.4,127.28 165.89,127.28 165.54,127.63 165.4,127.63 164.9,128.13 164.9,128.19 164.87,128.23 164.87,128.23 v1(164.86,128.23)
PS_1: length 30.3
  TOP w0.102: C7919.1 149.78,121.84 ; 149.78,121.84 150.11,122.17 v2(151.82,122.17) 151.88,122.17 152.98,123.27 152.98,123.85 154.44,125.3 v1(154.44,125.84) ; 149.78,121.84 149.02,122.61 147.67,122.61 147.32,122.26 R7929.1 146.72,122.66 R7928.2
  L3 w0.102: v1(154.44,125.84) 155.01,126.41 155.18,126.41 156.23,127.46 160.29,127.46 160.94,128.11 162.44,128.11 162.53,128.02 162.86,128.02 162.95,128.11 163.55,128.11 165,129.56 v1(165,130.11)
  BOTTOM w0.102: GPU1.AD19 168.95,131.3 168.57,131.68 168.13,131.68 167.93,131.47 167.53,131.47 167.37,131.63 166.06,131.63 165.86,131.43 165.87,131.42 165.87,130.99 165.72,130.84 165.2,130.84 165,130.63 v1(165,130.11)
PS_2: length 14.1
  TOP w0.102: v1(170.36,130.82) 171.06,130.82 171.74,131.5 173.1,131.5 173.52,131.08 175.42,131.08 175.95,131.62 v2(175.95,134.9) 175.95,135.2 176.25,135.49 177.41,135.49 R7931.1 177.43,135.51 R7930.2 178.82,136.08 C7920.1
  BOTTOM w0.102: v1(170.36,130.82) 170.68,130.5 GPU1.AE17
PS_3: length 7.8
  TOP w0.102: v1(167.47,128.45) 167.17,128.45 166.62,127.91 v2(166.62,127.49) 167.18,127.49 167.52,127.82 C7921.1 167.54,127.83 R7933.1 169.15,127.83 R7932.2
  BOTTOM w0.102: GPU1.AE20 168.93,129.97 168.93,128.76 168.62,128.45 v1(167.47,128.45)
PS_ID: length 272.5
  L2 w0.356: 186.29,64.97 186.29,63.11 183.84,60.65
  L2 w0.381: 186.29,64.97 186.29,79.32 183.96,81.66 183.96,83.78 177.5,90.24 177.06,90.24 176.37,90.24 171.79,94.82 171.09,95.52 165.09,95.52 159.52,101.08 159.52,102.51 158.64,103.39 153.01,103.39 149.64,106.77 149.64,122.83 150.51,123.71 v1(153.6,123.71) ; 183.84,60.65 180.01,56.83 175.79,56.83 173.13,54.16 173.13,53.04 173.01,52.91 173.01,49.68 174.62,48.07 v1(174.62,46.2)
  L3 w0.381: v1(123.63,175.06) 125.14,173.55 125.14,163.18 128.18,160.14 137.02,160.14 142.01,155.15 147.38,155.15 148.65,153.88 148.65,149.68 145.47,146.5 145.47,141.06 152.66,133.86 154.53,133.86 156.41,131.98 156.41,129.42 154.53,127.54 153.78,127.54 152.58,126.34 152.58,124.73 v1(153.6,123.71)
  L4 w0.381: v1(123.63,175.06) 123.63,176.19 115.52,184.3 70.87,184.3 v3(62.36,175.8)
  BOTTOM w0.203: 174.02,45.35 173.4,44.73 KBC24.36
  BOTTOM w0.381: PD4302.3 65.14,170.21 65.48,170.55 v2(65.48,172.17) 65.46,172.18 PR4304.2 PR4305.2 65.46,174.73 64.4,175.8 v3(62.36,175.8) ; 174.02,45.35 174.62,45.95 v1(174.62,46.2)
PS_ID_R: length 16.1
  TOP w0.381: DCIN1.4 74.4,179.51 72.51,181.39 66.49,181.39 66.27,181.17 66.27,181.14 66.08,180.95 66.05,180.95 AFTP4312.1 63.82,178.72 PR4317.1
PS_ID_R1: length 5.4
  BOTTOM w0.102: PQ4301.S 60.44,174.85 62.28,174.85 62.54,175.11 v2(63.61,175.11) 63.76,174.96 PR4306.2 PR4305.1
PS_ID_R2: length 7.2
  BOTTOM w0.381: PQ4301.D 62.72,173.38 63.71,173.38 PR4306.1 63.89,173.2 v1(63.89,172.37) 63.49,172.37 v2(61.37,170.25) 61.12,170 PR4309.1
PSID_DISABLE#_R_C: length 4.5
  BOTTOM w0.102: PQ4302.C 58.66,173.69 59.58,172.76 PQ4301.G 60.38,172.63 PR4303.1 59.36,171.49 v2(59.27,171.4)
PTP_DIS#: length 3.1
  BOTTOM w0.127: D2405.K 161.15,29.25 v2(161.15,30.57) 161.26,30.68 KBC24.90
PU8201_36:
  vias: v2(161.71,105.19)
PU8201_39:
  vias: v2(160.47,105.41)
PURE_HW_SHUTDOWN#: length 428.1
  TOP w0.102: C2610.1 197.88,132.86 197.22,132.19 v1(197.18,132.19) 197.18,132.15 Q2602.D 196.62,131.42 196.62,130.9 196.75,130.77 196.75,130.05 196.62,129.92 196.62,129.21 195.3,127.89 R2612.2 194.41,127.76 v1(194.23,127.94) ; v2(68.93,83.42) R4012.2 68.1,82.53 v1(68.05,82.58) 67.93,82.45 D4001.3
  L3 w0.102: v1(194.23,127.94) 194.18,127.94 193.02,126.79 193.02,94.26 194.55,92.74 194.55,70.26 195.74,69.06 195.74,61.54 192.49,58.29 191.77,58.29 189.51,56.04 189.51,55.46 187.61,53.55 187.61,42.23 187.56,42.18 187.56,38.57 189.3,36.84 190.12,36.84 195.58,31.38 195.58,11.52 187.17,3.12 181.97,3.12 180.53,1.68 155.9,1.68 v1(155.4,2.18) ; v1(59.54,8.51) 59.23,8.21 54.63,8.21 49.11,13.73 27.01,13.73 21.05,19.69 21.05,24.23 20.28,25 20.28,36.1 19.61,36.76 19.61,41.86 19.2,42.27 19.2,43.82 18.31,44.71 18.31,56.17 18.48,56.33 18.48,56.47 18.73,56.72 18.86,56.72 20.06,57.91 20.06,57.93 20.31,58.18 20.33,58.18 45.97,83.82 53.59,83.82 55.01,82.4 64.42,82.4 64.91,82.88 67.75,82.88 v1(68.05,82.58)
  L4 w0.102: v1(59.54,8.51) 59.48,8.56 59.48,9.21 60.62,10.34 62.89,10.34 63.14,10.6 132.55,10.6 133.48,9.67 150.32,9.67 153.73,6.25 153.73,3.15 154.7,2.18 v1(155.4,2.18)
  BOTTOM w0.102: Q2605.D 195.97,132.84 196.53,132.84 v1(197.18,132.19)
PWR_0D95V: length 9.2
  BOTTOM w0.254: PR8622.1 140.6,148.42 PC8624.1 141.13,148.39 142.73,146.79 v2(145.05,146.79) 146.67,146.79 146.67,146.81 147.33,147.47 PC8626.1
PWR_0D95V_FB: length 4.7
  BOTTOM w0.254: v2(140.78,147.48) 140.44,147.48 139.71,148.21 PC8624.2 139.73,148.42 PR8622.2 PR8623.1 139.73,150.5 140.22,150.99 PU8601.1
PWR_0D95V_PHASE:
  vias: v2(143.12,153.67)
PWR_0D95V_PVDD:
  vias: v2(137.34,150.95)
PWR_1D0V:
  vias: v2(168.87,72.97) v2(171.23,74.32) v3(169.1,75.04) v3(169.1,74.23) v3(169.74,74.65) v3(169.71,73.84) v3(169.79,75.43)
PWR_1D0V_BT: length 3.5
  BOTTOM w0.305: PU5301.20 181.16,77.7 180.27,78.59 v2(179.8,78.59) 179.79,78.6 PC5304.2
PWR_1D0V_EN: length 3.9
  BOTTOM w0.127: PU5301.2 183.67,75.73 184.19,76.25 184.19,76.78 184.39,76.98 v2(184.44,76.98) 184.46,76.98 185.01,76.43 PC5314.1 185.37,76.48 PR5306.2
PWR_1D0V_PFM: length 2.2
  BOTTOM w0.254: PU5301.3 183.92,75.23 184.28,75.6 v2(184.44,75.6) 184.45,75.59 PR5303.1
PWR_1D0V_PG: length 4.2
  BOTTOM w0.127: PU5301.1 183.57,76.23 183.92,76.58 183.92,78.18 v2(183.94,78.2) 183.66,78.48 PR5305.2 183.66,79.11 PR5308.2
PWR_1D0V_PH: length 5
  BOTTOM w0.254: 175.06,73.88 173.71,72.54 v2(173.71,70.69) 174.59,70.69 PR5309.1
PWR_1D0V_SNUB: length 2.6
  BOTTOM w0.254: PC5315.1 v2(177.7,70.1) 177.04,70.1 176.5,70.64 PR5309.2
PWR_1D0V_SS: length 2.2
  BOTTOM w0.254: PC5313.1 182.87,78.08 v2(182.68,77.88) 182.66,77.87 PU5301.22
PWR_1D0V_TON: length 3
  BOTTOM w0.254: PU5301.6 183.34,73.67 184.08,72.93 v2(184.76,72.93) 184.78,72.93 185.2,72.5 PR5301.2
PWR_1D0V_VFB: length 4.8
  BOTTOM w0.254: PR5304.1 187.12,74.69 PR5302.2 187.11,74.69 PC5312.2 185.19,74.69 v2(184.95,74.45) 184.73,74.23 PU5301.5
PWR_1D0V_VFB_A: length 14.3
  TOP w0.381: v2(176.65,72.72) v1(176.49,72.19) 176.13,71.83 PG5310.1
  L3 w0.381: v1(184.25,73.63) 182.62,72 182.62,71.8 181.8,70.98 177.69,70.98 v1(176.49,72.19)
  BOTTOM w0.203: v1(184.25,73.63) 184.4,73.78 PC5312.1 186.29,73.82 PR5302.1
PWR_1D2V:
  vias: v2(54.29,35.13) v2(54.54,34.75) v4(51.6,33.38) v4(55.56,38.24) v4(55.56,37) v4(55.68,35.91) v4(55.7,34.8) v4(56.68,38.83) v4(56.72,37.85) v4(56.72,36.61) v4(56.78,35.52) v4(56.77,34.36)
PWR_1D8V_EN: length 4.8
  TOP w0.127: PR5406.2 161.02,65.44 PR5401.1 161,64.81 PC5406.1 161,63.46 160.75,63.21 v2(160.4,63.21) 160.27,63.21 v1(159.88,63.59)
  BOTTOM w0.127: v1(159.88,63.59) 159.88,63.84 159.85,63.87 PU5401.8
PWR_1D8V_POK: length 4.7
  BOTTOM w0.127: PU5401.7 161.12,63.74 160.85,63.47 160.45,63.47 160.1,63.12 PR5408.2 161.02,62.78 v2(161.1,62.86) 161.13,62.84 161.17,62.84 161.52,62.48 PR5402.2
PWR_1D35V_BOOT: length 2.6
  BOTTOM w0.254: PU8651.1 191.76,166.06 PR8674.1
  BOTTOM w0.305: v2(190.33,166.29) 191.46,166.29 PR8674.1
PWR_1D35V_BOOT_A: length 2.3
  BOTTOM w0.356: PR8674.2 191.83,164.67 PC8656.1 191.24,163.71 v2(191.02,163.93)
PWR_1D35V_EN: length 25.7
  TOP w0.127: D8602.1 189.11,181.56 PR8672.1 187.84,180.59 v1(187.86,180.57) ; v1(197.83,173.22) 198.12,173.52 PG8655.2
  L4 w0.127: v1(187.86,180.57) 188.9,181.61 192.46,181.61 192.83,181.24 192.93,181.24 196.46,177.71 196.46,176.07 196.46,175.73 197.83,174.37 v1(197.83,173.22)
  BOTTOM w0.127: PU8651.11 195.69,167.86 195.82,167.98 195.82,169.17 196.04,169.39 196.04,170.99 v2(197.1,172.05) 197.83,172.78 v1(197.83,173.22)
PWR_1D35V_FB: length 3.7
  BOTTOM w0.254: PR8676.1 197.3,168.44 PR8675.2 197.28,167.61 PC8662.2 196.63,166.79 v2(196.49,166.65) 196.35,166.51 PU8651.14
PWR_1D35V_FB_A: length 16.9
  BOTTOM w0.381: v2(196.71,153.11) 196.85,153.11 197.3,153.56 PG8653.1 197.43,154 198.58,154 199.11,154.52 199.11,165.27 198.19,166.18 PC8662.1 198.19,167.61 PR8675.1
PWR_1D35V_PG:
  vias: v2(195.31,170.84)
PWR_1D35V_PH: length 7.1
  L4 w0.254: v1(193.25,164.34) 192.64,164.95 v1(192.64,169.29)
  BOTTOM w0.381: v2(192.18,169.78) 192.18,169.75 v1(192.64,169.29) 193.19,168.75 PU8651.6
  vias: v4(194.11,159.95) v4(195.18,160) v4(196.25,159.97)
PWR_1D35V_VCC: length 8.7
  L4 w0.254: v1(195.05,163.65) 195.82,164.42 195.82,169.93 196.65,170.76 v1(196.65,170.95)
  BOTTOM w0.254: v1(196.65,170.95) 196.8,171.11 PR8677.2
  vias: v2(195.66,164.16)
PWR_1V35V_ILMT: length 6
  BOTTOM w0.254: PR8677.1 196.49,170.24 v2(196.42,170.18) 196.42,169.94 196.62,169.74 196.9,169.74 PR8671.1 196.92,169.32 196.33,168.72 196.33,167.37 195.91,166.96 PU8651.13
PWR_2D5V_EN: length 5.4
  BOTTOM w0.254: PU5151.8 133.65,19.27 133.15,18.78 v2(132.8,18.78) 132.15,18.78 PR5153.2 PR5152.1 130.36,18.98 PC5155.1
PWR_2D5V_FB: length 5.2
  BOTTOM w0.381: PU5151.2 134.92,26.29 135.22,26.59 PR5151.2 135.22,28.29 PC5153.2 135,28.2 134.4,28.2 v2(134.24,28.03) 134.24,27.22 PR5154.1
PWR_2D5V_POK: length 6.7
  TOP w0.127: PR5158.2 135.14,15.65 v2(135.14,16.54) 134.83,16.84 PR5155.2 134.09,17.25 v1(133.61,17.72)
  BOTTOM w0.127: v1(133.61,17.72) 133.61,18.6 134.92,19.91 PU5151.7
PWR_3D3V_CS2: length 3.4
  TOP w0.203: PU4503.5 47.51,76.49 47.45,76.55
  TOP w0.254: PR4517.1 45.02,77.22 v2(45.8,77.22) 46.5,77.22 47.16,76.55 47.45,76.55
PWR_3D3V_DRVH2: length 17.8
  TOP w0.203: PU4503.10 46.63,73.6 v4(46.3,73.6)
  L3 w1.016: v4(40.77,61.33) 40.77,62.94 39.61,64.1 39.61,67.56 45.39,73.34 46.04,73.34 v4(46.3,73.6)
  BOTTOM w0.508: v4(46.3,73.6) 45.82,73.6 v2(45.66,73.45)
PWR_3D3V_DRVL2: length 10.7
  TOP w0.203: v4(47.7,72.42) 47.92,72.64 PU4503.11
  L3 w1.016: v4(42.53,65.79) 42.53,67.25 v4(47.7,72.42)
  BOTTOM w0.508: v4(47.7,72.42) v2(47.7,71.66)
PWR_3D3V_EN2: length 2.7
  TOP w0.203: PU4503.6 46.23,75.8 v2(46.06,75.97)
  TOP w0.254: v2(46.06,75.97) 45.76,76.27 44.71,76.27 PR4503.2
PWR_3D3V_FB2: length 5.3
  TOP w0.203: PU4503.4 48.32,76.74 47.77,77.29
  TOP w0.254: 47.77,77.29 47.31,77.75 47.31,77.93 47.28,77.96 47.28,78.27 PR4523.1 46.19,78.51 46.18,78.49 ; 46.18,78.49 v2(46.13,78.44) ; 46.18,78.49 PR4512.2 46.15,79.34 PC4523.2
PWR_3D3V_FB2_R: length 2
  TOP w0.254: PC4523.1 45.24,80.31 PR4535.2 44.27,81.07 v2(44.1,80.9)
PWR_3D3V_LL2: length 20.6
  TOP w0.203: v4(45.54,74.62) 45.54,74.75 45.8,75 PU4503.8
  TOP w0.508: PC4535.2 44.53,74.62 v4(45.54,74.62)
  L3 w1.016: v4(45.54,74.62) 44.87,74.62 38.34,68.08 38.34,63.57 39.49,62.42 v4(39.49,61.38)
  vias: v2(41.49,59.89) v4(38.68,60.27) v4(39.83,60.27) v4(42.12,60.75) v4(43.14,60.75) v4(44.15,60.75) v4(45.17,60.75) v4(46.02,60.4)
PWR_3D3V_SNUB: length 2.7
  BOTTOM w0.508: v2(47.78,67.11) 48.51,67.83 PC4520.1
  BOTTOM w0.635: v2(47.78,67.11) 47.63,66.96 PR4533.2
PWR_3D3V_VBST2: length 3.8
  TOP w0.203: v2(45.23,73.4) 46.43,74.6 PU4503.9
  TOP w0.508: PR4528.2 44.8,72.96 v2(45.23,73.4)
PWR_3D3V_VBST2_1: length 2.6
  TOP w0.508: PR4528.1 PC4535.1 41.48,74.24 v2(41.47,74.23)
PWR_5V_CS1: length 3.9
  TOP w0.203: 51.63,77.65 50.94,76.95 50.56,76.95 49.66,76.95 49.52,76.81 PU4503.1
  TOP w0.254: 51.63,77.65 v2(51.69,77.65) 51.87,77.83 PR4531.1
PWR_5V_DRVH1: length 18.2
  TOP w0.203: v4(51.46,73.73) 51.12,73.73 50.65,74.2 PU4503.16
  L3 w1.016: v4(51.46,73.73) 52.47,73.73 58.24,67.96 v4(58.24,61.41)
  BOTTOM w0.508: v4(51.46,73.73) 50.84,73.73 v2(50.54,74.03)
PWR_5V_DRVL1: length 7.6
  L3 w1.016: v4(50.75,65.73) 50.75,72.1 v4(50.51,72.33)
  BOTTOM w0.508: v4(50.51,72.33) 50.51,71.66 v2(50.32,71.48)
PWR_5V_EN1: length 4.7
  TOP w0.254: PU4503.20 50.87,76.47 52.14,76.47 v2(52.89,77.22) 52.89,78.5 PR4502.2
PWR_5V_EN1_R: length 16
  TOP w0.254: PR4502.1 52.76,80.22 50.83,82.15 48.56,82.15 48,81.59 45.8,81.59 45.42,81.97 43.97,81.97 43.6,81.59 43.57,81.59 v2(42.84,80.86) 42.84,80.04 PR4501.2 PR4530.1 43.05,78.38 43.46,77.97 PR4504.1
PWR_5V_FB1: length 5
  TOP w0.203: PU4503.2 49.12,77.04 49.26,77.19
  TOP w0.254: 49.26,77.19 49.26,78.62 PC4522.2 49.28,78.66 PR4527.2 PR4526.1 49.28,81.35 v2(49.26,81.37)
PWR_5V_FB1_R: length 2.4
  TOP w0.254: PC4522.1 50.16,77.79 v2(50.24,77.72) 50.62,77.72 50.98,78.07 PR4525.2
PWR_5V_LL1: length 24.2
  TOP w0.203: v4(51.46,75) PU4503.18
  TOP w0.508: v4(51.46,75) 52.73,75 PC4516.2
  L3 w1.016: v4(56.97,60.4) 57.23,60.14 58.77,60.14 59.51,60.88 59.51,68.49 53,75 v4(51.46,75)
  vias: v2(53.39,60.15) v4(51.26,60.86) v4(52.14,60.86) v4(53.03,60.86) v4(53.92,60.86) v4(54.8,60.93) v4(55.69,60.93) v4(56.57,61.31)
PWR_5V_SNUB: length 2.4
  BOTTOM w0.508: v2(57.25,68.12) 57.25,68.11 PC4536.1 PR4529.2
PWR_5V_VBST1: length 4.4
  TOP w0.203: PU4503.17 50.93,74.6 51.16,74.37 51.91,74.37 52.2,74.08
  TOP w0.508: 52.2,74.08 52.81,73.47 PR4524.1 v2(52.98,72.28)
PWR_5V_VBST1_1: length 2.5
  TOP w0.508: PR4524.2 PC4516.1 v2(54.3,76)
PWR_5V_VCLK: length 2.2
  TOP w0.102: PU4503.19 50.89,75.4 51.43,75.93 TP4501.1
PWR_5V_VO1: length 92.3
  TOP w0.203: v1(49.22,72.59) 49.12,72.7 PU4503.14
  TOP w0.508: v1(50.98,80.27) PR4525.1 50.93,79.45 PR4527.1
  L3 w0.254: v1(50.98,80.27) 53.47,77.78 57.34,77.78 61.91,73.2 61.91,59.29 58.74,56.12 56.71,56.12 52.94,52.35 v1(51.04,52.35)
  L4 w0.508: v1(51.04,52.35) 52.08,52.35 56.34,56.62 57.99,56.62 62.68,61.31 62.68,73.26 57.72,78.22 52.5,78.22 50.06,75.79 50.06,73.94 49.22,73.1 v1(49.22,72.59)
  BOTTOM w0.254: v1(51.04,52.35) 51.13,52.26 PG4532.2
  BOTTOM w0.508: v2(49.08,71.83) 49.08,72.44 v1(49.22,72.59)
PWR_CHG_ACDET: length 5.9
  BOTTOM w0.203: PU4401.1 132.37,179.03 132.2,179.2
  BOTTOM w0.254: 132.2,179.2 131.95,179.2 131.61,179.54 131.61,180.32 PC4419.1 131.93,181.42 PR4416.1 131.92,181.46 131.92,182.56 v2(132.04,182.68) 131.78,182.93 131.38,182.93 PR4452.2
PWR_CHG_ACN: length 5.3
  BOTTOM w0.203: 130.66,178.46 130.78,178.34 130.78,178.15 131.2,177.73 PU4401.31
  BOTTOM w0.254: v2(127.59,177.8) 127.95,178.17 128.17,178.17 128.56,178.56 PR4468.2 129.37,178.71 PC4466.2 130.19,178.69 PC4468.1 130.4,178.72 130.66,178.46
PWR_CHG_ACOK: length 16
  TOP w0.102: v2(130.66,177.78) 131.57,177.71 PR4474.2 131.58,178.64 PR4451.2 131.93,179.08 132.13,179.27 v1(132.13,179.71) 132.93,179.71 133.23,179.41 PR4434.2 ; PR4408.2 124.24,177.75 v1(124.47,177.52)
  L3 w0.102: v1(124.47,177.52) 125.53,177.52 127.21,179.21 131.36,179.21 131.86,179.71 v1(132.13,179.71)
  BOTTOM w0.102: PU4401.2 132.77,179.07 v1(132.13,179.71)
PWR_CHG_ACP: length 5.1
  BOTTOM w0.203: 130.86,179.07 131.12,178.81 131.12,178.44 131.43,178.13 PU4401.32
  BOTTOM w0.254: 128.57,179.6 PR4467.2 ; 128.57,179.6 128.57,179.6 PC4466.1 130.1,179.6 PC4467.1 130.45,179.49 130.86,179.07 ; 128.57,179.6 128.57,180.48 v2(128.53,180.52)
PWR_CHG_AMON: length 6.2
  BOTTOM w0.203: 136.19,180.1 135.92,179.83 135.17,179.83 134.37,179.04 PU4401.6
  BOTTOM w0.254: v2(136.45,182.77) 136.7,182.75 PR4475.2 137.15,182.13 136.64,181.62 136.64,180.56 136.64,180.55 136.19,180.1
PWR_CHG_ASGATE: length 4.9
  BOTTOM w0.203: 130.99,177.33 PU4401.30
  BOTTOM w0.254: PC4409.2 127.64,176.43 128.25,177.04 v2(128.83,177.04) 129.45,177.04 129.74,177.32 130.98,177.32 130.99,177.33
PWR_CHG_BATDRV: length 1.4
  TOP w0.381: v2(131.68,174.37) v1(131.13,174.72) 131.26,174.85 PC4408.2
PWR_CHG_BATGONE: length 4
  TOP w0.254: PC4436.1 136.82,175.81 v1(137.63,176.62)
  BOTTOM w0.203: PU4401.13 136.5,176.53
  BOTTOM w0.254: 136.5,176.53 136.85,176.53 v2(136.88,176.56) 136.91,176.53 137.54,176.53 v1(137.63,176.62) 137.65,176.64 PR4439.1
PWR_CHG_BMON: length 4.3
  BOTTOM w0.203: PU4401.7 134.77,179 135.24,179.48 135.67,179.48
  BOTTOM w0.254: PR4476.2 v2(137.23,180.4) 136.31,179.48 135.67,179.48
PWR_CHG_BTST: length 5.3
  BOTTOM w0.203: 131,174.09 131.64,174.09 132.36,174.82 PU4401.24
  BOTTOM w0.508: PR4428.1 130.05,172.28 129.79,172.54 v2(129.79,173.14) 130.75,174.09 131,174.09
PWR_CHG_BTST1: length 2.5
  BOTTOM w0.508: PC4431.1 131.13,170.96 PR4428.2 129.92,170.96 v2(129.91,170.96)
PWR_CHG_CMSRC: length 4.4
  BOTTOM w0.203: PU4401.29 130.12,176.93 v2(130.08,176.89)
  BOTTOM w0.254: v2(130.08,176.89) 129.36,176.17 PC4409.1 128.55,175.4 PR4477.2
PWR_CHG_COMP: length 4.5
  TOP w0.254: v1(137.38,178.6) 137.24,178.73 PC4406.1 PR4407.1 138.04,180.17 v2(138.01,180.2)
  BOTTOM w0.203: 136.47,178.01 136.18,177.73 PU4401.10
  BOTTOM w0.254: 136.47,178.01 137.06,178.6 v1(137.38,178.6)
PWR_CHG_DCIN: length 4.1
  TOP w0.254: PC4435.1 134.6,174.69 v2(134.6,173.56) 135.23,173.56 v1(135.35,173.68) 135.35,173.68 PR4437.1
  BOTTOM w0.203: 135.01,173.91 134.77,174.15 PU4401.18
  BOTTOM w0.254: v1(135.35,173.68) 135.23,173.68 135.01,173.91
PWR_CHG_DCIN_D: length 5
  TOP w0.127: PD4410.2 137.37,170.38 PQ4416.3 136.07,168.12 v2(136,168.2) 135.88,168.31 PR4481.2
PWR_CHG_DCIN_R: length 2.3
  TOP w0.254: PD4410.3 136.18,172.96 PR4437.2 137,173.57 137.47,173.57 v2(137.81,173.23)
PWR_CHG_FSET: length 3.5
  TOP w0.254: PR4406.2 136.61,176.81 v2(136.73,176.69) 136.99,176.69 137.29,177 v1(137.29,177.18)
  BOTTOM w0.203: PU4401.12 136.52,176.93 ; 137.28,177.17 v1(137.29,177.18)
  BOTTOM w0.254: 136.52,176.93 136.57,176.93 136.68,177.04 137.15,177.04 137.28,177.17
PWR_CHG_HIDRV: length 11.7
  L3 w1.016: v4(129.28,162.41) 130,163.13 130,171.93 v4(131.31,173.24)
  vias: v2(129.34,163.38)
PWR_CHG_LODRV: length 5.1
  TOP w0.635: v4(133.81,172.98) 133.28,172.45 v2(133.28,172.37)
  L4 w0.635: v4(133.81,172.98) 133.85,172.94 133.85,170.2 134.25,169.8 134.25,169 v4(134.17,168.92)
PWR_CHG_NTC: length 6.2
  BOTTOM w0.203: PU4401.17 135.17,174.51 135.81,173.87 135.81,173.82 136.01,173.62
  BOTTOM w0.254: v2(136.84,170.79) 137.18,171.14 PR4410.1 137.7,171.18 137.7,172.68 136.76,173.62 136.01,173.62
PWR_CHG_NTC_1: length 2.2
  BOTTOM w0.254: PR4410.2 138.72,171.03 PR4412.1 138.72,170.07 v2(139.5,169.29)
PWR_CHG_PHASE: length 15.1
  L3 w1.016: v4(132.58,173.24) 132.58,172.68 131.45,171.55 131.45,164.34 134.07,161.72 v4(136.13,161.72)
  vias: v2(137.55,163.96) v4(136.05,166.27) v4(137.19,166.27) v4(137.17,161.7) v4(138.09,161.74) v4(138.26,166.25)
PWR_CHG_PROG: length 3
  BOTTOM w0.203: PU4401.9 136.04,178.13 136.24,178.33
  BOTTOM w0.254: PR4405.1 136.87,179.3 v2(136.8,179.23) 136.24,178.67 136.24,178.33
PWR_CHG_REGN: length 25.2
  TOP w0.254: v1(128.2,177.66) 128.32,177.66 129.24,176.74 PR4417.1
  L3 w0.254: v1(135.77,169.85) 135.77,171.91 136.05,172.19 136.05,173.08 136.68,173.71 136.68,175.02 135.76,175.94 135.76,176.51 133.99,178.28 132.33,178.28 130.85,176.8 128.65,176.8 128.15,177.29 128.15,177.61 v1(128.2,177.66)
  BOTTOM w0.203: PU4401.20 133.97,173.8 134.23,173.54
  BOTTOM w0.254: v1(135.77,169.85) 135.09,169.85 134.46,170.48 PR4438.2 134.46,171.99 PC4445.1 134.55,172.11 v2(134.55,172.92) 134.55,173.15 134.45,173.26 134.45,173.32 134.23,173.54
PWR_CHG_SCL: length 3.2
  BOTTOM w0.203: 133.57,179.26 PU4401.4
  BOTTOM w0.254: PR4471.2 134.24,180.81 PR4449.2 134.41,180.11 v2(134.02,179.72) 133.57,179.26
PWR_CHG_SDA: length 3.4
  BOTTOM w0.203: PU4401.3 133.17,179.06 132.77,179.46 v2(132.77,179.65)
  BOTTOM w0.254: v2(132.77,179.65) 133.59,180.47 PR4435.2 133.59,180.95 133.38,181.17 PR4470.2
PWR_CHG_SRN: length 6.7
  BOTTOM w0.203: PU4401.14 137.49,176.13
  BOTTOM w0.254: v2(140.32,173) 139.77,173.55 PR4457.2 139.36,173.62 PC4463.2 139.36,174.7 PC4462.2 137.94,176.13 137.49,176.13
PWR_CHG_SRN_R: length 2.6
  BOTTOM w0.254: PG4426.1 140.75,170.97 v2(139.94,171.77) 139.29,172.43 PR4457.1
PWR_CHG_SRP: length 5.5
  BOTTOM w0.203: PU4401.15 137.74,175.73 138.1,175.37 138.1,175.19 PC4461.2 138.1,174.73 PC4463.1 138.47,174.35 PR4456.2 137.56,173.55 v2(137.5,173.61)
PWR_CHG_SRP_R: length 4.8
  BOTTOM w0.254: PR4456.1 138.47,172.41 139.76,171.12 139.76,170.5 ; PG4428.1 141,169.62 140.15,170.48 140.15,170.48 139.76,170.48 139.76,170.5 ; 139.76,170.5 v2(139.77,170.5)
PWR_DCBATOUT_1D0V:
  vias: v1(181.67,69.42) v1(181.97,72.06) v2(183.33,71.93)
PWR_DCBATOUT_1D35V:
  vias: v2(190.1,171.35) v2(190.77,167.45)
PWR_DCBATOUT_3D3V:
  vias: v2(38.64,69.08)
PWR_DCBATOUT_5V:
  vias: v2(59.09,69.4)
PWR_DCBATOUT_VCCGTA:
  vias: v2(118.59,128.61) v4(117.79,128.02) v4(119.87,128.12)
PWR_DCBATOUT_VCCGTB:
  vias: v2(110.26,128.98) v4(108.72,128.14) v4(109.7,128.15)
PWR_DCBATOUT_VCCSA:
  vias: v2(133.1,125.98) v4(134.36,126.71)
PWR_DCBATOUT_VCORE:
  vias: v2(100.38,128.22) v4(99.18,128.42) v4(101.72,128.34) v4(102.56,128.31)
PWR_DCBATOUT_VDDQ: length 9.4
  BOTTOM w0.508: PC5103.1 49.21,17.26 48.6,16.64 45.75,16.64 44.53,17.86 v2(43.54,17.86) 42.06,17.86 41.69,17.49 v1(41.69,17.22)
PWR_DCBATOUT_VGA_CORE1:
  vias: v2(165.66,117.57) v4(166.39,116.98) v4(166.39,116.08) v4(167.34,116.93) v4(167.31,116.08)
PWR_DCBATOUT_VGA_CORE2:
  vias: v2(166.43,98.66) v4(167.08,99.79) v4(167.97,99.76) v4(167.97,98.91)
PWR_OPCN: length 4.2
  BOTTOM w0.203: 130.89,176.53 PU4401.28
  BOTTOM w0.254: v2(128.5,174.48) 129.45,175.43 PC4407.2 129.46,175.43 130.55,176.53 130.89,176.53
PWR_OPCP: length 3.1
  BOTTOM w0.203: PU4401.27 131.05,176.13
  BOTTOM w0.254: 131.05,176.13 130.99,176.13 v2(130.56,175.7) 130.56,175.63 PC4407.1
PWR_SECLET: length 80.6
  TOP w0.191: v1(186.27,43.55) 186.27,42.84 185.86,42.43 185.08,42.43 184.47,43.03 184.27,43.24 179.53,43.24 176.49,40.19 173.53,40.19 172.62,39.29 v2(172.31,39.29) 171.14,39.29 170.59,39.84 169.37,39.84 v1(169.29,39.76) ; v1(158.53,74.26) 158.62,74.35 158.62,75.15 158.16,75.61 R2401.1 157.98,75.84 R1819.2
  L3 w0.165: v1(186.27,43.55) 186.41,43.69 186.41,49.46 185.84,50.02 v1(185.75,50.02)
  L4 w0.165: v1(158.53,74.26) 161.7,71.1 162.44,70.79 165.47,70.79 167.91,68.35 167.91,68.3 168.2,68.01 168.6,68.01 168.77,68.17 176.71,68.17 177.86,67.02 178.29,67.02 185.47,59.85 185.47,51.2 185.26,50.99 185.26,50.51 v1(185.75,50.02) ; v1(169.29,39.76) 169.29,37.03 v1(169.25,36.99)
  BOTTOM w0.191: KBC24.63 171.95,33.93 171.17,34.71 171.17,35.08 v1(169.25,36.99)
PWR_VBAT: length 4.9
  TOP w0.254: PC4408.1 130.35,174.67 v1(130.37,174.65) 130.37,173.94 130.5,173.81 ; 130.5,173.81 v2(130.5,173.81) ; 130.5,173.81 130.47,173.79 129.47,173.79 PR4454.1
  BOTTOM w0.203: PU4401.26 131.23,175.73 131.02,175.52
  BOTTOM w0.254: 131.02,175.52 130.37,174.86 v1(130.37,174.65)
PWR_VCCGT_BOOTA:
  vias: v2(123.91,128.15)
PWR_VCCGT_BOOTA_RC: length 1.3
  BOTTOM w0.635: PR4804.1 PC4808.1
PWR_VCCGT_BOOTB:
  vias: v2(115.14,128.25)
PWR_VCCGT_BOOTB_RC: length 2.3
  BOTTOM w0.254: v2(113.76,131.62) PC4811.1
  BOTTOM w0.635: PC4811.1 113.76,130.6 PR4810.1
PWR_VCCGT_BOOTRA:
  vias: v2(122.64,128.18)
PWR_VCCGT_BOOTRB:
  vias: v2(113.89,128.25)
PWR_VCCGT_COMP: length 4.3
  TOP w0.254: PC4610.2 125.16,143.57 v2(125.2,143.53) 125.2,142.83 v1(125.31,142.72) 125.36,142.66 PR4626.2
  BOTTOM w0.203: v1(125.31,142.72) 125.31,142.72 125.22,142.82 PU4601.4
PWR_VCCGT_COMP1: length 4.3
  TOP w0.254: v1(129,142.65) 128.79,142.44 128.07,142.44 127.85,142.66 PR4626.1
  BOTTOM w0.254: v2(128.92,145.19) 128.92,144.44 PC4651.1 129.05,143.54 PC4612.1 129,143.49 v1(129,142.65)
PWR_VCCGT_FB: length 6.5
  BOTTOM w0.203: 125.89,142.21 125.53,142.21 125.52,142.22 125.12,142.22 125.1,142.24 124.93,142.42 PU4601.5
  BOTTOM w0.254: PR4630.2 v2(127.28,138.59)
  BOTTOM w0.381: PR4630.2 127.28,140.26 PR4633.2 127,140.55 PR4671.2 127,141.87 PR4636.2 126.22,141.87 125.89,142.21
PWR_VCCGT_FB1: length 2.9
  BOTTOM w0.381: PC4614.1 128.87,140.17 PC4661.1 128.87,138.87 v2(128.53,138.53) 128.53,138.56 128.46,138.56 128.46,138.57 128.15,138.88 PR4630.1
PWR_VCCGT_FB2: length 11.1
  TOP w0.254: 130.59,141.86 130.58,141.86 PR4665.2 129.29,141.86 129.11,141.68 128.87,141.68 128.57,141.38 v1(128.57,141.36) 128.25,141.68 127.76,141.68 127.58,141.86 PC4619.1
  TOP w0.381: v1(130.64,141.26) 130.59,141.31 PC4615.2 130.59,143.48 v1(130.65,143.54)
  BOTTOM w0.254: v1(130.64,141.26) 130.47,141.09 PR4631.2 130.9,140.51 131.25,140.16 v2(131.37,140.16)
  BOTTOM w0.381: v1(128.57,141.36) 128.3,141.09 PR4671.1 128.14,140.82 PR4633.1 ; v1(130.65,143.54) 130.65,142.94 PC4662.1 129.71,142.79 PC4618.1
PWR_VCCGT_FB_RC: length 2.8
  BOTTOM w0.381: PC4662.2 129.71,141.88 PC4618.2 129.53,142.05 v2(128.8,142.05) 128.03,142.05 PR4636.1
PWR_VCCGT_FCCM#: length 29.9
  TOP w0.254: v1(126.91,124.56) v2(126.91,123.98)
  L3 w0.254: v1(124.93,139) 125.62,139 127.56,137.05 127.56,134.08 127.04,133.56 127.04,124.97 126.91,124.84 v1(126.91,124.56)
  L4 w0.254: v1(126.91,124.56) 126.63,124.56 125.79,123.72 118.22,123.72 v1(118.09,123.85)
  BOTTOM w0.203: PU4601.11 123.56,139.38 123.76,139.18
  BOTTOM w0.254: v1(126.91,124.56) 127.91,124.56 PR4806.1 ; 123.76,139.18 123.94,139 v1(124.93,139) ; v1(118.09,123.85) PR4812.1
PWR_VCCGT_FCCM#_RA: length 4.1
  BOTTOM w0.203: PU4801.1 124.89,123.82 125.01,123.94
  BOTTOM w0.254: 125.01,123.94 125.28,124.21 126.5,124.21 v2(126.88,123.83) 127.13,123.58 PR4806.2
PWR_VCCGT_FCCM#_RB: length 1.8
  BOTTOM w0.203: PR4812.2 116.14,123.55 115.26,123.55 115.12,123.69 PU4802.1
PWR_VCCGT_IMON: length 6
  TOP w0.254: v1(125.67,144.25) 126.45,143.47 PR4608.2 126.67,143.47 PR4672.2 126.65,144.29 v2(126.65,145.16)
  BOTTOM w0.203: 124.8,143.62 PU4601.2
  BOTTOM w0.254: PC4604.2 125.73,144.25 v1(125.67,144.25) 125.43,144.25 124.8,143.62
PWR_VCCGT_ISEN1: length 7.3
  TOP w0.203: v1(125.98,139.69) 126.5,139.18 PR4669.2 126.5,137.71 PC4625.1 126.66,137.51 PR4824.2 126.54,136.96 PR4821.1
  BOTTOM w0.203: PU4601.9 124.61,140.82 125.73,139.7 126,139.7 126,139.69 v1(125.98,139.69) v2(125.98,139.13)
PWR_VCCGT_ISEN2: length 12
  TOP w0.203: PR4822.2 124.46,136.95 123.88,136.37 123.88,135.94 PR4823.1 123.61,135.91 123.1,135.39 122.93,135.39 122.48,134.94 122.48,134.47 122.44,133.17 v2(122.48,133.12) PR4635.2 ; PR4822.2 124.62,137 125.09,137.47 125.14,137.47 125.63,137.97 PR4669.1 125.63,139.11 v1(125.12,139.62) ; PR4822.2 124.29,137.28 PC4626.1
  BOTTOM w0.203: PU4601.10 124.55,140.42 125.12,139.84 v1(125.12,139.62)
PWR_VCCGT_ISUMN: length 42.1
  TOP w0.203: PR4643.2 123.38,140.47 PC4630.2 123.45,139.69 PR4642.2 123.45,139.56 123.45,138.92 PR4670.2 123.43,138.81 123.43,138.1 PC4626.2 123.37,138.04 123.37,137.78 123.55,137.6 v1(123.55,137.41) ; PR4809.2 124.15,133.66 v1(124.11,133.7) ; PR4645.2 128.88,138.87 PR4647.1 128.87,138.12 PC4633.1 128.94,137.76 v1(129.44,137.26) 129.44,137.03 v2(129.06,136.65) 127.63,136.65 PR4815.2 127.39,136.89 PC4625.2
  L3 w0.203: v1(124.11,133.7) 124.08,133.74 121.63,133.74 118.61,130.72 118.61,119.64 117.59,118.61 117.59,118.02 v1(118.11,117.5)
  L4 w0.203: v1(129.44,137.26) 123.71,137.26 v1(123.55,137.41) 123.4,137.26 123.4,135.56 123.83,135.13 123.83,133.99 v1(124.11,133.7)
  BOTTOM w0.203: v1(118.11,117.5) 118.34,117.27 PR4646.2
PWR_VCCGT_ISUMN_GA: length 24.1
  TOP w0.203: v2(121.65,118.01) 122.03,117.63 v1(122.18,117.63) ; PR4822.1 124.62,135.46 v1(124.7,135.38) 124.77,135.31 PR4809.1
  L3 w0.203: v1(124.7,135.38) 124.7,131.61 119.84,126.76 119.84,119.92 121.94,117.82 122.04,117.82 122.23,117.63 v1(122.18,117.63)
  BOTTOM w0.127: v1(122.18,117.63) 122.38,117.63 122.73,117.27 PG4809.2
PWR_VCCGT_ISUMN_GB: length 33.2
  TOP w0.203: v1(112.22,117.88) 111.93,117.88 v2(111.62,118.19) ; PR4815.1 PR4824.1 126.48,135.98 v1(126.04,136.42)
  L3 w0.203: v1(112.22,117.88) 112.04,118.06 111.96,118.06 110.4,119.62 110.4,127.09 112.85,129.55 116.15,129.55 121.92,135.32 123.35,135.32 124.45,136.42 v1(126.04,136.42)
  BOTTOM w0.203: v1(112.22,117.88) 112.83,117.88 113.14,117.57 PG4815.2
PWR_VCCGT_ISUMN_P_1: length 3.3
  TOP w0.254: v2(128.21,137.57) 128.19,137.59 PC4609.2 128.18,138.48 PC4628.2 128.18,139.25 PC4653.2 128.59,140.02 PR4647.2
PWR_VCCGT_ISUMN_P_2: length 17.4
  TOP w0.254: v2(121.62,131.61) 121.62,131.89 v1(121.85,132.12) PR4641.2
  L3 w0.254: v1(118.13,118.3) 118.22,118.3 119.22,119.3 119.22,129.49 v1(121.85,132.12)
  BOTTOM w0.254: v1(118.13,118.3) 118.3,118.13 PR4646.1
PWR_VCCGT_ISUMN_RC: length 1.9
  TOP w0.254: PR4645.1 129.76,139.85 PC4623.1 v2(131.53,139.85)
PWR_VCCGT_ISUMNB: length 12.7
  TOP w0.254: PR4670.1 PR4642.1 124.4,139.63 125.2,140.44 v1(125.67,140.44) ; v1(130.59,137.26) 131.01,137.68 v2(131.01,137.93) 131.01,138.37 PC4623.2
  L4 w0.254: v1(130.59,137.26) 130.21,137.64 130.15,137.64 129.59,138.2 128.19,138.2 125.95,140.44 v1(125.67,140.44)
  BOTTOM w0.203: v1(125.67,140.44) 125.46,140.44 124.68,141.22 PU4601.8
PWR_VCCGT_ISUMP: length 23.3
  TOP w0.203: PC4630.1 124.27,140.5 124.27,141.17 ; PR4643.1 124.27,141.17 ; 124.27,141.17 124.35,141.1 125.64,141.1 v1(125.77,141.24) 126.11,140.9 126.11,140.86 126.94,140.02 PC4653.1 127.3,139.99 127.3,139.28 PC4628.1 127.28,139.24 PC4609.1 ; v2(124.16,131.43) 124.16,131.88 v1(124.06,131.98) 123.92,132.12 PR4641.1 123.39,132.94 PR4816.1 123.44,133.03 124.96,133.03 125.56,133.63 PR4808.1
  L4 w0.203: v1(124.06,131.98) 124.06,132.41 123.5,132.97 123.5,134.99 123.07,135.42 123.07,137.76 123.45,138.14 123.45,138.91 v1(125.77,141.24)
  BOTTOM w0.203: v1(125.77,141.24) 125.13,141.24 124.75,141.62 PU4601.7
PWR_VCCGT_ISUMP_GA: length 23.4
  TOP w0.203: PR4821.2 125.41,136.04 125.53,135.92 v1(125.53,135.36) 125.56,135.33 PR4808.2 ; v2(122.59,118.87) v1(122.18,118.47)
  L3 w0.203: v1(125.53,135.36) 125.53,135.31 125.38,135.16 125.03,134.8 125.03,131.48 120.17,126.62 120.17,120.05 121.83,118.4 122.11,118.4 v1(122.18,118.47)
  BOTTOM w0.127: v1(122.18,118.47) 122.4,118.47 122.76,118.82 PG4808.2
PWR_VCCGT_ISUMP_GB: length 28.7
  TOP w0.203: v1(123.02,134.79) 123.12,134.75 PR4823.2 123.84,134.61 123.37,134.14 PR4816.2 ; v2(112.54,119.03) 112.37,118.86 v1(112.37,118.5)
  L3 w0.203: v1(123.02,134.79) 121.86,134.79 116.29,129.22 112.99,129.22 110.73,126.96 110.73,119.76 111.99,118.5 v1(112.37,118.5)
  BOTTOM w0.203: PG4813.2 112.97,118.53 112.42,118.53 112.36,118.47 112.36,118.5 v1(112.37,118.5)
PWR_VCCGT_NTC: length 3
  BOTTOM w0.203: PU4601.3 125.04,143.22 125.26,143.43 125.74,143.43 v2(125.76,143.41) 126.23,142.95 126.38,142.95 PR4616.1
PWR_VCCGT_NTC1: length 25.4
  TOP w0.254: v1(128.28,142.95) 128.58,142.95 129.05,143.42 PR4621.2 129.06,143.55 v2(129.06,144.42)
  L3 w0.254: v1(128.57,122.77) 128.77,122.97 128.77,132.85 129.95,134.03 129.95,137.84 129.86,137.94 129.86,138.5 127.92,140.43 127.92,142.59 v1(128.28,142.95)
  BOTTOM w0.254: PR4616.2 127.57,142.7 128.21,142.96 128.26,142.96 v1(128.28,142.95) ; v1(128.57,122.77) 128.53,122.72 127.8,122.72 127.81,122.73 PR4617.2
PWR_VCCGT_PWMA: length 12.8
  TOP w0.381: v2(126.34,131.12) v1(125.94,130.72)
  L3 w0.254: v1(124.92,137.96) 125.46,137.41 125.77,137.41 126.55,136.63 126.55,134.92 126.03,134.4 126.03,130.81 v1(125.94,130.72)
  BOTTOM w0.203: PU4601.12 123.16,139.19 124.21,138.14 124.73,138.14 v1(124.92,137.96)
  BOTTOM w0.508: PR4802.2 126.02,130.64 v1(125.94,130.72)
PWR_VCCGT_PWMA_RA:
  vias: v2(125.15,128.03)
PWR_VCCGT_PWMB: length 13.4
  TOP w0.254: v2(117.16,131.32) 117.16,131.3 v1(116.78,130.91)
  L3 w0.508: v1(122.67,138.45) 122.67,138.22 121.85,137.41 121.39,137.41 120.21,136.23 120.21,135.63 116.78,132.2 v1(116.78,130.91)
  BOTTOM w0.203: v1(122.67,138.45) 122.82,138.6 122.82,139.24 122.76,139.3 PU4601.13
  BOTTOM w0.508: v1(116.78,130.91) 116.91,130.78 PR4811.2
PWR_VCCGT_PWMB_RA:
  vias: v2(116.45,128.09)
PWR_VCCGT_RTN: length 5.6
  TOP w0.254: PR4639.2 124.24,142.12 PC4622.1 124.66,141.71 125.29,141.71 v1(125.32,141.74) 125.69,142.11 v2(125.75,142.11) 126.3,142.11 PC4619.2 126.72,141.69 PR4666.2
  BOTTOM w0.203: v1(125.32,141.74) 125.09,141.74 124.81,142.02 PU4601.6
PWR_VCCGT_SNB1:
  vias: v2(118.07,123.17)
PWR_VCCGT_SNB2: length 2.1
  BOTTOM w0.635: PR4814.2 109.13,121.87 109.45,122.19 PC4813.1
PWR_VCCGT_SWA: length 5.2
  BOTTOM w0.508: PR4805.1 121.66,119.33 PL4801.1
  vias: v2(119.87,123.4)
PWR_VCCGT_SWB: length 5.5
  BOTTOM w0.508: PL4802.1 111.68,119.18 PR4814.1
  vias: v2(110.57,123.4)
PWR_VCCGT_VCCDA: length 3.8
  BOTTOM w0.203: PU4801.2 123.91,123.44 123.97,123.38 123.97,123.26 124.49,122.74 PC4809.1
  BOTTOM w0.508: PC4809.1 124.82,122.74 v2(125.62,123.53) 126.23,122.93 PR4803.2
PWR_VCCGT_VCCDB: length 2
  BOTTOM w0.203: PC4812.1 115.34,122.94 114.72,123.55 PU4802.2
  BOTTOM w0.508: PR4813.2 116.07,122.94 PC4812.1
PWR_VCCSA_BST: length 9.7
  TOP w0.254: PR5001.2 v2(131.11,135.41)
  TOP w0.305: PU5001.2 133.96,129.18 v1(133.97,129.17)
  L3 w0.635: v1(133.97,129.17) 133.97,129.93 132.73,131.16 132.73,135.54 v4(133.3,136.11)
PWR_VCCSA_BST_RC: length 2.3
  TOP w0.254: v2(133.38,134.77) PR5001.1
  TOP w0.508: PC5005.1 132.23,134.57 PR5001.1
PWR_VCCSA_COMP: length 4.4
  BOTTOM w0.203: 118.76,141.62 PU4601.24
  BOTTOM w0.254: PR4640.1 116.79,139.67 PC4624.1 117.01,139.77 117.7,140.46 v2(117.7,140.71) 117.91,140.91 117.91,141.18 118.34,141.62 118.76,141.62
PWR_VCCSA_COMP_RC: length 1.8
  BOTTOM w0.254: v2(114.18,138.77) 115.01,138.77 PC4601.1 115.21,138.97 PR4640.2
PWR_VCCSA_DRVH: length 9
  L3 w0.635: v4(132.29,121.76) 132.29,129.39 v4(132.62,129.73)
  BOTTOM w0.635: v4(132.29,121.76) 132.29,121.84 132.49,122.05 PU5002.4
  vias: v2(131.71,129.74)
PWR_VCCSA_DRVL: length 11.6
  TOP w0.305: PU5001.5 134.96,132.23 135.42,132.7 v4(135.42,133.29)
  TOP w0.381: v2(135.94,133.81) v4(135.42,133.29)
  L3 w0.635: v4(135.42,133.29) 135.19,133.05 135.19,131.08 137.31,128.96 137.46,128.81 v4(137.91,128.81)
  BOTTOM w0.406: v4(137.91,128.81) 138.02,128.81 138.23,128.61 PU5003.4
PWR_VCCSA_FB: length 6
  BOTTOM w0.203: PU4601.25 118.55,142.02 118.5,141.97 v2(117.66,141.97) 117.66,142.08 117.52,142.23 117.52,142.73 117.12,143.12 PR4632.2
  BOTTOM w0.381: PR4632.2 116.85,143.12 116.85,141.47 PR4637.1 116.79,141.27 PR4638.2
PWR_VCCSA_FB1:
  vias: v2(115,140.59)
PWR_VCCSA_FB2: length 1.5
  TOP w0.381: 115.21,141.4 v1(115.19,141.4)
  BOTTOM w0.381: PR4637.2 115.47,141.35 115.43,141.38 115.23,141.38 115.21,141.4 ; PC4617.2 115.02,141.88 115.19,141.72 115.19,141.41 115.21,141.4 ; 115.21,141.4 v1(115.19,141.4)
  vias: v2(115.87,141.21)
PWR_VCCSA_FB_RC: length 1.9
  BOTTOM w0.254: PC4617.1 115.94,143.07 PR4632.1 115.99,142.3 115.91,142.22 v2(115.91,142.23)
PWR_VCCSA_FCCM: length 26.4
  TOP w0.254: v1(133.43,134.01) 133.43,133.2 v2(133.72,132.91) 133.96,132.67 PU5001.7
  L4 w0.254: v1(133.43,134.01) 133.91,134.49 133.91,136.48 132.12,138.26 131,138.26 130.55,138.71 128.56,138.71 126.46,140.81 126.46,142.29 124.42,144.32 118.77,144.32 118.44,144.65 v1(118.44,144.7)
  BOTTOM w0.203: PU4601.29 118.96,143.62 118.44,144.14 v1(118.44,144.7)
PWR_VCCSA_IMON: length 3.8
  TOP w0.254: PC4629.2 119.51,141.92 PR4644.1 119.54,141.09 119.32,140.87 v2(119.24,140.87) 118.6,140.87 v1(118.45,141.01)
  BOTTOM w0.203: PU4601.23 118.94,141.22 v1(118.45,141.01)
PWR_VCCSA_ISUMN: length 47.1
  TOP w0.203: PR4618.2 115.31,144.72 115.6,144.44 v1(115.59,144.44) 115.76,144.61 PR4620.1 ; PR4613.1 115.26,146.9 PC4603.2 115.26,145.81 PR4615.1 116.26,144.82 PR4620.1 ; PC4605.1 PR5004.2 116.26,143.91 PR4620.1
  L3 w0.203: v1(129.51,119.29) 128.09,120.72 128.09,123.15 128.16,123.22 128.16,133.1 128.92,133.86 128.92,134.26 128.92,134.27 128.92,134.67 128.92,134.67 128.92,138.42 127.16,140.18 127.16,143.94 126.24,144.86 119.53,144.86 118.89,144.22 115.82,144.22 115.6,144.44 v1(115.59,144.44)
  BOTTOM w0.203: v1(115.59,144.44) 115.94,144.79 v2(115.94,144.88) ; v1(129.51,119.29) 129.56,119.24 130.65,119.24 PR4611.1
PWR_VCCSA_ISUMN_P_1: length 2.4
  TOP w0.254: PC4608.2 113.12,146.53 112.86,146.79 v2(112.86,146.93) 112.86,147.11 113.06,147.31 PR4613.2
PWR_VCCSA_ISUMN_P_2: length 43.2
  TOP w0.254: v1(113.94,144.03) 113.69,143.77 113.61,143.74 PR4625.2 ; v1(129.57,118.61) 129.56,118.61 129.09,118.61 v2(129.01,118.61)
  L3 w0.254: v1(129.57,118.61) 129.06,118.61 127.48,120.2 127.48,123.4 127.55,123.47 127.55,133.35 128.31,134.11 128.31,134.92 128.31,134.93 128.31,138.16 126.55,139.92 126.55,142.6 124.91,144.25 119.79,144.25 119.15,143.61 115.7,143.61 115.33,143.24 114.36,143.24 113.94,143.65 v1(113.94,144.03)
  BOTTOM w0.254: PR4611.2 130.88,118.6 129.58,118.6 v1(129.57,118.61)
PWR_VCCSA_ISUMN_R: length 50.4
  TOP w0.203: v2(135.65,117.83) 135.19,117.83 v1(135.1,117.74) ; v1(114.57,143.81) PR5004.1
  L3 w0.203: v1(135.1,117.74) 134.57,118.27 131.66,118.27 129.38,120.56 129.38,132.59 131.16,134.37 131.16,138.07 130.72,138.5 130.72,138.5 129.82,139.4 129.82,142.56 129.04,144.46 129.03,144.46 128.99,144.51 128.09,145.41 126.52,145.41 126.48,145.44 116.56,145.44 116.53,145.47 115.73,145.47 114.61,144.35 114.61,143.85 v1(114.57,143.81)
  BOTTOM w0.127: PG5001.1 135.39,117.74 v1(135.1,117.74)
PWR_VCCSA_ISUMN_RC: length 2.1
  TOP w0.254: PC4611.2 117.15,146.2 v2(116.97,146.38) 116.44,145.86 PR4615.2
PWR_VCCSA_ISUMNB: length 4.6
  TOP w0.254: PC4611.1 117.81,145.24 v1(117.81,144.74) 117.68,144.61 PR4620.2
  BOTTOM w0.203: PU4601.28 118.9,143.22 117.85,144.26 117.85,144.74 v1(117.81,144.74)
  BOTTOM w0.254: v2(117.29,144.94) v1(117.81,144.74)
PWR_VCCSA_ISUMP: length 11.9
  TOP w0.203: PC4605.2 118.07,143.81 118.32,143.56 v1(118.32,143.1) ; PR4625.1 112.39,143.9 PR5003.2 114.03,144.72 PR4618.1 114.67,145.36 v1(114.83,145.36) 114.83,146.24 PC4608.1
  BOTTOM w0.203: PU4601.27 118.66,142.82 118.54,142.94 118.48,142.94 v1(118.32,143.1) 118.15,143.1 117.3,143.95 115.29,143.95 v2(114.76,144.48) 114.86,144.59 114.86,145.36 v1(114.83,145.36)
PWR_VCCSA_ISUMP_R: length 51.2
  TOP w0.203: v1(113.7,145.46) 113.64,145.39 112.92,145.39 112.34,144.81 PR5003.1 ; v1(135.11,118.6) 135.08,118.64 v2(135.08,119.2)
  L3 w0.203: v1(113.7,145.46) 114.09,145.84 116.62,145.84 116.69,145.77 128.19,145.77 129.27,144.7 129.32,144.65 130.15,142.63 130.15,139.54 130.86,138.83 131.49,138.21 131.49,134.24 129.71,132.46 129.71,120.69 131.8,118.6 v1(135.11,118.6)
  BOTTOM w0.127: PG5011.1 135.56,118.44 135.27,118.44 v1(135.11,118.6)
PWR_VCCSA_PWM: length 36
  TOP w0.305: PU5001.3 134.46,129.32 134.77,129.01 v2(134.98,129.01) 135.51,129.01 v1(135.81,129.3)
  L4 w0.381: v1(135.81,129.3) 135.81,130.18 134.75,131.24 134.75,133.81 134.99,134.04 134.99,136.92 132.12,139.79 129.01,139.79 127.54,141.26 127.54,143.66 125.72,145.48 119.18,145.48 118.89,145.77 118.26,145.77 v1(117.72,146.31)
  BOTTOM w0.203: v1(117.72,146.31) 117.72,146.19 118.95,144.95 118.95,144.22 119.16,144.02 PU4601.30
PWR_VCCSA_RTN: length 5
  TOP w0.203: PR4627.1 118.19,142.46 v1(118.3,142.46) 118.58,142.18 118.58,141.97 v2(118.58,141.97)
  TOP w0.254: PR4602.1 115.37,143.11 PC4616.1 116.09,143.1 116.87,143.1 PC4613.1 116.99,142.98 117.54,142.98 117.56,142.97 PR4627.1
  BOTTOM w0.203: PU4601.26 118.34,142.42 v1(118.3,142.46)
PWR_VCCSA_SW: length 14.1
  TOP w0.635: v4(133.31,120.44) 133.64,120.77 v2(133.64,121.01)
  L3 w0.635: v1(131.22,132.23) 131.22,130.84 130.89,130.52 130.89,122.03 132.48,120.44 v4(133.31,120.44)
PWR_VCORE_ALERT#: length 3.5
  TOP w0.191: PR4623.2 123.05,147.3 122.43,146.69 122.43,146.4 v1(122.49,146.35)
  BOTTOM w0.191: v1(122.49,146.35) 122.49,146 v2(122.12,145.64) 121.96,145.48 PU4601.36
PWR_VCORE_BOOT:
  vias: v2(106.03,128.36)
PWR_VCORE_BOOT_RC: length 2.4
  BOTTOM w0.254: PR4705.1 v2(106,131.74)
  BOTTOM w0.635: PR4705.1 PC4707.1
PWR_VCORE_BOOTR:
  vias: v2(104.59,128.36)
PWR_VCORE_COMP: length 5.5
  TOP w0.254: v1(121.13,138.04) 121.13,136.97 121.09,136.93 121.09,136.13 PC4639.1 121.06,135.87 PR4656.1
  BOTTOM w0.203: PU4601.16 121.56,139.48 121.51,139.43 121.51,138.42 v1(121.13,138.04)
  BOTTOM w0.254: v2(120.58,138.04) v1(121.13,138.04)
PWR_VCORE_COMP1: length 1.8
  TOP w0.254: PC4640.1 121.1,134.3 v2(121.8,134.3) 121.8,135.06 PR4656.2
PWR_VCORE_FB: length 1.1
  BOTTOM w0.203: v1(121.03,138.83) 121.03,138.93 121.16,139.06 PU4601.17
  vias: v2(120.51,138.62)
PWR_VCORE_FB1: length 0.8
  TOP w0.381: PC4641.1 120.24,136.05 120.24,136.71 120.25,136.72 PR4657.2
PWR_VCORE_FB2: length 6.1
  TOP w0.356: 117.74,135.13 118.15,135.13 v2(119.04,135.13) 119.08,135.13 119.48,135.53 PC4643.2
  TOP w0.381: PC4644.1 117.82,135.21 PC4642.2 116.96,136.13 PR4667.2 116.88,136.04 PR4663.1 ; PR4660.2 119.48,136.82 PC4643.2
PWR_VCORE_FB_RC: length 0.9
  TOP w0.381: PR4658.2 118.56,136.74 PC4643.1
PWR_VCORE_FCCM#: length 24.7
  L3 w0.254: v1(119.1,139.8) 119.1,139.68 117.8,138.37 117.8,135.72 112.49,130.42 110.15,130.42 108.05,128.32 108.05,124.61 v1(108.7,123.95)
  BOTTOM w0.203: v1(119.1,139.8) 119.1,139.92 119.37,140.19 PU4601.21
  BOTTOM w0.254: v1(119.1,139.8) 118.36,139.8 118.09,139.53 v2(118.09,139.52) ; PR4706.1 v1(108.7,123.95)
PWR_VCORE_FCCM#_R: length 2.9
  BOTTOM w0.203: v2(106.87,125.11) 106.87,124.88 107.12,124.63 PR4706.2 106.89,123.73 105.94,123.73 105.8,123.87 PU4701.1
PWR_VCORE_IMON: length 3.5
  TOP w0.254: v2(121.75,139.27) 122,139.02 v1(122.34,139.02) 122.56,139.24 PR4661.1 122.53,140.09 PC4638.1
  BOTTOM w0.203: v1(122.34,139.02) 122.36,139.04 PU4601.14
PWR_VCORE_ISUMN: length 50
  TOP w0.203: PR4651.2 115.14,138.6 PC4631.1 114.48,137.82 PR4648.2 ; PR4649.2 113.55,141.17 112.87,141.46 v1(112.77,141.42) 112.17,140.82 PR4652.2 ; PR4701.2 113.64,137.07 113.64,137.71 PC4634.1 113.82,137.78 114.43,137.78 PR4648.2 ; PR4648.2 114.49,137.79 114.49,137.66 115,137.15 v1(115.33,137.15)
  L3 w0.203: v1(112.77,141.42) 112.77,141.31 111.66,140.2 111.59,140.2 111.53,140.14 104.4,140.14 103.61,139.35 103.47,139.35 96.98,132.85 96.98,120.74 v1(97.59,120.12)
  L4 w0.203: v1(112.77,141.42) 112.6,141.25 112.6,141.18 112.24,140.32 112.24,139.34 113.25,138.33 114.25,138.33 115.33,137.25 v1(115.33,137.15)
  BOTTOM w0.203: v2(112.88,142.14) 112.88,141.52 v1(112.77,141.42) ; v1(97.59,120.12) 97.71,120.01 97.71,119.37 98.58,118.5 PR4650.1
PWR_VCORE_ISUMN_G: length 32.5
  TOP w0.203: PR4701.1 112.84,136.82 113.09,136.57 113.09,135.81 113.03,135.75 113.03,135.72 v1(113.06,135.72) 113.18,135.61 v2(113.62,135.61)
  L3 w0.203: v1(102.74,118.03) 102.59,118.18 102.59,118.18 102.57,118.2 101.18,118.2 99.6,119.78 99.6,127.63 106.14,134.17 112.41,134.17 113.35,135.1 113.35,135.5 113.13,135.72 v1(113.06,135.72)
  BOTTOM w0.127: v1(102.74,118.03) 103.14,118.03 PG4708.1
PWR_VCORE_ISUMN_P_1: length 2.8
  TOP w0.254: v2(112.68,140.69) 112.93,140.69 113.25,140.37 113.46,140.37 PR4649.1 113.57,139.62 PC4635.1 113.78,139.41 PC4652.1
PWR_VCORE_ISUMN_P_2: length 39.3
  TOP w0.254: v1(111.99,141.51) 111.96,141.51 111.96,141.49 111.4,140.93 PR4653.2
  L3 w0.254: v1(97.14,119.08) 96.37,119.85 96.37,133.11 103.22,139.96 103.36,139.96 104.15,140.75 104.78,140.75 111.28,140.75 111.96,141.43 111.96,141.51 v1(111.99,141.51)
  BOTTOM w0.254: PR4650.2 98.58,117.64 v1(97.14,119.08) ; v2(111.59,141.9) 111.96,141.53 111.96,141.51 v1(111.99,141.51)
PWR_VCORE_ISUMN_RC: length 1.8
  TOP w0.254: v2(116.79,140.36) 116.24,139.8 PC4632.1 115.48,139.8 PR4651.1
PWR_VCORE_ISUMNA: length 6.1
  TOP w0.254: PC4632.2 116.05,138.47 v1(115.91,138.33) 115.39,137.81 PR4648.1
  BOTTOM w0.203: 118.96,138.96 119.83,139.83 PU4601.20
  BOTTOM w0.254: 118.96,138.96 118.36,138.96 118.15,138.75 118.15,138.75 v2(117.71,138.31) 115.93,138.31 v1(115.91,138.33)
PWR_VCORE_ISUMP: length 15.6
  TOP w0.203: 111.4,138.31 112.17,138.31 PR4652.1 ; PC4652.2 112.86,137.85 PC4634.2 ; PC4652.2 112.86,139.41 PC4635.2 112.73,139.55 v1(112.73,140.05) ; PC4652.2 112.79,138.55 PR4652.1 ; PR4652.1 112.17,137.65 PR4708.2
  L4 w0.203: v1(118.77,138.45) 118.03,137.71 115.34,137.71 114.39,138.66 113.38,138.66 112.57,139.47 112.57,139.9 v1(112.73,140.05)
  BOTTOM w0.203: v1(112.73,140.05) 112.73,140.05 v2(113.12,139.66) ; v1(118.77,138.45) 118.97,138.45 119.04,138.52 119.07,138.52 119.78,139.23 120.16,139.23 120.36,139.43 PU4601.19
PWR_VCORE_ISUMP_G: length 32.8
  TOP w0.203: v1(102.79,118.66) 103.08,118.95 v2(103.37,118.95) ; v1(112.55,136.1) 112.52,136.1 112.52,136.39 112.31,136.6 PR4708.1
  L3 w0.203: v1(102.79,118.66) 102.66,118.53 101.32,118.53 99.93,119.92 99.93,127.49 106.27,133.84 112.55,133.84 113.68,134.97 113.68,135.79 113.22,136.26 112.71,136.26 v1(112.55,136.1)
  BOTTOM w0.127: PG4707.1 103.4,118.66 v1(102.79,118.66)
PWR_VCORE_NTC: length 3
  TOP w0.254: PR4662.1 121.82,138.27 v1(121.99,138.44)
  BOTTOM w0.203: PU4601.15 121.96,139.42 121.85,139.31 121.85,138.58 v1(121.99,138.44)
  BOTTOM w0.254: v1(121.99,138.44) 121.99,137.99 v2(122.1,137.88)
PWR_VCORE_NTC1: length 32
  TOP w0.254: PR4662.2 122.68,137.37 122.28,136.97 PR4655.2 122.07,136.76 122.02,136.72 v1(121.59,136.72)
  L4 w0.254: v1(121.59,136.72) 117.36,132.48 105.66,132.48 103.83,130.64 99.01,130.64 98.94,130.71 v1(98.93,130.71)
  BOTTOM w0.254: v1(98.93,130.71) 98.89,130.71 98.89,130.76 98.89,130.76 98.57,130.76 97.54,129.74 v2(97.54,127.63) PR4654.1
PWR_VCORE_PROG1: length 4.6
  TOP w0.254: v2(118.95,145.85) 119.36,146.26 v1(119.39,146.26) 119.39,146.24 119.55,146.24 119.87,145.92 120.31,145.92 120.83,145.4 PR4629.1
  BOTTOM w0.203: PU4601.32 120.36,145.19
  BOTTOM w0.254: 120.36,145.19 119.39,146.16 v1(119.39,146.26)
PWR_VCORE_PROG2: length 5.8
  TOP w0.254: v1(118.57,146.41) 118.52,146.35 118.52,145.67 118.99,145.2 v2(118.99,144.58) 119.36,144.58 120.03,145.25 PR4628.1
  BOTTOM w0.254: PU4601.31 119.96,144.87 118.57,146.26 v1(118.57,146.41)
PWR_VCORE_PWM: length 18.2
  TOP w0.381: v2(118,139.94) v1(118.41,140.35)
  L3 w0.508: v1(118.41,140.35) 118.1,140.35 116.59,138.85 116.59,136.3 112.13,131.83 109.22,131.83 v1(108.13,130.74)
  BOTTOM w0.203: PU4601.22 118.98,140.82 118.51,140.35 v1(118.41,140.35)
  BOTTOM w0.508: v1(108.13,130.74) 107.93,130.55 PR4702.2
PWR_VCORE_PWM_R:
  vias: v2(107.32,128.22)
PWR_VCORE_RTN: length 8.1
  TOP w0.254: PC4637.1 120.86,140.2 PR4659.1 119.93,139.93 119.93,138.66 v1(119.85,138.58) 119.82,138.58 119.42,138.98 118.54,138.98 118.23,138.67 v2(118.11,138.67) 117.8,138.36 PR4668.2 117.8,137.07 PC4642.1
  BOTTOM w0.203: PU4601.18 120.76,139.3 120.4,138.94
  BOTTOM w0.254: 120.4,138.94 120.1,138.64 119.91,138.64 v1(119.85,138.58)
PWR_VCORE_SCLK: length 4.6
  TOP w0.191: v1(123.26,146.31) 124.26,147.32 PR4624.2
  BOTTOM w0.191: PU4601.37 122.36,145.13 123,145.77 123,146.05 v1(123.26,146.31) v2(123.12,146.92)
PWR_VCORE_SDIO: length 3.7
  TOP w0.191: v2(122.31,145.82) v1(121.7,146.33) 121.7,146.58 121.99,146.87 PR4622.2
  BOTTOM w0.191: v1(121.7,146.33) 121.56,146.19 PU4601.35
PWR_VCORE_SNB: length 3.1
  BOTTOM w0.635: v2(97.37,123.17) 98.01,122.53 PR4703.2 98.88,122.67 PC4706.1
PWR_VCORE_SW: length 2.5
  BOTTOM w0.635: PR4703.1 101.53,119.84
  vias: v2(101.1,123.65)
PWR_VCORE_VCC: length 5.7
  TOP w0.508: PC4607.1 121.62,145.22 121.62,145.51 120.83,146.31 v1(120.83,146.4) 120.83,146.56 120.94,146.67 PR4610.2
  BOTTOM w0.203: v2(121.84,147.14) v1(120.83,146.4) 120.83,146.2 121.16,145.86 PU4601.34
PWR_VCORE_VCC_R: length 2.2
  BOTTOM w0.203: PU4701.2 105.4,123.65 105.98,123.08 PC4708.1
  BOTTOM w0.508: PR4704.2 PC4708.1
PWR_VCORE_VIN: length 6.5
  TOP w0.254: v1(120.08,146.43) 119.75,146.76 119.6,146.76 119.6,146.76 119.3,146.76 118.83,147.24 PC4606.1
  TOP w0.508: PC4606.1 118.76,147.34 117.73,147.34 v2(117.67,147.4) 117.4,147.4 116.9,147.9 PR4612.2
  BOTTOM w0.127: 120.76,145.5 PU4601.33
  BOTTOM w0.254: v1(120.08,146.43) 120.08,146.17 120.76,145.5
PWR_VCORE_VRHOT#: length 4.8
  TOP w0.254: PR4607.2 125.63,147.33 124.64,146.34 124.35,146.34 v1(124.33,146.36)
  BOTTOM w0.203: PU4601.38 122.76,145 v2(123.5,145.73) 124.13,146.36 v1(124.33,146.36)
PWR_VDDQ_BOOT: length 3
  TOP w0.203: 38.82,25.51 38.82,25.21 39.17,24.86 PU5101.18
  TOP w0.508: PR5112.1 39.36,26.32 38.82,25.77 v2(38.82,25.76) 38.82,25.76 38.82,25.51
PWR_VDDQ_BOOT_A: length 3.3
  TOP w0.508: PC5108.1 40.66,28.95 40.36,29.25 v2(39.97,29.25) 39.58,29.25 39.36,29.03 PR5112.2
PWR_VDDQ_CS: length 2.6
  TOP w0.203: 41.53,22.43 41.31,22.65 PU5101.13
  TOP w0.254: PR5114.1 42.8,23.23 42,22.43 v2(41.93,22.43) 41.53,22.43
PWR_VDDQ_EN: length 3.6
  TOP w0.203: 39.17,20.43 PU5101.8
  TOP w0.254: PR5128.2 40.96,18.81 40.15,18.81 PC5106.1 40.15,19.49 v2(39.9,19.74) 39.86,19.74 39.17,20.43
PWR_VDDQ_FB: length 6.5
  TOP w0.203: PU5101.6 38.37,20.76 37.8,20.2 37.34,20.2
  TOP w0.254: PR5117.1 37.38,18.82 37.08,18.52 36.72,18.52 36.71,18.5 PC5115.2 35.92,19.12 PR5116.2 36.53,19.35 v2(36.63,19.44) 36.67,19.49 36.67,19.52 37.34,20.2
PWR_VDDQ_HG: length 15.5
  TOP w0.356: v4(51.76,26.78) v2(51.76,26.01)
  L4 w1.016: v4(39.57,25.42) 39.57,26.43 41.19,28.05 51.02,28.05 51.76,27.3 v4(51.76,26.78)
PWR_VDDQ_LG: length 4.6
  TOP w0.356: v2(45.04,23.27) 44.5,22.73 v4(44.5,22.53)
  L3 w1.016: v4(44.5,22.53) 43.08,23.96 v4(41.44,23.96)
PWR_VDDQ_PG: length 219.7
  TOP w0.127: v1(43.14,17.22) 43.14,18.31 PR5111.2 42.65,18.92 41.33,20.23 40.95,20.23 40.43,20.76 40.17,20.76 39.97,20.96 PU5101.10 ; v1(185.66,42.9) 185.19,42.9 184.69,43.4 184.44,43.65 179.36,43.65 176.38,40.67 v2(175.8,40.67) v1(174.97,40.67)
  L3 w0.127: v1(53.67,17.57) 54.43,17.57 56.54,15.46 61.47,15.46 63.7,13.24 128.59,13.24 129.09,13.74 132.5,13.74 133.64,12.61 135.53,12.61 138.83,9.31 150.48,9.31 156.2,3.59 158.35,3.59 158.39,3.55 160.01,3.55 160.28,3.82 166.31,3.82 166.35,3.78 173.94,3.78 176.12,5.95 178.67,5.95 179.46,5.16 188.09,5.16 194.78,11.86 194.78,31.05 190.37,35.45 189.02,35.45 185.33,39.14 185.33,42.57 v1(185.66,42.9)
  BOTTOM w0.127: v1(53.67,17.57) 53.67,16.13 52.56,15.02 50.07,15.02 49.02,16.06 44.29,16.06 v1(43.14,17.22) ; v1(174.97,40.67) 174.97,40.94 175.46,41.43 R4011.1
PWR_VDDQ_PH: length 10.9
  TOP w0.356: v4(50.49,26.78) v2(50.49,27.62)
  L4 w1.016: v4(50.49,26.78) 41.71,26.78 v4(40.84,25.9)
  vias: v2(40.65,25.22) v4(48.44,25.72)
PWR_VDDQ_SNUB:
  vias: v2(48.54,23.95)
PWR_VDDQ_TON: length 3.7
  TOP w0.203: 39.57,20.6 PU5101.9
  TOP w0.254: 39.57,20.6 39.9,20.27 40.25,20.27 40.82,19.71 41.23,19.71 ; 41.23,19.71 41.81,19.12 PR5113.2 ; 41.23,19.71 v2(41.23,19.71)
PWR_VDDQ_VDD: length 6.2
  TOP w0.203: PU5101.12 41.21,22.25 41.46,21.99 41.7,21.99
  TOP w0.254: PR5109.1 44.73,21.44 v2(44.73,21.66) 43.63,21.66 42.89,22.4 PC5107.1 42.73,22.4 42.32,21.99 41.7,21.99
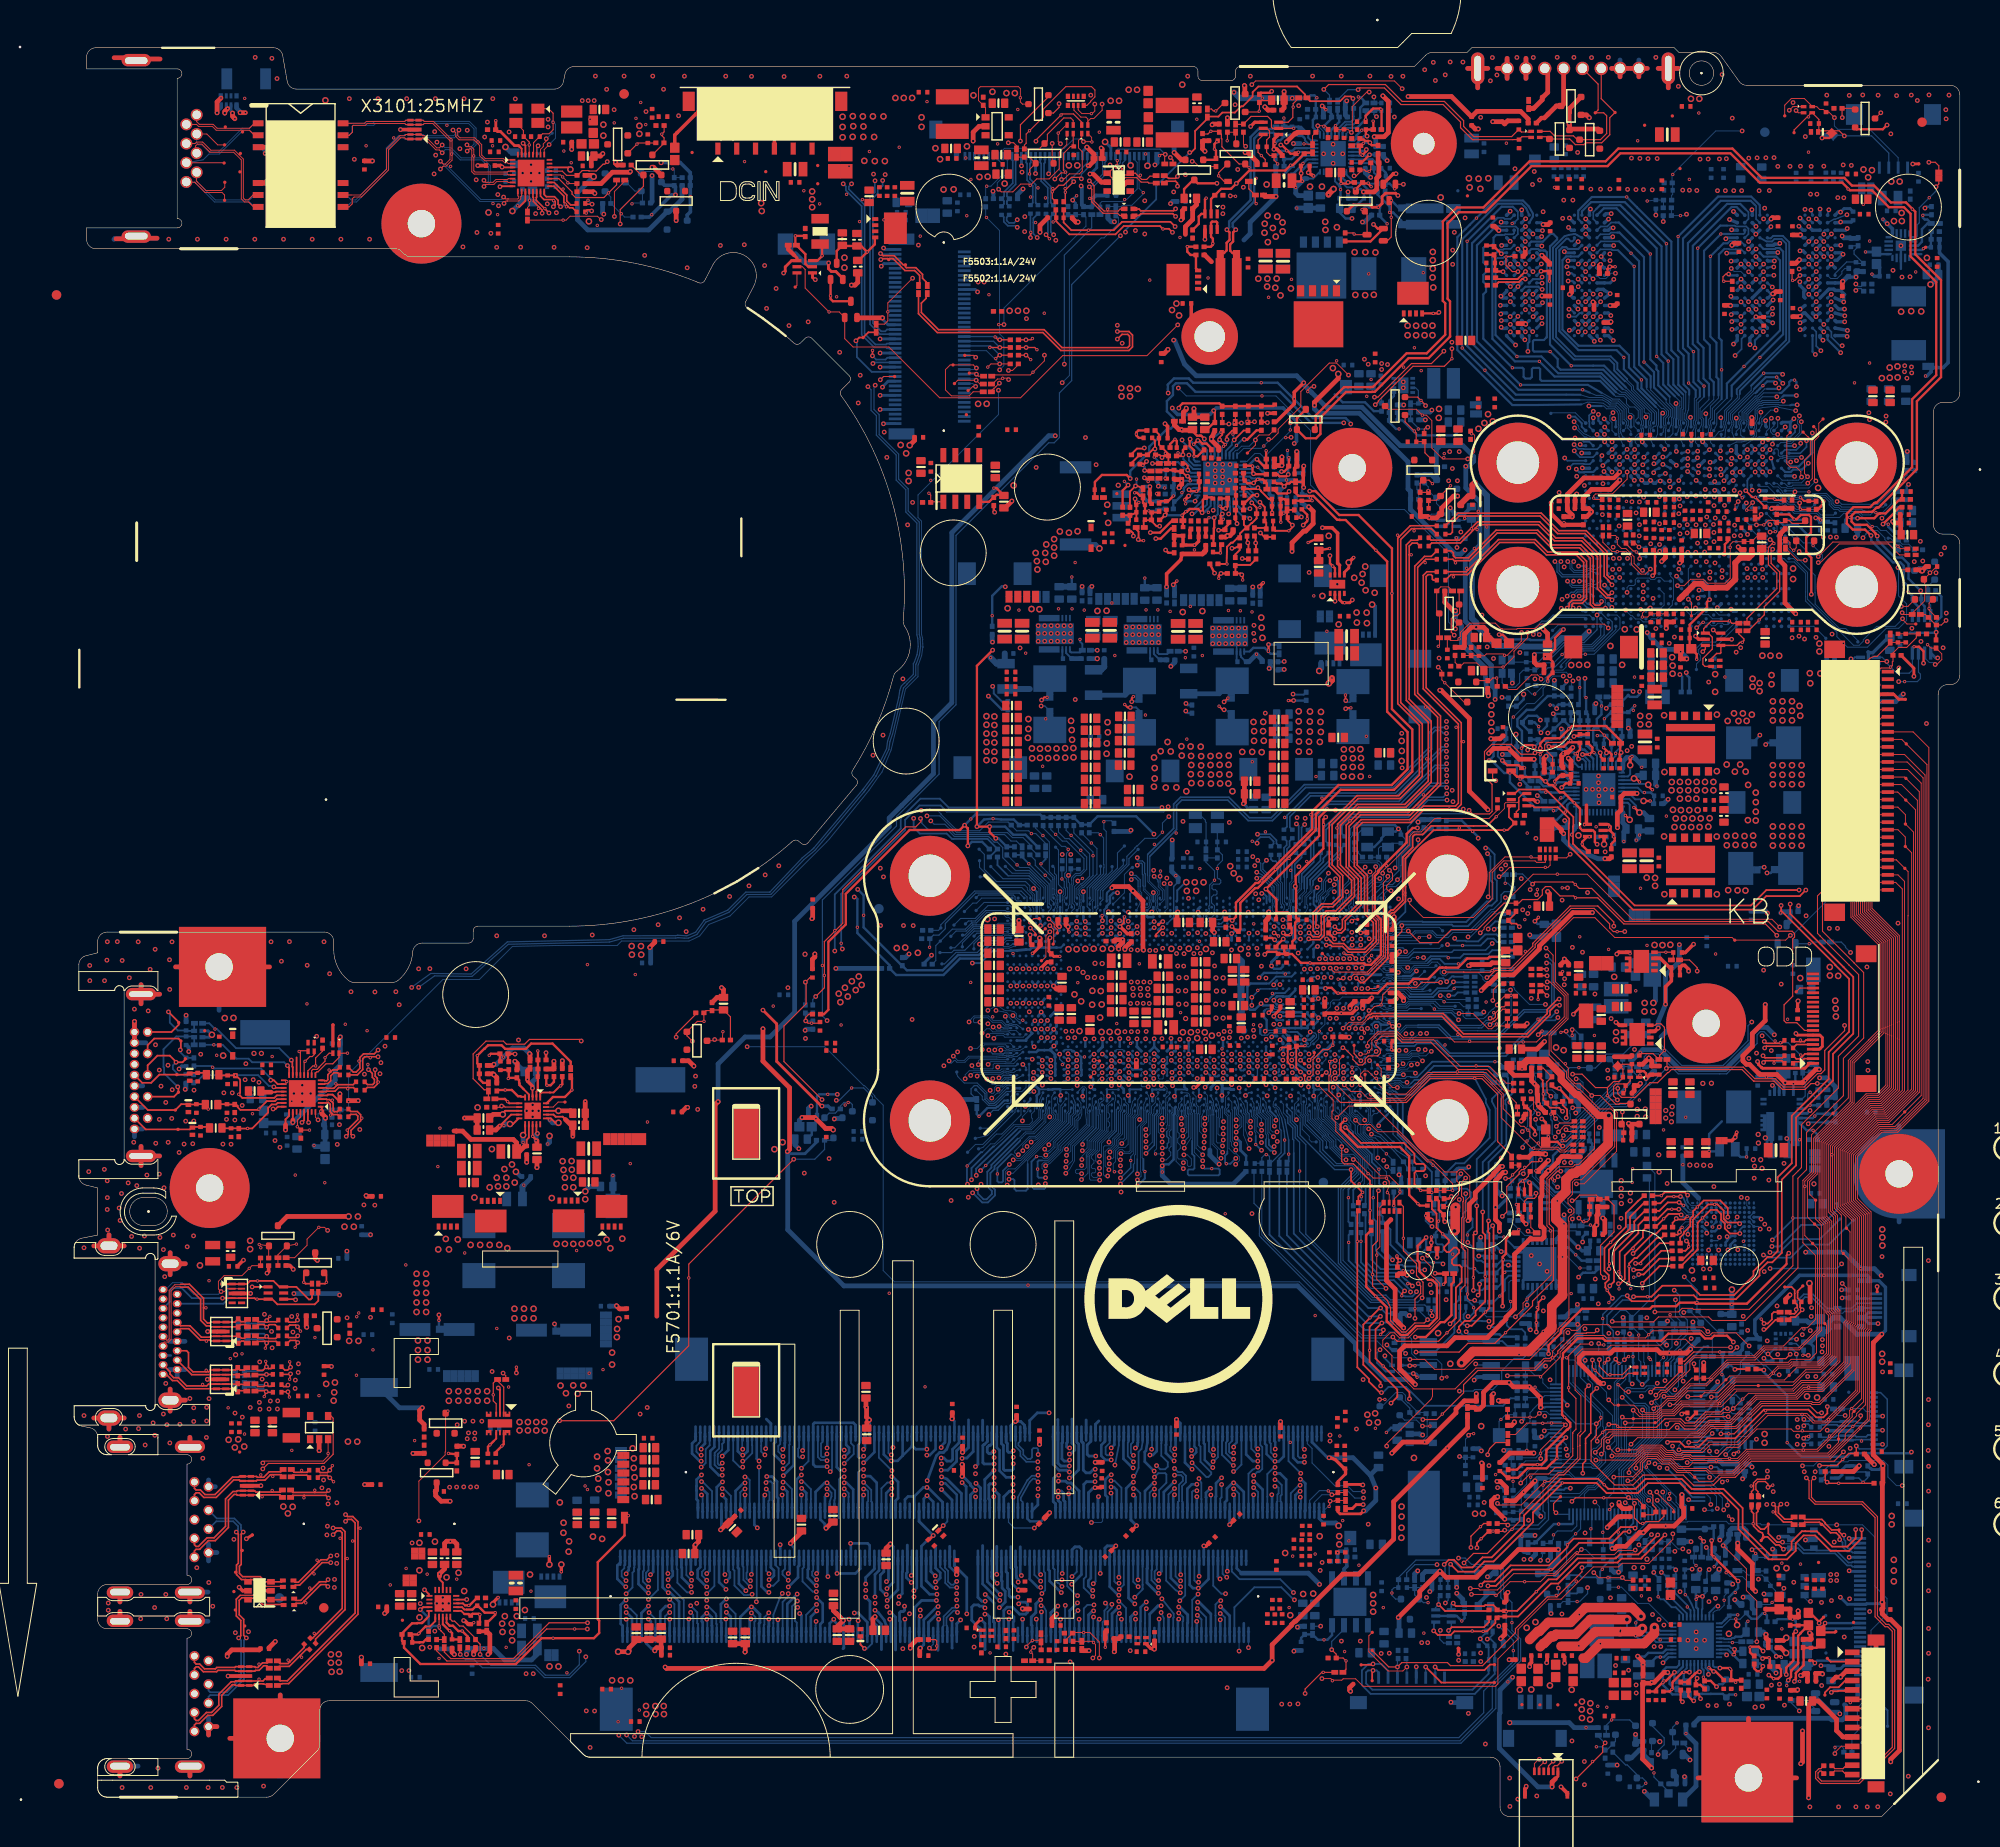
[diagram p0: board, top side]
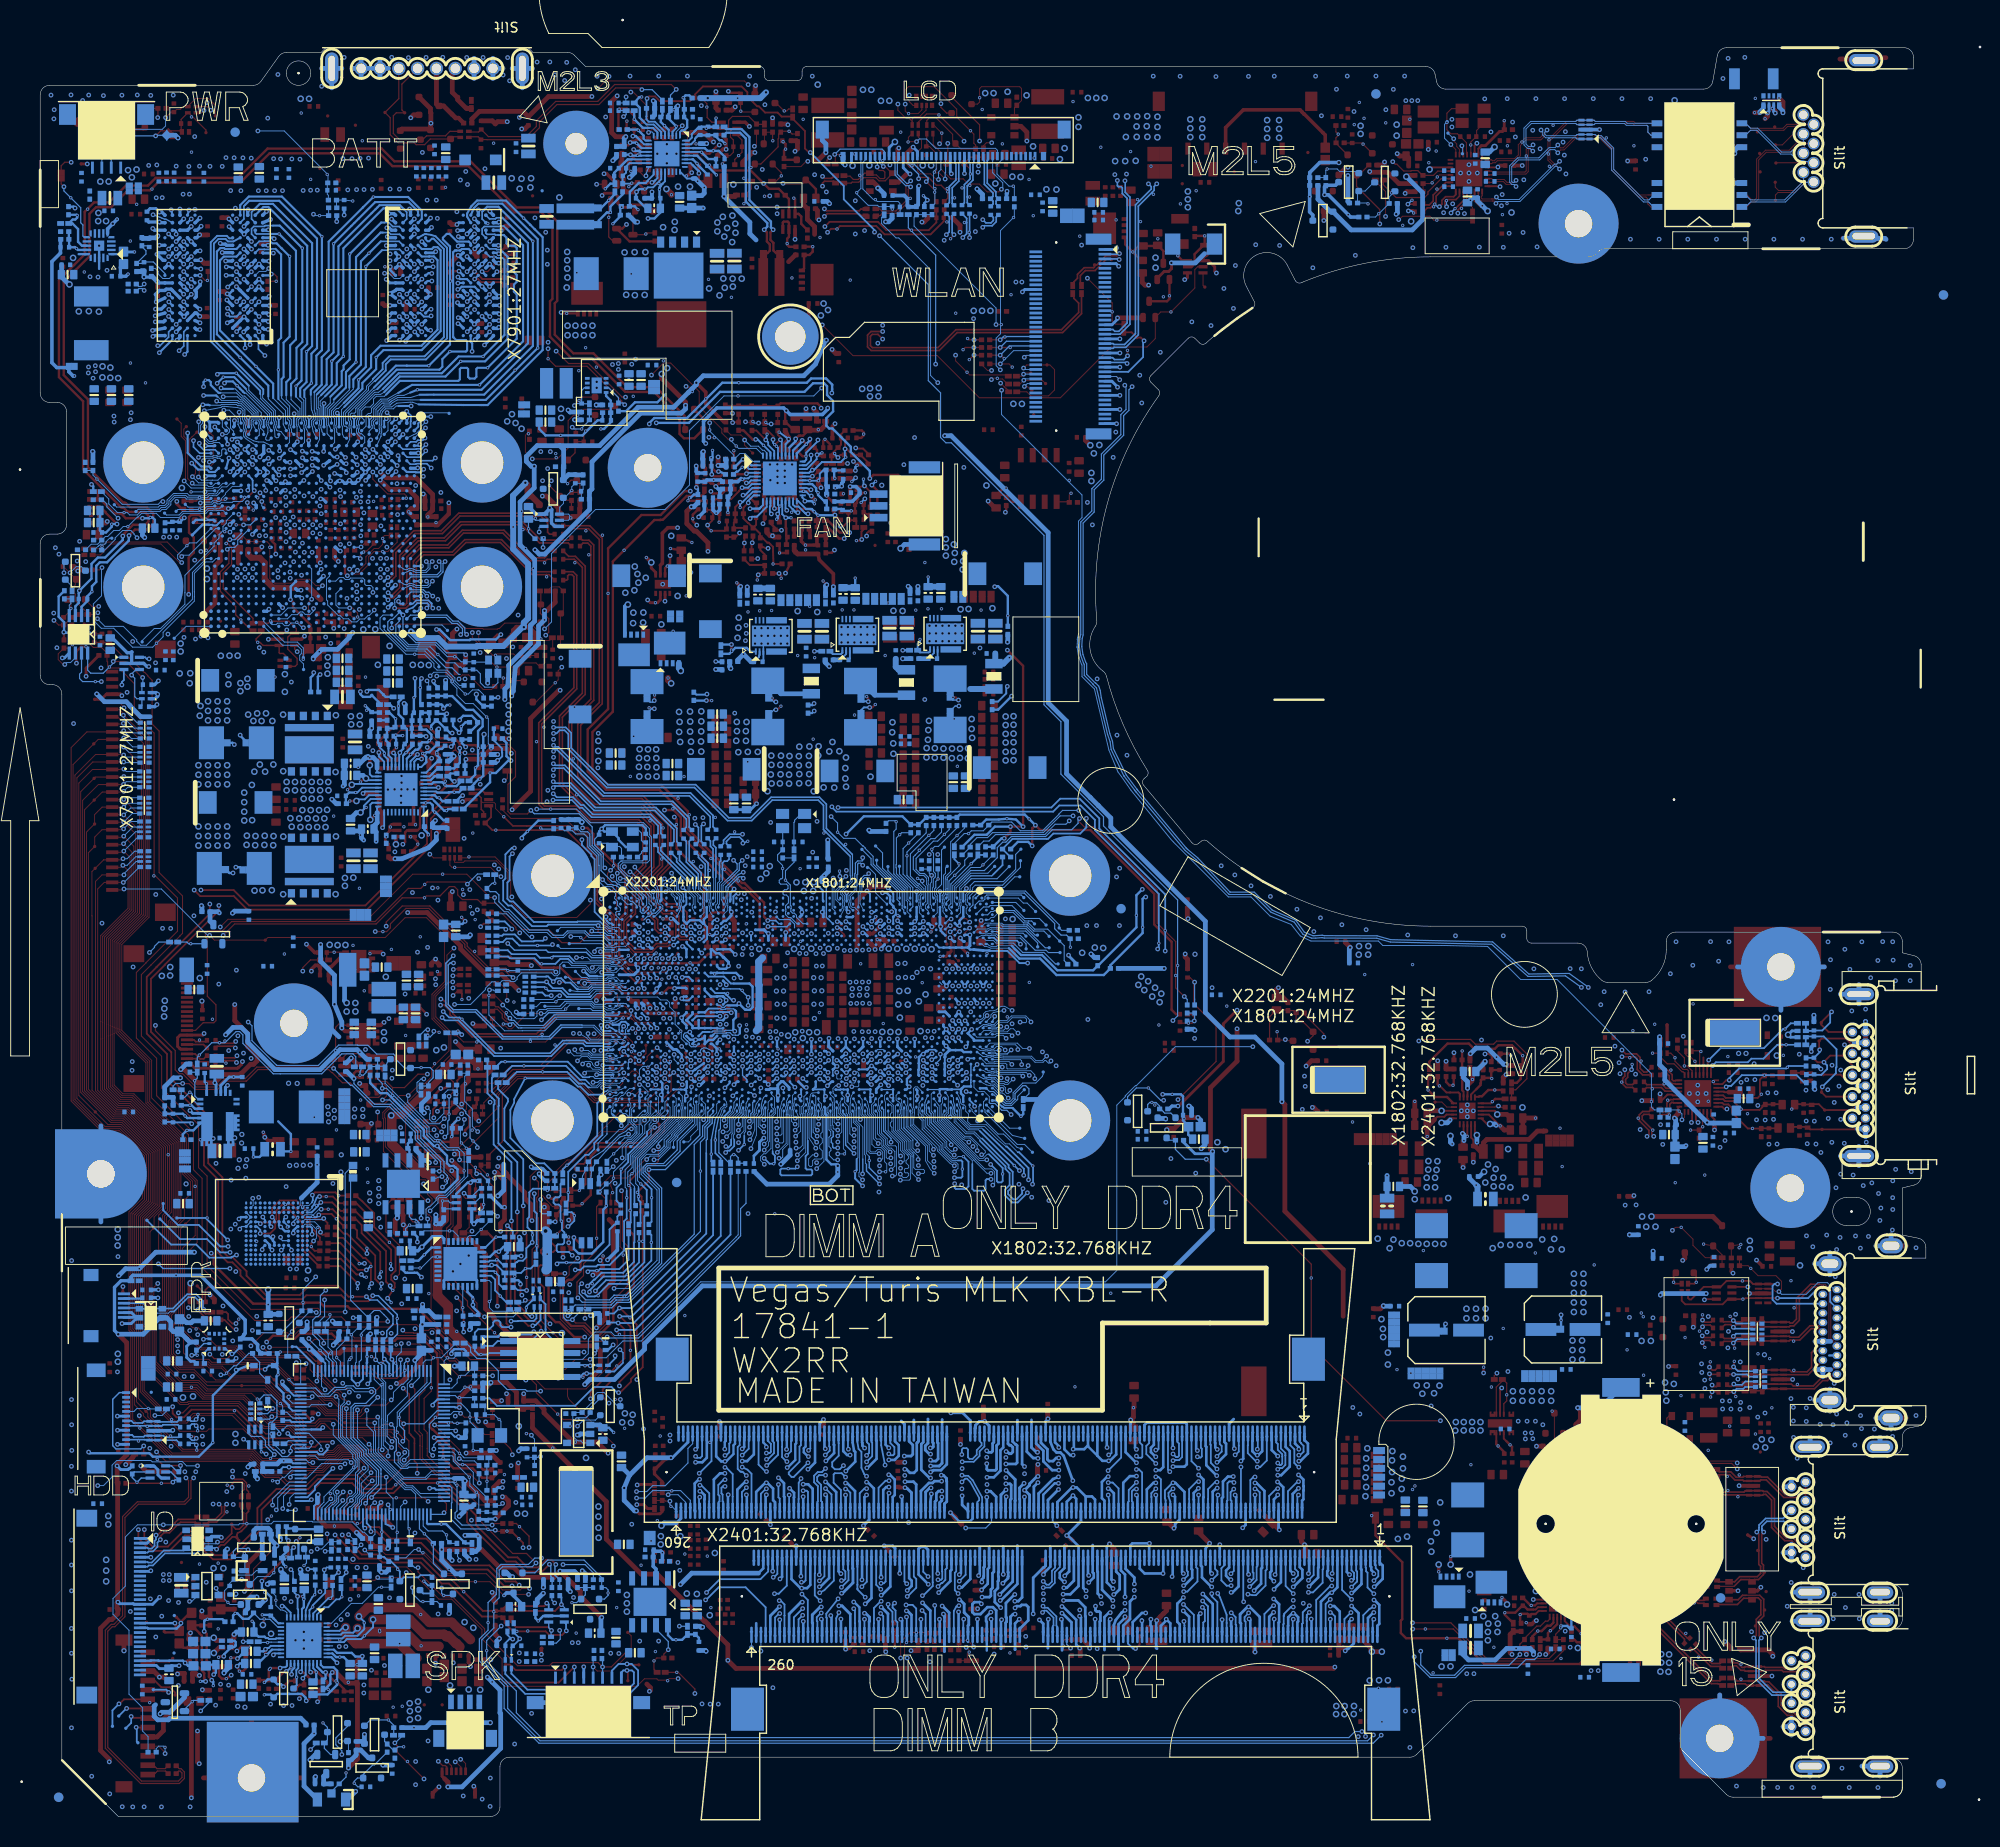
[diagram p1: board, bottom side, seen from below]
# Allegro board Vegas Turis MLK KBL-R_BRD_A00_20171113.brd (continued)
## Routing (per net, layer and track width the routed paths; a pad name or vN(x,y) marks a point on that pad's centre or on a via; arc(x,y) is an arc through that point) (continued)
PWR_VDDQ_VDDQ: length 41.8
  TOP w0.203: 37.46,21.05 37.68,21.27 PU5101.5
  TOP w0.254: 37.46,21.05 37.06,20.65 37.04,20.65 36.95,20.55 36.45,20.55 36.43,20.53 35.91,20.53 34.84,19.46 PR5116.1 34.84,18.68 PC5115.1 35.05,18.46 35.05,17.94 36.78,16.21 46.93,16.21 49.67,18.94 v2(50.89,18.94) 55.23,18.94 55.79,19.5 55.79,20.81 55.63,20.97 55.63,27.03 58.48,29.87 PG5101.1
PWR_VDDQ_VID: length 3.7
  TOP w0.203: PU5101.11 41.13,21.85 41.47,21.51
  TOP w0.254: 41.47,21.51 41.89,21.51 42.06,21.34 PC5102.1 42.33,21.54 43.02,21.54 v2(43.11,21.46) 43.11,20.64 PR5107.1
PWR_VDDQ_VLDOIN:
  vias: v2(37.51,25.75)
PWR_VDDQ_VTT:
  vias: v2(33.59,24.61)
PWR_VDDQ_VTTREF: length 4.7
  TOP w0.203: v1(36.78,21.99) 36.82,21.99 37.08,22.25 PU5101.4
  BOTTOM w0.254: v1(36.78,21.99) 37.66,21.11 PC5116.1 37.66,19.98 37.84,19.98 38.11,20.25 38.59,20.25 v2(38.8,20.05)
PWR_VGA_CORE__BOOT1_1: length 2.5
  BOTTOM w0.508: PC8510.1 168.03,109.65 v2(168.17,109.51)
  BOTTOM w0.635: PR8515.2 168.03,111.94 PC8510.1
PWR_VGA_CORE__BOOT2_1: length 2.5
  BOTTOM w0.508: PC8507.1 166.4,104.75 PR8507.2 166.2,104 v2(165.98,103.77)
PWR_VGA_CORE_BOOT1: length 3.9
  BOTTOM w0.203: PU8501.21 164.56,111.1 164.56,111.4
  BOTTOM w0.508: 164.56,111.4 164.56,112.15 164.96,112.55 165.42,112.55 v2(165.52,112.65) 165.57,112.6 165.71,112.6 165.88,112.44 165.88,112.44 166.38,111.94 PR8515.1
PWR_VGA_CORE_BOOT2: length 4
  BOTTOM w0.203: 164.56,106.69 164.56,107.19 PU8501.30
  BOTTOM w0.508: v2(164.65,103.64) 164.65,104.65 164.88,104.88 PR8507.1 164.88,105.29 164.54,105.63 164.54,106.68 164.56,106.69
PWR_VGA_CORE_COMP: length 4.6
  BOTTOM w0.203: 164.24,113.91 164.24,113.6 163.78,113.14 v2(163.78,112.99) 163.78,112.74 163.4,112.36 PU8501.19
  BOTTOM w0.254: PC8515.2 164.46,115.47 PR8528.1 164.46,114.13 PC8514.2 164.24,113.91
PWR_VGA_CORE_COMP_1: length 1.8
  BOTTOM w0.254: v2(165.81,118.05) PC8516.1 165.09,117.34 PR8527.2
PWR_VGA_CORE_EN_R#: length 4.4
  TOP w0.254: 163.26,104.72 163.57,104.41 v2(163.57,104.12) 163.68,104.01 163.68,103.72 163.32,103.37 PR8539.2 ; 163.26,104.72 163.26,105.22 163.02,105.46 PQ8501.6 ; 163.26,104.72 163.17,104.81 PQ8501.5
PWR_VGA_CORE_ENABLE: length 1.9
  BOTTOM w0.203: 158.87,110.15 PU8501.8
  BOTTOM w0.254: 158.87,110.15 158.44,110.57 PR8514.2
PWR_VGA_CORE_FB: length 7.3
  BOTTOM w0.203: PU8501.18 163,112.46 163.34,112.8 163.34,113.52
  BOTTOM w0.254: 163.34,113.52 163.34,113.9 PC8514.1 163.33,114.07 163.61,114.35 PR8523.2 163.51,114.93 163.51,115.63 PR8526.2 162.78,115.65 PR8525.1 162.59,115.85 v2(162.59,116.67) 163.25,117.34 PR8527.1
PWR_VGA_CORE_FB2_R: length 0.8
  BOTTOM w0.254: PC8515.1 164.28,116.52 PR8526.1
PWR_VGA_CORE_FB_R: length 1.9
  BOTTOM w0.254: PC8513.1 162.53,114.51 162.75,114.73 PR8523.1 162.69,114.88 v2(161.83,114.88)
PWR_VGA_CORE_IMON: length 4.5
  BOTTOM w0.203: PU8501.10 159.34,110.95 158.92,111.36
  BOTTOM w0.254: PC8511.1 157.67,113.47 157.94,113.47 158.21,113.2 v2(158.21,113.07) 158.21,112.81 157.92,112.52 PR8516.1 158.1,112.18 158.92,111.36
PWR_VGA_CORE_IMON_NB: length 3.6
  BOTTOM w0.203: PU8501.2 158.91,107.75 158.74,107.58
  BOTTOM w0.254: PR8508.2 157.14,105.88 157.5,105.88 158.35,106.73 158.42,106.73 v2(158.44,106.76) 158.64,106.95 158.64,107.48 158.74,107.58
PWR_VGA_CORE_ISEN1: length 13.1
  TOP w0.254: v1(160.26,112.88) v2(161,112.88) 161.32,113.2 161.32,113.61 PC8518.1
  L3 w0.254: v1(160.26,112.88) 160.81,113.43 160.81,115.72 159.33,117.21 v1(157.16,117.21)
  BOTTOM w0.203: v1(160.26,112.88) 160.27,112.88 161,112.15 PU8501.13
  BOTTOM w0.254: PR8519.1 158.08,117.2 157.26,117.2 157.25,117.21 v1(157.16,117.21) 157.35,117.02 PR8543.1
PWR_VGA_CORE_ISEN2: length 8.7
  TOP w0.254: v2(159.71,112.99) 159.74,112.99 ; 159.74,112.99 159.74,112.99 159.74,112.98 159.74,112.49 v1(159.84,112.4) ; 159.74,112.99 159.74,113.12 159.99,113.37 PC8517.1 159.99,114.13 159.94,114.18 158.75,114.18 158.28,113.71 v1(156.69,113.71)
  BOTTOM w0.203: v1(159.84,112.4) 160.32,112.4 160.6,112.11 PU8501.12
  BOTTOM w0.254: v1(156.69,113.71) 156.41,113.99 PR8522.1 156.96,114.46 PR8538.1
PWR_VGA_CORE_ISUMN: length 2.8
  BOTTOM w0.203: PU8501.15 161.8,112.75 161.7,112.86
  BOTTOM w0.254: 161.7,112.86 161.48,113.07 v2(161.48,113.07) 160.8,113.76 PR8536.2
PWR_VGA_CORE_ISUMP: length 9.9
  BOTTOM w0.203: 161.4,112.43 PU8501.14
  BOTTOM w0.254: 161.4,112.43 160.77,113.06 160.77,113.09 160.47,113.39 160.25,113.39 159.98,113.65 PC8522.1 159.98,113.95 159.77,114.17 159.19,114.17 v2(159.01,114.35) 158.79,114.58 158.79,114.98 159.33,115.52 159.82,115.52 PC8523.1 159.96,116.46 PR8532.1 159.98,117.17 PR8529.1 PR8517.1 159.01,116.61 PR8537.1
PWR_VGA_CORE_LGATE1: length 11.6
  TOP w0.254: v2(167.69,109.13) 167.64,109.13 167.25,109.53 v4(167.25,109.66)
  L4 w1.016: v4(174.53,111.1) 169.06,111.1 v4(168.97,111.02) 168.47,111.02 167.25,109.79 v4(167.25,109.66)
  BOTTOM w0.203: PU8501.24 167.16,109.75 v4(167.25,109.66)
PWR_VGA_CORE_LGATE2: length 13.9
  TOP w0.254: v4(166.75,107.94) v2(167.45,107.94)
  L4 w1.016: v4(166.75,107.94) 166.79,107.98 167.24,107.98 168.93,106.29 v4(168.93,104.17) 170.26,104.15 v4(174.52,104.15)
  BOTTOM w0.203: PU8501.27 165.42,108.55 165.85,108.11 166.57,108.11 v4(166.75,107.94)
PWR_VGA_CORE_LGATE_NB:
  vias: v2(160.98,104.12)
PWR_VGA_CORE_NTC: length 3.8
  BOTTOM w0.203: 159.49,111.91 159.85,111.55 PU8501.11
  BOTTOM w0.254: 159.49,111.91 159.33,112.06 159.33,112.61 159.48,112.76 v2(159.48,112.94) 159.31,113.12 159.01,113.12 PR8524.1
PWR_VGA_CORE_NTC_NB: length 3.2
  BOTTOM w0.203: 159.6,106.56 PU8501.1
  BOTTOM w0.254: 159.6,106.56 159.6,105.29 PR8506.2 159.52,104.87 159.11,104.45 v2(159.11,104.33)
PWR_VGA_CORE_PGOOD: length 17.4
  TOP w0.254: v1(155.78,113.55) 155.78,114.06 156.32,114.6 157.84,114.6 159.14,115.9 162.76,115.9 164.3,114.35 PR8520.1 164.28,114.03 164.28,113.18 v1(164.37,113.08) 164.2,112.92 PC8512.1
  BOTTOM w0.203: v1(164.37,113.08) 164.37,112.68 163.8,112.11 PU8501.20
  BOTTOM w0.254: PR8544.2 156.37,111.4 PR8518.2 155.78,111.99 v2(155.78,112.87) v1(155.78,113.55)
PWR_VGA_CORE_PH1: length 29.4
  L4 w0.254: v1(179.1,114.94) 179.15,114.99 179.15,117.48 178.3,118.33 167.77,118.33 167.11,117.68 165.36,117.68 164.42,116.74 161.5,116.74 160.56,117.68 157.59,117.68 v1(157.51,117.76)
  BOTTOM w0.254: PR8517.2 158.2,118.18 PR8519.2 158.18,118.19 157.72,118.19 157.59,118.07 157.59,117.83 v1(157.51,117.76) 157.13,118.13 v2(156.82,118.13) ; v1(179.1,114.94) 179.1,114.89 178.53,114.31 PG8507.1
PWR_VGA_CORE_PH2: length 41
  L4 w0.254: v1(179.56,100.89) 179.12,100.45 179.12,99.09 177.51,97.48 175.63,97.48 175.11,96.97 168.36,96.97 167.57,97.77 166.13,99.2 166.13,101.43 160.02,107.54 160.02,110.38 159.98,110.42 159.98,110.54 157.74,112.78 157.74,114.23 156.81,115.15 v1(156.57,115.15)
  BOTTOM w0.254: v1(156.57,115.15) 156.79,115.15 PR8538.2 157.28,115.6 158.17,116.49 PR8537.2 158.8,115.96 v2(158.8,115.61) ; v1(179.56,100.89) 179.13,100.89 PG8509.1
PWR_VGA_CORE_PHASE1: length 15.7
  TOP w0.254: v4(165.73,110.33) 165.94,110.33 v2(166.32,109.95)
  L4 w1.016: v4(165.73,110.33) 171.18,115.78 175.02,115.78 v4(175.68,116.44)
  BOTTOM w0.203: PU8501.23 165.55,110.15 v4(165.73,110.33)
  BOTTOM w0.508: v4(165.73,110.33) 166.06,110.66 PC8510.2
  vias: v4(175.58,111.81) v4(176.36,117.25) v4(176.45,111.05) v4(176.83,116.44) v4(177.01,111.81) v4(177.3,117.25) v4(177.6,111.05) v4(177.7,116.45) v4(178.25,117.11)
PWR_VGA_CORE_PHASE2: length 19.4
  TOP w0.254: v4(166.31,106.71) 165.77,107.25 v2(165.72,107.25)
  L4 w1.016: v4(166.31,106.71) 167.42,105.6 167.42,103.74 170.34,100.83 170.34,100.15 171.19,99.3 174.54,99.29 175.23,99.29 175.74,98.79 v4(175.74,98.45)
  BOTTOM w0.203: v4(166.31,106.71) 165.96,107.06 165.96,107.43 165.24,108.15 PU8501.28
  BOTTOM w0.508: v4(166.31,106.71) 166.34,106.68 166.76,106.68 PC8507.2
  vias: v4(175.56,104.2) v4(175.59,103.23) v4(176.49,104.24) v4(176.53,103.26) v4(176.73,98.44) v4(177.47,104.21) v4(177.51,103.23) v4(177.57,98.41) v4(178.39,104.25) v4(178.42,103.27)
PWR_VGA_CORE_PWROK: length 2.1
  BOTTOM w0.203: 158.75,110.77 158.97,110.55 PU8501.9
  BOTTOM w0.254: 158.75,110.77 158.12,111.4 PR8544.1
PWR_VGA_CORE_RTN: length 9.1
  TOP w0.254: v2(162.49,113.6) 162.81,113.29 v1(162.81,113.05) 162.91,113.15 163.09,113.15 163.34,112.9 PC8501.1
  L3 w0.254: v1(162.78,117.78) 162.78,113.07 v1(162.81,113.05)
  BOTTOM w0.203: 162.6,112.84 PU8501.17
  BOTTOM w0.254: v1(162.81,113.05) 162.6,112.84 ; PR8530.1 163.18,118.18 v1(162.78,117.78)
PWR_VGA_CORE_SVC: length 3.9
  BOTTOM w0.203: 158.48,107.95 158.68,108.15 PU8501.3
  BOTTOM w0.254: PR8509.2 157.01,107.07 v2(157.18,106.9) 157.43,106.9 158.48,107.95
PWR_VGA_CORE_SVD: length 4.4
  BOTTOM w0.203: PU8501.5 158.3,108.95 158.18,108.83
  BOTTOM w0.254: 158.18,108.83 156.94,108.83 156.9,108.87 v2(156.36,108.87) 155.85,108.87 PR8512.2
PWR_VGA_CORE_SVT: length 4.5
  BOTTOM w0.203: 158.73,109.75 PU8501.7
  BOTTOM w0.254: PR8513.2 155.65,109.99 156.12,109.51 157.21,109.51 v2(157.34,109.65) 157.62,109.92 158.56,109.92 158.73,109.75
PWR_VGA_CORE_UGATE1: length 15.2
  TOP w0.356: v4(165.33,111.74) v2(165.33,112.52)
  L4 w1.016: v4(165.33,111.74) 168.93,115.34 v4(168.93,117.05) 174.47,117.05 v4(174.54,117.12)
  BOTTOM w0.203: PU8501.22 165.1,110.55 165.33,110.77 v4(165.33,111.74)
PWR_VGA_CORE_UGATE2: length 18.2
  TOP w0.254: v4(165.28,105.94) 164.84,106.37 164.84,106.4 v2(164.81,106.4)
  L4 w1.016: v4(174.54,98.02) v4(168.96,98.03) 168.96,100.4 166.15,103.21 166.15,105.06 v4(165.28,105.94)
  BOTTOM w0.203: PU8501.29 165.07,107.75 165.28,107.54 v4(165.28,105.94)
PWR_VGA_CORE_UGATE_LX_NB:
  vias: v2(163.14,105.17)
PWR_VGA_CORE_VDD: length 4.7
  BOTTOM w0.203: v2(166.84,108.83) 166.65,108.83 166.14,109.35 PU8501.25
  BOTTOM w0.254: PR8510.2 167.87,107.7 PC8509.1 167.52,108.83 v2(166.84,108.83)
PWR_VGA_CORE_VDDIO: length 30.5
  TOP w0.254: PC8503.2 158.49,109.81 v1(158.05,109.37)
  TOP w0.305: PC8503.2 159.04,109.91 PR8505.2 158.19,110.66 PR8546.2 157.93,110.66 v2(157.3,110.03)
  L3 w0.254: v1(151.75,112.88) 151.75,114.76 151.83,114.85 151.83,115.6 151.83,115.6 151.83,118.82 v1(151.7,118.95)
  L4 w0.254: v1(158.55,120.67) 158.07,120.67 157.33,121.41 156.78,121.41 156.58,121.21 156.58,120.9 154.43,118.75 152.43,118.75 152.23,118.95 v1(151.7,118.95) ; v1(158.05,109.37) 156.66,110.76 153.49,110.76 152.25,112 152.25,112.46 151.96,112.75 151.87,112.75 v1(151.75,112.88)
  BOTTOM w0.203: PU8501.6 158.07,109.35 v1(158.05,109.37)
  BOTTOM w0.254: v1(151.7,118.95) 151.78,118.88 R7923.1 ; v1(158.55,120.67) 158.53,120.67 158.53,120.45 158.13,120.05 R7924.1
  BOTTOM w0.508: v1(151.75,112.88) 152.01,112.88 152.02,112.87 R7940.1
PWR_VGA_CORE_VO1: length 37.5
  TOP w0.254: v2(153.78,113.54) 154.11,113.87 154.95,113.87 v1(155.14,113.68)
  L4 w0.254: v1(179.73,113.93) 179.68,113.98 179.68,117.89 178.73,118.84 167.36,118.84 166.73,118.21 164.95,118.21 164.02,117.27 161.75,117.27 160.76,118.26 157.3,118.26 157,117.97 157,117.95 156.53,117.47 156.53,116.55 155.81,115.84 155.77,115.84 155.14,115.21 v1(155.14,113.68)
  BOTTOM w0.254: PG8508.1 179.91,114.12 v1(179.73,113.93) ; v1(155.14,113.68) 155.54,114.08 PR8522.2 155.53,114.47 PR8521.2
PWR_VGA_CORE_VO2: length 42.4
  L4 w0.254: v1(155.85,115.19) 156.06,114.97 156.06,114.94 156.36,114.65 156.39,114.65 156.61,114.43 156.78,114.43 157.21,114 157.21,112.47 159.51,110.17 159.51,107.23 165.12,101.63 165.12,99.36 168.11,96.37 174.87,96.36 175.02,96.36 175.3,96.36 175.52,96.58 175.76,96.82 177.57,96.82 179.86,99.11 v1(179.86,100.28)
  BOTTOM w0.254: PR8540.2 155.16,116.3 v2(155.61,115.85) 155.61,115.42 v1(155.85,115.19) 155.85,115.26 156.49,115.91 PR8543.2 ; PG8510.1 180.25,100.28 v1(179.86,100.28)
PWR_VGA_CORE_VR_HOT#: length 2.9
  BOTTOM w0.203: 158.73,108.55 PU8501.4
  BOTTOM w0.254: 158.73,108.55 158.44,108.55 158.16,108.27 v2(157.96,108.27) 157.59,107.9 PR8511.2
PWR_VGA_CORE_VSEN: length 9.3
  TOP w0.254: PC8524.1 162.2,112.62 162.2,112.99 162.14,113.06 162.14,113.06 v1(162.14,113.06)
  BOTTOM w0.203: PU8501.16 162.2,112.99 162.14,113.06 162.14,113.06
  BOTTOM w0.254: v1(162.14,113.06) 162.14,113.06 162.14,113.13 161.79,113.48 161.79,113.82 PC8513.2 161.39,114.22 161.39,115.58 161.6,115.78 PR8525.2 161.78,115.79 161.78,116.65 162.28,117.14 162.28,118.02 v2(162.28,118.03) 162.28,118.46 161.99,118.75 PR8534.1
PWR_VGA_CORE_VSUM-: length 30
  TOP w0.254: PC8518.2 160.78,115.01 160.01,115.01 PC8517.2 159.81,114.86 159.41,114.86 159.34,114.78 159.34,114.8 v1(159.35,114.8)
  L3 w0.254: v1(159.35,114.8) 157.65,114.8 156.76,115.69 156.63,115.69 v1(155.79,116.53) ; v1(170.61,121.38) 170.06,120.83 160.67,120.83 v1(160.52,120.97)
  BOTTOM w0.254: v1(160.52,120.97) 160.51,120.96 160.51,119.05 v2(160.64,118.92) 160.65,118.92 PC8525.1 160.84,117.12 PR8532.2 160.87,116.45 PC8523.2 160.87,114.9 PR8536.1 160.77,114.85 PC8522.2 159.41,114.85 159.34,114.78 159.34,114.8 v1(159.35,114.8) ; PR8521.1 154.61,115.34 153.88,116.07 PR8540.1 153.88,116.38 154.48,116.99 155.41,116.99 155.73,116.67 155.73,116.53 v1(155.79,116.53) ; PR8533.2 170.85,119.62 170.85,121.14 v1(170.61,121.38)
PWR_VTT_EN: length 3.4
  TOP w0.127: PU5101.7 v2(38.77,20.26) 38.77,19.95 38.97,19.74 38.97,19.73 39.33,19.37 PR5127.2 PR5126.2
PWRGOOD_TEST: length 22.3
  TOP w0.102: v2(177.24,140.16) 176.99,140.4 v1(176.99,140.69)
  L3 w0.102: v1(176.99,140.69) 177.33,140.36 180.08,140.36 183.51,136.93 192.37,136.93 192.62,137.19 192.62,137.55 192.18,137.99 v1(192.08,137.99)
  BOTTOM w0.102: v1(192.08,137.99) 193.27,139.18 193.27,139.52 193.71,139.95 R7601.2 ; v1(176.99,140.69) GPU1.N10
PX_EN: length 5.5
  TOP w0.102: TP7904.1 171.84,129.04 v1(171.51,129.38)
  BOTTOM w0.102: GPU1.AB16 171.51,132.61 v1(171.51,129.38)
Q502_G: length 4.6
  BOTTOM w0.127: Q501.D 82.68,75.67 82.47,75.89 v2(82.24,75.89) 81.79,75.89 81.41,75.5 R507.2 81.3,75.2 81.01,74.92 81.01,74.9 80.87,74.76 80.21,74.76 Q502.G
Q4009_G: length 4.7
  BOTTOM w0.127: Q2705.G 165.28,10.26 v2(163.35,10.26) 162.79,9.7 R2737.2 162.79,8.65 R2740.2
Q6204_G: length 4
  BOTTOM w0.254: R6512.2 147.73,21.08 v2(147.44,20.78) 146.9,21.31 Q6503.5 Q6503.2
Q6205_Q: length 2.9
  BOTTOM w0.381: R6522.2 149.19,22.59 150.06,23.47 Q6505.D 150.8,23.76 v2(151.07,23.49)
RASA0B: length 31.4
  L3 w0.203: v1(160.6,164.99) 159.79,165.8 158.53,165.8 157.74,165.01 157.74,156.91 160.14,154.51 163.45,154.51 164.45,153.52 164.45,151.06 166.16,149.35 166.16,147.7 167.37,146.49 167.37,145.25 166.78,144.66 v1(166.78,144.47)
  BOTTOM w0.229: VRAM1.G3 160.6,165 v1(160.6,164.99) ; v1(166.78,144.47) 166.78,144.48 GPU1.G22
RASA1B: length 30.1
  L3 w0.203: v1(171.46,145.1) 170.67,145.88 170.67,149.33 170.96,149.62 170.96,150.87 169.77,152.06 169.77,162.35 172.98,165.55 175.61,165.55 175.83,165.77 177.93,165.77 v1(178.7,165)
  BOTTOM w0.229: VRAM2.L3 v1(178.7,165) ; GPU1.G17 v1(171.46,145.1)
REGOUT:
  vias: v2(52.03,177.02)
RESET_OUT#: length 139.5
  TOP w0.102: v1(165.94,37.02) 165.94,37.43 166.96,38.45 168.27,38.45 168.85,37.87 169.56,37.87 170.45,36.98 173.45,36.98 173.73,36.69 176.22,36.69 177.94,38.41 186.42,38.41 188.17,40.17 188.17,40.64 v2(188.98,41.45) 189.82,42.29 v1(189.82,42.6) ; Q2602.G 194.84,128.62 v1(194.13,128.62)
  L3 w0.102: v1(167.28,33.6) 167.59,33.3 167.59,29.96 v1(167.59,29.96) ; v1(194.13,128.62) 194.25,128.62 194.87,128 194.87,127.27 193.33,125.73 193.33,94.39 194.85,92.86 194.85,70.38 196.05,69.19 196.05,61.42 192.62,57.99 191.89,57.99 189.82,55.91 v1(189.82,42.6)
  L4 w0.102: v1(197.82,132.19) 197.82,131.31 195.13,128.62 v1(194.13,128.62)
  BOTTOM w0.102: KBC24.73 168.06,32.83 v1(167.28,33.6) 167.28,33.71 166.64,34.35 166.64,36.33 v1(165.94,37.02) ; 166.95,29.27 166.97,29.29 167.64,29.29 EU1701.1 ; 166.95,29.27 166.95,29.32 v1(167.59,29.96) ; 166.95,29.27 R1706.1 ; v1(197.82,132.19) 197.82,133.22 Q2605.G
RING2: length 9.1
  TOP w0.254: v2(176.55,21) v4(176.69,20.35)
  TOP w0.508: EC2905.1 181.34,17.93 v4(181.9,17.38)
  L3 w1.016: v4(176.69,20.35) 180.01,20.35 180.64,19.72 180.64,18.47 181.2,17.91 181.21,17.91 181.75,17.38 v4(181.9,17.38)
RSET: length 5.2
  TOP w0.203: LOM31.31 47.55,177.27 47.36,177.46
  TOP w0.305: v2(44.8,180.24) 44.8,179.31 R3102.2 44.98,179.1 45.29,179.1 46.79,177.59 47.22,177.59 47.36,177.46
RSMRST_PWRGD#: length 6.2
  BOTTOM w0.127: R4033.2 164.41,79.74 163.88,79.74 R4030.2 163.45,80.18 D4002.3 ; R4033.2 164.5,80.45 R4032.2 ; R4033.2 164.56,79.71 165.24,79.71 R4031.2 165.29,79.61 165.73,79.17 165.73,79.07 166.01,78.79 v2(166.37,78.79) 166.37,79.14 166.17,79.61 R4029.2
RSVD_F65: length 4.1
  TOP w0.102: TP612.1 102.83,90.96 103.25,91.38 103.25,93.61 103.67,94.03 v1(103.67,94.03)
  BOTTOM w0.102: CPU1.F65 103.27,94.3 103.53,94.04 103.66,94.04 103.67,94.03 v1(103.67,94.03)
RSVD_G65: length 1.3
  TOP w0.102: v1(102.67,94.05) 102.88,94.05 TP613.1
  BOTTOM w0.102: v1(102.67,94.05) 102.68,94.05 102.69,94.03 102.79,94.03 CPU1.G65
RSVD_TP_AW70: length 8.4
  BOTTOM w0.102: CPU1.AW70 100.12,75.96 100.12,75.25 99.97,75.1 99.97,74.85 96.55,71.44 95.77,71.44 TP615.1
RSVD_TP_AW71: length 4.8
  BOTTOM w0.102: CPU1.AW71 99.12,76.68 98.98,76.68 97.98,75.69 97.96,75.69 97.83,75.56 97.16,75.56 97.15,75.57 96.49,76.23 96.49,76.55 TP614.1
RSVD_TP_BA68: length 7.1
  BOTTOM w0.102: TP602.1 96.56,71.12 97.78,72.34 98.01,72.53 98.56,72.53 100.6,74.57 100.6,75.48 CPU1.BA68
RSVD_TP_BA70: length 4.6
  BOTTOM w0.102: TP601.1 97.35,73.15 CPU1.BA70
RTC_3D3V: length 250
  TOP w0.508: D2501.3 38.52,34.69 C2503.1 38.42,34.5 38.42,34.09 39,33.51 v1(39.94,33.51) ; v1(178.65,23.93) 178.31,24.27 178.31,26.86 176.75,28.42 v1(176.75,29.05) ; R2472.1 148.04,41.3 v2(145.89,39.15) 140.19,33.46 140.19,29.47 136.48,25.76 134.79,25.76 129.79,20.76 129.71,20.76 129.34,20.39 129.34,20.31 127.29,18.25 v1(127.29,16.6) 126.42,15.73 62.94,15.73 v1(62.8,15.88)
  L3 w0.508: v1(127.29,16.6) 133.25,16.6 139.71,10.13 150.65,10.13 155.95,4.83 165.05,4.83 167.52,7.3 170.92,7.3 171.36,7.74 186.92,7.74 189.65,10.47 189.65,10.89 192.84,14.09 192.84,16.36 192.85,16.37 192.85,21.01 192.84,21.02 192.84,22.93 192.4,23.38 192.32,23.38 192.12,23.58 189.09,23.58 v1(188.64,23.13)
  L4 w0.508: v1(178.65,23.93) 178.92,23.93 179.33,24.34 179.86,24.34 180.58,23.62 183.03,23.62 183.63,24.22 187.64,24.22 188.64,23.21 v1(188.64,23.13) ; v1(62.8,15.88) 62.16,15.88 53.95,24.09 53.95,34.69 52.48,36.16 47.18,36.16 44.54,33.52 44.43,33.52 44.42,33.51 v1(39.94,33.51)
  BOTTOM w0.508: R2113.1 v1(176.75,29.05) 176.75,27.59 Q2107.S
RTC_3P3_EN_D: length 4.1
  BOTTOM w0.102: Q2110.D 177.26,25.5 175.94,25.5 v2(175.52,25.91) 175.44,25.99 R2104.2
RTC_3P3_EN_G: length 7.9
  BOTTOM w0.102: D2102.A 177.38,26.13 177.86,25.66 179.33,25.66 R2102.2 180.22,24.77 C2123.1 180.26,24.5 180.75,24.01 180.75,23.1 v2(180.41,22.75) 180.19,22.53 Q2110.G
RTC_AUX_S5: length 127.9
  TOP w0.102: v1(175.21,28.79) 177.67,26.32 177.67,24.01 178.78,22.9 v1(178.78,18.58)
  TOP w0.127: v1(157.94,68.58) 157.6,68.58 156.72,67.7 156.72,62.97 157.17,62.52 157.17,56.99 154.95,54.77 154.95,54.29 v2(152.08,51.42) 150.95,50.29 148.09,50.29 147.15,49.36 v1(142.57,49.36)
  TOP w0.254: RN1901.1 166.88,78.57 v1(167.02,78.43) 167.02,78.98 166.78,79.22 RN1901.2 ; v1(142.5,50.95) 143.6,50.95 145.19,52.54 145.59,52.54 146.34,53.29 146.34,56.57 146.58,56.81 R2107.1
  TOP w0.381: v1(167.02,78.43) 167.43,78.85 C2117.1 C2118.1
  L3 w0.381: v1(160.53,30.13) 157.82,32.85 157.82,41 157.41,41.4 157.41,42.17 156.74,42.84 156.74,43.23 156.65,43.44 156.04,44.05 155.96,44.05 150.66,49.36 v1(142.57,49.36)
  L4 w0.254: v1(142.57,49.36) 142.5,49.43 v1(142.5,50.95)
  L4 w0.381: v1(175.21,28.79) 175.42,29.01 175.42,29.61 175.08,29.95 170.84,29.95 170.24,29.35 166.58,29.35 166.43,29.51 161.16,29.51 v1(160.53,30.13)
  BOTTOM w0.127: v1(167.02,78.43) 167.02,77.89 164.83,75.7 163.11,75.7 160.24,72.83 160.24,72.05 157.81,69.62 157.81,68.72 v1(157.94,68.58) 157.97,68.61 R1730.1 ; v1(178.78,18.58) R2708.1
  BOTTOM w0.508: v1(167.02,78.43) 167.76,79.18 C2119.1 ; Q2107.D 177.65,30.38 177.4,30.64 176.14,30.64 175.92,30.41 175.92,30.03 R2113.2 175.83,29.94 175.83,29.41 v1(175.21,28.79) 175.44,28.55 R2104.1
RTC_DET#: length 307.7
  TOP w0.102: 133.69,14.49 v2(133.69,14.43) ; 133.69,14.49 134.68,14.49 134.83,14.63 136.15,14.63 136.95,13.83 151.01,13.83 151.27,14.09 151.27,16.73 153.42,18.88 153.42,19.89 156.62,23.1 157.98,23.1 161.41,26.52 164.09,26.52 164.48,26.91 166.9,26.91 166.92,26.89 167.3,26.89 169.86,29.44 v1(169.86,30.04) ; 133.69,14.49 133.52,14.65 v1(132.57,14.65) ; Q2505.D 39.47,38.78 39.42,38.73 39.42,38.43 36.63,35.64 v1(36.63,31.42)
  L3 w0.102: v1(132.57,14.65) 132.55,14.63 103.67,14.63 102.98,13.95 63.5,13.95 61.65,15.8 56.59,15.8 54.39,18 48.92,18 47.97,17.05 44.82,17.05 43.52,18.35 39.35,18.35 38.46,19.25 36.24,19.25 35.02,20.47 35.02,29.8 v1(36.63,31.42)
  L4 w0.102: v1(156.33,86.31) 156.33,85.49 157.42,84.39 157.87,84.39 158.02,84.54 161.15,84.54 164.46,87.85 164.78,87.85 169.61,87.85 169.83,87.63 169.98,87.63 169.99,87.62 177.87,87.62 177.88,87.63 178.21,87.63 180.33,89.74 184.99,89.74 186.07,90.82 186.76,90.82 189.38,88.2 189.38,71.61 188.36,70.6 188.36,65.4 191.09,62.67 191.09,38.72 190.09,37.73 190.09,36.82 184.03,30.76 183.83,30.53 183.8,30.53 183.54,30.26 175.65,30.26 175.59,30.32 170.14,30.32 v1(169.86,30.04)
  BOTTOM w0.089: 142.37,90.44 142.08,90.15 142.08,90.07 141.85,89.84 141.45,89.84 141,90.29 140.18,90.29 140.02,90.13 CPU1.P1
  BOTTOM w0.102: v1(156.33,86.31) 154.62,86.31 153.05,87.88 153.05,88.03 152.36,88.71 152.01,88.71 RN2011.3 151.68,88.42 151.27,88.83 150.43,88.83 150.34,88.74 149.93,88.74 149.68,88.99 149.68,89.2 149.22,89.66 146.02,89.66 145.72,89.36 145.39,89.36 145.14,89.61 145.14,90.5 144.84,90.81 144.25,90.81 143.89,90.44 142.37,90.44
RTC_PWR:
  vias: v2(36.18,39.95)
RTC_RST#: length 50.1
  TOP w0.127: 162.91,77.47 v2(162.91,76.62) 162.91,76.59 163.79,75.71 164.16,75.71 164.24,75.79 165.29,75.79 Q1901.D ; 162.91,77.47 161.64,77.47 160.21,78.9 v1(159.21,78.9) ; 162.91,77.47 163.56,78.12 164.13,78.12 164.56,78.55 EC1807.1 164.56,79.44 G1901.2 164.48,79.95 165.5,79.95 C1901.1 165.51,79.39 RN1901.3
  L3 w0.127: v1(131.2,81.04) 132.32,81.04 132.81,80.55 133.18,80.55 133.44,80.81 133.44,81.12 133.75,81.43 134.12,81.43 135.8,79.75 136.06,79.75 136.16,79.65 139.79,79.65 140.28,79.16 140.92,79.16 141.05,79.28 141.41,79.28 141.84,78.86 141.84,78.72 142.8,77.76 147.7,77.76 149.76,75.7 149.81,75.7 152.04,73.47 154.85,73.47 154.9,73.42 156.15,73.42 156.71,73.98 156.71,75.28 158.85,77.42 158.85,78.54 v1(159.21,78.9)
  BOTTOM w0.127: v1(131.2,81.04) 130.89,81.35 CPU1.AM16
RTC_X1: length 25.3
  L4 w0.114: v1(129.39,81.04) 130.35,82 130.76,82 130.84,82.05 131.1,82.22 131.27,82.39 131.5,82.62 132.1,83.21 133.11,83.21 133.39,82.94 133.48,82.35 133.48,78.32 133.73,78.06 133.89,77.95 133.96,77.95 134.98,76.93 136.54,74.23 136.61,74.07 136.68,73.84 137.21,73.19 137.32,73.08 v1(137.54,73.08)
  BOTTOM w0.114: v1(129.39,81.04) CPU1.AM18 ; v1(137.54,73.08) 137.86,73.08 138.13,72.82 138.84,72.44 140.53,70.75 141.63,70.06 R1815.1 C1804.1 142.72,68.08 X1802.1
RTC_X2: length 25.2
  L4 w0.114: v1(137.83,72.52) 137.5,72.52 137.08,72.52 136.96,72.65 136.88,72.66 135.71,73.83 135.71,74.56 135.53,74.87 134.34,76.05 134.18,76.05 134.06,75.94 133.9,75.94 133.67,76.17 133.67,76.33 133.79,76.45 133.79,76.61 133.55,76.84 133.39,76.84 133.19,76.64 133.02,76.64 132.79,76.87 132.79,77.03 133,77.24 133,77.4 132.6,77.8 132.6,79.26 132.63,79.63 132.63,80.42 132.56,80.95 132.56,81.1 132.64,81.42 132.64,82.03 132.38,82.28 132.02,82.28 131.88,82.15 131.57,81.86 130.97,81.46 130.34,81.02 v1(130.3,81.03)
  BOTTOM w0.114: v1(137.83,72.52) 138.24,72.36 138.74,72.22 140.24,70.72 R1815.2 C1803.1 141.83,68.09 X1802.4 ; v1(130.3,81.03) 130.17,81.47 130.04,81.6 129.83,81.7 129.59,81.68 CPU1.AM20
RTCRST_ON: length 65
  TOP w0.127: EC1808.1 164.62,71.92 164.62,72.64 R1817.1 164.65,73.35 Q1901.G 164.41,73.86 164.5,73.94 v1(164.5,74.88) ; v1(178.27,28.35) 178.66,27.96 v2(178.66,27.96)
  L3 w0.127: v1(164.5,74.88) 164.5,71.07 163.64,70.21 163.64,56.45 163.89,56.2 163.89,53.1 165.25,51.74 165.48,51.74 v1(170.96,46.27) 172.48,44.74 172.48,41.79 173.6,40.68 173.6,40.52 174.28,39.84 176,39.84 177.17,38.67 177.17,36.62 178.27,35.52 v1(178.27,28.35)
  BOTTOM w0.127: KBC24.31 170.86,46.35 170.94,46.27 v1(170.96,46.27) ; R2102.1 178.73,26.09 D2102.K 178.6,26.22 Q2107.G 179.75,27.53 R2118.1 179.82,28.18 179.53,28.48 178.39,28.48 v1(178.27,28.35)
RUNPWROK: length 1.9
  BOTTOM w0.127: R2481.2 174.31,39.62 173.99,39.93 KBC24.48
SA0_CHA_DIM0: length 5.2
  TOP w0.102: v2(133.25,34.61) v1(133.63,34.2) 133.92,34.2 134.15,34.42 R1204.2 134.26,34.43 R1205.2
  BOTTOM w0.102: v1(133.63,34.2) 132.58,34.2 131.77,33.39 DM1.256
SA0_CHB_DIM0: length 22.3
  TOP w0.102: v1(108.24,16.84) 108.52,17.12 108.52,18.28 v2(108.31,18.49) 108.19,18.61 R1303.2 106.14,18.61 R1302.2
  L4 w0.102: v1(108.24,16.84) 108.67,17.27 109.1,17.27 109.57,16.81 114.53,16.81 115.58,17.86 123.49,17.86 v1(123.77,17.58)
  BOTTOM w0.102: v1(123.77,17.58) DM2.256
SA1_CHA_DIM0: length 3.5
  TOP w0.102: v2(133.34,32.96) v1(133.44,33.51) 133.9,33.51 133.98,33.59 R1208.2 134.26,33.59 R1210.2
  BOTTOM w0.102: DM1.260 133.44,33.17 v1(133.44,33.51)
SA1_CHB_DIM0: length 24.1
  TOP w0.102: v1(108.92,16.84) 108.92,18.55 107.92,19.55 v2(107.26,19.55) 106.14,19.55 R1307.2 105.34,18.75 R1306.2
  L3 w0.102: v1(124.77,17.95) 124.77,17.65 123.84,16.72 109.05,16.72 v1(108.92,16.84)
  BOTTOM w0.102: DM2.260 v1(124.77,17.95)
SA2_CHA_DIM0: length 21.1
  TOP w0.102: v1(101.96,17.98) 101.64,17.66 v2(101.64,17.47) 101.84,17.27 R1212.2 R1211.2
  L4 w0.102: v1(101.96,17.98) 102.43,18.44 103.23,18.44 106.06,21.27 106.06,24.06 106.46,24.47 106.46,29.62 v1(108.08,31.24)
  BOTTOM w0.102: DM1.166 109.27,31.4 109.12,31.24 v1(108.08,31.24)
SA2_CHB_DIM0: length 4.2
  TOP w0.102: v1(101.18,18.01) 101.18,18.1 101.8,18.72 v2(101.82,18.72) 102.56,18.72 R1311.2 102.75,18.53 R1310.2
  BOTTOM w0.102: DM2.166 101.27,18.11 v1(101.18,18.01)
SATA_LED#_R: length 175
  TOP w0.127: v1(141.75,94.11) 142.98,92.88 144.93,92.88 146.32,94.26 149.1,94.26 151.91,97.07 R1606.1 153.49,97.07 153.87,97.46 155.49,97.46 155.99,97.95 155.99,98.5 156.33,98.83 156.88,98.83 157.87,97.84 159.32,97.84 v2(159.52,97.64) 161.88,97.64 164.65,94.87 179.69,94.87 v1(180.91,93.65)
  L3 w0.127: v1(180.91,93.65) 184.48,90.08 184.48,84.64 188.09,81.02 188.09,71.69 186.86,70.45 186.86,60.61 182.13,55.88 182.11,55.88 181.11,54.88 181.11,54.7 181.37,54.44 181.37,54.07 181.11,53.81 180.74,53.81 180.42,53.49 180.42,48.39 181.34,47.48 181.45,47.48 181.71,47.22 181.71,47.1 181.74,47.08 181.74,36.48 186.42,31.79 187.36,31.79 189.15,30 191.39,30 193.89,27.5 193.89,12.22 187.9,6.24 186.89,6.24 186.55,6.58 v1(168.3,6.58)
  BOTTOM w0.127: v1(168.3,6.58) 168.3,6.98 168.94,7.62 168.94,8.35 167.7,9.59 Q6401.S ; CPU1.H1 139.69,93.65 140.05,93.65 140.06,93.65 140.1,93.65 140.3,93.86 140.35,93.86 140.45,93.96 141.6,93.96 v1(141.75,94.11)
SATA_ODD_DA#_C: length 2
  TOP w0.127: ODD1.17 183.36,88.05 TP6001.1
SATA_ODD_PRSNT#: length 19.9
  BOTTOM w0.089: 138.45,93.18 CPU1.H3
  BOTTOM w0.127: 138.45,93.18 138.47,93.16 139.91,93.16 140.39,93.64 141.97,93.64 142.44,94.12 144.33,94.12 144.79,93.66 145.83,93.66 146.38,94.22 148.36,94.22 150.55,96.4 150.79,96.4 151.61,97.23 151.61,97.95 151.95,98.29 152.55,98.29 R1608.1 152.33,99.19 v2(152.05,99.19) 152.06,99.2 R6004.1
SATA_ODD_PRSNT#_R: length 45.9
  TOP w0.127: ODD1.8 183.85,83.55 183.03,84.37 181.89,84.37 181.68,84.58 181.68,86.27 182.59,87.18 182.59,93.27 182.79,93.47 182.79,93.83 182.53,94.09 181.03,94.09 180.01,95.12 164.76,95.12 161.24,98.65 159.91,98.65 v2(159.49,99.06) 159.23,99.32 155.19,99.32 v1(154.96,99.1)
  BOTTOM w0.127: v1(154.96,99.1) 154.96,99.1 153.89,100.17 152.99,100.17 R6004.2
SATA_RX_CON_N0: length 6.1
  BOTTOM w0.178: 189.77,41.52 ED6001.7 ED6001.4 187.42,41.52 187.31,41.63 185.73,41.63 C6004.2 ; 189.77,41.52 v2(189.76,41.28) ; 189.77,41.52 191.19,41.52 HDD1.8
SATA_RX_CON_N1: length 2.3
  TOP w0.178: ODD1.5 183,82.05 C6010.2
SATA_RX_CON_P0: length 6.3
  BOTTOM w0.178: C6003.2 185.81,41.93 186.39,41.93 ; v2(186.39,42.19) 186.39,41.93 ; 186.39,41.93 187.83,41.93 ED6001.5 ED6001.6 189.32,42 189.49,41.82 190.43,41.82 190.65,42.05 HDD1.7
SATA_RX_CON_P1: length 2.4
  TOP w0.178: v2(183.42,82.53) 183.42,82.35 ; 183.42,82.35 183.83,82.35 184.02,82.55 ODD1.6 ; 183.42,82.35 182.78,82.35 C6011.2
SATA_RX_CPU_N0: length 118.1
  L4 w0.152: v1(128.47,94.56) 128,95.15 128,95.55 128.25,96.03 128.25,96.68 132.55,100.98 133.76,100.98 136.71,98.04 136.71,97.68 142.3,92.09 142.3,91.31 143.12,90.49 146.5,90.49 147.53,89.45 148.97,89.45 150.25,88.17 150.25,86.2 151.25,85.21 151.25,83.17 151.25,82.93 156.46,77.72 156.81,77.72 157.6,76.93 160.33,76.93 160.78,77.37 161.84,77.37 162.28,76.93 167.25,76.93 169.94,79.63 169.94,79.63 182.64,79.63 185.28,76.99 185.28,73.35 184.59,72.66 184.24,72.31 184.24,63.69 187.32,60.61 187.32,48.18 186.08,46.94 186.08,44.02 185.17,43.12 185.17,42.09 184.62,41.53 v1(183.78,41.53)
  BOTTOM w0.178: CPU1.F20 v1(128.47,94.56) ; v2(183.62,40.99) 183.62,41.38 v1(183.78,41.53) 183.95,41.71 184.23,41.71 C6004.1
SATA_RX_CPU_N1: length 75.8
  TOP w0.178: v1(127.49,93.91) v2(127.96,93.58) ; 181.72,81.68 181.52,81.88 179.81,81.88 v1(179.62,81.68)
  L4 w0.152: v1(127.49,93.91) 127.92,94.42 127.92,94.76 127.76,94.92 127.76,97.48 131.73,101.45 133.82,101.45 137.29,97.98 137.29,97.46 141.39,93.37 141.97,93.37 144.33,91 148.61,91 149.98,89.63 150.3,89.63 150.97,88.95 150.97,87.2 151.81,86.36 151.81,83.16 156.49,78.48 157.8,78.48 158.68,77.61 160.16,77.61 160.48,77.93 162.13,77.93 162.44,77.62 163.4,77.62 164.66,78.89 167.86,78.89 169.2,80.23 176.47,80.23 177.93,81.68 v1(179.62,81.68)
  BOTTOM w0.178: CPU1.G21 v1(127.49,93.91)
SATA_RX_CPU_P0: length 117.9
  L4 w0.152: v1(128.43,95.3) 129.39,95.3 129.59,95.51 129.59,95.8 129.4,95.98 128.69,95.98 128.54,96.13 128.54,96.56 132.68,100.69 133.64,100.69 136.42,97.91 136.42,97.56 142.01,91.97 142.01,91.89 142.01,91.19 143,90.19 146.38,90.19 147.41,89.16 148.85,89.16 149.96,88.05 149.96,86.08 150.96,85.08 150.96,83.17 150.96,82.81 156.34,77.43 156.69,77.43 157.48,76.64 160.45,76.64 160.9,77.08 161.72,77.08 162.16,76.64 167.37,76.64 170.07,79.34 182.52,79.34 184.99,76.87 184.99,73.47 184.3,72.78 183.94,72.43 183.94,63.56 184.3,63.21 184.3,63.21 184.3,63.21 187.02,60.48 187.02,48.3 185.78,47.06 185.78,44.14 184.88,43.24 184.88,42.21 184.5,41.82 184.17,41.82 v1(183.79,42.2)
  BOTTOM w0.178: C6003.1 184.31,42.01 183.97,42.01 v1(183.79,42.2) 183.59,42.4 v2(183.59,42.73) ; CPU1.E20 128.92,95.1 128.72,95.3 v1(128.43,95.3)
SATA_RX_CPU_P1: length 75.4
  TOP w0.178: 180.71,82.18 181.4,82.18 181.72,82.5 ; 180.71,82.18 v2(180.72,82.43) ; 180.71,82.18 179.77,82.18 v1(179.58,82.37)
  L4 w0.152: v1(127.5,94.58) 127.47,94.61 127.47,97.6 131.61,101.74 133.95,101.74 137.58,98.1 137.58,97.58 141.51,93.66 142.09,93.66 144.45,91.29 148.73,91.29 150.1,89.92 150.42,89.92 151.26,89.08 151.26,87.32 152.1,86.48 152.1,83.29 156.61,78.77 157.92,78.77 158.8,77.9 160.04,77.9 160.36,78.23 162.26,78.23 162.56,77.92 163.27,77.92 164.54,79.18 167.74,79.18 169.08,80.52 176.35,80.52 177.81,81.98 179.18,81.98 v1(179.58,82.37)
  BOTTOM w0.178: CPU1.F21 128.01,94.38 127.81,94.58 v1(127.5,94.58)
SATA_TX_CON_N0: length 6.2
  BOTTOM w0.178: v2(186.5,40.44) 186.51,40.3 ; 186.51,40.3 185.67,40.3 C6006.2 ; 186.51,40.3 187.09,40.3 187.26,40.48 ED6001.2 ED6001.9 189.24,40.48 189.36,40.36 190.39,40.36 190.59,40.55 HDD1.10
SATA_TX_CON_N1: length 2.7
  TOP w0.178: ODD1.3 183.89,81.05 183.62,80.78 ; 183.62,80.78 183.36,80.52 182.98,80.52 C6013.2 ; 183.62,80.78 v2(183.45,80.93)
SATA_TX_CON_P0: length 6.1
  BOTTOM w0.178: v2(189.91,39.91) 189.91,40.05 ; 189.91,40.05 189.26,40.05 ED6001.10 ED6001.1 185.88,40 C6005.2 ; 189.91,40.05 HDD1.11
SATA_TX_CON_P1: length 2.3
  TOP w0.178: ODD1.2 183.82,80.55 183.49,80.22 182.8,80.22 C6014.2
SATA_TX_CPU_N0: length 132
  TOP w0.178: v2(184.29,40.39) 183.95,40.39 v1(183.76,40.2)
  L4 w0.152: v1(183.76,40.2) 183.97,39.99 185.88,39.99 187.34,41.45 187.34,46.45 188.74,47.85 188.74,60.72 186.09,63.38 186.09,72.62 186.38,72.9 186.38,83.21 184.66,84.92 177.92,84.92 174.94,81.94 167.42,81.94 166.14,80.66 159.22,80.66 158.77,80.21 157.16,80.21 153.51,83.87 153.51,87.1 153.08,87.53 153.08,89.51 150.95,91.64 150.61,91.64 148.16,94.09 144.23,94.09 141.75,96.58 140.59,96.58 138.99,98.18 138.61,98.18 133.84,102.94 126.73,102.94 126.1,102.31 126.1,101.88 126.35,101.63 v1(126.68,101.63)
  BOTTOM w0.089: 127.28,99.7 127.29,99.7 127.42,99.57 127.99,99 127.99,97.49 CPU1.B21
  BOTTOM w0.127: 127.28,99.7 126.3,100.68 126.3,101.25 v1(126.68,101.63)
  BOTTOM w0.178: v1(183.76,40.2) 183.97,39.98 184.22,39.98 184.56,40.33 C6006.1
SATA_TX_CPU_N1: length 84.6
  TOP w0.178: 181.72,80.87 181.48,80.63 179.67,80.63 v1(179.44,80.86)
  L4 w0.152: v1(179.44,80.86) 179.81,80.49 181.25,80.49 181.93,81.17 181.93,83.01 181.24,83.7 178.46,83.7 175.84,81.08 168.85,81.08 167.55,79.78 159.59,79.78 159.16,79.36 156.82,79.36 152.66,83.52 152.66,86.72 151.82,87.56 151.82,89.31 150.65,90.48 150.34,90.48 148.94,91.88 144.61,91.88 140.45,96.04 140.21,96.04 138.61,97.64 138.39,97.64 133.88,102.15 129.62,102.15 127.53,100.07 125.99,100.07 v1(125.65,99.72)
  BOTTOM w0.089: CPU1.D21 127.73,95.88 127.34,96.27 127.34,96.69 127.29,96.83 127.29,97.09 127.35,97.24 127.35,97.34 127.29,97.48 127.29,98.41 127.26,98.51
  BOTTOM w0.127: v1(125.65,99.72) 125.8,99.88 126.09,99.88 126.36,99.6 ; v2(126.19,99.44) 126.36,99.6 ; 126.36,99.6 127.26,98.71 127.26,98.51
SATA_TX_CPU_P0: length 132
  L4 w0.152: v1(125.76,101.62) 125.76,102.38 126.61,103.23 133.96,103.23 138.73,98.47 139.11,98.47 140.71,96.87 141.87,96.87 144.35,94.38 148.28,94.38 150.73,91.93 151.07,91.93 153.37,89.63 153.37,87.66 153.8,87.23 153.8,83.99 157.28,80.51 158.65,80.51 159.09,80.95 166.02,80.95 167.3,82.23 174.82,82.23 177.8,85.21 184.78,85.21 186.67,83.33 186.67,72.78 186.38,72.49 186.38,63.5 189.04,60.84 189.04,47.73 187.63,46.33 187.63,41.33 186,39.7 183.97,39.7 v1(183.76,39.49)
  BOTTOM w0.089: CPU1.A21 127.8,97.68 127.8,98.92 127.28,99.44 127.12,99.54
  BOTTOM w0.127: 127.12,99.54 126.07,100.58 126.07,101.31 v1(125.76,101.62)
  BOTTOM w0.178: v2(183.72,38.93) 183.72,39.45 v1(183.76,39.49) 183.95,39.68 184.48,39.68 C6005.1
SATA_TX_CPU_P1: length 84.8
  TOP w0.178: 180.64,80.33 179.68,80.33 v1(179.49,80.14) ; 180.64,80.33 181.44,80.33 181.72,80.05 ; 180.64,80.33 v2(180.61,80.07)
  L4 w0.152: v1(125.65,100.36) 127.41,100.36 129.5,102.44 134,102.44 138.51,97.94 138.73,97.94 140.33,96.33 140.57,96.33 144.73,92.17 149.06,92.17 150.46,90.77 150.77,90.77 152.11,89.43 152.11,87.68 152.95,86.85 152.95,83.64 156.94,79.65 159.04,79.65 159.47,80.08 167.43,80.08 168.73,81.37 175.72,81.37 178.34,83.99 181.36,83.99 182.22,83.13 182.22,81.05 181.37,80.2 179.55,80.2 v1(179.49,80.14)
  BOTTOM w0.089: 127.5,98.46 127.47,98.35 127.47,97.51 127.53,97.37 127.53,97.21 127.47,97.06 127.47,96.86 127.52,96.73 127.53,96.69 CPU1.C21
  BOTTOM w0.127: 127.5,98.46 127.5,98.79 126.18,100.1 v1(125.65,100.36)
SD_RCOMP: length 4.3
  TOP w0.381: R1901.1 132.97,85.38 133.93,85.38 133.94,85.37 134.62,85.37 v2(134.62,85.36) 135.78,85.36 136.25,85.83 v1(136.25,85.9)
  BOTTOM w0.406: v1(136.25,85.9) 136.25,86.24 CPU1.AB7
SEN_A0: length 2.5
  TOP w0.254: v2(156.75,163.19) R8111.2 156.65,164.25 v1(155.86,164.25)
  BOTTOM w0.254: v1(155.86,164.25) 155.85,164.25 VRAM1.J10
SEN_A1: length 2.5
  TOP w0.127: v1(183.36,163.8) 182.83,163.26 v2(182.59,163.26) 182.52,163.33 R8113.2
  BOTTOM w0.254: VRAM2.J10 v1(183.36,163.8)
SERIRQ_TPM: length 3.5
  BOTTOM w0.102: R9141.1 v2(153.5,62.39) 154.15,61.74 154.75,61.74 154.95,61.54 U9103.27
SIO_EXT_SCI#: length 14.9
  TOP w0.102: v1(149.4,93.92) 149.81,94.33 149.81,94.5 151.42,96.11 R1610.1
  L3 w0.102: v1(149.4,93.92) 149.4,93.92 144.37,93.92 v1(143.97,93.52)
  BOTTOM w0.089: 140.08,92.52 139.71,92.52 139.62,92.55 139.5,92.55 139.27,92.78 CPU1.J2
  BOTTOM w0.102: 140.08,92.52 140.64,93.08 142.58,93.08 v2(142.92,93.42) 143.02,93.52 v1(143.97,93.52)
SIO_EXT_SMI#_R: length 17.9
  TOP w0.102: v1(137.6,91) 137.6,91.26 v2(137.85,91.52)
  L3 w0.102: v1(137.6,91) 138.56,91 140.22,92.66 144.1,92.66 144.12,92.64 145.01,92.64 145.44,93.07 146.08,93.07 146.21,92.94 147.56,92.94 v1(148.1,93.49)
  BOTTOM w0.102: v1(148.1,93.49) 148.36,93.49 148.97,94.09 148.97,94.1 149.22,94.35 149.22,94.35 150.82,95.94 R802.1 ; v1(137.6,91) 137.6,91.13 CPU1.L6
SIO_EXT_WAKE#: length 130.7
  L2 w0.102: v1(154.7,98.52) 155.04,98.52 156.29,99.76 160.03,99.76 164.85,94.95 170.75,94.95 177.22,88.48 177.22,88.31 177.22,88.16 178.68,86.7 178.68,84.16 177.51,82.99 177.51,79.04 180.73,75.81 180.73,70.35 180.35,69.97 180.35,68.59 178.71,66.96 176.81,66.96 173.02,63.17 173.02,61.08 172.63,60.68 172.63,60.62 166.24,54.23 162.38,54.23 161.89,53.74 159.52,53.74 157.3,51.53 157.3,42.92 156.2,41.82 v1(156.2,40.99)
  L3 w0.102: v1(154.7,98.52) 154.7,97.03 157.26,94.47 157.26,87.32 156.72,86.77 155.68,86.77 154.6,87.85 v1(152.62,87.85)
  BOTTOM w0.089: 140.81,84.73 140.46,84.38 139.68,84.38 139.59,84.42 139.19,84.42 CPU1.AD3
  BOTTOM w0.102: 140.81,84.73 145.51,84.73 146.73,83.52 149.13,83.52 149.14,83.51 151,83.51 152.68,85.18 v2(152.68,87.28) 152.68,87.79 v1(152.62,87.85) 152.21,87.85 152.11,87.75 RN2011.4 ; v1(156.2,40.99) 156.34,41.13 KBC24.116
SIO_PWRBTN#: length 72.3
  TOP w0.102: v1(167.31,37.61) 167.04,37.34 v2(167.04,37.13)
  L3 w0.102: v1(167.31,37.61) 167.19,37.49 166.1,37.49 163.09,40.5 158.96,40.5 157.84,41.62 157.84,42.26 157.11,42.99 157.11,43.5 156.19,44.42 156.12,44.42 150.81,49.73 144.12,49.73 144.06,49.79 141.1,49.79 139.7,48.39 138.5,48.39 137.49,49.39 137.49,67.55 135.24,69.8 v1(135.14,69.8)
  BOTTOM w0.089: 132.24,72.98 131.19,74.02 131.19,74.59 131.01,74.78 131.01,75.35 131.27,75.61 CPU1.BA15
  BOTTOM w0.102: v1(167.31,37.61) 167.61,37.92 170.71,37.92 171.13,38.33 KBC24.52 ; 132.24,72.98 132.8,72.42 132.8,72.27 133.43,71.64 133.43,71.05 134.68,69.8 v1(135.14,69.8)
SIO_RCIN#: length 16.9
  TOP w0.127: v1(134.68,71.2) 134.68,69.63 134.95,69.35 135.32,69.35 135.33,69.36 135.92,69.36 136.31,68.97 136.31,68.97
  TOP w0.191: R1816.2 137.69,63.28 v2(137.69,64.41) 137.69,67.59 136.31,68.97
  BOTTOM w0.089: 134.31,71.94 134.31,71.94 132.54,73.71 132.06,74.19 132.06,75.09 132.09,75.23 132.09,75.39 132.06,75.54 132.06,75.82 132.13,76.11 132.13,76.57 CPU1.AW13
  BOTTOM w0.14: v1(134.68,71.2) 134.68,71.57 134.31,71.94
SIO_SLP_A#: length 1.1
  TOP w0.102: v1(130.3,80.38) 130.33,80.38 TP1706.1
  BOTTOM w0.102: CPU1.AN16 v1(130.3,80.38)
SIO_SLP_S0#: length 1.2
  TOP w0.127: v1(133.04,79.08) 132.92,79.08 TP1701.1
  BOTTOM w0.127: CPU1.AT11 133.36,78.75 v1(133.04,79.08)
SIO_SLP_S3#: length 352.9
  TOP w0.127: R4034.1 169.24,79.58 v1(169.17,79.51) 169.3,79.64 177.35,79.64 178.58,78.41 180.74,78.41 181.61,77.53 183.81,77.53 185.23,78.95 185.6,78.95 186,79.35 186,81.41 188.11,83.52 v1(188.11,84.08) ; PR5126.1 38.51,17.62 39.6,16.52 46.8,16.52 50.2,19.93 v2(53.18,19.93) v1(54.53,19.93) ; R2487.2 166.92,32.06 166.93,32.06 167.76,32.06 R2486.2 168.05,32.77 167.74,33.08 167.74,34.15 v1(167.42,34.47) ; v1(162.67,7.83) 162.67,7.76 162.44,7.53 162.4,7.48 162.4,6.82 v1(159.57,3.99) ; R4010.1 45.86,46.84 v1(45.57,47.12)
  L3 w0.102: v1(132.16,79.71) 132.61,79.27 132.61,78.9 133.2,78.3 133.2,78.27
  L3 w0.127: v1(162.67,7.83) 160.68,7.83 157.75,10.76 157.75,20.43 162.63,25.31 162.63,26.76 166.8,30.93 166.8,33.85 v1(167.42,34.47) ; 133.2,78.27 133.2,76.82 134.06,75.96 135.06,75.96 135.75,75.26 139.03,75.26 143.57,70.72 144.6,70.3 151.31,70.3 151.44,70.43 153.22,70.43 153.41,70.24 154.3,70.24 154.81,70.75 155.95,70.75 156.04,70.84 156.72,70.84 156.77,70.79 157.06,70.79 v1(158.33,69.51) ; v1(122.5,13.68) 123.01,14.19 134.11,14.19 135.43,12.86 135.64,12.86 138.93,9.57 150.58,9.57 156.16,3.99 v1(159.57,3.99) ; v1(54.53,19.93) 54.99,20.39 54.99,20.89 54.42,21.47 54.23,22.38 54.23,23.6 54.23,23.6 54.23,24.87 53.6,25.5 53.6,30.44 53.61,30.44 53.61,30.65 53.6,30.65 53.6,32.39 52.47,33.52 52.47,41.8 47.86,46.41 46.28,46.41 v1(45.57,47.12)
  L4 w0.127: v1(54.53,19.93) 57.4,19.93 63.65,13.68 v1(122.5,13.68) ; v1(188.11,84.08) 188.11,73.12 187.16,72.17 187.16,63.82 189.81,61.16 189.81,43.93 189.34,43.46 189.34,40.74 187.54,38.94 187.54,37.7 182.25,32.41 177.22,32.41 176.03,33.6 173.59,33.6 172.99,33 169.29,33 168.8,33.49 168.76,33.68 168.39,34.05 167.84,34.05 v1(167.42,34.47)
  BOTTOM w0.127: R2740.1 161.95,8.49 162.62,7.83 v1(162.67,7.83) ; CPU1.AP15 132.11,79.74 132.14,79.71 v1(132.16,79.71) ; v1(169.17,79.51) 167.37,77.71 167.2,77.71 164.93,75.45 163.22,75.45 160.49,72.72 160.49,71.94 158.33,69.79 v1(158.33,69.51)
SIO_SLP_S4#: length 267.9
  TOP w0.127: v1(172.45,89.85) 172.45,90.22 171.63,91.04 R4024.1 ; PQ4415.B v1(141.23,173.48) ; v1(145.53,155.75) 144.21,154.43 142.09,154.43 138.52,150.86 v1(138.16,150.86) ; v1(142.81,56.63) 143.07,56.38 143.07,55.6 142.46,54.99 v2(142.46,53.98) v1(142.46,52.94)
  L3 w0.127: v1(132.44,20.23) 140.63,20.23 v1(143.68,23.28) ; v1(138.16,150.86) 138.71,150.31 138.71,148.79 141.39,146.1 141.39,138.42 144.68,135.13 144.68,125.73 144.68,125.73 144.68,124.75 145.47,123.95 145.47,120.58 145.53,120.53 146.29,119.77 146.29,111.4 146.29,110.13 149.93,106.49 150.71,106.49 157.64,99.56 157.64,99.56 158.09,99.1 v1(158.09,97.4) 158.09,96.9 160.47,94.52 160.47,92.9 161.14,92.23 161.14,91.5 160.8,91.17 160.8,80.44 160.67,80.31 160.67,77.9 160.64,77.88 159.94,77.17 159.94,75.29 159.99,75.23 159.99,74.59 159.79,74.39 159.79,67.84 160.06,67.57 160.06,67.05 159.8,66.79 158.4,66.79 157.85,67.34 155.29,67.34 154.81,67.82 154.44,67.82 153.56,66.94 146.33,66.94 144.15,69.11 143.03,69.58 142.87,69.73 v1(139.14,69.73) ; v1(145.53,155.75) 145.57,155.79 145.57,169.6 145.74,169.76 145.74,172.31 144.57,173.48 v1(141.23,173.48)
  L4 w0.127: v1(143.68,23.28) 141.7,25.26 141.7,26.54 142.21,27.06 142.21,33.67 141.68,34.2 141.68,39.66 141.03,40.31 141.03,45.09 143.02,47.08 143.02,51.07 142.46,51.62 v1(142.46,52.94) ; v1(172.45,89.85) 172.45,89.65 172.15,89.35 171.18,89.35 170.75,89.75 170.66,89.84 165.1,89.84 158.09,96.85 v1(158.09,97.4) ; v1(142.81,56.63) 142.35,57.1 141.45,57.1 141.19,57.36 141.19,57.77 141.3,57.88 141.3,59.32 140.24,60.38 140.24,67.7 139.32,68.63 139.28,68.63 139.02,68.89 139.02,69.62 v1(139.14,69.73)
  BOTTOM w0.089: CPU1.BA16 130.64,74.64 130.84,74.45 130.84,73.62 130.94,73.52
  BOTTOM w0.127: PR5153.1 132.43,20.21 v1(132.44,20.23) ; v1(142.81,56.63) 143.07,56.38 143.07,55.6 142.38,54.91 139.86,54.91 139.37,55.4 138.07,55.4 134.57,58.9 134.57,66.69 136.3,68.41 136.3,69.01 135.92,69.39 134.13,69.39 132.67,70.85 132.67,71.79 130.94,73.52
SIO_SLP_S5#: length 6.6
  BOTTOM w0.089: 131.02,73.92 131.01,73.92 131.01,74.52 130.83,74.7 130.83,75.61 130.93,75.71 130.93,76.33 CPU1.AY16
  BOTTOM w0.102: TP1703.1 133.06,71.74 132.61,72.19 132.61,72.33 131.02,73.92
SKTOCC#: length 6.2
  BOTTOM w0.089: 102.15,99.6 103.04,98.7 103.04,97.71 CPU1.A65
  BOTTOM w0.102: 102.15,99.6 101.49,100.26 99.66,100.26 TP402.1
SLEEVE: length 11.3
  TOP w0.508: EC2906.1 181.63,18.71 v4(181.91,19)
  L3 w1.016: v4(175.82,19.42) 175.42,19.82 175.42,20.88 176.16,21.62 180.53,21.62 181.91,20.24 v4(181.91,19)
  vias: v2(181.44,19.94)
SLEEVE_R:
  vias: v1(188.07,19.08)
SLP_LAN#: length 2
  TOP w0.127: v1(131.15,77.55) 131.15,77.82 130.74,78.23 TP1704.1
  BOTTOM w0.127: v1(131.15,77.55) 131.19,77.5 131.19,76.97 CPU1.AW15
SLP_SUS#: length 1.6
  TOP w0.127: v1(131.21,80.38) 131.76,80.93 TP1702.1
  BOTTOM w0.127: CPU1.AN15 131.54,80.7 v1(131.21,80.38)
SM_DRAMRST#: length 73.1
  TOP w0.127: v1(147.85,67.86) 147.41,67.42 147.41,65.96 147.61,65.75 147.61,65.39 147.56,65.33 147.56,63.74 147.43,63.61 147.43,61.32 147.4,61.3 147.4,60.5 147.78,60.11 147.78,56.46 147.3,55.97 147.3,52.84 v2(145.86,51.41) 144.96,50.51 140.57,50.51 140.12,50.96 v1(140.11,50.96)
  L3 w0.089: 132.71,76.59 132.71,77.84 v1(132.12,78.43)
  L3 w0.127: 132.71,76.59 133.85,75.45 134.63,75.45 135.33,74.76 138.8,74.76 141.98,71.57 142,71.57 143.41,70.16 144.62,69.66 144.86,69.66 146.86,67.66 147.65,67.66 v1(147.85,67.86)
  BOTTOM w0.127: R504.1 140.9,50.87 140.44,50.41 ED502.1 140.29,50.78 v1(140.11,50.96) 140.01,50.86 136.78,50.86 126.15,61.49 126.15,61.5 125.94,61.72 125.94,61.93 125.94,64.59 125.36,65.17 R505.2 ; CPU1.AT13 v1(132.12,78.43)
SM_INTRUDER#: length 36.2
  TOP w0.102: v2(157.29,67.56) v1(157.66,68.01)
  L3 w0.102: v1(157.66,68.01) 155.29,68.01 154.56,68.74 153.62,68.74 152.26,67.38 146.51,67.38 144.4,69.49 143.28,69.95 141.9,71.33 141.88,71.33 139.34,73.87 137.99,73.87 137.36,74.51 134.79,74.51 134.08,75.21 133.75,75.21 131.58,77.38 131.58,77.73 131.33,77.98 131.04,77.98 130.77,78.26 130.77,79.28 v1(131.21,79.73)
  BOTTOM w0.102: v1(157.66,68.01) 157.71,67.96 157.99,67.96 158.51,67.74 R1730.2 ; CPU1.AP16 v1(131.21,79.73)
SM_PGCNTL: length 37.7
  L4 w0.127: v1(101.97,77.06) 101.97,77.51 103.28,78.82 103.28,80.55 102.49,81.35 101.49,81.35 98.17,84.67 96.58,84.67 96.41,84.85 95.6,84.85 95.58,84.87 94.91,84.87 94.76,84.72 89.87,84.72 81.26,76.12 v1(80.98,76.12)
  BOTTOM w0.127: v1(101.97,77.06) 101.85,76.93 CPU1.AW67 ; v1(80.98,76.12) 81.29,76.12 v2(82.6,77.43) 83.88,77.43 84.82,76.49 Q501.G
SM_PGCNTL_R: length 87.4
  TOP w0.127: v1(54.55,20.58) 50.47,20.58 46.67,16.78 40.03,16.78 39.33,17.48 PR5127.1 ; v1(76.45,69.86) 65.3,58.71 v2(65.3,57.24) 65.3,50.03 57.33,42.06 v1(51.58,42.06)
  L3 w0.127: v1(51.58,42.06) 52.2,41.44 52.2,33.43 53.35,32.28 53.35,30.54 53.35,30.54 53.35,25.39 53.35,25.39 53.98,24.76 53.98,23.49 53.98,22.16 54.16,21.25 54.55,20.87 v1(54.55,20.58)
  BOTTOM w0.127: Q502.D 80.42,71.88 R506.2 79.73,70.9 78.69,69.86 v1(76.45,69.86)
SM_RCOMP_0: length 4
  TOP w0.203: v2(128.2,81.58) 128.19,81.58 128.35,81.74 R501.1 128.94,81.59 128.94,80.6 128.93,80.58 128.93,80.21 128.94,80.19 128.94,80.16 v1(129.38,79.72)
  BOTTOM w0.305: CPU1.AR18 129.52,79.72 129.33,79.72 129.33,79.72 v1(129.38,79.72)
SM_RCOMP_1: length 1.3
  TOP w0.305: R502.1 130.21,78.39 130.23,78.4 v1(130.3,78.4)
  BOTTOM w0.305: CPU1.AT18 130.19,78.4 v1(130.3,78.4)
SM_RCOMP_2: length 25.2
  TOP w0.203: R503.1 140.6,58.85 v1(140.85,59.11)
  TOP w0.305: v1(140.85,59.11) 140.55,59.41 v2(140.55,59.57)
  L4 w0.305: v1(130.35,77.75) 130.61,77.49 130.61,76.91 135.29,72.23 135.5,72.23 137.96,69.77 137.96,69.36 139.8,67.52 139.8,60.19 140.85,59.13 v1(140.85,59.11)
  BOTTOM w0.305: CPU1.AU18 130.2,77.75 v1(130.35,77.75)
SMB_CLK_THM_R: length 12.1
  TOP w0.127: v1(192.59,122.76) 191.37,122.76 191.11,122.65 189.52,121.06 v1(189.47,121.06)
  BOTTOM w0.127: v1(189.47,121.06) 189.44,121.03 C2617.1 189.54,120.19 RN7903.3 ; Q7904.1 192.1,123.21 192.55,122.76 v1(192.59,122.76) 192.59,122.58 v2(193,122.17) 193.65,121.52 194.98,121.52 195.31,121.85 THM262.8
SMB_CLK_VGA: length 13
  TOP w0.14: R7912.2 177.74,127.35 180.91,130.52 180.91,132.16 180.01,133.05 180.01,134.89 180.41,135.28 180.56,135.28 v2(180.59,135.3) 180.55,135.34 180.55,135.45 180.3,135.7 180.21,135.7 180.21,135.71 180.2,135.71 180.2,135.71 v1(180.2,135.71)
  BOTTOM w0.114: v1(180.2,135.71) 180.2,135.71 180.2,135.71 180.21,135.71 180.21,135.7 180.18,135.7 180.18,135.71 180.17,135.7 179.66,135.7 179,136.36 GPU1.U7
SMB_CLK_VGA_R: length 9.9
  TOP w0.127: Q7901.1 173.14,125.95 173.14,126.25
  TOP w0.14: Q7901.1 173.62,125.77 174.05,125.34 174.05,124.08 173.05,123.09 173.05,122.45 173.26,122.24 173.57,122.24 ; R7912.1 176.13,126.83 v2(175.87,127.08) 175.87,127.06 175.85,127.04 173.93,127.04 173.14,126.25
  TOP w0.152: 173.57,122.24 RN7902.2
SMB_DATA_THM_R: length 14.1
  L4 w0.165: v1(193.85,120.62) 192.67,120.62 191.98,121.31 v1(190.63,121.31)
  BOTTOM w0.127: THM262.7 195.96,121.62 196.17,121.41 196.17,120.95 195.84,120.62 v2(194.49,120.62) v1(193.85,120.62) ; C2618.1 189.54,118.11 RN7903.4 190.08,118.8 190.3,119.03 190.3,120.98 v1(190.63,121.31) 190.63,121.44 190.17,121.91 Q7904.4
SMB_DATA_VGA: length 14
  TOP w0.14: R7914.2 177.88,126.03 v2(179.03,127.18) 179.58,127.72 179.58,128.59 181.21,130.22 181.21,132.29 180.3,133.2 180.3,134.52 v1(180.47,134.69)
  BOTTOM w0.114: v1(180.47,134.69) 180.27,134.89 179.68,134.89 179.36,135.21 179.36,135.64 178.3,136.7 GPU1.U8
SMB_DATA_VGA_R: length 6.2
  TOP w0.14: R7914.1 176.87,125.7 177.41,125.16 177.41,124.98 v2(177.24,124.8) 177,124.8 176.89,124.68 176.88,124.68 176.67,124.47 176.32,124.47
  TOP w0.152: RN7902.1 173.93,123.03 174.51,123.61 174.89,123.61 174.96,123.69 Q7901.4 176.32,124.47
SML0_SMBCLK: length 15.2
  TOP w0.191: v2(134.3,88.99) 134.74,88.99 v1(134.85,89.11)
  L3 w0.165: v1(146.05,87.25) 145.18,88.12 142.33,88.12 141.78,88.66 135.3,88.66 v1(134.85,89.11)
  BOTTOM w0.191: v1(146.05,87.25) 146.67,87.25 147,87.58 RN1807.5 ; CPU1.R9 v1(134.85,89.11)
SML0_SMBDATA: length 9.6
  BOTTOM w0.089: CPU1.W2 139.39,87.7 139.62,87.7 139.71,87.73 141.29,87.73 141.79,87.23
  BOTTOM w0.191: 141.79,87.23 141.92,87.1 141.93,87.1 144.4,87.1 145.05,87.76 146.36,87.76 v2(146.62,88.01) 146.77,88.16 RN1807.6
SML1_SMBCLK: length 219.3
  TOP w0.14: v1(174.15,126.11) 174.17,126.11 174.51,125.77 Q7901.6
  TOP w0.191: v1(165.68,55.24) v2(167.17,55.24) 167.58,55.24 168.74,56.41 171.77,56.41 172.75,55.43 176.37,55.43 178.42,57.47 178.42,57.96 179.94,59.47 180.37,59.47 180.99,60.1 180.99,67.93 182.5,69.43 182.5,74.47 186.42,78.39 186.42,81.24 188.58,83.4 188.58,89.03 187.12,90.5 187.12,90.52 181.36,96.28 v1(181.36,96.83)
  L3 w0.165: v1(165.68,55.24) 165.68,57.31 164.68,58.31 164.68,62.78 164.36,63.11 v1(164.36,63.58)
  L4 w0.165: v1(181.36,96.83) 181.36,96.21 179.13,93.98 176.6,93.98 176.32,93.71 167.19,93.71 162.07,98.82 162.07,100.03 162.04,100.06 161.73,100.37 158.72,103.38 158.72,104.66 158.45,104.93 158.05,104.93 157.34,105.63 157.34,107.28 155.38,109.24 153.4,109.24 150.86,111.79 150.86,113.5 152.28,114.92 152.28,115.4 152.81,115.93 153.01,115.93 155.14,118.05 155.14,118.05 155.61,118.53 155.61,118.54 156.78,119.71 164.52,119.71 165.53,120.72 166.55,120.72 166.57,120.74 171.1,120.74 172.47,122.11 172.47,123.89 173.77,125.19 v1(174.15,126.11) 174.27,125.99 174.27,123.77 174.89,123.15 176.64,123.15 177.89,124.4 177.89,124.78 179.9,126.79 185.44,126.79 186.1,126.13 186.97,126.13 187.24,125.86 187.24,124.58 v1(188.78,123.04) ; v1(146.55,88.71) 148.07,87.19 148.07,82.02 152.89,77.21 153.08,77.21 154.75,75.54 154.75,72.17 154.83,72.1 154.83,69.39 156.67,67.55 158.05,67.55 158.21,67.7 160.23,67.7 v1(164.36,63.58)
  BOTTOM w0.089: CPU1.W3 138.92,87.88 139.59,87.88 139.68,87.91 141.51,87.91 141.98,87.44
  BOTTOM w0.152: R2439.2 163.53,50.98 163.53,51.62 162.88,52.27 162.88,52.38 162.87,52.39 162.87,53.15 162.87,53.16 162.87,53.24 164.53,54.89 165.33,54.89 v1(165.68,55.24)
  BOTTOM w0.191: 141.98,87.44 142.04,87.38 144.2,87.38 144.85,88.03 145.88,88.03 v1(146.55,88.71) 146.6,88.66 RN1807.7 ; Q7904.6 189.2,123.21 189.03,123.04 v1(188.78,123.04)
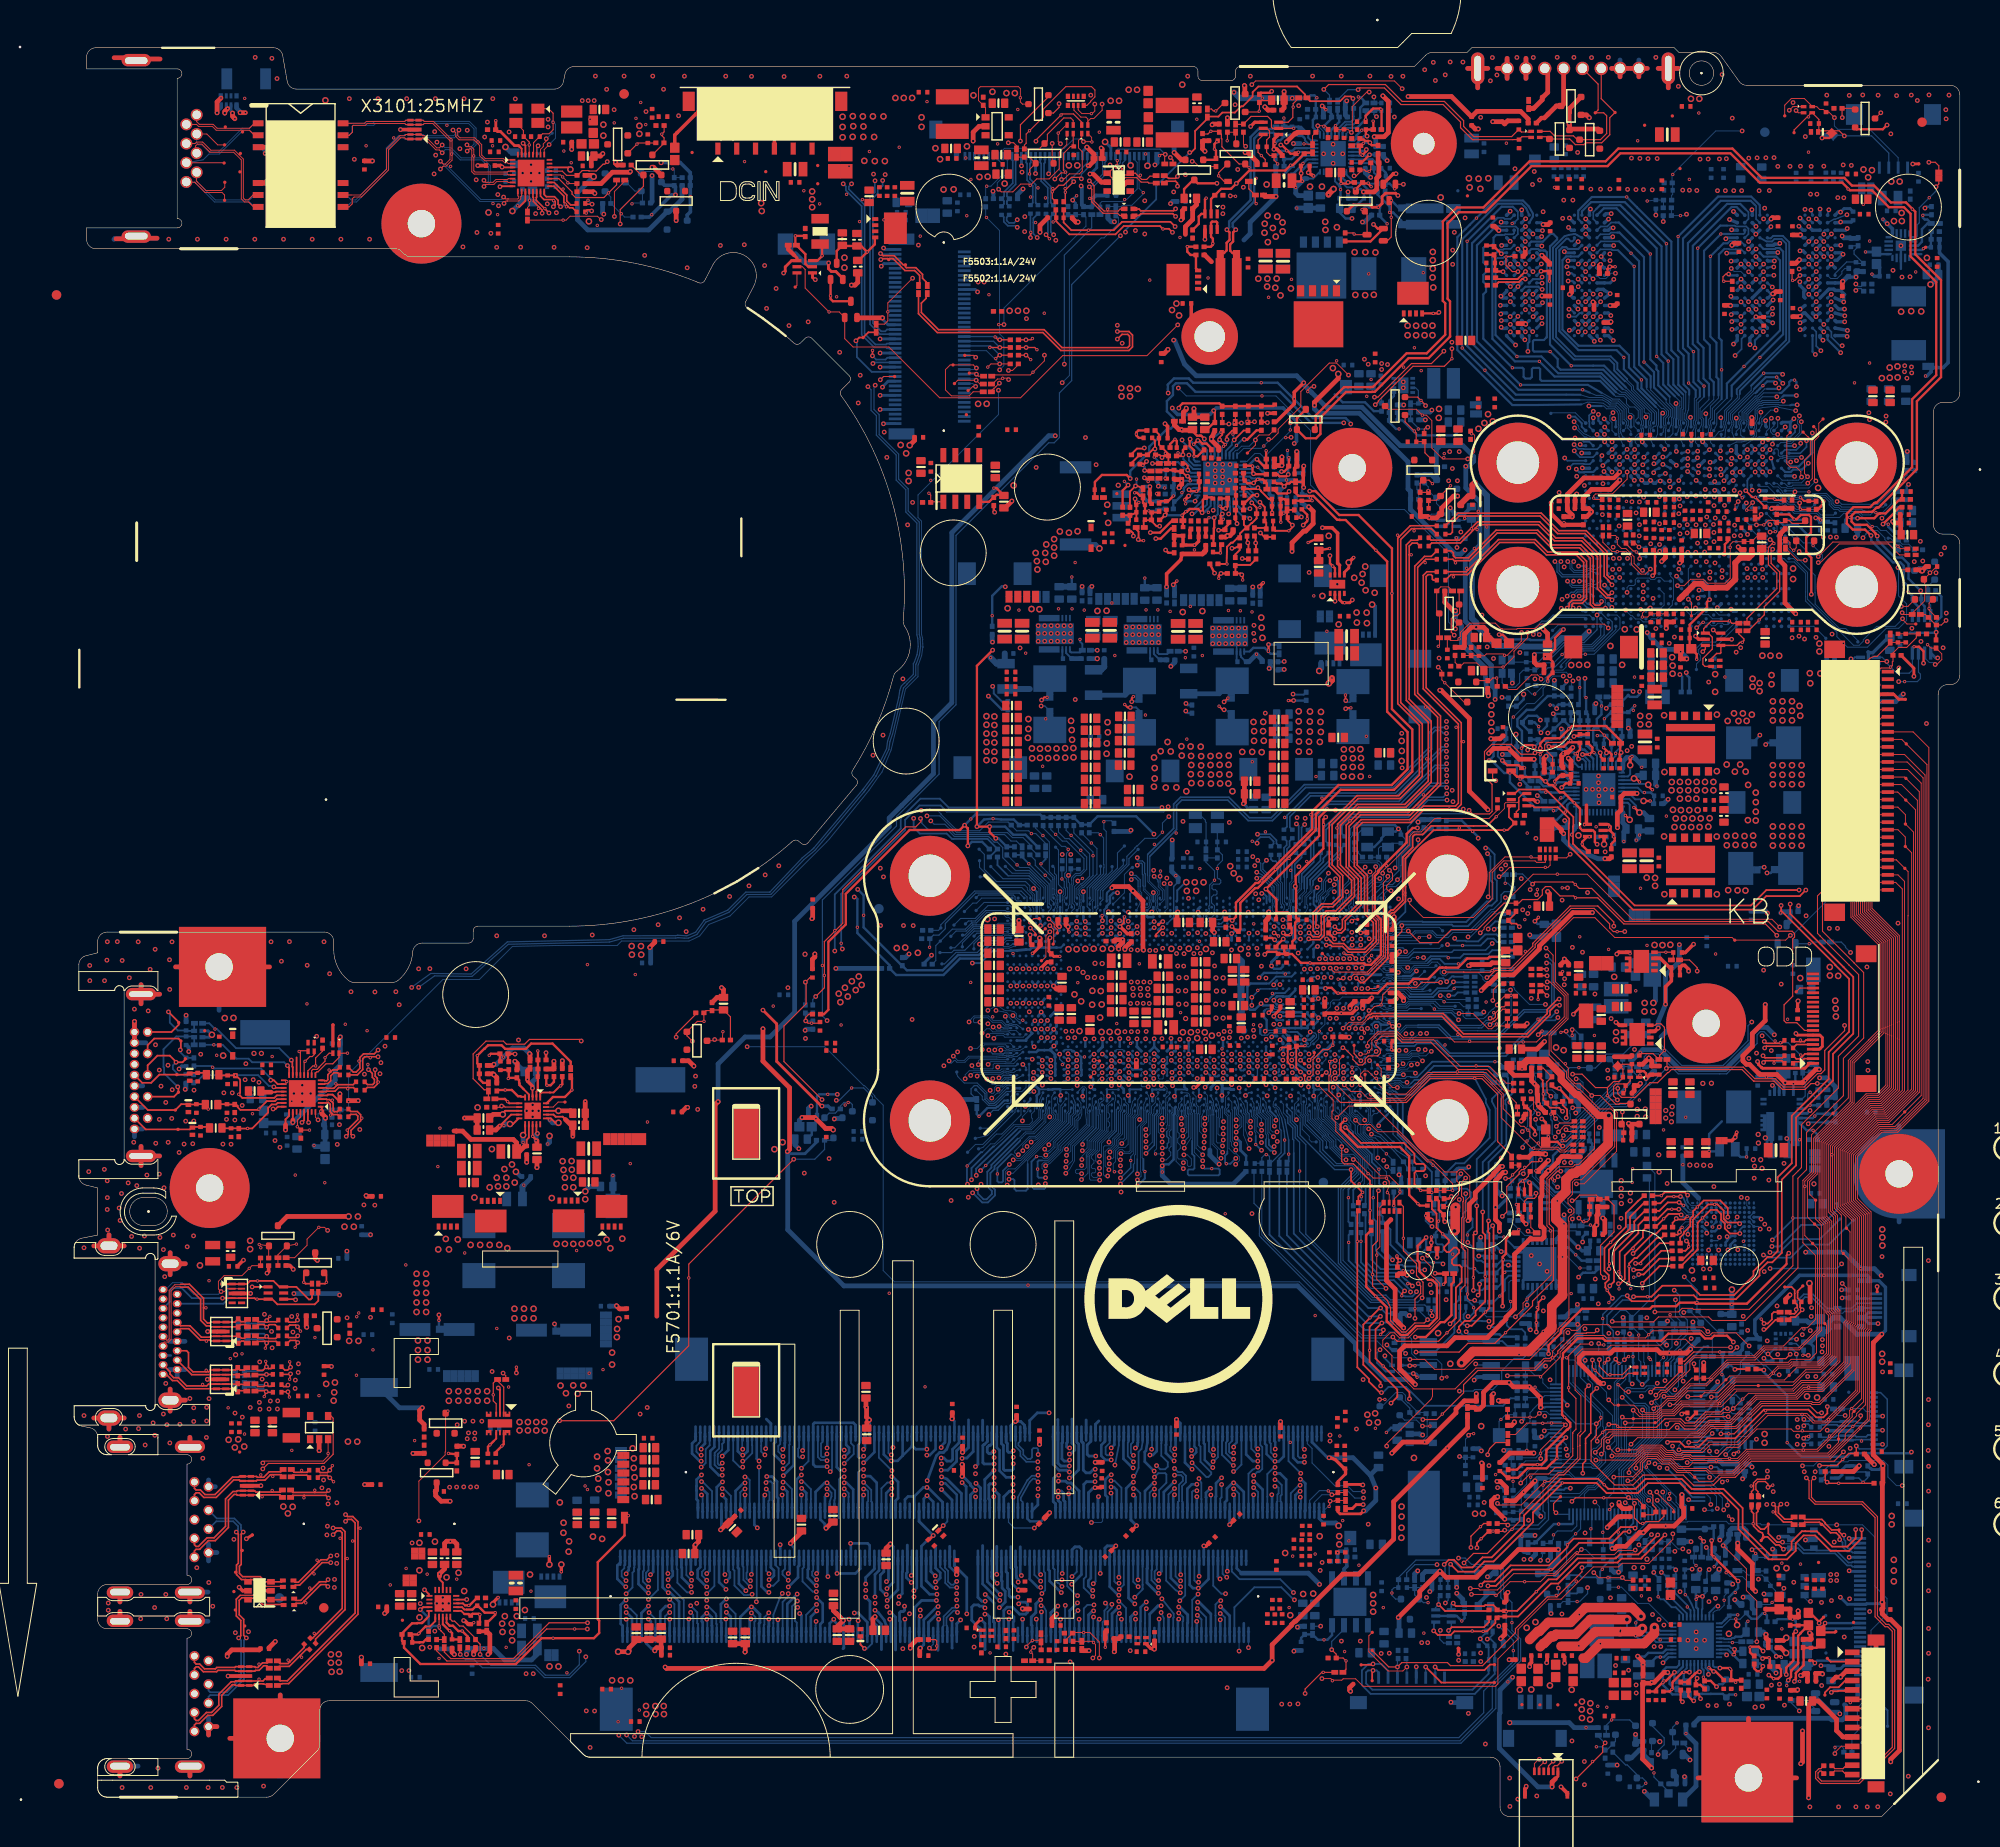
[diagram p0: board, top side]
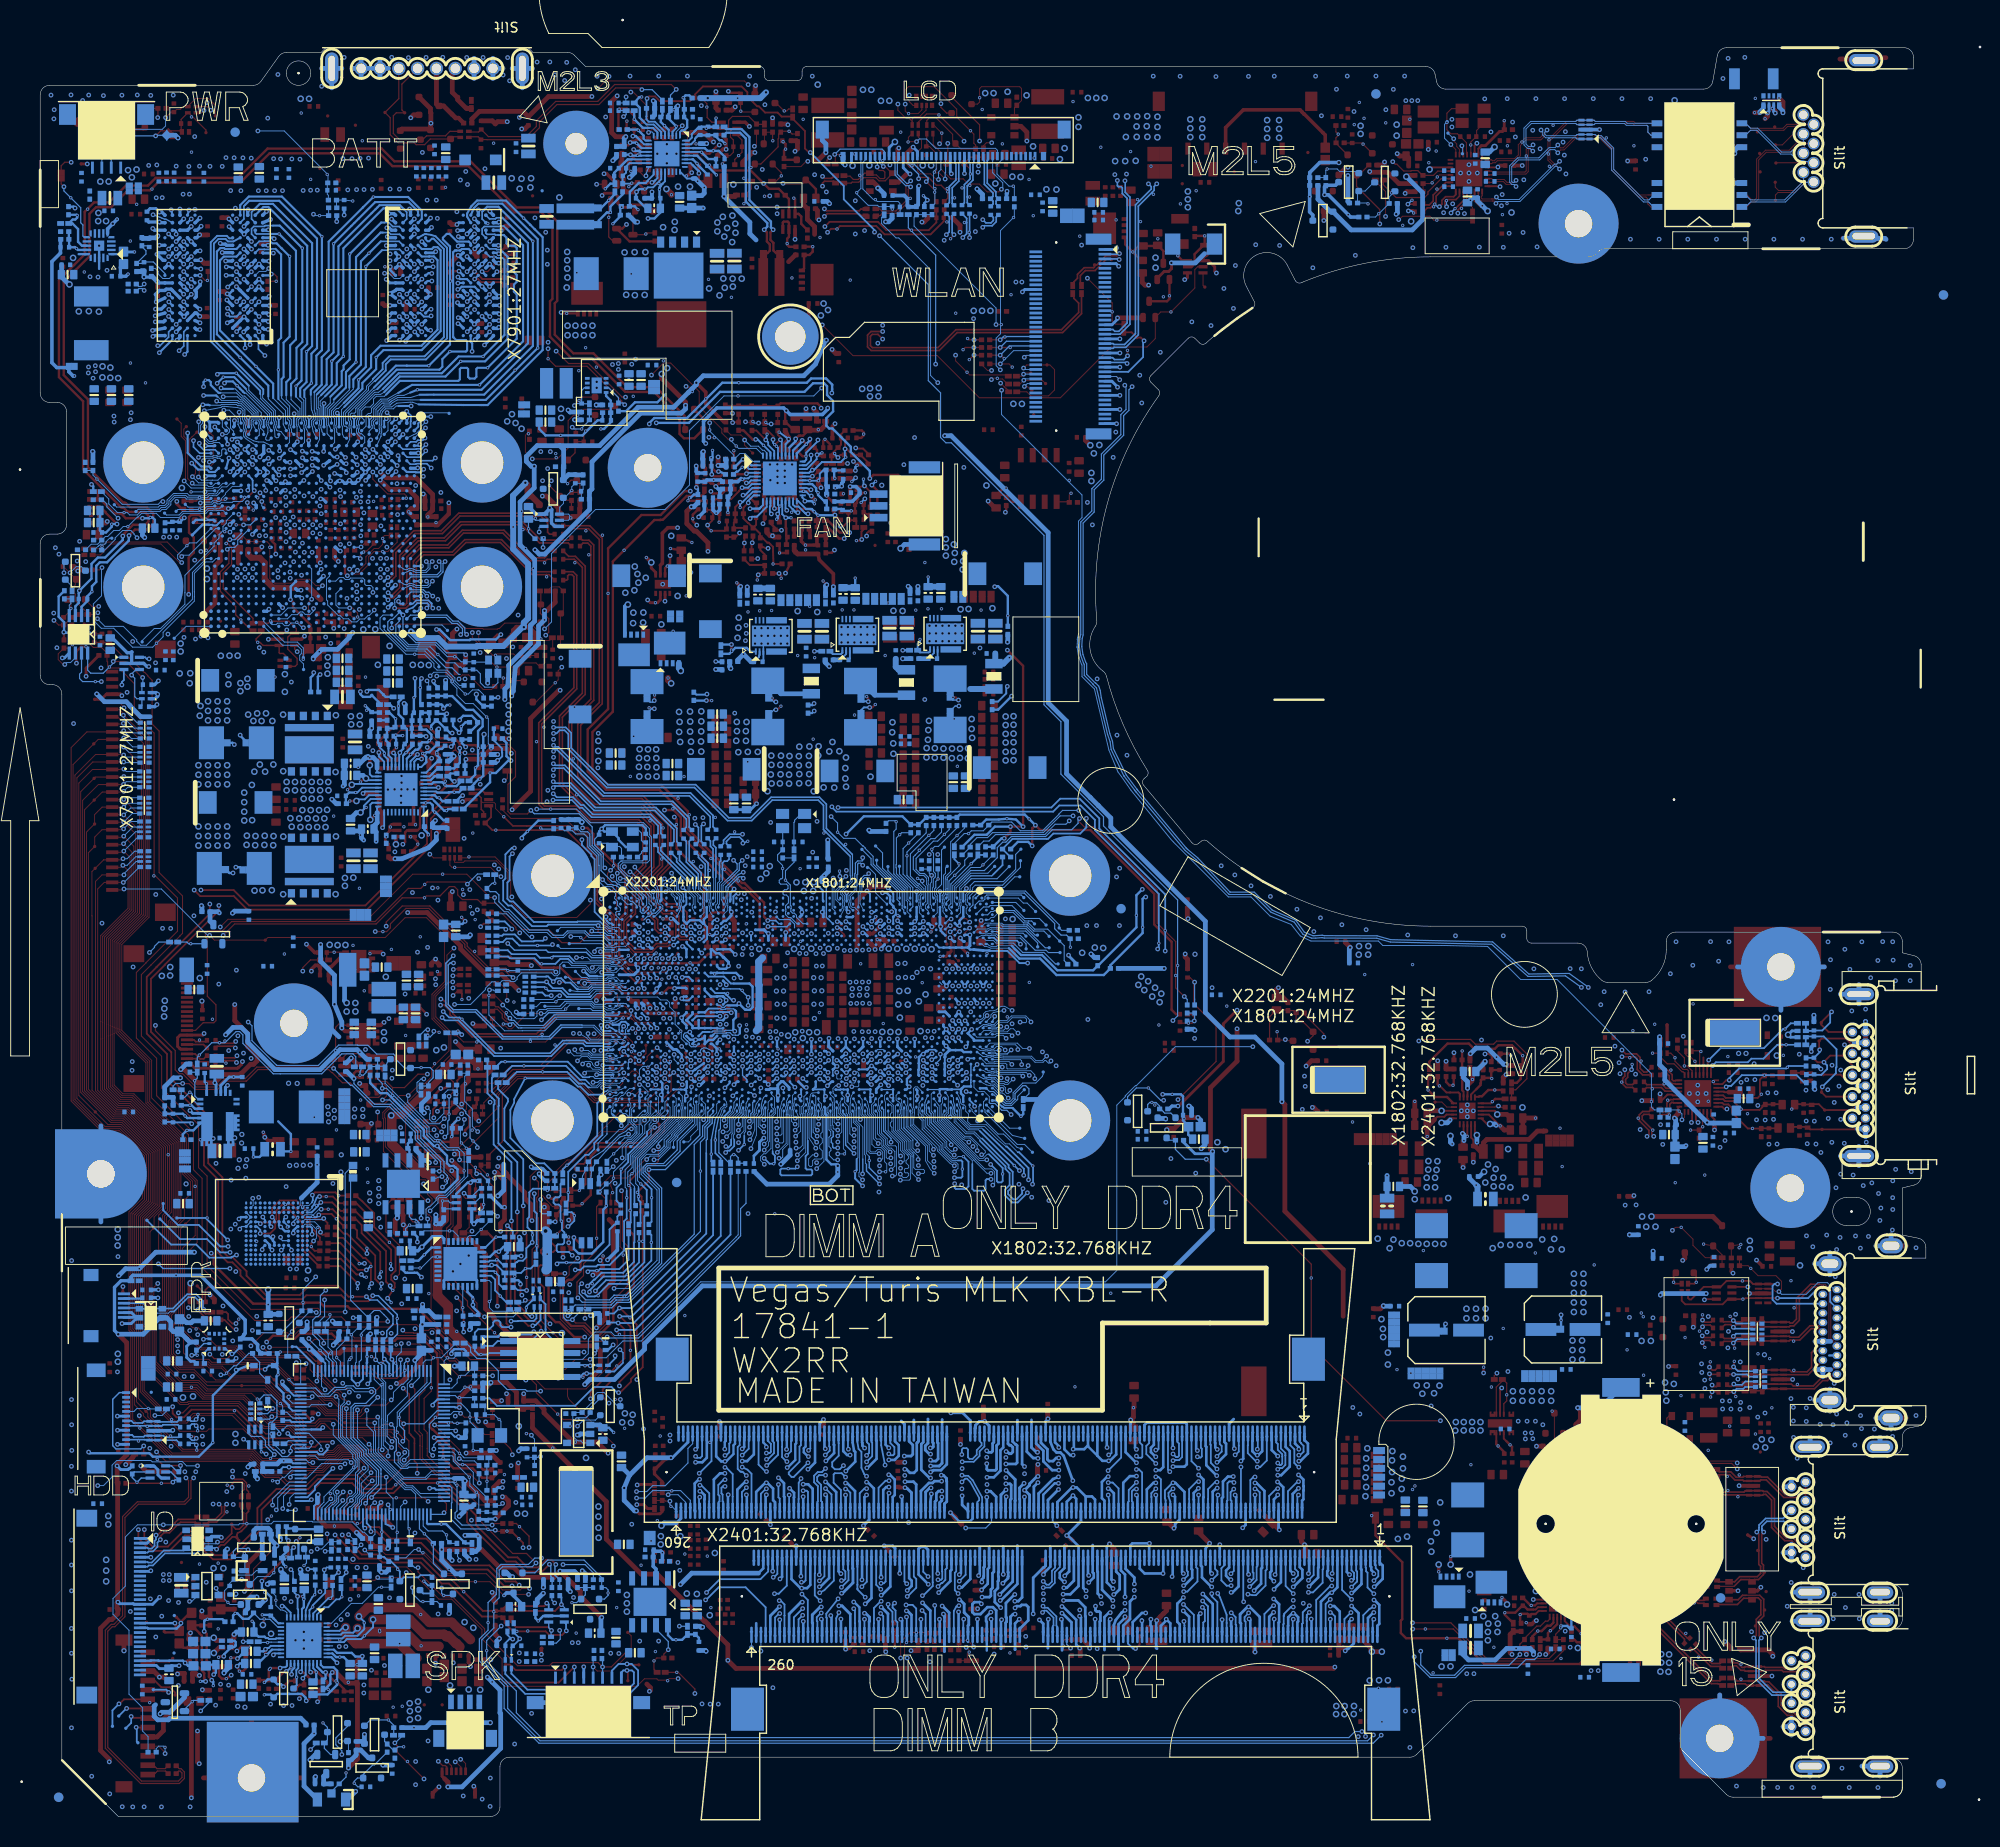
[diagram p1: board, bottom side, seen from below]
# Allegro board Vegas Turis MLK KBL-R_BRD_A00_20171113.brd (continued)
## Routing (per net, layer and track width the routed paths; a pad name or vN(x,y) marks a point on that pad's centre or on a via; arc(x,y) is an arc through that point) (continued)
SML1_SMBDATA: length 222
  TOP w0.152: v1(173.04,123.81) 173.31,124.08 Q7901.3
  TOP w0.191: v1(182.33,96.98) 182.33,95.94 188,90.27 188,90.26 189.03,89.23 189.03,83.2 186.88,81.05 186.88,78.21 182.95,74.29 182.95,69.21 181.44,67.69 181.44,59.91 180.42,58.9 179.93,58.9 179.07,58.04 179.07,57.49 176.56,54.98 172.49,54.98 172.08,55.39 168.36,55.39 167.73,54.77 165.49,54.77 165.02,55.23 v1(165.02,55.35)
  L3 w0.165: v1(164.17,62.64) 164.17,58.08 164.74,57.51 164.74,57.12 164.66,57.05 164.66,55.71 v1(165.02,55.35)
  L4 w0.165: v1(191.67,120.27) 190.91,120.27 189.66,121.52 188.54,121.52 186.77,123.29 186.77,124.84 185.09,126.52 180.7,126.52 180.23,126.52 178.31,124.61 178.31,124.23 176.82,122.73 174.13,122.73 v1(173.04,123.81) 173.04,122.09 171.27,120.32 166.75,120.32 166.72,120.3 165.7,120.3 164.7,119.29 156.96,119.29 156.03,118.37 156.03,118.36 155.55,117.88 155.55,117.88 153.19,115.51 152.99,115.51 152.7,115.22 152.7,114.49 151.28,113.07 151.28,112.05 153.15,110.18 155.04,110.18 157.76,107.46 157.76,105.81 158.22,105.35 158.62,105.35 159.14,104.83 159.14,103.55 162.49,100.2 162.49,99 167.36,94.13 176.15,94.13 176.42,94.4 178.96,94.4 180.38,95.82 180.38,96.5 181.17,97.29 182.02,97.29 v1(182.33,96.98) ; v1(164.17,62.64) 164.17,63.1 160.7,66.57 158.06,66.57 157.92,66.43 157.19,66.43 154.39,69.23 154.39,71.84 154.33,71.9 154.33,75.37 152.91,76.79 152.71,76.79 147.65,81.85 147.65,86.91 v1(145.83,88.73)
  BOTTOM w0.089: CPU1.V3 138.43,88.14 138.66,88.37 138.74,88.4 138.94,88.4 139.03,88.36 139.29,88.36 139.39,88.4 139.59,88.4 139.67,88.36 139.89,88.28 141.74,88.28 141.76,88.26
  BOTTOM w0.14: 141.76,88.26 142.11,87.91 143.17,87.91 ; v2(162.41,52.92) 162.46,52.88
  BOTTOM w0.152: v1(165.02,55.35) 164.42,55.35 162.41,53.35 v2(162.41,52.92) ; 162.46,52.88 162.46,52.42 162.39,52.35 162.39,51.28 R2438.2
  BOTTOM w0.191: v1(191.67,120.27) 191.67,120.58 191.46,120.79 Q7904.3 ; RN1807.8 147.91,89.26 146.61,89.26 146.57,89.29 146.4,89.29 v1(145.83,88.73) 145.47,89.09 145,89.09 144.76,88.85 144.76,88.84 144.55,88.63 144.02,88.63 143.31,87.92 143.27,87.91 143.17,87.91
SPI_CLK_CPU: length 13.5
  BOTTOM w0.089: CPU1.AV2 139.1,77.73 140.3,77.73 140.43,77.87 140.75,77.87 141.16,77.46 141.93,77.46 141.97,77.5
  BOTTOM w0.191: R1806.2 149.7,79.14 v2(146.96,79.14) 144.37,79.14 143.12,77.89 142.52,77.89 142.12,77.5 141.97,77.5
SPI_CLK_CRT: length 3.7
  TOP w0.127: U5601.11 24.84,79.25 25.36,79.77 v2(25.66,79.77) 25.66,80.62 26.39,81.36 R5613.2
SPI_CLK_ROM: length 47
  TOP w0.191: v1(148.67,55.91) v2(148.67,57.3) 148.67,61.81 v1(148.89,62.03) 149.03,62.17 v1(149.03,64.9)
  L3 w0.165: v1(148.89,62.03) 148.48,61.63 146.35,61.63 144.28,59.56 144.28,59.45 143.72,58.88 142.15,58.88 139.87,56.6 139.87,55.96 138.14,54.23 138.14,49.56 138.74,48.96 v1(139.26,48.96)
  BOTTOM w0.191: v1(149.03,64.9) 149.03,69.86 150.66,71.49 151.03,71.86 151.03,75.25 150.63,76.01 150.67,76.31 151.7,77.33 R1806.1 ; R9138.1 149.89,56.22 149.61,55.94 148.69,55.94 v1(148.67,55.91) ; v1(139.26,48.96) 139.22,48.92 139.22,48.73 140.01,47.93 RN2503.4
SPI_CLK_ROM_R: length 3.4
  TOP w0.191: v2(142.47,47.91) v1(141.91,47.91)
  BOTTOM w0.191: RN2503.1 141.69,47.95 141.73,47.91 v1(141.91,47.91) 141.99,47.98 SPI25.6
SPI_CLK_ROM_TPM2: length 3.5
  BOTTOM w0.191: U9103.19 152.14,57.97 v2(151.99,57.83) 151.61,57.45 151.61,56.61 151.22,56.22 R9138.2
SPI_CS2#_R_TPM2: length 14.7
  TOP w0.191: v1(155.36,51.49) v2(155.36,52.49) 155.36,53.64 155.59,53.87 155.59,54.64 v1(156.09,55.15)
  L3 w0.165: v1(156.09,55.15) 153.65,55.15 152.38,56.42 v1(152.38,58.6)
  BOTTOM w0.191: U9103.20 152.51,58.47 v1(152.38,58.6) 151.85,58.6 151.02,57.77 R9130.2 150.98,57.77 R9140.2 ; v1(155.36,51.49) 155.42,51.55 R9122.2
SPI_CS_CPU_N0: length 14.3
  BOTTOM w0.089: 142.03,77.91 142.03,77.9 141.77,77.64 141.23,77.64 140.83,78.04 140.36,78.04 140.25,77.93 138.77,77.93 CPU1.AU3
  BOTTOM w0.165: 142.42,78.3 142.03,77.91
  BOTTOM w0.191: 142.42,78.3 143,78.3 144.48,79.78 v2(148.96,79.78) 150.2,79.78 R1812.2
SPI_CS_CPU_N2: length 23.5
  L4 w0.165: v1(141.61,78.02) 142.09,77.54 142.09,72.84 144.15,70.79 144.38,70.79 144.7,70.68 145.49,70.43 146.87,69.05 146.87,67.19 v1(147.85,66.2)
  BOTTOM w0.114: CPU1.AU1 140.24,78.19 140.28,78.23 140.9,78.23 141.11,78.02 v1(141.61,78.02)
  BOTTOM w0.191: v2(147.58,60.65) 147.6,60.65 ; 147.6,60.65 147.6,59.74 R1814.2 ; 147.6,60.65 147.6,64.09 147.85,64.35 v1(147.85,66.2)
SPI_CS_ROM_N0: length 37
  TOP w0.191: v1(149.66,64.25) 149.66,62.07 149.92,61.81 v2(149.92,57.41) 149.92,54.73 148.9,53.72 148.9,53.27 148.3,52.67 147.74,52.67 147.12,52.05 v1(147.12,51.58)
  BOTTOM w0.178: 151.75,50.52 150.66,50.52 SPI25.1 SKT251.1 148.18,50.52 v1(147.12,51.58)
  BOTTOM w0.191: v1(149.66,64.25) 149.66,69.54 151.67,71.55 151.67,75.5 151.63,75.54 151.63,76.3 152.36,77.03 152.36,78.48 R1812.1 ; 151.75,50.52 152.26,50.01 R2501.2
SPI_CS_ROM_N2: length 2.9
  BOTTOM w0.191: R1814.1 148.23,58.24 v2(148.79,58.24) 149.26,57.77 R9130.1
SPI_HOLD_CPU: length 15.3
  BOTTOM w0.114: 141.96,78.64 141.6,78.64 141.4,78.44 140.67,78.44 140.65,78.47
  BOTTOM w0.127: CPU1.AU4 138.14,78.47 140.64,78.47 140.65,78.47
  BOTTOM w0.178: 141.96,78.64 142.03,78.57 142.69,78.57 143.6,79.48
  BOTTOM w0.191: 143.6,79.48 143.6,79.52 144.3,80.22 v2(150.95,80.22) 151.37,80.22 R1811.2
SPI_HOLD_ROM: length 33.3
  TOP w0.191: v1(150.28,63.3) 150.24,63.26 150.24,62.13 150.36,62 150.36,54.03 v2(149.95,53.62) 148.49,52.15 v1(148.02,52.15)
  BOTTOM w0.191: R1827.2 152.83,80.33 R1811.1 152.83,76.87 152.36,76.39 152.35,76.39 152.07,76.12 152.07,75.72 152.17,75.62 152.17,71.42 150.28,69.53 v1(150.28,63.3) ; v1(148.02,52.15) 148,52.15 147.92,52.23 147.72,52.23 147.18,52.77 147.18,53.53 147.24,53.59 147.22,53.61 RN2502.4
SPI_HOLD_ROM_R: length 8.6
  BOTTOM w0.191: SKT251.7 144.48,49.25 146.65,51.42 146.65,51.78 146.66,51.79 146.66,54.45 147.22,55.01 RN2502.1 147.24,55.09 147.24,55.95 RN2501.2
SPI_IRQ#_TPM2: length 4.7
  BOTTOM w0.191: U9103.18 152.43,57.47 152.02,57.07 152.02,55.91 151.48,55.37 v2(151.48,55.31) 150.82,54.66 R9152.2
SPI_SI_CPU: length 26.2
  BOTTOM w0.089: CPU1.AV3 138.62,77.28 138.89,77.21 140.06,77.21
  BOTTOM w0.14: 140.38,77.07 140.21,77.07 140.06,77.21
  BOTTOM w0.191: R1808.2 145.67,66.78 R1825.1 145.66,67.57 R1824.2 145.66,68.38 145.8,68.43 146.79,69.42 147.7,69.42 150.4,72.13 150.4,75.09 149.99,75.85 149.99,76.23 v2(148.82,78.46) 144.1,78.46 143.21,77.58 142.96,77.58 142.09,76.71 140.74,76.71 140.38,77.07
SPI_SI_CRT: length 3.1
  TOP w0.127: U5601.12 24.44,80.16 v2(24.54,80.27) 25.05,80.77 25.3,80.77 25.5,80.98 RN5603.4
SPI_SI_ROM: length 31.6
  L3 w0.165: v1(138.75,49.61) 138.75,50.59 140.48,52.32 140.48,56.23 141.33,57.08 141.83,57.08 141.97,57.22 143.28,57.22 147.07,61.02 v1(148.07,61.02)
  BOTTOM w0.152: v1(138.75,49.61) 138.43,49.29 138.43,48.22
  BOTTOM w0.191: R1808.1 146.59,66.72 148,66.72 148.39,66.34 148.39,63.71 148.58,63.53 148.58,62.62 148.04,62.08 v2(148.04,61.81) 148.04,61.81 148.04,61.05 v1(148.07,61.02) 148.7,60.39 148.7,59.43 149.06,59.07 149.53,59.07 149.69,58.91 149.75,58.91 R9133.1 ; RN2503.3 139.35,47.3 138.43,48.22
SPI_SI_ROM_R: length 3.6
  TOP w0.191: v2(142.69,46.68) v1(142.29,47.08)
  BOTTOM w0.191: RN2503.2 141.44,47.3 141.66,47.08 v1(142.29,47.08) 142.63,47.08 143,46.71 SPI25.5
SPI_SI_ROM_TPM2: length 2.6
  BOTTOM w0.191: U9103.21 152.68,58.97 152.58,59.08 151.93,59.08 v2(151.84,59.17) 151.73,59.17 151.14,58.59 R9133.2
SPI_SO_CPU: length 15.1
  BOTTOM w0.089: CPU1.AW3 138.76,76.94 139.08,76.62 139.42,76.62 139.63,76.4 140,76.4
  BOTTOM w0.178: 140.62,73.52 140.62,75.78 140,76.4
  BOTTOM w0.191: R1807.2 144.48,65.25 144.25,65.49 v2(144.25,66.32) 144.25,68.51 142.44,70.32 142.08,70.32 141.49,70.92 141.49,71.58 140.62,72.44 140.62,73.52
SPI_SO_CRT: length 3.6
  TOP w0.127: U5601.13 24.04,81.18 v2(23.91,81.31) 23.99,81.39 24.8,81.39 RN5603.3
SPI_SO_ROM: length 28.6
  TOP w0.191: v1(150.32,52.01) 150.41,52.01 150.81,52.41 150.81,62.69 v1(150.71,62.79)
  L3 w0.165: v1(144.28,62.71) 145.5,63.93 146.43,63.93 146.44,63.92 149.34,63.92 149.47,63.79 150.45,63.79 150.74,63.5 150.74,62.82 v1(150.71,62.79)
  BOTTOM w0.191: R2507.1 154.17,51.43 153.82,51.79 152.63,51.79 152.22,52.2 152.22,52.51 152.03,52.7 151.65,52.7 151.46,52.51 151.46,52.2 151.26,52.01 v1(150.32,52.01) ; R1807.1 143.88,64.23 143.6,63.95 v2(143.6,63.86) 143.6,63.31 144.2,62.71 v1(144.28,62.71) ; v1(150.71,62.79) 150.13,62.21 R9132.1
SPI_SO_ROM_R: length 4.2
  BOTTOM w0.191: R2507.2 154.17,49.5 153.77,49.09 v2(153.52,49.09) 152.84,49.09 152.68,49.25 SPI25.2
SPI_SO_ROM_TPM2: length 2.7
  BOTTOM w0.191: U9103.24 153.05,60.47 151.94,61.59 v2(151.91,61.59) R9132.2
SPI_WP_CPU: length 11.6
  BOTTOM w0.089: CPU1.AW2 139.6,76.94 139.7,77.03 139.95,77.03 140.38,76.61
  BOTTOM w0.191: R1809.2 144.83,68.77 v2(144.38,69.22) 144.36,69.22 144.3,69.28 144.2,69.33 141.16,72.36 141.16,75.82 140.38,76.61
SPI_WP_ROM: length 26.3
  L4 w0.165: v1(143.82,59.64) 143.82,59.77 144.02,59.97 144.97,59.97 148.19,56.75 148.49,56.75 149.8,55.44 149.8,53.47 150.32,52.95 v1(150.32,52.65)
  BOTTOM w0.191: R1809.1 145.06,67.21 145.06,65.99 145.25,65.8 145.61,65.8 145.8,65.61 145.8,65.23 145.61,65.04 145.25,65.04 145.06,64.85 145.06,63.37 v2(144.97,63.27) 144.91,63.22 144.91,62.33 144.66,62.07 R1828.2 144.67,61.68 144.67,60.98 144.84,60.81 145.35,60.81 145.47,60.68 145.47,60.15 145.32,60 144.17,60 v1(143.82,59.64) ; v1(150.32,52.65) 149.6,52.65 149.57,52.67 147.9,52.67 147.63,52.95 147.63,53.34 147.87,53.59 RN2502.3
SPI_WP_ROM_R: length 10.7
  L4 w0.165: v1(148.1,53.15) 148.1,52.73 148.56,52.27 148.56,48.46 v1(148.91,48.1)
  BOTTOM w0.127: v1(148.91,48.1) 149.03,47.98 SKT251.3
  BOTTOM w0.191: RN2501.1 147.97,55.18 RN2502.2 148.11,54.82 148.11,54.81 148.69,54.23 v2(148.69,54.07) 148.71,54.05 148.71,53.55 148.31,53.15 v1(148.1,53.15)
SPKR: length 74.5
  TOP w0.254: v2(144.21,61.59) 144.21,61 v1(144.19,60.99) 144.19,60.61 R2006.2
  L3 w0.254: v1(168.46,37.08) 168.46,35.53 172.26,31.73 172.26,29.4 173.06,28.6 v1(173.42,28.6)
  L4 w0.254: 144.19,60.98 v1(144.19,60.99) ; 144.19,60.98 143.14,59.92 141.7,59.92 140.97,60.64 140.97,67.69 141.28,67.99 141.28,68.42 140.97,68.72 140.97,68.75 138.44,71.28 138.44,72.24 138.46,72.26 138.46,72.78 138.44,72.8 138.44,73.25 v1(138.61,73.42) ; 144.19,60.98 144.51,60.66 144.96,60.66 148.32,57.29 149.32,57.29 150.26,56.35 150.26,53.66 150.84,53.09 150.84,51.44 157,45.28 158.9,45.28 162.55,41.63 162.55,41.47 163.66,40.35 165.82,40.35 168.47,37.69 168.47,37.1 v1(168.46,37.08)
  BOTTOM w0.089: CPU1.AW5 137.73,77.39 138.19,76.92 138.19,76.87 138.43,76.63 138.58,76.63 138.89,76.31
  BOTTOM w0.102: 138.89,76.31 138.89,76.14 139.06,75.97 139.26,75.97 139.49,75.74 139.49,75.3 139.67,75.12 139.67,74.75 139.54,74.62
  BOTTOM w0.203: R2741.1 173.64,27.56 173.64,28.37 v1(173.42,28.6)
  BOTTOM w0.254: v1(138.61,73.42) 138.61,73.68 139.54,74.62
SPV10: length 13.8
  TOP w0.254: v2(185.55,137.8) 185.32,138.03 v1(185.04,138.03)
  L3 w0.254: v1(177.79,143.7) 177.77,143.68 177.77,142.55 178.51,141.81 179.94,141.81 183.77,137.97 184.99,137.97 v1(185.04,138.03)
  BOTTOM w0.254: v1(185.04,138.03) 185.45,137.62 C8055.1 185.53,137.62 C8056.1 186.41,137.5 L8003.2 ; v1(177.79,143.7) 178.19,144.1 GPU1.H8
SPV18: length 23.8
  TOP w0.254: v1(189.48,137.99) 191.26,137.99 191.74,138.46 191.83,138.46 191.86,138.5 192.46,138.5 193.85,139.88 194.11,139.99 L8002.2 194.21,140.01 C8054.1
  L3 w0.254: v1(178.6,143.7) 178.13,143.23 178.13,142.7 178.66,142.17 180.08,142.17 183.72,138.53 188.94,138.53 v1(189.48,137.99)
  BOTTOM w0.254: C8053.1 188.16,137.82 188.41,138.07 v2(188.65,138.07) 188.68,138.07 188.77,137.99 v1(189.48,137.99) ; GPU1.H7 v1(178.6,143.7)
SRTC_RST#: length 56.5
  TOP w0.127: C1902.1 164.83,77.11 EC1806.1 ; EC1806.1 164.65,77.86 163.85,77.86 163.56,77.57 163.56,76.57 v1(163.98,76.16) ; EC1806.1 165.33,78.18 RN1901.4
  L3 w0.127: v1(139.27,67.3) 139.27,67.74 140.89,69.37 142.87,69.37 142.88,69.36 144.01,68.9 146.22,66.68 154.66,66.68 154.91,66.94 157.46,66.94 157.51,66.92 157.55,66.88 157.61,66.88 157.61,66.89 v1(157.61,66.89)
  L4 w0.127: v1(129.37,80.39) 129.85,79.91 129.85,77.47 130.17,77.15 130.17,76.72 135.62,71.27 135.97,71.27 137.08,70.17 137.08,69.49 v1(139.27,67.3)
  BOTTOM w0.127: CPU1.AN18 129.68,80.7 v1(129.37,80.39) ; v1(157.61,66.89) 157.61,66.89 157.61,66.88 157.55,66.88 157.08,67.34 v2(157.08,67.75) 157.08,68.1 157.44,68.46 157.44,69.61 159.91,72.08 159.91,72.86 163.21,76.16 v1(163.98,76.16)
SUS_CLK: length 36.4
  TOP w0.191: v1(138.9,45.05) 138.74,45.05 137.58,46.22 137.58,46.51 136.33,47.75 v2(136.33,61.13) 136.33,64.26 R1813.2
  BOTTOM w0.191: R2428.1 152.62,44.45 151.82,43.65 143.51,43.65 141.51,45.65 139.65,45.65 139.05,45.05 v1(138.9,45.05)
SUSACK#_R: length 31.9
  TOP w0.127: v1(133.99,80.35) 133.51,80.35 v2(133.4,80.25) 133.4,79.51 133.48,79.43 133.48,78.89 133.32,78.73 133.32,77.12 134.55,75.89 141.54,75.89 144.08,78.43 149.58,78.43 151.25,76.76 151.25,71.73 152.73,70.25 R1708.2
  BOTTOM w0.127: CPU1.AP11 133.6,80.05 133.9,80.35 v1(133.99,80.35)
SUSCLK_R: length 14.6
  TOP w0.191: R1813.1 136.45,65.88 v2(136.9,66.33) 135.67,67.56 135.67,68.76 v1(135.67,68.76)
  BOTTOM w0.089: 130.26,73.77 130.26,74.23 129.81,74.68 129.81,75.09 129.85,75.18 129.85,75.41 CPU1.BA17
  BOTTOM w0.14: v1(135.67,68.76) 133.93,68.76 130.26,72.42 130.26,73.77
SYS_PRES1#: length 5.6
  TOP w0.508: BATT1.6 156.57,185.48 156.57,183.25 156.05,182.74 AFTP4305.1 155.98,182.46 155.09,181.56 154.95,181.56 154.95,181.54 R4301.1
SYS_PWROK: length 135.6
  L3 w0.127: v1(140.6,99.57) 142.93,101.89 143.88,101.89 144.65,102.67 147.45,102.67 149.02,101.1 151.23,101.1 v1(151.63,100.7) ; v1(192.09,59.51) 189.76,59.51 186.14,55.89 186.14,53.32 v1(184.46,51.64)
  L4 w0.127: v1(184.46,51.64) 184.45,51.65 183.1,51.65 182.58,51.13 182.58,50.92 182.56,50.9 182.56,50.54 182.58,50.51 182.58,49.79 182.36,49.57 182.14,49.57 182.13,49.56 180.2,49.56 180.16,49.6 179.99,49.6 178.92,50.68 176.67,50.68 176.48,50.87 176.11,50.87 175.62,50.38 175.62,50.37 175.34,50.1 174.95,50.1 174.24,50.81 173.97,50.81 173.92,50.76 173.3,50.76 173.26,50.81 v1(171.81,50.81) ; v1(151.63,100.7) 153.11,99.23 153.11,99.02 153.85,98.29 153.88,98.29 156.22,95.94 156.86,95.94 161.88,90.93 161.88,90.87 162.49,90.26 162.5,89.24 162.5,89.24 163.63,88.11 169.79,88.11 170.02,87.87 170.08,87.87 170.09,87.86 177.77,87.86 177.78,87.87 178.11,87.87 180.23,89.98 184.89,89.98 185.97,91.06 186.86,91.06 189.62,88.3 189.62,71.51 188.6,70.5 188.6,65.5 191.45,62.65 191.45,60.14 v1(192.09,59.51)
  BOTTOM w0.127: v1(171.81,50.81) 171.81,50.74 v2(170.62,49.55) 169.98,48.91 169.98,48.64 169.66,48.32 KBC24.28 ; EC1702.1 143.42,105.08 R1717.2 143.32,105.09 142.89,104.66 142.18,104.66 141.96,104.43 141.96,103.15 141,102.19 141,101.1 140.97,101.07 140.97,99.94 v1(140.6,99.57) 140.08,99.04 139.52,99.04 139.44,98.96 139.17,98.96 139.08,98.87 139.01,98.87 137.88,97.75 137.88,97.52 137.63,97.27 137.42,97.27 136.97,96.81 CPU1.B6
SYSPWR_PRES: length 6.3
  TOP w0.102: R2453.2 152.3,42.44 R2455.1 v2(154.69,42.44) 155.27,42.44 v1(155.68,42.85)
  BOTTOM w0.102: KBC24.120 156.73,42.73 156.43,43.04 155.87,43.04 v1(155.68,42.85)
TESTEN: length 21.1
  L3 w0.102: v1(187.31,139.76) 186.89,139.35 184.39,139.35 183.37,140.37 182.68,140.37 180.55,142.5 179.01,142.5 v1(178.61,142.9)
  BOTTOM w0.102: R7902.2 R7903.1 194.74,142.58 v2(194.32,142.15) 191.63,139.47 187.81,139.47 187.51,139.76 v1(187.31,139.76) ; v1(178.61,142.9) 178.64,142.9 178.64,142.86 179,142.5 GPU1.K7
THERM_SYS_SHDN#: length 2.4
  TOP w0.102: R2602.2 197.08,128.23 v2(197.08,128.4) 197.08,128.96 Q2602.S
TOPAZ_OCP: length 65.2
  TOP w0.254: R7913.1 182.25,138.39 v2(182.75,137.89) 183.01,137.89 183.45,138.33 184.33,138.33 184.54,138.12 184.54,136.47 184.03,135.96 184.03,134.33 184.57,133.79 v1(184.57,129.9)
  L4 w0.254: v1(155.46,108.51) 153.36,108.51 150.15,111.71 150.12,111.71 149.79,112.05 149.79,113.21 150.62,114.04 150.74,114.04 151.82,115.12 151.82,115.59 152.62,116.39 152.82,116.39 155.15,118.72 155.15,118.74 156.53,120.12 156.55,120.12 156.61,120.18 160.78,120.18 161.09,120.49 164.5,120.49 165.19,121.18 166.36,121.18 166.38,121.2 166.91,121.2 170.55,124.84 172.34,124.84 173.51,126.01 173.51,128.09 174.73,129.31 183.98,129.31 v1(184.57,129.9)
  BOTTOM w0.254: PR8511.1 156.16,107.92 155.7,108.38 155.6,108.38 v1(155.46,108.51)
TOUCH_PANEL_INTR#: length 214.2
  L3 w0.127: v1(105.21,154.36) 105.52,154.05 114.57,154.05 115.18,153.44 117,153.44 118.23,152.22 125.44,152.22 126.05,152.83 131.53,152.83 132.29,152.07 132.29,149.31 135.2,146.41 136.62,146.41 138.48,144.54 138.48,137.9 138.48,137.22 141.77,133.93 141.77,126.93 141.77,126.44 141.77,126.44 141.77,123.54 141.77,123.54 141.77,122.51 141.77,119.51 142.03,119.25 142.03,107.43 141.83,107.24 141.83,101.7 141.89,101.64 ; 141.89,101.64 142.5,102.25 143.75,102.25 144.43,102.92 147.55,102.92 149.11,101.36 151.87,101.36 v1(152.09,101.14) ; 141.89,101.64 141.89,101.45 139.85,99.4 139.37,99.4 139.04,99.73 138.75,99.73 v1(138.72,99.7) ; v1(179.5,89.95) 179.5,89.71 180.57,88.65 180.93,88.29 180.93,88.28 181.19,88.02 181.27,88.02 182.09,87.21 182.09,86.78 184.22,84.64 184.22,84.53 187.84,80.91 187.84,71.8 186.6,70.56 186.6,60.73 179.08,53.21 179.08,49.22 179.09,49.21 179.09,48.52 179.71,47.9 179.72,47.9 179.98,47.64 179.98,47.63 180.28,47.32 180.96,47.32 181.16,47.12 v1(181.16,46.94)
  L4 w0.127: v1(152.09,101.14) 152.09,100.73 153.36,99.47 153.36,99.13 153.95,98.54 153.98,98.54 156.33,96.2 156.97,96.2 162.75,90.42 162.75,90.37 162.75,90.16 162.75,89.35 163.74,88.36 169.89,88.36 170.13,88.12 170.18,88.12 170.19,88.11 177.67,88.11 v1(179.5,89.95)
  BOTTOM w0.127: v1(181.16,46.94) 180.73,46.94 v2(180.55,47.12) 179.77,47.9 179.5,47.9 178.18,49.23 R2429.1 177.79,49.02 177.04,48.27 177.04,47.13 176.31,46.4 D2402.A ; R5537.2 108.11,170.25 108.11,168.86 105.21,165.96 v1(105.21,154.36) ; v1(138.72,99.7) 138.25,99.7 136.29,97.74 CPU1.A7
TOUCHPAD_INTR#: length 8.1
  BOTTOM w0.102: R410.2 140.14,69.72 v2(139.42,70.43) 139.06,70.79 139.06,70.79 137.92,71.94 137.59,71.94 136.95,72.58 136.95,72.74 136.95,73.32 137.25,73.62 137.28,73.62 137.51,73.85 137.51,74.62 137.55,74.66 137.55,75.14 137.22,75.48 CPU1.BA5
TP1_AY4: length 6.1
  BOTTOM w0.089: CPU1.AY4 137.77,75.93 137.61,75.76 137.61,75.36
  BOTTOM w0.102: TP610.1 138.25,72.13 137.67,72.13 137.14,72.66 137.14,73.25 137.33,73.43 137.36,73.43 137.7,73.77 137.7,74.54 137.74,74.58 137.74,75.22 137.61,75.36
TP2_BB3: length 5
  BOTTOM w0.102: CPU1.BB3 138.42,74.71 138.14,74.71 137.89,74.46 137.89,73.58 138.46,73 138.84,73 TP611.1
TP_EN#: length 59.9
  TOP w0.127: v2(175.78,31.93) 175.81,31.93 175.81,31.9 v1(176.18,31.53)
  L3 w0.127: v1(173.75,38.84) 173.75,38.79 175.19,37.36 175.19,36.11 175.3,36 175.57,35.73 175.57,34.86 176.84,33.58 176.84,32.6 176.76,32.52 176.76,32.12 v1(176.18,31.53)
  L4 w0.127: v1(176.18,31.53) 176.17,31.54 173.68,31.54 173.67,31.53 168.75,31.53 168.74,31.54 161.27,31.54 160.05,30.32 155.03,30.32 154.59,29.89 147.92,29.89 v1(144.8,26.77)
  BOTTOM w0.127: KBC24.49 173.52,39.53 173.75,39.3 v1(173.75,38.84) 173.75,38.58 174.07,38.26 174.64,38.26 175.33,38.95 175.56,38.95 176.07,39.46 176.07,41.76 175.92,41.91 175.7,41.91 175.2,42.41 175.2,43.73 175.2,43.74 175.2,44.04 175.2,44.05 175.2,44.18 175.82,44.79 176.58,44.79 177.02,44.35 RN2405.4 ; v1(144.8,26.77) 142.45,26.77 141.58,25.9 R6516.1
TP_LOCK#: length 31.2
  TOP w0.127: v1(160.21,26.45) 160.21,26 157.54,23.34 156.52,23.34 153.14,19.95 153.14,19.53 149.64,16.03 146.24,16.03 145.91,16.35 141.06,16.35 v1(140.6,15.89) 139.68,15.89 AFTP6526.1
  BOTTOM w0.127: TP1.6 v1(140.6,15.89) 140.6,16.72 R6509.2 ; v1(160.21,26.45) 160.55,26.45 D2405.A
TP_ON#_GATE: length 13.3
  BOTTOM w0.127: Q6505.G 147.78,25.9 146.43,27.25 142.57,27.25 140.66,25.34 140.66,25.22 R6516.2 140.69,25.14 C6503.1 140.26,24.33 140.01,24.08 v2(140.01,23.75) 140.01,23.5 140.4,23.1 Q6504.G
TP_RESET: length 8.5
  BOTTOM w0.102: LCD1.38 113.15,173.04 v2(113.59,172.6) 113.59,172.47 112.38,171.25 111.39,171.25 111.23,171.1 R5538.1 110.65,171.12 C5540.1
TP_RS: length 9.4
  BOTTOM w0.102: R5537.1 108.99,171.05 C5541.1 109.01,171.46 109.2,171.66 111.41,171.66 v2(111.61,171.86) 111.82,171.86 112.95,172.99 112.95,175.81 112.65,176.11 LCD1.37
TP_VDD: length 0.6
  TOP w0.381: v1(147.1,17.23) 147.1,17.84 AFTP6529.1
  vias: v1(143.18,18.47) v1(143.81,18.47) v1(147.1,16.6) v2(143.4,19.49) v2(148.55,19.71)
TP_WAKE_KBC#: length 4.7
  BOTTOM w0.102: v2(173.92,46.45) 173.41,45.93 KBC24.33 172.68,48.46 173.13,48.92 R2431.2
TPAN_VDD: length 7.1
  TOP w0.508: v1(111.36,173.08) 111.36,173.24 111.83,173.71 ED5501.5
  L4 w0.508: v1(111.36,173.08) 111.66,173.08 v4(114.04,175.45)
  BOTTOM w0.305: v4(114.04,175.45) 114.15,175.56 LCD1.40
  BOTTOM w0.508: v1(111.36,173.08) 111.28,173.08 110.69,172.48 110.69,172.3 C5501.1
  vias: v2(113.85,176.71)
TPAN_VDD_F:
  vias: v2(119.29,180.39)
TPCLK_C: length 18.9
  TOP w0.191: AFTP6530.1 137.91,15.43 v1(138.01,15.52)
  BOTTOM w0.191: RN6503.4 150.29,15.18 148.58,13.47 137.93,13.47 137.27,14.14 137.27,15.32 137.47,15.52 v1(138.01,15.52) 138.4,15.52 138.6,15.32 TP1.8
TPDATA_C: length 22.9
  TOP w0.191: AFTP6524.1 137.91,16.11 v1(138.01,16.21)
  BOTTOM w0.191: RN6503.3 150.94,15.15 148.82,13.03 137.75,13.03 136.82,13.95 136.82,15.53 137.5,16.21 v1(138.01,16.21) 138.89,16.21 139.6,15.5 TP1.7
TPM_GPIO0: length 4.7
  BOTTOM w0.102: R9121.1 159.57,62.24 v2(156.85,62.24) 156.48,62.24 155.95,61.71 U9103.29
TPM_GPIO2: length 3.3
  BOTTOM w0.102: R9120.1 v2(159.99,58.29) 159.87,58.29 158.69,59.47 U9103.3
TPM_GPIO4: length 3.1
  BOTTOM w0.102: U9103.13 v2(155.45,54.09) 155.45,53.21 R9122.1
TPM_SELECT: length 34.2
  TOP w0.127: R2022.2 156.07,79.55 R2020.1 156.46,78.06 156.51,76.95 v1(156.9,76.55)
  L3 w0.127: v1(157.36,72.21) 157.13,72.44 155.81,72.44 155.35,71.98 154.62,71.98 154.6,71.99 152.26,71.99 149.44,74.81 149.39,74.81 147.34,76.86 142.23,76.86 142.17,76.81 139.35,76.81 138.38,77.78 v1(136.67,77.78)
  BOTTOM w0.089: v1(136.67,77.78) 136.5,77.78 135.78,77.06 135.78,76.72 136.05,76.45 CPU1.AY7
  BOTTOM w0.127: v1(156.9,76.55) v2(156.9,74.65) 156.9,74.05 157.04,73.91 157.04,72.53 v1(157.36,72.21)
TPM_VDD14: length 15.8
  L3 w0.254: v1(154.37,54.37) 153.6,54.37 151.62,56.35 v1(151.62,60.04)
  BOTTOM w0.254: U9103.22 152.57,59.47 152,60.04 v1(151.62,60.04) 151.11,60.55 C9113.1 150.69,59.93 150.89,59.72 R9147.2 ; U9103.14 154.95,55.76 154.37,55.18 v2(154.37,54.99) v1(154.37,54.37) 154.37,54.15 153.81,53.58 C9107.1 153.86,53.25 154.57,53.25 C9111.1
TPM_VSB: length 3.4
  BOTTOM w0.254: U9103.1 158.76,60.47 v2(159.54,59.7) 160.16,59.08 R9144.2
TS#_DIMM0_1: length 4.9
  TOP w0.127: v1(102.02,30.66) 102.47,31.12 R1215.2
  BOTTOM w0.127: DM1.134 99.27,31.27 99.88,30.66 v1(102.02,30.66)
TS#_DIMM1_1: length 4.3
  TOP w0.127: v1(90.87,17.89) 91.07,17.7 91.53,17.7 91.65,17.82 v2(91.65,18.12) 91.65,18.66 91.51,18.8 R1312.2
  BOTTOM w0.127: v1(90.87,17.89) 91.27,18.29 DM2.134
U22_POWER_K52: length 2.8
  TOP w0.508: R721.2 110.64,93.19 v2(111.41,93.19) 111.41,92.93 111.13,92.65 111.13,92.64 110.93,92.44 110.93,92.25 v1(110.98,92.2)
  BOTTOM w0.305: v1(110.98,92.2) 110.98,92.32 CPU1.K52
UART0_CTS#: length 7.4
  BOTTOM w0.089: 143.45,88.4 143.21,88.16 142.15,88.16 141.85,88.46 141.35,88.46 141.35,88.46 139.93,88.46 139.62,88.57 139.35,88.57 139.26,88.54 139.06,88.54 138.97,88.57 138.7,88.57 138.61,88.54 138.12,88.54 CPU1.U4
  BOTTOM w0.114: TP2011.1 144.25,89.2 143.45,88.4
UART0_RTS#: length 5.5
  BOTTOM w0.089: CPU1.U3 138.73,88.8 139.13,89.2 139.59,89.2 139.68,89.24 139.99,89.24 140.07,89.2 140.24,89.04 141.15,89.04
  BOTTOM w0.114: 141.15,89.04 142.12,89.04 142.26,89.18 142.84,89.18 TP2010.1
UART0_TXD: length 4.3
  BOTTOM w0.089: TP2007.1 142.86,88.93 142.29,88.93 142.2,88.84 140.18,88.84 140,89.03 139.91,89.06 139.71,89.06 139.62,89.02 139.39,89.02 CPU1.U2
UART1_CTS#: length 9.4
  BOTTOM w0.114: CPU1.AB4 138.11,86.4 138.33,86.4 138.36,86.42 138.67,86.42 138.69,86.4 138.98,86.4 139.01,86.42 139.32,86.42 139.34,86.4 139.63,86.4 139.66,86.42 139.97,86.42 139.99,86.4 140.25,86.4 140.33,86.32 141.42,86.32 141.74,86.64 144.61,86.64 145.13,86.12 146.73,86.12 TP2015.1
UART1_RXD: length 3.9
  BOTTOM w0.114: TP2012.1 141.86,85.86 141.65,85.65 140.44,85.65 140.18,85.4 139.57,85.4 CPU1.AC1
UART_2_CRXD_DTXD: length 149.7
  TOP w0.127: v1(150.45,84.84) 150.51,84.78 150.8,84.78 151,84.98 151,85.39 151.67,86.06 151.94,86.06 152.26,86.38 R2048.2 ; R6809.1 185.62,4.83 185.49,4.83 185.28,4.62 185.28,4.14 185.67,3.76 189.58,3.76 193.17,7.35 193.17,19.69 192.69,20.17 192.41,20.17 191.35,21.23 191.35,31.77 189.92,33.19 184.96,33.19 184.33,33.82 184.33,35.69 v1(184.04,35.98)
  L4 w0.127: v1(150.45,84.84) 150.23,84.63 149.93,84.63 149.46,84.16 149.46,82.51 153.44,78.53 153.93,78.53 156.69,75.78 160.7,75.78 161.05,75.43 164.63,75.43 164.95,75.75 167.61,75.75 170.39,78.53 182.14,78.53 183.5,77.17 183.5,73.11 183.14,72.76 183.14,63.23 186.22,60.15 186.22,48.67 185.15,47.6 183.54,47.6 181.75,45.82 181.75,39.86 184.27,37.34 184.27,36.21 v1(184.04,35.98)
  BOTTOM w0.127: v2(150.83,85.44) 150.83,85.44 150.83,85.44 150.84,85.44 150.84,85.23 v1(150.45,84.84) 150.44,84.84 150.44,84.78 150.29,84.63 150.01,84.63 149.45,84.06 149.37,84.06 149.36,84.07 146.87,84.07 145.74,85.2 140.63,85.2 140.33,84.9 139.9,84.9 CPU1.AD1
UART_2_CRXD_DTXD_CON: length 2.4
  TOP w0.127: DBG1.14 188.27,4.45 187.89,4.83 187.03,4.83 R6809.2
UART_2_CTXD_DRXD: length 151.4
  TOP w0.127: v1(184.86,35.98) 184.59,35.71 184.59,33.92 185.07,33.44 190.03,33.44 191.6,31.87 191.6,21.34 192.51,20.42 192.8,20.42 193.43,19.79 193.43,7.25 189.69,3.51 185.56,3.51 185.03,4.04 185.03,4.73 185.38,5.08 185.59,5.08 R6808.1 ; R2049.2 152.07,85.8 151.78,85.8 151.26,85.28 151.26,84.87 150.9,84.52 150.8,84.52 150.46,84.18 150.46,84.15 v1(150.43,84.15)
  L4 w0.127: v1(150.43,84.15) 150.24,84.35 150.01,84.35 149.71,84.05 149.71,82.62 153.54,78.79 154.04,78.79 156.79,76.03 160.81,76.03 161.15,75.68 164.52,75.68 164.84,76.01 167.51,76.01 170.29,78.79 182.24,78.79 183.75,77.28 183.75,73.01 183.4,72.65 183.4,63.34 186.48,60.26 186.48,48.57 185.26,47.35 183.64,47.35 182,45.71 182,39.96 184.52,37.44 184.52,36.32 v1(184.86,35.98)
  BOTTOM w0.089: CPU1.AD2 139.39,84.6 139.62,84.6 139.71,84.56 140.19,84.56 140.43,84.65
  BOTTOM w0.127: 140.43,84.65 140.73,84.95 145.64,84.95 146.77,83.82 149.25,83.82 149.26,83.81 149.55,83.81 150.12,84.37 150.21,84.37 v1(150.43,84.15) 150.51,84.23 v2(151.14,84.23)
UART_2_CTXD_DRXD_CON: length 2.4
  TOP w0.127: DBG1.13 188.31,5.45 187.94,5.08 187.07,5.08 R6808.2
USB2_ID: length 29.4
  TOP w0.127: v1(159.17,83.63) 159.16,83.63 v2(159.16,83.01)
  L3 w0.127: v1(159.17,83.63) 159.22,83.58 159.22,81.24 156.26,78.28 149.79,78.28 148.46,79.6 147.83,79.6 144.64,82.79 141.68,82.79 141.67,82.78 141.33,82.78 140.59,83.53 138.82,83.53 v1(138.36,83.99)
  BOTTOM w0.127: CPU1.AG3 138.51,83.84 138.37,83.99 v1(138.36,83.99) ; R1601.1 160.12,82.92 159.41,83.63 v1(159.17,83.63)
USB2_VBUSSENSE: length 30
  TOP w0.127: v2(157.97,83.34) 158.04,83.41 158.48,83.41 v1(158.53,83.46)
  L3 w0.127: v1(158.53,83.46) 158.53,82.68 158.81,82.4 158.81,81.19 156.15,78.53 149.9,78.53 148.55,79.88 147.91,79.88 143.31,84.49 138.14,84.49 v1(137.42,83.76)
  BOTTOM w0.127: CPU1.AG4 137.59,83.76 v1(137.42,83.76) ; v1(158.53,83.46) 158.53,83.25 158.92,82.86 R1602.1
USB3_PRX_CTX_N1_C: length 14.6
  TOP w0.178: R3607.2 21.86,34.18 19.97,34.18 ; 19.97,34.18 18.82,34.18 ED3602.1 ED3602.10 17.34,34.14 17.25,34.23 17,34.23 16.39,33.62 16.39,30.71 14.99,29.31 14.25,29.31 13.34,28.4 12.96,28.4 12.78,28.22 USB1.5 ; 19.97,34.18 v2(19.97,33.99)
USB3_PRX_CTX_N2_C: length 11.2
  TOP w0.178: USB2.5 12.78,9.72 12.96,9.9 13.34,9.9 14.18,10.75 14.73,10.75 15.68,11.7 15.68,12.87 16.82,14.01 17.07,14.01 17.16,13.92 ED3603.10 ED3603.1 19.02,13.92 19.19,14.1 20.06,14.1 R3611.2
USB3_PRX_CTX_P1_C: length 14.6
  TOP w0.178: v2(21.04,34.65) 21.04,34.48 ; 21.04,34.48 21.92,34.48 R3608.2 ; 21.04,34.48 19.31,34.48 19.17,34.62 ED3602.2 ED3602.9 17.34,34.62 17.25,34.54 16.87,34.54 16.09,33.75 16.09,30.84 14.87,29.62 14.13,29.62 13.21,28.7 12.96,28.7 12.78,28.88 USB1.6
USB3_PRX_CTX_P2_C: length 11.4
  TOP w0.178: USB2.6 12.78,10.38 12.96,10.2 13.21,10.2 14.06,11.05 14.6,11.05 15.37,11.82 15.37,13 16.69,14.32 17.07,14.32 17.16,14.4 ED3603.9 ED3603.2 19.65,14.4 ; 19.65,14.4 20.07,14.4 20.3,14.64 20.67,14.64 R3612.2 ; 19.65,14.4 v2(19.65,14.59)
USB3_PTX_CRX_N1_C: length 11.7
  TOP w0.178: v2(21.11,36.14) 21.11,36.32 ; 21.11,36.32 20.85,36.32 20.28,35.75 19.46,35.75 19.37,35.67 ED3602.4 ED3602.7 17.63,35.67 17.53,35.77 16.95,35.77 15.09,33.91 13.77,33.91 13.29,34.4 12.96,34.4 12.78,34.22 USB1.8 ; 21.11,36.32 21.98,36.32 R3605.2
USB3_PTX_CRX_N1_R: length 2.1
  TOP w0.178: R3605.1 23.25,36.28 24.72,36.28 C3602.2
USB3_PTX_CRX_N2_C: length 9.4
  TOP w0.178: R3609.2 20.47,16.01 20.13,16.01 19.65,15.53 19.27,15.53 19.19,15.45 ED3603.4 ED3603.7 17.16,15.45 17.07,15.53 15.28,15.53 15.13,15.38 13.72,15.38 13.21,15.9 12.96,15.9 12.78,15.72 USB2.8
USB3_PTX_CRX_N2_R: length 4.5
  TOP w0.178: 24,17.09 22.86,15.95 21.8,15.95 R3609.1 ; 24,17.09 24.66,17.75 C3605.2 ; 24,17.09 v2(24.16,16.92)
USB3_PTX_CRX_P1_C: length 11.8
  TOP w0.178: v2(19.83,36.3) 19.83,36.06 ; 19.83,36.06 20.15,36.06 20.72,36.63 21.95,36.63 R3606.2 ; 19.83,36.06 19.46,36.06 19.37,36.14 ED3602.5 ED3602.6 17.56,36.14 17.48,36.07 16.82,36.07 14.97,34.22 13.9,34.22 13.41,34.7 12.96,34.7 12.78,34.88 USB1.9
USB3_PTX_CRX_P1_R: length 2.3
  TOP w0.178: 24.16,36.58 24.75,36.58 24.75,36.58 C3601.2 ; 24.16,36.58 23.37,36.58 R3606.1 ; 24.16,36.58 v2(24.16,36.78)
USB3_PTX_CRX_P2_C: length 9.5
  TOP w0.178: v2(19.64,16.19) 19.77,16.08 ; 19.77,16.08 19.53,15.84 19.27,15.84 19.19,15.92 ED3603.5 ED3603.6 17.16,15.92 17.07,15.84 15.16,15.84 15.01,15.69 13.85,15.69 13.34,16.2 12.96,16.2 12.78,16.38 USB2.9 ; 19.77,16.08 20.01,16.32 20.52,16.32 R3610.2
USB3_PTX_CRX_P2_R: length 4.3
  TOP w0.178: 22.92,16.44 22.73,16.25 21.88,16.25 R3610.1 ; 22.92,16.44 v2(22.74,16.62) ; 22.92,16.44 24.44,17.97 C3604.2
USB20_VCCA: length 0.9
  BOTTOM w0.508: v1(183.95,29.39) 184.27,29.39 184.35,29.47 ED3704.5
  vias: v1(186.63,25.72) v1(186.63,25.08) v1(187.27,25.72) v1(187.27,25.08) v2(183.42,26.82)
USB30_RX_CPU_N1: length 149
  TOP w0.178: 24.44,34.13 23.22,34.13 R3607.1 ; 24.44,34.13 26.74,34.13 v1(27.03,33.85) ; 24.44,34.13 v2(24.42,33.88)
  L4 w0.152: v1(135.78,93.27) 135.36,92.85 135.36,92.45 134.6,91.68 131.73,91.68 129.67,89.63 115.95,89.63 114.98,90.6 110.68,90.6 109.7,89.63 108.16,89.63 107.19,90.59 98.12,90.59 97.41,89.88 86.94,89.88 68.56,71.5 68.56,64.85 59.49,55.78 59.49,50.93 58.62,50.06 58.62,47.64 53.87,42.88 46.82,42.88 46.19,42.26 46.19,41.24 43.23,38.28 37.05,38.28 32.61,33.85 v1(27.03,33.85)
  BOTTOM w0.178: CPU1.H8 v1(135.78,93.27)
USB30_RX_CPU_N2: length 172.3
  TOP w0.178: 30.16,30.64 30.16,21.49 22.78,14.12 22.11,14.12 R3611.1 ; 30.16,30.64 30.16,31.33 29.61,31.88 29.04,31.88 v1(28.84,32.08) ; 30.16,30.64 v2(30.39,30.64)
  L4 w0.127: 125.93,88.61 125.96,88.58 126.67,88.58 127.23,89.13 130.76,89.13 131.05,89.13 131.5,88.67 137.41,88.67 138.1,89.35 138.16,89.42 138.16,91.76 137.13,92.79 136.87,92.79 v1(136.7,92.62)
  L4 w0.152: v1(28.84,32.08) 29.05,31.87 31.45,31.87 37.19,37.62 43.43,37.62 45.85,40.04 51.86,40.04 59.21,47.39 59.21,49.76 60.09,50.64 60.09,55.53 69.16,64.6 69.16,71.31 87.17,89.32 98.11,89.32 98.41,89.61 106.43,89.61 107.44,88.61 109.85,88.61 111.48,90.24 114.8,90.24 116.43,88.61 125.93,88.61
  BOTTOM w0.178: CPU1.J6 136.37,92.29 v1(136.7,92.62)
USB30_RX_CPU_P1: length 149
  TOP w0.178: R3608.1 23.26,34.44 25.58,34.44 ; v2(25.57,34.68) 25.58,34.44 ; 25.58,34.44 26.81,34.44 v1(27.03,34.65)
  L4 w0.152: v1(27.03,34.65) 27.24,34.87 27.59,34.87 27.77,34.69 27.77,34.34 27.98,34.14 32.49,34.14 36.93,38.57 43.11,38.57 45.9,41.36 45.9,42.38 46.7,43.17 53.75,43.17 58.33,47.76 58.33,50.18 59.2,51.05 59.2,55.9 68.27,64.97 68.27,71.62 86.82,90.17 97.29,90.17 98,90.88 107.31,90.88 108.28,89.92 109.58,89.92 110.55,90.89 115.1,90.89 116.07,89.92 129.55,89.92 131.61,91.98 134.47,91.98 135.07,92.57 135.07,93.07 v1(134.87,93.27)
  BOTTOM w0.178: CPU1.G8 v1(134.87,93.27)
USB30_RX_CPU_P2: length 172.2
  TOP w0.178: v2(29.59,29.28) 29.85,29.28 ; 29.85,29.28 29.85,21.62 22.66,14.42 21.89,14.42 R3612.1 ; 29.85,29.28 29.85,31.2 29.48,31.57 29.04,31.57 v1(28.84,31.37)
  L4 w0.127: 125.93,88.32 125.96,88.35 126.77,88.35 127.32,88.9 130.86,88.9 130.95,88.9 131.41,88.44 137.32,88.44 137.51,88.44 138.32,89.26 138.39,89.32 138.39,91.86 137.23,93.02 136.94,93.02 v1(136.7,93.26)
  L4 w0.152: v1(28.84,31.37) 29.05,31.58 31.57,31.58 37.31,37.33 43.55,37.33 45.97,39.75 51.98,39.75 59.5,47.27 59.5,49.64 60.38,50.52 60.38,55.41 69.45,64.48 69.45,71.19 87.29,89.03 98.24,89.03 98.53,89.32 106.31,89.32 107.32,88.32 109.97,88.32 111.6,89.95 114.68,89.95 116.31,88.32 125.93,88.32
  BOTTOM w0.178: CPU1.H6 136.37,92.94 v1(136.7,93.26)
USB30_TX_CPU_N1: length 161.5
  TOP w0.178: C3602.1 26.12,36.25 26.91,36.25 v1(27.16,36) v2(27.56,35.58)
  L4 w0.152: v1(133.42,99.48) 133.15,99.21 133.15,98.12 132.83,97.8 132.83,93.65 132.39,93.2 132.15,93.2 131.24,92.29 131.24,91.95 130.16,90.87 128.54,90.87 115.6,90.87 115.15,91.32 94.55,91.32 93.99,90.76 76.99,90.76 69.9,83.66 47.25,83.66 26.28,62.69 26.28,60.32 27.26,59.34 27.26,49.1 25.79,47.63 25.79,41.54 27.46,39.87 27.46,37.27 27.61,37.11 27.83,37.11 28.07,36.88 28.07,36.24 27.83,36 v1(27.16,36)
  BOTTOM w0.089: v1(133.42,99.48) 133.09,99.48 132.94,99.33 132.94,98.3 132.43,97.79 132.43,97.51 132.46,97.42 132.46,97.15 132.43,97.06 132.43,96.86 132.48,96.73 132.48,96.52 CPU1.C13
USB30_TX_CPU_N2: length 178.4
  TOP w0.178: 28.78,27.41 28.78,30.28 28.4,30.66 v1(27.52,30.66) ; 28.78,27.41 v2(29.01,27.42) ; 28.78,27.41 28.78,21.98 25.65,18.85 C3605.1
  L4 w0.152: v1(133.89,98.29) 134.1,98.5 134.37,98.5 134.5,98.37 134.5,97.87 139.22,93.15 139.22,88.08 137.8,86.66 133.88,86.66 133.51,86.29 129.12,86.29 128.98,86.14 126.63,86.14 126.27,85.78 124.57,85.78 123.18,87.18 116.88,87.18 114.59,89.46 111.71,89.46 109.42,87.18 107.85,87.18 106.03,89 98.94,89 98.41,88.47 87.52,88.47 70.07,71.02 70.07,64.22 61.01,55.15 61.01,50.29 60.09,49.37 60.09,47.03 52.17,39.11 46.14,39.11 43.79,36.76 37.57,36.76 31.48,30.66 v1(27.52,30.66)
  BOTTOM w0.089: v1(133.89,98.29) 133.68,98.49 133.51,98.49 133.31,98.29 133.31,97.98 132.95,97.61 132.95,97.46 CPU1.B13
USB30_TX_CPU_P1: length 161.5
  TOP w0.178: C3601.1 26.14,36.55 26.91,36.55 v1(27.16,36.81) v2(27.44,37.29)
  L4 w0.152: v1(133.27,100.26) 132.86,99.33 132.86,98.24 132.54,97.92 132.54,93.77 132.26,93.5 132.03,93.5 130.94,92.41 130.94,92.07 130.04,91.16 115.72,91.16 115.27,91.61 94.43,91.61 93.87,91.05 76.87,91.05 69.78,83.95 47.13,83.95 25.99,62.81 25.99,60.2 26.97,59.22 26.97,49.22 25.5,47.75 25.5,41.42 27.16,39.75 v1(27.16,36.81)
  BOTTOM w0.089: CPU1.D13 132.3,96.45 132.3,96.69 132.25,96.83 132.25,97.1 132.28,97.19 132.28,97.39 132.25,97.48 132.25,97.88 132.75,98.38 132.75,99.39 v1(133.27,100.26)
USB30_TX_CPU_P2: length 178.7
  TOP w0.178: 28.48,29.57 28.48,22.11 25.32,18.96 C3604.1 ; 28.48,29.57 28.48,30.15 28.28,30.36 27.92,30.36 v1(27.52,29.95) ; 28.48,29.57 v2(28.26,29.57)
  L4 w0.152: v1(27.52,29.95) 27.93,30.37 31.6,30.37 37.7,36.46 43.91,36.46 46.26,38.82 52.29,38.82 60.38,46.91 60.38,49.25 61.3,50.17 61.3,55.03 70.37,64.1 70.37,70.9 87.64,88.18 98.53,88.18 99.06,88.71 105.91,88.71 107.73,86.89 109.54,86.89 111.83,89.17 114.47,89.17 116.76,86.89 123.06,86.89 124.45,85.49 126.39,85.49 126.75,85.85 129.1,85.85 129.24,85.99 133.63,85.99 134,86.37 137.67,86.37 137.92,86.37 139.51,87.96 139.51,93.28 134.79,97.99 134.79,98.49 134.5,98.79 134.13,98.79 133.99,98.94 133.99,98.94 v1(133.89,99.04)
  BOTTOM w0.089: v1(133.89,99.04) 133.89,98.88 133.68,98.68 133.44,98.68 133.12,98.37 133.12,98.05 132.76,97.69 132.76,97.68 CPU1.A13
USB30_VCCC: length 8.7
  TOP w0.381: ED3604.5 17.91,23.99 v1(17.53,24.36)
  TOP w0.508: 17.99,17.71 19.67,17.71 C3618.1 ; 17.99,17.71 AFTP3605.1 ; 17.99,17.71 16.75,17.71 16.26,17.22 v1(16.26,17.02)
  L3 w0.508: USB2.1 14.28,17.26 ; USB2.1 14.99,16.55 ; USB2.1 14.28,15.84
  BOTTOM w0.508: 14.99,35.05 USB1.1 14.28,35.76
  vias: v2(18.1,40.65) v2(23.13,38.92) v4(16.42,40.03) v4(17.08,39.22) v4(17.43,40.08) v4(18.07,39.32)
USB_CAMERA_PN4: length 10.2
  TOP w0.127: 109.81,170.64 109.43,170.64 108.36,171.71 108.36,173.35 v1(107.87,173.84) ; 109.81,170.64 110.92,170.64 111.14,170.85 EL5507.1 ; 109.81,170.64 v2(109.81,170.84)
  BOTTOM w0.127: LCD1.30 109.15,176.03 109.28,175.9 109.28,174.56 108.29,173.58 108.14,173.58 v1(107.87,173.84)
USB_CAMERA_PP4: length 10.2
  TOP w0.127: v1(107.87,173.21) 108.12,172.95 108.12,171.99 ; 108.12,171.99 108.12,171.61 109.33,170.4 110.86,170.4 111.09,170.17 EL5507.4 ; 108.12,171.99 v2(107.91,171.99)
  BOTTOM w0.127: LCD1.31 109.65,175.96 109.52,175.83 109.52,174.46 108.39,173.33 107.99,173.33 v1(107.87,173.21)
USB_CON_PN6: length 7.7
  TOP w0.178: R6110.1 89.84,162.85 89.84,163.78 89.3,164.31 88.27,164.31 87,165.58 86.65,165.58 AFTP6109.1 86.51,165.48 86.41,165.58 85.81,165.58 v1(85.71,165.48)
  BOTTOM w0.178: v1(85.71,165.48) 85.77,165.55 WLAN1.5
USB_CON_PN7: length 9.1
  TOP w0.127: R5535.1 114.18,173.61 114.08,173.71 113.37,173.71 112.89,174.19 111.56,174.19 111.22,173.85 110.57,173.85 ED5501.1 109.86,174.66 110.56,175.36 110.75,175.36 v1(110.77,175.38) 110.77,175.4 110.83,175.47 v2(110.83,176)
  BOTTOM w0.127: LCD1.34 111.15,175.76 v1(110.77,175.38)
USB_CON_PP6: length 8.5
  TOP w0.178: v1(85.68,166.12) 85.73,166.12 85.96,165.89 87.13,165.89 88.09,164.92 AFTP6110.1 88.32,164.72 88.42,164.62 89.43,164.62 90.14,163.91 90.14,163.49 90.52,163.11 90.52,162.86 R6111.1
  BOTTOM w0.178: v1(85.68,166.12) 85.75,166.05 WLAN1.3
USB_CON_PP7: length 8.3
  TOP w0.127: v1(111.43,175.33) 111.43,175.16 111.21,174.95 110.79,174.95 110.61,174.78 110.61,174.19 110.71,174.09 111.12,174.09 111.5,174.48 112.01,174.48 ED5501.6 112.76,174.66 113.12,174.3 ; v2(113.29,174.44) 113.12,174.3 ; 113.12,174.3 113.42,174 113.96,174 114.31,174.35 114.9,174.35 R5536.1
  BOTTOM w0.127: v1(111.43,175.33) 111.39,175.37 111.39,175.74 111.65,176.01 LCD1.35
USB_CPU_PN0: length 152.1
  TOP w0.178: 26,27.06 26.22,27.28 26.86,27.28 v1(27.27,27.69) ; 26,27.06 v2(25.81,27.23) ; 26,27.06 23.83,24.89 23.49,24.89 EL3601.4
  L4 w0.127: 125.09,84.85 125.12,84.85 125.15,84.88 125.87,84.88 127.25,83.5 129.08,83.5 130.92,85.35 134.32,85.35 v1(134.87,85.9)
  L4 w0.152: v1(27.27,27.69) 26.85,27.27 26.51,27.27 26.24,27.54 26.24,28.21 26.72,28.69 31.14,28.69 38.06,35.61 44.31,35.61 46.59,37.89 52.59,37.89 61.23,46.54 61.23,48.89 62.19,49.84 62.19,54.67 71.62,64.1 71.62,70.92 87.99,87.29 98.53,87.29 98.78,87.54 104.81,87.54 106.92,85.44 122.95,85.44 123.53,84.85 125.09,84.85
  BOTTOM w0.178: CPU1.AB9 v1(134.87,85.9)
USB_CPU_PN1: length 155.4
  TOP w0.178: 25.23,24.1 26.07,24.94 26.75,24.94 v1(26.98,25.17) ; 25.23,24.1 v2(25.03,24.28) ; 25.23,24.1 24.09,22.96 23.57,22.96 EL3602.4
  L4 w0.152: v1(26.98,25.17) 26.74,24.93 26.44,24.93 26.31,25.07 26.31,25.36 26.78,25.83 29.61,25.83 38.02,34.24 44.23,34.24 46.98,37 53.14,37 62.1,45.96 62.1,48.53 63.05,49.48 63.05,54.31 72.51,63.77 72.51,70.52 88.41,86.41 88.53,86.41 88.53,86.41 98.67,86.41 99.19,86.93 104.36,86.93 107.32,83.97 122.99,83.97 123.24,83.73 123.24,82.44 123.87,81.8 128.82,81.8 131.14,84.12 134.46,84.12 134.54,84.2 136.35,84.2 136.55,84.4 v1(136.55,84.83)
  BOTTOM w0.178: v1(136.55,84.83) 136.88,84.83 137.09,85.03 CPU1.AD6
USB_CPU_PN2: length 91.5
  TOP w0.152: v1(179.97,34.99) 179.97,35.32 179.69,35.59 178.93,35.59 178.68,35.35 178.68,34.75 178.9,34.53 EL3706.1
  TOP w0.178: v1(179.97,34.99) v2(180.48,35.21)
  L4 w0.152: v1(142.14,83.21) 142.44,83.21 142.75,83.51 142.75,83.98 142.23,84.5 140.04,84.5 139.15,83.61 139.15,75.87 140.22,74.8 140.22,73.09 140.22,72.63 140.22,72.63 140.22,72.01 143.28,68.95 144.05,68.95 145.03,67.97 145.03,63.07 148.99,59.11 149.98,59.11 152.61,56.48 152.61,52.17 156.06,48.72 157.12,48.72 157.92,47.93 170.79,47.93 171.75,46.97 174.95,46.97 175.2,46.97 180.84,41.33 180.84,39.98 180.84,39.98 180.84,35.19 180.64,34.99 v1(179.97,34.99)
  BOTTOM w0.089: CPU1.AH3 138.45,82.57 138.94,82.57 139.03,82.61 139.3,82.61 139.39,82.57 139.59,82.57 139.68,82.61 141.87,82.61 142.14,82.88 v1(142.14,83.21)
USB_CPU_PN4: length 136.8
  TOP w0.178: EL5507.2 113.14,170.85 113.33,170.66 116.82,170.66 v1(117.03,170.87)
  L4 w0.152: v1(157.53,85.55) 157.67,85.41 158.15,85.41 159.2,86.46 159.2,89.38 159.2,89.54 159.2,90.93 158.29,91.84 158.29,92.25 156.73,93.8 156.03,93.8 155.9,93.8 155.45,93.8 153.74,95.51 153.17,95.51 150.74,97.94 150.74,98.02 148.99,99.77 148.99,100.68 146.93,102.74 142.85,102.74 142.01,103.58 142.01,105.72 140.17,107.56 140.17,115.42 141.3,116.55 141.3,125.12 141.76,125.59 141.76,125.59 141.91,125.73 141.91,139.93 136.41,145.43 134.36,145.43 124.26,155.53 124.26,157.96 115.84,166.39 115.84,170.62 116.09,170.87 v1(117.03,170.87)
  BOTTOM w0.178: v2(145.65,82) 145.46,81.84 ; 145.46,81.84 146.17,81.13 151.99,81.13 155.79,84.92 156.9,84.92 v1(157.53,85.55) ; 145.46,81.84 144.83,82.47 142.55,82.47 142.28,82.19 140.48,82.19 140.4,82.11 139.87,82.11 CPU1.AJ1
USB_CPU_PN5: length 83.4
  TOP w0.178: v2(137.09,83.27) 137.09,83.43 v1(136.78,83.74) ; v1(181.34,33.19) 181.07,32.92 181.07,32.26 181.73,31.6 182.51,31.6 R3301.1
  L4 w0.089: 136.21,82.59 136.21,82.86 136.56,83.21 136.56,83.52 v1(136.78,83.74)
  L4 w0.152: v1(181.34,33.19) 180.47,34.06 179.71,34.06 179.4,34.37 179.4,37.93 171.74,45.58 170.91,45.58 169.42,47.08 157.32,47.08 157.16,47.24 156.32,47.24 151.89,51.66 151.89,51.68 151.76,51.81 151.76,53.44 151.17,54.04 151.17,56.72 149.63,58.26 148.76,58.26 148.64,58.26 144.99,61.91 144.55,61.91 144.43,61.91 143.74,62.6 143.74,63.19 143.74,63.19 143.74,67.26 139.37,71.63 139.37,72.27 139.37,72.27 139.37,73.44 139.37,74.39 137.31,76.45 137.31,77.36 137.43,77.48 137.43,78.82 136.17,80.09 136.17,82.54 136.21,82.59
  BOTTOM w0.178: v1(136.78,83.74) 136.78,84 CPU1.AF6
USB_CPU_PN6: length 156
  TOP w0.178: v1(110.84,157.84) 112.06,157.84 112.45,157.46 112.45,156.2 112.06,155.82 104.83,155.82 102.93,157.72 91.71,157.72 89.71,159.73 R6110.2
  L4 w0.152: v1(110.84,157.84) 112.56,157.84 115.34,155.07 117.03,155.07 120.79,151.31 125.68,151.31 128.68,148.31 128.68,148.02 129.1,147.6 129.57,147.6 132.28,144.9 132.28,142.44 140.42,134.29 140.42,127.47 140.42,126.72 139.87,126.17 139.87,117.28 138.76,116.17 138.76,108.77 136.51,106.52 136.51,102.61 136.85,102.26 140.63,102.26 142.18,100.72 142.18,99.03 144.88,96.32 150.14,96.32 151.74,94.72 151.74,93.93 153.84,91.83 155.74,91.83 156.09,91.48 v1(156.46,91.48)
  BOTTOM w0.102: CPU1.AH1 139.69,83.03 140.71,83.03 141.57,83.89 142.76,83.89 142.78,83.87 142.81,83.87
  BOTTOM w0.152: 142.81,83.87 144.92,83.87 146.16,82.64 151.25,82.64 154.11,85.5 156.55,85.5 157.25,86.19 157.25,88.46 157.25,88.47 157.25,90.69 v1(156.46,91.48)
  BOTTOM w0.178: v2(148.26,82.39) 148.26,82.64
USB_CPU_PN7: length 144.5
  TOP w0.089: v1(135.46,83.78) 135.9,84.22 136.93,84.22 137.42,84.71 137.42,84.72 137.46,84.76 137.48,84.76
  TOP w0.178: v1(157.82,86.23) 157.77,86.27 157.45,86.27 156.81,85.63 156.81,85.21 154.47,82.87 147.5,82.87 145.32,85.05 138.4,85.05 ; R5535.2 116.04,173.81 117.03,173.81 117.23,173.6 v1(117.23,173.28) ; v2(138.4,84.88) 138.4,85.05 ; 138.4,85.05 138,85.05 137.88,84.93 137.65,84.93 137.48,84.76
  L4 w0.152: v1(157.82,86.23) 157.82,86.27 158.02,86.47 158.25,86.47 158.62,86.85 158.62,87.39 157.73,88.29 157.73,90.72 157.73,91.15 157.73,92.01 156.5,93.24 156.26,93.24 153.76,93.24 152.59,94.41 152.59,95.07 150.49,97.17 150.44,97.23 144.9,97.23 144.82,97.31 143.19,98.94 143.19,101.86 141.72,103.33 141.72,105.34 139.61,107.46 139.61,107.84 139.61,107.84 139.61,115.73 140.74,116.86 140.74,125.6 141.27,126.13 141.27,126.37 141.27,134.65 133.53,142.38 133.53,142.88 133.54,142.88 133.54,144.98 130.04,148.47 130.04,148.92 126.29,152.67 121.74,152.67 119.56,154.86 119.54,154.86 117.95,156.45 117.95,157.38 117.29,158.05 117.1,158.05 115.3,159.84 115.28,159.84 115.28,159.85 115.28,172.49 116.5,173.72 116.79,173.72 v1(117.23,173.28)
  BOTTOM w0.178: v1(135.46,83.78) 135.51,83.83 135.51,84.03 CPU1.AF8
USB_CPU_PN8: length 67.5
  TOP w0.178: R9203.1 181.25,53.61 180.59,53.61 180.38,53.4 180.38,52.83 179.95,52.39 v1(179.55,52.39) v2(179.25,52.87)
  L4 w0.152: v1(179.55,52.39) 179.46,52.31 179.17,52.31 178.86,52.63 178.86,53.44 177.84,54.46 166.12,54.46 166.07,54.4 162.81,54.4 161.99,53.59 157.28,53.59 156.85,54.01 156.85,54.05 156.41,54.49 155.81,54.49 149.71,60.59 149.69,60.59 145.88,64.4 145.88,66.61 145.88,68.65 144.96,69.56 144.51,69.71 144.22,69.8 143.63,69.8 141.07,72.36 141.07,72.98 141.07,75.15 140,76.23 140,82.25 140.53,82.78 140.53,83.85 v1(140.76,84.08)
  BOTTOM w0.178: v1(140.76,84.08) 140.76,83.7 140.55,83.5 CPU1.AG1
USB_CPU_PP0: length 152
  TOP w0.178: 25.31,25.94 26.35,26.98 v1(27.27,26.98) ; 25.31,25.94 23.96,24.59 23.49,24.59 EL3601.1 ; 25.31,25.94 v2(25.49,25.79)
  L4 w0.127: 125.09,85.14 125.12,85.14 125.15,85.11 125.97,85.11 127.34,83.73 128.98,83.73 130.82,85.57 133.84,85.57 v1(134.16,85.9)
  L4 w0.152: 125.09,85.14 123.65,85.14 123.07,85.73 107.04,85.73 104.93,87.84 98.66,87.84 98.41,87.58 87.87,87.58 71.33,71.05 71.33,64.22 61.89,54.79 61.89,49.96 60.94,49.01 60.94,46.66 52.47,38.19 46.47,38.19 44.19,35.9 37.94,35.9 31.02,28.98 26.6,28.98 25.94,28.33 25.94,27.42 26.39,26.98 v1(27.27,26.98)
  BOTTOM w0.178: CPU1.AB10 134.16,86.11 v1(134.16,85.9)
USB_CPU_PP1: length 155
  TOP w0.178: v2(24.61,22.71) 24.42,22.86 ; 24.42,22.86 26.19,24.64 26.75,24.64 v1(26.96,24.44) ; 24.42,22.86 24.21,22.66 23.57,22.66 EL3602.1
  L4 w0.152: v1(135.85,84.81) 135.53,84.49 134.42,84.49 134.34,84.41 131.02,84.41 128.7,82.09 123.99,82.09 123.53,82.56 123.53,83.85 123.11,84.27 107.44,84.27 104.48,87.23 99.07,87.23 98.55,86.7 88.65,86.7 88.65,86.71 88.29,86.71 72.22,70.64 72.22,63.89 62.76,54.43 62.76,49.6 61.81,48.65 61.81,46.08 53.02,37.29 46.86,37.29 44.1,34.54 37.89,34.54 29.48,26.13 26.66,26.13 26.02,25.49 26.02,24.94 26.32,24.64 26.75,24.64 v1(26.96,24.44)
  BOTTOM w0.178: CPU1.AD7 v1(135.85,84.81)
USB_CPU_PP2: length 90.7
  TOP w0.152: v1(179.92,36.08) 179.7,35.85 178.82,35.85 178.43,35.45 178.43,34.75 178.22,34.53 EL3706.4
  TOP w0.178: v2(178.19,35.13) 178.43,35.13
  L4 w0.152: v1(143.04,83.21) 143.04,83.25 143.04,83.25 143.04,84.1 142.35,84.79 142.1,84.79 139.92,84.79 138.86,83.73 138.86,75.75 139.93,74.68 139.93,73.21 139.93,72.51 139.93,71.89 143.16,68.66 143.93,68.66 144.73,67.85 144.73,62.95 148.87,58.82 149.86,58.82 152.32,56.36 152.32,52.04 155.94,48.43 156.18,48.43 156.18,48.43 156.35,48.43 156.35,48.43 157,48.43 157.79,47.63 170.67,47.63 171.63,46.68 175.07,46.68 180.55,41.21 180.55,40.1 180.55,36.46 180.28,36.2 180.16,36.08 v1(179.92,36.08)
  BOTTOM w0.089: v1(143.04,83.21) 142.31,82.78 141.97,82.43 139.71,82.43 139.62,82.39 139.36,82.39 139.26,82.43 139.06,82.43 138.98,82.4 138.75,82.17 CPU1.AJ3
USB_CPU_PP4: length 136.8
  TOP w0.178: v1(117.03,170.07) 116.74,170.36 113.33,170.36 113.14,170.17 EL5507.3
  L4 w0.152: v1(157.65,84.92) 157.84,85.11 158.27,85.11 159.5,86.34 159.5,89.38 159.5,89.54 159.49,91.05 158.58,91.96 158.58,92.37 156.85,94.09 155.9,94.09 155.57,94.09 153.86,95.8 153.29,95.8 151.03,98.06 151.03,98.15 149.28,99.9 149.28,100.56 149.28,100.81 147.05,103.03 142.97,103.03 142.3,103.7 142.3,105.84 140.46,107.68 140.46,115.3 141.59,116.43 141.59,125 142.2,125.61 142.2,140.05 136.53,145.72 134.48,145.72 124.56,155.65 124.56,158.09 116.13,166.51 116.13,169.78 116.42,170.07 v1(117.03,170.07)
  BOTTOM w0.102: CPU1.AJ2 139.53,81.81 139.75,81.81
  BOTTOM w0.178: v2(153.96,82.32) 153.78,82.49 ; 153.78,82.49 155.92,84.62 157.34,84.62 v1(157.65,84.92) ; 153.78,82.49 152.12,80.82 146.04,80.82 144.7,82.16 142.68,82.16 142.4,81.89 140.61,81.89 140.53,81.81 139.75,81.81
USB_CPU_PP5: length 83.3
  TOP w0.178: R3302.1 182.46,31.29 181.61,31.29 180.77,32.13 180.77,32.38 ; 180.77,32.38 180.77,32.96 v1(180.54,33.19) ; 180.77,32.38 v2(180.51,32.37)
  L4 w0.089: v1(136.15,83.74) 136.37,83.52 136.37,83.35 135.96,82.94 135.96,82.69
  L4 w0.152: 135.96,82.69 135.88,82.61 135.88,79.97 137.14,78.7 137.14,77.6 137.02,77.48 137.02,76.33 139.08,74.27 139.08,73.56 139.08,72.15 139.08,72.15 139.08,71.51 143.45,67.14 143.45,63.32 143.45,63.32 143.45,62.47 144.31,61.61 144.55,61.61 144.87,61.61 148.52,57.97 148.88,57.97 149.51,57.97 150.87,56.6 150.87,53.92 151.47,53.32 151.47,51.69 151.6,51.56 151.6,51.54 156.2,46.95 157.04,46.95 157.2,46.78 169.3,46.78 170.79,45.29 171.62,45.29 179.11,37.8 179.11,34.25 179.59,33.77 180.28,33.77 180.54,33.51 v1(180.54,33.19)
  BOTTOM w0.178: CPU1.AF7 136.15,84.01 v1(136.15,83.74)
USB_CPU_PP6: length 155.3
  TOP w0.178: v1(110.84,157.03) 111.34,157.53 111.94,157.53 112.14,157.33 112.14,156.33 111.94,156.12 104.96,156.12 103.05,158.03 91.84,158.03 90.02,159.85 90.02,160.86 90.52,161.36 90.52,161.73 R6111.2
  L4 w0.152: v1(110.84,157.03) 111.35,157.55 112.44,157.55 115.21,154.77 116.91,154.77 120.67,151.02 125.56,151.02 128.39,148.19 128.39,147.9 128.98,147.31 129.45,147.31 131.98,144.77 131.98,142.32 140.13,134.17 140.13,127.35 140.13,126.84 139.58,126.29 139.58,117.4 138.46,116.29 138.46,116.04 138.46,108.89 136.21,106.64 136.21,102.49 136.73,101.97 140.51,101.97 141.88,100.6 141.88,98.9 144.76,96.03 150.02,96.03 151.45,94.6 151.45,93.81 153.72,91.54 155.62,91.54 155.82,91.33 155.82,90.82 155.93,90.71 v1(156.44,90.71)
  BOTTOM w0.089: 139.23,83.22 139.31,83.22 140.13,83.22 140.15,83.24 140.23,83.24
  BOTTOM w0.102: 140.23,83.24 140.62,83.24 141.49,84.1 142.76,84.1 142.78,84.12 142.81,84.12 ; 139.23,83.22 CPU1.AH2
  BOTTOM w0.152: 142.81,84.12 145.03,84.12 146.26,82.89 151.14,82.89 154,85.75 156.45,85.75 156.99,86.3 156.99,88.57 157,88.57 157,90.51 156.79,90.71 v1(156.44,90.71)
  BOTTOM w0.178: v2(147.02,83.13) 147.03,82.89
USB_CPU_PP7: length 145.1
  TOP w0.089: 137.26,84.97 137.23,84.94 137.23,84.79 136.85,84.41 135.45,84.41 v1(134.82,83.78)
  TOP w0.178: 155.72,84.56 154.34,83.18 147.62,83.18 145.45,85.35 137.87,85.35 137.75,85.23 137.52,85.23 137.26,84.97 ; 155.72,84.56 156.5,85.34 156.5,85.75 157.63,86.88 v1(157.78,86.88) ; 155.72,84.56 v2(155.54,84.74) ; v1(117.23,174.32) 117.02,174.11 116.29,174.11 R5536.2
  L4 w0.152: v1(117.23,174.32) 116.92,174.01 116.38,174.01 114.99,172.61 114.99,159.73 115.16,159.55 115.18,159.55 116.98,157.75 117.17,157.75 117.66,157.26 117.66,156.33 119.42,154.57 119.44,154.57 121.62,152.38 126.16,152.38 129.75,148.8 129.75,148.35 133.24,144.85 133.24,143 133.24,143 133.24,142.26 140.98,134.52 140.98,127.7 140.98,126.25 140.45,125.72 140.45,116.98 139.31,115.85 139.31,107.84 139.31,107.84 139.31,107.34 141.43,105.22 141.43,103.21 142.89,101.74 142.89,98.82 144.69,97.02 144.78,96.94 150.31,96.94 150.37,96.88 152.3,94.95 152.3,94.29 153.64,92.95 153.88,92.95 156.38,92.95 157.43,91.89 157.43,91.15 157.44,90.72 157.44,88.17 158.33,87.27 158.33,86.97 158.13,86.77 157.9,86.77 v1(157.78,86.88)
  BOTTOM w0.178: CPU1.AF9 135.13,84.17 134.82,83.86 v1(134.82,83.78)
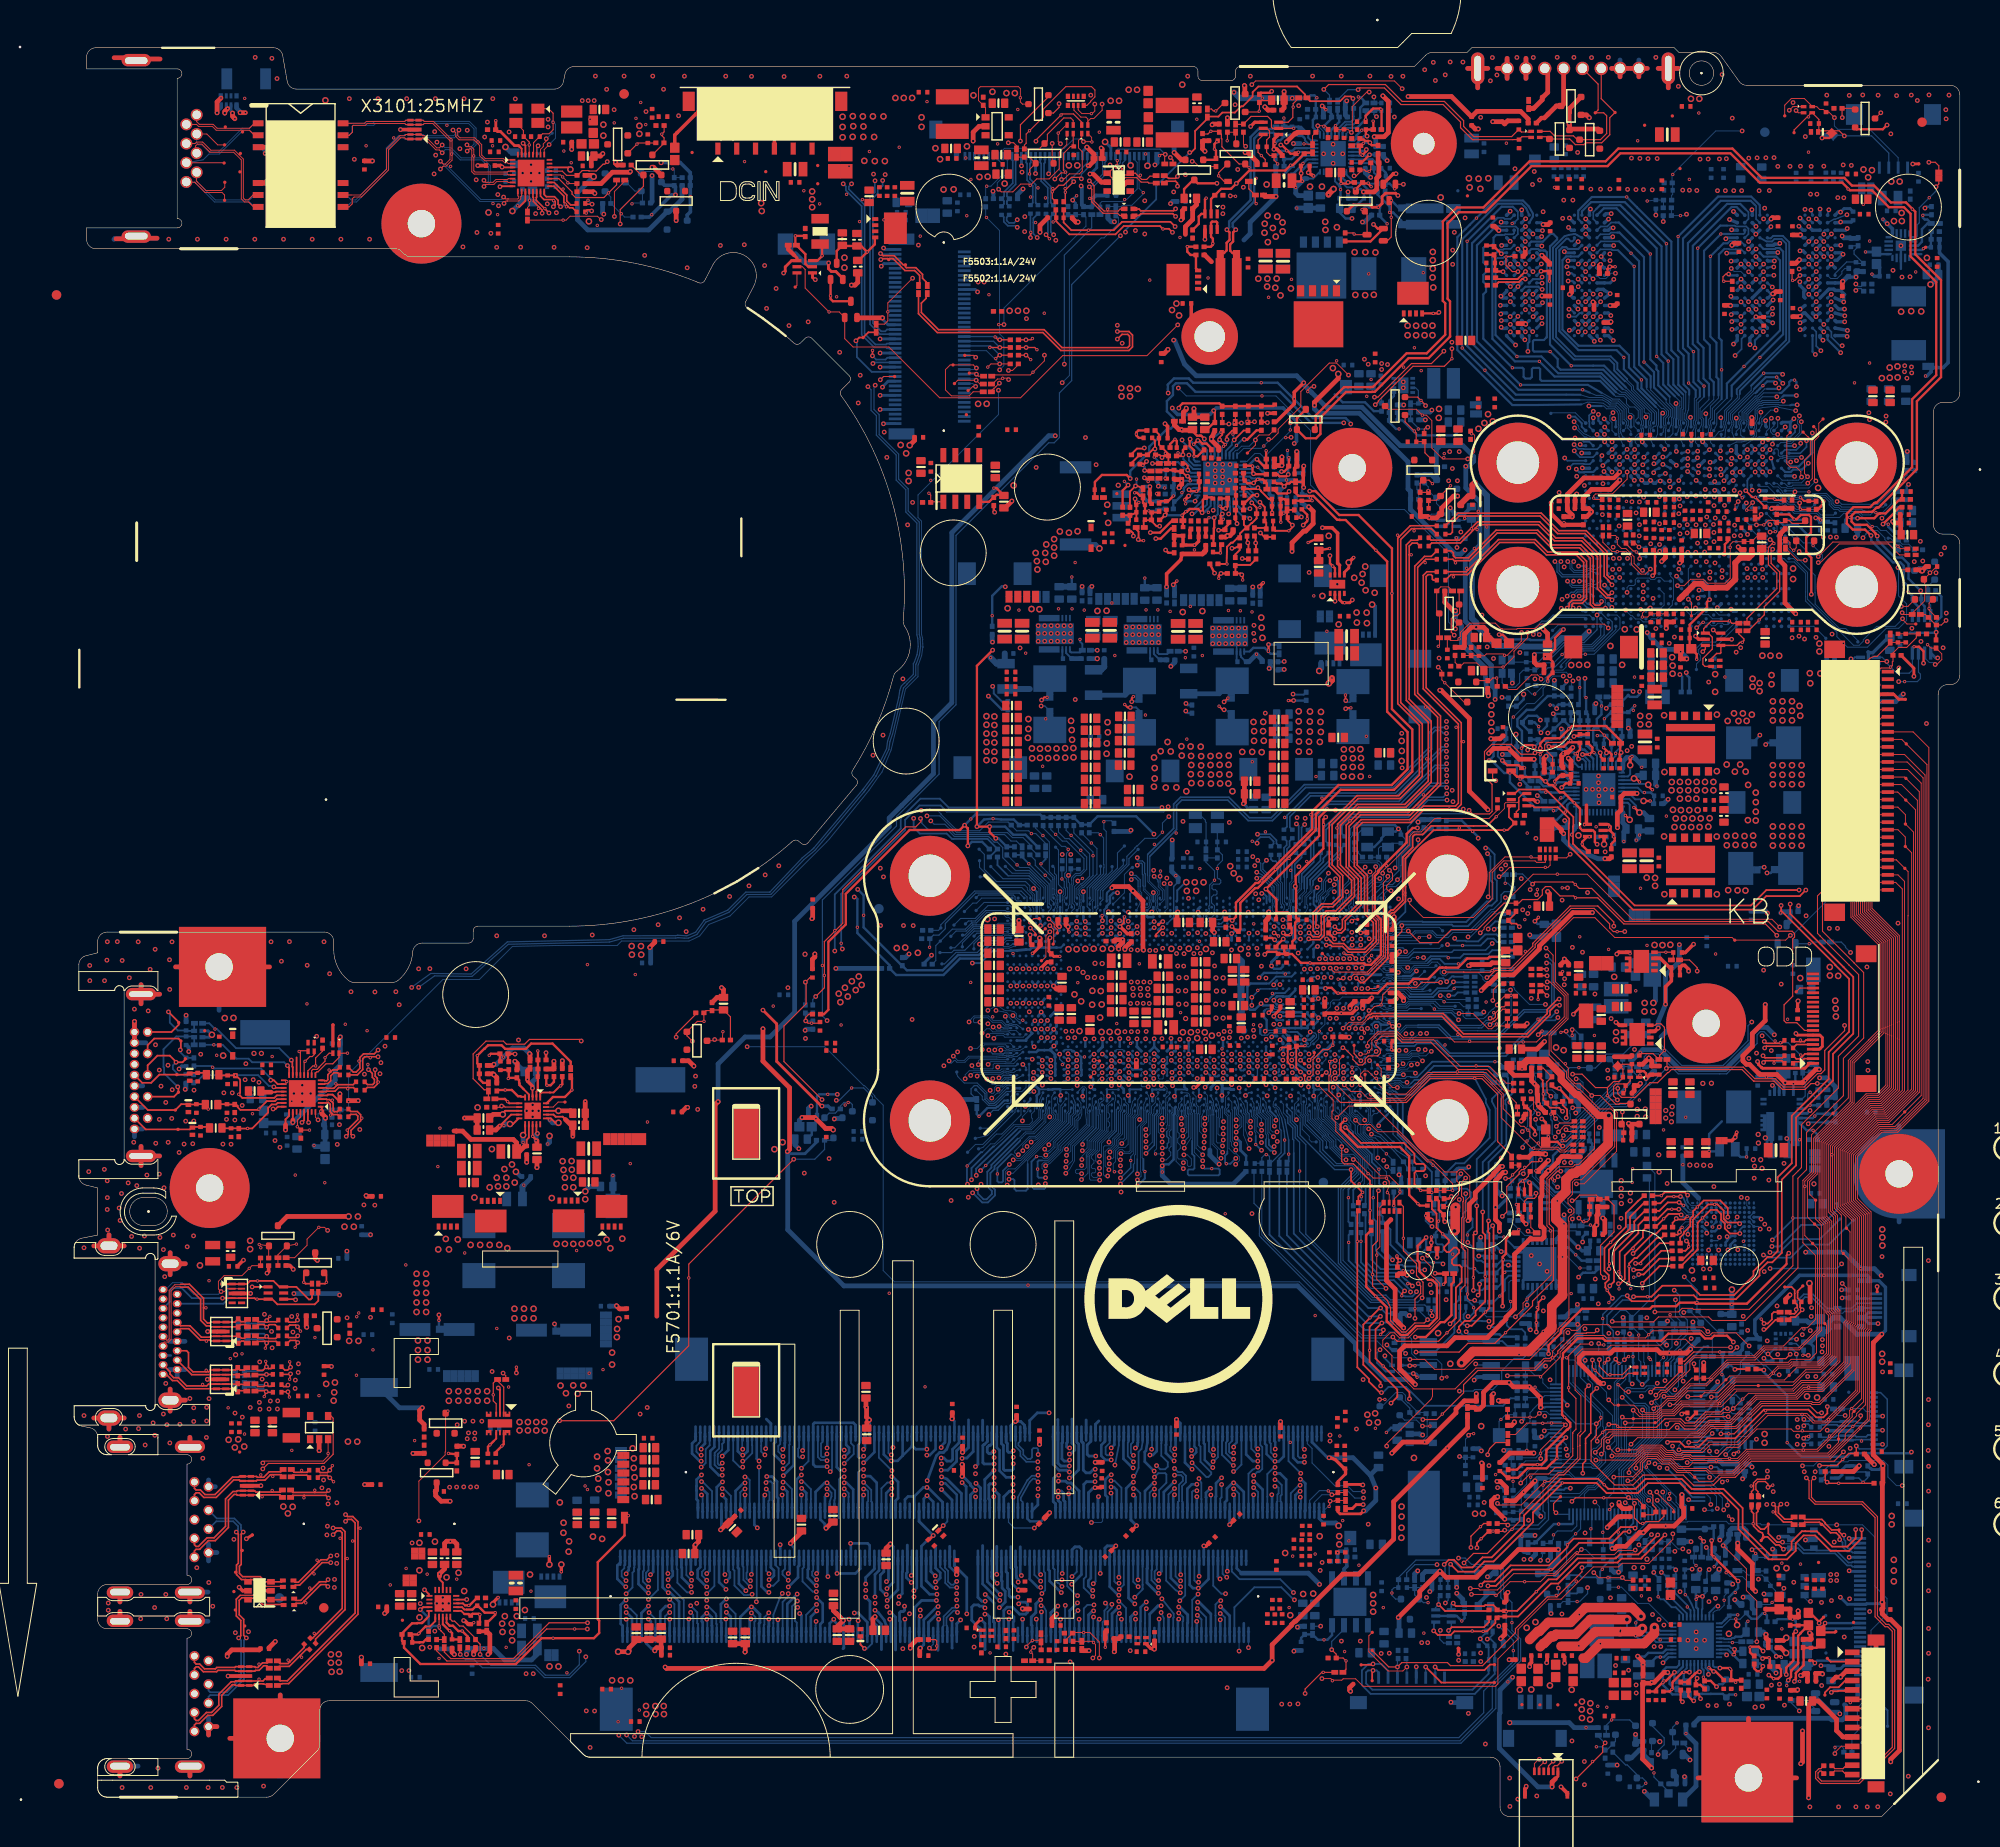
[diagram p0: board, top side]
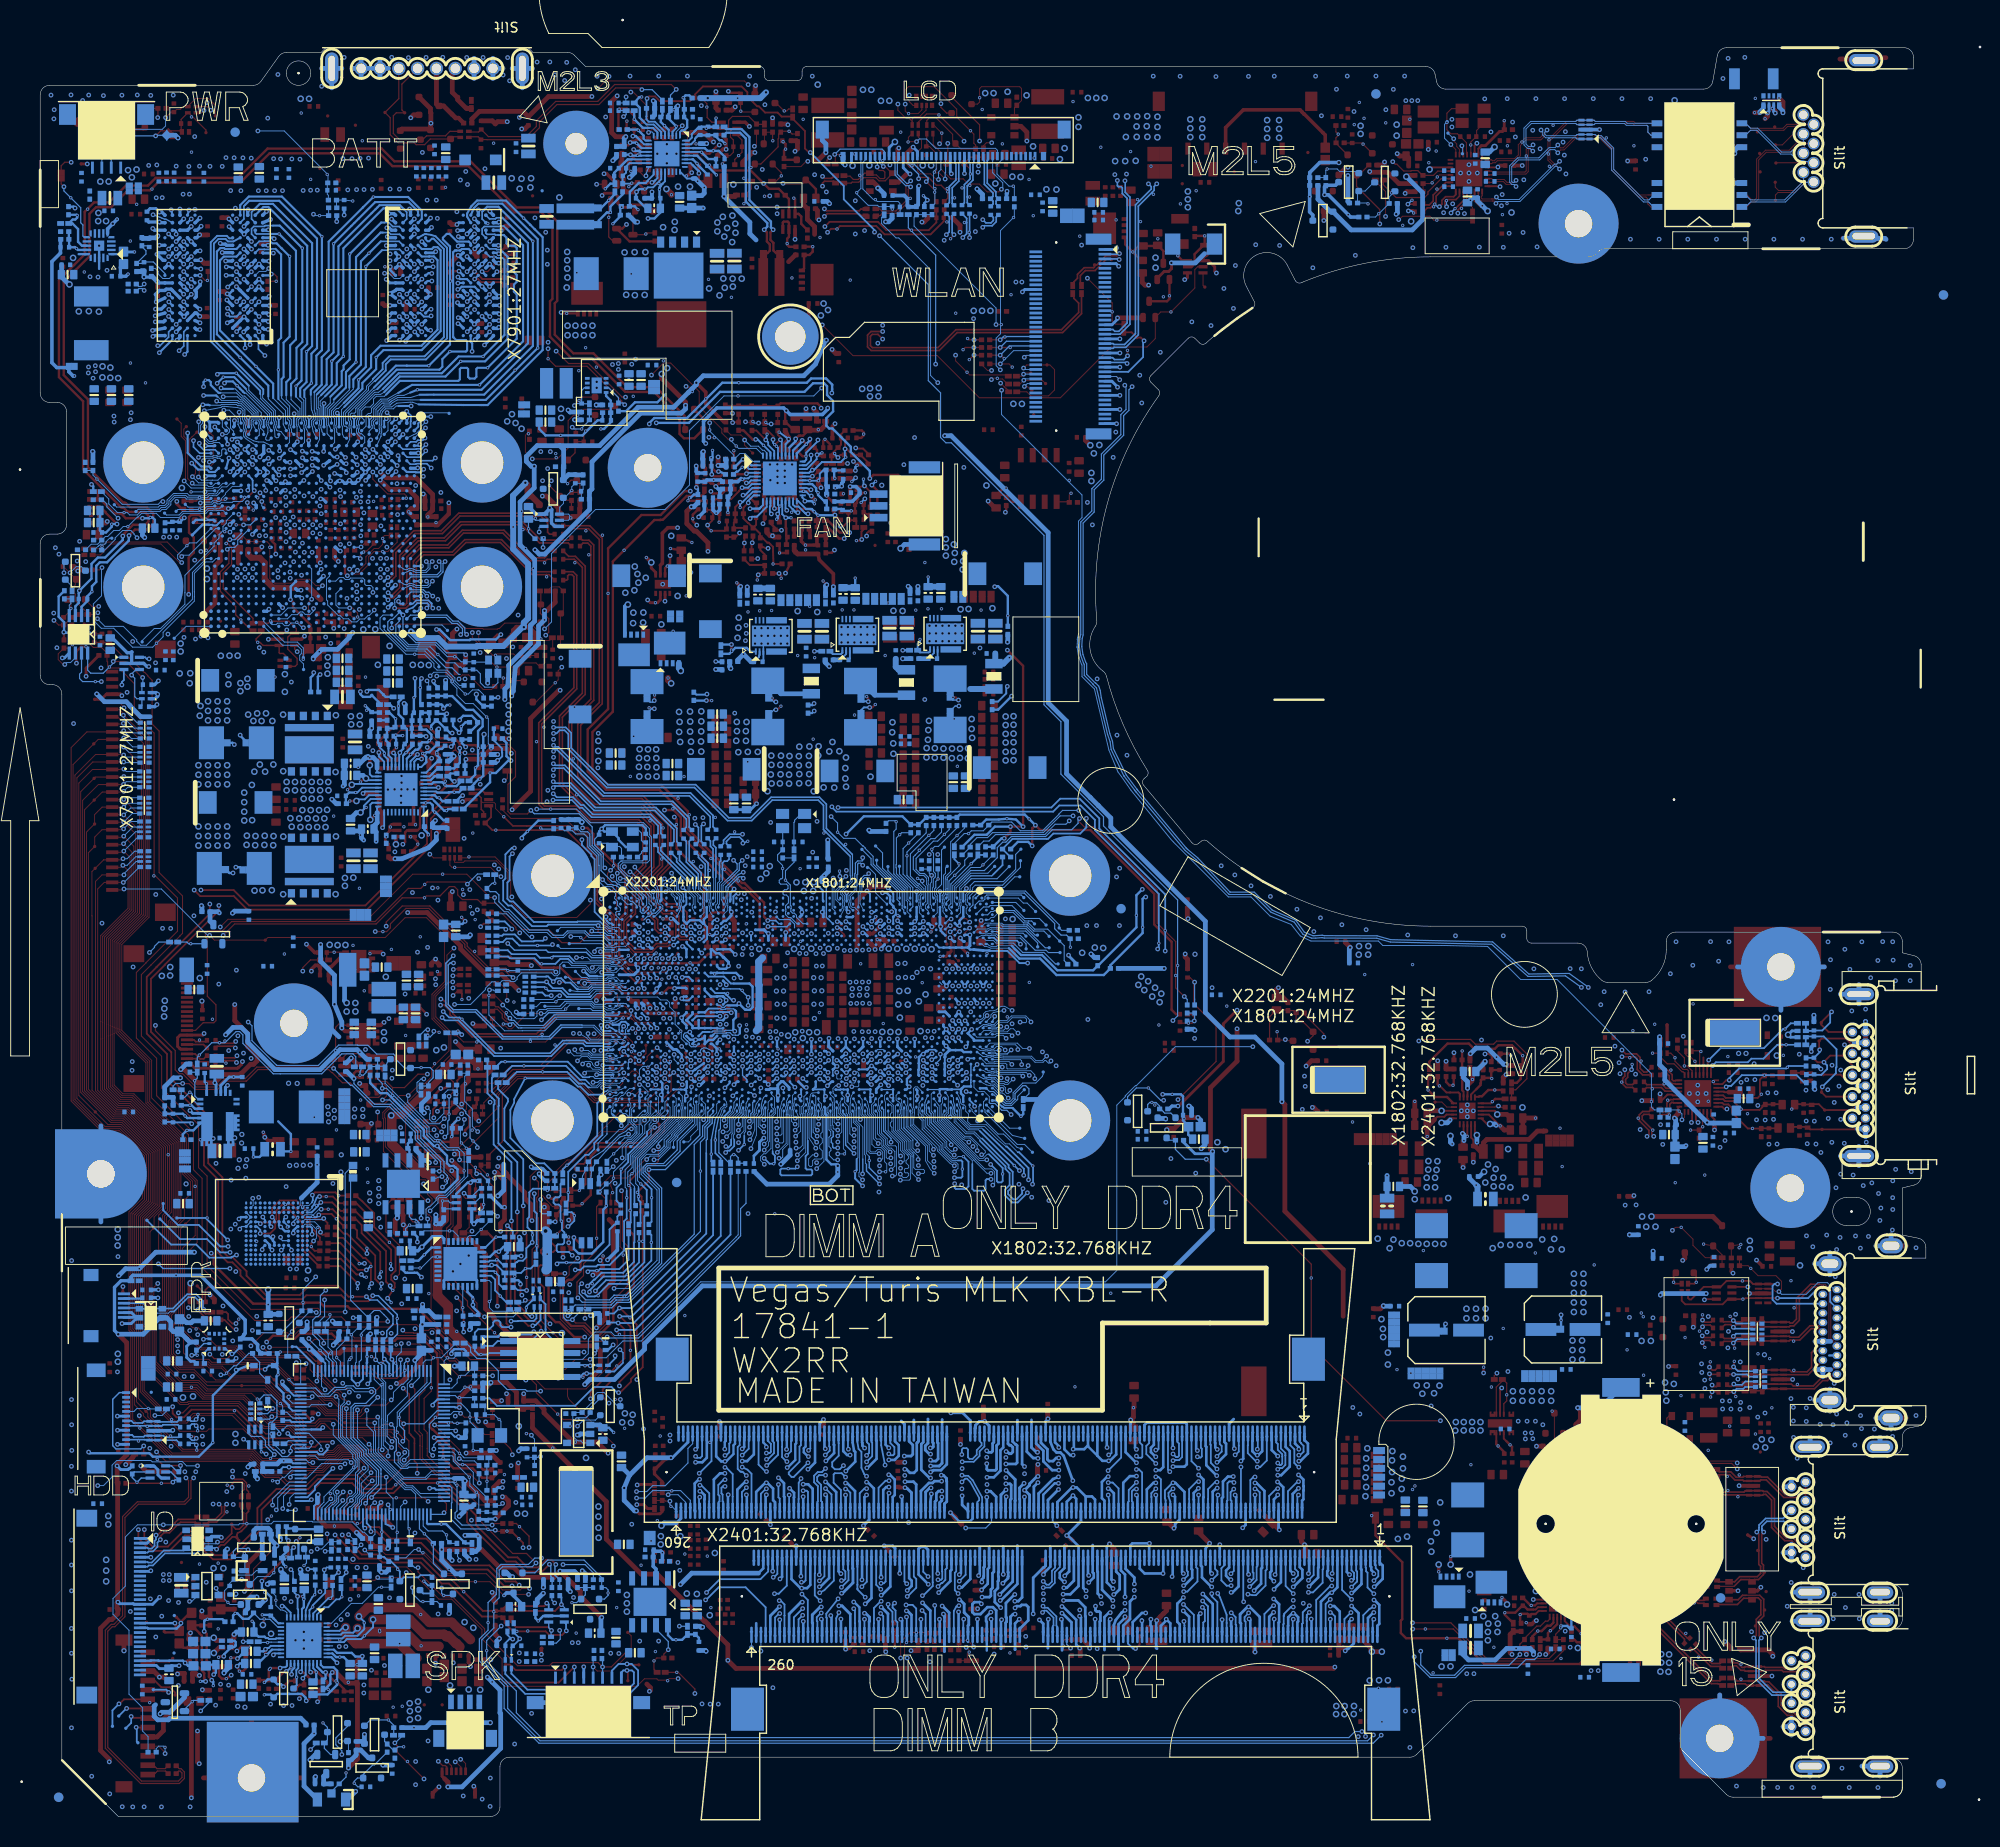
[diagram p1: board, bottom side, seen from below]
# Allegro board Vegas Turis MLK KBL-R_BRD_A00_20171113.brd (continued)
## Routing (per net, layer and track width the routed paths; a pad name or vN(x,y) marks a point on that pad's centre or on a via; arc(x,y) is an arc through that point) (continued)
USB_CPU_PP8: length 67.1
  TOP w0.178: R9204.1 180.77,52.79 179.74,51.76 v1(179.53,51.76) ; v2(139.69,84.36) v1(140.09,83.96)
  L4 w0.152: v1(179.53,51.76) 179.5,51.79 179.28,51.79 178.56,52.5 178.56,53.32 177.72,54.16 166.24,54.16 166.19,54.11 162.93,54.11 162.11,53.3 157.15,53.3 156.56,53.89 156.56,53.93 156.29,54.2 155.69,54.2 149.59,60.29 149.57,60.29 145.58,64.28 145.58,66.73 145.58,68.53 144.81,69.31 144.43,69.43 144.17,69.51 143.51,69.51 140.78,72.24 140.78,72.86 140.78,75.03 139.71,76.1 139.71,82.38 140.23,82.9 140.23,83.82 v1(140.09,83.96)
  BOTTOM w0.178: CPU1.AG2 139.62,83.79 140.04,83.98 v1(140.09,83.96)
USB_EN#: length 3.7
  TOP w0.127: v2(165.16,48.88) 165.05,48.88 v1(164.71,48.54)
  BOTTOM w0.127: 164.71,48.54 164.72,48.55 R2479.2 ; 164.71,48.54 164.36,48.2 163.9,48.2 163.66,47.96 KBC24.13 ; 164.71,48.54 v1(164.71,48.54)
USB_OC0#: length 366.6
  TOP w0.102: v1(20.04,37.58) 20.24,37.77 26.45,37.77 26.98,38.31 v2(26.98,38.58) U3501.3 ; RN802.6 156.32,101.45 156.28,101.41 155.38,101.41 155.22,101.57 151.89,101.57 150.67,100.35 150.67,97.56 148.66,95.55 143.34,95.55 141.89,97 v1(141.89,97.4)
  L3 w0.102: v1(141.89,97.4) 141.43,96.94 136.01,96.94 135.36,97.59 135.36,98.16 v1(135.22,98.29) ; v1(20.04,37.58) 20.84,36.78 20.84,25.23 21.61,24.46 21.61,19.92 27.24,14.29 49.39,14.29 54.14,9.54 63.39,9.54 64.45,10.6 136.78,10.6 138.57,8.8 150.29,8.8 157.11,1.98 179.31,1.98 180.85,3.52 187.14,3.52 195.27,11.65 195.27,31.25 190.5,36.02 189.15,36.02 185.83,39.35 185.83,42.1 186.79,43.06 186.79,49.73 185.84,50.68 v1(185.75,50.68)
  L4 w0.089: 136.06,97.5 136.01,97.5 v1(135.22,98.29)
  L4 w0.102: v1(185.75,50.68) 185.86,50.79 185.86,60.01 178.45,67.41 178.02,67.41 174.65,70.78 166.66,70.78 166.27,71.18 162.96,71.18 162.22,71.48 158.32,75.38 156.52,75.38 155.75,76.16 154.68,76.16 153.24,77.59 153.05,77.59 148.51,82.14 148.51,87.31 146.46,89.36 142,89.36 139.89,91.47 139.89,93.67 136.06,97.5
  BOTTOM w0.102: CPU1.A9 135.16,98.23 v1(135.22,98.29)
USB_OC1#: length 29.6
  TOP w0.102: RN802.5 154.89,101.89 v2(154.79,101.99) 152.02,101.99 150.35,100.32 150.35,97.85 v1(150.24,97.74)
  L3 w0.102: v1(150.24,97.74) 149.84,97.34 143.61,97.34 141.81,99.14 139.69,99.14 139.63,99.16 139.57,99.16 138.7,99.16 138.31,99.55 138.31,100.34 137.74,100.91 v1(137.17,100.91)
  BOTTOM w0.089: 134.98,98.67 134.84,98.4 134.84,98.13 134.87,98.1 134.87,97.74 134.91,97.5 134.92,97.43 134.94,97.38 134.94,97.26 134.93,97.15 134.9,97.05 134.9,96.57 CPU1.C9
  BOTTOM w0.102: v1(137.17,100.91) 137.17,100.86 134.98,98.67
USB_OC2#: length 160.7
  TOP w0.102: RN802.8 158.57,101.89 v1(158.95,102.27)
  L2 w0.102: v1(163.06,51.36) 163.55,50.86 166.89,50.86 169.17,53.14 171.2,53.14 172.04,53.98 172.04,54.49 176.11,58.56 176.95,58.56 184.28,65.89 184.28,67.95 184.68,68.34 184.68,73.81 183.92,74.57 183.92,79.2 180.21,82.91 180.21,86.37 176.72,89.87 176.22,89.87 170.94,95.15 164.93,95.15 158.95,101.13 v1(158.95,102.27) 158.33,102.9 152.79,102.9 149.18,106.51 148.04,106.51 147.78,106.76 147.78,106.88 v1(147.59,107.07)
  L3 w0.102: v1(163.06,51.36) 167.66,46.76 169.28,46.76 170.51,45.53 170.51,44.88 171.87,43.52 171.87,41.7 173.11,40.47 173.11,40.32 174.11,39.31 175.24,39.31 175.91,38.65 175.91,36.09 176.06,35.94 176.06,35.06 177.33,33.79 177.33,32.4 177.33,32.39 177.33,27.17 177.53,26.97 177.53,24.44 178.75,23.22 184.12,23.22 v1(184.48,22.86)
  BOTTOM w0.089: 134.2,96.77 134.44,96.98 134.6,96.98 134.68,97.06 134.74,97.15 134.76,97.21 134.76,97.29 134.75,97.38 134.73,97.44 134.63,97.99 134.66,98.15 134.66,98.47 134.69,98.5 134.72,98.56 134.76,98.8
  BOTTOM w0.102: CPU1.D9 135.03,95.66 134.2,96.5 134.2,96.77 ; v1(184.48,22.86) 184.24,22.86 183.86,23.24 U3503.3 ; v1(147.59,107.07) v2(146.11,107.07) 143.36,107.07 143.07,106.78 143.01,106.78 141.86,105.63 140.44,105.63 140.44,105.64 136.25,105.64 135.62,105.01 135.62,104.34 135.39,104.11 135.39,99.43 134.76,98.8
USB_OC3#: length 28.8
  TOP w0.102: RN802.7 156.82,101.1 156.6,100.88 v2(156.31,100.88) 152.5,100.88 151.52,99.9 v1(151.4,99.9)
  L3 w0.102: v1(151.4,99.9) 151.4,98.29 150.25,97.14 143.54,97.14 141.73,98.95 139.66,98.95 139.65,98.95 139.6,98.97 139.56,98.97 138.49,98.97 138.35,99.11 138.34,99.11 137.69,99.76 v1(137.69,100.4)
  BOTTOM w0.102: CPU1.B9 135.16,96.98 135.43,97.25 135.43,97.94 135.62,98.13 135.62,98.45 137.57,100.4 v1(137.69,100.4)
USB_PN0_C: length 14.7
  TOP w0.178: v1(17.97,30.23) 17.75,30.01 17.75,28.27 ; 17.75,28.27 17.75,26.79 17.56,26.6 17.56,25.83 17.91,25.48 19.78,25.48 20.33,24.94 ED3604.3 22.03,24.94 EL3601.3 ; 17.75,28.27 AFTP3602.1
  BOTTOM w0.178: v1(17.97,30.23) 17.74,30.46 17.74,30.69 17.72,30.71 17.72,30.98 17.03,31.68 15.15,31.68 USB1.2
USB_PN1_C: length 19.1
  TOP w0.127: 19.11,23.51 17.65,23.51
  TOP w0.178: 19.11,23.51 19.48,23.51 19.95,23.04 ED3604.1 22.14,23.04 EL3602.3 ; AFTP3606.1 17.23,21.95 ; 17.23,21.95 17.23,23.09 17.65,23.51 ; 17.23,21.95 17.23,21.31 17.71,20.83 17.71,19.2 v1(17.48,18.98)
  BOTTOM w0.178: v1(17.48,18.98) 17.74,18.72 17.74,14.71 16.23,13.2 14.46,13.2 14.28,13.38 USB2.2
USB_PN2_C: length 15.8
  TOP w0.178: EL3706.2 178.9,32.42 178.75,32.27 178.75,30.99 179.19,30.55 179.57,30.55 180,30.98 ; 180,30.98 180,30.08 180.92,29.16 v1(181.51,29.16) ; 180,30.98 AFTP6603.1
  BOTTOM w0.102: v1(181.51,29.16) 181.69,28.98 183.14,28.98 183.15,28.97
  BOTTOM w0.178: 183.15,28.97 183.8,28.32 184.65,28.32 ED3704.6 185.09,28.27 187.22,28.27 188.5,26.98 188.88,26.98 188.95,27.05 IOBD1.6
USB_PN5_C: length 8.3
  TOP w0.178: R3301.2 183.86,31.57 185.68,31.57 186.05,31.21 186.05,31.15 186.74,30.46 AFTP6601.1 187.51,30.28 187.89,29.9 v1(188.04,29.9)
  BOTTOM w0.178: v1(188.04,29.9) 188.04,29.64 188.05,29.62 188.05,29.43 188.2,29.29 188.2,28.78 188.5,28.48 188.87,28.48 188.95,28.55 IOBD1.3
USB_PN8_C: length 15.2
  TOP w0.178: R9203.2 182.29,53.43 182.79,53.43 182.97,53.61 v1(182.97,53.88) 182.97,53.92 183.08,54.02 183.08,54.38 EC9202.1 182.81,54.75 182.81,55.59 182.81,55.59 182.81,55.95 182.48,56.28 AFTP8903.1
  BOTTOM w0.178: v1(182.97,53.88) 183.06,53.97 183.06,54.79 183.77,55.5 184.74,55.5 186.24,53.99 187.34,53.99 ED9201.6 187.41,53.99 188.84,53.99 189.4,54.55 FPR1.3
USB_POWERSHARE_VBUS_EN: length 8.1
  L4 w0.102: v1(173.22,32.61) 169.2,32.61 v1(168.2,33.6)
  BOTTOM w0.102: v1(173.22,32.61) 173.29,32.54 TP2403.1 ; KBC24.71 168.86,32.83 168.2,33.48 v1(168.2,33.6)
USB_PP0_C: length 14.9
  TOP w0.127: EL3601.2 22.12,24.46 20.37,24.46
  TOP w0.178: 20.37,24.46 19.65,25.18 18.72,25.18 ED3604.4 18.23,25.18 17.78,25.18 17.25,25.71 17.25,25.96 ; 17.25,25.96 17.25,26.72 17.44,26.91 17.44,30.01 v1(17.23,30.23) ; 17.25,25.96 AFTP3603.1
  BOTTOM w0.178: v1(17.23,30.23) 17.43,30.43 17.43,30.57 17.42,30.58 17.42,30.85 16.9,31.37 15.1,31.37 USB1.3
USB_PP1_C: length 19.4
  TOP w0.178: EL3602.2 22.19,22.53 20.02,22.53 19.36,23.19 18.63,23.19 ED3604.6 18.27,23.24 17.81,23.24 17.53,22.96 17.53,21.44 18.02,20.96 18.02,20.25 ; 18.02,20.25 18.02,19.26 v1(18.3,18.98) ; 18.02,20.25 AFTP3607.1
  BOTTOM w0.178: v1(18.3,18.98) 18.04,18.72 18.04,14.58 16.36,12.9 14.46,12.9 14.28,12.72 USB2.3
USB_PP2_C: length 16.3
  TOP w0.178: v1(181.61,28.41) 181.33,28.69 181.32,28.69 181.15,28.86 180.79,28.86 179.94,29.71 179.63,29.71 AFTP6604.1 179.47,29.85 179.47,29.88 179.46,29.91 179.37,30.13 179.02,30.28 178.97,30.33 178.97,30.33 178.44,30.86 178.44,32.2 178.22,32.42 EL3706.3
  BOTTOM w0.178: v1(181.61,28.41) 181.73,28.53 182.39,28.53 ED3704.1 183.17,28.52 183.73,27.96 187.09,27.96 188.38,26.68 188.82,26.68 188.95,26.55 IOBD1.7
USB_PP5_C: length 8.1
  TOP w0.178: R3302.2 183.86,31.27 185.43,31.27 AFTP6602.1 185.72,31.05 186.61,30.15 187.21,30.15 187.57,29.79 187.57,29.71 187.58,29.69 v1(187.58,29.43)
  BOTTOM w0.178: IOBD1.4 188.95,28.05 188.83,28.17 188.37,28.17 187.89,28.65 187.89,29.12 v1(187.58,29.43)
USB_PP8_C: length 15.2
  TOP w0.178: R9204.2 182.41,53.08 182.87,53.08 183.61,53.82 v1(183.61,53.86) 183.61,53.89 183.38,54.12 183.38,54.56 EC9201.1 183.11,55.11 183.11,55.71 183.11,55.71 183.11,55.83 AFTP8904.1
  BOTTOM w0.102: 188.11,53.69 187.92,53.49 186.72,53.49 186.54,53.67 186.47,53.67
  BOTTOM w0.178: 186.47,53.67 186.13,53.67 184.61,55.2 183.9,55.2 183.36,54.66 183.36,54.26 183.53,53.86 183.53,53.86 v1(183.61,53.86) ; 188.11,53.69 188.97,53.69 188.97,53.7 188.99,53.7 189.25,53.96 ED9201.1 189.9,54.05 FPR1.4
USB_PWR_EN#: length 249.3
  TOP w0.127: U3501.4 27.29,42.56 27.52,42.33 27.52,38.5 26.55,37.53 26.35,37.53 26.35,37.53 20.63,37.53 v1(20.04,36.94)
  L3 w0.127: v1(163.99,51.38) 168.36,47 169.38,47 170.91,45.48 171.23,45.48 172.23,44.48 172.23,41.69 173.35,40.57 173.35,40.42 174.18,39.59 175.89,39.59 176.78,38.7 176.78,35.04 177.83,33.99 177.83,32.19 177.82,32.18 177.82,28.17 178.03,27.96 178.03,25.51 178.91,24.63 179.84,24.63 180.21,24.25 v1(181.66,24.25) ; v1(59.92,9.03) 58.96,9.03 58.88,9.11 54.23,9.11 49.29,14.05 27.14,14.05 21.37,19.82 21.37,24.36 20.59,25.13 20.59,36.39 v1(20.04,36.94)
  L4 w0.127: v1(151.37,20.24) 151.44,20.24 153.02,21.82 155.74,21.82 156.44,21.12 157.1,21.12 157.37,21.38 157.37,21.44 157.89,21.96 163.9,21.96 164.78,22.85 165.5,22.85 166.17,23.52 169.62,23.52 170.44,24.34 172.24,24.34 172.34,24.39 173.1,25.15 173.13,25.16 176.31,25.16 176.61,25.46 177.98,25.46 178.67,24.77 179.13,24.77 179.15,24.79 181.13,24.79 v1(181.66,24.25)
  BOTTOM w0.127: v1(59.92,9.03) 60.66,9.03 61.3,8.38 147.12,8.38 149.76,11.02 149.76,13.33 152.64,16.22 152.65,16.22 152.91,16.48 v2(152.91,17.62) 152.91,18.7 v1(151.37,20.24) ; v1(163.99,51.38) 164.07,51.46 164.59,51.46 R2434.2 164.69,51.42 164.69,50.57 R2479.1 ; U3503.4 181.39,23.87 181.66,24.14 v1(181.66,24.25)
USB_PWR_SHR_EN_L#: length 2.4
  BOTTOM w0.102: KBC24.118 156.56,41.93 156.56,41.93 156.41,41.79 156.04,41.79 v2(156.03,41.79) 155.8,41.79 155.76,41.83 R2493.1
USB_UART_SEL_D9: length 6.3
  BOTTOM w0.089: TP2006.1 144.53,90.25 142.46,90.25 142.26,90.05 142.26,89.99 141.92,89.66 141.37,89.66 140.93,90.11 140.31,90.11 140.06,89.86 139.71,89.86 139.62,89.9 139.39,89.9 CPU1.P2
USBCOMP: length 2.5
  TOP w0.508: v1(136.9,85.9) 136.9,86.59 R1603.1 137.5,86.64 v2(137.88,87.02)
  BOTTOM w0.406: v1(136.9,85.9) 137.09,86.09 CPU1.AB6
V_SM_VREF_CNTA: length 144.9
  TOP w0.508: v1(110.51,17.51) 110.55,17.55 110.55,18.82 C1222.1 111.01,18.9 R1206.2
  L4 w0.305: v1(101.07,75.48) 101.07,78.39 101.35,78.68 101.35,79.32 102.31,80.27 102.31,80.69 101.97,81.03 101.18,81.03 98.97,83.24 97.57,83.24 97.06,83.75 96.7,83.75 96.55,83.9 94.42,83.9
  L4 w0.508: v1(110.51,17.51) 110.51,19.1 111.91,20.5 111.91,28.42 108.45,31.88 106.79,31.88 104.93,30.02 101.23,30.02 98.84,32.41 67.27,32.41 63.64,36.04 63.64,39.8 64.96,41.12 64.96,47.44 65.82,48.31 65.82,52.74 68.08,55 73.63,60.94 74.02,61.36 74.04,61.38 75.28,62.62 75.28,62.71 77.91,65.53 78.69,66.36 80.12,67.79 80.12,67.81 81.09,70.34 81.46,70.7 82.56,73.58 82.56,75.99 90.47,83.9 94.42,83.9
  BOTTOM w0.203: CPU1.AY67 101.6,76.13 101.07,75.6 v1(101.07,75.48)
V_SM_VREF_CNTB: length 141.1
  L4 w0.279: 100.76,82.53 100.74,82.53 98.14,85.13 96.72,85.13
  L4 w0.305: 96.34,85.27 96.58,85.27 96.72,85.13 ; 100.76,82.53 102.27,82.53 102.55,82.25 102.66,82.25 104.31,80.6 104.31,77.76 100.76,74.21 v1(100.76,73.93)
  L4 w0.508: 96.34,85.27 96.06,85.55 88.98,85.55 80.16,76.73 80.16,74.42 79.99,74.26 79.99,70.68 78.71,69.39 78.71,67.81 77.96,67.06 74.26,63.11 74.26,63.04 73.31,62.09 72.89,61.64 67.62,56 67.6,56 64.81,53.2 64.81,48.73 63.94,47.86 63.94,41.57 62.45,40.08 62.45,20.9 63.45,19.9 84.19,19.9 86.9,17.2 93.49,17.2 93.55,17.26 v1(98.99,17.26)
  BOTTOM w0.089: v1(100.76,73.93) 100.76,74.39 101.34,74.97 101.34,75.14 101.6,75.4 101.6,75.63 CPU1.BA67
VCI_IN1#: length 3.6
  BOTTOM w0.102: KBC24.126 155.71,45.13 v2(155.22,45.63) 154.89,45.63 154.51,45.25 R2452.1
VCREF0: length 5.7
  BOTTOM w0.102: R2424.2 167.66,51.57 C2409.1 167.77,51.41 R2448.1 168.88,49.65 168.88,48.79 v2(168.85,48.77) 168.46,48.37 KBC24.25
VD_IN1_C: length 108.9
  TOP w0.102: C2613.2 192.98,124.79 R2611.1
  TOP w0.114: C2612.2 C2613.2 ; v1(167.95,53.62) 167.95,53.63 170.46,53.63 170.84,54.01 171.93,54.01 172.04,53.9 177.98,53.9 182.61,58.54 v2(182.61,63.62) 182.61,68.06 183.19,68.63 183.52,68.97 183.52,73.52 184.49,74.48 184.51,74.48 187.45,77.42 187.45,80.8 189.6,82.96 189.6,89.48 188.58,90.5 188.58,90.5 185.53,93.56 185.52,93.58 185.23,93.87 185.23,97.85 187.71,100.33 187.71,115.37 188.46,116.11 188.46,120.76 188.93,121.23 188.93,121.28 189.24,121.6 189.29,121.6 190.81,123.11 191.26,123.3 191.56,123.3 192.96,124.7 R2611.1
  BOTTOM w0.114: v1(167.95,53.62) 167.95,68.36 R2610.2
VGA_CORE: length 28.7
  L4 w0.381: v1(162.67,102.53) 162.83,102.53 164.02,101.34 164.02,99.29 167.77,95.54 174.87,95.53 175.02,95.53 175.64,95.53 175.86,95.76 177.7,95.76 180.69,98.74 180.77,98.74 182.52,100.5 v4(182.52,103.2)
  vias: v1(166.44,128.3) v1(166.72,130.86) v1(166.72,130.15) v1(166.69,129.39) v1(167.51,135.27) v1(167.76,129.47) v1(168.45,135.2) v1(168.49,140.98) v1(170.5,141.06) v1(170.49,138.47) v1(170.62,139.3) v1(170.62,136.33) v1(171.38,140.28) v1(171.39,137.3) v1(171.46,134.37) v1(172.31,140.36) v1(172.3,134.37) v1(172.58,131.93) v1(173.24,134.39) v1(173.3,141.05) v1(173.3,140.28) v1(173.31,137.27) v1(173.38,135.42) v1(173.8,132.27) v1(173.78,131.61) v1(174.22,136.48) v1(174.26,140.24) v1(174.34,133.24) v1(174.36,138.01) v1(175.1,132.43) v1(175.08,131.71) v1(175.27,141.08) v1(176.42,137.25) v1(176.39,136.13) v1(177.06,136.14) v1(183.27,125.46) v1(183.85,125.15) v2(165.79,121.1) v4(163.23,124.41) v4(164.47,122.4) v4(164.75,126.19) v4(166.02,126.16) v4(179.37,123.38) v4(180.23,123.38) v4(180.35,121.31) v4(180.35,120.35) v4(180.49,118.53) v4(180.49,117.51) v4(180.49,116.5) v4(180.49,111.74) v4(180.49,110.72) v4(180.49,109.71) v4(180.49,105.23) v4(180.49,104.21) v4(180.49,103.2) v4(181.16,123.37) v4(181.5,118.53) v4(181.5,117.51) v4(181.5,116.5) v4(181.5,111.74) v4(181.5,110.72) v4(181.5,109.71) v4(181.5,105.23) v4(181.5,104.21) v4(181.5,103.2) v4(182.52,118.53) v4(182.52,117.51) v4(182.52,116.5) v4(182.52,111.74) v4(182.52,110.72) v4(182.52,109.71) v4(182.52,105.23) v4(182.52,104.21) v4(182.63,132.64) v4(182.63,131.52) v4(183.32,118.04) v4(183.4,116.99) v4(183.54,111.74) v4(183.54,110.72) v4(183.54,109.71) v4(183.54,105.23) v4(183.54,104.21) v4(183.54,103.2) v4(184.41,121.52) v4(184.46,120.45) v4(185.53,121.49)
VGA_RST#: length 20.8
  TOP w0.102: v1(163,126.32) 162.59,126.73 155.74,126.73 155.39,126.38 155.35,126.38 155.24,126.27 153.34,126.27 153.28,126.2 151.77,126.2 151.7,126.27 151.56,126.27 150.99,126.84 148.27,126.84 147.38,125.95 147.29,125.85 147.29,125.42 147.15,125.29 v2(147.15,125.16) 146.97,124.99 146.24,124.99 R7621.2 145.9,125.25 C7609.1
  BOTTOM w0.102: GPU1.AL27 v1(163,126.32)
VGA_SVC: length 73.9
  TOP w0.254: R7919.1 178.61,137.98 178.98,137.98 179.24,138.24 v1(179.24,138.4)
  L2 w0.254: v3(154.01,119.28) 151.79,117.06 151.79,113.68 v1(150.33,112.22)
  L3 w0.254: v1(183.28,134.45) 183.28,134.92 179.71,138.49 179.36,138.49 179.22,138.36 179.22,138.4 v1(179.24,138.4)
  L4 w0.254: v1(183.28,134.45) 182.4,133.58 175.12,133.58 173.88,134.82 173.49,134.82 173.44,134.88 173.04,134.88 172.98,134.82 172.53,134.82 172.5,134.85 172.1,134.85 172.06,134.82 171.69,134.82 171.66,134.85 171.26,134.85 171.22,134.82 171.21,134.82 169.43,136.59 164.51,136.59 163.04,135.11 163.04,133.55 163.41,133.17 164.26,133.17 164.69,132.74 164.69,131.19 164.2,130.7 164.2,128.53 157.59,121.92 155.32,121.92 154.54,121.14 154.54,119.99 154.01,119.46 v3(154.01,119.28)
  BOTTOM w0.254: v3(154.01,119.28) 154.01,118.73 153.29,118.01 R7946.1 R7923.2 ; R7939.1 151.04,114.36 151.04,114.34 150.81,114.11 150.81,112.7 v1(150.33,112.22) 150.62,112.22 151.94,110.91 v2(152.55,110.91) 152.55,109.92 PR8509.1
VGA_SVD: length 78.3
  L3 w0.254: v1(191.12,119.48) 191.4,119.76 191.88,119.76 192.18,120.06 192.18,120.48 192.08,120.58 192.08,128.45 193.17,129.54 193.17,133.61 195.38,135.82 195.38,138.72 195.38,138.72 195.38,139.77 195.38,140.47 194.73,141.13 194.73,141.41 v1(194.9,141.58)
  L4 w0.254: v3(153.19,115.02) 153.35,115.02 156.02,117.68 156.02,117.69 156.5,118.16 156.5,118.18 157.15,118.83 166.54,118.83 167.04,119.32 167.13,119.32 167.15,119.35 172.67,119.35 173.18,119.86 173.81,119.86 175.94,121.98 176.72,121.98 178.5,123.76 178.78,124.03 178.78,124.41 180.57,126.21 184.87,126.21 185.55,125.53 185.55,125.4 186.04,124.92 186.04,123.37 189.92,119.48 v1(191.12,119.48)
  BOTTOM w0.254: R7920.1 194.71,141.39 v1(194.9,141.58) ; PR8512.1 154.56,109.43 154.25,109.74 154.25,109.78 153.76,110.27 v2(153.63,110.27) 153.27,110.63 R7925.1 R7940.2 R7944.1 153.27,114.92 153.19,115 v3(153.19,115.02)
VGA_SVT: length 13.9
  BOTTOM w0.254: R7945.1 159.01,119.11 R7924.2 158.13,119.1 R7934.1 157.26,119.09 156.57,119.09 155.11,117.62 154.34,117.62 153.34,116.63 153.34,115.86 153.83,115.38 153.83,111.73 v2(154.1,111.46) 154.13,111.42 154.13,110.72 PR8513.1
VGA_VDD_RUN_FB_H: length 30.8
  TOP w0.254: v1(167.71,131.88) 167.96,132.13 167.96,134.42 PR8535.1
  L3 w0.254: v1(167.71,131.88) 167.71,130.65 168.48,129.88 171.28,129.88 172.22,130.82 172.84,130.82 173.12,130.54 173.12,128.62 171.79,127.29 171.79,124.31 171.85,124.25 171.85,121.14 171.79,121.09 171.79,121.07 171.32,120.6 171.3,120.6 169.76,119.05 166.12,119.05 165.64,119.53 v1(165.64,119.58)
  BOTTOM w0.254: v1(165.64,119.58) 165.48,119.74 164.37,119.74 163.88,119.25 TP8502.1 163.65,119 PR8534.2
VGA_VDD_RUN_FB_L: length 29.6
  TOP w0.254: v1(175.32,134.18) 175.34,134.18 175.34,134.16 175.39,134.21 175.39,135.21 175.72,135.54 PR8531.1
  L3 w0.254: v1(173.67,120.58) 175.03,120.58 177.58,123.13 177.58,124.94 177.3,125.22 177.3,129.45 175.94,130.81 175.94,133.56 v1(175.32,134.18)
  L4 w0.254: v1(166.33,119.56) 166.55,119.56 166.83,119.83 166.92,119.83 166.94,119.86 172.24,119.86 172.96,120.58 v1(173.67,120.58)
  BOTTOM w0.254: PR8530.2 164.3,118.36 TP8501.1 165.29,119 166.05,119 166.33,119.28 v1(166.33,119.56)
VGA_VSUM-_1: length 17.6
  L3 w0.254: v1(171.28,121.58) 171.28,121.3 170.36,120.37 170.32,120.37 170.27,120.32 161.19,120.32 161.14,120.37 160.3,120.37 159.83,120.84 v1(159.83,120.96)
  BOTTOM w0.254: v1(171.28,121.58) 171.36,121.51 171.36,121.31 171.61,121.06 PR8533.1 ; v1(159.83,120.96) 159.97,120.82 v2(159.97,119.99) 159.97,118.32 PR8529.2
VR_CAP: length 2.4
  BOTTOM w0.203: KBC24.18 165.66,48.21
  BOTTOM w0.254: 165.66,48.21 165.63,48.24 v2(165.63,48.87) 165.63,49.58 C2418.1
VR_EN: length 107.5
  TOP w0.102: v1(126.91,146.37) 127.25,146.37 127.93,147.05 127.93,147.46 130.33,149.87 130.33,151.46 133.35,154.48 134.13,154.48 v1(135.4,153.2)
  L3 w0.102: v1(135.4,153.2) 135.4,151.18 140.75,145.84 140.75,138.15 144.03,134.87 144.03,126 144.03,126 144.03,124.48 144.03,124.48 144.03,120.56 144.47,120.12 144.47,119.44 144.65,119.26 144.65,107.77 146.78,105.64 150.36,105.64 156.79,99.21 156.79,99.2 157.2,98.8 157.2,98.04 157.05,97.9 157.05,96.73 159.62,94.17 159.62,91.47 159.94,91.14 159.94,80.78 159.82,80.66 159.82,78.62 v1(159.59,78.39)
  BOTTOM w0.102: v1(126.91,146.37) 126.91,146.18 v2(126.4,145.67) 126.14,145.41 124.26,145.41 123.56,144.72 PU4601.40 ; R4002.2 159.98,76.78 160.32,77.11 160.32,77.99 160.21,78.1 160.18,78.1 159.89,78.39 v1(159.59,78.39)
VR_RDY: length 7.5
  TOP w0.102: AFTP4601.1 125.51,145.77 v1(125.51,146.3) 125.51,146.45 125.9,146.84 126.96,146.84 PR4609.2
  BOTTOM w0.102: v1(125.51,146.3) 124.85,145.64 124.03,145.64 123.6,145.21 123.43,145.21 123.16,144.94 PU4601.39
VR_SVID_ALERT#: length 86.1
  TOP w0.114: PR4605.2 123.38,148.18 PR4623.1 123.43,148.11 v1(124.02,148.11)
  L3 w0.102: v1(90.61,106.35) 90.84,106.58 90.84,107.39 90.74,107.49 90.58,107.49 90.48,107.6 90.48,107.85 90.58,107.95 90.74,107.95 90.84,108.05 90.84,108.51 94.77,112.44 94.77,118.59 95.33,119.15 95.33,133.54 106.4,144.61 106.8,144.61 109.81,144.61 114.14,148.95 114.81,148.95 115.01,149.15 115.01,149.55 115.11,149.65 115.37,149.65 115.47,149.55 115.47,149.15 115.67,148.95 116.88,148.95 116.98,149.05 116.98,149.11 117.09,149.21 117.34,149.21 117.44,149.11 117.44,149.05 117.54,148.95 117.8,148.95 117.9,149.05 117.9,149.11 118,149.21 118.25,149.21 118.36,149.11 118.36,149.05 118.46,148.95 119.6,148.95 119.76,149.11 119.76,149.52 119.87,149.62 120.12,149.62 120.22,149.52 120.22,149.08 120.35,148.95 121.57,148.95 121.67,149.05 121.67,149.42 121.77,149.53 122.03,149.53 122.13,149.42 122.13,149.05 122.23,148.95 122.48,148.95 122.59,149.05 122.59,149.42 122.69,149.53 122.94,149.53 123.04,149.42 123.04,149.05 123.14,148.95 124,148.95 124.2,148.75 124.2,148.28 v1(124.02,148.11)
  BOTTOM w0.114: v1(124.02,148.11) 124.47,148.11 v2(124.62,148.26) ; v1(90.61,106.35) 91.98,106.35 93.76,104.57 99.17,104.57 99.69,104.04 100.82,104.04 101.54,103.32 R727.2 102.35,102.21 R728.2
VR_SVID_CLK: length 84.4
  TOP w0.114: v1(125.41,148.24) 125.35,148.18 PR4624.1 124.72,149.01 PR4606.2
  L3 w0.102: v1(90,106.94) 90,108.35 94.29,112.64 94.29,118.97 94.71,119.39 94.71,133.6 106.27,145.17 109.68,145.17 114.64,150.13 116.85,150.13 116.87,150.12 123.53,150.12 v1(125.41,148.24)
  BOTTOM w0.114: v1(90,106.94) 91.73,106.94 92.12,106.54 92.12,106.5 93.85,104.77 96.22,104.77 97.14,105.69 99.25,105.69 R723.2 99.56,105.35 100.15,104.76 101.42,104.76 v2(101.71,104.47) 102.17,104.47 103.22,103.42 R732.2
VR_SVID_DATA: length 83.5
  TOP w0.114: PR4604.2 121.98,148.16 PR4622.1 122.14,148.01 v1(122.69,148.01)
  L3 w0.102: v1(91.02,105.82) 91.02,106.1 91.62,106.71 91.62,108.61 95.25,112.24 95.25,118.39 95.81,118.95 95.81,133.34 106.6,144.13 107.04,144.13 107.14,144.03 107.14,143.28 107.25,143.17 107.53,143.17 107.63,143.28 107.63,143.99 107.77,144.13 110.01,144.13 110.35,144.47 110.49,144.47 110.93,144.04 111.07,144.04 111.27,144.24 111.27,144.38 110.83,144.81 110.83,144.96 111.16,145.29 111.4,145.29 111.69,144.99 111.83,144.99 112.03,145.19 112.03,145.33 111.78,145.59 111.78,145.9 114.01,148.13 115.23,148.13 115.57,148.47 117.11,148.47 117.21,148.36 117.21,148.11 117.31,148.01 117.59,148.01 117.69,148.11 117.69,148.36 117.79,148.47 118.07,148.47 118.17,148.36 118.17,148.11 118.27,148.01 118.55,148.01 118.66,148.11 118.66,148.36 118.76,148.47 119.04,148.47 119.14,148.36 119.14,148.11 119.24,148.01 119.52,148.01 119.62,148.11 119.62,148.36 119.72,148.47 120,148.47 120.1,148.36 120.1,148.11 120.2,148.01 120.48,148.01 120.59,148.11 120.59,148.36 120.69,148.47 120.97,148.47 121.07,148.36 121.07,148.11 121.17,148.01 121.45,148.01 121.55,148.11 121.55,148.26 121.75,148.47 122.49,148.47 122.69,148.26 v1(122.69,148.01)
  BOTTOM w0.114: v1(91.02,105.82) 91.37,105.46 92.51,105.46 93.61,104.36 98.85,104.36 99.54,103.68 100.11,103.68 R709.2 ; v1(122.69,148.01) 123.09,148.01 v2(123.26,148.18)
VRAM_ID1: length 24.5
  TOP w0.102: v1(136.68,78.44) 136.68,78.91 137.01,79.24 137.46,79.24 138.24,78.46 v2(138.35,78.46) 138.46,78.34 138.46,77.93 139.61,76.78 141.52,76.78 143.81,79.07 150,79.07 153.22,75.85 153.22,75.55 R2023.2 153.35,75.42 R2024.1
  BOTTOM w0.102: CPU1.AP8 135.65,79.73 136.32,79.73 136.68,79.37 v1(136.68,78.44)
VREF_CPU: length 6.6
  BOTTOM w0.203: 159.26,31.17 KBC24.95
  BOTTOM w0.254: R2402.2 155.16,29.02 C2406.1 157.22,31.08 v2(157.73,31.08) 159.17,31.08 159.26,31.17
VREFC_A0: length 4
  TOP w0.254: C8101.2 150.14,165.99 R8105.2 150.96,165.89 C8103.1 150.96,164.41 R8107.1 151.15,164.22 151.79,164.22 v1(151.82,164.19)
  BOTTOM w0.254: VRAM1.J14 151.83,164.17 151.83,164.19 v1(151.82,164.19)
VREFC_A1: length 7.1
  BOTTOM w0.127: C8102.2 188.9,166.95 R8106.2 189.54,166.86 189.11,166.43 189.11,166.07 R8108.1 189.45,165.07 C8104.1 189.29,165.23 188.33,165.23 187.1,164 VRAM2.J14
WCKA0_0: length 18.2
  L4 w0.165: v1(159.41,147.59) 159.81,147.98 159.81,148.21 159.81,148.21 159.81,148.43 159.77,148.46 159.77,155.83 158.22,157.39 158.22,157.8 157.88,158.14 157.39,158.14 157.23,158.3 157.23,158.65 157.39,158.81 157.88,158.81 158.22,159.15 158.22,159.59 158.36,159.74 158.57,159.74 v1(158.82,159.49)
  BOTTOM w0.102: v1(159.41,147.59) 159.51,147.59 159.57,147.53 160.46,146.64 GPU1.E32
  BOTTOM w0.203: VRAM1.P4 159.97,159.8 159.59,159.42 158.89,159.42 v1(158.82,159.49)
WCKA0_1: length 29.1
  BOTTOM w0.102: 164.77,152.56 164.78,152.54 164.87,152.54 165.47,151.94 165.47,151.6 167.93,149.14 167.93,148.33 GPU1.A21
  BOTTOM w0.203: VRAM1.D4 159.69,168.08 159.5,168.19 159.35,168.19 158.8,168.1 158.34,167.95 157.12,166.74 157.12,157.11 159.37,154.87 163.12,154.87 163.63,154.35 163.63,153.69 164.77,152.56
WCKA0B_0: length 18.2
  L4 w0.165: v1(158.82,160.2) 158.65,160.03 158.24,160.03 157.92,159.71 157.92,159.27 157.76,159.11 157.27,159.11 156.94,158.77 156.94,158.18 157.27,157.85 157.76,157.85 157.92,157.68 157.92,157.27 159.48,155.71 159.48,148.36 v1(159.37,148.25)
  BOTTOM w0.102: v1(159.37,148.25) 159.82,147.79 159.88,147.51 160.41,146.97 160.69,146.86 GPU1.E30
  BOTTOM w0.203: VRAM1.P5 159,160.2 v1(158.82,160.2)
WCKA0B_1: length 29
  BOTTOM w0.102: 165,152.79 165.02,152.77 165.02,152.68 165.67,152.02 165.67,151.68 168.13,149.23 168.13,147.96 168.04,147.77 167.86,147.77 167.74,147.65 167.74,147.36 GPU1.C21
  BOTTOM w0.203: VRAM1.D5 159.4,167.64 159.19,167.42 159.01,167.42 158.74,167.7 158.56,167.7 157.46,166.6 157.46,157.24 159.5,155.2 163.25,155.2 163.96,154.49 163.96,153.83 165,152.79
WCKA1_0: length 27.2
  BOTTOM w0.102: 176.65,151.21 176.65,151.18 176.72,151.12 176.72,150.78 175.36,149.43 175.36,148.47 175.27,148.25 175.27,147.95 175.33,147.76 175.33,147.65 175.23,147.35 175.17,147.29 174.77,147.2 GPU1.E13
  BOTTOM w0.203: 176.65,151.21 176.65,151.68 181.89,156.93 181.89,167.19 181.41,167.67 180.66,167.67 180.4,167.41 179.82,167.41 VRAM2.P4
WCKA1_1: length 19
  L4 w0.165: v1(180.45,159.67) 180.62,159.84 181.56,159.84 182.04,159.35 182.04,154.63 183.51,153.17 183.51,149.07 v1(183.31,148.87)
  BOTTOM w0.102: GPU1.E3 181.67,146.23 181.93,146.23 182.13,146.13 182.36,146.13 183.31,147.08 183.31,147.87 183.1,148.07 183.1,148.41 183.31,148.62 v1(183.31,148.87)
  BOTTOM w0.203: v1(180.45,159.67) 180.2,159.42 179.48,159.42 VRAM2.D4
WCKA1B_0: length 27
  BOTTOM w0.102: GPU1.D12 174.98,146.66 175.08,146.55 175.26,146.54 175.4,146.66 175.45,147.36 175.54,147.61 175.54,147.79 175.47,147.98 175.47,148.2 175.57,148.42 175.57,149.35 176.92,150.7 176.92,151.12 176.98,151.18 176.98,151.21
  BOTTOM w0.203: 176.98,151.21 176.98,151.55 182.22,156.79 182.22,167.32 181.55,168 180.52,168 180.26,167.74 179.96,167.74 VRAM2.P5
WCKA1B_1: length 19.3
  L4 w0.165: v1(183.51,148.25) 183.51,148.45 183.8,148.75 183.8,153.29 182.34,154.76 182.34,159.47 181.68,160.13 180.62,160.13 v1(180.45,160.3)
  BOTTOM w0.102: v1(183.51,148.25) 183.51,146.99 182.45,145.93 182.09,145.93 181.88,146.03 181.33,146.03 GPU1.F4
  BOTTOM w0.203: v1(180.45,160.3) 180.45,160.3 180.4,160.3 VRAM2.D5
WEA0B: length 29.3
  L3 w0.203: v1(155.98,162.31) 156.46,161.83 156.46,156.83 156.05,156.42 156.05,154.86 157.34,153.57 157.63,153.57 157.86,153.79 158.14,153.79 158.36,153.58 158.36,153.29 158.13,153.07 158.13,152.78 158.35,152.56 158.64,152.56 158.86,152.79 159.15,152.79 159.36,152.57 159.36,152.28 159.14,152.06 159.14,151.77 159.42,151.49 160.71,151.49 160.91,151.7 160.91,152.33 161.11,152.53 161.42,152.53 161.62,152.33 161.62,151.7 161.83,151.49 162.29,151.49 164.3,149.48 164.3,148.98 164.34,148.95 164.34,148.25 164.76,147.83 164.76,145.55 v1(165,145.31)
  BOTTOM w0.229: VRAM1.L12 154.19,162.59 155.56,162.59 155.84,162.31 v1(155.98,162.31) ; GPU1.G25 164.6,144.91 v1(165,145.31)
WEA1B: length 26.3
  L3 w0.203: v1(176.12,144.37) 176.16,144.37 176.87,145.08 176.87,145.59 179.21,147.93 179.21,148.58 178.26,149.53 178.26,149.92 178.38,150.05 179.44,150.05 179.65,150.25 179.65,150.55 179.44,150.76 178.37,150.76 178.24,150.88 178.24,152.11 181.76,155.63 183.19,155.63 184.25,156.69 184.25,160.95 v1(185.1,161.8)
  BOTTOM w0.229: VRAM2.G12 v1(185.1,161.8) ; v1(176.12,144.37) GPU1.H10
WHITE_LED_BAT: length 2
  BOTTOM w0.508: R6406.1 170.23,3.46 EC6404.1 170.23,4.27 Q6404.C
WIFI_RF_EN: length 116.2
  TOP w0.102: v1(139.03,100.25) 139.07,100.25 139.07,100.53 139.57,101.03 139.64,101.03 141.85,103.25 141.85,104.13 142.37,104.65 143.14,104.65 144.58,106.08 150.33,106.08 151.23,106.97 R1503.1 ; v1(99.28,152.72) 99.13,152.88 98.66,152.88 ; v2(98.66,152.86) 98.66,152.88 ; 98.66,152.88 98.57,152.79 98.11,152.79 97.57,152.25 R6114.1
  L3 w0.102: v1(99.28,152.72) 99.59,153.03 114.96,153.03 115,153 116.82,153 118.12,151.69 127.83,151.69 133.85,145.67 133.85,140.38 140.51,133.72 140.51,111.37 136.75,107.61 134.1,107.61 133.62,107.13 133.62,105.01 137.14,101.49 137.97,101.49 138.1,101.36 138.44,101.36 138.47,101.33 138.59,101.33 139.07,100.84 139.07,100.25 v1(139.03,100.25)
  BOTTOM w0.089: 136.6,97.68 136.57,97.55 CPU1.B7
  BOTTOM w0.102: v1(139.03,100.25) 139.11,100.17 139.11,99.54 138.87,99.29 138.22,99.29 136.6,97.68
WLAN_CLKREQ_WLAN#: length 9
  TOP w0.191: v1(83.07,156.85) 83.41,157.19 AFTP6105.1 84.39,157.75 R6112.1
  BOTTOM w0.191: v1(83.07,156.85) 83.17,156.75 83.17,155.12 84.74,153.55 WLAN1.53
WLAN_DISABLE#1: length 4.7
  TOP w0.102: AFTP6106.1 93.89,152.66 v1(95.84,152.66) 96.25,152.25 R6114.2
  BOTTOM w0.102: WLAN1.56 95.7,152.8 v1(95.84,152.66)
WLAN_WAKE: length 3.4
  TOP w0.102: v1(85.66,152.71) 86,153.05 TP6101.1
  BOTTOM w0.102: WLAN1.55 86,153.05 v1(85.66,152.71)
XCLK_BIASREF: length 6.8
  BOTTOM w0.127: R1803.1 116.62,100.89
  BOTTOM w0.152: 117.3,99.33 116.83,98.86 116.83,95.57 116.6,95.35 116.58,95.35 CPU1.E42
  BOTTOM w0.508: 116.62,100.89 116.62,100.44 v2(117.05,100) 117.3,99.75 117.3,99.33
XDP_BPM0: length 7.8
  BOTTOM w0.114: TP405.1 110.85,102.41 110.85,100.81 108.55,98.51 108.55,96.72 CPU1.C55
XDP_BPM1: length 6.9
  BOTTOM w0.114: CPU1.D55 108.59,96.11 108.59,96.34 108.77,96.52 108.77,96.8 108.76,96.81 108.76,98.43 111.48,101.15 TP406.1
XDP_BPM2: length 7.5
  BOTTOM w0.114: TP407.1 112.07,101.81 112.07,101.17 109.31,98.4 109.31,97.46 109.03,97.18 CPU1.B54
XDP_BPM3: length 5.4
  BOTTOM w0.114: CPU1.C56 107.91,96.42 107.63,96.7 107.63,98.74 109.06,100.16 TP408.1
XDP_DBRESET#: length 15.2
  BOTTOM w0.114: CPU1.B5 137.99,96.96 138.52,97.5 138.52,97.75 139.61,98.83 140.43,98.83 141.2,99.61 141.2,102.1 142.17,103.06 142.17,104.03 142.57,104.44 143.46,104.44 143.8,104.78 144.64,104.78 144.93,105.07 EC1706.1 145.71,105.07 R1701.2 145.83,104.95 146.99,104.95 147.1,105 v2(147.18,105.07)
XDP_PRDY#: length 6.3
  BOTTOM w0.089: 108.46,98.7 108.34,98.59 108.34,97.37 108.18,97.21 108.18,96.52 108.24,96.46 108.24,96.17 107.91,95.84 CPU1.D56
  BOTTOM w0.114: 108.46,98.7 110.28,100.53 TP1601.1
XDP_PREQ#: length 8
  BOTTOM w0.089: 104.92,98.73 105.14,98.5 105.14,98.05 104.99,97.9 104.99,97.45 105.02,97.38 105.03,97.36 105.04,97.35 105.04,96.05 CPU1.D61
  BOTTOM w0.114: 104.92,98.73 104.59,99.06 104.59,102.71 TP1602.1
XDP_TCK_JTAGX: length 9.4
  BOTTOM w0.089: 106.91,99.08 106.46,98.62 106.46,97.71 CPU1.A59
  BOTTOM w0.114: 106.91,99.08 106.96,99.12 107.07,99.12 107.89,99.95 107.89,102.31 v2(105.93,104.28) 105.4,104.8 R417.1
XDP_TCLK: length 4.1
  BOTTOM w0.089: CPU1.B61 105.22,97.17 105.22,97.39 105.17,97.49 105.17,97.78 105.34,97.95 105.34,98.59 105.25,98.68
  BOTTOM w0.114: R406.1 104.95,100.69 v2(104.95,99.65) 104.95,99.63 105.19,99.38 105.19,98.74 105.25,98.68
XDP_TDI: length 11.9
  BOTTOM w0.089: 106.18,99.72 106.18,99.06 106.1,98.98 106.1,97.04 106.28,96.86 106.28,96.51 106.25,96.49 106.25,96.49 106.1,96.33 106.1,96.33 105.99,96.23 CPU1.D60
  BOTTOM w0.114: R422.1 104.58,104.63 105.28,103.93 105.71,103.93 v2(106.95,102.7) 106.95,102.62 107.38,102.19 107.38,102.18 107.58,101.98 107.58,100.67 106.94,100.03 106.48,100.03 106.18,99.72
XDP_TDO_CPU: length 9.4
  BOTTOM w0.089: 105.46,98.79 105.55,98.7 105.55,97.73 CPU1.A61
  BOTTOM w0.114: R423.1 102.95,105.07 104.92,103.11 105.31,103.11 v2(105.62,102.79) 105.62,102.56 105.43,102.37 105.43,100.43 105.24,100.24 105.24,99.86 105.46,99.65 105.46,98.79
XDP_TMS: length 11.3
  BOTTOM w0.089: CPU1.C60 105.99,96.81 105.92,96.88 105.92,99.06 106,99.14 106,99.48 105.98,99.51 105.98,99.68
  BOTTOM w0.114: 105.98,99.68 105.98,99.81 106.4,100.23 106.86,100.23 107.29,100.66 107.29,101.83 105.45,103.67 105,103.67 v2(104.28,104.38) 103.77,104.89 R421.1
XDP_TRST#: length 10
  L4 w0.114: v1(105.64,100.03) 105.65,100.03 105.65,100.02 106.24,99.44 v1(106.63,99.44)
  BOTTOM w0.089: v1(106.63,99.44) 106.63,99.17 106.28,98.82 106.28,97.24 CPU1.B59 ; 105.65,100.03 105.65,99.31 105.74,99.21 105.74,96.92 105.66,96.8 105.66,96.55 CPU1.C61
  BOTTOM w0.114: v1(105.64,100.03) 105.65,100.03 105.89,100.27 R402.1 105.92,100.7 EC401.1 ; v2(107.13,99.7) v1(106.63,99.44)
XO_IN: length 6.6
  TOP w0.102: RN7904.2 163.76,136.15 163.96,135.95 v2(163.96,135.84) 163.96,135.21 164.4,134.77 164.86,134.77 165.74,133.89 165.74,133.18 166.47,132.45 v1(166.64,132.45)
  BOTTOM w0.102: v1(166.64,132.45) 166.99,132.1 GPU1.AC22
XO_IN2: length 8.5
  TOP w0.102: RN7904.1 162.42,135.43 163.41,134.44 v2(163.96,134.44) 164.89,134.44 165.45,133.89 165.45,133.07 166.47,132.04 166.94,132.04 v1(167.48,132.58)
  BOTTOM w0.102: v1(167.48,132.58) 167.32,132.58 GPU1.AB22
XTAL24_IN: length 9.9
  BOTTOM w0.114: CPU1.E37 119.31,94.89 120,95.58 120,95.79 120.23,96.02 120.42,96.02 120.59,96.19 120.59,96.48 120.56,96.52 120.56,96.76 120.65,96.85 120.65,99 v2(121.17,99.52) 121.17,100.51 120.25,101.42 R1810.1 121.46,101.88 R1802.1
XTAL24_IN_R: length 4.5
  BOTTOM w0.114: X1801.1 119.52,106.56 120.19,105.89 120.19,105.73 120.26,105.66 C1801.1 120.26,102.76 R1810.2
XTAL24_IN_U42: length 9.2
  TOP w0.114: v1(139.93,98.39) 139.65,98.39 139.44,98.6 139.44,98.92 140.07,99.56 140.07,100.24 v1(139.75,100.56)
  BOTTOM w0.102: v1(139.93,98.39) 139.51,98.39 139.22,98.1 139.22,97.83 139.32,97.74 139.32,97.57 139,97.25 139,96.85 138.71,96.56 138.71,96.28 138.78,96.2 139.09,96.2 139.2,96.09 139.2,95.81 138.73,95.34 CPU1.E3
  BOTTOM w0.114: R2201.1 139.42,101.94 v2(139.42,101.07) 139.42,100.89 v1(139.75,100.56)
XTAL24_IN_U42_R: length 4.4
  BOTTOM w0.114: R2203.1 R2201.2 138.59,102.9 138.79,103.1 139.53,103.1 X2201.1 140,103.44 C2201.1
XTAL24_OUT: length 13.3
  BOTTOM w0.114: X1801.3 121.46,105.03 C1802.1 121.46,102.75 R1802.2 122,102.2 122,101.61 121.47,101.08 v2(121.47,100.76) 121.47,99.76 121.56,99.67 121.66,99.67 121.83,99.51 121.83,99.25 121.67,99.09 121.05,99.09 120.89,98.93 120.89,98.65 121.04,98.5 121.27,98.5 121.43,98.34 121.43,98.06 121.31,97.94 121.07,97.94 120.85,97.72 120.85,97.11 121.16,96.8 121.16,96.47 121.12,96.44 121.12,96.19 121.16,96.16 121.16,95.86 120.83,95.54 120.59,95.54 119.95,94.89 CPU1.E35
XTAL24_OUT_R_U42: length 4.6
  BOTTOM w0.114: X2201.3 137.24,104.82 136.76,104.82 136.47,104.53 136.47,103.74 136.27,103.53 C2202.1 135.88,103.4 135.88,102.93 R2202.2 136.24,102.77 136.44,102.57 136.44,102.41 R2203.2
XTAL24_OUT_U42: length 9.5
  BOTTOM w0.114: CPU1.C7 136.29,96.5 135.92,96.87 135.92,97.66 136.02,97.76 136.02,97.77 136.18,97.93 136.19,97.93 138.63,100.37 138.63,100.42 138.93,100.72 138.93,101.27 138.65,101.55 138.55,101.55 138.53,101.56 136.39,101.56 R2202.1
XTAL_KBC_2: length 4.5
  BOTTOM w0.114: X2401.2 151.4,40.51 151.4,42 v2(151.59,42.2) 152.1,42.7 153.09,42.7 C2424.1 153.1,43.43 R2458.2
XTL_27M_X1_VGA: length 11.7
  BOTTOM w0.114: GPU1.AM28 162.2,125.54 161.2,124.54 160.14,124.54 160.13,124.53 158.35,124.53 157.1,123.27 v2(156.31,123.27) 156.16,123.27 155.61,122.73 R7901.1 154.32,122.73 C7901.1 152.94,122.69 X7901.1
XTL_27M_X2_VGA: length 16.8
  BOTTOM w0.114: X7901.3 151.72,120.5 152.19,120.03 153.11,120.03 153.58,120.5 153.58,121.45 153.96,121.84 154.29,121.84 C7903.1 154.39,121.89 155.15,121.89 R7901.2 155.37,121.86 155.68,122.17 155.85,122.17 156.3,122.62 157.22,122.62 v2(158.1,123.5) 158.91,124.31 160.22,124.31 160.23,124.32 161.29,124.32 162.56,125.6 162.56,126.67 162.2,127.04 GPU1.AK28
ZQ_A0: length 4
  TOP w0.127: R8110.2 152.21,165.83 v2(152.13,165.75) 152.13,164.88 152.81,164.2 v1(153.4,164.2)
  BOTTOM w0.254: VRAM1.J13 v1(153.4,164.2)
ZQ_A1: length 3
  BOTTOM w0.102: VRAM2.J13 186.63,163.47 187.32,163.47 187.82,163.97 187.82,164.23 188.14,164.54 R8109.2
ZVM#: length 1.2
  TOP w0.102: TP616.1 v1(108.37,79.05)
  BOTTOM w0.102: CPU1.AR56 108.02,79.4 v1(108.37,79.05)

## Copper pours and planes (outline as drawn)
5V_CRT_S0_R on TOP: 16.11,82.37 16.02,82.46 14.85,82.46 14.67,82.65 14.24,82.65 13.37,83.52 13.37,84.92 14.14,85.7 15.56,85.7 17.69,85.7 18.17,85.22 18.17,82.73 17.81,82.37 ; 2 cut-outs
5V_HDD_S0 on BOTTOM: 189.11,43.41 188.65,43.87 186.82,43.87 186.62,44.07 186.62,46.38 186.8,46.56 187.38,46.56 188.15,47.32 190.08,47.32 190.08,45.16 190.53,44.71 191.6,44.71 191.65,44.66 191.65,44.4 190.79,44.4 190.74,44.35 190.74,44.25 190.79,44.2 191.65,44.2 191.65,43.89 190.76,43.89 190.74,43.87 190.74,43.74 190.76,43.72 191.65,43.72 191.65,43.41 ; 4 cut-outs
5V_HDMI_S0 on TOP: 13.55,56.21 12.81,56.95 12.81,59.49 12.95,59.63 12.96,59.63 13.27,59.95 17.08,59.95 17.25,59.77 17.25,59.18 16.82,58.75 16.82,58.27 16.57,58.02 16.31,58.02 14.51,56.21 ; 2 cut-outs
5V_HDMI_S0 on TOP: 15.25,80.39 14.94,80.7 14.94,81.18 15.2,81.43 15.63,81.43 15.91,81.71 17.2,81.71 17.67,81.24 17.67,80.56 17.51,80.39
5V_HDMI_S0 on L4: 13.04,59.36 13.04,57.99 13.52,57.51 14.74,57.51 15.58,58.35 15.58,62.84 12.61,65.81 12.61,67.77 15.12,70.28 15.12,77.14 16.21,78.23 16.21,81.13 16.03,81.31 15.76,81.31 13.7,79.25 13.7,71.25 11.31,68.86 11.31,64.62 13.67,62.26 13.67,60
5V_PWR on BOTTOM: 50.16,47.25 49.82,47.58 49.82,49 51.59,50.78 51.59,52.35 50.35,53.6 50.35,58.29 50.36,58.3 50.36,58.77 50.58,58.98 55.67,58.98 56.37,58.28 56.37,47.4 56.22,47.25 ; 2 cut-outs
5V_S0 on TOP: 191.89,47.85 191.65,48.1 191.65,49.65 191.81,49.82 193.22,49.82 193.32,49.73 193.32,48.04 193.13,47.85 ; 1 cut-out
5V_S0 on TOP: 93.3,138.82 93.25,138.87 93.25,140.79 92.49,141.55 88.45,141.55 88.28,141.72 88.28,143.1 88.46,143.27 93.15,143.27 94.05,142.38 94.05,138.89 93.98,138.82 ; 4 cut-outs
5V_S0 on TOP: 46.16,35.29 45.89,35.56 45.89,41.04 45.95,41.11 46.61,41.11 46.75,41.24 46.75,41.96 47.07,42.28 50.5,42.28 50.66,42.12 50.66,36.23 49.71,35.29 ; 2 cut-outs
5V_S0 on TOP: 21.8,78.13 21.29,78.64 20.76,78.64 20.56,78.84 20.56,80.24 20.1,80.7 18.78,80.7 18.57,80.9 18.57,81.82 18.9,82.15 21.14,82.15 22.23,81.05 22.23,79.05 22.56,78.72 22.56,78.13 ; 3 cut-outs
5V_S0 on TOP: 28.46,39.36 28.32,39.5 28.32,49.62 27.54,50.4 27.54,51.46 27.74,51.66 30.22,51.66 30.55,51.33 30.55,39.62 30.28,39.36 ; 2 cut-outs
5V_S0 on TOP: 34.62,14.86 34.5,14.97 34.5,15.81 34.59,15.9 49.28,15.9 49.46,15.72 49.46,15.11 49.21,14.86
5V_S0 on TOP: 111.96,182.91 111.61,183.27 111.61,184.01 111.82,184.22 114.65,184.22 114.79,184.08 114.79,183 114.7,182.91 ; 1 cut-out
5V_S0 on TOP: 18.01,59.95 17.71,60.25 13.93,60.25 13.77,60.4 13.77,61.44 13.99,61.66 18.74,61.66 18.75,61.66 18.98,61.66 19.21,61.43 19.21,60.14 19.02,59.95 ; 2 cut-outs
5V_S0 on TOP: 152.29,6.16 151.39,7.06 60.31,7.06 59.77,7.6 59.77,12.3 60,12.52 152.17,12.52 153.28,11.41 159.78,11.41 160.09,11.72 160.09,12.57 160.3,12.79 161.57,12.79 162.92,11.43 162.92,9.53 162.23,8.83 162.23,6.59 161.8,6.16 ; 4 cut-outs
5V_S0 on BOTTOM: 186.44,88.97 185.44,89.98 182.73,89.98 180.68,92.03 180.68,93.19 180.78,93.3 181.8,93.3 182.37,92.72 182.37,92.04 182.63,91.77 185.96,91.77 187.99,89.74 187.99,89.13 187.83,88.97 ; 1 cut-out
5V_S0 on BOTTOM: 94.79,172.09 94.7,172.18 94.7,173.19 93.86,174.03 91.17,174.03 89.42,175.77 89.42,180.85 89.72,181.15 90.51,181.15 90.74,180.92 90.74,176.29 91.67,175.36 94.37,175.36 96.43,173.3 96.43,172.27 96.25,172.09 ; 1 cut-out
5V_S0 on BOTTOM: 186.54,46.74 186.47,46.81 186.47,49.51 186.75,49.79 192.26,49.79 192.38,49.67 192.38,47.75 192.28,47.65 188.12,47.65 187.21,46.74 ; 3 cut-outs
5V_S0 on BOTTOM: 28.32,50.07 28.18,50.22 28.18,55.55 24.57,59.15 18.73,59.15 18.23,59.65 18.23,61.47 18.42,61.66 26.3,61.66 28.44,59.53 28.44,59.1 31.06,56.47 31.06,50.39 30.74,50.07 ; 6 cut-outs
5V_S0 on BOTTOM: 159.87,9.98 159.52,10.34 159.52,12.37 159.87,12.73 159.87,15.57 160.03,15.72 163.46,15.72 163.58,15.6 163.58,11.94 161.63,9.98
5V_S0 on BOTTOM: 178.39,11.08 178.28,11.19 178.28,11.91 178.62,12.25 178.62,13.31 178.68,13.36 179.74,13.36 179.97,13.13 179.97,11.46 179.59,11.08 ; 1 cut-out
5V_S0 on L2: 26.95,13.82 26.95,17.67 28.91,19.63 32.45,19.63 36.44,15.64 51.95,15.64 52.73,14.86 53.55,14.86 53.6,14.91 54.71,14.91 55.76,13.86 62.21,13.86 63.75,12.32 63.75,7.06 63.71,7.06 63.63,7.14 54.74,7.14 48.62,13.26 27.51,13.26
5V_S0 on L2: 190.8,15.8 190.8,21.74 190.08,22.45 190.08,60.21 187.82,62.47 187.82,81.69 185.83,83.69 185.83,90.76 186.35,91.29 189.36,91.29 192.35,88.3 192.35,66.7 195.93,63.12 195.93,62.96 196.2,62.69 196.2,8.72 190.7,3.22 159.07,3.22 158.3,3.99 158.3,6.12 157.21,7.22 157.21,10.49 159.67,12.96 163.42,12.96 164.11,12.26 164.24,12.14 165.13,11.25 177.6,11.25 177.61,11.25 177.96,11.25 179.47,12.77 183.38,12.77 184.8,14.19 184.8,15.25 185.04,15.5 185.36,15.5 185.65,15.2 187.8,15.2 187.83,15.23 187.83,15.25 188.14,15.56 190.56,15.56
5V_S0 on L3: 31.42,28.57 31.42,22.08 36.58,16.92 48.15,16.92 49.07,17.84 52.93,17.84 56.79,13.98 62.72,13.98 63.05,13.65 63.05,10.28 62.63,9.86 54.53,9.86 49.68,14.71 27.41,14.71 23.17,18.95 23.17,20.12 22.06,21.23 22.06,25.76 20.99,26.83 20.99,39.91 23.93,42.85 37.59,42.85 38.44,43.71 48.78,43.71 50.4,42.08 50.4,33.78 49.53,32.91 35.76,32.91
5V_S0 on L3: 88.31,143.48 88.31,141.34 88.63,141.01 94.05,141.01 96.29,143.26 96.29,146.23 95.71,146.82 93.41,146.82 93.22,146.62 93.22,145.13 92.08,143.99 88.81,143.99
5V_S0 on L3: 159.23,11.68 160.03,12.48 161.28,12.48 163.17,10.59 163.19,10.59 163.5,10.28 175.98,10.28 177.75,12.05 179.55,12.05 179.92,11.68 179.92,9.81 178.51,8.4 160.66,8.4 159.23,9.83
5V_S0 on L3: 15.54,85.5 20.57,85.5 20.69,85.37 20.69,83.47 20.35,83.14 15.48,83.14 15.25,83.36 15.25,85.21
5V_S0 on L3: 186.12,84.95 186.12,91.05 186.44,91.36 192.42,91.36 193.1,90.68 193.1,71.12 191.52,69.55 191.52,67.01 192.31,66.22 192.31,63.1 192.59,62.82 192.59,60.56 192.31,60.27 190.52,60.27 190.5,60.29 189.06,60.29 188.24,61.11 188.24,70.07 189.57,71.4 189.57,81.5
5V_S0 on L3: 89.27,181.01 90.9,181.01 91.22,180.69 91.22,175.29 91,175.07 88.99,175.07 88.56,175.49 88.56,180.31
5V_S0 on L4: 17.27,60 16.8,60.47 16.8,66.86 16.77,66.9 16.77,68.54 15.45,69.85 15.45,75.29 16.57,76.41 16.57,82.03 15.26,83.34 15.26,84.81 15.26,84.81 15.26,84.88 15.78,85.4 18.14,85.4 20.15,83.39 20.15,76.25 19.31,75.41 19.31,60.19 19.12,60
5V_S0 on L4: 89.34,179.47 89.68,179.12 100.67,179.12 102.44,180.9 111.36,180.9 113.4,182.93 113.4,184.25 113.07,184.57 101.34,184.57 99.21,182.44 90.24,182.44 89.34,181.54
5V_S5 on TOP: 24.45,41.55 24.28,41.73 24.28,47.06 24.49,47.27 27.59,47.27 28.05,46.81 28.05,43.99 27.73,43.68 26.54,43.68 26.4,43.54 26.4,41.81 26.14,41.55 ; 4 cut-outs
5V_S5 on TOP: 45.94,42.45 45.88,42.52 45.88,45.62 46.42,46.16 47.42,46.16 51.35,50.09 54.12,50.09 57.53,53.5 62.65,53.5 63.74,52.41 63.74,49.18 57.01,42.45 ; 2 cut-outs
5V_S5 on TOP: 137.71,41.09 137.22,41.59 137.22,42.31 136.91,42.62 134.88,42.62 134.78,42.72 134.78,43.31 135.87,44.4 138.01,44.4 138.53,43.88 139.38,43.88 139.8,43.46 139.8,41.63 139.26,41.09 ; 1 cut-out
5V_S5 on TOP: 180.15,25.29 179.55,25.9 179.55,26.63 179.84,26.93 182.05,26.93 182.29,26.68 182.29,25.85 181.74,25.29 ; 2 cut-outs
5V_S5 on BOTTOM: 134.32,16.22 133.96,16.58 133.96,18.67 134.58,19.28 135.57,19.28 135.77,19.48 135.77,21.02 135.85,21.1 136.55,21.1 136.61,21.03 136.61,19.74 137.23,19.12 137.23,16.31 137.14,16.22 ; 4 cut-outs
5V_S5 on BOTTOM: 137.39,41.08 136.46,42.01 135.27,42.01 135.03,41.78 130.06,41.78 125.03,46.8 71.98,46.8 67.32,51.46 63.86,51.46 63.3,50.9 63.3,48.48 62.01,47.19 62.01,46.23 59.27,43.49 46.33,43.49 44.71,45.1 44.71,45.59 44.74,45.62 44.74,46.33 45.17,46.76 47.66,46.76 47.81,46.91 56.27,46.91 56.67,47.32 56.67,53.44 56.88,53.65 57.23,53.65 58.58,54.99 58.58,57.18 60.36,58.96 70.39,58.96 75.43,53.91 123.49,53.91 131.33,46.08 136.27,46.08 136.27,46.07 136.91,46.07 138.18,44.8 138.18,43.5 138.62,43.07 139.32,43.07 139.35,43.09 139.5,43.09 139.81,42.78 139.81,41.55 139.33,41.08
5V_S5 on BOTTOM: 180.85,25.04 180.49,25.41 180.49,26.92 180.73,27.17 181.77,27.17 182.21,26.73 182.21,25.28 181.98,25.04
5V_S5 on L2: 51.26,46.53 54.31,46.53 54.59,46.26 54.59,43.49 54.49,43.39 53.09,43.39 52.38,44.1 51.75,44.1 50.99,44.86 50.99,46.26
5V_S5 on L3: 180.13,23.65 179.42,24.36 179.42,29.91 180.14,30.63 185,30.63 186.71,28.92 192.88,28.92 193.71,28.09 193.71,24.23 193.49,24.01 187.78,24.01 187.43,23.65
5V_S5 on L3: 40.32,51.95 53.27,51.95 54.71,53.38 59.24,53.38 60.02,52.6 60.02,47.31 57.23,44.52 50.21,44.52 46.93,47.79 45.97,47.79 45.4,47.22 45.4,45.27 45.19,45.06 44.66,45.06 44.56,45.16 44.56,45.24 44.38,45.42 39.3,45.42 37.39,43.5 27.35,43.5 26.42,44.43 26.42,46.33 26.78,46.69 26.78,48.08 27.54,48.85 28.53,48.85 28.71,49.03 32.88,49.03 35.77,51.92 40.29,51.92
5V_S5 on L4: 139.1,44.05 139.1,25.15 137.25,23.3 137.25,19.51 136.95,19.22 136.95,18.17 136.35,17.58 136.35,16.42 137.14,15.63 156,15.63 159.69,11.95 160.35,11.29 160.35,10.72 164.98,6.09 170.43,6.09 170.44,6.1 171.39,6.1 173.32,8.03 183.55,8.03 187.08,11.55 189.95,11.55 192.99,14.59 192.99,27.64 193.16,27.81 196.48,27.81 196.79,27.5 196.79,7.13 190.88,1.23 157.13,1.23 154.29,4.07 154.29,7.09 151.63,9.75 133.78,9.75 131.08,12.45 131.05,12.48 131.05,19.63 132.68,21.27 132.68,27.01 135.64,29.97 135.64,42.72 137.37,44.45 138.69,44.45
+3V_1D8V_DVDD on TOP: 169.74,21.7 169.37,22.06 169.37,22.07 169.08,22.36 166.6,22.36 165.18,23.78 165.18,24.51 165.29,24.61 167.39,24.61 167.8,24.21 169.57,24.21 170.16,23.62 170.93,23.62 171.52,24.21 176.88,24.21 177.64,23.45 177.64,23.2 177.48,23.04 175.91,23.04 175.24,22.36 174.41,22.36 173.75,21.7 ; 7 cut-outs
+3V_1D8V_DVDD on BOTTOM: 169.43,20.78 167.3,22.9 166.68,22.9 166.68,22.9 166.12,22.9 165.01,24.01 165.01,24.61 165.23,24.83 167.43,24.83 167.59,24.67 167.59,23.6 168.46,22.74 169.4,22.74 170.64,21.49 170.64,20.8 170.62,20.78 ; 3 cut-outs
+3V_1D8V_DVDD on BOTTOM: 173.26,20.8 173.21,20.86 173.21,23.29 173.62,23.7 173.62,24.36 173.67,24.41 174.87,24.41 175.13,24.14 175.13,23.24 174.2,22.3 173.95,22.3 173.49,21.85 173.49,20.86 173.44,20.8 ; 2 cut-outs
+5V_AVDD on BOTTOM: 176.92,12.02 176.82,12.11 176.82,14.35 174.45,16.72 174.45,16.99 174.53,17.07 175.01,17.07 176.61,15.47 178.11,15.47 178.22,15.35 178.22,12.32 177.92,12.02 ; 4 cut-outs
+5V_PVDD on BOTTOM: 159.96,16.23 159.59,16.6 159.59,21.89 160.01,22.31 161.58,22.31 162.07,21.82 162.07,18.16 162.89,17.34 163.34,17.34 163.44,17.24 163.44,16.43 163.25,16.23
+5V_PVDD1 on TOP: 168.56,16.82 167.85,17.53 167.85,17.55 167.62,17.78 167.62,18.26 168.64,19.28 168.64,20.37 168.33,20.68 167.62,20.68 167.27,21.03 167.27,21.95 167.49,22.18 168.76,22.18 169.98,20.96 169.98,16.94 169.86,16.82 ; 4 cut-outs
+5V_PVDD1 on BOTTOM: 163.31,17.5 162.55,18.26 162.55,22.18 162.8,22.43 167.29,22.43 169.49,20.24 170.22,20.24 170.24,20.22 170.24,20.07 170.19,20.02 168.71,20.02 168.14,20.59 167.56,20.59 166.68,21.47 164.88,21.47 164.85,21.44 164.85,19.94 165.02,19.94 166.24,18.71 167.48,18.71 167.95,18.24 169.76,18.24 169.8,18.2 169.8,18.05 169.77,18.03 168.8,18.03 168.61,17.84 167.33,17.84 166.99,17.5 ; 3 cut-outs
+V1.00A_SIP on TOP: 127.73,82.28 127.62,82.39 127.62,83.02 127.39,83.25 127.19,83.25 127.19,83.24 126.8,83.24 125.82,84.21 125.82,87.16 126.21,87.55 126.21,88.45 126.36,88.6 126.36,89.3 126.37,89.31 126.37,90.02 126.98,90.63 127.36,90.63 127.75,90.24 127.75,89.25 127.08,88.59 127.08,88.19 128.37,86.9 128.37,86.56 128.3,86.49 127.94,86.49 127.86,86.56 127.86,86.95 127.67,87.14 127.3,87.14 127.07,86.91 127.07,86.58 126.86,86.37 126.86,85.92 126.54,85.59 126.54,85.27 127.06,84.74 127.06,84.04 127.36,83.73 128.01,83.73 128.08,83.67 128.08,83.18 128.38,82.88 128.38,82.44 128.23,82.28 ; 1 cut-out
+V1.00A_SIP on TOP: 154.13,92.97 153.92,92.75 151.56,92.75 149.73,90.92 144.55,90.92 143.22,89.59 142.34,89.59 141.54,88.78 139.98,88.78 139.7,89.06 139.7,91.54 139.75,91.59 141.06,91.59 141.2,91.72 141.2,92.06 141.01,92.26 140.47,92.26 140.45,92.24 139.78,92.24 139.72,92.3 139.72,92.82 139.79,92.88 141.93,92.88 142.32,92.49 147.31,92.49 147.7,92.88 149.47,92.88 150.53,93.93 150.54,93.93 151.31,94.71 153.08,94.71 153.5,95.13 153.5,96.8 154.01,97.31 155.63,97.31 155.76,97.18 155.76,96.32 154.97,95.53 154.97,93.8 154.14,92.97 ; 4 cut-outs
+V1.00A_SIP on BOTTOM: 164.48,89.81 164.38,89.91 164.38,90.89 164.23,91.04 161.92,91.04 158.09,94.87 154.86,94.87 153.68,96.06 153.68,96.06 153.47,96.27 153.47,97.28 153.7,97.51 157.93,97.51 162.97,92.47 165.11,92.47 166.48,91.1 166.48,90.12 165.39,90.12 165.08,89.81 ; 2 cut-outs
+V1.00A_SIP on BOTTOM: 130.35,86.09 130.18,86.26 130.18,86.34 129.85,86.67 129.52,86.67 129.37,86.51 129.37,86.17 129.34,86.14 128.01,86.14 127.83,86.31 127.83,86.87 127.97,87.01 128.25,87.01 128.38,86.88 129.16,86.88 129.66,87.38 129.88,87.38 130.02,87.24 130.02,87.09 130.64,86.47 130.64,86.21 130.52,86.09
+V1.00A_SIP on L2: 152.91,94.71 150.25,92.05 148.76,92.05 146.5,89.79 139.58,89.79 138.23,88.44 129.83,88.44 129.16,89.1 127.81,89.1 127.44,88.73 127.44,88 128.47,86.97 128.47,86.44 128.15,86.12 125.94,86.12 125.78,86.29 125.78,89 126.89,90.12 126.89,90.45 127.09,90.64 129.85,90.64 131.45,92.23 137.16,92.23 138.53,93.6 138.53,98.25 138.85,98.57 141.05,98.57 144.51,95.11 149.31,95.11 151.72,97.53 155.69,97.53 156.01,97.2 156.01,95.82 154.91,94.71
+V1.00A_SIP on L3: 129.86,99.92 130.26,99.52 131.86,99.52 132.14,99.24 132.14,98.99 134,97.12 140.78,97.12 140.95,97.3 140.95,98.33 140.88,98.4 140.62,98.4 140.61,98.4 140.21,98.79 138.4,98.79 134.62,102.57 131.28,102.57 129.86,101.15
+V1.00U_CPU on TOP: 159.45,89.95 159.34,90.06 159.34,91.44 158.91,91.88 158.91,93.5 159.43,94.03 161.41,94.03 162.08,93.35 162.08,89.95 162.08,89.95 ; 1 cut-out
+V1.00U_CPU_LS on TOP: 164.06,89.7 163.81,89.95 162.77,89.95 162.57,90.15 162.57,91.99 162.91,92.33 163.21,92.33 163.47,92.07 163.47,91.61 163.63,91.44 164.19,91.44 164.24,91.49 164.27,91.47 165.4,91.47 165.46,91.42 165.46,89.77 165.38,89.7
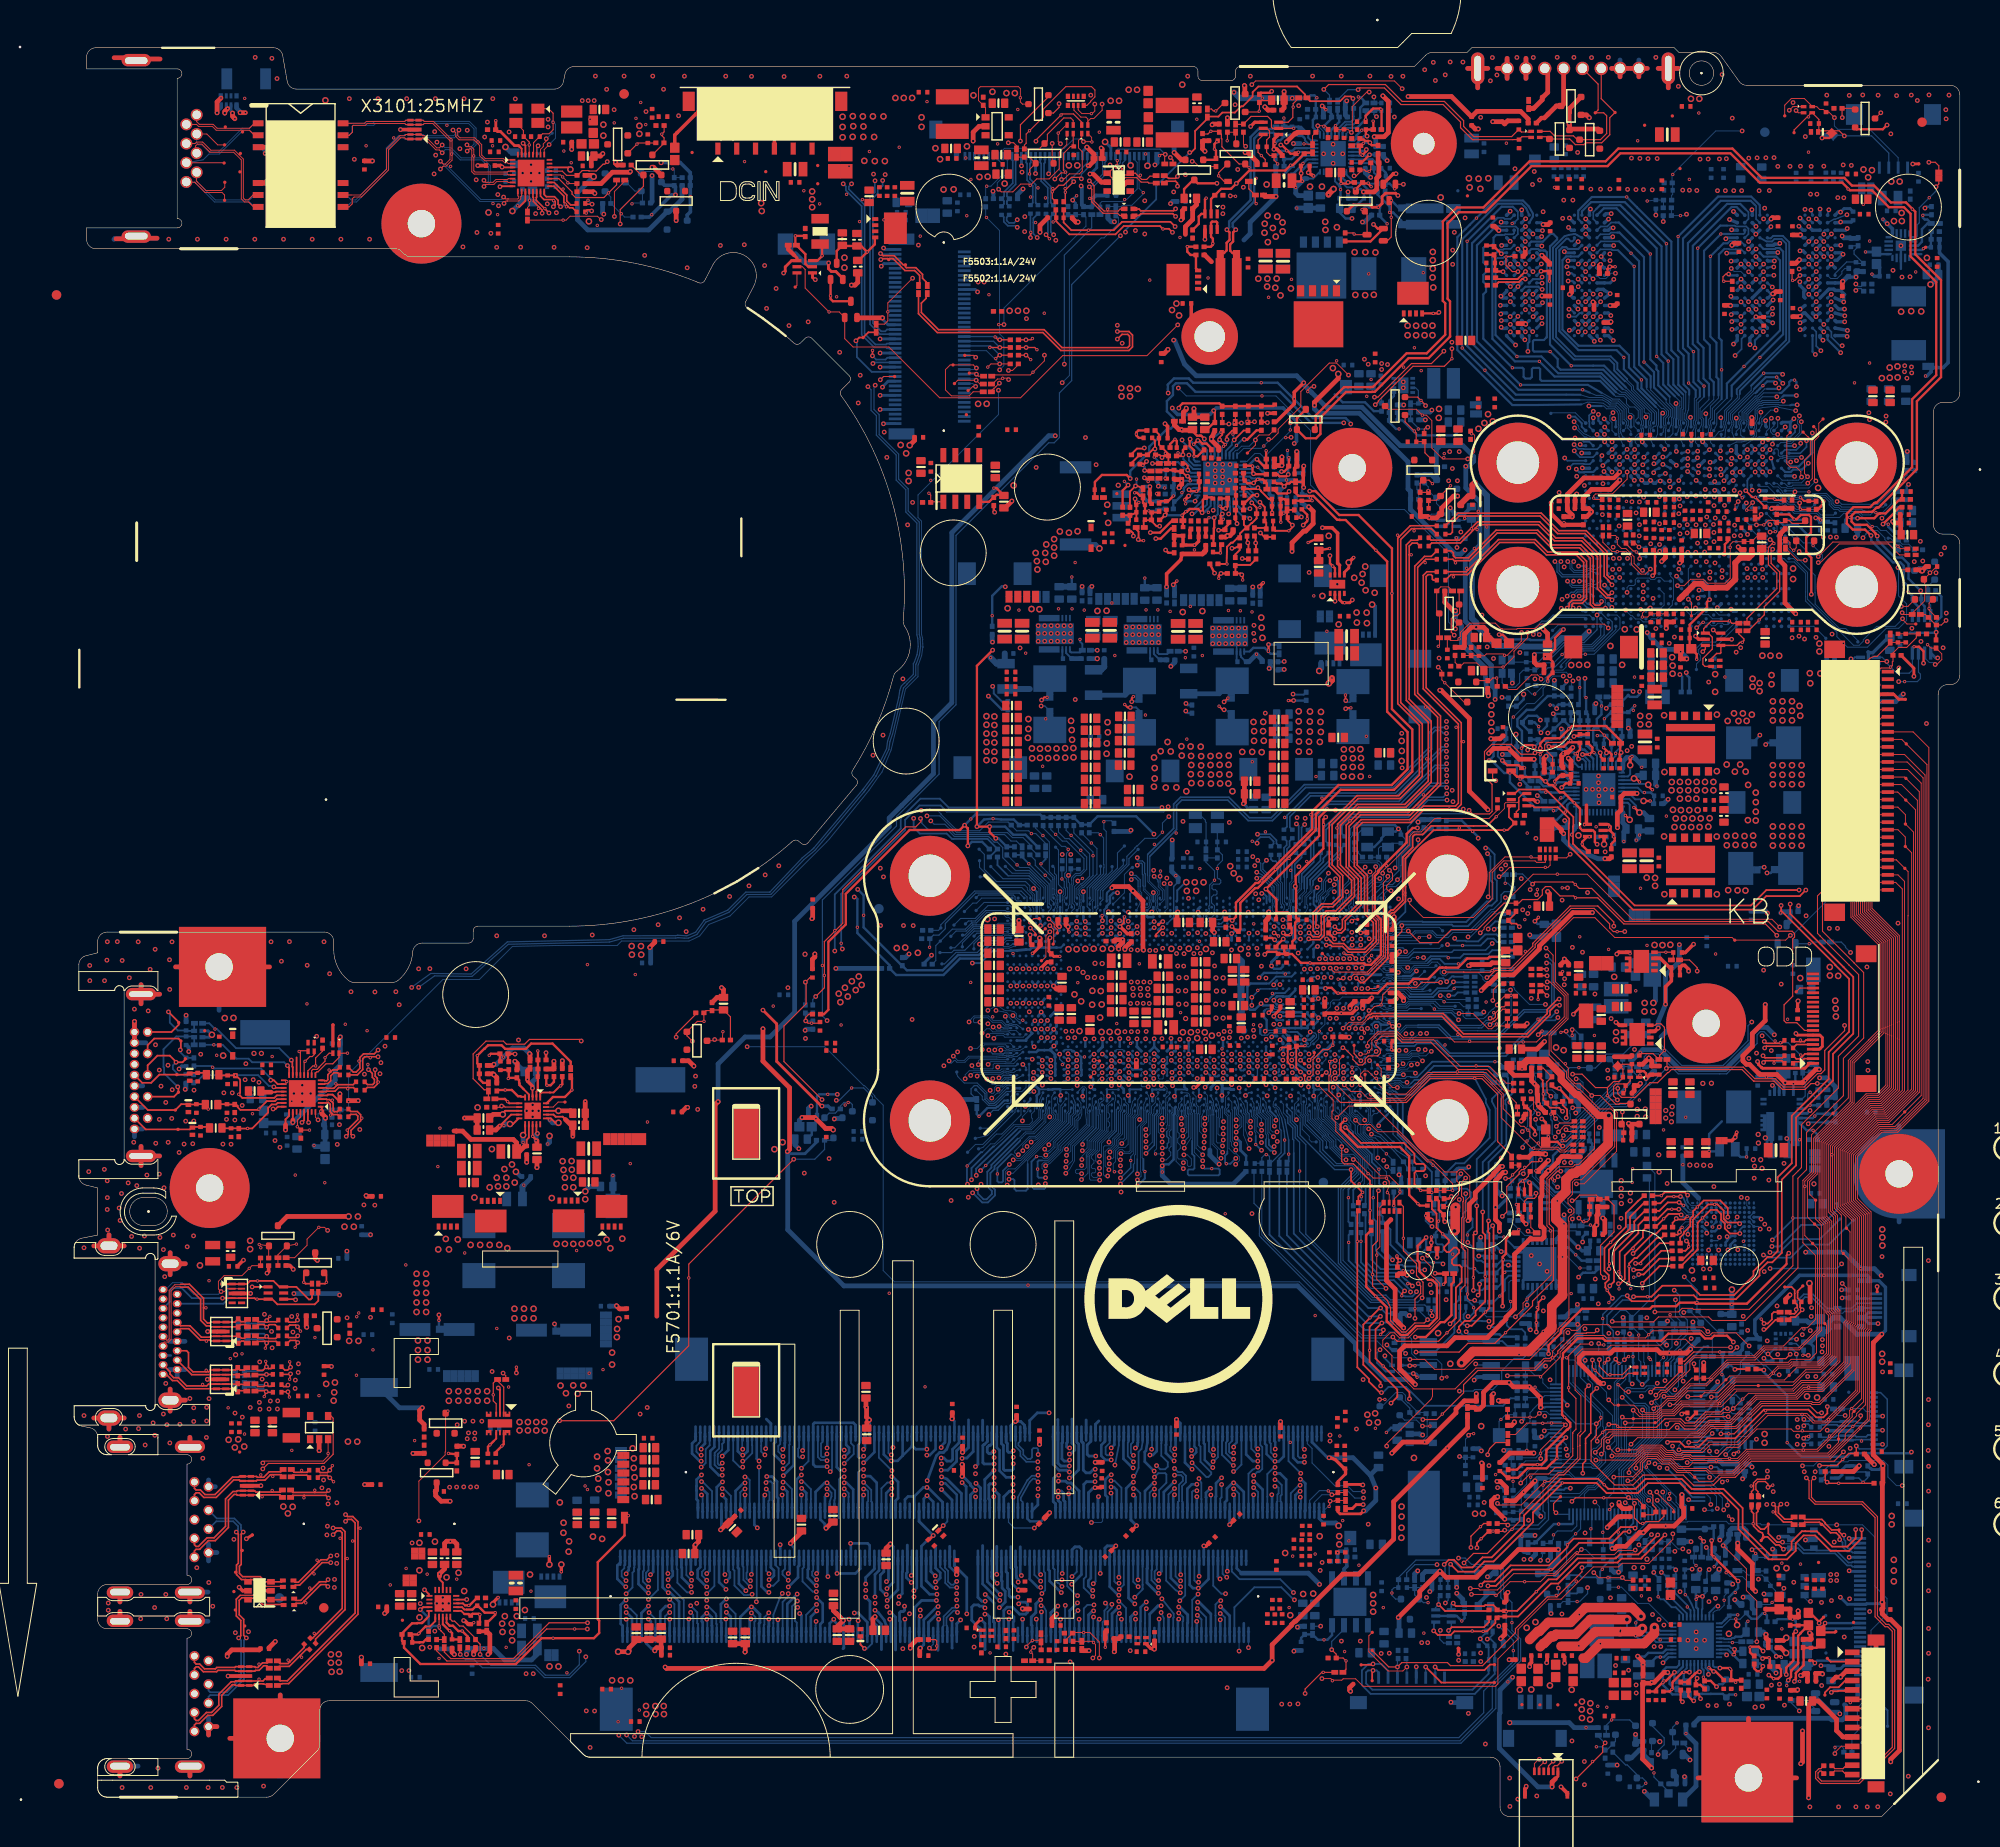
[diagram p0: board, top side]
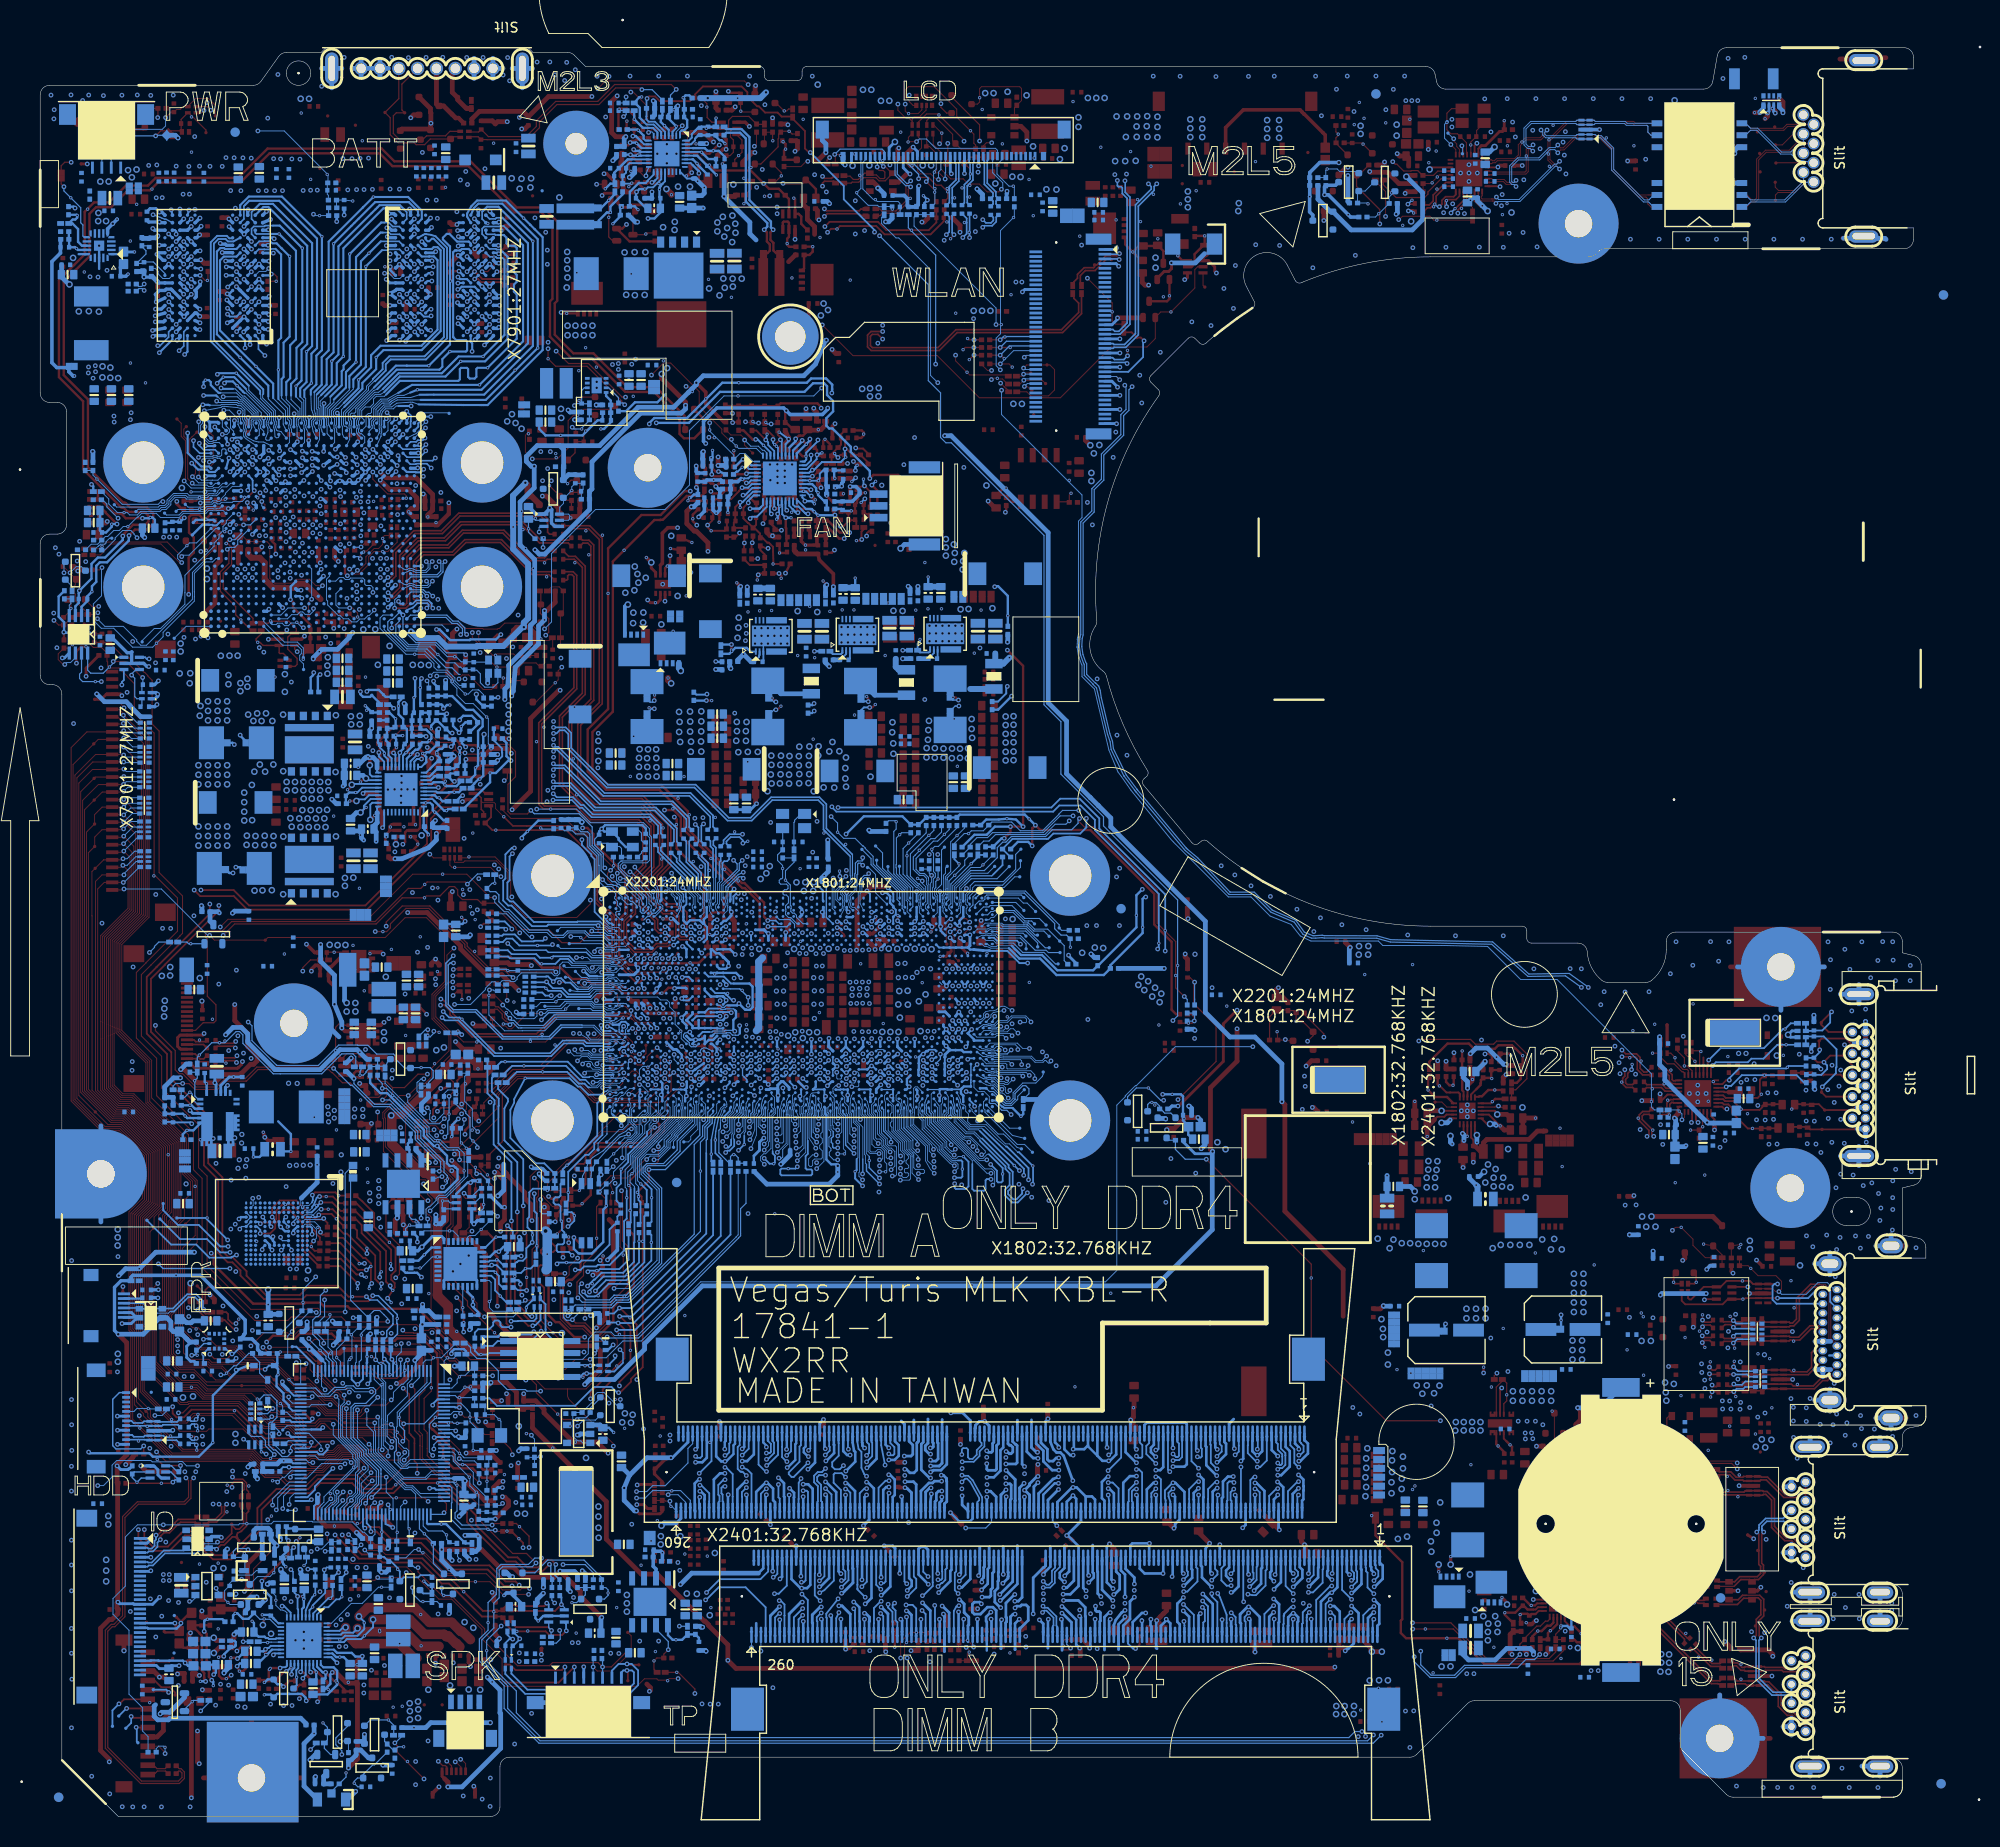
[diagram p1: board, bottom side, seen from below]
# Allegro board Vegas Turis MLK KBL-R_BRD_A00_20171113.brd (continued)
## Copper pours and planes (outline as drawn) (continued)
+V1.8A_SIP on TOP: 151.83,78.95 151.51,79.27 150.7,80.08 150.64,80.14 150.64,81.7 150.92,81.97 152.53,81.97 153,81.5 153,79.34 152.61,78.95 ; 3 cut-outs
+V3.3A_SIP on TOP: 131.19,82.45 131.06,82.58 131.06,82.58 131.02,82.62 131.02,83.88 131.14,84 131.14,89.29 131.32,89.46 132.23,89.46 132.43,89.26 132.43,85.2 132.7,84.94 132.7,82.65 132.49,82.45 ; 12 cut-outs
+V3.3A_SIP on BOTTOM: 157.68,78.32 157.24,78.76 157.24,80.13 156.96,80.41 155.87,80.41 155.63,80.65 155.63,81.57 155.89,81.83 155.9,81.83 156.68,82.61 156.68,83.47 156.83,83.62 157.71,83.62 158.78,82.55 158.78,79.68 158.42,79.32 158.42,78.41 158.32,78.32 ; 4 cut-outs
+V3.3A_SIP on L3: 129.1,83.23 131.57,85.71 137.78,85.71 138.13,86.06 141.52,86.06 141.53,86.06 142.91,86.06 143.18,85.79 145.25,85.79 146.87,84.17 148.15,84.17 150.03,82.29 151.19,81.13 153.78,81.13 154.68,82.03 156.03,82.03 156.12,81.94 158.33,81.94 158.68,81.59 158.68,81.06 158.34,80.72 158.31,80.72 157.07,79.49 157.05,79.49 156.21,78.65 149.19,78.65 143.33,84.51 137.89,84.51 137.45,84.06 133.02,84.06 132.51,83.55 131.24,83.55 129.53,81.84 127.22,81.84 126.98,82.08 126.98,82.98 127.23,83.23
+VCCGT on TOP: 99.8,121.93 100.59,121.93 100.77,121.75 100.77,120.36 102.51,118.62 105.45,118.62 106.75,119.92 107.65,119.92 107.87,119.69 107.87,106.55 108.24,106.18 112.31,106.18 112.39,106.26 113.05,106.26 114.64,104.67 114.64,101.78 113.7,100.84 113.7,93.36 113.12,92.78 111.41,92.78 110.73,92.1 110.73,84.99 110.83,84.89 111.89,84.89 111.97,84.97 114.11,84.97 114.41,84.66 114.41,84 114.28,83.87 111.46,83.87 111.23,83.64 111.23,83.34 111.16,83.27 111.13,83.27 110.87,83.01 109.02,83.01 108.74,83.29 108.74,83.97 108.52,84.2 107.35,84.2 107.17,84.03 107.17,83.24 107.04,83.11 106.64,83.11 106.46,83.29 106.46,83.57 106.46,83.57 106.46,83.82 106.69,84.05 106.69,85.24 106.33,85.6 104.25,85.6 104.12,85.73 104.12,86.44 103.84,86.72 103.23,86.72 103,86.95 102.57,86.95 102.37,86.74 102.37,86.3 102.25,86.19 98.2,86.19 98.03,86.36 98.03,94.59 97.62,95 96.83,95 96.44,95.39 96.44,97.12 95.63,97.93 95.63,102.38 96.38,103.13 97.99,103.13 99.31,104.45 99.31,107.08 99.75,107.52 99.75,118.87 99.63,119 99.63,121.76 ; 59 cut-outs
+VCCGT on TOP: 80.83,80.6 80.58,80.85 80.58,87.71 86.32,93.45 89.59,93.45 90.28,92.76 90.28,90.35 81.67,81.74 81.67,80.98 81.29,80.6 ; 3 cut-outs
+VCCGT on BOTTOM: 105.54,107.56 104.89,108.21 104.89,109.52 104.45,109.96 99.11,109.96 98.25,110.81 98.25,115.8 98.26,115.8 98.26,116.45 98.75,116.94 106.12,116.94 107.92,115.14 108.2,115.14 108.32,115.02 108.32,107.64 108.25,107.56 ; 9 cut-outs
+VCCGT on BOTTOM: 81.08,83.47 79.69,84.86 79.69,88.6 80.73,89.64 86.67,89.64 87.27,89.04 92.54,89.04 94.27,90.77 96.73,90.77 97.67,91.71 104.2,91.71 104.61,92.11 104.94,92.11 105.38,92.55 105.38,93.07 105.59,93.28 109.55,93.28 109.89,92.94 109.89,92.51 109.76,92.38 109.76,91.6 106.14,91.6 105.02,90.49 104.76,90.49 104.5,90.23 104.5,89.89 105.1,89.29 105.1,88.56 104.84,88.56 104.65,88.37 104.65,87.99 105.05,87.59 105.05,87.09 104.66,86.7 103.96,86.7 103.87,86.6 103.87,86.08 103.89,86.05 103.89,85.9 103.83,85.84 103.38,85.84 103.32,85.78 99.01,85.78 98.23,86.57 97.8,86.57 97.72,86.49 97.19,86.49 94.17,83.47
+VCCGT on L2: 82.32,92.83 82.32,99.91 87.22,104.82 87.25,104.79 91.46,104.79 92.2,105.53 92.2,106.63 96.3,110.73 96.3,110.74 96.68,111.12 96.68,117.17 96.3,117.55 96.3,118.39 96.79,118.89 96.79,119.08 97.6,119.88 111.19,119.88 112.96,118.11 112.96,93.65 114.47,92.13 114.47,85.52 114.58,85.41 114.58,83.84 114.54,83.8 111.46,83.8 111.23,83.57 111.23,83.09 111.49,82.83 111.49,82.4 110.94,81.85 106.4,81.85 106.1,82.15 106.1,83.74 103.03,86.81 87.37,86.81 84.92,84.36 81.36,84.36 80.96,84.76 80.96,90.73 80.97,90.74 80.97,91.48
+VCCGT on L3: 80.98,86.06 80.98,88.75 84.36,92.13 84.36,100.05 88.68,104.37 91.8,104.37 93.31,105.88 93.31,107.72 96.26,110.67 97.29,110.67 98.61,111.99 98.61,116.58 99,116.97 111.44,116.97 113.14,115.27 113.14,108.41 114.16,107.39 114.16,101.5 113.49,100.84 113.49,93.7 114.84,92.36 114.84,91.82 114.82,91.85 112.22,91.85 112.02,92.05 112.02,92.36 111.84,92.53 111.46,92.53 111.31,92.38 111.31,91.75 111.92,91.14 113.82,91.14 115.48,89.49 115.48,83.92 115.25,83.7 111.56,83.7 111.36,83.49 111.36,82.43 111.21,82.28 106.43,82.28 106.41,82.26 106,82.67 106,84.49 103.11,87.38 88.08,87.38 86,85.3 81.74,85.3
+VCCGT on L4: 109.23,112.73 108.69,112.19 100.95,112.19 99.96,113.18 99.96,116.66 100.36,117.06 108.39,117.06 109.23,116.22
+VCCGT on L4: 86.8,92.61 86.8,91.32 87.15,90.96 93.43,90.96 93.47,91 94.38,91 95.26,91.87 111.23,91.87 111.69,91.42 114.51,91.42 114.94,91.85 114.94,92.92 114.92,92.94 114.92,93.32 114.43,93.8 110.73,93.8 109.94,93.02 108.69,93.02 108.39,93.32 105.01,93.32 104.78,93.09 103.82,93.09 103.39,93.52 103.39,95.15 102.5,96.04 96.88,96.04 93.66,92.81 87,92.81
+VCCIO on TOP: 116.48,81.49 116.28,81.68 116.28,82.78 116.43,82.93 116.69,82.93 117.56,82.07 117.56,81.61 117.43,81.49 ; 1 cut-out
+VCCIO on TOP: 158.96,81.41 158.96,82.33 159.31,82.68 159.31,84.91 159.42,85.02 162.75,85.02 162.75,84.03 163.1,83.67 164.29,83.67 164.3,83.67 164.94,83.67 165.01,83.6 165.01,81.92 164.69,81.6 163.78,81.6 163.46,81.28 159.09,81.28 ; 7 cut-outs
+VCCIO on TOP: 121.8,80.77 121.7,80.88 121.7,81.69 122.44,82.43 122.44,82.86 121.88,83.42 121.88,83.62 121.88,83.63 121.88,83.82 122.38,84.32 122.97,84.32 123.08,84.21 123.08,81.43 123.34,81.17 123.34,80.93 123.19,80.77 ; 3 cut-outs
+VCCIO on BOTTOM: 121.88,80.82 121.81,80.89 121.81,81.12 122.36,81.66 122.36,82.36 122.46,82.45 122.46,82.68 122.02,83.12 122.02,83.61 122.11,83.7 123.24,83.7 123.42,83.52 123.42,82.59 123.59,82.42 123.59,81.27 123.15,80.82 122.84,80.82 122.66,81 122.38,81 122.21,80.82
+VCCIO on L2: 135.37,75.25 134.96,75.66 132.85,75.66 131.34,77.17 131.1,77.17 130.52,77.74 130.52,78.75 129.6,79.67 129.6,80.24 129.45,80.24 128.9,80.8 127.17,80.8 126.64,81.32 125.56,81.32 124.79,80.56 116.16,80.53 116.11,80.59 116.11,81.23 115.55,81.79 115.55,81.96 115.63,82.03 121.57,82.03 122.04,82.5 122.04,83.74 122.21,83.91 124.11,83.91 124.62,83.4 124.78,83.4 125.43,83.4 125.43,83.4 130.99,83.4 131.98,82.41 133.96,82.41 135.03,81.35 136.17,81.35 136.89,80.63 139.33,80.63 139.71,81.02 144.98,81.01 147.14,78.85 157.99,78.85 160.14,81 160.22,81 160.33,81.11 163.79,84.58 165.48,84.58 165.75,84.31 165.75,78.14 162.86,75.25
+VCCMPHYGTAON_1P0_LS_SIP on TOP: 128.03,88.05 127.84,88.24 127.84,89.51 128.73,90.4 132.24,90.4 132.38,90.26 132.38,89.86 132.15,89.64 131.2,89.64 130.91,89.35 129.27,89.35 128.97,89.05 128.97,88.53 128.5,88.05
+VCCMPHYGTAON_1P0_LS_SIP on TOP: 159.26,87.18 157.51,88.93 157.51,89.94 157.58,90.01 158.97,90.01 159.18,89.8 159.18,88.77 159.28,88.66 159.79,88.66 159.87,88.58 159.87,87.26 159.8,87.18 ; 3 cut-outs
+VCCMPHYGTAON_1P0_LS_SIP on BOTTOM: 162.6,85.27 162.2,85.66 159.15,85.66 157.51,87.3 157.51,91.39 157.24,91.66 157.24,92.56 157.24,92.56 157.24,92.73 156.98,92.99 156.98,93.88 157.04,93.94 158.48,93.94 159.24,93.18 159.24,89.13 159.5,88.88 163.36,88.88 163.5,88.74 163.5,85.43 163.34,85.27 ; 10 cut-outs
+VCCMPHYGTAON_1P0_LS_SIP on BOTTOM: 130.98,89.36 130.81,89.53 130.81,89.72 130.23,90.3 129.7,90.3 129.57,90.43 129.57,90.61 129.73,90.76 132.15,90.76 132.26,90.66 132.26,89.74 131.88,89.36
+VCCMPHYGTAON_1P0_LS_SIP on BOTTOM: 127.98,88.18 127.88,88.27 127.88,88.67 128.24,89.02 129.24,89.02 129.32,88.93 129.32,88.39 129.11,88.18
+VCCMPHYGTAON_1P0_LS_SIP on L2: 139.4,86.17 139.2,85.97 131.07,85.97 130.31,85.21 128.07,85.21 127.65,84.8 127.34,84.8 127.12,85.02 127.12,85.56 127.13,85.57 127.13,85.77 127.33,85.97 128.39,85.97 128.85,86.43 128.85,87.13 127.82,88.16 127.82,88.57 127.97,88.72 129,88.72 129.67,88.06 138.39,88.06 139.74,89.41 146.65,89.41 148.92,91.67 150.41,91.67 153.19,94.45 155.14,94.45 156.03,95.34 159.87,95.34 161.67,93.54 161.67,88.98 161.64,88.96 160.48,87.8 157.75,87.8 156.61,87.8 154.57,85.76 146.61,85.76 146.19,86.18 141.12,86.18 139.48,86.17
+VCCMPHYGTAON_1P0_LS_SIP on L3: 132.2,90.44 130.56,90.44 129.67,89.55 128.45,89.55 127.86,88.96 127.86,88.12 128.19,87.79 129.2,87.79 129.87,88.47 130.37,88.47 131.74,89.84 132.21,89.84 132.34,89.97 132.34,90.3
+VCCPRIM_CORE on TOP: 127.37,83.91 127.2,84.08 127.2,84.35 127.34,84.48 128.02,84.48 128.66,85.12 128.66,85.55 128.79,85.68 129.6,85.68 129.7,85.57 129.7,84.95 129.38,84.63 129.38,84.04 129.25,83.91 ; 1 cut-out
+VCCPRIM_CORE on TOP: 124.19,85.6 123.98,85.81 123.98,87.53 123.98,87.53 124.11,87.66 125.13,87.66 125.55,88.08 126,88.08 126.09,87.99 126.09,87.61 125.69,87.21 125.69,85.75 125.53,85.6 ; 2 cut-outs
+VCCPRIM_CORE on BOTTOM: 127.24,83.98 127.11,84.11 127.11,84.4 127.26,84.55 127.54,84.55 127.7,84.39 128.46,84.39 128.91,84.84 129.87,84.84 129.96,84.75 129.96,84.31 129.69,84.03 127.91,84.03 127.9,84.05 127.62,84.05 127.56,83.98
+VCCPRIM_CORE on BOTTOM: 166.62,92.77 166.82,92.97 169.58,92.97 169.77,92.77 169.77,90.98 169.07,90.28 166.94,90.28 166.62,90.6
+VCCPRIM_CORE on BOTTOM: 125,86.13 124.72,86.41 124.72,87.84 125.01,88.13 128.5,88.13 128.61,88.03 128.61,87.72 128.54,87.66 127.03,87.66 125.49,86.13
+VCCPRIM_CORE on L2: 145.07,81.39 139.71,81.4 139.55,81.4 139.17,81.02 137.04,81.02 136.33,81.73 135.19,81.73 135.18,81.74 134.94,81.74 134.04,82.63 132.3,82.63 131.15,83.78 125.59,83.78 124.77,83.78 124.33,84.23 124.33,87.07 124.72,87.47 125.29,87.47 125.39,87.37 125.39,86.13 125.79,85.74 126.59,85.74 126.74,85.59 126.74,85 127.13,84.61 128.06,84.61 128.41,84.96 130.31,84.96 130.94,85.59 133.47,85.59 133.62,85.43 133.62,84.56 134.6,83.58 139.96,83.58 140.02,83.64 140.69,84.3 145.31,84.3 147.19,82.43 155.24,82.43 158.77,85.95 158.77,86.53 158.82,86.58 158.82,86.86 159.38,87.42 160.64,87.42 160.75,87.53 161.97,88.74 166.11,92.87 167.12,93.87 169.66,93.87 170.11,93.42 170.11,91.44 169.6,90.93 160.06,81.38 157.83,79.16 147.3,79.16
+VCCPRIM_CORE on L3: 128.35,83.92 127.16,83.92 126.65,84.43 125.94,84.43 124.87,85.5 124.87,87.2 125.2,87.53 125.66,87.53 126,87.19 126,86.86 126.36,86.5 126.36,85.74 127.44,84.66 128.34,84.66 128.42,84.59 128.42,83.99
+VCCSA on TOP: 122.71,89.59 122.58,89.72 122.58,90.51 122.69,90.61 122.69,92.21 123.05,92.57 123.97,92.57 124.16,92.76 124.16,94.59 124.15,94.6 124.26,94.72 124.26,96.52 125.18,97.44 125.18,98.17 125.33,98.33 125.66,98.33 126.69,97.3 126.69,96 126.25,95.56 126.25,93.01 126.31,92.95 126.42,92.95 126.55,92.81 126.96,92.81 127.21,92.56 127.21,92.1 127.13,92.03 126.4,92.03 126.33,91.96 126.26,91.96 126.12,91.82 126.12,91.39 125.53,90.81 125.53,90.07 125.05,89.59 ; 5 cut-outs
+VCCSA on TOP: 134.9,109.79 134.4,110.29 134.4,115.57 135.1,116.26 138.61,116.26 139.2,115.68 139.2,110.51 138.49,109.79 ; 6 cut-outs
+VCCSA on TOP: 124.64,82.6 124.48,82.75 124.48,82.94 124.26,83.16 123.57,83.16 123.4,83.34 123.4,84.04 123.54,84.18 124.77,84.18 125.02,84.43 125.51,84.43 125.76,84.18 125.76,82.86 125.49,82.6 ; 1 cut-out
+VCCSA on BOTTOM: 133.68,109.9 133.37,110.21 133.37,116.55 133.51,116.69 138.69,116.69 139.17,116.21 139.17,110.69 139.17,110.68 139.17,110.47 138.6,109.9 ; 8 cut-outs
+VCCSA on BOTTOM: 122.92,91.11 122.41,91.62 122.41,92.76 122.51,92.86 123.04,92.86 123.25,93.07 123.25,93.78 124.29,93.78 124.7,94.19 124.92,94.19 125.13,93.98 125.38,93.98 125.58,94.19 125.85,94.19 126.79,93.25 126.79,92.98 126.17,92.36 126.17,91.29 126.05,91.18 125.04,91.18 125,91.14 125,91.12 124.99,91.11
+VCCSA on BOTTOM: 125,82.11 124.43,82.69 124.43,82.81 124.17,83.07 124.17,83.49 124.4,83.72 125,83.72 125.23,83.95 125.61,83.95 125.69,83.87 125.69,83.01 126.34,82.36 126.34,82.19 126.27,82.12 126.11,82.12 126.11,82.11
+VCCSA on L2: 125.32,89.61 123.67,91.27 123.67,92.46 124.53,93.32 124.53,94.68 125.13,95.28 125.13,98.98 129.37,103.22 129.37,112.2 129.64,112.47 131.51,112.47 132.93,113.89 132.93,116.2 133.52,116.78 136.53,116.78 139.19,114.13 139.19,109.88 138.28,108.97 135.81,108.97 133.37,106.53 133.37,106.53 132.94,106.09 132.94,98 130.47,95.53 130.47,91.8 129.7,91.02 126.93,91.02 126.51,90.61 126.51,90.28 125.85,89.61
+VCCSA on L3: 122.66,92.2 122.66,84.71 124.82,82.55 125.46,82.55 125.71,82.81 125.71,83.44 124.49,84.66 124.49,87.43 125.65,88.58 125.65,90.82 126.4,91.57 126.4,94.06 126.17,94.29 124.77,94.29 122.69,92.2
GND on TOP: 174.13,127.31 174.03,127.41 174.03,129.63 174.59,130.2 175.78,130.2 177.16,131.57 177.16,133.09 177.31,133.24 179.5,133.24 180.53,132.21 180.53,130.56 177.28,127.31
GND on TOP: 37.6,27.72 37.5,27.82 37.5,30.17 37.61,30.28 38.38,30.28 38.81,29.85 38.81,28.97 38.59,28.75 38.59,27.77 38.53,27.72 ; 1 cut-out
GND on TOP: 192.06,121.43 191.96,121.52 191.96,122.01 191.98,122.02 193.45,122.02 193.99,122.56 194.7,122.56 194.9,122.35 194.9,121.69 194.63,121.43
GND on TOP: 141.83,81.64 141.83,80.68 141.56,80.4 140.47,80.4 140.21,80.14 139.35,80.14 139.09,80.4 139.09,81.49 138.96,81.62 138.96,82.63 139.03,82.7 139.44,82.7 139.52,82.62 139.52,81.67 139.52,81.65 140.13,81.05 141.01,81.05 141.17,81.2 141.17,81.53 141.34,81.7 141.77,81.7 ; 2 cut-outs
GND on TOP: 52.15,65.09 52.02,65.22 52.02,66.36 51.48,66.9 51.48,71.06 52.14,71.72 54.35,71.72 54.56,71.5 54.56,67 54.69,66.87 54.69,65.35 54.43,65.09 ; 2 cut-outs
GND on TOP: 148.19,123.82 148.05,123.96 148.05,125.53 148.45,125.93 149.21,125.93 149.42,125.72 149.42,124.76 149.55,124.63 150.31,124.63 150.47,124.47 150.47,124.29 150.01,123.82 ; 1 cut-out
GND on TOP: 160.26,86.9 160.05,87.1 160.05,88.74 159.93,88.86 159.47,88.86 159.36,88.97 159.36,89.58 159.49,89.71 163.7,89.71 164.06,89.35 164.06,88.86 164.07,88.85 164.07,85.42 163.91,85.27 161.7,85.27 161.58,85.39 161.58,86.56 161.24,86.9 ; 8 cut-outs
GND on TOP: 174.36,134.26 174.28,134.35 174.28,135.03 173.97,135.33 173.97,135.67 174.59,136.29 174.59,136.66 173.9,137.35 173.9,137.47 174.08,137.64 174.51,137.64 175.14,138.28 175.14,139.53 175.37,139.75 175.37,140.22 175.48,140.34 176.09,140.34 176.16,140.26 176.16,138.45 175.33,137.62 175.33,135.6 174.97,135.24 174.97,134.35 174.88,134.26 ; 4 cut-outs
GND on TOP: 156.6,138.89 156.49,139 148.39,139 148.11,139.28 148.11,139.55 148.35,139.79 148.91,139.79 149.09,139.97 149.09,146.07 149.1,146.09 149.09,146.09 149.09,147.97 148.65,148.42 148,148.42 147.84,148.25 147.84,147.2 147.76,147.12 144.46,147.12 144.36,147.22 144.36,149.2 143.95,149.61 143.95,150.29 142.83,151.41 141.26,151.41 140.82,151.84 140.82,152.5 141.51,153.19 145.32,153.19 148.42,150.09 151.72,150.09 153.5,148.31 155.23,148.31 155.23,148.29 157.92,145.59 157.92,142.09 158.15,141.86 158.15,139.08 157.95,138.89 ; 10 cut-outs
GND on TOP: 107.91,123.94 107.17,124.68 107.17,125.61 107.39,125.82 110.63,125.82 111.51,126.71 115.69,126.71 115.83,126.56 115.83,124.7 115.63,124.5 110.93,124.5 110.38,123.94
GND on TOP: 170.54,16.84 170.19,17.2 170.19,20.32 170.47,20.6 174.1,20.6 174.2,20.5 174.2,16.92 174.12,16.84 ; 3 cut-outs
GND on TOP: 179.44,22.58 179.1,22.91 179.1,24.46 179.64,25 181.89,25 182.09,25.2 182.81,25.2 183.4,24.62 184.25,24.62 184.34,24.52 186.15,24.52 186.4,24.27 186.4,22.76 186.22,22.58 ; 12 cut-outs
GND on TOP: 169.69,134.29 169.65,134.33 169.65,135.21 170.32,135.88 170.83,135.88 171.11,136.16 171.11,136.77 171.25,136.92 171.58,136.92 172.2,137.53 172.44,137.53 172.74,137.24 172.74,135.18 172.62,135.05 172.16,135.05 171.99,135.22 170.48,135.22 170.39,135.13 170.39,134.39 170.28,134.29 ; 4 cut-outs
GND on TOP: 77.08,80.69 76.78,80.99 76.78,83.54 77.25,84 79.71,84 80.35,83.36 80.35,80.97 80.07,80.69 ; 5 cut-outs
GND on TOP: 157.4,177.61 164.64,177.61 165.39,176.86 165.41,176.89 180.44,176.89 181.5,175.83 183.71,175.83 183.71,175.83 188.92,175.83 189.16,175.59 189.16,175.31 188.74,174.89 188.74,174.51 188.74,174.51 188.74,174.07 188.25,173.59 156.78,173.59 156.04,172.85 153.17,172.85 152.32,173.7 152.32,176.93 153.04,177.65 154.03,177.65 154.33,177.35 157.13,177.35 ; 13 cut-outs
GND on TOP: 173.26,138.01 172.82,138.45 170.96,138.45 170.89,138.53 170.89,138.98 171,139.09 173.75,139.09 173.82,139.03 173.82,138.27 173.56,138.01 ; 1 cut-out
GND on TOP: 130.72,95.02 130.63,95.11 130.63,97.96 131.83,99.16 132.04,99.16 132.49,98.71 132.49,98.19 131.36,97.07 131.36,95.22 131.16,95.02
GND on TOP: 19.24,73.43 19.13,73.54 16.9,73.54 16.64,73.79 13.24,73.79 13.11,73.66 11.56,73.66 11.44,73.54 8.59,73.54 8.47,73.66 8.47,74.5 8.69,74.73 10.07,74.73 10.57,75.24 16.92,75.24 17.41,74.75 19.82,74.75 19.92,74.65 19.92,74.12 ; 6 cut-outs
GND on TOP: 177.67,135.99 177.59,136.07 177.59,137.25 177.32,137.51 177.32,138.17 177.35,138.19 177.94,138.19 178.17,137.96 178.17,137.65 178.39,137.44 178.39,136.15 178.22,135.99 ; 1 cut-out
GND on TOP: 171.7,31.51 171.61,31.6 171.61,32.95 171.62,32.96 171.62,33.07 171.35,33.33 171.35,33.66 171.36,33.67 171.36,34.01 171.43,34.08 172.84,34.08 173.01,33.92 173.01,31.65 172.87,31.51 ; 2 cut-outs
GND on TOP: 109.95,140.41 109.75,140.61 109.05,140.61 108.98,140.69 108.98,141.52 109.49,142.03 110.94,142.03 111.31,141.65 111.31,141.3 111.06,141.04 111.06,140.51 110.96,140.41 ; 1 cut-out
GND on TOP: 135.33,129.59 134.9,129.59 134.8,129.7 134.8,130.44 134.74,130.5 133.39,130.5 133.39,130.5 133.33,130.5 133.26,130.57 133.26,131.32 133.39,131.45 135.15,131.45 135.43,131.73 135.43,132.01 135.98,132.56 135.98,133.16 136.58,133.76 138.77,133.76 138.99,133.55 138.99,130.29 138.29,129.59
GND on TOP: 12.99,17.77 12.75,18.01 12.75,18.44 13.19,19.85 11.99,20.71 3.5,20.71 3.33,20.78 3.26,20.95 3.26,23.65 3.33,23.82 3.5,23.89 11.99,23.89 13.19,24.75 12.75,26.16 12.75,26.64 12.86,26.75 15.75,26.75 16.13,26.37 16.13,25.81 17.25,24.68 17.25,23.6 17.03,23.37 17.02,23.37 16.13,22.48 16.13,18.73 15.18,17.77
GND on TOP: 135.93,40.73 135.31,41.35 135.21,41.35 134.83,41.73 134.83,42.32 134.91,42.39 136.8,42.39 136.95,42.25 136.95,41.69 136.95,41.69 136.95,41.52 136.95,41.52 136.95,40.93 136.75,40.73 ; 1 cut-out
GND on TOP: 97.21,181.57 97.1,181.68 97.1,182.29 96.92,182.46 96.32,182.46 96.27,182.51 96.27,183.6 96.38,183.7 97.92,183.7 98.02,183.6 98.02,181.67 97.93,181.57 ; 2 cut-outs
GND on TOP: 17.63,75.11 17.13,75.62 17.13,76.08 16.75,76.46 10.85,76.46 9.9,75.5 7.59,75.5 7.07,76.02 7.07,77.7 7.25,77.88 8.36,77.88 9.02,78.54 10.22,78.54 10.55,78.21 13.06,78.21 13.22,78.06 15.48,78.06 15.6,78.18 17.05,78.18 17.43,77.8 17.43,76.56 18.17,75.82 19.13,75.82 19.34,75.62 19.34,75.29 19.16,75.11 ; 4 cut-outs
GND on TOP: outline of 86 points within 152.3,0.78 197.24,62.97 ; 24 cut-outs
GND on TOP: 168.03,68 167.65,68.38 167.65,70.44 168,70.79 174.05,70.79 174.23,70.61 174.23,68.38 173.84,68 ; 6 cut-outs
GND on TOP: 128.55,106.83 128.15,107.23 128.15,117.52 128.61,117.98 132.99,117.98 134.16,116.8 134.16,110.31 134.15,110.3 134.15,109.99 131.25,107.09 131.23,107.09 130.97,106.83 ; 11 cut-outs
GND on TOP: 160.76,77.85 159.04,79.58 159.04,80.89 159.18,81.03 163.63,81.03 163.89,80.78 163.89,78.49 163.65,78.24 163.01,78.24 162.62,77.85 ; 4 cut-outs
GND on TOP: 98.81,172.96 98.34,173.42 98.34,173.84 98.66,174.16 98.66,175.07 98.32,175.41 98.32,176.07 98.73,176.47 98.73,177.38 98.85,177.5 99.62,177.5 99.78,177.34 99.78,175.97 99.85,175.9 100.87,175.9 101.06,175.71 101.06,174.67 99.35,172.96 ; 5 cut-outs
GND on TOP: 170.28,107.8 169.46,108.62 168.38,108.62 168.08,108.91 168.08,109.52 167.46,110.15 166.89,110.15 165.92,111.13 165.92,113.83 165.98,113.9 168.34,113.9 168.5,113.74 168.5,112.04 168.91,111.64 172.68,111.64 172.77,111.54 172.77,110.58 173.03,110.32 174.34,110.32 174.52,110.14 174.52,109.18 173.69,108.35 173.69,107.91 173.58,107.8 171.37,107.8 ; 2 cut-outs
GND on TOP: 168.17,45.77 168.05,45.89 168.05,46.2 168.89,47.04 168.89,48.44 168.93,48.48 169.99,48.48 170.16,48.31 170.16,47.27 169.26,46.37 169.26,46.17 168.86,45.77 ; 3 cut-outs
GND on TOP: 33.93,20.47 33.8,20.61 33.8,22.73 33.96,22.9 36.87,22.9 37.01,22.76 38.07,22.76 38.08,22.75 38.08,22.55 38.06,22.54 37.06,22.54 36.92,22.4 36.92,22.19 37.05,22.06 37.05,20.95 36.88,20.77 35.71,20.77 35.41,20.47 ; 2 cut-outs
GND on TOP: 91.56,175.58 91.14,176 91.14,177.56 91.45,177.87 92.96,177.87 93.12,177.7 93.12,175.79 92.92,175.58 ; 4 cut-outs
GND on TOP: 46.66,178.14 45.96,178.84 45.96,179.15 46.12,179.31 47.05,179.31 47.28,179.08 47.28,178.25 47.17,178.14 ; 1 cut-out
GND on TOP: 164.5,101.6 164.24,101.86 164.24,103.96 167.73,107.44 172.93,107.44 173.03,107.34 173.46,107.34 173.6,107.21 173.6,106.61 174.04,106.17 174.04,103.74 173.89,103.6 171.77,103.6 171.75,103.61 171.74,103.6 170.71,103.6 170.64,103.66 170.64,104.58 170.47,104.75 168.44,104.75 168.36,104.68 168.36,103.49 168.67,103.18 168.67,101.65 168.62,101.6 ; 2 cut-outs
GND on TOP: 127.69,25.61 127.44,25.86 127.44,26.52 127.49,26.57 128.35,26.57 128.9,27.11 131.68,27.11 132.1,27.54 135.31,27.54 135.47,27.38 135.47,26.52 135.14,26.19 133.06,26.19 132.66,25.78 130.79,25.78 130.61,25.61 ; 10 cut-outs
GND on TOP: 178.49,68.48 177.58,69.39 177.58,72.27 178.37,73.05 179.99,73.05 180.5,72.54 180.5,68.99 179.99,68.48
GND on TOP: 98,124.04 97.64,124.4 97.64,125.77 97.8,125.92 101.3,125.92 102.19,126.81 106.37,126.81 106.51,126.66 106.51,124.8 106.31,124.6 101.61,124.6 101.06,124.04
GND on TOP: 167.83,24.41 167.52,24.72 166.3,24.72 166.07,24.94 166.07,25.45 165.83,25.69 165.29,25.69 165.07,25.91 165.07,26.54 165.24,26.71 168.14,26.71 168.89,25.96 168.89,24.51 168.79,24.41 ; 2 cut-outs
GND on TOP: 172.85,55.7 171.77,56.78 171.77,57.37 171.89,57.48 172.3,57.48 172.52,57.71 173.36,57.71 173.62,57.46 173.62,55.91 173.41,55.7 ; 3 cut-outs
GND on TOP: 40.14,40.16 39.84,40.46 39.84,41.38 40.78,42.32 46.45,42.32 46.55,42.22 46.55,41.34 46.54,41.33 45.44,41.33 45.39,41.28 45.39,40.31 45.35,40.27 45.14,40.27 45.08,40.33 45.08,41.2 45.01,41.27 41.59,41.27 41,40.68 41,40.34 40.82,40.16
GND on TOP: 27.21,51.79 27.09,51.91 27.09,55.91 27.69,56.51 27.69,61.27 28.39,61.97 30.79,61.97 31,62.19 31.62,62.19 32.04,61.77 32.04,52.12 31.7,51.79 ; 4 cut-outs
GND on TOP: 124.62,165.28 124.37,165.53 124.37,166.93 123.97,167.32 123.97,169.71 123.81,169.88 121.42,169.88 121.23,170.07 121.23,171.49 121.76,172.02 121.76,172.53 121.85,172.62 122.46,172.62 122.52,172.56 122.52,172.15 122.69,171.99 124.04,171.99 125.66,170.36 132.82,170.36 133.28,169.9 133.28,168.3 133.1,168.12 129.5,168.12 129.22,167.85 129.22,165.53 128.97,165.28 ; 1 cut-out
GND on TOP: 194.73,135.13 194.63,135.23 194.63,138.6 194.7,138.67 195.7,138.67 195.79,138.59 195.79,136.48 196.32,135.94 196.32,135.28 196.17,135.13 ; 6 cut-outs
GND on TOP: 174.27,78.73 174.27,77.94 173.98,77.65 169.17,77.65 168.89,77.93 168.89,78.49 169.6,79.2 173.8,79.2 ; 4 cut-outs
GND on TOP: 141.79,137.75 141.08,138.45 134.91,138.45 131.57,141.79 131.57,145.59 133.9,147.92 133.9,150.87 135.87,152.83 135.87,154.33 136.63,155.09 137.52,155.09 137.72,154.89 139.51,154.89 139.85,154.55 139.85,154.23 137.24,151.62 137.24,149.63 137.51,149.36 139.27,149.36 141.99,146.64 141.99,145.59 142.76,144.83 142.76,143.14 142.48,142.86 142.48,137.9 142.32,137.75 ; 5 cut-outs
GND on TOP: 183.73,178.3 183.64,178.38 183.64,179.64 184.26,180.25 184.67,180.25 184.76,180.17 184.76,178.75 184.3,178.3 ; 1 cut-out
GND on TOP: 43.75,65.04 43.72,65.07 43.72,66.68 43.55,66.85 42.29,66.85 42.24,66.91 42.24,71.29 42.37,71.43 45.88,71.43 46.21,71.1 46.21,69.95 46.5,69.67 46.81,69.67 47.83,68.65 47.83,65.32 47.55,65.04 ; 1 cut-out
GND on TOP: 166.75,136.42 166.64,136.53 166.64,137.01 166.73,137.1 167.26,137.1 167.51,137.34 167.51,137.85 167.86,138.2 167.86,140.24 167.99,140.37 169.24,140.37 169.35,140.27 169.35,137.36 169.77,136.94 169.77,136.48 169.71,136.42 ; 13 cut-outs
GND on TOP: 116.51,123.74 116.16,124.09 116.16,125.46 116.31,125.61 119.82,125.61 120.82,126.61 124.89,126.61 125.19,126.91 126.08,127.8 126.45,127.8 126.74,127.5 126.74,125.05 125.99,124.29 120.13,124.29 119.57,123.74
GND on TOP: 114.56,84.97 114.33,85.19 111.92,85.19 111.74,85.02 111.13,85.02 111.03,85.12 111.03,89.82 111.13,89.92 113.55,89.92 113.75,89.71 115.32,89.71 115.45,89.59 115.45,85.04 115.37,84.97 ; 7 cut-outs
GND on TOP: 166.94,119.36 166.38,119.91 165.41,119.91 165.27,120.05 165.27,120.52 165.32,120.57 166.69,120.57 166.86,120.4 168.23,120.4 168.35,120.53 168.35,125.73 168.14,125.95 167.09,125.95 167.09,127.12 167.35,127.37 168.52,127.37 168.69,127.2 168.69,126.23 168.94,125.99 169.4,125.99 169.96,126.54 170.34,126.54 170.49,126.7 170.49,128.04 170.59,128.15 171.15,128.15 171.23,128.07 171.23,126.54 171.16,126.47 171.16,125.05 170.95,124.84 170.32,124.84 170.32,124.84 170.19,124.84 169.98,124.64 169.98,123.65 170.19,123.44 170.19,122.67 170.38,122.48 170.88,122.48 170.96,122.4 170.96,121.94 170.86,121.85 170.44,121.85 170.19,121.59 170.19,119.77 169.78,119.36 ; 13 cut-outs
GND on TOP: 3.56,2.81 3.26,3.11 3.26,5.15 3.33,5.32 3.5,5.39 11.99,5.39 13.19,6.25 12.75,7.66 12.75,8.38 17.53,13.16 24.22,13.16 24.64,13.57 25.09,13.57 26.03,14.14 27.1,14.33 28.43,14.33 28.43,14.34 31.51,14.34 32.54,13.3 51.94,13.3 52.73,14.09 55.8,14.09 55.8,14.08 56.24,14.08 56.49,13.83 56.49,13.21 57.16,12.55 59.16,12.55 59.37,12.34 59.37,7.37 59.06,7.06 54.81,7.06 54.72,7.08 54.65,7.13 49.23,12.55 48.66,12.93 47.99,13.06 27.1,13.06 25.85,12.55 25.34,11.3 25.34,7.88 20.27,2.81 ; 6 cut-outs
GND on TOP: 157.87,121.93 157.62,122.18 157.62,125.4 157.78,125.56 160.58,125.56 161.6,124.53 161.6,122.1 161.43,121.93
GND on TOP: 184.63,134.7 184.52,134.81 184.52,136.1 184.67,136.25 186.74,136.25 187.01,135.98 187.01,134.9 186.82,134.7
GND on TOP: 45.14,17.5 44.82,17.81 44.82,20.87 45.4,21.44 45.4,23.37 45.12,23.65 44.25,23.65 44.05,23.45 44.05,22.23 43.92,22.1 43.54,22.1 43.37,22.28 43.37,23.93 43.7,24.26 45.47,24.26 45.85,23.88 45.85,22.76 46.21,22.4 48.06,22.4 48.32,22.15 48.32,18.79 47.02,17.5 ; 2 cut-outs
GND on TOP: 120,140.74 119.87,140.87 119.87,141.41 120.11,141.65 120.11,142.98 119.86,143.23 119.53,143.23 119.41,143.35 119.41,144.63 119.59,144.8 123.68,144.8 123.76,144.72 123.76,141.65 123.49,141.38 123.15,141.38 122.92,141.15 122.92,140.82 122.83,140.74 ; 12 cut-outs
GND on TOP: 69.32,69.76 68.82,70.27 68.82,75.08 68.97,75.23 74.14,75.23 75.62,73.75 75.62,71.58 73.81,69.76
GND on TOP: 188.36,122.3 188.35,122.3 187.04,122.3 185.95,123.4 182.84,123.4 180.91,125.33 179.46,125.33 179.2,125.58 179.2,126.19 179.28,126.27 179.97,126.27 180.32,126.62 180.32,127.41 180.91,127.99 182,127.99 182.84,127.15 182.84,124.97 183.05,124.75 184.64,124.75 184.81,124.92 184.81,127.55 184.79,127.56 184.81,127.58 184.81,132.25 187.52,134.96 191.03,134.96 193.72,132.27 193.72,126.05 193.15,125.48 192.59,125.48 192.52,125.41 192.52,124.67 190.14,122.3 ; 10 cut-outs
GND on TOP: 190.32,89.79 185.96,94.15 185.96,96.97 186.09,97.11 188.09,97.11 188.09,97.11 188.32,97.11 188.44,96.99 188.44,95.39 191.03,92.8 191.39,92.8 191.57,92.61 191.57,89.92 191.44,89.79
GND on TOP: 48.29,178.15 48.19,178.25 48.19,180.43 48.42,180.66 50.59,180.66 50.7,180.54 50.7,179.45 50.29,179.04 49.23,179.04 49.02,178.83 49.02,178.4 48.77,178.15 ; 1 cut-out
GND on TOP: 160.43,107.39 160.26,107.57 160.26,109.3 160.08,109.48 159.71,109.48 159.58,109.6 159.58,110.07 159.62,110.11 160.13,110.11 160.26,110.24 160.26,110.75 160.38,110.87 161.91,110.87 162.03,111 162.03,111.48 162.29,111.74 164.41,111.74 164.53,111.62 164.53,111.18 164.46,111.11 164,111.11 163.75,110.86 163.75,107.44 163.7,107.39 ; 6 cut-outs
GND on TOP: 107.8,134.27 107.73,134.34 107.73,135.63 107.86,135.77 110.56,135.77 110.64,135.68 110.64,134.65 110.26,134.27 ; 3 cut-outs
GND on TOP: 146.26,156.24 145.9,156.6 145.9,157.02 146.19,157.31 146.19,166.69 146.42,166.92 148.61,166.92 149.84,165.68 150.18,165.68 150.5,165.36 150.5,164.17 150.41,164.08 150.12,164.08 150.11,164.09 148,164.09 147.56,163.65 147.56,156.46 147.33,156.24 ; 3 cut-outs
GND on TOP: outline of 115 points within 0.76,57.03 76.71,102.54 ; 12 cut-outs
GND on TOP: 39.24,34.05 39.03,34.25 39.03,36.01 40.03,37.01 40.93,37.01 41.19,37.26 41.19,37.86 41.32,37.99 45.15,37.99 45.31,37.83 45.31,34.79 45.17,34.64 45.16,34.64 44.56,34.05 ; 12 cut-outs
GND on TOP: 108.67,106.9 108.16,107.41 108.16,119.62 108.4,119.86 109.63,119.86 111.41,118.09 111.41,111.55 112.53,110.43 112.53,107.85 111.58,106.9 ; 22 cut-outs
GND on TOP: 139.75,111.08 139.66,111.17 139.66,114.43 139.88,114.66 141.35,114.66 141.53,114.48 141.53,111.3 141.31,111.08 ; 2 cut-outs
GND on TOP: 18.15,76.48 17.92,76.71 17.92,78.56 17.05,79.43 11.72,79.43 11.36,79.07 8.9,79.07 8.88,79.06 8.87,79.07 8.59,79.07 8.34,79.33 8.34,80.06 8.54,80.27 10.07,80.27 10.45,79.89 10.88,79.89 11.01,80.01 11.01,80.55 10.57,80.98 8.67,80.98 8.26,81.38 8.26,82.09 8.52,82.35 10.17,82.35 11.06,81.46 11.62,81.46 12.67,82.51 14.55,82.51 14.82,82.25 15.68,82.25 15.76,82.17 15.76,81.84 15.55,81.64 15.02,81.64 14.71,81.33 14.71,80.55 15.15,80.11 17.63,80.11 17.79,80.27 20.21,80.27 20.35,80.12 20.35,78.77 20,78.41 19.44,78.41 19.22,78.19 19.22,76.59 19.11,76.48 ; 5 cut-outs
GND on TOP: 52.11,27.97 51.37,28.71 51.07,29 51.07,31.16 51.79,31.88 52.57,31.88 53.02,31.42 57.64,31.42 57.95,31.11 57.95,29.49 57.17,28.7 54.04,28.7 53.31,27.97 ; 6 cut-outs
GND on TOP: 183.08,88.34 182.81,88.61 182.81,89.59 183.06,89.85 185.34,89.85 185.41,89.78 185.41,88.37 185.38,88.34
GND on TOP: outline of 113 points within 124.44,139.45 199.59,187.24 ; 15 cut-outs
GND on TOP: 146.82,120.26 146.16,120.92 145.98,120.92 145.84,121.06 145.84,121.7 145.75,121.79 145.07,121.79 144.81,122.05 144.81,123.09 145.19,123.47 146.18,123.47 146.24,123.42 146.24,122.84 146.57,122.51 146.57,122.07 146.82,121.82 147.43,121.82 147.96,122.35 148.9,122.35 149.08,122.18 149.08,121.26 148.95,121.13 148.19,121.13 147.91,120.86 147.91,120.47 147.7,120.26 ; 5 cut-outs
GND on TOP: 189.5,76.91 189.31,77.1 189.31,79.79 190.16,80.65 191.45,80.65 191.78,80.32 191.78,78.79 191.73,78.74 191.73,77.17 191.47,76.91
GND on TOP: 161.9,136.61 161.78,136.73 161.78,139.3 161.94,139.45 162.59,139.45 162.81,139.67 162.81,140.15 162.9,140.24 163.47,140.24 163.54,140.17 163.54,137.82 163.8,137.56 165.57,137.56 165.73,137.4 165.73,136.87 165.53,136.68 164.52,136.68 164.24,136.4 163.65,136.4 163.44,136.61 ; 6 cut-outs
GND on TOP: 98.34,104.46 96.22,106.57 96.22,120.09 96.23,120.1 96.23,121.23 97.05,122.05 99.14,122.05 99.45,121.74 99.45,120.19 99.45,120.18 99.45,118.96 99.58,118.83 99.58,107.57 99.04,107.03 99.04,104.61 98.89,104.46 ; 14 cut-outs
GND on TOP: outline of 253 points within 2.08,110.54 118.6,187.24 ; 32 cut-outs
GND on TOP: 106.04,182.49 106.03,182.5 106.03,183.48 106.13,183.58 108.2,183.58 108.34,183.44 108.34,182.57 108.25,182.49
GND on TOP: 149.94,126.38 148.06,128.25 148.06,131.64 151.41,135 155.06,135 157.69,132.37 157.69,128.93 155.14,126.38
GND on TOP: 111.95,175.11 111.84,175.21 111.84,175.62 111.42,176.05 111.42,178.45 111.58,178.62 113.16,178.62 113.31,178.46 113.31,175.74 112.68,175.11 ; 3 cut-outs
GND on TOP: 104.23,18.23 104.09,18.38 104.09,19.73 104.45,20.09 104.45,21.01 104.65,21.21 105.27,21.21 105.7,20.77 105.7,19.23 105.64,19.17 105.14,19.17 104.82,18.85 104.82,18.31 104.74,18.23 ; 2 cut-outs
GND on TOP: 10.53,46.38 11.69,45.22 12.45,45.22 12.66,45.01 15.95,45.01 16.45,44.51 23.15,44.51 23.52,44.88 23.52,44.91 23.6,44.99 24.04,44.99 24.12,44.9 24.12,41.44 24.03,41.35 16.1,41.35 15.81,41.06 15.81,38.84 14.7,37.72 13.77,37.72 12.28,39.21 12.07,39.21 11.99,39.21 3.5,39.21 3.33,39.28 3.26,39.45 3.26,40.33 2.87,41.44 1.86,42.06 0.95,42.24 0.82,42.32 0.76,42.47 0.76,42.89 7.09,42.89 8.5,42.45 9.36,43.65 9.36,46.19 9.56,46.38 ; 13 cut-outs
GND on TOP: 135.62,122.8 135.14,123.29 135.14,128.03 135.57,128.46 137.61,128.46 137.91,128.17 137.91,123.61 137.09,122.8 ; 2 cut-outs
GND on TOP: 132.97,174.2 132.48,174.69 132.48,178.67 132.58,178.78 135.68,178.78 136.03,179.13 136.03,180.37 136.1,180.44 136.56,180.44 136.68,180.33 136.68,178.89 136.54,178.89 136.07,178.43 136.07,174.8 136,174.73 135.41,174.73 135.31,174.84 135.31,175.22 135.07,175.47 133.9,175.47 133.75,175.32 133.75,174.3 133.65,174.2 ; 10 cut-outs
GND on TOP: 105.48,175.16 105.29,175.35 105.29,176.58 105.63,176.92 106.69,176.92 106.89,176.71 106.89,175.33 106.73,175.16 ; 2 cut-outs
GND on TOP: outline of 270 points within 57.87,16.28 135.95,104.45 ; 210 cut-outs
GND on BOTTOM: 145.89,167.74 145.69,167.93 145.69,169.53 145.88,169.72 147.06,169.72 147.5,170.16 148.09,170.16 148.22,170.03 148.22,169.6 146.64,168.02 146.64,167.99 146.39,167.74
GND on BOTTOM: 148.97,32.79 148.64,33.12 148.64,35.59 148.61,35.62 148.61,37.65 148.94,37.98 149.76,37.98 149.93,37.81 149.93,37.58 149.36,37.01 149.36,35.78 149.85,35.28 149.85,34.46 150.43,33.88 150.43,33.08 150.13,32.79 ; 6 cut-outs
GND on BOTTOM: 128.83,117.72 132.45,117.72 133,117.17 133,110.21 132.78,110 128.92,110 128.68,110.24 128.68,117.01 128.68,117.56 ; 5 cut-outs
GND on BOTTOM: 136.13,37.99 135.67,38.44 135.67,41.05 135.99,41.38 136.78,41.38 136.88,41.28 136.88,41.27 139.15,39 139.15,38.88 139.14,38.88 139.14,38.11 139.02,37.99 ; 1 cut-out
GND on BOTTOM: outline of 336 points within 1.26,0.76 199.59,125.46 ; 31 cut-outs
GND on BOTTOM: 145.17,147.47 144,148.64 144,149.66 144.38,150.04 146.29,150.04 146.44,149.89 146.44,147.7 146.21,147.47 ; 2 cut-outs
GND on BOTTOM: 133.34,24.53 132.14,25.73 132.14,27.2 132.35,27.42 133.7,27.42 133.76,27.35 133.76,26.92 133.98,26.7 133.98,24.54 133.96,24.53 ; 1 cut-out
GND on BOTTOM: outline of 88 points within 132.04,89.44 139.71,96.9
GND on BOTTOM: 136.48,129.42 135.66,130.25 135.66,131.91 137.25,133.5 139.13,133.5 139.92,132.71 139.92,129.52 139.82,129.42
GND on BOTTOM: 136.94,46.2 136.9,46.24 131.38,46.24 131.33,46.29 131.33,50.88 131.42,50.97 134.88,50.97 135.68,50.17 135.68,49.58 137.35,47.91 137.35,46.41 137.14,46.2
GND on BOTTOM: 158.1,75.5 158.04,75.57 158.04,76.99 157.61,77.42 156.81,77.42 156.68,77.54 156.68,77.89 156.18,78.4 156.18,79.3 156.05,79.43 155.52,79.43 155.41,79.54 155.41,80.11 155.55,80.25 156.86,80.25 157.07,80.04 157.07,78.71 157.72,78.06 158.58,78.06 158.72,77.91 158.72,75.85 158.37,75.5 ; 4 cut-outs
GND on BOTTOM: 194.09,163.35 193.89,163.55 193.89,163.65 193.94,163.71 193.94,166.19 193.73,166.4 193.53,166.4 193.48,166.45 193.48,169.09 193.07,169.5 193.07,172.75 193.12,172.8 194.27,172.8 194.32,172.75 194.32,171.58 194.77,171.12 194.77,169.67 194.22,169.12 194.22,167.64 194.34,167.52 194.6,167.52 194.62,167.49 194.62,166.42 194.6,166.4 194.29,166.4 194.22,166.32 194.22,164.04 194.44,163.81 194.44,163.5 194.29,163.35 ; 2 cut-outs
GND on BOTTOM: 177.92,68.02 177.7,68.24 177.7,69.63 178.32,70.25 178.32,71.4 178.67,71.76 178.67,75.06 179.03,75.41 179.71,75.41 179.84,75.29 179.84,73.56 179.69,73.41 179.69,72.77 180.07,72.39 180.7,72.39 180.75,72.34 180.75,71.66 181.01,71.4 181.01,68.18 180.86,68.02 ; 3 cut-outs
GND on BOTTOM: 137.68,78.64 136.94,79.38 136.94,79.48 137.07,79.61 137.29,79.61 137.62,79.28 138.23,79.28 138.26,79.3 138.72,79.3 139.02,79 139.02,78.72 138.95,78.64
GND on BOTTOM: 137.32,89.16 136.53,89.94 136.53,90.63 136.81,90.91 137.19,90.91 138.36,89.74 138.87,89.74 139.05,89.56 139.05,89.31 138.89,89.16
GND on BOTTOM: 168.54,118.19 168.48,118.25 168.48,123.55 168.55,123.62 170.17,123.62 170.31,123.48 170.31,118.84 169.65,118.19 ; 3 cut-outs
GND on BOTTOM: 154.11,119.92 153.96,120.07 153.96,121.19 154.08,121.31 155.15,121.31 155.27,121.43 155.48,121.43 155.57,121.52 155.76,121.52 155.76,121.31 154.77,120.32 154.77,119.99 154.69,119.92 ; 2 cut-outs
GND on BOTTOM: 58.56,75.9 57.56,76.9 57.56,80.89 58.66,81.99 67.5,81.99 67.65,81.84 67.65,76.63 66.92,75.9
GND on BOTTOM: 52.14,28.85 51.64,29.35 51.64,31.94 52.37,32.66 55.86,32.66 56.21,32.31 56.21,31.77 55.77,31.32 53.87,31.32 53.47,30.92 53.47,29.13 53.18,28.85 ; 4 cut-outs
GND on BOTTOM: 27.81,71.2 27.44,71.56 27.44,72.8 27.08,73.17 27.08,74.42 27.26,74.61 27.65,74.61 27.76,74.49 27.76,74.09 27.95,73.91 28.37,73.91 28.7,73.58 28.7,71.58 28.32,71.2 ; 4 cut-outs
GND on BOTTOM: 46.79,50.93 46.21,51.51 46.21,54.05 46.57,54.41 49.26,54.41 50.25,53.42 50.25,51.01 50.17,50.93
GND on BOTTOM: 127.91,81.22 127.49,81.64 127.49,81.71 126.85,82.35 126.55,82.35 126.4,82.5 126.4,82.76 126.55,82.91 126.8,82.91 127.34,82.37 127.74,82.37 127.98,82.13 127.98,81.68 128.16,81.5 128.16,81.27 128.11,81.22
GND on BOTTOM: 139.64,111.17 139.45,111.36 139.45,117.61 140.02,118.18 144.12,118.18 144.27,118.03 144.27,116.05 143.67,115.44 143.67,113.84 141,111.17 ; 2 cut-outs
GND on BOTTOM: 100.41,84.94 100.39,84.97 100.39,85.5 100.62,85.73 104.83,85.73 104.96,85.6 104.96,85.47 104.86,85.37 104.25,85.37 103.82,84.94
GND on BOTTOM: 130.04,22.24 129.92,22.37 129.92,24.84 130.07,24.98 131.98,24.98 132.38,24.58 132.38,22.31 132.32,22.24 ; 1 cut-out
GND on BOTTOM: 137.5,16.79 137.42,16.87 137.42,17.93 137.65,18.16 137.97,18.16 138.71,18.91 139.81,18.91 139.98,18.74 139.98,16.93 139.84,16.79 ; 3 cut-outs
GND on BOTTOM: 130.06,180.09 129.62,180.52 129.62,181.81 129.93,182.12 131.09,182.12 131.36,181.85 131.36,180.15 131.3,180.09 ; 3 cut-outs
GND on BOTTOM: 179.81,50.07 179.5,50.38 179.5,51.54 181.19,53.23 181.96,53.23 182.03,53.16 182.03,52.42 181.5,51.89 181.5,50.64 180.94,50.07 ; 1 cut-out
GND on BOTTOM: 80.75,64.04 77.3,67.49 77.3,68.53 79.66,70.9 83.09,70.9 83.26,71.07 83.26,73.78 83.91,74.42 85.24,74.42 85.54,74.12 85.54,71.89 85.39,71.74 85.39,65.53 83.9,64.04 ; 4 cut-outs
GND on BOTTOM: outline of 132 points within 127.57,85.05 132.94,99.02
GND on BOTTOM: 172.56,132.63 171.62,133.57 171.62,133.95 171.76,134.08 171.98,134.08 172.58,133.48 173.01,133.48 173.66,134.12 173.89,134.12 174.06,133.95 174.06,133.51 173.17,132.63
GND on BOTTOM: 99.55,123.28 99.45,123.38 99.45,123.87 99.28,124.04 98.27,124.04 98.11,124.2 98.11,125.77 98.25,125.92 101.31,125.92 102.2,126.81 106.37,126.81 106.52,126.66 106.52,124.8 106.31,124.6 105.25,124.6 105.09,124.44 105.09,123.8 105.06,123.78 104.93,123.78 104.88,123.83 104.88,124.42 104.71,124.6 101.62,124.6 101.06,124.04 101.06,124.04 100.3,123.28 ; 1 cut-out
GND on BOTTOM: 152.16,90.51 151.42,90.51 151.17,90.26 147.88,90.26 147.73,90.41 147.73,90.88 148,91.15 151.91,91.15 152.06,91 153.46,91 154.72,89.74 154.72,88.73 154.39,88.4 153.87,88.4 153.35,88.92 152.48,88.92 152.29,89.11 152.29,90.38
GND on BOTTOM: 182.98,86.29 182.37,86.9 182.37,88.67 182.16,88.88 182.16,89.7 182.33,89.86 183.1,89.86 183.82,89.14 183.82,86.73 183.38,86.29 ; 3 cut-outs
GND on BOTTOM: 138.76,24.51 138.6,24.68 138.6,30.31 138.25,30.66 137.42,30.66 137.2,30.88 137.2,31.66 139.08,33.54 139.08,35.83 140.2,36.95 144.91,36.95 145.15,36.7 145.15,27.75 145.12,27.72 142.47,27.72 139.26,24.51 ; 3 cut-outs
GND on BOTTOM: 89.61,92.87 89.44,93.04 87.38,93.04 86.76,93.66 86.76,97.85 84.95,99.66 84.95,101.39 87.79,104.23 92.68,104.23 95.33,101.57 95.33,98.35 92.12,95.14 91.24,95.14 90.51,94.41 90.51,92.98 90.4,92.87 ; 3 cut-outs
GND on BOTTOM: 162.52,102.81 162.08,103.25 162.08,103.47 162.45,103.84 162.45,104.3 162.54,104.39 162.88,104.39 163.5,103.78 163.8,103.78 163.86,103.72 163.86,102.91 163.76,102.81 ; 1 cut-out
GND on BOTTOM: 182.54,79.63 182.33,79.83 180.38,79.83 180.08,80.14 180.08,81.62 180.33,81.87 182.16,81.87 183.25,80.77 183.25,79.75 183.13,79.63 ; 1 cut-out
GND on BOTTOM: 164.38,101.7 164.25,101.84 164.25,103.03 164.37,103.16 165.98,103.16 166.96,104.14 167.72,104.14 168.03,104.45 168.03,106.97 168.4,107.34 168.4,108.89 168.58,109.07 168.58,109.41 168.58,109.41 168.58,110 168.89,110.31 170.55,110.31 170.72,110.48 170.72,111.53 170.77,111.58 174.03,111.58 175.6,110.01 179.12,110.01 179.59,109.54 179.59,104.99 179.42,104.82 173.22,104.82 173.04,104.64 173.04,103.78 172.83,103.57 168.57,103.57 168.17,103.17 168.17,102.12 167.75,101.7 ; 1 cut-out
GND on BOTTOM: 143.89,54.54 143.62,54.81 143.62,56.78 144.18,57.35 145.12,57.35 145.22,57.25 145.22,54.73 145.03,54.54 ; 3 cut-outs
GND on BOTTOM: 56.04,174.35 55.79,174.6 55.79,176.99 55.94,177.14 57.39,177.14 57.97,176.56 57.97,174.78 57.54,174.35
GND on BOTTOM: 174.32,118.78 174.02,119.08 174.02,122.25 174.18,122.4 175.5,122.4 175.7,122.2 177.88,122.2 179.46,120.63 179.46,119.18 179.06,118.78 ; 1 cut-out
GND on BOTTOM: outline of 139 points within 111.95,92.95 123.38,108.05 ; 4 cut-outs
GND on BOTTOM: 169.65,138.53 169.65,138.51 173.03,135.13 173.03,134.75 172.9,134.63 172.63,134.63 171.4,135.86 171.4,136.03 169.35,138.08 168.89,138.08 168.73,137.91 168.73,137.55 168.95,137.32 169.07,137.32 171.22,135.17 171.22,134.78 171.14,134.7 170.72,134.7 167.84,137.58 167.84,137.86 168.4,138.42 168.4,139 167.83,139.57 167.83,140.16 167.97,140.3 168.25,140.3 168.34,140.4 168.59,140.4 168.74,140.25 168.74,139.44
GND on BOTTOM: 140.73,151.17 140.64,151.26 140.64,152.63 140.57,152.69 139.83,152.69 139.7,152.83 135.96,152.83 135.88,152.9 135.88,153.34 135.47,153.76 135.47,154.51 135.67,154.71 141.27,154.71 141.78,154.2 141.78,151.6 141.87,151.51 142.6,151.51 142.61,151.5 142.61,151.19 142.59,151.17 ; 5 cut-outs
GND on BOTTOM: 105.52,175.06 105.34,175.23 105.34,175.83 105.47,175.96 105.47,176.92 105.52,176.97 106.74,176.97 106.81,176.91 106.81,175.89 106.94,175.76 106.94,175.34 106.66,175.06
GND on BOTTOM: 154.26,5.29 152.36,7.19 151.95,7.19 151.72,7.42 151.72,9.25 152.05,9.58 158.35,9.58 159.34,8.59 159.34,6.15 158.48,5.29
GND on BOTTOM: 45.03,17.05 44.86,17.22 44.86,20.9 45.63,21.67 45.63,23.08 45.7,23.15 47.83,23.15 48.22,22.76 48.22,17.17 48.1,17.05 ; 2 cut-outs
GND on BOTTOM: 163.81,15.62 163.61,15.83 163.61,16.48 164.37,17.25 165.34,17.25 165.47,17.11 165.47,17 165.35,16.88 165.35,16.55 164.42,15.62 ; 1 cut-out
GND on BOTTOM: 91.71,175.8 90.86,176.64 90.86,180.01 91.13,180.28 92.42,180.28 94.05,178.65 94.05,176.05 93.81,175.8
GND on BOTTOM: 125.39,165.52 125.2,165.71 125.2,167.36 126.09,168.25 126.09,169.78 126.63,170.31 132.62,170.31 133.53,169.4 133.53,166.84 133.43,166.73 129.5,166.73 129.29,166.52 129.29,165.58 129.23,165.52
GND on BOTTOM: 122.97,78.56 122.87,78.67 122.87,79.96 122.28,80.55 122.28,80.77 122.38,80.88 122.56,80.88 122.77,80.67 123.17,80.67 123.35,80.85 123.53,80.85 123.63,80.75 123.63,80.6 123.58,80.55 123.58,79.55 123.65,79.48 123.65,78.74 123.48,78.56
GND on BOTTOM: 133.38,79.28 133.31,79.35 133.31,79.61 133.79,80.09 134.09,80.09 134.63,80.62 134.63,81.03 135.14,81.54 135.14,81.82 134.93,82.02 133.84,82.02 132.95,81.13 132.42,81.13 132.27,81.28 132.27,81.41 132.61,81.75 132.61,82.55 132.37,82.79 132.37,83.44 132.61,83.68 132.61,84.58 133.48,85.45 134.12,85.45 134.45,85.12 134.45,84.71 134.68,84.48 134.68,84.15 134.45,83.92 134.45,83.59 134.63,83.42 137.52,83.42 138.02,82.92 138.02,82.27 138.28,82.01 139.02,82.01 139.15,81.89 139.15,81.21 139.07,81.13 137.91,81.13 137.64,81.4 137.64,81.63 137.74,81.73 137.74,82.01 137.61,82.14 137.24,82.14 136.71,81.61 136.18,81.61 136,81.43 136,80.44 135.82,80.27 135.26,80.27 135.02,80.02 134.69,80.02 134.07,79.4 133.87,79.4 133.74,79.28
GND on BOTTOM: 117.56,101.53 117.56,102.44 117.84,102.72 118.57,102.72 118.93,102.36 118.93,101.65 118.8,101.53 ; 2 cut-outs
GND on BOTTOM: 135.84,125.29 135.66,125.47 135.66,128.19 135.82,128.35 137.53,128.35 137.78,128.1 137.78,125.6 137.78,125.6 137.78,125.33 137.74,125.29
GND on BOTTOM: 93,107.47 92.14,108.33 92.14,115.85 93.41,117.12 93.41,117.13 93.9,117.63 93.9,134.57 94.17,134.84 96.38,134.84 96.85,134.37 96.85,119.91 96.79,119.85 96.79,118.23 97.61,117.4 97.72,117.4 98.08,117.04 98.08,110.67 99.07,109.67 103.94,109.67 104.12,109.49 104.12,107.98 103.61,107.47 ; 3 cut-outs
GND on BOTTOM: 187.76,121.52 187.6,121.67 187.6,123.26 187.34,123.52 186.55,123.52 185.15,123.52 184.81,123.87 184.81,125.39 184.92,125.5 185.33,125.5 186.08,124.75 186.96,124.75 186.97,124.74 187.57,124.74 189.03,123.27 189.03,122.68 188.45,122.1 188.45,121.67 188.3,121.52 ; 5 cut-outs
GND on BOTTOM: 105.66,101.31 105.6,101.37 105.6,102.38 105.72,102.5 106.67,102.5 107,102.18 107,101.37 106.94,101.31 ; 2 cut-outs
GND on BOTTOM: 174.12,137.04 171.64,139.52 171.64,139.77 171.75,139.88 171.98,139.88 174.43,137.43 174.43,137.19 174.28,137.04
GND on BOTTOM: 165.28,25.24 165.04,25.47 165.04,27.08 165.52,27.55 166.99,27.55 167.33,27.9 167.33,28.64 167.39,28.7 168.83,28.7 168.94,28.58 168.94,27.88 169.27,27.55 170.56,27.55 171.41,28.41 171.69,28.41 171.8,28.3 171.8,27.91 171.53,27.64 171.53,26.88 171.4,26.76 167.7,26.76 167.4,26.45 167.4,25.53 167.4,25.37 167.26,25.24 ; 8 cut-outs
GND on BOTTOM: 119.74,78.49 119.08,79.15 119.08,80.37 118.93,80.37 118.57,80.72 118.32,80.72 118.12,80.52 118.12,79.99 118.02,79.89 117.56,79.89 116.87,80.57 116.87,80.88 117.3,81.31 117.63,81.31 117.81,81.13 118.09,81.13 118.24,81.28 118.55,81.28 118.73,81.1 118.93,81.1 119.16,81.33 119.44,81.33 119.69,81.08 119.9,81.08 120.02,81.21 120.02,82.78 120.09,82.84 120.39,82.84 120.45,82.78 120.45,81.23 120.81,80.88 121.65,80.88 121.77,80.75 121.77,79.91 121.75,79.89 121.47,79.89 121.27,80.09 120.99,80.09 120.39,80.69 119.95,80.24 119.95,78.89 120.05,78.79 120.05,78.56 119.97,78.49
GND on BOTTOM: 126.92,75.86 126.79,75.99 126.79,76.14 127.04,76.4 127.04,76.83 126.76,77.11 124.4,77.11 124.28,77.24 124.28,77.36 124.38,77.46 124.94,77.46 125.49,78.02 125.49,78.33 125.95,78.78 125.95,79.96 125.75,79.96 125.36,80.35 125.36,80.97 125.11,80.97 124.94,80.79 124.68,80.79 124.09,81.38 123.8,81.38 123.71,81.47 123.71,82.88 123.86,83.03 124.07,83.03 124.28,82.81 124.28,82.66 124.98,81.96 125.93,81.96 126.28,81.6 126.28,81.58 126.36,81.5 126.36,78.58 126.08,78.3 126.05,78.3 125.98,78.23 125.98,77.95 126.46,77.46 127.09,77.46 127.4,77.16 127.4,76.24 127.02,75.86
GND on BOTTOM: 161.14,120.03 160.84,120.33 160.84,121.46 160.51,121.8 158.86,121.8 158.64,122.01 158.64,122.76 159.51,123.63 162.58,123.63 162.63,123.58 162.63,120.11 162.55,120.03 ; 2 cut-outs
GND on BOTTOM: 110.28,140.1 110.19,140.18 110.19,141.27 110.73,141.81 111.3,141.81 111.83,141.28 112.19,141.28 112.23,141.23 112.23,140.2 112.13,140.1
GND on BOTTOM: 175.51,137.53 173.63,139.41 173.63,139.79 173.7,139.87 174.08,139.87 174.67,139.28 175.05,139.28 175.66,139.89 175.91,139.89 176.17,139.64 176.17,137.76 175.94,137.53
GND on BOTTOM: 161.45,53.76 160.96,54.25 160.96,57.3 161.09,57.43 161.12,57.43 161.27,57.58 162.08,57.58 163.81,59.31 163.81,62.79 164.02,62.99 166.15,62.99 166.48,62.66 166.48,58.83 163.58,55.93 162.36,55.93 162.09,55.66 162.09,53.86 161.98,53.76 ; 6 cut-outs
GND on BOTTOM: 151.06,122.51 150.6,122.96 150.6,123.4 150.81,123.6 151.93,123.6 152.09,123.44 152.09,122.77 151.83,122.51
GND on BOTTOM: 148.43,16.18 148.38,16.22 148.38,17.51 148.97,18.1 148.97,18.29 149.09,18.41 149.49,18.41 149.62,18.28 149.62,17.82 149.79,17.64 149.79,16.3 149.67,16.18 ; 3 cut-outs
GND on BOTTOM: 86.6,146.33 85.73,147.2 85.73,148.19 85.88,148.34 86.47,148.34 86.6,148.21 88.65,148.21 89.44,147.42 89.44,146.51 89.26,146.33
GND on BOTTOM: 140.09,95.38 139.96,95.51 139.96,95.76 140.06,95.86 140.06,96.12 139.61,96.57 139.61,98.5 141.13,100.03 141.13,100.89 144.49,104.24 147.58,104.24 150.06,101.76 150.06,98.87 149.94,98.76 149.94,97.98 147.61,95.65 140.74,95.65 140.47,95.38
GND on BOTTOM: 127.01,92.48 126.91,92.59 126.91,93.52 126.35,94.08 126.14,94.08 125.53,94.69 125,94.69 124.52,94.21 124.52,94.19 124.37,94.03 123.53,94.03 123.15,93.65 123.15,93.07 123.04,92.97 122.92,92.97 122.82,93.07 122.82,93.63 122.69,93.75 122.69,93.88 122.71,93.88 122.71,94.16 122.78,94.22 123.11,94.22 123.68,94.79 123.68,95.1 124.37,95.79 124.37,96.27 124.75,96.65 125.92,96.65 126.19,96.93 126.19,97.67 126.19,97.67 125.88,97.97 125.88,98.24 126.01,98.36 126.34,98.36 126.8,97.9 126.8,97.08 127.26,96.62 127.26,95.71 127.31,95.66 127.41,95.66 128.12,94.95 128.12,94.72 128.1,94.69 127.59,94.69 127.38,94.91 127.16,94.69 127.16,94.46 127.31,94.31 127.31,94.21 127.19,94.08 127.19,93.75 127.26,93.68 127.26,92.56 127.19,92.48
GND on BOTTOM: 108.98,107.52 108.47,108.03 108.47,111.81 108.5,111.84 108.5,114.92 108.59,115.01 109.07,115.01 109.09,114.99 109.26,114.99 110.98,113.27 112.36,113.27 112.57,113.06 112.57,108.07 112.02,107.52 ; 4 cut-outs
GND on BOTTOM: 195.15,135.16 194.98,135.32 194.43,135.32 194.33,135.43 194.33,136.65 194.49,136.81 194.75,136.81 194.93,137 194.93,139.09 194.4,139.63 194.4,140.17 194.51,140.28 195.1,140.28 195.86,141.04 195.86,143.55 195.75,143.66 195.27,143.66 195.24,143.7 195.24,144.17 194.58,144.82 193.67,144.82 193.59,144.75 193.59,142.27 191.18,139.85 187.47,139.85 185.07,142.25 185.07,145.72 186.06,146.71 186.06,150.7 186.49,151.13 195.74,151.13 196.41,150.46 196.41,150.28 196.41,150.28 196.41,135.67 196.4,135.66 196.4,135.43 196.12,135.16 ; 19 cut-outs
GND on BOTTOM: 46.63,172.59 46.29,172.93 46.29,175.89 46.39,175.99 50.45,175.99 50.64,175.81 50.64,172.71 50.51,172.59 ; 14 cut-outs
GND on BOTTOM: 92.22,171.24 92.03,171.42 92.03,173.36 92.29,173.62 93.88,173.62 94.44,173.06 94.44,171.5 94.18,171.24 ; 3 cut-outs
GND on BOTTOM: 171.69,68.82 171.41,69.1 171.41,70.59 171.33,70.66 170.59,70.66 170.37,70.44 170.37,69.93 170.19,69.75 166.81,69.75 166.63,69.93 166.63,73.28 166.73,73.38 167.62,73.38 169.14,71.86 173.94,71.86 174.22,71.58 174.22,69.1 173.93,68.82 ; 6 cut-outs
GND on BOTTOM: 104.72,142.59 104.61,142.7 104.61,144.15 104.9,144.43 108.24,144.43 108.56,144.11 108.56,144.1 108.8,143.87 108.8,143.64 108.8,143.64 108.8,143.04 108.35,142.59
GND on BOTTOM: 100.87,94.39 100.62,94.64 100.62,94.74 100.41,94.95 100.24,94.95 100.11,95.07 100.11,95.38 100.24,95.51 101,95.51 101.12,95.38 101.12,94.49 101.02,94.39
GND on BOTTOM: 21.58,70.54 20.92,71.2 20.92,73.08 20.98,73.13 21.71,73.13 21.86,72.99 21.86,72.07 22.3,71.63 24.52,71.63 24.57,71.58 24.57,70.79 24.32,70.54 ; 5 cut-outs
GND on BOTTOM: 123.45,123.47 123.4,123.52 123.4,124.24 123.3,124.34 119.97,124.34 119.51,123.89 118.67,123.89 118.2,124.36 116.66,124.36 116.66,124.36 115.46,124.36 115.31,124.5 114.51,124.5 114.41,124.4 114.41,123.67 114.36,123.62 114.26,123.62 114.21,123.67 114.21,124.45 114.15,124.5 110.94,124.5 110.03,123.59 109.23,123.59 109.13,123.69 109.13,124.2 108.91,124.41 107.44,124.41 107.23,124.62 107.23,125.7 107.35,125.82 110.63,125.82 111.52,126.71 115.69,126.71 116.79,125.61 119.74,125.61 120.74,126.61 124.73,126.61 126.95,128.84 126.95,128.85 127.36,129.25 128.59,129.25 130.35,127.5 130.35,124.37 130.12,124.14 126.11,124.14 125.91,124.34 123.66,124.34 123.6,124.28 123.6,123.55 123.53,123.47 ; 3 cut-outs
GND on BOTTOM: outline of 133 points within 2.08,148.6 118.59,187.24 ; 6 cut-outs
GND on BOTTOM: outline of 115 points within 124.54,168.05 199.39,187.24 ; 42 cut-outs
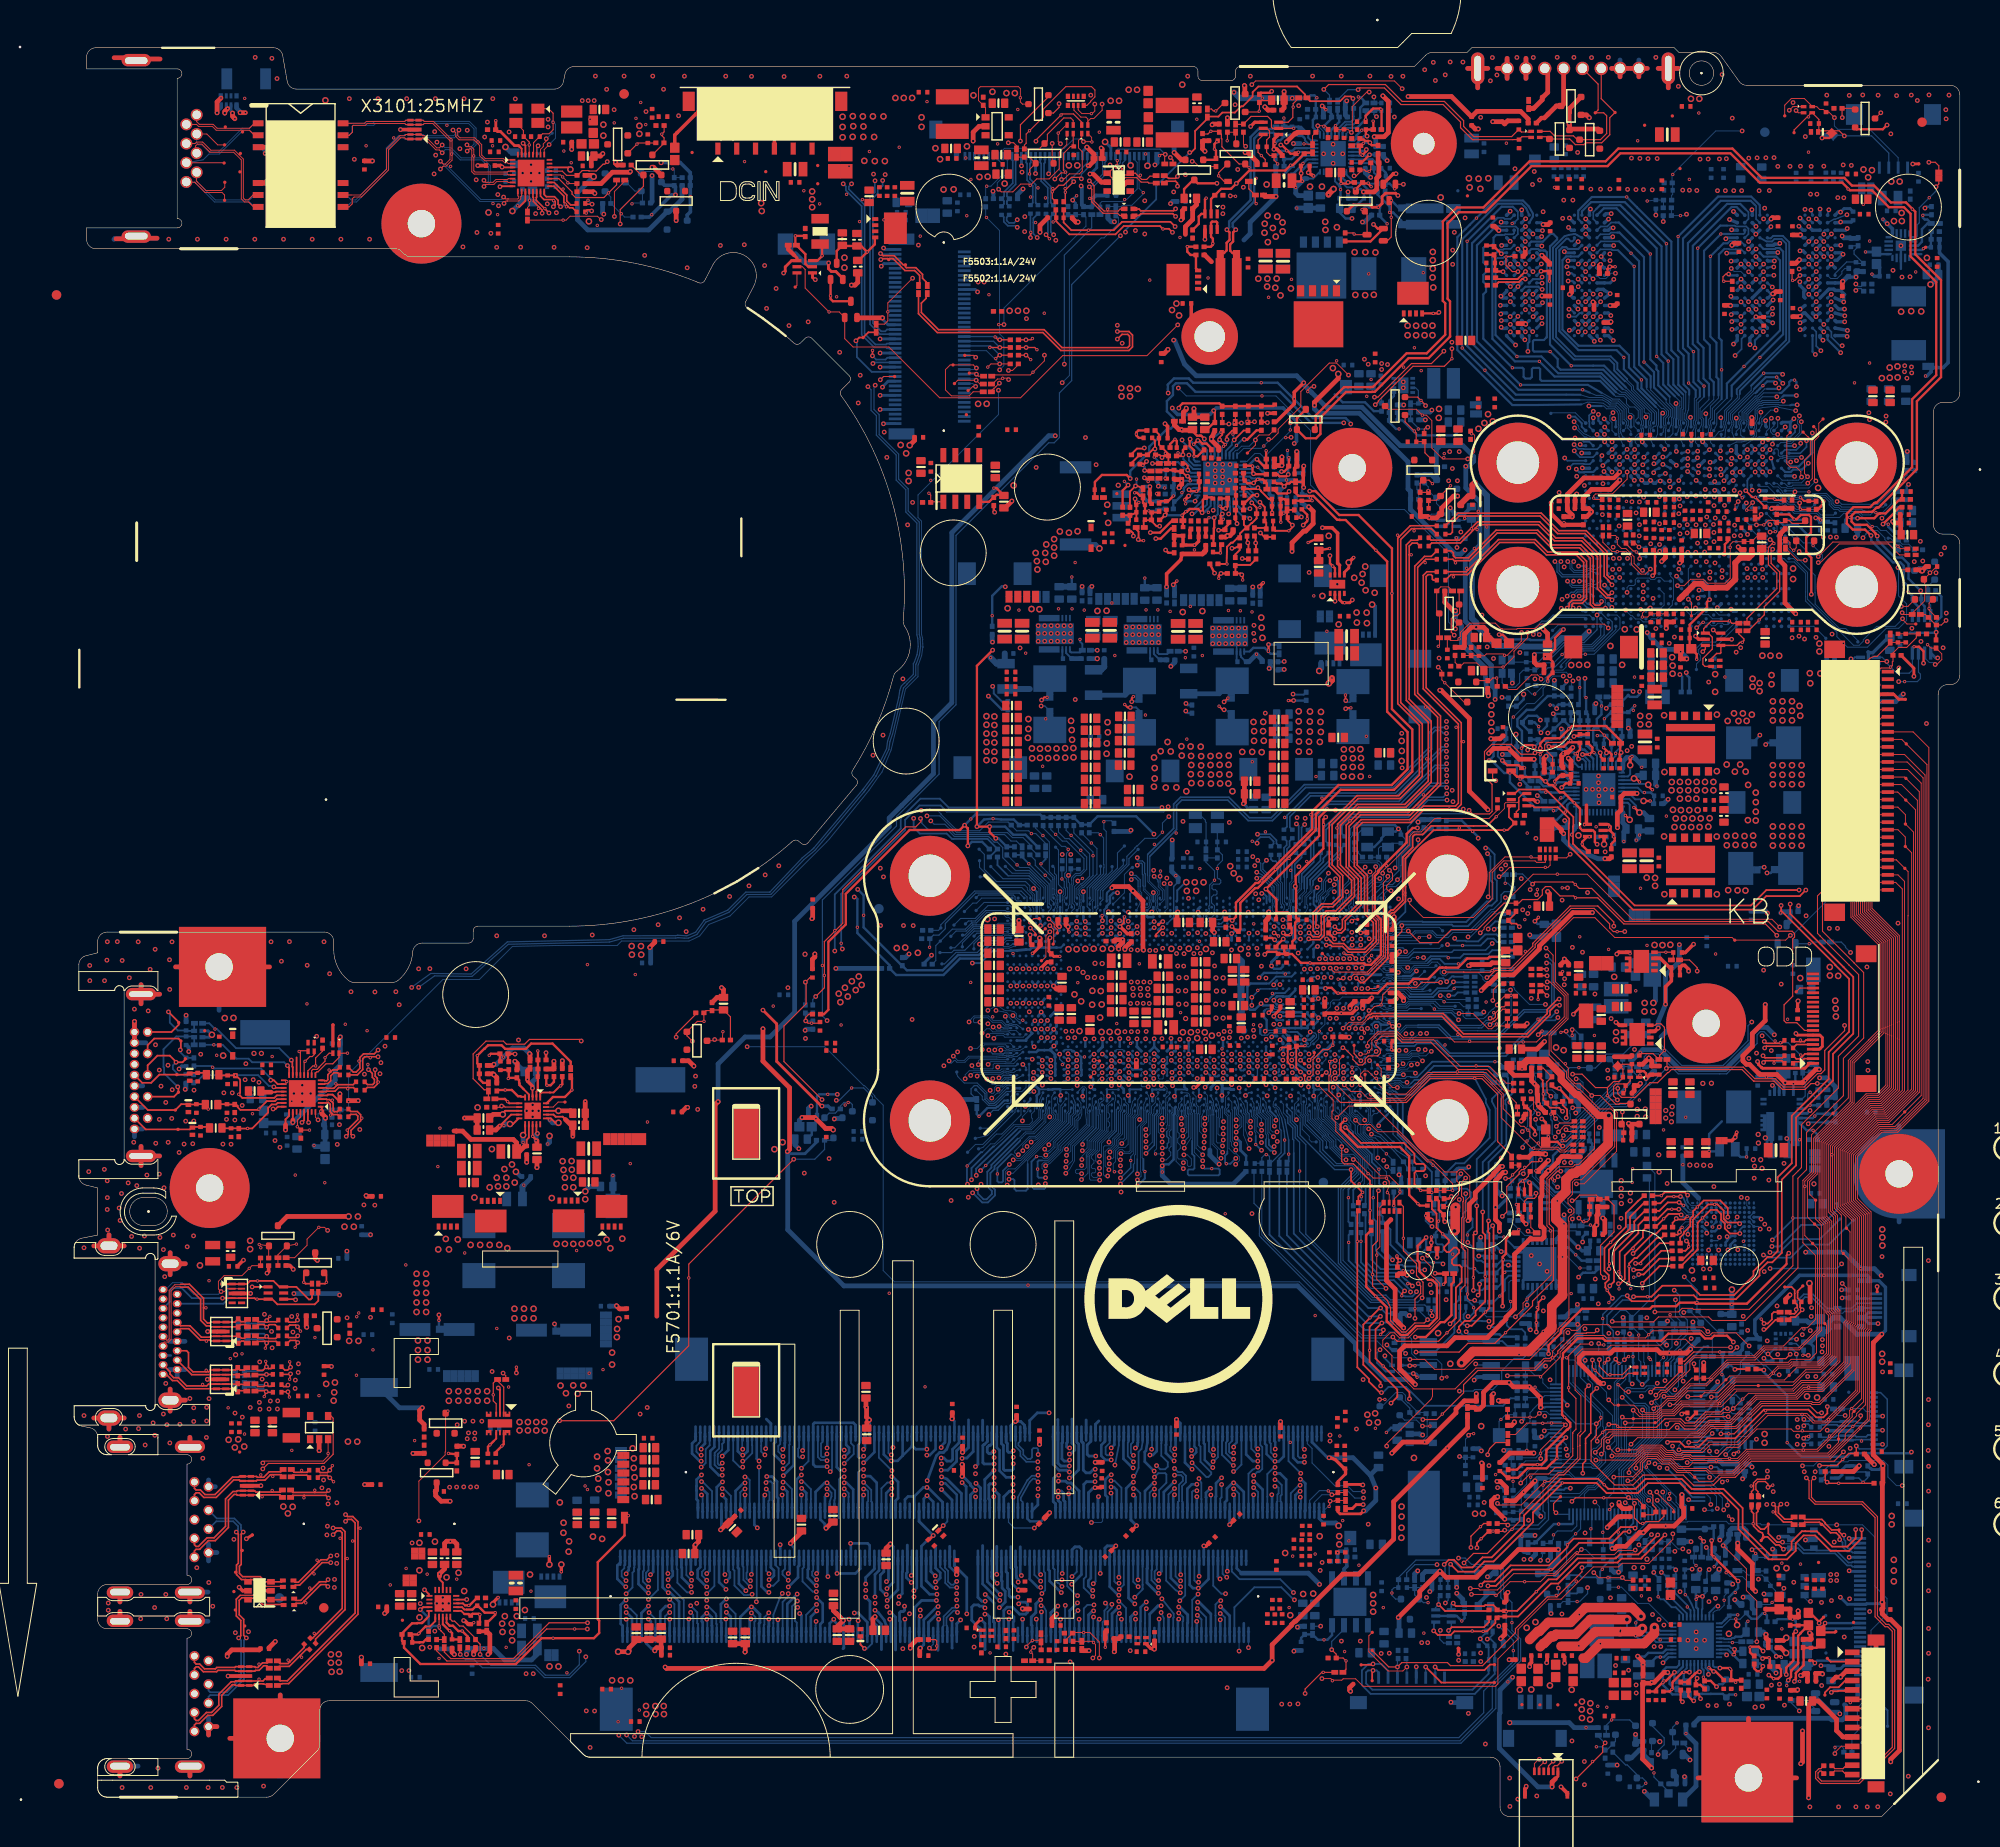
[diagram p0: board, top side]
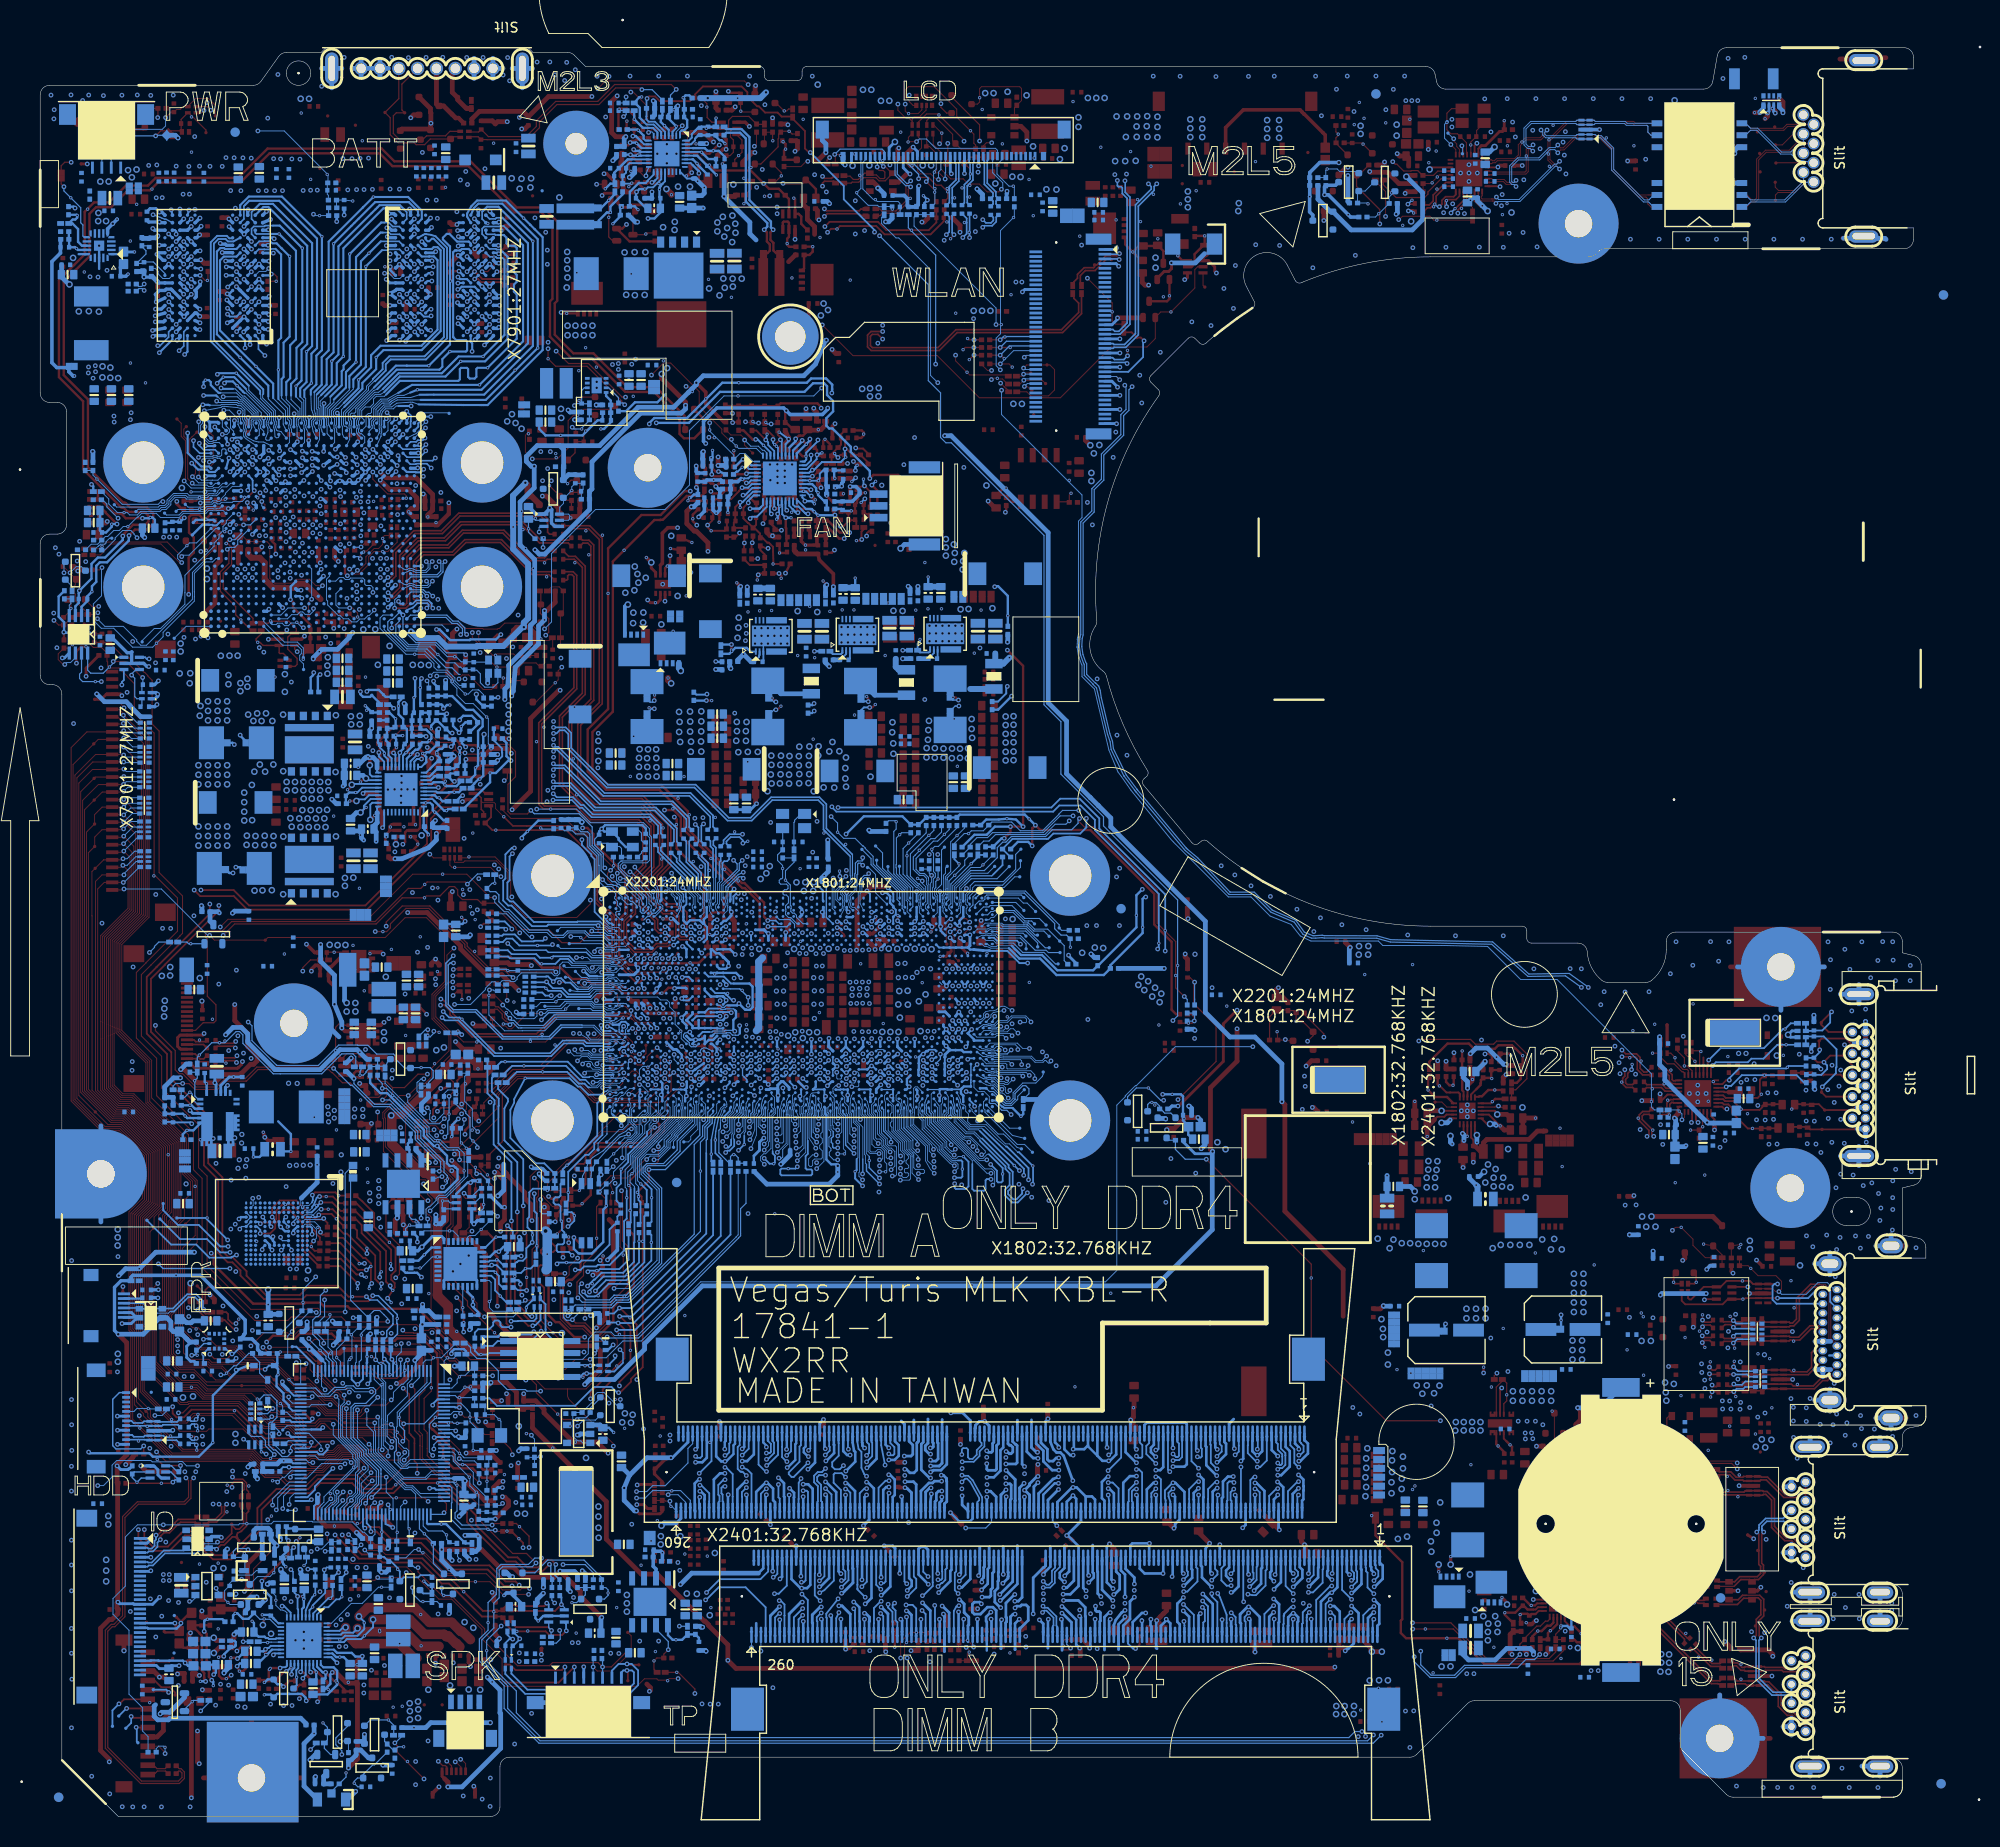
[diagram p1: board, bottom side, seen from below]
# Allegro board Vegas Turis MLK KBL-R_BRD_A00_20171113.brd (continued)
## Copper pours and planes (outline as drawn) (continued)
GND on BOTTOM: 178.76,130.32 175.58,133.49 175.58,134.38 174.78,135.17 174.23,135.17 173.41,135.99 173.22,135.99 171.62,137.59 171.62,137.7 170.83,138.49 170.83,138.76 170.94,138.87 171.13,138.87 174.39,135.61 174.89,135.61 175.35,136.08 175.93,136.08 176.24,135.76 176.24,135.34 176.39,135.2 176.96,135.2 177.07,135.08 177.07,133.01 177.23,132.85 177.69,132.85 177.7,132.87 179.42,132.87 179.64,133.09 179.87,133.09 180.31,132.65 180.31,131.37 179.26,130.32
GND on BOTTOM: 150.89,125.38 149.08,127.19 149.08,129.8 149.07,129.81 149.07,132.61 149.08,132.62 149.08,132.96 150.51,134.39 150.51,140.77 149.06,142.22 149.06,145.67 152.69,149.3 156.01,149.3 158.26,147.06 158.26,143.52 159.11,142.67 162.05,142.67 162.06,142.67 162.29,142.67 162.3,142.67 162.37,142.67 163.28,141.76 163.28,140.8 163.58,140.5 164.62,140.5 164.65,140.48 164.69,140.48 164.81,140.35 164.81,135.68 165.8,134.69 165.8,131.71 165.07,130.98 164.66,130.98 164.45,131.19 164.37,131.19 163.69,131.87 162.68,131.87 162.5,132.04 162.5,132.13 162.31,132.32 162.31,133.4 162.27,133.44 161.55,132.72 160.46,132.72 160.23,132.95 160.23,133.44 159.83,133.84 157.17,133.84 156.94,133.6 156.94,133.1 157.71,132.32 157.71,131.95 158.21,131.44 158.21,128.17 158.11,128.06 156.8,128.06 154.12,125.38
GND on BOTTOM: 159.89,89 159.54,89.35 159.54,91.8 159.75,92.01 160.41,92.01 161.51,90.9 163.84,90.9 164,90.74 164,89.11 163.89,89 ; 3 cut-outs
GND on BOTTOM: 170.71,80.14 168.81,82.04 168.81,82.18 165.47,82.18 164.77,81.47 164.71,81.47 164.4,81.17 162.54,81.17 161.58,80.2 159.37,80.2 158.88,80.7 158.88,82.63 158.14,83.37 158.14,84.83 158.61,85.3 162.24,85.3 162.67,84.87 162.97,84.87 164.19,83.65 167.98,83.65 169.65,85.32 169.65,89.19 171.96,91.5 171.96,92.15 172.19,92.38 172.19,92.64 172.5,92.95 173.69,92.95 176.09,90.55 176.09,87.54 177.29,86.35 177.29,85.79 177.71,85.36 177.71,82.63 175.22,80.14 ; 14 cut-outs
GND on BOTTOM: 188.79,13.54 188.57,13.77 185.34,13.77 185.1,14 185.1,15.13 185.34,15.37 185.95,15.37 186.18,15.14 187.6,15.14 188.18,15.72 190.45,15.72 190.56,15.61 190.56,14.02 190.08,13.54 ; 6 cut-outs
GND on BOTTOM: 185.39,135.71 185.24,135.85 185.24,136.97 185.32,137.05 186.58,137.05 186.64,136.98 186.64,136.34 186.81,136.17 186.81,135.83 186.69,135.71 ; 1 cut-out
GND on BOTTOM: 166.17,112.78 166.07,112.88 164.95,112.88 164.78,113.06 164.78,114.02 164.97,114.21 167.79,114.21 168.07,113.93 168.07,113.04 167.81,112.78
GND on BOTTOM: 143.52,67.85 142.91,68.46 142.91,68.96 143.06,69.12 143.31,69.12 143.85,68.58 143.85,67.97 143.72,67.85 ; 1 cut-out
GND on BOTTOM: 37.81,47.24 37.81,47.24 33.38,47.24 31.36,49.27 31.36,52.21 31.94,52.79 34.12,52.79 34.25,52.65 37.79,52.65 38.05,52.39 38.05,49.36 38.05,49.35 38.05,47.29 38,47.24 ; 5 cut-outs
GND on BOTTOM: 157.85,49.6 157.67,49.78 157.67,50.49 157.67,50.49 157.67,51.75 157.76,51.84 158.96,51.84 159.19,51.61 159.19,50.33 159,50.15 158.57,50.15 158.34,49.92 158.34,49.75 158.2,49.6 ; 2 cut-outs
GND on BOTTOM: 161.69,22.57 161.34,22.92 161.34,23.46 161.58,23.7 164.75,23.7 164.98,23.47 164.98,22.85 164.69,22.57 ; 1 cut-out
GND on BOTTOM: 124.53,100.33 124.26,100.6 124.26,102.97 124.38,103.09 125.35,103.09 125.87,102.58 125.87,102.28 125.51,101.91 125.51,101.58 125.51,101.57 125.51,101.42 125.69,101.24 125.69,100.92 125.54,100.77 125.41,100.77 124.97,100.33 ; 6 cut-outs
GND on BOTTOM: 129.32,75.19 129.27,75.24 129.27,75.54 128.99,75.82 128.99,76.74 129.06,76.81 129.06,77.07 128.91,77.22 128.68,77.22 128.43,76.96 128.02,76.96 127.9,77.09 127.9,77.57 128.76,78.44 128.76,80.57 128.68,80.65 128.68,80.82 128.76,80.9 129.01,80.9 129.09,80.82 129.09,79.53 129.29,79.33 129.6,79.33 129.73,79.2 129.73,78.84 129.62,78.74 129.62,77.9 130.06,77.47 130.74,77.47 130.84,77.37 130.84,77.17 130.72,77.04 130.31,77.04 130.23,77.12 129.88,77.12 129.85,77.09 129.85,76.1 129.57,75.82 129.57,75.29 129.47,75.19
GND on BOTTOM: 184.06,43.99 183.88,44.17 183.88,46.43 183.64,46.66 182.88,46.66 182.63,46.92 182.63,47.52 182.75,47.65 184.19,47.65 185.51,48.96 185.93,48.96 186.24,48.66 186.24,44.15 186.09,43.99 ; 10 cut-outs
GND on BOTTOM: 185.27,64.46 185.27,65.56 185.05,65.79 185.05,66.58 184.54,67.08 184.54,67.57 184.64,67.67 186.11,67.67 186.51,67.27 186.51,64.85 186.11,64.46 ; 3 cut-outs
GND on BOTTOM: 135.67,85.12 135.47,85.32 135.47,85.45 135.26,85.65 135.26,86.16 135.41,86.31 135.41,86.54 135.26,86.69 133.79,86.69 133.66,86.57 133.08,86.57 132.32,87.33 132.32,87.66 132.42,87.76 132.7,87.76 132.82,87.63 133.05,87.63 133.38,87.96 133.38,88.67 133.59,88.88 134.47,88.88 135.14,88.22 135.14,87.81 135.77,87.17 136.53,87.17 136.63,87.28 136.63,87.66 136.56,87.73 136.56,88.04 136.71,88.19 136.99,88.19 137.12,88.06 137.12,87.84 137.73,87.23 139.05,87.23 139.17,87.1 139.17,86.82 138.97,86.62 137.78,86.62 137.7,86.69 136.18,86.69 135.95,86.46 135.95,85.17 135.9,85.12
GND on BOTTOM: 47.82,74.12 47.81,74.12 47.81,75.86 47.84,75.88 49.59,75.88 49.59,74.12
GND on BOTTOM: 183.3,22.43 182.94,22.79 182.94,24.46 183.39,24.9 184.22,24.9 184.87,24.25 186.14,24.25 186.16,24.23 186.16,23.6 186.58,23.18 187.05,23.18 187.21,23.02 187.21,22.6 187.06,22.45 184.2,22.45 184.18,22.43
GND on L2: 145.4,84.57 140.41,84.57 139.81,83.96 134.76,83.96 134.01,84.71 134.01,85.38 134.21,85.59 139.35,85.59 139.56,85.79 141.2,85.8 146.2,85.8 148.48,83.52 154.04,83.52 156.18,85.66 156.18,86.46 157.25,87.53 157.67,87.53 158.17,87.03 158.17,86.14 154.65,82.62 147.35,82.62
GND on L2: outline of 506 points within 0.76,0.76 199.59,187.24 ; 3 cut-outs
GND on L2: 134.42,74.82 163.32,74.82 167.68,79.19 167.68,86.93 169.44,88.69 173.72,88.69 176.07,86.34 176.07,79.06 180.61,74.52 180.61,69.77 179.49,68.65 176.43,68.65 165.91,58.12 163.87,58.12 163.79,58.21 161.9,58.21 155.05,51.36 155.05,42.85 155.76,42.14 156.83,42.14 157.59,42.9 157.59,45.14 158.2,45.75 163.55,45.75 164.32,44.98 177.02,44.98 177.96,45.92 177.96,53.11 179.39,54.54 188.11,54.54 189.43,53.23 189.43,24.52 188.06,23.15 176.02,23.15 174.21,21.34 174.21,17.2 173.98,16.96 165.85,16.96 165.51,17.31 164.43,17.31 164.33,17.21 164.33,14.08 163.6,13.36 158.75,13.36 157.24,11.85 152.53,11.85 149.79,14.59 141.31,14.59 139.09,12.36 130.35,12.36 128.9,13.82 71.87,13.82 70.76,14.93 70.76,18.61 71.87,19.72 89.85,19.72 90.56,19.01 94.22,19.01 94.94,19.72 122.72,19.72 134.55,31.56 134.55,46.52 135.49,47.46 135.49,70.58 134.33,71.74 134.33,74.73
GND on L3: 45.88,25.47 53,25.47 53.42,25.05 53.42,19.83 53.25,19.65 48.19,19.65 47.16,18.63 44.99,18.63 44.4,19.22 44.4,21.46 45.27,22.32 45.27,24.86
GND on L3: 140.09,181.58 146.56,181.58 147.5,180.64 147.5,176.29 147.15,175.93 142.53,175.93 139.82,178.65 139.82,181.31
GND on L3: 123.58,158.39 123.58,156.08 122.8,155.31 119.4,155.31 118.56,156.15 118.56,160.39 118.57,160.4 118.57,160.78 118.77,160.98 120.98,160.98
GND on L3: 134.96,145.11 136.47,145.11 137.54,144.04 137.54,141.73 136.9,141.09 135.19,141.09 134.13,142.15 134.13,144.28
GND on L3: 26.97,181.57 26.6,181.93 23.27,181.93 21.08,184.13 21.08,186.14 20.51,186.72 19.03,186.72 18.84,186.91 18.84,187.1 18.98,187.24 21.17,187.24 21.32,187.18 21.4,187.04 21.89,184.29 22.49,183.25 23.62,182.84 51.01,182.84 52.12,183.23 52.73,184.24 52.9,185.05 52.98,185.18 53.13,185.24 118.55,185.24 118.55,184.91 65.35,184.91 64.4,183.97 53.97,183.97 52.91,182.24 51.01,181.57
GND on L3: 154.84,39.83 154.46,39.45 150.72,39.45 150.45,39.72 150.45,41.93 150.81,42.29 154.54,42.29 154.84,41.99
GND on L3: 170.39,178.54 169.2,179.73 169.2,183.57 168.2,184.57 168.2,186.77 168.01,186.97 163.36,186.97 162.99,186.61 155.76,186.61 155.49,186.34 155.49,181.32 155.15,180.97 151.8,180.97 150.25,182.53 144.1,182.53 141.97,184.66 124.23,184.66 124.23,185.24 142.72,185.24 144.15,186.67 144.22,186.72 144.31,186.74 148.32,186.74 148.82,187.24 169.68,187.24 170.18,186.74 174.19,186.74 174.29,186.71 174.38,186.64 176.28,183.98 176.91,183.43 177.71,183.24 199.35,183.24 199.52,183.17 199.59,183 199.59,179.85 198.99,179.25 198.48,179.25 195.56,182.17 186.8,182.17 186.16,182.81 182.58,182.81 182.46,182.68 182.46,182.11 181.67,181.33 181.6,181.33 180.73,180.45 175.93,180.45 174.01,178.54
GND on L3: outline of 267 points within 0.76,0.76 197.29,171.02
GND on L3: 133.11,117.33 133.11,112.59 132.33,111.81 129.95,111.81 129.49,112.27 129.49,117.58 129.85,117.93 132.5,117.93
GND on L3: 190.07,125.44 190.07,124.69 190.21,124.55 190.71,124.55 190.78,124.61 190.78,128.85 191.97,130.04 191.97,133.3 190.93,134.34 187.53,134.34 186.51,133.31 186.51,129.01
GND on L3: 174.23,17.05 174.03,16.85 170.73,16.85 170.44,17.14 170.44,20.53 170.54,20.63 174.07,20.63 174.23,20.48
GND on L3: 121.01,126.7 124.95,126.7 125.13,126.88 125.43,126.88 125.67,126.64 125.67,124.52 125.39,124.25 121,124.25 120.7,124.54 120.7,126.39
GND on L3: 102.06,126.98 106.48,126.98 106.69,126.77 106.69,124.78 106.45,124.53 102,124.53 101.86,124.67 101.86,126.79
GND on L3: 111.42,126.94 115.84,126.94 116.05,126.72 116.05,124.73 115.81,124.48 111.36,124.48 111.22,124.62 111.22,126.75
GND on L3: 87.42,181.14 88.35,180.2 88.35,175.25 87.99,174.89 80.72,174.89 80.38,175.24 80.38,180.86 80.66,181.14
GND on L4: 47.1,176.77 49.94,176.77 50.32,176.39 50.32,173.58 49.53,172.8 47.06,172.8 46.76,173.1 46.76,176.43
GND on L4: 199.42,178.16 196.47,181.11 193.86,181.11 193,181.97 193,181.97 192.39,182.58 185.2,182.58 184.87,182.91 174.81,182.91 174.18,183.54 170.15,183.54 169.6,184.09 168.91,184.09 168.13,184.86 150.37,184.86 149.93,184.41 149.62,184.1 142.27,184.1 141.71,184.66 124.47,184.66 124.34,184.79 124.34,185.08 124.49,185.24 142.72,185.24 144.15,186.67 144.22,186.72 144.31,186.74 148.32,186.74 148.82,187.24 169.68,187.24 170.18,186.74 174.19,186.74 174.29,186.71 174.38,186.64 176.28,183.98 176.91,183.43 177.71,183.24 199.35,183.24 199.52,183.17 199.59,183 199.59,178.17 199.58,178.16
GND on L4: outline of 264 points within 0.76,0.76 199.59,171.04
GND on L4: 85.07,98.83 86.52,97.39 92.03,97.39 93.56,98.91 93.56,101.12 92.16,102.52 85.78,102.52 85.07,101.81
GND on L4: 192.03,131.96 192.03,128.63 191.55,128.15 188.19,128.15 186.08,130.25 186.08,131.43 187.88,133.23 190.75,133.23
GND on L4: 174.03,20.61 174.21,20.42 174.21,16.91 174.18,16.87 170.54,16.87 170.45,16.96 170.45,20.56 170.5,20.61
GND on L4: 133.67,108.59 132.9,107.82 129.33,107.82 128.51,108.64 128.51,119.89 130.89,122.27 132.74,122.27 133.67,121.33
GND on L4: 155.64,126.99 155.86,127.2 155.86,133.28 155.03,134.11 150.2,134.11 148.92,132.84 148.92,127.57 149.51,126.99
GND on L4: 85.8,183.4 88.62,180.58 88.62,178.76 88.07,178.2 80.33,178.2 79.58,178.95 79.58,182.78 80.21,183.4
GND on L4: 62.32,19.91 85.02,19.91 86.21,18.73 86.58,18.73 89.26,16.05 100.65,16.05 101.88,17.27 122.6,17.27 122.63,17.3 124.37,17.3 125.28,18.21 125.28,18.67 124.19,19.76 121.57,19.76 120.84,20.5 120.84,25.83 121.6,26.6 126.37,26.6 127.36,25.61 127.36,17.53 123.83,13.99 65.3,13.99 60.83,18.46 60.83,18.49 58.1,21.23 58.1,26.32 58.07,26.34 58.53,26.8 61.07,26.8 61.73,26.14 61.73,20.5
GND on L4: 154.83,39.87 154.41,39.46 150.75,39.46 150.44,39.77 150.44,41.88 150.79,42.23 154.39,42.23 154.83,41.79
GND on L4: 27,181.57 26.65,181.92 22.89,181.92 21.14,183.66 21.14,185.42 19.92,186.64 19.01,186.64 18.83,186.82 18.83,187.1 18.97,187.24 21.17,187.24 21.32,187.18 21.4,187.04 21.89,184.29 22.49,183.25 23.62,182.84 51.01,182.84 52.12,183.23 52.73,184.24 52.9,185.05 52.98,185.18 53.13,185.24 82.25,185.24 82.4,185.08 82.4,184.76 82.25,184.61 70.21,184.61 69.57,183.97 53.97,183.97 52.91,182.24 51.01,181.57
GND on L5GND: outline of 220 points within 0.76,0.76 199.59,187.24 ; 1 cut-out
VCC_CORE on TOP: 120.73,81.03 120.66,81.1 120.66,81.99 120.43,82.22 117.55,82.22 116.68,83.09 116.41,83.09 116.34,83.16 116.34,84.66 116.01,84.99 116.01,89.87 115.78,90.1 115.78,91.51 115.7,91.59 115.7,91.83 114.94,92.59 114.5,92.59 113.82,93.27 113.82,100.74 114.78,101.69 114.78,105.01 112.84,106.95 112.84,107.1 112.8,107.13 112.8,110.57 111.85,111.52 111.85,117.27 112.5,117.92 126.51,117.92 127.71,116.72 127.71,103.78 125.25,101.32 125.25,100.02 123.86,98.63 123.86,97.67 123.17,96.98 123.17,95.86 122.99,95.68 122.05,95.68 121.9,95.53 121.9,95.15 122.11,94.95 122.49,94.95 122.77,94.67 122.77,94.21 122.28,93.73 122,93.73 121.46,93.18 121.46,91.99 121.01,91.54 119.84,91.54 119.54,91.24 119.54,83.97 119.74,83.76 121.36,83.76 121.84,83.29 121.84,82.58 121.83,82.57 121.83,82.38 121.44,81.99 121.44,81.08 121.39,81.03 ; 47 cut-outs
VCC_CORE on BOTTOM: 118.4,97.06 117.51,97.94 117.25,97.94 117,98.2 117,98.55 117.69,99.24 117.69,101.12 117.81,101.25 119.41,101.25 120.43,100.23 120.43,99.06 119.79,98.43 119.79,97.18 119.67,97.06 ; 3 cut-outs
VCC_CORE on BOTTOM: 120.78,81.16 120.56,81.38 120.56,82.86 120.45,82.96 120.05,82.96 119.95,82.86 119.95,81.36 119.84,81.26 119.64,81.26 119.46,81.43 119.15,81.43 118.91,81.19 118.76,81.19 118.7,81.24 117.81,81.24 117.54,81.52 117.32,81.52 116.39,82.44 116.39,83.51 116.59,83.71 121.66,83.71 121.79,83.58 121.79,82.82 121.34,82.37 121.34,82.01 121.82,81.53 121.82,81.38 121.6,81.16
VCC_CORE on BOTTOM: 124.09,107.47 122.84,108.73 119.88,108.73 119.79,108.64 114.23,108.64 113.56,109.31 113.56,112.79 112.74,113.6 111.56,113.6 111.29,113.87 111.29,116.52 111.53,116.77 115.68,116.77 117.5,114.95 119.73,114.95 121.54,116.77 125.45,116.77 126.56,117.87 127.96,117.87 128.21,117.62 128.21,108.96 126.73,107.47 ; 10 cut-outs
VCC_CORE on BOTTOM: 115.73,91.28 115.32,91.69 115.32,92.38 115.05,92.66 115.05,92.78 115.2,92.93 115.87,92.93 115.96,93.02 115.96,93.67 116.42,94.13 116.76,94.13 117.21,93.68 117.21,92.87 117.34,92.74 117.66,92.74 117.8,92.88 117.8,93.66 118.25,94.12 118.57,94.12 119.02,93.66 119.02,92.94 119.16,92.81 119.51,92.81 119.61,92.91 119.61,93.65 120.08,94.11 120.41,94.11 120.86,93.66 120.86,93.65 121.44,93.65 121.44,93.65 121.62,93.83 122.49,93.83 122.69,93.63 122.69,93.36 122.21,92.87 122.21,91.36 122.13,91.28
VCC_CORE on BOTTOM: 122.03,97.11 121.95,97.18 121.95,97.79 122.36,98.2 122.36,101.07 122.99,101.7 122.99,101.93 122.99,102.72 123.24,102.96 123.89,102.96 123.97,102.88 123.97,100.69 123.99,100.67 123.99,100.17 124.24,99.93 124.24,99.42 122.56,97.74 122.56,97.28 122.38,97.11 ; 5 cut-outs
VCC_CORE on L2: 114.85,92.29 113.34,93.8 113.34,115.17 115.55,117.38 128.56,117.38 128.99,116.95 128.99,103.38 124.75,99.14 124.75,95.44 124.15,94.84 124.15,93.48 123.29,92.62 123.29,91.11 125.39,89 125.39,87.95 125.29,87.85 124.57,87.85 123.95,87.23 123.95,84.52 123.72,84.29 122.05,84.29 121.66,83.9 121.66,82.66 121.42,82.41 115.44,82.41 114.85,83
VCC_CORE on L3: 125.98,117.27 128.12,115.12 128.12,96.75 127.54,96.16 127.54,95.31 126.71,94.49 124.77,94.49 122.46,92.18 122.46,91.26 122.38,91.19 121.44,91.19 120.84,90.58 120.84,84.13 121.44,83.52 121.44,82.68 121.37,82.6 119.77,82.6 119.54,82.37 119.16,82.37 118.75,82.78 118.17,82.78 117.69,82.3 116.64,82.3 116.43,82.51 116.43,84.44 116.06,84.81 116.06,90.17 114.99,91.24 114.99,92.41 113.62,93.78 113.62,100.51 115.23,102.12 115.23,106.74 115.27,106.78 115.27,107.46 113.95,108.78 113.95,114.75 116.47,117.27
VCC_CORE on L4: 114.35,108.38 113.52,109.21 113.52,117.78 114.99,119.25 126.16,119.25 127.02,118.4 127.02,109.51 125.97,108.46 114.43,108.46
VCC_CORE on L4: 117.46,97.82 117.46,99.2 118.04,99.78 121.46,99.78 126.03,95.22 126.03,92.87 124.54,91.38 115.39,91.38 115.04,91.73 115.04,93.79 115.06,93.81 115.06,95.91 115.6,96.45 116.09,96.45
VCCK_12 on BOTTOM: 22.22,71.87 22.12,71.97 22.12,73.08 22.28,73.24 23.28,73.24 23.57,73.53 23.86,73.53 24.28,73.11 24.28,71.97 24.18,71.87 ; 3 cut-outs
VDD10 on TOP: 54.71,179.86 54,180.57 51.72,180.57 51.7,180.6 51.7,182.48 51.88,182.66 55.41,182.66 55.67,182.4 55.67,179.94 55.59,179.86 ; 2 cut-outs
VDD10 on BOTTOM: 45.44,172.87 45.37,172.95 45.03,172.95 44.9,173.08 44.9,175.59 43.7,176.8 43.7,178.54 44.56,179.4 49.57,179.4 50.09,178.89 50.09,177.46 50.56,176.99 50.98,176.99 52.63,178.65 52.63,182.06 53.45,182.88 55.15,182.88 55.57,182.46 55.57,175.92 52.63,172.97 50.86,172.97 50.78,173.05 50.78,175.86 50.51,176.14 47.51,176.14 47.48,176.16 47.48,177.37 47.38,177.47 46.31,177.47 46.15,177.31 46.15,172.94 46.08,172.87 ; 10 cut-outs
VDD_DAC_33 on TOP: 19.54,76.51 19.44,76.61 19.44,78.23 19.49,78.28 20.25,78.28 20.73,77.8 20.73,76.81 20.43,76.51 ; 1 cut-out
VDD_DAC_33 on BOTTOM: 18.88,74.4 18.75,74.53 18.75,74.83 19.39,75.47 19.39,78.18 19.5,78.29 19.78,78.29 20.76,77.32 20.76,74.68 20.48,74.4 ; 7 cut-outs
VDDREG on TOP: 54.41,175.1 54.41,175.11 53.31,175.11 52.87,175.55 50.22,175.55 50.17,175.61 50.17,175.75 50.2,175.78 51.23,175.78 52.28,176.82 53.09,176.82 53.34,177.06 53.34,177.09 53.34,177.32 53.34,177.32 53.34,178.29 53.49,178.44 54.37,178.44 54.5,178.3 54.5,175.19 ; 2 cut-outs
(no net) on L3: outline of 91 points within 57.59,18.21 137.15,86.5
0D6V_S0 on TOP: 126.31,21.12 126.14,21.29 126.14,22.18 126.47,22.51 129.06,22.51 129.67,21.9 129.67,21.36 129.43,21.12 ; 6 cut-outs
0D6V_S0 on TOP: 133.37,30.57 133.17,30.77 132.23,30.77 132.04,30.58 130.26,30.58 130.23,30.61 130.23,31.09 130.46,31.32 132.19,31.32 132.29,31.42 133.51,31.42 133.88,31.79 135.15,31.79 135.28,31.65 135.28,30.74 135.12,30.57 ; 2 cut-outs
0D6V_S0 on TOP: 34.81,25.25 34.78,25.28 34.78,26.29 35.03,26.55 36.81,26.55 37.07,26.29 37.07,25.75 36.57,25.25
0D6V_S0 on BOTTOM: 124.03,20.42 124,20.44 124,21.66 124.81,22.47 128.44,22.47 129.04,21.87 132.89,21.87 133.2,21.56 133.2,21.01 132.87,20.68 124.88,20.68 124.61,20.42 ; 3 cut-outs
0D95V_VGA_S0 on TOP: 164.52,136.45 164.6,136.53 165.76,136.53 165.86,136.63 165.86,137.67 165.79,137.73 163.94,137.73 163.68,137.99 163.68,140.37 164.32,141.01 166.97,141.01 167.69,140.28 167.69,138.31 167.23,137.84 167.23,137.38 167.13,137.28 166.67,137.28 166.53,137.14 166.53,135.95 166.42,135.85 164.6,135.85 164.52,135.92 ; 16 cut-outs
0D95V_VGA_S0 on BOTTOM: 187.15,135.79 186.98,135.97 186.98,136.18 186.8,136.36 186.8,136.96 186.9,137.06 187.56,137.06 187.61,137.01 187.61,135.94 187.46,135.79 ; 1 cut-out
0D95V_VGA_S0 on BOTTOM: 148.44,146.53 148.17,146.81 148.17,147.02 148.78,147.63 148.78,147.68 149.16,148.06 149.16,150.42 149.18,150.42 149.26,150.5 149.87,150.5 151.29,149.07 151.29,148.13 150.07,146.92 149.74,146.92 149.36,146.53
0D95V_VGA_S0 on BOTTOM: 165.26,141.7 166.6,141.7 166.9,141.4 167.44,141.4 167.74,141.1 167.74,139.59 168.26,139.08 168.26,138.55 167.68,137.97 167.68,137.49 168.21,136.96 168.21,136.62 167.19,135.6 165.1,135.6 164.91,135.79 164.91,140.39 164.71,140.59 163.68,140.59 163.48,140.79 163.48,141.64 164,142.15 164.81,142.15
0D95V_VGA_S0 on L3: 165.41,141.13 167.48,141.13 167.71,140.9 167.71,136.76 167.61,136.66 158.25,136.66 156.52,138.39 152.88,138.39 148.6,142.67 148.6,148.62 149.49,149.51 150.71,149.51 151.54,148.67 151.54,142.14 152.36,141.33 158.25,141.33 159.63,139.94 164.23,139.94
0D95V_VGA_S0 on L4: 152.09,147.11 150.59,145.6 150.59,142.81 153.94,139.46 162.26,139.46 163.92,141.12 167.28,141.12 167.64,140.76 167.64,138.63 167.1,138.1 165.75,138.1 164.26,136.61 150.16,136.61 147.85,138.91 147.85,148.49 149.02,149.66 150.29,149.66 152.09,147.86
1D0V_S5 on TOP: 165.35,81.86 165.24,81.98 165.24,84.5 164.94,84.8 164.93,84.8 164.66,85.07 164.66,88.59 165.64,89.57 165.64,92.1 165.65,92.11 167.38,92.11 167.41,92.07 167.41,90.86 167.49,90.78 168.51,90.78 168.86,90.44 168.86,86.41 166.89,84.45 166.89,83.09 166.99,82.98 167.9,82.98 168.01,82.88 168.01,82.09 167.78,81.86 ; 4 cut-outs
1D0V_S5 on TOP: 166.96,73.61 166.52,74.06 165.64,74.06 165.55,74.15 165.55,75.08 165.89,75.43 165.89,76.15 167.19,77.44 167.85,77.44 167.93,77.37 167.93,73.76 167.77,73.61
1D0V_S5 on BOTTOM: 164.43,84.02 164.1,84.35 164.1,89.03 164.43,89.36 164.45,89.36 164.65,89.56 165.11,89.56 165.34,89.79 168.04,89.79 168.88,88.95 168.88,85.28 167.63,84.02 ; 6 cut-outs
1D0V_S5 on BOTTOM: 166,73.48 165.39,74.09 165.39,75.79 167.12,77.52 167.7,77.52 167.93,77.29 167.93,73.66 167.75,73.48
1D0V_S5 on L3: 174.8,88.55 180.43,82.93 180.43,79.57 179.99,79.13 170.14,79.13 170,78.99 170,76.08 169.72,75.8 169.15,75.8 168.9,75.55 168.9,74.13 168.43,73.66 165.92,73.66 165.58,74 165.58,74.03 165.34,74.27 165.34,80.41 166.36,81.42 166.36,88.06 166.85,88.55
1D2V_S3 on TOP: 35.8,27.94 35.67,28.07 35.67,30 35.95,30.28 37.14,30.28 37.32,30.1 37.32,28.07 37.19,27.94 ; 1 cut-out
1D2V_S3 on TOP: 59.35,32.79 58.54,33.61 58.54,34.2 58.53,34.2 58.53,39.62 59.37,40.46 60.92,40.46 60.95,40.43 60.95,32.98 60.76,32.79 ; 9 cut-outs
1D2V_S3 on BOTTOM: 49.76,12.44 48.32,13.19 37.44,13.19 37.03,13.61 36.38,14.26 36.38,18.18 36.62,18.43 38.95,18.43 39.22,18.15 39.22,16.44 40.18,15.48 48.93,15.48 50.26,14.15 53.35,14.15 55.06,15.86 55.06,17.92 53.97,19.02 53.97,19.07 53.33,19.7 53.33,28.81 53.76,29.25 53.76,30.18 53.77,30.18 53.77,30.5 54.15,30.89 56.2,30.89 58.47,33.16 58.47,33.89 58.28,34.07 58.28,39.43 64.75,45.9 125.73,45.9 128.77,42.86 128.77,42.05 128.53,41.81 127.77,41.81 127.25,42.34 118.02,42.34 117.6,41.92 93.92,41.92 93.66,41.66 93.66,40.31 93.58,40.24 93.5,40.24 93.4,40.34 93.4,41.71 93.19,41.92 66.08,41.92 63.53,39.37 63.53,35.36 63.58,35.31 63.58,33.2 65.41,31.37 98.71,31.37 98.71,31.37 101.81,31.37 102.12,31.68 103.28,31.68 103.59,31.37 123.07,31.37 123.53,30.91 123.53,30.03 122.03,28.53 58.52,28.53 55.9,25.92 55.9,22.54 57.18,21.26 57.18,18.92 57.87,18.23 114.99,18.23 115.4,17.82 115.4,15.68 115.03,15.3 57.27,15.3 54.4,12.44 ; 6 cut-outs
1D2V_S3 on BOTTOM: 82.96,71.55 82.96,71.56 82.49,71.56 81.41,72.65 80.53,72.65 80.37,72.8 80.37,73.18 80.45,73.26 80.45,73.26 80.79,73.59 82.76,73.59 83.2,73.15 83.2,71.79 ; 3 cut-outs
1D2V_S3 on L3: 115.98,76.26 116.8,75.44 116.8,73.33 116.97,73.15 116.97,71.99 117.08,71.88 117.08,68.28 119.57,65.79 119.57,52.71 109.23,42.37 109.23,40.77 108.85,40.39 108.85,33.66 101.62,26.43 101.62,21.35 100.59,20.32 95.92,20.32 94.6,19 86.32,19 84.16,21.16 84.16,22 83.19,22.96 83.19,29.82 87.59,34.22 87.59,48.57 102.5,63.48 102.51,63.48 102.51,65.88 103.84,67.21 103.84,70.92 104.35,71.43 104.35,72.7 107.78,76.13 107.78,77.01 107.5,77.28 107.5,78.82 107.45,78.87 107.45,81.21 107.93,81.69 115.25,81.69 116.15,80.78 116.15,78.8 115.98,78.63
1D2V_S3 on L4: 124.12,28.17 115.37,28.17 112.59,30.94 112.59,31.54 113.27,32.22 124.92,32.22 125.78,31.36 125.78,29.82
1D2V_S3 on L4: 37.31,29.4 37.31,28.77 35.27,26.74 35.27,21.62 38.04,18.85 38.04,17.83 37.84,17.63 36.4,17.63 33.33,20.7 33.33,28.25 35,29.92 36.78,29.92
1D2V_S3 on L4: 126.39,77.32 124.67,77.32 124.04,77.95 123.53,77.95 122.94,77.37 122.38,77.37 121.85,77.9 120.07,77.9 119.31,77.14 116.67,77.14 116.66,77.15 116.29,77.15 116.01,77.43 116.01,79.5 115.4,80.11 112.81,80.11 112.5,80.42 112.5,81.76 112.94,82.2 115.45,82.2 115.72,81.93 116.15,81.93 116.36,81.71 126.32,81.71 126.79,81.24 126.99,81.24 128.18,80.06 128.18,77.99 128.97,77.19 128.97,76.29 128.64,75.95 127.74,75.95 126.52,77.17 126.52,77.19
1D8V_PWR on BOTTOM: 165.03,68.3 164.37,68.97 162.12,68.97 161.95,69.14 161.95,71.19 161.53,71.61 161.53,72.69 161.69,72.85 161.96,72.85 162.06,72.75 162.06,72.32 162.16,72.21 164.83,72.21 165.03,72.42 165.03,73.2 165.13,73.31 166.02,73.31 166.35,72.98 166.35,68.58 166.07,68.3 ; 8 cut-outs
1D8V_S5 on BOTTOM: 162.59,2.53 160.01,5.11 160.01,6.72 160.21,6.92 161.91,6.92 162.25,6.58 162.62,6.58 162.63,6.59 162.96,6.59 163.04,6.51 163.04,5.91 162.91,5.77 162.55,5.77 162.5,5.73 162.5,5.12 162.6,5.03 164.12,5.03 165.55,3.59 165.55,2.83 165.25,2.53 ; 4 cut-outs
1D8V_S5 on BOTTOM: 162.46,72.46 162.22,72.69 162.22,74.3 162.97,75.05 164.54,75.05 164.83,74.76 164.83,72.77 164.52,72.46
1D8V_VGA_S0 on TOP: 194.62,133 194.5,133.12 194.5,133.68 194.52,133.71 194.89,133.71 194.99,133.81 194.99,134.57 195.34,134.92 195.77,134.92 195.78,134.93 196.41,134.93 196.68,135.21 196.68,135.81 195.96,136.53 195.96,138.81 195.86,138.92 194.73,138.92 194.64,139.01 194.64,140.24 194.76,140.36 196.7,140.36 196.7,136.53 197.54,135.69 197.54,134.11 197.3,133.87 196.16,133.87 195.97,133.68 195.97,133.38 195.59,133 ; 2 cut-outs
1D8V_VGA_S0 on TOP: 169.7,126.7 169.63,126.77 169.63,128.07 169.43,128.27 168.6,128.27 168.4,128.48 168.4,133.66 168.48,133.74 169.83,133.74 170.13,133.44 170.13,132.7 170.62,132.22 170.62,128.37 170.36,128.12 170.36,126.8 170.26,126.7
1D8V_VGA_S0 on BOTTOM: 169.24,133.93 169.24,132.79 169.11,132.65 167.96,132.65 167.83,132.79 167.83,133.95 167.93,134.05 169.12,134.05
1D35V_VGA_S0 on TOP: 183.46,140.3 183.04,140.72 176.44,140.72 175.5,141.66 165.62,141.66 165.34,141.94 165.34,142.41 164.94,142.81 163.97,142.81 163.72,143.05 163.72,146.07 163.3,146.48 157.46,146.48 155.38,148.57 153.58,148.57 151.72,150.42 148.97,150.42 147.98,151.41 147.98,160.44 147.97,160.45 147.97,163.65 148.28,163.96 149.54,163.96 149.55,163.95 150.33,163.95 150.52,163.76 150.52,162.55 150.81,162.26 151.8,162.26 152.39,162.85 156.47,162.85 157.26,163.64 157.26,165.65 156.55,166.36 152.59,166.36 150.28,168.67 150.28,171.18 150.6,171.5 150.6,172.32 150.86,172.59 156.33,172.59 157.06,173.32 187.74,173.32 188.5,172.56 189.83,172.56 189.94,172.46 189.94,169.9 190.25,169.59 191.1,169.59 192.08,168.61 192.08,160.58 193.66,159.01 195.18,159.01 195.95,158.23 195.95,151.78 195.24,151.07 190.07,151.07 189.55,150.56 188.09,150.56 186.75,149.23 185.33,149.23 184.13,148.03 182.1,148.03 181.77,147.7 181.77,142.65 182.48,141.94 183.55,141.94 183.83,141.66 185.49,141.66 185.76,141.39 185.76,140.46 185.59,140.3 ; 66 cut-outs
1D35V_VGA_S0 on BOTTOM: 178.41,157.59 177.74,158.26 177.74,158.79 177.35,159.18 176.08,159.18 175.81,159.46 175.81,164.08 175.82,164.09 176.85,164.09 175.8,165.15 175.8,165.41 176.02,165.63 177.93,165.63 179.01,164.55 179.01,163.52 179.79,162.74 179.79,162.21 178.26,160.68 178.26,160.32 179.13,159.45 180.66,159.45 180.92,159.19 180.92,158.48 180.61,158.17 179.56,158.17 178.97,157.59
1D35V_VGA_S0 on BOTTOM: 159.86,157.5 158.86,158.5 158.86,162.2 159.49,162.83 159.49,165.36 160.87,166.74 160.87,166.88 160.53,167.23 160.05,167.23 159.51,166.68 158.46,166.68 158.32,166.54 157.99,166.54 157.92,166.61 157.92,167.15 158.15,167.38 159.31,167.38 159.61,167.68 160.22,167.68 160.38,167.84 160.38,169.91 160.49,170.02 160.89,170.02 161.55,169.36 162.09,169.36 162.81,170.09 163.3,170.09 163.39,169.99 163.39,169.74 162.77,169.12 162.27,169.12 161.8,168.65 161.8,167.89 161.93,167.76 162.06,167.76 162.4,168.1 163.13,168.1 163.35,168.32 163.61,168.32 163.87,168.06 163.87,167.86 163.64,167.64 163.34,167.64 163.21,167.5 162.25,167.5 161.96,167.21 161.96,167.11 162.21,166.85 162.72,166.85 164.18,165.4 164.18,158.9 164.17,158.89 164.17,158.46 163.22,157.5
1D35V_VGA_S0 on BOTTOM: 151.71,164.43 151.36,164.78 151.36,166.86 151.64,167.14 152.32,167.14 152.8,167.62 152.8,169.24 153.15,169.59 154.46,169.59 155.19,168.86 155.51,168.86 156.21,168.16 156.21,165.81 154.83,164.43
1D35V_VGA_S0 on BOTTOM: 175.7,141.51 175.57,141.63 175.57,141.8 175.89,142.13 175.89,143.25 176.15,143.51 177.48,143.51 177.71,143.28 177.71,142.39 177.15,141.84 176.36,141.84 176.03,141.51
1D35V_VGA_S0 on BOTTOM: 151.54,157.94 151.25,158.23 151.25,162.49 151.98,163.22 154.08,163.22 154.87,162.42 154.87,159.65 154.64,159.41 153.86,159.41 153.68,159.59 153.68,160.49 153.43,160.74 153.14,160.74 152.82,160.42 152.82,158.26 152.5,157.94
1D35V_VGA_S0 on BOTTOM: 185.4,151.44 182.67,154.17 182.65,154.17 182.17,154.65 182.17,165.67 181.96,165.87 181.96,167.9 181.24,168.61 180.55,168.61 180.17,168.24 179.75,168.24 179.55,168.43 179.55,168.75 180.52,169.72 180.52,170.75 178.78,172.5 170.79,172.5 170.6,172.69 170.6,174.35 170.8,174.54 182.01,174.54 182.47,174.08 188.51,174.08 188.98,173.61 188.98,172.1 188,171.12 188,169 188.23,168.77 188.23,165.46 187.54,164.77 187.05,164.77 186.6,164.32 186.53,164.32 186.11,163.9 186.11,162.81 188.11,162.81 189.89,161.04 190.3,161.04 190.58,161.32 190.58,163.15 190.78,163.35 191.16,163.35 191.27,163.24 191.27,157.73 191.6,157.4 191.62,157.4 192.09,156.93 196.77,156.93 196.8,156.89 196.8,152.44 195.8,151.44 ; 24 cut-outs
1D35V_VGA_S0 on BOTTOM: 166.94,141.48 166.6,141.82 165.33,141.82 165.03,142.12 165.03,143.33 165.18,143.48 165.66,143.97 165.89,143.97 166.1,143.76 166.1,143.73 166.46,143.36 166.46,142.74 166.66,142.54 169.02,142.54 169.19,142.37 169.19,141.58 169.09,141.48
1D35V_VGA_S0 on BOTTOM: 158.64,168.52 158.63,168.53 158.17,168.53 156.88,169.82 156.88,173.98 157.54,174.63 168.18,174.63 168.42,174.39 168.42,172.97 168.07,172.62 160.75,172.62 158.92,170.8 158.92,169.85 159.14,169.64 159.14,168.86 158.88,168.61 158.73,168.61 ; 5 cut-outs
1D35V_VGA_S0 on L3: 182.83,169.99 183.42,169.39 183.42,168.94 183.29,168.81 178.8,168.81 178.14,169.47 174.96,169.47 174.62,169.81 173.6,169.81 171.6,167.82 165.21,167.82 165.21,167.83 159.9,167.83 158.78,166.71 156.5,166.71 155.3,165.51 154.3,165.51 153.58,164.79 149.74,164.79 149.08,165.45 149.08,168.77 151.33,171.02 155.6,171.02 157.81,173.22 188.18,173.22 188.66,172.75 188.66,171.71 188.49,171.54 183.73,171.54 182.83,170.64
1D35V_VGA_S0 on L4: 188.61,135.43 187.63,136.41 186.83,136.41 186.09,135.67 181.79,135.67 180.93,134.81 179.32,134.81 178.66,135.46 178.66,136.85 176.41,139.1 170.43,139.1 169.81,138.48 169.21,138.48 167.76,139.94 167.76,140.85 167.34,141.27 165.59,141.27 165.16,141.7 165.16,143.2 165.18,143.22 165.71,143.22 166.47,142.47 167.51,142.47 167.58,142.53 168.35,142.53 169.19,141.69 169.19,141.14 169.34,140.99 169.79,140.99 170.58,141.77 172.59,141.77 173.24,142.43 175.32,142.43 176.57,143.67 178.67,143.67 179.65,142.69 181.95,142.69 183.06,141.58 186.18,141.58 187.04,142.44 188.23,142.44 190.7,144.92 190.7,152.8 193.1,155.2 193.1,155.27 195.59,155.27 196.11,154.75 196.11,152.83 195.16,151.88 195.16,136.88 193.71,135.43
2D5V_PWR on BOTTOM: 135.85,24.52 135.74,24.64 135.74,30.31 135.86,30.43 138.12,30.43 138.34,30.21 138.34,24.98 137.88,24.52 ; 7 cut-outs
2D5V_S3 on TOP: 133.18,27.74 133.1,27.82 133.1,29.77 133.65,30.32 135.43,30.32 136.58,31.47 136.58,32.9 137.27,33.58 137.27,37.12 135.32,39.07 133.81,39.07 133.15,39.73 133.15,41 133.89,41.73 134.5,41.73 135.02,41.21 135.24,41.21 135.89,40.56 137.79,40.56 140.11,38.23 140.11,33.91 139.3,33.1 139.3,30.48 136.56,27.74 ; 11 cut-outs
2D5V_S3 on TOP: 127.25,26.89 127.16,26.98 127.16,27.43 128.54,28.82 131.54,28.82 131.63,28.72 131.63,27.46 131.41,27.24 128.75,27.24 128.39,26.89 ; 10 cut-outs
2D5V_S3 on BOTTOM: 124.02,26.36 123.81,26.56 123.81,29.22 125.56,30.97 134.72,30.97 135.41,30.28 135.41,28.4 135.32,28.31 134.13,28.31 133.63,27.82 133.62,27.82 133.42,27.62 131.79,27.62 131.01,26.84 131.01,26.82 130.55,26.36
2D5V_S3 on BOTTOM: 132.54,39.31 131.85,40.01 131.85,41.58 131.88,41.62 133.6,41.62 133.79,41.43 133.79,39.49 133.61,39.31
3D3V_CAMERA_S0 on TOP: 109.94,176.21 109.61,176.54 109.61,177.34 108.72,178.23 108.72,179.67 108.84,179.79 111.18,179.79 111.22,179.75 111.22,176.38 111.06,176.21 ; 4 cut-outs
3D3V_LAN_S5 on TOP: 55.39,167.69 55.16,167.91 55.16,169.02 55.02,169.16 53.92,169.16 53.57,168.81 53.16,168.81 53.03,168.93 53.03,169.9 53.21,170.07 56.84,170.07 57.44,169.47 57.44,167.89 57.23,167.69
3D3V_LAN_S5 on TOP: 43.54,168.85 43.28,169.11 43.28,170.92 43.49,171.12 46.84,171.12 47.82,172.1 47.82,172.99 47.86,173.03 48.03,173.03 48.08,172.97 48.08,171.45 47.36,170.72 47.36,170.21 46.51,170.21 46.16,169.85 46.16,169.09 45.92,168.85 ; 2 cut-outs
3D3V_LAN_S5 on TOP: 54.76,177.27 54.7,177.33 54.7,178.23 54.82,178.34 55.62,178.34 55.85,178.58 55.85,180.25 55.97,180.37 57.56,180.37 57.56,180.37 57.78,180.37 57.89,180.27 57.89,177.37 57.79,177.27
3D3V_LAN_S5 on TOP: 46.95,176.3 46.73,176.52 44.89,176.52 44.66,176.75 44.66,177.55 44.81,177.7 44.81,178.34 44.91,178.43 45.57,178.43 46.68,177.32 47.18,177.32 47.31,177.18 47.31,176.39 47.22,176.3 ; 2 cut-outs
3D3V_LAN_S5 on L3: 44.29,167.76 43.25,168.8 43.25,178.69 43.85,179.29 50.19,179.29 51.32,180.42 56.52,180.42 56.66,180.29 56.66,177.61 56.07,177.02 47.21,177.02 46.66,176.47 46.66,172.42 49.07,170 56.2,170 56.59,169.62 56.59,168.14 56.21,167.76
3D3V_PWR on BOTTOM: 38.45,46.96 38.35,47.06 38.35,50.21 39.19,51.05 39.19,58.26 39.78,58.85 44.9,58.85 45.86,57.89 45.86,47.38 45.45,46.96 ; 2 cut-outs
3D3V_RUN_FFS on BOTTOM: 183.54,50.98 183.38,51.13 182.6,51.13 182.53,51.06 181.76,51.06 181.68,51.14 181.68,51.56 182.39,52.28 182.39,53.16 182.52,53.29 183.76,53.29 183.97,53.08 183.97,51.22 183.73,50.98 ; 1 cut-out
3D3V_RUN_FFS on BOTTOM: 181.9,47.08 181,47.97 181,48.6 180.77,48.83 180.77,49.22 181.16,49.61 181.16,49.95 181.17,49.96 181.95,49.96 181.99,49.93 181.99,48.93 182.47,48.44 182.47,47.15 182.4,47.08 ; 3 cut-outs
3D3V_S0 on TOP: 103.39,16.13 103.18,16.34 103.18,17.91 103.28,18.01 106.28,18.01 106.46,17.83 106.46,16.49 106.1,16.13 ; 5 cut-outs
3D3V_S0 on TOP: 170.19,23.89 169.72,24.36 169.27,24.36 168.97,24.67 168.97,27.56 169.35,27.94 170.95,27.94 171.51,27.38 171.51,24.51 171.36,24.36 171.34,24.36 170.86,23.89 ; 2 cut-outs
3D3V_S0 on TOP: 23.5,80.36 23.07,80.8 23.07,80.82 22.86,81.03 22.86,82.55 23.52,83.22 26.79,83.22 26.9,83.1 26.9,82.44 26.66,82.2 26.09,82.2 25.82,81.93 24.13,81.93 23.56,81.36 23.56,81.07 23.84,80.79 23.84,80.43 23.78,80.36 ; 2 cut-outs
3D3V_S0 on TOP: 41.78,38.32 41.63,38.47 41.63,39.45 41.64,39.47 41.64,39.57 41.31,39.91 41.31,40.79 41.65,41.13 44.54,41.13 44.6,41.07 44.6,40.31 44.56,40.27 44.01,40.27 43.54,39.79 43.54,38.53 43.33,38.32 ; 2 cut-outs
3D3V_S0 on TOP: 98.48,178.36 98.39,178.45 98.39,183.36 98.64,183.6 100.25,183.6 100.36,183.48 100.36,178.45 100.28,178.36 ; 2 cut-outs
3D3V_S0 on TOP: 160.12,69.64 159.85,69.9 159.85,74.14 159.59,74.41 159.42,74.41 159.23,74.59 159.23,74.84 159.62,75.23 160.69,75.23 161.16,74.76 161.16,69.97 160.83,69.64
3D3V_S0 on TOP: 19.97,55.3 19.84,55.43 19.84,55.84 19.92,55.93 23.61,55.93 23.65,55.88 23.65,55.42 23.53,55.3
3D3V_S0 on TOP: 152.9,84.43 152.79,84.54 152.79,87.49 152.47,87.81 152.47,88.78 152.71,89.01 153.12,89.01 154.57,90.46 154.77,90.46 155.11,90.12 155.11,85.6 153.95,84.43 ; 6 cut-outs
3D3V_S0 on TOP: 109.62,180.42 109.49,180.55 109.49,182.59 109.64,182.74 111.41,182.74 111.49,182.66 111.49,180.51 111.4,180.42
3D3V_S0 on TOP: 151.11,107.72 150.93,107.9 150.93,108.92 152.03,110.01 153.78,110.01 153.96,109.83 153.96,109.5 153.83,109.37 152.33,109.37 151.9,108.94 151.9,108.38 152,108.28 153.07,108.28 153.17,108.18 153.17,108 153.07,107.9 151.7,107.9 151.52,107.72 ; 1 cut-out
3D3V_S0 on TOP: 118.85,182.32 118.75,182.42 118.75,182.7 118.52,182.93 118.05,182.93 117.34,183.65 117.34,184.34 117.52,184.52 118.51,184.52 119.84,183.19 119.84,182.37 119.79,182.32 ; 1 cut-out
3D3V_S0 on BOTTOM: 26.55,62.29 26.3,62.54 26.3,63.99 22.51,67.78 19.51,67.78 18.59,68.7 18.59,73.83 18.84,74.08 20.62,74.08 20.7,73.99 20.7,71.06 21.36,70.4 28.39,70.4 31.05,73.06 31.05,76.28 33.35,78.58 33.35,81.71 40.24,88.6 43.02,88.6 46.79,92.37 57.76,92.37 58.29,92.9 60.37,92.9 60.64,92.63 60.64,90.35 60.69,90.3 60.69,88.71 60.21,88.23 47.83,88.23 45.44,85.84 42.79,85.84 37.2,80.24 37.2,77.59 35.19,75.59 35.19,72.47 31.52,68.8 31.52,62.94 30.87,62.29 ; 8 cut-outs
3D3V_S0 on BOTTOM: 154.51,86.68 154.01,87.18 154.01,88.01 154.27,88.27 154.47,88.27 154.96,88.77 154.96,89.96 153.73,91.19 152.39,91.19 152.27,91.31 152.27,96.31 152.32,96.36 152.32,97.65 153.37,98.71 153.7,98.71 154.08,98.33 154.08,97.83 153.9,97.66 153.59,97.66 153.25,97.31 153.25,96.27 153.44,96.08 154.44,95.08 154.44,93.96 155.01,93.38 155.01,92.37 156.29,91.09 156.29,88.06 155.71,87.48 155.71,87.25 155.13,86.68 ; 2 cut-outs
3D3V_S0 on BOTTOM: 88.17,169.21 88,169.38 88,173.4 86.89,174.51 86.89,182.81 87.12,183.04 89.21,183.04 89.4,182.86 89.4,175.45 90.41,174.43 90.41,169.32 90.3,169.21 ; 7 cut-outs
3D3V_S0 on BOTTOM: 192.41,124.92 192.31,125.02 192.31,125.71 192.64,126.04 194.06,126.04 195.06,127.04 195.06,128.41 195.13,128.48 195.54,128.48 195.6,128.43 195.6,126.14 194.37,124.92 ; 3 cut-outs
3D3V_S0 on L2: 43.7,41.4 44.1,41 44.1,38.46 43.82,38.18 41.28,38.18 40.67,38.79 40.67,40.74 41.33,41.4
3D3V_S0 on L2: 95.61,146.22 96.42,145.42 96.42,137.58 93.54,134.7 93.54,113.56 93.26,113.28 88.56,108.59 88.56,106.69 87.27,105.4 87.23,105.4 87.12,105.29 87.12,105.25 72.31,90.44 58.97,90.44 58.7,90.71 58.7,93.22 58.97,93.49 62.39,93.49 72.75,97.69 79.11,102.57 84.45,107.9 84.45,109.97 84.94,110.47 84.98,110.47 86.14,111.63 89.4,120.84 89.4,123.26 89.56,125.15 88.89,126.92 88.85,126.99 88.85,127.07 88.89,132.82 88.02,138.5 88.03,138.51 88.03,144.54 87.38,145.19 87.38,145.54 88.07,146.22
3D3V_S0 on L3: 87.63,144.52 87.04,145.11 87.04,154.54 83.77,157.81 82.19,157.81 76.98,163.02 76.98,164.79 72.56,169.21 65.28,169.21 64.85,168.78 59.07,168.78 58.3,169.55 58.3,177.34 65.7,184.74 117.98,184.74 118.17,184.56 118.39,184.56 119.41,183.54 119.41,181.63 119.19,181.41 67.51,181.41 61.66,175.55 61.66,172.51 62.27,171.9 63.28,171.9 64.11,172.73 74.83,172.73 79.99,167.57 79.99,165.96 85.07,160.88 87.08,160.88 91.27,156.68 91.27,144.93 90.86,144.52
3D3V_S0 on L4: 32.51,64.35 33.81,63.05 33.81,49.28 36.42,46.67 43.89,46.67 45.2,45.36 45.2,42.31 42.79,39.91 32.62,39.91 27.49,45.04 27.49,62.82 29.03,64.35
3D3V_S5 on TOP: 139.26,63.23 138.92,63.57 138.92,64.71 139,64.8 140.96,64.8 141.08,64.67 141.08,63.42 140.89,63.23
3D3V_S5 on TOP: 196.12,165.25 195.58,165.79 195.58,170.96 195.02,171.52 193.6,171.52 191.59,173.53 191.59,175.35 190.99,175.96 181.74,175.96 180.39,177.31 172.2,177.31 171.39,178.12 171.39,182.91 171.67,183.2 176.65,183.2 179.16,180.69 180.39,180.69 182.84,178.24 191.31,178.24 194.85,174.7 197.62,174.7 199.21,173.1 199.21,166.04 198.43,165.25 ; 4 cut-outs
3D3V_S5 on TOP: 98.43,158.44 98.26,158.62 98.26,160.97 98.36,161.08 118.07,161.08 118.12,161.03 118.12,159.44 117.12,158.44 ; 3 cut-outs
3D3V_S5 on TOP: 42.68,74.96 42.35,75.29 42.35,75.62 42.53,75.8 44,75.8 44.15,75.64 44.15,75.14 43.97,74.96
3D3V_S5 on TOP: 57.19,12.77 56.67,13.29 56.67,14.73 57.23,15.29 125.46,15.29 132.95,22.78 132.95,24.42 133.85,25.33 137.68,25.33 147.61,35.26 151.37,35.26 151.54,35.08 151.54,34.81 151.26,34.53 150.95,34.53 150.1,33.68 150.1,31.91 149.96,31.77 148.5,31.77 143.84,27.11 143.84,24.93 140.47,21.56 138.74,21.56 135.26,18.07 134.01,18.07 133.5,17.56 133.5,16.31 129.96,12.77 ; 6 cut-outs
3D3V_S5 on TOP: 58.22,178.36 58.04,178.54 58.04,180.23 58.72,180.91 61.22,180.91 61.26,180.94 62.39,180.94 62.45,180.88 62.45,180.38 62.35,180.28 62.34,180.28 62.1,180.03 62.1,178.97 61.49,178.36 ; 6 cut-outs
3D3V_S5 on TOP: 171.74,57.61 171.3,58.04 171.3,58.8 172.27,59.77 173.03,59.77 173.26,59.54 173.26,58.19 172.83,57.76 172.4,57.76 172.24,57.61 ; 1 cut-out
3D3V_S5 on TOP: 41.02,42.48 39.42,44.07 36.51,44.07 35.87,44.71 35.87,57.88 36.14,58.15 40.79,58.15 40.95,57.98 40.95,55.64 41.16,55.43 43.5,55.43 43.71,55.23 43.71,46.96 44.28,46.38 44.29,46.37 44.29,44.08 44.58,43.8 44.58,42.55 44.5,42.48
3D3V_S5 on BOTTOM: 195.56,164.62 195.41,164.77 195.41,165.64 195.16,165.89 195.16,166.14 197.19,166.14 197.92,165.41 197.92,164.87 197.67,164.62 ; 1 cut-out
3D3V_S5 on BOTTOM: 194.85,172.44 194.75,172.54 194.75,172.77 194.54,172.98 192.14,172.98 191.83,173.29 191.83,174.2 191.63,174.4 191.63,175.94 191.68,175.99 192.27,175.99 192.41,175.85 192.41,174.56 192.52,174.44 195.41,174.44 195.73,174.12 196.17,174.12 196.25,174.04 196.25,173.43 196.25,173.28 196.07,173.1 195.54,173.1 195.43,173 195.43,172.49 195.38,172.44 ; 2 cut-outs
3D3V_S5 on BOTTOM: 71.2,169.72 64.42,176.51 60.05,176.51 59.44,177.12 59.44,179.55 59.98,180.09 64.22,180.09 68.87,175.44 69.76,175.44 73.95,171.25 73.95,170.61 73.06,169.72
3D3V_S5 on BOTTOM: 122.63,161.98 123.32,161.98 125.97,159.32 125.97,156.58 126.83,155.73 134.07,155.73 135.21,154.58 135.21,153.7 134.96,153.45 134.96,150.78 134.78,150.59 133.56,150.59 132.95,151.2 132.95,152.63 132.34,153.24 125.81,153.24 124.24,154.82 124.24,158.17 121.97,160.43 119.34,160.43 118.13,159.22 116.73,159.22 116.12,159.83 116.12,161.59 116.51,161.98 122.62,161.98 ; 2 cut-outs
3D3V_S5 on BOTTOM: 162.11,61.7 161.98,61.83 161.98,62.74 163.3,64.06 163.3,65.59 163.15,65.74 160.1,65.74 160.02,65.82 160.02,68.56 160.23,68.78 164.25,68.78 164.88,68.15 166.25,68.15 166.38,68.02 166.38,63.71 166.07,63.4 163.94,63.4 163.48,62.94 163.48,62.62 163.41,62.55 163.03,62.55 162.74,62.25 162.74,61.89 162.54,61.7 ; 3 cut-outs
3D3V_S5 on BOTTOM: 23.17,28.6 21.47,30.3 21.47,36.52 23.46,38.51 23.48,38.51 25,40.03 25,41.01 25.33,41.34 26.72,41.34 27.62,40.44 36.58,40.44 37.68,41.53 37.68,46.08 38.24,46.64 44.3,46.64 44.58,46.37 44.58,40.16 33.03,28.6 ; 4 cut-outs
3D3V_S5 on BOTTOM: 137.29,19.27 136.81,19.76 136.81,21.21 136.72,21.3 133.75,21.3 133.72,21.33 133.72,24.24 133.82,24.33 139.36,24.33 139.62,24.07 139.62,23.58 139.88,23.32 139.88,19.41 139.73,19.27 ; 3 cut-outs
3D3V_S5 on BOTTOM: 192.77,30.63 192.34,31.07 192.34,31.35 190.86,32.82 182.48,32.82 180.41,34.89 180.41,35.89 177.25,39.04 177.25,41.52 177.56,41.83 177.56,45.77 177.95,46.15 180.07,46.15 181.72,44.51 181.72,38.64 185.15,35.21 186.32,35.21 186.61,35.5 190.22,35.5 190.51,35.78 192.58,35.78 194.17,34.19 194.17,31.08 193.72,30.63 ; 2 cut-outs
3D3V_S5 on BOTTOM: 33.37,53.03 32.36,54.04 32.36,68.88 35.42,71.94 35.42,75.25 37.48,77.31 37.48,80.1 43.04,85.66 45.65,85.66 47.79,87.8 60.51,87.8 64.99,92.28 65.67,92.28 69.65,94.97 72.75,97.07 84.51,108.82 85.96,110.95 87,113.59 87,117.88 88.16,119.04 89.72,121.31 89.72,127.13 89.44,127.41 89.44,139.99 99.02,149.57 99.02,160.32 99.23,160.53 103.24,160.53 103.83,159.94 103.83,147.52 92.85,136.54 92.85,130.14 93.38,129.61 93.38,119.36 90.79,116.77 90.79,110.26 86.28,105.75 86.28,105.3 76.92,95.94 76.92,93 75.38,91.47 75.38,89.35 75.43,89.3 75.43,85.46 73.29,83.31 47.15,83.31 44.04,80.21 44.04,73.47 38.06,67.49 38.06,53.53 37.73,53.2 34.67,53.2 34.5,53.03 ; 4 cut-outs
3D3V_S5 on BOTTOM: 153.88,19.1 153.25,19.74 153.25,23.33 151.56,25.02 151.56,26.27 151.16,26.68 147.52,26.68 146.95,27.24 146.32,27.24 145.8,27.76 145.8,36.54 144.11,38.23 144.11,43.04 144.44,43.38 146.06,43.38 146.63,42.8 146.63,40.59 147.29,39.93 147.29,37.12 147.58,36.83 148.04,36.83 148.38,36.5 148.38,34.69 148.35,34.67 148.35,34.32 148.55,34.12 148.55,32.84 148.81,32.59 150.58,32.59 150.71,32.71 151.33,32.71 151.45,32.59 151.45,30.32 153.87,27.9 153.87,26.9 154.1,26.66 154.1,26.66 154.89,25.87 154.89,25.21 156.06,24.04 156.06,19.93 155.23,19.1 ; 11 cut-outs
3D3V_S5 on L3: 174.52,55.53 174.52,53.49 175.67,52.34 175.67,48.04 179.92,43.78 179.92,39.38 179.55,39.01 178.04,39.01 175.73,41.32 174.31,41.32 174.28,41.29 173.79,41.29 172.7,42.38 172.7,44.42 164.15,52.98 164.15,54.03 164.73,54.61 165.4,54.61 165.84,55.05 165.84,57.46 165.79,57.5 165.79,59.16 165.85,59.21 165.85,59.97 165.05,60.77 165.05,63.37 163.76,64.65 163.76,67.83 164.17,68.24 164.99,68.24 165.03,68.2 169.38,68.2 169.78,67.81 169.78,66.26 170.62,65.41 170.62,60.1 172.55,58.17 172.55,57.5
3D3V_S5 on L4: 168.75,183.56 147.05,183.56 145.14,181.65 145.14,177.3 141.66,173.82 141.66,172.52 139.53,170.4 139.53,161.01 133.45,154.94 133.45,153.38 134,152.84 135.22,152.84 135.76,153.38 135.76,154.22 141.89,160.35 141.89,169.82 144.28,172.21 144.28,173.33 147.5,176.54 147.5,179.34 147.52,179.36 147.52,180.76 148.14,181.38 150.13,181.38 150.15,181.37 168.83,181.37 169.04,181.15 173.11,181.15 173.16,181.21 173.16,182.98 172.98,183.16 169.15,183.16
3D3V_S5 on L4: 95.99,168.81 82.1,168.81 80.45,170.46 77.02,170.46 75.17,172.32 72.47,172.32 71.89,171.73 71.89,170.94 76.03,166.8 76.72,166.8 81.26,162.26 93.89,162.26 96.48,159.66 101.61,159.66 101.81,159.86 101.81,162.99
3D3V_S5 on L4: 49.36,14.28 26.52,14.28 19.29,21.52 19.29,33.02 19.61,33.34 23.48,33.34 23.78,33.04 23.78,24.83 25.01,23.6 28.83,23.6 34.9,17.53 38.65,17.53 39.81,18.7 55.96,18.7 59.82,14.84 59.82,13.36 59.3,12.85 50.8,12.85
3D3V_S5 on L4: 156.69,19.64 160.03,19.64 160.03,19.64 162,19.64 163.84,17.8 163.84,17.77 164.82,16.79 164.82,12.51 165.5,11.82 166.36,11.82 167.85,10.34 172.23,10.34 172.55,10.66 180.17,10.66 182.15,12.65 183.31,12.65 184.91,14.24 184.91,14.68 185.61,15.39 185.91,15.39 185.95,15.35 187.57,15.35 187.61,15.39 190.18,15.39 190.79,16.01 190.79,22.11 190.32,22.59 190.32,29.18 190.81,29.67 190.81,30.55 192.57,32.31 193.45,32.31 194.12,31.64 194.12,29 193.55,28.43 192.84,27.72 192.84,14.66 189.87,11.69 186.98,11.69 185.91,10.62 185.91,10.62 183.45,8.15 173.25,8.15 171.3,6.21 164.9,6.21 160.43,10.68 160.43,11.23 159.87,11.78 159.87,16.48 159.27,17.09 154.68,17.09 153.98,17.79 153.98,19.05 153.52,19.51 153.52,20.37 153.98,20.83 155.5,20.83
3D3V_S5 on L4: 60.21,180.19 60.44,179.96 60.44,178.7 58.02,176.28 56.62,176.28 56.24,175.9 56.24,174.54 55.79,174.08 54.86,174.08 54.53,174.41 54.53,180.47 55.27,181.21 56.93,181.21 57.94,180.19
3D3V_S5_KBC on TOP: 166,43.74 165.89,43.84 165.89,44.71 166,44.81 166,46.45 166.45,46.91 166.45,48.51 166.68,48.74 168.47,48.74 168.61,48.61 168.61,46.99 167.34,45.72 167.34,44.71 167.6,44.45 167.6,44.11 167.23,43.74 ; 4 cut-outs
3D3V_S5_KBC on TOP: 196.57,125.41 196.52,125.46 196.52,125.97 196.38,126.11 195.95,126.11 195.82,125.98 195.14,125.98 194.99,126.13 194.99,126.57 195.11,126.69 195.31,126.69 195.45,126.56 195.75,126.56 196.42,127.24 197.23,127.24 197.28,127.19 197.28,125.49 197.19,125.41 ; 1 cut-out
3D3V_S5_KBC on BOTTOM: 188.01,99.79 187.73,100.08 187.73,116.92 187.96,117.15 188.94,117.15 189.11,116.97 189.11,100.26 188.64,99.79
3D3V_S5_PCH on TOP: 153.62,76.68 153.47,76.83 153.47,78.17 153.62,78.31 154.19,78.31 154.33,78.17 154.33,78.17 155.07,77.43 155.07,76.83 154.92,76.68 ; 1 cut-out
3D3V_S5_PCH on TOP: 155.06,102.37 153.4,104.03 153.4,105 153.81,105.41 153.81,106.67 154.07,106.94 155.22,106.94 155.41,106.76 155.41,105.05 155.72,104.73 157.37,104.73 158.26,103.84 158.26,102.89 157.75,102.37 ; 3 cut-outs
3D3V_S5_PCH on BOTTOM: 150.81,68.86 150.73,68.94 150.73,69.43 152.16,70.86 152.16,74.18 153.37,75.38 153.37,81.07 153.84,81.55 154.94,81.55 155.31,81.18 155.31,79.7 154.88,79.27 154.88,78.7 155.23,78.36 155.23,74.79 153.58,73.14 153.58,70.08 152.36,68.86 ; 4 cut-outs
3D3V_S5_PCH on BOTTOM: 143.18,50.15 142.96,50.37 142.96,51.01 143.4,51.44 145.03,53.08 145.03,54.25 145.44,54.66 145.44,57.81 145.81,58.17 147.52,58.17 148.43,57.26 148.43,56.64 148.38,56.59 146.97,56.59 146.84,56.47 146.84,54.94 146.44,54.54 146.44,52.1 144.49,50.15 ; 5 cut-outs
3D3V_S5_PCH on BOTTOM: 148.74,85.71 148.69,85.76 148.69,89.31 148.81,89.43 149.66,89.43 150.31,88.78 150.76,88.78 151.16,88.38 151.16,87.02 150.07,85.94 149.56,85.94 149.33,85.71 ; 2 cut-outs
3D3V_S5_PCH on BOTTOM: 141.85,37.09 139.82,39.12 139.82,40.52 139.88,40.59 140.98,40.59 141.24,40.33 141.24,39.74 142.36,38.62 142.94,38.62 143.53,38.03 143.53,37.47 143.15,37.09 ; 1 cut-out
3D3V_TPM on BOTTOM: 157.05,49.64 156.96,49.72 156.96,50.34 156.78,50.52 156.24,50.52 155.86,50.9 155.86,51.47 155.83,51.49 155.83,53.94 156.02,54.13 157.34,54.13 157.5,53.97 157.5,49.68 157.45,49.64 ; 4 cut-outs
3D3V_TPM_1 on BOTTOM: 161.71,58.71 161.6,58.82 161.6,61.41 161.72,61.53 162.73,61.53 162.95,61.74 162.95,62.28 163,62.33 163.45,62.33 163.57,62.21 163.57,59.6 162.68,58.71 ; 4 cut-outs
3D3V_VGA_S0 on TOP: 145.05,144.69 144.38,145.37 144.38,146.57 144.54,146.73 148.57,146.73 148.7,146.6 148.7,144.95 148.45,144.69 ; 5 cut-outs
3D3V_VGA_S0 on TOP: 174.91,120.88 174.66,121.13 174.66,122.36 174.7,122.4 175.49,122.4 175.56,122.48 175.56,122.68 175.52,122.72 174.68,122.72 174.66,122.73 174.66,123.07 174.76,123.17 175.24,123.17 175.34,123.27 175.34,123.8 175.55,124 176.87,124 177.1,123.78 177.1,121.29 176.69,120.88
3D3V_VGA_S0 on BOTTOM: 198.18,123.94 197.97,124.14 197.97,127.64 198.43,128.09 198.43,129.82 198.29,129.97 198.29,132.66 198,132.94 196.52,132.94 196.1,133.37 196.1,134.98 196.58,135.46 199.22,135.46 199.59,135.09 199.59,124.04 199.48,123.94 ; 2 cut-outs
3D3V_VGA_S0 on BOTTOM: 145.7,140.5 145.31,140.89 145.31,143.93 144.89,144.35 144.89,145.31 144.98,145.39 147.04,145.39 147.35,145.08 147.35,140.99 146.86,140.5 ; 2 cut-outs
3D3V_VGA_S0 on BOTTOM: 169.98,132.63 169.84,132.77 169.84,133.95 169.96,134.07 171.26,134.07 171.53,133.79 171.53,132.85 171.31,132.63
3D3V_VGA_S0 on L3: 172.5,125.96 173.44,126.9 173.44,130.7 172.95,131.19 172.25,131.19 171.03,129.97 168.44,129.97 167.68,130.74 167.68,131.27 166.81,132.13 162.11,132.13 160.6,133.64 157.45,133.64 155.35,135.74 152.33,135.74 147.07,141 146.16,141 145.76,141.4 145.76,145.24 146.34,145.82 147.66,145.82 147.78,145.69 147.78,141.76 151.4,138.15 156.35,138.15 158.11,136.39 166.39,136.39 166.91,135.87 166.91,135.08 168.21,133.78 174.56,133.78 175.77,132.57 175.77,131.12 176.78,130.11 176.78,124.44 176.97,124.24 176.97,123.27 175.65,121.95 174.3,121.95 173.5,121.14 172.58,121.14 172.46,121.25 172.46,124.52 171.97,125.02 171.97,125.73 172.19,125.96
3D3V_VGA_S0 on L4: 189.11,126.67 190.13,126.67 192.07,124.73 198.85,124.73 199.36,124.22 199.36,123.2 198.97,122.81 189.29,122.81 188.75,123.34 188.75,124.84 186.24,127.36 178.85,127.36 177.15,125.66 177.15,123.7 176.94,123.5 176.76,123.5 175.95,124.31 175.32,124.94 175.32,126.05 178.35,129.08 186.7,129.08
3D3V_WLAN_S0 on TOP: 94.43,147.39 93.99,147.82 93.99,149.75 94.02,149.78 94.02,150.07 94.42,150.47 95.51,150.47 95.56,150.52 97.26,150.52 97.4,150.39 97.4,147.76 97.03,147.39 ; 2 cut-outs
3D3V_WLAN_S0 on TOP: 96.08,159.65 95.41,160.31 95.41,163.11 95.68,163.37 96.8,163.37 97.96,162.21 97.96,159.75 97.85,159.65 ; 1 cut-out
3D3V_WLAN_S0 on BOTTOM: 94.08,147.56 93.84,147.79 93.84,148.9 93.9,148.96 95.41,148.96 95.67,149.22 95.67,149.73 95.67,149.73 95.67,150.32 95.84,150.5 97.47,150.5 97.75,150.21 97.75,148.92 96.39,147.56
3D3V_WLAN_S0 on BOTTOM: 95.72,162.84 95.54,163.03 95.54,165.59 95.49,165.64 93.88,165.64 93.86,165.65 93.86,167.61 93.24,168.22 91.12,168.22 90.97,168.37 90.97,170.88 91.04,170.94 94.31,170.94 97.82,167.44 97.82,163.08 97.58,162.84 ; 4 cut-outs
3D3V_WLAN_S0 on L3: 94.78,163.49 97.79,163.49 98.18,163.1 98.18,153.09 97.42,152.33 97.42,149.25 97.21,149.04 95.54,149.04 94.01,150.57 94.01,162.73
